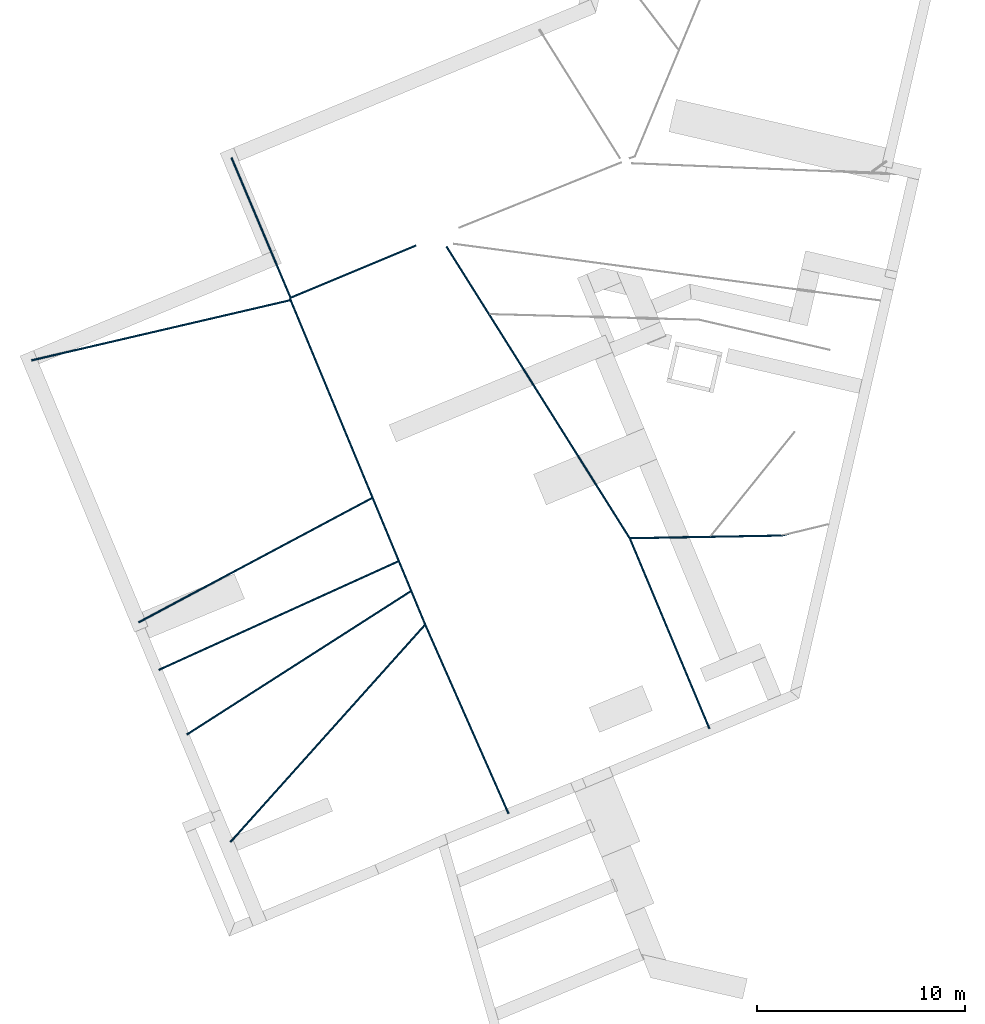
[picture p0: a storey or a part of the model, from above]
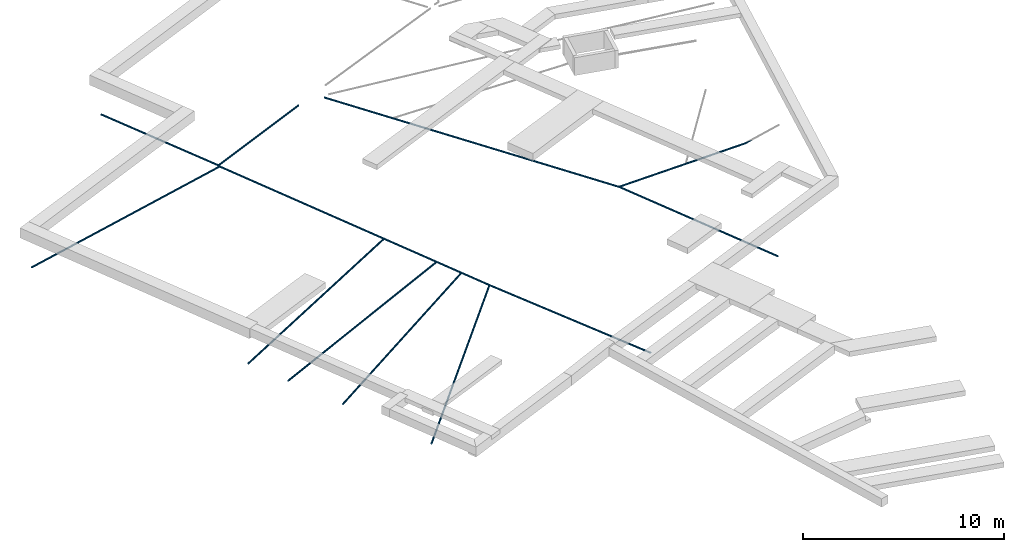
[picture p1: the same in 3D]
Properties of the parts of a building model (IFC2X3), part 1 of 22

# File
Description: ViewDefinition [CoordinationView_V2.0, SurfaceGeometryAddOnView, QuantityTakeOffAddOnView], Option [Drawing Scale: 100.000000], Option [Elements to export: Visible elements (on all stories)], Option [Partial Structure Display: Entire Model], Option [IFC Domain: All], Option [Structural Function: All Elements], Option [Convert Grid elements: On], Option [Convert IFC Annotations and ARCHICAD 2D elements: Off], Option [Convert 2D symbols of Doors and Windows: Off], Option [Export geometries that Participates in Collision Detection only: Off], Option [Split complex elements: Off], Option [Material Preservation: Never explode], Option [IFC Site Location: At Project Origin], Option [Curtain Wall export mode: Single Element], Option [Railing export mode: Single Element], Option [Stair export mode: Single Element], Option [Properties To Export: All properties], Option [Space containment: Off], Option [Bounding Box: Off], Option [Geometry to type objects: Off], Option [Element Properties: Off], Option [Building Material Properties: On], Option [Element Parameters: Off], Option [Component Parameters: Off], Option [IFC Base Quantities: On], Option [Door Window Parameters: Off], Option [IFC Space boundaries: Off], Option [ARCHICAD Zone Categories as IFC Space classification data: Off], Option [Element Classifications: On]
File name: C:\Users\ymarc\Documents\AFFAIRES YM ARCHITECTE\AFFAIRES EN COURS\PIERRES ET TERRITOIRES\CHARTRES Parmentier OLYMPI\Projet 2 - OLYMPI\PRO\Parmentier PRO DEF LIEN BIM OFFICE 26 janvier.ifc
Time: 2021-01-27T10:03:07
Author: #Nom maître oeuvre #Prénom maître oeuvre
Organization: #Societé maître oeuvre
Written by: The EXPRESS Data Manager Version 5.02.0100.09 : 26 Sep 2013
Made in: IFC file generated by GRAPHISOFT ARCHICAD 23.0.0 FRA FULL Windows version (IFC add-on version: 3003 FRA FULL). (Solibri IFC Optimizer)
Authorization: #Nom maître oeuvre #Prénom maître oeuvre

# IfcProject, NOM DU PROJET
Phase: #Provisoire

# IfcSite, Site
RefLatitude: 48, 52, 0, 0; RefLongitude: 2, 20, 0, 0; RefElevation: 136.55 m
BaseQuantities - GrossPerimeter: 0 m; GrossArea: 0 m2

# IfcBuilding, Bâtiment
BaseQuantities - GrossFloorArea: 10399.8 m2

# IfcBuildingStorey (9)
In: Bâtiment
Name | LongName | Elevation (m) | NetHeight (m) = GrossHeight (m) = Height (m) | GrossFloorArea (m2)
Etage | EDICULE | 13.88 | 3 | 0 | Autre - Catégorie: Niveaux; Famille: Niveau: Pointe 8 mm; Famille et type: Niveau: Pointe 8 mm; ID du type: Niveau: Pointe 8 mm; Type: Niveau: Pointe 8 mm; Contraintes - Elévation: 13.58 m; Cotes - Hauteur de calcul: 0 m; Données d'identification - Etage de bâtiment: yes; Structure: no; Nom: EDICULE; Autre(Type) - Catégorie: Niveaux; Nom de la famille: Niveau; Contraintes(Type) - Base de l'élévation: Point de base du projet; Données d'identification(Type) - Nom du type: Pointe 8 mm; Graphismes(Type) - Couleur: 0; Epaisseur des lignes: 1; Motif des lignes: Centre; Symbole: M_Marqueur de niveau - Point triangulaire: M_Marqueur de niveau - Point triangulaire; Valeur par défaut du symbole à l'extrémité 1: no; Valeur par défaut du symbole à l'extrémité 2: yes
Sous-sol | SS | -2.9 | 2.9 | 195.321
Rez-de-chaussée | RDC | 0 | 2.72 | 1224.98
R+1 | 1er | 2.72 | 2.72 | 864.001
R+2 | 2ème | 5.44 | 2.72 | 819.694
R+3 | 3ème | 8.16 | 2.72 | 6864.93
R+4 | 4ème | 10.88 | 3 | 430.843
-2. Etage | fond | -5.7 | 2.8 | 0
Etage |  | 16.88 | 3 | 0

# IfcSpace: Atelier, 001
In: R+4
Type - ElementType: INTERNAL; PredefinedType: USERDEFINED
Description: Logt 3.36.5; LongName: Atelier; InteriorOrExteriorSpace: INTERNAL; Classification: Espace résidentiel (Classification ARCHICAD)
Pset_SpaceCommon - Category: Atelier
PSET ZONES - Finition sol: Carrelage; Finition murs: Peinture; Finition plafond: Peinture
Propriétés DCE - Numéro de LOT: LOT 15; Numéro d'article: L12.2.1.6.3.3; L15.2.1.1
AC_Pset_RenovationAndPhasing - Renovation Status: Existing
BaseQuantities - Height: 2.5 m; FinishCeilingHeight: 2.5 m; FinishFloorHeight: 0 m; ClearHeight: 2.5 m; GrossFloorArea: 20.6791 m2; NetFloorArea: 20.6791 m2; SpaceNetFloorAreaBOMA: 20.6791 m2; SpaceUsableFloorAreaBOMA: 20.6791 m2; GrossCeilingArea: 20.6791 m2; NetCeilingArea: 20.6791 m2; GrossWallArea: 44.7081 m2; NetWallArea: 34.7349 m2; GrossPerimeter: 22.5182 m; NetPerimeter: 22.5182 m; GrossVolume: 51.6977 m3; NetVolume: 45.0737 m3

# IfcSpace: Balcon (17)
LongName: Balcon; InteriorOrExteriorSpace: INTERNAL; Classification: Espace (Classification ARCHICAD)
Pset_SpaceCommon - Category: Balcon
PSET ZONES - Finition sol: résine
AC_Pset_RenovationAndPhasing - Renovation Status: Existing
BaseQuantities - Height: 2.5 m; FinishCeilingHeight: 2.5 m; FinishFloorHeight: 0 m; ClearHeight: 2.5 m
Name | In | Description | GrossFloorArea (m2) = NetFloorArea (m2) = SpaceNetFloorAreaBOMA (m2) = SpaceUsableFloorAreaBOMA (m2) = GrossCeilingArea (m2) = NetCeilingArea (m2) | GrossWallArea (m2) | NetWallArea (m2) | GrossPerimeter (m) = NetPerimeter (m) | GrossVolume (m3) | NetVolume (m3)
001 | R+1 | Logt 1.19.2 | 3.283 | 7.53363 | 2.25363 | 7.81 | 8.2075 | 10.3839
001 | R+1 | Logt 1.15.2 | 3.283 | 7.49458 | 2.21458 | 7.81 | 8.2075 | 10.3906
001 | R+1 | Logt 1.16.2 | 3.283 | 7.49458 | 2.21458 | 7.81 | 8.2075 | 10.3906
001 | R+1 | Logt 1.18.2 | 7.35474 | 18.7929 | 11.5329 | 14.8194 | 18.3868 | 18.3247
001 | R+1 | Logt 1.17.2 | 3.34977 | 0.50818 | 0.50818 | 8.41483 | 8.37443 | 8.465
001 | R+1 | Logt 1.14.3 | 6.68895 | 13.251 | 7.971 | 12.4291 | 16.7224 | 19.8875
001 | R+2 | Logt 2.25.2 | 3.283 | 7.49458 | 2.21458 | 7.81 | 8.2075 | 10.3906
001 | R+2 | Logt 2.26.1 | 3.283 | 7.49458 | 2.21458 | 7.81 | 8.2075 | 10.3906
001 | R+2 | Logt 2.23.3 | 3.98036 | 8.58661 | 3.30661 | 8.80421 | 9.95089 | 12.4015
001 | R+2 | Logt 2.32.2 | 5.50066 | 14.5828 | 9.30276 | 11.1143 | 13.7517 | 13.7499
001 | R+2 | Logt 2.30.3 | 13.2116 | 24.672 | 17.192 | 17.7353 | 33.029 | 36.4807
001 | R+2 | Logt 2.28.2 | 7.35474 | 18.7929 | 11.5329 | 14.8194 | 18.3868 | 18.3247
001 | R+2 | Logt 2.27.2 | 3.34977 | 0.50818 | 0.50818 | 8.41483 | 8.37443 | 8.465
001 | R+3 | Logt 3.34.2 | 3.283 | 7.49458 | 2.21458 | 7.81 | 8.2075 | 10.3906
001 | R+3 | Logt 3.35.3 | 3.283 | 7.49458 | 2.21458 | 7.81 | 8.2075 | 10.3906
001 | R+3 | Logt 3.32.3 | 3.82636 | 8.57113 | 3.29113 | 8.70421 | 9.56589 | 11.9767
001 | R+3 | Logt 3.36.5 | 5.77799 | 12.2434 | 6.96343 | 12.4515 | 14.445 | 13.7299

# IfcSpace: Balcon (4)
In: R+1
Type - ElementType: INTERNAL; PredefinedType: USERDEFINED
InteriorOrExteriorSpace: INTERNAL; Classification: Espace résidentiel (Classification ARCHICAD)
Pset_SpaceCommon - Category: Balcon
PSET ZONES - Finition sol: résine
Propriétés DCE - Numéro de LOT: LOT 12-LOT 15; Numéro d'article: 12.1.1.6-15.1.1.1
AC_Pset_RenovationAndPhasing - Renovation Status: Existing
BaseQuantities - Height: 2.5 m; FinishCeilingHeight: 2.5 m; FinishFloorHeight: 0 m; ClearHeight: 2.5 m
Name | Description | LongName | GrossFloorArea (m2) = NetFloorArea (m2) = SpaceNetFloorAreaBOMA (m2) = SpaceUsableFloorAreaBOMA (m2) = GrossCeilingArea (m2) = NetCeilingArea (m2) | GrossWallArea (m2) | NetWallArea (m2) | GrossPerimeter (m) = NetPerimeter (m) | GrossVolume (m3) | NetVolume (m3)
001 | Logt 1.22.2 | balcon | 7.58408 | 19.7508 | 12.4908 | 14.8322 | 18.9602 | 21.9707
001 | Logt 1.13.3 | Balcon | 5.93859 | 13.4346 | 8.15458 | 11.7353 | 14.8465 | 14.8437
001 | Logt 1.22.2 | balcon | 13.2116 | 24.672 | 17.192 | 17.7353 | 33.029 | 36.4807
001 | Logt 1.22.2 | balcon | 4.69709 | 14.3663 | 9.08629 | 10.154 | 11.7427 | 13.7558

# IfcSpace: Buanderie, 001
In: R+4
Type - ElementType: INTERNAL; PredefinedType: USERDEFINED
Description: Logt 3.36.5; LongName: Buanderie; InteriorOrExteriorSpace: INTERNAL; Classification: Espace résidentiel (Classification ARCHICAD)
Pset_SpaceCommon - Category: Buanderie
PSET ZONES - Finition sol: Carrelage; Finition murs: Peinture
Propriétés DCE - Numéro de LOT: LOT 15; Numéro d'article: L12.2.1.6.3.3; L15.2.1.1
AC_Pset_RenovationAndPhasing - Renovation Status: Existing
BaseQuantities - Height: 2.5 m; FinishCeilingHeight: 2.5 m; FinishFloorHeight: 0 m; ClearHeight: 2.5 m; GrossFloorArea: 6.50737 m2; NetFloorArea: 6.50737 m2; SpaceNetFloorAreaBOMA: 6.50737 m2; SpaceUsableFloorAreaBOMA: 6.50737 m2; GrossCeilingArea: 6.50737 m2; NetCeilingArea: 6.50737 m2; GrossWallArea: 24.57 m2; NetWallArea: 22.3818 m2; GrossPerimeter: 10.6865 m; NetPerimeter: 10.6865 m; GrossVolume: 16.2684 m3; NetVolume: 15.5404 m3

# IfcSpace: CAVES (17)
In: Sous-sol
Type - ElementType: INTERNAL; PredefinedType: USERDEFINED
Description: Logt 0.1.1; InteriorOrExteriorSpace: INTERNAL; Classification: Espace résidentiel (Classification ARCHICAD)
Pset_SpaceCommon - Category: CAVES
PSET ZONES - Finition sol: <Finition de sol>; Finition murs: <Finition de mur>; Finition plafond: <Finition de plafond>
AC_Pset_RenovationAndPhasing - Renovation Status: Existing
BaseQuantities - Height: 2.5 m; FinishCeilingHeight: 2.5 m; FinishFloorHeight: 0 m; ClearHeight: 2.5 m
Name | LongName | GrossFloorArea (m2) = NetFloorArea (m2) = SpaceNetFloorAreaBOMA (m2) = SpaceUsableFloorAreaBOMA (m2) = GrossCeilingArea (m2) = NetCeilingArea (m2) | GrossWallArea (m2) | NetWallArea (m2) | GrossPerimeter (m) = NetPerimeter (m) | GrossVolume (m3) = NetVolume (m3)
001 | C12 | 4.49422 | 28.6191 | 26.9259 | 10.1648 | 11.2355
001 | C14 | 3.99673 | 26.1667 | 24.4735 | 9.12429 | 9.99182
001 | C1 | 3 | 14.6066 | 12.9134 | 7 | 7.5
001 | C2 | 3 | 13.2577 | 11.5645 | 7 | 7.5
001 | C3 | 3 | 18.2324 | 16.5392 | 7 | 7.5
001 | C4 | 3 | 16.9328 | 15.2396 | 7 | 7.5
001 | C5 | 3 | 17.015 | 15.3218 | 7 | 7.5
001 | C6 | 3 | 17.015 | 15.3218 | 7 | 7.5
001 | C7 | 3 | 16.755 | 15.0618 | 7 | 7.5
001 | C8 | 6.55755 | 34.4816 | 32.7884 | 10.8499 | 16.3939
001 | C9 | 2.62853 | 25.3291 | 23.6359 | 6.87805 | 6.57132
001 | C10 | 2.83501 | 21.7716 | 20.0784 | 7.11222 | 7.08752
001 | C11 | 3.06849 | 22.6571 | 20.9639 | 8.02007 | 7.67122
001 | C13 | 3.41698 | 17.3919 | 15.6987 | 7.40575 | 8.54245
001 | C15 | 3.26187 | 23.1827 | 21.4895 | 7.2592 | 8.15468
001 | C16 | 4.27543 | 28.3545 | 26.6613 | 9.5913 | 10.6886
001 | C17 | 4.63662 | 23.6168 | 21.9236 | 9.7913 | 11.5916

# IfcSpace: COULOIR ETAGE (5)
Type - ElementType: INTERNAL; PredefinedType: USERDEFINED
Description: Logt 1.20.2; LongName: Circu. étage; InteriorOrExteriorSpace: INTERNAL; Classification: Espace résidentiel (Classification ARCHICAD)
Pset_SpaceCommon - Category: COULOIR ETAGE
PSET ZONES - Finition sol: Moquette; Finition murs: Peinture; Finition plafond: Peinture
Propriétés DCE - Numéro de LOT: LOT 12-LOT 15-LOT 14; Numéro d'article: L12.2.2.4.1; L15.2.4.1; L14.2.1.1; L14.2.2.1; L14.2.3.1
AC_Pset_RenovationAndPhasing - Renovation Status: Existing
BaseQuantities - Height: 2.5 m; FinishCeilingHeight: 2.5 m; FinishFloorHeight: 0 m; ClearHeight: 2.5 m
Name | In | GrossFloorArea (m2) = NetFloorArea (m2) = SpaceNetFloorAreaBOMA (m2) = SpaceUsableFloorAreaBOMA (m2) = GrossCeilingArea (m2) = NetCeilingArea (m2) | GrossWallArea (m2) | NetWallArea (m2) | GrossPerimeter (m) = NetPerimeter (m) | GrossVolume (m3) = NetVolume (m3)
001 | R+1 | 13.7318 | 56.4038 | 48.815 | 23.6332 | 34.3295
001 | R+1 | 44.1862 | 191.702 | 172.73 | 79.1505 | 110.466
001 | R+2 | 8.48177 | 37.0854 | 31.3938 | 15.674 | 21.2044
001 | R+2 | 41.3609 | 211.953 | 194.878 | 81.5573 | 103.402
001 | R+3 | 18.2227 | 55.9197 | 48.3309 | 31.083 | 45.5567

# IfcSpace: COULOIR RDC, 001
In: Rez-de-chaussée
Description: Logt 0.3.3; LongName: Ascenseur; InteriorOrExteriorSpace: INTERNAL; Classification: Espace (Classification ARCHICAD)
Pset_SpaceCommon - Category: COULOIR RDC
PSET ZONES - Finition sol: Carrelage; Finition murs: <Finition de mur>; Finition plafond: <Finition de plafond>
AC_Pset_RenovationAndPhasing - Renovation Status: Existing
BaseQuantities - Height: 2.5 m; FinishCeilingHeight: 2.5 m; FinishFloorHeight: 0 m; ClearHeight: 2.5 m; GrossFloorArea: 1.54 m2; NetFloorArea: 1.54 m2; SpaceNetFloorAreaBOMA: 1.54 m2; SpaceUsableFloorAreaBOMA: 1.54 m2; GrossCeilingArea: 1.54 m2; NetCeilingArea: 1.54 m2; GrossWallArea: 0 m2; NetWallArea: 0 m2; GrossPerimeter: 5 m; NetPerimeter: 5 m; GrossVolume: 3.85 m3; NetVolume: 3.85 m3

# IfcSpace: COULOIR RDC (2)
In: Rez-de-chaussée
Type - ElementType: INTERNAL; PredefinedType: USERDEFINED
Description: Logt 0.3.3; LongName: Circulation RDC; InteriorOrExteriorSpace: INTERNAL; Classification: Espace résidentiel (Classification ARCHICAD)
Pset_SpaceCommon - Category: COULOIR RDC
PSET ZONES - Finition sol: Carrelage; Finition murs: Peinture; Finition plafond: Peinture
Propriétés DCE - Numéro de LOT: LOT 13-LOT 15; Numéro d'article: 13.1.1.1.3-13.1.3.1.1-13.1.3.1.2-15.1.2.1.1-15.1.2.1.2
AC_Pset_RenovationAndPhasing - Renovation Status: Existing
BaseQuantities - Height: 2.5 m; FinishCeilingHeight: 2.5 m; FinishFloorHeight: 0 m; ClearHeight: 2.5 m
Name | GrossFloorArea (m2) = NetFloorArea (m2) = SpaceNetFloorAreaBOMA (m2) = SpaceUsableFloorAreaBOMA (m2) = GrossCeilingArea (m2) = NetCeilingArea (m2) | GrossWallArea (m2) | NetWallArea (m2) | GrossPerimeter (m) = NetPerimeter (m) | GrossVolume (m3) = NetVolume (m3)
001 | 9.43469 | 40.6755 | 33.0867 | 17.4635 | 23.5867
001 | 45.6297 | 181.319 | 159.083 | 79.5205 | 114.074

# IfcSpace: Cellier, 001
In: R+3
Type - ElementType: INTERNAL; PredefinedType: USERDEFINED
Description: Logt 0.3.3; LongName: Cellier; InteriorOrExteriorSpace: INTERNAL; Classification: Espace résidentiel (Classification ARCHICAD)
Pset_SpaceCommon - Category: Cellier
PSET ZONES - Finition sol: Carrelage; Finition murs: <Finition de mur>; Finition plafond: <Finition de plafond>
Propriétés DCE - Numéro de LOT: LOT 15; Numéro d'article: L12.2.1.6.3.3; L15.2.1.1
AC_Pset_RenovationAndPhasing - Renovation Status: Existing
BaseQuantities - Height: 2.5 m; FinishCeilingHeight: 2.5 m; FinishFloorHeight: 0 m; ClearHeight: 2.5 m; GrossFloorArea: 2.90385 m2; NetFloorArea: 2.90385 m2; SpaceNetFloorAreaBOMA: 2.90385 m2; SpaceUsableFloorAreaBOMA: 2.90385 m2; GrossCeilingArea: 2.90385 m2; NetCeilingArea: 2.90385 m2; GrossWallArea: 18.1002 m2; NetWallArea: 16.407 m2; GrossPerimeter: 7.31993 m; NetPerimeter: 7.31993 m; GrossVolume: 7.25964 m3; NetVolume: 7.25964 m3

# IfcSpace: Chambre, 001
In: R+2
Description: Logt 2.27.2; LongName: Dressing; InteriorOrExteriorSpace: INTERNAL; Classification: Espace (Classification ARCHICAD)
Pset_SpaceCommon - Category: Chambre
PSET ZONES - Finition sol: Parquet; Finition murs: Peinture; Finition plafond: Peinture
Propriétés DCE - Numéro d'article: L12.2.1.6.3.3; L15.2.1.1
AC_Pset_RenovationAndPhasing - Renovation Status: Existing
BaseQuantities - Height: 2.5 m; FinishCeilingHeight: 2.5 m; FinishFloorHeight: 0 m; ClearHeight: 2.5 m; GrossFloorArea: 4.50766 m2; NetFloorArea: 4.50766 m2; SpaceNetFloorAreaBOMA: 4.50766 m2; SpaceUsableFloorAreaBOMA: 4.50766 m2; GrossCeilingArea: 4.50766 m2; NetCeilingArea: 4.50766 m2; GrossWallArea: 22.627 m2; NetWallArea: 20.9338 m2; GrossPerimeter: 9.13062 m; NetPerimeter: 9.13062 m; GrossVolume: 11.2691 m3; NetVolume: 11.2691 m3

# IfcSpace: Chambre (55)
Type - ElementType: INTERNAL; PredefinedType: USERDEFINED
InteriorOrExteriorSpace: INTERNAL; Classification: Espace résidentiel (Classification ARCHICAD)
Pset_SpaceCommon - Category: Chambre
PSET ZONES - Finition sol: Parquet; Finition murs: Peinture; Finition plafond: Peinture
Propriétés DCE - Numéro de LOT: LOT 12-LOT 15
AC_Pset_RenovationAndPhasing - Renovation Status: Existing
BaseQuantities - Height: 2.5 m; FinishCeilingHeight: 2.5 m; FinishFloorHeight: 0 m; ClearHeight: 2.5 m
Name | In | Description | LongName | Numéro d'article | GrossFloorArea (m2) = NetFloorArea (m2) = SpaceNetFloorAreaBOMA (m2) = SpaceUsableFloorAreaBOMA (m2) = GrossCeilingArea (m2) = NetCeilingArea (m2) | GrossWallArea (m2) | NetWallArea (m2) | GrossPerimeter (m) = NetPerimeter (m) | GrossVolume (m3) | NetVolume (m3)
001 | Rez-de-chaussée | Logt 0.2.3 | Chambre 2 | L12.2.1.6.3.3; L15.2.1.1 | 10.8317 | 33.7745 | 30.0313 | 13.684 | 27.0793 | 27.0793
001 | Rez-de-chaussée | Logt 0.2.3 | Chambre 1 | L12.2.1.6.3.3; L15.2.1.1 | 12.0572 | 35.6307 | 31.8875 | 14.2577 | 30.143 | 30.143
001 | Rez-de-chaussée | Logt 0.3.3 | Chambre 2 | L12.2.1.6.3.3; L15.2.1.1 | 10.0639 | 33.651 | 29.9078 | 13.3511 | 25.1598 | 25.1598
001 | Rez-de-chaussée | Logt 0.3.3 | Chambre | L12.2.1.6.3.3; L15.2.1.1 | 13.2249 | 40.3012 | 36.558 | 16.1116 | 33.0622 | 33.0622
001 | Rez-de-chaussée | Logt 0.4.2 | Chambre | L12.2.1.6.3.3; L15.2.1.1 | 11.3237 | 34.5906 | 30.0274 | 13.77 | 28.3093 | 28.3093
001 | Rez-de-chaussée | Logt 0.5.3 | Chambre 1 | L12.2.1.6.3.3; L15.2.1.1 | 12.1874 | 37.0337 | 32.4705 | 14.8309 | 30.4686 | 30.4686
001 | Rez-de-chaussée | Logt 0.5.3 | Chambre 2 | L12.2.1.6.3.3; L15.2.1.1 | 10.5101 | 34.8425 | 30.2793 | 13.8652 | 26.2752 | 26.2752
001 | Rez-de-chaussée | Logt 0.6.2 | Chambre | L12.2.1.6.3.3; L15.2.1.1 | 12.2354 | 35.3281 | 30.7649 | 14.1356 | 30.5886 | 30.5886
001 | Rez-de-chaussée | Logt 0.7.2 | Chambre | L12.2.1.6.3.3; L15.2.1.1 | 10.7997 | 32.864 | 28.3008 | 13.1515 | 26.9992 | 26.9992
001 | Rez-de-chaussée | Logt 0.8.2 | Chambre | L12.2.1.6.3.3; L15.2.1.1 | 13.2777 | 37.2305 | 32.6673 | 15.7317 | 33.1943 | 33.1943
001 | Rez-de-chaussée | Logt 0.9.2 | Chambre | L12.2.1.6.3.3; L15.2.1.1 | 10.9787 | 31.114 | 27.3708 | 13.2593 | 27.4467 | 27.4467
001 | Rez-de-chaussée | Logt 0.10.3 | Chambre 1 | L12.2.1.6.3.3; L15.2.1.1 | 10.8301 | 32.2211 | 28.6379 | 13.1694 | 27.0751 | 27.0751
001 | Rez-de-chaussée | Logt 0.10.3 | Chambre 2 | L12.2.1.6.3.3; L15.2.1.1 | 10.3406 | 33.1093 | 29.5261 | 13.2748 | 25.8516 | 25.8516
001 | Rez-de-chaussée | Logt 0.11.2 | Chambre | L12.2.1.6.3.3; L15.2.1.1 | 11.8526 | 39.1258 | 35.3826 | 15.65 | 29.6314 | 29.6314
001 | R+1 | Logt 2.30.3 | Chambre 2 | L12.1.1.6-L15.1.1.1 | 10.3406 | 32.8862 | 29.303 | 13.2748 | 25.8516 | 25.8671
001 | R+1 | Logt 2.30.3 | Chambre 1 | L12.1.1.6-L15.1.1.1 | 10.8301 | 32.0148 | 28.4316 | 13.1694 | 27.0751 | 27.0931
001 | R+1 | Logt 1.14.3 | Chambre 2 | L12.2.1.6.3.3; L15.2.1.1 | 10.3309 | 26.1613 | 22.5781 | 13.5208 | 25.8273 | 25.8273
001 | R+1 | Logt 1.14.3 | Chambre 1 | L12.2.1.6.3.3; L15.2.1.1 | 13.5888 | 29.462 | 26.3288 | 15.1212 | 33.972 | 33.972
001 | R+1 | Logt 1.17.2 | Chambre | L12.2.1.6.3.3; L15.2.1.1 | 12.1446 | 35.0093 | 31.4261 | 14.0856 | 30.3614 | 30.3614
001 | R+1 | Logt 1.19.2 | Chambre | L12.2.1.6.3.3; L15.2.1.1 | 13.2777 | 39.1295 | 35.5463 | 15.7317 | 33.1943 | 33.1943
001 | R+1 | Logt 1.20.2 | Chambre | L12.2.1.6.3.3; L15.2.1.1 | 10.9787 | 32.8844 | 29.3012 | 13.2593 | 27.4467 | 27.4467
001 | R+1 | Logt 1.22.2 | Chambre | L12.2.1.6.3.3; L15.2.1.1 | 12.1293 | 39.1712 | 35.588 | 15.8707 | 30.3233 | 30.3233
001 | R+1 | Logt 1.12.3 | Chambre 2 | L12.2.1.6.3.3; L15.2.1.1 | 10.7169 | 36.15 | 32.5668 | 14.515 | 26.7923 | 26.7923
001 | R+1 | Logt 1.12.3 | Chambre 1 | L12.2.1.6.3.3; L15.2.1.1 | 12.4766 | 37.5702 | 33.987 | 15.5505 | 31.1916 | 31.1916
001 | R+1 | Logt 1.13.3 | Chambre 2 | L12.2.1.6.3.3; L15.2.1.1 | 10.8542 | 33.6188 | 30.0356 | 13.694 | 27.1355 | 27.1355
001 | R+1 | Logt 1.13.3 | Chambre 1 | L12.2.1.6.3.3; L15.2.1.1 | 12.0572 | 35.4447 | 31.8615 | 14.2577 | 30.143 | 30.143
001 | R+1 | Logt 2.26.3 | Chambre 1 | L12.1.1.6-L15.1.1.1 | 12.1874 | 36.8776 | 33.2944 | 14.8309 | 30.4686 | 30.4686
001 | R+1 | Logt 2.26.3 | Chambre 2 | L12.1.1.6-L15.1.1.1 | 10.5101 | 34.688 | 31.1048 | 13.8652 | 26.2752 | 26.2752
001 | R+1 | Logt 2.28.2 | Chambre | L12.1.1.6-L15.1.1.1 | 10.8233 | 33.0833 | 29.4101 | 13.3132 | 27.0583 | 27.0583
001 | R+1 | Logt 2.25.2 | Chambre | L12.1.1.6-L15.1.1.1 | 11.3237 | 34.2254 | 30.6422 | 13.77 | 28.3093 | 28.3093
001 | R+2 | Logt 2.24.4 | Chambre 2 | L12.2.1.6.3.3; L15.2.1.1 | 9.7608 | 31.1641 | 27.5809 | 13.6455 | 24.402 | 24.402
001 | R+2 | Logt 2.24.4 | Chambre 3 | L12.2.1.6.3.3; L15.2.1.1 | 10.2932 | 32.8868 | 29.3036 | 13.2345 | 25.733 | 25.733
001 | R+2 | Logt 2.24.4 | Chambre 1 | L12.2.1.6.3.3; L15.2.1.1 | 11.4767 | 33.8477 | 30.2645 | 14.4449 | 28.6918 | 28.6918
001 | R+2 | Logt 2.25.2 | Chambre | L12.2.1.6.3.3; L15.2.1.1 | 11.3237 | 34.2254 | 30.6422 | 13.77 | 28.3093 | 28.3093
001 | R+2 | Logt 2.26.3 | Chambre 1 | L12.2.1.6.3.3; L15.2.1.1 | 12.1874 | 36.8776 | 33.2944 | 14.8309 | 30.4686 | 30.4686
001 | R+2 | Logt 2.26.3 | Chambre 2 | L12.2.1.6.3.3; L15.2.1.1 | 10.5101 | 34.688 | 31.1048 | 13.8652 | 26.2752 | 26.2752
001 | R+2 | Logt 2.28.2 | Chambre | L12.2.1.6.3.3; L15.2.1.1 | 10.8233 | 33.0833 | 29.4101 | 13.3132 | 27.0583 | 27.0583
001 | R+2 | Logt 2.30.3 | Chambre 1 | L12.2.1.6.3.3; L15.2.1.1 | 10.8301 | 31.9829 | 28.3997 | 13.1694 | 27.0751 | 27.084
001 | R+2 | Logt 2.30.3 | Chambre 2 | L12.2.1.6.3.3; L15.2.1.1 | 10.3406 | 32.8862 | 29.303 | 13.2748 | 25.8516 | 25.8671
001 | R+2 | Logt 2.29.4 | Chambre 2 | L12.2.1.6.3.3; L15.2.1.1 | 12.4026 | 35.0395 | 31.4563 | 14.0957 | 31.0065 | 31.0065
001 | R+2 | Logt 2.29.4 | Chambre 1 | L12.2.1.6.3.3; L15.2.1.1 | 12.6264 | 41.2386 | 35.9622 | 16.6622 | 31.566 | 31.6108
001 | R+2 | Logt 2.29.4 | Chambre 3 | L12.2.1.6.3.3; L15.2.1.1 | 10.5897 | 33.9057 | 30.3225 | 13.6421 | 26.4742 | 26.4742
001 | R+2 | Logt 2.31.2 | Chambre | L12.2.1.6.3.3; L15.2.1.1 | 12.1198 | 39.1987 | 35.6155 | 15.8667 | 30.2996 | 30.2996
001 | R+2 | Logt 2.23.2 | Chambre 1 | L12.2.1.6.3.3; L15.2.1.1 | 12.4815 | 37.5952 | 34.012 | 15.5605 | 31.2037 | 31.2037
001 | R+2 | Logt 2.23.2 | Chambre 2 | L12.2.1.6.3.3; L15.2.1.1 | 10.7169 | 36.15 | 32.5668 | 14.515 | 26.7923 | 26.7923
001 | R+3 | Logt 3.33.4 | Chambre 1 | L12.2.1.6.3.3; L15.2.1.1 | 14.4222 | 40.4615 | 35.1851 | 16.3319 | 36.0555 | 36.0555
001 | R+3 | Logt 3.34.2 | Chambre | L12.2.1.6.3.3; L15.2.1.1 | 11.3767 | 34.1504 | 30.5672 | 13.74 | 28.4418 | 28.4418
001 | R+3 | Logt 3.35.3 | Chambre 1 | L12.2.1.6.3.3; L15.2.1.1 | 12.181 | 35.8852 | 32.302 | 14.8309 | 30.4526 | 30.4706
001 | R+3 | Logt 3.35.3 | Chambre 2 | L12.2.1.6.3.3; L15.2.1.1 | 10.5101 | 34.5475 | 30.9643 | 13.8652 | 26.2752 | 26.2752
001 | R+3 | Logt 3.32.3 | Chambre 1 | L12.2.1.6.3.3; L15.2.1.1 | 12.4775 | 37.571 | 33.9878 | 15.5512 | 31.1937 | 31.1937
001 | R+3 | Logt 3.32.3 | Chambre 2 | L12.2.1.6.3.3; L15.2.1.1 | 10.7169 | 36.15 | 32.5668 | 14.515 | 26.7923 | 26.7923
001 | R+3 | Logt 3.36.5 | Chambre 1 | L12.2.1.6.3.3; L15.2.1.1 | 17.3424 | 43.2841 | 39.7009 | 17.2946 | 43.356 | 43.356
001 | R+4 | Logt 3.33.4 | Chambre 2 | L12.2.1.6.3.3; L15.2.1.1 | 13.8583 | 38.6254 | 33.1522 | 15.53 | 34.6457 | 34.6457
001 | R+4 | Logt 3.33.4 | Chambre 3 | L12.2.1.6.3.3; L15.2.1.1 | 12.6962 | 40.3167 | 36.7335 | 16.1817 | 31.7406 | 31.7406
001 | R+4 | Logt 3.36.5 | Chambre 2 | L12.2.1.6.3.3; L15.2.1.1 | 25.6963 | 47.0476 | 40.5544 | 21.0926 | 64.2407 | 55.3606

# IfcSpace: Cuisine (18)
Type - ElementType: INTERNAL; PredefinedType: USERDEFINED
LongName: Cuisine; InteriorOrExteriorSpace: INTERNAL; Classification: Espace résidentiel (Classification ARCHICAD)
Pset_SpaceCommon - Category: Cuisine
PSET ZONES - Finition sol: Carrelage
Propriétés DCE - Numéro de LOT: LOT 12-LOT 15
AC_Pset_RenovationAndPhasing - Renovation Status: Existing
BaseQuantities - Height: 2.5 m; FinishCeilingHeight: 2.5 m; FinishFloorHeight: 0 m; ClearHeight: 2.5 m
Name | In | Description | Finition murs | Finition plafond | Numéro d'article | GrossFloorArea (m2) = NetFloorArea (m2) = SpaceNetFloorAreaBOMA (m2) = SpaceUsableFloorAreaBOMA (m2) = GrossCeilingArea (m2) = NetCeilingArea (m2) | GrossWallArea (m2) | NetWallArea (m2) | GrossPerimeter (m) = NetPerimeter (m) | GrossVolume (m3) = NetVolume (m3)
001 | Rez-de-chaussée | Logt 0.3.3 | Peinture | Peinture | L12.2.1.6.3.3; L15.2.1.1 | 4.07483 | 11.1856 | 11.1856 | 8.94848 | 10.1871
001 | Rez-de-chaussée | Logt 0.2.3 | Peinture | Peinture | L12.2.1.6.3.3; L15.2.1.1 | 4.75197 | 7.25744 | 7.25744 | 9.40695 | 11.8799
001 | Rez-de-chaussée | Logt 0.5.3 | Peinture | Peinture | L12.2.1.6.3.3; L15.2.1.1 | 5.54214 | 18.8417 | 18.8417 | 11.1948 | 13.8554
001 | Rez-de-chaussée | Logt 0.10.3 | Peinture | Peinture | L12.2.1.6.3.3; L15.2.1.1 | 4.0175 | 10.5 | 10.5 | 8.4 | 10.0438
001 | R+1 | Logt 1.12.3 | Peinture | Peinture | L12.2.1.6.3.3; L15.2.1.1 | 4.86409 | 18.585 | 18.585 | 9.10011 | 12.1602
001 | R+1 | Logt 1.14.3 | Peinture | Peinture | L12.2.1.6.3.3; L15.2.1.1 | 4.07483 | 11.1856 | 11.1856 | 8.94848 | 10.1871
001 | R+1 | Logt 1.13.3 | Peinture | Peinture | L12.2.1.6.3.3; L15.2.1.1 | 4.75197 | 11.7587 | 11.7587 | 9.40695 | 11.8799
001 | R+1 | Logt 2.30.3 | <Finition de mur> | <Finition de plafond> | 12.1.1.6-15.1.1.1 | 4.0175 | 5.8017 | 5.8017 | 8.4 | 10.0438
001 | R+1 | Logt 2.26.3 | Peinture | Peinture | 12.1.1.6-15.1.1.1 | 5.54214 | 18.8417 | 18.8417 | 11.1948 | 13.8554
001 | R+2 | Logt 2.29.4 | Peinture | Peinture | L12.2.1.6.3.3; L15.2.1.1 | 6.144 | 12.4 | 12.4 | 9.92 | 15.36
001 | R+2 | Logt 2.26.3 | Peinture | Peinture | L12.2.1.6.3.3; L15.2.1.1 | 5.54214 | 18.8417 | 18.8417 | 11.1948 | 13.8554
001 | R+2 | Logt 2.30.3 | <Finition de mur> | <Finition de plafond> | L12.2.1.6.3.3; L15.2.1.1 | 4.0175 | 5.8017 | 5.8017 | 8.4 | 10.0438
001 | R+2 | Logt 2.23.2 | Peinture | Peinture | L12.2.1.6.3.3; L15.2.1.1 | 4.86409 | 18.585 | 18.585 | 9.10011 | 12.1602
001 | R+2 | Logt 2.24.4 | Peinture | Peinture | L12.2.1.6.3.3; L15.2.1.1 | 7.38843 | 17.7671 | 16.8071 | 11.0455 | 18.4711
001 | R+3 | Logt 3.36.5 | Peinture | Peinture | L12.2.1.6.3.3; L15.2.1.1 | 14.7522 | 31.5539 | 27.9707 | 15.8334 | 36.8806
001 | R+3 | Logt 3.33.4 | Peinture | Peinture | L12.2.1.6.3.3; L15.2.1.1 | 8.22793 | 15.5979 | 12.8379 | 12.132 | 20.5698
001 | R+3 | Logt 3.35.3 | Peinture | Peinture | L12.2.1.6.3.3; L15.2.1.1 | 5.54214 | 18.8016 | 18.8016 | 11.1948 | 13.8554
001 | R+3 | Logt 2.23.2 | <Finition de mur> | <Finition de plafond> | L12.2.1.6.3.3; L15.2.1.1 | 4.86409 | 18.585 | 18.585 | 9.10011 | 12.1602

# IfcSpace: Dégagement (10)
Type - ElementType: INTERNAL; PredefinedType: USERDEFINED
InteriorOrExteriorSpace: INTERNAL; Classification: Espace résidentiel (Classification ARCHICAD)
Pset_SpaceCommon - Category: Dégagement
PSET ZONES - Finition sol: Parquet; Finition murs: Peinture; Finition plafond: Peinture
Propriétés DCE - Numéro de LOT: LOT 12-LOT 15; Numéro d'article: L12.2.1.6.3.3; L15.2.1.1
AC_Pset_RenovationAndPhasing - Renovation Status: Existing
BaseQuantities - Height: 2.5 m; FinishCeilingHeight: 2.5 m; FinishFloorHeight: 0 m; ClearHeight: 2.5 m
Name | In | Description | LongName | GrossFloorArea (m2) = NetFloorArea (m2) = SpaceNetFloorAreaBOMA (m2) = SpaceUsableFloorAreaBOMA (m2) = GrossCeilingArea (m2) = NetCeilingArea (m2) | GrossWallArea (m2) | NetWallArea (m2) | GrossPerimeter (m) = NetPerimeter (m) | GrossVolume (m3) | NetVolume (m3)
001 | Rez-de-chaussée | Logt 0.3.3 | Déggt | 4.25148 | 19.6983 | 12.9255 | 8.24764 | 10.6287 | 10.6287
001 | R+1 | Logt 1.14.3 | Déggt | 4.25148 | 19.6983 | 12.9255 | 8.24764 | 10.6287 | 10.6287
001 | R+1 | Logt 1.12.3 | Déggt | 3.15465 | 18.1569 | 11.3841 | 7.5871 | 7.88662 | 7.88662
001 | R+2 | Logt 2.24.4 | Déggt | 8.77711 | 42.2918 | 30.4394 | 17.4507 | 21.9428 | 21.9428
001 | R+2 | Logt 2.29.4 | Déggt | 3.55713 | 22.4668 | 13.174 | 9.32303 | 8.89283 | 8.89283
001 | R+2 | Logt 2.23.2 | Déggt | 3.14982 | 18.1444 | 11.3716 | 7.5771 | 7.87454 | 7.87454
001 | R+3 | Logt 3.32.3 | Déggt | 3.15465 | 18.1569 | 11.3841 | 7.5871 | 7.88662 | 7.88662
001 | R+3 | Logt 3.36.5 | Déggt 1 | 4.07693 | 20.2613 | 14.9777 | 8.208 | 10.1923 | 10.1923
001 | R+4 | Logt 3.36.5 | Déggt 2 | 21.8978 | 77.0758 | 65.533 | 32.3628 | 54.7446 | 50.0303
001 | R+4 | Logt 3.33.4 | Palier | 8.52736 | 29.3825 | 22.6097 | 14.2321 | 21.3184 | 21.3184

# IfcSpace: Entrée (19)
Type - ElementType: INTERNAL; PredefinedType: USERDEFINED
LongName: Entrée; InteriorOrExteriorSpace: INTERNAL; Classification: Espace résidentiel (Classification ARCHICAD)
Pset_SpaceCommon - Category: Entrée
PSET ZONES - Finition sol: Parquet; Finition murs: Peinture; Finition plafond: Peinture
Propriétés DCE - Numéro de LOT: LOT 12-LOT 15
AC_Pset_RenovationAndPhasing - Renovation Status: Existing
BaseQuantities - Height: 2.5 m; FinishCeilingHeight: 2.5 m; FinishFloorHeight: 0 m; ClearHeight: 2.5 m
Name | In | Description | Numéro d'article | GrossFloorArea (m2) = NetFloorArea (m2) = SpaceNetFloorAreaBOMA (m2) = SpaceUsableFloorAreaBOMA (m2) = GrossCeilingArea (m2) = NetCeilingArea (m2) | GrossWallArea (m2) | NetWallArea (m2) | GrossPerimeter (m) = NetPerimeter (m) | GrossVolume (m3) = NetVolume (m3)
001 | Rez-de-chaussée | Logt 0.2.3 | L12.2.1.6.3.3; L15.2.1.1 | 7.97796 | 38.1366 | 27.0186 | 15.7922 | 19.9449
001 | Rez-de-chaussée | Logt 0.3.3 | L12.2.1.6.3.3; L15.2.1.1 | 9.81222 | 40.2189 | 32.1305 | 16.1396 | 24.5305
001 | Rez-de-chaussée | Logt 0.5.3 | L12.2.1.6.3.3; L15.2.1.1 | 5.70438 | 28.9176 | 18.5544 | 11.984 | 14.2609
001 | Rez-de-chaussée | Logt 0.10.3 | L12.2.1.6.3.3; L15.2.1.1 | 7.9214 | 36.6348 | 25.5168 | 15.0028 | 19.8035
001 | R+1 | Logt 1.14.3 | L12.2.1.6.3.3; L15.2.1.1 | 5.4762 | 24.1899 | 17.1915 | 9.94862 | 13.6905
001 | R+1 | Logt 1.12.3 | L12.2.1.6.3.3; L15.2.1.1 | 7.14349 | 32.5811 | 24.8495 | 13.2217 | 17.8587
001 | R+1 | Logt 1.13.3 | L12.2.1.6.3.3; L15.2.1.1 | 7.97021 | 38.1073 | 26.9893 | 15.7981 | 19.9255
001 | R+1 | Logt 2.26.3 | 12.1.1.6-15.1.1.1 | 5.70438 | 28.9926 | 18.6294 | 11.984 | 14.2609
001 | R+1 | Logt 2.30.3 | 12.1.1.6-15.1.1.1 | 7.9214 | 36.4959 | 25.3779 | 15.0028 | 19.8035
001 | R+2 | Logt 2.24.4 | L12.2.1.6.3.3; L15.2.1.1 | 7.05132 | 11.3328 | 9.43565 | 13.127 | 17.6283
001 | R+2 | Logt 2.26.3 | L12.2.1.6.3.3; L15.2.1.1 | 5.70438 | 28.9926 | 18.6294 | 11.984 | 14.2609
001 | R+2 | Logt 2.30.3 | L12.2.1.6.3.3; L15.2.1.1 | 7.9214 | 36.4959 | 25.3779 | 15.0028 | 19.8035
001 | R+2 | Logt 2.27.2 | L12.2.1.6.3.3; L15.2.1.1 | 5.12816 | 23.3123 | 16.3355 | 9.65623 | 12.8204
001 | R+2 | Logt 2.29.4 | L12.2.1.6.3.3; L15.2.1.1 | 4.55607 | 23.1293 | 16.0109 | 9.536 | 11.3902
001 | R+2 | Logt 2.23.2 | L12.2.1.6.3.3; L15.2.1.1 | 7.14349 | 32.5811 | 24.8495 | 13.2217 | 17.8587
001 | R+3 | Logt 3.33.4 | L12.2.1.6.3.3; L15.2.1.1 | 6.2956 | 27.2204 | 23.63 | 12.3153 | 15.739
001 | R+3 | Logt 3.35.3 | L12.2.1.6.3.3; L15.2.1.1 | 5.70438 | 28.8845 | 18.5213 | 11.984 | 14.2609
001 | R+3 | Logt 3.32.3 | L12.2.1.6.3.3; L15.2.1.1 | 7.14349 | 32.1047 | 24.3731 | 13.2217 | 17.8587
001 | R+3 | Logt 3.36.5 | L12.2.1.6.3.3; L15.2.1.1 | 5.0348 | 21.6991 | 16.2115 | 10.5402 | 12.587

# IfcSpace: Escalier service (6)
Type - ElementType: INTERNAL; PredefinedType: USERDEFINED
Description: Logt 1.20.2; InteriorOrExteriorSpace: INTERNAL; Classification: Espace résidentiel (Classification ARCHICAD)
Pset_SpaceCommon - Category: Escalier service
PSET ZONES - Finition sol: Peinture de sol; Finition murs: Peinture; Finition plafond: Peinture
Propriétés DCE - Numéro de LOT: LOT 15; Numéro d'article: L15.12.6.1-L15.1.2.3.1-L151.2.5.1
AC_Pset_RenovationAndPhasing - Renovation Status: Existing
BaseQuantities - Height: 2.5 m; FinishCeilingHeight: 2.5 m; FinishFloorHeight: 0 m; ClearHeight: 2.5 m
Name | In | LongName | GrossFloorArea (m2) = NetFloorArea (m2) = SpaceNetFloorAreaBOMA (m2) = SpaceUsableFloorAreaBOMA (m2) = GrossCeilingArea (m2) = NetCeilingArea (m2) | GrossWallArea (m2) | NetWallArea (m2) | GrossPerimeter (m) = NetPerimeter (m) | GrossVolume (m3) = NetVolume (m3)
001 | Sous-sol | Escalier sous-sol | 8.47847 | 53.9703 | 52.0731 | 14.0935 | 21.1962
001 | Rez-de-chaussée | Escalier sous-sol | 4.9842 | 22.7455 | 20.8483 | 9.19 | 12.4605
001 | Rez-de-chaussée | Escalier RDC | 7.95873 | 27.6313 | 25.7341 | 12.0892 | 19.8968
001 | R+1 | Escalier 1° | 7.95873 | 27.6313 | 25.7341 | 12.0892 | 19.8968
001 | R+2 | Escalier 2° | 7.95873 | 27.6313 | 25.7341 | 12.0892 | 19.8968
001 | R+3 | Escalier 3° | 7.38178 | 29.7833 | 27.8861 | 14.0663 | 18.4545

# IfcSpace: HALL, 001
In: Rez-de-chaussée
Type - ElementType: INTERNAL; PredefinedType: USERDEFINED
Description: Logt 0.3.3; LongName: Hall; InteriorOrExteriorSpace: INTERNAL; Classification: Espace résidentiel (Classification ARCHICAD)
Pset_SpaceCommon - Category: HALL
PSET ZONES - Finition sol: Carrelage; Finition murs: Peinture; Finition plafond: Peinture
Propriétés DCE - Numéro de LOT: LOT 13-LOT 15; Numéro d'article: L13.1.1.1.3-L13.1.3.1.1-L13.1.3.1.2-L15.1.2.1.1-L15.1.2.1.2-15.1.2.1.3
AC_Pset_RenovationAndPhasing - Renovation Status: Existing
BaseQuantities - Height: 2.5 m; FinishCeilingHeight: 2.5 m; FinishFloorHeight: 0 m; ClearHeight: 2.5 m; GrossFloorArea: 16.8686 m2; NetFloorArea: 16.8686 m2; SpaceNetFloorAreaBOMA: 16.8686 m2; SpaceUsableFloorAreaBOMA: 16.8686 m2; GrossCeilingArea: 16.8686 m2; NetCeilingArea: 16.8686 m2; GrossWallArea: 52.4988 m2; NetWallArea: 42.1764 m2; GrossPerimeter: 20.1557 m; NetPerimeter: 20.1557 m; GrossVolume: 42.1714 m3; NetVolume: 42.0781 m3

# IfcSpace: Jardin privatif (5)
In: Rez-de-chaussée
Type - ElementType: INTERNAL; PredefinedType: USERDEFINED
LongName: Jardin; InteriorOrExteriorSpace: INTERNAL; Classification: Espace résidentiel (Classification ARCHICAD)
Pset_SpaceCommon - Category: Jardin privatif
PSET ZONES - Finition sol: Gazon; Finition murs: Peinture; Finition plafond: Peinture
AC_Pset_RenovationAndPhasing - Renovation Status: Existing
BaseQuantities - Height: 2.5 m; FinishCeilingHeight: 2.5 m; FinishFloorHeight: 0 m; ClearHeight: 2.5 m
Name | Description | GrossFloorArea (m2) = GrossCeilingArea (m2) | NetFloorArea (m2) = SpaceNetFloorAreaBOMA (m2) = SpaceUsableFloorAreaBOMA (m2) = NetCeilingArea (m2) | GrossWallArea (m2) = NetWallArea (m2) | GrossPerimeter (m) | NetPerimeter (m) | GrossVolume (m3) | NetVolume (m3)
001 | Logt 0.1.1 | 8.65737 | 38.0237 | 9.11703 | 15.1385 | 39.1549 | 21.6434 | 21.6402
001 | Logt 0.11.3 | 25.9397 | 25.9397 | 13.0734 | 22.3924 | 22.3924 | 64.8494 | 63.7154
001 | Logt 0.2.3 | 29.3663 | 38.0237 | 19.3692 | 27.5318 | 39.1549 | 73.4158 | 73.2185
001 | Logt 0.3.3 | 15.1118 | 15.1118 | 20.1468 | 17.6937 | 17.6937 | 37.7796 | 37.7796
001 | Logt 0.10.3 | 9.1816 | 9.1816 | 5.12703 | 16.6091 | 16.6091 | 22.954 | 22.497

# IfcSpace: Local OM RDC, 001
In: Rez-de-chaussée
Type - ElementType: INTERNAL; PredefinedType: USERDEFINED
Description: Logt 0.3.3; LongName: local OM; InteriorOrExteriorSpace: INTERNAL; Classification: Espace résidentiel (Classification ARCHICAD)
Pset_SpaceCommon - Category: Local OM RDC
PSET ZONES - Finition sol: Carrelage; Finition murs: <Finition de mur>
Propriétés DCE - Numéro de LOT: LOT 13-LOT 15; Numéro d'article: L13.2.1.1.3; L13.2.3.2.1; L13.2.3.2.2-L13.1.5.4; L15.2.2.7.1
AC_Pset_RenovationAndPhasing - Renovation Status: Existing
BaseQuantities - Height: 2.5 m; FinishCeilingHeight: 2.5 m; FinishFloorHeight: 0 m; ClearHeight: 2.5 m; GrossFloorArea: 27.2739 m2; NetFloorArea: 27.2739 m2; SpaceNetFloorAreaBOMA: 27.2739 m2; SpaceUsableFloorAreaBOMA: 27.2739 m2; GrossCeilingArea: 27.2739 m2; NetCeilingArea: 27.2739 m2; GrossWallArea: 65.1817 m2; NetWallArea: 61.3873 m2; GrossPerimeter: 23.5682 m; NetPerimeter: 23.5682 m; GrossVolume: 68.1848 m3; NetVolume: 68.172 m3

# IfcSpace: Local Technique Sous-sol, 001
In: Sous-sol
Type - ElementType: INTERNAL; PredefinedType: USERDEFINED
Description: Logt 0.1.1; LongName: local fibre; InteriorOrExteriorSpace: INTERNAL; Classification: Espace technique (Classification ARCHICAD)
Pset_SpaceCommon - Category: Local Technique Sous-sol
PSET ZONES - Finition sol: <Finition de sol>; Finition murs: <Finition de mur>; Finition plafond: <Finition de plafond>
AC_Pset_RenovationAndPhasing - Renovation Status: Existing
BaseQuantities - Height: 2.5 m; FinishCeilingHeight: 2.5 m; FinishFloorHeight: 0 m; ClearHeight: 2.5 m; GrossFloorArea: 7.00415 m2; NetFloorArea: 7.00415 m2; SpaceNetFloorAreaBOMA: 7.00415 m2; SpaceUsableFloorAreaBOMA: 7.00415 m2; GrossCeilingArea: 7.00415 m2; NetCeilingArea: 7.00415 m2; GrossWallArea: 38.9487 m2; NetWallArea: 37.0515 m2; GrossPerimeter: 11.6278 m; NetPerimeter: 11.6278 m; GrossVolume: 17.5104 m3; NetVolume: 17.5104 m3

# IfcSpace: Local Vélos Sous-sol (2)
In: Sous-sol
Type - ElementType: INTERNAL; PredefinedType: USERDEFINED
Description: Logt 0.1.1; InteriorOrExteriorSpace: INTERNAL; Classification: Espace résidentiel (Classification ARCHICAD)
Pset_SpaceCommon - Category: Local Vélos Sous-sol
PSET ZONES - Finition sol: <Finition de sol>; Finition murs: <Finition de mur>; Finition plafond: <Finition de plafond>
AC_Pset_RenovationAndPhasing - Renovation Status: Existing
BaseQuantities - Height: 2.5 m; FinishCeilingHeight: 2.5 m; FinishFloorHeight: 0 m; ClearHeight: 2.5 m
Name | LongName | Numéro d'article | GrossFloorArea (m2) = NetFloorArea (m2) = SpaceNetFloorAreaBOMA (m2) = SpaceUsableFloorAreaBOMA (m2) = GrossCeilingArea (m2) = NetCeilingArea (m2) | GrossWallArea (m2) | NetWallArea (m2) | GrossPerimeter (m) = NetPerimeter (m) | GrossVolume (m3) = NetVolume (m3)
001 | local vélos | L15.2.2.2; L15.2.2.6.2 | 34.7376 | 111.886 | 109.989 | 30.7754 | 86.8441 | Propriétés DCE - Numéro de LOT: LOT 13-LOT 15
001 | ciculation caves | L15.1.2.2-L15.1.2.6.2 | 18.7292 | 78.2179 | 47.5363 | 33.4311 | 46.823

# IfcSpace: SAS Sous-sol (3)
In: Sous-sol
Type - ElementType: INTERNAL; PredefinedType: USERDEFINED
Description: Logt 0.1.1; InteriorOrExteriorSpace: INTERNAL; Classification: Espace résidentiel (Classification ARCHICAD)
Pset_SpaceCommon - Category: SAS Sous-sol
PSET ZONES - Finition sol: <Finition de sol>; Finition murs: <Finition de mur>; Finition plafond: <Finition de plafond>
Propriétés DCE - Numéro de LOT: LOT 15; Numéro d'article: L15.2.2.2; L15.2.2.6.2
AC_Pset_RenovationAndPhasing - Renovation Status: Existing
BaseQuantities - Height: 2.5 m; FinishCeilingHeight: 2.5 m; FinishFloorHeight: 0 m; ClearHeight: 2.5 m
Name | LongName | GrossFloorArea (m2) = NetFloorArea (m2) = SpaceNetFloorAreaBOMA (m2) = SpaceUsableFloorAreaBOMA (m2) = GrossCeilingArea (m2) = NetCeilingArea (m2) | GrossWallArea (m2) | NetWallArea (m2) | GrossPerimeter (m) = NetPerimeter (m) | GrossVolume (m3) = NetVolume (m3)
001 | sas | 5.55207 | 42.9757 | 39.1813 | 9.84168 | 13.8802
001 | sas | 5.53641 | 36.7587 | 32.9643 | 10.3247 | 13.841
001 | circu. sous-sol | 11.1714 | 64.5525 | 58.8609 | 16.9737 | 27.9286

# IfcSpace: Salle d'eau avec WC (9)
Type - ElementType: INTERNAL; PredefinedType: USERDEFINED
LongName: S. d'eau; InteriorOrExteriorSpace: INTERNAL; Classification: Espace résidentiel (Classification ARCHICAD)
Pset_SpaceCommon - Category: Salle d'eau avec WC
PSET ZONES - Finition sol: Carrelage; Finition murs: Peinture; Finition plafond: Peinture
Propriétés DCE - Numéro de LOT: LOT 09-LOT 13-LOT 15; Numéro d'article: L13.2.1.1.1; L13.2.1.1.2; L13.1.2.2-L13.1.2.3; L15.2.1.2
AC_Pset_RenovationAndPhasing - Renovation Status: Existing
BaseQuantities - Height: 2.5 m; FinishCeilingHeight: 2.5 m; FinishFloorHeight: 0 m; ClearHeight: 2.5 m
Name | In | Description | GrossFloorArea (m2) = NetFloorArea (m2) = SpaceNetFloorAreaBOMA (m2) = SpaceUsableFloorAreaBOMA (m2) = GrossCeilingArea (m2) = NetCeilingArea (m2) | GrossWallArea (m2) | NetWallArea (m2) | GrossPerimeter (m) = NetPerimeter (m) | GrossVolume (m3) | NetVolume (m3)
001 | Rez-de-chaussée | Logt 0.1.1 | 4.78806 | 21.9514 | 20.2582 | 8.92811 | 11.9702 | 11.9702
001 | Rez-de-chaussée | Logt 0.6.2 | 6.62591 | 31.0577 | 29.3645 | 12.5029 | 16.5648 | 16.5648
001 | Rez-de-chaussée | Logt 0.11.2 | 5.28958 | 27.481 | 25.7878 | 11.1242 | 13.2239 | 13.2239
001 | R+1 | Logt 1.17.2 | 6.63575 | 26.3827 | 24.6895 | 10.6329 | 16.5894 | 16.5894
001 | R+1 | Logt 1.22.2 | 5.28958 | 26.9766 | 25.2834 | 11.1242 | 13.2239 | 13.2239
001 | R+2 | Logt 2.31.2 | 5.3275 | 27.5472 | 25.854 | 11.1542 | 13.3187 | 13.3187
001 | R+2 | Logt 2.27.2 | 6.69325 | 26.5077 | 24.8145 | 10.6829 | 16.7331 | 16.7331
001 | R+3 | Logt 0.3.3 | 7.91732 | 32.67 | 30.9768 | 14.0269 | 19.7933 | 19.7918
001 | R+4 | Logt 3.36.5 | 7.98868 | 30.9661 | 28.3929 | 13.2446 | 19.9717 | 17.7077

# IfcSpace: Salle d'eau sans WC (17)
Type - ElementType: INTERNAL; PredefinedType: USERDEFINED
LongName: S. d'eau; InteriorOrExteriorSpace: INTERNAL; Classification: Espace résidentiel (Classification ARCHICAD)
Pset_SpaceCommon - Category: Salle d'eau sans WC
PSET ZONES - Finition sol: Carrelage; Finition murs: Peinture; Finition plafond: Peinture
Propriétés DCE - Numéro de LOT: LOT 09-LOT 13-LOT 15
AC_Pset_RenovationAndPhasing - Renovation Status: Existing
BaseQuantities - Height: 2.5 m; FinishCeilingHeight: 2.5 m; FinishFloorHeight: 0 m; ClearHeight: 2.5 m
Name | In | Description | Numéro d'article | GrossFloorArea (m2) = NetFloorArea (m2) = SpaceNetFloorAreaBOMA (m2) = SpaceUsableFloorAreaBOMA (m2) = GrossCeilingArea (m2) = NetCeilingArea (m2) | GrossWallArea (m2) | NetWallArea (m2) | GrossPerimeter (m) = NetPerimeter (m) | GrossVolume (m3) = NetVolume (m3)
001 | Rez-de-chaussée | Logt 0.7.2 | L13.2.1.1.1; L13.2.1.1.2; L13.1.2.2-L13.1.2.3; L15.2.1.2 | 5.00987 | 25.9777 | 24.2845 | 10.4709 | 12.5247
001 | Rez-de-chaussée | Logt 0.5.3 | L13.2.1.1.1; L13.2.1.1.2; L13.1.2.2-L13.1.2.3; L15.2.1.2 | 4.55674 | 23.5978 | 21.9046 | 9.51898 | 11.3918
001 | Rez-de-chaussée | Logt 0.4.2 | L13.2.1.1.1; L13.2.1.1.2; L13.1.2.2-L13.1.2.3; L15.2.1.2 | 5.39285 | 29.3469 | 27.6537 | 11.8525 | 13.4821
001 | Rez-de-chaussée | Logt 0.8.2 | L13.2.1.1.1; L13.2.1.1.2; L13.1.2.2-L13.1.2.3; L15.2.1.2 | 5.80556 | 29.5382 | 27.845 | 11.8871 | 14.5139
001 | Rez-de-chaussée | Logt 0.9.2 | L13.2.1.1.1; L13.2.1.1.2; L13.1.2.2-L13.1.2.3; L15.2.1.2 | 5.63435 | 29.2058 | 27.5126 | 12.1172 | 14.0859
001 | R+1 | Logt 1.19.2 | L13.2.1.1.1; L13.2.1.1.2; L13.1.2.2-L13.1.2.3; L15.2.1.2 | 5.80556 | 29.5382 | 27.845 | 11.8871 | 14.5139
001 | R+1 | Logt 1.20.2 | L13.2.1.1.1; L13.2.1.1.2; L13.1.2.2-L13.1.2.3; L15.2.1.2 | 5.63435 | 29.6342 | 27.941 | 12.1172 | 14.0859
001 | R+1 | Logt 2.26.3 | L09.2.5.2-L13.1.1.1.1-L13.1.1.1.2-L13.1.1.2.1-L13.1.2.2-L13.1.4.1-L13.1.5.5-L13.1.5.6-L15.1.1.2 | 4.55674 | 23.5978 | 21.9046 | 9.51898 | 11.3918
001 | R+1 | Logt 2.28.2 | L09.2.5.2-L13.1.1.1.1-L13.1.1.1.2-L13.1.1.2.1-L13.1.2.2-L13.1.4.1-L13.1.5.5-L13.1.5.6-L15.1.1.2 | 4.99407 | 25.5342 | 23.841 | 10.4595 | 12.4852
001 | R+1 | Logt 2.25.2 | L09.2.5.2-L13.1.1.1.1-L13.1.1.1.2-L13.1.1.2.1-L13.1.2.2-L13.1.4.1-L13.1.5.5-L13.1.5.6-L15.1.1.2 | 5.39285 | 29.1652 | 27.472 | 11.8525 | 13.4821
001 | R+2 | Logt 2.29.4 | L13.2.1.1.1; L13.2.1.1.2; L13.1.2.2-L13.1.2.3; L15.2.1.2 | 3.75096 | 21.2044 | 19.5112 | 8.63073 | 9.37739
001 | R+2 | Logt 2.24.4 | L13.2.1.1.1; L13.2.1.1.2; L13.1.2.2-L13.1.2.3; L15.2.1.2 | 3.48454 | 20.0274 | 18.3342 | 8.09078 | 8.71136
001 | R+2 | Logt 2.28.2 | L13.2.1.1.1; L13.2.1.1.2; L13.1.2.2-L13.1.2.3; L15.2.1.2 | 4.99407 | 25.5342 | 23.841 | 10.4595 | 12.4852
001 | R+2 | Logt 2.25.2 | L13.2.1.1.1; L13.2.1.1.2; L13.1.2.2-L13.1.2.3; L15.2.1.2 | 5.39285 | 29.1652 | 27.472 | 11.8525 | 13.4821
001 | R+2 | Logt 2.26.3 | L13.2.1.1.1; L13.2.1.1.2; L13.1.2.2-L13.1.2.3; L15.2.1.2 | 4.55674 | 23.5978 | 21.9046 | 9.51898 | 11.3918
001 | R+3 | Logt 3.35.3 | L13.2.1.1.1; L13.2.1.1.2; L13.1.2.2-L13.1.2.3; L15.2.1.2 | 4.57438 | 21.2711 | 19.5779 | 9.51898 | 11.4359
001 | R+3 | Logt 3.33.4 | L13.2.1.1.1; L13.2.1.1.2; L13.1.2.2-L13.1.2.3; L15.2.1.2 | 4.91033 | 24.0288 | 22.3356 | 9.69138 | 12.2758

# IfcSpace: Salle de bain (12)
Type - ElementType: INTERNAL; PredefinedType: USERDEFINED
LongName: S. de bain; InteriorOrExteriorSpace: INTERNAL; Classification: Espace résidentiel (Classification ARCHICAD)
Pset_SpaceCommon - Category: Salle de bain
PSET ZONES - Finition sol: Carrelage; Finition murs: Peinture; Finition plafond: Peinture
Propriétés DCE - Numéro de LOT: LOT 09-LOT 13-LOT 15
AC_Pset_RenovationAndPhasing - Renovation Status: Existing
BaseQuantities - Height: 2.5 m; FinishCeilingHeight: 2.5 m; FinishFloorHeight: 0 m; ClearHeight: 2.5 m
Name | In | Description | Numéro d'article | GrossFloorArea (m2) = NetFloorArea (m2) = SpaceNetFloorAreaBOMA (m2) = SpaceUsableFloorAreaBOMA (m2) = GrossCeilingArea (m2) = NetCeilingArea (m2) | GrossWallArea (m2) | NetWallArea (m2) | GrossPerimeter (m) = NetPerimeter (m) | GrossVolume (m3) | NetVolume (m3)
001 | Rez-de-chaussée | Logt 0.3.3 | L13.2.1.1.1; L13.2.1.1.2; L13.1.2.2-L13.1.2.3; L15.2.1.2 | 4.78076 | 22.1935 | 20.5003 | 9.09029 | 11.9519 | 11.9519
001 | Rez-de-chaussée | Logt 0.2.3 | L13.2.1.1.1; L13.2.1.1.2; L13.1.2.2-L13.1.2.3; L15.2.1.2 | 5.76694 | 25.0353 | 23.3421 | 10.094 | 14.4174 | 14.4174
001 | Rez-de-chaussée | Logt 0.10.3 | L13.2.1.1.1; L13.2.1.1.2; L13.1.2.2-L13.1.2.3; L15.2.1.2 | 6.11693 | 29.2519 | 27.5587 | 11.8445 | 15.2923 | 15.2923
001 | R+1 | Logt 2.30.3 | L09.2.5.2-L13.1.1.1.1-L13.1.1.1.2-L13.1.1.2.1-L13.1.2.2-L13.1.4.1-L13.1.5.5-L13.1.5.6-L15.1.1.2 | 6.13788 | 29.7949 | 28.1017 | 12.0125 | 15.3447 | 15.3452
001 | R+1 | Logt 1.13.3 | L13.2.1.1.1; L13.2.1.1.2; L13.1.2.2-L13.1.2.3; L15.2.1.2 | 5.76619 | 25.4204 | 23.7272 | 10.248 | 14.4155 | 14.4155
001 | R+1 | Logt 1.12.3 | L13.2.1.1.1; L13.2.1.1.2; L13.1.2.2-L13.1.2.3; L15.2.1.2 | 4.6671 | 22.0873 | 20.3941 | 8.91477 | 11.6678 | 11.6678
001 | R+1 | Logt 1.14.3 | L13.2.1.1.1; L13.2.1.1.2; L13.1.2.2-L13.1.2.3; L15.2.1.2 | 4.93769 | 18.5647 | 16.8715 | 9.29171 | 12.3442 | 12.3442
001 | R+2 | Logt 2.23.2 | L13.2.1.1.1; L13.2.1.1.2; L13.1.2.2-L13.1.2.3; L15.2.1.2 | 4.6671 | 22.0873 | 20.3941 | 8.91477 | 11.6678 | 11.6678
001 | R+2 | Logt 2.30.3 | L13.2.1.1.1; L13.2.1.1.2; L13.1.2.2-L13.1.2.3; L15.2.1.2 | 5.96493 | 29.3898 | 27.6966 | 11.8445 | 14.9123 | 14.9123
001 | R+3 | Logt 3.36.5 | L13.2.1.1.1; L13.2.1.1.2; L13.1.2.2-L13.1.2.3; L15.2.1.2 | 4.45113 | 21.5654 | 19.8722 | 8.706 | 11.1278 | 11.1278
001 | R+3 | Logt 3.32.3 | L13.2.1.1.1; L13.2.1.1.2; L13.1.2.2-L13.1.2.3; L15.2.1.2 | 4.6671 | 22.0873 | 20.3941 | 8.91477 | 11.6678 | 11.6678
001 | R+4 | Logt 3.33.4 | L13.2.1.1.1; L13.2.1.1.2; L13.1.2.2-L13.1.2.3; L15.2.1.2 | 6.11661 | 28.2965 | 25.6433 | 11.3984 | 15.2915 | 15.2915

# IfcSpace: Salle de bain+WC (2)
In: R+2
Type - ElementType: INTERNAL; PredefinedType: USERDEFINED
LongName: S. de bain; InteriorOrExteriorSpace: INTERNAL; Classification: Espace résidentiel (Classification ARCHICAD)
Pset_SpaceCommon - Category: Salle de bain+WC
PSET ZONES - Finition sol: Carrelage; Finition murs: Peinture; Finition plafond: Peinture
Propriétés DCE - Numéro de LOT: LOT 09-LOT 13-LOT 15; Numéro d'article: L13.2.1.1.1; L13.2.1.1.2; L13.1.2.2-L13.1.2.3; L15.2.1.2
AC_Pset_RenovationAndPhasing - Renovation Status: Existing
BaseQuantities - Height: 2.5 m; FinishCeilingHeight: 2.5 m; FinishFloorHeight: 0 m; ClearHeight: 2.5 m
Name | Description | GrossFloorArea (m2) = NetFloorArea (m2) = SpaceNetFloorAreaBOMA (m2) = SpaceUsableFloorAreaBOMA (m2) = GrossCeilingArea (m2) = NetCeilingArea (m2) | GrossWallArea (m2) | NetWallArea (m2) | GrossPerimeter (m) = NetPerimeter (m) | GrossVolume (m3) = NetVolume (m3)
001 | Logt 2.29.4 | 5.42055 | 25.4507 | 23.7575 | 10.0801 | 13.5514
001 | Logt 2.24.4 | 5.53083 | 25.8464 | 24.1532 | 10.4284 | 13.8271

# IfcSpace: Séjour A <28m² (15)
LongName: Terrasse; InteriorOrExteriorSpace: INTERNAL; Classification: Espace (Classification ARCHICAD)
Pset_SpaceCommon - Category: Séjour A <28m²
PSET ZONES - Finition plafond: Peinture
AC_Pset_RenovationAndPhasing - Renovation Status: Existing
BaseQuantities - Height: 2.5 m; FinishCeilingHeight: 2.5 m; FinishFloorHeight: 0 m; ClearHeight: 2.5 m
Name | In | Description | Finition sol | Finition murs | GrossFloorArea (m2) = GrossCeilingArea (m2) | NetFloorArea (m2) = SpaceNetFloorAreaBOMA (m2) = SpaceUsableFloorAreaBOMA (m2) = NetCeilingArea (m2) | GrossWallArea (m2) | NetWallArea (m2) | GrossPerimeter (m) | NetPerimeter (m) | GrossVolume (m3) | NetVolume (m3)
001 | Rez-de-chaussée | Logt 0.8.2 | Dalle béton 50x50 | Peinture | 24.3659 | 24.3659 | 37.969 | 27.309 | 25.0874 | 25.0874 | 60.9148 | 60.7925
001 | Rez-de-chaussée | Logt 0.8.2 | Dalle béton 50x50 | Peinture | 15.528 | 15.528 | 29.6288 | 21.8388 | 17.7712 | 17.7712 | 38.8201 | 38.741
001 | Rez-de-chaussée | Logt 0.8.2 | Dalle béton 50x50 | Peinture | 17.2051 | 17.2051 | 25.2541 | 17.4641 | 18.7836 | 18.7836 | 43.0129 | 42.9248
001 | Rez-de-chaussée | Logt 0.8.2 | Dalle béton 50x50 | Peinture | 16.1493 | 16.1493 | 25.3595 | 17.5695 | 18.2469 | 18.2469 | 40.3732 | 40.2726
001 | Rez-de-chaussée | Logt 0.8.2 | Dalle béton 50x50 | Peinture | 17.8924 | 17.8924 | 44.5783 | 36.7883 | 23.486 | 23.486 | 44.7311 | 44.6232
001 | Rez-de-chaussée | Logt 0.9.2 | Dalle béton 50x50 | Peinture | 29.9301 | 29.9301 | 37.1825 | 29.1325 | 25.3226 | 25.3226 | 74.8252 | 69.3665
001 | Rez-de-chaussée | Logt 0.10.3 | Dalle béton 50x50 | Peinture | 30.1386 | 51.2553 | 38.0778 | 30.0278 | 29.7369 | 45.1309 | 75.3465 | 73.1599
001 | Rez-de-chaussée | Logt 0.3.3 | Dalle béton 50x50 | Peinture | 51.3592 | 51.3592 | 85.9994 | 81.8994 | 34.7794 | 34.7794 | 128.398 | 128.155
001 | Rez-de-chaussée | Logt 0.11.3 | Dalle béton 50x50 | Peinture | 21.1165 | 51.2553 | 31.1716 | 24.2016 | 21.674 | 45.1309 | 52.7912 | 49.2675
001 | R+3 | Logt 3.36.5 | plantation gazon | plantation gazon | 29.7178 | 29.7178 | 9.46666 | 9.46666 | 29.7083 | 29.7083 | 74.2945 | 74.7043
001 | R+3 | Logt 3.36.5 | Dalle béton 50x50 | Peinture | 64.5283 | 64.5283 | 69.1576 | 41.1156 | 51.199 | 51.199 | 161.321 | 146.858
001 | R+3 | Logt 3.33.4 | Dalle béton 50x50 | Peinture | 38.3048 | 38.3048 | 25.9399 | 19.3399 | 28.671 | 28.671 | 95.7621 | 94.3438
001 | R+4 | Logt 3.36.5 | plantation gazon | plantation gazon | 18.4905 | 18.4905 | 5.95053 | 5.95053 | 23.984 | 23.984 | 46.2264 | 43.2569
001 | R+4 | Logt 3.36.5 | Dalle béton 50x50 | Peinture | 73.4517 | 73.4517 | 29.8673 | 26.2673 | 56.9297 | 56.9297 | 183.629 | 167.714
001 | R+4 | Logt 3.36.5 | Dalle béton 50x50 | Peinture | 56.3259 | 56.3259 | 22.8439 | 21.0439 | 39.0284 | 39.0284 | 140.815 | 129.763

# IfcSpace: Séjour A <28m² (33)
Type - ElementType: INTERNAL; PredefinedType: USERDEFINED
LongName: Séjour; InteriorOrExteriorSpace: INTERNAL; Classification: Espace résidentiel (Classification ARCHICAD)
Pset_SpaceCommon - Category: Séjour A <28m²
PSET ZONES - Finition sol: Parquet; Finition murs: Peinture; Finition plafond: Peinture
Propriétés DCE - Numéro de LOT: LOT 12-LOT 15
AC_Pset_RenovationAndPhasing - Renovation Status: Existing
BaseQuantities - Height: 2.5 m; FinishCeilingHeight: 2.5 m; FinishFloorHeight: 0 m; ClearHeight: 2.5 m
Name | In | Description | Numéro d'article | GrossFloorArea (m2) = NetFloorArea (m2) = SpaceNetFloorAreaBOMA (m2) = SpaceUsableFloorAreaBOMA (m2) = GrossCeilingArea (m2) = NetCeilingArea (m2) | GrossWallArea (m2) | NetWallArea (m2) | GrossPerimeter (m) = NetPerimeter (m) | GrossVolume (m3) | NetVolume (m3)
001 | Rez-de-chaussée | Logt 0.4.2 | L12.2.1.6.3.3; L15.2.1.1 | 25.2511 | 68.4517 | 56.5549 | 27.6438 | 63.1277 | 63.1277
001 | Rez-de-chaussée | Logt 0.5.3 | L12.2.1.6.3.3; L15.2.1.1 | 19.5258 | 39.4917 | 32.8785 | 19.4526 | 48.8146 | 48.8146
001 | Rez-de-chaussée | Logt 0.6.2 | L12.2.1.6.3.3; L15.2.1.1 | 21.4769 | 60.3017 | 50.0981 | 24.1495 | 53.6922 | 53.6922
001 | Rez-de-chaussée | Logt 0.7.2 | L12.2.1.6.3.3; L15.2.1.1 | 27.8516 | 72.8105 | 60.9137 | 25.3502 | 69.6289 | 69.6289
001 | Rez-de-chaussée | Logt 0.8.2 | L12.2.1.6.3.3; L15.2.1.1 | 25.934 | 74.851 | 62.9542 | 30.0738 | 64.835 | 64.835
001 | Rez-de-chaussée | Logt 0.9.2 | L12.2.1.6.3.3; L15.2.1.1 | 27.7362 | 69.0686 | 56.0918 | 27.6308 | 69.3405 | 69.3405
001 | Rez-de-chaussée | Logt 0.10.3 | L12.2.1.6.3.3; L15.2.1.1 | 24.9726 | 48.5359 | 38.0379 | 23.7224 | 62.4315 | 62.4315
001 | Rez-de-chaussée | Logt 0.11.2 | L12.2.1.6.3.3; L15.2.1.1 | 21.6411 | 56.1785 | 45.9749 | 22.7903 | 54.1028 | 54.1028
001 | Rez-de-chaussée | Logt 0.1.1 | L12.2.1.6.3.3; L15.2.1.1 | 24.6374 | 59.7371 | 49.1767 | 24.2055 | 61.5935 | 61.5935
001 | R+1 | Logt 1.12.3 | L12.2.1.6.3.3; L15.2.1.1 | 3.98036 | 8.58661 | 3.30661 | 8.80421 | 9.95089 | 12.4015
001 | R+1 | Logt 2.30.3 | L12.1.1.6-L15.1.1.1 | 24.921 | 48.0577 | 37.0497 | 23.6824 | 62.3026 | 62.3026
001 | R+1 | Logt 1.17.2 | L12.2.1.6.3.3; L15.2.1.1 | 21.617 | 59.9999 | 49.4363 | 24.1843 | 54.0426 | 54.0426
001 | R+1 | Logt 1.19.2 | L12.2.1.6.3.3; L15.2.1.1 | 25.934 | 74.3162 | 62.0594 | 30.0738 | 64.835 | 64.8978
001 | R+1 | Logt 1.20.2 | L12.2.1.6.3.3; L15.2.1.1 | 27.7362 | 68.3805 | 54.1437 | 27.6308 | 69.3405 | 69.3876
001 | R+1 | Logt 1.22.2 | L12.2.1.6.3.3; L15.2.1.1 | 21.6722 | 44.711 | 34.1474 | 22.7903 | 54.1804 | 54.1804
001 | R+1 | Logt 1.12.3 | L12.2.1.6.3.3; L15.2.1.1 | 19.3907 | 40.0157 | 32.2877 | 19.2981 | 48.4768 | 48.4768
001 | R+1 | Logt 1.13.3 | L12.2.1.6.3.3; L15.2.1.1 | 19.0209 | 39.5537 | 31.8257 | 20.6224 | 47.5522 | 47.5522
001 | R+1 | Logt 2.26.3 | L12.1.1.6-L15.1.1.1 | 19.5258 | 39.2867 | 32.3135 | 19.4526 | 48.8146 | 48.8146
001 | R+1 | Logt 2.28.2 | L12.1.1.6-L15.1.1.1 | 27.819 | 66.4748 | 54.218 | 25.3328 | 69.5474 | 69.5474
001 | R+1 | Logt 2.25.2 | L12.1.1.6-L15.1.1.1 | 25.2511 | 68.3562 | 56.0994 | 27.6438 | 63.1277 | 63.1277
001 | R+2 | Logt 2.24.4 | L12.2.1.6.3.3; L15.2.1.1 | 34.4683 | 65.6893 | 51.7513 | 29.8207 | 86.1709 | 86.1709
001 | R+2 | Logt 2.25.2 | L12.2.1.6.3.3; L15.2.1.1 | 25.2511 | 68.3562 | 56.0994 | 27.6438 | 63.1277 | 63.1277
001 | R+2 | Logt 2.26.3 | L12.2.1.6.3.3; L15.2.1.1 | 19.5258 | 39.2867 | 32.3135 | 19.4526 | 48.8146 | 48.8146
001 | R+2 | Logt 2.27.2 | L12.2.1.6.3.3; L15.2.1.1 | 23.9391 | 54.177 | 45.3138 | 21.7526 | 59.8478 | 59.8478
001 | R+2 | Logt 2.28.2 | L12.2.1.6.3.3; L15.2.1.1 | 27.819 | 66.4554 | 54.1986 | 25.3328 | 69.5474 | 69.5474
001 | R+2 | Logt 2.30.3 | L12.2.1.6.3.3; L15.2.1.1 | 24.921 | 48.0584 | 37.0504 | 23.6824 | 62.3026 | 62.3026
001 | R+2 | Logt 2.29.4 | L12.2.1.6.3.3; L15.2.1.1 | 25.9269 | 53.6681 | 40.2101 | 26.4908 | 64.8172 | 64.8172
001 | R+2 | Logt 2.31.2 | L12.2.1.6.3.3; L15.2.1.1 | 21.7302 | 55.4544 | 44.8908 | 22.8003 | 54.3254 | 54.5414
001 | R+2 | Logt 2.23.2 | L12.2.1.6.3.3; L15.2.1.1 | 19.3907 | 40.0157 | 32.2877 | 19.2981 | 48.4768 | 48.4768
001 | R+3 | Logt 3.36.5 | L12.2.1.6.3.3; L15.2.1.1 | 99.7852 | 128.38 | 95.1062 | 59.8535 | 249.463 | 238.017
001 | R+3 | Logt 3.34.2 | L12.2.1.6.3.3; L15.2.1.1 | 23.9696 | 72.1216 | 61.558 | 28.9521 | 59.924 | 59.924
001 | R+3 | Logt 3.35.3 | L12.2.1.6.3.3; L15.2.1.1 | 19.5258 | 39.1287 | 32.1555 | 19.4526 | 48.8146 | 48.8146
001 | R+3 | Logt 3.32.3 | L12.2.1.6.3.3; L15.2.1.1 | 19.3907 | 40.7282 | 33.0002 | 19.2981 | 48.4768 | 48.4768

# IfcSpace: Séjour A >28m² (4)
Type - ElementType: INTERNAL; PredefinedType: USERDEFINED
LongName: Séjour; InteriorOrExteriorSpace: INTERNAL; Classification: Espace résidentiel (Classification ARCHICAD)
Pset_SpaceCommon - Category: Séjour A >28m²
PSET ZONES - Finition sol: Parquet; Finition murs: Peinture; Finition plafond: Peinture
Propriétés DCE - Numéro de LOT: LOT 12-LOT 15; Numéro d'article: L12.2.1.6.3.3; L15.2.1.1
AC_Pset_RenovationAndPhasing - Renovation Status: Existing
BaseQuantities - Height: 2.5 m; FinishCeilingHeight: 2.5 m; FinishFloorHeight: 0 m; ClearHeight: 2.5 m
Name | In | Description | GrossFloorArea (m2) = NetFloorArea (m2) = SpaceNetFloorAreaBOMA (m2) = SpaceUsableFloorAreaBOMA (m2) = GrossCeilingArea (m2) = NetCeilingArea (m2) | GrossWallArea (m2) | NetWallArea (m2) | GrossPerimeter (m) = NetPerimeter (m) | GrossVolume (m3) = NetVolume (m3)
001 | Rez-de-chaussée | Logt 0.3.3 | 32.7606 | 53.031 | 41.9198 | 25.8399 | 81.9015
001 | Rez-de-chaussée | Logt 0.2.3 | 19.0199 | 39.7947 | 32.4267 | 20.6189 | 47.5499
001 | R+1 | Logt 1.14.3 | 32.7839 | 52.5745 | 41.2633 | 25.8458 | 81.9598
001 | R+3 | Logt 3.33.4 | 37.3867 | 45.261 | 36.8778 | 28.6888 | 93.4667

# IfcSpace: Techniques (4)
LongName: Toiture terrasse inaccessible; InteriorOrExteriorSpace: INTERNAL; Classification: Espace (Classification ARCHICAD)
Pset_SpaceCommon - Category: Techniques
PSET ZONES - Finition sol: gravier; Finition murs: Peinture; Finition plafond: Peinture
AC_Pset_RenovationAndPhasing - Renovation Status: Existing
BaseQuantities - Height: 2.5 m; FinishCeilingHeight: 2.5 m; FinishFloorHeight: 0 m; ClearHeight: 2.5 m
Name | In | GrossFloorArea (m2) = NetFloorArea (m2) = SpaceNetFloorAreaBOMA (m2) = SpaceUsableFloorAreaBOMA (m2) = GrossCeilingArea (m2) = NetCeilingArea (m2) | GrossWallArea (m2) | NetWallArea (m2) | GrossPerimeter (m) = NetPerimeter (m) | GrossVolume (m3) | NetVolume (m3)
001 | R+1 | 20.7213 | 16.7181 | 14.8281 | 18.2954 | 51.8033 | 60.716
001 | R+3 | 96.0594 | 25.9104 | 25.9104 | 41.6304 | 240.148 | 258.076
001 | R+4 | 78.1993 | 99.9308 | 99.9308 | 63.3301 | 195.498 | 201.063
001 | R+4 | 126.089 | 96.8996 | 96.8996 | 122.969 | 315.222 | 300.513

# IfcSpace: Terrasse >5m² (5)
LongName: Terrasse; InteriorOrExteriorSpace: INTERNAL; Classification: Espace (Classification ARCHICAD)
Pset_SpaceCommon - Category: Terrasse >5m²
PSET ZONES - Finition murs: Peinture; Finition plafond: Peinture
AC_Pset_RenovationAndPhasing - Renovation Status: Existing
BaseQuantities - Height: 2.5 m; FinishCeilingHeight: 2.5 m; FinishFloorHeight: 0 m; ClearHeight: 2.5 m
Name | In | Description | Finition sol | GrossFloorArea (m2) = NetFloorArea (m2) = SpaceNetFloorAreaBOMA (m2) = SpaceUsableFloorAreaBOMA (m2) = GrossCeilingArea (m2) = NetCeilingArea (m2) | GrossWallArea (m2) | NetWallArea (m2) | GrossPerimeter (m) = NetPerimeter (m) | GrossVolume (m3) | NetVolume (m3)
001 | Rez-de-chaussée | Logt 0.1.1 | Dalle béton 50x50 | 22.6027 | 41.2545 | 32.2345 | 28.6174 | 56.5067 | 56.3685
001 | Rez-de-chaussée | Logt 0.3.3 | Dalle béton 50x50 | 17.2526 | 34.2875 | 25.2675 | 22.8586 | 43.1316 | 43.199
001 | Rez-de-chaussée | Logt 0.1.1 | Dalle béton 50x50 | 16.2105 | 5.08058 | 5.08058 | 17.1169 | 40.5263 | 40.6019
001 | R+2 | Logt 2.29.4 | Parquet | 11.6786 | 7.87425 | 6.07425 | 16.1581 | 29.1966 | 25.1749
001 | R+2 | Logt 2.24.4 | Dalle béton 50x50 | 55.7501 | 30.4675 | 20.8675 | 40.9657 | 139.375 | 137.29

# IfcSpace: WC (29)
Type - ElementType: INTERNAL; PredefinedType: USERDEFINED
InteriorOrExteriorSpace: INTERNAL; Classification: Espace résidentiel (Classification ARCHICAD)
Pset_SpaceCommon - Category: WC
PSET ZONES - Finition sol: Carrelage; Finition murs: Peinture; Finition plafond: Peinture
Propriétés DCE - Numéro de LOT: LOT 13-LOT 15
AC_Pset_RenovationAndPhasing - Renovation Status: Existing
BaseQuantities - Height: 2.5 m; FinishCeilingHeight: 2.5 m; FinishFloorHeight: 0 m; ClearHeight: 2.5 m
Name | In | Description | LongName | Numéro d'article | GrossFloorArea (m2) = NetFloorArea (m2) = SpaceNetFloorAreaBOMA (m2) = SpaceUsableFloorAreaBOMA (m2) = GrossCeilingArea (m2) = NetCeilingArea (m2) | GrossWallArea (m2) | NetWallArea (m2) | GrossPerimeter (m) = NetPerimeter (m) | GrossVolume (m3) = NetVolume (m3)
001 | Rez-de-chaussée | Logt 0.8.2 | WC | L13.2.1.1.1; L13.2.1.1.2; L13.1.2.2-L13.1.2.3; L15.2.1.2 | 1.8738 | 13.4904 | 11.7972 | 5.476 | 4.6845
001 | Rez-de-chaussée | Logt 0.4.2 | WC | L13.2.1.1.1; L13.2.1.1.2; L13.1.2.2-L13.1.2.3; L15.2.1.2 | 1.88768 | 13.5911 | 11.8979 | 5.508 | 4.7192
001 | Rez-de-chaussée | Logt 0.3.3 | WC | L13.2.1.1.1; L13.2.1.1.2; L13.1.2.2-L13.1.2.3; L15.2.1.2 | 1.96 | 13.733 | 12.0398 | 5.6 | 4.9
001 | Rez-de-chaussée | Logt 0.5.3 | WC | L13.2.1.1.1; L13.2.1.1.2; L13.1.2.2-L13.1.2.3; L15.2.1.2 | 1.9614 | 13.8054 | 12.1122 | 5.602 | 4.9035
001 | Rez-de-chaussée | Logt 0.2.3 | WC | L13.2.1.1.1; L13.2.1.1.2; L13.1.2.2-L13.1.2.3; L15.2.1.2 | 1.88927 | 13.7048 | 12.0116 | 5.49896 | 4.72317
001 | Rez-de-chaussée | Logt 0.7.2 | WC | L13.2.1.1.1; L13.2.1.1.2; L13.1.2.2-L13.1.2.3; L15.2.1.2 | 1.96 | 13.6054 | 11.9122 | 5.6 | 4.9
001 | Rez-de-chaussée | Logt 0.10.3 | WC | L13.2.1.1.1; L13.2.1.1.2; L13.1.2.2-L13.1.2.3; L15.2.1.2 | 2.06802 | 14.3654 | 12.6722 | 5.826 | 5.17004
001 | Rez-de-chaussée | Logt 0.9.2 | WC | L13.2.1.1.1; L13.2.1.1.2; L13.1.2.2-L13.1.2.3; L15.2.1.2 | 1.96 | 13.7724 | 12.0792 | 5.6 | 4.9
001 | R+1 | Logt 0.3.3 | WC | L13.2.1.1.1; L13.2.1.1.2; L13.1.2.2-L13.1.2.3; L15.2.1.2 | 1.96 | 13.733 | 12.0398 | 5.6 | 4.9
001 | R+1 | Logt 1.20.2 | WC | L13.2.1.1.1; L13.2.1.1.2; L13.1.2.2-L13.1.2.3; L15.2.1.2 | 1.96 | 13.1897 | 11.4965 | 5.6 | 4.9
001 | R+1 | Logt 1.13.3 | WC | L13.2.1.1.1; L13.2.1.1.2; L13.1.2.2-L13.1.2.3; L15.2.1.2 | 1.89129 | 13.555 | 11.8618 | 5.50184 | 4.72822
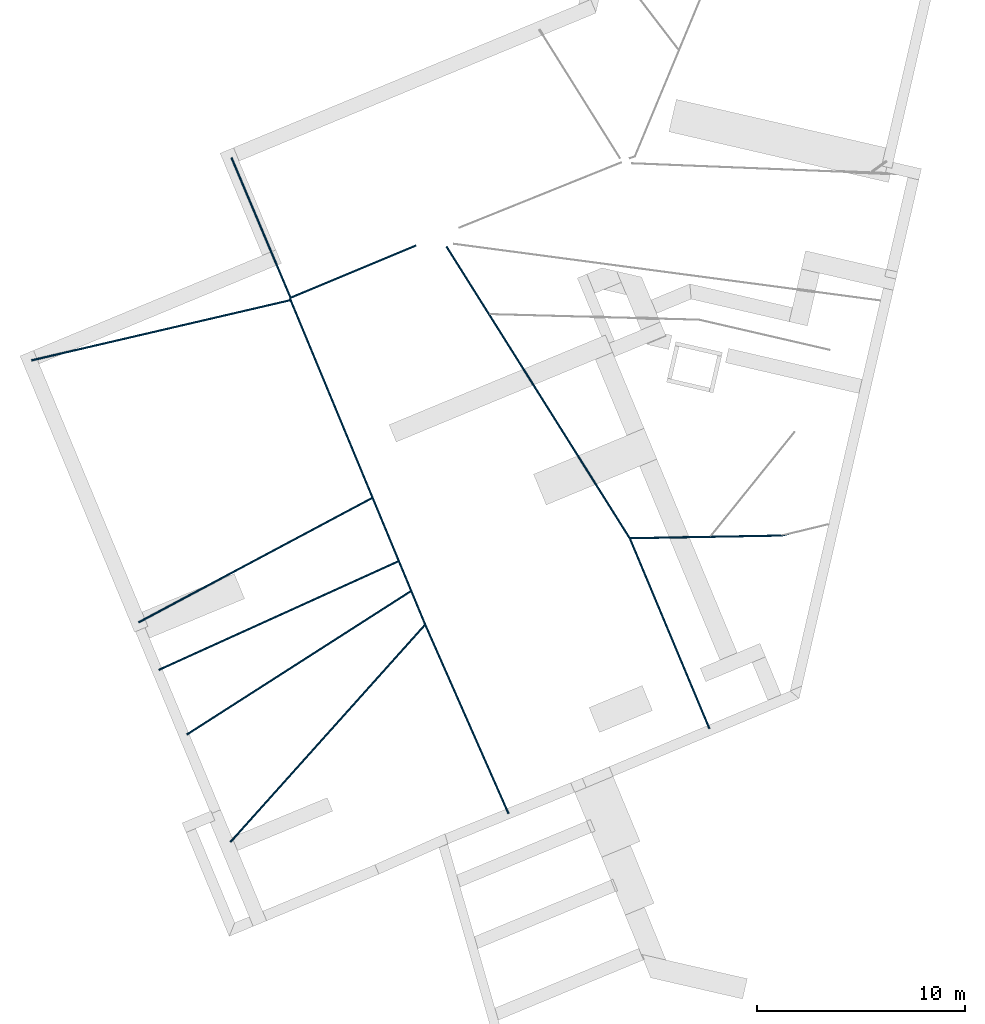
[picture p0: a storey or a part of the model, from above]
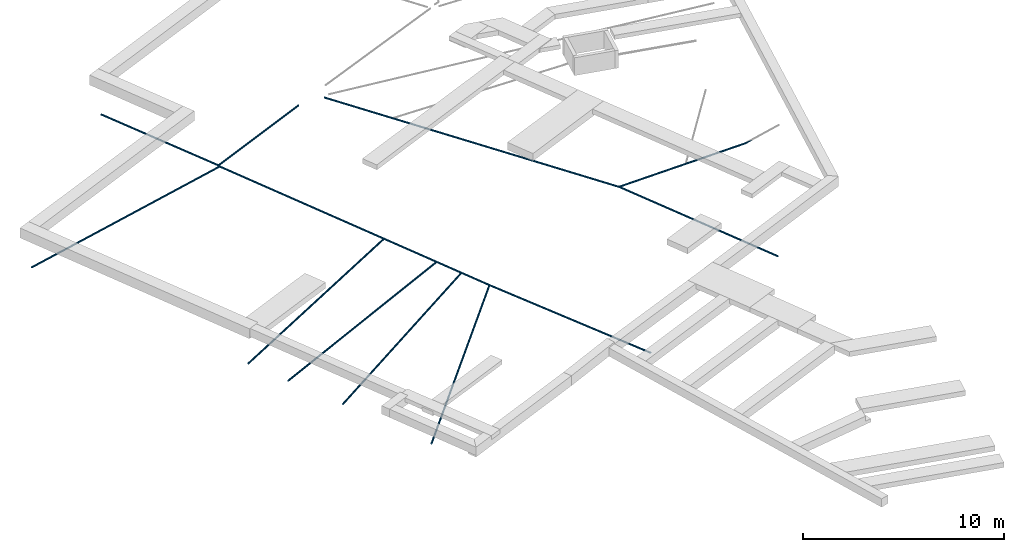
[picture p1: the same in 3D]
Properties of the parts of a building model (IFC2X3), part 2 of 22

# IfcSpace: WC (29)
Name | In | Description | LongName | Numéro d'article | GrossFloorArea (m2) = NetFloorArea (m2) = SpaceNetFloorAreaBOMA (m2) = SpaceUsableFloorAreaBOMA (m2) = GrossCeilingArea (m2) = NetCeilingArea (m2) | GrossWallArea (m2) | NetWallArea (m2) | GrossPerimeter (m) = NetPerimeter (m) | GrossVolume (m3) = NetVolume (m3)
001 | R+1 | Logt 1.19.2 | WC | L13.2.1.1.1; L13.2.1.1.2; L13.1.2.2-L13.1.2.3; L15.2.1.2 | 1.8738 | 13.0854 | 11.3922 | 5.476 | 4.6845
001 | R+1 | Logt 1.12.3 | WC | L13.2.1.1.1; L13.2.1.1.2; L13.1.2.2-L13.1.2.3; L15.2.1.2 | 1.9035 | 16.1354 | 14.4422 | 5.52 | 4.75875
001 | R+1 | Logt 2.26.3 | WC | L13.1.1.1.1-L13.1.1.1.2-L13.1.2.2-L13.1.2.3-L15.1.1.2 | 1.9614 | 13.8054 | 12.1122 | 5.602 | 4.9035
001 | R+1 | Logt 2.30.3 | WC | L13.1.1.1.1-L13.1.1.1.2-L13.1.2.2-L13.1.2.3-L15.1.1.2 | 2.06802 | 14.3071 | 12.6139 | 5.826 | 5.17004
001 | R+1 | Logt 2.28.2 | WC | L13.1.1.1.1-L13.1.1.1.2-L13.1.2.2-L13.1.2.3-L15.1.1.2 | 1.96 | 13.6054 | 11.9122 | 5.6 | 4.9
001 | R+1 | Logt 2.25.2 | WC | L13.1.1.1.1-L13.1.1.1.2-L13.1.2.2-L13.1.2.3-L15.1.1.2 | 1.88768 | 13.5454 | 11.8522 | 5.508 | 4.7192
001 | R+2 | Logt 2.23.2 | WC | L13.2.1.1.1; L13.2.1.1.2; L13.1.2.2-L13.1.2.3; L15.2.1.2 | 1.9035 | 16.1354 | 14.4422 | 5.52 | 4.75875
001 | R+2 | Logt 2.30.3 | WC | L13.2.1.1.1; L13.2.1.1.2; L13.1.2.2-L13.1.2.3; L15.2.1.2 | 2.06802 | 14.3071 | 12.6139 | 5.826 | 5.17004
001 | R+2 | Logt 2.25.2 | WC | L13.2.1.1.1; L13.2.1.1.2; L13.1.2.2-L13.1.2.3; L15.2.1.2 | 1.88768 | 13.5454 | 11.8522 | 5.508 | 4.7192
001 | R+2 | Logt 2.29.4 | WC | L13.2.1.1.1; L13.2.1.1.2; L13.1.2.2-L13.1.2.3; L15.2.1.2 | 1.55512 | 12.6178 | 10.9246 | 5.20435 | 3.8878
001 | R+2 | Logt 2.24.4 | WC | L13.2.1.1.1; L13.2.1.1.2; L13.1.2.2-L13.1.2.3; L15.2.1.2 | 2.07281 | 13.9469 | 12.2537 | 5.75905 | 5.18203
001 | R+2 | Logt 2.26.3 | WC | L13.2.1.1.1; L13.2.1.1.2; L13.1.2.2-L13.1.2.3; L15.2.1.2 | 1.9614 | 13.8054 | 12.1122 | 5.602 | 4.9035
001 | R+2 | Logt 2.28.2 | WC | L13.2.1.1.1; L13.2.1.1.2; L13.1.2.2-L13.1.2.3; L15.2.1.2 | 1.96 | 13.6054 | 11.9122 | 5.6 | 4.9
001 | R+3 | Logt 0.3.3 | WC | L13.2.1.1.1; L13.2.1.1.2; L13.1.2.2-L13.1.2.3; L15.2.1.2 | 2.32213 | 13.1749 | 11.4817 | 6.14691 | 5.80532
001 | R+3 | Logt 3.32.3 | WC | L13.2.1.1.1; L13.2.1.1.2; L13.1.2.2-L13.1.2.3; L15.2.1.2 | 1.9035 | 14.9675 | 13.2743 | 5.52 | 4.75875
001 | R+3 | Logt 3.35.3 | WC | L13.2.1.1.1; L13.2.1.1.2; L13.1.2.2-L13.1.2.3; L15.2.1.2 | 1.9614 | 13.7634 | 12.0702 | 5.602 | 4.9035
001 | R+3 | Logt 3.33.4 | WC1 | L13.2.1.1.1; L13.2.1.1.2; L13.1.2.2-L13.1.2.3; L15.2.1.2 | 2.56571 | 16.7696 | 15.0764 | 6.67167 | 6.41428
001 | R+4 | Logt 3.33.4 | WC2 | L13.2.1.1.1; L13.2.1.1.2; L13.1.2.2-L13.1.2.3; L15.2.1.2 | 2.14305 | 15.9819 | 14.2887 | 6.434 | 5.35763

# IfcBeam: Béton 1000 x 800, PoBA-002
In: Sous-sol
Type - PredefinedType: BEAM
Classification: Poutre (Classification ARCHICAD); Material: Béton
AC_Pset_RenovationAndPhasing - Renovation Status: Existing
Pset_BeamCommon - LoadBearing: yes; IsExternal: no; Reference: Béton 1000 x 800
Material Properties - Béton, ThermalConductivity: 2.3; Béton, SpecificHeatCapacity: 1000 J/kg/K; Béton, MassDensity: 2300 kg/m3; Béton, Embodied Energy: 1.92 (MJ/kg); Béton, Embodied Carbon: 0.198 (kgCO₂/kg); Béton, Name: Béton; Béton, Participates in Collision Detection: yes
BaseQuantities - NetSurfaceAreaExtrudedSides: 32.1338 m2; Length: 9.80263 m; Width: 1 m; Depth: 0.8 m; CrossSectionArea: 0.8 m2; OuterSurfaceArea: 32.1338 m2; TotalSurfaceArea: 33.7338 m2; GrossSurfaceArea: 33.7338 m2; GrossVolume: 7.30449 m3; NetSurfaceArea: 33.7338 m2; NetVolume: 7.30449 m3

# IfcBeam: Béton 200 x 500, PoBA-001
In: Rez-de-chaussée
Type - PredefinedType: BEAM
Classification: Poutre (Classification ARCHICAD); Material: Béton
AC_Pset_RenovationAndPhasing - Renovation Status: Existing
Pset_BeamCommon - LoadBearing: yes; IsExternal: no; Reference: Béton 200 x 500
Material Properties - Béton, ThermalConductivity: 2.3; Béton, SpecificHeatCapacity: 1000 J/kg/K; Béton, MassDensity: 2300 kg/m3; Béton, Embodied Energy: 1.92 (MJ/kg); Béton, Embodied Carbon: 0.198 (kgCO₂/kg); Béton, Name: Béton; Béton, Participates in Collision Detection: yes
BaseQuantities - NetSurfaceAreaExtrudedSides: 6.4678 m2; Length: 4.62 m; Width: 0.2 m; Depth: 0.5 m; CrossSectionArea: 0.1 m2; OuterSurfaceArea: 6.4678 m2; TotalSurfaceArea: 6.6678 m2; GrossSurfaceArea: 6.6678 m2; GrossVolume: 0.461986 m3; NetSurfaceArea: 6.6678 m2; NetVolume: 0.461986 m3

# IfcBeam: Béton 200 x 700, PoBA-002
In: Sous-sol
Type - PredefinedType: BEAM
Classification: Poutre (Classification ARCHICAD); Material: Béton
AC_Pset_RenovationAndPhasing - Renovation Status: Existing
Pset_BeamCommon - LoadBearing: yes; IsExternal: no; Reference: Béton 200 x 700
Material Properties - Béton, ThermalConductivity: 2.3; Béton, SpecificHeatCapacity: 1000 J/kg/K; Béton, MassDensity: 2300 kg/m3; Béton, Embodied Energy: 1.92 (MJ/kg); Béton, Embodied Carbon: 0.198 (kgCO₂/kg); Béton, Name: Béton; Béton, Participates in Collision Detection: yes
BaseQuantities - NetSurfaceAreaExtrudedSides: 2.1452 m2; Length: 1.19735 m; Width: 0.2 m; Depth: 0.7 m; CrossSectionArea: 0.14 m2; OuterSurfaceArea: 2.1452 m2; TotalSurfaceArea: 2.4252 m2; GrossSurfaceArea: 2.4252 m2; GrossVolume: 0.167201 m3; NetSurfaceArea: 2.4252 m2; NetVolume: 0.167201 m3

# IfcBeam: Béton 400 x 600, PoBA-002
In: Sous-sol
Type - PredefinedType: BEAM
Classification: Poutre (Classification ARCHICAD); Material: Béton
AC_Pset_RenovationAndPhasing - Renovation Status: Existing
Pset_BeamCommon - LoadBearing: yes; IsExternal: no; Reference: Béton 400 x 600
Material Properties - Béton, ThermalConductivity: 2.3; Béton, SpecificHeatCapacity: 1000 J/kg/K; Béton, MassDensity: 2300 kg/m3; Béton, Embodied Energy: 1.92 (MJ/kg); Béton, Embodied Carbon: 0.198 (kgCO₂/kg); Béton, Name: Béton; Béton, Participates in Collision Detection: yes
BaseQuantities - NetSurfaceAreaExtrudedSides: 12.846 m2; Length: 6.42298 m; Width: 0.4 m; Depth: 0.6 m; CrossSectionArea: 0.24 m2; OuterSurfaceArea: 12.846 m2; TotalSurfaceArea: 13.326 m2; GrossSurfaceArea: 13.326 m2; GrossVolume: 1.54152 m3; NetSurfaceArea: 13.326 m2; NetVolume: 1.54152 m3

# IfcBeam: Béton 500 x 510, PoBA-002
In: Sous-sol
Type - PredefinedType: BEAM
Classification: Poutre (Classification ARCHICAD); Material: Béton
AC_Pset_RenovationAndPhasing - Renovation Status: Existing
Pset_BeamCommon - LoadBearing: yes; IsExternal: no; Reference: Béton 500 x 510
Material Properties - Béton, ThermalConductivity: 2.3; Béton, SpecificHeatCapacity: 1000 J/kg/K; Béton, MassDensity: 2300 kg/m3; Béton, Embodied Energy: 1.92 (MJ/kg); Béton, Embodied Carbon: 0.198 (kgCO₂/kg); Béton, Name: Béton; Béton, Participates in Collision Detection: yes
BaseQuantities - NetSurfaceAreaExtrudedSides: 8.484 m2; Length: 4.2 m; Width: 0.5 m; Depth: 0.51 m; CrossSectionArea: 0.255 m2; OuterSurfaceArea: 8.484 m2; TotalSurfaceArea: 8.994 m2; GrossSurfaceArea: 8.994 m2; GrossVolume: 1.071 m3; NetSurfaceArea: 8.994 m2; NetVolume: 1.071 m3

# IfcBeam: Béton 500 x 600 (2)
In: Sous-sol
Type - PredefinedType: BEAM
Classification: Poutre (Classification ARCHICAD); Material: Béton
AC_Pset_RenovationAndPhasing - Renovation Status: Existing
Pset_BeamCommon - LoadBearing: yes; IsExternal: no; Reference: Béton 500 x 600
Material Properties - Béton, ThermalConductivity: 2.3; Béton, SpecificHeatCapacity: 1000 J/kg/K; Béton, MassDensity: 2300 kg/m3; Béton, Embodied Energy: 1.92 (MJ/kg); Béton, Embodied Carbon: 0.198 (kgCO₂/kg); Béton, Name: Béton; Béton, Participates in Collision Detection: yes
BaseQuantities - Width: 0.5 m; Depth: 0.6 m; CrossSectionArea: 0.3 m2
Name | NetSurfaceAreaExtrudedSides (m2) = OuterSurfaceArea (m2) | Length (m) | TotalSurfaceArea (m2) = GrossSurfaceArea (m2) = NetSurfaceArea (m2) | GrossVolume (m3) = NetVolume (m3)
PoBA-002 | 11.8623 | 5.39197 | 12.4623 | 1.61759
PoBA-002 | 13.6816 | 6.25 | 14.2816 | 1.87271

# IfcBeam: Béton 500 x 700, PoBA-002
In: Sous-sol
Type - PredefinedType: BEAM
Classification: Poutre (Classification ARCHICAD); Material: Béton
AC_Pset_RenovationAndPhasing - Renovation Status: Existing
Pset_BeamCommon - LoadBearing: yes; IsExternal: no; Reference: Béton 500 x 700
Material Properties - Béton, ThermalConductivity: 2.3; Béton, SpecificHeatCapacity: 1000 J/kg/K; Béton, MassDensity: 2300 kg/m3; Béton, Embodied Energy: 1.92 (MJ/kg); Béton, Embodied Carbon: 0.198 (kgCO₂/kg); Béton, Name: Béton; Béton, Participates in Collision Detection: yes
BaseQuantities - NetSurfaceAreaExtrudedSides: 18.6502 m2; Length: 7.93851 m; Width: 0.5 m; Depth: 0.7 m; CrossSectionArea: 0.35 m2; OuterSurfaceArea: 18.6502 m2; TotalSurfaceArea: 19.3502 m2; GrossSurfaceArea: 19.3502 m2; GrossVolume: 2.71982 m3; NetSurfaceArea: 19.3502 m2; NetVolume: 2.71982 m3

# IfcBeam: Béton 600 x 500, PoBA-002
In: Sous-sol
Type - PredefinedType: BEAM
Classification: Poutre (Classification ARCHICAD); Material: Béton
AC_Pset_RenovationAndPhasing - Renovation Status: Existing
Pset_BeamCommon - LoadBearing: yes; IsExternal: no; Reference: Béton 600 x 500
Material Properties - Béton, ThermalConductivity: 2.3; Béton, SpecificHeatCapacity: 1000 J/kg/K; Béton, MassDensity: 2300 kg/m3; Béton, Embodied Energy: 1.92 (MJ/kg); Béton, Embodied Carbon: 0.198 (kgCO₂/kg); Béton, Name: Béton; Béton, Participates in Collision Detection: yes
BaseQuantities - NetSurfaceAreaExtrudedSides: 12.307 m2; Length: 6.25953 m; Width: 0.6 m; Depth: 0.5 m; CrossSectionArea: 0.3 m2; OuterSurfaceArea: 12.307 m2; TotalSurfaceArea: 12.907 m2; GrossSurfaceArea: 12.907 m2; GrossVolume: 1.67059 m3; NetSurfaceArea: 12.907 m2; NetVolume: 1.67059 m3

# IfcBeam: Béton 700 x 500, PoBA-002
In: Sous-sol
Type - PredefinedType: BEAM
Classification: Poutre (Classification ARCHICAD); Material: Béton
AC_Pset_RenovationAndPhasing - Renovation Status: Existing
Pset_BeamCommon - LoadBearing: yes; IsExternal: no; Reference: Béton 700 x 500
Material Properties - Béton, ThermalConductivity: 2.3; Béton, SpecificHeatCapacity: 1000 J/kg/K; Béton, MassDensity: 2300 kg/m3; Béton, Embodied Energy: 1.92 (MJ/kg); Béton, Embodied Carbon: 0.198 (kgCO₂/kg); Béton, Name: Béton; Béton, Participates in Collision Detection: yes
BaseQuantities - NetSurfaceAreaExtrudedSides: 27.5752 m2; Length: 11.4897 m; Width: 0.7 m; Depth: 0.5 m; CrossSectionArea: 0.35 m2; OuterSurfaceArea: 27.5752 m2; TotalSurfaceArea: 28.2752 m2; GrossSurfaceArea: 28.2752 m2; GrossVolume: 4.02138 m3; NetSurfaceArea: 28.2752 m2; NetVolume: 4.02138 m3

# IfcBeam: Béton 700 x 600 (8)
In: Sous-sol
Type - PredefinedType: BEAM
Classification: Poutre (Classification ARCHICAD); Material: Béton
AC_Pset_RenovationAndPhasing - Renovation Status: Existing
Pset_BeamCommon - LoadBearing: yes; IsExternal: no; Reference: Béton 700 x 600
Material Properties - Béton, ThermalConductivity: 2.3; Béton, SpecificHeatCapacity: 1000 J/kg/K; Béton, MassDensity: 2300 kg/m3; Béton, Embodied Energy: 1.92 (MJ/kg); Béton, Embodied Carbon: 0.198 (kgCO₂/kg); Béton, Name: Béton; Béton, Participates in Collision Detection: yes
BaseQuantities - Width: 0.7 m; Depth: 0.6 m; CrossSectionArea: 0.42 m2
Name | NetSurfaceAreaExtrudedSides (m2) = OuterSurfaceArea (m2) | Length (m) | TotalSurfaceArea (m2) = GrossSurfaceArea (m2) = NetSurfaceArea (m2) | GrossVolume (m3) = NetVolume (m3)
PoBA-002 | 12.137 | 5 | 12.977 | 2.06538
PoBA-002 | 11.303 | 4.3473 | 12.143 | 1.82587
PoBA-002 | 40.0582 | 15.407 | 40.8982 | 6.47094
PoBA-002 | 9.23765 | 3.73144 | 10.0777 | 1.50277
PoBA-002 | 9.54802 | 4.16955 | 10.388 | 1.70148
PoBA-002 | 15.2338 | 6.30263 | 16.0738 | 2.4695
PoBA-002 | 11.591 | 5.00219 | 12.431 | 2.06581
PoBA-002 | 13.9807 | 5.37719 | 14.8207 | 2.25842

# IfcBeam: Béton 700 x 650 (2)
In: Sous-sol
Type - PredefinedType: BEAM
Classification: Poutre (Classification ARCHICAD); Material: Béton
AC_Pset_RenovationAndPhasing - Renovation Status: Existing
Pset_BeamCommon - LoadBearing: yes; IsExternal: no; Reference: Béton 700 x 650
Material Properties - Béton, ThermalConductivity: 2.3; Béton, SpecificHeatCapacity: 1000 J/kg/K; Béton, MassDensity: 2300 kg/m3; Béton, Embodied Energy: 1.92 (MJ/kg); Béton, Embodied Carbon: 0.198 (kgCO₂/kg); Béton, Name: Béton; Béton, Participates in Collision Detection: yes
BaseQuantities - Width: 0.7 m; Depth: 0.65 m; CrossSectionArea: 0.455 m2
Name | NetSurfaceAreaExtrudedSides (m2) = OuterSurfaceArea (m2) | Length (m) | TotalSurfaceArea (m2) = GrossSurfaceArea (m2) = NetSurfaceArea (m2) | GrossVolume (m3) = NetVolume (m3)
PoBA-002 | 14.4493 | 5.3516 | 15.3593 | 2.43498
PoBA-002 | 14.9143 | 6.0516 | 15.8243 | 2.49973

# IfcBeam: Béton 700 x 700 (9)
In: Sous-sol
Type - PredefinedType: BEAM
Classification: Poutre (Classification ARCHICAD); Material: Béton
AC_Pset_RenovationAndPhasing - Renovation Status: Existing
Pset_BeamCommon - LoadBearing: yes; IsExternal: no; Reference: Béton 700 x 700
Material Properties - Béton, ThermalConductivity: 2.3; Béton, SpecificHeatCapacity: 1000 J/kg/K; Béton, MassDensity: 2300 kg/m3; Béton, Embodied Energy: 1.92 (MJ/kg); Béton, Embodied Carbon: 0.198 (kgCO₂/kg); Béton, Name: Béton; Béton, Participates in Collision Detection: yes
BaseQuantities - Width: 0.7 m; Depth: 0.7 m; CrossSectionArea: 0.49 m2
Name | NetSurfaceAreaExtrudedSides (m2) = OuterSurfaceArea (m2) | Length (m) | TotalSurfaceArea (m2) = GrossSurfaceArea (m2) = NetSurfaceArea (m2) | GrossVolume (m3) = NetVolume (m3)
PoBA-002 | 14.8325 | 5.3516 | 15.8125 | 2.56908
PoBA-002 | 29.6832 | 10.6011 | 30.6632 | 5.19455
PoBA-002 | 12.5107 | 5.41902 | 13.4907 | 2.12911
PoBA-002 | 16.3816 | 6.20058 | 17.3616 | 2.86679
PoBA-002 | 13.262 | 5.41554 | 14.242 | 2.44508
PoBA-002 | 38.7558 | 14.7174 | 39.7358 | 6.70122
PoBA-002 | 18.4601 | 7.53572 | 19.4401 | 3.11463
PoBA-002 | 29.1396 | 10.407 | 30.1196 | 5.09943
PoBA-002 | 19.5419 | 7.38144 | 20.5219 | 3.43958

# IfcBeam: Béton 700 x 800 (2)
In: Sous-sol
Type - PredefinedType: BEAM
Classification: Poutre (Classification ARCHICAD); Material: Béton
AC_Pset_RenovationAndPhasing - Renovation Status: Existing
Pset_BeamCommon - LoadBearing: yes; IsExternal: no; Reference: Béton 700 x 800
Material Properties - Béton, ThermalConductivity: 2.3; Béton, SpecificHeatCapacity: 1000 J/kg/K; Béton, MassDensity: 2300 kg/m3; Béton, Embodied Energy: 1.92 (MJ/kg); Béton, Embodied Carbon: 0.198 (kgCO₂/kg); Béton, Name: Béton; Béton, Participates in Collision Detection: yes
BaseQuantities - Width: 0.7 m; Depth: 0.8 m; CrossSectionArea: 0.56 m2
Name | NetSurfaceAreaExtrudedSides (m2) = OuterSurfaceArea (m2) | Length (m) | TotalSurfaceArea (m2) = GrossSurfaceArea (m2) = NetSurfaceArea (m2) | GrossVolume (m3) = NetVolume (m3)
PoBA-002 | 26.2096 | 8.76181 | 27.3296 | 4.8945
PoBA-002 | 23.1423 | 7.71459 | 24.2623 | 4.31983

# IfcBeam: Béton 750 x 700, PoBA-002
In: Sous-sol
Type - PredefinedType: BEAM
Classification: Poutre (Classification ARCHICAD); Material: Béton
AC_Pset_RenovationAndPhasing - Renovation Status: Existing
Pset_BeamCommon - LoadBearing: yes; IsExternal: no; Reference: Béton 750 x 700
Material Properties - Béton, ThermalConductivity: 2.3; Béton, SpecificHeatCapacity: 1000 J/kg/K; Béton, MassDensity: 2300 kg/m3; Béton, Embodied Energy: 1.92 (MJ/kg); Béton, Embodied Carbon: 0.198 (kgCO₂/kg); Béton, Name: Béton; Béton, Participates in Collision Detection: yes
BaseQuantities - NetSurfaceAreaExtrudedSides: 42.5124 m2; Length: 16.4604 m; Width: 0.75 m; Depth: 0.7 m; CrossSectionArea: 0.525 m2; OuterSurfaceArea: 42.5124 m2; TotalSurfaceArea: 43.5624 m2; GrossSurfaceArea: 43.5624 m2; GrossVolume: 7.25506 m3; NetSurfaceArea: 43.5624 m2; NetVolume: 7.25506 m3

# IfcBeam: Béton 800 x 600 (3)
In: Sous-sol
Type - PredefinedType: BEAM
Classification: Poutre (Classification ARCHICAD); Material: Béton
AC_Pset_RenovationAndPhasing - Renovation Status: Existing
Pset_BeamCommon - LoadBearing: yes; IsExternal: no; Reference: Béton 800 x 600
Material Properties - Béton, ThermalConductivity: 2.3; Béton, SpecificHeatCapacity: 1000 J/kg/K; Béton, MassDensity: 2300 kg/m3; Béton, Embodied Energy: 1.92 (MJ/kg); Béton, Embodied Carbon: 0.198 (kgCO₂/kg); Béton, Name: Béton; Béton, Participates in Collision Detection: yes
BaseQuantities - Width: 0.8 m; Depth: 0.6 m; CrossSectionArea: 0.48 m2
Name | NetSurfaceAreaExtrudedSides (m2) = OuterSurfaceArea (m2) | Length (m) | TotalSurfaceArea (m2) = GrossSurfaceArea (m2) = NetSurfaceArea (m2) | GrossVolume (m3) = NetVolume (m3)
PoBA-002 | 17.8001 | 6.76588 | 18.7601 | 3.06201
PoBA-002 | 10.0894 | 3.78117 | 11.0494 | 1.80663
PoBA-002 | 22.1188 | 8.1558 | 23.0788 | 3.86697

# IfcBeam: Béton 800 x 700, PoBA-002
In: Sous-sol
Type - PredefinedType: BEAM
Classification: Poutre (Classification ARCHICAD); Material: Béton
AC_Pset_RenovationAndPhasing - Renovation Status: Existing
Pset_BeamCommon - LoadBearing: yes; IsExternal: no; Reference: Béton 800 x 700
Material Properties - Béton, ThermalConductivity: 2.3; Béton, SpecificHeatCapacity: 1000 J/kg/K; Béton, MassDensity: 2300 kg/m3; Béton, Embodied Energy: 1.92 (MJ/kg); Béton, Embodied Carbon: 0.198 (kgCO₂/kg); Béton, Name: Béton; Béton, Participates in Collision Detection: yes
BaseQuantities - NetSurfaceAreaExtrudedSides: 15.414 m2; Length: 5.138 m; Width: 0.8 m; Depth: 0.7 m; CrossSectionArea: 0.56 m2; OuterSurfaceArea: 15.414 m2; TotalSurfaceArea: 16.534 m2; GrossSurfaceArea: 16.534 m2; GrossVolume: 2.87728 m3; NetSurfaceArea: 16.534 m2; NetVolume: 2.87728 m3

# IfcBeam: Béton 800 x 800 (3)
In: Sous-sol
Type - PredefinedType: BEAM
Classification: Poutre (Classification ARCHICAD); Material: Béton
AC_Pset_RenovationAndPhasing - Renovation Status: Existing
Pset_BeamCommon - LoadBearing: yes; IsExternal: no; Reference: Béton 800 x 800
Material Properties - Béton, ThermalConductivity: 2.3; Béton, SpecificHeatCapacity: 1000 J/kg/K; Béton, MassDensity: 2300 kg/m3; Béton, Embodied Energy: 1.92 (MJ/kg); Béton, Embodied Carbon: 0.198 (kgCO₂/kg); Béton, Name: Béton; Béton, Participates in Collision Detection: yes
BaseQuantities - Width: 0.8 m; Depth: 0.8 m; CrossSectionArea: 0.64 m2
Name | NetSurfaceAreaExtrudedSides (m2) = OuterSurfaceArea (m2) | Length (m) | TotalSurfaceArea (m2) = GrossSurfaceArea (m2) = NetSurfaceArea (m2) | GrossVolume (m3) = NetVolume (m3)
PoBA-002 | 45.2854 | 14.1954 | 46.5654 | 9.02139
PoBA-002 | 45.4254 | 14.1954 | 46.7054 | 9.08509
PoBA-002 | 45.8242 | 14.8189 | 47.1042 | 9.41887

# IfcBeam: Béton armé (Coulé) 400 x 230, PoBA-002
In: Sous-sol
Type - PredefinedType: BEAM
Classification: Poutre (Classification ARCHICAD); Material: Béton armé (Coulé)
AC_Pset_RenovationAndPhasing - Renovation Status: Existing
Pset_BeamCommon - LoadBearing: yes; IsExternal: no; Reference: Béton armé (Coulé) 400 x 230
Material Properties - Béton armé (Coulé), ThermalConductivity: 2.3; Béton armé (Coulé), SpecificHeatCapacity: 1000 J/kg/K; Béton armé (Coulé), MassDensity: 2300 kg/m3; Béton armé (Coulé), Embodied Energy: 1.92 (MJ/kg); Béton armé (Coulé), Embodied Carbon: 0.198 (kgCO₂/kg); Béton armé (Coulé), Name: Béton armé (Coulé); Béton armé (Coulé), Participates in Collision Detection: yes
BaseQuantities - NetSurfaceAreaExtrudedSides: 3.04682 m2; Length: 2.41811 m; Width: 0.4 m; Depth: 0.23 m; CrossSectionArea: 0.092 m2; OuterSurfaceArea: 3.04682 m2; TotalSurfaceArea: 3.23082 m2; GrossSurfaceArea: 3.23082 m2; GrossVolume: 0.222466 m3; NetSurfaceArea: 3.23082 m2; NetVolume: 0.222466 m3

# IfcBuildingElementProxy: 1 - Mur Extérieur Béton 16+ ravalement + bardage 240, M_Ext-008
In: R+4
Classification: Mur (Classification ARCHICAD); Material: Bois - Bardage, Bois - Lattage, Béton, Finition ext - Crépis
Propriétés DCE - Numéro de LOT: LOT 04; LOT 16; Numéro article: L16.2.1
AC_Pset_RenovationAndPhasing - Renovation Status: Existing
Material Properties - Component 1, Bois - Bardage, ThermalConductivity: 0.14; Component 1, Bois - Bardage, SpecificHeatCapacity: 2300 J/kg/K; Component 1, Bois - Bardage, MassDensity: 500 kg/m3; Component 1, Bois - Bardage, Embodied Energy: 10 (MJ/kg); Component 1, Bois - Bardage, Embodied Carbon: 0.36 (kgCO₂/kg); Component 1, Bois - Bardage, Name: Bois - Bardage; Component 1, Bois - Bardage, Participates in Collision Detection: yes; Component 2, Bois - Lattage, ThermalConductivity: 0.13; Component 2, Bois - Lattage, SpecificHeatCapacity: 1600 J/kg/K; Component 2, Bois - Lattage, MassDensity: 500 kg/m3; Component 2, Bois - Lattage, Embodied Energy: 6.95 (MJ/kg); Component 2, Bois - Lattage, Embodied Carbon: 0.29 (kgCO₂/kg); Component 2, Bois - Lattage, Name: Bois - Lattage; Component 2, Bois - Lattage, Participates in Collision Detection: yes; Component 3, Béton, ThermalConductivity: 2.3; Component 3, Béton, SpecificHeatCapacity: 1000 J/kg/K; Component 3, Béton, MassDensity: 2300 kg/m3; Component 3, Béton, Embodied Energy: 1.92 (MJ/kg); Component 3, Béton, Embodied Carbon: 0.198 (kgCO₂/kg); Component 3, Béton, Name: Béton; Component 3, Béton, Participates in Collision Detection: yes; Component 4, Finition ext - Crépis, ThermalConductivity: 0.8; Component 4, Finition ext - Crépis, SpecificHeatCapacity: 1000 J/kg/K; Component 4, Finition ext - Crépis, MassDensity: 1600 kg/m3; Component 4, Finition ext - Crépis, Embodied Energy: 1.4 (MJ/kg); Component 4, Finition ext - Crépis, Embodied Carbon: 0.09 (kgCO₂/kg); Component 4, Finition ext - Crépis, Name: Finition ext - Crépis; Component 4, Finition ext - Crépis, Participates in Collision Detection: no

# IfcBuildingElementProxy: 2 - Murs Béton 16 + Enduit 1 Face 170 (4)
In: R+4
Classification: Mur (Classification ARCHICAD)
AC_Pset_RenovationAndPhasing - Renovation Status: Existing
Material Properties - Component 1, Béton, ThermalConductivity: 2.3; Component 1, Béton, SpecificHeatCapacity: 1000 J/kg/K; Component 1, Béton, MassDensity: 2300 kg/m3; Component 1, Béton, Embodied Energy: 1.92 (MJ/kg); Component 1, Béton, Embodied Carbon: 0.198 (kgCO₂/kg); Component 1, Béton, Name: Béton; Component 1, Béton, Participates in Collision Detection: yes; Component 2, Finition int - Enduit plâtre, ThermalConductivity: 0.57; Component 2, Finition int - Enduit plâtre, SpecificHeatCapacity: 1000 J/kg/K; Component 2, Finition int - Enduit plâtre, MassDensity: 1300 kg/m3; Component 2, Finition int - Enduit plâtre, Embodied Energy: 1.8 (MJ/kg); Component 2, Finition int - Enduit plâtre, Embodied Carbon: 0.13 (kgCO₂/kg); Component 2, Finition int - Enduit plâtre, Name: Finition int - Enduit plâtre; Component 2, Finition int - Enduit plâtre, Participates in Collision Detection: no
Name | Material
2 x M_Ext-008 | Béton, Finition int - Enduit plâtre
2 x M_Ext-008 | Finition int - Enduit plâtre, Béton

# IfcBuildingElementProxy: 2 - Murs Béton 18 + Enduit 2 Faces 200, M_Ext-009
In: R+3
Classification: Mur (Classification ARCHICAD); Material: Finition int - Enduit plâtre (2), Béton
Propriétés DCE - Numéro article: L04.2.12.3.2
AC_Pset_RenovationAndPhasing - Renovation Status: Existing
Material Properties - Component 1, Finition int - Enduit plâtre, ThermalConductivity: 0.57; Component 1, Finition int - Enduit plâtre, SpecificHeatCapacity: 1000 J/kg/K; Component 1, Finition int - Enduit plâtre, MassDensity: 1300 kg/m3; Component 1, Finition int - Enduit plâtre, Embodied Energy: 1.8 (MJ/kg); Component 1, Finition int - Enduit plâtre, Embodied Carbon: 0.13 (kgCO₂/kg); Component 1, Finition int - Enduit plâtre, Name: Finition int - Enduit plâtre; Component 1, Finition int - Enduit plâtre, Participates in Collision Detection: no; Component 2, Béton, ThermalConductivity: 2.3; Component 2, Béton, SpecificHeatCapacity: 1000 J/kg/K; Component 2, Béton, MassDensity: 2300 kg/m3; Component 2, Béton, Embodied Energy: 1.92 (MJ/kg); Component 2, Béton, Embodied Carbon: 0.198 (kgCO₂/kg); Component 2, Béton, Name: Béton; Component 2, Béton, Participates in Collision Detection: yes; Component 1: 2 with these values

# IfcBuildingElementProxy: 5 - Couverture zinc sur fermette+volige+zinc 75 (2)
Classification: Toit (Classification ARCHICAD); Material: Toiture - ZINC, Bois - Massif 01, Bois - Lattage
AC_Pset_RenovationAndPhasing - Renovation Status: Existing
Material Properties - Component 1, Toiture - ZINC, ThermalConductivity: 50; Component 1, Toiture - ZINC, SpecificHeatCapacity: 450 J/kg/K; Component 1, Toiture - ZINC, MassDensity: 7800 kg/m3; Component 1, Toiture - ZINC, Embodied Energy: 20.1 (MJ/kg); Component 1, Toiture - ZINC, Embodied Carbon: 1.46 (kgCO₂/kg); Component 1, Toiture - ZINC, Name: Toiture - ZINC; Component 1, Toiture - ZINC, Participates in Collision Detection: no; Component 2, Bois - Massif 01, ThermalConductivity: 0.14; Component 2, Bois - Massif 01, SpecificHeatCapacity: 2300 J/kg/K; Component 2, Bois - Massif 01, MassDensity: 500 kg/m3; Component 2, Bois - Massif 01, Embodied Energy: 10 (MJ/kg); Component 2, Bois - Massif 01, Embodied Carbon: 0.36 (kgCO₂/kg); Component 2, Bois - Massif 01, Name: Bois - Massif 01; Component 2, Bois - Massif 01, Participates in Collision Detection: yes; Component 3, Bois - Lattage, ThermalConductivity: 0.13; Component 3, Bois - Lattage, SpecificHeatCapacity: 1600 J/kg/K; Component 3, Bois - Lattage, MassDensity: 500 kg/m3; Component 3, Bois - Lattage, Embodied Energy: 6.95 (MJ/kg); Component 3, Bois - Lattage, Embodied Carbon: 0.29 (kgCO₂/kg); Component 3, Bois - Lattage, Name: Bois - Lattage; Component 3, Bois - Lattage, Participates in Collision Detection: yes
Name | In | Numéro de LOT | Numéro article
Toit-05 | R+4 | LOT 06 | L06.1.1
Toit-01 | Etage | LOT 05; LOT 06 | L06.2.1

# IfcBuildingElementProxy: 6 - Isolation sur terrasse béton protections multiples 110 (2)
Classification: Dalle (Classification ARCHICAD); Material: Etanchéité - Bitume, Isolation - Polyuréthane (extérieur)
Propriétés DCE - Numéro de LOT: LOT 07; Numéro article: L07.2.4.1;L07.2.4.3;L07.2.4.4; L07.2.4.5
AC_Pset_RenovationAndPhasing - Renovation Status: Existing
Material Properties - Component 1, Etanchéité - Bitume, ThermalConductivity: 0.23; Component 1, Etanchéité - Bitume, SpecificHeatCapacity: 1000 J/kg/K; Component 1, Etanchéité - Bitume, MassDensity: 1100 kg/m3; Component 1, Etanchéité - Bitume, Embodied Energy: 2.86 (MJ/kg); Component 1, Etanchéité - Bitume, Embodied Carbon: 0.066 (kgCO₂/kg); Component 1, Etanchéité - Bitume, Name: Etanchéité - Bitume; Component 1, Etanchéité - Bitume, Participates in Collision Detection: no; Component 2, Isolation - Polyuréthane (extérieur), ThermalConductivity: 0.036; Component 2, Isolation - Polyuréthane (extérieur), SpecificHeatCapacity: 1450 J/kg/K; Component 2, Isolation - Polyuréthane (extérieur), MassDensity: 25 kg/m3; Component 2, Isolation - Polyuréthane (extérieur), Embodied Energy: 86.6 (MJ/kg); Component 2, Isolation - Polyuréthane (extérieur), Embodied Carbon: 3.29 (kgCO₂/kg); Component 2, Isolation - Polyuréthane (extérieur), Name: Isolation - Polyuréthane (extérieur); Component 2, Isolation - Polyuréthane (extérieur), Participates in Collision Detection: no
Name | In
Dalle_003 | R+4
Dalle_003 | R+3

# IfcBuildingElementProxy: 6 - Isolation sur terrasse sous dalle béton 110 (3)
Classification: Dalle (Classification ARCHICAD); Material: Etanchéité - Bitume, Isolation - Polyuréthane (extérieur)
Propriétés DCE - Numéro de LOT: LOT 07; Numéro article: L07.2.3.3.1; L07.2.3.3; L07.2.3.4
AC_Pset_RenovationAndPhasing - Renovation Status: Existing
Material Properties - Component 1, Etanchéité - Bitume, ThermalConductivity: 0.23; Component 1, Etanchéité - Bitume, SpecificHeatCapacity: 1000 J/kg/K; Component 1, Etanchéité - Bitume, MassDensity: 1100 kg/m3; Component 1, Etanchéité - Bitume, Embodied Energy: 2.86 (MJ/kg); Component 1, Etanchéité - Bitume, Embodied Carbon: 0.066 (kgCO₂/kg); Component 1, Etanchéité - Bitume, Name: Etanchéité - Bitume; Component 1, Etanchéité - Bitume, Participates in Collision Detection: no; Component 2, Isolation - Polyuréthane (extérieur), ThermalConductivity: 0.036; Component 2, Isolation - Polyuréthane (extérieur), SpecificHeatCapacity: 1450 J/kg/K; Component 2, Isolation - Polyuréthane (extérieur), MassDensity: 25 kg/m3; Component 2, Isolation - Polyuréthane (extérieur), Embodied Energy: 86.6 (MJ/kg); Component 2, Isolation - Polyuréthane (extérieur), Embodied Carbon: 3.29 (kgCO₂/kg); Component 2, Isolation - Polyuréthane (extérieur), Name: Isolation - Polyuréthane (extérieur); Component 2, Isolation - Polyuréthane (extérieur), Participates in Collision Detection: no
Name | In
2 x Dalle_003 | R+2
Dalle_003 | R+3

# IfcBuildingElementProxy: 6 - Isolation sur terrasse sous gravier 110 (3)
Classification: Dalle (Classification ARCHICAD); Material: Etanchéité - Bitume, Isolation - Polyuréthane (extérieur)
Propriétés DCE - Numéro de LOT: LOT 07; Numéro article: L07.2.2
AC_Pset_RenovationAndPhasing - Renovation Status: Existing
Material Properties - Component 1, Etanchéité - Bitume, ThermalConductivity: 0.23; Component 1, Etanchéité - Bitume, SpecificHeatCapacity: 1000 J/kg/K; Component 1, Etanchéité - Bitume, MassDensity: 1100 kg/m3; Component 1, Etanchéité - Bitume, Embodied Energy: 2.86 (MJ/kg); Component 1, Etanchéité - Bitume, Embodied Carbon: 0.066 (kgCO₂/kg); Component 1, Etanchéité - Bitume, Name: Etanchéité - Bitume; Component 1, Etanchéité - Bitume, Participates in Collision Detection: no; Component 2, Isolation - Polyuréthane (extérieur), ThermalConductivity: 0.036; Component 2, Isolation - Polyuréthane (extérieur), SpecificHeatCapacity: 1450 J/kg/K; Component 2, Isolation - Polyuréthane (extérieur), MassDensity: 25 kg/m3; Component 2, Isolation - Polyuréthane (extérieur), Embodied Energy: 86.6 (MJ/kg); Component 2, Isolation - Polyuréthane (extérieur), Embodied Carbon: 3.29 (kgCO₂/kg); Component 2, Isolation - Polyuréthane (extérieur), Name: Isolation - Polyuréthane (extérieur); Component 2, Isolation - Polyuréthane (extérieur), Participates in Collision Detection: no
Name | In
Dalle_004 | R+1
Dalle_003 | R+3
Dalle_003 | R+4

# IfcBuildingElementProxy: 6 -Etanchéité RDC non isolée sous dalles sur plots 90, Dalle_004
In: Rez-de-chaussée
Classification: Dalle (Classification ARCHICAD); Material: Divers - Vide, Etanchéité - Bitume
Propriétés DCE - Numéro de LOT: LOT 07; Numéro article: L07.2.3.2; L07.2.3.3; L07.2.3.4
AC_Pset_RenovationAndPhasing - Renovation Status: Existing
Material Properties - Component 1, Divers - Vide, ThermalConductivity: 0.15; Component 1, Divers - Vide, SpecificHeatCapacity: 1008 J/kg/K; Component 1, Divers - Vide, MassDensity: 1.2 kg/m3; Component 1, Divers - Vide, Embodied Energy: 0 (MJ/kg); Component 1, Divers - Vide, Embodied Carbon: 0 (kgCO₂/kg); Component 1, Divers - Vide, Name: Divers - Vide; Component 1, Divers - Vide, Participates in Collision Detection: no; Component 2, Etanchéité - Bitume, ThermalConductivity: 0.23; Component 2, Etanchéité - Bitume, SpecificHeatCapacity: 1000 J/kg/K; Component 2, Etanchéité - Bitume, MassDensity: 1100 kg/m3; Component 2, Etanchéité - Bitume, Embodied Energy: 2.86 (MJ/kg); Component 2, Etanchéité - Bitume, Embodied Carbon: 0.066 (kgCO₂/kg); Component 2, Etanchéité - Bitume, Name: Etanchéité - Bitume; Component 2, Etanchéité - Bitume, Participates in Collision Detection: no

# IfcBuildingElementProxy: 6 -Etanchéité RDC protections multiples 90 (3)
In: Rez-de-chaussée
Classification: Dalle (Classification ARCHICAD); Material: Divers - Vide, Etanchéité - Bitume
Propriétés DCE - Numéro de LOT: LOT 07; Numéro article: L07.2.4.2;L07.2.4.3;L07.2.4.4; L07.2.4.5
AC_Pset_RenovationAndPhasing - Renovation Status: Existing
Material Properties - Component 1, Divers - Vide, ThermalConductivity: 0.15; Component 1, Divers - Vide, SpecificHeatCapacity: 1008 J/kg/K; Component 1, Divers - Vide, MassDensity: 1.2 kg/m3; Component 1, Divers - Vide, Embodied Energy: 0 (MJ/kg); Component 1, Divers - Vide, Embodied Carbon: 0 (kgCO₂/kg); Component 1, Divers - Vide, Name: Divers - Vide; Component 1, Divers - Vide, Participates in Collision Detection: no; Component 2, Etanchéité - Bitume, ThermalConductivity: 0.23; Component 2, Etanchéité - Bitume, SpecificHeatCapacity: 1000 J/kg/K; Component 2, Etanchéité - Bitume, MassDensity: 1100 kg/m3; Component 2, Etanchéité - Bitume, Embodied Energy: 2.86 (MJ/kg); Component 2, Etanchéité - Bitume, Embodied Carbon: 0.066 (kgCO₂/kg); Component 2, Etanchéité - Bitume, Name: Etanchéité - Bitume; Component 2, Etanchéité - Bitume, Participates in Collision Detection: no

# IfcBuildingElementProxy: Bois - Massif 01 100 x 100 (2)
In: R+3
Description: Pergola; Classification: Element de construction non défini (Classification ARCHICAD); Material: Bois - Massif 01
Propriétés DCE - Numéro de LOT: LOT 05; Numéro article: L05.2.2.3.1
AC_Pset_RenovationAndPhasing - Renovation Status: Existing
Material Properties - Bois - Massif 01, ThermalConductivity: 0.14; Bois - Massif 01, SpecificHeatCapacity: 2300 J/kg/K; Bois - Massif 01, MassDensity: 500 kg/m3; Bois - Massif 01, Embodied Energy: 10 (MJ/kg); Bois - Massif 01, Embodied Carbon: 0.36 (kgCO₂/kg); Bois - Massif 01, Name: Bois - Massif 01; Bois - Massif 01, Participates in Collision Detection: yes

# IfcBuildingElementProxy: Béton 10, M_Ext-009
In: R+4
Classification: Finition métallique (Classification ARCHICAD); Material: Béton
AC_Pset_RenovationAndPhasing - Renovation Status: Existing
Material Properties - Béton, ThermalConductivity: 2.3; Béton, SpecificHeatCapacity: 1000 J/kg/K; Béton, MassDensity: 2300 kg/m3; Béton, Embodied Energy: 1.92 (MJ/kg); Béton, Embodied Carbon: 0.198 (kgCO₂/kg); Béton, Name: Béton; Béton, Participates in Collision Detection: yes

# IfcBuildingElementProxy: Béton 120 (3)
In: R+4
Classification: Mur (Classification ARCHICAD); Material: Béton
AC_Pset_RenovationAndPhasing - Renovation Status: Existing
Material Properties - Béton, ThermalConductivity: 2.3; Béton, SpecificHeatCapacity: 1000 J/kg/K; Béton, MassDensity: 2300 kg/m3; Béton, Embodied Energy: 1.92 (MJ/kg); Béton, Embodied Carbon: 0.198 (kgCO₂/kg); Béton, Name: Béton; Béton, Participates in Collision Detection: yes

# IfcBuildingElementProxy: Béton 180 (2)
Classification: Mur (Classification ARCHICAD); Material: Béton
Propriétés DCE - Numéro article: L04.2.12.3.2
AC_Pset_RenovationAndPhasing - Renovation Status: Existing
Material Properties - Béton, ThermalConductivity: 2.3; Béton, SpecificHeatCapacity: 1000 J/kg/K; Béton, MassDensity: 2300 kg/m3; Béton, Embodied Energy: 1.92 (MJ/kg); Béton, Embodied Carbon: 0.198 (kgCO₂/kg); Béton, Name: Béton; Béton, Participates in Collision Detection: yes
Name | In
M_Ext-009 | R+1
M_Ext-009 | R+2

# IfcBuildingElementProxy: Béton 200 (9)
Material: Béton
AC_Pset_RenovationAndPhasing - Renovation Status: Existing
Material Properties - Béton, ThermalConductivity: 2.3; Béton, SpecificHeatCapacity: 1000 J/kg/K; Béton, MassDensity: 2300 kg/m3; Béton, Embodied Energy: 1.92 (MJ/kg); Béton, Embodied Carbon: 0.198 (kgCO₂/kg); Béton, Name: Béton; Béton, Participates in Collision Detection: yes
Name | In | Classification
7 x M_Ext-007 | Sous-sol | Mur (Classification ARCHICAD)
Dalle_004 | R+1 | Dalle (Classification ARCHICAD) | Propriétés DCE - Numéro de LOT: LOT 04; Numéro article: L04.2.12.6
M_Ext-007 | R+3 | Mur (Classification ARCHICAD)

# IfcBuildingElementProxy: Béton 210 (7)
Classification: Dalle (Classification ARCHICAD); Material: Béton
Propriétés DCE - Numéro de LOT: LOT 04; Numéro article: L04.2.12.6
AC_Pset_RenovationAndPhasing - Renovation Status: Existing
Material Properties - Béton, ThermalConductivity: 2.3; Béton, SpecificHeatCapacity: 1000 J/kg/K; Béton, MassDensity: 2300 kg/m3; Béton, Embodied Energy: 1.92 (MJ/kg); Béton, Embodied Carbon: 0.198 (kgCO₂/kg); Béton, Name: Béton; Béton, Participates in Collision Detection: yes
Name | In
2 x Dalle_004 | R+1
2 x Dalle_004 | R+2
2 x Dalle_004 | R+3
Dalle_003 | R+4

# IfcBuildingElementProxy: Béton 230 (4)
Classification: Dalle (Classification ARCHICAD); Material: Béton
Propriétés DCE - Numéro de LOT: LOT 04; Numéro article: L04.2.12.6
AC_Pset_RenovationAndPhasing - Renovation Status: Existing
Material Properties - Béton, ThermalConductivity: 2.3; Béton, SpecificHeatCapacity: 1000 J/kg/K; Béton, MassDensity: 2300 kg/m3; Béton, Embodied Energy: 1.92 (MJ/kg); Béton, Embodied Carbon: 0.198 (kgCO₂/kg); Béton, Name: Béton; Béton, Participates in Collision Detection: yes
Name | In
Dalle_003 | R+4
Dalle_003 | R+2
Dalle_003 | R+3
Dalle_005 | R+4

# IfcBuildingElementProxy: Béton 250 (2)
Classification: Dalle (Classification ARCHICAD); Material: Béton
Propriétés DCE - Numéro de LOT: LOT 04; Numéro article: L04.2.12.6
AC_Pset_RenovationAndPhasing - Renovation Status: Existing
Material Properties - Béton, ThermalConductivity: 2.3; Béton, SpecificHeatCapacity: 1000 J/kg/K; Béton, MassDensity: 2300 kg/m3; Béton, Embodied Energy: 1.92 (MJ/kg); Béton, Embodied Carbon: 0.198 (kgCO₂/kg); Béton, Name: Béton; Béton, Participates in Collision Detection: yes
Name | In
Dalle_004 | R+2
Dalle_003 | R+4

# IfcBuildingElementProxy: Béton 2500, Dalle_004
In: Sous-sol
Classification: Dalle (Classification ARCHICAD); Material: Béton
AC_Pset_RenovationAndPhasing - Renovation Status: Existing
Material Properties - Béton, ThermalConductivity: 2.3; Béton, SpecificHeatCapacity: 1000 J/kg/K; Béton, MassDensity: 2300 kg/m3; Béton, Embodied Energy: 1.92 (MJ/kg); Béton, Embodied Carbon: 0.198 (kgCO₂/kg); Béton, Name: Béton; Béton, Participates in Collision Detection: yes

# IfcBuildingElementProxy: Béton 50, M_Ext-024
In: Rez-de-chaussée
Type - ElementType: CONSTRUCTION ELEMENT; PredefinedType: USERDEFINED
Classification: Couvertine de mur (Classification ARCHICAD); Material: Béton
AC_Pset_RenovationAndPhasing - Renovation Status: Existing
Material Properties - Béton, ThermalConductivity: 2.3; Béton, SpecificHeatCapacity: 1000 J/kg/K; Béton, MassDensity: 2300 kg/m3; Béton, Embodied Energy: 1.92 (MJ/kg); Béton, Embodied Carbon: 0.198 (kgCO₂/kg); Béton, Name: Béton; Béton, Participates in Collision Detection: yes

# IfcBuildingElementProxy: Béton 90, Dalle_003
In: Rez-de-chaussée
Classification: Dalle (Classification ARCHICAD); Material: Béton
Propriétés DCE - Numéro de LOT: LOT 19; Numéro article: L19.2.4.2
AC_Pset_RenovationAndPhasing - Renovation Status: Existing
Material Properties - Béton, ThermalConductivity: 2.3; Béton, SpecificHeatCapacity: 1000 J/kg/K; Béton, MassDensity: 2300 kg/m3; Béton, Embodied Energy: 1.92 (MJ/kg); Béton, Embodied Carbon: 0.198 (kgCO₂/kg); Béton, Name: Béton; Béton, Participates in Collision Detection: yes

# IfcBuildingElementProxy: Béton DALLAGE 130, Dalle_002
In: Sous-sol
Classification: Dalle (Classification ARCHICAD); Material: Béton DALLAGE
Propriétés DCE - Numéro de LOT: LOT 04; Numéro article: L04.2.8.5
AC_Pset_RenovationAndPhasing - Renovation Status: Existing
Material Properties - Béton DALLAGE, ThermalConductivity: 2.3; Béton DALLAGE, SpecificHeatCapacity: 1000 J/kg/K; Béton DALLAGE, MassDensity: 2300 kg/m3; Béton DALLAGE, Embodied Energy: 1.92 (MJ/kg); Béton DALLAGE, Embodied Carbon: 0.198 (kgCO₂/kg); Béton DALLAGE, Name: Béton DALLAGE; Béton DALLAGE, Participates in Collision Detection: yes

# IfcBuildingElementProxy: Béton DALLAGE 250, Dalle_003
In: R+4
Classification: Dalle (Classification ARCHICAD); Material: Béton DALLAGE
AC_Pset_RenovationAndPhasing - Renovation Status: Existing
Material Properties - Béton DALLAGE, ThermalConductivity: 2.3; Béton DALLAGE, SpecificHeatCapacity: 1000 J/kg/K; Béton DALLAGE, MassDensity: 2300 kg/m3; Béton DALLAGE, Embodied Energy: 1.92 (MJ/kg); Béton DALLAGE, Embodied Carbon: 0.198 (kgCO₂/kg); Béton DALLAGE, Name: Béton DALLAGE; Béton DALLAGE, Participates in Collision Detection: yes

# IfcBuildingElementProxy: Béton armé (Banché) 200 (4)
In: -2. Etage
Classification: Mur (Classification ARCHICAD); Material: Béton armé (Banché)
Propriétés DCE - Numéro de LOT: LOT 04; Numéro article: L0.4.2.6.4.2
AC_Pset_RenovationAndPhasing - Renovation Status: Existing
Material Properties - Béton armé (Banché), ThermalConductivity: 2.3; Béton armé (Banché), SpecificHeatCapacity: 1000 J/kg/K; Béton armé (Banché), MassDensity: 2300 kg/m3; Béton armé (Banché), Embodied Energy: 1.92 (MJ/kg); Béton armé (Banché), Embodied Carbon: 0.198 (kgCO₂/kg); Béton armé (Banché), Name: Béton armé (Banché); Béton armé (Banché), Participates in Collision Detection: yes

# IfcBuildingElementProxy: Béton armé (Coulé) 200 x 200, Pot-002
In: R+3
Classification: Poteau (Classification ARCHICAD); Material: Béton armé (Coulé)
Propriétés DCE - Numéro de LOT: LOT 04; Numéro article: L04.2.12.5.1; L04.2.12.5.2; L04.2.12.5.3
AC_Pset_RenovationAndPhasing - Renovation Status: Existing
Material Properties - Béton armé (Coulé), ThermalConductivity: 2.3; Béton armé (Coulé), SpecificHeatCapacity: 1000 J/kg/K; Béton armé (Coulé), MassDensity: 2300 kg/m3; Béton armé (Coulé), Embodied Energy: 1.92 (MJ/kg); Béton armé (Coulé), Embodied Carbon: 0.198 (kgCO₂/kg); Béton armé (Coulé), Name: Béton armé (Coulé); Béton armé (Coulé), Participates in Collision Detection: yes

# IfcBuildingElementProxy: Béton armé (Coulé) 460 x 200, Pot-002
In: R+3
Classification: Poteau (Classification ARCHICAD); Material: Béton armé (Coulé)
Propriétés DCE - Numéro de LOT: LOT 04; Numéro article: L04.2.12.5.1; L04.2.12.5.2; L04.2.12.5.3
AC_Pset_RenovationAndPhasing - Renovation Status: Existing
Material Properties - Béton armé (Coulé), ThermalConductivity: 2.3; Béton armé (Coulé), SpecificHeatCapacity: 1000 J/kg/K; Béton armé (Coulé), MassDensity: 2300 kg/m3; Béton armé (Coulé), Embodied Energy: 1.92 (MJ/kg); Béton armé (Coulé), Embodied Carbon: 0.198 (kgCO₂/kg); Béton armé (Coulé), Name: Béton armé (Coulé); Béton armé (Coulé), Participates in Collision Detection: yes

# IfcBuildingElementProxy: Conduit 23, MOB-002
In: R+4
AC_Pset_RenovationAndPhasing - Renovation Status: Existing

# IfcBuildingElementProxy: Couronnement mur 0401163462 280 x 60 (3)
In: Sous-sol
Type - ElementType: ELEMENTS; PredefinedType: USERDEFINED
Description: Chapeau béton; Classification: Chapeau béton (Classification ARCHICAD); Material: Béton préfabriqué
Propriétés DCE - Numéro de LOT: LOT 04; Numéro article: L04.2.13.2.2
AC_Pset_RenovationAndPhasing - Renovation Status: Existing
Material Properties - Béton préfabriqué, ThermalConductivity: 0.6; Béton préfabriqué, SpecificHeatCapacity: 880 J/kg/K; Béton préfabriqué, MassDensity: 1400 kg/m3; Béton préfabriqué, Embodied Energy: 0.72 (MJ/kg); Béton préfabriqué, Embodied Carbon: 0.088 (kgCO₂/kg); Béton préfabriqué, Name: Béton préfabriqué; Béton préfabriqué, Participates in Collision Detection: yes

# IfcBuildingElementProxy: Couronnement mur 0401163462 330 x 60 (10)
In: Rez-de-chaussée
Type - ElementType: ELEMENTS; PredefinedType: USERDEFINED
Description: Chapeau béton; Classification: Chapeau béton (Classification ARCHICAD); Material: Béton préfabriqué
Propriétés DCE - Numéro de LOT: LOT 04; Numéro article: L04.2.13.2.2
AC_Pset_RenovationAndPhasing - Renovation Status: Existing
Material Properties - Béton préfabriqué, ThermalConductivity: 0.6; Béton préfabriqué, SpecificHeatCapacity: 880 J/kg/K; Béton préfabriqué, MassDensity: 1400 kg/m3; Béton préfabriqué, Embodied Energy: 0.72 (MJ/kg); Béton préfabriqué, Embodied Carbon: 0.088 (kgCO₂/kg); Béton préfabriqué, Name: Béton préfabriqué; Béton préfabriqué, Participates in Collision Detection: yes

# IfcBuildingElementProxy: Couvertine Métal 270 x 50 (4)
In: Rez-de-chaussée
Type - ElementType: CONSTRUCTION ELEMENT; PredefinedType: USERDEFINED
Description: Couvertine; Classification: Couvertine de mur (Classification ARCHICAD); Material: Métal - Aluminium
Propriétés DCE - Numéro de LOT: LOT 07; Numéro article: L07.2.7.1
AC_Pset_RenovationAndPhasing - Renovation Status: Existing
Material Properties - Métal - Aluminium, ThermalConductivity: 160; Métal - Aluminium, SpecificHeatCapacity: 880 J/kg/K; Métal - Aluminium, MassDensity: 2800 kg/m3; Métal - Aluminium, Embodied Energy: 155 (MJ/kg); Métal - Aluminium, Embodied Carbon: 9.16 (kgCO₂/kg); Métal - Aluminium, Name: Métal - Aluminium; Métal - Aluminium, Participates in Collision Detection: yes

# IfcBuildingElementProxy: Couvertine Métal 280 x 50 (35)
Type - ElementType: CONSTRUCTION ELEMENT; PredefinedType: USERDEFINED
Description: Couvertine; Classification: Couvertine de mur (Classification ARCHICAD); Material: Métal - Aluminium
Propriétés DCE - Numéro de LOT: LOT 07; Numéro article: L07.2.7.1
AC_Pset_RenovationAndPhasing - Renovation Status: Existing
Material Properties - Métal - Aluminium, ThermalConductivity: 160; Métal - Aluminium, SpecificHeatCapacity: 880 J/kg/K; Métal - Aluminium, MassDensity: 2800 kg/m3; Métal - Aluminium, Embodied Energy: 155 (MJ/kg); Métal - Aluminium, Embodied Carbon: 9.16 (kgCO₂/kg); Métal - Aluminium, Name: Métal - Aluminium; Métal - Aluminium, Participates in Collision Detection: yes
Name | In
7 x Couvertine métal laqué | R+2
5 x Couvertine métal laqué | R+3
14 x Couvertine métal laqué | R+4
9 x Couvertine métal laqué | Etage

# IfcBuildingElementProxy: Couvertine Métal 320 x 50 (5)
In: R+4
Type - ElementType: CONSTRUCTION ELEMENT; PredefinedType: USERDEFINED
Description: Couvertine; Classification: Couvertine de mur (Classification ARCHICAD); Material: Métal - Aluminium
Propriétés DCE - Numéro de LOT: LOT 07; Numéro article: L07.2.7.1
AC_Pset_RenovationAndPhasing - Renovation Status: Existing
Material Properties - Métal - Aluminium, ThermalConductivity: 160; Métal - Aluminium, SpecificHeatCapacity: 880 J/kg/K; Métal - Aluminium, MassDensity: 2800 kg/m3; Métal - Aluminium, Embodied Energy: 155 (MJ/kg); Métal - Aluminium, Embodied Carbon: 9.16 (kgCO₂/kg); Métal - Aluminium, Name: Métal - Aluminium; Métal - Aluminium, Participates in Collision Detection: yes

# IfcBuildingElementProxy: Couvertine Métal 330 x 50 (11)
Type - ElementType: CONSTRUCTION ELEMENT; PredefinedType: USERDEFINED
Description: Couvertine; Classification: Couvertine de mur (Classification ARCHICAD); Material: Métal - Aluminium
Propriétés DCE - Numéro de LOT: LOT 07; Numéro article: L07.2.7.1
AC_Pset_RenovationAndPhasing - Renovation Status: Existing
Material Properties - Métal - Aluminium, ThermalConductivity: 160; Métal - Aluminium, SpecificHeatCapacity: 880 J/kg/K; Métal - Aluminium, MassDensity: 2800 kg/m3; Métal - Aluminium, Embodied Energy: 155 (MJ/kg); Métal - Aluminium, Embodied Carbon: 9.16 (kgCO₂/kg); Métal - Aluminium, Name: Métal - Aluminium; Métal - Aluminium, Participates in Collision Detection: yes
Name | In
4 x Couvertine métal laqué | R+3
3 x Couvertine métal laqué | R+1
4 x Couvertine métal laqué | R+4

# IfcBuildingElementProxy: Couvertine Métal 400 x 50 (2)
In: R+4
Type - ElementType: CONSTRUCTION ELEMENT; PredefinedType: USERDEFINED
Description: Couvertine; Classification: Couvertine de mur (Classification ARCHICAD); Material: Métal - Aluminium
Propriétés DCE - Numéro de LOT: LOT 07; Numéro article: L07.2.7.1
AC_Pset_RenovationAndPhasing - Renovation Status: Existing
Material Properties - Métal - Aluminium, ThermalConductivity: 160; Métal - Aluminium, SpecificHeatCapacity: 880 J/kg/K; Métal - Aluminium, MassDensity: 2800 kg/m3; Métal - Aluminium, Embodied Energy: 155 (MJ/kg); Métal - Aluminium, Embodied Carbon: 9.16 (kgCO₂/kg); Métal - Aluminium, Name: Métal - Aluminium; Métal - Aluminium, Participates in Collision Detection: yes

# IfcBuildingElementProxy: Couvertine Métal 440 x 50, Couvertine métal laqué
In: R+4
Type - ElementType: CONSTRUCTION ELEMENT; PredefinedType: USERDEFINED
Description: Couvertine; Classification: Couvertine de mur (Classification ARCHICAD); Material: Métal - Aluminium
Propriétés DCE - Numéro de LOT: LOT 07; Numéro article: L07.2.7.1
AC_Pset_RenovationAndPhasing - Renovation Status: Existing
Material Properties - Métal - Aluminium, ThermalConductivity: 160; Métal - Aluminium, SpecificHeatCapacity: 880 J/kg/K; Métal - Aluminium, MassDensity: 2800 kg/m3; Métal - Aluminium, Embodied Energy: 155 (MJ/kg); Métal - Aluminium, Embodied Carbon: 9.16 (kgCO₂/kg); Métal - Aluminium, Name: Métal - Aluminium; Métal - Aluminium, Participates in Collision Detection: yes

# IfcBuildingElementProxy: Couvertine Métal 50 x 50, Couvertine métal laqué
In: Etage
Type - ElementType: CONSTRUCTION ELEMENT; PredefinedType: USERDEFINED
Description: Couvertine; Classification: Couvertine de mur (Classification ARCHICAD); Mur (Classification ARCHICAD); Material: Métal - Aluminium
Propriétés DCE - Numéro de LOT: LOT 07; Numéro article: L07.2.7.1
AC_Pset_RenovationAndPhasing - Renovation Status: Existing
Material Properties - Métal - Aluminium, ThermalConductivity: 160; Métal - Aluminium, SpecificHeatCapacity: 880 J/kg/K; Métal - Aluminium, MassDensity: 2800 kg/m3; Métal - Aluminium, Embodied Energy: 155 (MJ/kg); Métal - Aluminium, Embodied Carbon: 9.16 (kgCO₂/kg); Métal - Aluminium, Name: Métal - Aluminium; Métal - Aluminium, Participates in Collision Detection: yes

# IfcBuildingElementProxy: Couvertine Métal 840 x 50, Couvertine métal laqué
In: Etage
Type - ElementType: CONSTRUCTION ELEMENT; PredefinedType: USERDEFINED
Description: Couvertine; Classification: Couvertine de mur (Classification ARCHICAD); Material: Métal - Aluminium
Propriétés DCE - Numéro de LOT: LOT 07; Numéro article: L07.2.7.1
AC_Pset_RenovationAndPhasing - Renovation Status: Existing
Material Properties - Métal - Aluminium, ThermalConductivity: 160; Métal - Aluminium, SpecificHeatCapacity: 880 J/kg/K; Métal - Aluminium, MassDensity: 2800 kg/m3; Métal - Aluminium, Embodied Energy: 155 (MJ/kg); Métal - Aluminium, Embodied Carbon: 9.16 (kgCO₂/kg); Métal - Aluminium, Name: Métal - Aluminium; Métal - Aluminium, Participates in Collision Detection: yes

# IfcBuildingElementProxy: Echelle murale 23, Echelle aluminium
In: R+3
Description: Echelle mobile; Classification: Element de construction non défini (Classification ARCHICAD)
Propriétés DCE - Numéro de LOT: LOT 17; Numéro article: L17.2.7.2
AC_Pset_RenovationAndPhasing - Renovation Status: Existing

# IfcBuildingElementProxy: Env. - Gravier 50 (4)
Classification: Dalle (Classification ARCHICAD); Material: Env. - Gravier
Propriétés DCE - Numéro de LOT: LOT 07
AC_Pset_RenovationAndPhasing - Renovation Status: Existing
Material Properties - Env. - Gravier, ThermalConductivity: 1.4; Env. - Gravier, SpecificHeatCapacity: 1900 J/kg/K; Env. - Gravier, MassDensity: 2200 kg/m3; Env. - Gravier, Embodied Energy: 0.083 (MJ/kg); Env. - Gravier, Embodied Carbon: 0.005 (kgCO₂/kg); Env. - Gravier, Name: Env. - Gravier; Env. - Gravier, Participates in Collision Detection: no
Name | In | Numéro article
Dalle_003 | R+4 | L07.2.4.6
Dalle_004 | R+1 | L07.2.2
Dalle_003 | R+3 | L07.2.2.4
Dalle_003 | R+4 | L07.2.2.4

# IfcBuildingElementProxy: Env. - Terre (3)
Classification: Géométrie du site (Classification ARCHICAD); Material: Env. - Terre
Propriétés DCE - Numéro de LOT: LOT 19; Numéro article: L19.2.5.2
AC_Pset_RenovationAndPhasing - Renovation Status: Existing
Material Properties - Env. - Terre, ThermalConductivity: 1.4; Env. - Terre, SpecificHeatCapacity: 1400 J/kg/K; Env. - Terre, MassDensity: 1900 kg/m3; Env. - Terre, Embodied Energy: 0.43 (MJ/kg); Env. - Terre, Embodied Carbon: 0.023 (kgCO₂/kg); Env. - Terre, Name: Env. - Terre; Env. - Terre, Participates in Collision Detection: no
Name | In
TER-004 | Rez-de-chaussée
TER-004 | R+3
TER-004 | R+4

# IfcBuildingElementProxy: Ferme pour shed 23 (15)
In: Etage
Classification: Ferme (Classification ARCHICAD); Material: Bois - Massif 02
Propriétés DCE - Numéro de LOT: LOT 05; Numéro article: L05.2.2.2.1
AC_Pset_RenovationAndPhasing - Renovation Status: Existing
Material Properties - Bois - Massif 02, ThermalConductivity: 0.14; Bois - Massif 02, SpecificHeatCapacity: 2300 J/kg/K; Bois - Massif 02, MassDensity: 500 kg/m3; Bois - Massif 02, Embodied Energy: 10 (MJ/kg); Bois - Massif 02, Embodied Carbon: 0.36 (kgCO₂/kg); Bois - Massif 02, Name: Bois - Massif 02; Bois - Massif 02, Participates in Collision Detection: yes

# IfcBuildingElementProxy: Finition ext - Bardage bois, Forme-007
In: R+2
Material: Finition ext - Bardage bois
AC_Pset_RenovationAndPhasing - Renovation Status: Existing
Material Properties - Finition ext - Bardage bois, ThermalConductivity: 0.14; Finition ext - Bardage bois, SpecificHeatCapacity: 2300 J/kg/K; Finition ext - Bardage bois, MassDensity: 500 kg/m3; Finition ext - Bardage bois, Embodied Energy: 10 (MJ/kg); Finition ext - Bardage bois, Embodied Carbon: 0.36 (kgCO₂/kg); Finition ext - Bardage bois, Name: Finition ext - Bardage bois; Finition ext - Bardage bois, Participates in Collision Detection: no

# IfcBuildingElementProxy: Muret en L H=75 600 x 750 (16)
Type - ElementType: CONSTRUCTION ELEMENT; PredefinedType: USERDEFINED
Description: Muret préfa H=75; Classification: Couvertine de mur (Classification ARCHICAD); Material: Béton
Propriétés DCE - Numéro de LOT: LOT 04; LOT 15; Numéro article: L04.2.16.3; L15.2.4.1
AC_Pset_RenovationAndPhasing - Renovation Status: Existing
Material Properties - Béton, ThermalConductivity: 2.3; Béton, SpecificHeatCapacity: 1000 J/kg/K; Béton, MassDensity: 2300 kg/m3; Béton, Embodied Energy: 1.92 (MJ/kg); Béton, Embodied Carbon: 0.198 (kgCO₂/kg); Béton, Name: Béton; Béton, Participates in Collision Detection: yes
Name | In
3 x Muret béton préfabriqué en L H=75 | Rez-de-chaussée
2 x Muret béton préfabriqué en L H=75 | R+3
11 x Muret béton préfabriqué en L H=75 | R+4

# IfcBuildingElementProxy: Panne 23, MOB-003
In: R+3
Classification: Toit (Classification ARCHICAD); Material: Bois - Massif 01
AC_Pset_RenovationAndPhasing - Renovation Status: Existing
Material Properties - Bois - Massif 01, ThermalConductivity: 0.14; Bois - Massif 01, SpecificHeatCapacity: 2300 J/kg/K; Bois - Massif 01, MassDensity: 500 kg/m3; Bois - Massif 01, Embodied Energy: 10 (MJ/kg); Bois - Massif 01, Embodied Carbon: 0.36 (kgCO₂/kg); Bois - Massif 01, Name: Bois - Massif 01; Bois - Massif 01, Participates in Collision Detection: yes

# IfcBuildingElementProxy: Sèche linge 23, MOB-002
In: R+4
Classification: Terminal sanitaire (Classification ARCHICAD)
AC_Pset_RenovationAndPhasing - Renovation Status: Existing

# IfcBuildingElementProxy: Tube évidé 23 (9)
AC_Pset_RenovationAndPhasing - Renovation Status: Existing
Name | In | Classification
MOB-003 | R+2 | Dalle (Classification ARCHICAD); Elément de construction (Classification ARCHICAD)
3 x MOB-003 | R+1 | Terminal d'air (Classification ARCHICAD)
MOB-003 | R+1 | Accessoire distinct (Classification ARCHICAD)
MOB-003 | R+1 | Terminal de gaz (Classification ARCHICAD)
MOB-003 | R+2 | Terminal de gaz (Classification ARCHICAD)
MOB-003 | R+2 | Terminal d'air (Classification ARCHICAD)
MOB-003 | R+3 | Terminal d'air (Classification ARCHICAD)

# IfcBuildingElementProxy: Volume - Etude (77)
Material: Volume - Etude
AC_Pset_RenovationAndPhasing - Renovation Status: Existing
Material Properties - Volume - Etude, ThermalConductivity: 0; Volume - Etude, SpecificHeatCapacity: 0 J/kg/K; Volume - Etude, MassDensity: 0 kg/m3; Volume - Etude, Embodied Energy: 0 (MJ/kg); Volume - Etude, Embodied Carbon: 0 (kgCO₂/kg); Volume - Etude, Name: Volume - Etude; Volume - Etude, Participates in Collision Detection: yes
Name | In
4 x Forme-017 | Sous-sol
8 x Forme-009 | R+2
4 x Forme-010 | R+2
6 x Forme-010 | R+3
14 x Forme-009 | R+3
28 x Forme-009 | R+4
13 x Forme-010 | R+4

# IfcColumn: Béton 200 x 1100 (2)
In: Sous-sol
Type - PredefinedType: COLUMN
Classification: Poteau (Classification ARCHICAD); Material: Béton
Propriétés DCE - Numéro de LOT: LOT 04; Numéro article: L04.2.8.4.1
AC_Pset_RenovationAndPhasing - Renovation Status: Existing
Pset_ColumnCommon - LoadBearing: yes; Reference: Béton 200 x 1100
Material Properties - Béton, ThermalConductivity: 2.3; Béton, SpecificHeatCapacity: 1000 J/kg/K; Béton, MassDensity: 2300 kg/m3; Béton, Embodied Energy: 1.92 (MJ/kg); Béton, Embodied Carbon: 0.198 (kgCO₂/kg); Béton, Name: Béton; Béton, Participates in Collision Detection: yes
BaseQuantities - Width: 0.2 m; Depth: 1.1 m; CrossSectionArea: 0.22 m2
Name | Length (m) | OuterSurfaceArea (m2) | TotalSurfaceArea (m2) = GrossSurfaceArea (m2) | GrossVolume (m3) = NetVolume (m3)
Pot-002 | 3.15 | 8.10626 | 8.54626 | 0.685426
Pot-002 | 2.45 | 6.37 | 6.81 | 0.539

# IfcColumn: Béton 200 x 1260, Pot-002
In: Sous-sol
Type - PredefinedType: COLUMN
Classification: Poteau (Classification ARCHICAD); Material: Béton
Propriétés DCE - Numéro de LOT: LOT 04; Numéro article: L04.2.8.4.1
AC_Pset_RenovationAndPhasing - Renovation Status: Existing
Pset_ColumnCommon - LoadBearing: yes; Reference: Béton 200 x 1260
Material Properties - Béton, ThermalConductivity: 2.3; Béton, SpecificHeatCapacity: 1000 J/kg/K; Béton, MassDensity: 2300 kg/m3; Béton, Embodied Energy: 1.92 (MJ/kg); Béton, Embodied Carbon: 0.198 (kgCO₂/kg); Béton, Name: Béton; Béton, Participates in Collision Detection: yes
BaseQuantities - Length: 2.55 m; Width: 0.2 m; Depth: 1.26 m; CrossSectionArea: 0.252 m2; OuterSurfaceArea: 7.446 m2; TotalSurfaceArea: 7.95 m2; GrossSurfaceArea: 7.95 m2; GrossVolume: 0.6426 m3; NetVolume: 0.6426 m3

# IfcColumn: Béton 200 x 1500, Pot-002
In: Sous-sol
Type - PredefinedType: COLUMN
Classification: Poteau (Classification ARCHICAD); Material: Béton
Propriétés DCE - Numéro de LOT: LOT 04; Numéro article: L04.2.8.4.1
AC_Pset_RenovationAndPhasing - Renovation Status: Existing
Pset_ColumnCommon - LoadBearing: yes; Reference: Béton 200 x 1500
Material Properties - Béton, ThermalConductivity: 2.3; Béton, SpecificHeatCapacity: 1000 J/kg/K; Béton, MassDensity: 2300 kg/m3; Béton, Embodied Energy: 1.92 (MJ/kg); Béton, Embodied Carbon: 0.198 (kgCO₂/kg); Béton, Name: Béton; Béton, Participates in Collision Detection: yes
BaseQuantities - Length: 2.67 m; Width: 0.2 m; Depth: 1.5 m; CrossSectionArea: 0.3 m2; OuterSurfaceArea: 9.05399 m2; TotalSurfaceArea: 9.65398 m2; GrossSurfaceArea: 9.65398 m2; GrossVolume: 0.800999 m3; NetVolume: 0.800999 m3

# IfcColumn: Béton 200 x 700 (21)
In: Sous-sol
Type - PredefinedType: COLUMN
Classification: Poteau (Classification ARCHICAD); Material: Béton
Propriétés DCE - Numéro de LOT: LOT 04; Numéro article: L04.2.8.4.1
AC_Pset_RenovationAndPhasing - Renovation Status: Existing
Pset_ColumnCommon - LoadBearing: yes; Reference: Béton 200 x 700
Material Properties - Béton, ThermalConductivity: 2.3; Béton, SpecificHeatCapacity: 1000 J/kg/K; Béton, MassDensity: 2300 kg/m3; Béton, Embodied Energy: 1.92 (MJ/kg); Béton, Embodied Carbon: 0.198 (kgCO₂/kg); Béton, Name: Béton; Béton, Participates in Collision Detection: yes
BaseQuantities - Width: 0.2 m; Depth: 0.7 m; CrossSectionArea: 0.14 m2
Name | Length (m) | OuterSurfaceArea (m2) | TotalSurfaceArea (m2) = GrossSurfaceArea (m2) | GrossVolume (m3) = NetVolume (m3)
5 x Pot-002 | 2.3 | 4.14 | 4.42 | 0.322
6 x Pot-002 | 2.1 | 3.78 | 4.06 | 0.294
6 x Pot-002 | 2.2 | 3.96 | 4.24 | 0.308
Pot-002 | 2.555 | 4.599 | 4.879 | 0.3577
Pot-002 | 2.45 | 4.41 | 4.69 | 0.343
2 x Pot-002 | 2.4 | 4.32 | 4.6 | 0.336

# IfcColumn: Béton armé (Coulé) 200 x 672, Pot-002
In: R+2
Type - PredefinedType: COLUMN
Classification: Poteau (Classification ARCHICAD); Material: Béton armé (Coulé)
Propriétés DCE - Numéro de LOT: LOT 04; Numéro article: L04.2.12.5.1; L04.2.12.5.2; L04.2.12.5.3
AC_Pset_RenovationAndPhasing - Renovation Status: Existing
Pset_ColumnCommon - LoadBearing: yes; Reference: Béton armé (Coulé) 200 x 672
Material Properties - Béton armé (Coulé), ThermalConductivity: 2.3; Béton armé (Coulé), SpecificHeatCapacity: 1000 J/kg/K; Béton armé (Coulé), MassDensity: 2300 kg/m3; Béton armé (Coulé), Embodied Energy: 1.92 (MJ/kg); Béton armé (Coulé), Embodied Carbon: 0.198 (kgCO₂/kg); Béton armé (Coulé), Name: Béton armé (Coulé); Béton armé (Coulé), Participates in Collision Detection: yes
BaseQuantities - Length: 2.51 m; Width: 0.2 m; Depth: 0.672397 m; CrossSectionArea: 0.134479 m2; OuterSurfaceArea: 4.37943 m2; TotalSurfaceArea: 4.64839 m2; GrossSurfaceArea: 4.64839 m2; GrossVolume: 0.337543 m3; NetVolume: 0.337543 m3

# IfcColumn: Béton armé (Coulé) 200 x 971, Pot-002
In: R+2
Type - PredefinedType: COLUMN
Classification: Poteau (Classification ARCHICAD); Material: Béton armé (Coulé)
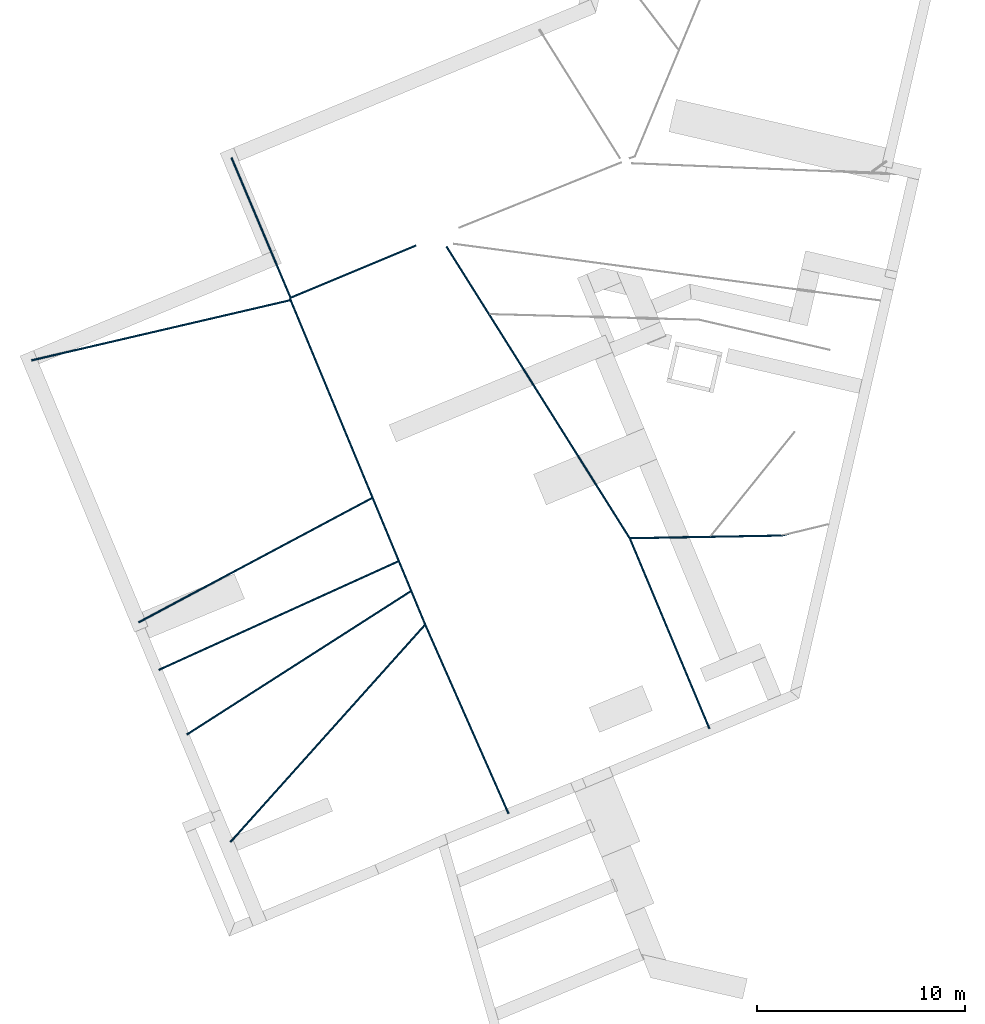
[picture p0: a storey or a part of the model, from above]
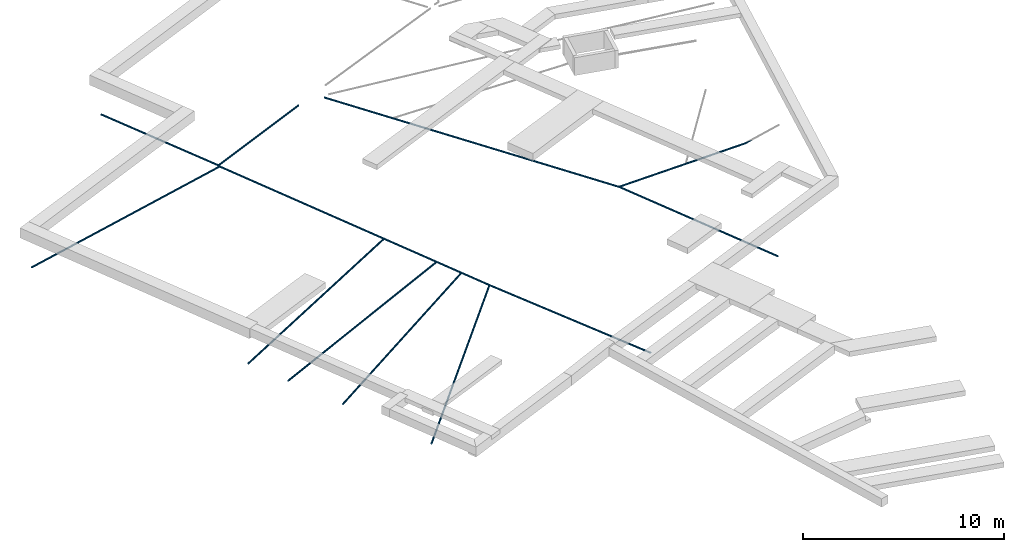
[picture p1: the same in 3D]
Properties of the parts of a building model (IFC2X3), part 3 of 22

# IfcColumn: Béton armé (Coulé) 200 x 971, Pot-002
Propriétés DCE - Numéro de LOT: LOT 04; Numéro article: L04.2.12.5.1; L04.2.12.5.2; L04.2.12.5.3
AC_Pset_RenovationAndPhasing - Renovation Status: Existing
Pset_ColumnCommon - LoadBearing: yes; Reference: Béton armé (Coulé) 200 x 971
Material Properties - Béton armé (Coulé), ThermalConductivity: 2.3; Béton armé (Coulé), SpecificHeatCapacity: 1000 J/kg/K; Béton armé (Coulé), MassDensity: 2300 kg/m3; Béton armé (Coulé), Embodied Energy: 1.92 (MJ/kg); Béton armé (Coulé), Embodied Carbon: 0.198 (kgCO₂/kg); Béton armé (Coulé), Name: Béton armé (Coulé); Béton armé (Coulé), Participates in Collision Detection: yes
BaseQuantities - Length: 2.76 m; Width: 0.2 m; Depth: 0.970609 m; CrossSectionArea: 0.194122 m2; OuterSurfaceArea: 6.46176 m2; TotalSurfaceArea: 6.85 m2; GrossSurfaceArea: 6.85 m2; GrossVolume: 0.535776 m3; NetVolume: 0.535776 m3

# IfcCovering: 6 -Dalles sur plots 130 (3)
Type - PredefinedType: INSULATION
Classification: Isolation (Classification ARCHICAD); Material: Finition sol - Dalles terrasse, Divers - Vide
Pset_CoveringCommon - AcousticRating: Non défini; Material: 6 -Dalles sur plots
Propriétés DCE - Numéro de LOT: LOT 07
AC_Pset_RenovationAndPhasing - Renovation Status: Existing
Material Properties - Component 1, Finition sol - Dalles terrasse, ThermalConductivity: 0.58; Component 1, Finition sol - Dalles terrasse, SpecificHeatCapacity: 840 J/kg/K; Component 1, Finition sol - Dalles terrasse, MassDensity: 1500 kg/m3; Component 1, Finition sol - Dalles terrasse, Embodied Energy: 3 (MJ/kg); Component 1, Finition sol - Dalles terrasse, Embodied Carbon: 0.24 (kgCO₂/kg); Component 1, Finition sol - Dalles terrasse, Name: Finition sol - Dalles terrasse; Component 1, Finition sol - Dalles terrasse, Participates in Collision Detection: no; Component 2, Divers - Vide, ThermalConductivity: 0.15; Component 2, Divers - Vide, SpecificHeatCapacity: 1008 J/kg/K; Component 2, Divers - Vide, MassDensity: 1.2 kg/m3; Component 2, Divers - Vide, Embodied Energy: 0 (MJ/kg); Component 2, Divers - Vide, Embodied Carbon: 0 (kgCO₂/kg); Component 2, Divers - Vide, Name: Divers - Vide; Component 2, Divers - Vide, Participates in Collision Detection: no
Name | In | Numéro article | GrossArea (m2) = NetArea (m2)
Dalle_004 | R+2 | L07.2.3.5 | 9.95122
Dalle_004 | R+2 | LOT 07.2.3.5 | 47.6884
Dalle_004 | R+3 | LOT 07.2.3.5 | 32.9138

# IfcCovering: 6 -Dalles sur plots multi protections 130 (2)
Type - PredefinedType: INSULATION
Classification: Isolation (Classification ARCHICAD); Material: Finition sol - Dalles terrasse, Divers - Vide
Pset_CoveringCommon - AcousticRating: Non défini; Material: 6 -Dalles sur plots multi protections
Propriétés DCE - Numéro de LOT: LOT 07
AC_Pset_RenovationAndPhasing - Renovation Status: Existing
Material Properties - Component 1, Finition sol - Dalles terrasse, ThermalConductivity: 0.58; Component 1, Finition sol - Dalles terrasse, SpecificHeatCapacity: 840 J/kg/K; Component 1, Finition sol - Dalles terrasse, MassDensity: 1500 kg/m3; Component 1, Finition sol - Dalles terrasse, Embodied Energy: 3 (MJ/kg); Component 1, Finition sol - Dalles terrasse, Embodied Carbon: 0.24 (kgCO₂/kg); Component 1, Finition sol - Dalles terrasse, Name: Finition sol - Dalles terrasse; Component 1, Finition sol - Dalles terrasse, Participates in Collision Detection: no; Component 2, Divers - Vide, ThermalConductivity: 0.15; Component 2, Divers - Vide, SpecificHeatCapacity: 1008 J/kg/K; Component 2, Divers - Vide, MassDensity: 1.2 kg/m3; Component 2, Divers - Vide, Embodied Energy: 0 (MJ/kg); Component 2, Divers - Vide, Embodied Carbon: 0 (kgCO₂/kg); Component 2, Divers - Vide, Name: Divers - Vide; Component 2, Divers - Vide, Participates in Collision Detection: no
Name | In | Numéro article | GrossArea (m2) = NetArea (m2)
Dalle_004 | R+3 | 07.2.4.5 | 49.9902
Dalle_004 | R+4 | L07.2.4.5 | 93.7681

# IfcCovering: 7 - FP Isolé 120 mm sous toiture terrasse 176, Dalle_004
In: Etage
Type - PredefinedType: INSULATION
Classification: Isolation (Classification ARCHICAD); Material: Isolation - Laine de verre, Divers - Vide, Finition int - Plaque de plâtre (2)
Pset_CoveringCommon - AcousticRating: Non défini; Material: 7 - FP Isolé 120 mm sous toiture terrasse
Propriétés DCE - Numéro de LOT: LOT 09; Numéro article: L09.2.3.1.2
AC_Pset_RenovationAndPhasing - Renovation Status: Existing
Material Properties - Component 1, Isolation - Laine de verre, ThermalConductivity: 0.038; Component 1, Isolation - Laine de verre, SpecificHeatCapacity: 1030 J/kg/K; Component 1, Isolation - Laine de verre, MassDensity: 14.5 kg/m3; Component 1, Isolation - Laine de verre, Embodied Energy: 26.5 (MJ/kg); Component 1, Isolation - Laine de verre, Embodied Carbon: 1.32 (kgCO₂/kg); Component 1, Isolation - Laine de verre, Name: Isolation - Laine de verre; Component 1, Isolation - Laine de verre, Participates in Collision Detection: no; Component 2, Divers - Vide, ThermalConductivity: 0.15; Component 2, Divers - Vide, SpecificHeatCapacity: 1008 J/kg/K; Component 2, Divers - Vide, MassDensity: 1.2 kg/m3; Component 2, Divers - Vide, Embodied Energy: 0 (MJ/kg); Component 2, Divers - Vide, Embodied Carbon: 0 (kgCO₂/kg); Component 2, Divers - Vide, Name: Divers - Vide; Component 2, Divers - Vide, Participates in Collision Detection: no; Component 3, Finition int - Plaque de plâtre, ThermalConductivity: 0.8; Component 3, Finition int - Plaque de plâtre, SpecificHeatCapacity: 1000 J/kg/K; Component 3, Finition int - Plaque de plâtre, MassDensity: 1600 kg/m3; Component 3, Finition int - Plaque de plâtre, Embodied Energy: 1.45 (MJ/kg); Component 3, Finition int - Plaque de plâtre, Embodied Carbon: 0.22 (kgCO₂/kg); Component 3, Finition int - Plaque de plâtre, Name: Finition int - Plaque de plâtre; Component 3, Finition int - Plaque de plâtre, Participates in Collision Detection: no; Component 3: 2 with these values
BaseQuantities - GrossArea: 76.7284 m2; NetArea: 76.7284 m2

# IfcCovering: 7 - FP Isolé 200 mm sous charpente 276, Dalle_004
In: R+4
Type - PredefinedType: INSULATION
Classification: Isolation (Classification ARCHICAD); Material: Isolation - Laine de verre, Divers - Vide, Finition int - Plaque de plâtre (2)
Pset_CoveringCommon - AcousticRating: Non défini; Material: 7 - FP Isolé 200 mm sous charpente
Propriétés DCE - Numéro de LOT: LOT 09; Numéro article: L09.2.3.1.3
AC_Pset_RenovationAndPhasing - Renovation Status: Existing
Material Properties - Component 1, Isolation - Laine de verre, ThermalConductivity: 0.038; Component 1, Isolation - Laine de verre, SpecificHeatCapacity: 1030 J/kg/K; Component 1, Isolation - Laine de verre, MassDensity: 14.5 kg/m3; Component 1, Isolation - Laine de verre, Embodied Energy: 26.5 (MJ/kg); Component 1, Isolation - Laine de verre, Embodied Carbon: 1.32 (kgCO₂/kg); Component 1, Isolation - Laine de verre, Name: Isolation - Laine de verre; Component 1, Isolation - Laine de verre, Participates in Collision Detection: no; Component 2, Divers - Vide, ThermalConductivity: 0.15; Component 2, Divers - Vide, SpecificHeatCapacity: 1008 J/kg/K; Component 2, Divers - Vide, MassDensity: 1.2 kg/m3; Component 2, Divers - Vide, Embodied Energy: 0 (MJ/kg); Component 2, Divers - Vide, Embodied Carbon: 0 (kgCO₂/kg); Component 2, Divers - Vide, Name: Divers - Vide; Component 2, Divers - Vide, Participates in Collision Detection: no; Component 3, Finition int - Plaque de plâtre, ThermalConductivity: 0.8; Component 3, Finition int - Plaque de plâtre, SpecificHeatCapacity: 1000 J/kg/K; Component 3, Finition int - Plaque de plâtre, MassDensity: 1600 kg/m3; Component 3, Finition int - Plaque de plâtre, Embodied Energy: 1.45 (MJ/kg); Component 3, Finition int - Plaque de plâtre, Embodied Carbon: 0.22 (kgCO₂/kg); Component 3, Finition int - Plaque de plâtre, Name: Finition int - Plaque de plâtre; Component 3, Finition int - Plaque de plâtre, Participates in Collision Detection: no; Component 3: 2 with these values
BaseQuantities - GrossArea: 16.4002 m2; NetArea: 16.4002 m2

# IfcCovering: 7 - FP Isolé 300 mm sous charpente 376, Dalle_004
In: Etage
Type - PredefinedType: CEILING
Classification: Revêtement de plafond (Classification ARCHICAD); Material: Isolation - Laine de verre, Divers - Vide, Finition int - Plaque de plâtre (2)
Pset_CoveringCommon - AcousticRating: Non défini; Material: 7 - FP Isolé 300 mm sous charpente
Propriétés DCE - Numéro de LOT: LOT 09; Numéro article: L09.2.3.1.1
AC_Pset_RenovationAndPhasing - Renovation Status: Existing
Material Properties - Component 1, Isolation - Laine de verre, ThermalConductivity: 0.038; Component 1, Isolation - Laine de verre, SpecificHeatCapacity: 1030 J/kg/K; Component 1, Isolation - Laine de verre, MassDensity: 14.5 kg/m3; Component 1, Isolation - Laine de verre, Embodied Energy: 26.5 (MJ/kg); Component 1, Isolation - Laine de verre, Embodied Carbon: 1.32 (kgCO₂/kg); Component 1, Isolation - Laine de verre, Name: Isolation - Laine de verre; Component 1, Isolation - Laine de verre, Participates in Collision Detection: no; Component 2, Divers - Vide, ThermalConductivity: 0.15; Component 2, Divers - Vide, SpecificHeatCapacity: 1008 J/kg/K; Component 2, Divers - Vide, MassDensity: 1.2 kg/m3; Component 2, Divers - Vide, Embodied Energy: 0 (MJ/kg); Component 2, Divers - Vide, Embodied Carbon: 0 (kgCO₂/kg); Component 2, Divers - Vide, Name: Divers - Vide; Component 2, Divers - Vide, Participates in Collision Detection: no; Component 3, Finition int - Plaque de plâtre, ThermalConductivity: 0.8; Component 3, Finition int - Plaque de plâtre, SpecificHeatCapacity: 1000 J/kg/K; Component 3, Finition int - Plaque de plâtre, MassDensity: 1600 kg/m3; Component 3, Finition int - Plaque de plâtre, Embodied Energy: 1.45 (MJ/kg); Component 3, Finition int - Plaque de plâtre, Embodied Carbon: 0.22 (kgCO₂/kg); Component 3, Finition int - Plaque de plâtre, Name: Finition int - Plaque de plâtre; Component 3, Finition int - Plaque de plâtre, Participates in Collision Detection: no; Component 3: 2 with these values
BaseQuantities - GrossArea: 51.0887 m2; NetArea: 51.0887 m2

# IfcCovering: 7 - Faux-plafond BA13 113 (4)
Type - PredefinedType: CEILING
Classification: Revêtement de plafond (Classification ARCHICAD); Material: Divers - Vide, Finition int - Plaque de plâtre
Pset_CoveringCommon - AcousticRating: Non défini; Material: 7 - Faux-plafond BA13
Propriétés DCE - Numéro de LOT: LOT 09; Numéro article: L09.2.3.2.1
AC_Pset_RenovationAndPhasing - Renovation Status: Existing
Material Properties - Component 1, Divers - Vide, ThermalConductivity: 0.15; Component 1, Divers - Vide, SpecificHeatCapacity: 1008 J/kg/K; Component 1, Divers - Vide, MassDensity: 1.2 kg/m3; Component 1, Divers - Vide, Embodied Energy: 0 (MJ/kg); Component 1, Divers - Vide, Embodied Carbon: 0 (kgCO₂/kg); Component 1, Divers - Vide, Name: Divers - Vide; Component 1, Divers - Vide, Participates in Collision Detection: no; Component 2, Finition int - Plaque de plâtre, ThermalConductivity: 0.8; Component 2, Finition int - Plaque de plâtre, SpecificHeatCapacity: 1000 J/kg/K; Component 2, Finition int - Plaque de plâtre, MassDensity: 1600 kg/m3; Component 2, Finition int - Plaque de plâtre, Embodied Energy: 1.45 (MJ/kg); Component 2, Finition int - Plaque de plâtre, Embodied Carbon: 0.22 (kgCO₂/kg); Component 2, Finition int - Plaque de plâtre, Name: Finition int - Plaque de plâtre; Component 2, Finition int - Plaque de plâtre, Participates in Collision Detection: no
Name | In | GrossArea (m2) | NetArea (m2)
Dalle_004 | Rez-de-chaussée | 31.4801 | 28.6001
Dalle_004 | Rez-de-chaussée | 9.43648 | 6.55648
Dalle_004 | R+2 | 10.7772 | 10.7772
Dalle_004 | R+3 | 18.2188 | 18.2188

# IfcCovering: 7 - Faux-plafond BA13 isolé laine 120mm 133 (2)
In: Rez-de-chaussée
Type - PredefinedType: CEILING
Classification: Revêtement de plafond (Classification ARCHICAD); Material: Isolation - Laine de verre, Finition int - Plaque de plâtre
Pset_CoveringCommon - AcousticRating: Non défini; Material: 7 - Faux-plafond BA13 isolé laine 120mm
Propriétés DCE - Numéro de LOT: LOT 09; Numéro article: L09.2.3.2.2
AC_Pset_RenovationAndPhasing - Renovation Status: Existing
Material Properties - Component 1, Isolation - Laine de verre, ThermalConductivity: 0.038; Component 1, Isolation - Laine de verre, SpecificHeatCapacity: 1030 J/kg/K; Component 1, Isolation - Laine de verre, MassDensity: 14.5 kg/m3; Component 1, Isolation - Laine de verre, Embodied Energy: 26.5 (MJ/kg); Component 1, Isolation - Laine de verre, Embodied Carbon: 1.32 (kgCO₂/kg); Component 1, Isolation - Laine de verre, Name: Isolation - Laine de verre; Component 1, Isolation - Laine de verre, Participates in Collision Detection: no; Component 2, Finition int - Plaque de plâtre, ThermalConductivity: 0.8; Component 2, Finition int - Plaque de plâtre, SpecificHeatCapacity: 1000 J/kg/K; Component 2, Finition int - Plaque de plâtre, MassDensity: 1600 kg/m3; Component 2, Finition int - Plaque de plâtre, Embodied Energy: 1.45 (MJ/kg); Component 2, Finition int - Plaque de plâtre, Embodied Carbon: 0.22 (kgCO₂/kg); Component 2, Finition int - Plaque de plâtre, Name: Finition int - Plaque de plâtre; Component 2, Finition int - Plaque de plâtre, Participates in Collision Detection: no
Name | GrossArea (m2) = NetArea (m2)
Dalle_004 | 16.8583
Dalle_004 | 4.9842

# IfcCovering: 7 - Isolation FYBRASTYROC 150mm sous plancher 165 (2)
In: Rez-de-chaussée
Type - PredefinedType: INSULATION
Classification: Isolation (Classification ARCHICAD); Material: Isolation - Polystyrène extrudé, Finition int - Plaque de plâtre extérieure 13mm
Pset_CoveringCommon - AcousticRating: Non défini; Material: 7 - Isolation FYBRASTYROC 150mm sous plancher
Propriétés DCE - Numéro de LOT: LOT 09; Numéro article: L09.2.3.4.1
AC_Pset_RenovationAndPhasing - Renovation Status: Existing
Material Properties - Component 1, Isolation - Polystyrène extrudé, ThermalConductivity: 0.036; Component 1, Isolation - Polystyrène extrudé, SpecificHeatCapacity: 1400 J/kg/K; Component 1, Isolation - Polystyrène extrudé, MassDensity: 25 kg/m3; Component 1, Isolation - Polystyrène extrudé, Embodied Energy: 86.4 (MJ/kg); Component 1, Isolation - Polystyrène extrudé, Embodied Carbon: 3.43 (kgCO₂/kg); Component 1, Isolation - Polystyrène extrudé, Name: Isolation - Polystyrène extrudé; Component 1, Isolation - Polystyrène extrudé, Participates in Collision Detection: no; Component 2, Finition int - Plaque de plâtre extérieure 13mm, ThermalConductivity: 0.8; Component 2, Finition int - Plaque de plâtre extérieure 13mm, SpecificHeatCapacity: 1000 J/kg/K; Component 2, Finition int - Plaque de plâtre extérieure 13mm, MassDensity: 1600 kg/m3; Component 2, Finition int - Plaque de plâtre extérieure 13mm, Embodied Energy: 1.45 (MJ/kg); Component 2, Finition int - Plaque de plâtre extérieure 13mm, Embodied Carbon: 0.22 (kgCO₂/kg); Component 2, Finition int - Plaque de plâtre extérieure 13mm, Name: Finition int - Plaque de plâtre extérieure 13mm; Component 2, Finition int - Plaque de plâtre extérieure 13mm, Participates in Collision Detection: no
Name | GrossArea (m2) = NetArea (m2)
Dalle_003 | 6.51762
Dalle_003 | 5.34149

# IfcCovering: Bande Podotactile (8)
Type - PredefinedType: FLOORING
Description: Bande podotactile; Classification: Revêtement de sol (Classification ARCHICAD); Material: Plastique - PVC
Pset_CoveringCommon - AcousticRating: Non défini; Material: Hachure solide
Propriétés DCE - Numéro de LOT: LOT 14; Numéro article: L14.2.3.2
AC_Pset_RenovationAndPhasing - Renovation Status: Existing
Material Properties - Plastique - PVC, ThermalConductivity: 0.17; Plastique - PVC, SpecificHeatCapacity: 900 J/kg/K; Plastique - PVC, MassDensity: 1390 kg/m3; Plastique - PVC, Embodied Energy: 77.2 (MJ/kg); Plastique - PVC, Embodied Carbon: 3.1 (kgCO₂/kg); Plastique - PVC, Name: Plastique - PVC; Plastique - PVC, Participates in Collision Detection: no
Name | In
Bande podotactile | Sous-sol
2 x Bande podotactile | Rez-de-chaussée
2 x Bande podotactile | R+1
2 x Bande podotactile | R+2
Bande podotactile | R+3

# IfcCovering: Bandeau de façade composite 80 x 165 (12)
Type - ElementType: MOLDING; PredefinedType: USERDEFINED
Description: Bandeaux de façade; Material: Finition sol - Carrelage
Pset_CoveringCommon - AcousticRating: Non défini; Material: Bandeau de façade composite
Propriétés DCE - Numéro de LOT: LOT 04; LOT 16; Numéro article: L04.2.12.7.2; L16.2.2.2
AC_Pset_RenovationAndPhasing - Renovation Status: Existing
Material Properties - Finition sol - Carrelage, ThermalConductivity: 0.58; Finition sol - Carrelage, SpecificHeatCapacity: 840 J/kg/K; Finition sol - Carrelage, MassDensity: 1500 kg/m3; Finition sol - Carrelage, Embodied Energy: 3 (MJ/kg); Finition sol - Carrelage, Embodied Carbon: 0.24 (kgCO₂/kg); Finition sol - Carrelage, Name: Finition sol - Carrelage; Finition sol - Carrelage, Participates in Collision Detection: no
Name | In | Classification | GrossArea (m2) | NetArea (m2)
Bandeaux de façade préfa composite | R+3 | Moulure (Classification ARCHICAD); Accessoire distinct (Classification ARCHICAD) | 0.110478 | 0.110478
Bandeaux de façade préfa composite | R+2 | Moulure (Classification ARCHICAD); Accessoire distinct (Classification ARCHICAD) | 0.0716647 | 0.0736647
Bandeaux de façade préfa composite | R+2 | Moulure (Classification ARCHICAD); Accessoire distinct (Classification ARCHICAD) | 0.620274 | 0.618258
Bandeaux de façade préfa composite | R+3 | Moulure (Classification ARCHICAD) | 0.33208 | 0.32848
Bandeaux de façade préfa composite | R+3 | Moulure (Classification ARCHICAD) | 0.0684647 | 0.0716647
Bandeaux de façade préfa composite | R+3 | Moulure (Classification ARCHICAD); Elément de construction (Classification ARCHICAD) | 0.0716647 | 0.0684485
Bandeaux de façade préfa composite | R+3 | Moulure (Classification ARCHICAD) | 0.0794611 | 0.0774449
Bandeaux de façade préfa composite | R+3 | Moulure (Classification ARCHICAD); Accessoire distinct (Classification ARCHICAD) | 0.268635 | 0.272567
Bandeaux de façade préfa composite | R+3 | Moulure (Classification ARCHICAD) | 0.329868 | 0.333068
Bandeaux de façade préfa composite | R+4 | Moulure (Classification ARCHICAD); Accessoire distinct (Classification ARCHICAD) | 0.892421 | 0.895621
Bandeaux de façade préfa composite | R+4 | Moulure (Classification ARCHICAD); Accessoire distinct (Classification ARCHICAD) | 0.0815998 | 0.0743837
Bandeaux de façade préfa composite | R+3 | Moulure (Classification ARCHICAD); Accessoire distinct (Classification ARCHICAD) | 0.250542 | 0.249342

# IfcCovering: Béton 120, Dalle_025
In: Rez-de-chaussée
Type - PredefinedType: CEILING
Classification: Revêtement de plafond (Classification ARCHICAD); Material: Béton
Pset_CoveringCommon - AcousticRating: Non défini; Material: Béton
Propriétés DCE - Numéro de LOT: LOT 09; Numéro article: L09.2.3.2.3
AC_Pset_RenovationAndPhasing - Renovation Status: Existing
Material Properties - Béton, ThermalConductivity: 2.3; Béton, SpecificHeatCapacity: 1000 J/kg/K; Béton, MassDensity: 2300 kg/m3; Béton, Embodied Energy: 1.92 (MJ/kg); Béton, Embodied Carbon: 0.198 (kgCO₂/kg); Béton, Name: Béton; Béton, Participates in Collision Detection: yes
BaseQuantities - GrossArea: 0.6895 m2; NetArea: 0.6895 m2

# IfcCovering: Béton 150, Dalle_004
In: Rez-de-chaussée
Type - PredefinedType: CEILING
Classification: Revêtement de plafond (Classification ARCHICAD); Material: Béton
Pset_CoveringCommon - AcousticRating: Non défini; Material: Béton
Propriétés DCE - Numéro de LOT: LOT 04; Numéro article: L04.2.8.6.4.2
AC_Pset_RenovationAndPhasing - Renovation Status: Existing
Material Properties - Béton, ThermalConductivity: 2.3; Béton, SpecificHeatCapacity: 1000 J/kg/K; Béton, MassDensity: 2300 kg/m3; Béton, Embodied Energy: 1.92 (MJ/kg); Béton, Embodied Carbon: 0.198 (kgCO₂/kg); Béton, Name: Béton; Béton, Participates in Collision Detection: yes
BaseQuantities - GrossArea: 7.2954 m2; NetArea: 7.2954 m2

# IfcCovering: Béton 150, Dalle_005
In: R+1
Type - PredefinedType: INSULATION
Classification: Isolation (Classification ARCHICAD); Material: Béton
Pset_CoveringCommon - AcousticRating: Non défini; Material: Béton
Propriétés DCE - Numéro de LOT: LOT 04; Numéro article: L04.2.12.6
AC_Pset_RenovationAndPhasing - Renovation Status: Existing
Material Properties - Béton, ThermalConductivity: 2.3; Béton, SpecificHeatCapacity: 1000 J/kg/K; Béton, MassDensity: 2300 kg/m3; Béton, Embodied Energy: 1.92 (MJ/kg); Béton, Embodied Carbon: 0.198 (kgCO₂/kg); Béton, Name: Béton; Béton, Participates in Collision Detection: yes
BaseQuantities - GrossArea: 6.3504 m2; NetArea: 6.3504 m2

# IfcCovering: Corniche lumineuse 50 x 180 (8)
In: Rez-de-chaussée
Type - ElementType: MOLDING; PredefinedType: USERDEFINED
Classification: Moulure (Classification ARCHICAD); Material: Finition sol - Carrelage
Pset_CoveringCommon - AcousticRating: Non défini; Material: Corniche lumineuse
Propriétés DCE - Numéro de LOT: LOT 09; Numéro article: L09.2.3.2.5
AC_Pset_RenovationAndPhasing - Renovation Status: Existing
Material Properties - Finition sol - Carrelage, ThermalConductivity: 0.58; Finition sol - Carrelage, SpecificHeatCapacity: 840 J/kg/K; Finition sol - Carrelage, MassDensity: 1500 kg/m3; Finition sol - Carrelage, Embodied Energy: 3 (MJ/kg); Finition sol - Carrelage, Embodied Carbon: 0.24 (kgCO₂/kg); Finition sol - Carrelage, Name: Finition sol - Carrelage; Finition sol - Carrelage, Participates in Collision Detection: no
Name | GrossArea (m2) | NetArea (m2)
M_Ext-014 | 0.116444 | 0
M_Ext-012 | 0.0900607 | 0.000516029
M_Ext-009 | 0.0677503 | 0.000516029
M_Ext-008 | 0.281968 | 0.00217822
M_Ext-009 | 0.118434 | 0.00108911
M_Ext-010 | 0.0880704 | 0.00222072
M_Ext-013 | 0.12925 | 0.00222072
M_Ext-011 | 0.0849677 | 0.00108911

# IfcCovering: Cylindre 23, MOB-004
In: Rez-de-chaussée
Type - ElementType: MOLDING; PredefinedType: USERDEFINED
Classification: Moulure (Classification ARCHICAD)
Pset_CoveringCommon - AcousticRating: Non défini; Material: Hachure solide
Propriétés DCE - Numéro de LOT: LOT 09; Numéro article: L09.2.3.2.4
AC_Pset_RenovationAndPhasing - Renovation Status: Existing

# IfcCovering: Evacuation EP terrasse (40)
Type - PredefinedType: FLOORING
Classification: Revêtement de sol (Classification ARCHICAD); Material: Volume - Etude
Pset_CoveringCommon - AcousticRating: Non défini; Material: Hachure solide
Propriétés DCE - Numéro de LOT: LOT 07; Numéro article: L07.2.6
AC_Pset_RenovationAndPhasing - Renovation Status: Existing
Material Properties - Volume - Etude, ThermalConductivity: 0; Volume - Etude, SpecificHeatCapacity: 0 J/kg/K; Volume - Etude, MassDensity: 0 kg/m3; Volume - Etude, Embodied Energy: 0 (MJ/kg); Volume - Etude, Embodied Carbon: 0 (kgCO₂/kg); Volume - Etude, Name: Volume - Etude; Volume - Etude, Participates in Collision Detection: yes
Name | In
18 x MOB-004 | Rez-de-chaussée
2 x MOB-004 | R+1
4 x MOB-004 | R+2
6 x MOB-004 | R+3
7 x MOB-004 | R+4
3 x MOB-004 | Etage

# IfcCovering: Finition ext - Crépis 15, M_Ext-016
In: Rez-de-chaussée
Type - PredefinedType: INSULATION
Classification: Isolation (Classification ARCHICAD); Material: Finition ext - Crépis
Pset_CoveringCommon - AcousticRating: Non défini; Material: Finition ext - Crépis
Propriétés DCE - Numéro de LOT: LOT 04; LOT 16; Numéro article: L16.2.1
AC_Pset_RenovationAndPhasing - Renovation Status: Existing
Material Properties - Finition ext - Crépis, ThermalConductivity: 0.8; Finition ext - Crépis, SpecificHeatCapacity: 1000 J/kg/K; Finition ext - Crépis, MassDensity: 1600 kg/m3; Finition ext - Crépis, Embodied Energy: 1.4 (MJ/kg); Finition ext - Crépis, Embodied Carbon: 0.09 (kgCO₂/kg); Finition ext - Crépis, Name: Finition ext - Crépis; Finition ext - Crépis, Participates in Collision Detection: no
BaseQuantities - GrossArea: 0.125049 m2; NetArea: 0.121974 m2

# IfcCovering: Finition int - Plaque de plâtre 200 (9)
Type - PredefinedType: CEILING
Material: Finition int - Plaque de plâtre
Pset_CoveringCommon - AcousticRating: Non défini; Material: Finition int - Plaque de plâtre
Propriétés DCE - Numéro de LOT: LOT 09; Numéro article: L09.2.3.3.1
AC_Pset_RenovationAndPhasing - Renovation Status: Existing
Material Properties - Finition int - Plaque de plâtre, ThermalConductivity: 0.8; Finition int - Plaque de plâtre, SpecificHeatCapacity: 1000 J/kg/K; Finition int - Plaque de plâtre, MassDensity: 1600 kg/m3; Finition int - Plaque de plâtre, Embodied Energy: 1.45 (MJ/kg); Finition int - Plaque de plâtre, Embodied Carbon: 0.22 (kgCO₂/kg); Finition int - Plaque de plâtre, Name: Finition int - Plaque de plâtre; Finition int - Plaque de plâtre, Participates in Collision Detection: no
Name | In | Classification | GrossArea (m2) = NetArea (m2)
Dalle_003 | R+1 | Dalle (Classification ARCHICAD); Revêtement de plafond (Classification ARCHICAD) | 0.641
Dalle_003 | R+2 | Dalle (Classification ARCHICAD); Revêtement de plafond (Classification ARCHICAD) | 0.641
Dalle_003 | Rez-de-chaussée | Revêtement de plafond (Classification ARCHICAD) | 0.641
Dalle_003 | Rez-de-chaussée | Revêtement de plafond (Classification ARCHICAD) | 7.49084
Dalle_003 | Rez-de-chaussée | Revêtement de plafond (Classification ARCHICAD) | 3.44808
Dalle_003 | Rez-de-chaussée | Revêtement de plafond (Classification ARCHICAD) | 0.805051
Dalle_003 | R+1 | Revêtement de plafond (Classification ARCHICAD) | 7.49082
Dalle_003 | R+1 | Revêtement de plafond (Classification ARCHICAD) | 0.805051
Dalle_003 | R+2 | Revêtement de plafond (Classification ARCHICAD) | 0.653051

# IfcCovering: Finition int - Plaque de plâtre 250 (2)
In: R+3
Type - PredefinedType: CEILING
Classification: Revêtement de plafond (Classification ARCHICAD); Material: Finition int - Plaque de plâtre
Pset_CoveringCommon - AcousticRating: Non défini; Material: Finition int - Plaque de plâtre
Propriétés DCE - Numéro de LOT: LOT 09; Numéro article: L09.2.3.3.1
AC_Pset_RenovationAndPhasing - Renovation Status: Existing
Material Properties - Finition int - Plaque de plâtre, ThermalConductivity: 0.8; Finition int - Plaque de plâtre, SpecificHeatCapacity: 1000 J/kg/K; Finition int - Plaque de plâtre, MassDensity: 1600 kg/m3; Finition int - Plaque de plâtre, Embodied Energy: 1.45 (MJ/kg); Finition int - Plaque de plâtre, Embodied Carbon: 0.22 (kgCO₂/kg); Finition int - Plaque de plâtre, Name: Finition int - Plaque de plâtre; Finition int - Plaque de plâtre, Participates in Collision Detection: no
Name | GrossArea (m2) = NetArea (m2)
Dalle_003 | 2.89715
Dalle_003 | 2.74552

# IfcCovering: Finition int - Plaque de plâtre 300 (25)
Type - PredefinedType: CEILING
Material: Finition int - Plaque de plâtre
Pset_CoveringCommon - AcousticRating: Non défini; Material: Finition int - Plaque de plâtre
Propriétés DCE - Numéro de LOT: LOT 09; Numéro article: L09.2.3.3.1
AC_Pset_RenovationAndPhasing - Renovation Status: Existing
Material Properties - Finition int - Plaque de plâtre, ThermalConductivity: 0.8; Finition int - Plaque de plâtre, SpecificHeatCapacity: 1000 J/kg/K; Finition int - Plaque de plâtre, MassDensity: 1600 kg/m3; Finition int - Plaque de plâtre, Embodied Energy: 1.45 (MJ/kg); Finition int - Plaque de plâtre, Embodied Carbon: 0.22 (kgCO₂/kg); Finition int - Plaque de plâtre, Name: Finition int - Plaque de plâtre; Finition int - Plaque de plâtre, Participates in Collision Detection: no
Name | In | Classification | GrossArea (m2) = NetArea (m2)
Dalle_003 | R+2 | Dalle (Classification ARCHICAD); Revêtement de plafond (Classification ARCHICAD) | 0.718
Dalle_004 | Rez-de-chaussée | Revêtement de plafond (Classification ARCHICAD) | 2.65481
Dalle_003 | Rez-de-chaussée | Revêtement de plafond (Classification ARCHICAD) | 0.63
Dalle_004 | Rez-de-chaussée | Revêtement de plafond (Classification ARCHICAD) | 4.47759
Dalle_003 | Rez-de-chaussée | Revêtement de plafond (Classification ARCHICAD) | 3.58877
Dalle_003 | Rez-de-chaussée | Revêtement de plafond (Classification ARCHICAD) | 0.28435
Dalle_004 | R+1 | Revêtement de plafond (Classification ARCHICAD) | 1.20444
Dalle_004 | R+1 | Revêtement de plafond (Classification ARCHICAD) | 1.04278
Dalle_004 | R+1 | Revêtement de plafond (Classification ARCHICAD) | 2.67024
Dalle_003 | R+1 | Revêtement de plafond (Classification ARCHICAD) | 0.63
Dalle_004 | R+1 | Revêtement de plafond (Classification ARCHICAD) | 3.7902
Dalle_004 | R+1 | Revêtement de plafond (Classification ARCHICAD) | 7.16323
Dalle_004 | R+1 | Revêtement de plafond (Classification ARCHICAD) | 1.16618
Dalle_003 | R+1 | Revêtement de plafond (Classification ARCHICAD) | 3.58877
Dalle_003 | R+1 | Revêtement de plafond (Classification ARCHICAD) | 0.28435
Dalle_003 | R+2 | Revêtement de plafond (Classification ARCHICAD) | 3.58877
Dalle_003 | R+2 | Revêtement de plafond (Classification ARCHICAD) | 1.42245
Dalle_004 | R+2 | Revêtement de plafond (Classification ARCHICAD) | 5.12816
Dalle_004 | R+2 | Revêtement de plafond (Classification ARCHICAD) | 4.45419
Dalle_003 | R+2 | Revêtement de plafond (Classification ARCHICAD) | 1.17989
Dalle_003 | R+2 | Revêtement de plafond (Classification ARCHICAD) | 1.20652
Dalle_003 | R+2 | Revêtement de plafond (Classification ARCHICAD) | 1.51085
Dalle_003 | R+2 | Revêtement de plafond (Classification ARCHICAD) | 0.28435
Dalle_003 | R+3 | Revêtement de plafond (Classification ARCHICAD) | 0.28435
Dalle_003 | R+3 | Revêtement de plafond (Classification ARCHICAD) | 1.65535

# IfcCovering: Finition int - Plaque de plâtre ACOUSTIQUE type GYPTONE 133, Dalle_004
In: Rez-de-chaussée
Type - PredefinedType: CEILING
Classification: Revêtement de plafond (Classification ARCHICAD); Material: Finition int - Plaque de plâtre ACOUSTIQUE type GYPTONE
Pset_CoveringCommon - AcousticRating: Non défini; Material: Finition int - Plaque de plâtre ACOUSTIQUE type GYPTONE
Propriétés DCE - Numéro article: L09.2.3.2.3
AC_Pset_RenovationAndPhasing - Renovation Status: Existing
Material Properties - Finition int - Plaque de plâtre ACOUSTIQUE type GYPTONE, ThermalConductivity: 0.8; Finition int - Plaque de plâtre ACOUSTIQUE type GYPTONE, SpecificHeatCapacity: 1000 J/kg/K; Finition int - Plaque de plâtre ACOUSTIQUE type GYPTONE, MassDensity: 1600 kg/m3; Finition int - Plaque de plâtre ACOUSTIQUE type GYPTONE, Embodied Energy: 1.45 (MJ/kg); Finition int - Plaque de plâtre ACOUSTIQUE type GYPTONE, Embodied Carbon: 0.22 (kgCO₂/kg); Finition int - Plaque de plâtre ACOUSTIQUE type GYPTONE, Name: Finition int - Plaque de plâtre ACOUSTIQUE type GYPTONE; Finition int - Plaque de plâtre ACOUSTIQUE type GYPTONE, Participates in Collision Detection: no
BaseQuantities - GrossArea: 1.44 m2; NetArea: 1.44 m2

# IfcCovering: Finition int - Plaque de plâtre ACOUSTIQUE type GYPTONE 15 (16)
In: Rez-de-chaussée
Type - PredefinedType: CEILING
Classification: Revêtement de plafond (Classification ARCHICAD); Material: Finition int - Plaque de plâtre ACOUSTIQUE type GYPTONE
Pset_CoveringCommon - AcousticRating: Non défini; Material: Finition int - Plaque de plâtre ACOUSTIQUE type GYPTONE
Propriétés DCE - Numéro de LOT: LOT 09; Numéro article: L09.2.3.2.3
AC_Pset_RenovationAndPhasing - Renovation Status: Existing
Material Properties - Finition int - Plaque de plâtre ACOUSTIQUE type GYPTONE, ThermalConductivity: 0.8; Finition int - Plaque de plâtre ACOUSTIQUE type GYPTONE, SpecificHeatCapacity: 1000 J/kg/K; Finition int - Plaque de plâtre ACOUSTIQUE type GYPTONE, MassDensity: 1600 kg/m3; Finition int - Plaque de plâtre ACOUSTIQUE type GYPTONE, Embodied Energy: 1.45 (MJ/kg); Finition int - Plaque de plâtre ACOUSTIQUE type GYPTONE, Embodied Carbon: 0.22 (kgCO₂/kg); Finition int - Plaque de plâtre ACOUSTIQUE type GYPTONE, Name: Finition int - Plaque de plâtre ACOUSTIQUE type GYPTONE; Finition int - Plaque de plâtre ACOUSTIQUE type GYPTONE, Participates in Collision Detection: no
Name | GrossArea (m2) = NetArea (m2)
15 x Dalle_004 | 1.44
Dalle_004 | 2.88

# IfcCovering: Isolation - FLOCAGE 120 (21)
In: Sous-sol
Type - PredefinedType: CEILING
Description: Flocage; Classification: Revêtement de plafond (Classification ARCHICAD); Material: Isolation - FLOCAGE
Pset_CoveringCommon - AcousticRating: Non défini; Material: Isolation - FLOCAGE
Propriétés DCE - Numéro de LOT: LOT 04; Numéro article: L04.2.11.1
AC_Pset_RenovationAndPhasing - Renovation Status: Existing
Material Properties - Isolation - FLOCAGE, ThermalConductivity: 0.052; Isolation - FLOCAGE, SpecificHeatCapacity: 1350 J/kg/K; Isolation - FLOCAGE, MassDensity: 300 kg/m3; Isolation - FLOCAGE, Embodied Energy: 12.4 (MJ/kg); Isolation - FLOCAGE, Embodied Carbon: 0.09 (kgCO₂/kg); Isolation - FLOCAGE, Name: Isolation - FLOCAGE; Isolation - FLOCAGE, Participates in Collision Detection: no
Name | GrossArea (m2) = NetArea (m2)
Flocage thermique 120mm | 33.3173
Flocage thermique 120mm | 58.4941
Flocage thermique 120mm | 36.2078
Flocage thermique 120mm | 29.0784
Flocage thermique 120mm | 3.78679
Flocage thermique 120mm | 35.7283
Flocage thermique 120mm | 29.8442
Flocage thermique 120mm | 46.3031
Flocage thermique 120mm | 21.0808
Flocage thermique 120mm | 18.434
Flocage thermique 120mm | 40.2184
Flocage thermique 120mm | 17.2121
Flocage thermique 120mm | 6.13854
Flocage thermique 120mm | 6.87828
Flocage thermique 120mm | 42.3922
Flocage thermique 120mm | 6.30553
Flocage thermique 120mm | 39.5715
Flocage thermique 120mm | 15.9934
Flocage thermique 120mm | 24.6822
Flocage thermique 120mm | 61.6148
Flocage thermique 120mm | 8.07361

# IfcCovering: Panneau drainage 40 (5)
Type - PredefinedType: INSULATION
Classification: Isolation (Classification ARCHICAD); Material: Panneau drainage
Pset_CoveringCommon - AcousticRating: Non défini; Material: Panneau drainage
Propriétés DCE - Numéro de LOT: LOT 07; Numéro article: L07.2.7.12
AC_Pset_RenovationAndPhasing - Renovation Status: Existing
Material Properties - Panneau drainage, ThermalConductivity: 0.17; Panneau drainage, SpecificHeatCapacity: 900 J/kg/K; Panneau drainage, MassDensity: 1390 kg/m3; Panneau drainage, Embodied Energy: 77.2 (MJ/kg); Panneau drainage, Embodied Carbon: 3.1 (kgCO₂/kg); Panneau drainage, Name: Panneau drainage; Panneau drainage, Participates in Collision Detection: no
Name | In | GrossArea (m2) = NetArea (m2)
Dalle_004 | Rez-de-chaussée | 275.622
Dalle_004 | Rez-de-chaussée | 6.17229
Dalle_004 | Rez-de-chaussée | 17.8319
Dalle_004 | R+3 | 20.9845
Dalle_004 | R+4 | 7.99077

# IfcCovering: Tapis 23, MOB-002
In: Rez-de-chaussée
Type - PredefinedType: FLOORING
Classification: Revêtement de sol (Classification ARCHICAD)
Pset_CoveringCommon - AcousticRating: Non défini; Material: Hachure solide
Propriétés DCE - Numéro de LOT: LOT 13; Numéro article: L13.1.5.2-L13.1.5.3
AC_Pset_RenovationAndPhasing - Renovation Status: Existing

# IfcDistributionChamberElement: Finition int - Plaque de plâtre 300 (3)
Type - PredefinedType: FORMEDDUCT
Classification: Conduit (Classification ARCHICAD); Material: Finition int - Plaque de plâtre
Propriétés DCE - Numéro de LOT: LOT 09; Numéro article: L09.2.5.1.1
AC_Pset_RenovationAndPhasing - Renovation Status: Existing
Material Properties - Finition int - Plaque de plâtre, ThermalConductivity: 0.8; Finition int - Plaque de plâtre, SpecificHeatCapacity: 1000 J/kg/K; Finition int - Plaque de plâtre, MassDensity: 1600 kg/m3; Finition int - Plaque de plâtre, Embodied Energy: 1.45 (MJ/kg); Finition int - Plaque de plâtre, Embodied Carbon: 0.22 (kgCO₂/kg); Finition int - Plaque de plâtre, Name: Finition int - Plaque de plâtre; Finition int - Plaque de plâtre, Participates in Collision Detection: no
Name | In
2 x Dalle_004 | Sous-sol
Dalle_004 | Rez-de-chaussée

# IfcDistributionChamberElement: Finition int - Plaque type PROMAT 5cm 300 (3)
In: Sous-sol
Type - PredefinedType: FORMEDDUCT
Classification: Conduit (Classification ARCHICAD); Material: Finition int - Plaque type PROMAT 5cm
Propriétés DCE - Numéro de LOT: LOT 09; Numéro article: L09.2.5.1.1
AC_Pset_RenovationAndPhasing - Renovation Status: Existing
Material Properties - Finition int - Plaque type PROMAT 5cm, ThermalConductivity: 0.18; Finition int - Plaque type PROMAT 5cm, SpecificHeatCapacity: 1000 J/kg/K; Finition int - Plaque type PROMAT 5cm, MassDensity: 600 kg/m3; Finition int - Plaque type PROMAT 5cm, Embodied Energy: 8 (MJ/kg); Finition int - Plaque type PROMAT 5cm, Embodied Carbon: 1.2 (kgCO₂/kg); Finition int - Plaque type PROMAT 5cm, Name: Finition int - Plaque type PROMAT 5cm; Finition int - Plaque type PROMAT 5cm, Participates in Collision Detection: no

# IfcDistributionElement: Echelle crinoline 23 (2)
In: R+4
Description: Echelle à crinoline; Classification: Elément de distribution (Classification ARCHICAD)
Propriétés DCE - Numéro de LOT: LOT 17; Numéro article: L17.2.7.1
AC_Pset_RenovationAndPhasing - Renovation Status: Existing

# IfcDoor: Porte garage au-dessus tête 23, Porte acier motorisée 450x210
In: Sous-sol
Type - OperationType: ROLLINGUP; ParameterTakesPrecedence: no; Sizeable: no
Description: Porte de garage; OverallHeight: 2.1 m; OverallWidth: 4.5 m; Classification: Porte (Classification ARCHICAD)
Pset_DoorCommon - ThermalTransmittance: 0; GlazingAreaFraction: 1.01191
Propriétés PORTES - Localisation: Porte de garage; Dimension passage: ×
Propriétés DCE - Numéro de LOT: LOT 17; Numéro article: L17.2.8.1
AC_Pset_RenovationAndPhasing - Renovation Status: Existing
BaseQuantities - Height: 2.1 m; Width: 4.5 m; Perimeter: 13.2 m; Area: 9.45 m2; Volume: 0.344259 m3; Depth: 0.215 m; NetVolume: 0.344259 m3

# IfcDoor: Porte int générique 2019 (14)
Type - OperationType: DOUBLE_DOOR_SINGLE_SWING; ParameterTakesPrecedence: no; Sizeable: no
OverallHeight: 2.04 m; Classification: Porte (Classification ARCHICAD)
Pset_DoorCommon - ThermalTransmittance: 0
AC_Pset_RenovationAndPhasing - Renovation Status: Existing
BaseQuantities - Height: 2.08 m
Name | In | Description | OverallWidth (m) | Localisation | Dimension passage | Numéro de LOT | Numéro article | Width (m) | Perimeter (m) | Area (m2) | Volume (m3) = NetVolume (m3) | Depth (m)
3 x Porte 120x204 bois alvéolaire | Rez-de-chaussée | Porte intérieure logement | 1.2 | Distribution Logements | 120x204 | LOT 12; LOT 15; LOT09 | L12.2.1.2.2; L15.2.1.3.1; L09.2.2.2.1 | 1.28 | 6.72 | 2.6624 | 0.0635616 | 0.074
Porte métal 2V 160x204 | Rez-de-chaussée | Porte entrée du hall | 1.6 | Porte de Hall extérieure | × | LOT 17 | L17.2.4.2.1 | 1.68 | 7.52 | 3.4944 | 0.113361 | 0.225
Porte métal 2V 160x204 | Rez-de-chaussée | Porte entrée du hall | 1.6 | Porte de Hall extérieure | × | LOT 17 | L17.2.4.2.2 | 1.68 | 7.52 | 3.4944 | 0.107601 | 0.2
3 x Porte 120x204 bois alvéolaire | R+1 | Porte intérieure logement | 1.2 | Distribution Logements | 120x204 | LOT 12; LOT 15; LOT09 | L12.2.1.2.2; L15.2.1.3.1; L09.2.2.2.1 | 1.28 | 6.72 | 2.6624 | 0.0635616 | 0.074
Porte 120x204 bois alvéolaire | R+1 | Porte intérieure logement | 1.2 | Distribution Logements | 120x204 | LOT 12-LOT 15-LOT09 | L12.1.1.2-L12.1.1.2.2-L15.1.1.3.1-L09.2.2.2.1 | 1.28 | 6.72 | 2.6624 | 0.0635616 | 0.074
3 x Porte 120x204 bois alvéolaire | R+2 | Porte intérieure logement | 1.2 | Distribution Logements | 120x204 | LOT 12; LOT 15; LOT09 | L12.2.1.2.2; L15.2.1.3.1; L09.2.2.2.1 | 1.28 | 6.72 | 2.6624 | 0.0635616 | 0.074
Por-002 | R+2 |  | 1.2 | Distribution Logements | 120x204 | LOT 12; LOT 15; LOT09 | L12.2.1.2.2; L15.2.1.3.1; L09.2.2.2.1 | 1.28 | 6.72 | 2.6624 | 0.0635616 | 0.074
Porte 120x204 bois alvéolaire | R+3 | Porte intérieure logement | 1.2 | Distribution Logements | 120x204 | LOT 12; LOT 15; LOT09 | L12.2.1.2.2; L15.2.1.3.1; L09.2.2.2.1 | 1.28 | 6.72 | 2.6624 | 0.0635616 | 0.074

# IfcDoor: Porte int générique 2019 (90)
Type - OperationType: SINGLE_SWING_LEFT; ParameterTakesPrecedence: no; Sizeable: no
OverallHeight: 2.04 m; Classification: Porte (Classification ARCHICAD)
Pset_DoorCommon - ThermalTransmittance: 0
AC_Pset_RenovationAndPhasing - Renovation Status: Existing
Name | In | Description | OverallWidth (m) | Localisation | Dimension passage | Numéro de LOT | Numéro article | Height (m) | Width (m) | Perimeter (m) | Area (m2) | Volume (m3) = NetVolume (m3) | Depth (m)
10 x Porte 83x204 bois bâti métal | Sous-sol | Porte de cave | 0.83 | Portes de caves | × | LOT 04; LOT 12 | L04.2.19.1; L12.2.1.1; L12.2.2.5.1; L15.2.1.3.2; L15.2.2.5.3 | 2.085 | 0.92 | 6.01 | 1.9182 | 0.070692 | 0.1 | Pset_DoorCommon - IsExternal: no
Porte 93x204 bois CF | Sous-sol | Porte cage d'escalier | 0.93 | Parties Communes Escaliers | × | LOT 04; LOT 12; LOT 15 | L04.2.20.1; L12.2.1.1; L12.2.2.5.1; L15.2.1.3.2; L15.2.2.5.3 | 2.085 | 1.02 | 6.21 | 2.1267 | 0.078912 | 0.2 | Pset_DoorCommon - IsExternal: no
Porte 93x204 bois CF | Sous-sol | Porte de sas | 0.93 | Parties Communes sas | × | LOT 04; LOT 12; LOT 15 | L04.2.20.1; L12.2.1.1; L12.2.2.5.1; L15.2.1.3.2; L15.2.2.5.3 | 2.085 | 1.02 | 6.21 | 2.1267 | 0.078912 | 0.2 | Pset_DoorCommon - IsExternal: no
Porte acier 1V 93x204 | Sous-sol | Porte acier extérieure | 0.93 | Porte métal extérieure 1V | × | L17 | L17.2.4.1.2 | 2.085 | 1.02 | 6.21 | 2.1267 | 0.078912 | 0.2
Porte acier 1V 93x204 | Sous-sol | Porte acier extérieure | 0.93 | Porte métal extérieure 1V | × | L17 | L17.2.4.1.2 | 2.085 | 1.02 | 6.21 | 2.1267 | 0.078912 | 0.215
Porte 93x204 bois CF | Sous-sol | Porte local commun | 0.93 | Parties Communes Locaux Communs | × | LOT 04; LOT 12; LOT 15 | L04.2.20.1; L12.2.1.1; L12.2.2.5.1; L15.2.1.3.2; L15.2.2.5.3 | 2.085 | 1.02 | 6.21 | 2.1267 | 0.078912 | 0.2 | Pset_DoorCommon - IsExternal: no
Porte 93x204 bois CF | Rez-de-chaussée | Porte de recoupement | 0.93 | Parties Communes Recoupement | × | LOT 04; LOT 12; LOT 15 | L04.2.20.1; L12.2.1.1; L12.2.2.5.1; L15.2.1.3.2; L15.2.2.5.3 | 2.085 | 1.02 | 6.21 | 2.1267 | 0.123678 | 0.2 | Pset_DoorCommon - IsExternal: no
14 x Porte 83x204 bois alvéolaire | Rez-de-chaussée | Porte intérieure logement | 0.83 | Distribution Logements | 83x204 | LOT 12; LOT 15; LOT 09 | L12.2.1.2.2; L15.2.1.3.1; L09.2.2.2.1 | 2.08 | 0.91 | 5.98 | 1.8928 | 0.0894884 | 0.074
4 x Porte 93x204 bois blindée | Rez-de-chaussée | Porte palière | 0.93 | Portes palières | 93x204 | LOT 04; LOT 12; LOT 15 | L04.2.20.1; L12.2.1.1; L12.2.2.5.1; L15.2.1.3.2; L15.2.2.5.3 | 2.085 | 1.02 | 6.21 | 2.1267 | 0.123678 | 0.2 | Pset_DoorCommon - IsExternal: no
Porte 93x204 bois CF | Rez-de-chaussée | Porte cage d'escalier | 0.93 | Parties Communes Escaliers | × | LOT 04; LOT 12; LOT 15 | L04.2.20.1; L12.2.1.1; L12.2.2.5.1; L15.2.1.3.2; L15.2.2.5.3 | 2.085 | 1.02 | 6.21 | 2.1267 | 0.078912 | 0.22
Porte 93x204 bois CF | Rez-de-chaussée | Porte local commun | 0.93 | Parties Communes Locaux Communs | × | LOT 04; LOT 12; LOT 15 | L04.2.20.1; L12.2.1.1; L12.2.2.5.1; L15.2.1.3.2; L15.2.2.5.3 | 2.085 | 1.02 | 6.21 | 2.1267 | 0.078912 | 0.21
Porte 93x204 bois CF | Rez-de-chaussée | Porte cage d'escalier | 0.93 | Parties Communes Escaliers | 93x204 | LOT 04; LOT 12; LOT 15 | L04.2.20.1; L12.2.1.1; L12.2.2.5.1; L15.2.1.3.2; L15.2.2.5.3 | 2.085 | 1.02 | 6.21 | 2.1267 | 0.123678 | 0.22 | Pset_DoorCommon - IsExternal: no
4 x Porte 93x204 bois blindée | R+1 | Porte palière | 0.93 | Portes palières | 93x204 | LOT 04; LOT 12; LOT 15 | L04.2.20.1; L12.2.1.1; L12.2.2.5.1; L15.2.1.3.2; L15.2.2.5.3 | 2.085 | 1.02 | 6.21 | 2.1267 | 0.123678 | 0.2 | Pset_DoorCommon - IsExternal: no
Porte 93x204 bois CF | R+1 | Porte cage d'escalier | 0.93 | Parties Communes Escaliers | 93x204 | LOT 04; LOT 12; LOT 15 | L04.2.20.1; L12.2.1.1; L12.2.2.5.1; L15.2.1.3.2; L15.2.2.5.3 | 2.085 | 1.02 | 6.21 | 2.1267 | 0.123678 | 0.22 | Pset_DoorCommon - IsExternal: no
7 x Porte 83x204 bois alvéolaire | R+1 | Porte intérieure logement | 0.83 | Distribution Logements | 83x204 | LOT 12; LOT 15; LOT 09 | L12.2.1.2.2; L15.2.1.3.1; L09.2.2.2.1 | 2.08 | 0.91 | 5.98 | 1.8928 | 0.0894884 | 0.074
Porte 93x204 bois CF | R+1 | Porte de recoupement | 0.93 | Parties Communes Recoupement | × | LOT 04; LOT 12; LOT 15 | L04.2.20.1; L12.2.1.1; L12.2.2.5.1; L15.2.1.3.2; L15.2.2.5.3 | 2.085 | 1.02 | 6.21 | 2.1267 | 0.123678 | 0.2 | Pset_DoorCommon - IsExternal: no
6 x Porte 83x204 bois alvéolaire | R+1 | Porte intérieure logement | 0.83 | Distribution Logements | 83x204 | LOT 12-LOT 15-LOT09 | L12.1.1.2-L12.1.1.2.2-L15.1.1.3.1-L09.2.2.2.1 | 2.08 | 0.91 | 5.98 | 1.8928 | 0.0894884 | 0.074
12 x Porte 83x204 bois alvéolaire | R+2 | Porte intérieure logement | 0.83 | Distribution Logements | 83x204 | LOT 12; LOT 15; LOT 09 | L12.2.1.2.2; L15.2.1.3.1; L09.2.2.2.1 | 2.08 | 0.91 | 5.98 | 1.8928 | 0.0894884 | 0.074
4 x Porte 93x204 bois blindée | R+2 | Porte palière | 0.93 | Portes palières | 93x204 | LOT 04; LOT 12; LOT 15 | L04.2.20.1; L12.2.1.1; L12.2.2.5.1; L15.2.1.3.2; L15.2.2.5.3 | 2.085 | 1.02 | 6.21 | 2.1267 | 0.123678 | 0.2 | Pset_DoorCommon - IsExternal: no
Porte 93x204 bois CF | R+2 | Porte de recoupement | 0.93 | Parties Communes Recoupement | × | LOT 04; LOT 12; LOT 15 | L04.2.20.1; L12.2.1.1; L12.2.2.5.1; L15.2.1.3.2; L15.2.2.5.3 | 2.085 | 1.02 | 6.21 | 2.1267 | 0.123678 | 0.2 | Pset_DoorCommon - IsExternal: no
Porte 93x204 bois CF | R+2 | Porte cage d'escalier | 0.93 | Parties Communes Escaliers | 93x204 | LOT 04; LOT 12; LOT 15 | L04.2.20.1; L12.2.1.1; L12.2.2.5.1; L15.2.1.3.2; L15.2.2.5.3 | 2.085 | 1.02 | 6.21 | 2.1267 | 0.123678 | 0.22 | Pset_DoorCommon - IsExternal: no
2 x Porte 93x204 bois blindée | R+3 | Porte palière | 0.93 | Portes palières | 93x204 | LOT 04; LOT 12; LOT 15 | L04.2.20.1; L12.2.1.1; L12.2.2.5.1; L15.2.1.3.2; L15.2.2.5.3 | 2.085 | 1.02 | 6.21 | 2.1267 | 0.123678 | 0.2 | Pset_DoorCommon - IsExternal: no
Porte 93x204 bois CF | R+3 | Porte cage d'escalier | 0.93 | Parties Communes Escaliers | 93x204 | LOT 04; LOT 12; LOT 15 | L04.2.20.1; L12.2.1.1; L12.2.2.5.1; L15.2.1.3.2; L15.2.2.5.3 | 2.085 | 1.02 | 6.21 | 2.1267 | 0.123678 | 0.22 | Pset_DoorCommon - IsExternal: no
8 x Porte 83x204 bois alvéolaire | R+3 | Porte intérieure logement | 0.83 | Distribution Logements | 83x204 | LOT 12; LOT 15; LOT 09 | L12.2.1.2.2; L15.2.1.3.1; L09.2.2.2.1 | 2.08 | 0.91 | 5.98 | 1.8928 | 0.0894884 | 0.074
5 x Porte 83x204 bois alvéolaire | R+4 | Porte intérieure logement | 0.83 | Distribution Logements | 83x204 | LOT 12; LOT 15; LOT 09 | L12.2.1.2.2; L15.2.1.3.1; L09.2.2.2.1 | 2.08 | 0.91 | 5.98 | 1.8928 | 0.0894884 | 0.074

# IfcDoor: Porte int générique 2019 (122)
Type - OperationType: SINGLE_SWING_RIGHT; ParameterTakesPrecedence: no; Sizeable: no
OverallHeight: 2.04 m; Classification: Porte (Classification ARCHICAD)
Pset_DoorCommon - ThermalTransmittance: 0
AC_Pset_RenovationAndPhasing - Renovation Status: Existing
Name | In | Description | OverallWidth (m) | Localisation | Dimension passage | Numéro de LOT | Numéro article | Height (m) | Width (m) | Perimeter (m) | Area (m2) | Volume (m3) = NetVolume (m3) | Depth (m)
Porte 93x204 bois CF | Sous-sol | Porte local commun | 0.93 | Parties Communes Locaux Communs | × | LOT 04; LOT 12; LOT 15 | L04.2.20.1; L12.2.1.1; L12.2.2.5.1; L15.2.1.3.2; L15.2.2.5.3 | 2.085 | 1.02 | 6.21 | 2.1267 | 0.078912 | 0.2 | Pset_DoorCommon - IsExternal: no
7 x Porte 83x204 bois bâti métal | Sous-sol | Porte de cave | 0.83 | Portes de caves | × | LOT 04; LOT 12 | L04.2.19.1; L12.2.1.1; L12.2.2.5.1; L15.2.1.3.2; L15.2.2.5.3 | 2.085 | 0.92 | 6.01 | 1.9182 | 0.070692 | 0.1 | Pset_DoorCommon - IsExternal: no
3 x Porte 93x204 bois CF | Sous-sol | Porte de sas | 0.93 | Parties Communes sas | × | LOT 04; LOT 12; LOT 15 | L04.2.20.1; L12.2.1.1; L12.2.2.5.1; L15.2.1.3.2; L15.2.2.5.3 | 2.085 | 1.02 | 6.21 | 2.1267 | 0.078912 | 0.2 | Pset_DoorCommon - IsExternal: no
7 x Porte 93x204 bois blindée | Rez-de-chaussée | Porte palière | 0.93 | Portes palières | 93x204 | LOT 04; LOT 12; LOT 15 | L04.2.20.1; L12.2.1.1; L12.2.2.5.1; L15.2.1.3.2; L15.2.2.5.3 | 2.085 | 1.02 | 6.21 | 2.1267 | 0.123678 | 0.2 | Pset_DoorCommon - IsExternal: no
21 x Porte 83x204 bois alvéolaire | Rez-de-chaussée | Porte intérieure logement | 0.83 | Distribution Logements | 83x204 | LOT 12; LOT 15; LOT 09 | L12.2.1.2.2; L15.2.1.3.1; L09.2.2.2.1 | 2.08 | 0.91 | 5.98 | 1.8928 | 0.0894884 | 0.074
Porte acier 1V 93x204 | Rez-de-chaussée | Porte acier extérieure | 0.93 | Porte métal extérieure 1V | 93x204 | L17 | L17.2.4.1.1 | 2.085 | 1.02 | 6.21 | 2.1267 | 0.078912 | 0.28
7 x Porte 93x204 bois blindée | R+1 | Porte palière | 0.93 | Portes palières | 93x204 | LOT 04; LOT 12; LOT 15 | L04.2.20.1; L12.2.1.1; L12.2.2.5.1; L15.2.1.3.2; L15.2.2.5.3 | 2.085 | 1.02 | 6.21 | 2.1267 | 0.123678 | 0.2 | Pset_DoorCommon - IsExternal: no
17 x Porte 83x204 bois alvéolaire | R+1 | Porte intérieure logement | 0.83 | Distribution Logements | 83x204 | LOT 12; LOT 15; LOT 09 | L12.2.1.2.2; L15.2.1.3.1; L09.2.2.2.1 | 2.08 | 0.91 | 5.98 | 1.8928 | 0.0894884 | 0.074
9 x Porte 83x204 bois alvéolaire | R+1 | Porte intérieure logement | 0.83 | Distribution Logements | 83x204 | LOT 12-LOT 15-LOT09 | L12.1.1.2-L12.1.1.2.2-L15.1.1.3.1-L09.2.2.2.1 | 2.08 | 0.91 | 5.98 | 1.8928 | 0.0894884 | 0.074
5 x Porte 93x204 bois blindée | R+2 | Porte palière | 0.93 | Portes palières | 93x204 | LOT 04; LOT 12; LOT 15 | L04.2.20.1; L12.2.1.1; L12.2.2.5.1; L15.2.1.3.2; L15.2.2.5.3 | 2.085 | 1.02 | 6.21 | 2.1267 | 0.123678 | 0.2 | Pset_DoorCommon - IsExternal: no
25 x Porte 83x204 bois alvéolaire | R+2 | Porte intérieure logement | 0.83 | Distribution Logements | 83x204 | LOT 12; LOT 15; LOT 09 | L12.2.1.2.2; L15.2.1.3.1; L09.2.2.2.1 | 2.08 | 0.91 | 5.98 | 1.8928 | 0.0894884 | 0.074
Por-004 | R+2 |  | 0.83 | Distribution Logements | 83x204 | LOT 12; LOT 15; LOT 09 | L12.2.1.2.2; L15.2.1.3.1; L09.2.2.2.1 | 2.08 | 0.91 | 5.98 | 1.8928 | 0.0894884 | 0.074
10 x Porte 83x204 bois alvéolaire | R+3 | Porte intérieure logement | 0.83 | Distribution Logements | 83x204 | LOT 12; LOT 15; LOT 09 | L12.2.1.2.2; L15.2.1.3.1; L09.2.2.2.1 | 2.08 | 0.91 | 5.98 | 1.8928 | 0.0894884 | 0.074
3 x Porte 93x204 bois blindée | R+3 | Porte palière | 0.93 | Portes palières | 93x204 | LOT 04; LOT 12; LOT 15 | L04.2.20.1; L12.2.1.1; L12.2.2.5.1; L15.2.1.3.2; L15.2.2.5.3 | 2.085 | 1.02 | 6.21 | 2.1267 | 0.123678 | 0.2 | Pset_DoorCommon - IsExternal: no
Porte 83x204 bois alvéolaire | R+3 | Porte intérieure logement | 0.83 | Distribution Logements | 83x204 | LOT 12; LOT 15; LOT 09 | L12.2.1.2.2; L15.2.1.3.1; L09.2.2.2.1 | 2.08 | 0.91 | 5.98 | 1.8928 | 0.114638 | 0.2
Porte 83x204 bois alvéolaire | R+3 | Porte intérieure logement | 0.93 | Distribution Logements | × | LOT 12-LOT 15-LOT09 | L12.1.1.2-L12.1.1.2.2-L15.1.1.3.1-L09.2.2.2.1 | 2.085 | 1.02 | 6.21 | 2.1267 | 0.123678 | 0.2
3 x Porte 83x204 bois alvéolaire | R+4 | Porte intérieure logement | 0.83 | Distribution Logements | 83x204 | LOT 12; LOT 15; LOT 09 | L12.2.1.2.2; L15.2.1.3.1; L09.2.2.2.1 | 2.08 | 0.91 | 5.98 | 1.8928 | 0.0894884 | 0.074

# IfcDoor: Porte int générique 2019 (56)
Type - OperationType: USERDEFINED; ParameterTakesPrecedence: no; Sizeable: no
Pset_DoorCommon - ThermalTransmittance: 0
Propriétés PORTES - Localisation: Placard; Dimension passage: ×
Propriétés DCE - Numéro de LOT: LOT 12
AC_Pset_RenovationAndPhasing - Renovation Status: Existing
BaseQuantities - Depth: 0.074 m
Name | In | OverallHeight (m) | OverallWidth (m) | Classification | Numéro article | Height (m) | Width (m) | Perimeter (m) | Area (m2) | Volume (m3) = NetVolume (m3)
Por-002 | R+1 | 2.04 | 1.37 | Porte (Classification ARCHICAD); Porte (Classification ARCHICAD) | L12.1.1.3 | 2.08 | 1.45 | 7.06 | 3.016 | 0.05712
Por-002 | R+1 | 2.5 | 0.869834 | Porte (Classification ARCHICAD); Porte (Classification ARCHICAD) | L12.2.1.3.1 | 2.5 | 0.949834 | 6.89967 | 2.37458 | 0.0449917
Por-002 | R+1 | 2.5 | 1.27 | Porte (Classification ARCHICAD); Porte (Classification ARCHICAD) | L12.2.1.3.2 | 2.5 | 1.35 | 7.7 | 3.375 | 0.065
Por-002 | R+1 | 2.5 | 1.12 | Porte (Classification ARCHICAD); Porte (Classification ARCHICAD) | L12.2.1.3.2 | 2.5 | 1.2 | 7.4 | 3 | 0.0575
Por-002 | R+1 | 2.5 | 3.10475 | Porte (Classification ARCHICAD); Porte (Classification ARCHICAD) | L12.2.1.3.3 | 2.5 | 3.18475 | 11.3695 | 7.96188 | 0.156738
Por-002 | R+1 | 2.5 | 1.31186 | Porte (Classification ARCHICAD); Porte (Classification ARCHICAD) | L12.2.1.3.2 | 2.5 | 1.39186 | 7.78373 | 3.47966 | 0.0670932
Por-002 | R+1 | 2.04 | 0.82 | Porte (Classification ARCHICAD); Porte (Classification ARCHICAD) | L12.2.1.3.1 | 2.08 | 0.9 | 5.96 | 1.872 | 0.03468
Por-002 | R+1 | 2.04 | 0.956 | Porte (Classification ARCHICAD); Porte (Classification ARCHICAD) | L12.2.1.3.2 | 2.08 | 1.036 | 6.232 | 2.15488 | 0.0402288
Por-002 | R+1 | 2.5 | 2.045 | Porte (Classification ARCHICAD); Porte (Classification ARCHICAD) | L12.2.1.3.3 | 2.5 | 2.125 | 9.25 | 5.3125 | 0.10375
Por-002 | R+1 | 2.5 | 0.984 | Porte (Classification ARCHICAD); Porte (Classification ARCHICAD) | L12.2.1.3.2 | 2.5 | 1.064 | 7.128 | 2.66 | 0.0507
Por-003 | R+1 | 2.5 | 1.77002 | Porte (Classification ARCHICAD); Porte (Classification ARCHICAD) | L12.2.1.3.3 | 2.5 | 1.85002 | 8.70003 | 4.62504 | 0.0900008
Por-002 | R+1 | 2.04 | 1.32 | Porte (Classification ARCHICAD); Porte (Classification ARCHICAD) | L12.1.1.3 | 2.08 | 1.4 | 6.96 | 2.912 | 0.05508
Por-002 | R+1 | 2.04 | 1.89807 | Porte (Classification ARCHICAD); Porte (Classification ARCHICAD) | L12.1.1.3 | 2.08 | 1.97807 | 8.11613 | 4.11438 | 0.0786651
Por-002 | R+1 | 2.04 | 1.07 | Porte (Classification ARCHICAD); Porte (Classification ARCHICAD) | L12.1.1.3 | 2.08 | 1.12896 | 6.41793 | 2.34824 | 0.04488
Por-002 | R+1 | 2.04 | 0.87 | Porte (Classification ARCHICAD); Porte (Classification ARCHICAD) | L12.1.1.3 | 2.08 | 0.95 | 6.06 | 1.976 | 0.03672
Por-003 | R+1 | 2.04 | 0.887 | Porte (Classification ARCHICAD); Porte (Classification ARCHICAD) | L12.1.1.3 | 2.08 | 0.967 | 6.094 | 2.01136 | 0.0374136
Por-002 | R+2 | 2.04 | 1.17 | Porte (Classification ARCHICAD); Porte (Classification ARCHICAD) | L12.2.1.3.2 | 2.08 | 1.25 | 6.66 | 2.6 | 0.04896
Por-002 | R+2 | 2.04 | 1.37 | Porte (Classification ARCHICAD); Porte (Classification ARCHICAD) | L12.1.1.3 | 2.08 | 1.45 | 7.06 | 3.016 | 0.05712
2 x Por-002 | R+2 | 2.04 | 1.32 | Porte (Classification ARCHICAD); Porte (Classification ARCHICAD) | L12.2.1.3.3 | 2.08 | 1.4 | 6.96 | 2.912 | 0.05508
Por-002 | R+2 | 2.04 | 0.869834 | Porte (Classification ARCHICAD); Porte (Classification ARCHICAD) | L12.2.1.3.1 | 2.08 | 0.949834 | 6.05967 | 1.97565 | 0.0367132
Por-002 | R+2 | 2.04 | 1.89807 | Porte (Classification ARCHICAD); Porte (Classification ARCHICAD) | L12.2.1.3.3 | 2.08 | 1.97807 | 8.11613 | 4.11438 | 0.0786651
Por-002 | R+2 | 2.04 | 0.87 | Porte (Classification ARCHICAD); Porte (Classification ARCHICAD) | L12.2.1.3.1 | 2.08 | 0.95 | 6.06 | 1.976 | 0.03672
Por-003 | R+2 | 2.04 | 0.887 | Porte (Classification ARCHICAD); Porte (Classification ARCHICAD) | L12.2.1.3.1 | 2.08 | 0.967 | 6.094 | 2.01136 | 0.0374136
Por-002 | R+2 | 2.04 | 1.07 | Porte (Classification ARCHICAD); Porte (Classification ARCHICAD) | L12.2.1.3.2 | 2.08 | 1.12896 | 6.41793 | 2.34824 | 0.04488
Por-002 | R+2 | 2.04 | 1.79589 | Porte (Classification ARCHICAD); Porte (Classification ARCHICAD) | L12.2.1.3.3 | 2.08 | 1.87589 | 7.91179 | 3.90186 | 0.0744965
Por-003 | R+3 | 2.04 | 3.19631 | Porte (Classification ARCHICAD); Porte (Classification ARCHICAD) | L12.2.1.3.3 | 2.08 | 3.27631 | 10.7126 | 6.81473 | 0.131633
Por-002 | R+3 | 2.04 | 3.24493 | Porte (Classification ARCHICAD); Porte (Classification ARCHICAD) | L12.2.1.3.3 | 2.08 | 3.32493 | 10.8099 | 6.91585 | 0.136065
Por-004 | R+3 | 2.04 | 1.792 | Porte (Classification ARCHICAD); Porte (Classification ARCHICAD) | L12.2.1.3.3 | 2.08 | 1.872 | 7.904 | 3.89376 | 0.0743376
Por-002 | R+3 | 2.04 | 0.928738 | Porte (Classification ARCHICAD); Porte (Classification ARCHICAD) | L12.2.1.3.2 | 2.08 | 1.00874 | 6.17748 | 2.09817 | 0.0391165
Por-002 | R+3 | 2.04 | 1.37 | Porte (Classification ARCHICAD); Porte (Classification ARCHICAD) | L12.1.1.3 | 2.08 | 1.45 | 7.06 | 3.016 | 0.05712
Por-002 | R+3 | 2.04 | 1.32 | Porte (Classification ARCHICAD); Porte (Classification ARCHICAD) | L12.2.1.3.3 | 2.08 | 1.4 | 6.96 | 2.912 | 0.05508
Por-002 | R+3 | 2.04 | 0.87 | Porte (Classification ARCHICAD); Porte (Classification ARCHICAD) | L12.2.1.3.1 | 2.08 | 0.95 | 6.06 | 1.976 | 0.03672
Por-003 | R+3 | 2.04 | 0.887 | Porte (Classification ARCHICAD); Porte (Classification ARCHICAD) | L12.2.1.3.1 | 2.08 | 0.967 | 6.094 | 2.01136 | 0.0374136
Por-002 | R+3 | 2.04 | 1.95589 | Porte (Classification ARCHICAD); Porte (Classification ARCHICAD) | L12.2.1.3.3 | 2.08 | 2.03589 | 8.23177 | 4.23464 | 0.0810241
Por-002 | R+4 | 2.04 | 2.24963 | Porte (Classification ARCHICAD); Porte (Classification ARCHICAD) | L12.2.1.3.3 | 2.08 | 2.32963 | 8.81926 | 4.84563 | 0.093009
Por-002 | R+4 | 2.04 | 2.8585 | Porte (Classification ARCHICAD); Porte (Classification ARCHICAD) | L12.2.1.3.3 | 2.08 | 2.9385 | 10.037 | 6.11207 | 0.119075
Por-003 | R+4 | 2.04 | 2.24563 | Porte (Classification ARCHICAD); Porte (Classification ARCHICAD) | L12.2.1.3.3 | 2.08 | 2.32563 | 8.81126 | 4.83731 | 0.0928458
Por-002 | R+4 | 2.04 | 1.25618 | Porte (Classification ARCHICAD); Porte (Classification ARCHICAD) | L12.2.1.3.2 | 2.08 | 1.33618 | 6.83236 | 2.77925 | 0.0524761
Por-002 | Rez-de-chaussée | 2.5 | 1.14491 | Porte (Classification ARCHICAD) | L12.2.1.3.2 | 2.5 | 1.22491 | 7.44981 | 3.06227 | 0.0587453
Por-002 | Rez-de-chaussée | 2.5 | 1.07 | Porte (Classification ARCHICAD) | L12.2.1.3.2 | 2.5 | 1.12896 | 7.25793 | 2.82241 | 0.055
Por-002 | Rez-de-chaussée | 2.5 | 0.87 | Porte (Classification ARCHICAD) | L12.2.1.3.1 | 2.5 | 0.95 | 6.9 | 2.375 | 0.045
Por-002 | Rez-de-chaussée | 2.5 | 1.33779 | Porte (Classification ARCHICAD) | L12.1.1.3 | 2.5 | 1.41779 | 7.83557 | 3.54446 | 0.0683893
Por-002 | Rez-de-chaussée | 2.5 | 0.869834 | Porte (Classification ARCHICAD) | L12.2.1.3.1 | 2.5 | 0.949834 | 6.89967 | 2.37458 | 0.0449917
Por-003 | Rez-de-chaussée | 2.5 | 0.887 | Porte (Classification ARCHICAD) | L12.2.1.3.1 | 2.5 | 0.967 | 6.934 | 2.4175 | 0.04585
2 x Por-002 | Rez-de-chaussée | 2.5 | 1.12 | Porte (Classification ARCHICAD) | L12.2.1.3.2 | 2.5 | 1.2 | 7.4 | 3 | 0.0575
Por-002 | Rez-de-chaussée | 2.5 | 0.984 | Porte (Classification ARCHICAD) | L12.2.1.3.2 | 2.5 | 1.064 | 7.128 | 2.66 | 0.0507
Por-002 | Rez-de-chaussée | 2.04 | 0.82 | Porte (Classification ARCHICAD) | L12.2.1.3.1 | 2.08 | 0.9 | 5.96 | 1.872 | 0.03468
Por-002 | Rez-de-chaussée | 2.04 | 0.956 | Porte (Classification ARCHICAD) | L12.2.1.3.2 | 2.08 | 1.036 | 6.232 | 2.15488 | 0.0402288
Por-002 | Rez-de-chaussée | 2.04 | 1.27 | Porte (Classification ARCHICAD) | L12.2.1.3.2 | 2.08 | 1.35 | 6.86 | 2.808 | 0.05304
Por-002 | Rez-de-chaussée | 2.5 | 1.89807 | Porte (Classification ARCHICAD) | L12.2.1.3.3 | 2.5 | 1.97807 | 8.95613 | 4.94517 | 0.0964033
Por-003 | Rez-de-chaussée | 2.5 | 1.77002 | Porte (Classification ARCHICAD) | L12.2.1.3.3 | 2.5 | 1.85002 | 8.70003 | 4.62504 | 0.0900008
Por-002 | Rez-de-chaussée | 2.5 | 1.32 | Porte (Classification ARCHICAD) | L12.2.1.3.3 | 2.5 | 1.4 | 7.8 | 3.5 | 0.0675
Por-002 | Rez-de-chaussée | 2.5 | 2.045 | Porte (Classification ARCHICAD) | L12.2.1.3.3 | 2.5 | 2.125 | 9.25 | 5.3125 | 0.10375
Por-002 | R+1 | 2.5 | 1.32 | Porte (Classification ARCHICAD); Porte (Classification ARCHICAD) | L12.2.1.3.3 | 2.5 | 1.4 | 7.8 | 3.5 | 0.0675

# IfcEnergyConversionDevice: Chaudière à gaz 23 (18)
Type - PredefinedType: WATER
Classification: Chaudière à eau (Classification ARCHICAD)
AC_Pset_RenovationAndPhasing - Renovation Status: Existing
Name | In
4 x MOB-002 | Rez-de-chaussée
5 x MOB-002 | R+1
5 x MOB-002 | R+2
3 x MOB-002 | R+3
MOB-002 | R+4

# IfcEnergyConversionDevice: Chauffe-eau électrique 23 (18)
Type - PredefinedType: SHELLANDTUBE
AC_Pset_RenovationAndPhasing - Renovation Status: Existing
Name | In | Classification
5 x MOB-002 | Rez-de-chaussée | Echangeur de chaleur tubulaire (Classification ARCHICAD); Terminal sanitaire (Classification ARCHICAD)
3 x MOB-002 | R+1 | Echangeur de chaleur tubulaire (Classification ARCHICAD); Terminal sanitaire (Classification ARCHICAD)
2 x MOB-002 | R+2 | Echangeur de chaleur tubulaire (Classification ARCHICAD); Terminal sanitaire (Classification ARCHICAD)
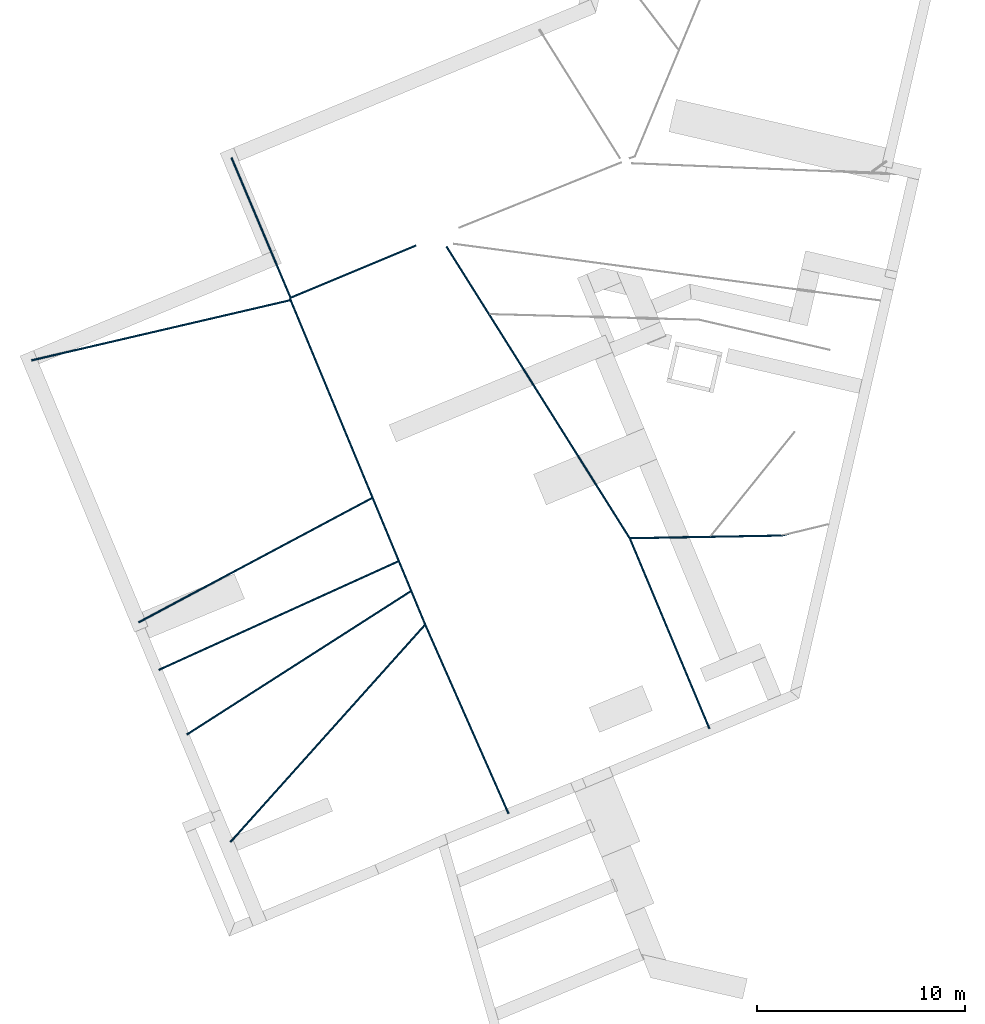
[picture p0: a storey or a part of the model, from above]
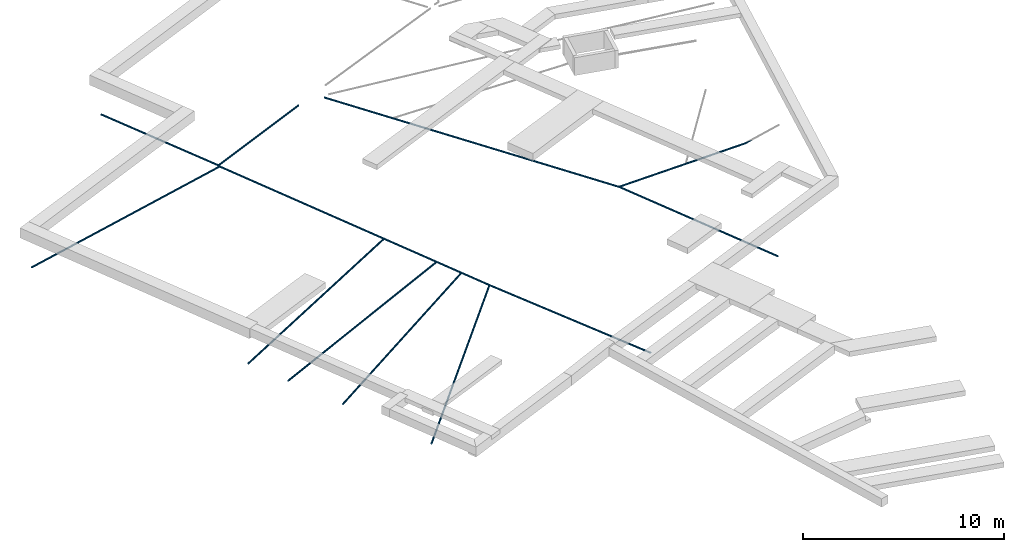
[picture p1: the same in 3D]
Properties of the parts of a building model (IFC2X3), part 4 of 22

# IfcEnergyConversionDevice: Chauffe-eau électrique 23 (18)
Name | In | Classification
2 x MOB-002 | Rez-de-chaussée | Echangeur de chaleur tubulaire (Classification ARCHICAD)
3 x MOB-002 | R+1 | Echangeur de chaleur tubulaire (Classification ARCHICAD)
2 x MOB-002 | R+2 | Echangeur de chaleur tubulaire (Classification ARCHICAD)
MOB-002 | R+3 | Echangeur de chaleur tubulaire (Classification ARCHICAD)

# IfcFastener: Panne 23 (22)
In: R+3
Description: Pergola; Material: Bois - Massif 01
Propriétés DCE - Numéro de LOT: LOT 05; Numéro article: L05.2.2.3.1
AC_Pset_RenovationAndPhasing - Renovation Status: Existing
Material Properties - Bois - Massif 01, ThermalConductivity: 0.14; Bois - Massif 01, SpecificHeatCapacity: 2300 J/kg/K; Bois - Massif 01, MassDensity: 500 kg/m3; Bois - Massif 01, Embodied Energy: 10 (MJ/kg); Bois - Massif 01, Embodied Carbon: 0.36 (kgCO₂/kg); Bois - Massif 01, Name: Bois - Massif 01; Bois - Massif 01, Participates in Collision Detection: yes
Name | Classification
Traverse bois pergola | Accessoire d'assemblage (Classification ARCHICAD); Elément d'assemblage (Classification ARCHICAD)
21 x Traverse bois pergola | Elément d'assemblage (Classification ARCHICAD)

# IfcFlowTerminal: Baignoire 23 (14)
Type - PredefinedType: BATH
AC_Pset_RenovationAndPhasing - Renovation Status: Existing
Name | In | Classification
MOB-002 | R+1 | Baignoire (Classification ARCHICAD); Terminal sanitaire (Classification ARCHICAD)
4 x MOB-002 | R+2 | Baignoire (Classification ARCHICAD); Terminal sanitaire (Classification ARCHICAD)
2 x MOB-002 | R+3 | Baignoire (Classification ARCHICAD); Terminal sanitaire (Classification ARCHICAD)
MOB-002 | R+4 | Baignoire (Classification ARCHICAD); Terminal sanitaire (Classification ARCHICAD)
3 x MOB-002 | Rez-de-chaussée | Baignoire (Classification ARCHICAD)
3 x MOB-002 | R+1 | Baignoire (Classification ARCHICAD)

# IfcFlowTerminal: Boite à eau 23 (6)
Type - PredefinedType: GULLYTRAP
Classification: Elément de construction (Classification ARCHICAD); Grille d'évacuation d'eau (Classification ARCHICAD)
Propriétés DCE - Numéro de LOT: LOT 06; Numéro article: L06.2.2.2
AC_Pset_RenovationAndPhasing - Renovation Status: Existing
Name | In
2 x MOB-005 | R+2
MOB-005 | R+3
MOB-005 | R+4
2 x MOB-005 | Etage

# IfcFlowTerminal: Caiilebotis terrasse accessible (12)
Type - PredefinedType: GULLYTRAP
Classification: Elément de transport (Classification ARCHICAD); Grille d'évacuation d'eau (Classification ARCHICAD)
Propriétés DCE - Numéro de LOT: Lot 07; Numéro article: L07.2.7.5
AC_Pset_RenovationAndPhasing - Renovation Status: Existing
Name | In
3 x MOB-002 | R+2
6 x MOB-002 | R+3
3 x MOB-002 | R+4

# IfcFlowTerminal: Conduit 23 (2)
Classification: Terminal de conduit de cheminée (Classification ARCHICAD)
Propriétés DCE - Numéro de LOT: LOT 07; Numéro article: L07.2.7.7
AC_Pset_RenovationAndPhasing - Renovation Status: Existing
Name | In
MOB-002 | R+3
MOB-002 | R+4

# IfcFlowTerminal: Cunette 115 x 60 (11)
In: Sous-sol
Type - PredefinedType: GULLYSUMP
Classification: Rigole (Classification ARCHICAD); Material: Finition sol - Carrelage
AC_Pset_RenovationAndPhasing - Renovation Status: Existing
Material Properties - Finition sol - Carrelage, ThermalConductivity: 0.58; Finition sol - Carrelage, SpecificHeatCapacity: 840 J/kg/K; Finition sol - Carrelage, MassDensity: 1500 kg/m3; Finition sol - Carrelage, Embodied Energy: 3 (MJ/kg); Finition sol - Carrelage, Embodied Carbon: 0.24 (kgCO₂/kg); Finition sol - Carrelage, Name: Finition sol - Carrelage; Finition sol - Carrelage, Participates in Collision Detection: no
Name
2 x M_Ext-011
4 x M_Ext-012
3 x M_Ext-010
2 x M_Ext-013

# IfcFlowTerminal: Douche rectangulaire 23 (27)
Type - PredefinedType: SHOWER
Classification: Douche (Classification ARCHICAD)
AC_Pset_RenovationAndPhasing - Renovation Status: Existing
Name | In
8 x MOB-002 | Rez-de-chaussée
7 x MOB-002 | R+1
8 x MOB-002 | R+2
3 x MOB-002 | R+3
MOB-002 | R+4

# IfcFlowTerminal: Décalage tuyau descente 23, MOB-006
In: R+4
Type - PredefinedType: GULLYTRAP
Classification: Elément de construction (Classification ARCHICAD); Grille d'évacuation d'eau (Classification ARCHICAD)
Propriétés DCE - Numéro de LOT: LOT 06; Numéro article: L06.1.2.1
AC_Pset_RenovationAndPhasing - Renovation Status: Existing

# IfcFlowTerminal: Elément simple avec deux portes 23 (17)
Type - PredefinedType: WASHINGMACHINE
Classification: Lave-linge (Classification ARCHICAD)
AC_Pset_RenovationAndPhasing - Renovation Status: Existing
Name | In
7 x MOB-002 | Rez-de-chaussée
6 x MOB-002 | R+1
3 x MOB-002 | R+2
MOB-002 | R+3

# IfcFlowTerminal: Empattement 1, Semelle filante:(100x30T):1404018
In: -2. Etage
Type - PredefinedType: WASHINGMACHINE
Classification: Fondation (Classification ARCHICAD); Lave-linge (Classification ARCHICAD); Material: Béton
Autre - Catégorie: Fondations; Famille: Semelle filante: (100x30T); Famille et type: Semelle filante: (100x30T); ID du type: Semelle filante: (100x30T); Type: Semelle filante: (100x30T)
Contraintes - Excentricité: 0 m
Cotes - Elévation à la base: -3.6 m; Elévation en haut: -3.3 m; Etude de l'élévation à la base: -3.6 m; Etude de l'élévation en haut: -3.3 m; Largeur: 1 m; Longueur: 3.01117 m; Surface: 2.73125 m2; Volume: 0.819374 m3
Données d'identification - Commentaires: SF12; Identifiant: SC 42; IdGtcParameter: 27060
Phase de construction - Phase de création: Nouvelle construction
Structure - Activer le modèle analytique: yes; Enrobage d'armature - Autres faces: Paramètres de l'enrobage d'armature: Enrobage d'armature 1; Enrobage d'armature - Face inférieure: Paramètres de l'enrobage d'armature: Enrobage d'armature 1; Enrobage d'armature - Face supérieure: Paramètres de l'enrobage d'armature: Enrobage d'armature 1
Texte - CLASSE BETON: C25/30; RATIOS: 35kg/m3
Autre(Type) - Catégorie: Fondations; Nom de la famille: Semelle filante
Cotes(Type) - Longueur de l'extension de fin par défaut: 0 m; Ne pas couper aux insertions: yes; Epaisseur de fondation: 0.3 m; Largeur: 1 m
Données d'identification(Type) - Nom du type: (100x30T)
Structure(Type) - Utilisation structurelle: Porteur
AC_Pset_RenovationAndPhasing - Renovation Status: Existing
Material Properties - Béton, ThermalConductivity: 2.3; Béton, SpecificHeatCapacity: 1000 J/kg/K; Béton, MassDensity: 2300 kg/m3; Béton, Embodied Energy: 1.92 (MJ/kg); Béton, Embodied Carbon: 0.198 (kgCO₂/kg); Béton, Name: Béton; Béton, Participates in Collision Detection: yes

# IfcFlowTerminal: Empattement 10, Semelle filante:(50x60T) ex:1598820
In: -2. Etage
Type - PredefinedType: WASHINGMACHINE
Classification: Fondation (Classification ARCHICAD); Lave-linge (Classification ARCHICAD); Material: Béton
Autre - Catégorie: Fondations; Famille: Semelle filante: (50x60T) ex; Famille et type: Semelle filante: (50x60T) ex; ID du type: Semelle filante: (50x60T) ex; Type: Semelle filante: (50x60T) ex
Cotes - Elévation à la base: -3.9 m; Elévation en haut: -3.3 m; Etude de l'élévation à la base: -3.9 m; Etude de l'élévation en haut: -3.3 m; Largeur: 0.5 m; Longueur: 7.42692 m; Surface: 3.71289 m2; Volume: 2.06803 m3
Données d'identification - Commentaires: SF4
Phase de construction - Phase de création: Nouvelle construction
Structure - Activer le modèle analytique: yes; Enrobage d'armature - Autres faces: Paramètres de l'enrobage d'armature: Enrobage d'armature 1; Enrobage d'armature - Face inférieure: Paramètres de l'enrobage d'armature: Enrobage d'armature 1; Enrobage d'armature - Face supérieure: Paramètres de l'enrobage d'armature: Enrobage d'armature 1
Autre(Type) - Catégorie: Fondations; Nom de la famille: Semelle filante
Cotes(Type) - Largeur côté extérieur: 0 m; Longueur de l'extension de fin par défaut: 0 m; Ne pas couper aux insertions: yes; Epaisseur de fondation: 0.6 m; Largeur côté intérieur: 0.25 m
Données d'identification(Type) - Nom du type: (50x60T) ex
Structure(Type) - Utilisation structurelle: Soutènement
AC_Pset_RenovationAndPhasing - Renovation Status: Existing
Material Properties - Béton, ThermalConductivity: 2.3; Béton, SpecificHeatCapacity: 1000 J/kg/K; Béton, MassDensity: 2300 kg/m3; Béton, Embodied Energy: 1.92 (MJ/kg); Béton, Embodied Carbon: 0.198 (kgCO₂/kg); Béton, Name: Béton; Béton, Participates in Collision Detection: yes

# IfcFlowTerminal: Empattement 11, Semelle filante:(50x60T) ex:1598829
In: -2. Etage
Type - PredefinedType: WASHINGMACHINE
Classification: Fondation (Classification ARCHICAD); Lave-linge (Classification ARCHICAD); Material: Béton
Autre - Catégorie: Fondations; Famille: Semelle filante: (50x60T) ex; Famille et type: Semelle filante: (50x60T) ex; ID du type: Semelle filante: (50x60T) ex; Type: Semelle filante: (50x60T) ex
Cotes - Elévation à la base: -3.9 m; Elévation en haut: -3.3 m; Etude de l'élévation à la base: -3.9 m; Etude de l'élévation en haut: -3.3 m; Largeur: 0.5 m; Longueur: 10.9542 m; Surface: 5.63048 m2; Volume: 3.09404 m3
Données d'identification - Commentaires: SF4
Phase de construction - Phase de création: Nouvelle construction
Structure - Activer le modèle analytique: yes; Enrobage d'armature - Autres faces: Paramètres de l'enrobage d'armature: Enrobage d'armature 1; Enrobage d'armature - Face inférieure: Paramètres de l'enrobage d'armature: Enrobage d'armature 1; Enrobage d'armature - Face supérieure: Paramètres de l'enrobage d'armature: Enrobage d'armature 1
Autre(Type) - Catégorie: Fondations; Nom de la famille: Semelle filante
Cotes(Type) - Largeur côté extérieur: 0 m; Longueur de l'extension de fin par défaut: 0 m; Ne pas couper aux insertions: yes; Epaisseur de fondation: 0.6 m; Largeur côté intérieur: 0.25 m
Données d'identification(Type) - Nom du type: (50x60T) ex
Structure(Type) - Utilisation structurelle: Soutènement
AC_Pset_RenovationAndPhasing - Renovation Status: Existing
Material Properties - Béton, ThermalConductivity: 2.3; Béton, SpecificHeatCapacity: 1000 J/kg/K; Béton, MassDensity: 2300 kg/m3; Béton, Embodied Energy: 1.92 (MJ/kg); Béton, Embodied Carbon: 0.198 (kgCO₂/kg); Béton, Name: Béton; Béton, Participates in Collision Detection: yes

# IfcFlowTerminal: Empattement 12, Semelle filante:(70x25T):1540224
In: -2. Etage
Type - PredefinedType: WASHINGMACHINE
Classification: Fondation (Classification ARCHICAD); Lave-linge (Classification ARCHICAD); Material: Béton
Autre - Catégorie: Fondations; Famille: Semelle filante: (70x25T); Famille et type: Semelle filante: (70x25T); ID du type: Semelle filante: (70x25T); Type: Semelle filante: (70x25T)
Contraintes - Excentricité: 0 m
Cotes - Elévation à la base: -3.45 m; Elévation en haut: -3.2 m; Etude de l'élévation à la base: -3.45 m; Etude de l'élévation en haut: -3.2 m; Largeur: 0.7 m; Longueur: 5.52331 m; Surface: 3.45757 m2; Volume: 0.913391 m3
Données d'identification - Commentaires: SF9
Phase de construction - Phase de création: Nouvelle construction
Structure - Activer le modèle analytique: yes; Enrobage d'armature - Autres faces: Paramètres de l'enrobage d'armature: Enrobage d'armature 1; Enrobage d'armature - Face inférieure: Paramètres de l'enrobage d'armature: Enrobage d'armature 1; Enrobage d'armature - Face supérieure: Paramètres de l'enrobage d'armature: Enrobage d'armature 1
Autre(Type) - Catégorie: Fondations; Nom de la famille: Semelle filante
Cotes(Type) - Longueur de l'extension de fin par défaut: 0 m; Ne pas couper aux insertions: yes; Epaisseur de fondation: 0.25 m; Largeur: 0.7 m
Données d'identification(Type) - Nom du type: (70x25T)
Structure(Type) - Utilisation structurelle: Porteur
AC_Pset_RenovationAndPhasing - Renovation Status: Existing
Material Properties - Béton, ThermalConductivity: 2.3; Béton, SpecificHeatCapacity: 1000 J/kg/K; Béton, MassDensity: 2300 kg/m3; Béton, Embodied Energy: 1.92 (MJ/kg); Béton, Embodied Carbon: 0.198 (kgCO₂/kg); Béton, Name: Béton; Béton, Participates in Collision Detection: yes

# IfcFlowTerminal: Empattement 13, Semelle filante:(90x30T):1403326
In: -2. Etage
Type - PredefinedType: WASHINGMACHINE
Classification: Fondation (Classification ARCHICAD); Lave-linge (Classification ARCHICAD); Material: Béton
Autre - Catégorie: Fondations; Famille: Semelle filante: (90x30T); Famille et type: Semelle filante: (90x30T); ID du type: Semelle filante: (90x30T); Type: Semelle filante: (90x30T)
Contraintes - Excentricité: 0 m
Cotes - Elévation à la base: -3.6 m; Elévation en haut: -3.3 m; Etude de l'élévation à la base: -3.6 m; Etude de l'élévation en haut: -3.3 m; Largeur: 0.9 m; Longueur: 16.4216 m; Surface: 12.6195 m2; Volume: 3.78584 m3
Données d'identification - Commentaires: SF6; Identifiant: SC 22; IdGtcParameter: 26420
Phase de construction - Phase de création: Nouvelle construction
Structure - Activer le modèle analytique: yes; Enrobage d'armature - Autres faces: Paramètres de l'enrobage d'armature: Enrobage d'armature 1; Enrobage d'armature - Face inférieure: Paramètres de l'enrobage d'armature: Enrobage d'armature 1; Enrobage d'armature - Face supérieure: Paramètres de l'enrobage d'armature: Enrobage d'armature 1
Texte - CLASSE BETON: C25/30; RATIOS: 35kg/m3
Autre(Type) - Catégorie: Fondations; Nom de la famille: Semelle filante
Cotes(Type) - Longueur de l'extension de fin par défaut: 0 m; Ne pas couper aux insertions: yes; Epaisseur de fondation: 0.3 m; Largeur: 0.9 m
Données d'identification(Type) - Nom du type: (90x30T)
Structure(Type) - Utilisation structurelle: Porteur
AC_Pset_RenovationAndPhasing - Renovation Status: Existing
Material Properties - Béton, ThermalConductivity: 2.3; Béton, SpecificHeatCapacity: 1000 J/kg/K; Béton, MassDensity: 2300 kg/m3; Béton, Embodied Energy: 1.92 (MJ/kg); Béton, Embodied Carbon: 0.198 (kgCO₂/kg); Béton, Name: Béton; Béton, Participates in Collision Detection: yes

# IfcFlowTerminal: Empattement 14, Semelle filante:(90x30T):1421007
In: -2. Etage
Type - PredefinedType: WASHINGMACHINE
Classification: Fondation (Classification ARCHICAD); Lave-linge (Classification ARCHICAD); Material: Béton
Autre - Catégorie: Fondations; Famille: Semelle filante: (90x30T); Famille et type: Semelle filante: (90x30T); ID du type: Semelle filante: (90x30T); Type: Semelle filante: (90x30T)
Contraintes - Excentricité: 0 m
Cotes - Elévation à la base: -3.6 m; Elévation en haut: -3.3 m; Etude de l'élévation à la base: -3.6 m; Etude de l'élévation en haut: -3.3 m; Largeur: 0.9 m; Longueur: 2.47968 m; Surface: 2.05115 m2; Volume: 0.615346 m3
Données d'identification - Commentaires: SF6
Phase de construction - Phase de création: Nouvelle construction
Structure - Activer le modèle analytique: yes; Enrobage d'armature - Autres faces: Paramètres de l'enrobage d'armature: Enrobage d'armature 1; Enrobage d'armature - Face inférieure: Paramètres de l'enrobage d'armature: Enrobage d'armature 1; Enrobage d'armature - Face supérieure: Paramètres de l'enrobage d'armature: Enrobage d'armature 1
Texte - CLASSE BETON: C25/30; RATIOS: 35kg/m3
Autre(Type) - Catégorie: Fondations; Nom de la famille: Semelle filante
Cotes(Type) - Longueur de l'extension de fin par défaut: 0 m; Ne pas couper aux insertions: yes; Epaisseur de fondation: 0.3 m; Largeur: 0.9 m
Données d'identification(Type) - Nom du type: (90x30T)
Structure(Type) - Utilisation structurelle: Porteur
AC_Pset_RenovationAndPhasing - Renovation Status: Existing
Material Properties - Béton, ThermalConductivity: 2.3; Béton, SpecificHeatCapacity: 1000 J/kg/K; Béton, MassDensity: 2300 kg/m3; Béton, Embodied Energy: 1.92 (MJ/kg); Béton, Embodied Carbon: 0.198 (kgCO₂/kg); Béton, Name: Béton; Béton, Participates in Collision Detection: yes

# IfcFlowTerminal: Empattement 15, Semelle filante:(90x60T) ex:1402540
In: -2. Etage
Type - PredefinedType: WASHINGMACHINE
Classification: Fondation (Classification ARCHICAD); Lave-linge (Classification ARCHICAD); Material: Béton
Autre - Catégorie: Fondations; Famille: Semelle filante: (90x60T) ex; Famille et type: Semelle filante: (90x60T) ex; ID du type: Semelle filante: (90x60T) ex; Type: Semelle filante: (90x60T) ex
Cotes - Elévation à la base: -3.9 m; Elévation en haut: -3.3 m; Etude de l'élévation à la base: -3.9 m; Etude de l'élévation en haut: -3.3 m; Largeur: 0.9 m; Longueur: 6.79616 m; Surface: 5.60599 m2; Volume: 3.36359 m3
Données d'identification - Commentaires: SF2; Identifiant: SC 6; IdGtcParameter: 25908
Phase de construction - Phase de création: Nouvelle construction
Structure - Activer le modèle analytique: yes; Enrobage d'armature - Autres faces: Paramètres de l'enrobage d'armature: Enrobage d'armature 1; Enrobage d'armature - Face inférieure: Paramètres de l'enrobage d'armature: Enrobage d'armature 1; Enrobage d'armature - Face supérieure: Paramètres de l'enrobage d'armature: Enrobage d'armature 1
Texte - CLASSE BETON: C25/30; RATIOS: 70kg/m3
Autre(Type) - Catégorie: Fondations; Nom de la famille: Semelle filante
Cotes(Type) - Largeur côté extérieur: 0 m; Longueur de l'extension de fin par défaut: 0 m; Ne pas couper aux insertions: yes; Epaisseur de fondation: 0.6 m; Largeur côté intérieur: 0.6 m
Données d'identification(Type) - Nom du type: (90x60T) ex
Structure(Type) - Utilisation structurelle: Soutènement
AC_Pset_RenovationAndPhasing - Renovation Status: Existing
Material Properties - Béton, ThermalConductivity: 2.3; Béton, SpecificHeatCapacity: 1000 J/kg/K; Béton, MassDensity: 2300 kg/m3; Béton, Embodied Energy: 1.92 (MJ/kg); Béton, Embodied Carbon: 0.198 (kgCO₂/kg); Béton, Name: Béton; Béton, Participates in Collision Detection: yes

# IfcFlowTerminal: Empattement 2, Semelle filante:(100x30T):1404027
In: -2. Etage
Type - PredefinedType: WASHINGMACHINE
Classification: Fondation (Classification ARCHICAD); Lave-linge (Classification ARCHICAD); Material: Béton
Autre - Catégorie: Fondations; Famille: Semelle filante: (100x30T); Famille et type: Semelle filante: (100x30T); ID du type: Semelle filante: (100x30T); Type: Semelle filante: (100x30T)
Contraintes - Excentricité: 0 m
Cotes - Elévation à la base: -3.6 m; Elévation en haut: -3.3 m; Etude de l'élévation à la base: -3.6 m; Etude de l'élévation en haut: -3.3 m; Largeur: 1 m; Longueur: 0.938704 m; Surface: 1.74751 m2; Volume: 0.399253 m3
Données d'identification - Commentaires: SF12; Identifiant: SC 43; IdGtcParameter: 27092
Phase de construction - Phase de création: Nouvelle construction
Structure - Activer le modèle analytique: yes; Enrobage d'armature - Autres faces: Paramètres de l'enrobage d'armature: Enrobage d'armature 1; Enrobage d'armature - Face inférieure: Paramètres de l'enrobage d'armature: Enrobage d'armature 1; Enrobage d'armature - Face supérieure: Paramètres de l'enrobage d'armature: Enrobage d'armature 1
Texte - CLASSE BETON: C25/30; RATIOS: 35kg/m3
Autre(Type) - Catégorie: Fondations; Nom de la famille: Semelle filante
Cotes(Type) - Longueur de l'extension de fin par défaut: 0 m; Ne pas couper aux insertions: yes; Epaisseur de fondation: 0.3 m; Largeur: 1 m
Données d'identification(Type) - Nom du type: (100x30T)
Structure(Type) - Utilisation structurelle: Porteur
AC_Pset_RenovationAndPhasing - Renovation Status: Existing
Material Properties - Béton, ThermalConductivity: 2.3; Béton, SpecificHeatCapacity: 1000 J/kg/K; Béton, MassDensity: 2300 kg/m3; Béton, Embodied Energy: 1.92 (MJ/kg); Béton, Embodied Carbon: 0.198 (kgCO₂/kg); Béton, Name: Béton; Béton, Participates in Collision Detection: yes

# IfcFlowTerminal: Empattement 4, Semelle filante:(50x50T) ex:1426913
In: -2. Etage
Type - PredefinedType: WASHINGMACHINE
Classification: Fondation (Classification ARCHICAD); Lave-linge (Classification ARCHICAD); Material: Béton
Autre - Catégorie: Fondations; Famille: Semelle filante: (50x50T) ex; Famille et type: Semelle filante: (50x50T) ex; ID du type: Semelle filante: (50x50T) ex; Type: Semelle filante: (50x50T) ex
Cotes - Elévation à la base: -3.8 m; Elévation en haut: -3.3 m; Etude de l'élévation à la base: -3.8 m; Etude de l'élévation en haut: -3.3 m; Largeur: 0.5 m; Longueur: 20.8507 m; Surface: 10.2714 m2; Volume: 5.05321 m3
Données d'identification - Commentaires: SF3
Phase de construction - Phase de création: Nouvelle construction
Structure - Activer le modèle analytique: yes; Enrobage d'armature - Autres faces: Paramètres de l'enrobage d'armature: Enrobage d'armature 1; Enrobage d'armature - Face inférieure: Paramètres de l'enrobage d'armature: Enrobage d'armature 1; Enrobage d'armature - Face supérieure: Paramètres de l'enrobage d'armature: Enrobage d'armature 1
Texte - CLASSE BETON: C25/30; RATIOS: 70kg/m3
Autre(Type) - Catégorie: Fondations; Nom de la famille: Semelle filante
Cotes(Type) - Largeur côté extérieur: 0 m; Longueur de l'extension de fin par défaut: 0 m; Ne pas couper aux insertions: yes; Epaisseur de fondation: 0.5 m; Largeur côté intérieur: 0.25 m
Données d'identification(Type) - Nom du type: (50x50T) ex
Structure(Type) - Utilisation structurelle: Soutènement
AC_Pset_RenovationAndPhasing - Renovation Status: Existing
Material Properties - Béton, ThermalConductivity: 2.3; Béton, SpecificHeatCapacity: 1000 J/kg/K; Béton, MassDensity: 2300 kg/m3; Béton, Embodied Energy: 1.92 (MJ/kg); Béton, Embodied Carbon: 0.198 (kgCO₂/kg); Béton, Name: Béton; Béton, Participates in Collision Detection: yes

# IfcFlowTerminal: Empattement 5, Semelle filante:(50x50T) ex:1426924
In: -2. Etage
Type - PredefinedType: WASHINGMACHINE
Classification: Fondation (Classification ARCHICAD); Lave-linge (Classification ARCHICAD); Material: Béton
Autre - Catégorie: Fondations; Famille: Semelle filante: (50x50T) ex; Famille et type: Semelle filante: (50x50T) ex; ID du type: Semelle filante: (50x50T) ex; Type: Semelle filante: (50x50T) ex
Cotes - Elévation à la base: -3.8 m; Elévation en haut: -3.3 m; Etude de l'élévation à la base: -3.8 m; Etude de l'élévation en haut: -3.3 m; Largeur: 0.55 m; Longueur: 5.38799 m; Surface: 2.6884 m2; Volume: 1.28659 m3
Données d'identification - Commentaires: SF3
Phase de construction - Phase de création: Nouvelle construction
Structure - Activer le modèle analytique: yes; Enrobage d'armature - Autres faces: Paramètres de l'enrobage d'armature: Enrobage d'armature 1; Enrobage d'armature - Face inférieure: Paramètres de l'enrobage d'armature: Enrobage d'armature 1; Enrobage d'armature - Face supérieure: Paramètres de l'enrobage d'armature: Enrobage d'armature 1
Texte - CLASSE BETON: C25/30; RATIOS: 70kg/m3
Autre(Type) - Catégorie: Fondations; Nom de la famille: Semelle filante
Cotes(Type) - Largeur côté extérieur: 0 m; Longueur de l'extension de fin par défaut: 0 m; Ne pas couper aux insertions: yes; Epaisseur de fondation: 0.5 m; Largeur côté intérieur: 0.25 m
Données d'identification(Type) - Nom du type: (50x50T) ex
Structure(Type) - Utilisation structurelle: Soutènement
AC_Pset_RenovationAndPhasing - Renovation Status: Existing
Material Properties - Béton, ThermalConductivity: 2.3; Béton, SpecificHeatCapacity: 1000 J/kg/K; Béton, MassDensity: 2300 kg/m3; Béton, Embodied Energy: 1.92 (MJ/kg); Béton, Embodied Carbon: 0.198 (kgCO₂/kg); Béton, Name: Béton; Béton, Participates in Collision Detection: yes

# IfcFlowTerminal: Empattement 6, Semelle filante:(50x50T) ex:1539690
In: -2. Etage
Type - PredefinedType: WASHINGMACHINE
Classification: Fondation (Classification ARCHICAD); Lave-linge (Classification ARCHICAD); Material: Béton
Autre - Catégorie: Fondations; Famille: Semelle filante: (50x50T) ex; Famille et type: Semelle filante: (50x50T) ex; ID du type: Semelle filante: (50x50T) ex; Type: Semelle filante: (50x50T) ex
Cotes - Elévation à la base: -3.7 m; Elévation en haut: -3.2 m; Etude de l'élévation à la base: -3.7 m; Etude de l'élévation en haut: -3.2 m; Largeur: 0.5 m; Longueur: 1.5 m; Surface: 0.74375 m2; Volume: 0.3725 m3
Données d'identification - Commentaires: SF3
Phase de construction - Phase de création: Nouvelle construction
Structure - Activer le modèle analytique: yes; Enrobage d'armature - Autres faces: Paramètres de l'enrobage d'armature: Enrobage d'armature 1; Enrobage d'armature - Face inférieure: Paramètres de l'enrobage d'armature: Enrobage d'armature 1; Enrobage d'armature - Face supérieure: Paramètres de l'enrobage d'armature: Enrobage d'armature 1
Autre(Type) - Catégorie: Fondations; Nom de la famille: Semelle filante
Cotes(Type) - Largeur côté extérieur: 0 m; Longueur de l'extension de fin par défaut: 0 m; Ne pas couper aux insertions: yes; Epaisseur de fondation: 0.5 m; Largeur côté intérieur: 0.25 m
Données d'identification(Type) - Nom du type: (50x50T) ex
Structure(Type) - Utilisation structurelle: Soutènement
AC_Pset_RenovationAndPhasing - Renovation Status: Existing
Material Properties - Béton, ThermalConductivity: 2.3; Béton, SpecificHeatCapacity: 1000 J/kg/K; Béton, MassDensity: 2300 kg/m3; Béton, Embodied Energy: 1.92 (MJ/kg); Béton, Embodied Carbon: 0.198 (kgCO₂/kg); Béton, Name: Béton; Béton, Participates in Collision Detection: yes

# IfcFlowTerminal: Empattement 7, Semelle filante:(50x50T):1466518
In: -2. Etage
Type - PredefinedType: WASHINGMACHINE
Classification: Fondation (Classification ARCHICAD); Lave-linge (Classification ARCHICAD); Material: Béton
Autre - Catégorie: Fondations; Famille: Semelle filante: (50x50T); Famille et type: Semelle filante: (50x50T); ID du type: Semelle filante: (50x50T); Type: Semelle filante: (50x50T)
Contraintes - Excentricité: 0 m
Cotes - Elévation à la base: -3.8 m; Elévation en haut: -3.3 m; Etude de l'élévation à la base: -3.8 m; Etude de l'élévation en haut: -3.3 m; Largeur: 0.5 m; Longueur: 4.60913 m; Surface: 2.01508 m2; Volume: 0.847994 m3
Phase de construction - Phase de création: Nouvelle construction
Structure - Activer le modèle analytique: yes; Enrobage d'armature - Autres faces: Paramètres de l'enrobage d'armature: Enrobage d'armature 1; Enrobage d'armature - Face inférieure: Paramètres de l'enrobage d'armature: Enrobage d'armature 1; Enrobage d'armature - Face supérieure: Paramètres de l'enrobage d'armature: Enrobage d'armature 1
Texte - CLASSE BETON: C25/30; RATIOS: 35kg/m3
Autre(Type) - Catégorie: Fondations; Nom de la famille: Semelle filante
Cotes(Type) - Ne pas couper aux insertions: yes; Epaisseur de fondation: 0.5 m; Largeur: 0.5 m; Longueur de l'extension de fin par défaut: 0.5 m
Données d'identification(Type) - Nom du type: (50x50T)
Structure(Type) - Utilisation structurelle: Porteur
AC_Pset_RenovationAndPhasing - Renovation Status: Existing
Material Properties - Béton, ThermalConductivity: 2.3; Béton, SpecificHeatCapacity: 1000 J/kg/K; Béton, MassDensity: 2300 kg/m3; Béton, Embodied Energy: 1.92 (MJ/kg); Béton, Embodied Carbon: 0.198 (kgCO₂/kg); Béton, Name: Béton; Béton, Participates in Collision Detection: yes

# IfcFlowTerminal: Empattement 8, Semelle filante:(50x60T) ex:1598756
In: -2. Etage
Type - PredefinedType: WASHINGMACHINE
Classification: Fondation (Classification ARCHICAD); Lave-linge (Classification ARCHICAD); Material: Béton
Autre - Catégorie: Fondations; Famille: Semelle filante: (50x60T) ex; Famille et type: Semelle filante: (50x60T) ex; ID du type: Semelle filante: (50x60T) ex; Type: Semelle filante: (50x60T) ex
Cotes - Elévation à la base: -3.8 m; Elévation en haut: -3.2 m; Etude de l'élévation à la base: -3.8 m; Etude de l'élévation en haut: -3.2 m; Largeur: 0.5 m; Longueur: 7.53992 m; Surface: 3.89347 m2; Volume: 2.18608 m3
Données d'identification - Commentaires: SF4
Phase de construction - Phase de création: Nouvelle construction
Structure - Activer le modèle analytique: yes; Enrobage d'armature - Autres faces: Paramètres de l'enrobage d'armature: Enrobage d'armature 1; Enrobage d'armature - Face inférieure: Paramètres de l'enrobage d'armature: Enrobage d'armature 1; Enrobage d'armature - Face supérieure: Paramètres de l'enrobage d'armature: Enrobage d'armature 1
Autre(Type) - Catégorie: Fondations; Nom de la famille: Semelle filante
Cotes(Type) - Largeur côté extérieur: 0 m; Longueur de l'extension de fin par défaut: 0 m; Ne pas couper aux insertions: yes; Epaisseur de fondation: 0.6 m; Largeur côté intérieur: 0.25 m
Données d'identification(Type) - Nom du type: (50x60T) ex
Structure(Type) - Utilisation structurelle: Soutènement
AC_Pset_RenovationAndPhasing - Renovation Status: Existing
Material Properties - Béton, ThermalConductivity: 2.3; Béton, SpecificHeatCapacity: 1000 J/kg/K; Béton, MassDensity: 2300 kg/m3; Béton, Embodied Energy: 1.92 (MJ/kg); Béton, Embodied Carbon: 0.198 (kgCO₂/kg); Béton, Name: Béton; Béton, Participates in Collision Detection: yes

# IfcFlowTerminal: Empattement 9, Semelle filante:(50x60T) ex:1598811
In: -2. Etage
Type - PredefinedType: WASHINGMACHINE
Classification: Fondation (Classification ARCHICAD); Lave-linge (Classification ARCHICAD); Material: Béton
Autre - Catégorie: Fondations; Famille: Semelle filante: (50x60T) ex; Famille et type: Semelle filante: (50x60T) ex; ID du type: Semelle filante: (50x60T) ex; Type: Semelle filante: (50x60T) ex
Cotes - Elévation à la base: -3.8 m; Elévation en haut: -3.2 m; Etude de l'élévation à la base: -3.8 m; Etude de l'élévation en haut: -3.2 m; Largeur: 0.5 m; Longueur: 3.19219 m; Surface: 1.5946 m2; Volume: 0.979476 m3
Phase de construction - Phase de création: Nouvelle construction
Structure - Activer le modèle analytique: yes; Enrobage d'armature - Autres faces: Paramètres de l'enrobage d'armature: Enrobage d'armature 1; Enrobage d'armature - Face inférieure: Paramètres de l'enrobage d'armature: Enrobage d'armature 1; Enrobage d'armature - Face supérieure: Paramètres de l'enrobage d'armature: Enrobage d'armature 1
Autre(Type) - Catégorie: Fondations; Nom de la famille: Semelle filante
Cotes(Type) - Largeur côté extérieur: 0 m; Longueur de l'extension de fin par défaut: 0 m; Ne pas couper aux insertions: yes; Epaisseur de fondation: 0.6 m; Largeur côté intérieur: 0.25 m
Données d'identification(Type) - Nom du type: (50x60T) ex
Structure(Type) - Utilisation structurelle: Soutènement
AC_Pset_RenovationAndPhasing - Renovation Status: Existing
Material Properties - Béton, ThermalConductivity: 2.3; Béton, SpecificHeatCapacity: 1000 J/kg/K; Béton, MassDensity: 2300 kg/m3; Béton, Embodied Energy: 1.92 (MJ/kg); Béton, Embodied Carbon: 0.198 (kgCO₂/kg); Béton, Name: Béton; Béton, Participates in Collision Detection: yes

# IfcFlowTerminal: Gouttière 23 (4)
In: Etage
Type - PredefinedType: GULLYTRAP
Classification: Elément de construction (Classification ARCHICAD); Grille d'évacuation d'eau (Classification ARCHICAD)
Propriétés DCE - Numéro de LOT: LOT 06; Numéro article: L06.1.1.6
AC_Pset_RenovationAndPhasing - Renovation Status: Existing

# IfcFlowTerminal: Grille 23 (24)
Type - PredefinedType: GULLYTRAP
Classification: Grille d'évacuation d'eau (Classification ARCHICAD)
AC_Pset_RenovationAndPhasing - Renovation Status: Existing
Name | In | Description | Numéro de LOT | Numéro article
Grille acier galva 200x200 | Sous-sol | Grille de ventilation | LOT 17 | L17.2.6.1.1
Caniveau béton à grille galvanisée | Sous-sol | Caniveau grille galva | LOT 04 | L04.2.19.7.1
5 x Grille acier galva 30x30 | Sous-sol | Grille de ventilation | LOT 17 | L17.2.6.2.1
Grille acier galva 250x150 | Sous-sol | Grille de ventilation | LOT 17 | L17.2.6.1.3
Caniveau béton à grille galvanisée | Sous-sol | Caniveau grille galva | LOT 04 | L04.2.20.7.1
4 x MOB-005 | Sous-sol |  | LOT 04 | L04.2.7.2.1; L04.2.7.2.2
Caniveau à grille inox | Rez-de-chaussée | Caniveau grille inox | LOT 04 | L04.2.19.7.2
5 x Grille acier galva 30x30 | Rez-de-chaussée | Grille de ventilation | LOT 17 | L17.2.6.2.1
Grille acier galva 250x150 | Rez-de-chaussée | Grille de ventilation | LOT 17 | L17.2.6.1.3
3 x Grille acier galva 180x60 | Rez-de-chaussée | Grille de ventilation | LOT 17 | L17.2.6.1.2
Grille acier galva 30x30 | R+4 | Grille de ventilation | LOT 17 | L17.2.6.2.1

# IfcFlowTerminal: IFC Footing Extruded (39)
In: -2. Etage
Type - PredefinedType: WASHINGMACHINE
Classification: Fondation (Classification ARCHICAD); Lave-linge (Classification ARCHICAD); Material: Béton
Autre - Catégorie: Fondations
Phase de construction - Phase de création: Nouvelle construction
Structure - Activer le modèle analytique: yes; Enrobage d'armature - Autres faces: Paramètres de l'enrobage d'armature: Enrobage d'armature 1; Enrobage d'armature - Face inférieure: Paramètres de l'enrobage d'armature: Enrobage d'armature 1; Enrobage d'armature - Face supérieure: Paramètres de l'enrobage d'armature: Enrobage d'armature 1
Autre(Type) - Catégorie: Fondations; Nom de la famille: Semelle filante
Cotes(Type) - Longueur de l'extension de fin par défaut: 0 m; Ne pas couper aux insertions: yes
AC_Pset_RenovationAndPhasing - Renovation Status: Existing
Material Properties - Béton, ThermalConductivity: 2.3; Béton, SpecificHeatCapacity: 1000 J/kg/K; Béton, MassDensity: 2300 kg/m3; Béton, Embodied Energy: 1.92 (MJ/kg); Béton, Embodied Carbon: 0.198 (kgCO₂/kg); Béton, Name: Béton; Béton, Participates in Collision Detection: yes
Name (Semelle filante:...) | Famille = Famille et type = ID du type = Type | Excentricité (m) | Elévation à la base (m) = Etude de l'élévation à la base (m) | Elévation en haut (m) = Etude de l'élévation en haut (m) | Cotes, Largeur (m) | Longueur (m) | Surface (m2) | Volume (m3) | Commentaires | Identifiant | IdGtcParameter | CLASSE BETON | RATIOS | Epaisseur de fondation (m) | Cotes(Type), Largeur (m) | Nom du type | Utilisation structurelle
(100x30T):1404040 | Semelle filante: (100x30T) | 0 | -3.6 | -3.3 | 1 | 1.79858 | 0.296762 | 0.0890287 | SF12 | SC 44 | 27124 | C25/30 | 35kg/m3 | 0.3 | 1 | (100x30T) | Porteur
(130x35T):1402918 | Semelle filante: (130x35T) | 0 | -3.65 | -3.3 | 1.3 | 5.2 | 6.3225 | 2.21287 | SF8 | SC 16 | 26228 | C25/30 | 35kg/m3 | 0.35 | 1.3 | (130x35T) | Porteur
(130x35T):1405857 | Semelle filante: (130x35T) | 0 | -3.65 | -3.3 | 1.3 | 2.76141 | 3.58983 | 1.25644 | SF8 | SC 46 | 27188 | C25/30 | 50kg/m3 | 0.35 | 1.3 | (130x35T) | Porteur
(160x45T):1403203 | Semelle filante: (160x45T) | 0 | -3.75 | -3.3 | 1.6 | 5.20235 | 9.20376 | 4.14169 | SF5 | SC 19 | 26324 | C25/30 | 35kg/m3 | 0.45 | 1.6 | (160x45T) | Porteur
(160x45T):1403427 | Semelle filante: (160x45T) | 0 | -3.75 | -3.3 | 1.6 | 10.8272 | 17.186 | 7.7337 | SF5 | SC 24 | 26484 | C25/30 | 35kg/m3 | 0.45 | 1.6 | (160x45T) | Porteur
(50x25T):1404008 | Semelle filante: (50x25T) | 0 | -3.55 | -3.3 | 0.5 | 3.1273 | 1.65114 | 0.412784 | SF10 | SC 41 | 27028 | C25/30 | 35kg/m3 | 0.25 | 0.5 | (50x25T) | Porteur
(70x25T):1403159 | Semelle filante: (70x25T) | 0 | -3.55 | -3.3 | 0.7 | 5.2 | 3.955 | 0.98875 | SF9 | SC 17 | 26260 | C25/30 | 35kg/m3 | 0.25 | 0.7 | (70x25T) | Porteur
(70x25T):1403297 | Semelle filante: (70x25T) | 0 | -3.55 | -3.3 | 0.7 | 2.66188 | 2.17832 | 0.544579 | SF9 | SC 20 | 26356 | C25/30 | 35kg/m3 | 0.25 | 0.7 | (70x25T) | Porteur
(70x25T):1403310 | Semelle filante: (70x25T) | 0 | -3.55 | -3.3 | 0.7 | 2.66862 | 1.37782 | 0.344454 | SF9 | SC 21 | 26388 | C25/30 | 35kg/m3 | 0.25 | 0.7 | (70x25T) | Porteur
(70x30T):1403837 | Semelle filante: (70x30T) | 0 | -3.6 | -3.3 | 0.7 | 5.60396 | 3.45924 | 1.03777 | SF7 | SC 27 | 26580 | C25/30 | 35kg/m3 | 0.3 | 0.7 | (70x30T) | Porteur
(70x30T):1403850 | Semelle filante: (70x30T) | 0 | -3.6 | -3.3 | 0.7 | 2.27208 | 1.33288 | 0.399864 | SF7 | SC 28 | 26612 | C25/30 | 35kg/m3 | 0.3 | 0.7 | (70x30T) | Porteur
(70x30T):1403876 | Semelle filante: (70x30T) | 0 | -3.6 | -3.3 | 0.7 | 2.42 | 1.869 | 0.5607 | SF7 | SC 30 | 26676 | C25/30 | 35kg/m3 | 0.3 | 0.7 | (70x30T) | Porteur
(90x30T):1403188 | Semelle filante: (90x30T) | 0 | -3.6 | -3.3 | 0.9 | 10.7 | 10.125 | 3.0375 | SF6 | SC 18 | 26292 | C25/30 | 35kg/m3 | 0.3 | 0.9 | (90x30T) | Porteur
(90x30T):1403809 | Semelle filante: (90x30T) | 0 | -3.6 | -3.3 | 0.9 | 4.18594 | 4.08235 | 1.2247 | SF6 | SC 25 | 26516 | C25/30 | 35kg/m3 | 0.3 | 0.9 | (90x30T) | Porteur
(90x30T):1403822 | Semelle filante: (90x30T) | 0 | -3.6 | -3.3 | 0.9 | 2.7 | 2.34 | 0.702 | SF6 | SC 26 | 26548 | C25/30 | 35kg/m3 | 0.3 | 0.9 | (90x30T) | Porteur
(90x30T):1420978 | Semelle filante: (90x30T) | 0 | -3.6 | -3.3 | 0.9 | 2.93339 | 2.42115 | 0.726345 | SF6 |  |  | C25/30 | 35kg/m3 | 0.3 | 0.9 | (90x30T) | Porteur
(90x30T):1420987 | Semelle filante: (90x30T) | 0 | -3.6 | -3.3 | 0.9 | 3.25297 | 2.55241 | 0.765723 | SF6 |  |  | C25/30 | 35kg/m3 | 0.3 | 0.9 | (90x30T) | Porteur
(100x30T):1542379 | Semelle filante: (100x30T) | 0 | -3.6 | -3.3 | 1 | 4.4597 | 4.87839 | 1.46352 | SF12 |  |  |  |  | 0.3 | 1 | (100x30T) | Porteur
(100x30T):1542396 | Semelle filante: (100x30T) | 0 | -3.6 | -3.3 | 1 | 4.99994 | 5.39994 | 1.61998 | SF12 |  |  |  |  | 0.3 | 1 | (100x30T) | Porteur
(100x30T):1542430 | Semelle filante: (100x30T) | 0 | -3.6 | -3.3 | 1 | 8.3467 | 8.0058 | 2.40174 | SF12 |  |  |  |  | 0.3 | 1 | (100x30T) | Porteur
(50x50T) ex:1402805 | Semelle filante: (50x50T) ex |  | -3.8 | -3.3 | 0.5 | 15.5031 | 7.93057 | 3.96529 | SF3 | SC 8 | 25972 | C25/30 | 70kg/m3 | 0.5 |  | (50x50T) ex | Soutènement | Cotes(Type) - Largeur côté extérieur: 0 m; Largeur côté intérieur: 0.25 m
(50x50T) ex:1402814 | Semelle filante: (50x50T) ex |  | -3.8 | -3.3 | 0.5 | 3.95631 | 1.62011 | 0.810056 | SF3 | SC 9 | 26004 | C25/30 | 70kg/m3 | 0.5 |  | (50x50T) ex | Soutènement | Cotes(Type) - Largeur côté extérieur: 0 m; Largeur côté intérieur: 0.25 m
(50x50T) ex:1402823 | Semelle filante: (50x50T) ex |  | -3.8 | -3.3 | 0.55 | 1.63978 | 0.826879 | 0.41344 | SF3 | SC 10 | 26036 | C25/30 | 70kg/m3 | 0.5 |  | (50x50T) ex | Soutènement | Cotes(Type) - Largeur côté extérieur: 0 m; Largeur côté intérieur: 0.25 m
(50x50T) ex:1402856 | Semelle filante: (50x50T) ex |  | -3.8 | -3.3 | 0.5 | 9.46665 | 4.73333 | 2.36666 | SF3 | SC 13 | 26132 | C25/30 | 70kg/m3 | 0.5 |  | (50x50T) ex | Soutènement | Cotes(Type) - Largeur côté extérieur: 0 m; Largeur côté intérieur: 0.25 m
(50x50T) ex:1465981 | Semelle filante: (50x50T) ex |  | -3.7 | -3.2 | 0.5 | 4.46 | 2.13 | 1.065 | SF3 |  |  | C25/30 | 70kg/m3 | 0.5 |  | (50x50T) ex | Soutènement | Cotes(Type) - Largeur côté extérieur: 0 m; Largeur côté intérieur: 0.25 m
(50x50T) ex:1465995 | Semelle filante: (50x50T) ex |  | -3.7 | -3.2 | 0.5 | 1.265 | 0.7575 | 0.37875 | SF3 |  |  | C25/30 | 70kg/m3 | 0.5 |  | (50x50T) ex | Soutènement | Cotes(Type) - Largeur côté extérieur: 0 m; Largeur côté intérieur: 0.25 m
(70x25T):1545225 | Semelle filante: (70x25T) | 0 | -3.55 | -3.3 | 0.7 | 6.82578 | 4.60303 | 1.15076 | SF9 |  |  |  |  | 0.25 | 0.7 | (70x25T) | Porteur
(70x25T):1546529 | Semelle filante: (70x25T) | 0 | -3.55 | -3.3 | 0.7 | 0.896862 | 0.443304 | 0.110826 | SF9 |  |  |  |  | 0.25 | 0.7 | (70x25T) | Porteur
(70x60T) ex:1402454 | Semelle filante: (70x60T) ex |  | -3.9 | -3.3 | 0.7 | 14.0488 | 10.0442 | 6.02651 | SF1 | SC 1 | 25748 | C25/30 | 70kg/m3 | 0.6 |  | (70x60T) ex | Soutènement | Cotes(Type) - Largeur côté extérieur: 0 m; Largeur côté intérieur: 0.4 m
(70x60T) ex:1402495 | Semelle filante: (70x60T) ex |  | -3.9 | -3.3 | 0.7 | 12.6033 | 8.82229 | 5.29337 | SF1 | SC 2 | 25780 | C25/30 | 70kg/m3 | 0.6 |  | (70x60T) ex | Soutènement | Cotes(Type) - Largeur côté extérieur: 0 m; Largeur côté intérieur: 0.4 m
(70x60T) ex:1402508 | Semelle filante: (70x60T) ex |  | -3.9 | -3.3 | 0.7 | 5.31276 | 3.71893 | 2.23136 | SF1 | SC 3 | 25812 | C25/30 | 70kg/m3 | 0.6 |  | (70x60T) ex | Soutènement | Cotes(Type) - Largeur côté extérieur: 0 m; Largeur côté intérieur: 0.4 m
(70x60T) ex:1402517 | Semelle filante: (70x60T) ex |  | -3.9 | -3.3 | 0.7 | 19.2645 | 12.9952 | 7.79711 | SF1 | SC 4 | 25844 | C25/30 | 70kg/m3 | 0.6 |  | (70x60T) ex | Soutènement | Cotes(Type) - Largeur côté extérieur: 0 m; Largeur côté intérieur: 0.4 m
(70x60T) ex:1402526 | Semelle filante: (70x60T) ex |  | -3.9 | -3.3 | 0.7 | 16.9908 | 10.3572 | 6.21431 | SF1 | SC 5 | 25876 | C25/30 | 70kg/m3 | 0.6 |  | (70x60T) ex | Soutènement | Cotes(Type) - Largeur côté extérieur: 0 m; Largeur côté intérieur: 0.4 m
(80x30T):1542443 | Semelle filante: (80x30T) | 0 | -3.6 | -3.3 | 0.8 | 7.46247 | 5.69725 | 1.70918 | SF13 |  |  |  |  | 0.3 | 0.8 | (80x30T) | Porteur
(100x30T) ex:1597808 | Semelle filante: (100x30T) ex |  | -3.6 | -3.3 | 1 | 2.94235 | 2.38299 | 0.714896 | SF16 |  |  |  |  | 0.3 |  | (100x30T) ex | Soutènement | Cotes(Type) - Largeur côté extérieur: 0.4 m; Largeur côté intérieur: 0.4 m
(150x30T) ex:1597777 | Semelle filante: (150x30T) ex |  | -3.6 | -3.3 | 1.5 | 3.0006 | 4.50157 | 1.35047 | SF15 |  |  |  |  | 0.3 |  | (150x30T) ex | Soutènement | Cotes(Type) - Largeur côté extérieur: 0.9 m; Largeur côté intérieur: 0.4 m
(200x30T) ex:1542362 | Semelle filante: (200x30T) ex |  | -3.6 | -3.3 | 2 | 3.37679 | 7.74881 | 2.32464 | SF14 |  |  |  |  | 0.3 |  | (200x30T) ex | Soutènement | Cotes(Type) - Largeur côté extérieur: 1.4 m; Largeur côté intérieur: 0.4 m
(50x50T) ex:1539703 | Semelle filante: (50x50T) ex |  | -3.7 | -3.2 | 0.5 | 5.64822 | 2.57411 | 1.28705 | SF3 |  |  |  |  | 0.5 |  | (50x50T) ex | Soutènement | Cotes(Type) - Largeur côté extérieur: 0 m; Largeur côté intérieur: 0.25 m
(50x50T) ex:1542357 | Semelle filante: (50x50T) ex |  | -3.8 | -3.3 | 0.45 | 19.0858 | 8.70686 | 4.35343 | SF3 |  |  |  |  | 0.5 |  | (50x50T) ex | Soutènement | Cotes(Type) - Largeur côté extérieur: 0 m; Largeur côté intérieur: 0.25 m

# IfcFlowTerminal: Lanterneau plat 23, MOB-001
In: R+4
Type - PredefinedType: GULLYTRAP
Classification: Grille d'évacuation d'eau (Classification ARCHICAD)
Propriétés DCE - Numéro de LOT: LOT 07; Numéro article: L07.2.8
AC_Pset_RenovationAndPhasing - Renovation Status: Existing

# IfcFlowTerminal: Lavabo sur meuble 23 (41)
Classification: Lavabo (Classification ARCHICAD)
AC_Pset_RenovationAndPhasing - Renovation Status: Existing
Name | In
11 x MOB-002 | Rez-de-chaussée
11 x MOB-002 | R+1
11 x MOB-002 | R+2
6 x MOB-002 | R+3
2 x MOB-002 | R+4

# IfcFlowTerminal: Lave linge 23 (34)
Type - PredefinedType: WASHINGMACHINE
Classification: Lave-linge (Classification ARCHICAD)
AC_Pset_RenovationAndPhasing - Renovation Status: Existing
Name | In
10 x MOB-002 | Rez-de-chaussée
10 x MOB-002 | R+1
9 x MOB-002 | R+2
4 x MOB-002 | R+3
MOB-002 | R+4

# IfcFlowTerminal: Modèle arbre conceptuel 23 (19)
In: Rez-de-chaussée
Classification: Géométrie du site (Classification ARCHICAD); Terminal d'air (Classification ARCHICAD)
Propriétés DCE - Numéro de LOT: LOT 19
AC_Pset_RenovationAndPhasing - Renovation Status: Existing
Name | Description | Numéro article
4 x Prunus ceradifera | Arbres à hautes tiges | L19.2.5.4.1
Prunus avium | Arbres à hautes tiges | L19.2.5.4.1
2 x Carpinus caroliniana | Arbres à hautes tiges | L19.2.5.4.1
2 x Acer Japonicum | Arbres à hautes tiges | L19.2.5.4.1
10 x  | Arbuste | L19.2.5.4.2

# IfcFlowTerminal: Platine sortie VMC (3)
In: Etage
Classification: Terminal d'air (Classification ARCHICAD); Material: Métal - Acier inoxidable, Volume - Etude
Propriétés DCE - Numéro de LOT: LOT 07; Numéro article: L07.2.7.10
AC_Pset_RenovationAndPhasing - Renovation Status: Existing
Material Properties - Component 1, Métal - Acier inoxidable, ThermalConductivity: 17; Component 1, Métal - Acier inoxidable, SpecificHeatCapacity: 460 J/kg/K; Component 1, Métal - Acier inoxidable, MassDensity: 7900 kg/m3; Component 1, Métal - Acier inoxidable, Embodied Energy: 56.7 (MJ/kg); Component 1, Métal - Acier inoxidable, Embodied Carbon: 6.15 (kgCO₂/kg); Component 1, Métal - Acier inoxidable, Name: Métal - Acier inoxidable; Component 1, Métal - Acier inoxidable, Participates in Collision Detection: yes; Component 2, Volume - Etude, ThermalConductivity: 0; Component 2, Volume - Etude, SpecificHeatCapacity: 0 J/kg/K; Component 2, Volume - Etude, MassDensity: 0 kg/m3; Component 2, Volume - Etude, Embodied Energy: 0 (MJ/kg); Component 2, Volume - Etude, Embodied Carbon: 0 (kgCO₂/kg); Component 2, Volume - Etude, Name: Volume - Etude; Component 2, Volume - Etude, Participates in Collision Detection: yes

# IfcFlowTerminal: Platine ventilation gaine gaz (2)
In: R+4
Type - PredefinedType: GULLYTRAP
Classification: Grille d'évacuation d'eau (Classification ARCHICAD); Material: Métal - Acier inoxidable, Volume - Etude
Propriétés DCE - Numéro de LOT: LOT 07; Numéro article: L07.2.7.9
AC_Pset_RenovationAndPhasing - Renovation Status: Existing
Material Properties - Component 1, Métal - Acier inoxidable, ThermalConductivity: 17; Component 1, Métal - Acier inoxidable, SpecificHeatCapacity: 460 J/kg/K; Component 1, Métal - Acier inoxidable, MassDensity: 7900 kg/m3; Component 1, Métal - Acier inoxidable, Embodied Energy: 56.7 (MJ/kg); Component 1, Métal - Acier inoxidable, Embodied Carbon: 6.15 (kgCO₂/kg); Component 1, Métal - Acier inoxidable, Name: Métal - Acier inoxidable; Component 1, Métal - Acier inoxidable, Participates in Collision Detection: yes; Component 2, Volume - Etude, ThermalConductivity: 0; Component 2, Volume - Etude, SpecificHeatCapacity: 0 J/kg/K; Component 2, Volume - Etude, MassDensity: 0 kg/m3; Component 2, Volume - Etude, Embodied Energy: 0 (MJ/kg); Component 2, Volume - Etude, Embodied Carbon: 0 (kgCO₂/kg); Component 2, Volume - Etude, Name: Volume - Etude; Component 2, Volume - Etude, Participates in Collision Detection: yes

# IfcFlowTerminal: Poutre 1, CERES_POUTRE_BETON:(60x50T):1599258
In: -2. Etage
Type - PredefinedType: WASHINGMACHINE
Classification: Poutre (Classification ARCHICAD); Lave-linge (Classification ARCHICAD); Material: Béton
Pset_BeamCommon - Slope: 0 deg; Reference: (60x50T)
Autre - Catégorie: Ossature; Famille: CERES_POUTRE_BETON: (60x50T); Famille et type: CERES_POUTRE_BETON: (60x50T); ID du type: CERES_POUTRE_BETON: (60x50T); Type: CERES_POUTRE_BETON: (60x50T)
Contraintes - Décalage du niveau d'arrivée: 0 m; Décalage du niveau de départ: 0 m; Rotation de la section: 0 deg; Orientation: Normale; Elévation du niveau de référence: -3.3 m; Niveau de référence: Niveau: fond; Plan de construction: Niveau : fond
Cotes - Elévation à la base: -3.8 m; Elévation en haut: -3.3 m; Longueur: 7.1 m; Surface: 7.92156 m2; Volume: 2.05913 m3
Phase de construction - Phase de création: Nouvelle construction
Position géométrique - Etat de la jonction: Deux jonctions activées; Justification Y: Origine; Justification YZ: Uniforme; Justification Z: Haut; Valeur de décalage Y: 0 m; Valeur de décalage Z: 0 m
Structure - Activer le modèle analytique: yes; Enrobage d'armature - Autres faces: Paramètres de l'enrobage d'armature: Enrobage d'armature 1; Enrobage d'armature - Face inférieure: Paramètres de l'enrobage d'armature: Enrobage d'armature 1; Enrobage d'armature - Face supérieure: Paramètres de l'enrobage d'armature: Enrobage d'armature 1; Utilisation structurelle: Autre; Longueur de coupe: 7.01554 m
Texte - NOM DE LA POUTRE: Longrine
AC_Pset_RenovationAndPhasing - Renovation Status: Existing
Material Properties - Béton, ThermalConductivity: 2.3; Béton, SpecificHeatCapacity: 1000 J/kg/K; Béton, MassDensity: 2300 kg/m3; Béton, Embodied Energy: 1.92 (MJ/kg); Béton, Embodied Carbon: 0.198 (kgCO₂/kg); Béton, Name: Béton; Béton, Participates in Collision Detection: yes

# IfcFlowTerminal: Poutre 2, CERES_POUTRE_BETON:(60x50T):1599423
In: -2. Etage
Type - PredefinedType: WASHINGMACHINE
Classification: Poutre (Classification ARCHICAD); Lave-linge (Classification ARCHICAD); Material: Béton
Pset_BeamCommon - Slope: 0 deg; Reference: (60x50T)
Autre - Catégorie: Ossature; Famille: CERES_POUTRE_BETON: (60x50T); Famille et type: CERES_POUTRE_BETON: (60x50T); ID du type: CERES_POUTRE_BETON: (60x50T); Type: CERES_POUTRE_BETON: (60x50T)
Contraintes - Décalage du niveau d'arrivée: 0 m; Décalage du niveau de départ: 0 m; Rotation de la section: 0 deg; Orientation: Normale; Niveau de référence: Niveau: fond; Elévation du niveau de référence: -3.3 m; Plan de construction: Niveau : fond
Cotes - Elévation à la base: -3.8 m; Elévation en haut: -3.3 m; Longueur: 7.3 m; Surface: 8.22541 m2; Volume: 2.15081 m3
Phase de construction - Phase de création: Nouvelle construction
Position géométrique - Etat de la jonction: Deux jonctions activées; Justification Y: Origine; Justification YZ: Uniforme; Justification Z: Haut; Valeur de décalage Y: 0 m; Valeur de décalage Z: 0 m
Structure - Activer le modèle analytique: yes; Enrobage d'armature - Autres faces: Paramètres de l'enrobage d'armature: Enrobage d'armature 1; Enrobage d'armature - Face inférieure: Paramètres de l'enrobage d'armature: Enrobage d'armature 1; Enrobage d'armature - Face supérieure: Paramètres de l'enrobage d'armature: Enrobage d'armature 1; Utilisation structurelle: Autre; Longueur de coupe: 7.26727 m
Texte - NOM DE LA POUTRE: Longrine
AC_Pset_RenovationAndPhasing - Renovation Status: Existing
Material Properties - Béton, ThermalConductivity: 2.3; Béton, SpecificHeatCapacity: 1000 J/kg/K; Béton, MassDensity: 2300 kg/m3; Béton, Embodied Energy: 1.92 (MJ/kg); Béton, Embodied Carbon: 0.198 (kgCO₂/kg); Béton, Name: Béton; Béton, Participates in Collision Detection: yes

# IfcFlowTerminal: Poutre 3, CERES_POUTRE_BETON:(60x50T):1599436
In: -2. Etage
Type - PredefinedType: WASHINGMACHINE
Classification: Poutre (Classification ARCHICAD); Lave-linge (Classification ARCHICAD); Material: Béton
Pset_BeamCommon - Slope: 0 deg; Reference: (60x50T)
Autre - Catégorie: Ossature; Famille: CERES_POUTRE_BETON: (60x50T); Famille et type: CERES_POUTRE_BETON: (60x50T); ID du type: CERES_POUTRE_BETON: (60x50T); Type: CERES_POUTRE_BETON: (60x50T)
Contraintes - Décalage du niveau d'arrivée: 0 m; Décalage du niveau de départ: 0 m; Rotation de la section: 0 deg; Orientation: Normale; Niveau de référence: Niveau: fond; Elévation du niveau de référence: -3.3 m; Plan de construction: Niveau : fond
Cotes - Elévation à la base: -3.8 m; Elévation en haut: -3.3 m; Longueur: 7.6 m; Surface: 8.60082 m2; Volume: 2.25913 m3
Phase de construction - Phase de création: Nouvelle construction
Position géométrique - Etat de la jonction: Deux jonctions activées; Justification Y: Origine; Justification YZ: Uniforme; Justification Z: Haut; Valeur de décalage Y: 0 m; Valeur de décalage Z: 0 m
Structure - Activer le modèle analytique: yes; Enrobage d'armature - Autres faces: Paramètres de l'enrobage d'armature: Enrobage d'armature 1; Enrobage d'armature - Face inférieure: Paramètres de l'enrobage d'armature: Enrobage d'armature 1; Enrobage d'armature - Face supérieure: Paramètres de l'enrobage d'armature: Enrobage d'armature 1; Utilisation structurelle: Autre; Longueur de coupe: 7.59207 m
Texte - NOM DE LA POUTRE: Longrine
AC_Pset_RenovationAndPhasing - Renovation Status: Existing
Material Properties - Béton, ThermalConductivity: 2.3; Béton, SpecificHeatCapacity: 1000 J/kg/K; Béton, MassDensity: 2300 kg/m3; Béton, Embodied Energy: 1.92 (MJ/kg); Béton, Embodied Carbon: 0.198 (kgCO₂/kg); Béton, Name: Béton; Béton, Participates in Collision Detection: yes

# IfcFlowTerminal: Poutre 4, CERES_POUTRE_BETON:(60x50T):1599914
In: -2. Etage
Type - PredefinedType: WASHINGMACHINE
Classification: Poutre (Classification ARCHICAD); Lave-linge (Classification ARCHICAD); Material: Béton
Pset_BeamCommon - Slope: 0 deg; Reference: (60x50T)
Autre - Catégorie: Ossature; Famille: CERES_POUTRE_BETON: (60x50T); Famille et type: CERES_POUTRE_BETON: (60x50T); ID du type: CERES_POUTRE_BETON: (60x50T); Type: CERES_POUTRE_BETON: (60x50T)
Contraintes - Décalage du niveau d'arrivée: 0 m; Décalage du niveau de départ: 0 m; Rotation de la section: 0 deg; Orientation: Normale; Niveau de référence: Niveau: fond; Elévation du niveau de référence: -3.3 m; Plan de construction: Niveau : fond
Cotes - Elévation à la base: -3.8 m; Elévation en haut: -3.3 m; Longueur: 4.7 m; Surface: 5.24767 m2; Volume: 1.32534 m3
Phase de construction - Phase de création: Nouvelle construction
Position géométrique - Etat de la jonction: Deux jonctions activées; Justification Y: Origine; Justification YZ: Uniforme; Justification Z: Haut; Valeur de décalage Y: 0 m; Valeur de décalage Z: 0 m
Structure - Activer le modèle analytique: yes; Enrobage d'armature - Autres faces: Paramètres de l'enrobage d'armature: Enrobage d'armature 1; Enrobage d'armature - Face inférieure: Paramètres de l'enrobage d'armature: Enrobage d'armature 1; Enrobage d'armature - Face supérieure: Paramètres de l'enrobage d'armature: Enrobage d'armature 1; Utilisation structurelle: Autre; Longueur de coupe: 4.58784 m
Texte - NOM DE LA POUTRE: Longrine
AC_Pset_RenovationAndPhasing - Renovation Status: Existing
Material Properties - Béton, ThermalConductivity: 2.3; Béton, SpecificHeatCapacity: 1000 J/kg/K; Béton, MassDensity: 2300 kg/m3; Béton, Embodied Energy: 1.92 (MJ/kg); Béton, Embodied Carbon: 0.198 (kgCO₂/kg); Béton, Name: Béton; Béton, Participates in Collision Detection: yes

# IfcFlowTerminal: Socle sortie VMC (12)
In: R+4
Type - PredefinedType: GULLYTRAP
Classification: Grille d'évacuation d'eau (Classification ARCHICAD); Material: Etanchéité - Bitume
Propriétés DCE - Numéro de LOT: LOT 04; LOT 07; Numéro article: L04.2.17.2; L07.2.7.6
AC_Pset_RenovationAndPhasing - Renovation Status: Existing
Material Properties - Etanchéité - Bitume, ThermalConductivity: 0.23; Etanchéité - Bitume, SpecificHeatCapacity: 1000 J/kg/K; Etanchéité - Bitume, MassDensity: 1100 kg/m3; Etanchéité - Bitume, Embodied Energy: 2.86 (MJ/kg); Etanchéité - Bitume, Embodied Carbon: 0.066 (kgCO₂/kg); Etanchéité - Bitume, Name: Etanchéité - Bitume; Etanchéité - Bitume, Participates in Collision Detection: no

# IfcFlowTerminal: Sortie de ventilation toiture terrasse (5)
Type - PredefinedType: GULLYTRAP
Classification: Elément de construction (Classification ARCHICAD); Grille d'évacuation d'eau (Classification ARCHICAD); Material: Métal - Acier inoxidable
Propriétés DCE - Numéro de LOT: LOT 07; Numéro article: L07.2.7.2
AC_Pset_RenovationAndPhasing - Renovation Status: Existing
Material Properties - Métal - Acier inoxidable, ThermalConductivity: 17; Métal - Acier inoxidable, SpecificHeatCapacity: 460 J/kg/K; Métal - Acier inoxidable, MassDensity: 7900 kg/m3; Métal - Acier inoxidable, Embodied Energy: 56.7 (MJ/kg); Métal - Acier inoxidable, Embodied Carbon: 6.15 (kgCO₂/kg); Métal - Acier inoxidable, Name: Métal - Acier inoxidable; Métal - Acier inoxidable, Participates in Collision Detection: yes
Name | In
2 x MOB-007 | R+4
3 x MOB-007 | Etage

# IfcFlowTerminal: Texte 3D 23, MOB-006
In: Rez-de-chaussée
Type - ElementType: GAS_TERMINAL; PredefinedType: USERDEFINED
Classification: Terminal de gaz (Classification ARCHICAD)
AC_Pset_RenovationAndPhasing - Renovation Status: Existing

# IfcFlowTerminal: Tube évidé 23 (5)
In: Rez-de-chaussée
Type - ElementType: GAS_TERMINAL; PredefinedType: USERDEFINED
AC_Pset_RenovationAndPhasing - Renovation Status: Existing
Name | Classification
3 x MOB-003 | Terminal de gaz (Classification ARCHICAD); Terminal d'air (Classification ARCHICAD)
MOB-003 | Terminal de gaz (Classification ARCHICAD); Elément de construction (Classification ARCHICAD)
MOB-003 | Terminal de gaz (Classification ARCHICAD)

# IfcFlowTerminal: Tuyau descente 23 (19)
Type - PredefinedType: GULLYTRAP
Classification: Elément de construction (Classification ARCHICAD); Grille d'évacuation d'eau (Classification ARCHICAD)
Propriétés DCE - Numéro de LOT: LOT 06; Numéro article: L06.2.2.1
AC_Pset_RenovationAndPhasing - Renovation Status: Existing
Name | In
5 x MOB-006 | Rez-de-chaussée
5 x MOB-006 | R+1
3 x MOB-006 | R+2
3 x MOB-006 | R+3
3 x MOB-006 | R+4

# IfcFlowTerminal: WC 23 (40)
Type - PredefinedType: TOILETPAN
Classification: Toilettes (Classification ARCHICAD)
AC_Pset_RenovationAndPhasing - Renovation Status: Existing
Name | In
11 x MOB-002 | Rez-de-chaussée
11 x MOB-002 | R+1
11 x MOB-002 | R+2
5 x MOB-002 | R+3
2 x MOB-002 | R+4

# IfcFurnishingElement: Casiers 23 (2)
In: Rez-de-chaussée
Type - ElementType: SYSTEM_FURNITURE
Classification: Elément d'ameublement (Classification ARCHICAD)
Propriétés DCE - Numéro de LOT: LOT 12; Numéro article: L12.1.2.3.1
AC_Pset_RenovationAndPhasing - Renovation Status: Existing

# IfcFurnishingElement: Lit double 23 (35)
Type - ElementType: BED
Classification: Lit (Classification ARCHICAD)
AC_Pset_RenovationAndPhasing - Renovation Status: Existing
Name | In
11 x MOB-002 | Rez-de-chaussée
11 x MOB-002 | R+1
8 x MOB-002 | R+2
5 x MOB-002 | R+3

# IfcFurnishingElement: Miroir 23 (2)
In: Rez-de-chaussée
Type - ElementType: SYSTEM_FURNITURE
Classification: Elément d'ameublement (Classification ARCHICAD)
Propriétés DCE - Numéro de LOT: LOT 12; Numéro article: L12.1.2.3.3
AC_Pset_RenovationAndPhasing - Renovation Status: Existing

# IfcMember: Béton D300 (4)
Type - ElementType: STAIR_STRUCTURE; PredefinedType: USERDEFINED
Classification: Structure d'escalier (Classification ARCHICAD); Material: Béton
AC_Pset_RenovationAndPhasing - Renovation Status: Existing
Pset_MemberCommon - LoadBearing: yes
Material Properties - Béton, ThermalConductivity: 2.3; Béton, SpecificHeatCapacity: 1000 J/kg/K; Béton, MassDensity: 2300 kg/m3; Béton, Embodied Energy: 1.92 (MJ/kg); Béton, Embodied Carbon: 0.198 (kgCO₂/kg); Béton, Name: Béton; Béton, Participates in Collision Detection: yes
BaseQuantities - Width: 0.3 m; Depth: 0.3 m; CrossSectionArea: 0.0706858 m2
Name | In | Numéro de LOT | Length (m) | OuterSurfaceArea (m2) | TotalSurfaceArea (m2) = GrossSurfaceArea (m2) | GrossVolume (m3) = NetVolume (m3)
Pot-001 | R+1 | LOT 04 | 2.72 | 2.55816 | 2.69835 | 0.190656
Pot-001 | R+2 | LOT 04 | 2.72 | 2.55816 | 2.69835 | 0.190656
Pot-001 | R+3 | LOT 04 | 1.05 | 0.987527 | 1.12771 | 0.0735988
Pot-001 | Rez-de-chaussée |  | 2.72 | 2.55816 | 2.69835 | 0.190656

# IfcOpeningElement (451)
Name | In | Height (m) | Width (m) | Depth (m) | Area (m2) | Volume (m3)
PERCEMENT-002 | Sous-sol | 0.2 | 0.3 | 0.215 | 0.06 | 0.0129 | Classification: Réservation (Classification ARCHICAD); AC_Pset_RenovationAndPhasing - Renovation Status: Existing
PERCEMENT-002 | Sous-sol | 0.3 | 0.3 | 0.2 | 0.09 | 0.009 | Classification: Réservation (Classification ARCHICAD); AC_Pset_RenovationAndPhasing - Renovation Status: Existing
PERCEMENT-002 | Sous-sol | 0.3 | 0.3 | 0.2 | 0.09 | 0.018 | Classification: Réservation (Classification ARCHICAD); AC_Pset_RenovationAndPhasing - Renovation Status: Existing
PERCEMENT-001 | Sous-sol | 0.2 | 2 | 0.2 | 0.4 | 0.08 | Classification: Réservation (Classification ARCHICAD); AC_Pset_RenovationAndPhasing - Renovation Status: Existing
PERCEMENT-002 | Sous-sol | 0.3 | 0.3 | 0.1 | 0.09 | 0.009 | Classification: Réservation (Classification ARCHICAD); AC_Pset_RenovationAndPhasing - Renovation Status: Existing
PERCEMENT-001 | Rez-de-chaussée | 1.25 | 2 | 0.215 | 2.5 | 0.5375 | Classification: Réservation (Classification ARCHICAD); AC_Pset_RenovationAndPhasing - Renovation Status: Existing
PERCEMENT-002 | Rez-de-chaussée | 0.3 | 0.3 | 0.215 | 0.09 | 0.01935 | Classification: Réservation (Classification ARCHICAD); AC_Pset_RenovationAndPhasing - Renovation Status: Existing
4 x PERCEMENT-002 | Rez-de-chaussée | 0.3 | 0.3 | 0.28 | 0.09 | 0.0252 | Classification: Réservation (Classification ARCHICAD); AC_Pset_RenovationAndPhasing - Renovation Status: Existing
PERCEMENT-002 | R+4 | 0.3 | 0.3 | 0.21 | 0.09 | 0.0189 | Classification: Réservation (Classification ARCHICAD); AC_Pset_RenovationAndPhasing - Renovation Status: Existing
7 x Porte 93x204 bois CF | Sous-sol | 2.085 | 1.02 | 0.2 | 2.1267 | 0.078912
17 x Porte 83x204 bois bâti métal | Sous-sol | 2.085 | 0.92 | 0.1 | 1.9182 | 0.070692
Porte acier 1V 93x204 | Sous-sol | 2.085 | 1.02 | 0.2 | 2.1267 | 0.078912
Porte acier 1V 93x204 | Sous-sol | 2.085 | 1.02 | 0.215 | 2.1267 | 0.078912
Porte acier motorisée 450x210 | Sous-sol | 2.1 | 4.5 | 0.215 | 9.45 | 0.344259
Por-002 | Rez-de-chaussée | 2.5 | 1.22491 | 0.074 | 3.06227 | 0.0587453
Por-002 | Rez-de-chaussée | 2.5 | 1.12896 | 0.074 | 2.82241 | 0.055
Porte 93x204 bois CF | Rez-de-chaussée | 2.085 | 1.02 | 0.2 | 2.1267 | 0.123678
11 x Porte 93x204 bois blindée | Rez-de-chaussée | 2.085 | 1.02 | 0.2 | 2.1267 | 0.123678
Por-002 | Rez-de-chaussée | 2.5 | 0.95 | 0.074 | 2.375 | 0.045
35 x Porte 83x204 bois alvéolaire | Rez-de-chaussée | 2.08 | 0.91 | 0.074 | 1.8928 | 0.0894884
MEN 30 | Rez-de-chaussée | 2.05 | 2.4 | 0.356439 | 5.01396 | 0.0981165
Por-002 | Rez-de-chaussée | 2.5 | 1.41779 | 0.074 | 3.54446 | 0.0683893
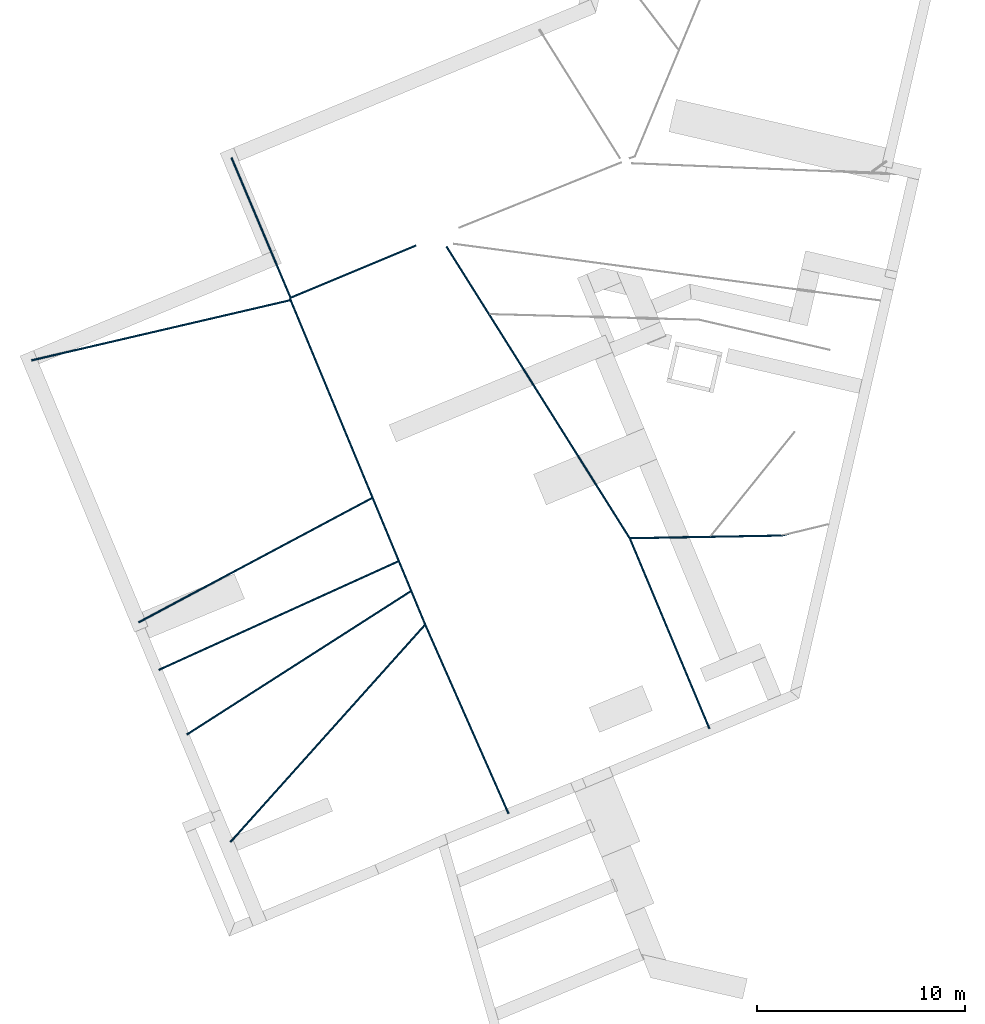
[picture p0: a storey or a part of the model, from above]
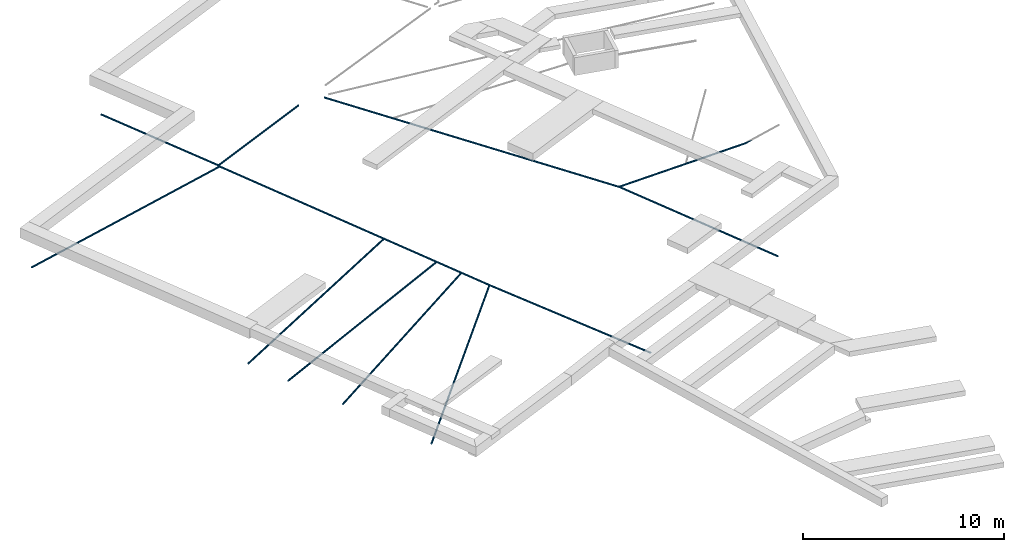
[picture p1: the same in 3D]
Properties of the parts of a building model (IFC2X3), part 5 of 22

# IfcOpeningElement (451)
Name | In | Height (m) | Width (m) | Depth (m) | Area (m2) | Volume (m3)
3 x Porte 120x204 bois alvéolaire | Rez-de-chaussée | 2.08 | 1.28 | 0.074 | 2.6624 | 0.0635616
Por-002 | Rez-de-chaussée | 2.5 | 0.949834 | 0.074 | 2.37458 | 0.0449917
Por-003 | Rez-de-chaussée | 2.5 | 0.967 | 0.074 | 2.4175 | 0.04585
2 x Por-002 | Rez-de-chaussée | 2.5 | 1.2 | 0.074 | 3 | 0.0575
Por-002 | Rez-de-chaussée | 2.5 | 1.064 | 0.074 | 2.66 | 0.0507
Por-002 | Rez-de-chaussée | 2.08 | 0.9 | 0.074 | 1.872 | 0.03468
Por-002 | Rez-de-chaussée | 2.08 | 1.036 | 0.074 | 2.15488 | 0.0402288
MEN 27 | Rez-de-chaussée | 2.05 | 2.4 | 0.356439 | 5.01396 | 0.0981165
MEN 28 | Rez-de-chaussée | 2.05 | 1 | 0.356439 | 2.05 | 0.058261
Porte 93x204 bois CF | Rez-de-chaussée | 2.085 | 1.02 | 0.22 | 2.1267 | 0.078912
MEN 03 | Rez-de-chaussée | 2.05 | 2.4 | 0.356439 | 4.92 | 0.0981165
MEN 15 | Rez-de-chaussée | 2.05 | 2.4 | 0.356439 | 4.92 | 0.0981165
MEN 16 | Rez-de-chaussée | 2.05 | 1.4 | 0.356439 | 2.87 | 0.0809674
MEN 14 | Rez-de-chaussée | 2.05 | 1.4 | 0.356439 | 2.87 | 0.0809674
MEN 13 | Rez-de-chaussée | 2.05 | 1.4 | 0.356439 | 2.87 | 0.0809674
MEN 31 | Rez-de-chaussée | 2.05 | 1 | 0.356439 | 2.08915 | 0.058261
Porte métal 2V 160x204 | Rez-de-chaussée | 2.08 | 1.68 | 0.225 | 3.4944 | 0.113361
Porte acier 1V 93x204 | Rez-de-chaussée | 2.085 | 1.02 | 0.28 | 2.1267 | 0.078912
Porte 93x204 bois CF | Rez-de-chaussée | 2.085 | 1.02 | 0.21 | 2.1267 | 0.078912
Porte 93x204 bois CF | Rez-de-chaussée | 2.085 | 1.02 | 0.22 | 2.1267 | 0.123678
Porte métal 2V 160x204 | Rez-de-chaussée | 2.08 | 1.68 | 0.2 | 3.4944 | 0.107601
MEN 19 | Rez-de-chaussée | 2.05 | 1.4 | 0.356439 | 2.87 | 0.0809674
MEN 18 | Rez-de-chaussée | 2.05 | 2.4 | 0.356439 | 4.92 | 0.0981165
MEN 17 | Rez-de-chaussée | 2.05 | 2.4 | 0.356439 | 4.92 | 0.0981165
MEN 12 | Rez-de-chaussée | 2.05 | 2.4 | 0.356439 | 4.92 | 0.0981165
MEN 11 | Rez-de-chaussée | 2.05 | 1.4 | 0.356439 | 2.87 | 0.0809674
MEN 10 | Rez-de-chaussée | 2.05 | 1 | 0.356439 | 2.05 | 0.058261
MEN 07 | Rez-de-chaussée | 2.05 | 1 | 0.356439 | 2.05 | 0.058261
MEN 08 | Rez-de-chaussée | 2.05 | 1 | 0.356439 | 2.05 | 0.058261
MEN 06 | Rez-de-chaussée | 2.05 | 2.4 | 0.356439 | 4.92 | 0.0981165
MEN 05 | Rez-de-chaussée | 2.05 | 1 | 0.356439 | 2.05 | 0.058261
MEN 04 | Rez-de-chaussée | 2.05 | 1 | 0.356439 | 2.05 | 0.058261
MEN 25 | Rez-de-chaussée | 2.1 | 0.9 | 0.345 | 1.89 | 0.065058
MEN 26 | Rez-de-chaussée | 2.1 | 0.9 | 0.345 | 1.89 | 0.065058
MEN 01 | Rez-de-chaussée | 2.05 | 2.4 | 0.356439 | 4.92 | 0.0981165
MEN 02 | Rez-de-chaussée | 2.05 | 1 | 0.356439 | 2.05 | 0.058261
MEN 29 | Rez-de-chaussée | 1.2 | 0.9 | 0.356439 | 1.08 | 0.0391674
3 x PERCEMENT-004 | Rez-de-chaussée | 0.6 | 1.8 | 0.21 | 1.08 | 0.2268 | AC_Pset_RenovationAndPhasing - Renovation Status: Existing
MEN 23 | Rez-de-chaussée | 2.05 | 2.4 | 0.345 | 4.92 | 0.0981165
MEN 22 | Rez-de-chaussée | 2.05 | 1 | 0.345 | 2.05 | 0.058261
MEN 24 | Rez-de-chaussée | 1.2 | 0.9 | 0.345 | 1.08 | 0.0391674
MEN 21 | Rez-de-chaussée | 2.05 | 1.4 | 0.356439 | 2.87 | 0.0809674
MEN 20 | Rez-de-chaussée | 2.05 | 2.4 | 0.356439 | 4.92 | 0.0981165
MEN 09 | Rez-de-chaussée | 2.05 | 1 | 0.356439 | 2.05 | 0.058261
Por-002 | Rez-de-chaussée | 2.08 | 1.35 | 0.074 | 2.808 | 0.05304
Por-002 | Rez-de-chaussée | 2.5 | 1.97807 | 0.074 | 4.94517 | 0.0964033
Por-003 | Rez-de-chaussée | 2.5 | 1.85002 | 0.074 | 4.62504 | 0.0900008
Por-002 | Rez-de-chaussée | 2.5 | 1.4 | 0.074 | 3.5 | 0.0675
Por-002 | Rez-de-chaussée | 2.5 | 2.125 | 0.074 | 5.3125 | 0.10375
11 x Porte 93x204 bois blindée | R+1 | 2.085 | 1.02 | 0.2 | 2.1267 | 0.123678
Por-002 | R+1 | 2.08 | 1.45 | 0.074 | 3.016 | 0.05712
39 x Porte 83x204 bois alvéolaire | R+1 | 2.08 | 0.91 | 0.074 | 1.8928 | 0.0894884
4 x Porte 120x204 bois alvéolaire | R+1 | 2.08 | 1.28 | 0.074 | 2.6624 | 0.0635616
MEN 42 | R+1 | 1.2 | 0.8 | 0.345 | 0.96 | 0.034786
MEN 50 | R+1 | 2.2 | 2.4 | 0.345 | 5.28 | 0.103149
MEN 51 | R+1 | 2.2 | 0.9 | 0.345 | 1.98 | 0.0625664
MEN 47 | R+1 | 2.2 | 2.4 | 0.345 | 5.28 | 0.103149
MEN 46 | R+1 | 2.1 | 0.9 | 0.345 | 1.89 | 0.0693171
MEN 48 | R+1 | 2.1 | 0.9 | 0.345 | 1.89 | 0.0693171
MEN 45 | R+1 | 2.1 | 0.9 | 0.345 | 1.89 | 0.0693171
MEN 43 | R+1 | 2.1 | 0.9 | 0.345 | 1.89 | 0.0693171
MEN 44 | R+1 | 2.2 | 2.4 | 0.345 | 5.28 | 0.103149
MEN 53 | R+1 | 2.1 | 0.9 | 0.345 | 1.89 | 0.0693171
MEN 52 | R+1 | 2.2 | 2.4 | 0.345 | 5.28 | 0.103149
MEN 41 | R+1 | 2.1 | 0.9 | 0.345 | 1.89 | 0.0693171
MEN 38 | R+1 | 2.2 | 2.4 | 0.345 | 5.28 | 0.103149
MEN 36 | R+1 | 2.1 | 0.9 | 0.345 | 1.89 | 0.0693171
MEN 37 | R+1 | 2.1 | 0.9 | 0.345 | 1.89 | 0.0693171
MEN 35 | R+1 | 2.2 | 2.4 | 0.345 | 5.28 | 0.103149
MEN 49 | R+1 | 2.2 | 2.4 | 0.345 | 5.28 | 0.103149
MEN 39 | R+1 | 2.1 | 0.9 | 0.345 | 1.89 | 0.0693171
MEN 63 | R+1 | 2.1 | 0.9 | 0.345 | 1.89 | 0.065058
MEN 62 | R+1 | 2.2 | 2.4 | 0.345 | 5.28 | 0.103149
MEN 57 | R+1 | 2.1 | 0.9 | 0.345 | 1.89 | 0.065058
MEN 58 | R+1 | 2.1 | 0.9 | 0.345 | 1.89 | 0.065058
Porte 93x204 bois CF | R+1 | 2.085 | 1.02 | 0.22 | 2.1267 | 0.123678
Por-002 | R+1 | 2.5 | 0.949834 | 0.074 | 2.37458 | 0.0449917
Porte 93x204 bois CF | R+1 | 2.085 | 1.02 | 0.2 | 2.1267 | 0.123678
Por-002 | R+1 | 2.5 | 1.35 | 0.074 | 3.375 | 0.065
Por-002 | R+1 | 2.5 | 1.2 | 0.074 | 3 | 0.0575
Por-002 | R+1 | 2.5 | 3.18475 | 0.074 | 7.96188 | 0.156738
Por-002 | R+1 | 2.5 | 1.39186 | 0.074 | 3.47966 | 0.0670932
MEN 54 | R+1 | 2.1 | 0.9 | 0.345 | 1.89 | 0.0693171
MEN 40 | R+1 | 1.2 | 1.2 | 0.345 | 1.44 | 0.0526044
MEN 32 | R+1 | 2.1 | 0.9 | 0.345 | 1.89 | 0.065058
Por-002 | R+1 | 2.08 | 0.9 | 0.074 | 1.872 | 0.03468
Por-002 | R+1 | 2.08 | 1.036 | 0.074 | 2.15488 | 0.0402288
Por-002 | R+1 | 2.5 | 2.125 | 0.074 | 5.3125 | 0.10375
Por-002 | R+1 | 2.5 | 1.064 | 0.074 | 2.66 | 0.0507
Por-003 | R+1 | 2.5 | 1.85002 | 0.074 | 4.62504 | 0.0900008
MEN 55 | R+1 | 2.2 | 2.4 | 0.345 | 5.28 | 0.103149
MEN 56 | R+1 | 2.2 | 0.9 | 0.345 | 1.98 | 0.0625664
MEN 59 | R+1 | 2.2 | 2.4 | 0.345 | 5.28 | 0.103149
MEN 60 | R+1 | 2.2 | 1 | 0.345 | 2.2 | 0.061666
MEN 61 | R+1 | 1.2 | 0.9 | 0.345 | 1.08 | 0.036876
MEN 33 | R+1 | 2.1 | 0.9 | 0.345 | 1.89 | 0.065058
MEN 34 | R+1 | 2.2 | 2.4 | 0.345 | 5.28 | 0.103149
Por-002 | R+1 | 2.08 | 1.4 | 0.074 | 2.912 | 0.05508
Por-002 | R+1 | 2.08 | 1.97807 | 0.074 | 4.11438 | 0.0786651
Por-002 | R+1 | 2.08 | 1.12896 | 0.074 | 2.34824 | 0.04488
Por-002 | R+1 | 2.08 | 0.95 | 0.074 | 1.976 | 0.03672
Por-003 | R+1 | 2.08 | 0.967 | 0.074 | 2.01136 | 0.0374136
37 x Porte 83x204 bois alvéolaire | R+2 | 2.08 | 0.91 | 0.074 | 1.8928 | 0.0894884
9 x Porte 93x204 bois blindée | R+2 | 2.085 | 1.02 | 0.2 | 2.1267 | 0.123678
MEN 92 | R+2 | 2.2 | 2.4 | 0.345 | 5.28 | 0.103149
MEN 93 | R+2 | 2.2 | 1 | 0.345 | 2.2 | 0.061666
MEN 94 | R+2 | 1.2 | 0.9 | 0.345 | 1.08 | 0.036876
MEN 65 | R+2 | 2.1 | 0.9 | 0.345 | 1.89 | 0.065058
MEN 66 | R+2 | 2.2 | 2.4 | 0.345 | 5.28 | 0.103149
MEN 67 | R+2 | 2.1 | 0.9 | 0.345 | 1.89 | 0.065058
MEN 64 | R+2 | 2.1 | 0.9 | 0.345 | 1.89 | 0.065058
MEN 68 | R+2 | 2.1 | 0.9 | 0.395 | 1.89 | 0.065058
MEN 69 | R+2 | 2.1 | 0.9 | 0.395 | 1.89 | 0.065058
MEN 70 | R+2 | 2.1 | 0.9 | 0.395 | 1.89 | 0.065058
MEN 95 | R+2 | 2.2 | 2.4 | 0.345 | 5.28 | 0.103149
3 x Porte 120x204 bois alvéolaire | R+2 | 2.08 | 1.28 | 0.074 | 2.6624 | 0.0635616
Porte 93x204 bois CF | R+2 | 2.085 | 1.02 | 0.2 | 2.1267 | 0.123678
MEN 72 | R+2 | 2 | 2.4 | 0.402689 | 4.824 | 0.096439
MEN 85 | R+2 | 2.1 | 0.9 | 0.345 | 1.89 | 0.065058
MEN 84 | R+2 | 2.1 | 0.9 | 0.345 | 1.89 | 0.065058
MEN 83 | R+2 | 2.1 | 0.9 | 0.345 | 1.89 | 0.065058
MEN 71 | R+2 | 2 | 2.4 | 0.402689 | 4.824 | 0.096439
MEN 88 | R+2 | 2 | 2.4 | 0.402689 | 4.824 | 0.0985035
MEN 89 | R+2 | 1.2 | 0.9 | 0.402689 | 1.08 | 0.0391674
MEN 78 | R+2 | 2.2 | 2.4 | 0.345 | 5.28 | 0.103149
MEN 77 | R+2 | 2.1 | 0.9 | 0.345 | 1.89 | 0.065058
MEN 79 | R+2 | 2.1 | 0.9 | 0.345 | 1.89 | 0.065058
MEN 76 | R+2 | 2.1 | 0.9 | 0.345 | 1.89 | 0.065058
MEN 86 | R+2 | 2.1 | 0.9 | 0.345 | 1.89 | 0.065058
MEN 87 | R+2 | 2 | 0.9 | 0.345 | 1.8 | 0.054636
MEN 96 | R+2 | 2.1 | 0.9 | 0.345 | 1.89 | 0.065058
MEN 74 | R+2 | 2.1 | 0.9 | 0.345 | 1.89 | 0.065058
MEN 75 | R+2 | 2.2 | 2.4 | 0.345 | 5.28 | 0.103149
MEN 81 | R+2 | 2.2 | 2.4 | 0.345 | 5.28 | 0.103149
MEN 82 | R+2 | 2.2 | 0.9 | 0.345 | 1.98 | 0.059076
MEN 80 | R+2 | 2.2 | 2.4 | 0.345 | 5.28 | 0.103149
MEN 73 | R+2 | 1.2 | 0.8 | 0.345 | 0.96 | 0.034786
Por-002 | R+2 | 2.08 | 1.25 | 0.074 | 2.6 | 0.04896
MEN 90 | R+2 | 2.1 | 0.9 | 0.345 | 1.89 | 0.065058
MEN 91 | R+2 | 2.1 | 0.9 | 0.345 | 1.89 | 0.065058
Porte 93x204 bois CF | R+2 | 2.085 | 1.02 | 0.22 | 2.1267 | 0.123678
Por-002 | R+2 | 2.08 | 1.45 | 0.074 | 3.016 | 0.05712
2 x Por-002 | R+2 | 2.08 | 1.4 | 0.074 | 2.912 | 0.05508
Por-002 | R+2 | 2.08 | 0.949834 | 0.074 | 1.97565 | 0.0367132
Por-004 | R+2 | 2.08 | 0.91 | 0.074 | 1.8928 | 0.0894884
Por-002 | R+2 | 2.08 | 1.97807 | 0.074 | 4.11438 | 0.0786651
Por-002 | R+2 | 2.08 | 0.95 | 0.074 | 1.976 | 0.03672
Por-003 | R+2 | 2.08 | 0.967 | 0.074 | 2.01136 | 0.0374136
Por-002 | R+2 | 2.08 | 1.12896 | 0.074 | 2.34824 | 0.04488
Por-002 | R+2 | 2.08 | 1.28 | 0.074 | 2.6624 | 0.0635616
Por-002 | R+2 | 2.08 | 1.87589 | 0.074 | 3.90186 | 0.0744965
18 x Porte 83x204 bois alvéolaire | R+3 | 2.08 | 0.91 | 0.074 | 1.8928 | 0.0894884
Por-003 | R+3 | 2.08 | 3.27631 | 0.074 | 6.81473 | 0.131633
5 x Porte 93x204 bois blindée | R+3 | 2.085 | 1.02 | 0.2 | 2.1267 | 0.123678
MEN 105 | R+3 | 1.2 | 0.8 | 0.395 | 0.96 | 0.034786
MEN 106 | R+3 | 2.1 | 0.9 | 0.345 | 1.89 | 0.065058
MEN 107 | R+3 | 2.2 | 2.4 | 0.345 | 5.28 | 0.103149
MEN 122 | R+3 | 2.1 | 0.9 | 0.345 | 1.89 | 0.065058
MEN 102 | R+3 | 2.1 | 0.9 | 0.395 | 1.89 | 0.065058
MEN 101 | R+3 | 2.1 | 0.7 | 0.395 | 1.47 | 0.057568
MEN 100 | R+3 | 2.1 | 0.9 | 0.395 | 1.89 | 0.065058
MEN 103 | R+3 | 2 | 2.4 | 0.402689 | 4.824 | 0.096439
MEN 112 | R+3 | 2.2 | 2.4 | 0.395 | 5.28 | 0.103149
MEN 113 | R+3 | 2 | 2.4 | 0.356439 | 4.86996 | 0.0985035
MEN 97 | R+3 | 2.1 | 0.9 | 0.345 | 1.89 | 0.065058
Porte 93x204 bois CF | R+3 | 2.085 | 1.02 | 0.22 | 2.1267 | 0.123678
MEN 108 | R+3 | 2.1 | 0.9 | 0.345 | 1.89 | 0.065058
Por-002 | R+3 | 2.08 | 3.32493 | 0.074 | 6.91585 | 0.136065
Porte 83x204 bois alvéolaire | R+3 | 2.08 | 0.91 | 0.2 | 1.8928 | 0.114638
Por-004 | R+3 | 2.08 | 1.872 | 0.074 | 3.89376 | 0.0743376
MEN 121 | R+3 | 2 | 2.4 | 0.356439 | 4.86996 | 0.096439
MEN 110 | R+3 | 2.2 | 2.4 | 0.345 | 5.28 | 0.103149
MEN 109 | R+3 | 2.1 | 0.9 | 0.345 | 1.89 | 0.065058
MEN 111 | R+3 | 2.1 | 0.9 | 0.345 | 1.89 | 0.065058
MEN 98 | R+3 | 2.1 | 0.9 | 0.395 | 1.89 | 0.065058
MEN 99 | R+3 | 2.2 | 2.4 | 0.395 | 5.28 | 0.103149
Por-002 | R+3 | 2.08 | 1.00874 | 0.074 | 2.09817 | 0.0391165
Por-002 | R+3 | 2.08 | 1.45 | 0.074 | 3.016 | 0.05712
Por-002 | R+3 | 2.08 | 1.4 | 0.074 | 2.912 | 0.05508
Porte 120x204 bois alvéolaire | R+3 | 2.08 | 1.28 | 0.074 | 2.6624 | 0.0635616
Por-002 | R+3 | 2.08 | 0.95 | 0.074 | 1.976 | 0.03672
Por-003 | R+3 | 2.08 | 0.967 | 0.074 | 2.01136 | 0.0374136
Por-002 | R+3 | 2.08 | 2.03589 | 0.074 | 4.23464 | 0.0810241
PERCEMENT-005 | R+3 | 0.25 | 0.25 | 0.215 | 0.0625 | 0.0134375 | AC_Pset_RenovationAndPhasing - Renovation Status: Existing
MEN 104 | R+3 | 2 | 0.9 | 0.402689 | 1.809 | 0.054636
Porte 83x204 bois alvéolaire | R+3 | 2.085 | 1.02 | 0.2 | 2.1267 | 0.123678
MEN 116 | R+3 | 1.2 | 0.9 | 0.358 | 1.08 | 0.036876
MEN 118 | R+3 | 1.2 | 0.9 | 0.358 | 1.08 | 0.036876
MEN 117 | R+3 | 1.2 | 2.8 | 0.358 | 3.36 | 0.07296
MEN 120 | R+3 | 2 | 2.8 | 0.358 | 5.84418 | 0.10112
MEN 119 | R+3 | 1.23 | 0.7 | 0.358 | 0.861 | 0.033332
MEN 114 | R+3 | 2 | 2.8 | 0.358 | 5.84418 | 0.10112
MEN 115 | R+3 | 1.23 | 0.7 | 0.358 | 0.861 | 0.033332
8 x Porte 83x204 bois alvéolaire | R+4 | 2.08 | 0.91 | 0.074 | 1.8928 | 0.0894884
Por-002 | R+4 | 2.08 | 2.32963 | 0.074 | 4.84563 | 0.093009
Por-002 | R+4 | 2.08 | 2.9385 | 0.074 | 6.11207 | 0.119075
Por-003 | R+4 | 2.08 | 2.32563 | 0.074 | 4.83731 | 0.0928458
PERCEMENT-002 | R+4 | 1 | 1 | 0.23 | 1 | 0.23 | AC_Pset_RenovationAndPhasing - Renovation Status: Existing
Por-002 | R+4 | 2.08 | 1.33618 | 0.074 | 2.77925 | 0.0524761
MEN 126 | R+4 | 2.1 | 0.9 | 0.31 | 1.89 | 0.0490215
MEN 125 | R+4 | 2.1 | 0.9 | 0.31 | 1.89 | 0.0490215
MEN 127 | R+4 | 1.2 | 0.8 | 0.31 | 0.96 | 0.0258142
MEN 124 | R+4 | 2.1 | 0.9 | 0.31 | 1.89 | 0.0490215
MEN 123 | R+4 | 2.1 | 0.7 | 0.31 | 1.47 | 0.0428719
MEN 128 | R+4 | 2.1 | 0.9 | 0.31 | 1.89 | 0.07275
MEN 133 | R+4 | 1.1 | 0.45 | 0.358 | 0.495 | 0.028776
MEN 134 | R+4 | 1.1 | 0.8 | 0.358 | 0.88 | 0.036616
MEN 129 | R+4 | 1.2 | 2.4 | 0.358 | 2.88 | 0.071998
MEN 130 | R+4 | 2 | 0.9 | 0.31 | 1.8 | 0.060996
MEN 131 | R+4 | 1.2 | 2.4 | 0.358 | 2.88 | 0.071998
MEN 132 | R+4 | 2 | 1.8 | 0.31 | 3.6 | 0.090379
MEN 135 | R+4 | 2 | 2.4 | 0.358 | 5.09466 | 0.100758
Por-003 | R+2 | 2.1 | 1.2 | 0.2 | 2.52 | 0
Ouverture de dalle | Sous-sol
4 x Ouverture de dalle | Rez-de-chaussée
3 x Ouverture de dalle | R+1
2 x Ouverture de dalle | R+2
Ouverture de dalle | R+3
5 x Ouverture de dalle | R+4

# IfcRailing: Type de garde-corps (46)
Classification: Garde-corps (Classification ARCHICAD)
AC_Pset_RenovationAndPhasing - Renovation Status: Existing
Name | In | Description | Material | Numéro de LOT | Numéro article | Component 1 in BARR-001 Poteau 1, 1, Métal - Acier, ThermalConductivity | Component 1 in BARR-001 Poteau 1, 1, Métal - Acier, SpecificHeatCapacity (J/kg/K) | Component 1 in BARR-001 Poteau 1, 1, Métal - Acier, MassDensity (kg/m3) | Component 1 in BARR-001 Poteau 1, 1, Métal - Acier, Embodied Energy | Component 1 in BARR-001 Poteau 1, 1, Métal - Acier, Embodied Carbon | Component 1 in BARR-001 Poteau 1, 1, Métal - Acier, Name | Component 1 in BARR-001 Poteau 1, 1, Métal - Acier, Participates in Collision Detection | Component 1 in BARR-001 Poteau 1, 1 | GrossVolume (m3) = NetVolume (m3) | Length (m)
Grille de clôture acier laqué | Rez-de-chaussée | Grille de clôture | Métal - Acier (78) | LOT 17 | L17.2.2.1 | 60 | 460 | 7800 | 25.1 (MJ/kg) | 1.66 (kgCO₂/kg) | Métal - Acier | yes | 78 with these values | 0.00742778 | 4.14982
Grille de clôture acier laqué | Rez-de-chaussée | Grille de clôture | Métal - Acier (190) | LOT 17 | L17.2.2.1 | 60 | 460 | 7800 | 25.1 (MJ/kg) | 1.66 (kgCO₂/kg) | Métal - Acier | yes | 190 with these values | 0.0172641 | 10.5473
Grille de clôture acier laqué | Rez-de-chaussée | Grille de clôture | Métal - Acier (277) | LOT 17 | L17.2.2.1 | 60 | 460 | 7800 | 25.1 (MJ/kg) | 1.66 (kgCO₂/kg) | Métal - Acier | yes | 277 with these values | 0.040991 | 14.3987
Grille de clôture acier laqué | Rez-de-chaussée | Grille de clôture | Métal - Acier (139) |  | L17.2.2.1 | 60 | 460 | 7800 | 25.1 (MJ/kg) | 1.66 (kgCO₂/kg) | Métal - Acier | yes | 139 with these values | 0.0169137 | 7.91086
Grille de clôture acier laqué | Rez-de-chaussée | Grille de clôture | Métal - Acier (243) | LOT 17 | L17.2.2.1 | 60 | 460 | 7800 | 25.1 (MJ/kg) | 1.66 (kgCO₂/kg) | Métal - Acier | yes | 243 with these values | 0.0291135 | 13.2859
Pare-vue acier laqué+verre dépoli H=90 | Rez-de-chaussée | Pare-vue métal et verre H=90 | Métal - Acier (15), Métal - Acier inoxidable (14), Vitrage (14) | LOT 17 | L17.2.3.2 | 60 | 460 | 7800 | 25.1 (MJ/kg) | 1.66 (kgCO₂/kg) | Métal - Acier | yes | 15 with these values | 0.238805 | 13.6862 | Material Properties - Component 1 in PANNEAU-001 Panneau 1, 1, Métal - Acier inoxidable, ThermalConductivity: 17; Component 1 in PANNEAU-001 Panneau 1, 1, Métal - Acier inoxidable, SpecificHeatCapacity: 460 J/kg/K; Component 1 in PANNEAU-001 Panneau 1, 1, Métal - Acier inoxidable, MassDensity: 7900 kg/m3; Component 1 in PANNEAU-001 Panneau 1, 1, Métal - Acier inoxidable, Embodied Energy: 56.7 (MJ/kg); Component 1 in PANNEAU-001 Panneau 1, 1, Métal - Acier inoxidable, Embodied Carbon: 6.15 (kgCO₂/kg); Component 1 in PANNEAU-001 Panneau 1, 1, Métal - Acier inoxidable, Name: Métal - Acier inoxidable; Component 1 in PANNEAU-001 Panneau 1, 1, Métal - Acier inoxidable, Participates in Collision Detection: yes; Component 2 in PANNEAU-001 Panneau 1, 1, Vitrage, ThermalConductivity: 1; Component 2 in PANNEAU-001 Panneau 1, 1, Vitrage, SpecificHeatCapacity: 750 J/kg/K; Component 2 in PANNEAU-001 Panneau 1, 1, Vitrage, MassDensity: 2500 kg/m3; Component 2 in PANNEAU-001 Panneau 1, 1, Vitrage, Embodied Energy: 15 (MJ/kg); Component 2 in PANNEAU-001 Panneau 1, 1, Vitrage, Embodied Carbon: 0.91 (kgCO₂/kg); Component 2 in PANNEAU-001 Panneau 1, 1, Vitrage, Name: Vitrage; Component 2 in PANNEAU-001 Panneau 1, 1, Vitrage, Participates in Collision Detection: no; Component 1 in PANNEAU-001 Panneau 1, 1: 14 with these values; Component 2 in PANNEAU-001 Panneau 1, 1: 14 with these values
Pare-vue acier laqué+verre dépoli H=190 | Rez-de-chaussée | Pare-vue métal et verre H=190 | Métal - Acier (5), Métal - Acier inoxidable (4), Vitrage (4) | LOT 17 | L17.2.3.1 | 60 | 460 | 7800 | 25.1 (MJ/kg) | 1.66 (kgCO₂/kg) | Métal - Acier | yes | 5 with these values | 0.135139 | 3.44665 | Material Properties - Component 1 in PANNEAU-001 Panneau 1, 1, Métal - Acier inoxidable, ThermalConductivity: 17; Component 1 in PANNEAU-001 Panneau 1, 1, Métal - Acier inoxidable, SpecificHeatCapacity: 460 J/kg/K; Component 1 in PANNEAU-001 Panneau 1, 1, Métal - Acier inoxidable, MassDensity: 7900 kg/m3; Component 1 in PANNEAU-001 Panneau 1, 1, Métal - Acier inoxidable, Embodied Energy: 56.7 (MJ/kg); Component 1 in PANNEAU-001 Panneau 1, 1, Métal - Acier inoxidable, Embodied Carbon: 6.15 (kgCO₂/kg); Component 1 in PANNEAU-001 Panneau 1, 1, Métal - Acier inoxidable, Name: Métal - Acier inoxidable; Component 1 in PANNEAU-001 Panneau 1, 1, Métal - Acier inoxidable, Participates in Collision Detection: yes; Component 2 in PANNEAU-001 Panneau 1, 1, Vitrage, ThermalConductivity: 1; Component 2 in PANNEAU-001 Panneau 1, 1, Vitrage, SpecificHeatCapacity: 750 J/kg/K; Component 2 in PANNEAU-001 Panneau 1, 1, Vitrage, MassDensity: 2500 kg/m3; Component 2 in PANNEAU-001 Panneau 1, 1, Vitrage, Embodied Energy: 15 (MJ/kg); Component 2 in PANNEAU-001 Panneau 1, 1, Vitrage, Embodied Carbon: 0.91 (kgCO₂/kg); Component 2 in PANNEAU-001 Panneau 1, 1, Vitrage, Name: Vitrage; Component 2 in PANNEAU-001 Panneau 1, 1, Vitrage, Participates in Collision Detection: no; Component 1 in PANNEAU-001 Panneau 1, 1: 4 with these values; Component 2 in PANNEAU-001 Panneau 1, 1: 4 with these values
Pare-vue acier laqué+verre dépoli H=190 | Rez-de-chaussée | Pare-vue métal et verre H=190 | Métal - Acier (3), Métal - Acier inoxidable (2), Vitrage (2) | LOT 17 | L17.2.3.1 | 60 | 460 | 7800 | 25.1 (MJ/kg) | 1.66 (kgCO₂/kg) | Métal - Acier | yes | 3 with these values | 0.0911861 | 2.35327 | Material Properties - Component 1 in PANNEAU-001 Panneau 1, 1, Métal - Acier inoxidable, ThermalConductivity: 17; Component 1 in PANNEAU-001 Panneau 1, 1, Métal - Acier inoxidable, SpecificHeatCapacity: 460 J/kg/K; Component 1 in PANNEAU-001 Panneau 1, 1, Métal - Acier inoxidable, MassDensity: 7900 kg/m3; Component 1 in PANNEAU-001 Panneau 1, 1, Métal - Acier inoxidable, Embodied Energy: 56.7 (MJ/kg); Component 1 in PANNEAU-001 Panneau 1, 1, Métal - Acier inoxidable, Embodied Carbon: 6.15 (kgCO₂/kg); Component 1 in PANNEAU-001 Panneau 1, 1, Métal - Acier inoxidable, Name: Métal - Acier inoxidable; Component 1 in PANNEAU-001 Panneau 1, 1, Métal - Acier inoxidable, Participates in Collision Detection: yes; Component 2 in PANNEAU-001 Panneau 1, 1, Vitrage, ThermalConductivity: 1; Component 2 in PANNEAU-001 Panneau 1, 1, Vitrage, SpecificHeatCapacity: 750 J/kg/K; Component 2 in PANNEAU-001 Panneau 1, 1, Vitrage, MassDensity: 2500 kg/m3; Component 2 in PANNEAU-001 Panneau 1, 1, Vitrage, Embodied Energy: 15 (MJ/kg); Component 2 in PANNEAU-001 Panneau 1, 1, Vitrage, Embodied Carbon: 0.91 (kgCO₂/kg); Component 2 in PANNEAU-001 Panneau 1, 1, Vitrage, Name: Vitrage; Component 2 in PANNEAU-001 Panneau 1, 1, Vitrage, Participates in Collision Detection: no; Component 1 in PANNEAU-001 Panneau 1, 1: 2 with these values; Component 2 in PANNEAU-001 Panneau 1, 1: 2 with these values
Pare-vue acier laqué+verre dépoli H=190 | Rez-de-chaussée | Pare-vue métal et verre H=190 | Métal - Acier (3), Métal - Acier inoxidable (2), Vitrage (2) | LOT 17 | L17.2.3.1 | 60 | 460 | 7800 | 25.1 (MJ/kg) | 1.66 (kgCO₂/kg) | Métal - Acier | yes | 3 with these values | 0.0905819 | 2.33667 | Material Properties - Component 1 in PANNEAU-001 Panneau 1, 1, Métal - Acier inoxidable, ThermalConductivity: 17; Component 1 in PANNEAU-001 Panneau 1, 1, Métal - Acier inoxidable, SpecificHeatCapacity: 460 J/kg/K; Component 1 in PANNEAU-001 Panneau 1, 1, Métal - Acier inoxidable, MassDensity: 7900 kg/m3; Component 1 in PANNEAU-001 Panneau 1, 1, Métal - Acier inoxidable, Embodied Energy: 56.7 (MJ/kg); Component 1 in PANNEAU-001 Panneau 1, 1, Métal - Acier inoxidable, Embodied Carbon: 6.15 (kgCO₂/kg); Component 1 in PANNEAU-001 Panneau 1, 1, Métal - Acier inoxidable, Name: Métal - Acier inoxidable; Component 1 in PANNEAU-001 Panneau 1, 1, Métal - Acier inoxidable, Participates in Collision Detection: yes; Component 2 in PANNEAU-001 Panneau 1, 1, Vitrage, ThermalConductivity: 1; Component 2 in PANNEAU-001 Panneau 1, 1, Vitrage, SpecificHeatCapacity: 750 J/kg/K; Component 2 in PANNEAU-001 Panneau 1, 1, Vitrage, MassDensity: 2500 kg/m3; Component 2 in PANNEAU-001 Panneau 1, 1, Vitrage, Embodied Energy: 15 (MJ/kg); Component 2 in PANNEAU-001 Panneau 1, 1, Vitrage, Embodied Carbon: 0.91 (kgCO₂/kg); Component 2 in PANNEAU-001 Panneau 1, 1, Vitrage, Name: Vitrage; Component 2 in PANNEAU-001 Panneau 1, 1, Vitrage, Participates in Collision Detection: no; Component 1 in PANNEAU-001 Panneau 1, 1: 2 with these values; Component 2 in PANNEAU-001 Panneau 1, 1: 2 with these values
Pare-vue acier laqué+verre dépoli H=190 | Rez-de-chaussée | Pare-vue métal et verre H=190 | Métal - Acier (3), Métal - Acier inoxidable (2), Vitrage (2) | LOT 17 | L17.2.3.1 | 60 | 460 | 7800 | 25.1 (MJ/kg) | 1.66 (kgCO₂/kg) | Métal - Acier | yes | 3 with these values | 0.0688664 | 1.74009 | Material Properties - Component 1 in PANNEAU-001 Panneau 1, 1, Métal - Acier inoxidable, ThermalConductivity: 17; Component 1 in PANNEAU-001 Panneau 1, 1, Métal - Acier inoxidable, SpecificHeatCapacity: 460 J/kg/K; Component 1 in PANNEAU-001 Panneau 1, 1, Métal - Acier inoxidable, MassDensity: 7900 kg/m3; Component 1 in PANNEAU-001 Panneau 1, 1, Métal - Acier inoxidable, Embodied Energy: 56.7 (MJ/kg); Component 1 in PANNEAU-001 Panneau 1, 1, Métal - Acier inoxidable, Embodied Carbon: 6.15 (kgCO₂/kg); Component 1 in PANNEAU-001 Panneau 1, 1, Métal - Acier inoxidable, Name: Métal - Acier inoxidable; Component 1 in PANNEAU-001 Panneau 1, 1, Métal - Acier inoxidable, Participates in Collision Detection: yes; Component 2 in PANNEAU-001 Panneau 1, 1, Vitrage, ThermalConductivity: 1; Component 2 in PANNEAU-001 Panneau 1, 1, Vitrage, SpecificHeatCapacity: 750 J/kg/K; Component 2 in PANNEAU-001 Panneau 1, 1, Vitrage, MassDensity: 2500 kg/m3; Component 2 in PANNEAU-001 Panneau 1, 1, Vitrage, Embodied Energy: 15 (MJ/kg); Component 2 in PANNEAU-001 Panneau 1, 1, Vitrage, Embodied Carbon: 0.91 (kgCO₂/kg); Component 2 in PANNEAU-001 Panneau 1, 1, Vitrage, Name: Vitrage; Component 2 in PANNEAU-001 Panneau 1, 1, Vitrage, Participates in Collision Detection: no; Component 1 in PANNEAU-001 Panneau 1, 1: 2 with these values; Component 2 in PANNEAU-001 Panneau 1, 1: 2 with these values
Pare-vue acier laqué+verre dépoli H=190 | Rez-de-chaussée | Pare-vue métal et verre H=190 | Métal - Acier (2), Métal - Acier inoxidable, Vitrage | LOT 17 | L17.2.3.1 | 60 | 460 | 7800 | 25.1 (MJ/kg) | 1.66 (kgCO₂/kg) | Métal - Acier | yes | 2 with these values | 0.0248459 | 0.587799 | Material Properties - Component 1 in PANNEAU-001 Panneau 1, 1, Métal - Acier inoxidable, ThermalConductivity: 17; Component 1 in PANNEAU-001 Panneau 1, 1, Métal - Acier inoxidable, SpecificHeatCapacity: 460 J/kg/K; Component 1 in PANNEAU-001 Panneau 1, 1, Métal - Acier inoxidable, MassDensity: 7900 kg/m3; Component 1 in PANNEAU-001 Panneau 1, 1, Métal - Acier inoxidable, Embodied Energy: 56.7 (MJ/kg); Component 1 in PANNEAU-001 Panneau 1, 1, Métal - Acier inoxidable, Embodied Carbon: 6.15 (kgCO₂/kg); Component 1 in PANNEAU-001 Panneau 1, 1, Métal - Acier inoxidable, Name: Métal - Acier inoxidable; Component 1 in PANNEAU-001 Panneau 1, 1, Métal - Acier inoxidable, Participates in Collision Detection: yes; Component 2 in PANNEAU-001 Panneau 1, 1, Vitrage, ThermalConductivity: 1; Component 2 in PANNEAU-001 Panneau 1, 1, Vitrage, SpecificHeatCapacity: 750 J/kg/K; Component 2 in PANNEAU-001 Panneau 1, 1, Vitrage, MassDensity: 2500 kg/m3; Component 2 in PANNEAU-001 Panneau 1, 1, Vitrage, Embodied Energy: 15 (MJ/kg); Component 2 in PANNEAU-001 Panneau 1, 1, Vitrage, Embodied Carbon: 0.91 (kgCO₂/kg); Component 2 in PANNEAU-001 Panneau 1, 1, Vitrage, Name: Vitrage; Component 2 in PANNEAU-001 Panneau 1, 1, Vitrage, Participates in Collision Detection: no
Pare-vue acier laqué+verre dépoli H=190 | Rez-de-chaussée | Pare-vue métal et verre H=190 | Métal - Acier (3), Métal - Acier inoxidable (2), Vitrage (2) | LOT 17 | L17.2.3.1 | 60 | 460 | 7800 | 25.1 (MJ/kg) | 1.66 (kgCO₂/kg) | Métal - Acier | yes | 3 with these values | 0.0657021 | 1.65316 | Material Properties - Component 1 in PANNEAU-001 Panneau 1, 1, Métal - Acier inoxidable, ThermalConductivity: 17; Component 1 in PANNEAU-001 Panneau 1, 1, Métal - Acier inoxidable, SpecificHeatCapacity: 460 J/kg/K; Component 1 in PANNEAU-001 Panneau 1, 1, Métal - Acier inoxidable, MassDensity: 7900 kg/m3; Component 1 in PANNEAU-001 Panneau 1, 1, Métal - Acier inoxidable, Embodied Energy: 56.7 (MJ/kg); Component 1 in PANNEAU-001 Panneau 1, 1, Métal - Acier inoxidable, Embodied Carbon: 6.15 (kgCO₂/kg); Component 1 in PANNEAU-001 Panneau 1, 1, Métal - Acier inoxidable, Name: Métal - Acier inoxidable; Component 1 in PANNEAU-001 Panneau 1, 1, Métal - Acier inoxidable, Participates in Collision Detection: yes; Component 2 in PANNEAU-001 Panneau 1, 1, Vitrage, ThermalConductivity: 1; Component 2 in PANNEAU-001 Panneau 1, 1, Vitrage, SpecificHeatCapacity: 750 J/kg/K; Component 2 in PANNEAU-001 Panneau 1, 1, Vitrage, MassDensity: 2500 kg/m3; Component 2 in PANNEAU-001 Panneau 1, 1, Vitrage, Embodied Energy: 15 (MJ/kg); Component 2 in PANNEAU-001 Panneau 1, 1, Vitrage, Embodied Carbon: 0.91 (kgCO₂/kg); Component 2 in PANNEAU-001 Panneau 1, 1, Vitrage, Name: Vitrage; Component 2 in PANNEAU-001 Panneau 1, 1, Vitrage, Participates in Collision Detection: no; Component 1 in PANNEAU-001 Panneau 1, 1: 2 with these values; Component 2 in PANNEAU-001 Panneau 1, 1: 2 with these values
GD/pare-vue bois | Rez-de-chaussée | Pare-vue bois | Bois - Massif 01 (9), Métal - Acier (3), Bois - Bardage (2) | LOT 05 | L05.2.2.3.2 |  |  |  |  |  |  |  | 9 with these values | 0.0668755 | 2.15601 | Material Properties - Component 1 in PANNEAU-001 Panneau 1, 1: 2 with these values; Component 1 in BARR-001 Poteau 1, 1, Bois - Massif 01, ThermalConductivity: 0.14; Component 1 in BARR-001 Poteau 1, 1, Bois - Massif 01, SpecificHeatCapacity: 2300 J/kg/K; Component 1 in BARR-001 Poteau 1, 1, Bois - Massif 01, MassDensity: 500 kg/m3; Component 1 in BARR-001 Poteau 1, 1, Bois - Massif 01, Embodied Energy: 10 (MJ/kg); Component 1 in BARR-001 Poteau 1, 1, Bois - Massif 01, Embodied Carbon: 0.36 (kgCO₂/kg); Component 1 in BARR-001 Poteau 1, 1, Bois - Massif 01, Name: Bois - Massif 01; Component 1 in BARR-001 Poteau 1, 1, Bois - Massif 01, Participates in Collision Detection: yes; Component 2 in BARR-001 Poteau 1, 1, Métal - Acier, ThermalConductivity: 60; Component 2 in BARR-001 Poteau 1, 1, Métal - Acier, SpecificHeatCapacity: 460 J/kg/K; Component 2 in BARR-001 Poteau 1, 1, Métal - Acier, MassDensity: 7800 kg/m3; Component 2 in BARR-001 Poteau 1, 1, Métal - Acier, Embodied Energy: 25.1 (MJ/kg); Component 2 in BARR-001 Poteau 1, 1, Métal - Acier, Embodied Carbon: 1.66 (kgCO₂/kg); Component 2 in BARR-001 Poteau 1, 1, Métal - Acier, Name: Métal - Acier; Component 2 in BARR-001 Poteau 1, 1, Métal - Acier, Participates in Collision Detection: yes; Component 1 in PANNEAU-001 Panneau 1, 1, Bois - Bardage, ThermalConductivity: 0.14; Component 1 in PANNEAU-001 Panneau 1, 1, Bois - Bardage, SpecificHeatCapacity: 2300 J/kg/K; Component 1 in PANNEAU-001 Panneau 1, 1, Bois - Bardage, MassDensity: 500 kg/m3; Component 1 in PANNEAU-001 Panneau 1, 1, Bois - Bardage, Embodied Energy: 10 (MJ/kg); Component 1 in PANNEAU-001 Panneau 1, 1, Bois - Bardage, Embodied Carbon: 0.36 (kgCO₂/kg); Component 1 in PANNEAU-001 Panneau 1, 1, Bois - Bardage, Name: Bois - Bardage; Component 1 in PANNEAU-001 Panneau 1, 1, Bois - Bardage, Participates in Collision Detection: yes; Component 2 in BARR-001 Poteau 1, 1: 3 with these values
Pare-vue acier laqué+verre dépoli H=190 | Rez-de-chaussée | Pare-vue métal et verre H=190 | Métal - Acier (4), Métal - Acier inoxidable (3), Vitrage (3) | LOT 17 | L17.2.3.1 | 60 | 460 | 7800 | 25.1 (MJ/kg) | 1.66 (kgCO₂/kg) | Métal - Acier | yes | 4 with these values | 0.108858 | 2.78172 | Material Properties - Component 1 in PANNEAU-001 Panneau 1, 1, Métal - Acier inoxidable, ThermalConductivity: 17; Component 1 in PANNEAU-001 Panneau 1, 1, Métal - Acier inoxidable, SpecificHeatCapacity: 460 J/kg/K; Component 1 in PANNEAU-001 Panneau 1, 1, Métal - Acier inoxidable, MassDensity: 7900 kg/m3; Component 1 in PANNEAU-001 Panneau 1, 1, Métal - Acier inoxidable, Embodied Energy: 56.7 (MJ/kg); Component 1 in PANNEAU-001 Panneau 1, 1, Métal - Acier inoxidable, Embodied Carbon: 6.15 (kgCO₂/kg); Component 1 in PANNEAU-001 Panneau 1, 1, Métal - Acier inoxidable, Name: Métal - Acier inoxidable; Component 1 in PANNEAU-001 Panneau 1, 1, Métal - Acier inoxidable, Participates in Collision Detection: yes; Component 2 in PANNEAU-001 Panneau 1, 1, Vitrage, ThermalConductivity: 1; Component 2 in PANNEAU-001 Panneau 1, 1, Vitrage, SpecificHeatCapacity: 750 J/kg/K; Component 2 in PANNEAU-001 Panneau 1, 1, Vitrage, MassDensity: 2500 kg/m3; Component 2 in PANNEAU-001 Panneau 1, 1, Vitrage, Embodied Energy: 15 (MJ/kg); Component 2 in PANNEAU-001 Panneau 1, 1, Vitrage, Embodied Carbon: 0.91 (kgCO₂/kg); Component 2 in PANNEAU-001 Panneau 1, 1, Vitrage, Name: Vitrage; Component 2 in PANNEAU-001 Panneau 1, 1, Vitrage, Participates in Collision Detection: no; Component 1 in PANNEAU-001 Panneau 1, 1: 3 with these values; Component 2 in PANNEAU-001 Panneau 1, 1: 3 with these values
Pare-vue acier laqué+verre dépoli H=190 | Rez-de-chaussée | Pare-vue métal et verre H=190 | Métal - Acier (3), Métal - Acier inoxidable (2), Vitrage (2) | LOT 17 | L17.2.3.1 | 60 | 460 | 7800 | 25.1 (MJ/kg) | 1.66 (kgCO₂/kg) | Métal - Acier | yes | 3 with these values | 0.0565385 | 1.40141 | Material Properties - Component 1 in PANNEAU-001 Panneau 1, 1, Métal - Acier inoxidable, ThermalConductivity: 17; Component 1 in PANNEAU-001 Panneau 1, 1, Métal - Acier inoxidable, SpecificHeatCapacity: 460 J/kg/K; Component 1 in PANNEAU-001 Panneau 1, 1, Métal - Acier inoxidable, MassDensity: 7900 kg/m3; Component 1 in PANNEAU-001 Panneau 1, 1, Métal - Acier inoxidable, Embodied Energy: 56.7 (MJ/kg); Component 1 in PANNEAU-001 Panneau 1, 1, Métal - Acier inoxidable, Embodied Carbon: 6.15 (kgCO₂/kg); Component 1 in PANNEAU-001 Panneau 1, 1, Métal - Acier inoxidable, Name: Métal - Acier inoxidable; Component 1 in PANNEAU-001 Panneau 1, 1, Métal - Acier inoxidable, Participates in Collision Detection: yes; Component 2 in PANNEAU-001 Panneau 1, 1, Vitrage, ThermalConductivity: 1; Component 2 in PANNEAU-001 Panneau 1, 1, Vitrage, SpecificHeatCapacity: 750 J/kg/K; Component 2 in PANNEAU-001 Panneau 1, 1, Vitrage, MassDensity: 2500 kg/m3; Component 2 in PANNEAU-001 Panneau 1, 1, Vitrage, Embodied Energy: 15 (MJ/kg); Component 2 in PANNEAU-001 Panneau 1, 1, Vitrage, Embodied Carbon: 0.91 (kgCO₂/kg); Component 2 in PANNEAU-001 Panneau 1, 1, Vitrage, Name: Vitrage; Component 2 in PANNEAU-001 Panneau 1, 1, Vitrage, Participates in Collision Detection: no; Component 1 in PANNEAU-001 Panneau 1, 1: 2 with these values; Component 2 in PANNEAU-001 Panneau 1, 1: 2 with these values
GD/pare-vue bois | Rez-de-chaussée | Pare-vue bois | Bois - Massif 01 (31), Métal - Acier (13), Bois - Bardage (12) | LOT 05 | L05.2.2.3.2 |  |  |  |  |  |  |  | 31 with these values | 0.384659 | 13.6012 | Material Properties - Component 1 in PANNEAU-001 Panneau 1, 1: 12 with these values; Component 1 in BARR-001 Poteau 1, 1, Bois - Massif 01, ThermalConductivity: 0.14; Component 1 in BARR-001 Poteau 1, 1, Bois - Massif 01, SpecificHeatCapacity: 2300 J/kg/K; Component 1 in BARR-001 Poteau 1, 1, Bois - Massif 01, MassDensity: 500 kg/m3; Component 1 in BARR-001 Poteau 1, 1, Bois - Massif 01, Embodied Energy: 10 (MJ/kg); Component 1 in BARR-001 Poteau 1, 1, Bois - Massif 01, Embodied Carbon: 0.36 (kgCO₂/kg); Component 1 in BARR-001 Poteau 1, 1, Bois - Massif 01, Name: Bois - Massif 01; Component 1 in BARR-001 Poteau 1, 1, Bois - Massif 01, Participates in Collision Detection: yes; Component 2 in BARR-001 Poteau 1, 1, Métal - Acier, ThermalConductivity: 60; Component 2 in BARR-001 Poteau 1, 1, Métal - Acier, SpecificHeatCapacity: 460 J/kg/K; Component 2 in BARR-001 Poteau 1, 1, Métal - Acier, MassDensity: 7800 kg/m3; Component 2 in BARR-001 Poteau 1, 1, Métal - Acier, Embodied Energy: 25.1 (MJ/kg); Component 2 in BARR-001 Poteau 1, 1, Métal - Acier, Embodied Carbon: 1.66 (kgCO₂/kg); Component 2 in BARR-001 Poteau 1, 1, Métal - Acier, Name: Métal - Acier; Component 2 in BARR-001 Poteau 1, 1, Métal - Acier, Participates in Collision Detection: yes; Component 1 in PANNEAU-001 Panneau 1, 1, Bois - Bardage, ThermalConductivity: 0.14; Component 1 in PANNEAU-001 Panneau 1, 1, Bois - Bardage, SpecificHeatCapacity: 2300 J/kg/K; Component 1 in PANNEAU-001 Panneau 1, 1, Bois - Bardage, MassDensity: 500 kg/m3; Component 1 in PANNEAU-001 Panneau 1, 1, Bois - Bardage, Embodied Energy: 10 (MJ/kg); Component 1 in PANNEAU-001 Panneau 1, 1, Bois - Bardage, Embodied Carbon: 0.36 (kgCO₂/kg); Component 1 in PANNEAU-001 Panneau 1, 1, Bois - Bardage, Name: Bois - Bardage; Component 1 in PANNEAU-001 Panneau 1, 1, Bois - Bardage, Participates in Collision Detection: yes; Component 2 in BARR-001 Poteau 1, 1: 13 with these values
3 x Garde-corps acier laqué | R+1 | Garde-corps balcon | Métal - Acier (63) | LOT 17 | L17.2.1.1 | 60 | 460 | 7800 | 25.1 (MJ/kg) | 1.66 (kgCO₂/kg) | Métal - Acier | yes | 63 with these values | 0.031267 | 5.38253
Garde-corps acier laqué | R+1 | Garde-corps balcon | Métal - Acier (94) | LOT 17 | L17.2.1.1 | 60 | 460 | 7800 | 25.1 (MJ/kg) | 1.66 (kgCO₂/kg) | Métal - Acier | yes | 94 with these values | 0.04878 | 8.63777
Pare-vue acier laqué+verre dépoli H=190 | R+1 | Pare-vue métal et verre H=190 | Métal - Acier (3), Métal - Acier inoxidable (2), Vitrage (2) | LOT 17 | L17.2.3.1 | 60 | 460 | 7800 | 25.1 (MJ/kg) | 1.66 (kgCO₂/kg) | Métal - Acier | yes | 3 with these values | 0.0425642 | 1.01751 | Material Properties - Component 1 in PANNEAU-001 Panneau 1, 1, Métal - Acier inoxidable, ThermalConductivity: 17; Component 1 in PANNEAU-001 Panneau 1, 1, Métal - Acier inoxidable, SpecificHeatCapacity: 460 J/kg/K; Component 1 in PANNEAU-001 Panneau 1, 1, Métal - Acier inoxidable, MassDensity: 7900 kg/m3; Component 1 in PANNEAU-001 Panneau 1, 1, Métal - Acier inoxidable, Embodied Energy: 56.7 (MJ/kg); Component 1 in PANNEAU-001 Panneau 1, 1, Métal - Acier inoxidable, Embodied Carbon: 6.15 (kgCO₂/kg); Component 1 in PANNEAU-001 Panneau 1, 1, Métal - Acier inoxidable, Name: Métal - Acier inoxidable; Component 1 in PANNEAU-001 Panneau 1, 1, Métal - Acier inoxidable, Participates in Collision Detection: yes; Component 2 in PANNEAU-001 Panneau 1, 1, Vitrage, ThermalConductivity: 1; Component 2 in PANNEAU-001 Panneau 1, 1, Vitrage, SpecificHeatCapacity: 750 J/kg/K; Component 2 in PANNEAU-001 Panneau 1, 1, Vitrage, MassDensity: 2500 kg/m3; Component 2 in PANNEAU-001 Panneau 1, 1, Vitrage, Embodied Energy: 15 (MJ/kg); Component 2 in PANNEAU-001 Panneau 1, 1, Vitrage, Embodied Carbon: 0.91 (kgCO₂/kg); Component 2 in PANNEAU-001 Panneau 1, 1, Vitrage, Name: Vitrage; Component 2 in PANNEAU-001 Panneau 1, 1, Vitrage, Participates in Collision Detection: no; Component 1 in PANNEAU-001 Panneau 1, 1: 2 with these values; Component 2 in PANNEAU-001 Panneau 1, 1: 2 with these values
Garde-corps acier laqué | R+1 | Garde-corps balcon | Métal - Acier (60) | LOT 17 | L17.2.1.1 | 60 | 460 | 7800 | 25.1 (MJ/kg) | 1.66 (kgCO₂/kg) | Métal - Acier | yes | 60 with these values | 0.030106 | 5.19942
Garde-corps acier laqué | R+1 | Garde-corps balcon | Métal - Acier (70) | LOT 17 | L17.2.1.1 | 60 | 460 | 7800 | 25.1 (MJ/kg) | 1.66 (kgCO₂/kg) | Métal - Acier | yes | 70 with these values | 0.0351983 | 6.01762
Garde-corps acier laqué | R+1 | Garde-corps balcon | Métal - Acier (90) | LOT 17 | L17.2.1.1 | 60 | 460 | 7800 | 25.1 (MJ/kg) | 1.66 (kgCO₂/kg) | Métal - Acier | yes | 90 with these values | 0.0452073 | 7.86478
Garde-corps acier laqué | R+1 | Garde-corps balcon | Métal - Acier (62) | LOT 17 | L17.2.1.1 | 60 | 460 | 7800 | 25.1 (MJ/kg) | 1.66 (kgCO₂/kg) | Métal - Acier | yes | 62 with these values | 0.0299598 | 4.95343
Garde-corps acier laqué | R+1 | Garde-corps balcon | Métal - Acier (84) | LOT 17 | L17.2.1.1 | 60 | 460 | 7800 | 25.1 (MJ/kg) | 1.66 (kgCO₂/kg) | Métal - Acier | yes | 84 with these values | 0.0435711 | 7.49162
Garde-corps acier laqué | R+1 | Garde-corps balcon | Métal - Acier (93) | LOT 17 | L17.2.1.1 | 60 | 460 | 7800 | 25.1 (MJ/kg) | 1.66 (kgCO₂/kg) | Métal - Acier | yes | 93 with these values | 0.0480627 | 8.44432
Garde-corps acier laqué | R+2 | Garde-corps balcon | Métal - Acier (93) | LOT 17 | L17.2.1.1 | 60 | 460 | 7800 | 25.1 (MJ/kg) | 1.66 (kgCO₂/kg) | Métal - Acier | yes | 93 with these values | 0.0480627 | 8.44432
2 x Garde-corps acier laqué | R+2 | Garde-corps balcon | Métal - Acier (63) | LOT 17 | L17.2.1.1 | 60 | 460 | 7800 | 25.1 (MJ/kg) | 1.66 (kgCO₂/kg) | Métal - Acier | yes | 63 with these values | 0.031267 | 5.38253
Garde-corps acier laqué | R+2 | Garde-corps balcon | Métal - Acier (94) | LOT 17 | L17.2.1.1 | 60 | 460 | 7800 | 25.1 (MJ/kg) | 1.66 (kgCO₂/kg) | Métal - Acier | yes | 94 with these values | 0.04878 | 8.63777
Pare-vue acier laqué+verre dépoli H=190 | R+2 | Pare-vue métal et verre H=190 | Métal - Acier (3), Métal - Acier inoxidable (2), Vitrage (2) | LOT 17 | L17.2.3.1 | 60 | 460 | 7800 | 25.1 (MJ/kg) | 1.66 (kgCO₂/kg) | Métal - Acier | yes | 3 with these values | 0.0425642 | 1.01751 | Material Properties - Component 1 in PANNEAU-001 Panneau 1, 1, Métal - Acier inoxidable, ThermalConductivity: 17; Component 1 in PANNEAU-001 Panneau 1, 1, Métal - Acier inoxidable, SpecificHeatCapacity: 460 J/kg/K; Component 1 in PANNEAU-001 Panneau 1, 1, Métal - Acier inoxidable, MassDensity: 7900 kg/m3; Component 1 in PANNEAU-001 Panneau 1, 1, Métal - Acier inoxidable, Embodied Energy: 56.7 (MJ/kg); Component 1 in PANNEAU-001 Panneau 1, 1, Métal - Acier inoxidable, Embodied Carbon: 6.15 (kgCO₂/kg); Component 1 in PANNEAU-001 Panneau 1, 1, Métal - Acier inoxidable, Name: Métal - Acier inoxidable; Component 1 in PANNEAU-001 Panneau 1, 1, Métal - Acier inoxidable, Participates in Collision Detection: yes; Component 2 in PANNEAU-001 Panneau 1, 1, Vitrage, ThermalConductivity: 1; Component 2 in PANNEAU-001 Panneau 1, 1, Vitrage, SpecificHeatCapacity: 750 J/kg/K; Component 2 in PANNEAU-001 Panneau 1, 1, Vitrage, MassDensity: 2500 kg/m3; Component 2 in PANNEAU-001 Panneau 1, 1, Vitrage, Embodied Energy: 15 (MJ/kg); Component 2 in PANNEAU-001 Panneau 1, 1, Vitrage, Embodied Carbon: 0.91 (kgCO₂/kg); Component 2 in PANNEAU-001 Panneau 1, 1, Vitrage, Name: Vitrage; Component 2 in PANNEAU-001 Panneau 1, 1, Vitrage, Participates in Collision Detection: no; Component 1 in PANNEAU-001 Panneau 1, 1: 2 with these values; Component 2 in PANNEAU-001 Panneau 1, 1: 2 with these values
Garde-corps acier laqué | R+2 | Garde-corps balcon | Métal - Acier (70) | LOT 17 | L17.2.1.1 | 60 | 460 | 7800 | 25.1 (MJ/kg) | 1.66 (kgCO₂/kg) | Métal - Acier | yes | 70 with these values | 0.0351983 | 6.01762
Garde-corps acier laqué | R+2 | Garde-corps balcon | Métal - Acier (62) | LOT 17 | L17.2.1.1 | 60 | 460 | 7800 | 25.1 (MJ/kg) | 1.66 (kgCO₂/kg) | Métal - Acier | yes | 62 with these values | 0.0299598 | 4.95343
Pare-vue acier laqué+verre dépoli H=90 | R+2 | Pare-vue métal et verre H=90 | Métal - Acier (11), Métal - Acier inoxidable (10), Vitrage (10) | LOT 17 | L17.2.3.2 | 60 | 460 | 7800 | 25.1 (MJ/kg) | 1.66 (kgCO₂/kg) | Métal - Acier | yes | 11 with these values | 0.197368 | 11.3979 | Material Properties - Component 1 in PANNEAU-001 Panneau 1, 1, Métal - Acier inoxidable, ThermalConductivity: 17; Component 1 in PANNEAU-001 Panneau 1, 1, Métal - Acier inoxidable, SpecificHeatCapacity: 460 J/kg/K; Component 1 in PANNEAU-001 Panneau 1, 1, Métal - Acier inoxidable, MassDensity: 7900 kg/m3; Component 1 in PANNEAU-001 Panneau 1, 1, Métal - Acier inoxidable, Embodied Energy: 56.7 (MJ/kg); Component 1 in PANNEAU-001 Panneau 1, 1, Métal - Acier inoxidable, Embodied Carbon: 6.15 (kgCO₂/kg); Component 1 in PANNEAU-001 Panneau 1, 1, Métal - Acier inoxidable, Name: Métal - Acier inoxidable; Component 1 in PANNEAU-001 Panneau 1, 1, Métal - Acier inoxidable, Participates in Collision Detection: yes; Component 2 in PANNEAU-001 Panneau 1, 1, Vitrage, ThermalConductivity: 1; Component 2 in PANNEAU-001 Panneau 1, 1, Vitrage, SpecificHeatCapacity: 750 J/kg/K; Component 2 in PANNEAU-001 Panneau 1, 1, Vitrage, MassDensity: 2500 kg/m3; Component 2 in PANNEAU-001 Panneau 1, 1, Vitrage, Embodied Energy: 15 (MJ/kg); Component 2 in PANNEAU-001 Panneau 1, 1, Vitrage, Embodied Carbon: 0.91 (kgCO₂/kg); Component 2 in PANNEAU-001 Panneau 1, 1, Vitrage, Name: Vitrage; Component 2 in PANNEAU-001 Panneau 1, 1, Vitrage, Participates in Collision Detection: no; Component 1 in PANNEAU-001 Panneau 1, 1: 10 with these values; Component 2 in PANNEAU-001 Panneau 1, 1: 10 with these values
Garde-corps acier laqué H=50cm | R+3 |  | Métal - Acier (33) | LOT 17 | L17.2.1.3 | 60 | 460 | 7800 | 25.1 (MJ/kg) | 1.66 (kgCO₂/kg) | Métal - Acier | yes | 33 with these values | 0.0319876 | 17.1582
Garde-corps acier laqué H=75cm | R+3 | Garde-corps technique acier laqué | Métal - Acier (50) | LOT 17 | L17.2.1.4.1 | 60 | 460 | 7800 | 25.1 (MJ/kg) | 1.66 (kgCO₂/kg) | Métal - Acier | yes | 50 with these values | 0.0597968 | 33.132
2 x Garde-corps acier laqué | R+3 | Garde-corps balcon | Métal - Acier (63) | LOT 17 | L17.2.1.1 | 60 | 460 | 7800 | 25.1 (MJ/kg) | 1.66 (kgCO₂/kg) | Métal - Acier | yes | 63 with these values | 0.031267 | 5.38253
Garde-corps acier laqué | R+3 | Garde-corps balcon | Métal - Acier (64) | LOT 17 | L17.2.1.1 | 60 | 460 | 7800 | 25.1 (MJ/kg) | 1.66 (kgCO₂/kg) | Métal - Acier | yes | 64 with these values | 0.0330302 | 5.7127
Garde-corps acier laqué | R+3 | Garde-corps balcon | Métal - Acier (69) | LOT 17 | L17.2.1.1 | 60 | 460 | 7800 | 25.1 (MJ/kg) | 1.66 (kgCO₂/kg) | Métal - Acier | yes | 69 with these values | 0.0337725 | 5.82208
Garde-corps acier laqué H=75cm | R+4 | Garde-corps technique acier laqué | Métal - Acier (55) | LOT 17 | L17.2.1.4.1 | 60 | 460 | 7800 | 25.1 (MJ/kg) | 1.66 (kgCO₂/kg) | Métal - Acier | yes | 55 with these values | 0.065452 | 36.1724
Garde-corps acier laqué H=50cm | R+4 | Garde-corps terrasse | Métal - Acier (18) | LOT 17 | L17.2.1.2 | 60 | 460 | 7800 | 25.1 (MJ/kg) | 1.66 (kgCO₂/kg) | Métal - Acier | yes | 18 with these values | 0.0125197 | 6.37445
Garde-corps acier laqué H=75cm | R+4 | Garde-corps technique acier laqué | Métal - Acier (13) | LOT 17 | L17.2.1.4.2 | 60 | 460 | 7800 | 25.1 (MJ/kg) | 1.66 (kgCO₂/kg) | Métal - Acier | yes | 13 with these values | 0.0135421 | 5.81854
Ligne de vie acier | Etage | Ligne de vie | Métal - Acier (36) | LOT 17 | L17.2.1.4.3 | 60 | 460 | 7800 | 25.1 (MJ/kg) | 1.66 (kgCO₂/kg) | Métal - Acier | yes | 36 with these values | 0.0116365 | 42.8392
RAMPE-001 | R+4 |  | Métal - Acier (18) |  |  | 60 | 460 | 7800 | 25.1 (MJ/kg) | 1.66 (kgCO₂/kg) | Métal - Acier | yes | 18 with these values | 0.00805441 | 1.15966

# IfcRoof: FLAT_ROOF (2)
In: Etage
Classification: Toiture plate (Classification ARCHICAD); Material: Etanchéité - Bitume, Isolation - Polyuréthane (extérieur), Bois - OSB 02
Pset_RoofCommon - IsExternal: yes
Propriétés DCE - Numéro de LOT: LOT 05; LOT 07; Numéro article: L05.2.2.1; L07.2.1
AC_Pset_RenovationAndPhasing - Renovation Status: Existing
Material Properties - Component 1, Etanchéité - Bitume, ThermalConductivity: 0.23; Component 1, Etanchéité - Bitume, SpecificHeatCapacity: 1000 J/kg/K; Component 1, Etanchéité - Bitume, MassDensity: 1100 kg/m3; Component 1, Etanchéité - Bitume, Embodied Energy: 2.86 (MJ/kg); Component 1, Etanchéité - Bitume, Embodied Carbon: 0.066 (kgCO₂/kg); Component 1, Etanchéité - Bitume, Name: Etanchéité - Bitume; Component 1, Etanchéité - Bitume, Participates in Collision Detection: no; Component 2, Isolation - Polyuréthane (extérieur), ThermalConductivity: 0.036; Component 2, Isolation - Polyuréthane (extérieur), SpecificHeatCapacity: 1450 J/kg/K; Component 2, Isolation - Polyuréthane (extérieur), MassDensity: 25 kg/m3; Component 2, Isolation - Polyuréthane (extérieur), Embodied Energy: 86.6 (MJ/kg); Component 2, Isolation - Polyuréthane (extérieur), Embodied Carbon: 3.29 (kgCO₂/kg); Component 2, Isolation - Polyuréthane (extérieur), Name: Isolation - Polyuréthane (extérieur); Component 2, Isolation - Polyuréthane (extérieur), Participates in Collision Detection: no; Component 3, Bois - OSB 02, ThermalConductivity: 0.13; Component 3, Bois - OSB 02, SpecificHeatCapacity: 1350 J/kg/K; Component 3, Bois - OSB 02, MassDensity: 1000 kg/m3; Component 3, Bois - OSB 02, Embodied Energy: 11.98 (MJ/kg); Component 3, Bois - OSB 02, Embodied Carbon: 0.51 (kgCO₂/kg); Component 3, Bois - OSB 02, Name: Bois - OSB 02; Component 3, Bois - OSB 02, Participates in Collision Detection: yes
Name | TotalArea (m2) = TotalSurfaceArea (m2)
Toit-04 | 17.4201
Toit-04 | 62.4084

# IfcRoof: FREEFORM (5)
In: R+4
Classification: Toiture libre (Classification ARCHICAD)
Pset_RoofCommon - IsExternal: yes
Propriétés DCE - Numéro article: L06.2.1
AC_Pset_RenovationAndPhasing - Renovation Status: Existing
Name | Material | TotalArea (m2) = TotalSurfaceArea (m2) | Numéro de LOT | Component 1, Toiture - ZINC, ThermalConductivity | Component 1, Toiture - ZINC, SpecificHeatCapacity (J/kg/K) | Component 1, Toiture - ZINC, MassDensity (kg/m3) | Component 1, Toiture - ZINC, Embodied Energy | Component 1, Toiture - ZINC, Embodied Carbon | Component 1, Toiture - ZINC, Name | Component 1, Toiture - ZINC, Participates in Collision Detection | Component 2, Bois - Massif 01, ThermalConductivity | Component 2, Bois - Massif 01, SpecificHeatCapacity (J/kg/K) | Component 2, Bois - Massif 01, MassDensity (kg/m3) = Component 3, Bois - Lattage, MassDensity (kg/m3) | Component 2, Bois - Massif 01, Embodied Energy | Component 2, Bois - Massif 01, Embodied Carbon | Component 2, Bois - Massif 01, Name | Component 2, Bois - Massif 01, Participates in Collision Detection = Component 3, Bois - Lattage, Participates in Collision Detection | Component 3, Bois - Lattage, ThermalConductivity | Component 3, Bois - Lattage, SpecificHeatCapacity (J/kg/K) | Component 3, Bois - Lattage, Embodied Energy | Component 3, Bois - Lattage, Embodied Carbon | Component 3, Bois - Lattage, Name
Toit-03 | Toiture - ZINC, Bois - Massif 01, Bois - Lattage | 6.89692 | LOT 05; LOT 06 | 50 | 450 | 7800 | 20.1 (MJ/kg) | 1.46 (kgCO₂/kg) | Toiture - ZINC | no | 0.14 | 2300 | 500 | 10 (MJ/kg) | 0.36 (kgCO₂/kg) | Bois - Massif 01 | yes | 0.13 | 1600 | 6.95 (MJ/kg) | 0.29 (kgCO₂/kg) | Bois - Lattage
Toit-03 | Toiture - ZINC, Bois - Massif 01, Bois - Lattage | 7.04479 | LOT 06 | 50 | 450 | 7800 | 20.1 (MJ/kg) | 1.46 (kgCO₂/kg) | Toiture - ZINC | no | 0.14 | 2300 | 500 | 10 (MJ/kg) | 0.36 (kgCO₂/kg) | Bois - Massif 01 | yes | 0.13 | 1600 | 6.95 (MJ/kg) | 0.29 (kgCO₂/kg) | Bois - Lattage
Toit-03 | Toiture - ZINC, Bois - Massif 01, Bois - Lattage | 6.89586 | LOT 05; LOT 06 | 50 | 450 | 7800 | 20.1 (MJ/kg) | 1.46 (kgCO₂/kg) | Toiture - ZINC | no | 0.14 | 2300 | 500 | 10 (MJ/kg) | 0.36 (kgCO₂/kg) | Bois - Massif 01 | yes | 0.13 | 1600 | 6.95 (MJ/kg) | 0.29 (kgCO₂/kg) | Bois - Lattage
2 x Toit-03 | Métal - Zinc | 0.0561174 | LOT 06 | Material Properties - Métal - Zinc, ThermalConductivity: 110; Métal - Zinc, SpecificHeatCapacity: 380 J/kg/K; Métal - Zinc, MassDensity: 7200 kg/m3; Métal - Zinc, Embodied Energy: 53.1 (MJ/kg); Métal - Zinc, Embodied Carbon: 3.09 (kgCO₂/kg); Métal - Zinc, Name: Métal - Zinc; Métal - Zinc, Participates in Collision Detection: yes

# IfcRoof: SHED_ROOF (11)
Classification: Toiture à un pan (Classification ARCHICAD)
AC_Pset_RenovationAndPhasing - Renovation Status: Existing
Name | In | Numéro de LOT | Numéro article | Material = Volume drainant enterré, Name | Volume drainant enterré, ThermalConductivity | Volume drainant enterré, SpecificHeatCapacity (J/kg/K) | Volume drainant enterré, MassDensity (kg/m3) | Volume drainant enterré, Embodied Energy | Volume drainant enterré, Embodied Carbon | Volume drainant enterré, Participates in Collision Detection
3 x MOB-004 | R+4 | LOT 06 | L06.1.1.2
MOB-003 | Etage | LOT 06 | L06.1.1.2
7 x MOB-004 | Rez-de-chaussée | LOT 02 | L02.2.3.1 | Volume drainant enterré | 0.17 | 900 | 1390 | 77.2 (MJ/kg) | 3.1 (kgCO₂/kg) | no

# IfcSlab: 6 -Dalles sur plots multi protections RDC 170 (2)
In: Rez-de-chaussée
Type - PredefinedType: FLOOR
Classification: Dalle de sol (Classification ARCHICAD); Dalle (Classification ARCHICAD); Material: Finition sol - Dalles terrasse, Divers - Vide
Pset_SlabCommon - AcousticRating: Non défini; ThermalTransmittance: 0; LoadBearing: yes; IsExternal: no
PSET_Dalles_ARCHI - Emplacement: INFRASTRUCTURE; Destination: Dallage sous-sol; Matériaux: Béton
Propriétés DCE - Numéro de LOT: LOT 07
AC_Pset_RenovationAndPhasing - Renovation Status: Existing
Material Properties - Component 1, Finition sol - Dalles terrasse, ThermalConductivity: 0.58; Component 1, Finition sol - Dalles terrasse, SpecificHeatCapacity: 840 J/kg/K; Component 1, Finition sol - Dalles terrasse, MassDensity: 1500 kg/m3; Component 1, Finition sol - Dalles terrasse, Embodied Energy: 3 (MJ/kg); Component 1, Finition sol - Dalles terrasse, Embodied Carbon: 0.24 (kgCO₂/kg); Component 1, Finition sol - Dalles terrasse, Name: Finition sol - Dalles terrasse; Component 1, Finition sol - Dalles terrasse, Participates in Collision Detection: no; Component 2, Divers - Vide, ThermalConductivity: 0.15; Component 2, Divers - Vide, SpecificHeatCapacity: 1008 J/kg/K; Component 2, Divers - Vide, MassDensity: 1.2 kg/m3; Component 2, Divers - Vide, Embodied Energy: 0 (MJ/kg); Component 2, Divers - Vide, Embodied Carbon: 0 (kgCO₂/kg); Component 2, Divers - Vide, Name: Divers - Vide; Component 2, Divers - Vide, Participates in Collision Detection: no
BaseQuantities - Width: 0.17 m
Name | Numéro article | Perimeter (m) | GrossArea (m2) = NetArea (m2) | GrossVolume (m3) = NetVolume (m3)
Dalle_006 | 07.2.4.5 | 22.8326 | 20.3878 | 3.78853
Dalle_006 | L07.2.3.5 | 43.2183 | 41.2019 | 7.0032

# IfcSlab: 6 -Dalles sur plots terrasse du RDC 170 (2)
In: Rez-de-chaussée
Type - PredefinedType: FLOOR
Classification: Dalle de sol (Classification ARCHICAD); Dalle (Classification ARCHICAD); Material: Finition sol - Dalles terrasse, Divers - Vide
Pset_SlabCommon - AcousticRating: Non défini; ThermalTransmittance: 0; LoadBearing: yes; IsExternal: no
PSET_Dalles_ARCHI - Emplacement: INFRASTRUCTURE; Destination: Dallage sous-sol; Matériaux: Béton
Propriétés DCE - Numéro de LOT: LOT 07; Numéro article: L07.2.3.5
AC_Pset_RenovationAndPhasing - Renovation Status: Existing
Material Properties - Component 1, Finition sol - Dalles terrasse, ThermalConductivity: 0.58; Component 1, Finition sol - Dalles terrasse, SpecificHeatCapacity: 840 J/kg/K; Component 1, Finition sol - Dalles terrasse, MassDensity: 1500 kg/m3; Component 1, Finition sol - Dalles terrasse, Embodied Energy: 3 (MJ/kg); Component 1, Finition sol - Dalles terrasse, Embodied Carbon: 0.24 (kgCO₂/kg); Component 1, Finition sol - Dalles terrasse, Name: Finition sol - Dalles terrasse; Component 1, Finition sol - Dalles terrasse, Participates in Collision Detection: no; Component 2, Divers - Vide, ThermalConductivity: 0.15; Component 2, Divers - Vide, SpecificHeatCapacity: 1008 J/kg/K; Component 2, Divers - Vide, MassDensity: 1.2 kg/m3; Component 2, Divers - Vide, Embodied Energy: 0 (MJ/kg); Component 2, Divers - Vide, Embodied Carbon: 0 (kgCO₂/kg); Component 2, Divers - Vide, Name: Divers - Vide; Component 2, Divers - Vide, Participates in Collision Detection: no
BaseQuantities - Width: 0.17 m
Name | Perimeter (m) | GrossArea (m2) = NetArea (m2) | GrossVolume (m3) = NetVolume (m3)
Dalle_006 | 115.67 | 141.731 | 24.0902
Dalle_006 | 60.938 | 59.5446 | 10.1212

# IfcSlab: 6 -Etanchéité RDC non isolée sous dalles sur plots 90, Dalle_006
In: Rez-de-chaussée
Type - PredefinedType: FLOOR
Classification: Dalle de sol (Classification ARCHICAD); Dalle (Classification ARCHICAD); Material: Divers - Vide, Etanchéité - Bitume
Pset_SlabCommon - AcousticRating: Non défini; ThermalTransmittance: 0; LoadBearing: yes; IsExternal: no
PSET_Dalles_ARCHI - Emplacement: INFRASTRUCTURE; Destination: Dallage sous-sol; Matériaux: Béton
Propriétés DCE - Numéro de LOT: LOT 07; Numéro article: L07.2.3.2; L07.2.3.3; L07.2.3.4
AC_Pset_RenovationAndPhasing - Renovation Status: Existing
Material Properties - Component 1, Divers - Vide, ThermalConductivity: 0.15; Component 1, Divers - Vide, SpecificHeatCapacity: 1008 J/kg/K; Component 1, Divers - Vide, MassDensity: 1.2 kg/m3; Component 1, Divers - Vide, Embodied Energy: 0 (MJ/kg); Component 1, Divers - Vide, Embodied Carbon: 0 (kgCO₂/kg); Component 1, Divers - Vide, Name: Divers - Vide; Component 1, Divers - Vide, Participates in Collision Detection: no; Component 2, Etanchéité - Bitume, ThermalConductivity: 0.23; Component 2, Etanchéité - Bitume, SpecificHeatCapacity: 1000 J/kg/K; Component 2, Etanchéité - Bitume, MassDensity: 1100 kg/m3; Component 2, Etanchéité - Bitume, Embodied Energy: 2.86 (MJ/kg); Component 2, Etanchéité - Bitume, Embodied Carbon: 0.066 (kgCO₂/kg); Component 2, Etanchéité - Bitume, Name: Etanchéité - Bitume; Component 2, Etanchéité - Bitume, Participates in Collision Detection: no
BaseQuantities - Width: 0.09 m; Perimeter: 115.79 m; GrossArea: 143.076 m2; NetArea: 143.076 m2; GrossVolume: 12.8297 m3; NetVolume: 12.8297 m3

# IfcSlab: 6 -Etanchéité dalle sous-sol sous terre 90, Dalle_007
In: Rez-de-chaussée
Type - PredefinedType: FLOOR
Classification: Dalle de sol (Classification ARCHICAD); Dalle (Classification ARCHICAD); Material: Divers - Vide, Etanchéité - Bitume
Pset_SlabCommon - AcousticRating: Non défini; ThermalTransmittance: 0; LoadBearing: yes; IsExternal: no
PSET_Dalles_ARCHI - Emplacement: INFRASTRUCTURE; Destination: Dallage sous-sol; Matériaux: Béton
Propriétés DCE - Numéro de LOT: LOT 07; Numéro article: L07.2.5.1
AC_Pset_RenovationAndPhasing - Renovation Status: Existing
Material Properties - Component 1, Divers - Vide, ThermalConductivity: 0.15; Component 1, Divers - Vide, SpecificHeatCapacity: 1008 J/kg/K; Component 1, Divers - Vide, MassDensity: 1.2 kg/m3; Component 1, Divers - Vide, Embodied Energy: 0 (MJ/kg); Component 1, Divers - Vide, Embodied Carbon: 0 (kgCO₂/kg); Component 1, Divers - Vide, Name: Divers - Vide; Component 1, Divers - Vide, Participates in Collision Detection: no; Component 2, Etanchéité - Bitume, ThermalConductivity: 0.23; Component 2, Etanchéité - Bitume, SpecificHeatCapacity: 1000 J/kg/K; Component 2, Etanchéité - Bitume, MassDensity: 1100 kg/m3; Component 2, Etanchéité - Bitume, Embodied Energy: 2.86 (MJ/kg); Component 2, Etanchéité - Bitume, Embodied Carbon: 0.066 (kgCO₂/kg); Component 2, Etanchéité - Bitume, Name: Etanchéité - Bitume; Component 2, Etanchéité - Bitume, Participates in Collision Detection: no
BaseQuantities - Width: 0.09 m; Perimeter: 83.2248 m; GrossArea: 274.561 m2; NetArea: 274.561 m2; GrossVolume: 24.6615 m3; NetVolume: 24.6615 m3

# IfcSlab: Béton (24)
Type - ElementType: BALCONY; PredefinedType: USERDEFINED
Description: Balcon; Classification: Balcon (Classification ARCHICAD); Material: Béton
Pset_SlabCommon - AcousticRating: Non défini; ThermalTransmittance: 0; IsExternal: yes
PSET_Dalles_ARCHI - Emplacement: INFRASTRUCTURE; Destination: Dallage sous-sol; Matériaux: Béton
Propriétés DCE - Numéro de LOT: LOT 04; LOT 07; LOT 16; Numéro article: L04.2.12.7.1; L07.2.7.4. L16.2.2.1
AC_Pset_RenovationAndPhasing - Renovation Status: Existing
Material Properties - Béton, ThermalConductivity: 2.3; Béton, SpecificHeatCapacity: 1000 J/kg/K; Béton, MassDensity: 2300 kg/m3; Béton, Embodied Energy: 1.92 (MJ/kg); Béton, Embodied Carbon: 0.198 (kgCO₂/kg); Béton, Name: Béton; Béton, Participates in Collision Detection: yes
Name | In
12 x Dalle de balcon béton | R+1
8 x Dalle de balcon béton | R+2
4 x Dalle de balcon béton | R+3

# IfcSlab: Béton 230 (6)
In: Rez-de-chaussée
Type - PredefinedType: FLOOR
Description: Pré-dalle béton; Classification: Dalle de sol (Classification ARCHICAD); Dalle (Classification ARCHICAD); Material: Béton
Pset_SlabCommon - AcousticRating: Non défini; ThermalTransmittance: 0; LoadBearing: yes; IsExternal: no
PSET_Dalles_ARCHI - Emplacement: INFRASTRUCTURE; Destination: Dallage sous-sol; Matériaux: Béton
Propriétés DCE - Numéro de LOT: LOT 04; Numéro article: L04.2.8.6.1; L04.2.8.6.3; L04.2.8.6.4
AC_Pset_RenovationAndPhasing - Renovation Status: Existing
Material Properties - Béton, ThermalConductivity: 2.3; Béton, SpecificHeatCapacity: 1000 J/kg/K; Béton, MassDensity: 2300 kg/m3; Béton, Embodied Energy: 1.92 (MJ/kg); Béton, Embodied Carbon: 0.198 (kgCO₂/kg); Béton, Name: Béton; Béton, Participates in Collision Detection: yes
BaseQuantities - Width: 0.23 m
Name | Perimeter (m) | GrossArea (m2) = NetArea (m2) | GrossVolume (m3) = NetVolume (m3)
Pré-dalle préfabriquée pour dalle béton | 107.35 | 248.263 | 57.4033
Pré-dalle préfabriquée pour dalle béton | 76.4903 | 216.845 | 50.1051
Pré-dalle préfabriquée pour dalle béton | 80.5534 | 172.107 | 39.8403
Pré-dalle préfabriquée pour dalle béton | 103.941 | 92.5625 | 21.2894
Pré-dalle préfabriquée pour dalle béton | 18.023 | 6.33082 | 1.45609
Pré-dalle préfabriquée pour dalle béton | 0.0216113 | 0.00000805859 | 0.00000185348

# IfcSlab: Béton 320 (5)
In: Rez-de-chaussée
Type - PredefinedType: FLOOR
Classification: Dalle de sol (Classification ARCHICAD); Dalle (Classification ARCHICAD); Material: Béton
Pset_SlabCommon - AcousticRating: Non défini; ThermalTransmittance: 0; LoadBearing: yes; IsExternal: no
PSET_Dalles_ARCHI - Emplacement: INFRASTRUCTURE; Destination: Dallage sous-sol; Matériaux: Béton
Propriétés DCE - Numéro de LOT: LOT 04
AC_Pset_RenovationAndPhasing - Renovation Status: Existing
Material Properties - Béton, ThermalConductivity: 2.3; Béton, SpecificHeatCapacity: 1000 J/kg/K; Béton, MassDensity: 2300 kg/m3; Béton, Embodied Energy: 1.92 (MJ/kg); Béton, Embodied Carbon: 0.198 (kgCO₂/kg); Béton, Name: Béton; Béton, Participates in Collision Detection: yes
BaseQuantities - Width: 0.32 m
Name | Description | Numéro article | Perimeter (m) | GrossArea (m2) = NetArea (m2) | GrossVolume (m3) = NetVolume (m3)
Dalle alvéolaire préfabriquée | Dalle alvéolaire | L04.2.8.6.2; L04.2.8.6.3; L04.2.8.6.4 | 77.9413 | 165.188 | 52.8603
Dalle alvéolaire préfabriquée | Dalle alvéolaire | L04.2.8.6.2; L04.2.8.6.3; L04.2.8.6.4 | 52.4991 | 132.514 | 42.4044
Pré-dalle préfabriquée pour dalle béton | Pré-dalle béton | L04.2.8.6.1; L04.2.8.6.3; L04.2.8.6.4 | 30.1318 | 26.9788 | 8.63323
Pré-dalle préfabriquée pour dalle béton | Pré-dalle béton | L04.2.8.6.1; L04.2.8.6.3; L04.2.8.6.4 | 20.1691 | 14.7923 | 4.78193
Dalle alvéolaire préfabriquée | Dalle alvéolaire | L04.2.8.6.2; L04.2.8.6.3; L04.2.8.6.4 | 30.21 | 42.398 | 13.7487
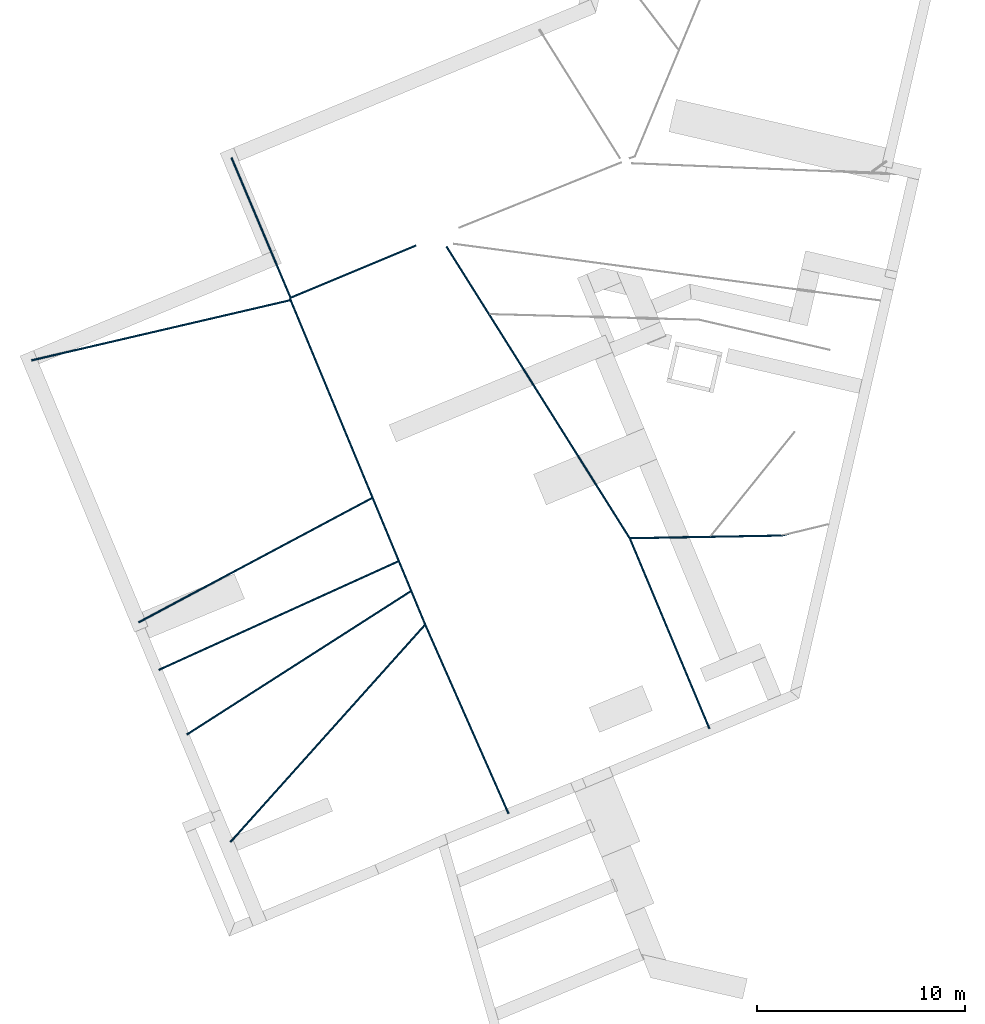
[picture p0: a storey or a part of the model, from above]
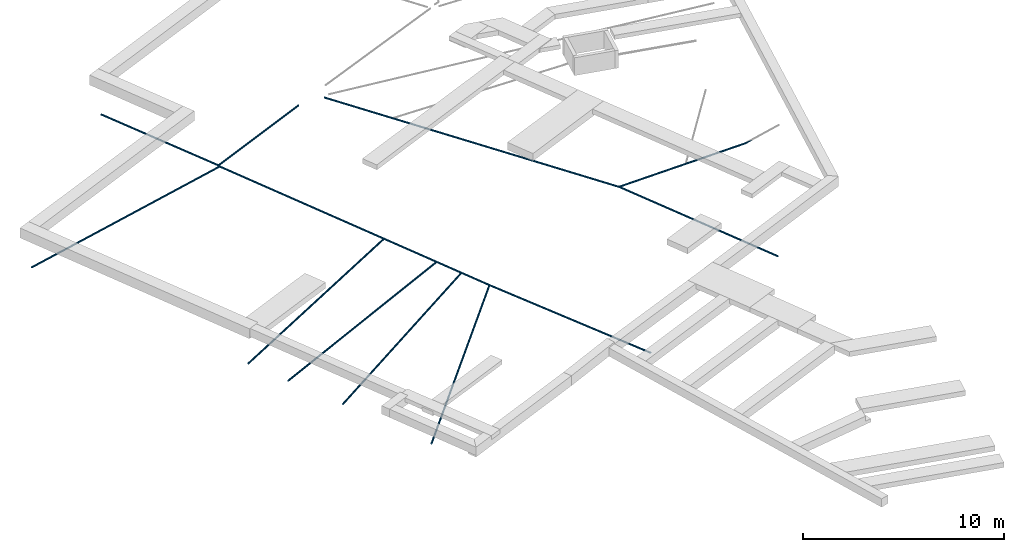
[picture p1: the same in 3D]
Properties of the parts of a building model (IFC2X3), part 6 of 22

# IfcSlab: Béton 380, Pré-dalle préfabriquée pour dalle béton
In: Rez-de-chaussée
Type - PredefinedType: FLOOR
Description: Pré-dalle béton; Classification: Dalle de sol (Classification ARCHICAD); Material: Béton
Pset_SlabCommon - AcousticRating: Non défini; ThermalTransmittance: 0; LoadBearing: yes; IsExternal: no
PSET_Dalles_ARCHI - Emplacement: INFRASTRUCTURE; Destination: Dallage sous-sol; Matériaux: Béton
Propriétés DCE - Numéro de LOT: LOT 04; Numéro article: L04.2.8.6.1; L04.2.8.6.3; L04.2.8.6.4
AC_Pset_RenovationAndPhasing - Renovation Status: Existing
Material Properties - Béton, ThermalConductivity: 2.3; Béton, SpecificHeatCapacity: 1000 J/kg/K; Béton, MassDensity: 2300 kg/m3; Béton, Embodied Energy: 1.92 (MJ/kg); Béton, Embodied Carbon: 0.198 (kgCO₂/kg); Béton, Name: Béton; Béton, Participates in Collision Detection: yes
BaseQuantities - Width: 0.38 m; Perimeter: 34.7739 m; GrossArea: 58.5369 m2; NetArea: 58.5369 m2; GrossVolume: 22.244 m3; NetVolume: 22.244 m3

# IfcSlab: Béton DALLAGE 150 (2)
In: Sous-sol
Type - PredefinedType: FLOOR
Classification: Dalle de sol (Classification ARCHICAD); Material: Béton DALLAGE
Pset_SlabCommon - AcousticRating: Non défini; ThermalTransmittance: 0; LoadBearing: yes; IsExternal: no
PSET_Dalles_ARCHI - Emplacement: INFRASTRUCTURE; Destination: Dallage sous-sol; Matériaux: Béton
Propriétés DCE - Numéro de LOT: LOT 04; Numéro article: L04.2.8.5
AC_Pset_RenovationAndPhasing - Renovation Status: Existing
Material Properties - Béton DALLAGE, ThermalConductivity: 2.3; Béton DALLAGE, SpecificHeatCapacity: 1000 J/kg/K; Béton DALLAGE, MassDensity: 2300 kg/m3; Béton DALLAGE, Embodied Energy: 1.92 (MJ/kg); Béton DALLAGE, Embodied Carbon: 0.198 (kgCO₂/kg); Béton DALLAGE, Name: Béton DALLAGE; Béton DALLAGE, Participates in Collision Detection: yes
BaseQuantities - Width: 0.15 m
Name | Perimeter (m) | GrossArea (m2) | NetArea (m2) | GrossVolume (m3) | NetVolume (m3)
Dalle_002 | 164.623 | 1392.14 | 1389.1 | 208.822 | 208.366
Dalle_002 | 4.96746 | 1.54216 | 1.54216 | 0.231324 | 0.231324

# IfcSlab: Béton DALLAGE 180, Dalle_003
In: R+4
Type - PredefinedType: ROOF
Classification: Dalle de toiture (Classification ARCHICAD); Material: Béton DALLAGE
Pset_SlabCommon - AcousticRating: Non défini; ThermalTransmittance: 0; LoadBearing: yes; IsExternal: no
PSET_Dalles_ARCHI - Emplacement: SUPERSTRUCTURE; Destination: Dalle Edicules; Matériaux: Béton
Propriétés DCE - Numéro de LOT: LOT 04; LOT 07; Numéro article: L04.2.16.2.1; L07.2.7.3
AC_Pset_RenovationAndPhasing - Renovation Status: Existing
Material Properties - Béton DALLAGE, ThermalConductivity: 2.3; Béton DALLAGE, SpecificHeatCapacity: 1000 J/kg/K; Béton DALLAGE, MassDensity: 2300 kg/m3; Béton DALLAGE, Embodied Energy: 1.92 (MJ/kg); Béton DALLAGE, Embodied Carbon: 0.198 (kgCO₂/kg); Béton DALLAGE, Name: Béton DALLAGE; Béton DALLAGE, Participates in Collision Detection: yes
BaseQuantities - Width: 0.18 m; Perimeter: 9.16 m; GrossArea: 5.2216 m2; NetArea: 5.2216 m2; GrossVolume: 0.939888 m3; NetVolume: 0.939888 m3

# IfcSlab: Nez de balcon 160 x 239 (56)
Type - ElementType: BALCONY; PredefinedType: USERDEFINED
Description: Nez-de-balcon; Classification: Balcon (Classification ARCHICAD); Material: Béton
Pset_SlabCommon - AcousticRating: Non défini; ThermalTransmittance: 0; LoadBearing: yes; IsExternal: yes
PSET_Dalles_ARCHI - Emplacement: INFRASTRUCTURE; Destination: Dallage sous-sol; Matériaux: Béton
Propriétés DCE - Numéro de LOT: LOT 04; LOT 16; Numéro article: L04.2.12.7.2; L16.2.2.2
AC_Pset_RenovationAndPhasing - Renovation Status: Existing
Material Properties - Béton, ThermalConductivity: 2.3; Béton, SpecificHeatCapacity: 1000 J/kg/K; Béton, MassDensity: 2300 kg/m3; Béton, Embodied Energy: 1.92 (MJ/kg); Béton, Embodied Carbon: 0.198 (kgCO₂/kg); Béton, Name: Béton; Béton, Participates in Collision Detection: yes
BaseQuantities - Width: 0.16 m
Name | In | Perimeter (m) | GrossArea (m2) | NetArea (m2) | GrossVolume (m3) = NetVolume (m3)
Nez-de-balcon béton | R+3 | 2.62627 | 0.1792 | 0.179101 | 0.038944
Nez-de-balcon béton | R+3 | 3.83 | 0.273439 | 0.273338 | 0.0609077
Nez-de-balcon béton | R+3 | 2.50459 | 0.171 | 0.170899 | 0.0369687
Nez-de-balcon béton | R+1 | 6.17017 | 0.461115 | 0.464131 | 0.107067
Nez-de-balcon béton | R+1 | 1.42627 | 0.0832 | 0.096 | 0.0223909
Nez-de-balcon béton | R+1 | 8.46523 | 0.641159 | 0.653862 | 0.149826
Nez-de-balcon béton | R+1 | 1.42719 | 0.0834182 | 0.0831118 | 0.0165174
Nez-de-balcon béton | R+1 | 12.3467 | 0.960539 | 0.976266 | 0.228031
Nez-de-balcon béton | R+1 | 5.56543 | 0.418038 | 0.410916 | 0.0923579
Nez-de-balcon béton | R+1 | 3.02627 | 0.2112 | 0.224 | 0.0522896
Nez-de-balcon béton | R+1 | 12.9585 | 1.00577 | 1.01783 | 0.232268
Nez-de-balcon béton | R+1 | 6.13255 | 0.4544 | 0.48 | 0.112099
5 x Nez-de-balcon béton | R+1 | 3.02627 | 0.2112 | 0.211101 | 0.0464202
Nez-de-balcon béton | R+1 | 3.02627 | 0.2112 | 0.224 | 0.046592
2 x Nez-de-balcon béton | R+1 | 6.13255 | 0.4544 | 0.48 | 0.112068
Nez-de-balcon béton | R+1 | 0.666274 | 0.0224 | 0.0223009 | 0.00231033
Nez-de-balcon béton | R+1 | 7.06441 | 0.528424 | 0.554519 | 0.129477
Nez-de-balcon béton | R+1 | 3.83 | 0.273439 | 0.273338 | 0.0609077
Nez-de-balcon béton | R+1 | 2.50459 | 0.171 | 0.170899 | 0.0369687
Nez-de-balcon béton | R+1 | 1.31629 | 0.0744032 | 0.0743041 | 0.01446
Nez-de-balcon béton | R+1 | 9.13378 | 0.694498 | 0.720098 | 0.168163
Nez-de-balcon béton | R+1 | 1.3185 | 0.0745761 | 0.0744771 | 0.0145004
Nez-de-balcon béton | R+1 | 3.34627 | 0.2368 | 0.2496 | 0.0582769
Nez-de-balcon béton | R+1 | 10.4317 | 0.798331 | 0.811032 | 0.186546
Nez-de-balcon béton | R+1 | 3.34627 | 0.2368 | 0.236701 | 0.0524013
Nez-de-balcon béton | R+2 | 1.39627 | 0.0808 | 0.096 | 0.0223909
Nez-de-balcon béton | R+2 | 8.46394 | 0.641056 | 0.653758 | 0.149802
Nez-de-balcon béton | R+2 | 1.42721 | 0.0834198 | 0.0831118 | 0.0165174
Nez-de-balcon béton | R+2 | 12.3467 | 0.960539 | 0.976266 | 0.228031
Nez-de-balcon béton | R+2 | 5.45094 | 0.405952 | 0.408779 | 0.0919412
2 x Nez-de-balcon béton | R+2 | 6.13255 | 0.4544 | 0.48 | 0.112068
4 x Nez-de-balcon béton | R+2 | 3.02627 | 0.2112 | 0.211101 | 0.0464202
Nez-de-balcon béton | R+2 | 6.17017 | 0.461115 | 0.464131 | 0.107067
Nez-de-balcon béton | R+2 | 0.666274 | 0.0224 | 0.0223009 | 0.00231033
Nez-de-balcon béton | R+2 | 7.06441 | 0.528424 | 0.554519 | 0.129477
Nez-de-balcon béton | R+2 | 3.83 | 0.273439 | 0.273338 | 0.0609077
Nez-de-balcon béton | R+2 | 2.50459 | 0.171 | 0.170899 | 0.0369687
2 x Nez-de-balcon béton | R+3 | 6.13255 | 0.4544 | 0.48 | 0.112068
4 x Nez-de-balcon béton | R+3 | 3.02627 | 0.2112 | 0.211101 | 0.0464202
Nez-de-balcon béton | R+3 | 7.06441 | 0.528424 | 0.554519 | 0.129477
Nez-de-balcon béton | R+1 | 11.7068 | 0.90935 | 0.925077 | 0.216056
Nez-de-balcon béton | R+2 | 11.7068 | 0.90935 | 0.925077 | 0.216056
Nez-de-balcon béton | R+3 | 9.94314 | 0.764549 | 0.777349 | 0.181577

# IfcStair (3)
In: Sous-sol
Classification: Escalier (Classification ARCHICAD); Material: Béton escalier
Pset_StairCommon - RequiredHeadroom: 2.2 m
AC_Pset_RenovationAndPhasing - Renovation Status: Existing
Material Properties - Béton escalier, ThermalConductivity: 2.3; Béton escalier, SpecificHeatCapacity: 1000 J/kg/K; Béton escalier, MassDensity: 2300 kg/m3; Béton escalier, Embodied Energy: 1.92 (MJ/kg); Béton escalier, Embodied Carbon: 0.198 (kgCO₂/kg); Béton escalier, Name: Béton escalier; Béton escalier, Participates in Collision Detection: yes
Name | Description | NumberOfRiser | NumberOfTreads | RiserHeight (m) | Numéro de LOT | Numéro article | Length (m) | Height (m) | GrossVolume (m3) = NetVolume (m3)
Escalier béton hélicoidale | Escalier béton commun | 17 | 16 | 0.170588 | LOT 04; L OT 15 | L04.2.10.1.2; L15.2.2.3.1. L15.2.2.6.1 | 4.48 | 2.9 | 1.77962
EScalier béton droit 120 extérieur | Escalier extérieur | 16 | 15 | 0.17 | LOT 04; L OT 15 | L04.2.10.1.2; L15.2.2.3.1. L15.2.2.6.1 | 4.2 | 2.72 | 1.32924
EScalier béton droit 140 extérieur | Escalier extérieur | 12 | 11 | 0.166667 | LOT 04 | L04.2.21.2 | 3.08 | 2 | 1.13083

# IfcStair: SPIRAL_STAIR (3)
Description: Escalier béton commun; Classification: Escalier hélicoïdal (Classification ARCHICAD); Material: Béton armé (Coulé)
Pset_StairCommon - NumberOfRiser: 16; NumberOfTreads: 15; RiserHeight: 0.175 m; RequiredHeadroom: 2.2 m
Propriétés DCE - Numéro de LOT: LOT 04; L OT 15; Numéro article: L04.2.10.1.2; L15.2.2.3.1. L15.2.2.6.1
AC_Pset_RenovationAndPhasing - Renovation Status: Existing
Material Properties - Béton armé (Coulé), ThermalConductivity: 2.3; Béton armé (Coulé), SpecificHeatCapacity: 1000 J/kg/K; Béton armé (Coulé), MassDensity: 2300 kg/m3; Béton armé (Coulé), Embodied Energy: 1.92 (MJ/kg); Béton armé (Coulé), Embodied Carbon: 0.198 (kgCO₂/kg); Béton armé (Coulé), Name: Béton armé (Coulé); Béton armé (Coulé), Participates in Collision Detection: yes
BaseQuantities - Length: 4.2 m; Height: 2.8 m; GrossVolume: 1.40527 m3; NetVolume: 1.40527 m3
Name | In
Escalier béton hélicoidale | Rez-de-chaussée
Escalier béton hélicoidale | R+1
Escalier béton hélicoidale | R+2

# IfcStair: TWO_QUARTER_WINDING_STAIR (2)
In: R+3
Description: EScalier des duplex; Classification: Escalier avec deux quarts tournants balancés (Classification ARCHICAD)
Pset_StairCommon - NumberOfRiser: 15; NumberOfTreads: 14; RiserHeight: 0.181333 m; RequiredHeadroom: 2.2 m
Propriétés DCE - Numéro de LOT: LOT 12-LOT 15; Numéro article: L12.1.1.7; L15.2.1.3.4
AC_Pset_RenovationAndPhasing - Renovation Status: Existing
BaseQuantities - Height: 2.72 m
Name | Material | Length (m) | GrossVolume (m3) = NetVolume (m3)
Escalier bois logement | Bois - Massif 02 (3), Bois - Massif 01 (29) | 4.41324 | 1.11312 | Material Properties - Component 1 in VOLEE-007 Structure F1, Bois - Massif 02, ThermalConductivity: 0.14; Component 1 in VOLEE-007 Structure F1, Bois - Massif 02, SpecificHeatCapacity: 2300 J/kg/K; Component 1 in VOLEE-007 Structure F1, Bois - Massif 02, MassDensity: 500 kg/m3; Component 1 in VOLEE-007 Structure F1, Bois - Massif 02, Embodied Energy: 10 (MJ/kg); Component 1 in VOLEE-007 Structure F1, Bois - Massif 02, Embodied Carbon: 0.36 (kgCO₂/kg); Component 1 in VOLEE-007 Structure F1, Bois - Massif 02, Name: Bois - Massif 02; Component 1 in VOLEE-007 Structure F1, Bois - Massif 02, Participates in Collision Detection: yes; Component 1 in C-MARCHE-079 Contremarche F1, 1, Bois - Massif 01, ThermalConductivity: 0.14; Component 1 in C-MARCHE-079 Contremarche F1, 1, Bois - Massif 01, SpecificHeatCapacity: 2300 J/kg/K; Component 1 in C-MARCHE-079 Contremarche F1, 1, Bois - Massif 01, MassDensity: 500 kg/m3; Component 1 in C-MARCHE-079 Contremarche F1, 1, Bois - Massif 01, Embodied Energy: 10 (MJ/kg); Component 1 in C-MARCHE-079 Contremarche F1, 1, Bois - Massif 01, Embodied Carbon: 0.36 (kgCO₂/kg); Component 1 in C-MARCHE-079 Contremarche F1, 1, Bois - Massif 01, Name: Bois - Massif 01; Component 1 in C-MARCHE-079 Contremarche F1, 1, Bois - Massif 01, Participates in Collision Detection: yes; Component 1 in VOLEE-007 Structure F1: 3 with these values; Component 1 in C-MARCHE-079 Contremarche F1, 1: 29 with these values
Escalier bois logement | Bois - Massif 02, Bois - Massif 01 (29) | 3.64 | 1.09129 | Material Properties - Component 1 in VOLEE-011 Structure F1, Bois - Massif 02, ThermalConductivity: 0.14; Component 1 in VOLEE-011 Structure F1, Bois - Massif 02, SpecificHeatCapacity: 2300 J/kg/K; Component 1 in VOLEE-011 Structure F1, Bois - Massif 02, MassDensity: 500 kg/m3; Component 1 in VOLEE-011 Structure F1, Bois - Massif 02, Embodied Energy: 10 (MJ/kg); Component 1 in VOLEE-011 Structure F1, Bois - Massif 02, Embodied Carbon: 0.36 (kgCO₂/kg); Component 1 in VOLEE-011 Structure F1, Bois - Massif 02, Name: Bois - Massif 02; Component 1 in VOLEE-011 Structure F1, Bois - Massif 02, Participates in Collision Detection: yes; Component 1 in C-MARCHE-127 Contremarche F1, 1, Bois - Massif 01, ThermalConductivity: 0.14; Component 1 in C-MARCHE-127 Contremarche F1, 1, Bois - Massif 01, SpecificHeatCapacity: 2300 J/kg/K; Component 1 in C-MARCHE-127 Contremarche F1, 1, Bois - Massif 01, MassDensity: 500 kg/m3; Component 1 in C-MARCHE-127 Contremarche F1, 1, Bois - Massif 01, Embodied Energy: 10 (MJ/kg); Component 1 in C-MARCHE-127 Contremarche F1, 1, Bois - Massif 01, Embodied Carbon: 0.36 (kgCO₂/kg); Component 1 in C-MARCHE-127 Contremarche F1, 1, Bois - Massif 01, Name: Bois - Massif 01; Component 1 in C-MARCHE-127 Contremarche F1, 1, Bois - Massif 01, Participates in Collision Detection: yes; Component 1 in C-MARCHE-127 Contremarche F1, 1: 29 with these values

# IfcTransportElement: Ascenseur 23 (5)
Type - PredefinedType: ELEVATOR
Classification: Ascenseur (Classification ARCHICAD)
AC_Pset_RenovationAndPhasing - Renovation Status: Existing
Name | In
MOB-001 | Sous-sol
MOB-001 | Rez-de-chaussée
MOB-001 | R+1
MOB-001 | R+2
MOB-001 | R+3

# IfcWall: 1 - Mur BETON 18 + ravalement 1 face 195 (2)
In: R+4
Type - ElementType: SOLIDWALL; PredefinedType: USERDEFINED
Classification: Mur porteur (Classification ARCHICAD)
Pset_WallCommon - AcousticRating: Non défini; ThermalTransmittance: 0; LoadBearing: yes; IsExternal: yes
PSET_Murs_ARCHI - Emplacement: Superstructure; Type: Mur béton banché 18cm; Destination: Mur intérieur; Matériaux: BETON
Propriétés DCE - Numéro de LOT: LOT 04; LOT 16; Numéro article: L16.2.1
AC_Pset_RenovationAndPhasing - Renovation Status: Existing
Material Properties - Component 2, Béton, ThermalConductivity: 2.3; Component 2, Béton, SpecificHeatCapacity: 1000 J/kg/K; Component 2, Béton, MassDensity: 2300 kg/m3; Component 2, Béton, Embodied Energy: 1.92 (MJ/kg); Component 2, Béton, Embodied Carbon: 0.198 (kgCO₂/kg); Component 2, Béton, Name: Béton; Component 2, Béton, Participates in Collision Detection: yes; Component 1, Finition ext - Crépis, ThermalConductivity: 0.8; Component 1, Finition ext - Crépis, SpecificHeatCapacity: 1000 J/kg/K; Component 1, Finition ext - Crépis, MassDensity: 1600 kg/m3; Component 1, Finition ext - Crépis, Embodied Energy: 1.4 (MJ/kg); Component 1, Finition ext - Crépis, Embodied Carbon: 0.09 (kgCO₂/kg); Component 1, Finition ext - Crépis, Name: Finition ext - Crépis; Component 1, Finition ext - Crépis, Participates in Collision Detection: no
BaseQuantities - Width: 0.195 m
Name | Material | Length (m) | Height (m) | GrossFootprintArea (m2) = NetFootprintArea (m2) | GrossSideArea (m2) = NetSideArea (m2) | GrossVolume (m3) = NetVolume (m3)
M_Ext-009 | Béton, Finition ext - Crépis | 7.97504 | 1.3 | 1.57583 | 10.0126 | 2.02272
M_Ext-009 | Finition ext - Crépis, Béton | 7.9487 | 1.32 | 1.56284 | 10.0633 | 2.0469

# IfcWall: 1 - Mur BETON 20+ PAREMENT PIERRE 280 (3)
In: Rez-de-chaussée
Type - ElementType: PARAPET; PredefinedType: USERDEFINED
Classification: Mur d'acrotère (Classification ARCHICAD); Material: Béton, Pierre
Pset_WallCommon - AcousticRating: Non défini; ThermalTransmittance: 0; LoadBearing: yes; IsExternal: yes
PSET_Murs_ARCHI - Emplacement: Superstructure; Matériaux: BETON
Propriétés DCE - Numéro de LOT: LOT 04; Numéro article: L04.2.21.1.6. L04.2.21.1.7
AC_Pset_RenovationAndPhasing - Renovation Status: Existing
Material Properties - Component 2, Béton, ThermalConductivity: 2.3; Component 2, Béton, SpecificHeatCapacity: 1000 J/kg/K; Component 2, Béton, MassDensity: 2300 kg/m3; Component 2, Béton, Embodied Energy: 1.92 (MJ/kg); Component 2, Béton, Embodied Carbon: 0.198 (kgCO₂/kg); Component 2, Béton, Name: Béton; Component 2, Béton, Participates in Collision Detection: yes; Component 1, Pierre, ThermalConductivity: 2.3; Component 1, Pierre, SpecificHeatCapacity: 1000 J/kg/K; Component 1, Pierre, MassDensity: 2600 kg/m3; Component 1, Pierre, Embodied Energy: 1.2 (MJ/kg); Component 1, Pierre, Embodied Carbon: 0.08 (kgCO₂/kg); Component 1, Pierre, Name: Pierre; Component 1, Pierre, Participates in Collision Detection: yes
BaseQuantities - Width: 0.28 m
Name | Description | Type | Destination | Length (m) | Height (m) | GrossFootprintArea (m2) = NetFootprintArea (m2) | GrossSideArea (m2) | NetSideArea (m2) | GrossVolume (m3) | NetVolume (m3)
Mur béton 20cm | Mur de clôture | Mur béton 20cm | Clôture | 2.95632 | 1.2239 | 0.827769 | 3.61823 | 3.52823 | 1.01311 | 0.987905
Mur béton 20cm | Mur de clôture | Mur béton 20cm | Clôture | 0.581667 | 1.224 | 0.2092 | 0.914491 | 0.914491 | 0.256058 | 0.256058
Mur béton 20cm | Acrotères et GD terrasses | Mur béton banché 20cm | Façade; Acrotère | 7.992 | 0.825112 | 2.23776 | 6.59429 | 6.59429 | 1.8464 | 1.8464

# IfcWall: 1 - Mur BETON 20+ PAREMENT PIERRE 280 (3)
In: Rez-de-chaussée
Type - PredefinedType: ELEMENTEDWALL
Classification: Mur composite (Classification ARCHICAD)
Pset_WallCommon - AcousticRating: Non défini; ThermalTransmittance: 0; LoadBearing: yes; IsExternal: yes
PSET_Murs_ARCHI - Emplacement: Superstructure; Type: Mur béton banché 20cm; Destination: Façade; Matériaux: BETON
Propriétés DCE - Numéro de LOT: LOT 04; Numéro article: L04.2.21.1.7
AC_Pset_RenovationAndPhasing - Renovation Status: Existing
Material Properties - Component 1, Pierre, ThermalConductivity: 2.3; Component 1, Pierre, SpecificHeatCapacity: 1000 J/kg/K; Component 1, Pierre, MassDensity: 2600 kg/m3; Component 1, Pierre, Embodied Energy: 1.2 (MJ/kg); Component 1, Pierre, Embodied Carbon: 0.08 (kgCO₂/kg); Component 1, Pierre, Name: Pierre; Component 1, Pierre, Participates in Collision Detection: yes; Component 2, Béton, ThermalConductivity: 2.3; Component 2, Béton, SpecificHeatCapacity: 1000 J/kg/K; Component 2, Béton, MassDensity: 2300 kg/m3; Component 2, Béton, Embodied Energy: 1.92 (MJ/kg); Component 2, Béton, Embodied Carbon: 0.198 (kgCO₂/kg); Component 2, Béton, Name: Béton; Component 2, Béton, Participates in Collision Detection: yes
BaseQuantities - Height: 2.27 m; Width: 0.28 m
Name | Material | Length (m) | GrossFootprintArea (m2) = NetFootprintArea (m2) | GrossSideArea (m2) | NetSideArea (m2) | GrossVolume (m3) | NetVolume (m3)
M_Ext-007 | Pierre, Béton | 4.90193 | 1.41896 | 11.5816 | 9.27486 | 3.22104 | 2.57516
M_Ext-007 | Pierre, Béton | 3.90985 | 1.07155 | 8.78452 | 8.78452 | 2.43241 | 2.43241
M_Ext-007 | Béton, Pierre | 0.15938 | 0.0214173 | 0.186829 | 0.186829 | 0.03514 | 0.03514

# IfcWall: 1 - Mur BETON 20+ PAREMENT PIERRE 280, M_Ext-007
In: Rez-de-chaussée
Type - PredefinedType: STANDARD
Classification: Mur standard (Classification ARCHICAD); Material: Pierre, Béton
Pset_WallCommon - AcousticRating: Non défini; ThermalTransmittance: 0; LoadBearing: yes; IsExternal: yes
PSET_Murs_ARCHI - Emplacement: Infrastructure; Type: Mur béton banché 20cm; Destination: Façade; Matériaux: BETON
Propriétés DCE - Numéro article: L04.2.21.1.7
AC_Pset_RenovationAndPhasing - Renovation Status: Existing
Material Properties - Component 1, Pierre, ThermalConductivity: 2.3; Component 1, Pierre, SpecificHeatCapacity: 1000 J/kg/K; Component 1, Pierre, MassDensity: 2600 kg/m3; Component 1, Pierre, Embodied Energy: 1.2 (MJ/kg); Component 1, Pierre, Embodied Carbon: 0.08 (kgCO₂/kg); Component 1, Pierre, Name: Pierre; Component 1, Pierre, Participates in Collision Detection: yes; Component 2, Béton, ThermalConductivity: 2.3; Component 2, Béton, SpecificHeatCapacity: 1000 J/kg/K; Component 2, Béton, MassDensity: 2300 kg/m3; Component 2, Béton, Embodied Energy: 1.92 (MJ/kg); Component 2, Béton, Embodied Carbon: 0.198 (kgCO₂/kg); Component 2, Béton, Name: Béton; Component 2, Béton, Participates in Collision Detection: yes
BaseQuantities - Length: 0.840809 m; Height: 2.54 m; Width: 0.28 m; GrossFootprintArea: 0.242626 m2; NetFootprintArea: 0.242626 m2; GrossSideArea: 2.10381 m2; NetSideArea: 2.01381 m2; GrossVolume: 0.609319 m3; NetVolume: 0.584119 m3

# IfcWall: 1 - Mur BETON 20+ ravalement 1 face 215 (4)
Type - ElementType: SOLIDWALL; PredefinedType: USERDEFINED
Classification: Mur porteur (Classification ARCHICAD)
Pset_WallCommon - AcousticRating: Non défini; ThermalTransmittance: 0; LoadBearing: yes; IsExternal: yes
PSET_Murs_ARCHI - Matériaux: BETON
AC_Pset_RenovationAndPhasing - Renovation Status: Existing
Material Properties - Component 2, Béton, ThermalConductivity: 2.3; Component 2, Béton, SpecificHeatCapacity: 1000 J/kg/K; Component 2, Béton, MassDensity: 2300 kg/m3; Component 2, Béton, Embodied Energy: 1.92 (MJ/kg); Component 2, Béton, Embodied Carbon: 0.198 (kgCO₂/kg); Component 2, Béton, Name: Béton; Component 2, Béton, Participates in Collision Detection: yes; Component 1, Finition ext - Crépis, ThermalConductivity: 0.8; Component 1, Finition ext - Crépis, SpecificHeatCapacity: 1000 J/kg/K; Component 1, Finition ext - Crépis, MassDensity: 1600 kg/m3; Component 1, Finition ext - Crépis, Embodied Energy: 1.4 (MJ/kg); Component 1, Finition ext - Crépis, Embodied Carbon: 0.09 (kgCO₂/kg); Component 1, Finition ext - Crépis, Name: Finition ext - Crépis; Component 1, Finition ext - Crépis, Participates in Collision Detection: no
BaseQuantities - Width: 0.215 m
Name | In | Material | Emplacement | Type | Destination | Numéro article | Length (m) | Height (m) | GrossFootprintArea (m2) = NetFootprintArea (m2) | GrossSideArea (m2) | NetSideArea (m2) | GrossVolume (m3) | NetVolume (m3)
M_Ext-009 | R+3 | Béton, Finition ext - Crépis | Superstructure | Mur béton banché 20cm | Façade | L16.2.1 | 0.9105 | 2.72 | 0.21587 | 2.64324 | 2.58074 | 0.54504 | 0.531603
M_Ext-003 | R+1 | Finition ext - Crépis, Béton | Infrastructure | Voile projeté contre terre | Mur contre terre | L04.2.12.1.1; L09.2.1.1.1; L16.2.1 | 9.185 | 1.27 | 1.9625 | 10.8555 | 10.8555 | 2.24012 | 2.24012 | Propriétés DCE - Numéro de LOT: LOT 04; LOT 05; LOT 09
Voile projeté béton par passes alternées | Rez-de-chaussée | Finition ext - Crépis, Béton | Infrastructure | Voile projeté contre terre | Mur contre terre | L16.2.1 | 1.50054 | 0.4331 | 0.322615 | 0.649882 | 0.649882 | 0.139725 | 0.139725 | Propriétés DCE - Numéro de LOT: LOT 03; Description: Voile contre terre
M_Ext-009 | R+3 | Finition ext - Crépis, Béton | Superstructure | Mur béton banché 20cm | Façade | L16.2.1 | 0.642867 | 2.74 | 0.118329 | 1.65272 | 1.65272 | 0.298179 | 0.298179

# IfcWall: 1 - Mur BETON 20+ ravalement 1 face 215 (2)
In: Rez-de-chaussée
Type - PredefinedType: ELEMENTEDWALL
Classification: Mur composite (Classification ARCHICAD)
Pset_WallCommon - AcousticRating: Non défini; ThermalTransmittance: 0; LoadBearing: yes; IsExternal: yes
PSET_Murs_ARCHI - Emplacement: Superstructure; Type: Mur béton banché 20cm; Destination: Muret sur terrasse; Mur contre terre; Matériaux: BETON
Propriétés DCE - Numéro de LOT: LOT 04; LOT 16; Numéro article: L16.2.1
AC_Pset_RenovationAndPhasing - Renovation Status: Existing
Material Properties - Component 2, Béton, ThermalConductivity: 2.3; Component 2, Béton, SpecificHeatCapacity: 1000 J/kg/K; Component 2, Béton, MassDensity: 2300 kg/m3; Component 2, Béton, Embodied Energy: 1.92 (MJ/kg); Component 2, Béton, Embodied Carbon: 0.198 (kgCO₂/kg); Component 2, Béton, Name: Béton; Component 2, Béton, Participates in Collision Detection: yes; Component 1, Finition ext - Crépis, ThermalConductivity: 0.8; Component 1, Finition ext - Crépis, SpecificHeatCapacity: 1000 J/kg/K; Component 1, Finition ext - Crépis, MassDensity: 1600 kg/m3; Component 1, Finition ext - Crépis, Embodied Energy: 1.4 (MJ/kg); Component 1, Finition ext - Crépis, Embodied Carbon: 0.09 (kgCO₂/kg); Component 1, Finition ext - Crépis, Name: Finition ext - Crépis; Component 1, Finition ext - Crépis, Participates in Collision Detection: no
BaseQuantities - Height: 1.2 m; Width: 0.215 m
Name | Material | Length (m) | GrossFootprintArea (m2) = NetFootprintArea (m2) | GrossSideArea (m2) = NetSideArea (m2) | GrossVolume (m3) = NetVolume (m3)
M_Ext-011 | Béton, Finition ext - Crépis | 14.1301 | 3.01327 | 16.6636 | 3.60185
M_Ext-010 | Finition ext - Crépis, Béton | 21.2364 | 4.59054 | 25.1723 | 5.47803

# IfcWall: 1 - Mur BETON 20+ ravalement 1 face 215 (2)
In: Rez-de-chaussée
Type - PredefinedType: STANDARD
Classification: Mur standard (Classification ARCHICAD); Material: Finition ext - Crépis, Béton
Pset_WallCommon - AcousticRating: Non défini; ThermalTransmittance: 0; LoadBearing: yes; IsExternal: yes
PSET_Murs_ARCHI - Emplacement: Infrastructure; Type: Mur béton banché 20cm; Destination: Façade; Matériaux: BETON
Propriétés DCE - Numéro de LOT: LOT 04; LOT 16; Numéro article: L16.2.1
AC_Pset_RenovationAndPhasing - Renovation Status: Existing
Material Properties - Component 1, Finition ext - Crépis, ThermalConductivity: 0.8; Component 1, Finition ext - Crépis, SpecificHeatCapacity: 1000 J/kg/K; Component 1, Finition ext - Crépis, MassDensity: 1600 kg/m3; Component 1, Finition ext - Crépis, Embodied Energy: 1.4 (MJ/kg); Component 1, Finition ext - Crépis, Embodied Carbon: 0.09 (kgCO₂/kg); Component 1, Finition ext - Crépis, Name: Finition ext - Crépis; Component 1, Finition ext - Crépis, Participates in Collision Detection: no; Component 2, Béton, ThermalConductivity: 2.3; Component 2, Béton, SpecificHeatCapacity: 1000 J/kg/K; Component 2, Béton, MassDensity: 2300 kg/m3; Component 2, Béton, Embodied Energy: 1.92 (MJ/kg); Component 2, Béton, Embodied Carbon: 0.198 (kgCO₂/kg); Component 2, Béton, Name: Béton; Component 2, Béton, Participates in Collision Detection: yes
BaseQuantities - Height: 3.22 m; Width: 0.215 m
Name | Length (m) | GrossFootprintArea (m2) = NetFootprintArea (m2) | GrossSideArea (m2) | NetSideArea (m2) | GrossVolume (m3) | NetVolume (m3)
M_Ext-003 | 4.5025 | 0.98815 | 14.82 | 12.32 | 3.18184 | 2.64434
M_Ext-004 | 1.4075 | 0.282275 | 4.4838 | 4.3938 | 0.908914 | 0.889564

# IfcWall: 1 - Mur BETON 20+ ravalement 2 faces 230 (2)
In: Rez-de-chaussée
Type - ElementType: SOLIDWALL; PredefinedType: USERDEFINED
Classification: Mur porteur (Classification ARCHICAD); Material: Finition ext - Crépis (2), Béton
Pset_WallCommon - AcousticRating: Non défini; ThermalTransmittance: 0; LoadBearing: yes; IsExternal: yes
PSET_Murs_ARCHI - Type: Mur béton banché 20cm; Destination: Façade; Matériaux: BETON
Propriétés DCE - Numéro de LOT: LOT 04; LOT 16; Numéro article: L16.2.1
AC_Pset_RenovationAndPhasing - Renovation Status: Existing
Material Properties - Component 3, Finition ext - Crépis, ThermalConductivity: 0.8; Component 3, Finition ext - Crépis, SpecificHeatCapacity: 1000 J/kg/K; Component 3, Finition ext - Crépis, MassDensity: 1600 kg/m3; Component 3, Finition ext - Crépis, Embodied Energy: 1.4 (MJ/kg); Component 3, Finition ext - Crépis, Embodied Carbon: 0.09 (kgCO₂/kg); Component 3, Finition ext - Crépis, Name: Finition ext - Crépis; Component 3, Finition ext - Crépis, Participates in Collision Detection: no; Component 2, Béton, ThermalConductivity: 2.3; Component 2, Béton, SpecificHeatCapacity: 1000 J/kg/K; Component 2, Béton, MassDensity: 2300 kg/m3; Component 2, Béton, Embodied Energy: 1.92 (MJ/kg); Component 2, Béton, Embodied Carbon: 0.198 (kgCO₂/kg); Component 2, Béton, Name: Béton; Component 2, Béton, Participates in Collision Detection: yes; Component 3: 2 with these values
BaseQuantities - Width: 0.23 m
Name | Emplacement | Length (m) | Height (m) | GrossFootprintArea (m2) = NetFootprintArea (m2) | GrossSideArea (m2) = NetSideArea (m2) | GrossVolume (m3) = NetVolume (m3)
M_Ext-010 | Infrastructure | 0.848309 | 2.51 | 0.196836 | 2.14667 | 0.494019
M_Ext-010 | Superstructure | 0.855809 | 2.54 | 0.200286 | 2.19544 | 0.502564

# IfcWall: 1 - Mur BETON 20+ ravalement 2 faces 230 (4)
In: Sous-sol
Type - PredefinedType: STANDARD
Description: Mur extérieur; Classification: Mur standard (Classification ARCHICAD); Material: Finition ext - Crépis (2), Béton
Pset_WallCommon - AcousticRating: Non défini; ThermalTransmittance: 0; LoadBearing: yes; IsExternal: yes
PSET_Murs_ARCHI - Emplacement: Extérieur; Type: Mur béton préfabriqué; Destination: Mur contre terre; Matériaux: BETON
Propriétés DCE - Numéro de LOT: LOT 04; LOT 16
AC_Pset_RenovationAndPhasing - Renovation Status: Existing
Material Properties - Component 2, Béton, ThermalConductivity: 2.3; Component 2, Béton, SpecificHeatCapacity: 1000 J/kg/K; Component 2, Béton, MassDensity: 2300 kg/m3; Component 2, Béton, Embodied Energy: 1.92 (MJ/kg); Component 2, Béton, Embodied Carbon: 0.198 (kgCO₂/kg); Component 2, Béton, Name: Béton; Component 2, Béton, Participates in Collision Detection: yes
BaseQuantities - Width: 0.23 m
Name | Numéro article | Component 1, Finition ext - Crépis, ThermalConductivity | Component 1, Finition ext - Crépis, SpecificHeatCapacity (J/kg/K) | Component 1, Finition ext - Crépis, MassDensity (kg/m3) | Component 1, Finition ext - Crépis, Embodied Energy | Component 1, Finition ext - Crépis, Embodied Carbon | Component 1, Finition ext - Crépis, Name | Component 1, Finition ext - Crépis, Participates in Collision Detection | Component 1 | Length (m) | Height (m) | GrossFootprintArea (m2) = NetFootprintArea (m2) | GrossSideArea (m2) = NetSideArea (m2) | GrossVolume (m3) = NetVolume (m3)
Mur béton préfabriqué | L04.2.21.1.8; L16.2.1 | 0.8 | 1000 | 1600 | 1.4 (MJ/kg) | 0.09 (kgCO₂/kg) | Finition ext - Crépis | no | 2 with these values | 15.1721 | 3.85 | 3.51879 | 58.4786 | 13.5393
Mur béton préfabriqué | L04.21.1.6.; L16.2.1 | 0.8 | 1000 | 1600 | 1.4 (MJ/kg) | 0.09 (kgCO₂/kg) | Finition ext - Crépis | no | 2 with these values | 4.75267 | 3.85 | 1.07001 | 18.2348 | 4.11862
Mur béton préfabriqué | L04.2.21.1.8; L16.2.1 | 0.8 | 1000 | 1600 | 1.4 (MJ/kg) | 0.09 (kgCO₂/kg) | Finition ext - Crépis | no | 2 with these values | 1.81247 | 1 | 0.393761 | 1.8039 | 0.393761
Mur béton préfabriqué | L04.21.1.6.; L16.2.1 |  |  |  |  |  |  |  |  | 3.86843 | 3.85 | 0.914568 | 14.7339 | 3.40994 | Material Properties - Component 3, Finition ext - Crépis, ThermalConductivity: 0.8; Component 3, Finition ext - Crépis, SpecificHeatCapacity: 1000 J/kg/K; Component 3, Finition ext - Crépis, MassDensity: 1600 kg/m3; Component 3, Finition ext - Crépis, Embodied Energy: 1.4 (MJ/kg); Component 3, Finition ext - Crépis, Embodied Carbon: 0.09 (kgCO₂/kg); Component 3, Finition ext - Crépis, Name: Finition ext - Crépis; Component 3, Finition ext - Crépis, Participates in Collision Detection: no; Component 3: 2 with these values

# IfcWall: 1 - Mur Extérieur BETON 18 +Isolant 120 330 (3)
Type - ElementType: SOLIDWALL; PredefinedType: USERDEFINED
Classification: Mur porteur (Classification ARCHICAD)
Pset_WallCommon - AcousticRating: Non défini; ThermalTransmittance: 0; LoadBearing: yes; IsExternal: yes
PSET_Murs_ARCHI - Emplacement: Superstructure; Type: Mur béton banché 18cm; Destination: Mur intérieur; Mur joint de dilatation; Matériaux: BETON
Propriétés DCE - Numéro de LOT: LOT 04; Numéro article: L04.2.12.4
AC_Pset_RenovationAndPhasing - Renovation Status: Existing
Material Properties - Component 5, Finition int - Plaque de plâtre, ThermalConductivity: 0.8; Component 5, Finition int - Plaque de plâtre, SpecificHeatCapacity: 1000 J/kg/K; Component 5, Finition int - Plaque de plâtre, MassDensity: 1600 kg/m3; Component 5, Finition int - Plaque de plâtre, Embodied Energy: 1.45 (MJ/kg); Component 5, Finition int - Plaque de plâtre, Embodied Carbon: 0.22 (kgCO₂/kg); Component 5, Finition int - Plaque de plâtre, Name: Finition int - Plaque de plâtre; Component 5, Finition int - Plaque de plâtre, Participates in Collision Detection: no; Component 4, Isolation - Polystyrène extrudé, ThermalConductivity: 0.036; Component 4, Isolation - Polystyrène extrudé, SpecificHeatCapacity: 1400 J/kg/K; Component 4, Isolation - Polystyrène extrudé, MassDensity: 25 kg/m3; Component 4, Isolation - Polystyrène extrudé, Embodied Energy: 86.4 (MJ/kg); Component 4, Isolation - Polystyrène extrudé, Embodied Carbon: 3.43 (kgCO₂/kg); Component 4, Isolation - Polystyrène extrudé, Name: Isolation - Polystyrène extrudé; Component 4, Isolation - Polystyrène extrudé, Participates in Collision Detection: no; Component 3, Divers - Vide, ThermalConductivity: 0.15; Component 3, Divers - Vide, SpecificHeatCapacity: 1008 J/kg/K; Component 3, Divers - Vide, MassDensity: 1.2 kg/m3; Component 3, Divers - Vide, Embodied Energy: 0 (MJ/kg); Component 3, Divers - Vide, Embodied Carbon: 0 (kgCO₂/kg); Component 3, Divers - Vide, Name: Divers - Vide; Component 3, Divers - Vide, Participates in Collision Detection: no; Component 1, Béton, ThermalConductivity: 2.3; Component 1, Béton, SpecificHeatCapacity: 1000 J/kg/K; Component 1, Béton, MassDensity: 2300 kg/m3; Component 1, Béton, Embodied Energy: 1.92 (MJ/kg); Component 1, Béton, Embodied Carbon: 0.198 (kgCO₂/kg); Component 1, Béton, Name: Béton; Component 1, Béton, Participates in Collision Detection: yes
BaseQuantities - Width: 0.33 m
Name | In | Material | Length (m) | Height (m) | GrossFootprintArea (m2) = NetFootprintArea (m2) | GrossSideArea (m2) = NetSideArea (m2) | GrossVolume (m3) = NetVolume (m3)
M_Ext-008 | R+1 | Finition int - Plaque de plâtre, Isolation - Polystyrène extrudé, Divers - Vide, Béton | 0.13 | 2.51 | 0.0429 | 0.3263 | 0.107679
M_Ext-008 | R+2 | Finition int - Plaque de plâtre, Isolation - Polystyrène extrudé, Divers - Vide, Béton | 0.34607 | 2.52 | 0.114203 | 0.869058 | 0.286707
M_Ext-009 | R+3 | Béton, Divers - Vide, Isolation - Polystyrène extrudé, Finition int - Plaque de plâtre | 0.285 | 2.51 | 0.09405 | 0.71535 | 0.236065

# IfcWall: 1 - Mur Extérieur BETON étanché+Isolant 120 + ravalement 345 (8)
Type - ElementType: SOLIDWALL; PredefinedType: USERDEFINED
Classification: Mur porteur (Classification ARCHICAD)
Pset_WallCommon - AcousticRating: Non défini; ThermalTransmittance: 0; LoadBearing: yes; IsExternal: yes
PSET_Murs_ARCHI - Emplacement: Superstructure; Type: Mur en bloc ELITHERM; Destination: Façade; Matériaux: Maçonnerie Bloc ALKERN Elitherm
Propriétés DCE - Numéro de LOT: LOT 04; LOT 05; LOT 09
AC_Pset_RenovationAndPhasing - Renovation Status: Existing
Material Properties - Component 1, Finition ext - Crépis, ThermalConductivity: 0.8; Component 1, Finition ext - Crépis, SpecificHeatCapacity: 1000 J/kg/K; Component 1, Finition ext - Crépis, MassDensity: 1600 kg/m3; Component 1, Finition ext - Crépis, Embodied Energy: 1.4 (MJ/kg); Component 1, Finition ext - Crépis, Embodied Carbon: 0.09 (kgCO₂/kg); Component 1, Finition ext - Crépis, Name: Finition ext - Crépis; Component 1, Finition ext - Crépis, Participates in Collision Detection: no; Component 2, Béton, ThermalConductivity: 2.3; Component 2, Béton, SpecificHeatCapacity: 1000 J/kg/K; Component 2, Béton, MassDensity: 2300 kg/m3; Component 2, Béton, Embodied Energy: 1.92 (MJ/kg); Component 2, Béton, Embodied Carbon: 0.198 (kgCO₂/kg); Component 2, Béton, Name: Béton; Component 2, Béton, Participates in Collision Detection: yes; Component 4, Etanchéité résine, ThermalConductivity: 0.17; Component 4, Etanchéité résine, SpecificHeatCapacity: 900 J/kg/K; Component 4, Etanchéité résine, MassDensity: 1390 kg/m3; Component 4, Etanchéité résine, Embodied Energy: 77.2 (MJ/kg); Component 4, Etanchéité résine, Embodied Carbon: 3.1 (kgCO₂/kg); Component 4, Etanchéité résine, Name: Etanchéité résine; Component 4, Etanchéité résine, Participates in Collision Detection: no; Component 5, Isolation - Polystyrène extrudé, ThermalConductivity: 0.036; Component 5, Isolation - Polystyrène extrudé, SpecificHeatCapacity: 1400 J/kg/K; Component 5, Isolation - Polystyrène extrudé, MassDensity: 25 kg/m3; Component 5, Isolation - Polystyrène extrudé, Embodied Energy: 86.4 (MJ/kg); Component 5, Isolation - Polystyrène extrudé, Embodied Carbon: 3.43 (kgCO₂/kg); Component 5, Isolation - Polystyrène extrudé, Name: Isolation - Polystyrène extrudé; Component 5, Isolation - Polystyrène extrudé, Participates in Collision Detection: no; Component 6, Finition int - Plaque de plâtre, ThermalConductivity: 0.8; Component 6, Finition int - Plaque de plâtre, SpecificHeatCapacity: 1000 J/kg/K; Component 6, Finition int - Plaque de plâtre, MassDensity: 1600 kg/m3; Component 6, Finition int - Plaque de plâtre, Embodied Energy: 1.45 (MJ/kg); Component 6, Finition int - Plaque de plâtre, Embodied Carbon: 0.22 (kgCO₂/kg); Component 6, Finition int - Plaque de plâtre, Name: Finition int - Plaque de plâtre; Component 6, Finition int - Plaque de plâtre, Participates in Collision Detection: no
BaseQuantities - Width: 0.345 m
Name | In | Material | Numéro article | Length (m) | Height (m) | GrossFootprintArea (m2) = NetFootprintArea (m2) | GrossSideArea (m2) = NetSideArea (m2) | GrossVolume (m3) = NetVolume (m3)
M_Ext-009 | Rez-de-chaussée | Finition ext - Crépis, Béton, Etanchéité résine, Isolation - Polystyrène extrudé, Finition int - Plaque de plâtre | L04.2.12.1.1; L09.2.1.1.1; L16.2.1 | 1.0425 | 2.72 | 0.388 | 2.7027 | 0.877062
M_Ext-009 | Rez-de-chaussée | Finition int - Plaque de plâtre, Isolation - Polystyrène extrudé, Etanchéité résine, Béton, Finition ext - Crépis | L04.2.12.1.1; L09.2.1.1.1; L16.2.1 | 4.80483 | 2.2869 | 1.65766 | 10.4837 | 3.52655
M_Ext-009 | Rez-de-chaussée | Finition int - Plaque de plâtre, Isolation - Polystyrène extrudé, Etanchéité résine, Béton, Finition ext - Crépis | L04.2.12.1.1; L09.2.1.1.1; L16.2.1 | 5.03933 | 2.2869 | 1.76483 | 11.0238 | 3.75789
M_Ext-009 | Rez-de-chaussée | Finition int - Plaque de plâtre, Isolation - Polystyrène extrudé, Etanchéité résine, Béton, Finition ext - Crépis | L04.2.12.1.1; L09.2.1.1.1; L16.2.1 | 1.34304 | 2.2869 | 0.437085 | 2.93133 | 0.93108
M_Ext-007 | R+1 | Finition ext - Crépis, Béton, Etanchéité résine, Isolation - Polystyrène extrudé, Finition int - Plaque de plâtre | L09.2.1.1.1; L16.2.1 | 0.8075 | 2.72 | 0.287275 | 1.65062 | 0.707157
M_Ext-007 | R+1 | Finition int - Plaque de plâtre, Isolation - Polystyrène extrudé, Etanchéité résine, Béton, Finition ext - Crépis | L09.2.1.1.1; L16.2.1 | 0.8075 | 2.72 | 0.287275 | 1.68062 | 0.621057
M_Ext-009 | Rez-de-chaussée | Finition int - Plaque de plâtre, Isolation - Polystyrène extrudé, Etanchéité résine, Béton, Finition ext - Crépis | L04.2.12.1.1; L09.2.1.1.1; L16.2.1 | 1.0425 | 2.2869 | 0.385925 | 2.30313 | 0.824376
M_Ext-007 | Rez-de-chaussée | Finition ext - Crépis, Béton, Etanchéité résine, Isolation - Polystyrène extrudé, Finition int - Plaque de plâtre | L09.2.1.1.1; L16.2.1 | 0.600137 | 2.51 | 0.204647 | 1.34319 | 0.513664

# IfcWall: 1 - Mur Extérieur Béton 20+ ravalement 1 face 215 (6)
In: Sous-sol
Type - ElementType: SOLIDWALL; PredefinedType: USERDEFINED
Classification: Mur porteur (Classification ARCHICAD)
Pset_WallCommon - AcousticRating: Non défini; ThermalTransmittance: 0; LoadBearing: yes; IsExternal: yes
PSET_Murs_ARCHI - Emplacement: Infrastructure; Type: Mur béton banché 20cm; Matériaux: BETON
Propriétés DCE - Numéro de LOT: LOT 04; LOT 16
AC_Pset_RenovationAndPhasing - Renovation Status: Existing
Material Properties - Component 2, Béton, ThermalConductivity: 2.3; Component 2, Béton, SpecificHeatCapacity: 1000 J/kg/K; Component 2, Béton, MassDensity: 2300 kg/m3; Component 2, Béton, Embodied Energy: 1.92 (MJ/kg); Component 2, Béton, Embodied Carbon: 0.198 (kgCO₂/kg); Component 2, Béton, Name: Béton; Component 2, Béton, Participates in Collision Detection: yes; Component 1, Finition ext - Crépis, ThermalConductivity: 0.8; Component 1, Finition ext - Crépis, SpecificHeatCapacity: 1000 J/kg/K; Component 1, Finition ext - Crépis, MassDensity: 1600 kg/m3; Component 1, Finition ext - Crépis, Embodied Energy: 1.4 (MJ/kg); Component 1, Finition ext - Crépis, Embodied Carbon: 0.09 (kgCO₂/kg); Component 1, Finition ext - Crépis, Name: Finition ext - Crépis; Component 1, Finition ext - Crépis, Participates in Collision Detection: no
BaseQuantities - Width: 0.215 m
Name | Description | Material | Destination | Numéro article | Length (m) | Height (m) | GrossFootprintArea (m2) = NetFootprintArea (m2) | GrossSideArea (m2) | NetSideArea (m2) | GrossVolume (m3) | NetVolume (m3)
Voile béton banché 20cm | Voile extérieur sous-sol | Béton, Finition ext - Crépis | Ouvrage extérieur | L16.2.1 | 7.43346 | 3.02 | 1.60142 | 21.9911 | 10.3544 | 4.826 | 2.32411
Mur béton 20cm | Murs extérieurs | Béton, Finition ext - Crépis | Façade | L04.21.1.6.; L16.2.1 | 9.52366 | 3.05 | 2.06038 | 29.1225 | 29.1225 | 6.24262 | 6.24262
Voile béton banché 20cm | Voile extérieur sous-sol | Béton, Finition ext - Crépis | Ouvrage extérieur | L16.2.1 | 4.07456 | 3.25 | 0.902905 | 12.9586 | 12.9586 | 2.76482 | 2.76482
Voile béton banché 20cm | Voile extérieur sous-sol | Béton, Finition ext - Crépis | Ouvrage extérieur | L16.2.1 | 3.13776 | 3.25 | 0.674621 | 9.83691 | 9.83691 | 2.18369 | 2.18369
Voile béton banché 20cm | Voile extérieur sous-sol | Finition ext - Crépis, Béton | Ouvrage extérieur | L16.2.1 | 3.58933 | 3.25 | 0.771706 | 11.2527 | 11.2527 | 2.49566 | 2.49566
Mur béton 20cm | Murs extérieurs | Béton, Finition ext - Crépis | Façade | L04.21.1.6.; L16.2.1 | 4.22704 | 3.05 | 0.88412 | 12.8644 | 12.8644 | 2.69657 | 2.69657

# IfcWall: 1 - Mur Extérieur Béton 20+ ravalement 1 face+enduit 1 face 225, M_Ext-007
In: Rez-de-chaussée
Type - PredefinedType: STANDARD
Classification: Mur standard (Classification ARCHICAD); Material: Finition ext - Crépis, Béton, Finition int - Enduit plâtre
Pset_WallCommon - AcousticRating: Non défini; ThermalTransmittance: 0; LoadBearing: yes; IsExternal: yes
PSET_Murs_ARCHI - Emplacement: Infrastructure; Type: Mur béton banché 20cm; Destination: Façade; Matériaux: BETON
Propriétés DCE - Numéro de LOT: LOT 04; LOT 05; LOT 09; Numéro article: L04.2.12.1.1; L09.2.1.1.1; L16.2.1
AC_Pset_RenovationAndPhasing - Renovation Status: Existing
Material Properties - Component 1, Finition ext - Crépis, ThermalConductivity: 0.8; Component 1, Finition ext - Crépis, SpecificHeatCapacity: 1000 J/kg/K; Component 1, Finition ext - Crépis, MassDensity: 1600 kg/m3; Component 1, Finition ext - Crépis, Embodied Energy: 1.4 (MJ/kg); Component 1, Finition ext - Crépis, Embodied Carbon: 0.09 (kgCO₂/kg); Component 1, Finition ext - Crépis, Name: Finition ext - Crépis; Component 1, Finition ext - Crépis, Participates in Collision Detection: no; Component 2, Béton, ThermalConductivity: 2.3; Component 2, Béton, SpecificHeatCapacity: 1000 J/kg/K; Component 2, Béton, MassDensity: 2300 kg/m3; Component 2, Béton, Embodied Energy: 1.92 (MJ/kg); Component 2, Béton, Embodied Carbon: 0.198 (kgCO₂/kg); Component 2, Béton, Name: Béton; Component 2, Béton, Participates in Collision Detection: yes; Component 3, Finition int - Enduit plâtre, ThermalConductivity: 0.57; Component 3, Finition int - Enduit plâtre, SpecificHeatCapacity: 1000 J/kg/K; Component 3, Finition int - Enduit plâtre, MassDensity: 1300 kg/m3; Component 3, Finition int - Enduit plâtre, Embodied Energy: 1.8 (MJ/kg); Component 3, Finition int - Enduit plâtre, Embodied Carbon: 0.13 (kgCO₂/kg); Component 3, Finition int - Enduit plâtre, Name: Finition int - Enduit plâtre; Component 3, Finition int - Enduit plâtre, Participates in Collision Detection: no
BaseQuantities - Length: 2.535 m; Height: 2.56 m; Width: 0.225 m; GrossFootprintArea: 0.6012 m2; NetFootprintArea: 0.6012 m2; GrossSideArea: 6.13125 m2; NetSideArea: 2.63685 m2; GrossVolume: 1.51059 m3; NetVolume: 0.72435 m3

# IfcWall: 1 - Mur Extérieur Béton 25+ ravalement 1 face copie 265 (3)
In: Rez-de-chaussée
Type - ElementType: SOLIDWALL; PredefinedType: USERDEFINED
Description: Voile contre terre; Classification: Mur porteur (Classification ARCHICAD); Material: Béton, Finition ext - Crépis
Pset_WallCommon - AcousticRating: Non défini; ThermalTransmittance: 0; LoadBearing: yes; IsExternal: yes
PSET_Murs_ARCHI - Emplacement: Infrastructure; Type: Voile projeté contre terre; Destination: Mur contre terre; Matériaux: BETON
Propriétés DCE - Numéro de LOT: LOT 04; LOT 16; Numéro article: L16.2.1
AC_Pset_RenovationAndPhasing - Renovation Status: Existing
Material Properties - Component 1, Béton, ThermalConductivity: 2.3; Component 1, Béton, SpecificHeatCapacity: 1000 J/kg/K; Component 1, Béton, MassDensity: 2300 kg/m3; Component 1, Béton, Embodied Energy: 1.92 (MJ/kg); Component 1, Béton, Embodied Carbon: 0.198 (kgCO₂/kg); Component 1, Béton, Name: Béton; Component 1, Béton, Participates in Collision Detection: yes; Component 2, Finition ext - Crépis, ThermalConductivity: 0.8; Component 2, Finition ext - Crépis, SpecificHeatCapacity: 1000 J/kg/K; Component 2, Finition ext - Crépis, MassDensity: 1600 kg/m3; Component 2, Finition ext - Crépis, Embodied Energy: 1.4 (MJ/kg); Component 2, Finition ext - Crépis, Embodied Carbon: 0.09 (kgCO₂/kg); Component 2, Finition ext - Crépis, Name: Finition ext - Crépis; Component 2, Finition ext - Crépis, Participates in Collision Detection: no
BaseQuantities - Width: 0.265 m
Name | Length (m) | Height (m) | GrossFootprintArea (m2) = NetFootprintArea (m2) | GrossSideArea (m2) = NetSideArea (m2) | GrossVolume (m3) = NetVolume (m3)
Voile projeté béton par passes alternées | 2.83245 | 4.1 | 0.7506 | 11.6093 | 3.07735
Voile projeté béton par passes alternées | 3.32969 | 3.38 | 0.883879 | 11.2629 | 2.98467
Voile projeté béton par passes alternées | 2.40008 | 1.88 | 0.636022 | 4.51216 | 1.19572

# IfcWall: 1 - Mur Ossature Bois 145 + bardage 222 (13)
In: Etage
Classification: Mur (Classification ARCHICAD)
Pset_WallCommon - AcousticRating: Non défini; ThermalTransmittance: 0; LoadBearing: yes; IsExternal: yes
PSET_Murs_ARCHI - Emplacement: Infrastructure; Type: Murs Ossature Bois; Destination: Façade; Matériaux: BETON
Propriétés DCE - Numéro de LOT: LOT 05; Numéro article: L05.2.1.2; L05.2.3.1
AC_Pset_RenovationAndPhasing - Renovation Status: Existing
Material Properties - Component 1, Finition ext - Bardage bois, ThermalConductivity: 0.14; Component 1, Finition ext - Bardage bois, SpecificHeatCapacity: 2300 J/kg/K; Component 1, Finition ext - Bardage bois, MassDensity: 500 kg/m3; Component 1, Finition ext - Bardage bois, Embodied Energy: 10 (MJ/kg); Component 1, Finition ext - Bardage bois, Embodied Carbon: 0.36 (kgCO₂/kg); Component 1, Finition ext - Bardage bois, Name: Finition ext - Bardage bois; Component 1, Finition ext - Bardage bois, Participates in Collision Detection: no; Component 2, Bois - Lattage, ThermalConductivity: 0.13; Component 2, Bois - Lattage, SpecificHeatCapacity: 1600 J/kg/K; Component 2, Bois - Lattage, MassDensity: 500 kg/m3; Component 2, Bois - Lattage, Embodied Energy: 6.95 (MJ/kg); Component 2, Bois - Lattage, Embodied Carbon: 0.29 (kgCO₂/kg); Component 2, Bois - Lattage, Name: Bois - Lattage; Component 2, Bois - Lattage, Participates in Collision Detection: yes; Component 3, Bois - OSB 02, ThermalConductivity: 0.13; Component 3, Bois - OSB 02, SpecificHeatCapacity: 1350 J/kg/K; Component 3, Bois - OSB 02, MassDensity: 1000 kg/m3; Component 3, Bois - OSB 02, Embodied Energy: 11.98 (MJ/kg); Component 3, Bois - OSB 02, Embodied Carbon: 0.51 (kgCO₂/kg); Component 3, Bois - OSB 02, Name: Bois - OSB 02; Component 3, Bois - OSB 02, Participates in Collision Detection: yes; Component 4, Bois - Massif 01, ThermalConductivity: 0.14; Component 4, Bois - Massif 01, SpecificHeatCapacity: 2300 J/kg/K; Component 4, Bois - Massif 01, MassDensity: 500 kg/m3; Component 4, Bois - Massif 01, Embodied Energy: 10 (MJ/kg); Component 4, Bois - Massif 01, Embodied Carbon: 0.36 (kgCO₂/kg); Component 4, Bois - Massif 01, Name: Bois - Massif 01; Component 4, Bois - Massif 01, Participates in Collision Detection: yes
BaseQuantities - Width: 0.222 m
Name | Material | Length (m) | Height (m) | GrossFootprintArea (m2) = NetFootprintArea (m2) | GrossSideArea (m2) = NetSideArea (m2) | GrossVolume (m3) = NetVolume (m3)
M_Ext-008 | Finition ext - Bardage bois, Bois - Lattage, Bois - OSB 02, Bois - Massif 01 | 4.01941 | 0.61 | 0.892308 | 2.45184 | 0.544308
M_Ext-016 | Finition ext - Bardage bois, Bois - Lattage, Bois - OSB 02, Bois - Massif 01 | 6.407 | 1.45212 | 1.39896 | 5.5657 | 1.22002
M_Ext-008 | Bois - Massif 01, Bois - OSB 02, Bois - Lattage, Finition ext - Bardage bois | 8.60283 | 0.61 | 1.90983 | 5.20573 | 1.15567
M_Ext-014 | Finition ext - Bardage bois, Bois - Lattage, Bois - OSB 02, Bois - Massif 01 | 6.407 | 1.45212 | 1.42235 | 5.59209 | 1.22732
M_Ext-008 | Bois - Massif 01, Bois - OSB 02, Bois - Lattage, Finition ext - Bardage bois | 5.19531 | 0.61 | 1.17675 | 3.25759 | 0.717819
M_Ext-014 | Finition ext - Bardage bois, Bois - Lattage, Bois - OSB 02, Bois - Massif 01 | 8.81339 | 1.45653 | 1.97997 | 12.8743 | 2.84524
M_Ext-010 | Finition ext - Bardage bois, Bois - Lattage, Bois - OSB 02, Bois - Massif 01 | 0.977794 | 0.61 | 0.222831 | 0.663202 | 0.135927
M_Ext-012 | Finition ext - Bardage bois, Bois - Lattage, Bois - OSB 02, Bois - Massif 01 | 7.4269 | 0.61 | 1.64034 | 4.56151 | 1.00061
M_Ext-014 | Finition ext - Bardage bois, Bois - Lattage, Bois - OSB 02, Bois - Massif 01 | 8.81339 | 0.330328 | 1.95657 | 2.75478 | 0.607787
M_Ext-012 | Finition ext - Bardage bois, Bois - Lattage, Bois - OSB 02, Bois - Massif 01 | 2.21653 | 0.61 | 0.49207 | 1.34952 | 0.299771
M_Ext-014 | Finition ext - Bardage bois, Bois - Lattage, Bois - OSB 02, Bois - Massif 01 | 10.9853 | 0.61 | 2.41533 | 6.68319 | 1.47296
M_Ext-009 | Finition ext - Bardage bois, Bois - Lattage, Bois - OSB 02, Bois - Massif 01 | 4.03085 | 0.61 | 0.897523 | 2.50553 | 0.547489
M_Ext-013 | Finition ext - Bardage bois, Bois - Lattage, Bois - OSB 02, Bois - Massif 01 | 0.992 | 0.61 | 0.220224 | 0.60512 | 0.134337

# IfcWall: 1 - Mur Ossature Bois 145 isolé + bardage 310 (11)
In: R+4
Type - PredefinedType: ELEMENTEDWALL
Classification: Mur composite (Classification ARCHICAD)
Pset_WallCommon - AcousticRating: Non défini; ThermalTransmittance: 0; LoadBearing: yes; IsExternal: yes
PSET_Murs_ARCHI - Emplacement: Superstructure; Type: Murs Ossature Bois; Destination: Façade; Matériaux: Ossature Bois
AC_Pset_RenovationAndPhasing - Renovation Status: Existing
Material Properties - Component 5, Etanchéité - Pare-vapeur, ThermalConductivity: 0.5; Component 5, Etanchéité - Pare-vapeur, SpecificHeatCapacity: 1800 J/kg/K; Component 5, Etanchéité - Pare-vapeur, MassDensity: 980 kg/m3; Component 5, Etanchéité - Pare-vapeur, Embodied Energy: 76.7 (MJ/kg); Component 5, Etanchéité - Pare-vapeur, Embodied Carbon: 1.93 (kgCO₂/kg); Component 5, Etanchéité - Pare-vapeur, Name: Etanchéité - Pare-vapeur; Component 5, Etanchéité - Pare-vapeur, Participates in Collision Detection: no; Component 3, Bois - OSB 02, ThermalConductivity: 0.13; Component 3, Bois - OSB 02, SpecificHeatCapacity: 1350 J/kg/K; Component 3, Bois - OSB 02, MassDensity: 1000 kg/m3; Component 3, Bois - OSB 02, Embodied Energy: 11.98 (MJ/kg); Component 3, Bois - OSB 02, Embodied Carbon: 0.51 (kgCO₂/kg); Component 3, Bois - OSB 02, Name: Bois - OSB 02; Component 3, Bois - OSB 02, Participates in Collision Detection: yes; Component 2, Bois - Lattage, ThermalConductivity: 0.13; Component 2, Bois - Lattage, SpecificHeatCapacity: 1600 J/kg/K; Component 2, Bois - Lattage, MassDensity: 500 kg/m3; Component 2, Bois - Lattage, Embodied Energy: 6.95 (MJ/kg); Component 2, Bois - Lattage, Embodied Carbon: 0.29 (kgCO₂/kg); Component 2, Bois - Lattage, Name: Bois - Lattage; Component 2, Bois - Lattage, Participates in Collision Detection: yes; Component 1, Finition ext - Bardage bois, ThermalConductivity: 0.14; Component 1, Finition ext - Bardage bois, SpecificHeatCapacity: 2300 J/kg/K; Component 1, Finition ext - Bardage bois, MassDensity: 500 kg/m3; Component 1, Finition ext - Bardage bois, Embodied Energy: 10 (MJ/kg); Component 1, Finition ext - Bardage bois, Embodied Carbon: 0.36 (kgCO₂/kg); Component 1, Finition ext - Bardage bois, Name: Finition ext - Bardage bois; Component 1, Finition ext - Bardage bois, Participates in Collision Detection: no
BaseQuantities - Width: 0.31 m
Name | Material | Numéro de LOT | Numéro article | Component 7, Finition int - Plaque de plâtre, ThermalConductivity | Component 7, Finition int - Plaque de plâtre, SpecificHeatCapacity (J/kg/K) | Component 7, Finition int - Plaque de plâtre, MassDensity (kg/m3) | Component 7, Finition int - Plaque de plâtre, Embodied Energy | Component 7, Finition int - Plaque de plâtre, Embodied Carbon | Component 7, Finition int - Plaque de plâtre, Name | Component 7, Finition int - Plaque de plâtre, Participates in Collision Detection | Component 6, Isolation - Laine de verre, ThermalConductivity | Component 6, Isolation - Laine de verre, SpecificHeatCapacity (J/kg/K) | Component 6, Isolation - Laine de verre, MassDensity (kg/m3) | Component 6, Isolation - Laine de verre, Embodied Energy | Component 6, Isolation - Laine de verre, Embodied Carbon | Component 6, Isolation - Laine de verre, Name | Component 6, Isolation - Laine de verre, Participates in Collision Detection | Component 6 | Length (m) | Height (m) | GrossFootprintArea (m2) = NetFootprintArea (m2) | GrossSideArea (m2) | NetSideArea (m2) | GrossVolume (m3) | NetVolume (m3)
M_Ext-007 | Finition int - Plaque de plâtre, Isolation - Laine de verre (2), Etanchéité - Pare-vapeur, Bois - OSB 02, Bois - Lattage, Finition ext - Bardage bois | LOT 05; LOT 09 | L05.2.1.2; L05.2.3.1; L09.2.1.2.1 | 0.8 | 1000 | 1600 | 1.45 (MJ/kg) | 0.22 (kgCO₂/kg) | Finition int - Plaque de plâtre | no | 0.038 | 1030 | 14.5 | 26.5 (MJ/kg) | 1.32 (kgCO₂/kg) | Isolation - Laine de verre | no | 2 with these values | 3.17557 | 2.51 | 0.970719 | 7.78902 | 6.82902 | 2.41744 | 2.11984
M_Ext-007 | Finition int - Plaque de plâtre, Isolation - Laine de verre (2), Etanchéité - Pare-vapeur, Bois - OSB 02, Bois - Lattage, Finition ext - Bardage bois | LOT 05; LOT 09 | L05.2.1.2; L05.2.3.1; L09.2.1.2.1 | 0.8 | 1000 | 1600 | 1.45 (MJ/kg) | 0.22 (kgCO₂/kg) | Finition int - Plaque de plâtre | no | 0.038 | 1030 | 14.5 | 26.5 (MJ/kg) | 1.32 (kgCO₂/kg) | Isolation - Laine de verre | no | 2 with these values | 8.72539 | 2.51 | 2.73229 | 21.9037 | 18.1237 | 6.85652 | 5.68472
M_Ext-007 | Finition ext - Bardage bois, Bois - Lattage, Bois - OSB 02, Isolation - Laine de verre (2), Etanchéité - Pare-vapeur, Finition int - Plaque de plâtre | LOT 05; LOT 09 | L05.2.1.2; L05.2.3.1; L09.2.1.2.1 | 0.8 | 1000 | 1600 | 1.45 (MJ/kg) | 0.22 (kgCO₂/kg) | Finition int - Plaque de plâtre | no |  |  |  |  |  |  |  |  | 6.319 | 2.51 | 1.95889 | 15.8218 | 12.4618 | 4.91573 | 3.87413 | Material Properties - Component 4, Isolation - Laine de verre, ThermalConductivity: 0.038; Component 4, Isolation - Laine de verre, SpecificHeatCapacity: 1030 J/kg/K; Component 4, Isolation - Laine de verre, MassDensity: 14.5 kg/m3; Component 4, Isolation - Laine de verre, Embodied Energy: 26.5 (MJ/kg); Component 4, Isolation - Laine de verre, Embodied Carbon: 1.32 (kgCO₂/kg); Component 4, Isolation - Laine de verre, Name: Isolation - Laine de verre; Component 4, Isolation - Laine de verre, Participates in Collision Detection: no; Component 4: 2 with these values
M_Ext-009 | Finition int - Plaque de plâtre, Isolation - Laine de verre (2), Etanchéité - Pare-vapeur, Bois - OSB 02, Bois - Lattage, Finition ext - Bardage bois | LOT 05; LOT 09 | L05.2.1.2; L05.2.3.1; L09.2.1.2.1 | 0.8 | 1000 | 1600 | 1.45 (MJ/kg) | 0.22 (kgCO₂/kg) | Finition int - Plaque de plâtre | no | 0.038 | 1030 | 14.5 | 26.5 (MJ/kg) | 1.32 (kgCO₂/kg) | Isolation - Laine de verre | no | 2 with these values | 10.8973 | 2.5 | 3.37815 | 27.1284 | 25.2384 | 8.44156 | 7.85566
M_Ext-009 | Finition int - Plaque de plâtre, Isolation - Laine de verre (2), Etanchéité - Pare-vapeur, Bois - OSB 02, Bois - Lattage, Finition ext - Bardage bois | LOT 04; LOT 05; LOT 09 | L04.2.12.8.3; L05.2.1.2; L05.2.3.1; L09.2.1.2.1 | 0.8 | 1000 | 1600 | 1.45 (MJ/kg) | 0.22 (kgCO₂/kg) | Finition int - Plaque de plâtre | no | 0.038 | 1030 | 14.5 | 26.5 (MJ/kg) | 1.32 (kgCO₂/kg) | Isolation - Laine de verre | no | 2 with these values | 0.9 | 2.5 | 0.279 | 2.196 | 0.396 | 0.691326 | 0.133326
M_Ext-009 | Finition int - Plaque de plâtre, Isolation - Laine de verre (2), Etanchéité - Pare-vapeur, Bois - OSB 02, Bois - Lattage, Finition ext - Bardage bois | LOT 05; LOT 09 | L05.2.1.2; L05.2.3.1; L09.2.1.2.1 | 0.8 | 1000 | 1600 | 1.45 (MJ/kg) | 0.22 (kgCO₂/kg) | Finition int - Plaque de plâtre | no | 0.038 | 1030 | 14.5 | 26.5 (MJ/kg) | 1.32 (kgCO₂/kg) | Isolation - Laine de verre | no | 2 with these values | 2.21653 | 2.5 | 0.714543 | 5.57274 | 5.57274 | 1.78555 | 1.78555
M_Ext-008 | Finition ext - Bardage bois, Bois - Lattage, Bois - OSB 02, Isolation - Laine de verre (2), Etanchéité - Pare-vapeur, Finition int - Plaque de plâtre | LOT 05; LOT 09 | L05.2.1.2; L05.2.3.1; L09.2.1.2.1 | 0.8 | 1000 | 1600 | 1.45 (MJ/kg) | 0.22 (kgCO₂/kg) | Finition int - Plaque de plâtre | no |  |  |  |  |  |  |  |  | 0.992 | 2.5 | 0.30752 | 2.47008 | 2.47008 | 0.768443 | 0.768443 | Material Properties - Component 4, Isolation - Laine de verre, ThermalConductivity: 0.038; Component 4, Isolation - Laine de verre, SpecificHeatCapacity: 1030 J/kg/K; Component 4, Isolation - Laine de verre, MassDensity: 14.5 kg/m3; Component 4, Isolation - Laine de verre, Embodied Energy: 26.5 (MJ/kg); Component 4, Isolation - Laine de verre, Embodied Carbon: 1.32 (kgCO₂/kg); Component 4, Isolation - Laine de verre, Name: Isolation - Laine de verre; Component 4, Isolation - Laine de verre, Participates in Collision Detection: no; Component 4: 2 with these values
M_Ext-007 | Finition int - Plaque de plâtre, Isolation - Laine de verre (2), Etanchéité - Pare-vapeur, Bois - OSB 02, Bois - Lattage, Finition ext - Bardage bois | LOT 04; LOT 05; LOT 09 | L04.2.12.8.3; L05.2.1.2; L05.2.3.1; L09.2.1.2.1 | 0.8 | 1000 | 1600 | 1.45 (MJ/kg) | 0.22 (kgCO₂/kg) | Finition int - Plaque de plâtre | no | 0.038 | 1030 | 14.5 | 26.5 (MJ/kg) | 1.32 (kgCO₂/kg) | Isolation - Laine de verre | no | 2 with these values | 0.785809 | 2.51 | 0.229892 | 1.91125 | 1.91125 | 0.572127 | 0.572127
M_Ext-009 | Isolation - Laine de verre (2), Etanchéité - Pare-vapeur, Bois - OSB 02, Bois - Lattage, Finition ext - Bardage bois | LOT 05; LOT 09 | L05.2.1.2; L05.2.3.1; L09.2.1.2.1 |  |  |  |  |  |  |  | 0.038 | 1030 | 14.5 | 26.5 (MJ/kg) | 1.32 (kgCO₂/kg) | Isolation - Laine de verre | no | 2 with these values | 0.155 | 2.5 | 0.034341 | 0.223212 | 0.223212 | 0.0542269 | 0.0542269
M_Ext-009 | Finition ext - Bardage bois, Bois - Lattage, Bois - OSB 02, Isolation - Laine de verre (2), Etanchéité - Pare-vapeur | LOT 04; LOT 05; LOT 09 | L04.2.12.8.3; L05.2.1.2; L05.2.3.1; L09.2.1.2.1 |  |  |  |  |  |  |  |  |  |  |  |  |  |  |  | 0.155 | 2.5 | 0.034341 | 0.354 | 0.354 | 0.08556 | 0.08556 | Material Properties - Component 4, Isolation - Laine de verre, ThermalConductivity: 0.038; Component 4, Isolation - Laine de verre, SpecificHeatCapacity: 1030 J/kg/K; Component 4, Isolation - Laine de verre, MassDensity: 14.5 kg/m3; Component 4, Isolation - Laine de verre, Embodied Energy: 26.5 (MJ/kg); Component 4, Isolation - Laine de verre, Embodied Carbon: 1.32 (kgCO₂/kg); Component 4, Isolation - Laine de verre, Name: Isolation - Laine de verre; Component 4, Isolation - Laine de verre, Participates in Collision Detection: no; Component 4: 2 with these values
M_Ext-009 | Finition int - Plaque de plâtre, Isolation - Laine de verre (2), Etanchéité - Pare-vapeur, Bois - OSB 02, Bois - Lattage, Finition ext - Bardage bois | LOT 04; LOT 05; LOT 09 | L04.2.12.8.3; L05.2.1.2; L05.2.3.1; L09.2.1.2.1 | 0.8 | 1000 | 1600 | 1.45 (MJ/kg) | 0.22 (kgCO₂/kg) | Finition int - Plaque de plâtre | no | 0.038 | 1030 | 14.5 | 26.5 (MJ/kg) | 1.32 (kgCO₂/kg) | Isolation - Laine de verre | no | 2 with these values | 1.8 | 2.5 | 0.558 | 4.392 | 0.792 | 1.38265 | 0.266652

# IfcWall: 1 - Mur PARPAING 20 + bardage 265 (3)
In: R+3
Type - ElementType: PARTITIONING; PredefinedType: USERDEFINED
Classification: Mur (Classification ARCHICAD); Cloison (Classification ARCHICAD); Material: Bois - Bardage, Bois - Lattage, Parpaing 20cm
Pset_WallCommon - AcousticRating: Non défini; ThermalTransmittance: 0; LoadBearing: yes; IsExternal: yes
PSET_Murs_ARCHI - Emplacement: Superstructure; Type: Mur béton banché 20cm; Destination: Gaine Technique Palière; Matériaux: BETON
AC_Pset_RenovationAndPhasing - Renovation Status: Existing
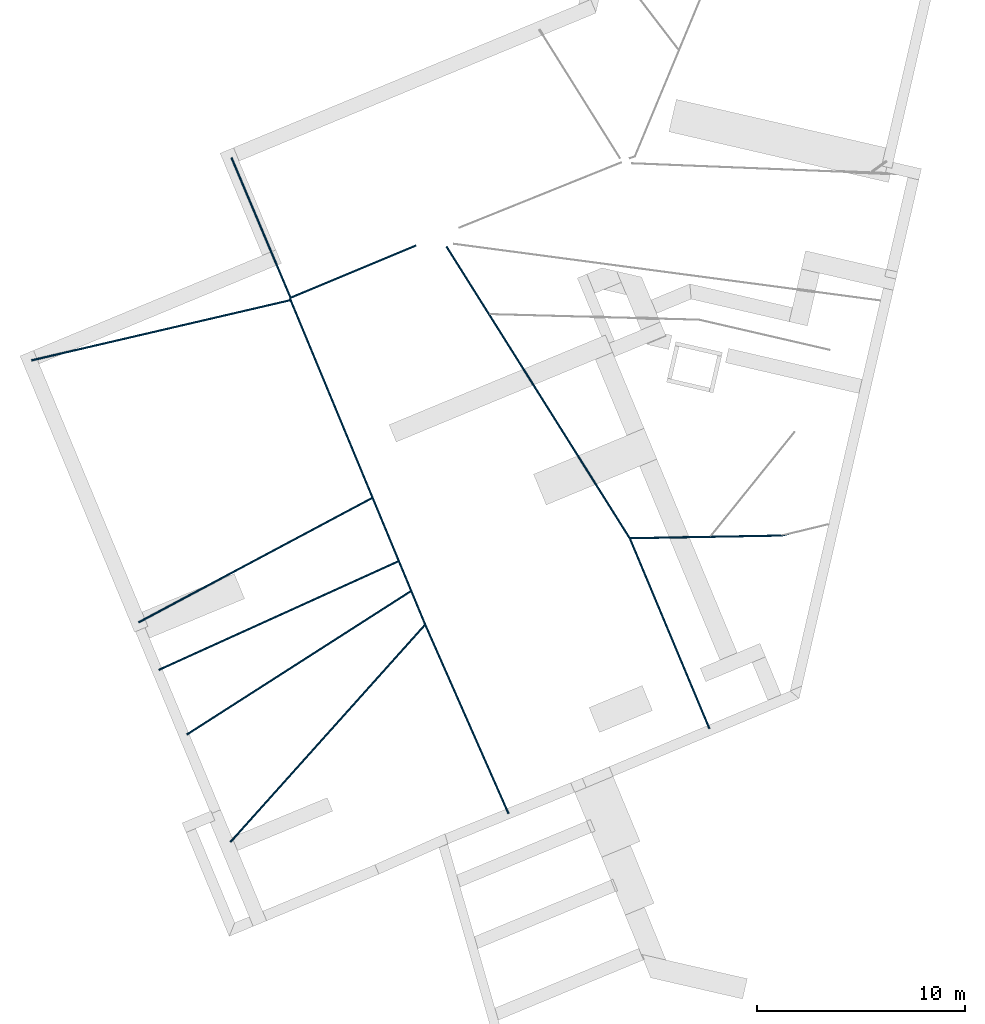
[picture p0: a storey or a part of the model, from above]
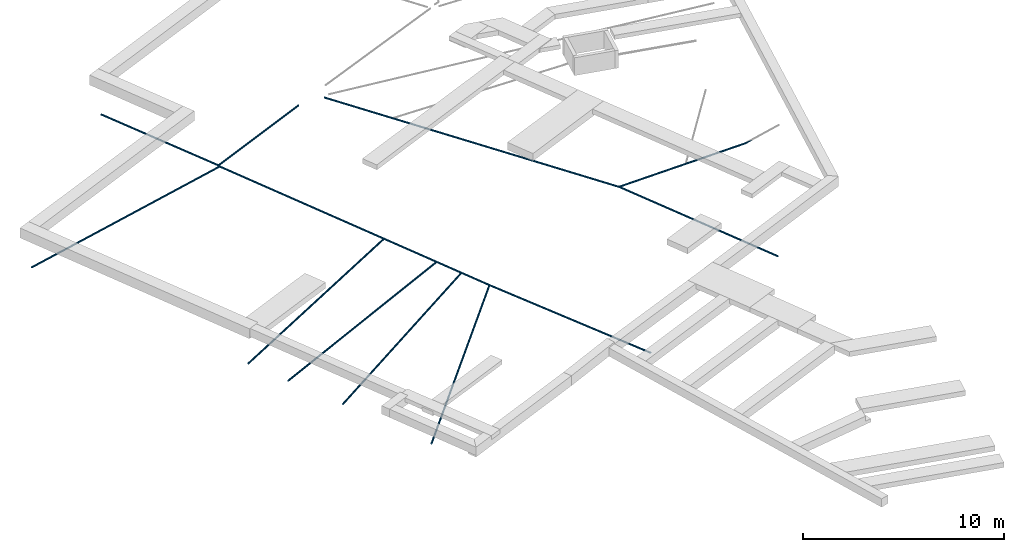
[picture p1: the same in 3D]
Properties of the parts of a building model (IFC2X3), part 7 of 22

# IfcWall: 1 - Mur PARPAING 20 + bardage 265 (3)
Material Properties - Component 1, Bois - Bardage, ThermalConductivity: 0.14; Component 1, Bois - Bardage, SpecificHeatCapacity: 2300 J/kg/K; Component 1, Bois - Bardage, MassDensity: 500 kg/m3; Component 1, Bois - Bardage, Embodied Energy: 10 (MJ/kg); Component 1, Bois - Bardage, Embodied Carbon: 0.36 (kgCO₂/kg); Component 1, Bois - Bardage, Name: Bois - Bardage; Component 1, Bois - Bardage, Participates in Collision Detection: yes; Component 2, Bois - Lattage, ThermalConductivity: 0.13; Component 2, Bois - Lattage, SpecificHeatCapacity: 1600 J/kg/K; Component 2, Bois - Lattage, MassDensity: 500 kg/m3; Component 2, Bois - Lattage, Embodied Energy: 6.95 (MJ/kg); Component 2, Bois - Lattage, Embodied Carbon: 0.29 (kgCO₂/kg); Component 2, Bois - Lattage, Name: Bois - Lattage; Component 2, Bois - Lattage, Participates in Collision Detection: yes; Component 3, Parpaing 20cm, ThermalConductivity: 0.6; Component 3, Parpaing 20cm, SpecificHeatCapacity: 880 J/kg/K; Component 3, Parpaing 20cm, MassDensity: 1400 kg/m3; Component 3, Parpaing 20cm, Embodied Energy: 0.72 (MJ/kg); Component 3, Parpaing 20cm, Embodied Carbon: 0.088 (kgCO₂/kg); Component 3, Parpaing 20cm, Name: Parpaing 20cm; Component 3, Parpaing 20cm, Participates in Collision Detection: yes
BaseQuantities - Width: 0.265 m
Name | Length (m) | Height (m) | GrossFootprintArea (m2) = NetFootprintArea (m2) | GrossSideArea (m2) = NetSideArea (m2) | GrossVolume (m3) = NetVolume (m3)
M_Ext-018 | 0.6595 | 2.6 | 0.19488 | 1.74474 | 0.47998
M_Ext-019 | 0.734324 | 2.52645 | 0.194596 | 1.9555 | 0.480963
M_Ext-020 | 0.6595 | 2.6 | 0.152655 | 1.46374 | 0.373754

# IfcWall: 1 - Mur PARPAING 20 + ravalement 1 face 215 (4)
In: Rez-de-chaussée
Type - ElementType: PARAPET; PredefinedType: USERDEFINED
Classification: Mur d'acrotère (Classification ARCHICAD)
Pset_WallCommon - AcousticRating: Non défini; ThermalTransmittance: 0; LoadBearing: yes; IsExternal: yes
PSET_Murs_ARCHI - Emplacement: Infrastructure; Type: Mur béton banché 20cm; Destination: Façade; Matériaux: BETON
Propriétés DCE - Numéro de LOT: LOT 04; LOT 16; Numéro article: L16.2.1
AC_Pset_RenovationAndPhasing - Renovation Status: Existing
Material Properties - Component 1, Finition ext - Crépis, ThermalConductivity: 0.8; Component 1, Finition ext - Crépis, SpecificHeatCapacity: 1000 J/kg/K; Component 1, Finition ext - Crépis, MassDensity: 1600 kg/m3; Component 1, Finition ext - Crépis, Embodied Energy: 1.4 (MJ/kg); Component 1, Finition ext - Crépis, Embodied Carbon: 0.09 (kgCO₂/kg); Component 1, Finition ext - Crépis, Name: Finition ext - Crépis; Component 1, Finition ext - Crépis, Participates in Collision Detection: no; Component 2, Parpaing 20cm, ThermalConductivity: 0.6; Component 2, Parpaing 20cm, SpecificHeatCapacity: 880 J/kg/K; Component 2, Parpaing 20cm, MassDensity: 1400 kg/m3; Component 2, Parpaing 20cm, Embodied Energy: 0.72 (MJ/kg); Component 2, Parpaing 20cm, Embodied Carbon: 0.088 (kgCO₂/kg); Component 2, Parpaing 20cm, Name: Parpaing 20cm; Component 2, Parpaing 20cm, Participates in Collision Detection: yes
BaseQuantities - Width: 0.215 m
Name | Material | Length (m) | Height (m) | GrossFootprintArea (m2) = NetFootprintArea (m2) | GrossSideArea (m2) = NetSideArea (m2) | GrossVolume (m3) = NetVolume (m3)
M_Ext-007 | Finition ext - Crépis, Parpaing 20cm | 7.1499 | 0.9 | 1.53723 | 6.43491 | 1.38351
M_Ext-007 | Parpaing 20cm, Finition ext - Crépis | 1.33978 | 0.7 | 0.285278 | 0.873097 | 0.199695
M_Ext-007 | Parpaing 20cm, Finition ext - Crépis | 7.94822 | 0.7 | 1.68875 | 5.49375 | 1.18213
M_Ext-007 | Finition ext - Crépis, Parpaing 20cm | 8.11458 | 0.7 | 1.76752 | 5.75021 | 1.23727

# IfcWall: 1 - Mur PARPAING 20 + ravalement 1 face 215, M_Ext-007
In: Rez-de-chaussée
Type - PredefinedType: ELEMENTEDWALL
Classification: Mur composite (Classification ARCHICAD); Material: Parpaing 20cm, Finition ext - Crépis
Pset_WallCommon - AcousticRating: Non défini; ThermalTransmittance: 0; LoadBearing: yes; IsExternal: yes
PSET_Murs_ARCHI - Emplacement: Superstructure; Type: Mur béton banché 20cm; Destination: Façade; Matériaux: BETON
Propriétés DCE - Numéro de LOT: LOT 04; LOT 16; Numéro article: L16.2.1
AC_Pset_RenovationAndPhasing - Renovation Status: Existing
Material Properties - Component 2, Parpaing 20cm, ThermalConductivity: 0.6; Component 2, Parpaing 20cm, SpecificHeatCapacity: 880 J/kg/K; Component 2, Parpaing 20cm, MassDensity: 1400 kg/m3; Component 2, Parpaing 20cm, Embodied Energy: 0.72 (MJ/kg); Component 2, Parpaing 20cm, Embodied Carbon: 0.088 (kgCO₂/kg); Component 2, Parpaing 20cm, Name: Parpaing 20cm; Component 2, Parpaing 20cm, Participates in Collision Detection: yes; Component 1, Finition ext - Crépis, ThermalConductivity: 0.8; Component 1, Finition ext - Crépis, SpecificHeatCapacity: 1000 J/kg/K; Component 1, Finition ext - Crépis, MassDensity: 1600 kg/m3; Component 1, Finition ext - Crépis, Embodied Energy: 1.4 (MJ/kg); Component 1, Finition ext - Crépis, Embodied Carbon: 0.09 (kgCO₂/kg); Component 1, Finition ext - Crépis, Name: Finition ext - Crépis; Component 1, Finition ext - Crépis, Participates in Collision Detection: no
BaseQuantities - Length: 4.46867 m; Height: 2.27 m; Width: 0.215 m; GrossFootprintArea: 0.960764 m2; NetFootprintArea: 0.960764 m2; GrossSideArea: 9.92207 m2; NetSideArea: 9.92207 m2; GrossVolume: 2.15024 m3; NetVolume: 2.15024 m3

# IfcWall: 1 - Mur PARPAING 20 + ravalement 1 face 215, M_Ext-007
In: Rez-de-chaussée
Type - PredefinedType: STANDARD
Classification: Mur standard (Classification ARCHICAD); Material: Parpaing 20cm, Finition ext - Crépis
Pset_WallCommon - AcousticRating: Non défini; ThermalTransmittance: 0; LoadBearing: yes; IsExternal: yes
PSET_Murs_ARCHI - Emplacement: Infrastructure; Type: Mur béton banché 20cm; Destination: Façade; Matériaux: BETON
Propriétés DCE - Numéro de LOT: LOT 04; LOT 16; Numéro article: L16.2.1
AC_Pset_RenovationAndPhasing - Renovation Status: Existing
Material Properties - Component 2, Parpaing 20cm, ThermalConductivity: 0.6; Component 2, Parpaing 20cm, SpecificHeatCapacity: 880 J/kg/K; Component 2, Parpaing 20cm, MassDensity: 1400 kg/m3; Component 2, Parpaing 20cm, Embodied Energy: 0.72 (MJ/kg); Component 2, Parpaing 20cm, Embodied Carbon: 0.088 (kgCO₂/kg); Component 2, Parpaing 20cm, Name: Parpaing 20cm; Component 2, Parpaing 20cm, Participates in Collision Detection: yes; Component 1, Finition ext - Crépis, ThermalConductivity: 0.8; Component 1, Finition ext - Crépis, SpecificHeatCapacity: 1000 J/kg/K; Component 1, Finition ext - Crépis, MassDensity: 1600 kg/m3; Component 1, Finition ext - Crépis, Embodied Energy: 1.4 (MJ/kg); Component 1, Finition ext - Crépis, Embodied Carbon: 0.09 (kgCO₂/kg); Component 1, Finition ext - Crépis, Name: Finition ext - Crépis; Component 1, Finition ext - Crépis, Participates in Collision Detection: no
BaseQuantities - Length: 0.322582 m; Height: 2.54 m; Width: 0.215 m; GrossFootprintArea: 0.0693551 m2; NetFootprintArea: 0.0693551 m2; GrossSideArea: 0.814165 m2; NetSideArea: 0.814165 m2; GrossVolume: 0.175942 m3; NetVolume: 0.175942 m3

# IfcWall: 1 - Mur PARPAING 20 Endui + parement pierre 1 face 265 (9)
In: Rez-de-chaussée
Type - PredefinedType: ELEMENTEDWALL
Classification: Mur composite (Classification ARCHICAD); Material: Pierre, Parpaing 20cm, Finition ext - Crépis
Pset_WallCommon - AcousticRating: Non défini; ThermalTransmittance: 0; LoadBearing: yes; IsExternal: yes
PSET_Murs_ARCHI - Emplacement: Superstructure; Destination: Clôture; Matériaux: BETON
Propriétés DCE - Numéro article: L04.2.21.1.6. L04.2.21.1.7
AC_Pset_RenovationAndPhasing - Renovation Status: Existing
Material Properties - Component 3, Pierre, ThermalConductivity: 2.3; Component 3, Pierre, SpecificHeatCapacity: 1000 J/kg/K; Component 3, Pierre, MassDensity: 2600 kg/m3; Component 3, Pierre, Embodied Energy: 1.2 (MJ/kg); Component 3, Pierre, Embodied Carbon: 0.08 (kgCO₂/kg); Component 3, Pierre, Name: Pierre; Component 3, Pierre, Participates in Collision Detection: yes; Component 2, Parpaing 20cm, ThermalConductivity: 0.6; Component 2, Parpaing 20cm, SpecificHeatCapacity: 880 J/kg/K; Component 2, Parpaing 20cm, MassDensity: 1400 kg/m3; Component 2, Parpaing 20cm, Embodied Energy: 0.72 (MJ/kg); Component 2, Parpaing 20cm, Embodied Carbon: 0.088 (kgCO₂/kg); Component 2, Parpaing 20cm, Name: Parpaing 20cm; Component 2, Parpaing 20cm, Participates in Collision Detection: yes; Component 1, Finition ext - Crépis, ThermalConductivity: 0.8; Component 1, Finition ext - Crépis, SpecificHeatCapacity: 1000 J/kg/K; Component 1, Finition ext - Crépis, MassDensity: 1600 kg/m3; Component 1, Finition ext - Crépis, Embodied Energy: 1.4 (MJ/kg); Component 1, Finition ext - Crépis, Embodied Carbon: 0.09 (kgCO₂/kg); Component 1, Finition ext - Crépis, Name: Finition ext - Crépis; Component 1, Finition ext - Crépis, Participates in Collision Detection: no
BaseQuantities - Width: 0.265 m
Name | Type | Numéro de LOT | Length (m) | Height (m) | GrossFootprintArea (m2) = NetFootprintArea (m2) | GrossSideArea (m2) = NetSideArea (m2) | GrossVolume (m3) = NetVolume (m3) | Description
M_Ext-007 | Mur béton banché 20cm | LOT 04; LOT 16 | 3.05633 | 2 | 0.856195 | 6.32767 | 1.71239
Mur béton 20cm | Mur béton 20cm | LOT 04 | 9.84303 | 1.2239 | 2.5793 | 11.87 | 3.15151 | Mur de clôture
Mur béton 20cm | Mur béton 20cm | LOT 04 | 10.56 | 1.12346 | 2.83072 | 11.8789 | 3.1772 | Mur de clôture
Mur béton 20cm | Mur béton 20cm | LOT 04; LOT 16 | 0.557837 | 0.931537 | 0.169262 | 0.543013 | 0.157673 | Mur de clôture
Mur béton 20cm | Mur béton 20cm | LOT 04; LOT 16 | 2.61849 | 1.03154 | 0.693941 | 2.6896 | 0.714629 | Mur de clôture
Mur béton 20cm | Mur béton 20cm | LOT 04; LOT 16 | 4.02833 | 1.23 | 1.10157 | 4.74599 | 1.27448 | Mur de clôture
Mur béton 20cm | Mur béton 20cm | LOT 04; LOT 16 | 6.63023 | 0.931537 | 1.75701 | 6.17626 | 1.63671 | Mur de clôture
Mur béton 20cm | Mur béton 20cm | LOT 04; LOT 16 | 4.186 | 1.05168 | 1.07858 | 4.36454 | 1.13432 | Mur de clôture
Mur béton 20cm | Mur béton 20cm | LOT 04; LOT 16 | 0.648372 | 0.931537 | 0.171819 | 0.603982 | 0.160055 | Mur de clôture

# IfcWall: 2 - Murs Béton 18 + Enduit 1 Face 190 (66)
Type - ElementType: SOLIDWALL; PredefinedType: USERDEFINED
Pset_WallCommon - AcousticRating: Non défini; ThermalTransmittance: 0; LoadBearing: yes; IsExternal: yes
PSET_Murs_ARCHI - Type: Mur béton banché 18cm; Matériaux: BETON
Propriétés DCE - Numéro de LOT: LOT 04
AC_Pset_RenovationAndPhasing - Renovation Status: Existing
Material Properties - Component 2, Finition int - Enduit plâtre, ThermalConductivity: 0.57; Component 2, Finition int - Enduit plâtre, SpecificHeatCapacity: 1000 J/kg/K; Component 2, Finition int - Enduit plâtre, MassDensity: 1300 kg/m3; Component 2, Finition int - Enduit plâtre, Embodied Energy: 1.8 (MJ/kg); Component 2, Finition int - Enduit plâtre, Embodied Carbon: 0.13 (kgCO₂/kg); Component 2, Finition int - Enduit plâtre, Name: Finition int - Enduit plâtre; Component 2, Finition int - Enduit plâtre, Participates in Collision Detection: no; Component 1, Béton, ThermalConductivity: 2.3; Component 1, Béton, SpecificHeatCapacity: 1000 J/kg/K; Component 1, Béton, MassDensity: 2300 kg/m3; Component 1, Béton, Embodied Energy: 1.92 (MJ/kg); Component 1, Béton, Embodied Carbon: 0.198 (kgCO₂/kg); Component 1, Béton, Name: Béton; Component 1, Béton, Participates in Collision Detection: yes
BaseQuantities - Width: 0.19 m
Name | In | Classification | Material | Emplacement | Destination | Numéro article | Length (m) | Height (m) | GrossFootprintArea (m2) = NetFootprintArea (m2) | GrossSideArea (m2) = NetSideArea (m2) | GrossVolume (m3) = NetVolume (m3)
M_Ext-008 | R+1 | Mur porteur (Classification ARCHICAD); Mur (Classification ARCHICAD) | Finition int - Enduit plâtre, Béton | Superstructure | Mur intérieur | L04.2.12.3.2 | 3.24806 | 2.5 | 0.616131 | 7.99514 | 1.54033
M_Ext-008 | R+2 | Mur porteur (Classification ARCHICAD); Mur (Classification ARCHICAD) | Finition int - Enduit plâtre, Béton | Superstructure | Mur intérieur | L04.2.12.3.2 | 3.24806 | 2.5 | 0.616131 | 7.99514 | 1.54033
M_Ext-008 | R+3 | Mur porteur (Classification ARCHICAD); Mur (Classification ARCHICAD) | Finition int - Enduit plâtre, Béton | Superstructure | Mur intérieur | L04.2.12.3.2 | 3.24806 | 2.5 | 0.649631 | 8.35764 | 1.62408
M_Ext-009 | Rez-de-chaussée | Mur porteur (Classification ARCHICAD) | Béton, Finition int - Enduit plâtre | Superstructure | Mur intérieur | L04.2.12.3.2 | 2.43339 | 2.51 | 0.482943 | 5.99536 | 1.20969
M_Ext-009 | R+1 | Mur porteur (Classification ARCHICAD); Mur (Classification ARCHICAD) | Béton, Finition int - Enduit plâtre | Superstructure | Mur intérieur | L04.2.12.3.2 | 2.43339 | 2.51 | 0.443011 | 5.82738 | 1.11196
M_Ext-009 | R+2 | Mur porteur (Classification ARCHICAD); Mur (Classification ARCHICAD) | Béton, Finition int - Enduit plâtre | Superstructure | Mur intérieur | L04.2.12.3.2 | 2.43339 | 2.51 | 0.443011 | 5.82738 | 1.11196
M_Ext-009 | Rez-de-chaussée | Mur porteur (Classification ARCHICAD) | Béton, Finition int - Enduit plâtre | Superstructure | Mur intérieur | L04.2.12.3.2 | 1.22165 | 2.51 | 0.232113 | 3.05412 | 0.582399
M_Ext-008 | R+1 | Mur porteur (Classification ARCHICAD); Mur (Classification ARCHICAD) | Finition int - Enduit plâtre, Béton | Superstructure | Mur intérieur | L04.2.12.3.2 | 0.652363 | 2.51 | 0.121619 | 1.4415 | 0.30506
M_Ext-008 | Rez-de-chaussée | Mur porteur (Classification ARCHICAD) | Finition int - Enduit plâtre, Béton | Superstructure | Mur intérieur | L04.2.12.3.2 | 0.652363 | 2.51 | 0.122999 | 1.45238 | 0.305278
M_Ext-008 | R+1 | Mur porteur (Classification ARCHICAD); Mur (Classification ARCHICAD) | Finition int - Enduit plâtre, Béton | Superstructure | Mur intérieur | L04.2.12.3.2 | 0.565 | 2.5 | 0.0739 | 1.1625 | 0.18475
M_Ext-009 | R+1 | Mur porteur (Classification ARCHICAD); Mur (Classification ARCHICAD) | Finition int - Enduit plâtre, Béton | Superstructure | Mur intérieur | L04.2.12.3.2 | 0.444 | 2.51 | 0.06906 | 1.11444 | 0.173341
M_Ext-009 | R+1 | Mur porteur (Classification ARCHICAD); Mur (Classification ARCHICAD) | Finition int - Enduit plâtre, Béton | Superstructure | Mur intérieur | L04.2.12.3.2 | 0.35 | 2.51 | 0.0818 | 0.8785 | 0.205318
M_Ext-008 | R+1 | Mur porteur (Classification ARCHICAD); Mur (Classification ARCHICAD) | Béton, Finition int - Enduit plâtre | Superstructure | Mur intérieur | L04.2.12.3.2 | 0.45 | 2.5 | 0.0854 | 1.1125 | 0.2135
M_Ext-008 | R+1 | Mur porteur (Classification ARCHICAD); Mur (Classification ARCHICAD) | Finition int - Enduit plâtre, Béton | Superstructure | Mur intérieur | L04.2.12.3.2 | 0.355 | 2.51 | 0.06472 | 0.51335 | 0.159644
M_Ext-009 | R+2 | Mur porteur (Classification ARCHICAD); Mur (Classification ARCHICAD) | Finition int - Enduit plâtre, Béton | Superstructure | Mur intérieur | L04.2.12.3.2 | 0.444 | 2.51 | 0.06906 | 1.11444 | 0.173341
M_Ext-008 | R+2 | Mur porteur (Classification ARCHICAD); Mur (Classification ARCHICAD) | Béton, Finition int - Enduit plâtre | Superstructure | Mur intérieur | L04.2.12.3.2 | 0.45 | 2.5 | 0.0854 | 1.1125 | 0.2135
M_Ext-008 | R+2 | Mur porteur (Classification ARCHICAD) | Finition int - Enduit plâtre, Béton | Superstructure | Mur intérieur | L04.2.12.3.2 | 0.665635 | 2.51 | 0.109271 | 1.43229 | 0.27427
M_Ext-009 | R+2 | Mur porteur (Classification ARCHICAD); Mur (Classification ARCHICAD) | Finition int - Enduit plâtre, Béton | Superstructure | Mur intérieur | L04.2.12.3.2 | 0.35 | 2.51 | 0.0818 | 0.8785 | 0.205318
M_Ext-008 | R+2 | Mur porteur (Classification ARCHICAD); Mur (Classification ARCHICAD) | Finition int - Enduit plâtre, Béton | Superstructure | Mur intérieur | L04.2.12.3.2 | 0.565 | 2.5 | 0.0739 | 1.1625 | 0.18475
M_Ext-008 | R+3 | Mur porteur (Classification ARCHICAD); Mur (Classification ARCHICAD) | Finition int - Enduit plâtre, Béton | Superstructure | Mur intérieur | L04.2.12.3.2 | 0.565 | 2.5 | 0.0739 | 1.1625 | 0.18475
M_Ext-008 | Rez-de-chaussée | Mur porteur (Classification ARCHICAD) | Finition int - Enduit plâtre, Béton | Superstructure | Mur intérieur | L04.2.12.3.2 | 0.57 | 2.5 | 0.0758 | 1.1875 | 0.1895
M_Ext-008 | Rez-de-chaussée | Mur porteur (Classification ARCHICAD) | Finition int - Enduit plâtre, Béton | Superstructure | Mur intérieur | L04.2.12.3.2 | 0.355 | 2.51 | 0.0665 | 0.516 | 0.159665
M_Ext-008 | Rez-de-chaussée | Mur porteur (Classification ARCHICAD) | Finition int - Enduit plâtre, Béton | Infrastructure | Façade | L04.2.12.4 | 4.81174 | 2.51 | 0.91423 | 12.0775 | 2.29472
M_Ext-009 | Rez-de-chaussée | Mur porteur (Classification ARCHICAD) | Finition int - Enduit plâtre, Béton | Superstructure | Mur intérieur | L04.2.12.3.2 | 0.444 | 2.51 | 0.06906 | 1.07893 | 0.17263
M_Ext-008 | Rez-de-chaussée | Mur porteur (Classification ARCHICAD) | Finition int - Enduit plâtre, Béton | Superstructure | Mur intérieur | L04.2.12.3.2 | 0.665635 | 2.51 | 0.109271 | 1.43229 | 0.27427
M_Ext-009 | Rez-de-chaussée | Mur porteur (Classification ARCHICAD) | Finition int - Enduit plâtre, Béton | Superstructure | Mur intérieur | L04.2.12.3.2 | 0.35 | 2.51 | 0.0493 | 0.64005 | 0.123743
M_Ext-008 | R+1 | Mur porteur (Classification ARCHICAD); Mur (Classification ARCHICAD) | Finition int - Enduit plâtre, Béton | Superstructure | Mur intérieur | L04.2.12.3.2 | 0.534 | 2.52 | 0.10146 | 1.32966 | 0.254738
M_Ext-009 | R+1 | Mur porteur (Classification ARCHICAD); Mur (Classification ARCHICAD) | Finition int - Enduit plâtre, Béton | Superstructure | Mur intérieur | L04.2.12.3.2 | 0.993 | 2.51 | 0.17337 | 2.49243 | 0.435159
M_Ext-008 | R+1 | Mur porteur (Classification ARCHICAD) | Finition int - Enduit plâtre, Béton | Superstructure | Mur intérieur | L04.2.12.3.2 | 0.665635 | 2.51 | 0.109271 | 1.43229 | 0.27427
M_Ext-008 | R+1 | Mur porteur (Classification ARCHICAD) | Béton, Finition int - Enduit plâtre | Superstructure | Mur intérieur; Mur joint de dilatation | L04.2.12.4 | 5.01083 | 2.51 | 0.934857 | 12.1362 | 2.34244
M_Ext-009 | R+2 | Mur porteur (Classification ARCHICAD); Mur (Classification ARCHICAD) | Finition int - Enduit plâtre, Béton | Superstructure | Mur intérieur | L04.2.12.3.2 | 0.993 | 2.51 | 0.17337 | 2.49243 | 0.435159
M_Ext-008 | R+2 | Mur porteur (Classification ARCHICAD) | Finition int - Enduit plâtre, Béton | Superstructure | Mur intérieur; Mur joint de dilatation | L04.2.12.4 | 4.98424 | 2.52 | 0.942407 | 12.266 | 2.35473
M_Ext-008 | R+2 | Mur porteur (Classification ARCHICAD) | Béton, Finition int - Enduit plâtre | Superstructure | Mur intérieur; Mur joint de dilatation | L04.2.12.4 | 5.94486 | 2.51 | 1.12952 | 14.7966 | 2.8326
M_Ext-009 | R+3 | Mur porteur (Classification ARCHICAD); Mur (Classification ARCHICAD) | Finition int - Enduit plâtre, Béton | Superstructure | Mur intérieur | L04.2.12.3.2 | 0.993 | 2.51 | 0.17337 | 2.49243 | 0.435159
M_Ext-009 | R+3 | Mur porteur (Classification ARCHICAD); Mur (Classification ARCHICAD) | Finition int - Enduit plâtre, Béton | Superstructure | Mur intérieur | L04.2.12.3.2 | 0.424 | 2.52 | 0.06526 | 1.06681 | 0.163854
M_Ext-009 | Rez-de-chaussée | Mur porteur (Classification ARCHICAD) | Béton, Finition int - Enduit plâtre | Infrastructure | Façade | L04.2.12.4 | 5.74741 | 2.51 | 1.12323 | 14.1419 | 2.7531
M_Ext-008 | Rez-de-chaussée | Mur porteur (Classification ARCHICAD) | Finition int - Enduit plâtre, Béton | Superstructure | Mur intérieur | L04.2.12.3.2 | 0.582674 | 2.51 | 0.0954081 | 1.45579 | 0.239452
M_Ext-009 | Rez-de-chaussée | Mur porteur (Classification ARCHICAD) | Béton, Finition int - Enduit plâtre | Superstructure | Mur intérieur | L04.2.12.3.2 | 0.539 | 2.51 | 0.08456 | 1.34645 | 0.212227
M_Ext-008 | Rez-de-chaussée | Mur porteur (Classification ARCHICAD) | Finition int - Enduit plâtre, Béton | Superstructure | Mur intérieur | L04.2.12.3.2 | 1.288 | 2.51 | 0.24472 | 3.23288 | 0.614247
M_Ext-009 | Rez-de-chaussée | Mur porteur (Classification ARCHICAD) | Finition int - Enduit plâtre, Béton | Superstructure | Mur intérieur | L04.2.12.3.2 | 0.993 | 2.51 | 0.17337 | 2.42041 | 0.433718
M_Ext-009 | Rez-de-chaussée | Mur porteur (Classification ARCHICAD) | Finition int - Enduit plâtre, Béton | Infrastructure | Façade | L04.2.12.4 | 6.01553 | 2.51 | 1.15887 | 14.8149 | 2.84256
M_Ext-008 | Rez-de-chaussée | Mur porteur (Classification ARCHICAD) | Finition int - Enduit plâtre, Béton | Superstructure | Mur intérieur | L04.2.12.3.2 | 0.534 | 2.51 | 0.10146 | 1.34034 | 0.254665
M_Ext-008 | Rez-de-chaussée | Mur porteur (Classification ARCHICAD) | Béton, Finition int - Enduit plâtre | Infrastructure | Façade | L04.2.12.4 | 1.9625 | 2.51 | 0.3635 | 4.65605 | 0.912385
M_Ext-008 | Rez-de-chaussée | Mur porteur (Classification ARCHICAD) | Finition int - Enduit plâtre, Béton | Superstructure | Mur intérieur | L04.2.12.3.2 | 0.68 | 2.51 | 0.1139 | 1.6991 | 0.285873
M_Ext-008 | Rez-de-chaussée | Mur porteur (Classification ARCHICAD) | Béton, Finition int - Enduit plâtre | Superstructure | Mur intérieur | L04.2.12.3.2 | 0.449548 | 2.5 | 0.052914 | 0.886369 | 0.132285
M_Ext-008 | Rez-de-chaussée | Mur porteur (Classification ARCHICAD) | Béton, Finition int - Enduit plâtre | Superstructure | Mur intérieur | L04.2.12.3.2 | 0.123777 | 2.51 | 0.0340626 | 0.449985 | 0.0854971
M_Ext-008 | Rez-de-chaussée | Mur porteur (Classification ARCHICAD) | Béton, Finition int - Enduit plâtre | Infrastructure | Façade | L04.2.12.4 | 5.01083 | 2.51 | 0.934857 | 12.3387 | 2.34649
M_Ext-009 | Rez-de-chaussée | Mur porteur (Classification ARCHICAD) | Béton, Finition int - Enduit plâtre | Infrastructure | Façade | L04.2.12.4 | 5.97853 | 2.5 | 1.12546 | 14.6633 | 2.81365
M_Ext-009 | Rez-de-chaussée | Mur porteur (Classification ARCHICAD) | Finition int - Enduit plâtre, Béton | Infrastructure | Façade | L04.2.12.4 | 5.61741 | 2.51 | 1.08323 | 13.8156 | 2.6527
M_Ext-008 | R+1 | Mur porteur (Classification ARCHICAD) | Béton, Finition int - Enduit plâtre | Superstructure | Mur intérieur; Mur joint de dilatation | L04.2.12.4 | 1.9625 | 2.52 | 0.367192 | 4.58227 | 0.897994
M_Ext-009 | R+1 | Mur porteur (Classification ARCHICAD) | Finition int - Enduit plâtre, Béton | Superstructure | Mur intérieur; Mur joint de dilatation | L04.2.12.4 | 6.00981 | 2.51 | 1.13249 | 14.8148 | 2.84255
M_Ext-008 | R+1 | Mur porteur (Classification ARCHICAD) | Finition int - Enduit plâtre, Béton | Superstructure | Mur intérieur; Mur joint de dilatation | L04.2.12.4 | 5.14174 | 2.52 | 0.97693 | 12.9064 | 2.45222
M_Ext-009 | R+1 | Mur porteur (Classification ARCHICAD) | Béton, Finition int - Enduit plâtre | Superstructure | Mur intérieur; Mur joint de dilatation | L04.2.12.4 | 5.57419 | 2.51 | 1.07715 | 14.0047 | 2.69914
M_Ext-008 | R+1 | Mur porteur (Classification ARCHICAD); Mur (Classification ARCHICAD) | Finition int - Enduit plâtre, Béton | Superstructure | Mur intérieur | L04.2.12.3.2 | 1.488 | 2.52 | 0.28272 | 3.73556 | 0.709756
M_Ext-009 | R+1 | Mur porteur (Classification ARCHICAD) | Béton, Finition int - Enduit plâtre | Superstructure | Mur intérieur; Mur joint de dilatation | L04.2.12.4 | 5.97281 | 2.5 | 1.12546 | 14.6633 | 2.81365
M_Ext-008 | R+1 | Mur porteur (Classification ARCHICAD) | Béton, Finition int - Enduit plâtre | Superstructure | Mur intérieur | L04.2.12.3.2 | 0.123777 | 2.51 | 0.0340626 | 0.449985 | 0.0854971
M_Ext-009 | R+1 | Mur porteur (Classification ARCHICAD) | Finition int - Enduit plâtre, Béton | Superstructure | Mur intérieur; Mur joint de dilatation | L04.2.12.4 | 5.43919 | 2.51 | 1.03345 | 13.6524 | 2.59395
M_Ext-009 | R+2 | Mur porteur (Classification ARCHICAD) | Béton, Finition int - Enduit plâtre | Superstructure | Mur intérieur; Mur joint de dilatation | L04.2.12.4 | 5.57419 | 2.51 | 1.07715 | 14.0047 | 2.69914
M_Ext-009 | R+2 | Mur porteur (Classification ARCHICAD) | Finition int - Enduit plâtre, Béton | Superstructure | Mur intérieur; Mur joint de dilatation | L04.2.12.4 | 5.43919 | 2.51 | 1.03345 | 13.6524 | 2.59395
M_Ext-009 | R+2 | Mur porteur (Classification ARCHICAD) | Béton, Finition int - Enduit plâtre | Superstructure | Mur intérieur; Mur joint de dilatation | L04.2.12.4 | 5.97281 | 2.5 | 1.12546 | 14.6633 | 2.81365
M_Ext-009 | R+2 | Mur porteur (Classification ARCHICAD) | Finition int - Enduit plâtre, Béton | Superstructure | Mur intérieur; Mur joint de dilatation | L04.2.12.4 | 6.00981 | 2.51 | 1.13249 | 14.8148 | 2.84255
M_Ext-008 | R+3 | Mur porteur (Classification ARCHICAD); Mur (Classification ARCHICAD) | Finition int - Enduit plâtre, Béton | Superstructure | Mur intérieur | L04.2.12.3.2 | 0.555635 | 2.51 | 0.105571 | 1.39464 | 0.264983
M_Ext-009 | R+3 | Mur porteur (Classification ARCHICAD) | Béton, Finition int - Enduit plâtre | Superstructure | Mur intérieur; Mur joint de dilatation | L04.2.12.4 | 5.22481 | 2.5 | 0.983339 | 12.7933 | 2.45835
M_Ext-009 | R+3 | Mur porteur (Classification ARCHICAD) | Finition int - Enduit plâtre, Béton | Superstructure | Mur intérieur; Mur joint de dilatation | L04.2.12.4 | 6.00981 | 2.49 | 1.16247 | 14.7008 | 2.82046
M_Ext-009 | R+3 | Mur porteur (Classification ARCHICAD) | Béton, Finition int - Enduit plâtre | Superstructure | Mur intérieur; Mur joint de dilatation | L04.2.12.4 | 5.70419 | 2.51 | 1.10185 | 14.0935 | 2.67988
M_Ext-009 | R+3 | Mur porteur (Classification ARCHICAD) | Finition int - Enduit plâtre, Béton | Superstructure | Mur intérieur; Mur joint de dilatation | L04.2.12.4 | 5.45919 | 2.51 | 1.03725 | 13.7026 | 2.60349

# IfcWall: 2 - Murs Béton 18 + Enduit 2 Faces 200 (88)
Type - ElementType: SOLIDWALL; PredefinedType: USERDEFINED
Material: Finition int - Enduit plâtre (2), Béton
Pset_WallCommon - AcousticRating: Non défini; ThermalTransmittance: 0; LoadBearing: yes; IsExternal: yes
PSET_Murs_ARCHI - Emplacement: Superstructure; Type: Mur béton banché 18cm; Destination: Mur intérieur; Matériaux: BETON
Propriétés DCE - Numéro de LOT: LOT 04
AC_Pset_RenovationAndPhasing - Renovation Status: Existing
Material Properties - Component 2, Béton, ThermalConductivity: 2.3; Component 2, Béton, SpecificHeatCapacity: 1000 J/kg/K; Component 2, Béton, MassDensity: 2300 kg/m3; Component 2, Béton, Embodied Energy: 1.92 (MJ/kg); Component 2, Béton, Embodied Carbon: 0.198 (kgCO₂/kg); Component 2, Béton, Name: Béton; Component 2, Béton, Participates in Collision Detection: yes
BaseQuantities - Width: 0.2 m
Name | In | Classification | Numéro article | Length (m) | Height (m) | GrossFootprintArea (m2) = NetFootprintArea (m2) | GrossSideArea (m2) | NetSideArea (m2) | GrossVolume (m3) | NetVolume (m3) | Component 3, Finition int - Enduit plâtre, ThermalConductivity | Component 3, Finition int - Enduit plâtre, SpecificHeatCapacity (J/kg/K) | Component 3, Finition int - Enduit plâtre, MassDensity (kg/m3) | Component 3, Finition int - Enduit plâtre, Embodied Energy | Component 3, Finition int - Enduit plâtre, Embodied Carbon | Component 3, Finition int - Enduit plâtre, Name | Component 3, Finition int - Enduit plâtre, Participates in Collision Detection | Component 3
M_Ext-009 | Rez-de-chaussée | Mur porteur (Classification ARCHICAD) | L04.2.12.3.2 | 17.0521 | 2.51 | 3.03823 | 40.8597 | 36.6267 | 8.56427 | 7.714 | Material Properties - Component 1, Finition int - Enduit plâtre, ThermalConductivity: 0.57; Component 1, Finition int - Enduit plâtre, SpecificHeatCapacity: 1000 J/kg/K; Component 1, Finition int - Enduit plâtre, MassDensity: 1300 kg/m3; Component 1, Finition int - Enduit plâtre, Embodied Energy: 1.8 (MJ/kg); Component 1, Finition int - Enduit plâtre, Embodied Carbon: 0.13 (kgCO₂/kg); Component 1, Finition int - Enduit plâtre, Name: Finition int - Enduit plâtre; Component 1, Finition int - Enduit plâtre, Participates in Collision Detection: no; Component 1: 2 with these values
M_Ext-009 | R+1 | Mur porteur (Classification ARCHICAD); Mur (Classification ARCHICAD) | L04.2.12.3.2 | 17.0521 | 2.51 | 2.98533 | 42.08 | 37.8266 | 8.50735 | 7.65667 | Material Properties - Component 1, Finition int - Enduit plâtre, ThermalConductivity: 0.57; Component 1, Finition int - Enduit plâtre, SpecificHeatCapacity: 1000 J/kg/K; Component 1, Finition int - Enduit plâtre, MassDensity: 1300 kg/m3; Component 1, Finition int - Enduit plâtre, Embodied Energy: 1.8 (MJ/kg); Component 1, Finition int - Enduit plâtre, Embodied Carbon: 0.13 (kgCO₂/kg); Component 1, Finition int - Enduit plâtre, Name: Finition int - Enduit plâtre; Component 1, Finition int - Enduit plâtre, Participates in Collision Detection: no; Component 1: 2 with these values
M_Ext-009 | R+2 | Mur porteur (Classification ARCHICAD); Mur (Classification ARCHICAD) | L04.2.12.3.2 | 17.0521 | 2.51 | 2.98533 | 42.0475 | 37.7941 | 8.5067 | 7.65602 | Material Properties - Component 1, Finition int - Enduit plâtre, ThermalConductivity: 0.57; Component 1, Finition int - Enduit plâtre, SpecificHeatCapacity: 1000 J/kg/K; Component 1, Finition int - Enduit plâtre, MassDensity: 1300 kg/m3; Component 1, Finition int - Enduit plâtre, Embodied Energy: 1.8 (MJ/kg); Component 1, Finition int - Enduit plâtre, Embodied Carbon: 0.13 (kgCO₂/kg); Component 1, Finition int - Enduit plâtre, Name: Finition int - Enduit plâtre; Component 1, Finition int - Enduit plâtre, Participates in Collision Detection: no; Component 1: 2 with these values
M_Ext-009 | R+3 | Mur porteur (Classification ARCHICAD); Mur (Classification ARCHICAD) | L04.2.12.3.2 | 12.8641 | 2.52 | 2.17783 | 31.5136 | 27.2602 | 6.47572 | 5.62504 | Material Properties - Component 1, Finition int - Enduit plâtre, ThermalConductivity: 0.57; Component 1, Finition int - Enduit plâtre, SpecificHeatCapacity: 1000 J/kg/K; Component 1, Finition int - Enduit plâtre, MassDensity: 1300 kg/m3; Component 1, Finition int - Enduit plâtre, Embodied Energy: 1.8 (MJ/kg); Component 1, Finition int - Enduit plâtre, Embodied Carbon: 0.13 (kgCO₂/kg); Component 1, Finition int - Enduit plâtre, Name: Finition int - Enduit plâtre; Component 1, Finition int - Enduit plâtre, Participates in Collision Detection: no; Component 1: 2 with these values
M_Ext-009 | R+1 | Mur porteur (Classification ARCHICAD); Mur (Classification ARCHICAD) | L04.2.12.3.2 | 9.93553 | 2.51 | 1.80033 | 24.1821 | 22.0554 | 5.02247 | 4.59713 | 0.57 | 1000 | 1300 | 1.8 (MJ/kg) | 0.13 (kgCO₂/kg) | Finition int - Enduit plâtre | no | 2 with these values
M_Ext-008 | Rez-de-chaussée | Mur porteur (Classification ARCHICAD) | L04.2.12.3.2 | 3.24806 | 2.51 | 0.649611 | 7.59667 | 7.59667 | 1.61908 | 1.61908 | 0.57 | 1000 | 1300 | 1.8 (MJ/kg) | 0.13 (kgCO₂/kg) | Finition int - Enduit plâtre | no | 2 with these values
M_Ext-009 | Rez-de-chaussée | Mur porteur (Classification ARCHICAD) | L04.2.12.3.2 | 5.76427 | 2.51 | 0.948853 | 14.0807 | 11.954 | 2.88591 | 2.46057 | 0.57 | 1000 | 1300 | 1.8 (MJ/kg) | 0.13 (kgCO₂/kg) | Finition int - Enduit plâtre | no | 2 with these values
M_Ext-008 | Rez-de-chaussée | Mur porteur (Classification ARCHICAD) | L04.2.12.3.2 | 7.87723 | 2.51 | 1.38005 | 18.9224 | 16.8059 | 3.93386 | 3.50862 | 0.57 | 1000 | 1300 | 1.8 (MJ/kg) | 0.13 (kgCO₂/kg) | Finition int - Enduit plâtre | no | 2 with these values
M_Ext-009 | R+2 | Mur porteur (Classification ARCHICAD); Mur (Classification ARCHICAD) | L04.2.12.3.2 | 9.84053 | 2.51 | 1.72354 | 24.1013 | 21.9746 | 4.82943 | 4.40409 | 0.57 | 1000 | 1300 | 1.8 (MJ/kg) | 0.13 (kgCO₂/kg) | Finition int - Enduit plâtre | no | 2 with these values
M_Ext-009 | R+1 | Mur porteur (Classification ARCHICAD); Mur (Classification ARCHICAD) | L04.2.12.3.2 | 5.76427 | 2.51 | 0.948853 | 14.3596 | 12.2329 | 2.89149 | 2.46615 | 0.57 | 1000 | 1300 | 1.8 (MJ/kg) | 0.13 (kgCO₂/kg) | Finition int - Enduit plâtre | no | 2 with these values
M_Ext-009 | R+2 | Mur porteur (Classification ARCHICAD); Mur (Classification ARCHICAD) | L04.2.12.3.2 | 5.76427 | 2.51 | 0.948853 | 14.3596 | 12.2329 | 2.89149 | 2.46615 | 0.57 | 1000 | 1300 | 1.8 (MJ/kg) | 0.13 (kgCO₂/kg) | Finition int - Enduit plâtre | no | 2 with these values
M_Ext-008 | R+2 | Mur porteur (Classification ARCHICAD); Mur (Classification ARCHICAD) | L04.2.12.3.2 | 7.87723 | 2.51 | 1.41466 | 19.3254 | 17.1987 | 4.0459 | 3.62056 | 0.57 | 1000 | 1300 | 1.8 (MJ/kg) | 0.13 (kgCO₂/kg) | Finition int - Enduit plâtre | no | 2 with these values
M_Ext-008 | R+1 | Mur porteur (Classification ARCHICAD); Mur (Classification ARCHICAD) | L04.2.12.3.2 | 8.55539 | 2.51 | 1.52868 | 21.0306 | 18.9039 | 4.34467 | 3.91933 | 0.57 | 1000 | 1300 | 1.8 (MJ/kg) | 0.13 (kgCO₂/kg) | Finition int - Enduit plâtre | no | 2 with these values
M_Ext-008 | R+1 | Mur porteur (Classification ARCHICAD); Mur (Classification ARCHICAD) | L04.2.12.3.2 | 4.93355 | 2.51 | 0.794411 | 12.2699 | 10.1432 | 2.49923 | 2.07389 | 0.57 | 1000 | 1300 | 1.8 (MJ/kg) | 0.13 (kgCO₂/kg) | Finition int - Enduit plâtre | no | 2 with these values
M_Ext-008 | R+1 | Mur porteur (Classification ARCHICAD); Mur (Classification ARCHICAD) | L04.2.12.3.2 | 7.87723 | 2.51 | 1.40978 | 19.7781 | 17.6514 | 4.05015 | 3.62481 | 0.57 | 1000 | 1300 | 1.8 (MJ/kg) | 0.13 (kgCO₂/kg) | Finition int - Enduit plâtre | no | 2 with these values
M_Ext-008 | R+2 | Mur porteur (Classification ARCHICAD); Mur (Classification ARCHICAD) | L04.2.12.3.2 | 4.93355 | 2.51 | 0.794411 | 12.2699 | 10.1432 | 2.49923 | 2.07389 | 0.57 | 1000 | 1300 | 1.8 (MJ/kg) | 0.13 (kgCO₂/kg) | Finition int - Enduit plâtre | no | 2 with these values
M_Ext-009 | R+3 | Mur porteur (Classification ARCHICAD); Mur (Classification ARCHICAD) | L04.2.12.3.2 | 2.12665 | 2.51 | 0.22113 | 4.9944 | 2.8677 | 1.06523 | 0.639887 | 0.57 | 1000 | 1300 | 1.8 (MJ/kg) | 0.13 (kgCO₂/kg) | Finition int - Enduit plâtre | no | 2 with these values
M_Ext-008 | R+3 | Mur porteur (Classification ARCHICAD); Mur (Classification ARCHICAD) | L04.2.12.3.2 | 4.93355 | 2.51 | 0.794411 | 12.2699 | 10.1432 | 2.49923 | 2.07389 | 0.57 | 1000 | 1300 | 1.8 (MJ/kg) | 0.13 (kgCO₂/kg) | Finition int - Enduit plâtre | no | 2 with these values
M_Ext-008 | Rez-de-chaussée | Mur porteur (Classification ARCHICAD) | L04.2.12.3.2 | 2.32355 | 2.5 | 0.26631 | 5.24963 | 3.12293 | 1.17534 | 0.750001 | 0.57 | 1000 | 1300 | 1.8 (MJ/kg) | 0.13 (kgCO₂/kg) | Finition int - Enduit plâtre | no | 2 with these values
M_Ext-009 | Rez-de-chaussée | Mur porteur (Classification ARCHICAD) | L04.2.12.3.2 | 6.81636 | 2.51 | 1.15927 | 16.8559 | 14.7394 | 3.41746 | 2.99223 | 0.57 | 1000 | 1300 | 1.8 (MJ/kg) | 0.13 (kgCO₂/kg) | Finition int - Enduit plâtre | no | 2 with these values
M_Ext-008 | R+1 | Mur porteur (Classification ARCHICAD); Mur (Classification ARCHICAD) | L04.2.12.3.2 | 6.40031 | 2.51 | 1.30526 | 15.8473 | 15.8473 | 3.27186 | 3.27186 | 0.57 | 1000 | 1300 | 1.8 (MJ/kg) | 0.13 (kgCO₂/kg) | Finition int - Enduit plâtre | no | 2 with these values
M_Ext-008 | R+1 | Mur porteur (Classification ARCHICAD); Mur (Classification ARCHICAD) | L04.2.12.3.2 | 1.94502 | 2.52 | 0.373703 | 4.62749 | 4.62749 | 0.933021 | 0.933021 | Material Properties - Component 1, Finition int - Enduit plâtre, ThermalConductivity: 0.57; Component 1, Finition int - Enduit plâtre, SpecificHeatCapacity: 1000 J/kg/K; Component 1, Finition int - Enduit plâtre, MassDensity: 1300 kg/m3; Component 1, Finition int - Enduit plâtre, Embodied Energy: 1.8 (MJ/kg); Component 1, Finition int - Enduit plâtre, Embodied Carbon: 0.13 (kgCO₂/kg); Component 1, Finition int - Enduit plâtre, Name: Finition int - Enduit plâtre; Component 1, Finition int - Enduit plâtre, Participates in Collision Detection: no; Component 1: 2 with these values
M_Ext-008 | R+1 | Mur porteur (Classification ARCHICAD); Mur (Classification ARCHICAD) | L04.2.12.3.2 | 5.27338 | 2.51 | 0.885976 | 13.2404 | 11.1137 | 2.7309 | 2.30556 | 0.57 | 1000 | 1300 | 1.8 (MJ/kg) | 0.13 (kgCO₂/kg) | Finition int - Enduit plâtre | no | 2 with these values
M_Ext-008 | R+1 | Mur porteur (Classification ARCHICAD); Mur (Classification ARCHICAD) | L04.2.12.3.2 | 3.037 | 2.51 | 0.4351 | 7.39263 | 5.26593 | 1.60355 | 1.17821 | 0.57 | 1000 | 1300 | 1.8 (MJ/kg) | 0.13 (kgCO₂/kg) | Finition int - Enduit plâtre | no | 2 with these values
M_Ext-008 | R+1 | Mur porteur (Classification ARCHICAD); Mur (Classification ARCHICAD) | L04.2.12.3.2 | 4.31115 | 2.51 | 0.88033 | 10.6485 | 10.6485 | 2.20593 | 2.20593 | 0.57 | 1000 | 1300 | 1.8 (MJ/kg) | 0.13 (kgCO₂/kg) | Finition int - Enduit plâtre | no | 2 with these values
M_Ext-008 | R+1 | Mur porteur (Classification ARCHICAD); Mur (Classification ARCHICAD) | L04.2.12.3.2 | 2.674 | 2.52 | 0.5348 | 6.1815 | 6.1815 | 1.33605 | 1.33605 | Material Properties - Component 1, Finition int - Enduit plâtre, ThermalConductivity: 0.57; Component 1, Finition int - Enduit plâtre, SpecificHeatCapacity: 1000 J/kg/K; Component 1, Finition int - Enduit plâtre, MassDensity: 1300 kg/m3; Component 1, Finition int - Enduit plâtre, Embodied Energy: 1.8 (MJ/kg); Component 1, Finition int - Enduit plâtre, Embodied Carbon: 0.13 (kgCO₂/kg); Component 1, Finition int - Enduit plâtre, Name: Finition int - Enduit plâtre; Component 1, Finition int - Enduit plâtre, Participates in Collision Detection: no; Component 1: 2 with these values
M_Ext-008 | R+2 | Mur porteur (Classification ARCHICAD); Mur (Classification ARCHICAD) | L04.2.12.3.2 | 6.40031 | 2.51 | 1.30526 | 15.8473 | 15.8473 | 3.27186 | 3.27186 | 0.57 | 1000 | 1300 | 1.8 (MJ/kg) | 0.13 (kgCO₂/kg) | Finition int - Enduit plâtre | no | 2 with these values
M_Ext-008 | R+3 | Mur porteur (Classification ARCHICAD); Mur (Classification ARCHICAD) | L04.2.12.3.2 | 1.43089 | 2.5 | 0.0939681 | 3.57168 | 1.44498 | 0.744809 | 0.319469 | Material Properties - Component 1, Finition int - Enduit plâtre, ThermalConductivity: 0.57; Component 1, Finition int - Enduit plâtre, SpecificHeatCapacity: 1000 J/kg/K; Component 1, Finition int - Enduit plâtre, MassDensity: 1300 kg/m3; Component 1, Finition int - Enduit plâtre, Embodied Energy: 1.8 (MJ/kg); Component 1, Finition int - Enduit plâtre, Embodied Carbon: 0.13 (kgCO₂/kg); Component 1, Finition int - Enduit plâtre, Name: Finition int - Enduit plâtre; Component 1, Finition int - Enduit plâtre, Participates in Collision Detection: no; Component 1: 2 with these values
M_Ext-008 | Rez-de-chaussée | Mur porteur (Classification ARCHICAD) | L04.2.12.3.2 | 9.10753 | 2.51 | 1.63753 | 22.6921 | 20.5756 | 4.61931 | 4.1941 | Material Properties - Component 1, Finition int - Enduit plâtre, ThermalConductivity: 0.57; Component 1, Finition int - Enduit plâtre, SpecificHeatCapacity: 1000 J/kg/K; Component 1, Finition int - Enduit plâtre, MassDensity: 1300 kg/m3; Component 1, Finition int - Enduit plâtre, Embodied Energy: 1.8 (MJ/kg); Component 1, Finition int - Enduit plâtre, Embodied Carbon: 0.13 (kgCO₂/kg); Component 1, Finition int - Enduit plâtre, Name: Finition int - Enduit plâtre; Component 1, Finition int - Enduit plâtre, Participates in Collision Detection: no; Component 1: 2 with these values
M_Ext-008 | Rez-de-chaussée | Mur porteur (Classification ARCHICAD) | L04.2.12.3.2 | 2.674 | 2.51 | 0.5348 | 6.5825 | 6.5825 | 1.34011 | 1.34011 | Material Properties - Component 1, Finition int - Enduit plâtre, ThermalConductivity: 0.57; Component 1, Finition int - Enduit plâtre, SpecificHeatCapacity: 1000 J/kg/K; Component 1, Finition int - Enduit plâtre, MassDensity: 1300 kg/m3; Component 1, Finition int - Enduit plâtre, Embodied Energy: 1.8 (MJ/kg); Component 1, Finition int - Enduit plâtre, Embodied Carbon: 0.13 (kgCO₂/kg); Component 1, Finition int - Enduit plâtre, Name: Finition int - Enduit plâtre; Component 1, Finition int - Enduit plâtre, Participates in Collision Detection: no; Component 1: 2 with these values
M_Ext-008 | Rez-de-chaussée | Mur porteur (Classification ARCHICAD) | L04.2.12.3.2 | 6.40031 | 2.51 | 1.33426 | 15.8474 | 15.8474 | 3.27187 | 3.27187 | 0.57 | 1000 | 1300 | 1.8 (MJ/kg) | 0.13 (kgCO₂/kg) | Finition int - Enduit plâtre | no | 2 with these values
M_Ext-008 | Rez-de-chaussée | Mur porteur (Classification ARCHICAD) | L04.2.12.3.2 | 3.037 | 2.51 | 0.4351 | 7.40637 | 5.28987 | 1.60398 | 1.17875 | 0.57 | 1000 | 1300 | 1.8 (MJ/kg) | 0.13 (kgCO₂/kg) | Finition int - Enduit plâtre | no | 2 with these values
M_Ext-008 | Rez-de-chaussée | Mur porteur (Classification ARCHICAD) | L04.2.12.3.2 | 2.5 | 2.56 | 0.194979 | 6.2755 | 2.8138 | 1.22015 | 0.523398 | 0.57 | 1000 | 1300 | 1.8 (MJ/kg) | 0.13 (kgCO₂/kg) | Finition int - Enduit plâtre | no | 2 with these values
M_Ext-009 | Rez-de-chaussée | Mur porteur (Classification ARCHICAD) | L04.2.12.3.2 | 4.437 | 2.51 | 0.8874 | 11.0119 | 11.0119 | 2.22487 | 2.22487 | Material Properties - Component 1, Finition int - Enduit plâtre, ThermalConductivity: 0.57; Component 1, Finition int - Enduit plâtre, SpecificHeatCapacity: 1000 J/kg/K; Component 1, Finition int - Enduit plâtre, MassDensity: 1300 kg/m3; Component 1, Finition int - Enduit plâtre, Embodied Energy: 1.8 (MJ/kg); Component 1, Finition int - Enduit plâtre, Embodied Carbon: 0.13 (kgCO₂/kg); Component 1, Finition int - Enduit plâtre, Name: Finition int - Enduit plâtre; Component 1, Finition int - Enduit plâtre, Participates in Collision Detection: no; Component 1: 2 with these values
M_Ext-008 | Rez-de-chaussée | Mur porteur (Classification ARCHICAD) | L04.2.12.3.2 | 1.94502 | 2.51 | 0.373703 | 4.66449 | 4.66449 | 0.933645 | 0.933645 | Material Properties - Component 1, Finition int - Enduit plâtre, ThermalConductivity: 0.57; Component 1, Finition int - Enduit plâtre, SpecificHeatCapacity: 1000 J/kg/K; Component 1, Finition int - Enduit plâtre, MassDensity: 1300 kg/m3; Component 1, Finition int - Enduit plâtre, Embodied Energy: 1.8 (MJ/kg); Component 1, Finition int - Enduit plâtre, Embodied Carbon: 0.13 (kgCO₂/kg); Component 1, Finition int - Enduit plâtre, Name: Finition int - Enduit plâtre; Component 1, Finition int - Enduit plâtre, Participates in Collision Detection: no; Component 1: 2 with these values
M_Ext-008 | Rez-de-chaussée | Mur porteur (Classification ARCHICAD) | L04.2.12.3.2 | 6.7267 | 2.51 | 1.38144 | 16.6541 | 16.6541 | 3.39029 | 3.39029 | 0.57 | 1000 | 1300 | 1.8 (MJ/kg) | 0.13 (kgCO₂/kg) | Finition int - Enduit plâtre | no | 2 with these values
M_Ext-008 | R+1 | Mur porteur (Classification ARCHICAD); Mur (Classification ARCHICAD) | L04.2.12.3.2 | 2.13391 | 2.51 | 0.208282 | 5.29909 | 3.17239 | 1.03394 | 0.608599 | Material Properties - Component 1, Finition int - Enduit plâtre, ThermalConductivity: 0.57; Component 1, Finition int - Enduit plâtre, SpecificHeatCapacity: 1000 J/kg/K; Component 1, Finition int - Enduit plâtre, MassDensity: 1300 kg/m3; Component 1, Finition int - Enduit plâtre, Embodied Energy: 1.8 (MJ/kg); Component 1, Finition int - Enduit plâtre, Embodied Carbon: 0.13 (kgCO₂/kg); Component 1, Finition int - Enduit plâtre, Name: Finition int - Enduit plâtre; Component 1, Finition int - Enduit plâtre, Participates in Collision Detection: no; Component 1: 2 with these values
M_Ext-009 | R+1 | Mur porteur (Classification ARCHICAD); Mur (Classification ARCHICAD) | L04.2.12.3.2 | 2.61531 | 2.51 | 0.504962 | 6.32598 | 6.32598 | 1.26745 | 1.26745 | 0.57 | 1000 | 1300 | 1.8 (MJ/kg) | 0.13 (kgCO₂/kg) | Finition int - Enduit plâtre | no | 2 with these values
M_Ext-008 | R+1 | Mur porteur (Classification ARCHICAD); Mur (Classification ARCHICAD) | L04.2.12.3.2 | 3.25474 | 2.51 | 0.681752 | 8.07176 | 8.07176 | 1.70538 | 1.70538 | 0.57 | 1000 | 1300 | 1.8 (MJ/kg) | 0.13 (kgCO₂/kg) | Finition int - Enduit plâtre | no | 2 with these values
M_Ext-008 | R+1 | Mur porteur (Classification ARCHICAD); Mur (Classification ARCHICAD) | L04.2.12.3.2 | 9.7002 | 2.51 | 1.69981 | 24.2539 | 22.1272 | 4.77701 | 4.35167 | Material Properties - Component 1, Finition int - Enduit plâtre, ThermalConductivity: 0.57; Component 1, Finition int - Enduit plâtre, SpecificHeatCapacity: 1000 J/kg/K; Component 1, Finition int - Enduit plâtre, MassDensity: 1300 kg/m3; Component 1, Finition int - Enduit plâtre, Embodied Energy: 1.8 (MJ/kg); Component 1, Finition int - Enduit plâtre, Embodied Carbon: 0.13 (kgCO₂/kg); Component 1, Finition int - Enduit plâtre, Name: Finition int - Enduit plâtre; Component 1, Finition int - Enduit plâtre, Participates in Collision Detection: no; Component 1: 2 with these values
M_Ext-009 | R+2 | Mur porteur (Classification ARCHICAD); Mur (Classification ARCHICAD) | L04.2.12.3.2 | 2.61531 | 2.51 | 0.504962 | 6.32598 | 6.32598 | 1.26745 | 1.26745 | 0.57 | 1000 | 1300 | 1.8 (MJ/kg) | 0.13 (kgCO₂/kg) | Finition int - Enduit plâtre | no | 2 with these values
M_Ext-008 | R+2 | Mur porteur (Classification ARCHICAD); Mur (Classification ARCHICAD) | L04.2.12.3.2 | 1.635 | 2.51 | 0.1085 | 4.0913 | 1.9646 | 0.784375 | 0.359035 | Material Properties - Component 1, Finition int - Enduit plâtre, ThermalConductivity: 0.57; Component 1, Finition int - Enduit plâtre, SpecificHeatCapacity: 1000 J/kg/K; Component 1, Finition int - Enduit plâtre, MassDensity: 1300 kg/m3; Component 1, Finition int - Enduit plâtre, Embodied Energy: 1.8 (MJ/kg); Component 1, Finition int - Enduit plâtre, Embodied Carbon: 0.13 (kgCO₂/kg); Component 1, Finition int - Enduit plâtre, Name: Finition int - Enduit plâtre; Component 1, Finition int - Enduit plâtre, Participates in Collision Detection: no; Component 1: 2 with these values
M_Ext-008 | R+2 | Mur porteur (Classification ARCHICAD); Mur (Classification ARCHICAD) | L04.2.12.3.2 | 3.70852 | 2.51 | 0.777005 | 9.31265 | 9.31265 | 1.94535 | 1.94535 | 0.57 | 1000 | 1300 | 1.8 (MJ/kg) | 0.13 (kgCO₂/kg) | Finition int - Enduit plâtre | no | 2 with these values
M_Ext-008 | R+2 | Mur porteur (Classification ARCHICAD); Mur (Classification ARCHICAD) | L04.2.12.3.2 | 7.8702 | 2.51 | 1.39569 | 19.3107 | 17.184 | 3.99574 | 3.5704 | Material Properties - Component 1, Finition int - Enduit plâtre, ThermalConductivity: 0.57; Component 1, Finition int - Enduit plâtre, SpecificHeatCapacity: 1000 J/kg/K; Component 1, Finition int - Enduit plâtre, MassDensity: 1300 kg/m3; Component 1, Finition int - Enduit plâtre, Embodied Energy: 1.8 (MJ/kg); Component 1, Finition int - Enduit plâtre, Embodied Carbon: 0.13 (kgCO₂/kg); Component 1, Finition int - Enduit plâtre, Name: Finition int - Enduit plâtre; Component 1, Finition int - Enduit plâtre, Participates in Collision Detection: no; Component 1: 2 with these values
M_Ext-009 | R+3 | Mur porteur (Classification ARCHICAD); Mur (Classification ARCHICAD) | L04.2.12.3.2 | 5.78427 | 2.51 | 0.952853 | 14.2935 | 12.1668 | 2.8992 | 2.47386 | Material Properties - Component 1, Finition int - Enduit plâtre, ThermalConductivity: 0.57; Component 1, Finition int - Enduit plâtre, SpecificHeatCapacity: 1000 J/kg/K; Component 1, Finition int - Enduit plâtre, MassDensity: 1300 kg/m3; Component 1, Finition int - Enduit plâtre, Embodied Energy: 1.8 (MJ/kg); Component 1, Finition int - Enduit plâtre, Embodied Carbon: 0.13 (kgCO₂/kg); Component 1, Finition int - Enduit plâtre, Name: Finition int - Enduit plâtre; Component 1, Finition int - Enduit plâtre, Participates in Collision Detection: no; Component 1: 2 with these values
M_Ext-008 | R+3 | Mur porteur (Classification ARCHICAD); Mur (Classification ARCHICAD) | L04.2.12.3.2 | 6.40031 | 2.51 | 1.30526 | 15.8758 | 15.8758 | 3.24892 | 3.24892 | 0.57 | 1000 | 1300 | 1.8 (MJ/kg) | 0.13 (kgCO₂/kg) | Finition int - Enduit plâtre | no | 2 with these values
M_Ext-008 | R+3 | Mur porteur (Classification ARCHICAD); Mur (Classification ARCHICAD) | L04.2.12.3.2 | 4.24193 | 2.51 | 0.673046 | 10.6469 | 8.75407 | 2.14602 | 1.76746 | 0.57 | 1000 | 1300 | 1.8 (MJ/kg) | 0.13 (kgCO₂/kg) | Finition int - Enduit plâtre | no | 2 with these values
M_Ext-008 | Rez-de-chaussée | Mur porteur (Classification ARCHICAD) | L04.2.12.3.2 | 2.13391 | 2.51 | 0.208282 | 5.34357 | 3.21687 | 1.03483 | 0.609489 | Material Properties - Component 1, Finition int - Enduit plâtre, ThermalConductivity: 0.57; Component 1, Finition int - Enduit plâtre, SpecificHeatCapacity: 1000 J/kg/K; Component 1, Finition int - Enduit plâtre, MassDensity: 1300 kg/m3; Component 1, Finition int - Enduit plâtre, Embodied Energy: 1.8 (MJ/kg); Component 1, Finition int - Enduit plâtre, Embodied Carbon: 0.13 (kgCO₂/kg); Component 1, Finition int - Enduit plâtre, Name: Finition int - Enduit plâtre; Component 1, Finition int - Enduit plâtre, Participates in Collision Detection: no; Component 1: 2 with these values
M_Ext-008 | Rez-de-chaussée | Mur porteur (Classification ARCHICAD) | L04.2.12.3.2 | 4.41115 | 2.51 | 0.878429 | 10.5951 | 10.5951 | 2.20486 | 2.20486 | 0.57 | 1000 | 1300 | 1.8 (MJ/kg) | 0.13 (kgCO₂/kg) | Finition int - Enduit plâtre | no | 2 with these values
M_Ext-009 | Rez-de-chaussée | Mur porteur (Classification ARCHICAD) | L04.2.12.3.2 | 1.26852 | 2.51 | 0.233677 | 3.1564 | 3.1564 | 0.5863 | 0.5863 | 0.57 | 1000 | 1300 | 1.8 (MJ/kg) | 0.13 (kgCO₂/kg) | Finition int - Enduit plâtre | no | 2 with these values
M_Ext-009 | Rez-de-chaussée | Mur porteur (Classification ARCHICAD) | L04.2.12.3.2 | 2.61531 | 2.51 | 0.504962 | 6.32598 | 6.32598 | 1.26745 | 1.26745 | 0.57 | 1000 | 1300 | 1.8 (MJ/kg) | 0.13 (kgCO₂/kg) | Finition int - Enduit plâtre | no | 2 with these values
M_Ext-008 | Rez-de-chaussée | Mur porteur (Classification ARCHICAD) | L04.2.12.3.2 | 5.27338 | 2.51 | 0.853385 | 13.2371 | 11.1104 | 2.64951 | 2.22417 | 0.57 | 1000 | 1300 | 1.8 (MJ/kg) | 0.13 (kgCO₂/kg) | Finition int - Enduit plâtre | no | 2 with these values
M_Ext-008 | R+1 | Mur porteur (Classification ARCHICAD); Mur (Classification ARCHICAD) | L04.2.12.3.2 | 0.771637 | 2.51 | 0.155227 | 1.92147 | 1.92147 | 0.389314 | 0.389314 | Material Properties - Component 1, Finition int - Enduit plâtre, ThermalConductivity: 0.57; Component 1, Finition int - Enduit plâtre, SpecificHeatCapacity: 1000 J/kg/K; Component 1, Finition int - Enduit plâtre, MassDensity: 1300 kg/m3; Component 1, Finition int - Enduit plâtre, Embodied Energy: 1.8 (MJ/kg); Component 1, Finition int - Enduit plâtre, Embodied Carbon: 0.13 (kgCO₂/kg); Component 1, Finition int - Enduit plâtre, Name: Finition int - Enduit plâtre; Component 1, Finition int - Enduit plâtre, Participates in Collision Detection: no; Component 1: 2 with these values
M_Ext-008 | R+1 | Mur porteur (Classification ARCHICAD); Mur (Classification ARCHICAD) | L04.2.12.3.2 | 3.41319 | 2.51 | 0.689298 | 8.52792 | 8.52792 | 1.72223 | 1.72223 | 0.57 | 1000 | 1300 | 1.8 (MJ/kg) | 0.13 (kgCO₂/kg) | Finition int - Enduit plâtre | no | 2 with these values
M_Ext-008 | R+1 | Mur porteur (Classification ARCHICAD); Mur (Classification ARCHICAD) | L04.2.12.3.2 | 1.58 | 2.51 | 0.3485 | 3.94065 | 3.94065 | 0.873981 | 0.873981 | Material Properties - Component 1, Finition int - Enduit plâtre, ThermalConductivity: 0.57; Component 1, Finition int - Enduit plâtre, SpecificHeatCapacity: 1000 J/kg/K; Component 1, Finition int - Enduit plâtre, MassDensity: 1300 kg/m3; Component 1, Finition int - Enduit plâtre, Embodied Energy: 1.8 (MJ/kg); Component 1, Finition int - Enduit plâtre, Embodied Carbon: 0.13 (kgCO₂/kg); Component 1, Finition int - Enduit plâtre, Name: Finition int - Enduit plâtre; Component 1, Finition int - Enduit plâtre, Participates in Collision Detection: no; Component 1: 2 with these values
M_Ext-009 | R+1 | Mur porteur (Classification ARCHICAD); Mur (Classification ARCHICAD) | L04.2.12.3.2 | 2.9216 | 2.51 | 0.58432 | 7.33321 | 7.33321 | 1.46664 | 1.46664 | 0.57 | 1000 | 1300 | 1.8 (MJ/kg) | 0.13 (kgCO₂/kg) | Finition int - Enduit plâtre | no | 2 with these values
M_Ext-009 | R+1 | Mur porteur (Classification ARCHICAD); Mur (Classification ARCHICAD) | L04.2.12.3.2 | 4.977 | 2.51 | 0.9972 | 12.4425 | 12.4425 | 2.50198 | 2.50198 | Material Properties - Component 1, Finition int - Enduit plâtre, ThermalConductivity: 0.57; Component 1, Finition int - Enduit plâtre, SpecificHeatCapacity: 1000 J/kg/K; Component 1, Finition int - Enduit plâtre, MassDensity: 1300 kg/m3; Component 1, Finition int - Enduit plâtre, Embodied Energy: 1.8 (MJ/kg); Component 1, Finition int - Enduit plâtre, Embodied Carbon: 0.13 (kgCO₂/kg); Component 1, Finition int - Enduit plâtre, Name: Finition int - Enduit plâtre; Component 1, Finition int - Enduit plâtre, Participates in Collision Detection: no; Component 1: 2 with these values
M_Ext-008 | R+1 | Mur porteur (Classification ARCHICAD); Mur (Classification ARCHICAD) | L04.2.12.3.2 | 2.82618 | 2.51 | 0.578556 | 7.09372 | 7.09372 | 1.45204 | 1.45204 | Material Properties - Component 1, Finition int - Enduit plâtre, ThermalConductivity: 0.57; Component 1, Finition int - Enduit plâtre, SpecificHeatCapacity: 1000 J/kg/K; Component 1, Finition int - Enduit plâtre, MassDensity: 1300 kg/m3; Component 1, Finition int - Enduit plâtre, Embodied Energy: 1.8 (MJ/kg); Component 1, Finition int - Enduit plâtre, Embodied Carbon: 0.13 (kgCO₂/kg); Component 1, Finition int - Enduit plâtre, Name: Finition int - Enduit plâtre; Component 1, Finition int - Enduit plâtre, Participates in Collision Detection: no; Component 1: 2 with these values
M_Ext-008 | R+1 | Mur porteur (Classification ARCHICAD); Mur (Classification ARCHICAD) | L04.2.12.3.2 | 1.26 | 2.51 | 0.2846 | 3.1877 | 3.1877 | 0.714346 | 0.714346 | 0.57 | 1000 | 1300 | 1.8 (MJ/kg) | 0.13 (kgCO₂/kg) | Finition int - Enduit plâtre | no | 2 with these values
M_Ext-008 | R+1 | Mur porteur (Classification ARCHICAD); Mur (Classification ARCHICAD) | L04.2.12.3.2 | 1.28039 | 2.5 | 0.0661381 | 3.20653 | 1.07983 | 0.642304 | 0.216964 | Material Properties - Component 1, Finition int - Enduit plâtre, ThermalConductivity: 0.57; Component 1, Finition int - Enduit plâtre, SpecificHeatCapacity: 1000 J/kg/K; Component 1, Finition int - Enduit plâtre, MassDensity: 1300 kg/m3; Component 1, Finition int - Enduit plâtre, Embodied Energy: 1.8 (MJ/kg); Component 1, Finition int - Enduit plâtre, Embodied Carbon: 0.13 (kgCO₂/kg); Component 1, Finition int - Enduit plâtre, Name: Finition int - Enduit plâtre; Component 1, Finition int - Enduit plâtre, Participates in Collision Detection: no; Component 1: 2 with these values
M_Ext-008 | R+1 | Mur porteur (Classification ARCHICAD); Mur (Classification ARCHICAD) | L04.2.12.3.2 | 0.267852 | 2.51 | 0.0209704 | 0.647209 | 0.647209 | 0.0526357 | 0.0526357 | 0.57 | 1000 | 1300 | 1.8 (MJ/kg) | 0.13 (kgCO₂/kg) | Finition int - Enduit plâtre | no | 2 with these values
M_Ext-008 | R+1 | Mur porteur (Classification ARCHICAD); Mur (Classification ARCHICAD) | L04.2.12.3.2 | 2.55498 | 2.51 | 0.518096 | 6.40045 | 6.40045 | 1.30042 | 1.30042 | Material Properties - Component 1, Finition int - Enduit plâtre, ThermalConductivity: 0.57; Component 1, Finition int - Enduit plâtre, SpecificHeatCapacity: 1000 J/kg/K; Component 1, Finition int - Enduit plâtre, MassDensity: 1300 kg/m3; Component 1, Finition int - Enduit plâtre, Embodied Energy: 1.8 (MJ/kg); Component 1, Finition int - Enduit plâtre, Embodied Carbon: 0.13 (kgCO₂/kg); Component 1, Finition int - Enduit plâtre, Name: Finition int - Enduit plâtre; Component 1, Finition int - Enduit plâtre, Participates in Collision Detection: no; Component 1: 2 with these values
M_Ext-008 | R+2 | Mur porteur (Classification ARCHICAD); Mur (Classification ARCHICAD) | L04.2.12.3.2 | 1.26 | 2.51 | 0.252 | 3.1626 | 3.1626 | 0.63252 | 0.63252 | 0.57 | 1000 | 1300 | 1.8 (MJ/kg) | 0.13 (kgCO₂/kg) | Finition int - Enduit plâtre | no | 2 with these values
M_Ext-008 | R+2 | Mur porteur (Classification ARCHICAD); Mur (Classification ARCHICAD) | L04.2.12.3.2 | 2.55498 | 2.51 | 0.550696 | 6.42555 | 6.42555 | 1.38225 | 1.38225 | Material Properties - Component 1, Finition int - Enduit plâtre, ThermalConductivity: 0.57; Component 1, Finition int - Enduit plâtre, SpecificHeatCapacity: 1000 J/kg/K; Component 1, Finition int - Enduit plâtre, MassDensity: 1300 kg/m3; Component 1, Finition int - Enduit plâtre, Embodied Energy: 1.8 (MJ/kg); Component 1, Finition int - Enduit plâtre, Embodied Carbon: 0.13 (kgCO₂/kg); Component 1, Finition int - Enduit plâtre, Name: Finition int - Enduit plâtre; Component 1, Finition int - Enduit plâtre, Participates in Collision Detection: no; Component 1: 2 with these values
M_Ext-009 | R+2 | Mur porteur (Classification ARCHICAD); Mur (Classification ARCHICAD) | L04.2.12.3.2 | 3.2516 | 2.51 | 0.64852 | 7.93561 | 7.93561 | 1.62778 | 1.62778 | 0.57 | 1000 | 1300 | 1.8 (MJ/kg) | 0.13 (kgCO₂/kg) | Finition int - Enduit plâtre | no | 2 with these values
M_Ext-008 | R+2 | Mur porteur (Classification ARCHICAD); Mur (Classification ARCHICAD) | L04.2.12.3.2 | 4.28202 | 2.51 | 0.629723 | 10.6622 | 8.16622 | 2.18116 | 1.67764 | Material Properties - Component 1, Finition int - Enduit plâtre, ThermalConductivity: 0.57; Component 1, Finition int - Enduit plâtre, SpecificHeatCapacity: 1000 J/kg/K; Component 1, Finition int - Enduit plâtre, MassDensity: 1300 kg/m3; Component 1, Finition int - Enduit plâtre, Embodied Energy: 1.8 (MJ/kg); Component 1, Finition int - Enduit plâtre, Embodied Carbon: 0.13 (kgCO₂/kg); Component 1, Finition int - Enduit plâtre, Name: Finition int - Enduit plâtre; Component 1, Finition int - Enduit plâtre, Participates in Collision Detection: no; Component 1: 2 with these values
M_Ext-008 | R+2 | Mur porteur (Classification ARCHICAD); Mur (Classification ARCHICAD) | L04.2.12.3.2 | 1.998 | 2.51 | 0.4322 | 5.04008 | 5.04008 | 1.08482 | 1.08482 | 0.57 | 1000 | 1300 | 1.8 (MJ/kg) | 0.13 (kgCO₂/kg) | Finition int - Enduit plâtre | no | 2 with these values
M_Ext-008 | R+2 | Mur porteur (Classification ARCHICAD); Mur (Classification ARCHICAD) | L04.2.12.3.2 | 0.264609 | 2.51 | 0.0203219 | 0.63907 | 0.63907 | 0.051008 | 0.051008 | 0.57 | 1000 | 1300 | 1.8 (MJ/kg) | 0.13 (kgCO₂/kg) | Finition int - Enduit plâtre | no | 2 with these values
M_Ext-008 | R+2 | Mur porteur (Classification ARCHICAD); Mur (Classification ARCHICAD) | L04.2.12.3.2 | 1.28039 | 2.5 | 0.0661381 | 3.20653 | 1.07983 | 0.642304 | 0.216964 | Material Properties - Component 1, Finition int - Enduit plâtre, ThermalConductivity: 0.57; Component 1, Finition int - Enduit plâtre, SpecificHeatCapacity: 1000 J/kg/K; Component 1, Finition int - Enduit plâtre, MassDensity: 1300 kg/m3; Component 1, Finition int - Enduit plâtre, Embodied Energy: 1.8 (MJ/kg); Component 1, Finition int - Enduit plâtre, Embodied Carbon: 0.13 (kgCO₂/kg); Component 1, Finition int - Enduit plâtre, Name: Finition int - Enduit plâtre; Component 1, Finition int - Enduit plâtre, Participates in Collision Detection: no; Component 1: 2 with these values
M_Ext-008 | R+2 | Mur porteur (Classification ARCHICAD); Mur (Classification ARCHICAD) | L04.2.12.3.2 | 0.19 | 2.51 | 0.038 | 0.475 | 0.475 | 0.0953421 | 0.0953421 | Material Properties - Component 1, Finition int - Enduit plâtre, ThermalConductivity: 0.57; Component 1, Finition int - Enduit plâtre, SpecificHeatCapacity: 1000 J/kg/K; Component 1, Finition int - Enduit plâtre, MassDensity: 1300 kg/m3; Component 1, Finition int - Enduit plâtre, Embodied Energy: 1.8 (MJ/kg); Component 1, Finition int - Enduit plâtre, Embodied Carbon: 0.13 (kgCO₂/kg); Component 1, Finition int - Enduit plâtre, Name: Finition int - Enduit plâtre; Component 1, Finition int - Enduit plâtre, Participates in Collision Detection: no; Component 1: 2 with these values
M_Ext-009 | R+2 | Mur porteur (Classification ARCHICAD); Mur (Classification ARCHICAD) | L04.2.12.3.2 | 4.977 | 2.51 | 0.9972 | 12.4425 | 12.4425 | 2.50198 | 2.50198 | 0.57 | 1000 | 1300 | 1.8 (MJ/kg) | 0.13 (kgCO₂/kg) | Finition int - Enduit plâtre | no | 2 with these values
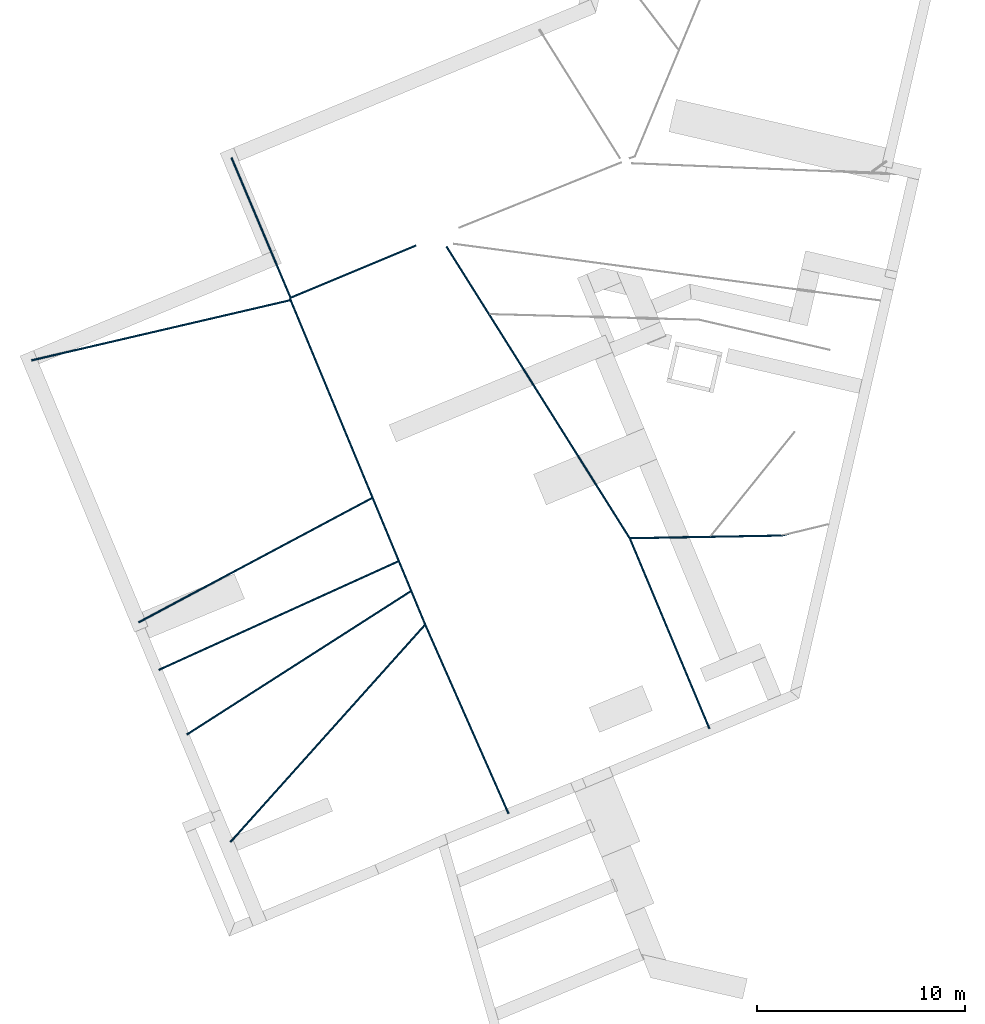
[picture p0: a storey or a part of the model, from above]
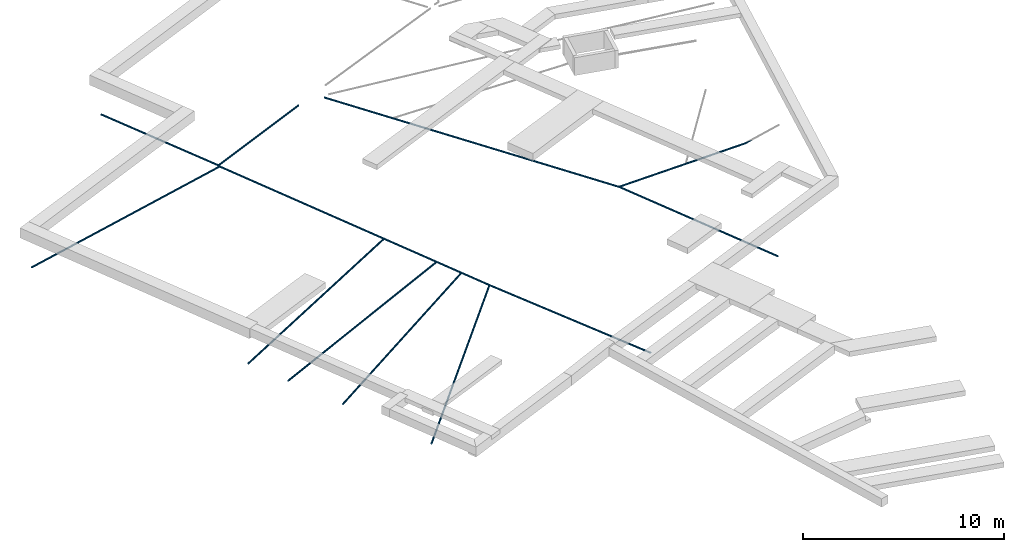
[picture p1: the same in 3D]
Properties of the parts of a building model (IFC2X3), part 8 of 22

# IfcWall: 2 - Murs Béton 18 + Enduit 2 Faces 200 (88)
Name | In | Classification | Numéro article | Length (m) | Height (m) | GrossFootprintArea (m2) = NetFootprintArea (m2) | GrossSideArea (m2) | NetSideArea (m2) | GrossVolume (m3) | NetVolume (m3) | Component 3, Finition int - Enduit plâtre, ThermalConductivity | Component 3, Finition int - Enduit plâtre, SpecificHeatCapacity (J/kg/K) | Component 3, Finition int - Enduit plâtre, MassDensity (kg/m3) | Component 3, Finition int - Enduit plâtre, Embodied Energy | Component 3, Finition int - Enduit plâtre, Embodied Carbon | Component 3, Finition int - Enduit plâtre, Name | Component 3, Finition int - Enduit plâtre, Participates in Collision Detection | Component 3
M_Ext-008 | R+2 | Mur porteur (Classification ARCHICAD) | L04.2.12.4 | 1.99867 | 2.51 | 0.180166 | 4.67444 | 2.54774 | 0.964255 | 0.538915 | Material Properties - Component 1, Finition int - Enduit plâtre, ThermalConductivity: 0.57; Component 1, Finition int - Enduit plâtre, SpecificHeatCapacity: 1000 J/kg/K; Component 1, Finition int - Enduit plâtre, MassDensity: 1300 kg/m3; Component 1, Finition int - Enduit plâtre, Embodied Energy: 1.8 (MJ/kg); Component 1, Finition int - Enduit plâtre, Embodied Carbon: 0.13 (kgCO₂/kg); Component 1, Finition int - Enduit plâtre, Name: Finition int - Enduit plâtre; Component 1, Finition int - Enduit plâtre, Participates in Collision Detection: no; Component 1: 2 with these values
M_Ext-009 | R+3 | Mur porteur (Classification ARCHICAD); Mur (Classification ARCHICAD) | L04.2.12.3.2 | 1.621 | 2.51 | 0.3242 | 4.06871 | 4.06871 | 0.813742 | 0.813742 | Material Properties - Component 1, Finition int - Enduit plâtre, ThermalConductivity: 0.57; Component 1, Finition int - Enduit plâtre, SpecificHeatCapacity: 1000 J/kg/K; Component 1, Finition int - Enduit plâtre, MassDensity: 1300 kg/m3; Component 1, Finition int - Enduit plâtre, Embodied Energy: 1.8 (MJ/kg); Component 1, Finition int - Enduit plâtre, Embodied Carbon: 0.13 (kgCO₂/kg); Component 1, Finition int - Enduit plâtre, Name: Finition int - Enduit plâtre; Component 1, Finition int - Enduit plâtre, Participates in Collision Detection: no; Component 1: 2 with these values
M_Ext-008 | Rez-de-chaussée | Mur porteur (Classification ARCHICAD) | L04.2.12.3.2 | 1.28039 | 2.5 | 0.0661381 | 3.18613 | 1.07983 | 0.640978 | 0.216964 | Material Properties - Component 1, Finition int - Enduit plâtre, ThermalConductivity: 0.57; Component 1, Finition int - Enduit plâtre, SpecificHeatCapacity: 1000 J/kg/K; Component 1, Finition int - Enduit plâtre, MassDensity: 1300 kg/m3; Component 1, Finition int - Enduit plâtre, Embodied Energy: 1.8 (MJ/kg); Component 1, Finition int - Enduit plâtre, Embodied Carbon: 0.13 (kgCO₂/kg); Component 1, Finition int - Enduit plâtre, Name: Finition int - Enduit plâtre; Component 1, Finition int - Enduit plâtre, Participates in Collision Detection: no; Component 1: 2 with these values
M_Ext-008 | Rez-de-chaussée | Mur porteur (Classification ARCHICAD) | L04.2.12.3.2 | 1.27 | 2.51 | 0.254 | 3.1877 | 3.1877 | 0.63754 | 0.63754 | 0.57 | 1000 | 1300 | 1.8 (MJ/kg) | 0.13 (kgCO₂/kg) | Finition int - Enduit plâtre | no | 2 with these values
M_Ext-008 | Rez-de-chaussée | Mur porteur (Classification ARCHICAD) | L04.2.12.3.2 | 2.55498 | 2.51 | 0.579696 | 6.42567 | 6.42567 | 1.38226 | 1.38226 | Material Properties - Component 1, Finition int - Enduit plâtre, ThermalConductivity: 0.57; Component 1, Finition int - Enduit plâtre, SpecificHeatCapacity: 1000 J/kg/K; Component 1, Finition int - Enduit plâtre, MassDensity: 1300 kg/m3; Component 1, Finition int - Enduit plâtre, Embodied Energy: 1.8 (MJ/kg); Component 1, Finition int - Enduit plâtre, Embodied Carbon: 0.13 (kgCO₂/kg); Component 1, Finition int - Enduit plâtre, Name: Finition int - Enduit plâtre; Component 1, Finition int - Enduit plâtre, Participates in Collision Detection: no; Component 1: 2 with these values
M_Ext-008 | Rez-de-chaussée | Mur porteur (Classification ARCHICAD) | L04.2.12.3.2 | 3.25474 | 2.51 | 0.681747 | 8.13758 | 8.13758 | 1.70902 | 1.70902 | 0.57 | 1000 | 1300 | 1.8 (MJ/kg) | 0.13 (kgCO₂/kg) | Finition int - Enduit plâtre | no | 2 with these values
M_Ext-008 | Rez-de-chaussée | Mur porteur (Classification ARCHICAD) | L04.2.12.3.2 | 0.771637 | 2.52 | 0.155227 | 1.93681 | 1.93681 | 0.389621 | 0.389621 | Material Properties - Component 1, Finition int - Enduit plâtre, ThermalConductivity: 0.57; Component 1, Finition int - Enduit plâtre, SpecificHeatCapacity: 1000 J/kg/K; Component 1, Finition int - Enduit plâtre, MassDensity: 1300 kg/m3; Component 1, Finition int - Enduit plâtre, Embodied Energy: 1.8 (MJ/kg); Component 1, Finition int - Enduit plâtre, Embodied Carbon: 0.13 (kgCO₂/kg); Component 1, Finition int - Enduit plâtre, Name: Finition int - Enduit plâtre; Component 1, Finition int - Enduit plâtre, Participates in Collision Detection: no; Component 1: 2 with these values
M_Ext-008 | Rez-de-chaussée | Mur porteur (Classification ARCHICAD) | L04.2.12.3.2 | 0.265182 | 2.51 | 0.0530364 | 0.665607 | 0.665607 | 0.133121 | 0.133121 | 0.57 | 1000 | 1300 | 1.8 (MJ/kg) | 0.13 (kgCO₂/kg) | Finition int - Enduit plâtre | no | 2 with these values
M_Ext-008 | Rez-de-chaussée | Mur porteur (Classification ARCHICAD) | L04.2.12.3.2 | 0.9 | 2.51 | 0.1963 | 2.26355 | 2.26355 | 0.492707 | 0.492707 | Material Properties - Component 1, Finition int - Enduit plâtre, ThermalConductivity: 0.57; Component 1, Finition int - Enduit plâtre, SpecificHeatCapacity: 1000 J/kg/K; Component 1, Finition int - Enduit plâtre, MassDensity: 1300 kg/m3; Component 1, Finition int - Enduit plâtre, Embodied Energy: 1.8 (MJ/kg); Component 1, Finition int - Enduit plâtre, Embodied Carbon: 0.13 (kgCO₂/kg); Component 1, Finition int - Enduit plâtre, Name: Finition int - Enduit plâtre; Component 1, Finition int - Enduit plâtre, Participates in Collision Detection: no; Component 1: 2 with these values
M_Ext-008 | Rez-de-chaussée | Mur porteur (Classification ARCHICAD) | L04.2.12.3.2 | 3.40819 | 2.51 | 0.688298 | 8.55419 | 8.55419 | 1.72749 | 1.72749 | 0.57 | 1000 | 1300 | 1.8 (MJ/kg) | 0.13 (kgCO₂/kg) | Finition int - Enduit plâtre | no | 2 with these values
M_Ext-008 | Rez-de-chaussée | Mur porteur (Classification ARCHICAD) | L04.2.12.3.2 | 2.86318 | 2.51 | 0.579296 | 7.18622 | 7.18622 | 1.45389 | 1.45389 | Material Properties - Component 1, Finition int - Enduit plâtre, ThermalConductivity: 0.57; Component 1, Finition int - Enduit plâtre, SpecificHeatCapacity: 1000 J/kg/K; Component 1, Finition int - Enduit plâtre, MassDensity: 1300 kg/m3; Component 1, Finition int - Enduit plâtre, Embodied Energy: 1.8 (MJ/kg); Component 1, Finition int - Enduit plâtre, Embodied Carbon: 0.13 (kgCO₂/kg); Component 1, Finition int - Enduit plâtre, Name: Finition int - Enduit plâtre; Component 1, Finition int - Enduit plâtre, Participates in Collision Detection: no; Component 1: 2 with these values
M_Ext-008 | Rez-de-chaussée | Mur porteur (Classification ARCHICAD) | L04.2.12.3.2 | 1.59869 | 2.51 | 0.112138 | 3.56091 | 1.43421 | 0.793506 | 0.368166 | 0.57 | 1000 | 1300 | 1.8 (MJ/kg) | 0.13 (kgCO₂/kg) | Finition int - Enduit plâtre | no | 2 with these values
M_Ext-009 | Rez-de-chaussée | Mur porteur (Classification ARCHICAD) | L04.2.12.3.2 | 2.9216 | 2.5 | 0.58432 | 7.30399 | 7.30399 | 1.4608 | 1.4608 | 0.57 | 1000 | 1300 | 1.8 (MJ/kg) | 0.13 (kgCO₂/kg) | Finition int - Enduit plâtre | no | 2 with these values
M_Ext-008 | R+1 | Mur porteur (Classification ARCHICAD); Mur (Classification ARCHICAD) | L04.2.12.3.2 | 2.33443 | 2.51 | 0.466886 | 5.85942 | 5.85942 | 1.17188 | 1.17188 | Material Properties - Component 1, Finition int - Enduit plâtre, ThermalConductivity: 0.57; Component 1, Finition int - Enduit plâtre, SpecificHeatCapacity: 1000 J/kg/K; Component 1, Finition int - Enduit plâtre, MassDensity: 1300 kg/m3; Component 1, Finition int - Enduit plâtre, Embodied Energy: 1.8 (MJ/kg); Component 1, Finition int - Enduit plâtre, Embodied Carbon: 0.13 (kgCO₂/kg); Component 1, Finition int - Enduit plâtre, Name: Finition int - Enduit plâtre; Component 1, Finition int - Enduit plâtre, Participates in Collision Detection: no; Component 1: 2 with these values
M_Ext-008 | R+2 | Mur porteur (Classification ARCHICAD); Mur (Classification ARCHICAD) | L04.2.12.3.2 | 1.92 | 2.51 | 0.384 | 4.79948 | 4.79948 | 0.963446 | 0.963446 | Material Properties - Component 1, Finition int - Enduit plâtre, ThermalConductivity: 0.57; Component 1, Finition int - Enduit plâtre, SpecificHeatCapacity: 1000 J/kg/K; Component 1, Finition int - Enduit plâtre, MassDensity: 1300 kg/m3; Component 1, Finition int - Enduit plâtre, Embodied Energy: 1.8 (MJ/kg); Component 1, Finition int - Enduit plâtre, Embodied Carbon: 0.13 (kgCO₂/kg); Component 1, Finition int - Enduit plâtre, Name: Finition int - Enduit plâtre; Component 1, Finition int - Enduit plâtre, Participates in Collision Detection: no; Component 1: 2 with these values
M_Ext-008 | Rez-de-chaussée | Mur porteur (Classification ARCHICAD) | L04.2.12.3.2 | 2.33443 | 2.51 | 0.466886 | 5.85942 | 5.85942 | 1.17188 | 1.17188 | Material Properties - Component 1, Finition int - Enduit plâtre, ThermalConductivity: 0.57; Component 1, Finition int - Enduit plâtre, SpecificHeatCapacity: 1000 J/kg/K; Component 1, Finition int - Enduit plâtre, MassDensity: 1300 kg/m3; Component 1, Finition int - Enduit plâtre, Embodied Energy: 1.8 (MJ/kg); Component 1, Finition int - Enduit plâtre, Embodied Carbon: 0.13 (kgCO₂/kg); Component 1, Finition int - Enduit plâtre, Name: Finition int - Enduit plâtre; Component 1, Finition int - Enduit plâtre, Participates in Collision Detection: no; Component 1: 2 with these values
M_Ext-009 | R+3 | Mur porteur (Classification ARCHICAD); Mur (Classification ARCHICAD) | L04.2.12.3.2 | 3.0516 | 2.51 | 0.61032 | 7.65951 | 7.65951 | 1.5319 | 1.5319 | 0.57 | 1000 | 1300 | 1.8 (MJ/kg) | 0.13 (kgCO₂/kg) | Finition int - Enduit plâtre | no | 2 with these values

# IfcWall: 2 - Murs Béton 18 + isolant 100 320 (2)
Type - ElementType: SOLIDWALL; PredefinedType: USERDEFINED
Classification: Mur porteur (Classification ARCHICAD); Material: Finition int - Plaque de plâtre, Isolation - Polystyrène extrudé, Divers - Vide, Béton
Pset_WallCommon - AcousticRating: Non défini; ThermalTransmittance: 0; LoadBearing: yes; IsExternal: yes
PSET_Murs_ARCHI - Type: Mur béton banché 18cm; Matériaux: BETON
Propriétés DCE - Numéro article: L04.2.12.4
AC_Pset_RenovationAndPhasing - Renovation Status: Existing
Material Properties - Component 4, Finition int - Plaque de plâtre, ThermalConductivity: 0.8; Component 4, Finition int - Plaque de plâtre, SpecificHeatCapacity: 1000 J/kg/K; Component 4, Finition int - Plaque de plâtre, MassDensity: 1600 kg/m3; Component 4, Finition int - Plaque de plâtre, Embodied Energy: 1.45 (MJ/kg); Component 4, Finition int - Plaque de plâtre, Embodied Carbon: 0.22 (kgCO₂/kg); Component 4, Finition int - Plaque de plâtre, Name: Finition int - Plaque de plâtre; Component 4, Finition int - Plaque de plâtre, Participates in Collision Detection: no; Component 3, Isolation - Polystyrène extrudé, ThermalConductivity: 0.036; Component 3, Isolation - Polystyrène extrudé, SpecificHeatCapacity: 1400 J/kg/K; Component 3, Isolation - Polystyrène extrudé, MassDensity: 25 kg/m3; Component 3, Isolation - Polystyrène extrudé, Embodied Energy: 86.4 (MJ/kg); Component 3, Isolation - Polystyrène extrudé, Embodied Carbon: 3.43 (kgCO₂/kg); Component 3, Isolation - Polystyrène extrudé, Name: Isolation - Polystyrène extrudé; Component 3, Isolation - Polystyrène extrudé, Participates in Collision Detection: no; Component 2, Divers - Vide, ThermalConductivity: 0.15; Component 2, Divers - Vide, SpecificHeatCapacity: 1008 J/kg/K; Component 2, Divers - Vide, MassDensity: 1.2 kg/m3; Component 2, Divers - Vide, Embodied Energy: 0 (MJ/kg); Component 2, Divers - Vide, Embodied Carbon: 0 (kgCO₂/kg); Component 2, Divers - Vide, Name: Divers - Vide; Component 2, Divers - Vide, Participates in Collision Detection: no; Component 1, Béton, ThermalConductivity: 2.3; Component 1, Béton, SpecificHeatCapacity: 1000 J/kg/K; Component 1, Béton, MassDensity: 2300 kg/m3; Component 1, Béton, Embodied Energy: 1.92 (MJ/kg); Component 1, Béton, Embodied Carbon: 0.198 (kgCO₂/kg); Component 1, Béton, Name: Béton; Component 1, Béton, Participates in Collision Detection: yes
BaseQuantities - Height: 2.52 m; Width: 0.32 m
Name | In | Emplacement | Destination | Numéro de LOT | Length (m) | GrossFootprintArea (m2) = NetFootprintArea (m2) | GrossSideArea (m2) = NetSideArea (m2) | GrossVolume (m3) = NetVolume (m3)
M_Ext-008 | Rez-de-chaussée | Infrastructure | Façade | LOT 09 | 2.07955 | 0.665455 | 5.16001 | 1.66913
M_Ext-008 | R+1 | Superstructure | Mur intérieur; Mur joint de dilatation | LOT 04 | 2.09455 | 0.670255 | 5.24684 | 1.67321

# IfcWall: 2 - Murs Béton 20 + Enduit 1 Face 210 (18)
Type - ElementType: SOLIDWALL; PredefinedType: USERDEFINED
Pset_WallCommon - AcousticRating: Non défini; ThermalTransmittance: 0; LoadBearing: yes; IsExternal: yes
PSET_Murs_ARCHI - Matériaux: BETON
AC_Pset_RenovationAndPhasing - Renovation Status: Existing
Material Properties - Component 1, Béton, ThermalConductivity: 2.3; Component 1, Béton, SpecificHeatCapacity: 1000 J/kg/K; Component 1, Béton, MassDensity: 2300 kg/m3; Component 1, Béton, Embodied Energy: 1.92 (MJ/kg); Component 1, Béton, Embodied Carbon: 0.198 (kgCO₂/kg); Component 1, Béton, Name: Béton; Component 1, Béton, Participates in Collision Detection: yes; Component 2, Finition int - Enduit plâtre, ThermalConductivity: 0.57; Component 2, Finition int - Enduit plâtre, SpecificHeatCapacity: 1000 J/kg/K; Component 2, Finition int - Enduit plâtre, MassDensity: 1300 kg/m3; Component 2, Finition int - Enduit plâtre, Embodied Energy: 1.8 (MJ/kg); Component 2, Finition int - Enduit plâtre, Embodied Carbon: 0.13 (kgCO₂/kg); Component 2, Finition int - Enduit plâtre, Name: Finition int - Enduit plâtre; Component 2, Finition int - Enduit plâtre, Participates in Collision Detection: no
BaseQuantities - Width: 0.21 m
Name | In | Classification | Material | Emplacement | Type | Destination | Numéro de LOT | Length (m) | Height (m) | GrossFootprintArea (m2) = NetFootprintArea (m2) | GrossSideArea (m2) | NetSideArea (m2) | GrossVolume (m3) | NetVolume (m3)
M_Ext-009 | Rez-de-chaussée | Mur porteur (Classification ARCHICAD) | Béton, Finition int - Enduit plâtre | Superstructure | Mur béton banché 18cm | Mur intérieur | LOT 04 | 4.885 | 2.56 | 0.7844 | 11.7626 | 9.64864 | 2.47161 | 2.02622
M_Ext-009 | R+1 | Mur porteur (Classification ARCHICAD); Mur (Classification ARCHICAD) | Finition int - Enduit plâtre, Béton | Superstructure | Mur béton banché 18cm | Mur intérieur | LOT 04 | 1.895 | 2.51 | 0.397991 | 4.64234 | 4.64234 | 0.998957 | 0.998957
M_Ext-009 | R+2 | Mur porteur (Classification ARCHICAD); Mur (Classification ARCHICAD) | Finition int - Enduit plâtre, Béton | Superstructure | Mur béton banché 18cm | Mur intérieur | LOT 04 | 1.895 | 2.51 | 0.397991 | 4.64234 | 4.64234 | 0.998957 | 0.998957
M_Ext-009 | R+3 | Mur porteur (Classification ARCHICAD); Mur (Classification ARCHICAD) | Finition int - Enduit plâtre, Béton | Superstructure | Mur béton banché 18cm | Mur intérieur | LOT 04 | 1.89 | 2.51 | 0.400091 | 4.64339 | 4.64339 | 0.998978 | 0.998978
M_Ext-009 | Rez-de-chaussée | Mur porteur (Classification ARCHICAD) | Finition int - Enduit plâtre, Béton | Superstructure | Mur béton banché 18cm | Mur intérieur | LOT 04 | 2.005 | 2.52 | 0.398091 | 4.66394 | 4.66394 | 0.999389 | 0.999389
M_Ext-009 | Rez-de-chaussée | Mur porteur (Classification ARCHICAD) | Béton, Finition int - Enduit plâtre | Superstructure | Mur béton banché 18cm | Mur intérieur | LOT 04 | 0.86 | 2.52 | 0.19645 | 2.12468 | 2.12468 | 0.493164 | 0.493164
Voile béton banché 20cm | Rez-de-chaussée | Mur porteur (Classification ARCHICAD) | Béton, Finition int - Enduit plâtre | Infrastructure | Mur béton banché 20cm | Ouvrage extérieur | LOT 04 | 2.105 | 3.77 | 0.4621 | 8.31285 | 7.23285 | 1.74212 | 1.51532 | Description: Voile extérieur sous-sol; Propriétés DCE - Numéro article: L04.2.8.1
Voile béton banché 20cm | Rez-de-chaussée | Mur porteur (Classification ARCHICAD) | Béton, Finition int - Enduit plâtre | Infrastructure | Mur béton banché 20cm | Ouvrage extérieur | LOT 04 | 2.21 | 3.77 | 0.4641 | 8.68985 | 7.60985 | 1.74966 | 1.52286 | Description: Voile extérieur sous-sol; Propriétés DCE - Numéro article: L04.2.8.1
Voile béton banché 20cm | Rez-de-chaussée | Mur porteur (Classification ARCHICAD) | Béton, Finition int - Enduit plâtre | Infrastructure | Mur béton banché 20cm | Ouvrage extérieur | LOT 04 | 2.105 | 3.77 | 0.425 | 8.439 | 7.359 | 1.60157 | 1.37477 | Description: Voile extérieur sous-sol; Propriétés DCE - Numéro article: L04.2.8.1
M_Ext-009 | R+1 | Mur porteur (Classification ARCHICAD); Mur (Classification ARCHICAD) | Béton, Finition int - Enduit plâtre | Superstructure | Mur béton banché 18cm | Mur intérieur | LOT 04 | 0.845 | 2.52 | 0.15635 | 1.86108 | 1.86108 | 0.392512 | 0.392512
M_Ext-009 | Rez-de-chaussée | Mur porteur (Classification ARCHICAD) | Béton, Finition int - Enduit plâtre | Superstructure | Mur béton banché 18cm | Mur intérieur | LOT 04 | 1.36708 | 2.52 | 0.292856 | 3.41289 | 3.41289 | 0.716709 | 0.716709
M_Ext-009 | Rez-de-chaussée | Mur porteur (Classification ARCHICAD) | Béton, Finition int - Enduit plâtre | Superstructure | Mur béton banché 18cm | Mur intérieur | LOT 04 | 2.005 | 2.51 | 0.401 | 5.02 | 5.02 | 1.00651 | 1.00651
M_Ext-009 | Rez-de-chaussée | Mur porteur (Classification ARCHICAD) | Finition int - Enduit plâtre, Béton | Superstructure | Mur béton banché 18cm | Mur intérieur | LOT 04 | 1.81 | 2.56 | 0.4202 | 5.1251 | 5.1251 | 1.0715 | 1.0715
M_Ext-009 | R+4 | Mur porteur (Classification ARCHICAD) | Finition int - Enduit plâtre, Béton | Toiture | Mur béton banché 20cm | Ouvrage en toiture; Edicules en toiture |  | 1.81 | 0.66 | 0.4202 | 1.165 | 1.075 | 0.2741 | 0.2552
M_Ext-009 | R+4 | Mur porteur (Classification ARCHICAD) | Béton, Finition int - Enduit plâtre | Toiture | Mur béton banché 20cm | Ouvrage en toiture; Edicules en toiture |  | 2.12 | 0.66 | 0.4051 | 1.2078 | 1.2078 | 0.26367 | 0.26367
M_Ext-009 | R+4 | Mur porteur (Classification ARCHICAD) | Béton, Finition int - Enduit plâtre | Toiture | Mur béton banché 20cm | Ouvrage en toiture; Edicules en toiture |  | 1.81 | 0.66 | 0.4202 | 1.165 | 1.165 | 0.2741 | 0.2741
M_Ext-009 | R+4 | Mur porteur (Classification ARCHICAD) | Finition int - Enduit plâtre, Béton | Toiture | Mur béton banché 20cm | Ouvrage en toiture; Edicules en toiture |  | 2.12 | 0.66 | 0.4051 | 1.2078 | 1.2078 | 0.26367 | 0.26367
Voile béton banché 20cm | R+1 | Mur porteur (Classification ARCHICAD) | Béton, Finition int - Enduit plâtre | Infrastructure | Mur béton banché 20cm | Ouvrage extérieur | LOT 04 | 2.42 | 0.2 | 0.5082 | 0.484 | 0.484 | 0.10164 | 0.10164 | Description: Voile extérieur sous-sol; Propriétés DCE - Numéro article: L04.2.8.1

# IfcWall: 2 - Murs Béton 20 + Enduit 2 Faces 220 (17)
Type - ElementType: SOLIDWALL; PredefinedType: USERDEFINED
Material: Finition int - Enduit plâtre (2), Béton
Pset_WallCommon - AcousticRating: Non défini; ThermalTransmittance: 0; LoadBearing: yes; IsExternal: yes
PSET_Murs_ARCHI - Emplacement: Superstructure; Type: Mur béton banché 18cm; Destination: Mur intérieur; Matériaux: BETON
Propriétés DCE - Numéro de LOT: LOT 04
AC_Pset_RenovationAndPhasing - Renovation Status: Existing
Material Properties - Component 2, Béton, ThermalConductivity: 2.3; Component 2, Béton, SpecificHeatCapacity: 1000 J/kg/K; Component 2, Béton, MassDensity: 2300 kg/m3; Component 2, Béton, Embodied Energy: 1.92 (MJ/kg); Component 2, Béton, Embodied Carbon: 0.198 (kgCO₂/kg); Component 2, Béton, Name: Béton; Component 2, Béton, Participates in Collision Detection: yes
BaseQuantities - Width: 0.22 m
Name | In | Classification | Component 3, Finition int - Enduit plâtre, ThermalConductivity | Component 3, Finition int - Enduit plâtre, SpecificHeatCapacity (J/kg/K) | Component 3, Finition int - Enduit plâtre, MassDensity (kg/m3) | Component 3, Finition int - Enduit plâtre, Embodied Energy | Component 3, Finition int - Enduit plâtre, Embodied Carbon | Component 3, Finition int - Enduit plâtre, Name | Component 3, Finition int - Enduit plâtre, Participates in Collision Detection | Component 3 | Length (m) | Height (m) | GrossFootprintArea (m2) = NetFootprintArea (m2) | GrossSideArea (m2) | NetSideArea (m2) | GrossVolume (m3) | NetVolume (m3)
M_Ext-009 | Rez-de-chaussée | Mur porteur (Classification ARCHICAD) | 0.57 | 1000 | 1300 | 1.8 (MJ/kg) | 0.13 (kgCO₂/kg) | Finition int - Enduit plâtre | no | 2 with these values | 2.84 | 2.52 | 0.627626 | 6.98217 | 6.98217 | 1.57536 | 1.57536
M_Ext-009 | R+1 | Mur porteur (Classification ARCHICAD); Mur (Classification ARCHICAD) | 0.57 | 1000 | 1300 | 1.8 (MJ/kg) | 0.13 (kgCO₂/kg) | Finition int - Enduit plâtre | no | 2 with these values | 3.055 | 2.52 | 0.4488 | 7.68235 | 5.55565 | 1.68977 | 1.22189
M_Ext-009 | R+2 | Mur porteur (Classification ARCHICAD); Mur (Classification ARCHICAD) | 0.57 | 1000 | 1300 | 1.8 (MJ/kg) | 0.13 (kgCO₂/kg) | Finition int - Enduit plâtre | no | 2 with these values | 2.95 | 2.51 | 0.4065 | 7.39195 | 5.26525 | 1.58356 | 1.11569
M_Ext-009 | R+2 | Mur porteur (Classification ARCHICAD); Mur (Classification ARCHICAD) | 0.57 | 1000 | 1300 | 1.8 (MJ/kg) | 0.13 (kgCO₂/kg) | Finition int - Enduit plâtre | no | 2 with these values | 0.818 | 2.51 | 0.204 | 1.79 | 1.79 | 0.51019 | 0.51019
M_Ext-009 | R+3 | Mur porteur (Classification ARCHICAD); Mur (Classification ARCHICAD) | 0.57 | 1000 | 1300 | 1.8 (MJ/kg) | 0.13 (kgCO₂/kg) | Finition int - Enduit plâtre | no | 2 with these values | 1.61605 | 2.51 | 0.131132 | 4.05629 | 1.92959 | 0.892385 | 0.424511
M_Ext-009 | Rez-de-chaussée | Mur porteur (Classification ARCHICAD) |  |  |  |  |  |  |  |  | 1.755 | 2.51 | 0.1657 | 4.28834 | 2.16164 | 0.976817 | 0.508943 | Material Properties - Component 1, Finition int - Enduit plâtre, ThermalConductivity: 0.57; Component 1, Finition int - Enduit plâtre, SpecificHeatCapacity: 1000 J/kg/K; Component 1, Finition int - Enduit plâtre, MassDensity: 1300 kg/m3; Component 1, Finition int - Enduit plâtre, Embodied Energy: 1.8 (MJ/kg); Component 1, Finition int - Enduit plâtre, Embodied Carbon: 0.13 (kgCO₂/kg); Component 1, Finition int - Enduit plâtre, Name: Finition int - Enduit plâtre; Component 1, Finition int - Enduit plâtre, Participates in Collision Detection: no; Component 1: 2 with these values
M_Ext-009 | Rez-de-chaussée | Mur porteur (Classification ARCHICAD) | 0.57 | 1000 | 1300 | 1.8 (MJ/kg) | 0.13 (kgCO₂/kg) | Finition int - Enduit plâtre | no | 2 with these values | 2.95 | 2.52 | 0.4467 | 7.41818 | 5.29148 | 1.68473 | 1.21685
M_Ext-009 | R+1 | Mur porteur (Classification ARCHICAD); Mur (Classification ARCHICAD) | 0.57 | 1000 | 1300 | 1.8 (MJ/kg) | 0.13 (kgCO₂/kg) | Finition int - Enduit plâtre | no | 2 with these values | 1.085 | 2.51 | 0.2588 | 2.7359 | 2.7359 | 0.649588 | 0.649588
M_Ext-009 | R+2 | Mur porteur (Classification ARCHICAD); Mur (Classification ARCHICAD) | 0.57 | 1000 | 1300 | 1.8 (MJ/kg) | 0.13 (kgCO₂/kg) | Finition int - Enduit plâtre | no | 2 with these values | 1.085 | 2.51 | 0.2588 | 2.7359 | 2.7359 | 0.649588 | 0.649588
M_Ext-009 | R+3 | Mur porteur (Classification ARCHICAD); Mur (Classification ARCHICAD) | 0.57 | 1000 | 1300 | 1.8 (MJ/kg) | 0.13 (kgCO₂/kg) | Finition int - Enduit plâtre | no | 2 with these values | 1.33395 | 2.51 | 0.275368 | 3.33566 | 3.33566 | 0.691174 | 0.691174
M_Ext-009 | R+3 | Mur porteur (Classification ARCHICAD); Mur (Classification ARCHICAD) | 0.57 | 1000 | 1300 | 1.8 (MJ/kg) | 0.13 (kgCO₂/kg) | Finition int - Enduit plâtre | no | 2 with these values | 1.085 | 2.51 | 0.2588 | 2.67968 | 2.67968 | 0.649026 | 0.649026
M_Ext-009 | R+3 | Mur porteur (Classification ARCHICAD); Mur (Classification ARCHICAD) | 0.57 | 1000 | 1300 | 1.8 (MJ/kg) | 0.13 (kgCO₂/kg) | Finition int - Enduit plâtre | no | 2 with these values | 0.234848 | 2.51 | 0.0516665 | 0.589468 | 0.589468 | 0.129683 | 0.129683
M_Ext-009 | Rez-de-chaussée | Mur porteur (Classification ARCHICAD) |  |  |  |  |  |  |  |  | 0.59 | 2.51 | 0.1477 | 1.42313 | 1.42313 | 0.369823 | 0.369823 | Material Properties - Component 1, Finition int - Enduit plâtre, ThermalConductivity: 0.57; Component 1, Finition int - Enduit plâtre, SpecificHeatCapacity: 1000 J/kg/K; Component 1, Finition int - Enduit plâtre, MassDensity: 1300 kg/m3; Component 1, Finition int - Enduit plâtre, Embodied Energy: 1.8 (MJ/kg); Component 1, Finition int - Enduit plâtre, Embodied Carbon: 0.13 (kgCO₂/kg); Component 1, Finition int - Enduit plâtre, Name: Finition int - Enduit plâtre; Component 1, Finition int - Enduit plâtre, Participates in Collision Detection: no; Component 1: 2 with these values
M_Ext-009 | Rez-de-chaussée | Mur porteur (Classification ARCHICAD) | 0.57 | 1000 | 1300 | 1.8 (MJ/kg) | 0.13 (kgCO₂/kg) | Finition int - Enduit plâtre | no | 2 with these values | 1.085 | 2.52 | 0.2186 | 2.64872 | 2.64872 | 0.547445 | 0.547445
M_Ext-009 | R+1 | Mur porteur (Classification ARCHICAD); Mur (Classification ARCHICAD) |  |  |  |  |  |  |  |  | 3.012 | 2.51 | 0.66264 | 7.56012 | 7.56012 | 1.66323 | 1.66323 | Material Properties - Component 1, Finition int - Enduit plâtre, ThermalConductivity: 0.57; Component 1, Finition int - Enduit plâtre, SpecificHeatCapacity: 1000 J/kg/K; Component 1, Finition int - Enduit plâtre, MassDensity: 1300 kg/m3; Component 1, Finition int - Enduit plâtre, Embodied Energy: 1.8 (MJ/kg); Component 1, Finition int - Enduit plâtre, Embodied Carbon: 0.13 (kgCO₂/kg); Component 1, Finition int - Enduit plâtre, Name: Finition int - Enduit plâtre; Component 1, Finition int - Enduit plâtre, Participates in Collision Detection: no; Component 1: 2 with these values
M_Ext-009 | R+2 | Mur porteur (Classification ARCHICAD); Mur (Classification ARCHICAD) |  |  |  |  |  |  |  |  | 3.012 | 2.51 | 0.66264 | 7.56012 | 7.56012 | 1.66323 | 1.66323 | Material Properties - Component 1, Finition int - Enduit plâtre, ThermalConductivity: 0.57; Component 1, Finition int - Enduit plâtre, SpecificHeatCapacity: 1000 J/kg/K; Component 1, Finition int - Enduit plâtre, MassDensity: 1300 kg/m3; Component 1, Finition int - Enduit plâtre, Embodied Energy: 1.8 (MJ/kg); Component 1, Finition int - Enduit plâtre, Embodied Carbon: 0.13 (kgCO₂/kg); Component 1, Finition int - Enduit plâtre, Name: Finition int - Enduit plâtre; Component 1, Finition int - Enduit plâtre, Participates in Collision Detection: no; Component 1: 2 with these values
M_Ext-009 | R+3 | Mur porteur (Classification ARCHICAD); Mur (Classification ARCHICAD) | 0.57 | 1000 | 1300 | 1.8 (MJ/kg) | 0.13 (kgCO₂/kg) | Finition int - Enduit plâtre | no | 2 with these values | 1.21855 | 1.05 | 0.238492 | 1.17325 | 1.17325 | 0.250417 | 0.250417

# IfcWall: 2 - Murs Béton 20 + Isolant 120 + Enduit 1 Faces 340 (11)
Type - ElementType: SOLIDWALL; PredefinedType: USERDEFINED
Pset_WallCommon - AcousticRating: Non défini; ThermalTransmittance: 0; LoadBearing: yes; IsExternal: yes
PSET_Murs_ARCHI - Emplacement: Superstructure; Type: Mur béton banché 18cm; Destination: Mur intérieur; Matériaux: BETON
AC_Pset_RenovationAndPhasing - Renovation Status: Existing
Material Properties - Component 4, Finition int - Plaque de plâtre, ThermalConductivity: 0.8; Component 4, Finition int - Plaque de plâtre, SpecificHeatCapacity: 1000 J/kg/K; Component 4, Finition int - Plaque de plâtre, MassDensity: 1600 kg/m3; Component 4, Finition int - Plaque de plâtre, Embodied Energy: 1.45 (MJ/kg); Component 4, Finition int - Plaque de plâtre, Embodied Carbon: 0.22 (kgCO₂/kg); Component 4, Finition int - Plaque de plâtre, Name: Finition int - Plaque de plâtre; Component 4, Finition int - Plaque de plâtre, Participates in Collision Detection: no; Component 3, Isolation - Polystyrène extrudé, ThermalConductivity: 0.036; Component 3, Isolation - Polystyrène extrudé, SpecificHeatCapacity: 1400 J/kg/K; Component 3, Isolation - Polystyrène extrudé, MassDensity: 25 kg/m3; Component 3, Isolation - Polystyrène extrudé, Embodied Energy: 86.4 (MJ/kg); Component 3, Isolation - Polystyrène extrudé, Embodied Carbon: 3.43 (kgCO₂/kg); Component 3, Isolation - Polystyrène extrudé, Name: Isolation - Polystyrène extrudé; Component 3, Isolation - Polystyrène extrudé, Participates in Collision Detection: no; Component 2, Béton, ThermalConductivity: 2.3; Component 2, Béton, SpecificHeatCapacity: 1000 J/kg/K; Component 2, Béton, MassDensity: 2300 kg/m3; Component 2, Béton, Embodied Energy: 1.92 (MJ/kg); Component 2, Béton, Embodied Carbon: 0.198 (kgCO₂/kg); Component 2, Béton, Name: Béton; Component 2, Béton, Participates in Collision Detection: yes; Component 1, Finition int - Enduit plâtre, ThermalConductivity: 0.57; Component 1, Finition int - Enduit plâtre, SpecificHeatCapacity: 1000 J/kg/K; Component 1, Finition int - Enduit plâtre, MassDensity: 1300 kg/m3; Component 1, Finition int - Enduit plâtre, Embodied Energy: 1.8 (MJ/kg); Component 1, Finition int - Enduit plâtre, Embodied Carbon: 0.13 (kgCO₂/kg); Component 1, Finition int - Enduit plâtre, Name: Finition int - Enduit plâtre; Component 1, Finition int - Enduit plâtre, Participates in Collision Detection: no
BaseQuantities - Width: 0.34 m
Name | In | Classification | Material | Numéro de LOT | Numéro article | Length (m) | Height (m) | GrossFootprintArea (m2) = NetFootprintArea (m2) | GrossSideArea (m2) = NetSideArea (m2) | GrossVolume (m3) = NetVolume (m3)
M_Ext-008 | Rez-de-chaussée | Mur porteur (Classification ARCHICAD) | Finition int - Plaque de plâtre, Isolation - Polystyrène extrudé, Béton, Finition int - Enduit plâtre | LOT 09 | L09.2.1.3.1 | 6.31741 | 2.51 | 2.20728 | 15.354 | 5.36083
M_Ext-008 | R+1 | Mur porteur (Classification ARCHICAD); Mur (Classification ARCHICAD) | Finition int - Plaque de plâtre, Isolation - Polystyrène extrudé, Béton, Finition int - Enduit plâtre | LOT 04 | 09.2.1.3.1 | 3.22 | 2.51 | 1.11883 | 7.68391 | 2.80825
M_Ext-008 | R+2 | Mur porteur (Classification ARCHICAD); Mur (Classification ARCHICAD) | Finition int - Plaque de plâtre, Isolation - Polystyrène extrudé, Béton, Finition int - Enduit plâtre | LOT 04 | 09.2.1.3.1 | 3.22 | 2.51 | 1.06423 | 7.65881 | 2.67121
M_Ext-008 | R+3 | Mur porteur (Classification ARCHICAD); Mur (Classification ARCHICAD) | Finition int - Plaque de plâtre, Isolation - Polystyrène extrudé, Béton, Finition int - Enduit plâtre | LOT 04 | 09.2.1.3.1 | 3.05 | 2.5 | 1.03703 | 7.2283 | 2.59257
M_Ext-008 | R+3 | Mur porteur (Classification ARCHICAD); Mur (Classification ARCHICAD) | Finition int - Plaque de plâtre, Isolation - Polystyrène extrudé, Béton, Finition int - Enduit plâtre | LOT 04 | 09.2.1.3.1 | 5.06035 | 2.51 | 1.72052 | 12.289 | 4.31025
M_Ext-008 | Rez-de-chaussée | Mur porteur (Classification ARCHICAD) | Finition int - Plaque de plâtre, Isolation - Polystyrène extrudé, Béton, Finition int - Enduit plâtre | LOT 09 | L09.2.1.3.1 | 4.21 | 2.51 | 1.423 | 10.3161 | 3.57173
M_Ext-008 | R+1 | Mur porteur (Classification ARCHICAD); Mur (Classification ARCHICAD) | Finition int - Enduit plâtre, Béton, Isolation - Polystyrène extrudé, Finition int - Plaque de plâtre | LOT 04 | 09.2.1.3.1 | 1.03461 | 2.51 | 0.359067 | 2.60942 | 0.901259
M_Ext-008 | R+1 | Mur porteur (Classification ARCHICAD); Mur (Classification ARCHICAD) | Finition int - Plaque de plâtre, Isolation - Polystyrène extrudé, Béton, Finition int - Enduit plâtre | LOT 04 | 09.2.1.3.1 | 2.3 | 2.51 | 0.7547 | 5.76045 | 1.8943
M_Ext-008 | R+2 | Mur porteur (Classification ARCHICAD); Mur (Classification ARCHICAD) | Finition int - Enduit plâtre, Béton, Isolation - Polystyrène extrudé, Finition int - Plaque de plâtre | LOT 04 | 09.2.1.3.1 | 1.03461 | 2.51 | 0.359067 | 2.60942 | 0.901259
M_Ext-008 | R+3 | Mur porteur (Classification ARCHICAD); Mur (Classification ARCHICAD) | Finition int - Enduit plâtre, Béton, Isolation - Polystyrène extrudé, Finition int - Plaque de plâtre | LOT 04 | 09.2.1.3.1 | 1.03461 | 2.51 | 0.359067 | 2.55661 | 0.900203
M_Ext-008 | R+2 | Mur porteur (Classification ARCHICAD); Mur (Classification ARCHICAD) | Finition int - Plaque de plâtre, Isolation - Polystyrène extrudé, Béton, Finition int - Enduit plâtre | LOT 04 | 09.2.1.3.1 | 2.3 | 2.51 | 0.8093 | 5.78555 | 2.03134

# IfcWall: 2 - Murs Béton 20 + Isolant 120 330 (6)
Type - ElementType: SOLIDWALL; PredefinedType: USERDEFINED
Classification: Mur porteur (Classification ARCHICAD); Mur (Classification ARCHICAD)
Pset_WallCommon - AcousticRating: Non défini; ThermalTransmittance: 0; LoadBearing: yes; IsExternal: yes
PSET_Murs_ARCHI - Emplacement: Superstructure; Type: Mur béton banché 18cm; Destination: Mur intérieur; Matériaux: BETON
Propriétés DCE - Numéro article: 09.2.1.3.1
AC_Pset_RenovationAndPhasing - Renovation Status: Existing
Material Properties - Component 3, Finition int - Plaque de plâtre, ThermalConductivity: 0.8; Component 3, Finition int - Plaque de plâtre, SpecificHeatCapacity: 1000 J/kg/K; Component 3, Finition int - Plaque de plâtre, MassDensity: 1600 kg/m3; Component 3, Finition int - Plaque de plâtre, Embodied Energy: 1.45 (MJ/kg); Component 3, Finition int - Plaque de plâtre, Embodied Carbon: 0.22 (kgCO₂/kg); Component 3, Finition int - Plaque de plâtre, Name: Finition int - Plaque de plâtre; Component 3, Finition int - Plaque de plâtre, Participates in Collision Detection: no; Component 2, Isolation - Polystyrène extrudé, ThermalConductivity: 0.036; Component 2, Isolation - Polystyrène extrudé, SpecificHeatCapacity: 1400 J/kg/K; Component 2, Isolation - Polystyrène extrudé, MassDensity: 25 kg/m3; Component 2, Isolation - Polystyrène extrudé, Embodied Energy: 86.4 (MJ/kg); Component 2, Isolation - Polystyrène extrudé, Embodied Carbon: 3.43 (kgCO₂/kg); Component 2, Isolation - Polystyrène extrudé, Name: Isolation - Polystyrène extrudé; Component 2, Isolation - Polystyrène extrudé, Participates in Collision Detection: no; Component 1, Béton, ThermalConductivity: 2.3; Component 1, Béton, SpecificHeatCapacity: 1000 J/kg/K; Component 1, Béton, MassDensity: 2300 kg/m3; Component 1, Béton, Embodied Energy: 1.92 (MJ/kg); Component 1, Béton, Embodied Carbon: 0.198 (kgCO₂/kg); Component 1, Béton, Name: Béton; Component 1, Béton, Participates in Collision Detection: yes
BaseQuantities - Height: 2.51 m; Width: 0.33 m
Name | In | Material | Numéro de LOT | Length (m) | GrossFootprintArea (m2) = NetFootprintArea (m2) | GrossSideArea (m2) = NetSideArea (m2) | GrossVolume (m3) = NetVolume (m3)
M_Ext-008 | R+1 | Finition int - Plaque de plâtre, Isolation - Polystyrène extrudé, Béton | LOT 04 | 1.765 | 0.6097 | 4.68115 | 1.53035
M_Ext-008 | R+2 | Finition int - Plaque de plâtre, Isolation - Polystyrène extrudé, Béton | LOT 04 | 1.765 | 0.6097 | 4.68115 | 1.53035
M_Ext-008 | R+3 | Finition int - Plaque de plâtre, Isolation - Polystyrène extrudé, Béton | LOT 04 | 1.765 | 0.677 | 4.6832 | 1.53102
M_Ext-008 | R+1 | Béton, Isolation - Polystyrène extrudé, Finition int - Plaque de plâtre | LOT 04 | 2.065 | 0.6542 | 5.1706 | 1.64204
M_Ext-008 | R+2 | Béton, Isolation - Polystyrène extrudé, Finition int - Plaque de plâtre | LOT 04 | 2.065 | 0.6542 | 5.1706 | 1.64204
M_Ext-008 | R+3 | Béton, Isolation - Polystyrène extrudé, Finition int - Plaque de plâtre | LOT 04. | 2.065 | 0.6542 | 5.1706 | 1.64204

# IfcWall: 3 - Cloison 72mm Placostil 74 (508)
Type - ElementType: PARTITIONING; PredefinedType: USERDEFINED
Description: Cloisons logements
Pset_WallCommon - ThermalTransmittance: 0; LoadBearing: yes; IsExternal: yes
PSET_Murs_ARCHI - Emplacement: Superstructure; Type: Cloisons; Destination: Cloison; Matériaux: Cloison 72/48
Propriétés DCE - Numéro de LOT: LOT 09; Numéro article: L09.2.2.1.1
AC_Pset_RenovationAndPhasing - Renovation Status: Existing
BaseQuantities - Width: 0.074 m
Name | In | Classification | Material | AcousticRating | Component 2, Isolation - Laine de roche, ThermalConductivity | Component 2, Isolation - Laine de roche, SpecificHeatCapacity (J/kg/K) | Component 2, Isolation - Laine de roche, MassDensity (kg/m3) | Component 2, Isolation - Laine de roche, Embodied Energy | Component 2, Isolation - Laine de roche, Embodied Carbon | Component 2, Isolation - Laine de roche, Name | Component 2, Isolation - Laine de roche, Participates in Collision Detection | Length (m) | Height (m) | GrossFootprintArea (m2) = NetFootprintArea (m2) | GrossSideArea (m2) | NetSideArea (m2) | GrossVolume (m3) | NetVolume (m3) | Component 1, Finition int - Plaque de plâtre, ThermalConductivity | Component 1, Finition int - Plaque de plâtre, SpecificHeatCapacity (J/kg/K) | Component 1, Finition int - Plaque de plâtre, MassDensity (kg/m3) | Component 1, Finition int - Plaque de plâtre, Embodied Energy | Component 1, Finition int - Plaque de plâtre, Embodied Carbon | Component 1, Finition int - Plaque de plâtre, Name | Component 1, Finition int - Plaque de plâtre, Participates in Collision Detection
Cloison Placostil 72/48 | R+2 | Mur (Classification ARCHICAD); Cloison (Classification ARCHICAD) | Finition int - Plaque de plâtre (2), Isolation - Laine de roche | Non défini | 0.04 | 840 | 160 | 23.4 (MJ/kg) | 1.73 (kgCO₂/kg) | Isolation - Laine de roche | no | 6.61947 | 2.5 | 0.272984 | 16.1699 | 10.4915 | 1.18751 | 0.767308 | Material Properties - Component 3, Finition int - Plaque de plâtre, ThermalConductivity: 0.8; Component 3, Finition int - Plaque de plâtre, SpecificHeatCapacity: 1000 J/kg/K; Component 3, Finition int - Plaque de plâtre, MassDensity: 1600 kg/m3; Component 3, Finition int - Plaque de plâtre, Embodied Energy: 1.45 (MJ/kg); Component 3, Finition int - Plaque de plâtre, Embodied Carbon: 0.22 (kgCO₂/kg); Component 3, Finition int - Plaque de plâtre, Name: Finition int - Plaque de plâtre; Component 3, Finition int - Plaque de plâtre, Participates in Collision Detection: no; Component 3: 2 with these values
Cloison Placostil 72/48 | R+1 | Mur (Classification ARCHICAD); Cloison (Classification ARCHICAD) | Finition int - Plaque de plâtre (2), Isolation - Laine de roche | Non défini | 0.04 | 840 | 160 | 23.4 (MJ/kg) | 1.73 (kgCO₂/kg) | Isolation - Laine de roche | no | 2.67383 | 2.5 | 0.129899 | 6.50458 | 4.61178 | 0.493099 | 0.353031 | Material Properties - Component 3, Finition int - Plaque de plâtre, ThermalConductivity: 0.8; Component 3, Finition int - Plaque de plâtre, SpecificHeatCapacity: 1000 J/kg/K; Component 3, Finition int - Plaque de plâtre, MassDensity: 1600 kg/m3; Component 3, Finition int - Plaque de plâtre, Embodied Energy: 1.45 (MJ/kg); Component 3, Finition int - Plaque de plâtre, Embodied Carbon: 0.22 (kgCO₂/kg); Component 3, Finition int - Plaque de plâtre, Name: Finition int - Plaque de plâtre; Component 3, Finition int - Plaque de plâtre, Participates in Collision Detection: no; Component 3: 2 with these values
Cloison Placostil 72/48 | R+2 | Mur (Classification ARCHICAD); Cloison (Classification ARCHICAD) | Finition int - Plaque de plâtre (2), Isolation - Laine de roche | Non défini | 0.04 | 840 | 160 | 23.4 (MJ/kg) | 1.73 (kgCO₂/kg) | Isolation - Laine de roche | no | 2.67383 | 2.5 | 0.129899 | 6.50458 | 4.61178 | 0.493099 | 0.353031 | Material Properties - Component 3, Finition int - Plaque de plâtre, ThermalConductivity: 0.8; Component 3, Finition int - Plaque de plâtre, SpecificHeatCapacity: 1000 J/kg/K; Component 3, Finition int - Plaque de plâtre, MassDensity: 1600 kg/m3; Component 3, Finition int - Plaque de plâtre, Embodied Energy: 1.45 (MJ/kg); Component 3, Finition int - Plaque de plâtre, Embodied Carbon: 0.22 (kgCO₂/kg); Component 3, Finition int - Plaque de plâtre, Name: Finition int - Plaque de plâtre; Component 3, Finition int - Plaque de plâtre, Participates in Collision Detection: no; Component 3: 2 with these values
Cloison Placostil 72/48 | R+3 | Mur (Classification ARCHICAD); Cloison (Classification ARCHICAD) | Finition int - Plaque de plâtre (2), Isolation - Laine de roche | Non défini | 0.04 | 840 | 160 | 23.4 (MJ/kg) | 1.73 (kgCO₂/kg) | Isolation - Laine de roche | no | 2.71083 | 2.5 | 0.130692 | 6.58083 | 4.68803 | 0.495081 | 0.355014 | Material Properties - Component 3, Finition int - Plaque de plâtre, ThermalConductivity: 0.8; Component 3, Finition int - Plaque de plâtre, SpecificHeatCapacity: 1000 J/kg/K; Component 3, Finition int - Plaque de plâtre, MassDensity: 1600 kg/m3; Component 3, Finition int - Plaque de plâtre, Embodied Energy: 1.45 (MJ/kg); Component 3, Finition int - Plaque de plâtre, Embodied Carbon: 0.22 (kgCO₂/kg); Component 3, Finition int - Plaque de plâtre, Name: Finition int - Plaque de plâtre; Component 3, Finition int - Plaque de plâtre, Participates in Collision Detection: no; Component 3: 2 with these values
Cloison Placostil 72/48 | R+3 | Mur (Classification ARCHICAD); Cloison (Classification ARCHICAD) | Finition int - Plaque de plâtre (2), Isolation - Laine de roche | Non défini | 0.04 | 840 | 160 | 23.4 (MJ/kg) | 1.73 (kgCO₂/kg) | Isolation - Laine de roche | no | 3.628 | 2.5 | 0.204863 | 9.1075 | 7.2147 | 0.680507 | 0.54044 | Material Properties - Component 3, Finition int - Plaque de plâtre, ThermalConductivity: 0.8; Component 3, Finition int - Plaque de plâtre, SpecificHeatCapacity: 1000 J/kg/K; Component 3, Finition int - Plaque de plâtre, MassDensity: 1600 kg/m3; Component 3, Finition int - Plaque de plâtre, Embodied Energy: 1.45 (MJ/kg); Component 3, Finition int - Plaque de plâtre, Embodied Carbon: 0.22 (kgCO₂/kg); Component 3, Finition int - Plaque de plâtre, Name: Finition int - Plaque de plâtre; Component 3, Finition int - Plaque de plâtre, Participates in Collision Detection: no; Component 3: 2 with these values
Cloison Placostil 72/48 | R+4 | Mur (Classification ARCHICAD); Cloison (Classification ARCHICAD) | Finition int - Plaque de plâtre (2), Isolation - Laine de roche | Non défini | 0.04 | 840 | 160 | 23.4 (MJ/kg) | 1.73 (kgCO₂/kg) | Isolation - Laine de roche | no | 4.87496 | 2.5 | 0.226067 | 12.0674 | 8.2818 | 0.901868 | 0.621733 | 0.8 | 1000 | 1600 | 1.45 (MJ/kg) | 0.22 (kgCO₂/kg) | Finition int - Plaque de plâtre | no | Material Properties - Component 1: 2 with these values
Cloison Placostil 72/48 | R+1 | Mur (Classification ARCHICAD); Cloison (Classification ARCHICAD) | Finition int - Plaque de plâtre (2), Isolation - Laine de roche | Non défini | 0.04 | 840 | 160 | 23.4 (MJ/kg) | 1.73 (kgCO₂/kg) | Isolation - Laine de roche | no | 2.64284 | 2.5 | 0.125661 | 6.41085 | 4.51805 | 0.482503 | 0.342435 | Material Properties - Component 3, Finition int - Plaque de plâtre, ThermalConductivity: 0.8; Component 3, Finition int - Plaque de plâtre, SpecificHeatCapacity: 1000 J/kg/K; Component 3, Finition int - Plaque de plâtre, MassDensity: 1600 kg/m3; Component 3, Finition int - Plaque de plâtre, Embodied Energy: 1.45 (MJ/kg); Component 3, Finition int - Plaque de plâtre, Embodied Carbon: 0.22 (kgCO₂/kg); Component 3, Finition int - Plaque de plâtre, Name: Finition int - Plaque de plâtre; Component 3, Finition int - Plaque de plâtre, Participates in Collision Detection: no; Component 3: 2 with these values
Cloison Placostil 72/48 | R+1 | Mur (Classification ARCHICAD); Cloison (Classification ARCHICAD) | Finition int - Plaque de plâtre (2), Isolation - Laine de roche | Non défini | 0.04 | 840 | 160 | 23.4 (MJ/kg) | 1.73 (kgCO₂/kg) | Isolation - Laine de roche | no | 4.504 | 2.49 | 0.196047 | 11.0693 | 7.28365 | 0.82325 | 0.543116 | 0.8 | 1000 | 1600 | 1.45 (MJ/kg) | 0.22 (kgCO₂/kg) | Finition int - Plaque de plâtre | no | Material Properties - Component 1: 2 with these values
Cloison Placostil 72/48 | R+1 | Mur (Classification ARCHICAD); Cloison (Classification ARCHICAD) | Finition int - Plaque de plâtre (2), Isolation - Laine de roche | Non défini | 0.04 | 840 | 160 | 23.4 (MJ/kg) | 1.73 (kgCO₂/kg) | Isolation - Laine de roche | no | 2.26067 | 2.5 | 0.107994 | 5.73292 | 3.84012 | 0.438336 | 0.298269 | Material Properties - Component 3, Finition int - Plaque de plâtre, ThermalConductivity: 0.8; Component 3, Finition int - Plaque de plâtre, SpecificHeatCapacity: 1000 J/kg/K; Component 3, Finition int - Plaque de plâtre, MassDensity: 1600 kg/m3; Component 3, Finition int - Plaque de plâtre, Embodied Energy: 1.45 (MJ/kg); Component 3, Finition int - Plaque de plâtre, Embodied Carbon: 0.22 (kgCO₂/kg); Component 3, Finition int - Plaque de plâtre, Name: Finition int - Plaque de plâtre; Component 3, Finition int - Plaque de plâtre, Participates in Collision Detection: no; Component 3: 2 with these values
Cloison Placostil 72/48 | R+1 | Mur (Classification ARCHICAD); Cloison (Classification ARCHICAD) | Finition int - Plaque de plâtre (2), Isolation - Laine de roche | Non défini | 0.04 | 840 | 160 | 23.4 (MJ/kg) | 1.73 (kgCO₂/kg) | Isolation - Laine de roche | no | 3.15302 | 2.5 | 0.0994565 | 7.8038 | 4.0182 | 0.585341 | 0.305207 | 0.8 | 1000 | 1600 | 1.45 (MJ/kg) | 0.22 (kgCO₂/kg) | Finition int - Plaque de plâtre | no | Material Properties - Component 1: 2 with these values
Cloison Placostil 72/48 | R+2 | Mur (Classification ARCHICAD); Cloison (Classification ARCHICAD) | Finition int - Plaque de plâtre (2), Isolation - Laine de roche | Non défini | 0.04 | 840 | 160 | 23.4 (MJ/kg) | 1.73 (kgCO₂/kg) | Isolation - Laine de roche | no | 4.504 | 2.49 | 0.196047 | 11.0693 | 7.28365 | 0.82325 | 0.543116 | 0.8 | 1000 | 1600 | 1.45 (MJ/kg) | 0.22 (kgCO₂/kg) | Finition int - Plaque de plâtre | no | Material Properties - Component 1: 2 with these values
Cloison Placostil 72/48 | R+2 | Mur (Classification ARCHICAD); Cloison (Classification ARCHICAD) | Finition int - Plaque de plâtre (2), Isolation - Laine de roche | Non défini | 0.04 | 840 | 160 | 23.4 (MJ/kg) | 1.73 (kgCO₂/kg) | Isolation - Laine de roche | no | 2.26067 | 2.5 | 0.107994 | 5.73292 | 3.84012 | 0.438336 | 0.298269 | Material Properties - Component 3, Finition int - Plaque de plâtre, ThermalConductivity: 0.8; Component 3, Finition int - Plaque de plâtre, SpecificHeatCapacity: 1000 J/kg/K; Component 3, Finition int - Plaque de plâtre, MassDensity: 1600 kg/m3; Component 3, Finition int - Plaque de plâtre, Embodied Energy: 1.45 (MJ/kg); Component 3, Finition int - Plaque de plâtre, Embodied Carbon: 0.22 (kgCO₂/kg); Component 3, Finition int - Plaque de plâtre, Name: Finition int - Plaque de plâtre; Component 3, Finition int - Plaque de plâtre, Participates in Collision Detection: no; Component 3: 2 with these values
Cloison Placostil 72/48 | R+2 | Mur (Classification ARCHICAD); Cloison (Classification ARCHICAD) | Finition int - Plaque de plâtre (2), Isolation - Laine de roche | Non défini | 0.04 | 840 | 160 | 23.4 (MJ/kg) | 1.73 (kgCO₂/kg) | Isolation - Laine de roche | no | 3.15302 | 2.5 | 0.0994565 | 7.8038 | 4.0182 | 0.585341 | 0.305207 | 0.8 | 1000 | 1600 | 1.45 (MJ/kg) | 0.22 (kgCO₂/kg) | Finition int - Plaque de plâtre | no | Material Properties - Component 1: 2 with these values
Cloison Placostil 72/48 | R+3 | Mur (Classification ARCHICAD); Cloison (Classification ARCHICAD) | Finition int - Plaque de plâtre (2), Isolation - Laine de roche | Non défini | 0.04 | 840 | 160 | 23.4 (MJ/kg) | 1.73 (kgCO₂/kg) | Isolation - Laine de roche | no | 2.26067 | 2.49 | 0.107994 | 5.70999 | 3.81719 | 0.436583 | 0.296516 | Material Properties - Component 3, Finition int - Plaque de plâtre, ThermalConductivity: 0.8; Component 3, Finition int - Plaque de plâtre, SpecificHeatCapacity: 1000 J/kg/K; Component 3, Finition int - Plaque de plâtre, MassDensity: 1600 kg/m3; Component 3, Finition int - Plaque de plâtre, Embodied Energy: 1.45 (MJ/kg); Component 3, Finition int - Plaque de plâtre, Embodied Carbon: 0.22 (kgCO₂/kg); Component 3, Finition int - Plaque de plâtre, Name: Finition int - Plaque de plâtre; Component 3, Finition int - Plaque de plâtre, Participates in Collision Detection: no; Component 3: 2 with these values
Cloison Placostil 72/48 | R+3 | Mur (Classification ARCHICAD); Cloison (Classification ARCHICAD) | Finition int - Plaque de plâtre (2), Isolation - Laine de roche | Non défini | 0.04 | 840 | 160 | 23.4 (MJ/kg) | 1.73 (kgCO₂/kg) | Isolation - Laine de roche | no | 3.15302 | 2.5 | 0.0994565 | 7.77269 | 3.98709 | 0.583007 | 0.302873 | 0.8 | 1000 | 1600 | 1.45 (MJ/kg) | 0.22 (kgCO₂/kg) | Finition int - Plaque de plâtre | no | Material Properties - Component 1: 2 with these values
Cloison Placostil 72/48 | Rez-de-chaussée | Cloison (Classification ARCHICAD) | Finition int - Plaque de plâtre (2), Isolation - Laine de roche | Non défini | 0.04 | 840 | 160 | 23.4 (MJ/kg) | 1.73 (kgCO₂/kg) | Isolation - Laine de roche | no | 2.26067 | 2.5 | 0.107994 | 5.73292 | 3.84012 | 0.438336 | 0.298269 | Material Properties - Component 3, Finition int - Plaque de plâtre, ThermalConductivity: 0.8; Component 3, Finition int - Plaque de plâtre, SpecificHeatCapacity: 1000 J/kg/K; Component 3, Finition int - Plaque de plâtre, MassDensity: 1600 kg/m3; Component 3, Finition int - Plaque de plâtre, Embodied Energy: 1.45 (MJ/kg); Component 3, Finition int - Plaque de plâtre, Embodied Carbon: 0.22 (kgCO₂/kg); Component 3, Finition int - Plaque de plâtre, Name: Finition int - Plaque de plâtre; Component 3, Finition int - Plaque de plâtre, Participates in Collision Detection: no; Component 3: 2 with these values
Cloison Placostil 72/48 | Rez-de-chaussée | Cloison (Classification ARCHICAD) | Finition int - Plaque de plâtre (2), Isolation - Laine de roche | Non défini | 0.04 | 840 | 160 | 23.4 (MJ/kg) | 1.73 (kgCO₂/kg) | Isolation - Laine de roche | no | 3.15302 | 2.5 | 0.0994565 | 7.8038 | 4.0182 | 0.585341 | 0.305207 | 0.8 | 1000 | 1600 | 1.45 (MJ/kg) | 0.22 (kgCO₂/kg) | Finition int - Plaque de plâtre | no | Material Properties - Component 1: 2 with these values
Cloison Placostil 72/48 | Rez-de-chaussée | Cloison (Classification ARCHICAD) | Finition int - Plaque de plâtre (2), Isolation - Laine de roche | Non défini | 0.04 | 840 | 160 | 23.4 (MJ/kg) | 1.73 (kgCO₂/kg) | Isolation - Laine de roche | no | 2.64284 | 2.5 | 0.125661 | 6.47085 | 4.57805 | 0.482503 | 0.342435 | Material Properties - Component 3, Finition int - Plaque de plâtre, ThermalConductivity: 0.8; Component 3, Finition int - Plaque de plâtre, SpecificHeatCapacity: 1000 J/kg/K; Component 3, Finition int - Plaque de plâtre, MassDensity: 1600 kg/m3; Component 3, Finition int - Plaque de plâtre, Embodied Energy: 1.45 (MJ/kg); Component 3, Finition int - Plaque de plâtre, Embodied Carbon: 0.22 (kgCO₂/kg); Component 3, Finition int - Plaque de plâtre, Name: Finition int - Plaque de plâtre; Component 3, Finition int - Plaque de plâtre, Participates in Collision Detection: no; Component 3: 2 with these values
Cloison Placostil 72/48 | Rez-de-chaussée | Cloison (Classification ARCHICAD) | Finition int - Plaque de plâtre (2), Isolation - Laine de roche | Non défini | 0.04 | 840 | 160 | 23.4 (MJ/kg) | 1.73 (kgCO₂/kg) | Isolation - Laine de roche | no | 4.504 | 2.5 | 0.196047 | 11.1137 | 7.32815 | 0.826557 | 0.546423 | 0.8 | 1000 | 1600 | 1.45 (MJ/kg) | 0.22 (kgCO₂/kg) | Finition int - Plaque de plâtre | no | Material Properties - Component 1: 2 with these values
Cloison Placostil 72/48 | R+1 | Mur (Classification ARCHICAD); Cloison (Classification ARCHICAD) | Finition int - Plaque de plâtre (2), Isolation - Laine de roche | Non défini | 0.04 | 840 | 160 | 23.4 (MJ/kg) | 1.73 (kgCO₂/kg) | Isolation - Laine de roche | no | 2.95083 | 2.5 | 0.0583195 | 7.34958 | 2.79438 | 0.550949 | 0.213864 | 0.8 | 1000 | 1600 | 1.45 (MJ/kg) | 0.22 (kgCO₂/kg) | Finition int - Plaque de plâtre | no | Material Properties - Component 1: 2 with these values
Cloison Placostil 72/48 | R+1 | Mur (Classification ARCHICAD); Cloison (Classification ARCHICAD) | Finition int - Plaque de plâtre (2), Isolation - Laine de roche | Non défini | 0.04 | 840 | 160 | 23.4 (MJ/kg) | 1.73 (kgCO₂/kg) | Isolation - Laine de roche | no | 2.33437 | 2.5 | 0.078647 | 5.77591 | 3.11351 | 0.433418 | 0.2364 | Material Properties - Component 3, Finition int - Plaque de plâtre, ThermalConductivity: 0.8; Component 3, Finition int - Plaque de plâtre, SpecificHeatCapacity: 1000 J/kg/K; Component 3, Finition int - Plaque de plâtre, MassDensity: 1600 kg/m3; Component 3, Finition int - Plaque de plâtre, Embodied Energy: 1.45 (MJ/kg); Component 3, Finition int - Plaque de plâtre, Embodied Carbon: 0.22 (kgCO₂/kg); Component 3, Finition int - Plaque de plâtre, Name: Finition int - Plaque de plâtre; Component 3, Finition int - Plaque de plâtre, Participates in Collision Detection: no; Component 3: 2 with these values
Cloison Placostil 72/48 | R+1 | Mur (Classification ARCHICAD); Cloison (Classification ARCHICAD) | Finition int - Plaque de plâtre (2), Isolation - Laine de roche | Non défini | 0.04 | 840 | 160 | 23.4 (MJ/kg) | 1.73 (kgCO₂/kg) | Isolation - Laine de roche | no | 2.26139 | 2.5 | 0.0193431 | 5.08648 | 1.30088 | 0.383576 | 0.103441 | 0.8 | 1000 | 1600 | 1.45 (MJ/kg) | 0.22 (kgCO₂/kg) | Finition int - Plaque de plâtre | no | Material Properties - Component 1: 2 with these values
Cloison Placostil 72/48 | R+1 | Mur (Classification ARCHICAD); Cloison (Classification ARCHICAD) | Finition int - Plaque de plâtre (2), Isolation - Laine de roche | Non défini | 0.04 | 840 | 160 | 23.4 (MJ/kg) | 1.73 (kgCO₂/kg) | Isolation - Laine de roche | no | 0.9 | 2.5 | 0.011238 | 2.4675 | 0.5955 | 0.194595 | 0.056067 | Material Properties - Component 3, Finition int - Plaque de plâtre, ThermalConductivity: 0.8; Component 3, Finition int - Plaque de plâtre, SpecificHeatCapacity: 1000 J/kg/K; Component 3, Finition int - Plaque de plâtre, MassDensity: 1600 kg/m3; Component 3, Finition int - Plaque de plâtre, Embodied Energy: 1.45 (MJ/kg); Component 3, Finition int - Plaque de plâtre, Embodied Carbon: 0.22 (kgCO₂/kg); Component 3, Finition int - Plaque de plâtre, Name: Finition int - Plaque de plâtre; Component 3, Finition int - Plaque de plâtre, Participates in Collision Detection: no; Component 3: 2 with these values
Cloison Placostil 72/48 | R+1 | Mur (Classification ARCHICAD); Cloison (Classification ARCHICAD) | Finition int - Plaque de plâtre (2), Isolation - Laine de roche | Non défini | 0.04 | 840 | 160 | 23.4 (MJ/kg) | 1.73 (kgCO₂/kg) | Isolation - Laine de roche | no | 1.425 | 2.5 | 0.105598 | 3.42625 | 3.42625 | 0.263995 | 0.263995 | Material Properties - Component 3, Finition int - Plaque de plâtre, ThermalConductivity: 0.8; Component 3, Finition int - Plaque de plâtre, SpecificHeatCapacity: 1000 J/kg/K; Component 3, Finition int - Plaque de plâtre, MassDensity: 1600 kg/m3; Component 3, Finition int - Plaque de plâtre, Embodied Energy: 1.45 (MJ/kg); Component 3, Finition int - Plaque de plâtre, Embodied Carbon: 0.22 (kgCO₂/kg); Component 3, Finition int - Plaque de plâtre, Name: Finition int - Plaque de plâtre; Component 3, Finition int - Plaque de plâtre, Participates in Collision Detection: no; Component 3: 2 with these values
Cloison Placostil 72/48 | R+1 | Mur (Classification ARCHICAD); Cloison (Classification ARCHICAD) | Finition int - Plaque de plâtre (2), Isolation - Laine de roche | Non défini | 0.04 | 840 | 160 | 23.4 (MJ/kg) | 1.73 (kgCO₂/kg) | Isolation - Laine de roche | no | 1.85002 | 2.5 | 0.00705 | 4.94004 | 0.3705 | 0.355593 | 0.0174471 | 0.8 | 1000 | 1600 | 1.45 (MJ/kg) | 0.22 (kgCO₂/kg) | Finition int - Plaque de plâtre | no | Material Properties - Component 1: 2 with these values
Cloison Placostil 72/48 | R+1 | Mur (Classification ARCHICAD); Cloison (Classification ARCHICAD) | Finition int - Plaque de plâtre (2), Isolation - Laine de roche | Non défini | 0.04 | 840 | 160 | 23.4 (MJ/kg) | 1.73 (kgCO₂/kg) | Isolation - Laine de roche | no | 2.237 | 2.49 | 0.099592 | 5.48298 | 3.59018 | 0.415661 | 0.275593 | Material Properties - Component 3, Finition int - Plaque de plâtre, ThermalConductivity: 0.8; Component 3, Finition int - Plaque de plâtre, SpecificHeatCapacity: 1000 J/kg/K; Component 3, Finition int - Plaque de plâtre, MassDensity: 1600 kg/m3; Component 3, Finition int - Plaque de plâtre, Embodied Energy: 1.45 (MJ/kg); Component 3, Finition int - Plaque de plâtre, Embodied Carbon: 0.22 (kgCO₂/kg); Component 3, Finition int - Plaque de plâtre, Name: Finition int - Plaque de plâtre; Component 3, Finition int - Plaque de plâtre, Participates in Collision Detection: no; Component 3: 2 with these values
Cloison Placostil 72/48 | R+1 | Mur (Classification ARCHICAD); Cloison (Classification ARCHICAD) | Finition int - Plaque de plâtre (2), Isolation - Laine de roche | Non défini | 0.04 | 840 | 160 | 23.4 (MJ/kg) | 1.73 (kgCO₂/kg) | Isolation - Laine de roche | no | 0.851 | 2.5 | 0.0611459 | 2.00249 | 2.00249 | 0.152865 | 0.152865 | 0.8 | 1000 | 1600 | 1.45 (MJ/kg) | 0.22 (kgCO₂/kg) | Finition int - Plaque de plâtre | no | Material Properties - Component 1: 2 with these values
Cloison Placostil 72/48 | R+1 | Mur (Classification ARCHICAD); Cloison (Classification ARCHICAD) | Finition int - Plaque de plâtre (2), Isolation - Laine de roche | Non défini | 0.04 | 840 | 160 | 23.4 (MJ/kg) | 1.73 (kgCO₂/kg) | Isolation - Laine de roche | no | 1.67802 | 2.5 | 0.0542645 | 3.9988 | 2.106 | 0.304011 | 0.163944 | 0.8 | 1000 | 1600 | 1.45 (MJ/kg) | 0.22 (kgCO₂/kg) | Finition int - Plaque de plâtre | no | Material Properties - Component 1: 2 with these values
Cloison Placostil 72/48 | R+2 | Mur (Classification ARCHICAD); Cloison (Classification ARCHICAD) | Finition int - Plaque de plâtre (2), Isolation - Laine de roche | Non défini | 0.04 | 840 | 160 | 23.4 (MJ/kg) | 1.73 (kgCO₂/kg) | Isolation - Laine de roche | no | 2.734 | 2.5 | 0.13637 | 6.7475 | 4.8547 | 0.509275 | 0.369208 | Material Properties - Component 3, Finition int - Plaque de plâtre, ThermalConductivity: 0.8; Component 3, Finition int - Plaque de plâtre, SpecificHeatCapacity: 1000 J/kg/K; Component 3, Finition int - Plaque de plâtre, MassDensity: 1600 kg/m3; Component 3, Finition int - Plaque de plâtre, Embodied Energy: 1.45 (MJ/kg); Component 3, Finition int - Plaque de plâtre, Embodied Carbon: 0.22 (kgCO₂/kg); Component 3, Finition int - Plaque de plâtre, Name: Finition int - Plaque de plâtre; Component 3, Finition int - Plaque de plâtre, Participates in Collision Detection: no; Component 3: 2 with these values
Cloison Placostil 72/48 | R+2 | Mur (Classification ARCHICAD); Cloison (Classification ARCHICAD) | Finition int - Plaque de plâtre (2), Isolation - Laine de roche | Non défini | 0.04 | 840 | 160 | 23.4 (MJ/kg) | 1.73 (kgCO₂/kg) | Isolation - Laine de roche | no | 2.95083 | 2.5 | 0.0583195 | 7.34958 | 2.79438 | 0.550949 | 0.213864 | 0.8 | 1000 | 1600 | 1.45 (MJ/kg) | 0.22 (kgCO₂/kg) | Finition int - Plaque de plâtre | no | Material Properties - Component 1: 2 with these values
Cloison Placostil 72/48 | R+2 | Mur (Classification ARCHICAD); Cloison (Classification ARCHICAD) | Finition int - Plaque de plâtre (2), Isolation - Laine de roche | Non défini | 0.04 | 840 | 160 | 23.4 (MJ/kg) | 1.73 (kgCO₂/kg) | Isolation - Laine de roche | no | 1.31747 | 2.5 | 0.0307765 | 3.23367 | 1.34087 | 0.245291 | 0.105224 | Material Properties - Component 3, Finition int - Plaque de plâtre, ThermalConductivity: 0.8; Component 3, Finition int - Plaque de plâtre, SpecificHeatCapacity: 1000 J/kg/K; Component 3, Finition int - Plaque de plâtre, MassDensity: 1600 kg/m3; Component 3, Finition int - Plaque de plâtre, Embodied Energy: 1.45 (MJ/kg); Component 3, Finition int - Plaque de plâtre, Embodied Carbon: 0.22 (kgCO₂/kg); Component 3, Finition int - Plaque de plâtre, Name: Finition int - Plaque de plâtre; Component 3, Finition int - Plaque de plâtre, Participates in Collision Detection: no; Component 3: 2 with these values
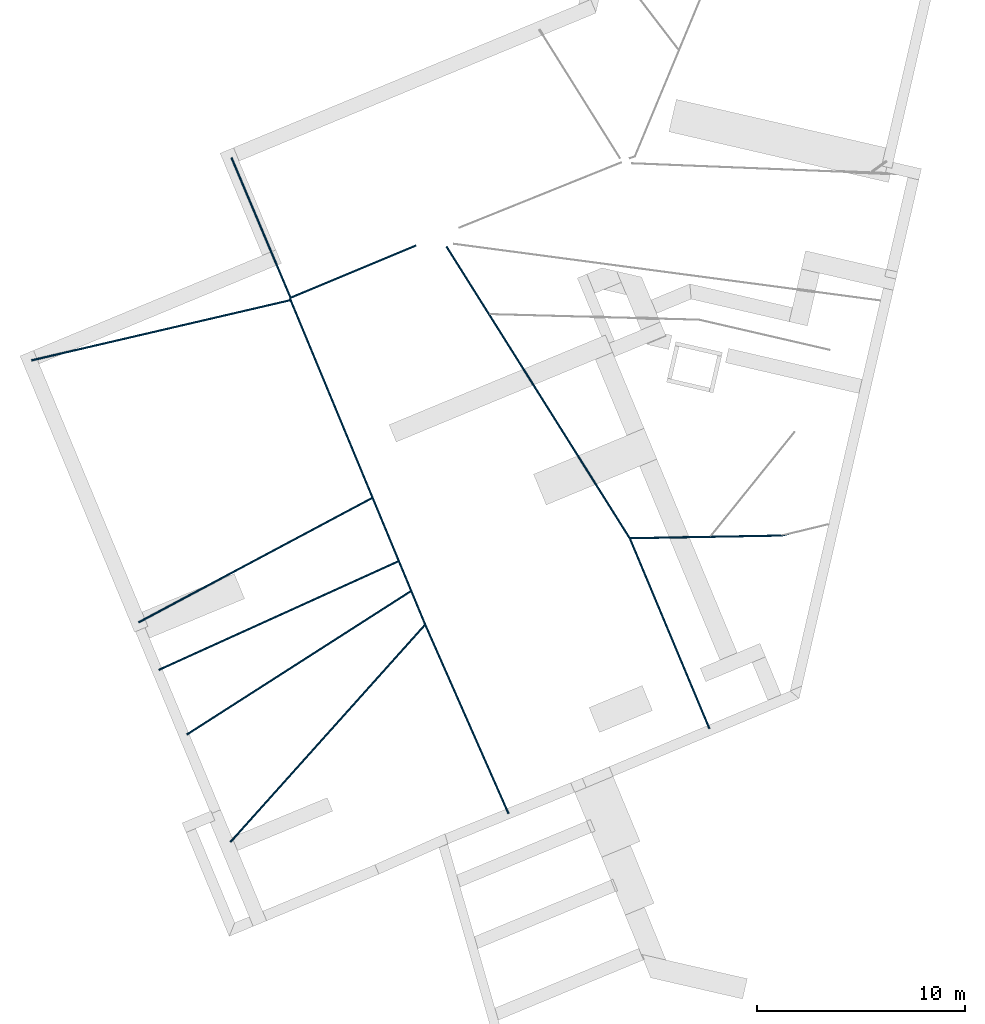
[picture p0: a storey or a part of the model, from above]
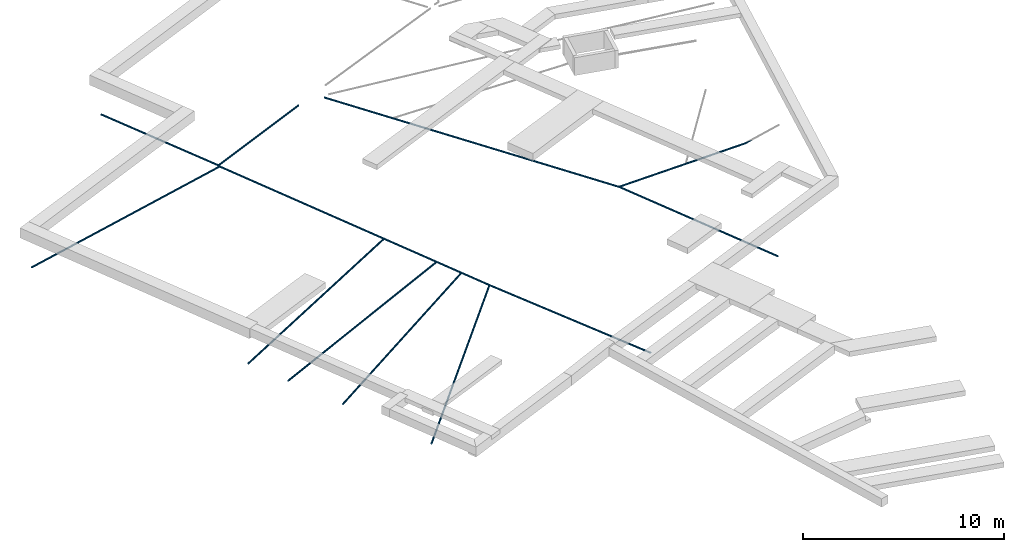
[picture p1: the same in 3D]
Properties of the parts of a building model (IFC2X3), part 9 of 22

# IfcWall: 3 - Cloison 72mm Placostil 74 (508)
Name | In | Classification | Material | AcousticRating | Component 2, Isolation - Laine de roche, ThermalConductivity | Component 2, Isolation - Laine de roche, SpecificHeatCapacity (J/kg/K) | Component 2, Isolation - Laine de roche, MassDensity (kg/m3) | Component 2, Isolation - Laine de roche, Embodied Energy | Component 2, Isolation - Laine de roche, Embodied Carbon | Component 2, Isolation - Laine de roche, Name | Component 2, Isolation - Laine de roche, Participates in Collision Detection | Length (m) | Height (m) | GrossFootprintArea (m2) = NetFootprintArea (m2) | GrossSideArea (m2) | NetSideArea (m2) | GrossVolume (m3) | NetVolume (m3) | Component 1, Finition int - Plaque de plâtre, ThermalConductivity | Component 1, Finition int - Plaque de plâtre, SpecificHeatCapacity (J/kg/K) | Component 1, Finition int - Plaque de plâtre, MassDensity (kg/m3) | Component 1, Finition int - Plaque de plâtre, Embodied Energy | Component 1, Finition int - Plaque de plâtre, Embodied Carbon | Component 1, Finition int - Plaque de plâtre, Name | Component 1, Finition int - Plaque de plâtre, Participates in Collision Detection
Cloison Placostil 72/48 | R+2 | Mur (Classification ARCHICAD); Cloison (Classification ARCHICAD) | Finition int - Plaque de plâtre (2), Isolation - Laine de roche | Non défini | 0.04 | 840 | 160 | 23.4 (MJ/kg) | 1.73 (kgCO₂/kg) | Isolation - Laine de roche | no | 2.237 | 2.49 | 0.099592 | 5.48298 | 3.59018 | 0.415661 | 0.275593 | Material Properties - Component 3, Finition int - Plaque de plâtre, ThermalConductivity: 0.8; Component 3, Finition int - Plaque de plâtre, SpecificHeatCapacity: 1000 J/kg/K; Component 3, Finition int - Plaque de plâtre, MassDensity: 1600 kg/m3; Component 3, Finition int - Plaque de plâtre, Embodied Energy: 1.45 (MJ/kg); Component 3, Finition int - Plaque de plâtre, Embodied Carbon: 0.22 (kgCO₂/kg); Component 3, Finition int - Plaque de plâtre, Name: Finition int - Plaque de plâtre; Component 3, Finition int - Plaque de plâtre, Participates in Collision Detection: no; Component 3: 2 with these values
Cloison Placostil 72/48 | R+2 | Mur (Classification ARCHICAD); Cloison (Classification ARCHICAD) | Finition int - Plaque de plâtre (2), Isolation - Laine de roche | Non défini | 0.04 | 840 | 160 | 23.4 (MJ/kg) | 1.73 (kgCO₂/kg) | Isolation - Laine de roche | no | 0.851 | 2.5 | 0.0611459 | 2.00249 | 2.00249 | 0.152865 | 0.152865 | 0.8 | 1000 | 1600 | 1.45 (MJ/kg) | 0.22 (kgCO₂/kg) | Finition int - Plaque de plâtre | no | Material Properties - Component 1: 2 with these values
Cloison Placostil 72/48 | R+2 | Mur (Classification ARCHICAD); Cloison (Classification ARCHICAD) | Finition int - Plaque de plâtre (2), Isolation - Laine de roche | Non défini | 0.04 | 840 | 160 | 23.4 (MJ/kg) | 1.73 (kgCO₂/kg) | Isolation - Laine de roche | no | 1.67802 | 2.5 | 0.0542645 | 3.9988 | 2.106 | 0.304011 | 0.163944 | 0.8 | 1000 | 1600 | 1.45 (MJ/kg) | 0.22 (kgCO₂/kg) | Finition int - Plaque de plâtre | no | Material Properties - Component 1: 2 with these values
Cloison Placostil 72/48 | R+3 | Mur (Classification ARCHICAD); Cloison (Classification ARCHICAD) | Finition int - Plaque de plâtre (2), Isolation - Laine de roche | Non défini | 0.04 | 840 | 160 | 23.4 (MJ/kg) | 1.73 (kgCO₂/kg) | Isolation - Laine de roche | no | 2.95083 | 2.5 | 0.0583195 | 7.22407 | 2.66887 | 0.546178 | 0.209094 | 0.8 | 1000 | 1600 | 1.45 (MJ/kg) | 0.22 (kgCO₂/kg) | Finition int - Plaque de plâtre | no | Material Properties - Component 1: 2 with these values
Cloison Placostil 72/48 | R+3 | Mur (Classification ARCHICAD); Cloison (Classification ARCHICAD) | Finition int - Plaque de plâtre (2), Isolation - Laine de roche | Non défini | 0.04 | 840 | 160 | 23.4 (MJ/kg) | 1.73 (kgCO₂/kg) | Isolation - Laine de roche | no | 1.67802 | 2.49 | 0.0542645 | 3.98281 | 2.09001 | 0.302795 | 0.162728 | 0.8 | 1000 | 1600 | 1.45 (MJ/kg) | 0.22 (kgCO₂/kg) | Finition int - Plaque de plâtre | no | Material Properties - Component 1: 2 with these values
Cloison Placostil 72/48 | R+3 | Mur (Classification ARCHICAD); Cloison (Classification ARCHICAD) | Finition int - Plaque de plâtre (2), Isolation - Laine de roche | Non défini | 0.04 | 840 | 160 | 23.4 (MJ/kg) | 1.73 (kgCO₂/kg) | Isolation - Laine de roche | no | 2.76753 | 2.5 | 0.14481 | 6.83885 | 4.94605 | 0.530375 | 0.390307 | 0.8 | 1000 | 1600 | 1.45 (MJ/kg) | 0.22 (kgCO₂/kg) | Finition int - Plaque de plâtre | no | Material Properties - Component 1: 2 with these values
Cloison Placostil 72/48 | Rez-de-chaussée | Cloison (Classification ARCHICAD) | Finition int - Plaque de plâtre (2), Isolation - Laine de roche | Non défini | 0.04 | 840 | 160 | 23.4 (MJ/kg) | 1.73 (kgCO₂/kg) | Isolation - Laine de roche | no | 0.801 | 2.5 | 0.0685359 | 1.90999 | 1.90999 | 0.17134 | 0.17134 | 0.8 | 1000 | 1600 | 1.45 (MJ/kg) | 0.22 (kgCO₂/kg) | Finition int - Plaque de plâtre | no | Material Properties - Component 1: 2 with these values
Cloison Placostil 72/48 | Rez-de-chaussée | Cloison (Classification ARCHICAD) | Finition int - Plaque de plâtre (2), Isolation - Laine de roche | Non défini | 0.04 | 840 | 160 | 23.4 (MJ/kg) | 1.73 (kgCO₂/kg) | Isolation - Laine de roche | no | 2.16139 | 2.5 | 0.0186031 | 5.06148 | 1.27588 | 0.381726 | 0.101591 | 0.8 | 1000 | 1600 | 1.45 (MJ/kg) | 0.22 (kgCO₂/kg) | Finition int - Plaque de plâtre | no | Material Properties - Component 1: 2 with these values
Cloison Placostil 72/48 | Rez-de-chaussée | Cloison (Classification ARCHICAD) | Finition int - Plaque de plâtre (2), Isolation - Laine de roche | Non défini | 0.04 | 840 | 160 | 23.4 (MJ/kg) | 1.73 (kgCO₂/kg) | Isolation - Laine de roche | no | 1.67802 | 2.5 | 0.0542645 | 3.9988 | 2.106 | 0.304011 | 0.163944 | 0.8 | 1000 | 1600 | 1.45 (MJ/kg) | 0.22 (kgCO₂/kg) | Finition int - Plaque de plâtre | no | Material Properties - Component 1: 2 with these values
Cloison Placostil 72/48 | Rez-de-chaussée | Cloison (Classification ARCHICAD) | Finition int - Plaque de plâtre (2), Isolation - Laine de roche | Non défini | 0.04 | 840 | 160 | 23.4 (MJ/kg) | 1.73 (kgCO₂/kg) | Isolation - Laine de roche | no | 0.9 | 2.5 | 0.011238 | 2.4675 | 0.5955 | 0.194595 | 0.056067 | Material Properties - Component 3, Finition int - Plaque de plâtre, ThermalConductivity: 0.8; Component 3, Finition int - Plaque de plâtre, SpecificHeatCapacity: 1000 J/kg/K; Component 3, Finition int - Plaque de plâtre, MassDensity: 1600 kg/m3; Component 3, Finition int - Plaque de plâtre, Embodied Energy: 1.45 (MJ/kg); Component 3, Finition int - Plaque de plâtre, Embodied Carbon: 0.22 (kgCO₂/kg); Component 3, Finition int - Plaque de plâtre, Name: Finition int - Plaque de plâtre; Component 3, Finition int - Plaque de plâtre, Participates in Collision Detection: no; Component 3: 2 with these values
Cloison Placostil 72/48 | Rez-de-chaussée | Cloison (Classification ARCHICAD) | Finition int - Plaque de plâtre (2), Isolation - Laine de roche | Non défini | 0.04 | 840 | 160 | 23.4 (MJ/kg) | 1.73 (kgCO₂/kg) | Isolation - Laine de roche | no | 1.425 | 2.5 | 0.105598 | 3.42625 | 3.42625 | 0.263995 | 0.263995 | Material Properties - Component 3, Finition int - Plaque de plâtre, ThermalConductivity: 0.8; Component 3, Finition int - Plaque de plâtre, SpecificHeatCapacity: 1000 J/kg/K; Component 3, Finition int - Plaque de plâtre, MassDensity: 1600 kg/m3; Component 3, Finition int - Plaque de plâtre, Embodied Energy: 1.45 (MJ/kg); Component 3, Finition int - Plaque de plâtre, Embodied Carbon: 0.22 (kgCO₂/kg); Component 3, Finition int - Plaque de plâtre, Name: Finition int - Plaque de plâtre; Component 3, Finition int - Plaque de plâtre, Participates in Collision Detection: no; Component 3: 2 with these values
Cloison Placostil 72/48 | Rez-de-chaussée | Cloison (Classification ARCHICAD) | Finition int - Plaque de plâtre (2), Isolation - Laine de roche | Non défini | 0.04 | 840 | 160 | 23.4 (MJ/kg) | 1.73 (kgCO₂/kg) | Isolation - Laine de roche | no | 2.33937 | 2.5 | 0.079017 | 5.78841 | 3.12601 | 0.434343 | 0.237325 | Material Properties - Component 3, Finition int - Plaque de plâtre, ThermalConductivity: 0.8; Component 3, Finition int - Plaque de plâtre, SpecificHeatCapacity: 1000 J/kg/K; Component 3, Finition int - Plaque de plâtre, MassDensity: 1600 kg/m3; Component 3, Finition int - Plaque de plâtre, Embodied Energy: 1.45 (MJ/kg); Component 3, Finition int - Plaque de plâtre, Embodied Carbon: 0.22 (kgCO₂/kg); Component 3, Finition int - Plaque de plâtre, Name: Finition int - Plaque de plâtre; Component 3, Finition int - Plaque de plâtre, Participates in Collision Detection: no; Component 3: 2 with these values
Cloison Placostil 72/48 | Rez-de-chaussée | Cloison (Classification ARCHICAD) | Finition int - Plaque de plâtre (2), Isolation - Laine de roche | Non défini | 0.04 | 840 | 160 | 23.4 (MJ/kg) | 1.73 (kgCO₂/kg) | Isolation - Laine de roche | no | 1.908 | 2.5 | 0.071283 | 4.54331 | 2.65051 | 0.344206 | 0.204139 | 0.8 | 1000 | 1600 | 1.45 (MJ/kg) | 0.22 (kgCO₂/kg) | Finition int - Plaque de plâtre | no | Material Properties - Component 1: 2 with these values
Cloison Placostil 72/48 | Rez-de-chaussée | Cloison (Classification ARCHICAD) | Finition int - Plaque de plâtre (2), Isolation - Laine de roche | Non défini | 0.04 | 840 | 160 | 23.4 (MJ/kg) | 1.73 (kgCO₂/kg) | Isolation - Laine de roche | no | 1.85002 | 2.5 | 0.00705 | 5.00004 | 0.375 | 0.359878 | 0.017625 | 0.8 | 1000 | 1600 | 1.45 (MJ/kg) | 0.22 (kgCO₂/kg) | Finition int - Plaque de plâtre | no | Material Properties - Component 1: 2 with these values
Cloison Placostil 72/48 | Rez-de-chaussée | Cloison (Classification ARCHICAD) | Finition int - Plaque de plâtre (2), Isolation - Laine de roche | Non défini | 0.04 | 840 | 160 | 23.4 (MJ/kg) | 1.73 (kgCO₂/kg) | Isolation - Laine de roche | no | 2.237 | 2.5 | 0.099592 | 5.505 | 3.6122 | 0.41733 | 0.277263 | Material Properties - Component 3, Finition int - Plaque de plâtre, ThermalConductivity: 0.8; Component 3, Finition int - Plaque de plâtre, SpecificHeatCapacity: 1000 J/kg/K; Component 3, Finition int - Plaque de plâtre, MassDensity: 1600 kg/m3; Component 3, Finition int - Plaque de plâtre, Embodied Energy: 1.45 (MJ/kg); Component 3, Finition int - Plaque de plâtre, Embodied Carbon: 0.22 (kgCO₂/kg); Component 3, Finition int - Plaque de plâtre, Name: Finition int - Plaque de plâtre; Component 3, Finition int - Plaque de plâtre, Participates in Collision Detection: no; Component 3: 2 with these values
Cloison Placostil 72/48 | R+1 | Mur (Classification ARCHICAD); Cloison (Classification ARCHICAD) | Finition int - Plaque de plâtre (2), Isolation - Laine de roche | Non défini | 0.04 | 840 | 160 | 23.4 (MJ/kg) | 1.73 (kgCO₂/kg) | Isolation - Laine de roche | no | 2.748 | 2.5 | 0.199462 | 6.7175 | 6.7175 | 0.498655 | 0.498655 | 0.8 | 1000 | 1600 | 1.45 (MJ/kg) | 0.22 (kgCO₂/kg) | Finition int - Plaque de plâtre | no | Material Properties - Component 1: 2 with these values
Cloison Placostil 72/48 | R+1 | Mur (Classification ARCHICAD); Cloison (Classification ARCHICAD) | Finition int - Plaque de plâtre (2), Isolation - Laine de roche | Non défini | 0.04 | 840 | 160 | 23.4 (MJ/kg) | 1.73 (kgCO₂/kg) | Isolation - Laine de roche | no | 2.42331 | 2.5 | 0.114003 | 6.03077 | 4.13797 | 0.453357 | 0.31329 | 0.8 | 1000 | 1600 | 1.45 (MJ/kg) | 0.22 (kgCO₂/kg) | Finition int - Plaque de plâtre | no | Material Properties - Component 1: 2 with these values
Cloison Placostil 72/48 | R+1 | Mur (Classification ARCHICAD); Cloison (Classification ARCHICAD) | Finition int - Plaque de plâtre (2), Isolation - Laine de roche | Non défini | 0.04 | 840 | 160 | 23.4 (MJ/kg) | 1.73 (kgCO₂/kg) | Isolation - Laine de roche | no | 1.274 | 2.5 | 0.028954 | 3.1575 | 1.2647 | 0.240735 | 0.100668 | Material Properties - Component 3, Finition int - Plaque de plâtre, ThermalConductivity: 0.8; Component 3, Finition int - Plaque de plâtre, SpecificHeatCapacity: 1000 J/kg/K; Component 3, Finition int - Plaque de plâtre, MassDensity: 1600 kg/m3; Component 3, Finition int - Plaque de plâtre, Embodied Energy: 1.45 (MJ/kg); Component 3, Finition int - Plaque de plâtre, Embodied Carbon: 0.22 (kgCO₂/kg); Component 3, Finition int - Plaque de plâtre, Name: Finition int - Plaque de plâtre; Component 3, Finition int - Plaque de plâtre, Participates in Collision Detection: no; Component 3: 2 with these values
Cloison Placostil 72/48 | R+1 | Mur (Classification ARCHICAD); Cloison (Classification ARCHICAD) | Finition int - Plaque de plâtre (2), Isolation - Laine de roche | Non défini | 0.04 | 840 | 160 | 23.4 (MJ/kg) | 1.73 (kgCO₂/kg) | Isolation - Laine de roche | no | 2.087 | 2.5 | 0.085777 | 5.14125 | 3.24845 | 0.382793 | 0.242725 | 0.8 | 1000 | 1600 | 1.45 (MJ/kg) | 0.22 (kgCO₂/kg) | Finition int - Plaque de plâtre | no | Material Properties - Component 1: 2 with these values
Cloison Placostil 72/48 | R+1 | Mur (Classification ARCHICAD); Cloison (Classification ARCHICAD) | Finition int - Plaque de plâtre (2), Isolation - Laine de roche | Non défini | 0.04 | 840 | 160 | 23.4 (MJ/kg) | 1.73 (kgCO₂/kg) | Isolation - Laine de roche | no | 2.34703 | 2.5 | 0.0796042 | 5.56668 | 2.90428 | 0.431533 | 0.234516 | 0.8 | 1000 | 1600 | 1.45 (MJ/kg) | 0.22 (kgCO₂/kg) | Finition int - Plaque de plâtre | no | Material Properties - Component 1: 2 with these values
Cloison Placostil 72/48 | R+1 | Mur (Classification ARCHICAD); Cloison (Classification ARCHICAD) | Finition int - Plaque de plâtre (2), Isolation - Laine de roche | Non défini | 0.04 | 840 | 160 | 23.4 (MJ/kg) | 1.73 (kgCO₂/kg) | Isolation - Laine de roche | no | 1.40733 | 2.5 | 0.00239214 | 3.34008 | 0.0358016 | 0.258841 | 0.00590624 | 0.8 | 1000 | 1600 | 1.45 (MJ/kg) | 0.22 (kgCO₂/kg) | Finition int - Plaque de plâtre | no | Material Properties - Component 1: 2 with these values
Cloison Placostil 72/48 | R+1 | Mur (Classification ARCHICAD); Cloison (Classification ARCHICAD) | Finition int - Plaque de plâtre (2), Isolation - Laine de roche | Non défini | 0.04 | 840 | 160 | 23.4 (MJ/kg) | 1.73 (kgCO₂/kg) | Isolation - Laine de roche | no | 1.474 | 2.5 | 0.107599 | 3.48046 | 3.48046 | 0.267439 | 0.267439 | 0.8 | 1000 | 1600 | 1.45 (MJ/kg) | 0.22 (kgCO₂/kg) | Finition int - Plaque de plâtre | no | Material Properties - Component 1: 2 with these values
Cloison Placostil 72/48 | R+1 | Mur (Classification ARCHICAD); Cloison (Classification ARCHICAD) | Finition int - Plaque de plâtre (2), Isolation - Laine de roche | Non défini | 0.04 | 840 | 160 | 23.4 (MJ/kg) | 1.73 (kgCO₂/kg) | Isolation - Laine de roche | no | 5.42029 | 2.5 | 0.265174 | 13.4307 | 9.64513 | 0.999634 | 0.7195 | 0.8 | 1000 | 1600 | 1.45 (MJ/kg) | 0.22 (kgCO₂/kg) | Finition int - Plaque de plâtre | no | Material Properties - Component 1: 2 with these values
Cloison Placostil 72/48 | R+1 | Mur (Classification ARCHICAD); Cloison (Classification ARCHICAD) | Finition int - Plaque de plâtre (2), Isolation - Laine de roche | Non défini | 0.04 | 840 | 160 | 23.4 (MJ/kg) | 1.73 (kgCO₂/kg) | Isolation - Laine de roche | no | 2.4474 | 2.5 | 0.112447 | 5.97701 | 4.08421 | 0.447771 | 0.307703 | 0.8 | 1000 | 1600 | 1.45 (MJ/kg) | 0.22 (kgCO₂/kg) | Finition int - Plaque de plâtre | no | Material Properties - Component 1: 2 with these values
Cloison Placostil 72/48 | R+1 | Mur (Classification ARCHICAD); Cloison (Classification ARCHICAD) | Finition int - Plaque de plâtre (2), Isolation - Laine de roche | Non défini | 0.04 | 840 | 160 | 23.4 (MJ/kg) | 1.73 (kgCO₂/kg) | Isolation - Laine de roche | no | 2.565 | 2.5 | 0.122543 | 5.75495 | 3.86215 | 0.460309 | 0.320241 | 0.8 | 1000 | 1600 | 1.45 (MJ/kg) | 0.22 (kgCO₂/kg) | Finition int - Plaque de plâtre | no | Material Properties - Component 1: 2 with these values
Cloison Placostil 72/48 | R+1 | Mur (Classification ARCHICAD); Cloison (Classification ARCHICAD) | Finition int - Plaque de plâtre (2), Isolation - Laine de roche | Non défini | 0.04 | 840 | 160 | 23.4 (MJ/kg) | 1.73 (kgCO₂/kg) | Isolation - Laine de roche | no | 1.574 | 2.5 | 0.048512 | 3.875 | 1.9822 | 0.28963 | 0.149563 | Material Properties - Component 3, Finition int - Plaque de plâtre, ThermalConductivity: 0.8; Component 3, Finition int - Plaque de plâtre, SpecificHeatCapacity: 1000 J/kg/K; Component 3, Finition int - Plaque de plâtre, MassDensity: 1600 kg/m3; Component 3, Finition int - Plaque de plâtre, Embodied Energy: 1.45 (MJ/kg); Component 3, Finition int - Plaque de plâtre, Embodied Carbon: 0.22 (kgCO₂/kg); Component 3, Finition int - Plaque de plâtre, Name: Finition int - Plaque de plâtre; Component 3, Finition int - Plaque de plâtre, Participates in Collision Detection: no; Component 3: 2 with these values
Cloison Placostil 72/48 | R+1 | Mur (Classification ARCHICAD); Cloison (Classification ARCHICAD) | Finition int - Plaque de plâtre (2), Isolation - Laine de roche | Non défini | 0.04 | 840 | 160 | 23.4 (MJ/kg) | 1.73 (kgCO₂/kg) | Isolation - Laine de roche | no | 1.176 | 2.49 | 0.098262 | 3.14487 | 3.14487 | 0.244672 | 0.244672 | 0.8 | 1000 | 1600 | 1.45 (MJ/kg) | 0.22 (kgCO₂/kg) | Finition int - Plaque de plâtre | no | Material Properties - Component 1: 2 with these values
Cloison Placostil 72/48 | R+1 | Mur (Classification ARCHICAD); Cloison (Classification ARCHICAD) | Finition int - Plaque de plâtre (2), Isolation - Laine de roche | Non défini | 0.04 | 840 | 160 | 23.4 (MJ/kg) | 1.73 (kgCO₂/kg) | Isolation - Laine de roche | no | 1.4209 | 2.49 | 0.0371097 | 3.52186 | 1.62906 | 0.26008 | 0.120012 | 0.8 | 1000 | 1600 | 1.45 (MJ/kg) | 0.22 (kgCO₂/kg) | Finition int - Plaque de plâtre | no | Material Properties - Component 1: 2 with these values
Cloison Placostil 72/48 | R+1 | Mur (Classification ARCHICAD); Cloison (Classification ARCHICAD) | Finition int - Plaque de plâtre (2), Isolation - Laine de roche | Non défini | 0.04 | 840 | 160 | 23.4 (MJ/kg) | 1.73 (kgCO₂/kg) | Isolation - Laine de roche | no | 2.01507 | 2.5 | 0.004927 | 4.72471 | 0.610328 | 0.370545 | 0.0660813 | 0.8 | 1000 | 1600 | 1.45 (MJ/kg) | 0.22 (kgCO₂/kg) | Finition int - Plaque de plâtre | no | Material Properties - Component 1: 2 with these values
Cloison Placostil 72/48 | R+1 | Mur (Classification ARCHICAD); Cloison (Classification ARCHICAD) | Finition int - Plaque de plâtre (2), Isolation - Laine de roche | Non défini | 0.04 | 840 | 160 | 23.4 (MJ/kg) | 1.73 (kgCO₂/kg) | Isolation - Laine de roche | no | 1.459 | 2.5 | 0.040002 | 3.5875 | 1.6947 | 0.268355 | 0.128288 | Material Properties - Component 3, Finition int - Plaque de plâtre, ThermalConductivity: 0.8; Component 3, Finition int - Plaque de plâtre, SpecificHeatCapacity: 1000 J/kg/K; Component 3, Finition int - Plaque de plâtre, MassDensity: 1600 kg/m3; Component 3, Finition int - Plaque de plâtre, Embodied Energy: 1.45 (MJ/kg); Component 3, Finition int - Plaque de plâtre, Embodied Carbon: 0.22 (kgCO₂/kg); Component 3, Finition int - Plaque de plâtre, Name: Finition int - Plaque de plâtre; Component 3, Finition int - Plaque de plâtre, Participates in Collision Detection: no; Component 3: 2 with these values
Cloison Placostil 72/48 | R+1 | Mur (Classification ARCHICAD); Cloison (Classification ARCHICAD) | Finition int - Plaque de plâtre (2), Isolation - Laine de roche | Non défini | 0.04 | 840 | 160 | 23.4 (MJ/kg) | 1.73 (kgCO₂/kg) | Isolation - Laine de roche | no | 1.16596 | 2.5 | 0.0111335 | 3.11616 | 0.746036 | 0.238936 | 0.0632989 | Material Properties - Component 3, Finition int - Plaque de plâtre, ThermalConductivity: 0.8; Component 3, Finition int - Plaque de plâtre, SpecificHeatCapacity: 1000 J/kg/K; Component 3, Finition int - Plaque de plâtre, MassDensity: 1600 kg/m3; Component 3, Finition int - Plaque de plâtre, Embodied Energy: 1.45 (MJ/kg); Component 3, Finition int - Plaque de plâtre, Embodied Carbon: 0.22 (kgCO₂/kg); Component 3, Finition int - Plaque de plâtre, Name: Finition int - Plaque de plâtre; Component 3, Finition int - Plaque de plâtre, Participates in Collision Detection: no; Component 3: 2 with these values
Cloison Placostil 72/48 | R+1 | Mur (Classification ARCHICAD); Cloison (Classification ARCHICAD) | Finition int - Plaque de plâtre (2), Isolation - Laine de roche | Non défini | 0.04 | 840 | 160 | 23.4 (MJ/kg) | 1.73 (kgCO₂/kg) | Isolation - Laine de roche | no | 1.511 | 2.5 | 0.109245 | 3.64125 | 3.64125 | 0.273113 | 0.273113 | Material Properties - Component 3, Finition int - Plaque de plâtre, ThermalConductivity: 0.8; Component 3, Finition int - Plaque de plâtre, SpecificHeatCapacity: 1000 J/kg/K; Component 3, Finition int - Plaque de plâtre, MassDensity: 1600 kg/m3; Component 3, Finition int - Plaque de plâtre, Embodied Energy: 1.45 (MJ/kg); Component 3, Finition int - Plaque de plâtre, Embodied Carbon: 0.22 (kgCO₂/kg); Component 3, Finition int - Plaque de plâtre, Name: Finition int - Plaque de plâtre; Component 3, Finition int - Plaque de plâtre, Participates in Collision Detection: no; Component 3: 2 with these values
Cloison Placostil 72/48 | R+1 | Mur (Classification ARCHICAD); Cloison (Classification ARCHICAD) | Finition int - Plaque de plâtre (2), Isolation - Laine de roche | Non défini | 0.04 | 840 | 160 | 23.4 (MJ/kg) | 1.73 (kgCO₂/kg) | Isolation - Laine de roche | no | 1.004 | 2.5 | 0.000793 | 2.30875 | 0.40139 | 0.165627 | 0.0294749 | Material Properties - Component 3, Finition int - Plaque de plâtre, ThermalConductivity: 0.8; Component 3, Finition int - Plaque de plâtre, SpecificHeatCapacity: 1000 J/kg/K; Component 3, Finition int - Plaque de plâtre, MassDensity: 1600 kg/m3; Component 3, Finition int - Plaque de plâtre, Embodied Energy: 1.45 (MJ/kg); Component 3, Finition int - Plaque de plâtre, Embodied Carbon: 0.22 (kgCO₂/kg); Component 3, Finition int - Plaque de plâtre, Name: Finition int - Plaque de plâtre; Component 3, Finition int - Plaque de plâtre, Participates in Collision Detection: no; Component 3: 2 with these values
Cloison Placostil 72/48 | R+2 | Mur (Classification ARCHICAD); Cloison (Classification ARCHICAD) | Finition int - Plaque de plâtre (2), Isolation - Laine de roche | Non défini | 0.04 | 840 | 160 | 23.4 (MJ/kg) | 1.73 (kgCO₂/kg) | Isolation - Laine de roche | no | 3.474 | 2.5 | 0.18647 | 8.5925 | 6.6997 | 0.634525 | 0.494458 | 0.8 | 1000 | 1600 | 1.45 (MJ/kg) | 0.22 (kgCO₂/kg) | Finition int - Plaque de plâtre | no | Material Properties - Component 1: 2 with these values
Cloison Placostil 72/48 | R+2 | Mur (Classification ARCHICAD); Cloison (Classification ARCHICAD) | Finition int - Plaque de plâtre (2), Isolation - Laine de roche | Non défini | 0.04 | 840 | 160 | 23.4 (MJ/kg) | 1.73 (kgCO₂/kg) | Isolation - Laine de roche | no | 1.64838 | 2.5 | 0.0559609 | 4.07719 | 2.18439 | 0.308252 | 0.168185 | 0.8 | 1000 | 1600 | 1.45 (MJ/kg) | 0.22 (kgCO₂/kg) | Finition int - Plaque de plâtre | no | Material Properties - Component 1: 2 with these values
Cloison Placostil 72/48 | R+2 | Mur (Classification ARCHICAD); Cloison (Classification ARCHICAD) | Finition int - Plaque de plâtre (2), Isolation - Laine de roche | Non défini | 0.04 | 840 | 160 | 23.4 (MJ/kg) | 1.73 (kgCO₂/kg) | Isolation - Laine de roche | no | 2.06779 | 2.5 | 0.0743012 | 4.73571 | 2.84291 | 0.354103 | 0.214036 | 0.8 | 1000 | 1600 | 1.45 (MJ/kg) | 0.22 (kgCO₂/kg) | Finition int - Plaque de plâtre | no | Material Properties - Component 1: 2 with these values
Cloison Placostil 72/48 | R+2 | Mur (Classification ARCHICAD); Cloison (Classification ARCHICAD) | Finition int - Plaque de plâtre (2), Isolation - Laine de roche | Non défini | 0.04 | 840 | 160 | 23.4 (MJ/kg) | 1.73 (kgCO₂/kg) | Isolation - Laine de roche | no | 1.70917 | 2.5 | 0.126552 | 3.97574 | 3.97574 | 0.31135 | 0.31135 | 0.8 | 1000 | 1600 | 1.45 (MJ/kg) | 0.22 (kgCO₂/kg) | Finition int - Plaque de plâtre | no | Material Properties - Component 1: 2 with these values
Cloison Placostil 72/48 | R+2 | Mur (Classification ARCHICAD); Cloison (Classification ARCHICAD) | Finition int - Plaque de plâtre (2), Isolation - Laine de roche | Non défini | 0.04 | 840 | 160 | 23.4 (MJ/kg) | 1.73 (kgCO₂/kg) | Isolation - Laine de roche | no | 2.748 | 2.5 | 0.199462 | 6.7175 | 6.7175 | 0.498655 | 0.498655 | 0.8 | 1000 | 1600 | 1.45 (MJ/kg) | 0.22 (kgCO₂/kg) | Finition int - Plaque de plâtre | no | Material Properties - Component 1: 2 with these values
Cloison Placostil 72/48 | R+2 | Mur (Classification ARCHICAD); Cloison (Classification ARCHICAD) | Finition int - Plaque de plâtre (2), Isolation - Laine de roche | Non défini | 0.04 | 840 | 160 | 23.4 (MJ/kg) | 1.73 (kgCO₂/kg) | Isolation - Laine de roche | no | 2.42331 | 2.5 | 0.114003 | 6.03077 | 4.13797 | 0.453357 | 0.31329 | 0.8 | 1000 | 1600 | 1.45 (MJ/kg) | 0.22 (kgCO₂/kg) | Finition int - Plaque de plâtre | no | Material Properties - Component 1: 2 with these values
Cloison Placostil 72/48 | R+2 | Mur (Classification ARCHICAD); Cloison (Classification ARCHICAD) | Finition int - Plaque de plâtre (2), Isolation - Laine de roche | Non défini | 0.04 | 840 | 160 | 23.4 (MJ/kg) | 1.73 (kgCO₂/kg) | Isolation - Laine de roche | no | 1.176 | 2.49 | 0.098262 | 3.14487 | 3.14487 | 0.244672 | 0.244672 | 0.8 | 1000 | 1600 | 1.45 (MJ/kg) | 0.22 (kgCO₂/kg) | Finition int - Plaque de plâtre | no | Material Properties - Component 1: 2 with these values
Cloison Placostil 72/48 | R+2 | Mur (Classification ARCHICAD); Cloison (Classification ARCHICAD) | Finition int - Plaque de plâtre (2), Isolation - Laine de roche | Non défini | 0.04 | 840 | 160 | 23.4 (MJ/kg) | 1.73 (kgCO₂/kg) | Isolation - Laine de roche | no | 1.25 | 2.5 | 0.001248 | 3.125 | 0.525 | 0.23437 | 0.04197 | 0.8 | 1000 | 1600 | 1.45 (MJ/kg) | 0.22 (kgCO₂/kg) | Finition int - Plaque de plâtre | no | Material Properties - Component 1: 2 with these values
Cloison Placostil 72/48 | R+2 | Mur (Classification ARCHICAD); Cloison (Classification ARCHICAD) | Finition int - Plaque de plâtre (2), Isolation - Laine de roche | 35 dB(A) | 0.04 | 840 | 160 | 23.4 (MJ/kg) | 1.73 (kgCO₂/kg) | Isolation - Laine de roche | no | 0.361 | 2.5 | 0.026641 | 0.88625 | 0.88625 | 0.0666025 | 0.0666025 | Material Properties - Component 3, Finition int - Plaque de plâtre, ThermalConductivity: 0.8; Component 3, Finition int - Plaque de plâtre, SpecificHeatCapacity: 1000 J/kg/K; Component 3, Finition int - Plaque de plâtre, MassDensity: 1600 kg/m3; Component 3, Finition int - Plaque de plâtre, Embodied Energy: 1.45 (MJ/kg); Component 3, Finition int - Plaque de plâtre, Embodied Carbon: 0.22 (kgCO₂/kg); Component 3, Finition int - Plaque de plâtre, Name: Finition int - Plaque de plâtre; Component 3, Finition int - Plaque de plâtre, Participates in Collision Detection: no; Component 3: 2 with these values
Cloison Placostil 72/48 | R+2 | Mur (Classification ARCHICAD); Cloison (Classification ARCHICAD) | Finition int - Plaque de plâtre (2), Isolation - Laine de roche | Non défini | 0.04 | 840 | 160 | 23.4 (MJ/kg) | 1.73 (kgCO₂/kg) | Isolation - Laine de roche | no | 2.565 | 2.5 | 0.122543 | 5.9222 | 4.0294 | 0.464655 | 0.324588 | 0.8 | 1000 | 1600 | 1.45 (MJ/kg) | 0.22 (kgCO₂/kg) | Finition int - Plaque de plâtre | no | Material Properties - Component 1: 2 with these values
Cloison Placostil 72/48 | R+2 | Mur (Classification ARCHICAD); Cloison (Classification ARCHICAD) | Finition int - Plaque de plâtre (2), Isolation - Laine de roche | Non défini | 0.04 | 840 | 160 | 23.4 (MJ/kg) | 1.73 (kgCO₂/kg) | Isolation - Laine de roche | no | 1.4209 | 2.49 | 0.0371097 | 3.52186 | 1.62906 | 0.26008 | 0.120012 | 0.8 | 1000 | 1600 | 1.45 (MJ/kg) | 0.22 (kgCO₂/kg) | Finition int - Plaque de plâtre | no | Material Properties - Component 1: 2 with these values
Cloison Placostil 72/48 | R+2 | Mur (Classification ARCHICAD); Cloison (Classification ARCHICAD) | Finition int - Plaque de plâtre (2), Isolation - Laine de roche | Non défini | 0.04 | 840 | 160 | 23.4 (MJ/kg) | 1.73 (kgCO₂/kg) | Isolation - Laine de roche | no | 2.01507 | 2.5 | 0.004927 | 4.72471 | 0.610328 | 0.370545 | 0.0660813 | 0.8 | 1000 | 1600 | 1.45 (MJ/kg) | 0.22 (kgCO₂/kg) | Finition int - Plaque de plâtre | no | Material Properties - Component 1: 2 with these values
Cloison Placostil 72/48 | R+2 | Mur (Classification ARCHICAD); Cloison (Classification ARCHICAD) | Finition int - Plaque de plâtre (2), Isolation - Laine de roche | Non défini | 0.04 | 840 | 160 | 23.4 (MJ/kg) | 1.73 (kgCO₂/kg) | Isolation - Laine de roche | no | 3.47153 | 2.5 | 0.188232 | 8.60258 | 6.70978 | 0.638931 | 0.498864 | 0.8 | 1000 | 1600 | 1.45 (MJ/kg) | 0.22 (kgCO₂/kg) | Finition int - Plaque de plâtre | no | Material Properties - Component 1: 2 with these values
Cloison Placostil 72/48 | R+2 | Mur (Classification ARCHICAD); Cloison (Classification ARCHICAD) | Finition int - Plaque de plâtre (2), Isolation - Laine de roche | Non défini | 0.04 | 840 | 160 | 23.4 (MJ/kg) | 1.73 (kgCO₂/kg) | Isolation - Laine de roche | no | 2.337 | 2.5 | 0.103029 | 5.70625 | 3.81345 | 0.425923 | 0.285855 | 0.8 | 1000 | 1600 | 1.45 (MJ/kg) | 0.22 (kgCO₂/kg) | Finition int - Plaque de plâtre | no | Material Properties - Component 1: 2 with these values
Cloison Placostil 72/48 | R+2 | Mur (Classification ARCHICAD); Cloison (Classification ARCHICAD) | Finition int - Plaque de plâtre (2), Isolation - Laine de roche | Non défini | 0.04 | 840 | 160 | 23.4 (MJ/kg) | 1.73 (kgCO₂/kg) | Isolation - Laine de roche | no | 1.511 | 2.5 | 0.109245 | 3.64125 | 3.64125 | 0.273113 | 0.273113 | Material Properties - Component 3, Finition int - Plaque de plâtre, ThermalConductivity: 0.8; Component 3, Finition int - Plaque de plâtre, SpecificHeatCapacity: 1000 J/kg/K; Component 3, Finition int - Plaque de plâtre, MassDensity: 1600 kg/m3; Component 3, Finition int - Plaque de plâtre, Embodied Energy: 1.45 (MJ/kg); Component 3, Finition int - Plaque de plâtre, Embodied Carbon: 0.22 (kgCO₂/kg); Component 3, Finition int - Plaque de plâtre, Name: Finition int - Plaque de plâtre; Component 3, Finition int - Plaque de plâtre, Participates in Collision Detection: no; Component 3: 2 with these values
Cloison Placostil 72/48 | R+2 | Mur (Classification ARCHICAD); Cloison (Classification ARCHICAD) | Finition int - Plaque de plâtre (2), Isolation - Laine de roche | Non défini | 0.04 | 840 | 160 | 23.4 (MJ/kg) | 1.73 (kgCO₂/kg) | Isolation - Laine de roche | no | 1.004 | 2.5 | 0.000793 | 2.30875 | 0.40139 | 0.165627 | 0.0294749 | Material Properties - Component 3, Finition int - Plaque de plâtre, ThermalConductivity: 0.8; Component 3, Finition int - Plaque de plâtre, SpecificHeatCapacity: 1000 J/kg/K; Component 3, Finition int - Plaque de plâtre, MassDensity: 1600 kg/m3; Component 3, Finition int - Plaque de plâtre, Embodied Energy: 1.45 (MJ/kg); Component 3, Finition int - Plaque de plâtre, Embodied Carbon: 0.22 (kgCO₂/kg); Component 3, Finition int - Plaque de plâtre, Name: Finition int - Plaque de plâtre; Component 3, Finition int - Plaque de plâtre, Participates in Collision Detection: no; Component 3: 2 with these values
Cloison Placostil 72/48 | R+2 | Mur (Classification ARCHICAD); Cloison (Classification ARCHICAD) | Finition int - Plaque de plâtre (2), Isolation - Laine de roche | Non défini | 0.04 | 840 | 160 | 23.4 (MJ/kg) | 1.73 (kgCO₂/kg) | Isolation - Laine de roche | no | 1.459 | 2.5 | 0.040002 | 3.5875 | 1.6947 | 0.268355 | 0.128288 | Material Properties - Component 3, Finition int - Plaque de plâtre, ThermalConductivity: 0.8; Component 3, Finition int - Plaque de plâtre, SpecificHeatCapacity: 1000 J/kg/K; Component 3, Finition int - Plaque de plâtre, MassDensity: 1600 kg/m3; Component 3, Finition int - Plaque de plâtre, Embodied Energy: 1.45 (MJ/kg); Component 3, Finition int - Plaque de plâtre, Embodied Carbon: 0.22 (kgCO₂/kg); Component 3, Finition int - Plaque de plâtre, Name: Finition int - Plaque de plâtre; Component 3, Finition int - Plaque de plâtre, Participates in Collision Detection: no; Component 3: 2 with these values
Cloison Placostil 72/48 | R+2 | Mur (Classification ARCHICAD); Cloison (Classification ARCHICAD) | Finition int - Plaque de plâtre (2), Isolation - Laine de roche | Non défini | 0.04 | 840 | 160 | 23.4 (MJ/kg) | 1.73 (kgCO₂/kg) | Isolation - Laine de roche | no | 1.16596 | 2.5 | 0.0111335 | 3.11616 | 0.746036 | 0.238936 | 0.0632989 | Material Properties - Component 3, Finition int - Plaque de plâtre, ThermalConductivity: 0.8; Component 3, Finition int - Plaque de plâtre, SpecificHeatCapacity: 1000 J/kg/K; Component 3, Finition int - Plaque de plâtre, MassDensity: 1600 kg/m3; Component 3, Finition int - Plaque de plâtre, Embodied Energy: 1.45 (MJ/kg); Component 3, Finition int - Plaque de plâtre, Embodied Carbon: 0.22 (kgCO₂/kg); Component 3, Finition int - Plaque de plâtre, Name: Finition int - Plaque de plâtre; Component 3, Finition int - Plaque de plâtre, Participates in Collision Detection: no; Component 3: 2 with these values
Cloison Placostil 72/48 | R+2 | Mur (Classification ARCHICAD); Cloison (Classification ARCHICAD) | Finition int - Plaque de plâtre (2), Isolation - Laine de roche | Non défini | 0.04 | 840 | 160 | 23.4 (MJ/kg) | 1.73 (kgCO₂/kg) | Isolation - Laine de roche | no | 1.63 | 2.5 | 0.025034 | 4.0425 | 1.3801 | 0.299385 | 0.102367 | Material Properties - Component 3, Finition int - Plaque de plâtre, ThermalConductivity: 0.8; Component 3, Finition int - Plaque de plâtre, SpecificHeatCapacity: 1000 J/kg/K; Component 3, Finition int - Plaque de plâtre, MassDensity: 1600 kg/m3; Component 3, Finition int - Plaque de plâtre, Embodied Energy: 1.45 (MJ/kg); Component 3, Finition int - Plaque de plâtre, Embodied Carbon: 0.22 (kgCO₂/kg); Component 3, Finition int - Plaque de plâtre, Name: Finition int - Plaque de plâtre; Component 3, Finition int - Plaque de plâtre, Participates in Collision Detection: no; Component 3: 2 with these values
Cloison Placostil 72/48 | R+3 | Mur (Classification ARCHICAD); Cloison (Classification ARCHICAD) | Finition int - Plaque de plâtre (2), Isolation - Laine de roche | Non défini | 0.04 | 840 | 160 | 23.4 (MJ/kg) | 1.73 (kgCO₂/kg) | Isolation - Laine de roche | no | 1.69821 | 2.5 | 0.0596488 | 4.20178 | 2.30898 | 0.317472 | 0.177405 | 0.8 | 1000 | 1600 | 1.45 (MJ/kg) | 0.22 (kgCO₂/kg) | Finition int - Plaque de plâtre | no | Material Properties - Component 1: 2 with these values
Cloison Placostil 72/48 | R+3 | Mur (Classification ARCHICAD); Cloison (Classification ARCHICAD) | Finition int - Plaque de plâtre (2), Isolation - Laine de roche | Non défini | 0.04 | 840 | 160 | 23.4 (MJ/kg) | 1.73 (kgCO₂/kg) | Isolation - Laine de roche | no | 2.70826 | 2.5 | 0.198466 | 6.63441 | 6.63441 | 0.496166 | 0.496166 | 0.8 | 1000 | 1600 | 1.45 (MJ/kg) | 0.22 (kgCO₂/kg) | Finition int - Plaque de plâtre | no | Material Properties - Component 1: 2 with these values
Cloison Placostil 72/48 | R+3 | Mur (Classification ARCHICAD); Cloison (Classification ARCHICAD) | Finition int - Plaque de plâtre (2), Isolation - Laine de roche | Non défini | 0.04 | 840 | 160 | 23.4 (MJ/kg) | 1.73 (kgCO₂/kg) | Isolation - Laine de roche | no | 0.361 | 2.5 | 0.014898 | 0.4725 | 0.4725 | 0.037245 | 0.037245 | 0.8 | 1000 | 1600 | 1.45 (MJ/kg) | 0.22 (kgCO₂/kg) | Finition int - Plaque de plâtre | no | Material Properties - Component 1: 2 with these values
Cloison Placostil 72/48 | R+3 | Mur (Classification ARCHICAD); Cloison (Classification ARCHICAD) | Finition int - Plaque de plâtre (2), Isolation - Laine de roche | Non défini | 0.04 | 840 | 160 | 23.4 (MJ/kg) | 1.73 (kgCO₂/kg) | Isolation - Laine de roche | no | 2.748 | 2.5 | 0.199462 | 6.7175 | 6.7175 | 0.498655 | 0.498655 | 0.8 | 1000 | 1600 | 1.45 (MJ/kg) | 0.22 (kgCO₂/kg) | Finition int - Plaque de plâtre | no | Material Properties - Component 1: 2 with these values
Cloison Placostil 72/48 | R+3 | Mur (Classification ARCHICAD); Cloison (Classification ARCHICAD) | Finition int - Plaque de plâtre (2), Isolation - Laine de roche | Non défini | 0.04 | 840 | 160 | 23.4 (MJ/kg) | 1.73 (kgCO₂/kg) | Isolation - Laine de roche | no | 2.42331 | 2.5 | 0.114003 | 6.03077 | 4.13797 | 0.453357 | 0.31329 | 0.8 | 1000 | 1600 | 1.45 (MJ/kg) | 0.22 (kgCO₂/kg) | Finition int - Plaque de plâtre | no | Material Properties - Component 1: 2 with these values
Cloison Placostil 72/48 | R+3 | Mur (Classification ARCHICAD); Cloison (Classification ARCHICAD) | Finition int - Plaque de plâtre (2), Isolation - Laine de roche | Non défini | 0.04 | 840 | 160 | 23.4 (MJ/kg) | 1.73 (kgCO₂/kg) | Isolation - Laine de roche | no | 1.004 | 2.49 | 0.000793 | 2.29951 | 0.392155 | 0.164965 | 0.0288123 | Material Properties - Component 3, Finition int - Plaque de plâtre, ThermalConductivity: 0.8; Component 3, Finition int - Plaque de plâtre, SpecificHeatCapacity: 1000 J/kg/K; Component 3, Finition int - Plaque de plâtre, MassDensity: 1600 kg/m3; Component 3, Finition int - Plaque de plâtre, Embodied Energy: 1.45 (MJ/kg); Component 3, Finition int - Plaque de plâtre, Embodied Carbon: 0.22 (kgCO₂/kg); Component 3, Finition int - Plaque de plâtre, Name: Finition int - Plaque de plâtre; Component 3, Finition int - Plaque de plâtre, Participates in Collision Detection: no; Component 3: 2 with these values
Cloison Placostil 72/48 | R+3 | Mur (Classification ARCHICAD); Cloison (Classification ARCHICAD) | Finition int - Plaque de plâtre (2), Isolation - Laine de roche | Non défini | 0.04 | 840 | 160 | 23.4 (MJ/kg) | 1.73 (kgCO₂/kg) | Isolation - Laine de roche | no | 2.859 | 2.5 | 0.143602 | 7.0875 | 5.1947 | 0.527355 | 0.387288 | Material Properties - Component 3, Finition int - Plaque de plâtre, ThermalConductivity: 0.8; Component 3, Finition int - Plaque de plâtre, SpecificHeatCapacity: 1000 J/kg/K; Component 3, Finition int - Plaque de plâtre, MassDensity: 1600 kg/m3; Component 3, Finition int - Plaque de plâtre, Embodied Energy: 1.45 (MJ/kg); Component 3, Finition int - Plaque de plâtre, Embodied Carbon: 0.22 (kgCO₂/kg); Component 3, Finition int - Plaque de plâtre, Name: Finition int - Plaque de plâtre; Component 3, Finition int - Plaque de plâtre, Participates in Collision Detection: no; Component 3: 2 with these values
Cloison Placostil 72/48 | R+3 | Mur (Classification ARCHICAD); Cloison (Classification ARCHICAD) | Finition int - Plaque de plâtre (2), Isolation - Laine de roche | Non défini | 0.04 | 840 | 160 | 23.4 (MJ/kg) | 1.73 (kgCO₂/kg) | Isolation - Laine de roche | no | 0.775 | 2.49 | 0.0672359 | 1.83761 | 1.83761 | 0.167417 | 0.167417 | 0.8 | 1000 | 1600 | 1.45 (MJ/kg) | 0.22 (kgCO₂/kg) | Finition int - Plaque de plâtre | no | Material Properties - Component 1: 2 with these values
Cloison Placostil 72/48 | R+3 | Mur (Classification ARCHICAD); Cloison (Classification ARCHICAD) | Finition int - Plaque de plâtre (2), Isolation - Laine de roche | Non défini | 0.04 | 840 | 160 | 23.4 (MJ/kg) | 1.73 (kgCO₂/kg) | Isolation - Laine de roche | no | 4.90595 | 2.5 | 0.370768 | 12.0849 | 12.0849 | 0.926921 | 0.926921 | 0.8 | 1000 | 1600 | 1.45 (MJ/kg) | 0.22 (kgCO₂/kg) | Finition int - Plaque de plâtre | no | Material Properties - Component 1: 2 with these values
Cloison Placostil 72/48 | R+4 | Mur (Classification ARCHICAD); Cloison (Classification ARCHICAD) | Finition int - Plaque de plâtre (2), Isolation - Laine de roche | Non défini | 0.04 | 840 | 160 | 23.4 (MJ/kg) | 1.73 (kgCO₂/kg) | Isolation - Laine de roche | no | 1.78884 | 2.48 | 0.0675993 | 4.41572 | 2.54112 | 0.334649 | 0.195929 | Material Properties - Component 3, Finition int - Plaque de plâtre, ThermalConductivity: 0.8; Component 3, Finition int - Plaque de plâtre, SpecificHeatCapacity: 1000 J/kg/K; Component 3, Finition int - Plaque de plâtre, MassDensity: 1600 kg/m3; Component 3, Finition int - Plaque de plâtre, Embodied Energy: 1.45 (MJ/kg); Component 3, Finition int - Plaque de plâtre, Embodied Carbon: 0.22 (kgCO₂/kg); Component 3, Finition int - Plaque de plâtre, Name: Finition int - Plaque de plâtre; Component 3, Finition int - Plaque de plâtre, Participates in Collision Detection: no; Component 3: 2 with these values
Cloison Placostil 72/48 | R+4 | Mur (Classification ARCHICAD); Cloison (Classification ARCHICAD) | Finition int - Plaque de plâtre (2), Isolation - Laine de roche | Non défini | 0.04 | 840 | 160 | 23.4 (MJ/kg) | 1.73 (kgCO₂/kg) | Isolation - Laine de roche | no | 5.15681 | 2.48 | 0.312943 | 12.7132 | 10.8386 | 0.943102 | 0.804381 | Material Properties - Component 3, Finition int - Plaque de plâtre, ThermalConductivity: 0.8; Component 3, Finition int - Plaque de plâtre, SpecificHeatCapacity: 1000 J/kg/K; Component 3, Finition int - Plaque de plâtre, MassDensity: 1600 kg/m3; Component 3, Finition int - Plaque de plâtre, Embodied Energy: 1.45 (MJ/kg); Component 3, Finition int - Plaque de plâtre, Embodied Carbon: 0.22 (kgCO₂/kg); Component 3, Finition int - Plaque de plâtre, Name: Finition int - Plaque de plâtre; Component 3, Finition int - Plaque de plâtre, Participates in Collision Detection: no; Component 3: 2 with these values
Cloison Placostil 72/48 | Rez-de-chaussée | Cloison (Classification ARCHICAD) | Isolation - Laine de roche, Finition int - Plaque de plâtre | Non défini | 0.04 | 840 | 160 | 23.4 (MJ/kg) | 1.73 (kgCO₂/kg) | Isolation - Laine de roche | no | 1.16596 | 2.5 | 0.0111335 | 3.11616 | 0.267454 | 0.238936 | 0.0278338 | 0.8 | 1000 | 1600 | 1.45 (MJ/kg) | 0.22 (kgCO₂/kg) | Finition int - Plaque de plâtre | no
Cloison Placostil 72/48 | Rez-de-chaussée | Cloison (Classification ARCHICAD) | Finition int - Plaque de plâtre (2), Isolation - Laine de roche | Non défini | 0.04 | 840 | 160 | 23.4 (MJ/kg) | 1.73 (kgCO₂/kg) | Isolation - Laine de roche | no | 1.459 | 2.5 | 0.040002 | 3.5875 | 1.6947 | 0.268355 | 0.128288 | Material Properties - Component 3, Finition int - Plaque de plâtre, ThermalConductivity: 0.8; Component 3, Finition int - Plaque de plâtre, SpecificHeatCapacity: 1000 J/kg/K; Component 3, Finition int - Plaque de plâtre, MassDensity: 1600 kg/m3; Component 3, Finition int - Plaque de plâtre, Embodied Energy: 1.45 (MJ/kg); Component 3, Finition int - Plaque de plâtre, Embodied Carbon: 0.22 (kgCO₂/kg); Component 3, Finition int - Plaque de plâtre, Name: Finition int - Plaque de plâtre; Component 3, Finition int - Plaque de plâtre, Participates in Collision Detection: no; Component 3: 2 with these values
Cloison Placostil 72/48 | Rez-de-chaussée | Cloison (Classification ARCHICAD) | Isolation - Laine de roche | Non défini |  |  |  |  |  |  |  | 1.41733 | 2.5 | 0.00122594 | 3.36318 | 0 | 0.260642 | 0.00306484 | Material Properties - Isolation - Laine de roche, ThermalConductivity: 0.04; Isolation - Laine de roche, SpecificHeatCapacity: 840 J/kg/K; Isolation - Laine de roche, MassDensity: 160 kg/m3; Isolation - Laine de roche, Embodied Energy: 23.4 (MJ/kg); Isolation - Laine de roche, Embodied Carbon: 1.73 (kgCO₂/kg); Isolation - Laine de roche, Name: Isolation - Laine de roche; Isolation - Laine de roche, Participates in Collision Detection: no
Cloison Placostil 72/48 | Rez-de-chaussée | Cloison (Classification ARCHICAD) | Finition int - Plaque de plâtre (2), Isolation - Laine de roche | Non défini | 0.04 | 840 | 160 | 23.4 (MJ/kg) | 1.73 (kgCO₂/kg) | Isolation - Laine de roche | no | 2.31178 | 2.5 | 0.0769956 | 5.65042 | 2.98802 | 0.428449 | 0.231431 | 0.8 | 1000 | 1600 | 1.45 (MJ/kg) | 0.22 (kgCO₂/kg) | Finition int - Plaque de plâtre | no | Material Properties - Component 1: 2 with these values
Cloison Placostil 72/48 | Rez-de-chaussée | Cloison (Classification ARCHICAD) | Finition int - Plaque de plâtre (2), Isolation - Laine de roche | Non défini | 0.04 | 840 | 160 | 23.4 (MJ/kg) | 1.73 (kgCO₂/kg) | Isolation - Laine de roche | no | 1.474 | 2.5 | 0.107599 | 3.48046 | 3.48046 | 0.267439 | 0.267439 | 0.8 | 1000 | 1600 | 1.45 (MJ/kg) | 0.22 (kgCO₂/kg) | Finition int - Plaque de plâtre | no | Material Properties - Component 1: 2 with these values
Cloison Placostil 72/48 | Rez-de-chaussée | Cloison (Classification ARCHICAD) | Finition int - Plaque de plâtre (2), Isolation - Laine de roche | Non défini | 0.04 | 840 | 160 | 23.4 (MJ/kg) | 1.73 (kgCO₂/kg) | Isolation - Laine de roche | no | 2.4474 | 2.5 | 0.112447 | 5.97701 | 4.08421 | 0.447771 | 0.307703 | 0.8 | 1000 | 1600 | 1.45 (MJ/kg) | 0.22 (kgCO₂/kg) | Finition int - Plaque de plâtre | no | Material Properties - Component 1: 2 with these values
Cloison Placostil 72/48 | Rez-de-chaussée | Cloison (Classification ARCHICAD) | Finition int - Plaque de plâtre (2), Isolation - Laine de roche | Non défini | 0.04 | 840 | 160 | 23.4 (MJ/kg) | 1.73 (kgCO₂/kg) | Isolation - Laine de roche | no | 2.565 | 2.5 | 0.122543 | 6.08945 | 4.19665 | 0.469006 | 0.328938 | 0.8 | 1000 | 1600 | 1.45 (MJ/kg) | 0.22 (kgCO₂/kg) | Finition int - Plaque de plâtre | no | Material Properties - Component 1: 2 with these values
Cloison Placostil 72/48 | Rez-de-chaussée | Cloison (Classification ARCHICAD) | Finition int - Plaque de plâtre (2), Isolation - Laine de roche | Non défini | 0.04 | 840 | 160 | 23.4 (MJ/kg) | 1.73 (kgCO₂/kg) | Isolation - Laine de roche | no | 1.511 | 2.5 | 0.109245 | 3.64125 | 3.64125 | 0.273113 | 0.273113 | Material Properties - Component 3, Finition int - Plaque de plâtre, ThermalConductivity: 0.8; Component 3, Finition int - Plaque de plâtre, SpecificHeatCapacity: 1000 J/kg/K; Component 3, Finition int - Plaque de plâtre, MassDensity: 1600 kg/m3; Component 3, Finition int - Plaque de plâtre, Embodied Energy: 1.45 (MJ/kg); Component 3, Finition int - Plaque de plâtre, Embodied Carbon: 0.22 (kgCO₂/kg); Component 3, Finition int - Plaque de plâtre, Name: Finition int - Plaque de plâtre; Component 3, Finition int - Plaque de plâtre, Participates in Collision Detection: no; Component 3: 2 with these values
Cloison Placostil 72/48 | Rez-de-chaussée | Cloison (Classification ARCHICAD) | Isolation - Laine de roche, Finition int - Plaque de plâtre | Non défini | 0.04 | 840 | 160 | 23.4 (MJ/kg) | 1.73 (kgCO₂/kg) | Isolation - Laine de roche | no | 1.004 | 2.5 | 0.000793 | 2.30875 | 0.01625 | 0.165627 | 0.0019825 | 0.8 | 1000 | 1600 | 1.45 (MJ/kg) | 0.22 (kgCO₂/kg) | Finition int - Plaque de plâtre | no
Cloison Placostil 72/48 | Rez-de-chaussée | Cloison (Classification ARCHICAD) | Finition int - Plaque de plâtre (2), Isolation - Laine de roche | Non défini | 0.04 | 840 | 160 | 23.4 (MJ/kg) | 1.73 (kgCO₂/kg) | Isolation - Laine de roche | no | 5.43031 | 2.5 | 0.265915 | 13.4558 | 9.67018 | 1.00149 | 0.721353 | 0.8 | 1000 | 1600 | 1.45 (MJ/kg) | 0.22 (kgCO₂/kg) | Finition int - Plaque de plâtre | no | Material Properties - Component 1: 2 with these values
Cloison Placostil 72/48 | Rez-de-chaussée | Cloison (Classification ARCHICAD) | Finition int - Plaque de plâtre (2), Isolation - Laine de roche | Non défini | 0.04 | 840 | 160 | 23.4 (MJ/kg) | 1.73 (kgCO₂/kg) | Isolation - Laine de roche | no | 1.574 | 2.5 | 0.048512 | 3.875 | 1.9822 | 0.28963 | 0.149563 | Material Properties - Component 3, Finition int - Plaque de plâtre, ThermalConductivity: 0.8; Component 3, Finition int - Plaque de plâtre, SpecificHeatCapacity: 1000 J/kg/K; Component 3, Finition int - Plaque de plâtre, MassDensity: 1600 kg/m3; Component 3, Finition int - Plaque de plâtre, Embodied Energy: 1.45 (MJ/kg); Component 3, Finition int - Plaque de plâtre, Embodied Carbon: 0.22 (kgCO₂/kg); Component 3, Finition int - Plaque de plâtre, Name: Finition int - Plaque de plâtre; Component 3, Finition int - Plaque de plâtre, Participates in Collision Detection: no; Component 3: 2 with these values
Cloison Placostil 72/48 | Rez-de-chaussée | Cloison (Classification ARCHICAD) | Finition int - Plaque de plâtre (2), Isolation - Laine de roche | Non défini | 0.04 | 840 | 160 | 23.4 (MJ/kg) | 1.73 (kgCO₂/kg) | Isolation - Laine de roche | no | 1.274 | 2.5 | 0.028954 | 3.1575 | 1.2647 | 0.240735 | 0.100668 | Material Properties - Component 3, Finition int - Plaque de plâtre, ThermalConductivity: 0.8; Component 3, Finition int - Plaque de plâtre, SpecificHeatCapacity: 1000 J/kg/K; Component 3, Finition int - Plaque de plâtre, MassDensity: 1600 kg/m3; Component 3, Finition int - Plaque de plâtre, Embodied Energy: 1.45 (MJ/kg); Component 3, Finition int - Plaque de plâtre, Embodied Carbon: 0.22 (kgCO₂/kg); Component 3, Finition int - Plaque de plâtre, Name: Finition int - Plaque de plâtre; Component 3, Finition int - Plaque de plâtre, Participates in Collision Detection: no; Component 3: 2 with these values
Cloison Placostil 72/48 | Rez-de-chaussée | Cloison (Classification ARCHICAD) | Finition int - Plaque de plâtre, Isolation - Laine de roche | Non défini | 0.04 | 840 | 160 | 23.4 (MJ/kg) | 1.73 (kgCO₂/kg) | Isolation - Laine de roche | no | 2.01507 | 2.5 | 0.004927 | 4.72471 | 0.07625 | 0.370545 | 0.0123175 | 0.8 | 1000 | 1600 | 1.45 (MJ/kg) | 0.22 (kgCO₂/kg) | Finition int - Plaque de plâtre | no
Cloison Placostil 72/48 | Rez-de-chaussée | Cloison (Classification ARCHICAD) | Finition int - Plaque de plâtre (2), Isolation - Laine de roche | Non défini | 0.04 | 840 | 160 | 23.4 (MJ/kg) | 1.73 (kgCO₂/kg) | Isolation - Laine de roche | no | 2.087 | 2.5 | 0.088419 | 5.17375 | 3.28095 | 0.389398 | 0.24933 | 0.8 | 1000 | 1600 | 1.45 (MJ/kg) | 0.22 (kgCO₂/kg) | Finition int - Plaque de plâtre | no | Material Properties - Component 1: 2 with these values
Cloison Placostil 72/48 | Rez-de-chaussée | Cloison (Classification ARCHICAD) | Finition int - Plaque de plâtre (2), Isolation - Laine de roche | Non défini | 0.04 | 840 | 160 | 23.4 (MJ/kg) | 1.73 (kgCO₂/kg) | Isolation - Laine de roche | no | 1.4209 | 2.5 | 0.0371097 | 3.536 | 1.6432 | 0.261124 | 0.121057 | 0.8 | 1000 | 1600 | 1.45 (MJ/kg) | 0.22 (kgCO₂/kg) | Finition int - Plaque de plâtre | no | Material Properties - Component 1: 2 with these values
Cloison Placostil 72/48 | Rez-de-chaussée | Cloison (Classification ARCHICAD) | Finition int - Plaque de plâtre (2), Isolation - Laine de roche | Non défini | 0.04 | 840 | 160 | 23.4 (MJ/kg) | 1.73 (kgCO₂/kg) | Isolation - Laine de roche | no | 1.189 | 2.5 | 0.08861 | 2.9725 | 2.9725 | 0.221525 | 0.221525 | 0.8 | 1000 | 1600 | 1.45 (MJ/kg) | 0.22 (kgCO₂/kg) | Finition int - Plaque de plâtre | no | Material Properties - Component 1: 2 with these values
Cloison Placostil 72/48 | R+1 | Mur (Classification ARCHICAD); Cloison (Classification ARCHICAD) | Finition int - Plaque de plâtre (2), Isolation - Laine de roche | Non défini | 0.04 | 840 | 160 | 23.4 (MJ/kg) | 1.73 (kgCO₂/kg) | Isolation - Laine de roche | no | 0.637 | 2.5 | 0.049707 | 1.60875 | 1.60875 | 0.124268 | 0.124268 | Material Properties - Component 3, Finition int - Plaque de plâtre, ThermalConductivity: 0.8; Component 3, Finition int - Plaque de plâtre, SpecificHeatCapacity: 1000 J/kg/K; Component 3, Finition int - Plaque de plâtre, MassDensity: 1600 kg/m3; Component 3, Finition int - Plaque de plâtre, Embodied Energy: 1.45 (MJ/kg); Component 3, Finition int - Plaque de plâtre, Embodied Carbon: 0.22 (kgCO₂/kg); Component 3, Finition int - Plaque de plâtre, Name: Finition int - Plaque de plâtre; Component 3, Finition int - Plaque de plâtre, Participates in Collision Detection: no; Component 3: 2 with these values
Cloison Placostil 72/48 | R+1 | Mur (Classification ARCHICAD); Cloison (Classification ARCHICAD) | Finition int - Plaque de plâtre (2), Isolation - Laine de roche | Non défini | 0.04 | 840 | 160 | 23.4 (MJ/kg) | 1.73 (kgCO₂/kg) | Isolation - Laine de roche | no | 0.976834 | 2.5 | 0.00424871 | 2.42583 | 0.533035 | 0.178972 | 0.0389046 | Material Properties - Component 3, Finition int - Plaque de plâtre, ThermalConductivity: 0.8; Component 3, Finition int - Plaque de plâtre, SpecificHeatCapacity: 1000 J/kg/K; Component 3, Finition int - Plaque de plâtre, MassDensity: 1600 kg/m3; Component 3, Finition int - Plaque de plâtre, Embodied Energy: 1.45 (MJ/kg); Component 3, Finition int - Plaque de plâtre, Embodied Carbon: 0.22 (kgCO₂/kg); Component 3, Finition int - Plaque de plâtre, Name: Finition int - Plaque de plâtre; Component 3, Finition int - Plaque de plâtre, Participates in Collision Detection: no; Component 3: 2 with these values
Cloison Placostil 72/48 | R+1 | Mur (Classification ARCHICAD); Cloison (Classification ARCHICAD) | Finition int - Plaque de plâtre (2), Isolation - Laine de roche | Non défini | 0.04 | 840 | 160 | 23.4 (MJ/kg) | 1.73 (kgCO₂/kg) | Isolation - Laine de roche | no | 0.629589 | 2.5 | 0.0479536 | 1.58897 | 1.58897 | 0.119624 | 0.119624 | 0.8 | 1000 | 1600 | 1.45 (MJ/kg) | 0.22 (kgCO₂/kg) | Finition int - Plaque de plâtre | no | Material Properties - Component 1: 2 with these values
Cloison Placostil 72/48 | R+1 | Mur (Classification ARCHICAD); Cloison (Classification ARCHICAD) | Isolation - Laine de roche, Finition int - Plaque de plâtre | Non défini | 0.04 | 840 | 160 | 23.4 (MJ/kg) | 1.73 (kgCO₂/kg) | Isolation - Laine de roche | no | 0.976834 | 2.5 | 0.001431 | 2.13473 | 0.0561 | 0.171403 | 0.0033786 | 0.8 | 1000 | 1600 | 1.45 (MJ/kg) | 0.22 (kgCO₂/kg) | Finition int - Plaque de plâtre | no
Cloison Placostil 72/48 | R+1 | Mur (Classification ARCHICAD); Cloison (Classification ARCHICAD) | Finition int - Plaque de plâtre (2), Isolation - Laine de roche | Non défini | 0.04 | 840 | 160 | 23.4 (MJ/kg) | 1.73 (kgCO₂/kg) | Isolation - Laine de roche | no | 2.06348 | 2.5 | 0.151186 | 4.9737 | 4.9737 | 0.377966 | 0.377966 | Material Properties - Component 3, Finition int - Plaque de plâtre, ThermalConductivity: 0.8; Component 3, Finition int - Plaque de plâtre, SpecificHeatCapacity: 1000 J/kg/K; Component 3, Finition int - Plaque de plâtre, MassDensity: 1600 kg/m3; Component 3, Finition int - Plaque de plâtre, Embodied Energy: 1.45 (MJ/kg); Component 3, Finition int - Plaque de plâtre, Embodied Carbon: 0.22 (kgCO₂/kg); Component 3, Finition int - Plaque de plâtre, Name: Finition int - Plaque de plâtre; Component 3, Finition int - Plaque de plâtre, Participates in Collision Detection: no; Component 3: 2 with these values
Cloison Placostil 72/48 | R+1 | Mur (Classification ARCHICAD); Cloison (Classification ARCHICAD) | Finition int - Plaque de plâtre (2), Isolation - Laine de roche | Non défini | 0.04 | 840 | 160 | 23.4 (MJ/kg) | 1.73 (kgCO₂/kg) | Isolation - Laine de roche | no | 1.03462 | 2.5 | 0.00657951 | 2.55404 | 0.661238 | 0.184799 | 0.0447316 | Material Properties - Component 3, Finition int - Plaque de plâtre, ThermalConductivity: 0.8; Component 3, Finition int - Plaque de plâtre, SpecificHeatCapacity: 1000 J/kg/K; Component 3, Finition int - Plaque de plâtre, MassDensity: 1600 kg/m3; Component 3, Finition int - Plaque de plâtre, Embodied Energy: 1.45 (MJ/kg); Component 3, Finition int - Plaque de plâtre, Embodied Carbon: 0.22 (kgCO₂/kg); Component 3, Finition int - Plaque de plâtre, Name: Finition int - Plaque de plâtre; Component 3, Finition int - Plaque de plâtre, Participates in Collision Detection: no; Component 3: 2 with these values
Cloison Placostil 72/48 | R+1 | Mur (Classification ARCHICAD); Cloison (Classification ARCHICAD) | Finition int - Plaque de plâtre (2), Isolation - Laine de roche | Non défini | 0.04 | 840 | 160 | 23.4 (MJ/kg) | 1.73 (kgCO₂/kg) | Isolation - Laine de roche | no | 0.901055 | 2.5 | 0.0681556 | 2.14687 | 2.14687 | 0.169111 | 0.169111 | Material Properties - Component 3, Finition int - Plaque de plâtre, ThermalConductivity: 0.8; Component 3, Finition int - Plaque de plâtre, SpecificHeatCapacity: 1000 J/kg/K; Component 3, Finition int - Plaque de plâtre, MassDensity: 1600 kg/m3; Component 3, Finition int - Plaque de plâtre, Embodied Energy: 1.45 (MJ/kg); Component 3, Finition int - Plaque de plâtre, Embodied Carbon: 0.22 (kgCO₂/kg); Component 3, Finition int - Plaque de plâtre, Name: Finition int - Plaque de plâtre; Component 3, Finition int - Plaque de plâtre, Participates in Collision Detection: no; Component 3: 2 with these values
Cloison Placostil 72/48 | R+1 | Mur (Classification ARCHICAD); Cloison (Classification ARCHICAD) | Finition int - Plaque de plâtre (2), Isolation - Laine de roche | Non défini | 0.04 | 840 | 160 | 23.4 (MJ/kg) | 1.73 (kgCO₂/kg) | Isolation - Laine de roche | no | 1.437 | 2.5 | 0.040319 | 3.60752 | 1.71472 | 0.26912 | 0.129052 | 0.8 | 1000 | 1600 | 1.45 (MJ/kg) | 0.22 (kgCO₂/kg) | Finition int - Plaque de plâtre | no | Material Properties - Component 1: 2 with these values
Cloison Placostil 72/48 | R+1 | Mur (Classification ARCHICAD); Cloison (Classification ARCHICAD) | Finition int - Plaque de plâtre (2), Isolation - Laine de roche | Non défini | 0.04 | 840 | 160 | 23.4 (MJ/kg) | 1.73 (kgCO₂/kg) | Isolation - Laine de roche | no | 0.847474 | 2.5 | 0.0626401 | 2.10243 | 2.10243 | 0.1566 | 0.1566 | 0.8 | 1000 | 1600 | 1.45 (MJ/kg) | 0.22 (kgCO₂/kg) | Finition int - Plaque de plâtre | no | Material Properties - Component 1: 2 with these values
Cloison Placostil 72/48 | R+1 | Mur (Classification ARCHICAD); Cloison (Classification ARCHICAD) | Finition int - Plaque de plâtre (2), Isolation - Laine de roche | Non défini | 0.04 | 840 | 160 | 23.4 (MJ/kg) | 1.73 (kgCO₂/kg) | Isolation - Laine de roche | no | 0.621367 | 2.5 | 0.0459081 | 1.53717 | 1.53717 | 0.11477 | 0.11477 | Material Properties - Component 3, Finition int - Plaque de plâtre, ThermalConductivity: 0.8; Component 3, Finition int - Plaque de plâtre, SpecificHeatCapacity: 1000 J/kg/K; Component 3, Finition int - Plaque de plâtre, MassDensity: 1600 kg/m3; Component 3, Finition int - Plaque de plâtre, Embodied Energy: 1.45 (MJ/kg); Component 3, Finition int - Plaque de plâtre, Embodied Carbon: 0.22 (kgCO₂/kg); Component 3, Finition int - Plaque de plâtre, Name: Finition int - Plaque de plâtre; Component 3, Finition int - Plaque de plâtre, Participates in Collision Detection: no; Component 3: 2 with these values
Cloison Placostil 72/48 | R+1 | Mur (Classification ARCHICAD); Cloison (Classification ARCHICAD) | Finition int - Plaque de plâtre (2), Isolation - Laine de roche | Non défini | 0.04 | 840 | 160 | 23.4 (MJ/kg) | 1.73 (kgCO₂/kg) | Isolation - Laine de roche | no | 2.67485 | 2.5 | 0.191976 | 6.41838 | 6.41838 | 0.47994 | 0.47994 | Material Properties - Component 3, Finition int - Plaque de plâtre, ThermalConductivity: 0.8; Component 3, Finition int - Plaque de plâtre, SpecificHeatCapacity: 1000 J/kg/K; Component 3, Finition int - Plaque de plâtre, MassDensity: 1600 kg/m3; Component 3, Finition int - Plaque de plâtre, Embodied Energy: 1.45 (MJ/kg); Component 3, Finition int - Plaque de plâtre, Embodied Carbon: 0.22 (kgCO₂/kg); Component 3, Finition int - Plaque de plâtre, Name: Finition int - Plaque de plâtre; Component 3, Finition int - Plaque de plâtre, Participates in Collision Detection: no; Component 3: 2 with these values
Cloison Placostil 72/48 | R+1 | Mur (Classification ARCHICAD); Cloison (Classification ARCHICAD) | Finition int - Plaque de plâtre (2), Isolation - Laine de roche | Non défini | 0.04 | 840 | 160 | 23.4 (MJ/kg) | 1.73 (kgCO₂/kg) | Isolation - Laine de roche | no | 3.842 | 2.5 | 0.21572 | 9.485 | 7.5922 | 0.70765 | 0.567583 | Material Properties - Component 3, Finition int - Plaque de plâtre, ThermalConductivity: 0.8; Component 3, Finition int - Plaque de plâtre, SpecificHeatCapacity: 1000 J/kg/K; Component 3, Finition int - Plaque de plâtre, MassDensity: 1600 kg/m3; Component 3, Finition int - Plaque de plâtre, Embodied Energy: 1.45 (MJ/kg); Component 3, Finition int - Plaque de plâtre, Embodied Carbon: 0.22 (kgCO₂/kg); Component 3, Finition int - Plaque de plâtre, Name: Finition int - Plaque de plâtre; Component 3, Finition int - Plaque de plâtre, Participates in Collision Detection: no; Component 3: 2 with these values
Cloison Placostil 72/48 | R+1 | Mur (Classification ARCHICAD); Cloison (Classification ARCHICAD) | Finition int - Plaque de plâtre (2), Isolation - Laine de roche | Non défini | 0.04 | 840 | 160 | 23.4 (MJ/kg) | 1.73 (kgCO₂/kg) | Isolation - Laine de roche | no | 0.637 | 2.5 | 0.049083 | 1.60875 | 1.60875 | 0.122707 | 0.122707 | 0.8 | 1000 | 1600 | 1.45 (MJ/kg) | 0.22 (kgCO₂/kg) | Finition int - Plaque de plâtre | no | Material Properties - Component 1: 2 with these values
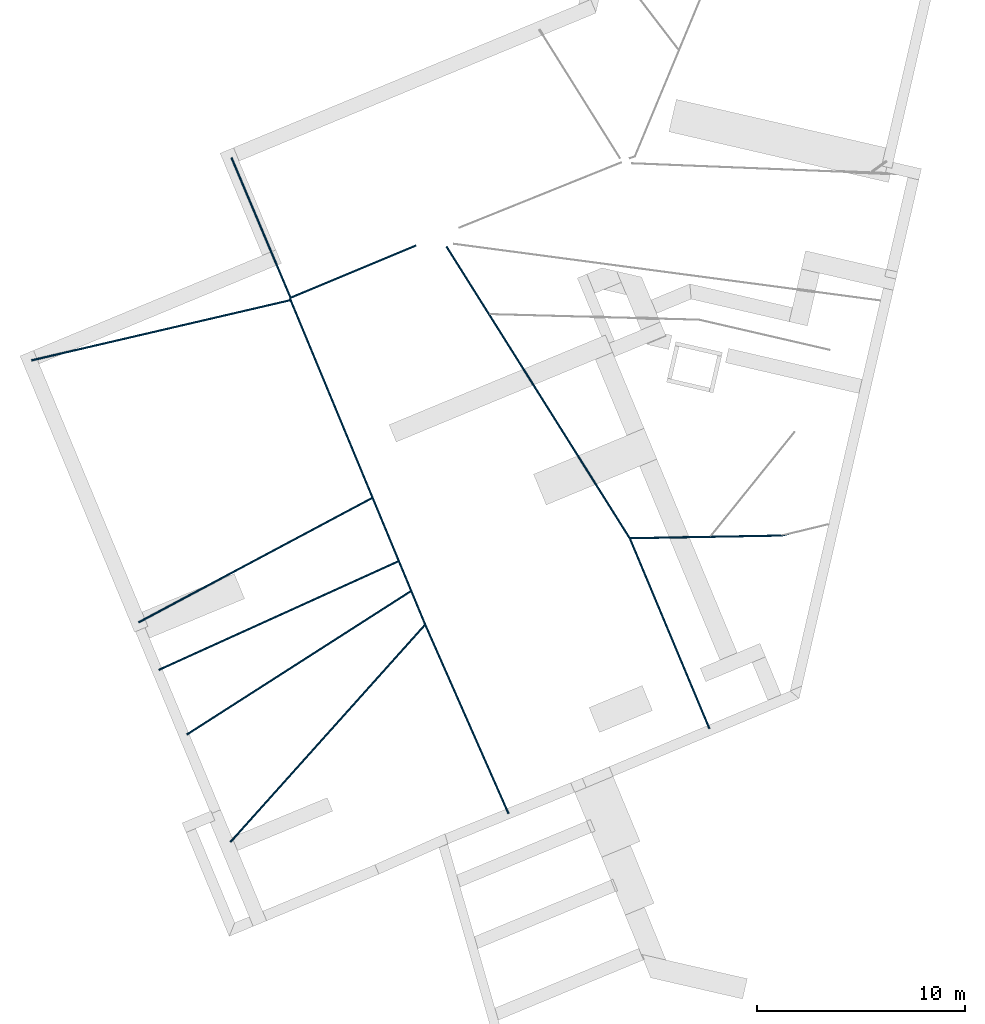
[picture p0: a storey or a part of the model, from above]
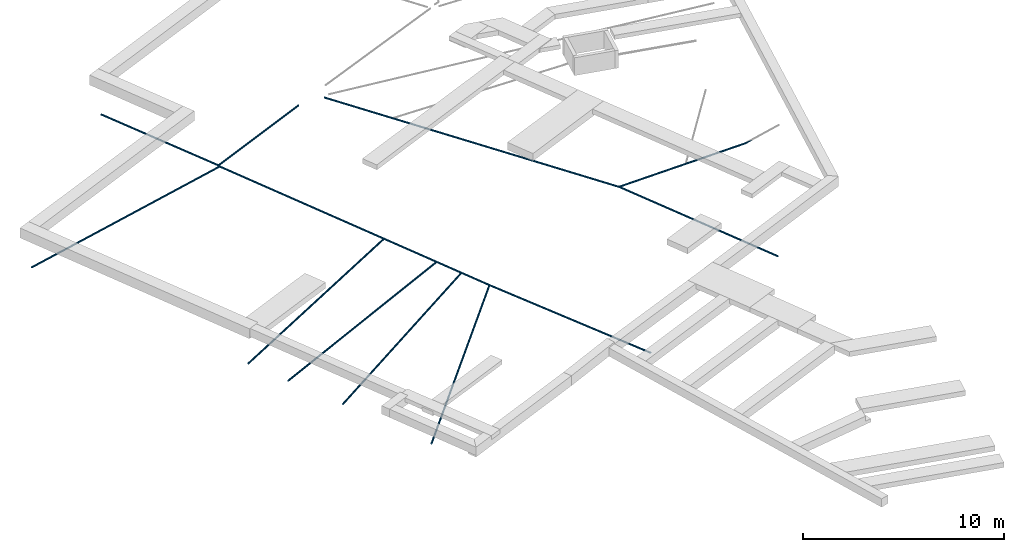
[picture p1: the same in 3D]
Properties of the parts of a building model (IFC2X3), part 10 of 22

# IfcWall: 3 - Cloison 72mm Placostil 74 (508)
Name | In | Classification | Material | AcousticRating | Component 2, Isolation - Laine de roche, ThermalConductivity | Component 2, Isolation - Laine de roche, SpecificHeatCapacity (J/kg/K) | Component 2, Isolation - Laine de roche, MassDensity (kg/m3) | Component 2, Isolation - Laine de roche, Embodied Energy | Component 2, Isolation - Laine de roche, Embodied Carbon | Component 2, Isolation - Laine de roche, Name | Component 2, Isolation - Laine de roche, Participates in Collision Detection | Length (m) | Height (m) | GrossFootprintArea (m2) = NetFootprintArea (m2) | GrossSideArea (m2) | NetSideArea (m2) | GrossVolume (m3) | NetVolume (m3) | Component 1, Finition int - Plaque de plâtre, ThermalConductivity | Component 1, Finition int - Plaque de plâtre, SpecificHeatCapacity (J/kg/K) | Component 1, Finition int - Plaque de plâtre, MassDensity (kg/m3) | Component 1, Finition int - Plaque de plâtre, Embodied Energy | Component 1, Finition int - Plaque de plâtre, Embodied Carbon | Component 1, Finition int - Plaque de plâtre, Name | Component 1, Finition int - Plaque de plâtre, Participates in Collision Detection
Cloison Placostil 72/48 | R+1 | Mur (Classification ARCHICAD); Cloison (Classification ARCHICAD) | Finition int - Plaque de plâtre (2), Isolation - Laine de roche | Non défini | 0.04 | 840 | 160 | 23.4 (MJ/kg) | 1.73 (kgCO₂/kg) | Isolation - Laine de roche | no | 0.687 | 2.5 | 0.049633 | 1.66625 | 1.66625 | 0.124083 | 0.124083 | 0.8 | 1000 | 1600 | 1.45 (MJ/kg) | 0.22 (kgCO₂/kg) | Finition int - Plaque de plâtre | no | Material Properties - Component 1: 2 with these values
Cloison Placostil 72/48 | R+1 | Mur (Classification ARCHICAD); Cloison (Classification ARCHICAD) | Finition int - Plaque de plâtre (2), Isolation - Laine de roche | Non défini | 0.04 | 840 | 160 | 23.4 (MJ/kg) | 1.73 (kgCO₂/kg) | Isolation - Laine de roche | no | 0.324728 | 2.5 | 0.0213878 | 0.779319 | 0.779319 | 0.0534696 | 0.0534696 | Material Properties - Component 3, Finition int - Plaque de plâtre, ThermalConductivity: 0.8; Component 3, Finition int - Plaque de plâtre, SpecificHeatCapacity: 1000 J/kg/K; Component 3, Finition int - Plaque de plâtre, MassDensity: 1600 kg/m3; Component 3, Finition int - Plaque de plâtre, Embodied Energy: 1.45 (MJ/kg); Component 3, Finition int - Plaque de plâtre, Embodied Carbon: 0.22 (kgCO₂/kg); Component 3, Finition int - Plaque de plâtre, Name: Finition int - Plaque de plâtre; Component 3, Finition int - Plaque de plâtre, Participates in Collision Detection: no; Component 3: 2 with these values
Cloison Placostil 72/48 | R+1 | Mur (Classification ARCHICAD); Cloison (Classification ARCHICAD) | Finition int - Plaque de plâtre (2), Isolation - Laine de roche | Non défini | 0.04 | 840 | 160 | 23.4 (MJ/kg) | 1.73 (kgCO₂/kg) | Isolation - Laine de roche | no | 0.637 | 2.5 | 0.048459 | 1.54875 | 1.54875 | 0.121148 | 0.121148 | Material Properties - Component 3, Finition int - Plaque de plâtre, ThermalConductivity: 0.8; Component 3, Finition int - Plaque de plâtre, SpecificHeatCapacity: 1000 J/kg/K; Component 3, Finition int - Plaque de plâtre, MassDensity: 1600 kg/m3; Component 3, Finition int - Plaque de plâtre, Embodied Energy: 1.45 (MJ/kg); Component 3, Finition int - Plaque de plâtre, Embodied Carbon: 0.22 (kgCO₂/kg); Component 3, Finition int - Plaque de plâtre, Name: Finition int - Plaque de plâtre; Component 3, Finition int - Plaque de plâtre, Participates in Collision Detection: no; Component 3: 2 with these values
Cloison Placostil 72/48 | R+1 | Mur (Classification ARCHICAD); Cloison (Classification ARCHICAD) | Finition int - Plaque de plâtre (2), Isolation - Laine de roche | Non défini | 0.04 | 840 | 160 | 23.4 (MJ/kg) | 1.73 (kgCO₂/kg) | Isolation - Laine de roche | no | 1.26173 | 2.5 | 0.0946889 | 3.11057 | 3.11057 | 0.236722 | 0.236722 | Material Properties - Component 3, Finition int - Plaque de plâtre, ThermalConductivity: 0.8; Component 3, Finition int - Plaque de plâtre, SpecificHeatCapacity: 1000 J/kg/K; Component 3, Finition int - Plaque de plâtre, MassDensity: 1600 kg/m3; Component 3, Finition int - Plaque de plâtre, Embodied Energy: 1.45 (MJ/kg); Component 3, Finition int - Plaque de plâtre, Embodied Carbon: 0.22 (kgCO₂/kg); Component 3, Finition int - Plaque de plâtre, Name: Finition int - Plaque de plâtre; Component 3, Finition int - Plaque de plâtre, Participates in Collision Detection: no; Component 3: 2 with these values
Cloison Placostil 72/48 | R+1 | Mur (Classification ARCHICAD); Cloison (Classification ARCHICAD) | Finition int - Plaque de plâtre (2), Isolation - Laine de roche | Non défini | 0.04 | 840 | 160 | 23.4 (MJ/kg) | 1.73 (kgCO₂/kg) | Isolation - Laine de roche | no | 1.77228 | 2.5 | 0.0638084 | 4.37069 | 2.47789 | 0.327871 | 0.187804 | 0.8 | 1000 | 1600 | 1.45 (MJ/kg) | 0.22 (kgCO₂/kg) | Finition int - Plaque de plâtre | no | Material Properties - Component 1: 2 with these values
Cloison Placostil 72/48 | R+1 | Mur (Classification ARCHICAD); Cloison (Classification ARCHICAD) | Finition int - Plaque de plâtre (2), Isolation - Laine de roche | Non défini | 0.04 | 840 | 160 | 23.4 (MJ/kg) | 1.73 (kgCO₂/kg) | Isolation - Laine de roche | no | 1.073 | 2.5 | 0.004683 | 2.69875 | 0.54387 | 0.203367 | 0.0439064 | Material Properties - Component 3, Finition int - Plaque de plâtre, ThermalConductivity: 0.8; Component 3, Finition int - Plaque de plâtre, SpecificHeatCapacity: 1000 J/kg/K; Component 3, Finition int - Plaque de plâtre, MassDensity: 1600 kg/m3; Component 3, Finition int - Plaque de plâtre, Embodied Energy: 1.45 (MJ/kg); Component 3, Finition int - Plaque de plâtre, Embodied Carbon: 0.22 (kgCO₂/kg); Component 3, Finition int - Plaque de plâtre, Name: Finition int - Plaque de plâtre; Component 3, Finition int - Plaque de plâtre, Participates in Collision Detection: no; Component 3: 2 with these values
Cloison Placostil 72/48 | R+1 | Mur (Classification ARCHICAD); Cloison (Classification ARCHICAD) | Finition int - Plaque de plâtre (2), Isolation - Laine de roche | Non défini | 0.04 | 840 | 160 | 23.4 (MJ/kg) | 1.73 (kgCO₂/kg) | Isolation - Laine de roche | no | 1.247 | 2.5 | 0.096316 | 3.13375 | 3.13375 | 0.24079 | 0.24079 | 0.8 | 1000 | 1600 | 1.45 (MJ/kg) | 0.22 (kgCO₂/kg) | Finition int - Plaque de plâtre | no | Material Properties - Component 1: 2 with these values
Cloison Placostil 72/48 | R+1 | Mur (Classification ARCHICAD); Cloison (Classification ARCHICAD) | Finition int - Plaque de plâtre (2), Isolation - Laine de roche | Non défini | 0.04 | 840 | 160 | 23.4 (MJ/kg) | 1.73 (kgCO₂/kg) | Isolation - Laine de roche | no | 1.387 | 2.5 | 0.026629 | 2.87625 | 0.98345 | 0.224783 | 0.0847153 | Material Properties - Component 3, Finition int - Plaque de plâtre, ThermalConductivity: 0.8; Component 3, Finition int - Plaque de plâtre, SpecificHeatCapacity: 1000 J/kg/K; Component 3, Finition int - Plaque de plâtre, MassDensity: 1600 kg/m3; Component 3, Finition int - Plaque de plâtre, Embodied Energy: 1.45 (MJ/kg); Component 3, Finition int - Plaque de plâtre, Embodied Carbon: 0.22 (kgCO₂/kg); Component 3, Finition int - Plaque de plâtre, Name: Finition int - Plaque de plâtre; Component 3, Finition int - Plaque de plâtre, Participates in Collision Detection: no; Component 3: 2 with these values
Cloison Placostil 72/48 | R+1 | Mur (Classification ARCHICAD); Cloison (Classification ARCHICAD) | Isolation - Laine de roche, Finition int - Plaque de plâtre | Non défini | 0.04 | 840 | 160 | 23.4 (MJ/kg) | 1.73 (kgCO₂/kg) | Isolation - Laine de roche | no | 1.064 | 2.47 | 0.010614 | 2.84297 | 0.21489 | 0.220695 | 0.0262166 | 0.8 | 1000 | 1600 | 1.45 (MJ/kg) | 0.22 (kgCO₂/kg) | Finition int - Plaque de plâtre | no
Cloison Placostil 72/48 | R+1 | Mur (Classification ARCHICAD); Cloison (Classification ARCHICAD) | Finition int - Plaque de plâtre (2), Isolation - Laine de roche | Non défini | 0.04 | 840 | 160 | 23.4 (MJ/kg) | 1.73 (kgCO₂/kg) | Isolation - Laine de roche | no | 0.789637 | 2.47 | 0.0583601 | 1.93435 | 1.93435 | 0.144149 | 0.144149 | Material Properties - Component 3, Finition int - Plaque de plâtre, ThermalConductivity: 0.8; Component 3, Finition int - Plaque de plâtre, SpecificHeatCapacity: 1000 J/kg/K; Component 3, Finition int - Plaque de plâtre, MassDensity: 1600 kg/m3; Component 3, Finition int - Plaque de plâtre, Embodied Energy: 1.45 (MJ/kg); Component 3, Finition int - Plaque de plâtre, Embodied Carbon: 0.22 (kgCO₂/kg); Component 3, Finition int - Plaque de plâtre, Name: Finition int - Plaque de plâtre; Component 3, Finition int - Plaque de plâtre, Participates in Collision Detection: no; Component 3: 2 with these values
Cloison Placostil 72/48 | R+1 | Mur (Classification ARCHICAD); Cloison (Classification ARCHICAD) | Finition int - Plaque de plâtre (2), Isolation - Laine de roche | Non défini | 0.04 | 840 | 160 | 23.4 (MJ/kg) | 1.73 (kgCO₂/kg) | Isolation - Laine de roche | no | 1.437 | 2.5 | 0.040943 | 3.60003 | 1.70723 | 0.270037 | 0.12997 | Material Properties - Component 3, Finition int - Plaque de plâtre, ThermalConductivity: 0.8; Component 3, Finition int - Plaque de plâtre, SpecificHeatCapacity: 1000 J/kg/K; Component 3, Finition int - Plaque de plâtre, MassDensity: 1600 kg/m3; Component 3, Finition int - Plaque de plâtre, Embodied Energy: 1.45 (MJ/kg); Component 3, Finition int - Plaque de plâtre, Embodied Carbon: 0.22 (kgCO₂/kg); Component 3, Finition int - Plaque de plâtre, Name: Finition int - Plaque de plâtre; Component 3, Finition int - Plaque de plâtre, Participates in Collision Detection: no; Component 3: 2 with these values
Cloison Placostil 72/48 | R+1 | Mur (Classification ARCHICAD); Cloison (Classification ARCHICAD) | Finition int - Plaque de plâtre (2), Isolation - Laine de roche | Non défini | 0.04 | 840 | 160 | 23.4 (MJ/kg) | 1.73 (kgCO₂/kg) | Isolation - Laine de roche | no | 2.67362 | 2.5 | 0.130508 | 6.49675 | 4.60395 | 0.49131 | 0.351243 | 0.8 | 1000 | 1600 | 1.45 (MJ/kg) | 0.22 (kgCO₂/kg) | Finition int - Plaque de plâtre | no | Material Properties - Component 1: 2 with these values
Cloison Placostil 72/48 | R+1 | Mur (Classification ARCHICAD); Cloison (Classification ARCHICAD) | Finition int - Plaque de plâtre (2), Isolation - Laine de roche | Non défini | 0.04 | 840 | 160 | 23.4 (MJ/kg) | 1.73 (kgCO₂/kg) | Isolation - Laine de roche | no | 3.52193 | 2.5 | 0.185999 | 8.51982 | 6.62702 | 0.633347 | 0.49328 | Material Properties - Component 3, Finition int - Plaque de plâtre, ThermalConductivity: 0.8; Component 3, Finition int - Plaque de plâtre, SpecificHeatCapacity: 1000 J/kg/K; Component 3, Finition int - Plaque de plâtre, MassDensity: 1600 kg/m3; Component 3, Finition int - Plaque de plâtre, Embodied Energy: 1.45 (MJ/kg); Component 3, Finition int - Plaque de plâtre, Embodied Carbon: 0.22 (kgCO₂/kg); Component 3, Finition int - Plaque de plâtre, Name: Finition int - Plaque de plâtre; Component 3, Finition int - Plaque de plâtre, Participates in Collision Detection: no; Component 3: 2 with these values
Cloison Placostil 72/48 | R+1 | Mur (Classification ARCHICAD); Cloison (Classification ARCHICAD) | Finition int - Plaque de plâtre (2), Isolation - Laine de roche | Non défini | 0.04 | 840 | 160 | 23.4 (MJ/kg) | 1.73 (kgCO₂/kg) | Isolation - Laine de roche | no | 0.324 | 2.47 | 0.013986 | 0.58539 | 0.58539 | 0.0345454 | 0.0345454 | Material Properties - Component 3, Finition int - Plaque de plâtre, ThermalConductivity: 0.8; Component 3, Finition int - Plaque de plâtre, SpecificHeatCapacity: 1000 J/kg/K; Component 3, Finition int - Plaque de plâtre, MassDensity: 1600 kg/m3; Component 3, Finition int - Plaque de plâtre, Embodied Energy: 1.45 (MJ/kg); Component 3, Finition int - Plaque de plâtre, Embodied Carbon: 0.22 (kgCO₂/kg); Component 3, Finition int - Plaque de plâtre, Name: Finition int - Plaque de plâtre; Component 3, Finition int - Plaque de plâtre, Participates in Collision Detection: no; Component 3: 2 with these values
Cloison Placostil 72/48 | R+1 | Mur (Classification ARCHICAD); Cloison (Classification ARCHICAD) | Finition int - Plaque de plâtre (2), Isolation - Laine de roche | Non défini | 0.04 | 840 | 160 | 23.4 (MJ/kg) | 1.73 (kgCO₂/kg) | Isolation - Laine de roche | no | 3.44314 | 2.49 | 0.15522 | 8.3294 | 5.667 | 0.622351 | 0.425334 | 0.8 | 1000 | 1600 | 1.45 (MJ/kg) | 0.22 (kgCO₂/kg) | Finition int - Plaque de plâtre | no | Material Properties - Component 1: 2 with these values
Cloison Placostil 72/48 | R+1 | Mur (Classification ARCHICAD); Cloison (Classification ARCHICAD) | Finition int - Plaque de plâtre (2), Isolation - Laine de roche | Non défini | 0.04 | 840 | 160 | 23.4 (MJ/kg) | 1.73 (kgCO₂/kg) | Isolation - Laine de roche | no | 0.991738 | 2.5 | 0.00667262 | 2.47935 | 0.586545 | 0.185032 | 0.0449644 | 0.8 | 1000 | 1600 | 1.45 (MJ/kg) | 0.22 (kgCO₂/kg) | Finition int - Plaque de plâtre | no | Material Properties - Component 1: 2 with these values
Cloison Placostil 72/48 | R+1 | Mur (Classification ARCHICAD); Cloison (Classification ARCHICAD) | Finition int - Plaque de plâtre (2), Isolation - Laine de roche | Non défini | 0.04 | 840 | 160 | 23.4 (MJ/kg) | 1.73 (kgCO₂/kg) | Isolation - Laine de roche | no | 0.537 | 2.5 | 0.038417 | 1.32625 | 1.32625 | 0.0960425 | 0.0960425 | 0.8 | 1000 | 1600 | 1.45 (MJ/kg) | 0.22 (kgCO₂/kg) | Finition int - Plaque de plâtre | no | Material Properties - Component 1: 2 with these values
Cloison Placostil 72/48 | R+1 | Mur (Classification ARCHICAD); Cloison (Classification ARCHICAD) | Finition int - Plaque de plâtre (2), Isolation - Laine de roche | Non défini | 0.04 | 840 | 160 | 23.4 (MJ/kg) | 1.73 (kgCO₂/kg) | Isolation - Laine de roche | no | 1.474 | 2.5 | 0.111094 | 3.6575 | 3.6575 | 0.277735 | 0.277735 | 0.8 | 1000 | 1600 | 1.45 (MJ/kg) | 0.22 (kgCO₂/kg) | Finition int - Plaque de plâtre | no | Material Properties - Component 1: 2 with these values
Cloison Placostil 72/48 | R+1 | Mur (Classification ARCHICAD); Cloison (Classification ARCHICAD) | Finition int - Plaque de plâtre (2), Isolation - Laine de roche | Non défini | 0.04 | 840 | 160 | 23.4 (MJ/kg) | 1.73 (kgCO₂/kg) | Isolation - Laine de roche | no | 0.644 | 2.5 | 0.04902 | 1.625 | 1.625 | 0.12229 | 0.12229 | 0.8 | 1000 | 1600 | 1.45 (MJ/kg) | 0.22 (kgCO₂/kg) | Finition int - Plaque de plâtre | no | Material Properties - Component 1: 2 with these values
Cloison Placostil 72/48 | R+1 | Mur (Classification ARCHICAD); Cloison (Classification ARCHICAD) | Finition int - Plaque de plâtre (2), Isolation - Laine de roche | Non défini | 0.04 | 840 | 160 | 23.4 (MJ/kg) | 1.73 (kgCO₂/kg) | Isolation - Laine de roche | no | 0.324 | 2.5 | 0.013986 | 0.5925 | 0.5925 | 0.034965 | 0.034965 | Material Properties - Component 3, Finition int - Plaque de plâtre, ThermalConductivity: 0.8; Component 3, Finition int - Plaque de plâtre, SpecificHeatCapacity: 1000 J/kg/K; Component 3, Finition int - Plaque de plâtre, MassDensity: 1600 kg/m3; Component 3, Finition int - Plaque de plâtre, Embodied Energy: 1.45 (MJ/kg); Component 3, Finition int - Plaque de plâtre, Embodied Carbon: 0.22 (kgCO₂/kg); Component 3, Finition int - Plaque de plâtre, Name: Finition int - Plaque de plâtre; Component 3, Finition int - Plaque de plâtre, Participates in Collision Detection: no; Component 3: 2 with these values
Cloison Placostil 72/48 | R+1 | Mur (Classification ARCHICAD); Cloison (Classification ARCHICAD) | Finition int - Plaque de plâtre (2), Isolation - Laine de roche | Non défini | 0.04 | 840 | 160 | 23.4 (MJ/kg) | 1.73 (kgCO₂/kg) | Isolation - Laine de roche | no | 2.2324 | 2.5 | 0.0971608 | 5.56476 | 3.67196 | 0.411252 | 0.271185 | Material Properties - Component 3, Finition int - Plaque de plâtre, ThermalConductivity: 0.8; Component 3, Finition int - Plaque de plâtre, SpecificHeatCapacity: 1000 J/kg/K; Component 3, Finition int - Plaque de plâtre, MassDensity: 1600 kg/m3; Component 3, Finition int - Plaque de plâtre, Embodied Energy: 1.45 (MJ/kg); Component 3, Finition int - Plaque de plâtre, Embodied Carbon: 0.22 (kgCO₂/kg); Component 3, Finition int - Plaque de plâtre, Name: Finition int - Plaque de plâtre; Component 3, Finition int - Plaque de plâtre, Participates in Collision Detection: no; Component 3: 2 with these values
Cloison Placostil 72/48 | R+1 | Mur (Classification ARCHICAD); Cloison (Classification ARCHICAD) | Finition int - Plaque de plâtre (2), Isolation - Laine de roche | Non défini | 0.04 | 840 | 160 | 23.4 (MJ/kg) | 1.73 (kgCO₂/kg) | Isolation - Laine de roche | no | 0.97131 | 2.5 | 0.00590097 | 2.45328 | 0.560476 | 0.183102 | 0.0430352 | Material Properties - Component 3, Finition int - Plaque de plâtre, ThermalConductivity: 0.8; Component 3, Finition int - Plaque de plâtre, SpecificHeatCapacity: 1000 J/kg/K; Component 3, Finition int - Plaque de plâtre, MassDensity: 1600 kg/m3; Component 3, Finition int - Plaque de plâtre, Embodied Energy: 1.45 (MJ/kg); Component 3, Finition int - Plaque de plâtre, Embodied Carbon: 0.22 (kgCO₂/kg); Component 3, Finition int - Plaque de plâtre, Name: Finition int - Plaque de plâtre; Component 3, Finition int - Plaque de plâtre, Participates in Collision Detection: no; Component 3: 2 with these values
Cloison Placostil 72/48 | R+1 | Mur (Classification ARCHICAD); Cloison (Classification ARCHICAD) | Finition int - Plaque de plâtre (2), Isolation - Laine de roche | Non défini | 0.04 | 840 | 160 | 23.4 (MJ/kg) | 1.73 (kgCO₂/kg) | Isolation - Laine de roche | no | 1.443 | 2.5 | 0.106158 | 3.5475 | 3.5475 | 0.265395 | 0.265395 | 0.8 | 1000 | 1600 | 1.45 (MJ/kg) | 0.22 (kgCO₂/kg) | Finition int - Plaque de plâtre | no | Material Properties - Component 1: 2 with these values
Cloison Placostil 72/48 | R+1 | Mur (Classification ARCHICAD); Cloison (Classification ARCHICAD) | Finition int - Plaque de plâtre (2), Isolation - Laine de roche | Non défini | 0.04 | 840 | 160 | 23.4 (MJ/kg) | 1.73 (kgCO₂/kg) | Isolation - Laine de roche | no | 0.524 | 2.5 | 0.037429 | 1.29125 | 1.29125 | 0.0935725 | 0.0935725 | 0.8 | 1000 | 1600 | 1.45 (MJ/kg) | 0.22 (kgCO₂/kg) | Finition int - Plaque de plâtre | no | Material Properties - Component 1: 2 with these values
Cloison Placostil 72/48 | R+1 | Mur (Classification ARCHICAD); Cloison (Classification ARCHICAD) | Finition int - Plaque de plâtre (2), Isolation - Laine de roche | Non défini | 0.04 | 840 | 160 | 23.4 (MJ/kg) | 1.73 (kgCO₂/kg) | Isolation - Laine de roche | no | 0.637 | 2.5 | 0.045933 | 1.54125 | 1.54125 | 0.114832 | 0.114832 | 0.8 | 1000 | 1600 | 1.45 (MJ/kg) | 0.22 (kgCO₂/kg) | Finition int - Plaque de plâtre | no | Material Properties - Component 1: 2 with these values
Cloison Placostil 72/48 | R+1 | Mur (Classification ARCHICAD); Cloison (Classification ARCHICAD) | Finition int - Plaque de plâtre (2), Isolation - Laine de roche | Non défini | 0.04 | 840 | 160 | 23.4 (MJ/kg) | 1.73 (kgCO₂/kg) | Isolation - Laine de roche | no | 1.438 | 2.5 | 0.041133 | 3.63625 | 1.74345 | 0.271183 | 0.131115 | Material Properties - Component 3, Finition int - Plaque de plâtre, ThermalConductivity: 0.8; Component 3, Finition int - Plaque de plâtre, SpecificHeatCapacity: 1000 J/kg/K; Component 3, Finition int - Plaque de plâtre, MassDensity: 1600 kg/m3; Component 3, Finition int - Plaque de plâtre, Embodied Energy: 1.45 (MJ/kg); Component 3, Finition int - Plaque de plâtre, Embodied Carbon: 0.22 (kgCO₂/kg); Component 3, Finition int - Plaque de plâtre, Name: Finition int - Plaque de plâtre; Component 3, Finition int - Plaque de plâtre, Participates in Collision Detection: no; Component 3: 2 with these values
Cloison Placostil 72/48 | R+1 | Mur (Classification ARCHICAD); Cloison (Classification ARCHICAD) | Finition int - Plaque de plâtre (2), Isolation - Laine de roche | Non défini | 0.04 | 840 | 160 | 23.4 (MJ/kg) | 1.73 (kgCO₂/kg) | Isolation - Laine de roche | no | 1.078 | 2.5 | 0.074223 | 2.49375 | 2.49375 | 0.185557 | 0.185557 | Material Properties - Component 3, Finition int - Plaque de plâtre, ThermalConductivity: 0.8; Component 3, Finition int - Plaque de plâtre, SpecificHeatCapacity: 1000 J/kg/K; Component 3, Finition int - Plaque de plâtre, MassDensity: 1600 kg/m3; Component 3, Finition int - Plaque de plâtre, Embodied Energy: 1.45 (MJ/kg); Component 3, Finition int - Plaque de plâtre, Embodied Carbon: 0.22 (kgCO₂/kg); Component 3, Finition int - Plaque de plâtre, Name: Finition int - Plaque de plâtre; Component 3, Finition int - Plaque de plâtre, Participates in Collision Detection: no; Component 3: 2 with these values
Cloison Placostil 72/48 | R+1 | Mur (Classification ARCHICAD); Cloison (Classification ARCHICAD) | Finition int - Plaque de plâtre (2), Isolation - Laine de roche | Non défini | 0.04 | 840 | 160 | 23.4 (MJ/kg) | 1.73 (kgCO₂/kg) | Isolation - Laine de roche | no | 0.987 | 2.5 | 0.001417 | 2.45125 | 0.47525 | 0.179293 | 0.0330685 | Material Properties - Component 3, Finition int - Plaque de plâtre, ThermalConductivity: 0.8; Component 3, Finition int - Plaque de plâtre, SpecificHeatCapacity: 1000 J/kg/K; Component 3, Finition int - Plaque de plâtre, MassDensity: 1600 kg/m3; Component 3, Finition int - Plaque de plâtre, Embodied Energy: 1.45 (MJ/kg); Component 3, Finition int - Plaque de plâtre, Embodied Carbon: 0.22 (kgCO₂/kg); Component 3, Finition int - Plaque de plâtre, Name: Finition int - Plaque de plâtre; Component 3, Finition int - Plaque de plâtre, Participates in Collision Detection: no; Component 3: 2 with these values
Cloison Placostil 72/48 | R+1 | Mur (Classification ARCHICAD); Cloison (Classification ARCHICAD) | Finition int - Plaque de plâtre (2), Isolation - Laine de roche | 35 dB(A) | 0.04 | 840 | 160 | 23.4 (MJ/kg) | 1.73 (kgCO₂/kg) | Isolation - Laine de roche | no | 0.5 | 2.5 | 0.038988 | 1.275 | 1.275 | 0.09747 | 0.09747 | 0.8 | 1000 | 1600 | 1.45 (MJ/kg) | 0.22 (kgCO₂/kg) | Finition int - Plaque de plâtre | no | Material Properties - Component 1: 2 with these values
Cloison Placostil 72/48 | R+2 | Mur (Classification ARCHICAD); Cloison (Classification ARCHICAD) | Finition int - Plaque de plâtre (2), Isolation - Laine de roche | Non défini | 0.04 | 840 | 160 | 23.4 (MJ/kg) | 1.73 (kgCO₂/kg) | Isolation - Laine de roche | no | 1.874 | 2.5 | 0.071336 | 4.685 | 2.7922 | 0.34669 | 0.206623 | Material Properties - Component 3, Finition int - Plaque de plâtre, ThermalConductivity: 0.8; Component 3, Finition int - Plaque de plâtre, SpecificHeatCapacity: 1000 J/kg/K; Component 3, Finition int - Plaque de plâtre, MassDensity: 1600 kg/m3; Component 3, Finition int - Plaque de plâtre, Embodied Energy: 1.45 (MJ/kg); Component 3, Finition int - Plaque de plâtre, Embodied Carbon: 0.22 (kgCO₂/kg); Component 3, Finition int - Plaque de plâtre, Name: Finition int - Plaque de plâtre; Component 3, Finition int - Plaque de plâtre, Participates in Collision Detection: no; Component 3: 2 with these values
Cloison Placostil 72/48 | R+2 | Mur (Classification ARCHICAD); Cloison (Classification ARCHICAD) | Finition int - Plaque de plâtre (2), Isolation - Laine de roche | Non défini | 0.04 | 840 | 160 | 23.4 (MJ/kg) | 1.73 (kgCO₂/kg) | Isolation - Laine de roche | no | 1.50939 | 2.5 | 0.113713 | 3.74598 | 3.74598 | 0.284282 | 0.284282 | Material Properties - Component 3, Finition int - Plaque de plâtre, ThermalConductivity: 0.8; Component 3, Finition int - Plaque de plâtre, SpecificHeatCapacity: 1000 J/kg/K; Component 3, Finition int - Plaque de plâtre, MassDensity: 1600 kg/m3; Component 3, Finition int - Plaque de plâtre, Embodied Energy: 1.45 (MJ/kg); Component 3, Finition int - Plaque de plâtre, Embodied Carbon: 0.22 (kgCO₂/kg); Component 3, Finition int - Plaque de plâtre, Name: Finition int - Plaque de plâtre; Component 3, Finition int - Plaque de plâtre, Participates in Collision Detection: no; Component 3: 2 with these values
Cloison Placostil 72/48 | R+2 | Mur (Classification ARCHICAD); Cloison (Classification ARCHICAD) | Finition int - Plaque de plâtre (2), Isolation - Laine de roche | Non défini | 0.04 | 840 | 160 | 23.4 (MJ/kg) | 1.73 (kgCO₂/kg) | Isolation - Laine de roche | no | 0.287 | 2.5 | 0.030531 | 0.91875 | 0.91875 | 0.0763275 | 0.0763275 | 0.8 | 1000 | 1600 | 1.45 (MJ/kg) | 0.22 (kgCO₂/kg) | Finition int - Plaque de plâtre | no | Material Properties - Component 1: 2 with these values
Cloison Placostil 72/48 | R+2 | Mur (Classification ARCHICAD); Cloison (Classification ARCHICAD) | Finition int - Plaque de plâtre (2), Isolation - Laine de roche | Non défini | 0.04 | 840 | 160 | 23.4 (MJ/kg) | 1.73 (kgCO₂/kg) | Isolation - Laine de roche | no | 1.23673 | 2.5 | 0.0234807 | 3.07556 | 1.18276 | 0.227052 | 0.0869844 | Material Properties - Component 3, Finition int - Plaque de plâtre, ThermalConductivity: 0.8; Component 3, Finition int - Plaque de plâtre, SpecificHeatCapacity: 1000 J/kg/K; Component 3, Finition int - Plaque de plâtre, MassDensity: 1600 kg/m3; Component 3, Finition int - Plaque de plâtre, Embodied Energy: 1.45 (MJ/kg); Component 3, Finition int - Plaque de plâtre, Embodied Carbon: 0.22 (kgCO₂/kg); Component 3, Finition int - Plaque de plâtre, Name: Finition int - Plaque de plâtre; Component 3, Finition int - Plaque de plâtre, Participates in Collision Detection: no; Component 3: 2 with these values
Cloison Placostil 72/48 | R+2 | Mur (Classification ARCHICAD); Cloison (Classification ARCHICAD) | Finition int - Plaque de plâtre (2), Isolation - Laine de roche | Non défini | 0.04 | 840 | 160 | 23.4 (MJ/kg) | 1.73 (kgCO₂/kg) | Isolation - Laine de roche | no | 3.44314 | 2.49 | 0.15522 | 8.3294 | 5.667 | 0.622351 | 0.425334 | 0.8 | 1000 | 1600 | 1.45 (MJ/kg) | 0.22 (kgCO₂/kg) | Finition int - Plaque de plâtre | no | Material Properties - Component 1: 2 with these values
Cloison Placostil 72/48 | R+2 | Mur (Classification ARCHICAD); Cloison (Classification ARCHICAD) | Finition int - Plaque de plâtre (2), Isolation - Laine de roche | Non défini | 0.04 | 840 | 160 | 23.4 (MJ/kg) | 1.73 (kgCO₂/kg) | Isolation - Laine de roche | no | 0.961834 | 2.5 | 0.00313871 | 2.38833 | 0.495535 | 0.176197 | 0.0361296 | Material Properties - Component 3, Finition int - Plaque de plâtre, ThermalConductivity: 0.8; Component 3, Finition int - Plaque de plâtre, SpecificHeatCapacity: 1000 J/kg/K; Component 3, Finition int - Plaque de plâtre, MassDensity: 1600 kg/m3; Component 3, Finition int - Plaque de plâtre, Embodied Energy: 1.45 (MJ/kg); Component 3, Finition int - Plaque de plâtre, Embodied Carbon: 0.22 (kgCO₂/kg); Component 3, Finition int - Plaque de plâtre, Name: Finition int - Plaque de plâtre; Component 3, Finition int - Plaque de plâtre, Participates in Collision Detection: no; Component 3: 2 with these values
Cloison Placostil 72/48 | R+2 | Mur (Classification ARCHICAD); Cloison (Classification ARCHICAD) | Finition int - Plaque de plâtre (2), Isolation - Laine de roche | Non défini | 0.04 | 840 | 160 | 23.4 (MJ/kg) | 1.73 (kgCO₂/kg) | Isolation - Laine de roche | no | 0.997 | 2.5 | 0.005117 | 2.47625 | 0.58345 | 0.181142 | 0.0410753 | 0.8 | 1000 | 1600 | 1.45 (MJ/kg) | 0.22 (kgCO₂/kg) | Finition int - Plaque de plâtre | no | Material Properties - Component 1: 2 with these values
Cloison Placostil 72/48 | R+2 | Mur (Classification ARCHICAD); Cloison (Classification ARCHICAD) | Finition int - Plaque de plâtre (2), Isolation - Laine de roche | Non défini | 0.04 | 840 | 160 | 23.4 (MJ/kg) | 1.73 (kgCO₂/kg) | Isolation - Laine de roche | no | 1.057 | 2.5 | 0.081876 | 2.84375 | 2.84375 | 0.20469 | 0.20469 | Material Properties - Component 3, Finition int - Plaque de plâtre, ThermalConductivity: 0.8; Component 3, Finition int - Plaque de plâtre, SpecificHeatCapacity: 1000 J/kg/K; Component 3, Finition int - Plaque de plâtre, MassDensity: 1600 kg/m3; Component 3, Finition int - Plaque de plâtre, Embodied Energy: 1.45 (MJ/kg); Component 3, Finition int - Plaque de plâtre, Embodied Carbon: 0.22 (kgCO₂/kg); Component 3, Finition int - Plaque de plâtre, Name: Finition int - Plaque de plâtre; Component 3, Finition int - Plaque de plâtre, Participates in Collision Detection: no; Component 3: 2 with these values
Cloison Placostil 72/48 | R+2 | Mur (Classification ARCHICAD); Cloison (Classification ARCHICAD) | Finition int - Plaque de plâtre (2), Isolation - Laine de roche | Non défini | 0.04 | 840 | 160 | 23.4 (MJ/kg) | 1.73 (kgCO₂/kg) | Isolation - Laine de roche | no | 1.799 | 2.5 | 0.066483 | 4.45375 | 2.56095 | 0.334557 | 0.19449 | Material Properties - Component 3, Finition int - Plaque de plâtre, ThermalConductivity: 0.8; Component 3, Finition int - Plaque de plâtre, SpecificHeatCapacity: 1000 J/kg/K; Component 3, Finition int - Plaque de plâtre, MassDensity: 1600 kg/m3; Component 3, Finition int - Plaque de plâtre, Embodied Energy: 1.45 (MJ/kg); Component 3, Finition int - Plaque de plâtre, Embodied Carbon: 0.22 (kgCO₂/kg); Component 3, Finition int - Plaque de plâtre, Name: Finition int - Plaque de plâtre; Component 3, Finition int - Plaque de plâtre, Participates in Collision Detection: no; Component 3: 2 with these values
Cloison Placostil 72/48 | R+2 | Mur (Classification ARCHICAD); Cloison (Classification ARCHICAD) | Finition int - Plaque de plâtre (2), Isolation - Laine de roche | Non défini | 0.04 | 840 | 160 | 23.4 (MJ/kg) | 1.73 (kgCO₂/kg) | Isolation - Laine de roche | no | 0.361 | 2.5 | 0.027411 | 0.85875 | 0.85875 | 0.0685275 | 0.0685275 | Material Properties - Component 3, Finition int - Plaque de plâtre, ThermalConductivity: 0.8; Component 3, Finition int - Plaque de plâtre, SpecificHeatCapacity: 1000 J/kg/K; Component 3, Finition int - Plaque de plâtre, MassDensity: 1600 kg/m3; Component 3, Finition int - Plaque de plâtre, Embodied Energy: 1.45 (MJ/kg); Component 3, Finition int - Plaque de plâtre, Embodied Carbon: 0.22 (kgCO₂/kg); Component 3, Finition int - Plaque de plâtre, Name: Finition int - Plaque de plâtre; Component 3, Finition int - Plaque de plâtre, Participates in Collision Detection: no; Component 3: 2 with these values
Cloison Placostil 72/48 | R+2 | Mur (Classification ARCHICAD); Cloison (Classification ARCHICAD) | Finition int - Plaque de plâtre (2), Isolation - Laine de roche | Non défini | 0.04 | 840 | 160 | 23.4 (MJ/kg) | 1.73 (kgCO₂/kg) | Isolation - Laine de roche | no | 2.514 | 2.5 | 0.0913158 | 6.22499 | 3.56259 | 0.46509 | 0.268072 | 0.8 | 1000 | 1600 | 1.45 (MJ/kg) | 0.22 (kgCO₂/kg) | Finition int - Plaque de plâtre | no | Material Properties - Component 1: 2 with these values
Cloison Placostil 72/48 | R+2 | Mur (Classification ARCHICAD); Cloison (Classification ARCHICAD) | Finition int - Plaque de plâtre (2), Isolation - Laine de roche | Non défini | 0.04 | 840 | 160 | 23.4 (MJ/kg) | 1.73 (kgCO₂/kg) | Isolation - Laine de roche | no | 2.749 | 2.5 | 0.204747 | 6.82875 | 6.82875 | 0.511868 | 0.511868 | 0.8 | 1000 | 1600 | 1.45 (MJ/kg) | 0.22 (kgCO₂/kg) | Finition int - Plaque de plâtre | no | Material Properties - Component 1: 2 with these values
Cloison Placostil 72/48 | R+2 | Mur (Classification ARCHICAD); Cloison (Classification ARCHICAD) | Finition int - Plaque de plâtre (2), Isolation - Laine de roche | Non défini | 0.04 | 840 | 160 | 23.4 (MJ/kg) | 1.73 (kgCO₂/kg) | Isolation - Laine de roche | no | 1.81 | 2.5 | 0.135336 | 4.50875 | 4.50875 | 0.33834 | 0.33834 | 0.8 | 1000 | 1600 | 1.45 (MJ/kg) | 0.22 (kgCO₂/kg) | Finition int - Plaque de plâtre | no | Material Properties - Component 1: 2 with these values
Cloison Placostil 72/48 | R+2 | Mur (Classification ARCHICAD); Cloison (Classification ARCHICAD) | Finition int - Plaque de plâtre (2), Isolation - Laine de roche | Non défini | 0.04 | 840 | 160 | 23.4 (MJ/kg) | 1.73 (kgCO₂/kg) | Isolation - Laine de roche | no | 0.637 | 2.5 | 0.049707 | 1.60875 | 1.60875 | 0.124267 | 0.124267 | Material Properties - Component 3, Finition int - Plaque de plâtre, ThermalConductivity: 0.8; Component 3, Finition int - Plaque de plâtre, SpecificHeatCapacity: 1000 J/kg/K; Component 3, Finition int - Plaque de plâtre, MassDensity: 1600 kg/m3; Component 3, Finition int - Plaque de plâtre, Embodied Energy: 1.45 (MJ/kg); Component 3, Finition int - Plaque de plâtre, Embodied Carbon: 0.22 (kgCO₂/kg); Component 3, Finition int - Plaque de plâtre, Name: Finition int - Plaque de plâtre; Component 3, Finition int - Plaque de plâtre, Participates in Collision Detection: no; Component 3: 2 with these values
Cloison Placostil 72/48 | R+2 | Mur (Classification ARCHICAD); Cloison (Classification ARCHICAD) | Finition int - Plaque de plâtre (2), Isolation - Laine de roche | Non défini | 0.04 | 840 | 160 | 23.4 (MJ/kg) | 1.73 (kgCO₂/kg) | Isolation - Laine de roche | no | 0.961834 | 2.5 | 0.001092 | 2.10173 | 0.15208 | 0.168745 | 0.0244208 | Material Properties - Component 3, Finition int - Plaque de plâtre, ThermalConductivity: 0.8; Component 3, Finition int - Plaque de plâtre, SpecificHeatCapacity: 1000 J/kg/K; Component 3, Finition int - Plaque de plâtre, MassDensity: 1600 kg/m3; Component 3, Finition int - Plaque de plâtre, Embodied Energy: 1.45 (MJ/kg); Component 3, Finition int - Plaque de plâtre, Embodied Carbon: 0.22 (kgCO₂/kg); Component 3, Finition int - Plaque de plâtre, Name: Finition int - Plaque de plâtre; Component 3, Finition int - Plaque de plâtre, Participates in Collision Detection: no; Component 3: 2 with these values
Cloison Placostil 72/48 | R+2 | Mur (Classification ARCHICAD); Cloison (Classification ARCHICAD) | Finition int - Plaque de plâtre (2), Isolation - Laine de roche | Non défini | 0.04 | 840 | 160 | 23.4 (MJ/kg) | 1.73 (kgCO₂/kg) | Isolation - Laine de roche | no | 0.629589 | 2.5 | 0.0579436 | 1.80647 | 1.80647 | 0.144599 | 0.144599 | 0.8 | 1000 | 1600 | 1.45 (MJ/kg) | 0.22 (kgCO₂/kg) | Finition int - Plaque de plâtre | no | Material Properties - Component 1: 2 with these values
Cloison Placostil 72/48 | R+2 | Mur (Classification ARCHICAD); Cloison (Classification ARCHICAD) | Finition int - Plaque de plâtre (2), Isolation - Laine de roche | Non défini | 0.04 | 840 | 160 | 23.4 (MJ/kg) | 1.73 (kgCO₂/kg) | Isolation - Laine de roche | no | 1 | 2.5 | 0.085238 | 2.63335 | 2.63335 | 0.210907 | 0.210907 | Material Properties - Component 3, Finition int - Plaque de plâtre, ThermalConductivity: 0.8; Component 3, Finition int - Plaque de plâtre, SpecificHeatCapacity: 1000 J/kg/K; Component 3, Finition int - Plaque de plâtre, MassDensity: 1600 kg/m3; Component 3, Finition int - Plaque de plâtre, Embodied Energy: 1.45 (MJ/kg); Component 3, Finition int - Plaque de plâtre, Embodied Carbon: 0.22 (kgCO₂/kg); Component 3, Finition int - Plaque de plâtre, Name: Finition int - Plaque de plâtre; Component 3, Finition int - Plaque de plâtre, Participates in Collision Detection: no; Component 3: 2 with these values
Cloison Placostil 72/48 | R+2 | Mur (Classification ARCHICAD); Cloison (Classification ARCHICAD) | Finition int - Plaque de plâtre (2), Isolation - Laine de roche | Non défini | 0.04 | 840 | 160 | 23.4 (MJ/kg) | 1.73 (kgCO₂/kg) | Isolation - Laine de roche | no | 0.644 | 2.5 | 0.04902 | 1.625 | 1.625 | 0.12229 | 0.12229 | 0.8 | 1000 | 1600 | 1.45 (MJ/kg) | 0.22 (kgCO₂/kg) | Finition int - Plaque de plâtre | no | Material Properties - Component 1: 2 with these values
Cloison Placostil 72/48 | R+2 | Mur (Classification ARCHICAD); Cloison (Classification ARCHICAD) | Finition int - Plaque de plâtre (2), Isolation - Laine de roche | Non défini | 0.04 | 840 | 160 | 23.4 (MJ/kg) | 1.73 (kgCO₂/kg) | Isolation - Laine de roche | no | 0.991738 | 2.5 | 0.00667262 | 2.47935 | 0.586545 | 0.185032 | 0.0449644 | 0.8 | 1000 | 1600 | 1.45 (MJ/kg) | 0.22 (kgCO₂/kg) | Finition int - Plaque de plâtre | no | Material Properties - Component 1: 2 with these values
Cloison Placostil 72/48 | R+2 | Mur (Classification ARCHICAD); Cloison (Classification ARCHICAD) | Finition int - Plaque de plâtre (2), Isolation - Laine de roche | Non défini | 0.04 | 840 | 160 | 23.4 (MJ/kg) | 1.73 (kgCO₂/kg) | Isolation - Laine de roche | no | 0.537 | 2.5 | 0.038417 | 1.32625 | 1.32625 | 0.0960425 | 0.0960425 | 0.8 | 1000 | 1600 | 1.45 (MJ/kg) | 0.22 (kgCO₂/kg) | Finition int - Plaque de plâtre | no | Material Properties - Component 1: 2 with these values
Cloison Placostil 72/48 | R+2 | Mur (Classification ARCHICAD); Cloison (Classification ARCHICAD) | Finition int - Plaque de plâtre (2), Isolation - Laine de roche | Non défini | 0.04 | 840 | 160 | 23.4 (MJ/kg) | 1.73 (kgCO₂/kg) | Isolation - Laine de roche | no | 1.474 | 2.5 | 0.111094 | 3.6575 | 3.6575 | 0.277735 | 0.277735 | 0.8 | 1000 | 1600 | 1.45 (MJ/kg) | 0.22 (kgCO₂/kg) | Finition int - Plaque de plâtre | no | Material Properties - Component 1: 2 with these values
Cloison Placostil 72/48 | R+2 | Mur (Classification ARCHICAD); Cloison (Classification ARCHICAD) | Finition int - Plaque de plâtre (2), Isolation - Laine de roche | Non défini | 0.04 | 840 | 160 | 23.4 (MJ/kg) | 1.73 (kgCO₂/kg) | Isolation - Laine de roche | no | 1.226 | 2.5 | 0.025256 | 3.065 | 1.1722 | 0.23149 | 0.0914228 | 0.8 | 1000 | 1600 | 1.45 (MJ/kg) | 0.22 (kgCO₂/kg) | Finition int - Plaque de plâtre | no | Material Properties - Component 1: 2 with these values
Cloison Placostil 72/48 | R+2 | Mur (Classification ARCHICAD); Cloison (Classification ARCHICAD) | Finition int - Plaque de plâtre (2), Isolation - Laine de roche | Non défini | 0.04 | 840 | 160 | 23.4 (MJ/kg) | 1.73 (kgCO₂/kg) | Isolation - Laine de roche | no | 1.438 | 2.5 | 0.041133 | 3.63625 | 1.74345 | 0.271183 | 0.131115 | Material Properties - Component 3, Finition int - Plaque de plâtre, ThermalConductivity: 0.8; Component 3, Finition int - Plaque de plâtre, SpecificHeatCapacity: 1000 J/kg/K; Component 3, Finition int - Plaque de plâtre, MassDensity: 1600 kg/m3; Component 3, Finition int - Plaque de plâtre, Embodied Energy: 1.45 (MJ/kg); Component 3, Finition int - Plaque de plâtre, Embodied Carbon: 0.22 (kgCO₂/kg); Component 3, Finition int - Plaque de plâtre, Name: Finition int - Plaque de plâtre; Component 3, Finition int - Plaque de plâtre, Participates in Collision Detection: no; Component 3: 2 with these values
Cloison Placostil 72/48 | R+2 | Mur (Classification ARCHICAD); Cloison (Classification ARCHICAD) | Finition int - Plaque de plâtre (2), Isolation - Laine de roche | Non défini | 0.04 | 840 | 160 | 23.4 (MJ/kg) | 1.73 (kgCO₂/kg) | Isolation - Laine de roche | no | 1.078 | 2.5 | 0.074223 | 2.49375 | 2.49375 | 0.185557 | 0.185557 | Material Properties - Component 3, Finition int - Plaque de plâtre, ThermalConductivity: 0.8; Component 3, Finition int - Plaque de plâtre, SpecificHeatCapacity: 1000 J/kg/K; Component 3, Finition int - Plaque de plâtre, MassDensity: 1600 kg/m3; Component 3, Finition int - Plaque de plâtre, Embodied Energy: 1.45 (MJ/kg); Component 3, Finition int - Plaque de plâtre, Embodied Carbon: 0.22 (kgCO₂/kg); Component 3, Finition int - Plaque de plâtre, Name: Finition int - Plaque de plâtre; Component 3, Finition int - Plaque de plâtre, Participates in Collision Detection: no; Component 3: 2 with these values
Cloison Placostil 72/48 | R+2 | Mur (Classification ARCHICAD); Cloison (Classification ARCHICAD) | Finition int - Plaque de plâtre (2), Isolation - Laine de roche | Non défini | 0.04 | 840 | 160 | 23.4 (MJ/kg) | 1.73 (kgCO₂/kg) | Isolation - Laine de roche | no | 0.987 | 2.5 | 0.001417 | 2.45125 | 0.47525 | 0.179293 | 0.0330685 | Material Properties - Component 3, Finition int - Plaque de plâtre, ThermalConductivity: 0.8; Component 3, Finition int - Plaque de plâtre, SpecificHeatCapacity: 1000 J/kg/K; Component 3, Finition int - Plaque de plâtre, MassDensity: 1600 kg/m3; Component 3, Finition int - Plaque de plâtre, Embodied Energy: 1.45 (MJ/kg); Component 3, Finition int - Plaque de plâtre, Embodied Carbon: 0.22 (kgCO₂/kg); Component 3, Finition int - Plaque de plâtre, Name: Finition int - Plaque de plâtre; Component 3, Finition int - Plaque de plâtre, Participates in Collision Detection: no; Component 3: 2 with these values
Cloison Placostil 72/48 | R+2 | Mur (Classification ARCHICAD); Cloison (Classification ARCHICAD) | Finition int - Plaque de plâtre (2), Isolation - Laine de roche | 35 dB(A) | 0.04 | 840 | 160 | 23.4 (MJ/kg) | 1.73 (kgCO₂/kg) | Isolation - Laine de roche | no | 0.5 | 2.5 | 0.038988 | 1.275 | 1.275 | 0.09747 | 0.09747 | 0.8 | 1000 | 1600 | 1.45 (MJ/kg) | 0.22 (kgCO₂/kg) | Finition int - Plaque de plâtre | no | Material Properties - Component 1: 2 with these values
Cloison Placostil 72/48 | R+2 | Mur (Classification ARCHICAD); Cloison (Classification ARCHICAD) | Finition int - Plaque de plâtre (2), Isolation - Laine de roche | Non défini | 0.04 | 840 | 160 | 23.4 (MJ/kg) | 1.73 (kgCO₂/kg) | Isolation - Laine de roche | no | 0.324 | 2.5 | 0.013986 | 0.5925 | 0.5925 | 0.034965 | 0.034965 | Material Properties - Component 3, Finition int - Plaque de plâtre, ThermalConductivity: 0.8; Component 3, Finition int - Plaque de plâtre, SpecificHeatCapacity: 1000 J/kg/K; Component 3, Finition int - Plaque de plâtre, MassDensity: 1600 kg/m3; Component 3, Finition int - Plaque de plâtre, Embodied Energy: 1.45 (MJ/kg); Component 3, Finition int - Plaque de plâtre, Embodied Carbon: 0.22 (kgCO₂/kg); Component 3, Finition int - Plaque de plâtre, Name: Finition int - Plaque de plâtre; Component 3, Finition int - Plaque de plâtre, Participates in Collision Detection: no; Component 3: 2 with these values
Cloison Placostil 72/48 | R+2 | Mur (Classification ARCHICAD); Cloison (Classification ARCHICAD) | Finition int - Plaque de plâtre (2), Isolation - Laine de roche | Non défini | 0.04 | 840 | 160 | 23.4 (MJ/kg) | 1.73 (kgCO₂/kg) | Isolation - Laine de roche | no | 2.2324 | 2.5 | 0.0971608 | 5.56476 | 3.67196 | 0.411252 | 0.271185 | Material Properties - Component 3, Finition int - Plaque de plâtre, ThermalConductivity: 0.8; Component 3, Finition int - Plaque de plâtre, SpecificHeatCapacity: 1000 J/kg/K; Component 3, Finition int - Plaque de plâtre, MassDensity: 1600 kg/m3; Component 3, Finition int - Plaque de plâtre, Embodied Energy: 1.45 (MJ/kg); Component 3, Finition int - Plaque de plâtre, Embodied Carbon: 0.22 (kgCO₂/kg); Component 3, Finition int - Plaque de plâtre, Name: Finition int - Plaque de plâtre; Component 3, Finition int - Plaque de plâtre, Participates in Collision Detection: no; Component 3: 2 with these values
Cloison Placostil 72/48 | R+2 | Mur (Classification ARCHICAD); Cloison (Classification ARCHICAD) | Finition int - Plaque de plâtre (2), Isolation - Laine de roche | Non défini | 0.04 | 840 | 160 | 23.4 (MJ/kg) | 1.73 (kgCO₂/kg) | Isolation - Laine de roche | no | 0.97131 | 2.5 | 0.00590097 | 2.45328 | 0.560476 | 0.183102 | 0.0430352 | Material Properties - Component 3, Finition int - Plaque de plâtre, ThermalConductivity: 0.8; Component 3, Finition int - Plaque de plâtre, SpecificHeatCapacity: 1000 J/kg/K; Component 3, Finition int - Plaque de plâtre, MassDensity: 1600 kg/m3; Component 3, Finition int - Plaque de plâtre, Embodied Energy: 1.45 (MJ/kg); Component 3, Finition int - Plaque de plâtre, Embodied Carbon: 0.22 (kgCO₂/kg); Component 3, Finition int - Plaque de plâtre, Name: Finition int - Plaque de plâtre; Component 3, Finition int - Plaque de plâtre, Participates in Collision Detection: no; Component 3: 2 with these values
Cloison Placostil 72/48 | R+2 | Mur (Classification ARCHICAD); Cloison (Classification ARCHICAD) | Finition int - Plaque de plâtre (2), Isolation - Laine de roche | Non défini | 0.04 | 840 | 160 | 23.4 (MJ/kg) | 1.73 (kgCO₂/kg) | Isolation - Laine de roche | no | 1.443 | 2.5 | 0.106158 | 3.5475 | 3.5475 | 0.265395 | 0.265395 | 0.8 | 1000 | 1600 | 1.45 (MJ/kg) | 0.22 (kgCO₂/kg) | Finition int - Plaque de plâtre | no | Material Properties - Component 1: 2 with these values
Cloison Placostil 72/48 | R+2 | Mur (Classification ARCHICAD); Cloison (Classification ARCHICAD) | Finition int - Plaque de plâtre (2), Isolation - Laine de roche | Non défini | 0.04 | 840 | 160 | 23.4 (MJ/kg) | 1.73 (kgCO₂/kg) | Isolation - Laine de roche | no | 0.524 | 2.5 | 0.037429 | 1.29125 | 1.29125 | 0.0935725 | 0.0935725 | 0.8 | 1000 | 1600 | 1.45 (MJ/kg) | 0.22 (kgCO₂/kg) | Finition int - Plaque de plâtre | no | Material Properties - Component 1: 2 with these values
Cloison Placostil 72/48 | R+2 | Mur (Classification ARCHICAD); Cloison (Classification ARCHICAD) | Finition int - Plaque de plâtre (2), Isolation - Laine de roche | Non défini | 0.04 | 840 | 160 | 23.4 (MJ/kg) | 1.73 (kgCO₂/kg) | Isolation - Laine de roche | no | 0.637 | 2.5 | 0.045933 | 1.54125 | 1.54125 | 0.114832 | 0.114832 | 0.8 | 1000 | 1600 | 1.45 (MJ/kg) | 0.22 (kgCO₂/kg) | Finition int - Plaque de plâtre | no | Material Properties - Component 1: 2 with these values
Cloison Placostil 72/48 | R+3 | Mur (Classification ARCHICAD); Cloison (Classification ARCHICAD) | Finition int - Plaque de plâtre (2), Isolation - Laine de roche | Non défini | 0.04 | 840 | 160 | 23.4 (MJ/kg) | 1.73 (kgCO₂/kg) | Isolation - Laine de roche | no | 2.53543 | 2.5 | 0.120979 | 6.29482 | 4.40202 | 0.470796 | 0.330729 | Material Properties - Component 3, Finition int - Plaque de plâtre, ThermalConductivity: 0.8; Component 3, Finition int - Plaque de plâtre, SpecificHeatCapacity: 1000 J/kg/K; Component 3, Finition int - Plaque de plâtre, MassDensity: 1600 kg/m3; Component 3, Finition int - Plaque de plâtre, Embodied Energy: 1.45 (MJ/kg); Component 3, Finition int - Plaque de plâtre, Embodied Carbon: 0.22 (kgCO₂/kg); Component 3, Finition int - Plaque de plâtre, Name: Finition int - Plaque de plâtre; Component 3, Finition int - Plaque de plâtre, Participates in Collision Detection: no; Component 3: 2 with these values
Cloison Placostil 72/48 | R+3 | Mur (Classification ARCHICAD); Cloison (Classification ARCHICAD) | Finition int - Plaque de plâtre (2), Isolation - Laine de roche | Non défini | 0.04 | 840 | 160 | 23.4 (MJ/kg) | 1.73 (kgCO₂/kg) | Isolation - Laine de roche | no | 0.464359 | 2.5 | 0.0265386 | 1.1009 | 1.1009 | 0.0663465 | 0.0663465 | 0.8 | 1000 | 1600 | 1.45 (MJ/kg) | 0.22 (kgCO₂/kg) | Finition int - Plaque de plâtre | no | Material Properties - Component 1: 2 with these values
Cloison Placostil 72/48 | R+3 | Mur (Classification ARCHICAD); Cloison (Classification ARCHICAD) | Finition int - Plaque de plâtre (2), Isolation - Laine de roche | Non défini | 0.04 | 840 | 160 | 23.4 (MJ/kg) | 1.73 (kgCO₂/kg) | Isolation - Laine de roche | no | 1.648 | 2.5 | 0.123273 | 4.07625 | 4.07625 | 0.308182 | 0.308182 | 0.8 | 1000 | 1600 | 1.45 (MJ/kg) | 0.22 (kgCO₂/kg) | Finition int - Plaque de plâtre | no | Material Properties - Component 1: 2 with these values
Cloison Placostil 72/48 | R+3 | Mur (Classification ARCHICAD); Cloison (Classification ARCHICAD) | Finition int - Plaque de plâtre (2), Isolation - Laine de roche | Non défini | 0.04 | 840 | 160 | 23.4 (MJ/kg) | 1.73 (kgCO₂/kg) | Isolation - Laine de roche | no | 1.511 | 2.5 | 0.043777 | 2.67244 | 0.779641 | 0.197111 | 0.0570443 | 0.8 | 1000 | 1600 | 1.45 (MJ/kg) | 0.22 (kgCO₂/kg) | Finition int - Plaque de plâtre | no | Material Properties - Component 1: 2 with these values
Cloison Placostil 72/48 | R+3 | Mur (Classification ARCHICAD); Cloison (Classification ARCHICAD) | Finition int - Plaque de plâtre (2), Isolation - Laine de roche | Non défini | 0.04 | 840 | 160 | 23.4 (MJ/kg) | 1.73 (kgCO₂/kg) | Isolation - Laine de roche | no | 1.872 | 2.5 | 0.000624 | 4.68 | 0.78624 | 0.34788 | 0.0597418 | 0.8 | 1000 | 1600 | 1.45 (MJ/kg) | 0.22 (kgCO₂/kg) | Finition int - Plaque de plâtre | no | Material Properties - Component 1: 2 with these values
Cloison Placostil 72/48 | R+3 | Mur (Classification ARCHICAD); Cloison (Classification ARCHICAD) | Finition int - Plaque de plâtre (2), Isolation - Laine de roche | Non défini | 0.04 | 840 | 160 | 23.4 (MJ/kg) | 1.73 (kgCO₂/kg) | Isolation - Laine de roche | no | 0.361 | 2.5 | 0.027411 | 0.85875 | 0.85875 | 0.0685275 | 0.0685275 | Material Properties - Component 3, Finition int - Plaque de plâtre, ThermalConductivity: 0.8; Component 3, Finition int - Plaque de plâtre, SpecificHeatCapacity: 1000 J/kg/K; Component 3, Finition int - Plaque de plâtre, MassDensity: 1600 kg/m3; Component 3, Finition int - Plaque de plâtre, Embodied Energy: 1.45 (MJ/kg); Component 3, Finition int - Plaque de plâtre, Embodied Carbon: 0.22 (kgCO₂/kg); Component 3, Finition int - Plaque de plâtre, Name: Finition int - Plaque de plâtre; Component 3, Finition int - Plaque de plâtre, Participates in Collision Detection: no; Component 3: 2 with these values
Cloison Placostil 72/48 | R+3 | Mur (Classification ARCHICAD); Cloison (Classification ARCHICAD) | Finition int - Plaque de plâtre (2), Isolation - Laine de roche | Non défini | 0.04 | 840 | 160 | 23.4 (MJ/kg) | 1.73 (kgCO₂/kg) | Isolation - Laine de roche | no | 0.644 | 2.5 | 0.04902 | 1.625 | 1.625 | 0.12229 | 0.12229 | 0.8 | 1000 | 1600 | 1.45 (MJ/kg) | 0.22 (kgCO₂/kg) | Finition int - Plaque de plâtre | no | Material Properties - Component 1: 2 with these values
Cloison Placostil 72/48 | R+3 | Mur (Classification ARCHICAD); Cloison (Classification ARCHICAD) | Finition int - Plaque de plâtre (2), Isolation - Laine de roche | Non défini | 0.04 | 840 | 160 | 23.4 (MJ/kg) | 1.73 (kgCO₂/kg) | Isolation - Laine de roche | no | 0.687 | 2.5 | 0.044959 | 1.73375 | 1.73375 | 0.112397 | 0.112397 | Material Properties - Component 3, Finition int - Plaque de plâtre, ThermalConductivity: 0.8; Component 3, Finition int - Plaque de plâtre, SpecificHeatCapacity: 1000 J/kg/K; Component 3, Finition int - Plaque de plâtre, MassDensity: 1600 kg/m3; Component 3, Finition int - Plaque de plâtre, Embodied Energy: 1.45 (MJ/kg); Component 3, Finition int - Plaque de plâtre, Embodied Carbon: 0.22 (kgCO₂/kg); Component 3, Finition int - Plaque de plâtre, Name: Finition int - Plaque de plâtre; Component 3, Finition int - Plaque de plâtre, Participates in Collision Detection: no; Component 3: 2 with these values
Cloison Placostil 72/48 | R+3 | Mur (Classification ARCHICAD); Cloison (Classification ARCHICAD) | Finition int - Plaque de plâtre (2), Isolation - Laine de roche | 35 dB(A) | 0.04 | 840 | 160 | 23.4 (MJ/kg) | 1.73 (kgCO₂/kg) | Isolation - Laine de roche | no | 0.369552 | 2.5 | 0.0293649 | 0.896381 | 0.896381 | 0.0734122 | 0.0734122 | Material Properties - Component 3, Finition int - Plaque de plâtre, ThermalConductivity: 0.8; Component 3, Finition int - Plaque de plâtre, SpecificHeatCapacity: 1000 J/kg/K; Component 3, Finition int - Plaque de plâtre, MassDensity: 1600 kg/m3; Component 3, Finition int - Plaque de plâtre, Embodied Energy: 1.45 (MJ/kg); Component 3, Finition int - Plaque de plâtre, Embodied Carbon: 0.22 (kgCO₂/kg); Component 3, Finition int - Plaque de plâtre, Name: Finition int - Plaque de plâtre; Component 3, Finition int - Plaque de plâtre, Participates in Collision Detection: no; Component 3: 2 with these values
Cloison Placostil 72/48 | R+3 | Mur (Classification ARCHICAD); Cloison (Classification ARCHICAD) | Finition int - Plaque de plâtre (2), Isolation - Laine de roche | Non défini | 0.04 | 840 | 160 | 23.4 (MJ/kg) | 1.73 (kgCO₂/kg) | Isolation - Laine de roche | no | 0.987 | 2.49 | 0.001417 | 2.44145 | 0.465445 | 0.178575 | 0.0323513 | Material Properties - Component 3, Finition int - Plaque de plâtre, ThermalConductivity: 0.8; Component 3, Finition int - Plaque de plâtre, SpecificHeatCapacity: 1000 J/kg/K; Component 3, Finition int - Plaque de plâtre, MassDensity: 1600 kg/m3; Component 3, Finition int - Plaque de plâtre, Embodied Energy: 1.45 (MJ/kg); Component 3, Finition int - Plaque de plâtre, Embodied Carbon: 0.22 (kgCO₂/kg); Component 3, Finition int - Plaque de plâtre, Name: Finition int - Plaque de plâtre; Component 3, Finition int - Plaque de plâtre, Participates in Collision Detection: no; Component 3: 2 with these values
Cloison Placostil 72/48 | R+3 | Mur (Classification ARCHICAD); Cloison (Classification ARCHICAD) | Finition int - Plaque de plâtre (2), Isolation - Laine de roche | Non défini | 0.04 | 840 | 160 | 23.4 (MJ/kg) | 1.73 (kgCO₂/kg) | Isolation - Laine de roche | no | 1.078 | 2.49 | 0.074223 | 2.48377 | 2.48377 | 0.184815 | 0.184815 | Material Properties - Component 3, Finition int - Plaque de plâtre, ThermalConductivity: 0.8; Component 3, Finition int - Plaque de plâtre, SpecificHeatCapacity: 1000 J/kg/K; Component 3, Finition int - Plaque de plâtre, MassDensity: 1600 kg/m3; Component 3, Finition int - Plaque de plâtre, Embodied Energy: 1.45 (MJ/kg); Component 3, Finition int - Plaque de plâtre, Embodied Carbon: 0.22 (kgCO₂/kg); Component 3, Finition int - Plaque de plâtre, Name: Finition int - Plaque de plâtre; Component 3, Finition int - Plaque de plâtre, Participates in Collision Detection: no; Component 3: 2 with these values
Cloison Placostil 72/48 | R+3 | Mur (Classification ARCHICAD); Cloison (Classification ARCHICAD) | Finition int - Plaque de plâtre (2), Isolation - Laine de roche | 35 dB(A) | 0.04 | 840 | 160 | 23.4 (MJ/kg) | 1.73 (kgCO₂/kg) | Isolation - Laine de roche | no | 0.55 | 2.5 | 0.03424 | 1.3945 | 1.3945 | 0.085265 | 0.085265 | 0.8 | 1000 | 1600 | 1.45 (MJ/kg) | 0.22 (kgCO₂/kg) | Finition int - Plaque de plâtre | no | Material Properties - Component 1: 2 with these values
Cloison Placostil 72/48 | R+3 | Mur (Classification ARCHICAD); Cloison (Classification ARCHICAD) | Finition int - Plaque de plâtre (2), Isolation - Laine de roche | Non défini | 0.04 | 840 | 160 | 23.4 (MJ/kg) | 1.73 (kgCO₂/kg) | Isolation - Laine de roche | no | 1.437 | 2.49 | 0.104393 | 3.50219 | 3.50219 | 0.259939 | 0.259939 | Material Properties - Component 3, Finition int - Plaque de plâtre, ThermalConductivity: 0.8; Component 3, Finition int - Plaque de plâtre, SpecificHeatCapacity: 1000 J/kg/K; Component 3, Finition int - Plaque de plâtre, MassDensity: 1600 kg/m3; Component 3, Finition int - Plaque de plâtre, Embodied Energy: 1.45 (MJ/kg); Component 3, Finition int - Plaque de plâtre, Embodied Carbon: 0.22 (kgCO₂/kg); Component 3, Finition int - Plaque de plâtre, Name: Finition int - Plaque de plâtre; Component 3, Finition int - Plaque de plâtre, Participates in Collision Detection: no; Component 3: 2 with these values
Cloison Placostil 72/48 | R+3 | Mur (Classification ARCHICAD); Cloison (Classification ARCHICAD) | Finition int - Plaque de plâtre (2), Isolation - Laine de roche | Non défini | 0.04 | 840 | 160 | 23.4 (MJ/kg) | 1.73 (kgCO₂/kg) | Isolation - Laine de roche | no | 1.438 | 2.5 | 0.041133 | 3.62181 | 1.72901 | 0.270105 | 0.130038 | Material Properties - Component 3, Finition int - Plaque de plâtre, ThermalConductivity: 0.8; Component 3, Finition int - Plaque de plâtre, SpecificHeatCapacity: 1000 J/kg/K; Component 3, Finition int - Plaque de plâtre, MassDensity: 1600 kg/m3; Component 3, Finition int - Plaque de plâtre, Embodied Energy: 1.45 (MJ/kg); Component 3, Finition int - Plaque de plâtre, Embodied Carbon: 0.22 (kgCO₂/kg); Component 3, Finition int - Plaque de plâtre, Name: Finition int - Plaque de plâtre; Component 3, Finition int - Plaque de plâtre, Participates in Collision Detection: no; Component 3: 2 with these values
Cloison Placostil 72/48 | R+3 | Mur (Classification ARCHICAD); Cloison (Classification ARCHICAD) | Finition int - Plaque de plâtre (2), Isolation - Laine de roche | Non défini | 0.04 | 840 | 160 | 23.4 (MJ/kg) | 1.73 (kgCO₂/kg) | Isolation - Laine de roche | no | 2.24131 | 2.5 | 0.098517 | 5.54328 | 3.65048 | 0.414642 | 0.274575 | 0.8 | 1000 | 1600 | 1.45 (MJ/kg) | 0.22 (kgCO₂/kg) | Finition int - Plaque de plâtre | no | Material Properties - Component 1: 2 with these values
Cloison Placostil 72/48 | R+3 | Mur (Classification ARCHICAD); Cloison (Classification ARCHICAD) | Finition int - Plaque de plâtre (2), Isolation - Laine de roche | Non défini | 0.04 | 840 | 160 | 23.4 (MJ/kg) | 1.73 (kgCO₂/kg) | Isolation - Laine de roche | no | 2.03589 | 2.5 | 0.000624 | 5.08971 | 0.855072 | 0.378199 | 0.0648353 | Material Properties - Component 3, Finition int - Plaque de plâtre, ThermalConductivity: 0.8; Component 3, Finition int - Plaque de plâtre, SpecificHeatCapacity: 1000 J/kg/K; Component 3, Finition int - Plaque de plâtre, MassDensity: 1600 kg/m3; Component 3, Finition int - Plaque de plâtre, Embodied Energy: 1.45 (MJ/kg); Component 3, Finition int - Plaque de plâtre, Embodied Carbon: 0.22 (kgCO₂/kg); Component 3, Finition int - Plaque de plâtre, Name: Finition int - Plaque de plâtre; Component 3, Finition int - Plaque de plâtre, Participates in Collision Detection: no; Component 3: 2 with these values
Cloison Placostil 72/48 | R+3 | Mur (Classification ARCHICAD); Cloison (Classification ARCHICAD) | Finition int - Plaque de plâtre (2), Isolation - Laine de roche | Non défini | 0.04 | 840 | 160 | 23.4 (MJ/kg) | 1.73 (kgCO₂/kg) | Isolation - Laine de roche | no | 1.513 | 2.5 | 0.114151 | 3.76625 | 3.76625 | 0.285378 | 0.285378 | 0.8 | 1000 | 1600 | 1.45 (MJ/kg) | 0.22 (kgCO₂/kg) | Finition int - Plaque de plâtre | no | Material Properties - Component 1: 2 with these values
Cloison Placostil 72/48 | R+3 | Mur (Classification ARCHICAD); Cloison (Classification ARCHICAD) | Finition int - Plaque de plâtre (2), Isolation - Laine de roche | Non défini | 0.04 | 840 | 160 | 23.4 (MJ/kg) | 1.73 (kgCO₂/kg) | Isolation - Laine de roche | no | 0.601263 | 2.5 | 0.0438695 | 1.44316 | 1.44316 | 0.109674 | 0.109674 | 0.8 | 1000 | 1600 | 1.45 (MJ/kg) | 0.22 (kgCO₂/kg) | Finition int - Plaque de plâtre | no | Material Properties - Component 1: 2 with these values
Cloison Placostil 72/48 | R+3 | Mur (Classification ARCHICAD); Cloison (Classification ARCHICAD) | Finition int - Plaque de plâtre (2), Isolation - Laine de roche | Non défini | 0.04 | 840 | 160 | 23.4 (MJ/kg) | 1.73 (kgCO₂/kg) | Isolation - Laine de roche | no | 0.357 | 2.5 | 0.024473 | 0.81625 | 0.81625 | 0.0611825 | 0.0611825 | Material Properties - Component 3, Finition int - Plaque de plâtre, ThermalConductivity: 0.8; Component 3, Finition int - Plaque de plâtre, SpecificHeatCapacity: 1000 J/kg/K; Component 3, Finition int - Plaque de plâtre, MassDensity: 1600 kg/m3; Component 3, Finition int - Plaque de plâtre, Embodied Energy: 1.45 (MJ/kg); Component 3, Finition int - Plaque de plâtre, Embodied Carbon: 0.22 (kgCO₂/kg); Component 3, Finition int - Plaque de plâtre, Name: Finition int - Plaque de plâtre; Component 3, Finition int - Plaque de plâtre, Participates in Collision Detection: no; Component 3: 2 with these values
Cloison Placostil 72/48 | R+3 | Mur (Classification ARCHICAD); Cloison (Classification ARCHICAD) | Finition int - Plaque de plâtre (2), Isolation - Laine de roche | Non défini | 0.04 | 840 | 160 | 23.4 (MJ/kg) | 1.73 (kgCO₂/kg) | Isolation - Laine de roche | no | 1.53196 | 2.5 | 0.122658 | 4.03116 | 4.03116 | 0.306646 | 0.306646 | Material Properties - Component 3, Finition int - Plaque de plâtre, ThermalConductivity: 0.8; Component 3, Finition int - Plaque de plâtre, SpecificHeatCapacity: 1000 J/kg/K; Component 3, Finition int - Plaque de plâtre, MassDensity: 1600 kg/m3; Component 3, Finition int - Plaque de plâtre, Embodied Energy: 1.45 (MJ/kg); Component 3, Finition int - Plaque de plâtre, Embodied Carbon: 0.22 (kgCO₂/kg); Component 3, Finition int - Plaque de plâtre, Name: Finition int - Plaque de plâtre; Component 3, Finition int - Plaque de plâtre, Participates in Collision Detection: no; Component 3: 2 with these values
Cloison Placostil 72/48 | R+4 | Mur (Classification ARCHICAD); Cloison (Classification ARCHICAD) | Finition int - Plaque de plâtre (2), Isolation - Laine de roche | Non défini | 0.04 | 840 | 160 | 23.4 (MJ/kg) | 1.73 (kgCO₂/kg) | Isolation - Laine de roche | no | 2.80131 | 2.48 | 0.206673 | 6.82821 | 6.82821 | 0.512549 | 0.512549 | 0.8 | 1000 | 1600 | 1.45 (MJ/kg) | 0.22 (kgCO₂/kg) | Finition int - Plaque de plâtre | no | Material Properties - Component 1: 2 with these values
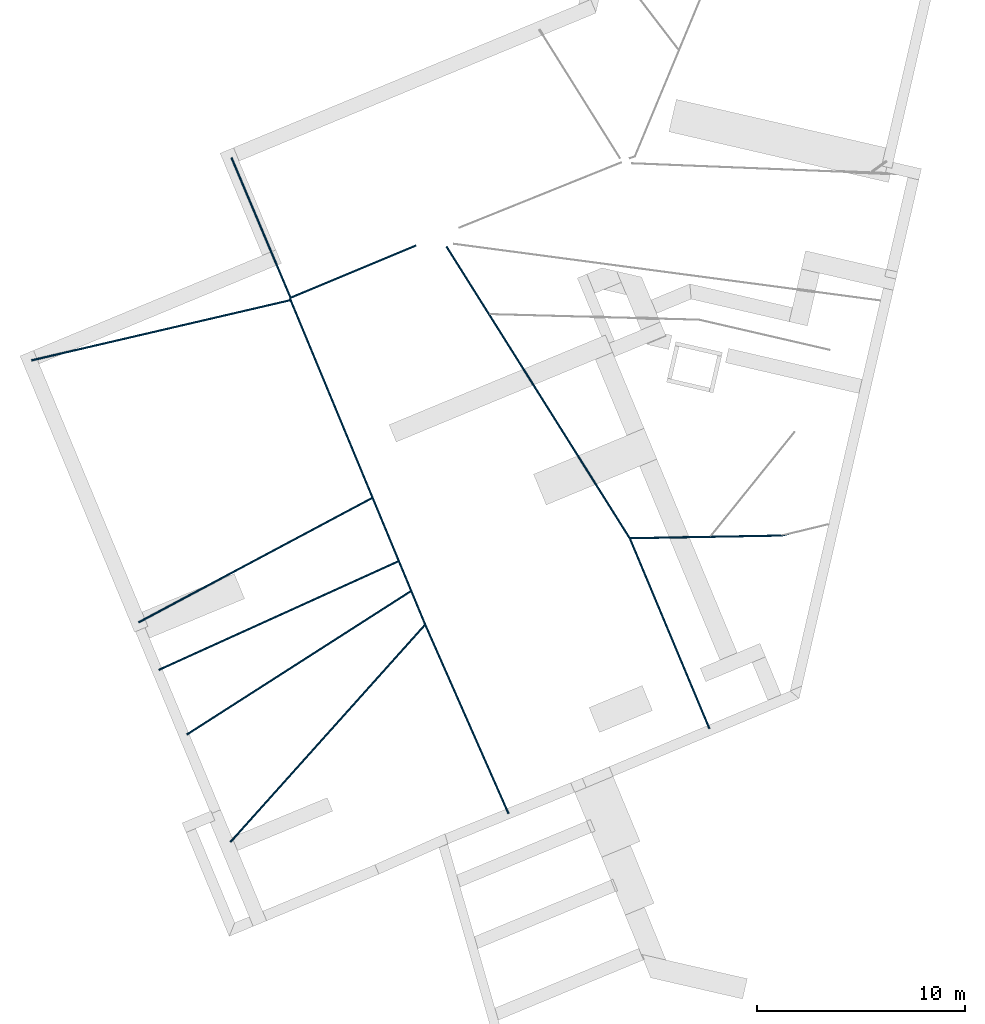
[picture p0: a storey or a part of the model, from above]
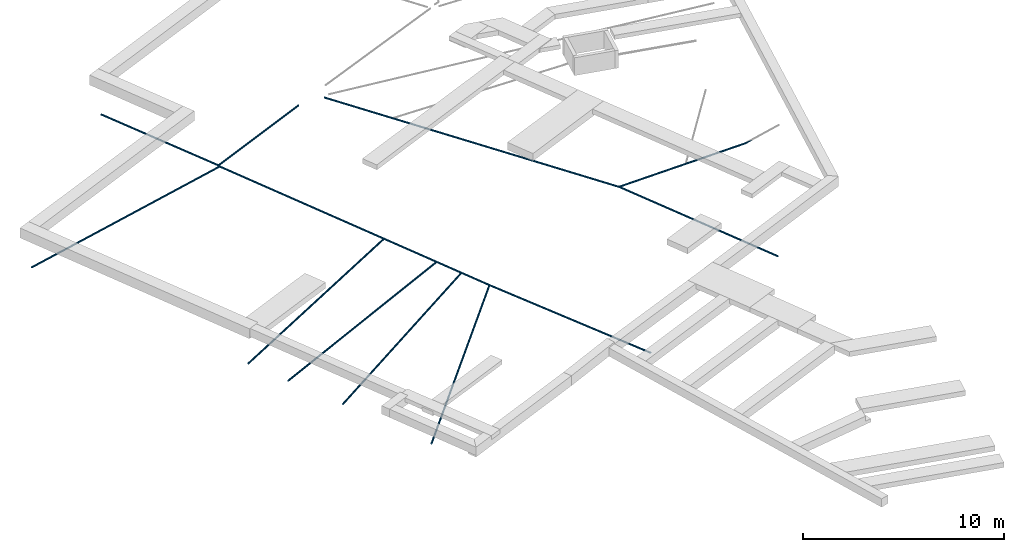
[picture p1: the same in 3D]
Properties of the parts of a building model (IFC2X3), part 11 of 22

# IfcWall: 3 - Cloison 72mm Placostil 74 (508)
Name | In | Classification | Material | AcousticRating | Component 2, Isolation - Laine de roche, ThermalConductivity | Component 2, Isolation - Laine de roche, SpecificHeatCapacity (J/kg/K) | Component 2, Isolation - Laine de roche, MassDensity (kg/m3) | Component 2, Isolation - Laine de roche, Embodied Energy | Component 2, Isolation - Laine de roche, Embodied Carbon | Component 2, Isolation - Laine de roche, Name | Component 2, Isolation - Laine de roche, Participates in Collision Detection | Length (m) | Height (m) | GrossFootprintArea (m2) = NetFootprintArea (m2) | GrossSideArea (m2) | NetSideArea (m2) | GrossVolume (m3) | NetVolume (m3) | Component 1, Finition int - Plaque de plâtre, ThermalConductivity | Component 1, Finition int - Plaque de plâtre, SpecificHeatCapacity (J/kg/K) | Component 1, Finition int - Plaque de plâtre, MassDensity (kg/m3) | Component 1, Finition int - Plaque de plâtre, Embodied Energy | Component 1, Finition int - Plaque de plâtre, Embodied Carbon | Component 1, Finition int - Plaque de plâtre, Name | Component 1, Finition int - Plaque de plâtre, Participates in Collision Detection
Cloison Placostil 72/48 | R+4 | Mur (Classification ARCHICAD); Cloison (Classification ARCHICAD) | Finition int - Plaque de plâtre (2), Isolation - Laine de roche | Non défini | 0.04 | 840 | 160 | 23.4 (MJ/kg) | 1.73 (kgCO₂/kg) | Isolation - Laine de roche | no | 4.79731 | 2.48 | 0.286413 | 11.7783 | 9.90369 | 0.877307 | 0.738587 | 0.8 | 1000 | 1600 | 1.45 (MJ/kg) | 0.22 (kgCO₂/kg) | Finition int - Plaque de plâtre | no | Material Properties - Component 1: 2 with these values
Cloison Placostil 72/48 | R+4 | Mur (Classification ARCHICAD); Cloison (Classification ARCHICAD) | Finition int - Plaque de plâtre (2), Isolation - Laine de roche | Non défini | 0.04 | 840 | 160 | 23.4 (MJ/kg) | 1.73 (kgCO₂/kg) | Isolation - Laine de roche | no | 2.00899 | 2.48 | 0.080628 | 4.96617 | 3.09157 | 0.366961 | 0.22824 | 0.8 | 1000 | 1600 | 1.45 (MJ/kg) | 0.22 (kgCO₂/kg) | Finition int - Plaque de plâtre | no | Material Properties - Component 1: 2 with these values
Cloison Placostil 72/48 | R+4 | Mur (Classification ARCHICAD); Cloison (Classification ARCHICAD) | Finition int - Plaque de plâtre (2), Isolation - Laine de roche | Non défini | 0.04 | 840 | 160 | 23.4 (MJ/kg) | 1.73 (kgCO₂/kg) | Isolation - Laine de roche | no | 2.36663 | 2.48 | 0.004683 | 5.88537 | 1.08633 | 0.439148 | 0.0840188 | 0.8 | 1000 | 1600 | 1.45 (MJ/kg) | 0.22 (kgCO₂/kg) | Finition int - Plaque de plâtre | no | Material Properties - Component 1: 2 with these values
Cloison Placostil 72/48 | R+4 | Mur (Classification ARCHICAD); Cloison (Classification ARCHICAD) | Finition int - Plaque de plâtre (2), Isolation - Laine de roche | Non défini | 0.04 | 840 | 160 | 23.4 (MJ/kg) | 1.73 (kgCO₂/kg) | Isolation - Laine de roche | no | 5.022 | 2.5 | 0.302343 | 12.4788 | 10.586 | 0.924208 | 0.78414 | 0.8 | 1000 | 1600 | 1.45 (MJ/kg) | 0.22 (kgCO₂/kg) | Finition int - Plaque de plâtre | no | Material Properties - Component 1: 2 with these values
Cloison Placostil 72/48 | R+4 | Mur (Classification ARCHICAD); Cloison (Classification ARCHICAD) | Finition int - Plaque de plâtre (2), Isolation - Laine de roche | Non défini | 0.04 | 840 | 160 | 23.4 (MJ/kg) | 1.73 (kgCO₂/kg) | Isolation - Laine de roche | no | 2.275 | 2.5 | 0.10101 | 5.6275 | 3.7347 | 0.420875 | 0.280808 | 0.8 | 1000 | 1600 | 1.45 (MJ/kg) | 0.22 (kgCO₂/kg) | Finition int - Plaque de plâtre | no | Material Properties - Component 1: 2 with these values
Cloison Placostil 72/48 | R+4 | Mur (Classification ARCHICAD); Cloison (Classification ARCHICAD) | Finition int - Plaque de plâtre (2), Isolation - Laine de roche | Non défini | 0.04 | 840 | 160 | 23.4 (MJ/kg) | 1.73 (kgCO₂/kg) | Isolation - Laine de roche | no | 2.96366 | 2.5 | 0.00147731 | 7.39291 | 1.30579 | 0.546535 | 0.0948907 | Material Properties - Component 3, Finition int - Plaque de plâtre, ThermalConductivity: 0.8; Component 3, Finition int - Plaque de plâtre, SpecificHeatCapacity: 1000 J/kg/K; Component 3, Finition int - Plaque de plâtre, MassDensity: 1600 kg/m3; Component 3, Finition int - Plaque de plâtre, Embodied Energy: 1.45 (MJ/kg); Component 3, Finition int - Plaque de plâtre, Embodied Carbon: 0.22 (kgCO₂/kg); Component 3, Finition int - Plaque de plâtre, Name: Finition int - Plaque de plâtre; Component 3, Finition int - Plaque de plâtre, Participates in Collision Detection: no; Component 3: 2 with these values
Cloison Placostil 72/48 | R+4 | Mur (Classification ARCHICAD); Cloison (Classification ARCHICAD) | Finition int - Plaque de plâtre (2), Isolation - Laine de roche | Non défini | 0.04 | 840 | 160 | 23.4 (MJ/kg) | 1.73 (kgCO₂/kg) | Isolation - Laine de roche | no | 1.33664 | 2.5 | 0.00190614 | 3.3416 | 0.562347 | 0.251958 | 0.0462938 | 0.8 | 1000 | 1600 | 1.45 (MJ/kg) | 0.22 (kgCO₂/kg) | Finition int - Plaque de plâtre | no | Material Properties - Component 1: 2 with these values
Cloison Placostil 72/48 | Rez-de-chaussée | Cloison (Classification ARCHICAD) | Finition int - Plaque de plâtre (2), Isolation - Laine de roche | Non défini | 0.04 | 840 | 160 | 23.4 (MJ/kg) | 1.73 (kgCO₂/kg) | Isolation - Laine de roche | no | 1.26191 | 2.5 | 0.004683 | 3.17102 | 0.10875 | 0.238315 | 0.0117075 | 0.8 | 1000 | 1600 | 1.45 (MJ/kg) | 0.22 (kgCO₂/kg) | Finition int - Plaque de plâtre | no | Material Properties - Component 1: 2 with these values
Cloison Placostil 72/48 | Rez-de-chaussée | Cloison (Classification ARCHICAD) | Isolation - Laine de roche, Finition int - Plaque de plâtre | Non défini | 0.04 | 840 | 160 | 23.4 (MJ/kg) | 1.73 (kgCO₂/kg) | Isolation - Laine de roche | no | 0.987 | 2.5 | 0.001417 | 2.45125 | 0.07625 | 0.179293 | 0.0035425 | 0.8 | 1000 | 1600 | 1.45 (MJ/kg) | 0.22 (kgCO₂/kg) | Finition int - Plaque de plâtre | no
Cloison Placostil 72/48 | Rez-de-chaussée | Cloison (Classification ARCHICAD) | Finition int - Plaque de plâtre (2), Isolation - Laine de roche | Non défini | 0.04 | 840 | 160 | 23.4 (MJ/kg) | 1.73 (kgCO₂/kg) | Isolation - Laine de roche | no | 0.663 | 2.5 | 0.050499 | 1.4526 | 1.4526 | 0.121408 | 0.121408 | 0.8 | 1000 | 1600 | 1.45 (MJ/kg) | 0.22 (kgCO₂/kg) | Finition int - Plaque de plâtre | no | Material Properties - Component 1: 2 with these values
Cloison Placostil 72/48 | Rez-de-chaussée | Cloison (Classification ARCHICAD) | Finition int - Plaque de plâtre (2), Isolation - Laine de roche | Non défini | 0.04 | 840 | 160 | 23.4 (MJ/kg) | 1.73 (kgCO₂/kg) | Isolation - Laine de roche | no | 0.637 | 2.5 | 0.045933 | 1.54125 | 1.54125 | 0.114832 | 0.114832 | 0.8 | 1000 | 1600 | 1.45 (MJ/kg) | 0.22 (kgCO₂/kg) | Finition int - Plaque de plâtre | no | Material Properties - Component 1: 2 with these values
2 x Cloison Placostil 72/48 | Rez-de-chaussée | Cloison (Classification ARCHICAD) | Finition int - Plaque de plâtre (2), Isolation - Laine de roche | Non défini | 0.04 | 840 | 160 | 23.4 (MJ/kg) | 1.73 (kgCO₂/kg) | Isolation - Laine de roche | no | 0.324 | 2.5 | 0.013986 | 0.5925 | 0.5925 | 0.034965 | 0.034965 | Material Properties - Component 3, Finition int - Plaque de plâtre, ThermalConductivity: 0.8; Component 3, Finition int - Plaque de plâtre, SpecificHeatCapacity: 1000 J/kg/K; Component 3, Finition int - Plaque de plâtre, MassDensity: 1600 kg/m3; Component 3, Finition int - Plaque de plâtre, Embodied Energy: 1.45 (MJ/kg); Component 3, Finition int - Plaque de plâtre, Embodied Carbon: 0.22 (kgCO₂/kg); Component 3, Finition int - Plaque de plâtre, Name: Finition int - Plaque de plâtre; Component 3, Finition int - Plaque de plâtre, Participates in Collision Detection: no; Component 3: 2 with these values
Cloison Placostil 72/48 | Rez-de-chaussée | Cloison (Classification ARCHICAD) | Finition int - Plaque de plâtre (2), Isolation - Laine de roche | Non défini | 0.04 | 840 | 160 | 23.4 (MJ/kg) | 1.73 (kgCO₂/kg) | Isolation - Laine de roche | no | 0.97131 | 2.5 | 0.00590097 | 2.45328 | 0.560476 | 0.183102 | 0.0430352 | Material Properties - Component 3, Finition int - Plaque de plâtre, ThermalConductivity: 0.8; Component 3, Finition int - Plaque de plâtre, SpecificHeatCapacity: 1000 J/kg/K; Component 3, Finition int - Plaque de plâtre, MassDensity: 1600 kg/m3; Component 3, Finition int - Plaque de plâtre, Embodied Energy: 1.45 (MJ/kg); Component 3, Finition int - Plaque de plâtre, Embodied Carbon: 0.22 (kgCO₂/kg); Component 3, Finition int - Plaque de plâtre, Name: Finition int - Plaque de plâtre; Component 3, Finition int - Plaque de plâtre, Participates in Collision Detection: no; Component 3: 2 with these values
Cloison Placostil 72/48 | Rez-de-chaussée | Cloison (Classification ARCHICAD) | Finition int - Plaque de plâtre (2), Isolation - Laine de roche | Non défini | 0.04 | 840 | 160 | 23.4 (MJ/kg) | 1.73 (kgCO₂/kg) | Isolation - Laine de roche | no | 0.644 | 2.5 | 0.04902 | 1.625 | 1.625 | 0.12229 | 0.12229 | 0.8 | 1000 | 1600 | 1.45 (MJ/kg) | 0.22 (kgCO₂/kg) | Finition int - Plaque de plâtre | no | Material Properties - Component 1: 2 with these values
Cloison Placostil 72/48 | Rez-de-chaussée | Cloison (Classification ARCHICAD) | Finition int - Plaque de plâtre (2), Isolation - Laine de roche | Non défini | 0.04 | 840 | 160 | 23.4 (MJ/kg) | 1.73 (kgCO₂/kg) | Isolation - Laine de roche | no | 1.443 | 2.5 | 0.106158 | 3.5475 | 3.5475 | 0.265395 | 0.265395 | 0.8 | 1000 | 1600 | 1.45 (MJ/kg) | 0.22 (kgCO₂/kg) | Finition int - Plaque de plâtre | no | Material Properties - Component 1: 2 with these values
Cloison Placostil 72/48 | Rez-de-chaussée | Cloison (Classification ARCHICAD) | Finition int - Plaque de plâtre (2), Isolation - Laine de roche | Non défini | 0.04 | 840 | 160 | 23.4 (MJ/kg) | 1.73 (kgCO₂/kg) | Isolation - Laine de roche | no | 2.2324 | 2.5 | 0.0971608 | 5.56476 | 3.67196 | 0.411252 | 0.271185 | Material Properties - Component 3, Finition int - Plaque de plâtre, ThermalConductivity: 0.8; Component 3, Finition int - Plaque de plâtre, SpecificHeatCapacity: 1000 J/kg/K; Component 3, Finition int - Plaque de plâtre, MassDensity: 1600 kg/m3; Component 3, Finition int - Plaque de plâtre, Embodied Energy: 1.45 (MJ/kg); Component 3, Finition int - Plaque de plâtre, Embodied Carbon: 0.22 (kgCO₂/kg); Component 3, Finition int - Plaque de plâtre, Name: Finition int - Plaque de plâtre; Component 3, Finition int - Plaque de plâtre, Participates in Collision Detection: no; Component 3: 2 with these values
Cloison Placostil 72/48 | Rez-de-chaussée | Cloison (Classification ARCHICAD) | Finition int - Plaque de plâtre (2), Isolation - Laine de roche | Non défini | 0.04 | 840 | 160 | 23.4 (MJ/kg) | 1.73 (kgCO₂/kg) | Isolation - Laine de roche | no | 0.911056 | 2.5 | 0.0688956 | 2.17092 | 2.17092 | 0.17096 | 0.17096 | Material Properties - Component 3, Finition int - Plaque de plâtre, ThermalConductivity: 0.8; Component 3, Finition int - Plaque de plâtre, SpecificHeatCapacity: 1000 J/kg/K; Component 3, Finition int - Plaque de plâtre, MassDensity: 1600 kg/m3; Component 3, Finition int - Plaque de plâtre, Embodied Energy: 1.45 (MJ/kg); Component 3, Finition int - Plaque de plâtre, Embodied Carbon: 0.22 (kgCO₂/kg); Component 3, Finition int - Plaque de plâtre, Name: Finition int - Plaque de plâtre; Component 3, Finition int - Plaque de plâtre, Participates in Collision Detection: no; Component 3: 2 with these values
Cloison Placostil 72/48 | Rez-de-chaussée | Cloison (Classification ARCHICAD) | Finition int - Plaque de plâtre (2), Isolation - Laine de roche | Non défini | 0.04 | 840 | 160 | 23.4 (MJ/kg) | 1.73 (kgCO₂/kg) | Isolation - Laine de roche | no | 0.847474 | 2.5 | 0.0626401 | 2.10243 | 2.10243 | 0.1566 | 0.1566 | 0.8 | 1000 | 1600 | 1.45 (MJ/kg) | 0.22 (kgCO₂/kg) | Finition int - Plaque de plâtre | no | Material Properties - Component 1: 2 with these values
Cloison Placostil 72/48 | Rez-de-chaussée | Cloison (Classification ARCHICAD) | Finition int - Plaque de plâtre (2), Isolation - Laine de roche | Non défini | 0.04 | 840 | 160 | 23.4 (MJ/kg) | 1.73 (kgCO₂/kg) | Isolation - Laine de roche | no | 1.437 | 2.5 | 0.040319 | 3.60752 | 1.71472 | 0.26912 | 0.129052 | 0.8 | 1000 | 1600 | 1.45 (MJ/kg) | 0.22 (kgCO₂/kg) | Finition int - Plaque de plâtre | no | Material Properties - Component 1: 2 with these values
Cloison Placostil 72/48 | Rez-de-chaussée | Cloison (Classification ARCHICAD) | Finition int - Plaque de plâtre (2), Isolation - Laine de roche | Non défini | 0.04 | 840 | 160 | 23.4 (MJ/kg) | 1.73 (kgCO₂/kg) | Isolation - Laine de roche | no | 3.852 | 2.5 | 0.21646 | 9.51 | 7.6172 | 0.7095 | 0.569433 | Material Properties - Component 3, Finition int - Plaque de plâtre, ThermalConductivity: 0.8; Component 3, Finition int - Plaque de plâtre, SpecificHeatCapacity: 1000 J/kg/K; Component 3, Finition int - Plaque de plâtre, MassDensity: 1600 kg/m3; Component 3, Finition int - Plaque de plâtre, Embodied Energy: 1.45 (MJ/kg); Component 3, Finition int - Plaque de plâtre, Embodied Carbon: 0.22 (kgCO₂/kg); Component 3, Finition int - Plaque de plâtre, Name: Finition int - Plaque de plâtre; Component 3, Finition int - Plaque de plâtre, Participates in Collision Detection: no; Component 3: 2 with these values
Cloison Placostil 72/48 | Rez-de-chaussée | Cloison (Classification ARCHICAD) | Finition int - Plaque de plâtre (2), Isolation - Laine de roche | Non défini | 0.04 | 840 | 160 | 23.4 (MJ/kg) | 1.73 (kgCO₂/kg) | Isolation - Laine de roche | no | 0.986834 | 2.5 | 0.00498871 | 2.45083 | 0.558035 | 0.180822 | 0.0407546 | Material Properties - Component 3, Finition int - Plaque de plâtre, ThermalConductivity: 0.8; Component 3, Finition int - Plaque de plâtre, SpecificHeatCapacity: 1000 J/kg/K; Component 3, Finition int - Plaque de plâtre, MassDensity: 1600 kg/m3; Component 3, Finition int - Plaque de plâtre, Embodied Energy: 1.45 (MJ/kg); Component 3, Finition int - Plaque de plâtre, Embodied Carbon: 0.22 (kgCO₂/kg); Component 3, Finition int - Plaque de plâtre, Name: Finition int - Plaque de plâtre; Component 3, Finition int - Plaque de plâtre, Participates in Collision Detection: no; Component 3: 2 with these values
Cloison Placostil 72/48 | Rez-de-chaussée | Cloison (Classification ARCHICAD) | Isolation - Laine de roche, Finition int - Plaque de plâtre | Non défini | 0.04 | 840 | 160 | 23.4 (MJ/kg) | 1.73 (kgCO₂/kg) | Isolation - Laine de roche | no | 0.986834 | 2.5 | 0.002041 | 2.15673 | 0.0671 | 0.173175 | 0.0048646 | 0.8 | 1000 | 1600 | 1.45 (MJ/kg) | 0.22 (kgCO₂/kg) | Finition int - Plaque de plâtre | no
Cloison Placostil 72/48 | Rez-de-chaussée | Cloison (Classification ARCHICAD) | Finition int - Plaque de plâtre (2), Isolation - Laine de roche | Non défini | 0.04 | 840 | 160 | 23.4 (MJ/kg) | 1.73 (kgCO₂/kg) | Isolation - Laine de roche | no | 1.078 | 2.5 | 0.074223 | 2.49375 | 2.49375 | 0.185557 | 0.185557 | Material Properties - Component 3, Finition int - Plaque de plâtre, ThermalConductivity: 0.8; Component 3, Finition int - Plaque de plâtre, SpecificHeatCapacity: 1000 J/kg/K; Component 3, Finition int - Plaque de plâtre, MassDensity: 1600 kg/m3; Component 3, Finition int - Plaque de plâtre, Embodied Energy: 1.45 (MJ/kg); Component 3, Finition int - Plaque de plâtre, Embodied Carbon: 0.22 (kgCO₂/kg); Component 3, Finition int - Plaque de plâtre, Name: Finition int - Plaque de plâtre; Component 3, Finition int - Plaque de plâtre, Participates in Collision Detection: no; Component 3: 2 with these values
Cloison Placostil 72/48 | Rez-de-chaussée | Cloison (Classification ARCHICAD) | Finition int - Plaque de plâtre (2), Isolation - Laine de roche | Non défini | 0.04 | 840 | 160 | 23.4 (MJ/kg) | 1.73 (kgCO₂/kg) | Isolation - Laine de roche | no | 0.55 | 2.5 | 0.03424 | 1.4 | 1.4 | 0.0856 | 0.0856 | 0.8 | 1000 | 1600 | 1.45 (MJ/kg) | 0.22 (kgCO₂/kg) | Finition int - Plaque de plâtre | no | Material Properties - Component 1: 2 with these values
Cloison Placostil 72/48 | Rez-de-chaussée | Cloison (Classification ARCHICAD) | Finition int - Plaque de plâtre (2), Isolation - Laine de roche | Non défini | 0.04 | 840 | 160 | 23.4 (MJ/kg) | 1.73 (kgCO₂/kg) | Isolation - Laine de roche | no | 1.438 | 2.5 | 0.041133 | 3.63625 | 1.74345 | 0.271183 | 0.131115 | Material Properties - Component 3, Finition int - Plaque de plâtre, ThermalConductivity: 0.8; Component 3, Finition int - Plaque de plâtre, SpecificHeatCapacity: 1000 J/kg/K; Component 3, Finition int - Plaque de plâtre, MassDensity: 1600 kg/m3; Component 3, Finition int - Plaque de plâtre, Embodied Energy: 1.45 (MJ/kg); Component 3, Finition int - Plaque de plâtre, Embodied Carbon: 0.22 (kgCO₂/kg); Component 3, Finition int - Plaque de plâtre, Name: Finition int - Plaque de plâtre; Component 3, Finition int - Plaque de plâtre, Participates in Collision Detection: no; Component 3: 2 with these values
Cloison Placostil 72/48 | Rez-de-chaussée | Cloison (Classification ARCHICAD) | Finition int - Plaque de plâtre (2), Isolation - Laine de roche | Non défini | 0.04 | 840 | 160 | 23.4 (MJ/kg) | 1.73 (kgCO₂/kg) | Isolation - Laine de roche | no | 0.537 | 2.5 | 0.041134 | 1.32625 | 1.32625 | 0.102835 | 0.102835 | 0.8 | 1000 | 1600 | 1.45 (MJ/kg) | 0.22 (kgCO₂/kg) | Finition int - Plaque de plâtre | no | Material Properties - Component 1: 2 with these values
Cloison Placostil 72/48 | Rez-de-chaussée | Cloison (Classification ARCHICAD) | Finition int - Plaque de plâtre (2), Isolation - Laine de roche | Non défini | 0.04 | 840 | 160 | 23.4 (MJ/kg) | 1.73 (kgCO₂/kg) | Isolation - Laine de roche | no | 1.474 | 2.5 | 0.111094 | 3.6575 | 3.6575 | 0.277735 | 0.277735 | 0.8 | 1000 | 1600 | 1.45 (MJ/kg) | 0.22 (kgCO₂/kg) | Finition int - Plaque de plâtre | no | Material Properties - Component 1: 2 with these values
Cloison Placostil 72/48 | Rez-de-chaussée | Cloison (Classification ARCHICAD) | Isolation - Laine de roche, Finition int - Plaque de plâtre | Non défini | 0.04 | 840 | 160 | 23.4 (MJ/kg) | 1.73 (kgCO₂/kg) | Isolation - Laine de roche | no | 1.064 | 2.5 | 0.010614 | 2.8775 | 0.2175 | 0.223375 | 0.026535 | 0.8 | 1000 | 1600 | 1.45 (MJ/kg) | 0.22 (kgCO₂/kg) | Finition int - Plaque de plâtre | no
Cloison Placostil 72/48 | Rez-de-chaussée | Cloison (Classification ARCHICAD) | Finition int - Plaque de plâtre (2), Isolation - Laine de roche | Non défini | 0.04 | 840 | 160 | 23.4 (MJ/kg) | 1.73 (kgCO₂/kg) | Isolation - Laine de roche | no | 0.324728 | 2.5 | 0.0213878 | 0.779319 | 0.779319 | 0.0534696 | 0.0534696 | Material Properties - Component 3, Finition int - Plaque de plâtre, ThermalConductivity: 0.8; Component 3, Finition int - Plaque de plâtre, SpecificHeatCapacity: 1000 J/kg/K; Component 3, Finition int - Plaque de plâtre, MassDensity: 1600 kg/m3; Component 3, Finition int - Plaque de plâtre, Embodied Energy: 1.45 (MJ/kg); Component 3, Finition int - Plaque de plâtre, Embodied Carbon: 0.22 (kgCO₂/kg); Component 3, Finition int - Plaque de plâtre, Name: Finition int - Plaque de plâtre; Component 3, Finition int - Plaque de plâtre, Participates in Collision Detection: no; Component 3: 2 with these values
Cloison Placostil 72/48 | Rez-de-chaussée | Cloison (Classification ARCHICAD) | Finition int - Plaque de plâtre (2), Isolation - Laine de roche | Non défini | 0.04 | 840 | 160 | 23.4 (MJ/kg) | 1.73 (kgCO₂/kg) | Isolation - Laine de roche | no | 0.789637 | 2.5 | 0.0583601 | 1.95784 | 1.95784 | 0.1459 | 0.1459 | Material Properties - Component 3, Finition int - Plaque de plâtre, ThermalConductivity: 0.8; Component 3, Finition int - Plaque de plâtre, SpecificHeatCapacity: 1000 J/kg/K; Component 3, Finition int - Plaque de plâtre, MassDensity: 1600 kg/m3; Component 3, Finition int - Plaque de plâtre, Embodied Energy: 1.45 (MJ/kg); Component 3, Finition int - Plaque de plâtre, Embodied Carbon: 0.22 (kgCO₂/kg); Component 3, Finition int - Plaque de plâtre, Name: Finition int - Plaque de plâtre; Component 3, Finition int - Plaque de plâtre, Participates in Collision Detection: no; Component 3: 2 with these values
Cloison Placostil 72/48 | Rez-de-chaussée | Cloison (Classification ARCHICAD) | Finition int - Plaque de plâtre (2), Isolation - Laine de roche | Non défini | 0.04 | 840 | 160 | 23.4 (MJ/kg) | 1.73 (kgCO₂/kg) | Isolation - Laine de roche | no | 1.437 | 2.5 | 0.040943 | 3.60875 | 1.71595 | 0.270707 | 0.13064 | Material Properties - Component 3, Finition int - Plaque de plâtre, ThermalConductivity: 0.8; Component 3, Finition int - Plaque de plâtre, SpecificHeatCapacity: 1000 J/kg/K; Component 3, Finition int - Plaque de plâtre, MassDensity: 1600 kg/m3; Component 3, Finition int - Plaque de plâtre, Embodied Energy: 1.45 (MJ/kg); Component 3, Finition int - Plaque de plâtre, Embodied Carbon: 0.22 (kgCO₂/kg); Component 3, Finition int - Plaque de plâtre, Name: Finition int - Plaque de plâtre; Component 3, Finition int - Plaque de plâtre, Participates in Collision Detection: no; Component 3: 2 with these values
Cloison Placostil 72/48 | Rez-de-chaussée | Cloison (Classification ARCHICAD) | Finition int - Plaque de plâtre (2), Isolation - Laine de roche | Non défini | 0.04 | 840 | 160 | 23.4 (MJ/kg) | 1.73 (kgCO₂/kg) | Isolation - Laine de roche | no | 2.67362 | 2.5 | 0.130508 | 6.62406 | 4.73126 | 0.494621 | 0.354553 | 0.8 | 1000 | 1600 | 1.45 (MJ/kg) | 0.22 (kgCO₂/kg) | Finition int - Plaque de plâtre | no | Material Properties - Component 1: 2 with these values
Cloison Placostil 72/48 | Rez-de-chaussée | Cloison (Classification ARCHICAD) | Finition int - Plaque de plâtre (2), Isolation - Laine de roche | Non défini | 0.04 | 840 | 160 | 23.4 (MJ/kg) | 1.73 (kgCO₂/kg) | Isolation - Laine de roche | no | 0.637 | 2.5 | 0.048459 | 1.54875 | 1.54875 | 0.121148 | 0.121148 | Material Properties - Component 3, Finition int - Plaque de plâtre, ThermalConductivity: 0.8; Component 3, Finition int - Plaque de plâtre, SpecificHeatCapacity: 1000 J/kg/K; Component 3, Finition int - Plaque de plâtre, MassDensity: 1600 kg/m3; Component 3, Finition int - Plaque de plâtre, Embodied Energy: 1.45 (MJ/kg); Component 3, Finition int - Plaque de plâtre, Embodied Carbon: 0.22 (kgCO₂/kg); Component 3, Finition int - Plaque de plâtre, Name: Finition int - Plaque de plâtre; Component 3, Finition int - Plaque de plâtre, Participates in Collision Detection: no; Component 3: 2 with these values
Cloison Placostil 72/48 | Rez-de-chaussée | Cloison (Classification ARCHICAD) | Finition int - Plaque de plâtre (2), Isolation - Laine de roche | Non défini | 0.04 | 840 | 160 | 23.4 (MJ/kg) | 1.73 (kgCO₂/kg) | Isolation - Laine de roche | no | 1.26173 | 2.5 | 0.0946889 | 3.11057 | 3.11057 | 0.236722 | 0.236722 | Material Properties - Component 3, Finition int - Plaque de plâtre, ThermalConductivity: 0.8; Component 3, Finition int - Plaque de plâtre, SpecificHeatCapacity: 1000 J/kg/K; Component 3, Finition int - Plaque de plâtre, MassDensity: 1600 kg/m3; Component 3, Finition int - Plaque de plâtre, Embodied Energy: 1.45 (MJ/kg); Component 3, Finition int - Plaque de plâtre, Embodied Carbon: 0.22 (kgCO₂/kg); Component 3, Finition int - Plaque de plâtre, Name: Finition int - Plaque de plâtre; Component 3, Finition int - Plaque de plâtre, Participates in Collision Detection: no; Component 3: 2 with these values
Cloison Placostil 72/48 | Rez-de-chaussée | Cloison (Classification ARCHICAD) | Finition int - Plaque de plâtre (2), Isolation - Laine de roche | Non défini | 0.04 | 840 | 160 | 23.4 (MJ/kg) | 1.73 (kgCO₂/kg) | Isolation - Laine de roche | no | 1.78228 | 2.5 | 0.0645484 | 4.39569 | 2.50289 | 0.329721 | 0.189654 | 0.8 | 1000 | 1600 | 1.45 (MJ/kg) | 0.22 (kgCO₂/kg) | Finition int - Plaque de plâtre | no | Material Properties - Component 1: 2 with these values
Cloison Placostil 72/48 | Rez-de-chaussée | Cloison (Classification ARCHICAD) | Finition int - Plaque de plâtre (2), Isolation - Laine de roche | Non défini | 0.04 | 840 | 160 | 23.4 (MJ/kg) | 1.73 (kgCO₂/kg) | Isolation - Laine de roche | no | 1.073 | 2.5 | 0.004683 | 2.69875 | 0.54387 | 0.203367 | 0.0439064 | Material Properties - Component 3, Finition int - Plaque de plâtre, ThermalConductivity: 0.8; Component 3, Finition int - Plaque de plâtre, SpecificHeatCapacity: 1000 J/kg/K; Component 3, Finition int - Plaque de plâtre, MassDensity: 1600 kg/m3; Component 3, Finition int - Plaque de plâtre, Embodied Energy: 1.45 (MJ/kg); Component 3, Finition int - Plaque de plâtre, Embodied Carbon: 0.22 (kgCO₂/kg); Component 3, Finition int - Plaque de plâtre, Name: Finition int - Plaque de plâtre; Component 3, Finition int - Plaque de plâtre, Participates in Collision Detection: no; Component 3: 2 with these values
Cloison Placostil 72/48 | Rez-de-chaussée | Cloison (Classification ARCHICAD) | Finition int - Plaque de plâtre (2), Isolation - Laine de roche | Non défini | 0.04 | 840 | 160 | 23.4 (MJ/kg) | 1.73 (kgCO₂/kg) | Isolation - Laine de roche | no | 1.247 | 2.5 | 0.096316 | 3.13375 | 3.13375 | 0.24079 | 0.24079 | 0.8 | 1000 | 1600 | 1.45 (MJ/kg) | 0.22 (kgCO₂/kg) | Finition int - Plaque de plâtre | no | Material Properties - Component 1: 2 with these values
Cloison Placostil 72/48 | Rez-de-chaussée | Cloison (Classification ARCHICAD) | Finition int - Plaque de plâtre (2), Isolation - Laine de roche | Non défini | 0.04 | 840 | 160 | 23.4 (MJ/kg) | 1.73 (kgCO₂/kg) | Isolation - Laine de roche | no | 3.52193 | 2.5 | 0.185999 | 8.51982 | 6.62702 | 0.633347 | 0.49328 | Material Properties - Component 3, Finition int - Plaque de plâtre, ThermalConductivity: 0.8; Component 3, Finition int - Plaque de plâtre, SpecificHeatCapacity: 1000 J/kg/K; Component 3, Finition int - Plaque de plâtre, MassDensity: 1600 kg/m3; Component 3, Finition int - Plaque de plâtre, Embodied Energy: 1.45 (MJ/kg); Component 3, Finition int - Plaque de plâtre, Embodied Carbon: 0.22 (kgCO₂/kg); Component 3, Finition int - Plaque de plâtre, Name: Finition int - Plaque de plâtre; Component 3, Finition int - Plaque de plâtre, Participates in Collision Detection: no; Component 3: 2 with these values
Cloison Placostil 72/48 | Rez-de-chaussée | Cloison (Classification ARCHICAD) | Finition int - Plaque de plâtre (2), Isolation - Laine de roche | Non défini | 0.04 | 840 | 160 | 23.4 (MJ/kg) | 1.73 (kgCO₂/kg) | Isolation - Laine de roche | no | 0.990997 | 2.5 | 0.00724179 | 2.47749 | 0.584693 | 0.186454 | 0.0463873 | 0.8 | 1000 | 1600 | 1.45 (MJ/kg) | 0.22 (kgCO₂/kg) | Finition int - Plaque de plâtre | no | Material Properties - Component 1: 2 with these values
Cloison Placostil 72/48 | Rez-de-chaussée | Cloison (Classification ARCHICAD) | Finition int - Plaque de plâtre (2), Isolation - Laine de roche | Non défini | 0.04 | 840 | 160 | 23.4 (MJ/kg) | 1.73 (kgCO₂/kg) | Isolation - Laine de roche | no | 1.387 | 2.5 | 0.026629 | 3.26625 | 1.37345 | 0.234923 | 0.0948553 | Material Properties - Component 3, Finition int - Plaque de plâtre, ThermalConductivity: 0.8; Component 3, Finition int - Plaque de plâtre, SpecificHeatCapacity: 1000 J/kg/K; Component 3, Finition int - Plaque de plâtre, MassDensity: 1600 kg/m3; Component 3, Finition int - Plaque de plâtre, Embodied Energy: 1.45 (MJ/kg); Component 3, Finition int - Plaque de plâtre, Embodied Carbon: 0.22 (kgCO₂/kg); Component 3, Finition int - Plaque de plâtre, Name: Finition int - Plaque de plâtre; Component 3, Finition int - Plaque de plâtre, Participates in Collision Detection: no; Component 3: 2 with these values
Cloison Placostil 72/48 | Rez-de-chaussée | Cloison (Classification ARCHICAD) | Finition int - Plaque de plâtre (2), Isolation - Laine de roche | Non défini | 0.04 | 840 | 160 | 23.4 (MJ/kg) | 1.73 (kgCO₂/kg) | Isolation - Laine de roche | no | 3.43314 | 2.5 | 0.15448 | 8.33785 | 5.67545 | 0.623001 | 0.425983 | 0.8 | 1000 | 1600 | 1.45 (MJ/kg) | 0.22 (kgCO₂/kg) | Finition int - Plaque de plâtre | no | Material Properties - Component 1: 2 with these values
Cloison Placostil 72/48 | Rez-de-chaussée | Cloison (Classification ARCHICAD) | Finition int - Plaque de plâtre (2), Isolation - Laine de roche | Non défini | 0.04 | 840 | 160 | 23.4 (MJ/kg) | 1.73 (kgCO₂/kg) | Isolation - Laine de roche | no | 0.637 | 2.5 | 0.051176 | 1.60875 | 1.60875 | 0.12794 | 0.12794 | 0.8 | 1000 | 1600 | 1.45 (MJ/kg) | 0.22 (kgCO₂/kg) | Finition int - Plaque de plâtre | no | Material Properties - Component 1: 2 with these values
Cloison Placostil 72/48 | Rez-de-chaussée | Cloison (Classification ARCHICAD) | Finition int - Plaque de plâtre (2), Isolation - Laine de roche | Non défini | 0.04 | 840 | 160 | 23.4 (MJ/kg) | 1.73 (kgCO₂/kg) | Isolation - Laine de roche | no | 1.02962 | 2.5 | 0.00620951 | 2.54154 | 0.648738 | 0.183874 | 0.0438066 | Material Properties - Component 3, Finition int - Plaque de plâtre, ThermalConductivity: 0.8; Component 3, Finition int - Plaque de plâtre, SpecificHeatCapacity: 1000 J/kg/K; Component 3, Finition int - Plaque de plâtre, MassDensity: 1600 kg/m3; Component 3, Finition int - Plaque de plâtre, Embodied Energy: 1.45 (MJ/kg); Component 3, Finition int - Plaque de plâtre, Embodied Carbon: 0.22 (kgCO₂/kg); Component 3, Finition int - Plaque de plâtre, Name: Finition int - Plaque de plâtre; Component 3, Finition int - Plaque de plâtre, Participates in Collision Detection: no; Component 3: 2 with these values
Cloison Placostil 72/48 | Rez-de-chaussée | Cloison (Classification ARCHICAD) | Finition int - Plaque de plâtre (2), Isolation - Laine de roche | Non défini | 0.04 | 840 | 160 | 23.4 (MJ/kg) | 1.73 (kgCO₂/kg) | Isolation - Laine de roche | no | 1.98415 | 2.5 | 0.150168 | 4.96037 | 4.96037 | 0.37542 | 0.37542 | Material Properties - Component 3, Finition int - Plaque de plâtre, ThermalConductivity: 0.8; Component 3, Finition int - Plaque de plâtre, SpecificHeatCapacity: 1000 J/kg/K; Component 3, Finition int - Plaque de plâtre, MassDensity: 1600 kg/m3; Component 3, Finition int - Plaque de plâtre, Embodied Energy: 1.45 (MJ/kg); Component 3, Finition int - Plaque de plâtre, Embodied Carbon: 0.22 (kgCO₂/kg); Component 3, Finition int - Plaque de plâtre, Name: Finition int - Plaque de plâtre; Component 3, Finition int - Plaque de plâtre, Participates in Collision Detection: no; Component 3: 2 with these values
Cloison Placostil 72/48 | Rez-de-chaussée | Cloison (Classification ARCHICAD) | Finition int - Plaque de plâtre (2), Isolation - Laine de roche | Non défini | 0.04 | 840 | 160 | 23.4 (MJ/kg) | 1.73 (kgCO₂/kg) | Isolation - Laine de roche | no | 2.67485 | 2.5 | 0.191976 | 6.41838 | 6.41838 | 0.47994 | 0.47994 | Material Properties - Component 3, Finition int - Plaque de plâtre, ThermalConductivity: 0.8; Component 3, Finition int - Plaque de plâtre, SpecificHeatCapacity: 1000 J/kg/K; Component 3, Finition int - Plaque de plâtre, MassDensity: 1600 kg/m3; Component 3, Finition int - Plaque de plâtre, Embodied Energy: 1.45 (MJ/kg); Component 3, Finition int - Plaque de plâtre, Embodied Carbon: 0.22 (kgCO₂/kg); Component 3, Finition int - Plaque de plâtre, Name: Finition int - Plaque de plâtre; Component 3, Finition int - Plaque de plâtre, Participates in Collision Detection: no; Component 3: 2 with these values
Cloison Placostil 72/48 | Rez-de-chaussée | Cloison (Classification ARCHICAD) | Finition int - Plaque de plâtre (2), Isolation - Laine de roche | Non défini | 0.04 | 840 | 160 | 23.4 (MJ/kg) | 1.73 (kgCO₂/kg) | Isolation - Laine de roche | no | 0.629589 | 2.5 | 0.0579436 | 1.80647 | 1.80647 | 0.144599 | 0.144599 | 0.8 | 1000 | 1600 | 1.45 (MJ/kg) | 0.22 (kgCO₂/kg) | Finition int - Plaque de plâtre | no | Material Properties - Component 1: 2 with these values
Cloison Placostil 72/48 | Rez-de-chaussée | Cloison (Classification ARCHICAD) | Finition int - Plaque de plâtre (2), Isolation - Laine de roche | Non défini | 0.04 | 840 | 160 | 23.4 (MJ/kg) | 1.73 (kgCO₂/kg) | Isolation - Laine de roche | no | 0.621367 | 2.5 | 0.0459081 | 1.53717 | 1.53717 | 0.11477 | 0.11477 | Material Properties - Component 3, Finition int - Plaque de plâtre, ThermalConductivity: 0.8; Component 3, Finition int - Plaque de plâtre, SpecificHeatCapacity: 1000 J/kg/K; Component 3, Finition int - Plaque de plâtre, MassDensity: 1600 kg/m3; Component 3, Finition int - Plaque de plâtre, Embodied Energy: 1.45 (MJ/kg); Component 3, Finition int - Plaque de plâtre, Embodied Carbon: 0.22 (kgCO₂/kg); Component 3, Finition int - Plaque de plâtre, Name: Finition int - Plaque de plâtre; Component 3, Finition int - Plaque de plâtre, Participates in Collision Detection: no; Component 3: 2 with these values
Cloison Placostil 72/48 | Rez-de-chaussée | Cloison (Classification ARCHICAD) | Finition int - Plaque de plâtre (2), Isolation - Laine de roche | Non défini | 0.04 | 840 | 160 | 23.4 (MJ/kg) | 1.73 (kgCO₂/kg) | Isolation - Laine de roche | no | 0.524 | 2.5 | 0.037429 | 1.29125 | 1.29125 | 0.0935725 | 0.0935725 | 0.8 | 1000 | 1600 | 1.45 (MJ/kg) | 0.22 (kgCO₂/kg) | Finition int - Plaque de plâtre | no | Material Properties - Component 1: 2 with these values
Cloison Placostil 72/48 | Rez-de-chaussée | Cloison (Classification ARCHICAD) | Finition int - Plaque de plâtre (2), Isolation - Laine de roche | Non défini | 0.04 | 840 | 160 | 23.4 (MJ/kg) | 1.73 (kgCO₂/kg) | Isolation - Laine de roche | no | 0.687 | 2.5 | 0.049633 | 1.66625 | 1.66625 | 0.124083 | 0.124083 | 0.8 | 1000 | 1600 | 1.45 (MJ/kg) | 0.22 (kgCO₂/kg) | Finition int - Plaque de plâtre | no | Material Properties - Component 1: 2 with these values
Cloison Placostil 72/48 | R+1 | Mur (Classification ARCHICAD); Cloison (Classification ARCHICAD) | Finition int - Plaque de plâtre (2), Isolation - Laine de roche | Non défini | 0.04 | 840 | 160 | 23.4 (MJ/kg) | 1.73 (kgCO₂/kg) | Isolation - Laine de roche | no | 1.45 | 2.5 | 0.000624 | 3.625 | 0.609 | 0.26981 | 0.046626 | Material Properties - Component 3, Finition int - Plaque de plâtre, ThermalConductivity: 0.8; Component 3, Finition int - Plaque de plâtre, SpecificHeatCapacity: 1000 J/kg/K; Component 3, Finition int - Plaque de plâtre, MassDensity: 1600 kg/m3; Component 3, Finition int - Plaque de plâtre, Embodied Energy: 1.45 (MJ/kg); Component 3, Finition int - Plaque de plâtre, Embodied Carbon: 0.22 (kgCO₂/kg); Component 3, Finition int - Plaque de plâtre, Name: Finition int - Plaque de plâtre; Component 3, Finition int - Plaque de plâtre, Participates in Collision Detection: no; Component 3: 2 with these values
Cloison Placostil 72/48 | R+1 | Mur (Classification ARCHICAD); Cloison (Classification ARCHICAD) | Finition int - Plaque de plâtre (2), Isolation - Laine de roche | Non défini | 0.04 | 840 | 160 | 23.4 (MJ/kg) | 1.73 (kgCO₂/kg) | Isolation - Laine de roche | no | 2.09955 | 2.5 | 0.0886509 | 5.24888 | 3.35608 | 0.389977 | 0.24991 | 0.8 | 1000 | 1600 | 1.45 (MJ/kg) | 0.22 (kgCO₂/kg) | Finition int - Plaque de plâtre | no | Material Properties - Component 1: 2 with these values
Cloison Placostil 72/48 | R+1 | Mur (Classification ARCHICAD); Cloison (Classification ARCHICAD) | Finition int - Plaque de plâtre (2), Isolation - Laine de roche | Non défini | 0.04 | 840 | 160 | 23.4 (MJ/kg) | 1.73 (kgCO₂/kg) | Isolation - Laine de roche | no | 0.6 | 2.5 | 0.045648 | 1.5 | 1.5 | 0.11412 | 0.11412 | Material Properties - Component 3, Finition int - Plaque de plâtre, ThermalConductivity: 0.8; Component 3, Finition int - Plaque de plâtre, SpecificHeatCapacity: 1000 J/kg/K; Component 3, Finition int - Plaque de plâtre, MassDensity: 1600 kg/m3; Component 3, Finition int - Plaque de plâtre, Embodied Energy: 1.45 (MJ/kg); Component 3, Finition int - Plaque de plâtre, Embodied Carbon: 0.22 (kgCO₂/kg); Component 3, Finition int - Plaque de plâtre, Name: Finition int - Plaque de plâtre; Component 3, Finition int - Plaque de plâtre, Participates in Collision Detection: no; Component 3: 2 with these values
Cloison Placostil 72/48 | R+1 | Mur (Classification ARCHICAD); Cloison (Classification ARCHICAD) | Finition int - Plaque de plâtre (2), Isolation - Laine de roche | Non défini | 0.04 | 840 | 160 | 23.4 (MJ/kg) | 1.73 (kgCO₂/kg) | Isolation - Laine de roche | no | 0.694 | 2.5 | 0.051356 | 1.735 | 1.735 | 0.12839 | 0.12839 | Material Properties - Component 3, Finition int - Plaque de plâtre, ThermalConductivity: 0.8; Component 3, Finition int - Plaque de plâtre, SpecificHeatCapacity: 1000 J/kg/K; Component 3, Finition int - Plaque de plâtre, MassDensity: 1600 kg/m3; Component 3, Finition int - Plaque de plâtre, Embodied Energy: 1.45 (MJ/kg); Component 3, Finition int - Plaque de plâtre, Embodied Carbon: 0.22 (kgCO₂/kg); Component 3, Finition int - Plaque de plâtre, Name: Finition int - Plaque de plâtre; Component 3, Finition int - Plaque de plâtre, Participates in Collision Detection: no; Component 3: 2 with these values
Cloison Placostil 72/48 | R+1 | Mur (Classification ARCHICAD); Cloison (Classification ARCHICAD) | Finition int - Plaque de plâtre (2), Isolation - Laine de roche | Non défini | 0.04 | 840 | 160 | 23.4 (MJ/kg) | 1.73 (kgCO₂/kg) | Isolation - Laine de roche | no | 3.40917 | 2.5 | 0.252279 | 8.46292 | 8.46292 | 0.630696 | 0.630696 | 0.8 | 1000 | 1600 | 1.45 (MJ/kg) | 0.22 (kgCO₂/kg) | Finition int - Plaque de plâtre | no | Material Properties - Component 1: 2 with these values
Cloison Placostil 72/48 | R+1 | Mur (Classification ARCHICAD); Cloison (Classification ARCHICAD) | Finition int - Plaque de plâtre (2), Isolation - Laine de roche | Non défini | 0.04 | 840 | 160 | 23.4 (MJ/kg) | 1.73 (kgCO₂/kg) | Isolation - Laine de roche | no | 0.361 | 2.5 | 0.027411 | 0.85875 | 0.85875 | 0.0685275 | 0.0685275 | Material Properties - Component 3, Finition int - Plaque de plâtre, ThermalConductivity: 0.8; Component 3, Finition int - Plaque de plâtre, SpecificHeatCapacity: 1000 J/kg/K; Component 3, Finition int - Plaque de plâtre, MassDensity: 1600 kg/m3; Component 3, Finition int - Plaque de plâtre, Embodied Energy: 1.45 (MJ/kg); Component 3, Finition int - Plaque de plâtre, Embodied Carbon: 0.22 (kgCO₂/kg); Component 3, Finition int - Plaque de plâtre, Name: Finition int - Plaque de plâtre; Component 3, Finition int - Plaque de plâtre, Participates in Collision Detection: no; Component 3: 2 with these values
Cloison Placostil 72/48 | R+1 | Mur (Classification ARCHICAD); Cloison (Classification ARCHICAD) | Finition int - Plaque de plâtre (2), Isolation - Laine de roche | Non défini | 0.04 | 840 | 160 | 23.4 (MJ/kg) | 1.73 (kgCO₂/kg) | Isolation - Laine de roche | no | 0.966221 | 2.5 | 0.00478435 | 2.41555 | 0.522753 | 0.180311 | 0.0402437 | 0.8 | 1000 | 1600 | 1.45 (MJ/kg) | 0.22 (kgCO₂/kg) | Finition int - Plaque de plâtre | no | Material Properties - Component 1: 2 with these values
Cloison Placostil 72/48 | R+1 | Mur (Classification ARCHICAD); Cloison (Classification ARCHICAD) | Finition int - Plaque de plâtre (2), Isolation - Laine de roche | Non défini | 0.04 | 840 | 160 | 23.4 (MJ/kg) | 1.73 (kgCO₂/kg) | Isolation - Laine de roche | no | 0.637 | 2.5 | 0.046441 | 1.57625 | 1.57625 | 0.116102 | 0.116102 | Material Properties - Component 3, Finition int - Plaque de plâtre, ThermalConductivity: 0.8; Component 3, Finition int - Plaque de plâtre, SpecificHeatCapacity: 1000 J/kg/K; Component 3, Finition int - Plaque de plâtre, MassDensity: 1600 kg/m3; Component 3, Finition int - Plaque de plâtre, Embodied Energy: 1.45 (MJ/kg); Component 3, Finition int - Plaque de plâtre, Embodied Carbon: 0.22 (kgCO₂/kg); Component 3, Finition int - Plaque de plâtre, Name: Finition int - Plaque de plâtre; Component 3, Finition int - Plaque de plâtre, Participates in Collision Detection: no; Component 3: 2 with these values
Cloison Placostil 72/48 | R+1 | Mur (Classification ARCHICAD); Cloison (Classification ARCHICAD) | Finition int - Plaque de plâtre (2), Isolation - Laine de roche | Non défini | 0.04 | 840 | 160 | 23.4 (MJ/kg) | 1.73 (kgCO₂/kg) | Isolation - Laine de roche | no | 1.387 | 2.5 | 0.101941 | 3.45125 | 3.45125 | 0.254852 | 0.254852 | Material Properties - Component 3, Finition int - Plaque de plâtre, ThermalConductivity: 0.8; Component 3, Finition int - Plaque de plâtre, SpecificHeatCapacity: 1000 J/kg/K; Component 3, Finition int - Plaque de plâtre, MassDensity: 1600 kg/m3; Component 3, Finition int - Plaque de plâtre, Embodied Energy: 1.45 (MJ/kg); Component 3, Finition int - Plaque de plâtre, Embodied Carbon: 0.22 (kgCO₂/kg); Component 3, Finition int - Plaque de plâtre, Name: Finition int - Plaque de plâtre; Component 3, Finition int - Plaque de plâtre, Participates in Collision Detection: no; Component 3: 2 with these values
Cloison Placostil 72/48 | R+1 | Mur (Classification ARCHICAD); Cloison (Classification ARCHICAD) | Finition int - Plaque de plâtre (2), Isolation - Laine de roche | Non défini | 0.04 | 840 | 160 | 23.4 (MJ/kg) | 1.73 (kgCO₂/kg) | Isolation - Laine de roche | no | 0.638 | 2.5 | 0.049273 | 1.63625 | 1.63625 | 0.123183 | 0.123183 | 0.8 | 1000 | 1600 | 1.45 (MJ/kg) | 0.22 (kgCO₂/kg) | Finition int - Plaque de plâtre | no | Material Properties - Component 1: 2 with these values
Cloison Placostil 72/48 | R+1 | Mur (Classification ARCHICAD); Cloison (Classification ARCHICAD) | Finition int - Plaque de plâtre (2), Isolation - Laine de roche | Non défini | 0.04 | 840 | 160 | 23.4 (MJ/kg) | 1.73 (kgCO₂/kg) | Isolation - Laine de roche | no | 0.32501 | 2.5 | 0.0240507 | 0.812525 | 0.812525 | 0.0601268 | 0.0601268 | 0.8 | 1000 | 1600 | 1.45 (MJ/kg) | 0.22 (kgCO₂/kg) | Finition int - Plaque de plâtre | no | Material Properties - Component 1: 2 with these values
Cloison Placostil 72/48 | R+1 | Mur (Classification ARCHICAD); Cloison (Classification ARCHICAD) | Finition int - Plaque de plâtre (2), Isolation - Laine de roche | Non défini | 0.04 | 840 | 160 | 23.4 (MJ/kg) | 1.73 (kgCO₂/kg) | Isolation - Laine de roche | no | 0.638 | 2.5 | 0.046631 | 1.60375 | 1.60375 | 0.116577 | 0.116577 | 0.8 | 1000 | 1600 | 1.45 (MJ/kg) | 0.22 (kgCO₂/kg) | Finition int - Plaque de plâtre | no | Material Properties - Component 1: 2 with these values
Cloison Placostil 72/48 | R+1 | Mur (Classification ARCHICAD); Cloison (Classification ARCHICAD) | Finition int - Plaque de plâtre (2), Isolation - Laine de roche | Non défini | 0.04 | 840 | 160 | 23.4 (MJ/kg) | 1.73 (kgCO₂/kg) | Isolation - Laine de roche | no | 0.287 | 2.5 | 0.020541 | 0.70125 | 0.70125 | 0.0513525 | 0.0513525 | 0.8 | 1000 | 1600 | 1.45 (MJ/kg) | 0.22 (kgCO₂/kg) | Finition int - Plaque de plâtre | no | Material Properties - Component 1: 2 with these values
Cloison Placostil 72/48 | R+1 | Mur (Classification ARCHICAD); Cloison (Classification ARCHICAD) | Finition int - Plaque de plâtre (2), Isolation - Laine de roche | Non défini | 0.04 | 840 | 160 | 23.4 (MJ/kg) | 1.73 (kgCO₂/kg) | Isolation - Laine de roche | no | 1.35037 | 2.5 | 0.101291 | 3.40092 | 3.40092 | 0.253228 | 0.253228 | Material Properties - Component 3, Finition int - Plaque de plâtre, ThermalConductivity: 0.8; Component 3, Finition int - Plaque de plâtre, SpecificHeatCapacity: 1000 J/kg/K; Component 3, Finition int - Plaque de plâtre, MassDensity: 1600 kg/m3; Component 3, Finition int - Plaque de plâtre, Embodied Energy: 1.45 (MJ/kg); Component 3, Finition int - Plaque de plâtre, Embodied Carbon: 0.22 (kgCO₂/kg); Component 3, Finition int - Plaque de plâtre, Name: Finition int - Plaque de plâtre; Component 3, Finition int - Plaque de plâtre, Participates in Collision Detection: no; Component 3: 2 with these values
Cloison Placostil 72/48 | R+1 | Mur (Classification ARCHICAD); Cloison (Classification ARCHICAD) | Finition int - Plaque de plâtre (2), Isolation - Laine de roche | Non défini | 0.04 | 840 | 160 | 23.4 (MJ/kg) | 1.73 (kgCO₂/kg) | Isolation - Laine de roche | no | 1.387 | 2.5 | 0.004059 | 3.48375 | 0.10875 | 0.259897 | 0.0101475 | Material Properties - Component 3, Finition int - Plaque de plâtre, ThermalConductivity: 0.8; Component 3, Finition int - Plaque de plâtre, SpecificHeatCapacity: 1000 J/kg/K; Component 3, Finition int - Plaque de plâtre, MassDensity: 1600 kg/m3; Component 3, Finition int - Plaque de plâtre, Embodied Energy: 1.45 (MJ/kg); Component 3, Finition int - Plaque de plâtre, Embodied Carbon: 0.22 (kgCO₂/kg); Component 3, Finition int - Plaque de plâtre, Name: Finition int - Plaque de plâtre; Component 3, Finition int - Plaque de plâtre, Participates in Collision Detection: no; Component 3: 2 with these values
Cloison Placostil 72/48 | R+1 | Mur (Classification ARCHICAD); Cloison (Classification ARCHICAD) | Finition int - Plaque de plâtre, Isolation - Laine de roche | Non défini | 0.04 | 840 | 160 | 23.4 (MJ/kg) | 1.73 (kgCO₂/kg) | Isolation - Laine de roche | no | 1.237 | 2.5 | 0.001417 | 2.71625 | 0.07625 | 0.216182 | 0.0035425 | 0.8 | 1000 | 1600 | 1.45 (MJ/kg) | 0.22 (kgCO₂/kg) | Finition int - Plaque de plâtre | no
Cloison Placostil 72/48 | R+1 | Mur (Classification ARCHICAD); Cloison (Classification ARCHICAD) | Finition int - Plaque de plâtre (2), Isolation - Laine de roche | Non défini | 0.04 | 840 | 160 | 23.4 (MJ/kg) | 1.73 (kgCO₂/kg) | Isolation - Laine de roche | no | 3.19975 | 2.5 | 0.001734 | 7.99938 | 0.0375 | 0.593514 | 0.004335 | 0.8 | 1000 | 1600 | 1.45 (MJ/kg) | 0.22 (kgCO₂/kg) | Finition int - Plaque de plâtre | no | Material Properties - Component 1: 2 with these values
Cloison Placostil 72/48 | R+1 | Mur (Classification ARCHICAD); Cloison (Classification ARCHICAD) | Finition int - Plaque de plâtre (2), Isolation - Laine de roche | Non défini | 0.04 | 840 | 160 | 23.4 (MJ/kg) | 1.73 (kgCO₂/kg) | Isolation - Laine de roche | no | 0.477635 | 2.5 | 0.0340771 | 1.17082 | 1.17082 | 0.0851929 | 0.0851929 | 0.8 | 1000 | 1600 | 1.45 (MJ/kg) | 0.22 (kgCO₂/kg) | Finition int - Plaque de plâtre | no | Material Properties - Component 1: 2 with these values
Cloison Placostil 72/48 | R+1 | Mur (Classification ARCHICAD); Cloison (Classification ARCHICAD) | Finition int - Plaque de plâtre (2), Isolation - Laine de roche | Non défini | 0.04 | 840 | 160 | 23.4 (MJ/kg) | 1.73 (kgCO₂/kg) | Isolation - Laine de roche | no | 0.7 | 2.5 | 0.054442 | 1.7825 | 1.7825 | 0.136105 | 0.136105 | 0.8 | 1000 | 1600 | 1.45 (MJ/kg) | 0.22 (kgCO₂/kg) | Finition int - Plaque de plâtre | no | Material Properties - Component 1: 2 with these values
Cloison Placostil 72/48 | R+1 | Mur (Classification ARCHICAD); Cloison (Classification ARCHICAD) | Finition int - Plaque de plâtre (2), Isolation - Laine de roche | Non défini | 0.04 | 840 | 160 | 23.4 (MJ/kg) | 1.73 (kgCO₂/kg) | Isolation - Laine de roche | no | 2.17161 | 2.5 | 0.1625 | 5.44527 | 5.44527 | 0.40625 | 0.40625 | Material Properties - Component 3, Finition int - Plaque de plâtre, ThermalConductivity: 0.8; Component 3, Finition int - Plaque de plâtre, SpecificHeatCapacity: 1000 J/kg/K; Component 3, Finition int - Plaque de plâtre, MassDensity: 1600 kg/m3; Component 3, Finition int - Plaque de plâtre, Embodied Energy: 1.45 (MJ/kg); Component 3, Finition int - Plaque de plâtre, Embodied Carbon: 0.22 (kgCO₂/kg); Component 3, Finition int - Plaque de plâtre, Name: Finition int - Plaque de plâtre; Component 3, Finition int - Plaque de plâtre, Participates in Collision Detection: no; Component 3: 2 with these values
Cloison Placostil 72/48 | R+1 | Mur (Classification ARCHICAD); Cloison (Classification ARCHICAD) | Finition int - Plaque de plâtre (2), Isolation - Laine de roche | Non défini | 0.04 | 840 | 160 | 23.4 (MJ/kg) | 1.73 (kgCO₂/kg) | Isolation - Laine de roche | no | 1.57217 | 2.5 | 0.113698 | 3.89792 | 3.89792 | 0.284246 | 0.284246 | Material Properties - Component 3, Finition int - Plaque de plâtre, ThermalConductivity: 0.8; Component 3, Finition int - Plaque de plâtre, SpecificHeatCapacity: 1000 J/kg/K; Component 3, Finition int - Plaque de plâtre, MassDensity: 1600 kg/m3; Component 3, Finition int - Plaque de plâtre, Embodied Energy: 1.45 (MJ/kg); Component 3, Finition int - Plaque de plâtre, Embodied Carbon: 0.22 (kgCO₂/kg); Component 3, Finition int - Plaque de plâtre, Name: Finition int - Plaque de plâtre; Component 3, Finition int - Plaque de plâtre, Participates in Collision Detection: no; Component 3: 2 with these values
Cloison Placostil 72/48 | R+1 | Mur (Classification ARCHICAD); Cloison (Classification ARCHICAD) | Finition int - Plaque de plâtre (2), Isolation - Laine de roche | Non défini | 0.04 | 840 | 160 | 23.4 (MJ/kg) | 1.73 (kgCO₂/kg) | Isolation - Laine de roche | no | 2.18055 | 2.5 | 0.158719 | 5.41888 | 5.41888 | 0.396797 | 0.396797 | 0.8 | 1000 | 1600 | 1.45 (MJ/kg) | 0.22 (kgCO₂/kg) | Finition int - Plaque de plâtre | no | Material Properties - Component 1: 2 with these values
Cloison Placostil 72/48 | R+1 | Mur (Classification ARCHICAD); Cloison (Classification ARCHICAD) | Finition int - Plaque de plâtre (2), Isolation - Laine de roche | Non défini | 0.04 | 840 | 160 | 23.4 (MJ/kg) | 1.73 (kgCO₂/kg) | Isolation - Laine de roche | no | 0.327 | 2.5 | 0.026143 | 0.83375 | 0.83375 | 0.065356 | 0.065356 | Material Properties - Component 3, Finition int - Plaque de plâtre, ThermalConductivity: 0.8; Component 3, Finition int - Plaque de plâtre, SpecificHeatCapacity: 1000 J/kg/K; Component 3, Finition int - Plaque de plâtre, MassDensity: 1600 kg/m3; Component 3, Finition int - Plaque de plâtre, Embodied Energy: 1.45 (MJ/kg); Component 3, Finition int - Plaque de plâtre, Embodied Carbon: 0.22 (kgCO₂/kg); Component 3, Finition int - Plaque de plâtre, Name: Finition int - Plaque de plâtre; Component 3, Finition int - Plaque de plâtre, Participates in Collision Detection: no; Component 3: 2 with these values
Cloison Placostil 72/48 | R+1 | Mur (Classification ARCHICAD); Cloison (Classification ARCHICAD) | Finition int - Plaque de plâtre (2), Isolation - Laine de roche | Non défini | 0.04 | 840 | 160 | 23.4 (MJ/kg) | 1.73 (kgCO₂/kg) | Isolation - Laine de roche | no | 0.674 | 2.5 | 0.049876 | 1.685 | 1.685 | 0.12469 | 0.12469 | 0.8 | 1000 | 1600 | 1.45 (MJ/kg) | 0.22 (kgCO₂/kg) | Finition int - Plaque de plâtre | no | Material Properties - Component 1: 2 with these values
Cloison Placostil 72/48 | R+1 | Mur (Classification ARCHICAD); Cloison (Classification ARCHICAD) | Finition int - Plaque de plâtre (2), Isolation - Laine de roche | Non défini | 0.04 | 840 | 160 | 23.4 (MJ/kg) | 1.73 (kgCO₂/kg) | Isolation - Laine de roche | no | 0.7 | 2.5 | 0.054442 | 1.7825 | 1.7825 | 0.136105 | 0.136105 | Material Properties - Component 3, Finition int - Plaque de plâtre, ThermalConductivity: 0.8; Component 3, Finition int - Plaque de plâtre, SpecificHeatCapacity: 1000 J/kg/K; Component 3, Finition int - Plaque de plâtre, MassDensity: 1600 kg/m3; Component 3, Finition int - Plaque de plâtre, Embodied Energy: 1.45 (MJ/kg); Component 3, Finition int - Plaque de plâtre, Embodied Carbon: 0.22 (kgCO₂/kg); Component 3, Finition int - Plaque de plâtre, Name: Finition int - Plaque de plâtre; Component 3, Finition int - Plaque de plâtre, Participates in Collision Detection: no; Component 3: 2 with these values
Cloison Placostil 72/48 | R+1 | Mur (Classification ARCHICAD); Cloison (Classification ARCHICAD) | Finition int - Plaque de plâtre (2), Isolation - Laine de roche | Non défini | 0.04 | 840 | 160 | 23.4 (MJ/kg) | 1.73 (kgCO₂/kg) | Isolation - Laine de roche | no | 1.05755 | 2.5 | 0.0809007 | 2.67638 | 2.67638 | 0.202252 | 0.202252 | 0.8 | 1000 | 1600 | 1.45 (MJ/kg) | 0.22 (kgCO₂/kg) | Finition int - Plaque de plâtre | no | Material Properties - Component 1: 2 with these values
Cloison Placostil 72/48 | R+1 | Mur (Classification ARCHICAD); Cloison (Classification ARCHICAD) | Isolation - Laine de roche | Non défini |  |  |  |  |  |  |  | 2.125 | 2.5 | 0.000624 | 5.3125 | 0 | 0.394685 | 0.00156 | Material Properties - Isolation - Laine de roche, ThermalConductivity: 0.04; Isolation - Laine de roche, SpecificHeatCapacity: 840 J/kg/K; Isolation - Laine de roche, MassDensity: 160 kg/m3; Isolation - Laine de roche, Embodied Energy: 23.4 (MJ/kg); Isolation - Laine de roche, Embodied Carbon: 1.73 (kgCO₂/kg); Isolation - Laine de roche, Name: Isolation - Laine de roche; Isolation - Laine de roche, Participates in Collision Detection: no
Cloison Placostil 72/48 | R+1 | Mur (Classification ARCHICAD); Cloison (Classification ARCHICAD) | Finition int - Plaque de plâtre (2), Isolation - Laine de roche | Non défini | 0.04 | 840 | 160 | 23.4 (MJ/kg) | 1.73 (kgCO₂/kg) | Isolation - Laine de roche | no | 0.913 | 2.5 | 0.06492 | 2.25 | 2.25 | 0.1623 | 0.1623 | Material Properties - Component 3, Finition int - Plaque de plâtre, ThermalConductivity: 0.8; Component 3, Finition int - Plaque de plâtre, SpecificHeatCapacity: 1000 J/kg/K; Component 3, Finition int - Plaque de plâtre, MassDensity: 1600 kg/m3; Component 3, Finition int - Plaque de plâtre, Embodied Energy: 1.45 (MJ/kg); Component 3, Finition int - Plaque de plâtre, Embodied Carbon: 0.22 (kgCO₂/kg); Component 3, Finition int - Plaque de plâtre, Name: Finition int - Plaque de plâtre; Component 3, Finition int - Plaque de plâtre, Participates in Collision Detection: no; Component 3: 2 with these values
Cloison Placostil 72/48 | R+1 | Mur (Classification ARCHICAD); Cloison (Classification ARCHICAD) | Finition int - Plaque de plâtre (2), Isolation - Laine de roche | Non défini | 0.04 | 840 | 160 | 23.4 (MJ/kg) | 1.73 (kgCO₂/kg) | Isolation - Laine de roche | no | 0.637 | 2.47 | 0.045193 | 1.49805 | 1.49805 | 0.111627 | 0.111627 | Material Properties - Component 3, Finition int - Plaque de plâtre, ThermalConductivity: 0.8; Component 3, Finition int - Plaque de plâtre, SpecificHeatCapacity: 1000 J/kg/K; Component 3, Finition int - Plaque de plâtre, MassDensity: 1600 kg/m3; Component 3, Finition int - Plaque de plâtre, Embodied Energy: 1.45 (MJ/kg); Component 3, Finition int - Plaque de plâtre, Embodied Carbon: 0.22 (kgCO₂/kg); Component 3, Finition int - Plaque de plâtre, Name: Finition int - Plaque de plâtre; Component 3, Finition int - Plaque de plâtre, Participates in Collision Detection: no; Component 3: 2 with these values
Cloison Placostil 72/48 | R+1 | Mur (Classification ARCHICAD); Cloison (Classification ARCHICAD) | Finition int - Plaque de plâtre (2), Isolation - Laine de roche | Non défini | 0.04 | 840 | 160 | 23.4 (MJ/kg) | 1.73 (kgCO₂/kg) | Isolation - Laine de roche | no | 0.387 | 2.5 | 0.029262 | 0.9675 | 0.9675 | 0.073155 | 0.073155 | Material Properties - Component 3, Finition int - Plaque de plâtre, ThermalConductivity: 0.8; Component 3, Finition int - Plaque de plâtre, SpecificHeatCapacity: 1000 J/kg/K; Component 3, Finition int - Plaque de plâtre, MassDensity: 1600 kg/m3; Component 3, Finition int - Plaque de plâtre, Embodied Energy: 1.45 (MJ/kg); Component 3, Finition int - Plaque de plâtre, Embodied Carbon: 0.22 (kgCO₂/kg); Component 3, Finition int - Plaque de plâtre, Name: Finition int - Plaque de plâtre; Component 3, Finition int - Plaque de plâtre, Participates in Collision Detection: no; Component 3: 2 with these values
Cloison Placostil 72/48 | R+1 | Mur (Classification ARCHICAD); Cloison (Classification ARCHICAD) | Finition int - Plaque de plâtre (2), Isolation - Laine de roche | Non défini | 0.04 | 840 | 160 | 23.4 (MJ/kg) | 1.73 (kgCO₂/kg) | Isolation - Laine de roche | no | 0.483901 | 2.49 | 0.0384507 | 1.23728 | 1.23728 | 0.0957421 | 0.0957421 | Material Properties - Component 3, Finition int - Plaque de plâtre, ThermalConductivity: 0.8; Component 3, Finition int - Plaque de plâtre, SpecificHeatCapacity: 1000 J/kg/K; Component 3, Finition int - Plaque de plâtre, MassDensity: 1600 kg/m3; Component 3, Finition int - Plaque de plâtre, Embodied Energy: 1.45 (MJ/kg); Component 3, Finition int - Plaque de plâtre, Embodied Carbon: 0.22 (kgCO₂/kg); Component 3, Finition int - Plaque de plâtre, Name: Finition int - Plaque de plâtre; Component 3, Finition int - Plaque de plâtre, Participates in Collision Detection: no; Component 3: 2 with these values
Cloison Placostil 72/48 | R+1 | Mur (Classification ARCHICAD); Cloison (Classification ARCHICAD) | Finition int - Plaque de plâtre (2), Isolation - Laine de roche | Non défini | 0.04 | 840 | 160 | 23.4 (MJ/kg) | 1.73 (kgCO₂/kg) | Isolation - Laine de roche | no | 0.286541 | 2.49 | 0.020507 | 0.697301 | 0.697301 | 0.0510625 | 0.0510625 | Material Properties - Component 3, Finition int - Plaque de plâtre, ThermalConductivity: 0.8; Component 3, Finition int - Plaque de plâtre, SpecificHeatCapacity: 1000 J/kg/K; Component 3, Finition int - Plaque de plâtre, MassDensity: 1600 kg/m3; Component 3, Finition int - Plaque de plâtre, Embodied Energy: 1.45 (MJ/kg); Component 3, Finition int - Plaque de plâtre, Embodied Carbon: 0.22 (kgCO₂/kg); Component 3, Finition int - Plaque de plâtre, Name: Finition int - Plaque de plâtre; Component 3, Finition int - Plaque de plâtre, Participates in Collision Detection: no; Component 3: 2 with these values
Cloison Placostil 72/48 | R+1 | Mur (Classification ARCHICAD); Cloison (Classification ARCHICAD) | Finition int - Plaque de plâtre (2), Isolation - Laine de roche | Non défini | 0.04 | 840 | 160 | 23.4 (MJ/kg) | 1.73 (kgCO₂/kg) | Isolation - Laine de roche | no | 1.437 | 2.49 | 0.001417 | 3.56195 | 0.649945 | 0.261492 | 0.0460043 | Material Properties - Component 3, Finition int - Plaque de plâtre, ThermalConductivity: 0.8; Component 3, Finition int - Plaque de plâtre, SpecificHeatCapacity: 1000 J/kg/K; Component 3, Finition int - Plaque de plâtre, MassDensity: 1600 kg/m3; Component 3, Finition int - Plaque de plâtre, Embodied Energy: 1.45 (MJ/kg); Component 3, Finition int - Plaque de plâtre, Embodied Carbon: 0.22 (kgCO₂/kg); Component 3, Finition int - Plaque de plâtre, Name: Finition int - Plaque de plâtre; Component 3, Finition int - Plaque de plâtre, Participates in Collision Detection: no; Component 3: 2 with these values
Cloison Placostil 72/48 | R+1 | Mur (Classification ARCHICAD); Cloison (Classification ARCHICAD) | Finition int - Plaque de plâtre (2), Isolation - Laine de roche | Non défini | 0.04 | 840 | 160 | 23.4 (MJ/kg) | 1.73 (kgCO₂/kg) | Isolation - Laine de roche | no | 2.00219 | 2.49 | 0.145593 | 4.84976 | 4.84976 | 0.362528 | 0.362528 | 0.8 | 1000 | 1600 | 1.45 (MJ/kg) | 0.22 (kgCO₂/kg) | Finition int - Plaque de plâtre | no | Material Properties - Component 1: 2 with these values
Cloison Placostil 72/48 | R+1 | Mur (Classification ARCHICAD); Cloison (Classification ARCHICAD) | Finition int - Plaque de plâtre (2), Isolation - Laine de roche | Non défini | 0.04 | 840 | 160 | 23.4 (MJ/kg) | 1.73 (kgCO₂/kg) | Isolation - Laine de roche | no | 3.42688 | 2.5 | 0.24804 | 8.36594 | 8.36594 | 0.6201 | 0.6201 | 0.8 | 1000 | 1600 | 1.45 (MJ/kg) | 0.22 (kgCO₂/kg) | Finition int - Plaque de plâtre | no | Material Properties - Component 1: 2 with these values
Cloison Placostil 72/48 | R+1 | Mur (Classification ARCHICAD); Cloison (Classification ARCHICAD) | Finition int - Plaque de plâtre (2), Isolation - Laine de roche | Non défini | 0.04 | 840 | 160 | 23.4 (MJ/kg) | 1.73 (kgCO₂/kg) | Isolation - Laine de roche | no | 0.663 | 2.5 | 0.049759 | 1.4276 | 1.4276 | 0.119558 | 0.119558 | 0.8 | 1000 | 1600 | 1.45 (MJ/kg) | 0.22 (kgCO₂/kg) | Finition int - Plaque de plâtre | no | Material Properties - Component 1: 2 with these values
Cloison Placostil 72/48 | R+1 | Mur (Classification ARCHICAD); Cloison (Classification ARCHICAD) | Finition int - Plaque de plâtre (2), Isolation - Laine de roche | Non défini | 0.04 | 840 | 160 | 23.4 (MJ/kg) | 1.73 (kgCO₂/kg) | Isolation - Laine de roche | no | 0.637 | 2.5 | 0.049083 | 1.4157 | 1.4157 | 0.117688 | 0.117688 | Material Properties - Component 3, Finition int - Plaque de plâtre, ThermalConductivity: 0.8; Component 3, Finition int - Plaque de plâtre, SpecificHeatCapacity: 1000 J/kg/K; Component 3, Finition int - Plaque de plâtre, MassDensity: 1600 kg/m3; Component 3, Finition int - Plaque de plâtre, Embodied Energy: 1.45 (MJ/kg); Component 3, Finition int - Plaque de plâtre, Embodied Carbon: 0.22 (kgCO₂/kg); Component 3, Finition int - Plaque de plâtre, Name: Finition int - Plaque de plâtre; Component 3, Finition int - Plaque de plâtre, Participates in Collision Detection: no; Component 3: 2 with these values
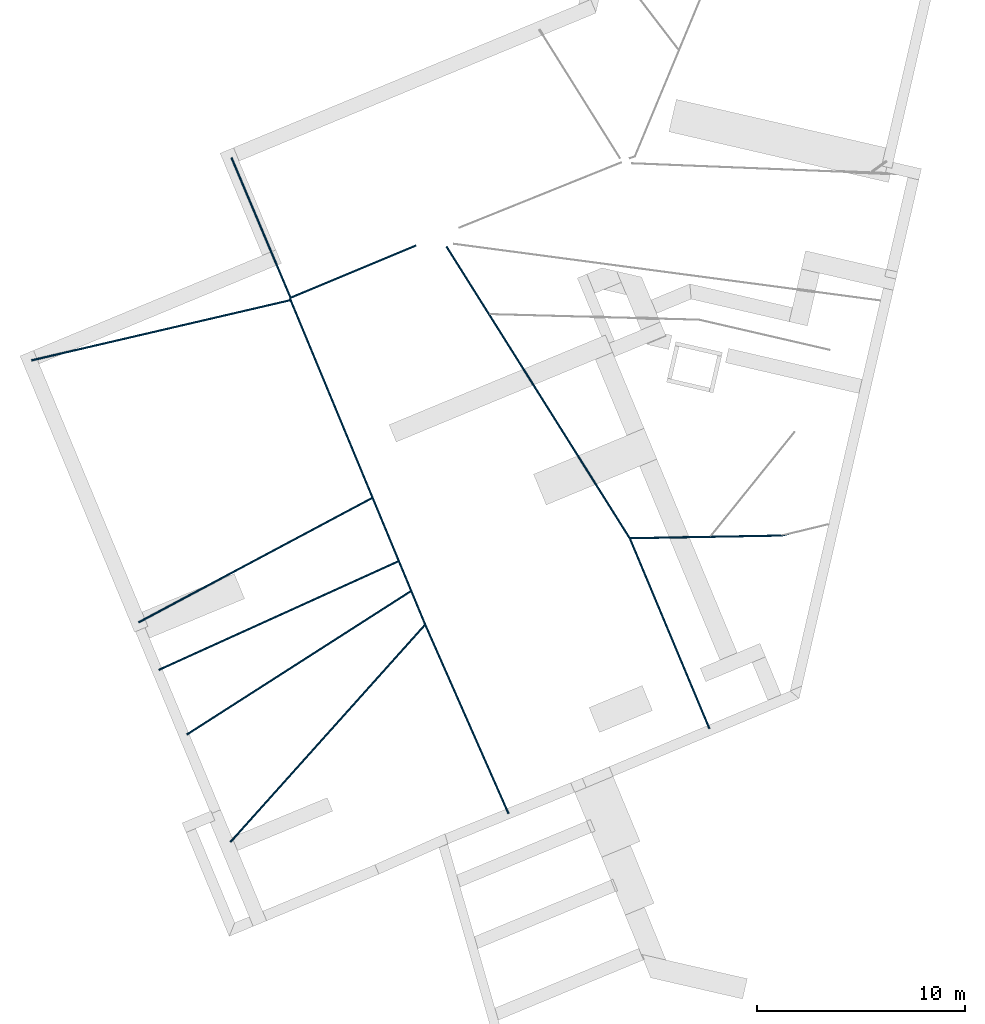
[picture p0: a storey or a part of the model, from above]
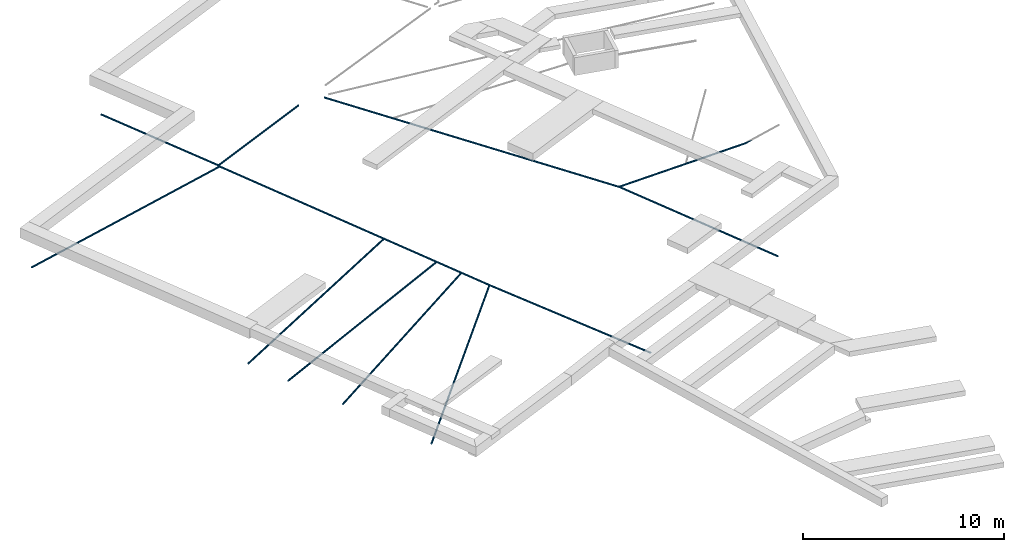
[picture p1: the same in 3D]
Properties of the parts of a building model (IFC2X3), part 12 of 22

# IfcWall: 3 - Cloison 72mm Placostil 74 (508)
Name | In | Classification | Material | AcousticRating | Component 2, Isolation - Laine de roche, ThermalConductivity | Component 2, Isolation - Laine de roche, SpecificHeatCapacity (J/kg/K) | Component 2, Isolation - Laine de roche, MassDensity (kg/m3) | Component 2, Isolation - Laine de roche, Embodied Energy | Component 2, Isolation - Laine de roche, Embodied Carbon | Component 2, Isolation - Laine de roche, Name | Component 2, Isolation - Laine de roche, Participates in Collision Detection | Length (m) | Height (m) | GrossFootprintArea (m2) = NetFootprintArea (m2) | GrossSideArea (m2) | NetSideArea (m2) | GrossVolume (m3) | NetVolume (m3) | Component 1, Finition int - Plaque de plâtre, ThermalConductivity | Component 1, Finition int - Plaque de plâtre, SpecificHeatCapacity (J/kg/K) | Component 1, Finition int - Plaque de plâtre, MassDensity (kg/m3) | Component 1, Finition int - Plaque de plâtre, Embodied Energy | Component 1, Finition int - Plaque de plâtre, Embodied Carbon | Component 1, Finition int - Plaque de plâtre, Name | Component 1, Finition int - Plaque de plâtre, Participates in Collision Detection
Cloison Placostil 72/48 | R+1 | Mur (Classification ARCHICAD); Cloison (Classification ARCHICAD) | Finition int - Plaque de plâtre (2), Isolation - Laine de roche | Non défini | 0.04 | 840 | 160 | 23.4 (MJ/kg) | 1.73 (kgCO₂/kg) | Isolation - Laine de roche | no | 1.437 | 2.5 | 0.037677 | 3.38125 | 1.48845 | 0.257473 | 0.117405 | 0.8 | 1000 | 1600 | 1.45 (MJ/kg) | 0.22 (kgCO₂/kg) | Finition int - Plaque de plâtre | no | Material Properties - Component 1: 2 with these values
Cloison Placostil 72/48 | R+1 | Mur (Classification ARCHICAD); Cloison (Classification ARCHICAD) | Finition int - Plaque de plâtre (2), Isolation - Laine de roche | Non défini | 0.04 | 840 | 160 | 23.4 (MJ/kg) | 1.73 (kgCO₂/kg) | Isolation - Laine de roche | no | 3.23685 | 2.5 | 0.173508 | 8.10837 | 6.21557 | 0.602119 | 0.462052 | 0.8 | 1000 | 1600 | 1.45 (MJ/kg) | 0.22 (kgCO₂/kg) | Finition int - Plaque de plâtre | no | Material Properties - Component 1: 2 with these values
Cloison Placostil 72/48 | R+1 | Mur (Classification ARCHICAD); Cloison (Classification ARCHICAD) | Finition int - Plaque de plâtre (2), Isolation - Laine de roche | Non défini | 0.04 | 840 | 160 | 23.4 (MJ/kg) | 1.73 (kgCO₂/kg) | Isolation - Laine de roche | no | 0.31902 | 2.5 | 0.0236075 | 0.797551 | 0.797551 | 0.0590188 | 0.0590188 | 0.8 | 1000 | 1600 | 1.45 (MJ/kg) | 0.22 (kgCO₂/kg) | Finition int - Plaque de plâtre | no | Material Properties - Component 1: 2 with these values
Cloison Placostil 72/48 | R+1 | Mur (Classification ARCHICAD); Cloison (Classification ARCHICAD) | Finition int - Plaque de plâtre (2), Isolation - Laine de roche | Non défini | 0.04 | 840 | 160 | 23.4 (MJ/kg) | 1.73 (kgCO₂/kg) | Isolation - Laine de roche | no | 0.637 | 2.5 | 0.049083 | 1.60875 | 1.60875 | 0.122708 | 0.122708 | Material Properties - Component 3, Finition int - Plaque de plâtre, ThermalConductivity: 0.8; Component 3, Finition int - Plaque de plâtre, SpecificHeatCapacity: 1000 J/kg/K; Component 3, Finition int - Plaque de plâtre, MassDensity: 1600 kg/m3; Component 3, Finition int - Plaque de plâtre, Embodied Energy: 1.45 (MJ/kg); Component 3, Finition int - Plaque de plâtre, Embodied Carbon: 0.22 (kgCO₂/kg); Component 3, Finition int - Plaque de plâtre, Name: Finition int - Plaque de plâtre; Component 3, Finition int - Plaque de plâtre, Participates in Collision Detection: no; Component 3: 2 with these values
Cloison Placostil 72/48 | R+1 | Mur (Classification ARCHICAD); Cloison (Classification ARCHICAD) | Finition int - Plaque de plâtre (2), Isolation - Laine de roche | Non défini | 0.04 | 840 | 160 | 23.4 (MJ/kg) | 1.73 (kgCO₂/kg) | Isolation - Laine de roche | no | 0.287 | 2.5 | 0.020541 | 0.70125 | 0.70125 | 0.0513525 | 0.0513525 | Material Properties - Component 3, Finition int - Plaque de plâtre, ThermalConductivity: 0.8; Component 3, Finition int - Plaque de plâtre, SpecificHeatCapacity: 1000 J/kg/K; Component 3, Finition int - Plaque de plâtre, MassDensity: 1600 kg/m3; Component 3, Finition int - Plaque de plâtre, Embodied Energy: 1.45 (MJ/kg); Component 3, Finition int - Plaque de plâtre, Embodied Carbon: 0.22 (kgCO₂/kg); Component 3, Finition int - Plaque de plâtre, Name: Finition int - Plaque de plâtre; Component 3, Finition int - Plaque de plâtre, Participates in Collision Detection: no; Component 3: 2 with these values
Cloison Placostil 72/48 | R+1 | Mur (Classification ARCHICAD); Cloison (Classification ARCHICAD) | Finition int - Plaque de plâtre (2), Isolation - Laine de roche | Non défini | 0.04 | 840 | 160 | 23.4 (MJ/kg) | 1.73 (kgCO₂/kg) | Isolation - Laine de roche | no | 3.92129 | 2.5 | 0.290872 | 9.75947 | 9.75947 | 0.727181 | 0.727181 | 0.8 | 1000 | 1600 | 1.45 (MJ/kg) | 0.22 (kgCO₂/kg) | Finition int - Plaque de plâtre | no | Material Properties - Component 1: 2 with these values
Cloison Placostil 72/48 | R+1 | Mur (Classification ARCHICAD); Cloison (Classification ARCHICAD) | Finition int - Plaque de plâtre (2), Isolation - Laine de roche | Non défini | 0.04 | 840 | 160 | 23.4 (MJ/kg) | 1.73 (kgCO₂/kg) | Isolation - Laine de roche | no | 1.79147 | 2.5 | 0.131872 | 4.46242 | 4.46242 | 0.329679 | 0.329679 | Material Properties - Component 3, Finition int - Plaque de plâtre, ThermalConductivity: 0.8; Component 3, Finition int - Plaque de plâtre, SpecificHeatCapacity: 1000 J/kg/K; Component 3, Finition int - Plaque de plâtre, MassDensity: 1600 kg/m3; Component 3, Finition int - Plaque de plâtre, Embodied Energy: 1.45 (MJ/kg); Component 3, Finition int - Plaque de plâtre, Embodied Carbon: 0.22 (kgCO₂/kg); Component 3, Finition int - Plaque de plâtre, Name: Finition int - Plaque de plâtre; Component 3, Finition int - Plaque de plâtre, Participates in Collision Detection: no; Component 3: 2 with these values
Cloison Placostil 72/48 | R+2 | Mur (Classification ARCHICAD); Cloison (Classification ARCHICAD) | Finition int - Plaque de plâtre (2), Isolation - Laine de roche | Non défini | 0.04 | 840 | 160 | 23.4 (MJ/kg) | 1.73 (kgCO₂/kg) | Isolation - Laine de roche | no | 3.68483 | 2.5 | 0.273374 | 9.16831 | 9.16831 | 0.683435 | 0.683435 | 0.8 | 1000 | 1600 | 1.45 (MJ/kg) | 0.22 (kgCO₂/kg) | Finition int - Plaque de plâtre | no | Material Properties - Component 1: 2 with these values
Cloison Placostil 72/48 | R+2 | Mur (Classification ARCHICAD); Cloison (Classification ARCHICAD) | Finition int - Plaque de plâtre (2), Isolation - Laine de roche | Non défini | 0.04 | 840 | 160 | 23.4 (MJ/kg) | 1.73 (kgCO₂/kg) | Isolation - Laine de roche | no | 0.483901 | 2.49 | 0.0384507 | 1.23728 | 1.23728 | 0.0957421 | 0.0957421 | Material Properties - Component 3, Finition int - Plaque de plâtre, ThermalConductivity: 0.8; Component 3, Finition int - Plaque de plâtre, SpecificHeatCapacity: 1000 J/kg/K; Component 3, Finition int - Plaque de plâtre, MassDensity: 1600 kg/m3; Component 3, Finition int - Plaque de plâtre, Embodied Energy: 1.45 (MJ/kg); Component 3, Finition int - Plaque de plâtre, Embodied Carbon: 0.22 (kgCO₂/kg); Component 3, Finition int - Plaque de plâtre, Name: Finition int - Plaque de plâtre; Component 3, Finition int - Plaque de plâtre, Participates in Collision Detection: no; Component 3: 2 with these values
Cloison Placostil 72/48 | R+2 | Mur (Classification ARCHICAD); Cloison (Classification ARCHICAD) | Finition int - Plaque de plâtre (2), Isolation - Laine de roche | Non défini | 0.04 | 840 | 160 | 23.4 (MJ/kg) | 1.73 (kgCO₂/kg) | Isolation - Laine de roche | no | 1.54147 | 2.5 | 0.117579 | 3.85367 | 3.85367 | 0.293946 | 0.293946 | 0.8 | 1000 | 1600 | 1.45 (MJ/kg) | 0.22 (kgCO₂/kg) | Finition int - Plaque de plâtre | no | Material Properties - Component 1: 2 with these values
Cloison Placostil 72/48 | R+2 | Mur (Classification ARCHICAD); Cloison (Classification ARCHICAD) | Finition int - Plaque de plâtre (2), Isolation - Laine de roche | Non défini | 0.04 | 840 | 160 | 23.4 (MJ/kg) | 1.73 (kgCO₂/kg) | Isolation - Laine de roche | no | 0.25 | 2.5 | 0.015858 | 0.5925 | 0.5925 | 0.039645 | 0.039645 | 0.8 | 1000 | 1600 | 1.45 (MJ/kg) | 0.22 (kgCO₂/kg) | Finition int - Plaque de plâtre | no | Material Properties - Component 1: 2 with these values
Cloison Placostil 72/48 | R+2 | Mur (Classification ARCHICAD); Cloison (Classification ARCHICAD) | Finition int - Plaque de plâtre (2), Isolation - Laine de roche | Non défini | 0.04 | 840 | 160 | 23.4 (MJ/kg) | 1.73 (kgCO₂/kg) | Isolation - Laine de roche | no | 0.636831 | 2.5 | 0.0490705 | 1.60833 | 1.60833 | 0.122676 | 0.122676 | 0.8 | 1000 | 1600 | 1.45 (MJ/kg) | 0.22 (kgCO₂/kg) | Finition int - Plaque de plâtre | no | Material Properties - Component 1: 2 with these values
Cloison Placostil 72/48 | R+2 | Mur (Classification ARCHICAD); Cloison (Classification ARCHICAD) | Finition int - Plaque de plâtre (2), Isolation - Laine de roche | Non défini | 0.04 | 840 | 160 | 23.4 (MJ/kg) | 1.73 (kgCO₂/kg) | Isolation - Laine de roche | no | 0.286541 | 2.49 | 0.020507 | 0.697301 | 0.697301 | 0.0510625 | 0.0510625 | Material Properties - Component 3, Finition int - Plaque de plâtre, ThermalConductivity: 0.8; Component 3, Finition int - Plaque de plâtre, SpecificHeatCapacity: 1000 J/kg/K; Component 3, Finition int - Plaque de plâtre, MassDensity: 1600 kg/m3; Component 3, Finition int - Plaque de plâtre, Embodied Energy: 1.45 (MJ/kg); Component 3, Finition int - Plaque de plâtre, Embodied Carbon: 0.22 (kgCO₂/kg); Component 3, Finition int - Plaque de plâtre, Name: Finition int - Plaque de plâtre; Component 3, Finition int - Plaque de plâtre, Participates in Collision Detection: no; Component 3: 2 with these values
Cloison Placostil 72/48 | R+2 | Mur (Classification ARCHICAD); Cloison (Classification ARCHICAD) | Finition int - Plaque de plâtre (2), Isolation - Laine de roche | Non défini | 0.04 | 840 | 160 | 23.4 (MJ/kg) | 1.73 (kgCO₂/kg) | Isolation - Laine de roche | no | 0.31902 | 2.5 | 0.0236075 | 0.797551 | 0.797551 | 0.0590188 | 0.0590188 | 0.8 | 1000 | 1600 | 1.45 (MJ/kg) | 0.22 (kgCO₂/kg) | Finition int - Plaque de plâtre | no | Material Properties - Component 1: 2 with these values
Cloison Placostil 72/48 | R+2 | Mur (Classification ARCHICAD); Cloison (Classification ARCHICAD) | Finition int - Plaque de plâtre (2), Isolation - Laine de roche | Non défini | 0.04 | 840 | 160 | 23.4 (MJ/kg) | 1.73 (kgCO₂/kg) | Isolation - Laine de roche | no | 1.387 | 2.5 | 0.101941 | 3.45125 | 3.45125 | 0.254852 | 0.254852 | Material Properties - Component 3, Finition int - Plaque de plâtre, ThermalConductivity: 0.8; Component 3, Finition int - Plaque de plâtre, SpecificHeatCapacity: 1000 J/kg/K; Component 3, Finition int - Plaque de plâtre, MassDensity: 1600 kg/m3; Component 3, Finition int - Plaque de plâtre, Embodied Energy: 1.45 (MJ/kg); Component 3, Finition int - Plaque de plâtre, Embodied Carbon: 0.22 (kgCO₂/kg); Component 3, Finition int - Plaque de plâtre, Name: Finition int - Plaque de plâtre; Component 3, Finition int - Plaque de plâtre, Participates in Collision Detection: no; Component 3: 2 with these values
Cloison Placostil 72/48 | R+2 | Mur (Classification ARCHICAD); Cloison (Classification ARCHICAD) | Finition int - Plaque de plâtre (2), Isolation - Laine de roche | Non défini | 0.04 | 840 | 160 | 23.4 (MJ/kg) | 1.73 (kgCO₂/kg) | Isolation - Laine de roche | no | 3.38417 | 2.5 | 0.250429 | 8.40042 | 8.40042 | 0.626071 | 0.626071 | 0.8 | 1000 | 1600 | 1.45 (MJ/kg) | 0.22 (kgCO₂/kg) | Finition int - Plaque de plâtre | no | Material Properties - Component 1: 2 with these values
Cloison Placostil 72/48 | R+2 | Mur (Classification ARCHICAD); Cloison (Classification ARCHICAD) | Finition int - Plaque de plâtre (2), Isolation - Laine de roche | Non défini | 0.04 | 840 | 160 | 23.4 (MJ/kg) | 1.73 (kgCO₂/kg) | Isolation - Laine de roche | no | 0.694 | 2.5 | 0.051356 | 1.735 | 1.735 | 0.12839 | 0.12839 | Material Properties - Component 3, Finition int - Plaque de plâtre, ThermalConductivity: 0.8; Component 3, Finition int - Plaque de plâtre, SpecificHeatCapacity: 1000 J/kg/K; Component 3, Finition int - Plaque de plâtre, MassDensity: 1600 kg/m3; Component 3, Finition int - Plaque de plâtre, Embodied Energy: 1.45 (MJ/kg); Component 3, Finition int - Plaque de plâtre, Embodied Carbon: 0.22 (kgCO₂/kg); Component 3, Finition int - Plaque de plâtre, Name: Finition int - Plaque de plâtre; Component 3, Finition int - Plaque de plâtre, Participates in Collision Detection: no; Component 3: 2 with these values
Cloison Placostil 72/48 | R+2 | Mur (Classification ARCHICAD); Cloison (Classification ARCHICAD) | Finition int - Plaque de plâtre (2), Isolation - Laine de roche | Non défini | 0.04 | 840 | 160 | 23.4 (MJ/kg) | 1.73 (kgCO₂/kg) | Isolation - Laine de roche | no | 0.637 | 2.5 | 0.046441 | 1.57625 | 1.57625 | 0.116102 | 0.116102 | Material Properties - Component 3, Finition int - Plaque de plâtre, ThermalConductivity: 0.8; Component 3, Finition int - Plaque de plâtre, SpecificHeatCapacity: 1000 J/kg/K; Component 3, Finition int - Plaque de plâtre, MassDensity: 1600 kg/m3; Component 3, Finition int - Plaque de plâtre, Embodied Energy: 1.45 (MJ/kg); Component 3, Finition int - Plaque de plâtre, Embodied Carbon: 0.22 (kgCO₂/kg); Component 3, Finition int - Plaque de plâtre, Name: Finition int - Plaque de plâtre; Component 3, Finition int - Plaque de plâtre, Participates in Collision Detection: no; Component 3: 2 with these values
Cloison Placostil 72/48 | R+2 | Mur (Classification ARCHICAD); Cloison (Classification ARCHICAD) | Finition int - Plaque de plâtre (2), Isolation - Laine de roche | Non défini | 0.04 | 840 | 160 | 23.4 (MJ/kg) | 1.73 (kgCO₂/kg) | Isolation - Laine de roche | no | 0.966221 | 2.5 | 0.00478436 | 2.41555 | 0.522753 | 0.180311 | 0.0402437 | 0.8 | 1000 | 1600 | 1.45 (MJ/kg) | 0.22 (kgCO₂/kg) | Finition int - Plaque de plâtre | no | Material Properties - Component 1: 2 with these values
Cloison Placostil 72/48 | R+2 | Mur (Classification ARCHICAD); Cloison (Classification ARCHICAD) | Finition int - Plaque de plâtre (2), Isolation - Laine de roche | Non défini | 0.04 | 840 | 160 | 23.4 (MJ/kg) | 1.73 (kgCO₂/kg) | Isolation - Laine de roche | no | 0.32501 | 2.5 | 0.0266927 | 0.845025 | 0.845025 | 0.0667318 | 0.0667318 | 0.8 | 1000 | 1600 | 1.45 (MJ/kg) | 0.22 (kgCO₂/kg) | Finition int - Plaque de plâtre | no | Material Properties - Component 1: 2 with these values
Cloison Placostil 72/48 | R+2 | Mur (Classification ARCHICAD); Cloison (Classification ARCHICAD) | Finition int - Plaque de plâtre (2), Isolation - Laine de roche | Non défini | 0.04 | 840 | 160 | 23.4 (MJ/kg) | 1.73 (kgCO₂/kg) | Isolation - Laine de roche | no | 0.955 | 2.5 | 0.003954 | 2.3875 | 0.4947 | 0.178235 | 0.0381678 | Material Properties - Component 3, Finition int - Plaque de plâtre, ThermalConductivity: 0.8; Component 3, Finition int - Plaque de plâtre, SpecificHeatCapacity: 1000 J/kg/K; Component 3, Finition int - Plaque de plâtre, MassDensity: 1600 kg/m3; Component 3, Finition int - Plaque de plâtre, Embodied Energy: 1.45 (MJ/kg); Component 3, Finition int - Plaque de plâtre, Embodied Carbon: 0.22 (kgCO₂/kg); Component 3, Finition int - Plaque de plâtre, Name: Finition int - Plaque de plâtre; Component 3, Finition int - Plaque de plâtre, Participates in Collision Detection: no; Component 3: 2 with these values
Cloison Placostil 72/48 | R+2 | Mur (Classification ARCHICAD); Cloison (Classification ARCHICAD) | Finition int - Plaque de plâtre (2), Isolation - Laine de roche | Non défini | 0.04 | 840 | 160 | 23.4 (MJ/kg) | 1.73 (kgCO₂/kg) | Isolation - Laine de roche | no | 0.523283 | 2.5 | 0.0360809 | 1.27571 | 1.27571 | 0.0902023 | 0.0902023 | Material Properties - Component 3, Finition int - Plaque de plâtre, ThermalConductivity: 0.8; Component 3, Finition int - Plaque de plâtre, SpecificHeatCapacity: 1000 J/kg/K; Component 3, Finition int - Plaque de plâtre, MassDensity: 1600 kg/m3; Component 3, Finition int - Plaque de plâtre, Embodied Energy: 1.45 (MJ/kg); Component 3, Finition int - Plaque de plâtre, Embodied Carbon: 0.22 (kgCO₂/kg); Component 3, Finition int - Plaque de plâtre, Name: Finition int - Plaque de plâtre; Component 3, Finition int - Plaque de plâtre, Participates in Collision Detection: no; Component 3: 2 with these values
Cloison Placostil 72/48 | R+2 | Mur (Classification ARCHICAD); Cloison (Classification ARCHICAD) | Finition int - Plaque de plâtre (2), Isolation - Laine de roche | Non défini | 0.04 | 840 | 160 | 23.4 (MJ/kg) | 1.73 (kgCO₂/kg) | Isolation - Laine de roche | no | 1.45 | 2.5 | 0.000624 | 3.625 | 0.609 | 0.26981 | 0.046626 | Material Properties - Component 3, Finition int - Plaque de plâtre, ThermalConductivity: 0.8; Component 3, Finition int - Plaque de plâtre, SpecificHeatCapacity: 1000 J/kg/K; Component 3, Finition int - Plaque de plâtre, MassDensity: 1600 kg/m3; Component 3, Finition int - Plaque de plâtre, Embodied Energy: 1.45 (MJ/kg); Component 3, Finition int - Plaque de plâtre, Embodied Carbon: 0.22 (kgCO₂/kg); Component 3, Finition int - Plaque de plâtre, Name: Finition int - Plaque de plâtre; Component 3, Finition int - Plaque de plâtre, Participates in Collision Detection: no; Component 3: 2 with these values
Cloison Placostil 72/48 | R+2 | Mur (Classification ARCHICAD); Cloison (Classification ARCHICAD) | Finition int - Plaque de plâtre (2), Isolation - Laine de roche | Non défini | 0.04 | 840 | 160 | 23.4 (MJ/kg) | 1.73 (kgCO₂/kg) | Isolation - Laine de roche | no | 1.4 | 0.42 | 0 | 3.5 | 0.588 | 0.259 | 0.043512 | Material Properties - Component 3, Finition int - Plaque de plâtre, ThermalConductivity: 0.8; Component 3, Finition int - Plaque de plâtre, SpecificHeatCapacity: 1000 J/kg/K; Component 3, Finition int - Plaque de plâtre, MassDensity: 1600 kg/m3; Component 3, Finition int - Plaque de plâtre, Embodied Energy: 1.45 (MJ/kg); Component 3, Finition int - Plaque de plâtre, Embodied Carbon: 0.22 (kgCO₂/kg); Component 3, Finition int - Plaque de plâtre, Name: Finition int - Plaque de plâtre; Component 3, Finition int - Plaque de plâtre, Participates in Collision Detection: no; Component 3: 2 with these values
Cloison Placostil 72/48 | R+2 | Mur (Classification ARCHICAD); Cloison (Classification ARCHICAD) | Finition int - Plaque de plâtre (2), Isolation - Laine de roche | Non défini | 0.04 | 840 | 160 | 23.4 (MJ/kg) | 1.73 (kgCO₂/kg) | Isolation - Laine de roche | no | 2.09455 | 2.5 | 0.0882809 | 5.23638 | 3.34358 | 0.389052 | 0.248985 | 0.8 | 1000 | 1600 | 1.45 (MJ/kg) | 0.22 (kgCO₂/kg) | Finition int - Plaque de plâtre | no | Material Properties - Component 1: 2 with these values
Cloison Placostil 72/48 | R+2 | Mur (Classification ARCHICAD); Cloison (Classification ARCHICAD) | Finition int - Plaque de plâtre (2), Isolation - Laine de roche | Non défini | 0.04 | 840 | 160 | 23.4 (MJ/kg) | 1.73 (kgCO₂/kg) | Isolation - Laine de roche | no | 0.6 | 2.5 | 0.045648 | 1.5 | 1.5 | 0.11412 | 0.11412 | Material Properties - Component 3, Finition int - Plaque de plâtre, ThermalConductivity: 0.8; Component 3, Finition int - Plaque de plâtre, SpecificHeatCapacity: 1000 J/kg/K; Component 3, Finition int - Plaque de plâtre, MassDensity: 1600 kg/m3; Component 3, Finition int - Plaque de plâtre, Embodied Energy: 1.45 (MJ/kg); Component 3, Finition int - Plaque de plâtre, Embodied Carbon: 0.22 (kgCO₂/kg); Component 3, Finition int - Plaque de plâtre, Name: Finition int - Plaque de plâtre; Component 3, Finition int - Plaque de plâtre, Participates in Collision Detection: no; Component 3: 2 with these values
Cloison Placostil 72/48 | R+2 | Mur (Classification ARCHICAD); Cloison (Classification ARCHICAD) | Finition int - Plaque de plâtre (2), Isolation - Laine de roche | Non défini | 0.04 | 840 | 160 | 23.4 (MJ/kg) | 1.73 (kgCO₂/kg) | Isolation - Laine de roche | no | 1.437 | 2.49 | 0.001417 | 3.56195 | 0.649945 | 0.261492 | 0.0460043 | Material Properties - Component 3, Finition int - Plaque de plâtre, ThermalConductivity: 0.8; Component 3, Finition int - Plaque de plâtre, SpecificHeatCapacity: 1000 J/kg/K; Component 3, Finition int - Plaque de plâtre, MassDensity: 1600 kg/m3; Component 3, Finition int - Plaque de plâtre, Embodied Energy: 1.45 (MJ/kg); Component 3, Finition int - Plaque de plâtre, Embodied Carbon: 0.22 (kgCO₂/kg); Component 3, Finition int - Plaque de plâtre, Name: Finition int - Plaque de plâtre; Component 3, Finition int - Plaque de plâtre, Participates in Collision Detection: no; Component 3: 2 with these values
Cloison Placostil 72/48 | R+2 | Mur (Classification ARCHICAD); Cloison (Classification ARCHICAD) | Finition int - Plaque de plâtre (2), Isolation - Laine de roche | Non défini | 0.04 | 840 | 160 | 23.4 (MJ/kg) | 1.73 (kgCO₂/kg) | Isolation - Laine de roche | no | 2.00219 | 2.49 | 0.145593 | 4.84976 | 4.84976 | 0.362528 | 0.362528 | 0.8 | 1000 | 1600 | 1.45 (MJ/kg) | 0.22 (kgCO₂/kg) | Finition int - Plaque de plâtre | no | Material Properties - Component 1: 2 with these values
Cloison Placostil 72/48 | R+2 | Mur (Classification ARCHICAD); Cloison (Classification ARCHICAD) | Finition int - Plaque de plâtre (2), Isolation - Laine de roche | Non défini | 0.04 | 840 | 160 | 23.4 (MJ/kg) | 1.73 (kgCO₂/kg) | Isolation - Laine de roche | no | 3.42688 | 2.5 | 0.24804 | 8.36594 | 8.36594 | 0.6201 | 0.6201 | 0.8 | 1000 | 1600 | 1.45 (MJ/kg) | 0.22 (kgCO₂/kg) | Finition int - Plaque de plâtre | no | Material Properties - Component 1: 2 with these values
Cloison Placostil 72/48 | R+2 | Mur (Classification ARCHICAD); Cloison (Classification ARCHICAD) | Finition int - Plaque de plâtre (2), Isolation - Laine de roche | Non défini | 0.04 | 840 | 160 | 23.4 (MJ/kg) | 1.73 (kgCO₂/kg) | Isolation - Laine de roche | no | 0.663 | 2.5 | 0.049759 | 1.4276 | 1.4276 | 0.119558 | 0.119558 | 0.8 | 1000 | 1600 | 1.45 (MJ/kg) | 0.22 (kgCO₂/kg) | Finition int - Plaque de plâtre | no | Material Properties - Component 1: 2 with these values
Cloison Placostil 72/48 | R+2 | Mur (Classification ARCHICAD); Cloison (Classification ARCHICAD) | Finition int - Plaque de plâtre (2), Isolation - Laine de roche | Non défini | 0.04 | 840 | 160 | 23.4 (MJ/kg) | 1.73 (kgCO₂/kg) | Isolation - Laine de roche | no | 0.637 | 2.5 | 0.049083 | 1.4157 | 1.4157 | 0.117688 | 0.117688 | Material Properties - Component 3, Finition int - Plaque de plâtre, ThermalConductivity: 0.8; Component 3, Finition int - Plaque de plâtre, SpecificHeatCapacity: 1000 J/kg/K; Component 3, Finition int - Plaque de plâtre, MassDensity: 1600 kg/m3; Component 3, Finition int - Plaque de plâtre, Embodied Energy: 1.45 (MJ/kg); Component 3, Finition int - Plaque de plâtre, Embodied Carbon: 0.22 (kgCO₂/kg); Component 3, Finition int - Plaque de plâtre, Name: Finition int - Plaque de plâtre; Component 3, Finition int - Plaque de plâtre, Participates in Collision Detection: no; Component 3: 2 with these values
Cloison Placostil 72/48 | R+2 | Mur (Classification ARCHICAD); Cloison (Classification ARCHICAD) | Finition int - Plaque de plâtre (2), Isolation - Laine de roche | Non défini | 0.04 | 840 | 160 | 23.4 (MJ/kg) | 1.73 (kgCO₂/kg) | Isolation - Laine de roche | no | 1.437 | 2.5 | 0.037677 | 3.38125 | 1.48845 | 0.257473 | 0.117405 | 0.8 | 1000 | 1600 | 1.45 (MJ/kg) | 0.22 (kgCO₂/kg) | Finition int - Plaque de plâtre | no | Material Properties - Component 1: 2 with these values
Cloison Placostil 72/48 | R+2 | Mur (Classification ARCHICAD); Cloison (Classification ARCHICAD) | Finition int - Plaque de plâtre (2), Isolation - Laine de roche | Non défini | 0.04 | 840 | 160 | 23.4 (MJ/kg) | 1.73 (kgCO₂/kg) | Isolation - Laine de roche | no | 3.23685 | 2.5 | 0.173508 | 8.10837 | 6.21557 | 0.602119 | 0.462052 | 0.8 | 1000 | 1600 | 1.45 (MJ/kg) | 0.22 (kgCO₂/kg) | Finition int - Plaque de plâtre | no | Material Properties - Component 1: 2 with these values
Cloison Placostil 72/48 | R+2 | Mur (Classification ARCHICAD); Cloison (Classification ARCHICAD) | Finition int - Plaque de plâtre (2), Isolation - Laine de roche | Non défini | 0.04 | 840 | 160 | 23.4 (MJ/kg) | 1.73 (kgCO₂/kg) | Isolation - Laine de roche | no | 0.301167 | 2.5 | 0.0242317 | 0.769173 | 0.769173 | 0.0605793 | 0.0605793 | Material Properties - Component 3, Finition int - Plaque de plâtre, ThermalConductivity: 0.8; Component 3, Finition int - Plaque de plâtre, SpecificHeatCapacity: 1000 J/kg/K; Component 3, Finition int - Plaque de plâtre, MassDensity: 1600 kg/m3; Component 3, Finition int - Plaque de plâtre, Embodied Energy: 1.45 (MJ/kg); Component 3, Finition int - Plaque de plâtre, Embodied Carbon: 0.22 (kgCO₂/kg); Component 3, Finition int - Plaque de plâtre, Name: Finition int - Plaque de plâtre; Component 3, Finition int - Plaque de plâtre, Participates in Collision Detection: no; Component 3: 2 with these values
Cloison Placostil 72/48 | R+2 | Mur (Classification ARCHICAD); Cloison (Classification ARCHICAD) | Finition int - Plaque de plâtre (2), Isolation - Laine de roche | Non défini | 0.04 | 840 | 160 | 23.4 (MJ/kg) | 1.73 (kgCO₂/kg) | Isolation - Laine de roche | no | 0.637 | 2.5 | 0.049083 | 1.60875 | 1.60875 | 0.122708 | 0.122708 | Material Properties - Component 3, Finition int - Plaque de plâtre, ThermalConductivity: 0.8; Component 3, Finition int - Plaque de plâtre, SpecificHeatCapacity: 1000 J/kg/K; Component 3, Finition int - Plaque de plâtre, MassDensity: 1600 kg/m3; Component 3, Finition int - Plaque de plâtre, Embodied Energy: 1.45 (MJ/kg); Component 3, Finition int - Plaque de plâtre, Embodied Carbon: 0.22 (kgCO₂/kg); Component 3, Finition int - Plaque de plâtre, Name: Finition int - Plaque de plâtre; Component 3, Finition int - Plaque de plâtre, Participates in Collision Detection: no; Component 3: 2 with these values
Cloison Placostil 72/48 | R+2 | Mur (Classification ARCHICAD); Cloison (Classification ARCHICAD) | Finition int - Plaque de plâtre (2), Isolation - Laine de roche | Non défini | 0.04 | 840 | 160 | 23.4 (MJ/kg) | 1.73 (kgCO₂/kg) | Isolation - Laine de roche | no | 0.287 | 2.5 | 0.020541 | 0.70125 | 0.70125 | 0.0513525 | 0.0513525 | Material Properties - Component 3, Finition int - Plaque de plâtre, ThermalConductivity: 0.8; Component 3, Finition int - Plaque de plâtre, SpecificHeatCapacity: 1000 J/kg/K; Component 3, Finition int - Plaque de plâtre, MassDensity: 1600 kg/m3; Component 3, Finition int - Plaque de plâtre, Embodied Energy: 1.45 (MJ/kg); Component 3, Finition int - Plaque de plâtre, Embodied Carbon: 0.22 (kgCO₂/kg); Component 3, Finition int - Plaque de plâtre, Name: Finition int - Plaque de plâtre; Component 3, Finition int - Plaque de plâtre, Participates in Collision Detection: no; Component 3: 2 with these values
Cloison Placostil 72/48 | R+2 | Mur (Classification ARCHICAD); Cloison (Classification ARCHICAD) | Finition int - Plaque de plâtre (2), Isolation - Laine de roche | Non défini | 0.04 | 840 | 160 | 23.4 (MJ/kg) | 1.73 (kgCO₂/kg) | Isolation - Laine de roche | no | 3.92129 | 2.5 | 0.290872 | 9.75947 | 9.75947 | 0.727181 | 0.727181 | 0.8 | 1000 | 1600 | 1.45 (MJ/kg) | 0.22 (kgCO₂/kg) | Finition int - Plaque de plâtre | no | Material Properties - Component 1: 2 with these values
Cloison Placostil 72/48 | R+2 | Mur (Classification ARCHICAD); Cloison (Classification ARCHICAD) | Finition int - Plaque de plâtre (2), Isolation - Laine de roche | Non défini | 0.04 | 840 | 160 | 23.4 (MJ/kg) | 1.73 (kgCO₂/kg) | Isolation - Laine de roche | no | 1.79147 | 2.5 | 0.131872 | 4.46242 | 4.46242 | 0.329679 | 0.329679 | Material Properties - Component 3, Finition int - Plaque de plâtre, ThermalConductivity: 0.8; Component 3, Finition int - Plaque de plâtre, SpecificHeatCapacity: 1000 J/kg/K; Component 3, Finition int - Plaque de plâtre, MassDensity: 1600 kg/m3; Component 3, Finition int - Plaque de plâtre, Embodied Energy: 1.45 (MJ/kg); Component 3, Finition int - Plaque de plâtre, Embodied Carbon: 0.22 (kgCO₂/kg); Component 3, Finition int - Plaque de plâtre, Name: Finition int - Plaque de plâtre; Component 3, Finition int - Plaque de plâtre, Participates in Collision Detection: no; Component 3: 2 with these values
Cloison Placostil 72/48 | R+2 | Mur (Classification ARCHICAD); Cloison (Classification ARCHICAD) | Finition int - Plaque de plâtre (2), Isolation - Laine de roche | Non défini | 0.04 | 840 | 160 | 23.4 (MJ/kg) | 1.73 (kgCO₂/kg) | Isolation - Laine de roche | no | 1.87589 | 2.5 | 0.000624 | 4.68973 | 0.787875 | 0.3486 | 0.0598628 | 0.8 | 1000 | 1600 | 1.45 (MJ/kg) | 0.22 (kgCO₂/kg) | Finition int - Plaque de plâtre | no | Material Properties - Component 1: 2 with these values
Cloison Placostil 72/48 | R+3 | Mur (Classification ARCHICAD); Cloison (Classification ARCHICAD) | Finition int - Plaque de plâtre (2), Isolation - Laine de roche | Non défini | 0.04 | 840 | 160 | 23.4 (MJ/kg) | 1.73 (kgCO₂/kg) | Isolation - Laine de roche | no | 3.27631 | 2.5 | 0.000624 | 8.19078 | 1.37605 | 0.607677 | 0.103388 | 0.8 | 1000 | 1600 | 1.45 (MJ/kg) | 0.22 (kgCO₂/kg) | Finition int - Plaque de plâtre | no | Material Properties - Component 1: 2 with these values
Cloison Placostil 72/48 | R+3 | Mur (Classification ARCHICAD); Cloison (Classification ARCHICAD) | Finition int - Plaque de plâtre (2), Isolation - Laine de roche | Non défini | 0.04 | 840 | 160 | 23.4 (MJ/kg) | 1.73 (kgCO₂/kg) | Isolation - Laine de roche | no | 0.432754 | 2.5 | 0.0313733 | 1.07388 | 1.07388 | 0.0784332 | 0.0784332 | Material Properties - Component 3, Finition int - Plaque de plâtre, ThermalConductivity: 0.8; Component 3, Finition int - Plaque de plâtre, SpecificHeatCapacity: 1000 J/kg/K; Component 3, Finition int - Plaque de plâtre, MassDensity: 1600 kg/m3; Component 3, Finition int - Plaque de plâtre, Embodied Energy: 1.45 (MJ/kg); Component 3, Finition int - Plaque de plâtre, Embodied Carbon: 0.22 (kgCO₂/kg); Component 3, Finition int - Plaque de plâtre, Name: Finition int - Plaque de plâtre; Component 3, Finition int - Plaque de plâtre, Participates in Collision Detection: no; Component 3: 2 with these values
Cloison Placostil 72/48 | R+3 | Mur (Classification ARCHICAD); Cloison (Classification ARCHICAD) | Finition int - Plaque de plâtre (2), Isolation - Laine de roche | 35 dB(A) | 0.04 | 840 | 160 | 23.4 (MJ/kg) | 1.73 (kgCO₂/kg) | Isolation - Laine de roche | no | 0.726 | 2.5 | 0.053143 | 1.82375 | 1.82375 | 0.132857 | 0.132857 | Material Properties - Component 3, Finition int - Plaque de plâtre, ThermalConductivity: 0.8; Component 3, Finition int - Plaque de plâtre, SpecificHeatCapacity: 1000 J/kg/K; Component 3, Finition int - Plaque de plâtre, MassDensity: 1600 kg/m3; Component 3, Finition int - Plaque de plâtre, Embodied Energy: 1.45 (MJ/kg); Component 3, Finition int - Plaque de plâtre, Embodied Carbon: 0.22 (kgCO₂/kg); Component 3, Finition int - Plaque de plâtre, Name: Finition int - Plaque de plâtre; Component 3, Finition int - Plaque de plâtre, Participates in Collision Detection: no; Component 3: 2 with these values
Cloison Placostil 72/48 | R+3 | Mur (Classification ARCHICAD); Cloison (Classification ARCHICAD) | Finition int - Plaque de plâtre (2), Isolation - Laine de roche | Non défini | 0.04 | 840 | 160 | 23.4 (MJ/kg) | 1.73 (kgCO₂/kg) | Isolation - Laine de roche | no | 3.32493 | 2.5 | 0.000624 | 8.31232 | 1.39647 | 0.616672 | 0.104899 | 0.8 | 1000 | 1600 | 1.45 (MJ/kg) | 0.22 (kgCO₂/kg) | Finition int - Plaque de plâtre | no | Material Properties - Component 1: 2 with these values
Cloison Placostil 72/48 | R+3 | Mur (Classification ARCHICAD); Cloison (Classification ARCHICAD) | Finition int - Plaque de plâtre (2), Isolation - Laine de roche | Non défini | 0.04 | 840 | 160 | 23.4 (MJ/kg) | 1.73 (kgCO₂/kg) | Isolation - Laine de roche | no | 1.50857 | 2.5 | 0.105598 | 3.54643 | 3.54643 | 0.263996 | 0.263996 | 0.8 | 1000 | 1600 | 1.45 (MJ/kg) | 0.22 (kgCO₂/kg) | Finition int - Plaque de plâtre | no | Material Properties - Component 1: 2 with these values
Cloison Placostil 72/48 | R+3 | Mur (Classification ARCHICAD); Cloison (Classification ARCHICAD) | Finition int - Plaque de plâtre (2), Isolation - Laine de roche | Non défini | 0.04 | 840 | 160 | 23.4 (MJ/kg) | 1.73 (kgCO₂/kg) | Isolation - Laine de roche | no | 0.625213 | 2.5 | 0.0475138 | 1.56303 | 1.56303 | 0.118784 | 0.118784 | 0.8 | 1000 | 1600 | 1.45 (MJ/kg) | 0.22 (kgCO₂/kg) | Finition int - Plaque de plâtre | no | Material Properties - Component 1: 2 with these values
Cloison Placostil 72/48 | R+3 | Mur (Classification ARCHICAD); Cloison (Classification ARCHICAD) | Finition int - Plaque de plâtre (2), Isolation - Laine de roche | Non défini | 0.04 | 840 | 160 | 23.4 (MJ/kg) | 1.73 (kgCO₂/kg) | Isolation - Laine de roche | no | 1.51565 | 2.5 | 0.111534 | 3.72913 | 3.72913 | 0.278836 | 0.278836 | Material Properties - Component 3, Finition int - Plaque de plâtre, ThermalConductivity: 0.8; Component 3, Finition int - Plaque de plâtre, SpecificHeatCapacity: 1000 J/kg/K; Component 3, Finition int - Plaque de plâtre, MassDensity: 1600 kg/m3; Component 3, Finition int - Plaque de plâtre, Embodied Energy: 1.45 (MJ/kg); Component 3, Finition int - Plaque de plâtre, Embodied Carbon: 0.22 (kgCO₂/kg); Component 3, Finition int - Plaque de plâtre, Name: Finition int - Plaque de plâtre; Component 3, Finition int - Plaque de plâtre, Participates in Collision Detection: no; Component 3: 2 with these values
Cloison Placostil 72/48 | R+3 | Mur (Classification ARCHICAD); Cloison (Classification ARCHICAD) | Finition int - Plaque de plâtre (2), Isolation - Laine de roche | Non défini | 0.04 | 840 | 160 | 23.4 (MJ/kg) | 1.73 (kgCO₂/kg) | Isolation - Laine de roche | no | 1.04574 | 2.5 | 0.0766876 | 2.59809 | 2.59809 | 0.191719 | 0.191719 | 0.8 | 1000 | 1600 | 1.45 (MJ/kg) | 0.22 (kgCO₂/kg) | Finition int - Plaque de plâtre | no | Material Properties - Component 1: 2 with these values
2 x Cloison Placostil 72/48 | R+3 | Mur (Classification ARCHICAD); Cloison (Classification ARCHICAD) | Finition int - Plaque de plâtre (2), Isolation - Laine de roche | Non défini | 0.04 | 840 | 160 | 23.4 (MJ/kg) | 1.73 (kgCO₂/kg) | Isolation - Laine de roche | no | 0.6 | 2.5 | 0.045648 | 1.5 | 1.5 | 0.11412 | 0.11412 | Material Properties - Component 3, Finition int - Plaque de plâtre, ThermalConductivity: 0.8; Component 3, Finition int - Plaque de plâtre, SpecificHeatCapacity: 1000 J/kg/K; Component 3, Finition int - Plaque de plâtre, MassDensity: 1600 kg/m3; Component 3, Finition int - Plaque de plâtre, Embodied Energy: 1.45 (MJ/kg); Component 3, Finition int - Plaque de plâtre, Embodied Carbon: 0.22 (kgCO₂/kg); Component 3, Finition int - Plaque de plâtre, Name: Finition int - Plaque de plâtre; Component 3, Finition int - Plaque de plâtre, Participates in Collision Detection: no; Component 3: 2 with these values
Cloison Placostil 72/48 | R+3 | Mur (Classification ARCHICAD); Cloison (Classification ARCHICAD) | Finition int - Plaque de plâtre (2), Isolation - Laine de roche | Non défini | 0.04 | 840 | 160 | 23.4 (MJ/kg) | 1.73 (kgCO₂/kg) | Isolation - Laine de roche | no | 1.33279 | 2.5 | 0.102221 | 2.90218 | 2.90218 | 0.220476 | 0.220476 | Material Properties - Component 3, Finition int - Plaque de plâtre, ThermalConductivity: 0.8; Component 3, Finition int - Plaque de plâtre, SpecificHeatCapacity: 1000 J/kg/K; Component 3, Finition int - Plaque de plâtre, MassDensity: 1600 kg/m3; Component 3, Finition int - Plaque de plâtre, Embodied Energy: 1.45 (MJ/kg); Component 3, Finition int - Plaque de plâtre, Embodied Carbon: 0.22 (kgCO₂/kg); Component 3, Finition int - Plaque de plâtre, Name: Finition int - Plaque de plâtre; Component 3, Finition int - Plaque de plâtre, Participates in Collision Detection: no; Component 3: 2 with these values
Cloison Placostil 72/48 | R+3 | Mur (Classification ARCHICAD); Cloison (Classification ARCHICAD) | Finition int - Plaque de plâtre (2), Isolation - Laine de roche | Non défini | 0.04 | 840 | 160 | 23.4 (MJ/kg) | 1.73 (kgCO₂/kg) | Isolation - Laine de roche | no | 2.07 | 2.5 | 0.086464 | 5.175 | 3.2822 | 0.38451 | 0.244443 | Material Properties - Component 3, Finition int - Plaque de plâtre, ThermalConductivity: 0.8; Component 3, Finition int - Plaque de plâtre, SpecificHeatCapacity: 1000 J/kg/K; Component 3, Finition int - Plaque de plâtre, MassDensity: 1600 kg/m3; Component 3, Finition int - Plaque de plâtre, Embodied Energy: 1.45 (MJ/kg); Component 3, Finition int - Plaque de plâtre, Embodied Carbon: 0.22 (kgCO₂/kg); Component 3, Finition int - Plaque de plâtre, Name: Finition int - Plaque de plâtre; Component 3, Finition int - Plaque de plâtre, Participates in Collision Detection: no; Component 3: 2 with these values
Cloison Placostil 72/48 | R+3 | Mur (Classification ARCHICAD); Cloison (Classification ARCHICAD) | Finition int - Plaque de plâtre (2), Isolation - Laine de roche | Non défini | 0.04 | 840 | 160 | 23.4 (MJ/kg) | 1.73 (kgCO₂/kg) | Isolation - Laine de roche | no | 1.387 | 2.5 | 0.101941 | 3.45125 | 3.45125 | 0.254852 | 0.254852 | Material Properties - Component 3, Finition int - Plaque de plâtre, ThermalConductivity: 0.8; Component 3, Finition int - Plaque de plâtre, SpecificHeatCapacity: 1000 J/kg/K; Component 3, Finition int - Plaque de plâtre, MassDensity: 1600 kg/m3; Component 3, Finition int - Plaque de plâtre, Embodied Energy: 1.45 (MJ/kg); Component 3, Finition int - Plaque de plâtre, Embodied Carbon: 0.22 (kgCO₂/kg); Component 3, Finition int - Plaque de plâtre, Name: Finition int - Plaque de plâtre; Component 3, Finition int - Plaque de plâtre, Participates in Collision Detection: no; Component 3: 2 with these values
Cloison Placostil 72/48 | R+3 | Mur (Classification ARCHICAD); Cloison (Classification ARCHICAD) | Finition int - Plaque de plâtre (2), Isolation - Laine de roche | Non défini | 0.04 | 840 | 160 | 23.4 (MJ/kg) | 1.73 (kgCO₂/kg) | Isolation - Laine de roche | no | 3.39417 | 2.5 | 0.251169 | 8.42542 | 8.42542 | 0.627921 | 0.627921 | 0.8 | 1000 | 1600 | 1.45 (MJ/kg) | 0.22 (kgCO₂/kg) | Finition int - Plaque de plâtre | no | Material Properties - Component 1: 2 with these values
Cloison Placostil 72/48 | R+3 | Mur (Classification ARCHICAD); Cloison (Classification ARCHICAD) | Finition int - Plaque de plâtre (2), Isolation - Laine de roche | Non défini | 0.04 | 840 | 160 | 23.4 (MJ/kg) | 1.73 (kgCO₂/kg) | Isolation - Laine de roche | no | 0.694 | 2.5 | 0.051356 | 1.735 | 1.735 | 0.12839 | 0.12839 | Material Properties - Component 3, Finition int - Plaque de plâtre, ThermalConductivity: 0.8; Component 3, Finition int - Plaque de plâtre, SpecificHeatCapacity: 1000 J/kg/K; Component 3, Finition int - Plaque de plâtre, MassDensity: 1600 kg/m3; Component 3, Finition int - Plaque de plâtre, Embodied Energy: 1.45 (MJ/kg); Component 3, Finition int - Plaque de plâtre, Embodied Carbon: 0.22 (kgCO₂/kg); Component 3, Finition int - Plaque de plâtre, Name: Finition int - Plaque de plâtre; Component 3, Finition int - Plaque de plâtre, Participates in Collision Detection: no; Component 3: 2 with these values
Cloison Placostil 72/48 | R+3 | Mur (Classification ARCHICAD); Cloison (Classification ARCHICAD) | Finition int - Plaque de plâtre (2), Isolation - Laine de roche | Non défini | 0.04 | 840 | 160 | 23.4 (MJ/kg) | 1.73 (kgCO₂/kg) | Isolation - Laine de roche | no | 0.637 | 2.5 | 0.046441 | 1.57625 | 1.57625 | 0.116102 | 0.116102 | Material Properties - Component 3, Finition int - Plaque de plâtre, ThermalConductivity: 0.8; Component 3, Finition int - Plaque de plâtre, SpecificHeatCapacity: 1000 J/kg/K; Component 3, Finition int - Plaque de plâtre, MassDensity: 1600 kg/m3; Component 3, Finition int - Plaque de plâtre, Embodied Energy: 1.45 (MJ/kg); Component 3, Finition int - Plaque de plâtre, Embodied Carbon: 0.22 (kgCO₂/kg); Component 3, Finition int - Plaque de plâtre, Name: Finition int - Plaque de plâtre; Component 3, Finition int - Plaque de plâtre, Participates in Collision Detection: no; Component 3: 2 with these values
Cloison Placostil 72/48 | R+3 | Mur (Classification ARCHICAD); Cloison (Classification ARCHICAD) | Finition int - Plaque de plâtre (2), Isolation - Laine de roche | Non défini | 0.04 | 840 | 160 | 23.4 (MJ/kg) | 1.73 (kgCO₂/kg) | Isolation - Laine de roche | no | 0.966221 | 2.5 | 0.00478435 | 2.41555 | 0.522753 | 0.180311 | 0.0402437 | 0.8 | 1000 | 1600 | 1.45 (MJ/kg) | 0.22 (kgCO₂/kg) | Finition int - Plaque de plâtre | no | Material Properties - Component 1: 2 with these values
Cloison Placostil 72/48 | R+3 | Mur (Classification ARCHICAD); Cloison (Classification ARCHICAD) | Finition int - Plaque de plâtre (2), Isolation - Laine de roche | Non défini | 0.04 | 840 | 160 | 23.4 (MJ/kg) | 1.73 (kgCO₂/kg) | Isolation - Laine de roche | no | 1.45 | 2.5 | 0.000624 | 3.625 | 0.609 | 0.26981 | 0.046626 | Material Properties - Component 3, Finition int - Plaque de plâtre, ThermalConductivity: 0.8; Component 3, Finition int - Plaque de plâtre, SpecificHeatCapacity: 1000 J/kg/K; Component 3, Finition int - Plaque de plâtre, MassDensity: 1600 kg/m3; Component 3, Finition int - Plaque de plâtre, Embodied Energy: 1.45 (MJ/kg); Component 3, Finition int - Plaque de plâtre, Embodied Carbon: 0.22 (kgCO₂/kg); Component 3, Finition int - Plaque de plâtre, Name: Finition int - Plaque de plâtre; Component 3, Finition int - Plaque de plâtre, Participates in Collision Detection: no; Component 3: 2 with these values
Cloison Placostil 72/48 | R+3 | Mur (Classification ARCHICAD); Cloison (Classification ARCHICAD) | Finition int - Plaque de plâtre (2), Isolation - Laine de roche | Non défini | 0.04 | 840 | 160 | 23.4 (MJ/kg) | 1.73 (kgCO₂/kg) | Isolation - Laine de roche | no | 1.4 | 0.42 | 0 | 3.31 | 0.398 | 0.25406 | 0.038572 | Material Properties - Component 3, Finition int - Plaque de plâtre, ThermalConductivity: 0.8; Component 3, Finition int - Plaque de plâtre, SpecificHeatCapacity: 1000 J/kg/K; Component 3, Finition int - Plaque de plâtre, MassDensity: 1600 kg/m3; Component 3, Finition int - Plaque de plâtre, Embodied Energy: 1.45 (MJ/kg); Component 3, Finition int - Plaque de plâtre, Embodied Carbon: 0.22 (kgCO₂/kg); Component 3, Finition int - Plaque de plâtre, Name: Finition int - Plaque de plâtre; Component 3, Finition int - Plaque de plâtre, Participates in Collision Detection: no; Component 3: 2 with these values
Cloison Placostil 72/48 | R+3 | Mur (Classification ARCHICAD); Cloison (Classification ARCHICAD) | Finition int - Plaque de plâtre (2), Isolation - Laine de roche | Non défini | 0.04 | 840 | 160 | 23.4 (MJ/kg) | 1.73 (kgCO₂/kg) | Isolation - Laine de roche | no | 2.09955 | 2.5 | 0.0886509 | 5.24888 | 3.35608 | 0.389977 | 0.24991 | 0.8 | 1000 | 1600 | 1.45 (MJ/kg) | 0.22 (kgCO₂/kg) | Finition int - Plaque de plâtre | no | Material Properties - Component 1: 2 with these values
Cloison Placostil 72/48 | R+3 | Mur (Classification ARCHICAD); Cloison (Classification ARCHICAD) | Finition int - Plaque de plâtre (2), Isolation - Laine de roche | Non défini | 0.04 | 840 | 160 | 23.4 (MJ/kg) | 1.73 (kgCO₂/kg) | Isolation - Laine de roche | no | 3.92129 | 2.49 | 0.290872 | 9.72044 | 9.72044 | 0.724272 | 0.724272 | 0.8 | 1000 | 1600 | 1.45 (MJ/kg) | 0.22 (kgCO₂/kg) | Finition int - Plaque de plâtre | no | Material Properties - Component 1: 2 with these values
Cloison Placostil 72/48 | R+3 | Mur (Classification ARCHICAD); Cloison (Classification ARCHICAD) | Finition int - Plaque de plâtre (2), Isolation - Laine de roche | Non défini | 0.04 | 840 | 160 | 23.4 (MJ/kg) | 1.73 (kgCO₂/kg) | Isolation - Laine de roche | no | 0.637 | 2.5 | 0.049199 | 1.62732 | 1.62732 | 0.122513 | 0.122513 | Material Properties - Component 3, Finition int - Plaque de plâtre, ThermalConductivity: 0.8; Component 3, Finition int - Plaque de plâtre, SpecificHeatCapacity: 1000 J/kg/K; Component 3, Finition int - Plaque de plâtre, MassDensity: 1600 kg/m3; Component 3, Finition int - Plaque de plâtre, Embodied Energy: 1.45 (MJ/kg); Component 3, Finition int - Plaque de plâtre, Embodied Carbon: 0.22 (kgCO₂/kg); Component 3, Finition int - Plaque de plâtre, Name: Finition int - Plaque de plâtre; Component 3, Finition int - Plaque de plâtre, Participates in Collision Detection: no; Component 3: 2 with these values
Cloison Placostil 72/48 | R+3 | Mur (Classification ARCHICAD); Cloison (Classification ARCHICAD) | Finition int - Plaque de plâtre (2), Isolation - Laine de roche | Non défini | 0.04 | 840 | 160 | 23.4 (MJ/kg) | 1.73 (kgCO₂/kg) | Isolation - Laine de roche | no | 0.287 | 2.49 | 0.020541 | 0.698445 | 0.698445 | 0.0511471 | 0.0511471 | Material Properties - Component 3, Finition int - Plaque de plâtre, ThermalConductivity: 0.8; Component 3, Finition int - Plaque de plâtre, SpecificHeatCapacity: 1000 J/kg/K; Component 3, Finition int - Plaque de plâtre, MassDensity: 1600 kg/m3; Component 3, Finition int - Plaque de plâtre, Embodied Energy: 1.45 (MJ/kg); Component 3, Finition int - Plaque de plâtre, Embodied Carbon: 0.22 (kgCO₂/kg); Component 3, Finition int - Plaque de plâtre, Name: Finition int - Plaque de plâtre; Component 3, Finition int - Plaque de plâtre, Participates in Collision Detection: no; Component 3: 2 with these values
Cloison Placostil 72/48 | R+3 | Mur (Classification ARCHICAD); Cloison (Classification ARCHICAD) | Finition int - Plaque de plâtre (2), Isolation - Laine de roche | Non défini | 0.04 | 840 | 160 | 23.4 (MJ/kg) | 1.73 (kgCO₂/kg) | Isolation - Laine de roche | no | 0.637 | 2.49 | 0.049083 | 1.60232 | 1.60232 | 0.122217 | 0.122217 | Material Properties - Component 3, Finition int - Plaque de plâtre, ThermalConductivity: 0.8; Component 3, Finition int - Plaque de plâtre, SpecificHeatCapacity: 1000 J/kg/K; Component 3, Finition int - Plaque de plâtre, MassDensity: 1600 kg/m3; Component 3, Finition int - Plaque de plâtre, Embodied Energy: 1.45 (MJ/kg); Component 3, Finition int - Plaque de plâtre, Embodied Carbon: 0.22 (kgCO₂/kg); Component 3, Finition int - Plaque de plâtre, Name: Finition int - Plaque de plâtre; Component 3, Finition int - Plaque de plâtre, Participates in Collision Detection: no; Component 3: 2 with these values
Cloison Placostil 72/48 | R+3 | Mur (Classification ARCHICAD); Cloison (Classification ARCHICAD) | Finition int - Plaque de plâtre (2), Isolation - Laine de roche | Non défini | 0.04 | 840 | 160 | 23.4 (MJ/kg) | 1.73 (kgCO₂/kg) | Isolation - Laine de roche | no | 1.79147 | 2.49 | 0.131872 | 4.44457 | 4.44457 | 0.32836 | 0.32836 | Material Properties - Component 3, Finition int - Plaque de plâtre, ThermalConductivity: 0.8; Component 3, Finition int - Plaque de plâtre, SpecificHeatCapacity: 1000 J/kg/K; Component 3, Finition int - Plaque de plâtre, MassDensity: 1600 kg/m3; Component 3, Finition int - Plaque de plâtre, Embodied Energy: 1.45 (MJ/kg); Component 3, Finition int - Plaque de plâtre, Embodied Carbon: 0.22 (kgCO₂/kg); Component 3, Finition int - Plaque de plâtre, Name: Finition int - Plaque de plâtre; Component 3, Finition int - Plaque de plâtre, Participates in Collision Detection: no; Component 3: 2 with these values
Cloison Placostil 72/48 | R+3 | Mur (Classification ARCHICAD); Cloison (Classification ARCHICAD) | Finition int - Plaque de plâtre (2), Isolation - Laine de roche | Non défini | 0.04 | 840 | 160 | 23.4 (MJ/kg) | 1.73 (kgCO₂/kg) | Isolation - Laine de roche | no | 0.31902 | 2.49 | 0.0262495 | 0.826731 | 0.826731 | 0.0653613 | 0.0653613 | 0.8 | 1000 | 1600 | 1.45 (MJ/kg) | 0.22 (kgCO₂/kg) | Finition int - Plaque de plâtre | no | Material Properties - Component 1: 2 with these values
Cloison Placostil 72/48 | R+3 | Mur (Classification ARCHICAD); Cloison (Classification ARCHICAD) | Finition int - Plaque de plâtre (2), Isolation - Laine de roche | 35 dB(A) | 0.04 | 840 | 160 | 23.4 (MJ/kg) | 1.73 (kgCO₂/kg) | Isolation - Laine de roche | no | 0.71 | 2.5 | 0.06214 | 1.775 | 1.775 | 0.15535 | 0.15535 | Material Properties - Component 3, Finition int - Plaque de plâtre, ThermalConductivity: 0.8; Component 3, Finition int - Plaque de plâtre, SpecificHeatCapacity: 1000 J/kg/K; Component 3, Finition int - Plaque de plâtre, MassDensity: 1600 kg/m3; Component 3, Finition int - Plaque de plâtre, Embodied Energy: 1.45 (MJ/kg); Component 3, Finition int - Plaque de plâtre, Embodied Carbon: 0.22 (kgCO₂/kg); Component 3, Finition int - Plaque de plâtre, Name: Finition int - Plaque de plâtre; Component 3, Finition int - Plaque de plâtre, Participates in Collision Detection: no; Component 3: 2 with these values
Cloison Placostil 72/48 | R+3 | Mur (Classification ARCHICAD); Cloison (Classification ARCHICAD) | Finition int - Plaque de plâtre (2), Isolation - Laine de roche | 35 dB(A) | 0.04 | 840 | 160 | 23.4 (MJ/kg) | 1.73 (kgCO₂/kg) | Isolation - Laine de roche | no | 0.689 | 2.5 | 0.05161 | 1.7225 | 1.7225 | 0.129025 | 0.129025 | Material Properties - Component 3, Finition int - Plaque de plâtre, ThermalConductivity: 0.8; Component 3, Finition int - Plaque de plâtre, SpecificHeatCapacity: 1000 J/kg/K; Component 3, Finition int - Plaque de plâtre, MassDensity: 1600 kg/m3; Component 3, Finition int - Plaque de plâtre, Embodied Energy: 1.45 (MJ/kg); Component 3, Finition int - Plaque de plâtre, Embodied Carbon: 0.22 (kgCO₂/kg); Component 3, Finition int - Plaque de plâtre, Name: Finition int - Plaque de plâtre; Component 3, Finition int - Plaque de plâtre, Participates in Collision Detection: no; Component 3: 2 with these values
Cloison Placostil 72/48 | R+4 | Mur (Classification ARCHICAD); Cloison (Classification ARCHICAD) | Finition int - Plaque de plâtre (2), Isolation - Laine de roche | Non défini | 0.04 | 840 | 160 | 23.4 (MJ/kg) | 1.73 (kgCO₂/kg) | Isolation - Laine de roche | no | 1.575 | 2.5 | 0.117247 | 3.89375 | 3.89375 | 0.293117 | 0.293117 | 0.8 | 1000 | 1600 | 1.45 (MJ/kg) | 0.22 (kgCO₂/kg) | Finition int - Plaque de plâtre | no | Material Properties - Component 1: 2 with these values
Cloison Placostil 72/48 | R+4 | Mur (Classification ARCHICAD); Cloison (Classification ARCHICAD) | Finition int - Plaque de plâtre (2), Isolation - Laine de roche | Non défini | 0.04 | 840 | 160 | 23.4 (MJ/kg) | 1.73 (kgCO₂/kg) | Isolation - Laine de roche | no | 0.324581 | 2.5 | 0.021377 | 0.778951 | 0.778951 | 0.0534424 | 0.0534424 | 0.8 | 1000 | 1600 | 1.45 (MJ/kg) | 0.22 (kgCO₂/kg) | Finition int - Plaque de plâtre | no | Material Properties - Component 1: 2 with these values
Cloison Placostil 72/48 | R+4 | Mur (Classification ARCHICAD); Cloison (Classification ARCHICAD) | Finition int - Plaque de plâtre (2), Isolation - Laine de roche | Non défini | 0.04 | 840 | 160 | 23.4 (MJ/kg) | 1.73 (kgCO₂/kg) | Isolation - Laine de roche | no | 2.36263 | 2.48 | 0.004059 | 5.87545 | 1.08465 | 0.436866 | 0.0823469 | 0.8 | 1000 | 1600 | 1.45 (MJ/kg) | 0.22 (kgCO₂/kg) | Finition int - Plaque de plâtre | no | Material Properties - Component 1: 2 with these values
Cloison Placostil 72/48 | R+4 | Mur (Classification ARCHICAD); Cloison (Classification ARCHICAD) | Finition int - Plaque de plâtre (2), Isolation - Laine de roche | Non défini | 0.04 | 840 | 160 | 23.4 (MJ/kg) | 1.73 (kgCO₂/kg) | Isolation - Laine de roche | no | 2.53695 | 2.48 | 0.187734 | 6.29164 | 6.29164 | 0.465581 | 0.465581 | Material Properties - Component 3, Finition int - Plaque de plâtre, ThermalConductivity: 0.8; Component 3, Finition int - Plaque de plâtre, SpecificHeatCapacity: 1000 J/kg/K; Component 3, Finition int - Plaque de plâtre, MassDensity: 1600 kg/m3; Component 3, Finition int - Plaque de plâtre, Embodied Energy: 1.45 (MJ/kg); Component 3, Finition int - Plaque de plâtre, Embodied Carbon: 0.22 (kgCO₂/kg); Component 3, Finition int - Plaque de plâtre, Name: Finition int - Plaque de plâtre; Component 3, Finition int - Plaque de plâtre, Participates in Collision Detection: no; Component 3: 2 with these values
Cloison Placostil 72/48 | R+4 | Mur (Classification ARCHICAD); Cloison (Classification ARCHICAD) | Finition int - Plaque de plâtre (2), Isolation - Laine de roche | Non défini | 0.04 | 840 | 160 | 23.4 (MJ/kg) | 1.73 (kgCO₂/kg) | Isolation - Laine de roche | no | 1.5365 | 2.48 | 0.109965 | 3.76493 | 3.76493 | 0.272713 | 0.272713 | Material Properties - Component 3, Finition int - Plaque de plâtre, ThermalConductivity: 0.8; Component 3, Finition int - Plaque de plâtre, SpecificHeatCapacity: 1000 J/kg/K; Component 3, Finition int - Plaque de plâtre, MassDensity: 1600 kg/m3; Component 3, Finition int - Plaque de plâtre, Embodied Energy: 1.45 (MJ/kg); Component 3, Finition int - Plaque de plâtre, Embodied Carbon: 0.22 (kgCO₂/kg); Component 3, Finition int - Plaque de plâtre, Name: Finition int - Plaque de plâtre; Component 3, Finition int - Plaque de plâtre, Participates in Collision Detection: no; Component 3: 2 with these values
Cloison Placostil 72/48 | R+4 | Mur (Classification ARCHICAD); Cloison (Classification ARCHICAD) | Finition int - Plaque de plâtre (2), Isolation - Laine de roche | Non défini | 0.04 | 840 | 160 | 23.4 (MJ/kg) | 1.73 (kgCO₂/kg) | Isolation - Laine de roche | no | 2.085 | 2.5 | 0.156235 | 5.22875 | 5.22875 | 0.390588 | 0.390588 | 0.8 | 1000 | 1600 | 1.45 (MJ/kg) | 0.22 (kgCO₂/kg) | Finition int - Plaque de plâtre | no | Material Properties - Component 1: 2 with these values
Cloison Placostil 72/48 | Rez-de-chaussée | Cloison (Classification ARCHICAD) | Finition int - Plaque de plâtre (2), Isolation - Laine de roche | Non défini | 0.04 | 840 | 160 | 23.4 (MJ/kg) | 1.73 (kgCO₂/kg) | Isolation - Laine de roche | no | 0.63557 | 2.5 | 0.0489772 | 1.60517 | 1.60517 | 0.122443 | 0.122443 | 0.8 | 1000 | 1600 | 1.45 (MJ/kg) | 0.22 (kgCO₂/kg) | Finition int - Plaque de plâtre | no | Material Properties - Component 1: 2 with these values
Cloison Placostil 72/48 | Rez-de-chaussée | Cloison (Classification ARCHICAD) | Finition int - Plaque de plâtre (2), Isolation - Laine de roche | Non défini | 0.04 | 840 | 160 | 23.4 (MJ/kg) | 1.73 (kgCO₂/kg) | Isolation - Laine de roche | no | 0.637 | 2.5 | 0.049083 | 1.4157 | 1.4157 | 0.117688 | 0.117688 | Material Properties - Component 3, Finition int - Plaque de plâtre, ThermalConductivity: 0.8; Component 3, Finition int - Plaque de plâtre, SpecificHeatCapacity: 1000 J/kg/K; Component 3, Finition int - Plaque de plâtre, MassDensity: 1600 kg/m3; Component 3, Finition int - Plaque de plâtre, Embodied Energy: 1.45 (MJ/kg); Component 3, Finition int - Plaque de plâtre, Embodied Carbon: 0.22 (kgCO₂/kg); Component 3, Finition int - Plaque de plâtre, Name: Finition int - Plaque de plâtre; Component 3, Finition int - Plaque de plâtre, Participates in Collision Detection: no; Component 3: 2 with these values
Cloison Placostil 72/48 | Rez-de-chaussée | Cloison (Classification ARCHICAD) | Finition int - Plaque de plâtre (2), Isolation - Laine de roche | Non défini | 0.04 | 840 | 160 | 23.4 (MJ/kg) | 1.73 (kgCO₂/kg) | Isolation - Laine de roche | no | 0.637 | 2.5 | 0.048761 | 1.63375 | 1.6175 | 0.122997 | 0.121903 | 0.8 | 1000 | 1600 | 1.45 (MJ/kg) | 0.22 (kgCO₂/kg) | Finition int - Plaque de plâtre | no | Material Properties - Component 1: 2 with these values
2 x Cloison Placostil 72/48 | Rez-de-chaussée | Cloison (Classification ARCHICAD) | Finition int - Plaque de plâtre (2), Isolation - Laine de roche | Non défini | 0.04 | 840 | 160 | 23.4 (MJ/kg) | 1.73 (kgCO₂/kg) | Isolation - Laine de roche | no | 0.637 | 2.5 | 0.049199 | 1.63375 | 1.63375 | 0.122997 | 0.122997 | Material Properties - Component 3, Finition int - Plaque de plâtre, ThermalConductivity: 0.8; Component 3, Finition int - Plaque de plâtre, SpecificHeatCapacity: 1000 J/kg/K; Component 3, Finition int - Plaque de plâtre, MassDensity: 1600 kg/m3; Component 3, Finition int - Plaque de plâtre, Embodied Energy: 1.45 (MJ/kg); Component 3, Finition int - Plaque de plâtre, Embodied Carbon: 0.22 (kgCO₂/kg); Component 3, Finition int - Plaque de plâtre, Name: Finition int - Plaque de plâtre; Component 3, Finition int - Plaque de plâtre, Participates in Collision Detection: no; Component 3: 2 with these values
Cloison Placostil 72/48 | Rez-de-chaussée | Cloison (Classification ARCHICAD) | Finition int - Plaque de plâtre (2), Isolation - Laine de roche | Non défini | 0.04 | 840 | 160 | 23.4 (MJ/kg) | 1.73 (kgCO₂/kg) | Isolation - Laine de roche | no | 2.25661 | 2.5 | 0.16251 | 5.44561 | 5.44561 | 0.406275 | 0.406275 | Material Properties - Component 3, Finition int - Plaque de plâtre, ThermalConductivity: 0.8; Component 3, Finition int - Plaque de plâtre, SpecificHeatCapacity: 1000 J/kg/K; Component 3, Finition int - Plaque de plâtre, MassDensity: 1600 kg/m3; Component 3, Finition int - Plaque de plâtre, Embodied Energy: 1.45 (MJ/kg); Component 3, Finition int - Plaque de plâtre, Embodied Carbon: 0.22 (kgCO₂/kg); Component 3, Finition int - Plaque de plâtre, Name: Finition int - Plaque de plâtre; Component 3, Finition int - Plaque de plâtre, Participates in Collision Detection: no; Component 3: 2 with these values
Cloison Placostil 72/48 | Rez-de-chaussée | Cloison (Classification ARCHICAD) | Finition int - Plaque de plâtre (2), Isolation - Laine de roche | Non défini | 0.04 | 840 | 160 | 23.4 (MJ/kg) | 1.73 (kgCO₂/kg) | Isolation - Laine de roche | no | 0.638 | 2.5 | 0.046631 | 1.60375 | 1.60375 | 0.116577 | 0.116577 | 0.8 | 1000 | 1600 | 1.45 (MJ/kg) | 0.22 (kgCO₂/kg) | Finition int - Plaque de plâtre | no | Material Properties - Component 1: 2 with these values
Cloison Placostil 72/48 | Rez-de-chaussée | Cloison (Classification ARCHICAD) | Finition int - Plaque de plâtre (2), Isolation - Laine de roche | Non défini | 0.04 | 840 | 160 | 23.4 (MJ/kg) | 1.73 (kgCO₂/kg) | Isolation - Laine de roche | no | 0.32501 | 2.5 | 0.0240507 | 0.812525 | 0.812525 | 0.0601268 | 0.0601268 | 0.8 | 1000 | 1600 | 1.45 (MJ/kg) | 0.22 (kgCO₂/kg) | Finition int - Plaque de plâtre | no | Material Properties - Component 1: 2 with these values
Cloison Placostil 72/48 | Rez-de-chaussée | Cloison (Classification ARCHICAD) | Finition int - Plaque de plâtre (2), Isolation - Laine de roche | Non défini | 0.04 | 840 | 160 | 23.4 (MJ/kg) | 1.73 (kgCO₂/kg) | Isolation - Laine de roche | no | 0.638 | 2.5 | 0.049273 | 1.63625 | 1.63625 | 0.123183 | 0.123183 | 0.8 | 1000 | 1600 | 1.45 (MJ/kg) | 0.22 (kgCO₂/kg) | Finition int - Plaque de plâtre | no | Material Properties - Component 1: 2 with these values
Cloison Placostil 72/48 | Rez-de-chaussée | Cloison (Classification ARCHICAD) | Finition int - Plaque de plâtre (2), Isolation - Laine de roche | Non défini | 0.04 | 840 | 160 | 23.4 (MJ/kg) | 1.73 (kgCO₂/kg) | Isolation - Laine de roche | no | 0.287 | 2.5 | 0.020541 | 0.70125 | 0.70125 | 0.0513525 | 0.0513525 | Material Properties - Component 3, Finition int - Plaque de plâtre, ThermalConductivity: 0.8; Component 3, Finition int - Plaque de plâtre, SpecificHeatCapacity: 1000 J/kg/K; Component 3, Finition int - Plaque de plâtre, MassDensity: 1600 kg/m3; Component 3, Finition int - Plaque de plâtre, Embodied Energy: 1.45 (MJ/kg); Component 3, Finition int - Plaque de plâtre, Embodied Carbon: 0.22 (kgCO₂/kg); Component 3, Finition int - Plaque de plâtre, Name: Finition int - Plaque de plâtre; Component 3, Finition int - Plaque de plâtre, Participates in Collision Detection: no; Component 3: 2 with these values
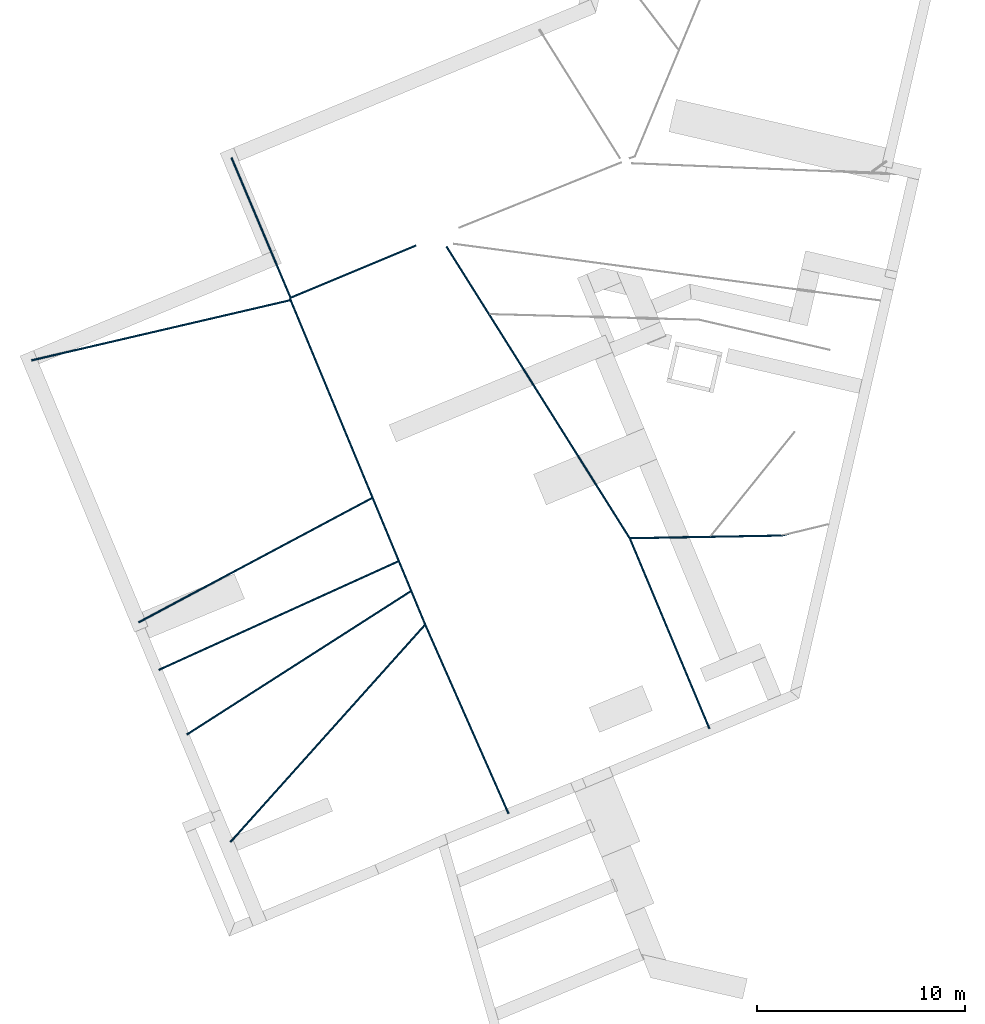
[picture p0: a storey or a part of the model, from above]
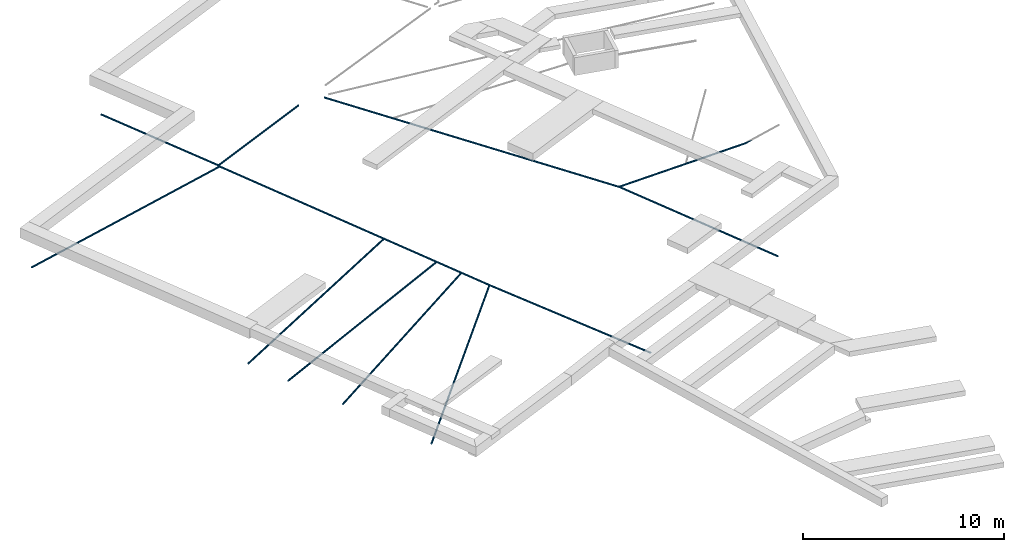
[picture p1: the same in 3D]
Properties of the parts of a building model (IFC2X3), part 13 of 22

# IfcWall: 3 - Cloison 72mm Placostil 74 (508)
Name | In | Classification | Material | AcousticRating | Component 2, Isolation - Laine de roche, ThermalConductivity | Component 2, Isolation - Laine de roche, SpecificHeatCapacity (J/kg/K) | Component 2, Isolation - Laine de roche, MassDensity (kg/m3) | Component 2, Isolation - Laine de roche, Embodied Energy | Component 2, Isolation - Laine de roche, Embodied Carbon | Component 2, Isolation - Laine de roche, Name | Component 2, Isolation - Laine de roche, Participates in Collision Detection | Length (m) | Height (m) | GrossFootprintArea (m2) = NetFootprintArea (m2) | GrossSideArea (m2) | NetSideArea (m2) | GrossVolume (m3) | NetVolume (m3) | Component 1, Finition int - Plaque de plâtre, ThermalConductivity | Component 1, Finition int - Plaque de plâtre, SpecificHeatCapacity (J/kg/K) | Component 1, Finition int - Plaque de plâtre, MassDensity (kg/m3) | Component 1, Finition int - Plaque de plâtre, Embodied Energy | Component 1, Finition int - Plaque de plâtre, Embodied Carbon | Component 1, Finition int - Plaque de plâtre, Name | Component 1, Finition int - Plaque de plâtre, Participates in Collision Detection
Cloison Placostil 72/48 | Rez-de-chaussée | Cloison (Classification ARCHICAD) | Finition int - Plaque de plâtre (2), Isolation - Laine de roche | Non défini | 0.04 | 840 | 160 | 23.4 (MJ/kg) | 1.73 (kgCO₂/kg) | Isolation - Laine de roche | no | 0.637 | 2.5 | 0.049083 | 1.60875 | 1.60875 | 0.122708 | 0.122708 | Material Properties - Component 3, Finition int - Plaque de plâtre, ThermalConductivity: 0.8; Component 3, Finition int - Plaque de plâtre, SpecificHeatCapacity: 1000 J/kg/K; Component 3, Finition int - Plaque de plâtre, MassDensity: 1600 kg/m3; Component 3, Finition int - Plaque de plâtre, Embodied Energy: 1.45 (MJ/kg); Component 3, Finition int - Plaque de plâtre, Embodied Carbon: 0.22 (kgCO₂/kg); Component 3, Finition int - Plaque de plâtre, Name: Finition int - Plaque de plâtre; Component 3, Finition int - Plaque de plâtre, Participates in Collision Detection: no; Component 3: 2 with these values
Cloison Placostil 72/48 | Rez-de-chaussée | Cloison (Classification ARCHICAD) | Finition int - Plaque de plâtre (2), Isolation - Laine de roche | Non défini | 0.04 | 840 | 160 | 23.4 (MJ/kg) | 1.73 (kgCO₂/kg) | Isolation - Laine de roche | no | 1.79147 | 2.5 | 0.131872 | 4.46242 | 4.46242 | 0.329679 | 0.329679 | Material Properties - Component 3, Finition int - Plaque de plâtre, ThermalConductivity: 0.8; Component 3, Finition int - Plaque de plâtre, SpecificHeatCapacity: 1000 J/kg/K; Component 3, Finition int - Plaque de plâtre, MassDensity: 1600 kg/m3; Component 3, Finition int - Plaque de plâtre, Embodied Energy: 1.45 (MJ/kg); Component 3, Finition int - Plaque de plâtre, Embodied Carbon: 0.22 (kgCO₂/kg); Component 3, Finition int - Plaque de plâtre, Name: Finition int - Plaque de plâtre; Component 3, Finition int - Plaque de plâtre, Participates in Collision Detection: no; Component 3: 2 with these values
Cloison Placostil 72/48 | Rez-de-chaussée | Cloison (Classification ARCHICAD) | Finition int - Plaque de plâtre (2), Isolation - Laine de roche | Non défini | 0.04 | 840 | 160 | 23.4 (MJ/kg) | 1.73 (kgCO₂/kg) | Isolation - Laine de roche | no | 0.31902 | 2.5 | 0.0236075 | 0.797551 | 0.797551 | 0.0590188 | 0.0590188 | 0.8 | 1000 | 1600 | 1.45 (MJ/kg) | 0.22 (kgCO₂/kg) | Finition int - Plaque de plâtre | no | Material Properties - Component 1: 2 with these values
Cloison Placostil 72/48 | Rez-de-chaussée | Cloison (Classification ARCHICAD) | Finition int - Plaque de plâtre (2), Isolation - Laine de roche | Non défini | 0.04 | 840 | 160 | 23.4 (MJ/kg) | 1.73 (kgCO₂/kg) | Isolation - Laine de roche | no | 3.94629 | 2.5 | 0.292723 | 9.82197 | 9.82197 | 0.731806 | 0.731806 | 0.8 | 1000 | 1600 | 1.45 (MJ/kg) | 0.22 (kgCO₂/kg) | Finition int - Plaque de plâtre | no | Material Properties - Component 1: 2 with these values
Cloison Placostil 72/48 | Rez-de-chaussée | Cloison (Classification ARCHICAD) | Finition int - Plaque de plâtre (2), Isolation - Laine de roche | Non défini | 0.04 | 840 | 160 | 23.4 (MJ/kg) | 1.73 (kgCO₂/kg) | Isolation - Laine de roche | no | 0.301167 | 2.5 | 0.0242317 | 0.769173 | 0.769173 | 0.0605793 | 0.0605793 | Material Properties - Component 3, Finition int - Plaque de plâtre, ThermalConductivity: 0.8; Component 3, Finition int - Plaque de plâtre, SpecificHeatCapacity: 1000 J/kg/K; Component 3, Finition int - Plaque de plâtre, MassDensity: 1600 kg/m3; Component 3, Finition int - Plaque de plâtre, Embodied Energy: 1.45 (MJ/kg); Component 3, Finition int - Plaque de plâtre, Embodied Carbon: 0.22 (kgCO₂/kg); Component 3, Finition int - Plaque de plâtre, Name: Finition int - Plaque de plâtre; Component 3, Finition int - Plaque de plâtre, Participates in Collision Detection: no; Component 3: 2 with these values
Cloison Placostil 72/48 | Rez-de-chaussée | Cloison (Classification ARCHICAD) | Finition int - Plaque de plâtre, Isolation - Laine de roche | Non défini | 0.04 | 840 | 160 | 23.4 (MJ/kg) | 1.73 (kgCO₂/kg) | Isolation - Laine de roche | no | 1.237 | 2.5 | 0.001417 | 2.71625 | 0.07625 | 0.216182 | 0.0035425 | 0.8 | 1000 | 1600 | 1.45 (MJ/kg) | 0.22 (kgCO₂/kg) | Finition int - Plaque de plâtre | no
Cloison Placostil 72/48 | Rez-de-chaussée | Cloison (Classification ARCHICAD) | Finition int - Plaque de plâtre (2), Isolation - Laine de roche | Non défini | 0.04 | 840 | 160 | 23.4 (MJ/kg) | 1.73 (kgCO₂/kg) | Isolation - Laine de roche | no | 0.7 | 2.5 | 0.054442 | 1.7825 | 1.7825 | 0.136105 | 0.136105 | 0.8 | 1000 | 1600 | 1.45 (MJ/kg) | 0.22 (kgCO₂/kg) | Finition int - Plaque de plâtre | no | Material Properties - Component 1: 2 with these values
Cloison Placostil 72/48 | Rez-de-chaussée | Cloison (Classification ARCHICAD) | Finition int - Plaque de plâtre (2), Isolation - Laine de roche | Non défini | 0.04 | 840 | 160 | 23.4 (MJ/kg) | 1.73 (kgCO₂/kg) | Isolation - Laine de roche | no | 3.427 | 2.5 | 0.251653 | 8.49125 | 8.49125 | 0.629132 | 0.629132 | 0.8 | 1000 | 1600 | 1.45 (MJ/kg) | 0.22 (kgCO₂/kg) | Finition int - Plaque de plâtre | no | Material Properties - Component 1: 2 with these values
Cloison Placostil 72/48 | Rez-de-chaussée | Cloison (Classification ARCHICAD) | Finition int - Plaque de plâtre (2), Isolation - Laine de roche | Non défini | 0.04 | 840 | 160 | 23.4 (MJ/kg) | 1.73 (kgCO₂/kg) | Isolation - Laine de roche | no | 3.22274 | 2.5 | 0.172464 | 8.0731 | 6.1803 | 0.59951 | 0.459442 | 0.8 | 1000 | 1600 | 1.45 (MJ/kg) | 0.22 (kgCO₂/kg) | Finition int - Plaque de plâtre | no | Material Properties - Component 1: 2 with these values
Cloison Placostil 72/48 | Rez-de-chaussée | Cloison (Classification ARCHICAD) | Finition int - Plaque de plâtre (2), Isolation - Laine de roche | Non défini | 0.04 | 840 | 160 | 23.4 (MJ/kg) | 1.73 (kgCO₂/kg) | Isolation - Laine de roche | no | 0.674 | 2.5 | 0.049876 | 1.685 | 1.685 | 0.12469 | 0.12469 | 0.8 | 1000 | 1600 | 1.45 (MJ/kg) | 0.22 (kgCO₂/kg) | Finition int - Plaque de plâtre | no | Material Properties - Component 1: 2 with these values
Cloison Placostil 72/48 | Rez-de-chaussée | Cloison (Classification ARCHICAD) | Finition int - Plaque de plâtre (2), Isolation - Laine de roche | Non défini | 0.04 | 840 | 160 | 23.4 (MJ/kg) | 1.73 (kgCO₂/kg) | Isolation - Laine de roche | no | 1.05755 | 2.5 | 0.0809007 | 2.67638 | 2.67638 | 0.202252 | 0.202252 | 0.8 | 1000 | 1600 | 1.45 (MJ/kg) | 0.22 (kgCO₂/kg) | Finition int - Plaque de plâtre | no | Material Properties - Component 1: 2 with these values
Cloison Placostil 72/48 | Rez-de-chaussée | Cloison (Classification ARCHICAD) | Finition int - Plaque de plâtre (2), Isolation - Laine de roche | Non défini | 0.04 | 840 | 160 | 23.4 (MJ/kg) | 1.73 (kgCO₂/kg) | Isolation - Laine de roche | no | 0.637 | 2.5 | 0.045193 | 1.51625 | 1.51625 | 0.112982 | 0.112982 | Material Properties - Component 3, Finition int - Plaque de plâtre, ThermalConductivity: 0.8; Component 3, Finition int - Plaque de plâtre, SpecificHeatCapacity: 1000 J/kg/K; Component 3, Finition int - Plaque de plâtre, MassDensity: 1600 kg/m3; Component 3, Finition int - Plaque de plâtre, Embodied Energy: 1.45 (MJ/kg); Component 3, Finition int - Plaque de plâtre, Embodied Carbon: 0.22 (kgCO₂/kg); Component 3, Finition int - Plaque de plâtre, Name: Finition int - Plaque de plâtre; Component 3, Finition int - Plaque de plâtre, Participates in Collision Detection: no; Component 3: 2 with these values
Cloison Placostil 72/48 | Rez-de-chaussée | Cloison (Classification ARCHICAD) | Finition int - Plaque de plâtre (2), Isolation - Laine de roche | Non défini | 0.04 | 840 | 160 | 23.4 (MJ/kg) | 1.73 (kgCO₂/kg) | Isolation - Laine de roche | no | 2.18055 | 2.5 | 0.161361 | 5.45138 | 5.45138 | 0.403402 | 0.403402 | 0.8 | 1000 | 1600 | 1.45 (MJ/kg) | 0.22 (kgCO₂/kg) | Finition int - Plaque de plâtre | no | Material Properties - Component 1: 2 with these values
Cloison Placostil 72/48 | Rez-de-chaussée | Cloison (Classification ARCHICAD) | Finition int - Plaque de plâtre (2), Isolation - Laine de roche | Non défini | 0.04 | 840 | 160 | 23.4 (MJ/kg) | 1.73 (kgCO₂/kg) | Isolation - Laine de roche | no | 0.491957 | 2.5 | 0.0351369 | 1.20662 | 1.20662 | 0.0878423 | 0.0878423 | 0.8 | 1000 | 1600 | 1.45 (MJ/kg) | 0.22 (kgCO₂/kg) | Finition int - Plaque de plâtre | no | Material Properties - Component 1: 2 with these values
Cloison Placostil 72/48 | Rez-de-chaussée | Cloison (Classification ARCHICAD) | Finition int - Plaque de plâtre (2), Isolation - Laine de roche | Non défini | 0.04 | 840 | 160 | 23.4 (MJ/kg) | 1.73 (kgCO₂/kg) | Isolation - Laine de roche | no | 1.437 | 2.5 | 0.037677 | 3.38125 | 1.48845 | 0.257473 | 0.117405 | 0.8 | 1000 | 1600 | 1.45 (MJ/kg) | 0.22 (kgCO₂/kg) | Finition int - Plaque de plâtre | no | Material Properties - Component 1: 2 with these values
Cloison Placostil 72/48 | Rez-de-chaussée | Cloison (Classification ARCHICAD) | Finition int - Plaque de plâtre (2), Isolation - Laine de roche | Non défini | 0.04 | 840 | 160 | 23.4 (MJ/kg) | 1.73 (kgCO₂/kg) | Isolation - Laine de roche | no | 0.287 | 2.5 | 0.020541 | 0.70125 | 0.70125 | 0.0513525 | 0.0513525 | 0.8 | 1000 | 1600 | 1.45 (MJ/kg) | 0.22 (kgCO₂/kg) | Finition int - Plaque de plâtre | no | Material Properties - Component 1: 2 with these values
Cloison Placostil 72/48 | Rez-de-chaussée | Cloison (Classification ARCHICAD) | Finition int - Plaque de plâtre (2), Isolation - Laine de roche | Non défini | 0.04 | 840 | 160 | 23.4 (MJ/kg) | 1.73 (kgCO₂/kg) | Isolation - Laine de roche | no | 0.913 | 2.5 | 0.06492 | 2.25 | 2.25 | 0.1623 | 0.1623 | Material Properties - Component 3, Finition int - Plaque de plâtre, ThermalConductivity: 0.8; Component 3, Finition int - Plaque de plâtre, SpecificHeatCapacity: 1000 J/kg/K; Component 3, Finition int - Plaque de plâtre, MassDensity: 1600 kg/m3; Component 3, Finition int - Plaque de plâtre, Embodied Energy: 1.45 (MJ/kg); Component 3, Finition int - Plaque de plâtre, Embodied Carbon: 0.22 (kgCO₂/kg); Component 3, Finition int - Plaque de plâtre, Name: Finition int - Plaque de plâtre; Component 3, Finition int - Plaque de plâtre, Participates in Collision Detection: no; Component 3: 2 with these values
Cloison Placostil 72/48 | Rez-de-chaussée | Cloison (Classification ARCHICAD) | Finition int - Plaque de plâtre (2), Isolation - Laine de roche | Non défini | 0.04 | 840 | 160 | 23.4 (MJ/kg) | 1.73 (kgCO₂/kg) | Isolation - Laine de roche | no | 0.225375 | 2.5 | 0.0153568 | 0.547188 | 0.547188 | 0.0383919 | 0.0383919 | Material Properties - Component 3, Finition int - Plaque de plâtre, ThermalConductivity: 0.8; Component 3, Finition int - Plaque de plâtre, SpecificHeatCapacity: 1000 J/kg/K; Component 3, Finition int - Plaque de plâtre, MassDensity: 1600 kg/m3; Component 3, Finition int - Plaque de plâtre, Embodied Energy: 1.45 (MJ/kg); Component 3, Finition int - Plaque de plâtre, Embodied Carbon: 0.22 (kgCO₂/kg); Component 3, Finition int - Plaque de plâtre, Name: Finition int - Plaque de plâtre; Component 3, Finition int - Plaque de plâtre, Participates in Collision Detection: no; Component 3: 2 with these values
Cloison Placostil 72/48 | Rez-de-chaussée | Cloison (Classification ARCHICAD) | Finition int - Plaque de plâtre (2), Isolation - Laine de roche | Non défini | 0.04 | 840 | 160 | 23.4 (MJ/kg) | 1.73 (kgCO₂/kg) | Isolation - Laine de roche | no | 0.286541 | 2.5 | 0.020507 | 0.700102 | 0.700102 | 0.0512675 | 0.0512675 | Material Properties - Component 3, Finition int - Plaque de plâtre, ThermalConductivity: 0.8; Component 3, Finition int - Plaque de plâtre, SpecificHeatCapacity: 1000 J/kg/K; Component 3, Finition int - Plaque de plâtre, MassDensity: 1600 kg/m3; Component 3, Finition int - Plaque de plâtre, Embodied Energy: 1.45 (MJ/kg); Component 3, Finition int - Plaque de plâtre, Embodied Carbon: 0.22 (kgCO₂/kg); Component 3, Finition int - Plaque de plâtre, Name: Finition int - Plaque de plâtre; Component 3, Finition int - Plaque de plâtre, Participates in Collision Detection: no; Component 3: 2 with these values
Cloison Placostil 72/48 | Rez-de-chaussée | Cloison (Classification ARCHICAD) | Finition int - Plaque de plâtre (2), Isolation - Laine de roche | Non défini | 0.04 | 840 | 160 | 23.4 (MJ/kg) | 1.73 (kgCO₂/kg) | Isolation - Laine de roche | no | 1.33039 | 2.5 | 0.00832806 | 3.05819 | 0.286192 | 0.23628 | 0.0202081 | 0.8 | 1000 | 1600 | 1.45 (MJ/kg) | 0.22 (kgCO₂/kg) | Finition int - Plaque de plâtre | no | Material Properties - Component 1: 2 with these values
Cloison Placostil 72/48 | Rez-de-chaussée | Cloison (Classification ARCHICAD) | Finition int - Plaque de plâtre (2), Isolation - Laine de roche | Non défini | 0.04 | 840 | 160 | 23.4 (MJ/kg) | 1.73 (kgCO₂/kg) | Isolation - Laine de roche | no | 2.70947 | 2.5 | 0.200501 | 6.71367 | 6.71367 | 0.501251 | 0.501251 | 0.8 | 1000 | 1600 | 1.45 (MJ/kg) | 0.22 (kgCO₂/kg) | Finition int - Plaque de plâtre | no | Material Properties - Component 1: 2 with these values
Cloison Placostil 72/48 | Rez-de-chaussée | Cloison (Classification ARCHICAD) | Finition int - Plaque de plâtre (2), Isolation - Laine de roche | Non défini | 0.04 | 840 | 160 | 23.4 (MJ/kg) | 1.73 (kgCO₂/kg) | Isolation - Laine de roche | no | 1.387 | 2.5 | 0.001417 | 3.45125 | 0.64325 | 0.253292 | 0.0455005 | Material Properties - Component 3, Finition int - Plaque de plâtre, ThermalConductivity: 0.8; Component 3, Finition int - Plaque de plâtre, SpecificHeatCapacity: 1000 J/kg/K; Component 3, Finition int - Plaque de plâtre, MassDensity: 1600 kg/m3; Component 3, Finition int - Plaque de plâtre, Embodied Energy: 1.45 (MJ/kg); Component 3, Finition int - Plaque de plâtre, Embodied Carbon: 0.22 (kgCO₂/kg); Component 3, Finition int - Plaque de plâtre, Name: Finition int - Plaque de plâtre; Component 3, Finition int - Plaque de plâtre, Participates in Collision Detection: no; Component 3: 2 with these values
Cloison Placostil 72/48 | Rez-de-chaussée | Cloison (Classification ARCHICAD) | Finition int - Plaque de plâtre (2), Isolation - Laine de roche | Non défini | 0.04 | 840 | 160 | 23.4 (MJ/kg) | 1.73 (kgCO₂/kg) | Isolation - Laine de roche | no | 0.483901 | 2.5 | 0.0384507 | 1.24225 | 1.24225 | 0.0961266 | 0.0961266 | Material Properties - Component 3, Finition int - Plaque de plâtre, ThermalConductivity: 0.8; Component 3, Finition int - Plaque de plâtre, SpecificHeatCapacity: 1000 J/kg/K; Component 3, Finition int - Plaque de plâtre, MassDensity: 1600 kg/m3; Component 3, Finition int - Plaque de plâtre, Embodied Energy: 1.45 (MJ/kg); Component 3, Finition int - Plaque de plâtre, Embodied Carbon: 0.22 (kgCO₂/kg); Component 3, Finition int - Plaque de plâtre, Name: Finition int - Plaque de plâtre; Component 3, Finition int - Plaque de plâtre, Participates in Collision Detection: no; Component 3: 2 with these values
Cloison Placostil 72/48 | Rez-de-chaussée | Cloison (Classification ARCHICAD) | Finition int - Plaque de plâtre (2), Isolation - Laine de roche | Non défini | 0.04 | 840 | 160 | 23.4 (MJ/kg) | 1.73 (kgCO₂/kg) | Isolation - Laine de roche | no | 0.387 | 2.5 | 0.029262 | 0.9675 | 0.9675 | 0.073155 | 0.073155 | Material Properties - Component 3, Finition int - Plaque de plâtre, ThermalConductivity: 0.8; Component 3, Finition int - Plaque de plâtre, SpecificHeatCapacity: 1000 J/kg/K; Component 3, Finition int - Plaque de plâtre, MassDensity: 1600 kg/m3; Component 3, Finition int - Plaque de plâtre, Embodied Energy: 1.45 (MJ/kg); Component 3, Finition int - Plaque de plâtre, Embodied Carbon: 0.22 (kgCO₂/kg); Component 3, Finition int - Plaque de plâtre, Name: Finition int - Plaque de plâtre; Component 3, Finition int - Plaque de plâtre, Participates in Collision Detection: no; Component 3: 2 with these values
Cloison Placostil 72/48 | Rez-de-chaussée | Cloison (Classification ARCHICAD) | Finition int - Plaque de plâtre (2), Isolation - Laine de roche | Non défini | 0.04 | 840 | 160 | 23.4 (MJ/kg) | 1.73 (kgCO₂/kg) | Isolation - Laine de roche | no | 1.57217 | 2.5 | 0.113698 | 3.89792 | 3.89792 | 0.284246 | 0.284246 | Material Properties - Component 3, Finition int - Plaque de plâtre, ThermalConductivity: 0.8; Component 3, Finition int - Plaque de plâtre, SpecificHeatCapacity: 1000 J/kg/K; Component 3, Finition int - Plaque de plâtre, MassDensity: 1600 kg/m3; Component 3, Finition int - Plaque de plâtre, Embodied Energy: 1.45 (MJ/kg); Component 3, Finition int - Plaque de plâtre, Embodied Carbon: 0.22 (kgCO₂/kg); Component 3, Finition int - Plaque de plâtre, Name: Finition int - Plaque de plâtre; Component 3, Finition int - Plaque de plâtre, Participates in Collision Detection: no; Component 3: 2 with these values
Cloison Placostil 72/48 | Rez-de-chaussée | Cloison (Classification ARCHICAD) | Finition int - Plaque de plâtre (2), Isolation - Laine de roche | Non défini | 0.04 | 840 | 160 | 23.4 (MJ/kg) | 1.73 (kgCO₂/kg) | Isolation - Laine de roche | no | 0.287 | 2.5 | 0.020657 | 0.6421 | 0.6421 | 0.0494546 | 0.0494546 | Material Properties - Component 3, Finition int - Plaque de plâtre, ThermalConductivity: 0.8; Component 3, Finition int - Plaque de plâtre, SpecificHeatCapacity: 1000 J/kg/K; Component 3, Finition int - Plaque de plâtre, MassDensity: 1600 kg/m3; Component 3, Finition int - Plaque de plâtre, Embodied Energy: 1.45 (MJ/kg); Component 3, Finition int - Plaque de plâtre, Embodied Carbon: 0.22 (kgCO₂/kg); Component 3, Finition int - Plaque de plâtre, Name: Finition int - Plaque de plâtre; Component 3, Finition int - Plaque de plâtre, Participates in Collision Detection: no; Component 3: 2 with these values
Cloison Placostil 72/48 | Rez-de-chaussée | Cloison (Classification ARCHICAD) | Finition int - Plaque de plâtre (2), Isolation - Laine de roche | Non défini | 0.04 | 840 | 160 | 23.4 (MJ/kg) | 1.73 (kgCO₂/kg) | Isolation - Laine de roche | no | 1.94319 | 2.5 | 0.142423 | 4.83674 | 4.83674 | 0.356059 | 0.356059 | 0.8 | 1000 | 1600 | 1.45 (MJ/kg) | 0.22 (kgCO₂/kg) | Finition int - Plaque de plâtre | no | Material Properties - Component 1: 2 with these values
Cloison Placostil 72/48 | Rez-de-chaussée | Cloison (Classification ARCHICAD) | Finition int - Plaque de plâtre (2), Isolation - Laine de roche | Non défini | 0.04 | 840 | 160 | 23.4 (MJ/kg) | 1.73 (kgCO₂/kg) | Isolation - Laine de roche | no | 1.08 | 2.5 | 0.05746 | 1.915 | 1.915 | 0.14339 | 0.14339 | 0.8 | 1000 | 1600 | 1.45 (MJ/kg) | 0.22 (kgCO₂/kg) | Finition int - Plaque de plâtre | no | Material Properties - Component 1: 2 with these values
Cloison Placostil 72/48 | Rez-de-chaussée | Cloison (Classification ARCHICAD) | Isolation - Laine de roche, Finition int - Plaque de plâtre | Non défini | 0.04 | 840 | 160 | 23.4 (MJ/kg) | 1.73 (kgCO₂/kg) | Isolation - Laine de roche | no | 1.437 | 2.5 | 0.001417 | 3.57625 | 0.07625 | 0.262543 | 0.0035425 | 0.8 | 1000 | 1600 | 1.45 (MJ/kg) | 0.22 (kgCO₂/kg) | Finition int - Plaque de plâtre | no
Cloison Placostil 72/48 | Rez-de-chaussée | Cloison (Classification ARCHICAD) | Finition int - Plaque de plâtre (2), Isolation - Laine de roche | Non défini | 0.04 | 840 | 160 | 23.4 (MJ/kg) | 1.73 (kgCO₂/kg) | Isolation - Laine de roche | no | 0.7 | 2.5 | 0.0518 | 1.75 | 1.75 | 0.1295 | 0.1295 | Material Properties - Component 3, Finition int - Plaque de plâtre, ThermalConductivity: 0.8; Component 3, Finition int - Plaque de plâtre, SpecificHeatCapacity: 1000 J/kg/K; Component 3, Finition int - Plaque de plâtre, MassDensity: 1600 kg/m3; Component 3, Finition int - Plaque de plâtre, Embodied Energy: 1.45 (MJ/kg); Component 3, Finition int - Plaque de plâtre, Embodied Carbon: 0.22 (kgCO₂/kg); Component 3, Finition int - Plaque de plâtre, Name: Finition int - Plaque de plâtre; Component 3, Finition int - Plaque de plâtre, Participates in Collision Detection: no; Component 3: 2 with these values
Cloison Placostil 72/48 | Rez-de-chaussée | Cloison (Classification ARCHICAD) | Isolation - Laine de roche | Non défini |  |  |  |  |  |  |  | 2.125 | 2.5 | 0.000624 | 5.3125 | 0 | 0.394685 | 0.00156 | Material Properties - Isolation - Laine de roche, ThermalConductivity: 0.04; Isolation - Laine de roche, SpecificHeatCapacity: 840 J/kg/K; Isolation - Laine de roche, MassDensity: 160 kg/m3; Isolation - Laine de roche, Embodied Energy: 23.4 (MJ/kg); Isolation - Laine de roche, Embodied Carbon: 1.73 (kgCO₂/kg); Isolation - Laine de roche, Name: Isolation - Laine de roche; Isolation - Laine de roche, Participates in Collision Detection: no
Cloison Placostil 72/48 | R+1 | Mur (Classification ARCHICAD); Cloison (Classification ARCHICAD) | Finition int - Plaque de plâtre (2), Isolation - Laine de roche | Non défini | 0.04 | 840 | 160 | 23.4 (MJ/kg) | 1.73 (kgCO₂/kg) | Isolation - Laine de roche | no | 1.89636 | 2.5 | 0.13901 | 4.72465 | 4.72465 | 0.347524 | 0.347524 | 0.8 | 1000 | 1600 | 1.45 (MJ/kg) | 0.22 (kgCO₂/kg) | Finition int - Plaque de plâtre | no | Material Properties - Component 1: 2 with these values
Cloison Placostil 72/48 | R+1 | Mur (Classification ARCHICAD); Cloison (Classification ARCHICAD) | Finition int - Plaque de plâtre (2), Isolation - Laine de roche | Non défini | 0.04 | 840 | 160 | 23.4 (MJ/kg) | 1.73 (kgCO₂/kg) | Isolation - Laine de roche | no | 3.07 | 2.5 | 0.228501 | 7.69125 | 7.69125 | 0.571253 | 0.571253 | 0.8 | 1000 | 1600 | 1.45 (MJ/kg) | 0.22 (kgCO₂/kg) | Finition int - Plaque de plâtre | no | Material Properties - Component 1: 2 with these values
Cloison Placostil 72/48 | R+1 | Mur (Classification ARCHICAD); Cloison (Classification ARCHICAD) | Finition int - Plaque de plâtre (2), Isolation - Laine de roche | Non défini | 0.04 | 840 | 160 | 23.4 (MJ/kg) | 1.73 (kgCO₂/kg) | Isolation - Laine de roche | no | 0.613 | 2.5 | 0.046603 | 1.3629 | 1.3486 | 0.111875 | 0.111699 | Material Properties - Component 3, Finition int - Plaque de plâtre, ThermalConductivity: 0.8; Component 3, Finition int - Plaque de plâtre, SpecificHeatCapacity: 1000 J/kg/K; Component 3, Finition int - Plaque de plâtre, MassDensity: 1600 kg/m3; Component 3, Finition int - Plaque de plâtre, Embodied Energy: 1.45 (MJ/kg); Component 3, Finition int - Plaque de plâtre, Embodied Carbon: 0.22 (kgCO₂/kg); Component 3, Finition int - Plaque de plâtre, Name: Finition int - Plaque de plâtre; Component 3, Finition int - Plaque de plâtre, Participates in Collision Detection: no; Component 3: 2 with these values
Cloison Placostil 72/48 | R+1 | Mur (Classification ARCHICAD); Cloison (Classification ARCHICAD) | Finition int - Plaque de plâtre (2), Isolation - Laine de roche | Non défini | 0.04 | 840 | 160 | 23.4 (MJ/kg) | 1.73 (kgCO₂/kg) | Isolation - Laine de roche | no | 0.657 | 2.5 | 0.048618 | 1.6425 | 1.6425 | 0.121545 | 0.121545 | Material Properties - Component 3, Finition int - Plaque de plâtre, ThermalConductivity: 0.8; Component 3, Finition int - Plaque de plâtre, SpecificHeatCapacity: 1000 J/kg/K; Component 3, Finition int - Plaque de plâtre, MassDensity: 1600 kg/m3; Component 3, Finition int - Plaque de plâtre, Embodied Energy: 1.45 (MJ/kg); Component 3, Finition int - Plaque de plâtre, Embodied Carbon: 0.22 (kgCO₂/kg); Component 3, Finition int - Plaque de plâtre, Name: Finition int - Plaque de plâtre; Component 3, Finition int - Plaque de plâtre, Participates in Collision Detection: no; Component 3: 2 with these values
Cloison Placostil 72/48 | R+1 | Mur (Classification ARCHICAD); Cloison (Classification ARCHICAD) | Finition int - Plaque de plâtre (2), Isolation - Laine de roche | Non défini | 0.04 | 840 | 160 | 23.4 (MJ/kg) | 1.73 (kgCO₂/kg) | Isolation - Laine de roche | no | 1.10539 | 2.5 | 0.0824227 | 2.76347 | 2.76347 | 0.206057 | 0.206057 | Material Properties - Component 3, Finition int - Plaque de plâtre, ThermalConductivity: 0.8; Component 3, Finition int - Plaque de plâtre, SpecificHeatCapacity: 1000 J/kg/K; Component 3, Finition int - Plaque de plâtre, MassDensity: 1600 kg/m3; Component 3, Finition int - Plaque de plâtre, Embodied Energy: 1.45 (MJ/kg); Component 3, Finition int - Plaque de plâtre, Embodied Carbon: 0.22 (kgCO₂/kg); Component 3, Finition int - Plaque de plâtre, Name: Finition int - Plaque de plâtre; Component 3, Finition int - Plaque de plâtre, Participates in Collision Detection: no; Component 3: 2 with these values
Cloison Placostil 72/48 | R+1 | Mur (Classification ARCHICAD); Cloison (Classification ARCHICAD) | Finition int - Plaque de plâtre (2), Isolation - Laine de roche | Non défini | 0.04 | 840 | 160 | 23.4 (MJ/kg) | 1.73 (kgCO₂/kg) | Isolation - Laine de roche | no | 2.68447 | 2.5 | 0.199275 | 6.71117 | 6.71117 | 0.498186 | 0.498186 | 0.8 | 1000 | 1600 | 1.45 (MJ/kg) | 0.22 (kgCO₂/kg) | Finition int - Plaque de plâtre | no | Material Properties - Component 1: 2 with these values
Cloison Placostil 72/48 | R+1 | Mur (Classification ARCHICAD); Cloison (Classification ARCHICAD) | Finition int - Plaque de plâtre (2), Isolation - Laine de roche | Non défini | 0.04 | 840 | 160 | 23.4 (MJ/kg) | 1.73 (kgCO₂/kg) | Isolation - Laine de roche | no | 0.638186 | 2.5 | 0.0459048 | 1.48006 | 1.48006 | 0.112562 | 0.112562 | Material Properties - Component 3, Finition int - Plaque de plâtre, ThermalConductivity: 0.8; Component 3, Finition int - Plaque de plâtre, SpecificHeatCapacity: 1000 J/kg/K; Component 3, Finition int - Plaque de plâtre, MassDensity: 1600 kg/m3; Component 3, Finition int - Plaque de plâtre, Embodied Energy: 1.45 (MJ/kg); Component 3, Finition int - Plaque de plâtre, Embodied Carbon: 0.22 (kgCO₂/kg); Component 3, Finition int - Plaque de plâtre, Name: Finition int - Plaque de plâtre; Component 3, Finition int - Plaque de plâtre, Participates in Collision Detection: no; Component 3: 2 with these values
Cloison Placostil 72/48 | R+1 | Mur (Classification ARCHICAD); Cloison (Classification ARCHICAD) | Finition int - Plaque de plâtre (2), Isolation - Laine de roche | Non défini | 0.04 | 840 | 160 | 23.4 (MJ/kg) | 1.73 (kgCO₂/kg) | Isolation - Laine de roche | no | 3.19738 | 2.5 | 0.23723 | 7.99346 | 7.99346 | 0.593076 | 0.593076 | Material Properties - Component 3, Finition int - Plaque de plâtre, ThermalConductivity: 0.8; Component 3, Finition int - Plaque de plâtre, SpecificHeatCapacity: 1000 J/kg/K; Component 3, Finition int - Plaque de plâtre, MassDensity: 1600 kg/m3; Component 3, Finition int - Plaque de plâtre, Embodied Energy: 1.45 (MJ/kg); Component 3, Finition int - Plaque de plâtre, Embodied Carbon: 0.22 (kgCO₂/kg); Component 3, Finition int - Plaque de plâtre, Name: Finition int - Plaque de plâtre; Component 3, Finition int - Plaque de plâtre, Participates in Collision Detection: no; Component 3: 2 with these values
Cloison Placostil 72/48 | R+1 | Mur (Classification ARCHICAD); Cloison (Classification ARCHICAD) | Finition int - Plaque de plâtre (2), Isolation - Laine de roche | Non défini | 0.04 | 840 | 160 | 23.4 (MJ/kg) | 1.73 (kgCO₂/kg) | Isolation - Laine de roche | no | 0.363 | 2.5 | 0.025541 | 0.89125 | 0.89125 | 0.0638525 | 0.0638525 | 0.8 | 1000 | 1600 | 1.45 (MJ/kg) | 0.22 (kgCO₂/kg) | Finition int - Plaque de plâtre | no | Material Properties - Component 1: 2 with these values
Cloison Placostil 72/48 | R+1 | Mur (Classification ARCHICAD); Cloison (Classification ARCHICAD) | Finition int - Plaque de plâtre (2), Isolation - Laine de roche | Non défini | 0.04 | 840 | 160 | 23.4 (MJ/kg) | 1.73 (kgCO₂/kg) | Isolation - Laine de roche | no | 0.603 | 2.5 | 0.043301 | 1.49125 | 1.49125 | 0.108253 | 0.108253 | 0.8 | 1000 | 1600 | 1.45 (MJ/kg) | 0.22 (kgCO₂/kg) | Finition int - Plaque de plâtre | no | Material Properties - Component 1: 2 with these values
Cloison Placostil 72/48 | R+1 | Mur (Classification ARCHICAD); Cloison (Classification ARCHICAD) | Finition int - Plaque de plâtre (2), Isolation - Laine de roche | Non défini | 0.04 | 840 | 160 | 23.4 (MJ/kg) | 1.73 (kgCO₂/kg) | Isolation - Laine de roche | no | 0.637 | 2.47 | 0.048459 | 1.58944 | 1.58944 | 0.119694 | 0.119694 | Material Properties - Component 3, Finition int - Plaque de plâtre, ThermalConductivity: 0.8; Component 3, Finition int - Plaque de plâtre, SpecificHeatCapacity: 1000 J/kg/K; Component 3, Finition int - Plaque de plâtre, MassDensity: 1600 kg/m3; Component 3, Finition int - Plaque de plâtre, Embodied Energy: 1.45 (MJ/kg); Component 3, Finition int - Plaque de plâtre, Embodied Carbon: 0.22 (kgCO₂/kg); Component 3, Finition int - Plaque de plâtre, Name: Finition int - Plaque de plâtre; Component 3, Finition int - Plaque de plâtre, Participates in Collision Detection: no; Component 3: 2 with these values
Cloison Placostil 72/48 | R+1 | Mur (Classification ARCHICAD); Cloison (Classification ARCHICAD) | Finition int - Plaque de plâtre (2), Isolation - Laine de roche | Non défini | 0.04 | 840 | 160 | 23.4 (MJ/kg) | 1.73 (kgCO₂/kg) | Isolation - Laine de roche | no | 3.21029 | 2.5 | 0.238185 | 8.02572 | 8.02572 | 0.595464 | 0.595464 | 0.8 | 1000 | 1600 | 1.45 (MJ/kg) | 0.22 (kgCO₂/kg) | Finition int - Plaque de plâtre | no | Material Properties - Component 1: 2 with these values
Cloison Placostil 72/48 | R+1 | Mur (Classification ARCHICAD); Cloison (Classification ARCHICAD) | Finition int - Plaque de plâtre (2), Isolation - Laine de roche | Non défini | 0.04 | 840 | 160 | 23.4 (MJ/kg) | 1.73 (kgCO₂/kg) | Isolation - Laine de roche | no | 3.195 | 2.49 | 0.237054 | 7.95555 | 7.95555 | 0.590264 | 0.590264 | 0.8 | 1000 | 1600 | 1.45 (MJ/kg) | 0.22 (kgCO₂/kg) | Finition int - Plaque de plâtre | no | Material Properties - Component 1: 2 with these values
Cloison Placostil 72/48 | R+1 | Mur (Classification ARCHICAD); Cloison (Classification ARCHICAD) | Finition int - Plaque de plâtre (2), Isolation - Laine de roche | Non défini | 0.04 | 840 | 160 | 23.4 (MJ/kg) | 1.73 (kgCO₂/kg) | Isolation - Laine de roche | no | 0.637 | 2.49 | 0.048459 | 1.60232 | 1.60232 | 0.120663 | 0.120663 | Material Properties - Component 3, Finition int - Plaque de plâtre, ThermalConductivity: 0.8; Component 3, Finition int - Plaque de plâtre, SpecificHeatCapacity: 1000 J/kg/K; Component 3, Finition int - Plaque de plâtre, MassDensity: 1600 kg/m3; Component 3, Finition int - Plaque de plâtre, Embodied Energy: 1.45 (MJ/kg); Component 3, Finition int - Plaque de plâtre, Embodied Carbon: 0.22 (kgCO₂/kg); Component 3, Finition int - Plaque de plâtre, Name: Finition int - Plaque de plâtre; Component 3, Finition int - Plaque de plâtre, Participates in Collision Detection: no; Component 3: 2 with these values
Cloison Placostil 72/48 | R+1 | Mur (Classification ARCHICAD); Cloison (Classification ARCHICAD) | Finition int - Plaque de plâtre (2), Isolation - Laine de roche | 35 dB(A) | 0.04 | 840 | 160 | 23.4 (MJ/kg) | 1.73 (kgCO₂/kg) | Isolation - Laine de roche | no | 0.73 | 2.49 | 0.05476 | 1.8326 | 1.8326 | 0.136092 | 0.136092 | 0.8 | 1000 | 1600 | 1.45 (MJ/kg) | 0.22 (kgCO₂/kg) | Finition int - Plaque de plâtre | no | Material Properties - Component 1: 2 with these values
Cloison Placostil 72/48 | R+1 | Mur (Classification ARCHICAD); Cloison (Classification ARCHICAD) | Finition int - Plaque de plâtre (2), Isolation - Laine de roche | Non défini | 0.04 | 840 | 160 | 23.4 (MJ/kg) | 1.73 (kgCO₂/kg) | Isolation - Laine de roche | no | 1.4 | 2.49 | 0.104224 | 3.486 | 3.486 | 0.259518 | 0.259518 | Material Properties - Component 3, Finition int - Plaque de plâtre, ThermalConductivity: 0.8; Component 3, Finition int - Plaque de plâtre, SpecificHeatCapacity: 1000 J/kg/K; Component 3, Finition int - Plaque de plâtre, MassDensity: 1600 kg/m3; Component 3, Finition int - Plaque de plâtre, Embodied Energy: 1.45 (MJ/kg); Component 3, Finition int - Plaque de plâtre, Embodied Carbon: 0.22 (kgCO₂/kg); Component 3, Finition int - Plaque de plâtre, Name: Finition int - Plaque de plâtre; Component 3, Finition int - Plaque de plâtre, Participates in Collision Detection: no; Component 3: 2 with these values
Cloison Placostil 72/48 | R+1 | Mur (Classification ARCHICAD); Cloison (Classification ARCHICAD) | Finition int - Plaque de plâtre (2), Isolation - Laine de roche | Non défini | 0.04 | 840 | 160 | 23.4 (MJ/kg) | 1.73 (kgCO₂/kg) | Isolation - Laine de roche | no | 0.287 | 2.5 | 0.019917 | 0.6171 | 0.6171 | 0.0476046 | 0.0476046 | Material Properties - Component 3, Finition int - Plaque de plâtre, ThermalConductivity: 0.8; Component 3, Finition int - Plaque de plâtre, SpecificHeatCapacity: 1000 J/kg/K; Component 3, Finition int - Plaque de plâtre, MassDensity: 1600 kg/m3; Component 3, Finition int - Plaque de plâtre, Embodied Energy: 1.45 (MJ/kg); Component 3, Finition int - Plaque de plâtre, Embodied Carbon: 0.22 (kgCO₂/kg); Component 3, Finition int - Plaque de plâtre, Name: Finition int - Plaque de plâtre; Component 3, Finition int - Plaque de plâtre, Participates in Collision Detection: no; Component 3: 2 with these values
2 x Cloison Placostil 72/48 | R+1 | Mur (Classification ARCHICAD); Cloison (Classification ARCHICAD) | Finition int - Plaque de plâtre (2), Isolation - Laine de roche | Non défini | 0.04 | 840 | 160 | 23.4 (MJ/kg) | 1.73 (kgCO₂/kg) | Isolation - Laine de roche | no | 0.637 | 2.5 | 0.048459 | 1.60875 | 1.60875 | 0.121147 | 0.121147 | Material Properties - Component 3, Finition int - Plaque de plâtre, ThermalConductivity: 0.8; Component 3, Finition int - Plaque de plâtre, SpecificHeatCapacity: 1000 J/kg/K; Component 3, Finition int - Plaque de plâtre, MassDensity: 1600 kg/m3; Component 3, Finition int - Plaque de plâtre, Embodied Energy: 1.45 (MJ/kg); Component 3, Finition int - Plaque de plâtre, Embodied Carbon: 0.22 (kgCO₂/kg); Component 3, Finition int - Plaque de plâtre, Name: Finition int - Plaque de plâtre; Component 3, Finition int - Plaque de plâtre, Participates in Collision Detection: no; Component 3: 2 with these values
Cloison Placostil 72/48 | R+1 | Mur (Classification ARCHICAD); Cloison (Classification ARCHICAD) | Finition int - Plaque de plâtre (2), Isolation - Laine de roche | Non défini | 0.04 | 840 | 160 | 23.4 (MJ/kg) | 1.73 (kgCO₂/kg) | Isolation - Laine de roche | no | 0.577598 | 2.5 | 0.0440632 | 1.46024 | 1.46024 | 0.110158 | 0.110158 | Material Properties - Component 3, Finition int - Plaque de plâtre, ThermalConductivity: 0.8; Component 3, Finition int - Plaque de plâtre, SpecificHeatCapacity: 1000 J/kg/K; Component 3, Finition int - Plaque de plâtre, MassDensity: 1600 kg/m3; Component 3, Finition int - Plaque de plâtre, Embodied Energy: 1.45 (MJ/kg); Component 3, Finition int - Plaque de plâtre, Embodied Carbon: 0.22 (kgCO₂/kg); Component 3, Finition int - Plaque de plâtre, Name: Finition int - Plaque de plâtre; Component 3, Finition int - Plaque de plâtre, Participates in Collision Detection: no; Component 3: 2 with these values
Cloison Placostil 72/48 | R+1 | Mur (Classification ARCHICAD); Cloison (Classification ARCHICAD) | Finition int - Plaque de plâtre (2), Isolation - Laine de roche | Non défini | 0.04 | 840 | 160 | 23.4 (MJ/kg) | 1.73 (kgCO₂/kg) | Isolation - Laine de roche | no | 4.122 | 2.5 | 0.306349 | 10.3213 | 10.3213 | 0.765873 | 0.765873 | 0.8 | 1000 | 1600 | 1.45 (MJ/kg) | 0.22 (kgCO₂/kg) | Finition int - Plaque de plâtre | no | Material Properties - Component 1: 2 with these values
Cloison Placostil 72/48 | R+1 | Mur (Classification ARCHICAD); Cloison (Classification ARCHICAD) | Finition int - Plaque de plâtre (2), Isolation - Laine de roche | Non défini | 0.04 | 840 | 160 | 23.4 (MJ/kg) | 1.73 (kgCO₂/kg) | Isolation - Laine de roche | no | 0.637 | 2.5 | 0.048021 | 1.60875 | 1.59523 | 0.121147 | 0.120236 | 0.8 | 1000 | 1600 | 1.45 (MJ/kg) | 0.22 (kgCO₂/kg) | Finition int - Plaque de plâtre | no | Material Properties - Component 1: 2 with these values
Cloison Placostil 72/48 | R+1 | Mur (Classification ARCHICAD); Cloison (Classification ARCHICAD) | Finition int - Plaque de plâtre (2), Isolation - Laine de roche | Non défini | 0.04 | 840 | 160 | 23.4 (MJ/kg) | 1.73 (kgCO₂/kg) | Isolation - Laine de roche | no | 0.876 | 2.5 | 0.066145 | 2.20625 | 2.20625 | 0.165362 | 0.165362 | Material Properties - Component 3, Finition int - Plaque de plâtre, ThermalConductivity: 0.8; Component 3, Finition int - Plaque de plâtre, SpecificHeatCapacity: 1000 J/kg/K; Component 3, Finition int - Plaque de plâtre, MassDensity: 1600 kg/m3; Component 3, Finition int - Plaque de plâtre, Embodied Energy: 1.45 (MJ/kg); Component 3, Finition int - Plaque de plâtre, Embodied Carbon: 0.22 (kgCO₂/kg); Component 3, Finition int - Plaque de plâtre, Name: Finition int - Plaque de plâtre; Component 3, Finition int - Plaque de plâtre, Participates in Collision Detection: no; Component 3: 2 with these values
Cloison Placostil 72/48 | R+2 | Mur (Classification ARCHICAD); Cloison (Classification ARCHICAD) | Finition int - Plaque de plâtre (2), Isolation - Laine de roche | Non défini | 0.04 | 840 | 160 | 23.4 (MJ/kg) | 1.73 (kgCO₂/kg) | Isolation - Laine de roche | no | 3.69483 | 2.5 | 0.274738 | 9.25331 | 9.25331 | 0.686845 | 0.686845 | Material Properties - Component 3, Finition int - Plaque de plâtre, ThermalConductivity: 0.8; Component 3, Finition int - Plaque de plâtre, SpecificHeatCapacity: 1000 J/kg/K; Component 3, Finition int - Plaque de plâtre, MassDensity: 1600 kg/m3; Component 3, Finition int - Plaque de plâtre, Embodied Energy: 1.45 (MJ/kg); Component 3, Finition int - Plaque de plâtre, Embodied Carbon: 0.22 (kgCO₂/kg); Component 3, Finition int - Plaque de plâtre, Name: Finition int - Plaque de plâtre; Component 3, Finition int - Plaque de plâtre, Participates in Collision Detection: no; Component 3: 2 with these values
Cloison Placostil 72/48 | R+2 | Mur (Classification ARCHICAD); Cloison (Classification ARCHICAD) | Finition int - Plaque de plâtre (2), Isolation - Laine de roche | Non défini | 0.04 | 840 | 160 | 23.4 (MJ/kg) | 1.73 (kgCO₂/kg) | Isolation - Laine de roche | no | 3.195 | 2.49 | 0.237054 | 7.95555 | 7.95555 | 0.590264 | 0.590264 | 0.8 | 1000 | 1600 | 1.45 (MJ/kg) | 0.22 (kgCO₂/kg) | Finition int - Plaque de plâtre | no | Material Properties - Component 1: 2 with these values
Cloison Placostil 72/48 | R+2 | Mur (Classification ARCHICAD); Cloison (Classification ARCHICAD) | Finition int - Plaque de plâtre (2), Isolation - Laine de roche | Non défini | 0.04 | 840 | 160 | 23.4 (MJ/kg) | 1.73 (kgCO₂/kg) | Isolation - Laine de roche | no | 0.213 | 2.5 | 0.014441 | 0.51625 | 0.51625 | 0.0361025 | 0.0361025 | Material Properties - Component 3, Finition int - Plaque de plâtre, ThermalConductivity: 0.8; Component 3, Finition int - Plaque de plâtre, SpecificHeatCapacity: 1000 J/kg/K; Component 3, Finition int - Plaque de plâtre, MassDensity: 1600 kg/m3; Component 3, Finition int - Plaque de plâtre, Embodied Energy: 1.45 (MJ/kg); Component 3, Finition int - Plaque de plâtre, Embodied Carbon: 0.22 (kgCO₂/kg); Component 3, Finition int - Plaque de plâtre, Name: Finition int - Plaque de plâtre; Component 3, Finition int - Plaque de plâtre, Participates in Collision Detection: no; Component 3: 2 with these values
Cloison Placostil 72/48 | R+2 | Mur (Classification ARCHICAD); Cloison (Classification ARCHICAD) | Finition int - Plaque de plâtre (2), Isolation - Laine de roche | Non défini | 0.04 | 840 | 160 | 23.4 (MJ/kg) | 1.73 (kgCO₂/kg) | Isolation - Laine de roche | no | 0.637 | 2.49 | 0.048459 | 1.60232 | 1.60232 | 0.120663 | 0.120663 | Material Properties - Component 3, Finition int - Plaque de plâtre, ThermalConductivity: 0.8; Component 3, Finition int - Plaque de plâtre, SpecificHeatCapacity: 1000 J/kg/K; Component 3, Finition int - Plaque de plâtre, MassDensity: 1600 kg/m3; Component 3, Finition int - Plaque de plâtre, Embodied Energy: 1.45 (MJ/kg); Component 3, Finition int - Plaque de plâtre, Embodied Carbon: 0.22 (kgCO₂/kg); Component 3, Finition int - Plaque de plâtre, Name: Finition int - Plaque de plâtre; Component 3, Finition int - Plaque de plâtre, Participates in Collision Detection: no; Component 3: 2 with these values
Cloison Placostil 72/48 | R+2 | Mur (Classification ARCHICAD); Cloison (Classification ARCHICAD) | Finition int - Plaque de plâtre (2), Isolation - Laine de roche | Non défini | 0.04 | 840 | 160 | 23.4 (MJ/kg) | 1.73 (kgCO₂/kg) | Isolation - Laine de roche | no | 1.45 | 2.5 | 0.107924 | 3.625 | 3.625 | 0.26981 | 0.26981 | Material Properties - Component 3, Finition int - Plaque de plâtre, ThermalConductivity: 0.8; Component 3, Finition int - Plaque de plâtre, SpecificHeatCapacity: 1000 J/kg/K; Component 3, Finition int - Plaque de plâtre, MassDensity: 1600 kg/m3; Component 3, Finition int - Plaque de plâtre, Embodied Energy: 1.45 (MJ/kg); Component 3, Finition int - Plaque de plâtre, Embodied Carbon: 0.22 (kgCO₂/kg); Component 3, Finition int - Plaque de plâtre, Name: Finition int - Plaque de plâtre; Component 3, Finition int - Plaque de plâtre, Participates in Collision Detection: no; Component 3: 2 with these values
Cloison Placostil 72/48 | R+2 | Mur (Classification ARCHICAD); Cloison (Classification ARCHICAD) | Finition int - Plaque de plâtre (2), Isolation - Laine de roche | Non défini | 0.04 | 840 | 160 | 23.4 (MJ/kg) | 1.73 (kgCO₂/kg) | Isolation - Laine de roche | no | 0.287 | 2.5 | 0.022559 | 0.73375 | 0.73375 | 0.0563975 | 0.0563975 | Material Properties - Component 3, Finition int - Plaque de plâtre, ThermalConductivity: 0.8; Component 3, Finition int - Plaque de plâtre, SpecificHeatCapacity: 1000 J/kg/K; Component 3, Finition int - Plaque de plâtre, MassDensity: 1600 kg/m3; Component 3, Finition int - Plaque de plâtre, Embodied Energy: 1.45 (MJ/kg); Component 3, Finition int - Plaque de plâtre, Embodied Carbon: 0.22 (kgCO₂/kg); Component 3, Finition int - Plaque de plâtre, Name: Finition int - Plaque de plâtre; Component 3, Finition int - Plaque de plâtre, Participates in Collision Detection: no; Component 3: 2 with these values
Cloison Placostil 72/48 | R+2 | Mur (Classification ARCHICAD); Cloison (Classification ARCHICAD) | Finition int - Plaque de plâtre (2), Isolation - Laine de roche | Non défini | 0.04 | 840 | 160 | 23.4 (MJ/kg) | 1.73 (kgCO₂/kg) | Isolation - Laine de roche | no | 1.56317 | 2.5 | 0.114353 | 3.89167 | 3.89167 | 0.285883 | 0.285883 | Material Properties - Component 3, Finition int - Plaque de plâtre, ThermalConductivity: 0.8; Component 3, Finition int - Plaque de plâtre, SpecificHeatCapacity: 1000 J/kg/K; Component 3, Finition int - Plaque de plâtre, MassDensity: 1600 kg/m3; Component 3, Finition int - Plaque de plâtre, Embodied Energy: 1.45 (MJ/kg); Component 3, Finition int - Plaque de plâtre, Embodied Carbon: 0.22 (kgCO₂/kg); Component 3, Finition int - Plaque de plâtre, Name: Finition int - Plaque de plâtre; Component 3, Finition int - Plaque de plâtre, Participates in Collision Detection: no; Component 3: 2 with these values
Cloison Placostil 72/48 | R+2 | Mur (Classification ARCHICAD); Cloison (Classification ARCHICAD) | Finition int - Plaque de plâtre (2), Isolation - Laine de roche | Non défini | 0.04 | 840 | 160 | 23.4 (MJ/kg) | 1.73 (kgCO₂/kg) | Isolation - Laine de roche | no | 6.06717 | 2.5 | 0.448347 | 15.1079 | 15.1079 | 1.12087 | 1.12087 | 0.8 | 1000 | 1600 | 1.45 (MJ/kg) | 0.22 (kgCO₂/kg) | Finition int - Plaque de plâtre | no | Material Properties - Component 1: 2 with these values
Cloison Placostil 72/48 | R+2 | Mur (Classification ARCHICAD); Cloison (Classification ARCHICAD) | Finition int - Plaque de plâtre (2), Isolation - Laine de roche | Non défini | 0.04 | 840 | 160 | 23.4 (MJ/kg) | 1.73 (kgCO₂/kg) | Isolation - Laine de roche | no | 4.11727 | 2.5 | 0.305302 | 10.2932 | 10.2932 | 0.763256 | 0.763256 | Material Properties - Component 3, Finition int - Plaque de plâtre, ThermalConductivity: 0.8; Component 3, Finition int - Plaque de plâtre, SpecificHeatCapacity: 1000 J/kg/K; Component 3, Finition int - Plaque de plâtre, MassDensity: 1600 kg/m3; Component 3, Finition int - Plaque de plâtre, Embodied Energy: 1.45 (MJ/kg); Component 3, Finition int - Plaque de plâtre, Embodied Carbon: 0.22 (kgCO₂/kg); Component 3, Finition int - Plaque de plâtre, Name: Finition int - Plaque de plâtre; Component 3, Finition int - Plaque de plâtre, Participates in Collision Detection: no; Component 3: 2 with these values
Cloison Placostil 72/48 | R+2 | Mur (Classification ARCHICAD); Cloison (Classification ARCHICAD) | Finition int - Plaque de plâtre (2), Isolation - Laine de roche | Non défini | 0.04 | 840 | 160 | 23.4 (MJ/kg) | 1.73 (kgCO₂/kg) | Isolation - Laine de roche | no | 0.638 | 2.5 | 0.045891 | 1.57875 | 1.57875 | 0.114728 | 0.114728 | 0.8 | 1000 | 1600 | 1.45 (MJ/kg) | 0.22 (kgCO₂/kg) | Finition int - Plaque de plâtre | no | Material Properties - Component 1: 2 with these values
Cloison Placostil 72/48 | R+2 | Mur (Classification ARCHICAD); Cloison (Classification ARCHICAD) | Finition int - Plaque de plâtre (2), Isolation - Laine de roche | Non défini | 0.04 | 840 | 160 | 23.4 (MJ/kg) | 1.73 (kgCO₂/kg) | Isolation - Laine de roche | no | 0.564 | 2.5 | 0.039675 | 1.36875 | 1.36875 | 0.0991875 | 0.0991875 | 0.8 | 1000 | 1600 | 1.45 (MJ/kg) | 0.22 (kgCO₂/kg) | Finition int - Plaque de plâtre | no | Material Properties - Component 1: 2 with these values
Cloison Placostil 72/48 | R+2 | Mur (Classification ARCHICAD); Cloison (Classification ARCHICAD) | Finition int - Plaque de plâtre (2), Isolation - Laine de roche | Non défini | 0.04 | 840 | 160 | 23.4 (MJ/kg) | 1.73 (kgCO₂/kg) | Isolation - Laine de roche | no | 1.91164 | 2.5 | 0.142782 | 4.79535 | 4.79535 | 0.356956 | 0.356956 | 0.8 | 1000 | 1600 | 1.45 (MJ/kg) | 0.22 (kgCO₂/kg) | Finition int - Plaque de plâtre | no | Material Properties - Component 1: 2 with these values
Cloison Placostil 72/48 | R+2 | Mur (Classification ARCHICAD); Cloison (Classification ARCHICAD) | Finition int - Plaque de plâtre (2), Isolation - Laine de roche | Non défini | 0.04 | 840 | 160 | 23.4 (MJ/kg) | 1.73 (kgCO₂/kg) | Isolation - Laine de roche | no | 0.638 | 2.5 | 0.045891 | 1.57875 | 1.57875 | 0.114727 | 0.114727 | 0.8 | 1000 | 1600 | 1.45 (MJ/kg) | 0.22 (kgCO₂/kg) | Finition int - Plaque de plâtre | no | Material Properties - Component 1: 2 with these values
Cloison Placostil 72/48 | R+2 | Mur (Classification ARCHICAD); Cloison (Classification ARCHICAD) | Finition int - Plaque de plâtre (2), Isolation - Laine de roche | Non défini | 0.04 | 840 | 160 | 23.4 (MJ/kg) | 1.73 (kgCO₂/kg) | Isolation - Laine de roche | no | 2.124 | 2.5 | 0.157176 | 5.31 | 5.31 | 0.39294 | 0.39294 | Material Properties - Component 3, Finition int - Plaque de plâtre, ThermalConductivity: 0.8; Component 3, Finition int - Plaque de plâtre, SpecificHeatCapacity: 1000 J/kg/K; Component 3, Finition int - Plaque de plâtre, MassDensity: 1600 kg/m3; Component 3, Finition int - Plaque de plâtre, Embodied Energy: 1.45 (MJ/kg); Component 3, Finition int - Plaque de plâtre, Embodied Carbon: 0.22 (kgCO₂/kg); Component 3, Finition int - Plaque de plâtre, Name: Finition int - Plaque de plâtre; Component 3, Finition int - Plaque de plâtre, Participates in Collision Detection: no; Component 3: 2 with these values
Cloison Placostil 72/48 | R+2 | Mur (Classification ARCHICAD); Cloison (Classification ARCHICAD) | Finition int - Plaque de plâtre (2), Isolation - Laine de roche | Non défini | 0.04 | 840 | 160 | 23.4 (MJ/kg) | 1.73 (kgCO₂/kg) | Isolation - Laine de roche | no | 1.87136 | 2.5 | 0.13716 | 4.66215 | 4.66215 | 0.342899 | 0.342899 | 0.8 | 1000 | 1600 | 1.45 (MJ/kg) | 0.22 (kgCO₂/kg) | Finition int - Plaque de plâtre | no | Material Properties - Component 1: 2 with these values
Cloison Placostil 72/48 | R+2 | Mur (Classification ARCHICAD); Cloison (Classification ARCHICAD) | Finition int - Plaque de plâtre (2), Isolation - Laine de roche | Non défini | 0.04 | 840 | 160 | 23.4 (MJ/kg) | 1.73 (kgCO₂/kg) | Isolation - Laine de roche | no | 0.657 | 2.5 | 0.048618 | 1.6425 | 1.6425 | 0.121545 | 0.121545 | Material Properties - Component 3, Finition int - Plaque de plâtre, ThermalConductivity: 0.8; Component 3, Finition int - Plaque de plâtre, SpecificHeatCapacity: 1000 J/kg/K; Component 3, Finition int - Plaque de plâtre, MassDensity: 1600 kg/m3; Component 3, Finition int - Plaque de plâtre, Embodied Energy: 1.45 (MJ/kg); Component 3, Finition int - Plaque de plâtre, Embodied Carbon: 0.22 (kgCO₂/kg); Component 3, Finition int - Plaque de plâtre, Name: Finition int - Plaque de plâtre; Component 3, Finition int - Plaque de plâtre, Participates in Collision Detection: no; Component 3: 2 with these values
Cloison Placostil 72/48 | R+2 | Mur (Classification ARCHICAD); Cloison (Classification ARCHICAD) | Finition int - Plaque de plâtre (2), Isolation - Laine de roche | Non défini | 0.04 | 840 | 160 | 23.4 (MJ/kg) | 1.73 (kgCO₂/kg) | Isolation - Laine de roche | no | 3.07 | 2.5 | 0.228501 | 7.69125 | 7.69125 | 0.571253 | 0.571253 | 0.8 | 1000 | 1600 | 1.45 (MJ/kg) | 0.22 (kgCO₂/kg) | Finition int - Plaque de plâtre | no | Material Properties - Component 1: 2 with these values
Cloison Placostil 72/48 | R+2 | Mur (Classification ARCHICAD); Cloison (Classification ARCHICAD) | Finition int - Plaque de plâtre (2), Isolation - Laine de roche | Non défini | 0.04 | 840 | 160 | 23.4 (MJ/kg) | 1.73 (kgCO₂/kg) | Isolation - Laine de roche | no | 0.613 | 2.5 | 0.0460945 | 1.3629 | 1.34938 | 0.111875 | 0.110651 | Material Properties - Component 3, Finition int - Plaque de plâtre, ThermalConductivity: 0.8; Component 3, Finition int - Plaque de plâtre, SpecificHeatCapacity: 1000 J/kg/K; Component 3, Finition int - Plaque de plâtre, MassDensity: 1600 kg/m3; Component 3, Finition int - Plaque de plâtre, Embodied Energy: 1.45 (MJ/kg); Component 3, Finition int - Plaque de plâtre, Embodied Carbon: 0.22 (kgCO₂/kg); Component 3, Finition int - Plaque de plâtre, Name: Finition int - Plaque de plâtre; Component 3, Finition int - Plaque de plâtre, Participates in Collision Detection: no; Component 3: 2 with these values
Cloison Placostil 72/48 | R+2 | Mur (Classification ARCHICAD); Cloison (Classification ARCHICAD) | Finition int - Plaque de plâtre (2), Isolation - Laine de roche | Non défini | 0.04 | 840 | 160 | 23.4 (MJ/kg) | 1.73 (kgCO₂/kg) | Isolation - Laine de roche | no | 0.363 | 2.5 | 0.025541 | 0.89125 | 0.89125 | 0.0638525 | 0.0638525 | 0.8 | 1000 | 1600 | 1.45 (MJ/kg) | 0.22 (kgCO₂/kg) | Finition int - Plaque de plâtre | no | Material Properties - Component 1: 2 with these values
Cloison Placostil 72/48 | R+2 | Mur (Classification ARCHICAD); Cloison (Classification ARCHICAD) | Finition int - Plaque de plâtre (2), Isolation - Laine de roche | Non défini | 0.04 | 840 | 160 | 23.4 (MJ/kg) | 1.73 (kgCO₂/kg) | Isolation - Laine de roche | no | 0.65 | 2.5 | 0.046779 | 1.60875 | 1.60875 | 0.116947 | 0.116947 | Material Properties - Component 3, Finition int - Plaque de plâtre, ThermalConductivity: 0.8; Component 3, Finition int - Plaque de plâtre, SpecificHeatCapacity: 1000 J/kg/K; Component 3, Finition int - Plaque de plâtre, MassDensity: 1600 kg/m3; Component 3, Finition int - Plaque de plâtre, Embodied Energy: 1.45 (MJ/kg); Component 3, Finition int - Plaque de plâtre, Embodied Carbon: 0.22 (kgCO₂/kg); Component 3, Finition int - Plaque de plâtre, Name: Finition int - Plaque de plâtre; Component 3, Finition int - Plaque de plâtre, Participates in Collision Detection: no; Component 3: 2 with these values
Cloison Placostil 72/48 | R+2 | Mur (Classification ARCHICAD); Cloison (Classification ARCHICAD) | Finition int - Plaque de plâtre (2), Isolation - Laine de roche | 35 dB(A) | 0.04 | 840 | 160 | 23.4 (MJ/kg) | 1.73 (kgCO₂/kg) | Isolation - Laine de roche | no | 0.73 | 2.49 | 0.05476 | 1.8326 | 1.8326 | 0.136092 | 0.136092 | 0.8 | 1000 | 1600 | 1.45 (MJ/kg) | 0.22 (kgCO₂/kg) | Finition int - Plaque de plâtre | no | Material Properties - Component 1: 2 with these values
Cloison Placostil 72/48 | R+2 | Mur (Classification ARCHICAD); Cloison (Classification ARCHICAD) | Finition int - Plaque de plâtre (2), Isolation - Laine de roche | Non défini | 0.04 | 840 | 160 | 23.4 (MJ/kg) | 1.73 (kgCO₂/kg) | Isolation - Laine de roche | no | 1.4 | 2.49 | 0.104224 | 3.486 | 3.486 | 0.259518 | 0.259518 | Material Properties - Component 3, Finition int - Plaque de plâtre, ThermalConductivity: 0.8; Component 3, Finition int - Plaque de plâtre, SpecificHeatCapacity: 1000 J/kg/K; Component 3, Finition int - Plaque de plâtre, MassDensity: 1600 kg/m3; Component 3, Finition int - Plaque de plâtre, Embodied Energy: 1.45 (MJ/kg); Component 3, Finition int - Plaque de plâtre, Embodied Carbon: 0.22 (kgCO₂/kg); Component 3, Finition int - Plaque de plâtre, Name: Finition int - Plaque de plâtre; Component 3, Finition int - Plaque de plâtre, Participates in Collision Detection: no; Component 3: 2 with these values
Cloison Placostil 72/48 | R+2 | Mur (Classification ARCHICAD); Cloison (Classification ARCHICAD) | Finition int - Plaque de plâtre (2), Isolation - Laine de roche | Non défini | 0.04 | 840 | 160 | 23.4 (MJ/kg) | 1.73 (kgCO₂/kg) | Isolation - Laine de roche | no | 0.287 | 2.5 | 0.019917 | 0.6171 | 0.6171 | 0.0476046 | 0.0476046 | Material Properties - Component 3, Finition int - Plaque de plâtre, ThermalConductivity: 0.8; Component 3, Finition int - Plaque de plâtre, SpecificHeatCapacity: 1000 J/kg/K; Component 3, Finition int - Plaque de plâtre, MassDensity: 1600 kg/m3; Component 3, Finition int - Plaque de plâtre, Embodied Energy: 1.45 (MJ/kg); Component 3, Finition int - Plaque de plâtre, Embodied Carbon: 0.22 (kgCO₂/kg); Component 3, Finition int - Plaque de plâtre, Name: Finition int - Plaque de plâtre; Component 3, Finition int - Plaque de plâtre, Participates in Collision Detection: no; Component 3: 2 with these values
Cloison Placostil 72/48 | R+2 | Mur (Classification ARCHICAD); Cloison (Classification ARCHICAD) | Finition int - Plaque de plâtre (2), Isolation - Laine de roche | Non défini | 0.04 | 840 | 160 | 23.4 (MJ/kg) | 1.73 (kgCO₂/kg) | Isolation - Laine de roche | no | 0.72831 | 2.5 | 0.055216 | 1.83703 | 1.83703 | 0.13804 | 0.13804 | 0.8 | 1000 | 1600 | 1.45 (MJ/kg) | 0.22 (kgCO₂/kg) | Finition int - Plaque de plâtre | no | Material Properties - Component 1: 2 with these values
Cloison Placostil 72/48 | R+2 | Mur (Classification ARCHICAD); Cloison (Classification ARCHICAD) | Finition int - Plaque de plâtre (2), Isolation - Laine de roche | Non défini | 0.04 | 840 | 160 | 23.4 (MJ/kg) | 1.73 (kgCO₂/kg) | Isolation - Laine de roche | no | 2.74647 | 2.5 | 0.20456 | 6.88242 | 6.88242 | 0.511399 | 0.511399 | 0.8 | 1000 | 1600 | 1.45 (MJ/kg) | 0.22 (kgCO₂/kg) | Finition int - Plaque de plâtre | no | Material Properties - Component 1: 2 with these values
Cloison Placostil 72/48 | R+2 | Mur (Classification ARCHICAD); Cloison (Classification ARCHICAD) | Finition int - Plaque de plâtre (2), Isolation - Laine de roche | Non défini | 0.04 | 840 | 160 | 23.4 (MJ/kg) | 1.73 (kgCO₂/kg) | Isolation - Laine de roche | no | 0.636334 | 2.5 | 0.0457674 | 1.57458 | 1.57458 | 0.114419 | 0.114419 | Material Properties - Component 3, Finition int - Plaque de plâtre, ThermalConductivity: 0.8; Component 3, Finition int - Plaque de plâtre, SpecificHeatCapacity: 1000 J/kg/K; Component 3, Finition int - Plaque de plâtre, MassDensity: 1600 kg/m3; Component 3, Finition int - Plaque de plâtre, Embodied Energy: 1.45 (MJ/kg); Component 3, Finition int - Plaque de plâtre, Embodied Carbon: 0.22 (kgCO₂/kg); Component 3, Finition int - Plaque de plâtre, Name: Finition int - Plaque de plâtre; Component 3, Finition int - Plaque de plâtre, Participates in Collision Detection: no; Component 3: 2 with these values
Cloison Placostil 72/48 | R+2 | Mur (Classification ARCHICAD); Cloison (Classification ARCHICAD) | Finition int - Plaque de plâtre (2), Isolation - Laine de roche | Non défini | 0.04 | 840 | 160 | 23.4 (MJ/kg) | 1.73 (kgCO₂/kg) | Isolation - Laine de roche | no | 0.876 | 2.5 | 0.066145 | 2.20625 | 2.20625 | 0.165362 | 0.165362 | Material Properties - Component 3, Finition int - Plaque de plâtre, ThermalConductivity: 0.8; Component 3, Finition int - Plaque de plâtre, SpecificHeatCapacity: 1000 J/kg/K; Component 3, Finition int - Plaque de plâtre, MassDensity: 1600 kg/m3; Component 3, Finition int - Plaque de plâtre, Embodied Energy: 1.45 (MJ/kg); Component 3, Finition int - Plaque de plâtre, Embodied Carbon: 0.22 (kgCO₂/kg); Component 3, Finition int - Plaque de plâtre, Name: Finition int - Plaque de plâtre; Component 3, Finition int - Plaque de plâtre, Participates in Collision Detection: no; Component 3: 2 with these values
2 x Cloison Placostil 72/48 | R+2 | Mur (Classification ARCHICAD); Cloison (Classification ARCHICAD) | Finition int - Plaque de plâtre (2), Isolation - Laine de roche | Non défini | 0.04 | 840 | 160 | 23.4 (MJ/kg) | 1.73 (kgCO₂/kg) | Isolation - Laine de roche | no | 0.637 | 2.5 | 0.048459 | 1.60875 | 1.60875 | 0.121147 | 0.121147 | Material Properties - Component 3, Finition int - Plaque de plâtre, ThermalConductivity: 0.8; Component 3, Finition int - Plaque de plâtre, SpecificHeatCapacity: 1000 J/kg/K; Component 3, Finition int - Plaque de plâtre, MassDensity: 1600 kg/m3; Component 3, Finition int - Plaque de plâtre, Embodied Energy: 1.45 (MJ/kg); Component 3, Finition int - Plaque de plâtre, Embodied Carbon: 0.22 (kgCO₂/kg); Component 3, Finition int - Plaque de plâtre, Name: Finition int - Plaque de plâtre; Component 3, Finition int - Plaque de plâtre, Participates in Collision Detection: no; Component 3: 2 with these values
Cloison Placostil 72/48 | R+2 | Mur (Classification ARCHICAD); Cloison (Classification ARCHICAD) | Finition int - Plaque de plâtre (2), Isolation - Laine de roche | Non défini | 0.04 | 840 | 160 | 23.4 (MJ/kg) | 1.73 (kgCO₂/kg) | Isolation - Laine de roche | no | 0.577598 | 2.5 | 0.0440632 | 1.46024 | 1.46024 | 0.110158 | 0.110158 | Material Properties - Component 3, Finition int - Plaque de plâtre, ThermalConductivity: 0.8; Component 3, Finition int - Plaque de plâtre, SpecificHeatCapacity: 1000 J/kg/K; Component 3, Finition int - Plaque de plâtre, MassDensity: 1600 kg/m3; Component 3, Finition int - Plaque de plâtre, Embodied Energy: 1.45 (MJ/kg); Component 3, Finition int - Plaque de plâtre, Embodied Carbon: 0.22 (kgCO₂/kg); Component 3, Finition int - Plaque de plâtre, Name: Finition int - Plaque de plâtre; Component 3, Finition int - Plaque de plâtre, Participates in Collision Detection: no; Component 3: 2 with these values
Cloison Placostil 72/48 | R+2 | Mur (Classification ARCHICAD); Cloison (Classification ARCHICAD) | Finition int - Plaque de plâtre (2), Isolation - Laine de roche | Non défini | 0.04 | 840 | 160 | 23.4 (MJ/kg) | 1.73 (kgCO₂/kg) | Isolation - Laine de roche | no | 4.122 | 2.5 | 0.306349 | 10.3213 | 10.3213 | 0.765873 | 0.765873 | 0.8 | 1000 | 1600 | 1.45 (MJ/kg) | 0.22 (kgCO₂/kg) | Finition int - Plaque de plâtre | no | Material Properties - Component 1: 2 with these values
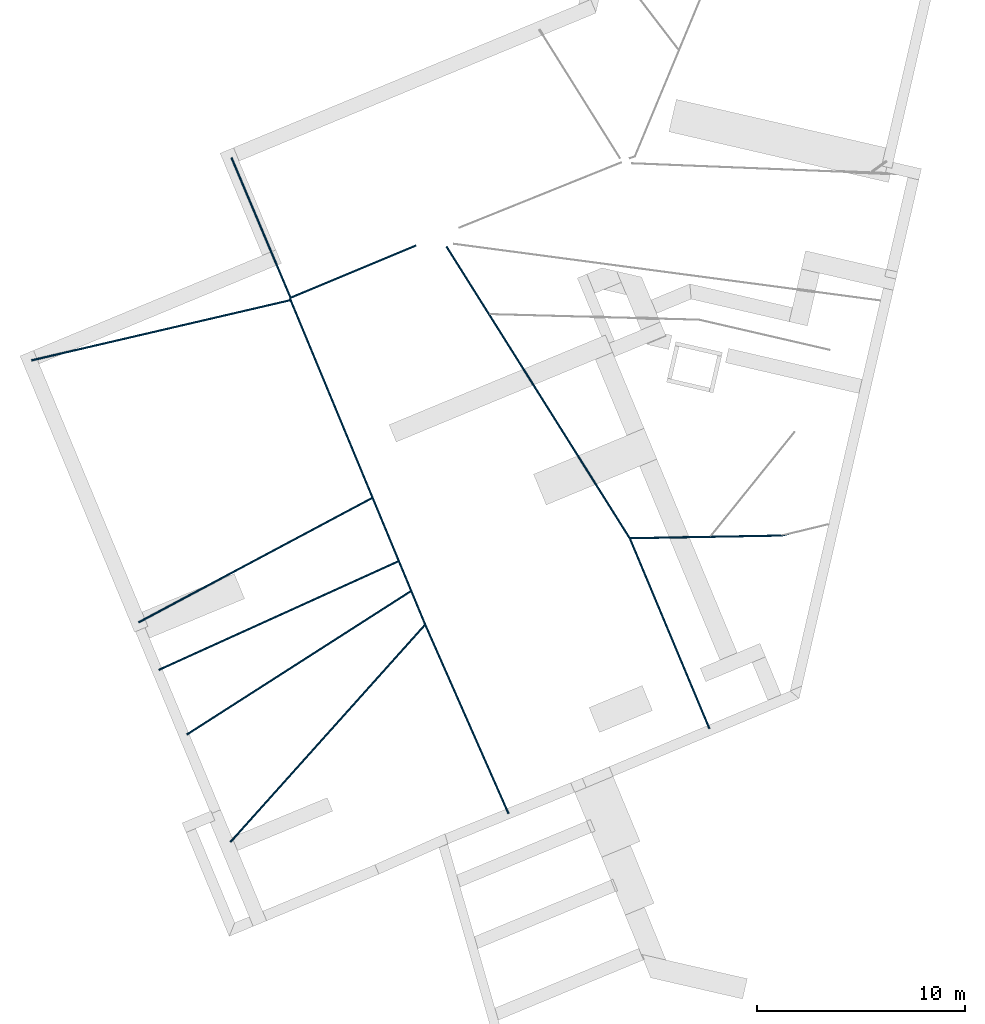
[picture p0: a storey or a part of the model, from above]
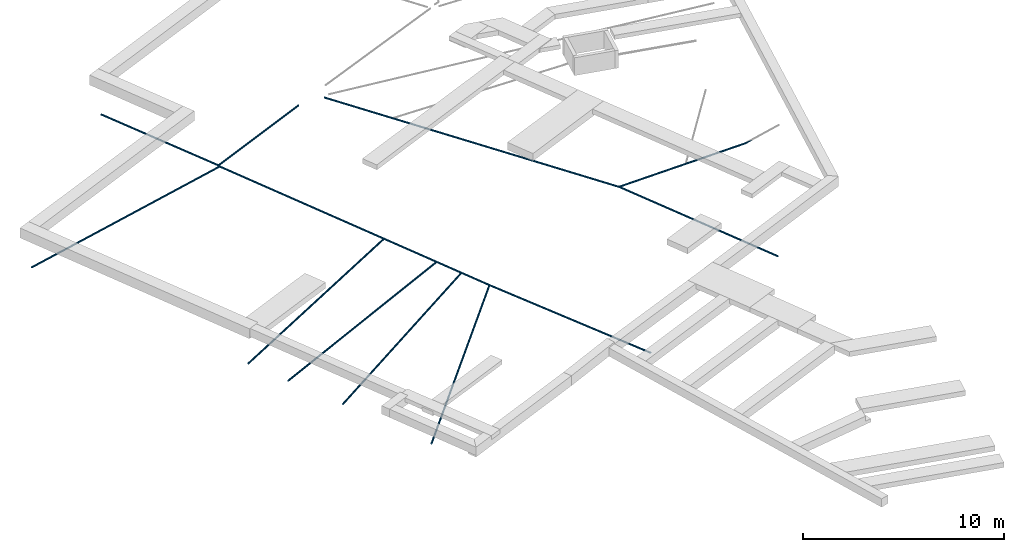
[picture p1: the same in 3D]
Properties of the parts of a building model (IFC2X3), part 14 of 22

# IfcWall: 3 - Cloison 72mm Placostil 74 (508)
Name | In | Classification | Material | AcousticRating | Component 2, Isolation - Laine de roche, ThermalConductivity | Component 2, Isolation - Laine de roche, SpecificHeatCapacity (J/kg/K) | Component 2, Isolation - Laine de roche, MassDensity (kg/m3) | Component 2, Isolation - Laine de roche, Embodied Energy | Component 2, Isolation - Laine de roche, Embodied Carbon | Component 2, Isolation - Laine de roche, Name | Component 2, Isolation - Laine de roche, Participates in Collision Detection | Length (m) | Height (m) | GrossFootprintArea (m2) = NetFootprintArea (m2) | GrossSideArea (m2) | NetSideArea (m2) | GrossVolume (m3) | NetVolume (m3) | Component 1, Finition int - Plaque de plâtre, ThermalConductivity | Component 1, Finition int - Plaque de plâtre, SpecificHeatCapacity (J/kg/K) | Component 1, Finition int - Plaque de plâtre, MassDensity (kg/m3) | Component 1, Finition int - Plaque de plâtre, Embodied Energy | Component 1, Finition int - Plaque de plâtre, Embodied Carbon | Component 1, Finition int - Plaque de plâtre, Name | Component 1, Finition int - Plaque de plâtre, Participates in Collision Detection
Cloison Placostil 72/48 | R+2 | Mur (Classification ARCHICAD); Cloison (Classification ARCHICAD) | Finition int - Plaque de plâtre (2), Isolation - Laine de roche | Non défini | 0.04 | 840 | 160 | 23.4 (MJ/kg) | 1.73 (kgCO₂/kg) | Isolation - Laine de roche | no | 0.637 | 2.5 | 0.048021 | 1.60875 | 1.59523 | 0.121147 | 0.120236 | 0.8 | 1000 | 1600 | 1.45 (MJ/kg) | 0.22 (kgCO₂/kg) | Finition int - Plaque de plâtre | no | Material Properties - Component 1: 2 with these values
Cloison Placostil 72/48 | R+2 | Mur (Classification ARCHICAD); Cloison (Classification ARCHICAD) | Finition int - Plaque de plâtre (2), Isolation - Laine de roche | Non défini | 0.04 | 840 | 160 | 23.4 (MJ/kg) | 1.73 (kgCO₂/kg) | Isolation - Laine de roche | no | 3.21029 | 2.5 | 0.238185 | 8.02572 | 8.02572 | 0.595464 | 0.595464 | 0.8 | 1000 | 1600 | 1.45 (MJ/kg) | 0.22 (kgCO₂/kg) | Finition int - Plaque de plâtre | no | Material Properties - Component 1: 2 with these values
Cloison Placostil 72/48 | R+2 | Mur (Classification ARCHICAD); Cloison (Classification ARCHICAD) | Finition int - Plaque de plâtre (2), Isolation - Laine de roche | Non défini | 0.04 | 840 | 160 | 23.4 (MJ/kg) | 1.73 (kgCO₂/kg) | Isolation - Laine de roche | no | 2.37847 | 2.5 | 0.177327 | 5.96242 | 5.96242 | 0.443319 | 0.443319 | Material Properties - Component 3, Finition int - Plaque de plâtre, ThermalConductivity: 0.8; Component 3, Finition int - Plaque de plâtre, SpecificHeatCapacity: 1000 J/kg/K; Component 3, Finition int - Plaque de plâtre, MassDensity: 1600 kg/m3; Component 3, Finition int - Plaque de plâtre, Embodied Energy: 1.45 (MJ/kg); Component 3, Finition int - Plaque de plâtre, Embodied Carbon: 0.22 (kgCO₂/kg); Component 3, Finition int - Plaque de plâtre, Name: Finition int - Plaque de plâtre; Component 3, Finition int - Plaque de plâtre, Participates in Collision Detection: no; Component 3: 2 with these values
Cloison Placostil 72/48 | R+2 | Mur (Classification ARCHICAD); Cloison (Classification ARCHICAD) | Finition int - Plaque de plâtre (2), Isolation - Laine de roche | Non défini | 0.04 | 840 | 160 | 23.4 (MJ/kg) | 1.73 (kgCO₂/kg) | Isolation - Laine de roche | no | 1.45159 | 2.5 | 0.106794 | 3.56898 | 3.56898 | 0.266984 | 0.266984 | 0.8 | 1000 | 1600 | 1.45 (MJ/kg) | 0.22 (kgCO₂/kg) | Finition int - Plaque de plâtre | no | Material Properties - Component 1: 2 with these values
Cloison Placostil 72/48 | R+3 | Mur (Classification ARCHICAD); Cloison (Classification ARCHICAD) | Finition int - Plaque de plâtre (2), Isolation - Laine de roche | Non défini | 0.04 | 840 | 160 | 23.4 (MJ/kg) | 1.73 (kgCO₂/kg) | Isolation - Laine de roche | no | 0.637 | 2.5 | 0.045817 | 1.57625 | 1.57625 | 0.114542 | 0.114542 | Material Properties - Component 3, Finition int - Plaque de plâtre, ThermalConductivity: 0.8; Component 3, Finition int - Plaque de plâtre, SpecificHeatCapacity: 1000 J/kg/K; Component 3, Finition int - Plaque de plâtre, MassDensity: 1600 kg/m3; Component 3, Finition int - Plaque de plâtre, Embodied Energy: 1.45 (MJ/kg); Component 3, Finition int - Plaque de plâtre, Embodied Carbon: 0.22 (kgCO₂/kg); Component 3, Finition int - Plaque de plâtre, Name: Finition int - Plaque de plâtre; Component 3, Finition int - Plaque de plâtre, Participates in Collision Detection: no; Component 3: 2 with these values
Cloison Placostil 72/48 | R+3 | Mur (Classification ARCHICAD); Cloison (Classification ARCHICAD) | Finition int - Plaque de plâtre (2), Isolation - Laine de roche | Non défini | 0.04 | 840 | 160 | 23.4 (MJ/kg) | 1.73 (kgCO₂/kg) | Isolation - Laine de roche | no | 0.944 | 2.5 | 0.065628 | 2.175 | 2.175 | 0.16407 | 0.16407 | 0.8 | 1000 | 1600 | 1.45 (MJ/kg) | 0.22 (kgCO₂/kg) | Finition int - Plaque de plâtre | no | Material Properties - Component 1: 2 with these values
Cloison Placostil 72/48 | R+3 | Mur (Classification ARCHICAD); Cloison (Classification ARCHICAD) | Finition int - Plaque de plâtre (2), Isolation - Laine de roche | Non défini | 0.04 | 840 | 160 | 23.4 (MJ/kg) | 1.73 (kgCO₂/kg) | Isolation - Laine de roche | no | 1.00874 | 0.42 | 0 | 2.52184 | 0.42367 | 0.186616 | 0.0313516 | 0.8 | 1000 | 1600 | 1.45 (MJ/kg) | 0.22 (kgCO₂/kg) | Finition int - Plaque de plâtre | no | Material Properties - Component 1: 2 with these values
Cloison Placostil 72/48 | R+3 | Mur (Classification ARCHICAD); Cloison (Classification ARCHICAD) | Finition int - Plaque de plâtre (2), Isolation - Laine de roche | Non défini | 0.04 | 840 | 160 | 23.4 (MJ/kg) | 1.73 (kgCO₂/kg) | Isolation - Laine de roche | no | 0.363 | 2.5 | 0.025541 | 0.802125 | 0.802125 | 0.0615353 | 0.0615353 | 0.8 | 1000 | 1600 | 1.45 (MJ/kg) | 0.22 (kgCO₂/kg) | Finition int - Plaque de plâtre | no | Material Properties - Component 1: 2 with these values
Cloison Placostil 72/48 | R+3 | Mur (Classification ARCHICAD); Cloison (Classification ARCHICAD) | Finition int - Plaque de plâtre (2), Isolation - Laine de roche | Non défini | 0.04 | 840 | 160 | 23.4 (MJ/kg) | 1.73 (kgCO₂/kg) | Isolation - Laine de roche | no | 1.88136 | 2.5 | 0.1379 | 4.68715 | 4.68715 | 0.344749 | 0.344749 | 0.8 | 1000 | 1600 | 1.45 (MJ/kg) | 0.22 (kgCO₂/kg) | Finition int - Plaque de plâtre | no | Material Properties - Component 1: 2 with these values
Cloison Placostil 72/48 | R+3 | Mur (Classification ARCHICAD); Cloison (Classification ARCHICAD) | Finition int - Plaque de plâtre (2), Isolation - Laine de roche | Non défini | 0.04 | 840 | 160 | 23.4 (MJ/kg) | 1.73 (kgCO₂/kg) | Isolation - Laine de roche | no | 3.21029 | 2.49 | 0.238185 | 7.99362 | 7.99362 | 0.593082 | 0.593082 | 0.8 | 1000 | 1600 | 1.45 (MJ/kg) | 0.22 (kgCO₂/kg) | Finition int - Plaque de plâtre | no | Material Properties - Component 1: 2 with these values
Cloison Placostil 72/48 | R+3 | Mur (Classification ARCHICAD); Cloison (Classification ARCHICAD) | Finition int - Plaque de plâtre (2), Isolation - Laine de roche | Non défini | 0.04 | 840 | 160 | 23.4 (MJ/kg) | 1.73 (kgCO₂/kg) | Isolation - Laine de roche | no | 0.638 | 2.5 | 0.048533 | 1.61125 | 1.61125 | 0.121332 | 0.121332 | Material Properties - Component 3, Finition int - Plaque de plâtre, ThermalConductivity: 0.8; Component 3, Finition int - Plaque de plâtre, SpecificHeatCapacity: 1000 J/kg/K; Component 3, Finition int - Plaque de plâtre, MassDensity: 1600 kg/m3; Component 3, Finition int - Plaque de plâtre, Embodied Energy: 1.45 (MJ/kg); Component 3, Finition int - Plaque de plâtre, Embodied Carbon: 0.22 (kgCO₂/kg); Component 3, Finition int - Plaque de plâtre, Name: Finition int - Plaque de plâtre; Component 3, Finition int - Plaque de plâtre, Participates in Collision Detection: no; Component 3: 2 with these values
Cloison Placostil 72/48 | R+3 | Mur (Classification ARCHICAD); Cloison (Classification ARCHICAD) | Finition int - Plaque de plâtre (2), Isolation - Laine de roche | Non défini | 0.04 | 840 | 160 | 23.4 (MJ/kg) | 1.73 (kgCO₂/kg) | Isolation - Laine de roche | no | 4.122 | 2.5 | 0.306349 | 10.3213 | 10.3213 | 0.765873 | 0.765873 | 0.8 | 1000 | 1600 | 1.45 (MJ/kg) | 0.22 (kgCO₂/kg) | Finition int - Plaque de plâtre | no | Material Properties - Component 1: 2 with these values
Cloison Placostil 72/48 | R+3 | Mur (Classification ARCHICAD); Cloison (Classification ARCHICAD) | Finition int - Plaque de plâtre (2), Isolation - Laine de roche | Non défini | 0.04 | 840 | 160 | 23.4 (MJ/kg) | 1.73 (kgCO₂/kg) | Isolation - Laine de roche | no | 0.152 | 2.5 | 0.009927 | 0.36375 | 0.36375 | 0.0248175 | 0.0248175 | Material Properties - Component 3, Finition int - Plaque de plâtre, ThermalConductivity: 0.8; Component 3, Finition int - Plaque de plâtre, SpecificHeatCapacity: 1000 J/kg/K; Component 3, Finition int - Plaque de plâtre, MassDensity: 1600 kg/m3; Component 3, Finition int - Plaque de plâtre, Embodied Energy: 1.45 (MJ/kg); Component 3, Finition int - Plaque de plâtre, Embodied Carbon: 0.22 (kgCO₂/kg); Component 3, Finition int - Plaque de plâtre, Name: Finition int - Plaque de plâtre; Component 3, Finition int - Plaque de plâtre, Participates in Collision Detection: no; Component 3: 2 with these values
Cloison Placostil 72/48 | R+3 | Mur (Classification ARCHICAD); Cloison (Classification ARCHICAD) | Finition int - Plaque de plâtre (2), Isolation - Laine de roche | Non défini | 0.04 | 840 | 160 | 23.4 (MJ/kg) | 1.73 (kgCO₂/kg) | Isolation - Laine de roche | no | 0.601 | 2.5 | 0.045098 | 1.5025 | 1.5025 | 0.112745 | 0.112745 | Material Properties - Component 3, Finition int - Plaque de plâtre, ThermalConductivity: 0.8; Component 3, Finition int - Plaque de plâtre, SpecificHeatCapacity: 1000 J/kg/K; Component 3, Finition int - Plaque de plâtre, MassDensity: 1600 kg/m3; Component 3, Finition int - Plaque de plâtre, Embodied Energy: 1.45 (MJ/kg); Component 3, Finition int - Plaque de plâtre, Embodied Carbon: 0.22 (kgCO₂/kg); Component 3, Finition int - Plaque de plâtre, Name: Finition int - Plaque de plâtre; Component 3, Finition int - Plaque de plâtre, Participates in Collision Detection: no; Component 3: 2 with these values
Cloison Placostil 72/48 | R+3 | Mur (Classification ARCHICAD); Cloison (Classification ARCHICAD) | Finition int - Plaque de plâtre (2), Isolation - Laine de roche | Non défini | 0.04 | 840 | 160 | 23.4 (MJ/kg) | 1.73 (kgCO₂/kg) | Isolation - Laine de roche | no | 0.637 | 2.5 | 0.048459 | 1.60875 | 1.60875 | 0.121148 | 0.121148 | 0.8 | 1000 | 1600 | 1.45 (MJ/kg) | 0.22 (kgCO₂/kg) | Finition int - Plaque de plâtre | no | Material Properties - Component 1: 2 with these values
Cloison Placostil 72/48 | R+3 | Mur (Classification ARCHICAD); Cloison (Classification ARCHICAD) | Finition int - Plaque de plâtre (2), Isolation - Laine de roche | Non défini | 0.04 | 840 | 160 | 23.4 (MJ/kg) | 1.73 (kgCO₂/kg) | Isolation - Laine de roche | no | 0.886 | 2.49 | 0.064243 | 2.18995 | 2.18995 | 0.159965 | 0.159965 | Material Properties - Component 3, Finition int - Plaque de plâtre, ThermalConductivity: 0.8; Component 3, Finition int - Plaque de plâtre, SpecificHeatCapacity: 1000 J/kg/K; Component 3, Finition int - Plaque de plâtre, MassDensity: 1600 kg/m3; Component 3, Finition int - Plaque de plâtre, Embodied Energy: 1.45 (MJ/kg); Component 3, Finition int - Plaque de plâtre, Embodied Carbon: 0.22 (kgCO₂/kg); Component 3, Finition int - Plaque de plâtre, Name: Finition int - Plaque de plâtre; Component 3, Finition int - Plaque de plâtre, Participates in Collision Detection: no; Component 3: 2 with these values
Cloison Placostil 72/48 | R+4 | Mur (Classification ARCHICAD); Cloison (Classification ARCHICAD) | Finition int - Plaque de plâtre (2), Isolation - Laine de roche | Non défini | 0.04 | 840 | 160 | 23.4 (MJ/kg) | 1.73 (kgCO₂/kg) | Isolation - Laine de roche | no | 2.817 | 2.5 | 0.209779 | 7.05875 | 7.05875 | 0.524447 | 0.524447 | 0.8 | 1000 | 1600 | 1.45 (MJ/kg) | 0.22 (kgCO₂/kg) | Finition int - Plaque de plâtre | no | Material Properties - Component 1: 2 with these values
Cloison Placostil 72/48 | R+4 | Mur (Classification ARCHICAD); Cloison (Classification ARCHICAD) | Finition int - Plaque de plâtre (2), Isolation - Laine de roche | Non défini | 0.04 | 840 | 160 | 23.4 (MJ/kg) | 1.73 (kgCO₂/kg) | Isolation - Laine de roche | no | 0.62784 | 2.5 | 0.0477812 | 1.58585 | 1.58585 | 0.119453 | 0.119453 | Material Properties - Component 3, Finition int - Plaque de plâtre, ThermalConductivity: 0.8; Component 3, Finition int - Plaque de plâtre, SpecificHeatCapacity: 1000 J/kg/K; Component 3, Finition int - Plaque de plâtre, MassDensity: 1600 kg/m3; Component 3, Finition int - Plaque de plâtre, Embodied Energy: 1.45 (MJ/kg); Component 3, Finition int - Plaque de plâtre, Embodied Carbon: 0.22 (kgCO₂/kg); Component 3, Finition int - Plaque de plâtre, Name: Finition int - Plaque de plâtre; Component 3, Finition int - Plaque de plâtre, Participates in Collision Detection: no; Component 3: 2 with these values
Cloison Placostil 72/48 | R+4 | Mur (Classification ARCHICAD); Cloison (Classification ARCHICAD) | Finition int - Plaque de plâtre (2), Isolation - Laine de roche | Non défini | 0.04 | 840 | 160 | 23.4 (MJ/kg) | 1.73 (kgCO₂/kg) | Isolation - Laine de roche | no | 0.685 | 2.48 | 0.049369 | 1.68268 | 1.68268 | 0.122435 | 0.122435 | Material Properties - Component 3, Finition int - Plaque de plâtre, ThermalConductivity: 0.8; Component 3, Finition int - Plaque de plâtre, SpecificHeatCapacity: 1000 J/kg/K; Component 3, Finition int - Plaque de plâtre, MassDensity: 1600 kg/m3; Component 3, Finition int - Plaque de plâtre, Embodied Energy: 1.45 (MJ/kg); Component 3, Finition int - Plaque de plâtre, Embodied Carbon: 0.22 (kgCO₂/kg); Component 3, Finition int - Plaque de plâtre, Name: Finition int - Plaque de plâtre; Component 3, Finition int - Plaque de plâtre, Participates in Collision Detection: no; Component 3: 2 with these values
Cloison Placostil 72/48 | R+4 | Mur (Classification ARCHICAD); Cloison (Classification ARCHICAD) | Finition int - Plaque de plâtre (2), Isolation - Laine de roche | Non défini | 0.04 | 840 | 160 | 23.4 (MJ/kg) | 1.73 (kgCO₂/kg) | Isolation - Laine de roche | no | 0.685 | 2.48 | 0.049369 | 1.68268 | 1.68268 | 0.122435 | 0.122435 | 0.8 | 1000 | 1600 | 1.45 (MJ/kg) | 0.22 (kgCO₂/kg) | Finition int - Plaque de plâtre | no | Material Properties - Component 1: 2 with these values
Cloison Placostil 72/48 | R+4 | Mur (Classification ARCHICAD); Cloison (Classification ARCHICAD) | Finition int - Plaque de plâtre (2), Isolation - Laine de roche | Non défini | 0.04 | 840 | 160 | 23.4 (MJ/kg) | 1.73 (kgCO₂/kg) | Isolation - Laine de roche | no | 0.913 | 2.48 | 0.068186 | 2.26424 | 2.26424 | 0.169101 | 0.169101 | 0.8 | 1000 | 1600 | 1.45 (MJ/kg) | 0.22 (kgCO₂/kg) | Finition int - Plaque de plâtre | no | Material Properties - Component 1: 2 with these values
Cloison Placostil 72/48 | R+4 | Mur (Classification ARCHICAD); Cloison (Classification ARCHICAD) | Finition int - Plaque de plâtre (2), Isolation - Laine de roche | Non défini | 0.04 | 840 | 160 | 23.4 (MJ/kg) | 1.73 (kgCO₂/kg) | Isolation - Laine de roche | no | 0.151506 | 2.48 | 0.0130796 | 0.398531 | 0.398531 | 0.0324374 | 0.0324374 | Material Properties - Component 3, Finition int - Plaque de plâtre, ThermalConductivity: 0.8; Component 3, Finition int - Plaque de plâtre, SpecificHeatCapacity: 1000 J/kg/K; Component 3, Finition int - Plaque de plâtre, MassDensity: 1600 kg/m3; Component 3, Finition int - Plaque de plâtre, Embodied Energy: 1.45 (MJ/kg); Component 3, Finition int - Plaque de plâtre, Embodied Carbon: 0.22 (kgCO₂/kg); Component 3, Finition int - Plaque de plâtre, Name: Finition int - Plaque de plâtre; Component 3, Finition int - Plaque de plâtre, Participates in Collision Detection: no; Component 3: 2 with these values
Cloison Placostil 72/48 | R+4 | Mur (Classification ARCHICAD); Cloison (Classification ARCHICAD) | Finition int - Plaque de plâtre (2), Isolation - Laine de roche | Non défini | 0.04 | 840 | 160 | 23.4 (MJ/kg) | 1.73 (kgCO₂/kg) | Isolation - Laine de roche | no | 0.484 | 2.48 | 0.037137 | 1.21644 | 1.21644 | 0.0920998 | 0.0920998 | 0.8 | 1000 | 1600 | 1.45 (MJ/kg) | 0.22 (kgCO₂/kg) | Finition int - Plaque de plâtre | no | Material Properties - Component 1: 2 with these values
Cloison Placostil 72/48 | Rez-de-chaussée | Cloison (Classification ARCHICAD) | Finition int - Plaque de plâtre (2), Isolation - Laine de roche | Non défini | 0.04 | 840 | 160 | 23.4 (MJ/kg) | 1.73 (kgCO₂/kg) | Isolation - Laine de roche | no | 0.591249 | 2.5 | 0.0424315 | 1.46187 | 1.46187 | 0.106079 | 0.106079 | 0.8 | 1000 | 1600 | 1.45 (MJ/kg) | 0.22 (kgCO₂/kg) | Finition int - Plaque de plâtre | no | Material Properties - Component 1: 2 with these values
Cloison Placostil 72/48 | Rez-de-chaussée | Cloison (Classification ARCHICAD) | Finition int - Plaque de plâtre (2), Isolation - Laine de roche | Non défini | 0.04 | 840 | 160 | 23.4 (MJ/kg) | 1.73 (kgCO₂/kg) | Isolation - Laine de roche | no | 0.297 | 2.5 | 0.020657 | 0.72625 | 0.72625 | 0.0516425 | 0.0516425 | 0.8 | 1000 | 1600 | 1.45 (MJ/kg) | 0.22 (kgCO₂/kg) | Finition int - Plaque de plâtre | no | Material Properties - Component 1: 2 with these values
Cloison Placostil 72/48 | Rez-de-chaussée | Cloison (Classification ARCHICAD) | Finition int - Plaque de plâtre (2), Isolation - Laine de roche | Non défini | 0.04 | 840 | 160 | 23.4 (MJ/kg) | 1.73 (kgCO₂/kg) | Isolation - Laine de roche | no | 0.567598 | 2.5 | 0.0433232 | 1.43524 | 1.43524 | 0.108308 | 0.108308 | Material Properties - Component 3, Finition int - Plaque de plâtre, ThermalConductivity: 0.8; Component 3, Finition int - Plaque de plâtre, SpecificHeatCapacity: 1000 J/kg/K; Component 3, Finition int - Plaque de plâtre, MassDensity: 1600 kg/m3; Component 3, Finition int - Plaque de plâtre, Embodied Energy: 1.45 (MJ/kg); Component 3, Finition int - Plaque de plâtre, Embodied Carbon: 0.22 (kgCO₂/kg); Component 3, Finition int - Plaque de plâtre, Name: Finition int - Plaque de plâtre; Component 3, Finition int - Plaque de plâtre, Participates in Collision Detection: no; Component 3: 2 with these values
Cloison Placostil 72/48 | Rez-de-chaussée | Cloison (Classification ARCHICAD) | Finition int - Plaque de plâtre (2), Isolation - Laine de roche | Non défini | 0.04 | 840 | 160 | 23.4 (MJ/kg) | 1.73 (kgCO₂/kg) | Isolation - Laine de roche | no | 4.122 | 2.5 | 0.306349 | 10.3213 | 10.3213 | 0.765873 | 0.765873 | 0.8 | 1000 | 1600 | 1.45 (MJ/kg) | 0.22 (kgCO₂/kg) | Finition int - Plaque de plâtre | no | Material Properties - Component 1: 2 with these values
Cloison Placostil 72/48 | Rez-de-chaussée | Cloison (Classification ARCHICAD) | Finition int - Plaque de plâtre (2), Isolation - Laine de roche | Non défini | 0.04 | 840 | 160 | 23.4 (MJ/kg) | 1.73 (kgCO₂/kg) | Isolation - Laine de roche | no | 1.10539 | 2.5 | 0.0824227 | 2.76347 | 2.76347 | 0.206057 | 0.206057 | Material Properties - Component 3, Finition int - Plaque de plâtre, ThermalConductivity: 0.8; Component 3, Finition int - Plaque de plâtre, SpecificHeatCapacity: 1000 J/kg/K; Component 3, Finition int - Plaque de plâtre, MassDensity: 1600 kg/m3; Component 3, Finition int - Plaque de plâtre, Embodied Energy: 1.45 (MJ/kg); Component 3, Finition int - Plaque de plâtre, Embodied Carbon: 0.22 (kgCO₂/kg); Component 3, Finition int - Plaque de plâtre, Name: Finition int - Plaque de plâtre; Component 3, Finition int - Plaque de plâtre, Participates in Collision Detection: no; Component 3: 2 with these values
Cloison Placostil 72/48 | Rez-de-chaussée | Cloison (Classification ARCHICAD) | Finition int - Plaque de plâtre (2), Isolation - Laine de roche | Non défini | 0.04 | 840 | 160 | 23.4 (MJ/kg) | 1.73 (kgCO₂/kg) | Isolation - Laine de roche | no | 0.613 | 2.5 | 0.046683 | 1.3629 | 1.3629 | 0.111875 | 0.111875 | Material Properties - Component 3, Finition int - Plaque de plâtre, ThermalConductivity: 0.8; Component 3, Finition int - Plaque de plâtre, SpecificHeatCapacity: 1000 J/kg/K; Component 3, Finition int - Plaque de plâtre, MassDensity: 1600 kg/m3; Component 3, Finition int - Plaque de plâtre, Embodied Energy: 1.45 (MJ/kg); Component 3, Finition int - Plaque de plâtre, Embodied Carbon: 0.22 (kgCO₂/kg); Component 3, Finition int - Plaque de plâtre, Name: Finition int - Plaque de plâtre; Component 3, Finition int - Plaque de plâtre, Participates in Collision Detection: no; Component 3: 2 with these values
Cloison Placostil 72/48 | Rez-de-chaussée | Cloison (Classification ARCHICAD) | Finition int - Plaque de plâtre (2), Isolation - Laine de roche | Non défini | 0.04 | 840 | 160 | 23.4 (MJ/kg) | 1.73 (kgCO₂/kg) | Isolation - Laine de roche | no | 3.08 | 2.5 | 0.229241 | 7.71625 | 7.71625 | 0.573102 | 0.573102 | 0.8 | 1000 | 1600 | 1.45 (MJ/kg) | 0.22 (kgCO₂/kg) | Finition int - Plaque de plâtre | no | Material Properties - Component 1: 2 with these values
Cloison Placostil 72/48 | Rez-de-chaussée | Cloison (Classification ARCHICAD) | Finition int - Plaque de plâtre (2), Isolation - Laine de roche | Non défini | 0.04 | 840 | 160 | 23.4 (MJ/kg) | 1.73 (kgCO₂/kg) | Isolation - Laine de roche | no | 0.662 | 2.5 | 0.048988 | 1.655 | 1.655 | 0.12247 | 0.12247 | Material Properties - Component 3, Finition int - Plaque de plâtre, ThermalConductivity: 0.8; Component 3, Finition int - Plaque de plâtre, SpecificHeatCapacity: 1000 J/kg/K; Component 3, Finition int - Plaque de plâtre, MassDensity: 1600 kg/m3; Component 3, Finition int - Plaque de plâtre, Embodied Energy: 1.45 (MJ/kg); Component 3, Finition int - Plaque de plâtre, Embodied Carbon: 0.22 (kgCO₂/kg); Component 3, Finition int - Plaque de plâtre, Name: Finition int - Plaque de plâtre; Component 3, Finition int - Plaque de plâtre, Participates in Collision Detection: no; Component 3: 2 with these values
Cloison Placostil 72/48 | Rez-de-chaussée | Cloison (Classification ARCHICAD) | Finition int - Plaque de plâtre (2), Isolation - Laine de roche | Non défini | 0.04 | 840 | 160 | 23.4 (MJ/kg) | 1.73 (kgCO₂/kg) | Isolation - Laine de roche | no | 3.23529 | 2.5 | 0.240035 | 8.08822 | 8.08822 | 0.600089 | 0.600089 | 0.8 | 1000 | 1600 | 1.45 (MJ/kg) | 0.22 (kgCO₂/kg) | Finition int - Plaque de plâtre | no | Material Properties - Component 1: 2 with these values
Cloison Placostil 72/48 | Rez-de-chaussée | Cloison (Classification ARCHICAD) | Finition int - Plaque de plâtre (2), Isolation - Laine de roche | Non défini | 0.04 | 840 | 160 | 23.4 (MJ/kg) | 1.73 (kgCO₂/kg) | Isolation - Laine de roche | no | 0.906 | 2.5 | 0.068365 | 2.28125 | 2.28125 | 0.170912 | 0.170912 | Material Properties - Component 3, Finition int - Plaque de plâtre, ThermalConductivity: 0.8; Component 3, Finition int - Plaque de plâtre, SpecificHeatCapacity: 1000 J/kg/K; Component 3, Finition int - Plaque de plâtre, MassDensity: 1600 kg/m3; Component 3, Finition int - Plaque de plâtre, Embodied Energy: 1.45 (MJ/kg); Component 3, Finition int - Plaque de plâtre, Embodied Carbon: 0.22 (kgCO₂/kg); Component 3, Finition int - Plaque de plâtre, Name: Finition int - Plaque de plâtre; Component 3, Finition int - Plaque de plâtre, Participates in Collision Detection: no; Component 3: 2 with these values
Cloison Placostil 72/48 | Rez-de-chaussée | Cloison (Classification ARCHICAD) | Finition int - Plaque de plâtre (2), Isolation - Laine de roche | Non défini | 0.04 | 840 | 160 | 23.4 (MJ/kg) | 1.73 (kgCO₂/kg) | Isolation - Laine de roche | no | 0.636334 | 2.5 | 0.0457674 | 1.57458 | 1.57458 | 0.114419 | 0.114419 | Material Properties - Component 3, Finition int - Plaque de plâtre, ThermalConductivity: 0.8; Component 3, Finition int - Plaque de plâtre, SpecificHeatCapacity: 1000 J/kg/K; Component 3, Finition int - Plaque de plâtre, MassDensity: 1600 kg/m3; Component 3, Finition int - Plaque de plâtre, Embodied Energy: 1.45 (MJ/kg); Component 3, Finition int - Plaque de plâtre, Embodied Carbon: 0.22 (kgCO₂/kg); Component 3, Finition int - Plaque de plâtre, Name: Finition int - Plaque de plâtre; Component 3, Finition int - Plaque de plâtre, Participates in Collision Detection: no; Component 3: 2 with these values
Cloison Placostil 72/48 | Rez-de-chaussée | Cloison (Classification ARCHICAD) | Finition int - Plaque de plâtre (2), Isolation - Laine de roche | Non défini | 0.04 | 840 | 160 | 23.4 (MJ/kg) | 1.73 (kgCO₂/kg) | Isolation - Laine de roche | no | 0.91 | 2.5 | 0.067964 | 2.275 | 2.275 | 0.16991 | 0.16991 | 0.8 | 1000 | 1600 | 1.45 (MJ/kg) | 0.22 (kgCO₂/kg) | Finition int - Plaque de plâtre | no | Material Properties - Component 1: 2 with these values
Cloison Placostil 72/48 | Rez-de-chaussée | Cloison (Classification ARCHICAD) | Finition int - Plaque de plâtre (2), Isolation - Laine de roche | Non défini | 0.04 | 840 | 160 | 23.4 (MJ/kg) | 1.73 (kgCO₂/kg) | Isolation - Laine de roche | no | 0.613 | 2.5 | 0.044041 | 1.51625 | 1.51625 | 0.110102 | 0.110102 | 0.8 | 1000 | 1600 | 1.45 (MJ/kg) | 0.22 (kgCO₂/kg) | Finition int - Plaque de plâtre | no | Material Properties - Component 1: 2 with these values
Cloison Placostil 72/48 | Rez-de-chaussée | Cloison (Classification ARCHICAD) | Finition int - Plaque de plâtre (2), Isolation - Laine de roche | Non défini | 0.04 | 840 | 160 | 23.4 (MJ/kg) | 1.73 (kgCO₂/kg) | Isolation - Laine de roche | no | 0.637 | 2.5 | 0.048459 | 1.60875 | 1.60875 | 0.121147 | 0.121147 | Material Properties - Component 3, Finition int - Plaque de plâtre, ThermalConductivity: 0.8; Component 3, Finition int - Plaque de plâtre, SpecificHeatCapacity: 1000 J/kg/K; Component 3, Finition int - Plaque de plâtre, MassDensity: 1600 kg/m3; Component 3, Finition int - Plaque de plâtre, Embodied Energy: 1.45 (MJ/kg); Component 3, Finition int - Plaque de plâtre, Embodied Carbon: 0.22 (kgCO₂/kg); Component 3, Finition int - Plaque de plâtre, Name: Finition int - Plaque de plâtre; Component 3, Finition int - Plaque de plâtre, Participates in Collision Detection: no; Component 3: 2 with these values
Cloison Placostil 72/48 | Rez-de-chaussée | Cloison (Classification ARCHICAD) | Finition int - Plaque de plâtre (2), Isolation - Laine de roche | Non défini | 0.04 | 840 | 160 | 23.4 (MJ/kg) | 1.73 (kgCO₂/kg) | Isolation - Laine de roche | no | 0.672 | 2.5 | 0.051049 | 1.57019 | 1.57019 | 0.124345 | 0.124345 | 0.8 | 1000 | 1600 | 1.45 (MJ/kg) | 0.22 (kgCO₂/kg) | Finition int - Plaque de plâtre | no | Material Properties - Component 1: 2 with these values
Cloison Placostil 72/48 | Rez-de-chaussée | Cloison (Classification ARCHICAD) | Finition int - Plaque de plâtre (2), Isolation - Laine de roche | Non défini | 0.04 | 840 | 160 | 23.4 (MJ/kg) | 1.73 (kgCO₂/kg) | Isolation - Laine de roche | no | 0.637 | 2.5 | 0.048459 | 1.60875 | 1.60875 | 0.121148 | 0.121148 | Material Properties - Component 3, Finition int - Plaque de plâtre, ThermalConductivity: 0.8; Component 3, Finition int - Plaque de plâtre, SpecificHeatCapacity: 1000 J/kg/K; Component 3, Finition int - Plaque de plâtre, MassDensity: 1600 kg/m3; Component 3, Finition int - Plaque de plâtre, Embodied Energy: 1.45 (MJ/kg); Component 3, Finition int - Plaque de plâtre, Embodied Carbon: 0.22 (kgCO₂/kg); Component 3, Finition int - Plaque de plâtre, Name: Finition int - Plaque de plâtre; Component 3, Finition int - Plaque de plâtre, Participates in Collision Detection: no; Component 3: 2 with these values
Cloison Placostil 72/48 | Rez-de-chaussée | Cloison (Classification ARCHICAD) | Finition int - Plaque de plâtre (2), Isolation - Laine de roche | Non défini | 0.04 | 840 | 160 | 23.4 (MJ/kg) | 1.73 (kgCO₂/kg) | Isolation - Laine de roche | no | 3.19738 | 2.5 | 0.23723 | 7.99346 | 7.99346 | 0.593076 | 0.593076 | Material Properties - Component 3, Finition int - Plaque de plâtre, ThermalConductivity: 0.8; Component 3, Finition int - Plaque de plâtre, SpecificHeatCapacity: 1000 J/kg/K; Component 3, Finition int - Plaque de plâtre, MassDensity: 1600 kg/m3; Component 3, Finition int - Plaque de plâtre, Embodied Energy: 1.45 (MJ/kg); Component 3, Finition int - Plaque de plâtre, Embodied Carbon: 0.22 (kgCO₂/kg); Component 3, Finition int - Plaque de plâtre, Name: Finition int - Plaque de plâtre; Component 3, Finition int - Plaque de plâtre, Participates in Collision Detection: no; Component 3: 2 with these values
Cloison Placostil 72/48 | Rez-de-chaussée | Cloison (Classification ARCHICAD) | Finition int - Plaque de plâtre (2), Isolation - Laine de roche | Non défini | 0.04 | 840 | 160 | 23.4 (MJ/kg) | 1.73 (kgCO₂/kg) | Isolation - Laine de roche | no | 3.205 | 2.5 | 0.237794 | 8.0125 | 8.0125 | 0.594485 | 0.594485 | 0.8 | 1000 | 1600 | 1.45 (MJ/kg) | 0.22 (kgCO₂/kg) | Finition int - Plaque de plâtre | no | Material Properties - Component 1: 2 with these values
Cloison Placostil 72/48 | Rez-de-chaussée | Cloison (Classification ARCHICAD) | Finition int - Plaque de plâtre (2), Isolation - Laine de roche | Non défini | 0.04 | 840 | 160 | 23.4 (MJ/kg) | 1.73 (kgCO₂/kg) | Isolation - Laine de roche | no | 2.43106 | 2.5 | 0.181219 | 6.09389 | 6.09389 | 0.453048 | 0.453048 | 0.8 | 1000 | 1600 | 1.45 (MJ/kg) | 0.22 (kgCO₂/kg) | Finition int - Plaque de plâtre | no | Material Properties - Component 1: 2 with these values
Cloison Placostil 72/48 | Rez-de-chaussée | Cloison (Classification ARCHICAD) | Finition int - Plaque de plâtre (2), Isolation - Laine de roche | Non défini | 0.04 | 840 | 160 | 23.4 (MJ/kg) | 1.73 (kgCO₂/kg) | Isolation - Laine de roche | no | 1.35948 | 2.5 | 0.101225 | 3.39869 | 3.39869 | 0.253063 | 0.253063 | Material Properties - Component 3, Finition int - Plaque de plâtre, ThermalConductivity: 0.8; Component 3, Finition int - Plaque de plâtre, SpecificHeatCapacity: 1000 J/kg/K; Component 3, Finition int - Plaque de plâtre, MassDensity: 1600 kg/m3; Component 3, Finition int - Plaque de plâtre, Embodied Energy: 1.45 (MJ/kg); Component 3, Finition int - Plaque de plâtre, Embodied Carbon: 0.22 (kgCO₂/kg); Component 3, Finition int - Plaque de plâtre, Name: Finition int - Plaque de plâtre; Component 3, Finition int - Plaque de plâtre, Participates in Collision Detection: no; Component 3: 2 with these values
Cloison Placostil 72/48 | Rez-de-chaussée | Cloison (Classification ARCHICAD) | Finition int - Plaque de plâtre (2), Isolation - Laine de roche | Non défini | 0.04 | 840 | 160 | 23.4 (MJ/kg) | 1.73 (kgCO₂/kg) | Isolation - Laine de roche | no | 1.4 | 2.5 | 0.104224 | 3.5 | 3.5 | 0.26056 | 0.26056 | Material Properties - Component 3, Finition int - Plaque de plâtre, ThermalConductivity: 0.8; Component 3, Finition int - Plaque de plâtre, SpecificHeatCapacity: 1000 J/kg/K; Component 3, Finition int - Plaque de plâtre, MassDensity: 1600 kg/m3; Component 3, Finition int - Plaque de plâtre, Embodied Energy: 1.45 (MJ/kg); Component 3, Finition int - Plaque de plâtre, Embodied Carbon: 0.22 (kgCO₂/kg); Component 3, Finition int - Plaque de plâtre, Name: Finition int - Plaque de plâtre; Component 3, Finition int - Plaque de plâtre, Participates in Collision Detection: no; Component 3: 2 with these values
Cloison Placostil 72/48 | R+1 | Mur (Classification ARCHICAD); Cloison (Classification ARCHICAD) | Finition int - Plaque de plâtre (2), Isolation - Laine de roche | 35 dB(A) | 0.04 | 840 | 160 | 23.4 (MJ/kg) | 1.73 (kgCO₂/kg) | Isolation - Laine de roche | no | 0.64 | 2.5 | 0.04736 | 1.6 | 1.6 | 0.1184 | 0.1184 | Material Properties - Component 3, Finition int - Plaque de plâtre, ThermalConductivity: 0.8; Component 3, Finition int - Plaque de plâtre, SpecificHeatCapacity: 1000 J/kg/K; Component 3, Finition int - Plaque de plâtre, MassDensity: 1600 kg/m3; Component 3, Finition int - Plaque de plâtre, Embodied Energy: 1.45 (MJ/kg); Component 3, Finition int - Plaque de plâtre, Embodied Carbon: 0.22 (kgCO₂/kg); Component 3, Finition int - Plaque de plâtre, Name: Finition int - Plaque de plâtre; Component 3, Finition int - Plaque de plâtre, Participates in Collision Detection: no; Component 3: 2 with these values
Cloison Placostil 72/48 | R+2 | Mur (Classification ARCHICAD); Cloison (Classification ARCHICAD) | Finition int - Plaque de plâtre | Non défini |  |  |  |  |  |  |  | 0.01 | 2.5 | 0.0000184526 | 0.0125 | 0.0125 | 0.0000461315 | 0.0000461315 | Material Properties - Finition int - Plaque de plâtre, ThermalConductivity: 0.8; Finition int - Plaque de plâtre, SpecificHeatCapacity: 1000 J/kg/K; Finition int - Plaque de plâtre, MassDensity: 1600 kg/m3; Finition int - Plaque de plâtre, Embodied Energy: 1.45 (MJ/kg); Finition int - Plaque de plâtre, Embodied Carbon: 0.22 (kgCO₂/kg); Finition int - Plaque de plâtre, Name: Finition int - Plaque de plâtre; Finition int - Plaque de plâtre, Participates in Collision Detection: no
Cloison Placostil 72/48 | R+2 | Mur (Classification ARCHICAD); Cloison (Classification ARCHICAD) | Finition int - Plaque de plâtre (2), Isolation - Laine de roche | Non défini | 0.04 | 840 | 160 | 23.4 (MJ/kg) | 1.73 (kgCO₂/kg) | Isolation - Laine de roche | no | 0.63 | 2.5 | 0.04662 | 1.575 | 1.575 | 0.11655 | 0.11655 | 0.8 | 1000 | 1600 | 1.45 (MJ/kg) | 0.22 (kgCO₂/kg) | Finition int - Plaque de plâtre | no | Material Properties - Component 1: 2 with these values
Cloison Placostil 72/48 | Rez-de-chaussée | Cloison (Classification ARCHICAD) | Finition int - Plaque de plâtre (2), Isolation - Laine de roche | Non défini | 0.04 | 840 | 160 | 23.4 (MJ/kg) | 1.73 (kgCO₂/kg) | Isolation - Laine de roche | no | 0.65 | 2.5 | 0.0481 | 1.625 | 1.625 | 0.12025 | 0.12025 | Material Properties - Component 3, Finition int - Plaque de plâtre, ThermalConductivity: 0.8; Component 3, Finition int - Plaque de plâtre, SpecificHeatCapacity: 1000 J/kg/K; Component 3, Finition int - Plaque de plâtre, MassDensity: 1600 kg/m3; Component 3, Finition int - Plaque de plâtre, Embodied Energy: 1.45 (MJ/kg); Component 3, Finition int - Plaque de plâtre, Embodied Carbon: 0.22 (kgCO₂/kg); Component 3, Finition int - Plaque de plâtre, Name: Finition int - Plaque de plâtre; Component 3, Finition int - Plaque de plâtre, Participates in Collision Detection: no; Component 3: 2 with these values

# IfcWall: 3 - Cloison CF 2H PROMAT 111 (6)
Type - ElementType: PARTITIONING; PredefinedType: USERDEFINED
Description: Paroi CF gaine palière; Classification: Cloison (Classification ARCHICAD)
Pset_WallCommon - AcousticRating: Non défini; ThermalTransmittance: 0; LoadBearing: yes; IsExternal: yes
PSET_Murs_ARCHI - Emplacement: Superstructure; Type: Cloisons; Destination: Gaine Technique Palière; Matériaux: Promat
Propriétés DCE - Numéro de LOT: LOT 09; Numéro article: L09.2.5.4
AC_Pset_RenovationAndPhasing - Renovation Status: Existing
Material Properties - Component 3, Finition int - Plaque de plâtre, ThermalConductivity: 0.8; Component 3, Finition int - Plaque de plâtre, SpecificHeatCapacity: 1000 J/kg/K; Component 3, Finition int - Plaque de plâtre, MassDensity: 1600 kg/m3; Component 3, Finition int - Plaque de plâtre, Embodied Energy: 1.45 (MJ/kg); Component 3, Finition int - Plaque de plâtre, Embodied Carbon: 0.22 (kgCO₂/kg); Component 3, Finition int - Plaque de plâtre, Name: Finition int - Plaque de plâtre; Component 3, Finition int - Plaque de plâtre, Participates in Collision Detection: no; Component 2, Isolation - Laine de roche, ThermalConductivity: 0.04; Component 2, Isolation - Laine de roche, SpecificHeatCapacity: 840 J/kg/K; Component 2, Isolation - Laine de roche, MassDensity: 160 kg/m3; Component 2, Isolation - Laine de roche, Embodied Energy: 23.4 (MJ/kg); Component 2, Isolation - Laine de roche, Embodied Carbon: 1.73 (kgCO₂/kg); Component 2, Isolation - Laine de roche, Name: Isolation - Laine de roche; Component 2, Isolation - Laine de roche, Participates in Collision Detection: no; Component 1, Finition int - Plaque type PROMAT 5cm, ThermalConductivity: 0.18; Component 1, Finition int - Plaque type PROMAT 5cm, SpecificHeatCapacity: 1000 J/kg/K; Component 1, Finition int - Plaque type PROMAT 5cm, MassDensity: 600 kg/m3; Component 1, Finition int - Plaque type PROMAT 5cm, Embodied Energy: 8 (MJ/kg); Component 1, Finition int - Plaque type PROMAT 5cm, Embodied Carbon: 1.2 (kgCO₂/kg); Component 1, Finition int - Plaque type PROMAT 5cm, Name: Finition int - Plaque type PROMAT 5cm; Component 1, Finition int - Plaque type PROMAT 5cm, Participates in Collision Detection: no
BaseQuantities - Height: 2.5 m; Width: 0.111 m
Name | In | Material | Length (m) | GrossFootprintArea (m2) = NetFootprintArea (m2) | GrossSideArea (m2) = NetSideArea (m2) | GrossVolume (m3) = NetVolume (m3)
Cloison CF Promat 5cm | R+2 | Finition int - Plaque de plâtre, Isolation - Laine de roche, Finition int - Plaque type PROMAT 5cm | 0.465367 | 0.0427757 | 0.963416 | 0.106939
Cloison CF Promat 5cm | R+3 | Finition int - Plaque type PROMAT 5cm, Isolation - Laine de roche, Finition int - Plaque de plâtre | 0.834976 | 0.0851788 | 1.92494 | 0.212947
Cloison CF Promat 5cm | Rez-de-chaussée | Finition int - Plaque de plâtre, Isolation - Laine de roche, Finition int - Plaque type PROMAT 5cm | 0.460367 | 0.0405557 | 0.913416 | 0.101389
Cloison CF Promat 5cm | R+1 | Finition int - Plaque de plâtre, Isolation - Laine de roche, Finition int - Plaque type PROMAT 5cm | 0.460367 | 0.0405557 | 0.913416 | 0.101389
Cloison CF Promat 5cm | R+3 | Finition int - Plaque de plâtre, Isolation - Laine de roche, Finition int - Plaque type PROMAT 5cm | 0.345367 | 0.0383357 | 0.863416 | 0.0958392
Cloison CF Promat 5cm | R+3 | Finition int - Plaque type PROMAT 5cm, Isolation - Laine de roche, Finition int - Plaque de plâtre | 0.3895 | 0.030758 | 0.7325 | 0.076895

# IfcWall: 3 - Cloison Gaine Technique 72mm 74 (154)
Type - ElementType: PARTITIONING; PredefinedType: USERDEFINED
Description: Cloison gaine logements; Material: Finition int - Plaque de plâtre (2), Isolation - Laine de roche
Pset_WallCommon - ThermalTransmittance: 0; LoadBearing: yes; IsExternal: yes
PSET_Murs_ARCHI - Emplacement: Superstructure; Type: Cloisons; Destination: Gaine technique logements; Matériaux: Cloison 72/48
Propriétés DCE - Numéro de LOT: LOT 09; Numéro article: L09.2.4.1.1
AC_Pset_RenovationAndPhasing - Renovation Status: Existing
Material Properties - Component 2, Isolation - Laine de roche, ThermalConductivity: 0.04; Component 2, Isolation - Laine de roche, SpecificHeatCapacity: 840 J/kg/K; Component 2, Isolation - Laine de roche, MassDensity: 160 kg/m3; Component 2, Isolation - Laine de roche, Embodied Energy: 23.4 (MJ/kg); Component 2, Isolation - Laine de roche, Embodied Carbon: 1.73 (kgCO₂/kg); Component 2, Isolation - Laine de roche, Name: Isolation - Laine de roche; Component 2, Isolation - Laine de roche, Participates in Collision Detection: no
BaseQuantities - Width: 0.074 m
Name | In | Classification | AcousticRating | Component 1, Finition int - Plaque de plâtre, ThermalConductivity | Component 1, Finition int - Plaque de plâtre, SpecificHeatCapacity (J/kg/K) | Component 1, Finition int - Plaque de plâtre, MassDensity (kg/m3) | Component 1, Finition int - Plaque de plâtre, Embodied Energy | Component 1, Finition int - Plaque de plâtre, Embodied Carbon | Component 1, Finition int - Plaque de plâtre, Name | Component 1, Finition int - Plaque de plâtre, Participates in Collision Detection | Component 1 | Length (m) | Height (m) | GrossFootprintArea (m2) = NetFootprintArea (m2) | GrossSideArea (m2) | NetSideArea (m2) | GrossVolume (m3) | NetVolume (m3)
Cloison Placostil 72/48 | R+1 | Mur (Classification ARCHICAD); Cloison (Classification ARCHICAD) | 35 dB(A) | 0.8 | 1000 | 1600 | 1.45 (MJ/kg) | 0.22 (kgCO₂/kg) | Finition int - Plaque de plâtre | no | 2 with these values | 0.324 | 2.5 | 0.02537 | 0.7225 | 0.7225 | 0.063425 | 0.063425
Cloison Placostil 72/48 | R+2 | Mur (Classification ARCHICAD); Cloison (Classification ARCHICAD) | 35 dB(A) | 0.8 | 1000 | 1600 | 1.45 (MJ/kg) | 0.22 (kgCO₂/kg) | Finition int - Plaque de plâtre | no | 2 with these values | 0.660831 | 2.5 | 0.0476535 | 1.53208 | 1.53208 | 0.119134 | 0.119134
Cloison Placostil 72/48 | Rez-de-chaussée | Cloison (Classification ARCHICAD) | Non défini | 0.8 | 1000 | 1600 | 1.45 (MJ/kg) | 0.22 (kgCO₂/kg) | Finition int - Plaque de plâtre | no | 2 with these values | 0.311 | 2.5 | 0.024239 | 0.67375 | 0.67375 | 0.0605975 | 0.0605975
Cloison Placostil 72/48 | R+1 | Mur (Classification ARCHICAD); Cloison (Classification ARCHICAD) | Non défini |  |  |  |  |  |  |  |  | 0.369552 | 2.5 | 0.0293649 | 0.896381 | 0.896381 | 0.0734122 | 0.0734122 | Material Properties - Component 3, Finition int - Plaque de plâtre, ThermalConductivity: 0.8; Component 3, Finition int - Plaque de plâtre, SpecificHeatCapacity: 1000 J/kg/K; Component 3, Finition int - Plaque de plâtre, MassDensity: 1600 kg/m3; Component 3, Finition int - Plaque de plâtre, Embodied Energy: 1.45 (MJ/kg); Component 3, Finition int - Plaque de plâtre, Embodied Carbon: 0.22 (kgCO₂/kg); Component 3, Finition int - Plaque de plâtre, Name: Finition int - Plaque de plâtre; Component 3, Finition int - Plaque de plâtre, Participates in Collision Detection: no; Component 3: 2 with these values
Cloison Placostil 72/48 | R+1 | Mur (Classification ARCHICAD); Cloison (Classification ARCHICAD) | 35 dB(A) |  |  |  |  |  |  |  |  | 0.211 | 2.5 | 0.0135 | 0.435 | 0.435 | 0.03375 | 0.03375 | Material Properties - Component 3, Finition int - Plaque de plâtre, ThermalConductivity: 0.8; Component 3, Finition int - Plaque de plâtre, SpecificHeatCapacity: 1000 J/kg/K; Component 3, Finition int - Plaque de plâtre, MassDensity: 1600 kg/m3; Component 3, Finition int - Plaque de plâtre, Embodied Energy: 1.45 (MJ/kg); Component 3, Finition int - Plaque de plâtre, Embodied Carbon: 0.22 (kgCO₂/kg); Component 3, Finition int - Plaque de plâtre, Name: Finition int - Plaque de plâtre; Component 3, Finition int - Plaque de plâtre, Participates in Collision Detection: no; Component 3: 2 with these values
Cloison Placostil 72/48 | R+1 | Mur (Classification ARCHICAD); Cloison (Classification ARCHICAD) | 35 dB(A) |  |  |  |  |  |  |  |  | 0.563 | 2.5 | 0.043342 | 1.26305 | 1.26305 | 0.108087 | 0.108087 | Material Properties - Component 3, Finition int - Plaque de plâtre, ThermalConductivity: 0.8; Component 3, Finition int - Plaque de plâtre, SpecificHeatCapacity: 1000 J/kg/K; Component 3, Finition int - Plaque de plâtre, MassDensity: 1600 kg/m3; Component 3, Finition int - Plaque de plâtre, Embodied Energy: 1.45 (MJ/kg); Component 3, Finition int - Plaque de plâtre, Embodied Carbon: 0.22 (kgCO₂/kg); Component 3, Finition int - Plaque de plâtre, Name: Finition int - Plaque de plâtre; Component 3, Finition int - Plaque de plâtre, Participates in Collision Detection: no; Component 3: 2 with these values
Cloison Placostil 72/48 | R+1 | Mur (Classification ARCHICAD); Cloison (Classification ARCHICAD) | 35 dB(A) | 0.8 | 1000 | 1600 | 1.45 (MJ/kg) | 0.22 (kgCO₂/kg) | Finition int - Plaque de plâtre | no | 2 with these values | 0.718 | 2.5 | 0.054569 | 1.77625 | 1.77625 | 0.136422 | 0.136422
Cloison Placostil 72/48 | R+1 | Mur (Classification ARCHICAD); Cloison (Classification ARCHICAD) | 35 dB(A) | 0.8 | 1000 | 1600 | 1.45 (MJ/kg) | 0.22 (kgCO₂/kg) | Finition int - Plaque de plâtre | no | 2 with these values | 0.55 | 2.5 | 0.042549 | 1.33125 | 1.33125 | 0.106373 | 0.106373
Cloison Placostil 72/48 | R+1 | Mur (Classification ARCHICAD); Cloison (Classification ARCHICAD) | 35 dB(A) |  |  |  |  |  |  |  |  | 0.565633 | 2.5 | 0.0411069 | 1.40658 | 1.40658 | 0.102767 | 0.102767 | Material Properties - Component 3, Finition int - Plaque de plâtre, ThermalConductivity: 0.8; Component 3, Finition int - Plaque de plâtre, SpecificHeatCapacity: 1000 J/kg/K; Component 3, Finition int - Plaque de plâtre, MassDensity: 1600 kg/m3; Component 3, Finition int - Plaque de plâtre, Embodied Energy: 1.45 (MJ/kg); Component 3, Finition int - Plaque de plâtre, Embodied Carbon: 0.22 (kgCO₂/kg); Component 3, Finition int - Plaque de plâtre, Name: Finition int - Plaque de plâtre; Component 3, Finition int - Plaque de plâtre, Participates in Collision Detection: no; Component 3: 2 with these values
Cloison Placostil 72/48 | R+1 | Mur (Classification ARCHICAD); Cloison (Classification ARCHICAD) | Non défini | 0.8 | 1000 | 1600 | 1.45 (MJ/kg) | 0.22 (kgCO₂/kg) | Finition int - Plaque de plâtre | no | 2 with these values | 0.279747 | 2.5 | 0.0200507 | 0.683117 | 0.683117 | 0.0501268 | 0.0501268
Cloison Placostil 72/48 | R+1 | Mur (Classification ARCHICAD); Cloison (Classification ARCHICAD) | 35 dB(A) |  |  |  |  |  |  |  |  | 0.714475 | 2.5 | 0.0522901 | 1.79494 | 1.79494 | 0.130725 | 0.130725 | Material Properties - Component 3, Finition int - Plaque de plâtre, ThermalConductivity: 0.8; Component 3, Finition int - Plaque de plâtre, SpecificHeatCapacity: 1000 J/kg/K; Component 3, Finition int - Plaque de plâtre, MassDensity: 1600 kg/m3; Component 3, Finition int - Plaque de plâtre, Embodied Energy: 1.45 (MJ/kg); Component 3, Finition int - Plaque de plâtre, Embodied Carbon: 0.22 (kgCO₂/kg); Component 3, Finition int - Plaque de plâtre, Name: Finition int - Plaque de plâtre; Component 3, Finition int - Plaque de plâtre, Participates in Collision Detection: no; Component 3: 2 with these values
Cloison Placostil 72/48 | R+1 | Mur (Classification ARCHICAD); Cloison (Classification ARCHICAD) | 35 dB(A) | 0.8 | 1000 | 1600 | 1.45 (MJ/kg) | 0.22 (kgCO₂/kg) | Finition int - Plaque de plâtre | no | 2 with these values | 0.513147 | 2.5 | 0.0373489 | 1.22287 | 1.22287 | 0.0933721 | 0.0933721
Cloison Placostil 72/48 | R+1 | Mur (Classification ARCHICAD); Cloison (Classification ARCHICAD) | Non défini |  |  |  |  |  |  |  |  | 0.283208 | 2.5 | 0.0223333 | 0.664267 | 0.664267 | 0.0558332 | 0.0558332 | Material Properties - Component 3, Finition int - Plaque de plâtre, ThermalConductivity: 0.8; Component 3, Finition int - Plaque de plâtre, SpecificHeatCapacity: 1000 J/kg/K; Component 3, Finition int - Plaque de plâtre, MassDensity: 1600 kg/m3; Component 3, Finition int - Plaque de plâtre, Embodied Energy: 1.45 (MJ/kg); Component 3, Finition int - Plaque de plâtre, Embodied Carbon: 0.22 (kgCO₂/kg); Component 3, Finition int - Plaque de plâtre, Name: Finition int - Plaque de plâtre; Component 3, Finition int - Plaque de plâtre, Participates in Collision Detection: no; Component 3: 2 with these values
Cloison Placostil 72/48 | R+1 | Mur (Classification ARCHICAD); Cloison (Classification ARCHICAD) | 35 dB(A) | 0.8 | 1000 | 1600 | 1.45 (MJ/kg) | 0.22 (kgCO₂/kg) | Finition int - Plaque de plâtre | no | 2 with these values | 0.9 | 2.5 | 0.065807 | 2.17375 | 2.17375 | 0.164518 | 0.164518
Cloison Placostil 72/48 | R+1 | Mur (Classification ARCHICAD); Cloison (Classification ARCHICAD) | 35 dB(A) | 0.8 | 1000 | 1600 | 1.45 (MJ/kg) | 0.22 (kgCO₂/kg) | Finition int - Plaque de plâtre | no | 2 with these values | 1.131 | 2.5 | 0.084391 | 2.77375 | 2.77375 | 0.210718 | 0.210718
Cloison Placostil 72/48 | R+1 | Mur (Classification ARCHICAD); Cloison (Classification ARCHICAD) | Non défini | 0.8 | 1000 | 1600 | 1.45 (MJ/kg) | 0.22 (kgCO₂/kg) | Finition int - Plaque de plâtre | no | 2 with these values | 0.224036 | 2.49 | 0.0133126 | 0.465718 | 0.465718 | 0.0331484 | 0.0331484
Cloison Placostil 72/48 | R+1 | Mur (Classification ARCHICAD); Cloison (Classification ARCHICAD) | 35 dB(A) | 0.8 | 1000 | 1600 | 1.45 (MJ/kg) | 0.22 (kgCO₂/kg) | Finition int - Plaque de plâtre | no | 2 with these values | 0.523367 | 2.5 | 0.0411601 | 1.36217 | 1.36217 | 0.1029 | 0.1029
Cloison Placostil 72/48 | R+2 | Mur (Classification ARCHICAD); Cloison (Classification ARCHICAD) | 35 dB(A) | 0.8 | 1000 | 1600 | 1.45 (MJ/kg) | 0.22 (kgCO₂/kg) | Finition int - Plaque de plâtre | no | 2 with these values | 0.32 | 2.5 | 0.023056 | 0.74 | 0.74 | 0.05764 | 0.05764
Cloison Placostil 72/48 | R+2 | Mur (Classification ARCHICAD); Cloison (Classification ARCHICAD) | 35 dB(A) | 0.8 | 1000 | 1600 | 1.45 (MJ/kg) | 0.22 (kgCO₂/kg) | Finition int - Plaque de plâtre | no | 2 with these values | 0.841068 | 2.5 | 0.0614461 | 2.02642 | 2.02642 | 0.153615 | 0.153615
Cloison Placostil 72/48 | R+2 | Mur (Classification ARCHICAD); Cloison (Classification ARCHICAD) | 35 dB(A) | 0.8 | 1000 | 1600 | 1.45 (MJ/kg) | 0.22 (kgCO₂/kg) | Finition int - Plaque de plâtre | no | 2 with these values | 1.011 | 2.5 | 0.074021 | 2.45125 | 2.45125 | 0.185053 | 0.185053
Cloison Placostil 72/48 | R+2 | Mur (Classification ARCHICAD); Cloison (Classification ARCHICAD) | 35 dB(A) |  |  |  |  |  |  |  |  | 0.369552 | 2.5 | 0.0267229 | 0.863881 | 0.863881 | 0.0668072 | 0.0668072 | Material Properties - Component 3, Finition int - Plaque de plâtre, ThermalConductivity: 0.8; Component 3, Finition int - Plaque de plâtre, SpecificHeatCapacity: 1000 J/kg/K; Component 3, Finition int - Plaque de plâtre, MassDensity: 1600 kg/m3; Component 3, Finition int - Plaque de plâtre, Embodied Energy: 1.45 (MJ/kg); Component 3, Finition int - Plaque de plâtre, Embodied Carbon: 0.22 (kgCO₂/kg); Component 3, Finition int - Plaque de plâtre, Name: Finition int - Plaque de plâtre; Component 3, Finition int - Plaque de plâtre, Participates in Collision Detection: no; Component 3: 2 with these values
Cloison Placostil 72/48 | R+2 | Mur (Classification ARCHICAD); Cloison (Classification ARCHICAD) | 35 dB(A) | 0.8 | 1000 | 1600 | 1.45 (MJ/kg) | 0.22 (kgCO₂/kg) | Finition int - Plaque de plâtre | no | 2 with these values | 0.497 | 2.5 | 0.020709 | 0.79125 | 0.79125 | 0.0517725 | 0.0517725
Cloison Placostil 72/48 | R+2 | Mur (Classification ARCHICAD); Cloison (Classification ARCHICAD) | Non défini | 0.8 | 1000 | 1600 | 1.45 (MJ/kg) | 0.22 (kgCO₂/kg) | Finition int - Plaque de plâtre | no | 2 with these values | 0.224036 | 2.49 | 0.0133126 | 0.465718 | 0.465718 | 0.0331484 | 0.0331484
Cloison Placostil 72/48 | R+2 | Mur (Classification ARCHICAD); Cloison (Classification ARCHICAD) | Non défini |  |  |  |  |  |  |  |  | 0.211 | 2.5 | 0.0135 | 0.435 | 0.435 | 0.03375 | 0.03375 | Material Properties - Component 3, Finition int - Plaque de plâtre, ThermalConductivity: 0.8; Component 3, Finition int - Plaque de plâtre, SpecificHeatCapacity: 1000 J/kg/K; Component 3, Finition int - Plaque de plâtre, MassDensity: 1600 kg/m3; Component 3, Finition int - Plaque de plâtre, Embodied Energy: 1.45 (MJ/kg); Component 3, Finition int - Plaque de plâtre, Embodied Carbon: 0.22 (kgCO₂/kg); Component 3, Finition int - Plaque de plâtre, Name: Finition int - Plaque de plâtre; Component 3, Finition int - Plaque de plâtre, Participates in Collision Detection: no; Component 3: 2 with these values
Cloison Placostil 72/48 | R+2 | Mur (Classification ARCHICAD); Cloison (Classification ARCHICAD) | 35 dB(A) | 0.8 | 1000 | 1600 | 1.45 (MJ/kg) | 0.22 (kgCO₂/kg) | Finition int - Plaque de plâtre | no | 2 with these values | 0.718 | 2.5 | 0.051927 | 1.74375 | 1.74375 | 0.129817 | 0.129817
Cloison Placostil 72/48 | R+2 | Mur (Classification ARCHICAD); Cloison (Classification ARCHICAD) | 35 dB(A) | 0.8 | 1000 | 1600 | 1.45 (MJ/kg) | 0.22 (kgCO₂/kg) | Finition int - Plaque de plâtre | no | 2 with these values | 0.65 | 2.5 | 0.0481 | 1.3922 | 1.3922 | 0.115757 | 0.115757
Cloison Placostil 72/48 | R+2 | Mur (Classification ARCHICAD); Cloison (Classification ARCHICAD) | 35 dB(A) | 0.8 | 1000 | 1600 | 1.45 (MJ/kg) | 0.22 (kgCO₂/kg) | Finition int - Plaque de plâtre | no | 2 with these values | 0.538367 | 2.5 | 0.0411601 | 1.36217 | 1.36217 | 0.1029 | 0.1029
Cloison Placostil 72/48 | R+3 | Mur (Classification ARCHICAD); Cloison (Classification ARCHICAD) | 35 dB(A) | 0.8 | 1000 | 1600 | 1.45 (MJ/kg) | 0.22 (kgCO₂/kg) | Finition int - Plaque de plâtre | no | 2 with these values | 0.428609 | 2.5 | 0.0309241 | 0.995274 | 0.995274 | 0.0773103 | 0.0773103
Cloison Placostil 72/48 | R+3 | Mur (Classification ARCHICAD); Cloison (Classification ARCHICAD) | 35 dB(A) |  |  |  |  |  |  |  |  | 0.347 | 2.5 | 0.027527 | 0.82375 | 0.82375 | 0.0688175 | 0.0688175 | Material Properties - Component 3, Finition int - Plaque de plâtre, ThermalConductivity: 0.8; Component 3, Finition int - Plaque de plâtre, SpecificHeatCapacity: 1000 J/kg/K; Component 3, Finition int - Plaque de plâtre, MassDensity: 1600 kg/m3; Component 3, Finition int - Plaque de plâtre, Embodied Energy: 1.45 (MJ/kg); Component 3, Finition int - Plaque de plâtre, Embodied Carbon: 0.22 (kgCO₂/kg); Component 3, Finition int - Plaque de plâtre, Name: Finition int - Plaque de plâtre; Component 3, Finition int - Plaque de plâtre, Participates in Collision Detection: no; Component 3: 2 with these values
Cloison Placostil 72/48 | R+3 | Mur (Classification ARCHICAD); Cloison (Classification ARCHICAD) | 35 dB(A) | 0.8 | 1000 | 1600 | 1.45 (MJ/kg) | 0.22 (kgCO₂/kg) | Finition int - Plaque de plâtre | no | 2 with these values | 0.703652 | 2.5 | 0.0488043 | 1.66663 | 1.66663 | 0.122011 | 0.122011
Cloison Placostil 72/48 | R+3 | Mur (Classification ARCHICAD); Cloison (Classification ARCHICAD) | 35 dB(A) | 0.8 | 1000 | 1600 | 1.45 (MJ/kg) | 0.22 (kgCO₂/kg) | Finition int - Plaque de plâtre | no | 2 with these values | 0.657 | 2.5 | 0.050679 | 1.68375 | 1.68375 | 0.126697 | 0.126697
Cloison Placostil 72/48 | R+4 | Mur (Classification ARCHICAD); Cloison (Classification ARCHICAD) | 35 dB(A) | 0.8 | 1000 | 1600 | 1.45 (MJ/kg) | 0.22 (kgCO₂/kg) | Finition int - Plaque de plâtre | no | 2 with these values | 1.2 | 2.5 | 0.088176 | 2.94 | 2.94 | 0.22044 | 0.22044
Cloison Placostil 72/48 | Rez-de-chaussée | Cloison (Classification ARCHICAD) | Non défini |  |  |  |  |  |  |  |  | 0.563 | 2.5 | 0.043342 | 1.3475 | 1.3475 | 0.108355 | 0.108355 | Material Properties - Component 3, Finition int - Plaque de plâtre, ThermalConductivity: 0.8; Component 3, Finition int - Plaque de plâtre, SpecificHeatCapacity: 1000 J/kg/K; Component 3, Finition int - Plaque de plâtre, MassDensity: 1600 kg/m3; Component 3, Finition int - Plaque de plâtre, Embodied Energy: 1.45 (MJ/kg); Component 3, Finition int - Plaque de plâtre, Embodied Carbon: 0.22 (kgCO₂/kg); Component 3, Finition int - Plaque de plâtre, Name: Finition int - Plaque de plâtre; Component 3, Finition int - Plaque de plâtre, Participates in Collision Detection: no; Component 3: 2 with these values
Cloison Placostil 72/48 | Rez-de-chaussée | Cloison (Classification ARCHICAD) | Non défini |  |  |  |  |  |  |  |  | 0.565633 | 2.5 | 0.0411069 | 1.40658 | 1.40658 | 0.102767 | 0.102767 | Material Properties - Component 3, Finition int - Plaque de plâtre, ThermalConductivity: 0.8; Component 3, Finition int - Plaque de plâtre, SpecificHeatCapacity: 1000 J/kg/K; Component 3, Finition int - Plaque de plâtre, MassDensity: 1600 kg/m3; Component 3, Finition int - Plaque de plâtre, Embodied Energy: 1.45 (MJ/kg); Component 3, Finition int - Plaque de plâtre, Embodied Carbon: 0.22 (kgCO₂/kg); Component 3, Finition int - Plaque de plâtre, Name: Finition int - Plaque de plâtre; Component 3, Finition int - Plaque de plâtre, Participates in Collision Detection: no; Component 3: 2 with these values
Cloison Placostil 72/48 | Rez-de-chaussée | Cloison (Classification ARCHICAD) | Non défini | 0.8 | 1000 | 1600 | 1.45 (MJ/kg) | 0.22 (kgCO₂/kg) | Finition int - Plaque de plâtre | no | 2 with these values | 0.518367 | 2.5 | 0.0396801 | 1.31217 | 1.31217 | 0.0992003 | 0.0992003
Cloison Placostil 72/48 | Rez-de-chaussée | Cloison (Classification ARCHICAD) | Non défini | 0.8 | 1000 | 1600 | 1.45 (MJ/kg) | 0.22 (kgCO₂/kg) | Finition int - Plaque de plâtre | no | 2 with these values | 0.9 | 2.5 | 0.065807 | 2.17375 | 2.17375 | 0.164518 | 0.164518
Cloison Placostil 72/48 | Rez-de-chaussée | Cloison (Classification ARCHICAD) | Non défini | 0.8 | 1000 | 1600 | 1.45 (MJ/kg) | 0.22 (kgCO₂/kg) | Finition int - Plaque de plâtre | no | 2 with these values | 0.52 | 2.5 | 0.040329 | 1.25625 | 1.25625 | 0.100823 | 0.100823
Cloison Placostil 72/48 | Rez-de-chaussée | Cloison (Classification ARCHICAD) | Non défini |  |  |  |  |  |  |  |  | 0.283208 | 2.5 | 0.0223213 | 0.664267 | 0.631765 | 0.0558332 | 0.0558033 | Material Properties - Component 3, Finition int - Plaque de plâtre, ThermalConductivity: 0.8; Component 3, Finition int - Plaque de plâtre, SpecificHeatCapacity: 1000 J/kg/K; Component 3, Finition int - Plaque de plâtre, MassDensity: 1600 kg/m3; Component 3, Finition int - Plaque de plâtre, Embodied Energy: 1.45 (MJ/kg); Component 3, Finition int - Plaque de plâtre, Embodied Carbon: 0.22 (kgCO₂/kg); Component 3, Finition int - Plaque de plâtre, Name: Finition int - Plaque de plâtre; Component 3, Finition int - Plaque de plâtre, Participates in Collision Detection: no; Component 3: 2 with these values
Cloison Placostil 72/48 | Rez-de-chaussée | Cloison (Classification ARCHICAD) | Non défini | 0.8 | 1000 | 1600 | 1.45 (MJ/kg) | 0.22 (kgCO₂/kg) | Finition int - Plaque de plâtre | no | 2 with these values | 0.291633 | 2.5 | 0.0234299 | 0.685334 | 0.685334 | 0.0585747 | 0.0585747
Cloison Placostil 72/48 | Rez-de-chaussée | Cloison (Classification ARCHICAD) | Non défini | 0.8 | 1000 | 1600 | 1.45 (MJ/kg) | 0.22 (kgCO₂/kg) | Finition int - Plaque de plâtre | no | 2 with these values | 1.131 | 2.5 | 0.084391 | 2.77375 | 2.77375 | 0.210718 | 0.210718
Cloison Placostil 72/48 | Rez-de-chaussée | Cloison (Classification ARCHICAD) | Non défini |  |  |  |  |  |  |  |  | 0.211 | 2.5 | 0.0135 | 0.435 | 0.435 | 0.03375 | 0.03375 | Material Properties - Component 3, Finition int - Plaque de plâtre, ThermalConductivity: 0.8; Component 3, Finition int - Plaque de plâtre, SpecificHeatCapacity: 1000 J/kg/K; Component 3, Finition int - Plaque de plâtre, MassDensity: 1600 kg/m3; Component 3, Finition int - Plaque de plâtre, Embodied Energy: 1.45 (MJ/kg); Component 3, Finition int - Plaque de plâtre, Embodied Carbon: 0.22 (kgCO₂/kg); Component 3, Finition int - Plaque de plâtre, Name: Finition int - Plaque de plâtre; Component 3, Finition int - Plaque de plâtre, Participates in Collision Detection: no; Component 3: 2 with these values
Cloison Placostil 72/48 | Rez-de-chaussée | Cloison (Classification ARCHICAD) | Non défini | 0.8 | 1000 | 1600 | 1.45 (MJ/kg) | 0.22 (kgCO₂/kg) | Finition int - Plaque de plâtre | no | 2 with these values | 0.279747 | 2.5 | 0.0200507 | 0.683117 | 0.683117 | 0.0501268 | 0.0501268
Cloison Placostil 72/48 | R+1 | Mur (Classification ARCHICAD); Cloison (Classification ARCHICAD) | 35 dB(A) |  |  |  |  |  |  |  |  | 0.76 | 2.5 | 0.05475 | 1.8675 | 1.8675 | 0.136875 | 0.136875 | Material Properties - Component 3, Finition int - Plaque de plâtre, ThermalConductivity: 0.8; Component 3, Finition int - Plaque de plâtre, SpecificHeatCapacity: 1000 J/kg/K; Component 3, Finition int - Plaque de plâtre, MassDensity: 1600 kg/m3; Component 3, Finition int - Plaque de plâtre, Embodied Energy: 1.45 (MJ/kg); Component 3, Finition int - Plaque de plâtre, Embodied Carbon: 0.22 (kgCO₂/kg); Component 3, Finition int - Plaque de plâtre, Name: Finition int - Plaque de plâtre; Component 3, Finition int - Plaque de plâtre, Participates in Collision Detection: no; Component 3: 2 with these values
Cloison Placostil 72/48 | R+1 | Mur (Classification ARCHICAD); Cloison (Classification ARCHICAD) | 35 dB(A) |  |  |  |  |  |  |  |  | 0.217635 | 2.5 | 0.014784 | 0.527837 | 0.527837 | 0.0369599 | 0.0369599 | Material Properties - Component 3, Finition int - Plaque de plâtre, ThermalConductivity: 0.8; Component 3, Finition int - Plaque de plâtre, SpecificHeatCapacity: 1000 J/kg/K; Component 3, Finition int - Plaque de plâtre, MassDensity: 1600 kg/m3; Component 3, Finition int - Plaque de plâtre, Embodied Energy: 1.45 (MJ/kg); Component 3, Finition int - Plaque de plâtre, Embodied Carbon: 0.22 (kgCO₂/kg); Component 3, Finition int - Plaque de plâtre, Name: Finition int - Plaque de plâtre; Component 3, Finition int - Plaque de plâtre, Participates in Collision Detection: no; Component 3: 2 with these values
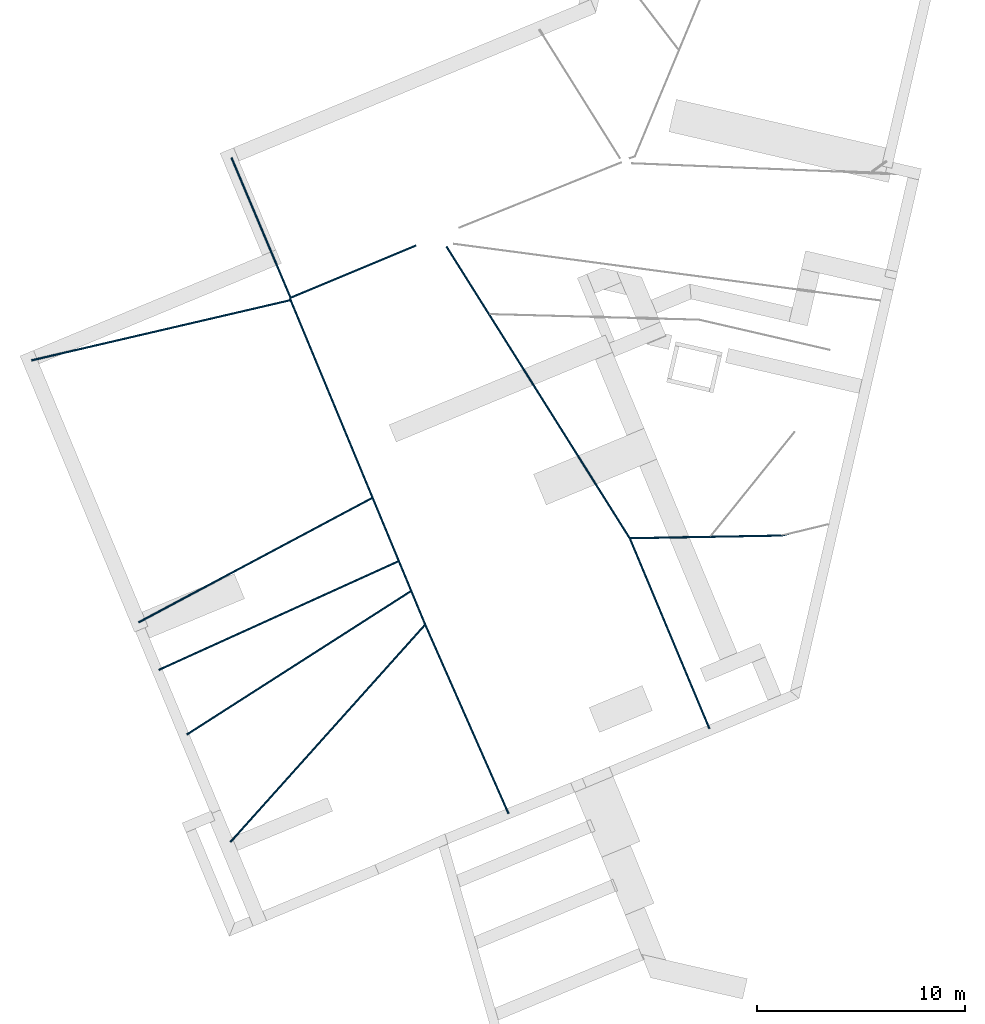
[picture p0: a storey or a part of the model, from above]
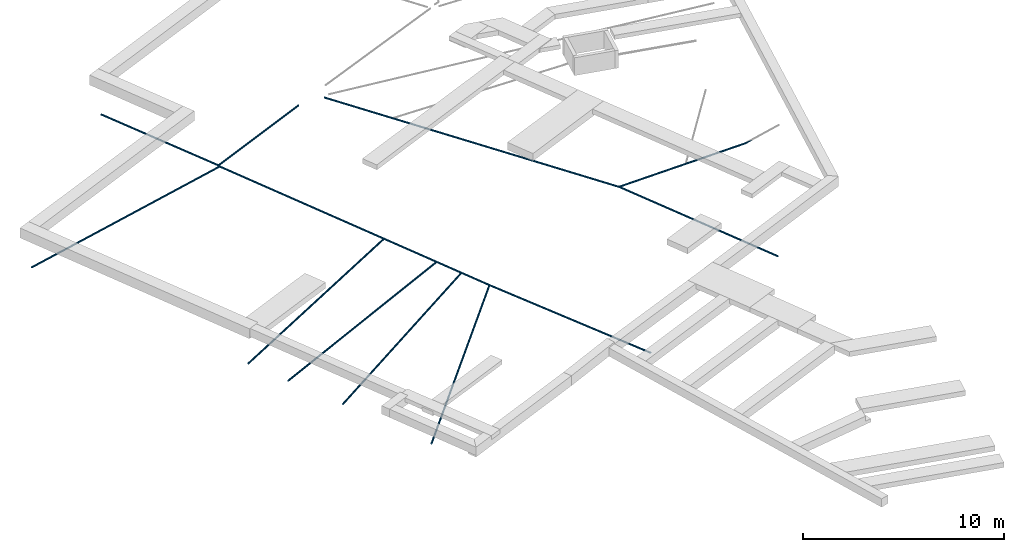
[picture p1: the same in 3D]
Properties of the parts of a building model (IFC2X3), part 15 of 22

# IfcWall: 3 - Cloison Gaine Technique 72mm 74 (154)
Name | In | Classification | AcousticRating | Component 1, Finition int - Plaque de plâtre, ThermalConductivity | Component 1, Finition int - Plaque de plâtre, SpecificHeatCapacity (J/kg/K) | Component 1, Finition int - Plaque de plâtre, MassDensity (kg/m3) | Component 1, Finition int - Plaque de plâtre, Embodied Energy | Component 1, Finition int - Plaque de plâtre, Embodied Carbon | Component 1, Finition int - Plaque de plâtre, Name | Component 1, Finition int - Plaque de plâtre, Participates in Collision Detection | Component 1 | Length (m) | Height (m) | GrossFootprintArea (m2) = NetFootprintArea (m2) | GrossSideArea (m2) | NetSideArea (m2) | GrossVolume (m3) | NetVolume (m3)
Cloison Placostil 72/48 | R+1 | Mur (Classification ARCHICAD); Cloison (Classification ARCHICAD) | 35 dB(A) | 0.8 | 1000 | 1600 | 1.45 (MJ/kg) | 0.22 (kgCO₂/kg) | Finition int - Plaque de plâtre | no | 2 with these values | 0.397 | 2.5 | 0.028057 | 0.97625 | 0.97625 | 0.0701425 | 0.0701425
Cloison Placostil 72/48 | R+1 | Mur (Classification ARCHICAD); Cloison (Classification ARCHICAD) | 35 dB(A) | 0.8 | 1000 | 1600 | 1.45 (MJ/kg) | 0.22 (kgCO₂/kg) | Finition int - Plaque de plâtre | no | 2 with these values | 0.217635 | 2.5 | 0.014784 | 0.527837 | 0.527837 | 0.0369599 | 0.0369599
Cloison Placostil 72/48 | R+1 | Mur (Classification ARCHICAD); Cloison (Classification ARCHICAD) | 35 dB(A) | 0.8 | 1000 | 1600 | 1.45 (MJ/kg) | 0.22 (kgCO₂/kg) | Finition int - Plaque de plâtre | no | 2 with these values | 0.187 | 2.5 | 0.013257 | 0.47625 | 0.47625 | 0.0331425 | 0.0331425
Cloison Placostil 72/48 | R+1 | Mur (Classification ARCHICAD); Cloison (Classification ARCHICAD) | 35 dB(A) |  |  |  |  |  |  |  |  | 0.391 | 2.5 | 0.030735 | 0.99375 | 0.99375 | 0.0768375 | 0.0768375 | Material Properties - Component 3, Finition int - Plaque de plâtre, ThermalConductivity: 0.8; Component 3, Finition int - Plaque de plâtre, SpecificHeatCapacity: 1000 J/kg/K; Component 3, Finition int - Plaque de plâtre, MassDensity: 1600 kg/m3; Component 3, Finition int - Plaque de plâtre, Embodied Energy: 1.45 (MJ/kg); Component 3, Finition int - Plaque de plâtre, Embodied Carbon: 0.22 (kgCO₂/kg); Component 3, Finition int - Plaque de plâtre, Name: Finition int - Plaque de plâtre; Component 3, Finition int - Plaque de plâtre, Participates in Collision Detection: no; Component 3: 2 with these values
Cloison Placostil 72/48 | R+1 | Mur (Classification ARCHICAD); Cloison (Classification ARCHICAD) | 35 dB(A) |  |  |  |  |  |  |  |  | 0.899 | 2.5 | 0.066357 | 2.23125 | 2.23125 | 0.165892 | 0.165892 | Material Properties - Component 3, Finition int - Plaque de plâtre, ThermalConductivity: 0.8; Component 3, Finition int - Plaque de plâtre, SpecificHeatCapacity: 1000 J/kg/K; Component 3, Finition int - Plaque de plâtre, MassDensity: 1600 kg/m3; Component 3, Finition int - Plaque de plâtre, Embodied Energy: 1.45 (MJ/kg); Component 3, Finition int - Plaque de plâtre, Embodied Carbon: 0.22 (kgCO₂/kg); Component 3, Finition int - Plaque de plâtre, Name: Finition int - Plaque de plâtre; Component 3, Finition int - Plaque de plâtre, Participates in Collision Detection: no; Component 3: 2 with these values
Cloison Placostil 72/48 | R+1 | Mur (Classification ARCHICAD); Cloison (Classification ARCHICAD) | 35 dB(A) | 0.8 | 1000 | 1600 | 1.45 (MJ/kg) | 0.22 (kgCO₂/kg) | Finition int - Plaque de plâtre | no | 2 with these values | 0.55 | 2.5 | 0.03921 | 1.3425 | 1.3425 | 0.098025 | 0.098025
Cloison Placostil 72/48 | R+1 | Mur (Classification ARCHICAD); Cloison (Classification ARCHICAD) | 35 dB(A) |  |  |  |  |  |  |  |  | 0.841131 | 2.5 | 0.0594327 | 2.05408 | 2.05408 | 0.148582 | 0.148582 | Material Properties - Component 3, Finition int - Plaque de plâtre, ThermalConductivity: 0.8; Component 3, Finition int - Plaque de plâtre, SpecificHeatCapacity: 1000 J/kg/K; Component 3, Finition int - Plaque de plâtre, MassDensity: 1600 kg/m3; Component 3, Finition int - Plaque de plâtre, Embodied Energy: 1.45 (MJ/kg); Component 3, Finition int - Plaque de plâtre, Embodied Carbon: 0.22 (kgCO₂/kg); Component 3, Finition int - Plaque de plâtre, Name: Finition int - Plaque de plâtre; Component 3, Finition int - Plaque de plâtre, Participates in Collision Detection: no; Component 3: 2 with these values
Cloison Placostil 72/48 | R+1 | Mur (Classification ARCHICAD); Cloison (Classification ARCHICAD) | 35 dB(A) |  |  |  |  |  |  |  |  | 0.295 | 2.5 | 0.021249 | 0.74625 | 0.74625 | 0.0531225 | 0.0531225 | Material Properties - Component 3, Finition int - Plaque de plâtre, ThermalConductivity: 0.8; Component 3, Finition int - Plaque de plâtre, SpecificHeatCapacity: 1000 J/kg/K; Component 3, Finition int - Plaque de plâtre, MassDensity: 1600 kg/m3; Component 3, Finition int - Plaque de plâtre, Embodied Energy: 1.45 (MJ/kg); Component 3, Finition int - Plaque de plâtre, Embodied Carbon: 0.22 (kgCO₂/kg); Component 3, Finition int - Plaque de plâtre, Name: Finition int - Plaque de plâtre; Component 3, Finition int - Plaque de plâtre, Participates in Collision Detection: no; Component 3: 2 with these values
Cloison Placostil 72/48 | R+1 | Mur (Classification ARCHICAD); Cloison (Classification ARCHICAD) | Non défini |  |  |  |  |  |  |  |  | 0.726 | 2.5 | 0.052403 | 1.79875 | 1.79875 | 0.131008 | 0.131008 | Material Properties - Component 3, Finition int - Plaque de plâtre, ThermalConductivity: 0.8; Component 3, Finition int - Plaque de plâtre, SpecificHeatCapacity: 1000 J/kg/K; Component 3, Finition int - Plaque de plâtre, MassDensity: 1600 kg/m3; Component 3, Finition int - Plaque de plâtre, Embodied Energy: 1.45 (MJ/kg); Component 3, Finition int - Plaque de plâtre, Embodied Carbon: 0.22 (kgCO₂/kg); Component 3, Finition int - Plaque de plâtre, Name: Finition int - Plaque de plâtre; Component 3, Finition int - Plaque de plâtre, Participates in Collision Detection: no; Component 3: 2 with these values
Cloison Placostil 72/48 | R+1 | Mur (Classification ARCHICAD); Cloison (Classification ARCHICAD) | 35 dB(A) |  |  |  |  |  |  |  |  | 0.607363 | 2.5 | 0.0454729 | 1.45841 | 1.45841 | 0.113682 | 0.113682 | Material Properties - Component 3, Finition int - Plaque de plâtre, ThermalConductivity: 0.8; Component 3, Finition int - Plaque de plâtre, SpecificHeatCapacity: 1000 J/kg/K; Component 3, Finition int - Plaque de plâtre, MassDensity: 1600 kg/m3; Component 3, Finition int - Plaque de plâtre, Embodied Energy: 1.45 (MJ/kg); Component 3, Finition int - Plaque de plâtre, Embodied Carbon: 0.22 (kgCO₂/kg); Component 3, Finition int - Plaque de plâtre, Name: Finition int - Plaque de plâtre; Component 3, Finition int - Plaque de plâtre, Participates in Collision Detection: no; Component 3: 2 with these values
Cloison Placostil 72/48 | R+1 | Mur (Classification ARCHICAD); Cloison (Classification ARCHICAD) | 35 dB(A) | 0.8 | 1000 | 1600 | 1.45 (MJ/kg) | 0.22 (kgCO₂/kg) | Finition int - Plaque de plâtre | no | 2 with these values | 0.526 | 2.5 | 0.040985 | 1.35625 | 1.35625 | 0.102463 | 0.102463
Cloison Placostil 72/48 | R+1 | Mur (Classification ARCHICAD); Cloison (Classification ARCHICAD) | 35 dB(A) |  |  |  |  |  |  |  |  | 0.486 | 2.5 | 0.034643 | 1.19875 | 1.19875 | 0.0866075 | 0.0866075 | Material Properties - Component 3, Finition int - Plaque de plâtre, ThermalConductivity: 0.8; Component 3, Finition int - Plaque de plâtre, SpecificHeatCapacity: 1000 J/kg/K; Component 3, Finition int - Plaque de plâtre, MassDensity: 1600 kg/m3; Component 3, Finition int - Plaque de plâtre, Embodied Energy: 1.45 (MJ/kg); Component 3, Finition int - Plaque de plâtre, Embodied Carbon: 0.22 (kgCO₂/kg); Component 3, Finition int - Plaque de plâtre, Name: Finition int - Plaque de plâtre; Component 3, Finition int - Plaque de plâtre, Participates in Collision Detection: no; Component 3: 2 with these values
Cloison Placostil 72/48 | R+1 | Mur (Classification ARCHICAD); Cloison (Classification ARCHICAD) | 35 dB(A) |  |  |  |  |  |  |  |  | 0.607363 | 2.47 | 0.0434549 | 1.46808 | 1.46808 | 0.107334 | 0.107334 | Material Properties - Component 3, Finition int - Plaque de plâtre, ThermalConductivity: 0.8; Component 3, Finition int - Plaque de plâtre, SpecificHeatCapacity: 1000 J/kg/K; Component 3, Finition int - Plaque de plâtre, MassDensity: 1600 kg/m3; Component 3, Finition int - Plaque de plâtre, Embodied Energy: 1.45 (MJ/kg); Component 3, Finition int - Plaque de plâtre, Embodied Carbon: 0.22 (kgCO₂/kg); Component 3, Finition int - Plaque de plâtre, Name: Finition int - Plaque de plâtre; Component 3, Finition int - Plaque de plâtre, Participates in Collision Detection: no; Component 3: 2 with these values
Cloison Placostil 72/48 | R+1 | Mur (Classification ARCHICAD); Cloison (Classification ARCHICAD) | 35 dB(A) |  |  |  |  |  |  |  |  | 0.726 | 2.5 | 0.053143 | 1.82375 | 1.82375 | 0.132858 | 0.132858 | Material Properties - Component 3, Finition int - Plaque de plâtre, ThermalConductivity: 0.8; Component 3, Finition int - Plaque de plâtre, SpecificHeatCapacity: 1000 J/kg/K; Component 3, Finition int - Plaque de plâtre, MassDensity: 1600 kg/m3; Component 3, Finition int - Plaque de plâtre, Embodied Energy: 1.45 (MJ/kg); Component 3, Finition int - Plaque de plâtre, Embodied Carbon: 0.22 (kgCO₂/kg); Component 3, Finition int - Plaque de plâtre, Name: Finition int - Plaque de plâtre; Component 3, Finition int - Plaque de plâtre, Participates in Collision Detection: no; Component 3: 2 with these values
Cloison Placostil 72/48 | R+1 | Mur (Classification ARCHICAD); Cloison (Classification ARCHICAD) | Non défini | 0.8 | 1000 | 1600 | 1.45 (MJ/kg) | 0.22 (kgCO₂/kg) | Finition int - Plaque de plâtre | no | 2 with these values | 0.187 | 2.49 | 0.005169 | 0.265185 | 0.265185 | 0.0128708 | 0.0128708
Cloison Placostil 72/48 | R+1 | Mur (Classification ARCHICAD); Cloison (Classification ARCHICAD) | 35 dB(A) | 0.8 | 1000 | 1600 | 1.45 (MJ/kg) | 0.22 (kgCO₂/kg) | Finition int - Plaque de plâtre | no | 2 with these values | 0.267633 | 2.5 | 0.0217499 | 0.685334 | 0.685334 | 0.0543747 | 0.0543747
Cloison Placostil 72/48 | R+1 | Mur (Classification ARCHICAD); Cloison (Classification ARCHICAD) | 35 dB(A) | 0.8 | 1000 | 1600 | 1.45 (MJ/kg) | 0.22 (kgCO₂/kg) | Finition int - Plaque de plâtre | no | 2 with these values | 0.262 | 2.5 | 0.018067 | 0.63875 | 0.63875 | 0.0451675 | 0.0451675
Cloison Placostil 72/48 | R+1 | Mur (Classification ARCHICAD); Cloison (Classification ARCHICAD) | Non défini | 0.8 | 1000 | 1600 | 1.45 (MJ/kg) | 0.22 (kgCO₂/kg) | Finition int - Plaque de plâtre | no | 2 with these values | 0.186598 | 2.5 | 0.0131112 | 0.450245 | 0.450245 | 0.0327781 | 0.0327781
Cloison Placostil 72/48 | R+1 | Mur (Classification ARCHICAD); Cloison (Classification ARCHICAD) | 35 dB(A) | 0.8 | 1000 | 1600 | 1.45 (MJ/kg) | 0.22 (kgCO₂/kg) | Finition int - Plaque de plâtre | no | 2 with these values | 0.647 | 2.5 | 0.048575 | 1.57375 | 1.57375 | 0.121438 | 0.121438
Cloison Placostil 72/48 | R+2 | Mur (Classification ARCHICAD); Cloison (Classification ARCHICAD) | Non défini | 0.8 | 1000 | 1600 | 1.45 (MJ/kg) | 0.22 (kgCO₂/kg) | Finition int - Plaque de plâtre | no | 2 with these values | 0.187 | 2.49 | 0.005169 | 0.265185 | 0.265185 | 0.0128708 | 0.0128708
Cloison Placostil 72/48 | R+2 | Mur (Classification ARCHICAD); Cloison (Classification ARCHICAD) | 35 dB(A) | 0.8 | 1000 | 1600 | 1.45 (MJ/kg) | 0.22 (kgCO₂/kg) | Finition int - Plaque de plâtre | no | 2 with these values | 0.262 | 2.5 | 0.018067 | 0.63875 | 0.63875 | 0.0451675 | 0.0451675
Cloison Placostil 72/48 | R+2 | Mur (Classification ARCHICAD); Cloison (Classification ARCHICAD) | Non défini | 0.8 | 1000 | 1600 | 1.45 (MJ/kg) | 0.22 (kgCO₂/kg) | Finition int - Plaque de plâtre | no | 2 with these values | 0.186598 | 2.5 | 0.0131112 | 0.450245 | 0.450245 | 0.0327781 | 0.0327781
Cloison Placostil 72/48 | R+2 | Mur (Classification ARCHICAD); Cloison (Classification ARCHICAD) | 35 dB(A) |  |  |  |  |  |  |  |  | 0.413 | 2.5 | 0.021893 | 0.78985 | 0.78985 | 0.0536561 | 0.0536561 | Material Properties - Component 3, Finition int - Plaque de plâtre, ThermalConductivity: 0.8; Component 3, Finition int - Plaque de plâtre, SpecificHeatCapacity: 1000 J/kg/K; Component 3, Finition int - Plaque de plâtre, MassDensity: 1600 kg/m3; Component 3, Finition int - Plaque de plâtre, Embodied Energy: 1.45 (MJ/kg); Component 3, Finition int - Plaque de plâtre, Embodied Carbon: 0.22 (kgCO₂/kg); Component 3, Finition int - Plaque de plâtre, Name: Finition int - Plaque de plâtre; Component 3, Finition int - Plaque de plâtre, Participates in Collision Detection: no; Component 3: 2 with these values
Cloison Placostil 72/48 | R+2 | Mur (Classification ARCHICAD); Cloison (Classification ARCHICAD) | 35 dB(A) | 0.8 | 1000 | 1600 | 1.45 (MJ/kg) | 0.22 (kgCO₂/kg) | Finition int - Plaque de plâtre | no | 2 with these values | 0.583363 | 2.5 | 0.0431689 | 1.45841 | 1.45841 | 0.107922 | 0.107922
Cloison Placostil 72/48 | R+2 | Mur (Classification ARCHICAD); Cloison (Classification ARCHICAD) | 35 dB(A) |  |  |  |  |  |  |  |  | 0.726 | 2.5 | 0.055785 | 1.85625 | 1.85625 | 0.139463 | 0.139463 | Material Properties - Component 3, Finition int - Plaque de plâtre, ThermalConductivity: 0.8; Component 3, Finition int - Plaque de plâtre, SpecificHeatCapacity: 1000 J/kg/K; Component 3, Finition int - Plaque de plâtre, MassDensity: 1600 kg/m3; Component 3, Finition int - Plaque de plâtre, Embodied Energy: 1.45 (MJ/kg); Component 3, Finition int - Plaque de plâtre, Embodied Carbon: 0.22 (kgCO₂/kg); Component 3, Finition int - Plaque de plâtre, Name: Finition int - Plaque de plâtre; Component 3, Finition int - Plaque de plâtre, Participates in Collision Detection: no; Component 3: 2 with these values
Cloison Placostil 72/48 | R+2 | Mur (Classification ARCHICAD); Cloison (Classification ARCHICAD) | Non défini |  |  |  |  |  |  |  |  | 0.55 | 2.5 | 0.043173 | 1.39125 | 1.39125 | 0.107933 | 0.107933 | Material Properties - Component 3, Finition int - Plaque de plâtre, ThermalConductivity: 0.8; Component 3, Finition int - Plaque de plâtre, SpecificHeatCapacity: 1000 J/kg/K; Component 3, Finition int - Plaque de plâtre, MassDensity: 1600 kg/m3; Component 3, Finition int - Plaque de plâtre, Embodied Energy: 1.45 (MJ/kg); Component 3, Finition int - Plaque de plâtre, Embodied Carbon: 0.22 (kgCO₂/kg); Component 3, Finition int - Plaque de plâtre, Name: Finition int - Plaque de plâtre; Component 3, Finition int - Plaque de plâtre, Participates in Collision Detection: no; Component 3: 2 with these values
Cloison Placostil 72/48 | R+2 | Mur (Classification ARCHICAD); Cloison (Classification ARCHICAD) | Non défini |  |  |  |  |  |  |  |  | 0.76 | 2.5 | 0.057392 | 1.9 | 1.9 | 0.14348 | 0.14348 | Material Properties - Component 3, Finition int - Plaque de plâtre, ThermalConductivity: 0.8; Component 3, Finition int - Plaque de plâtre, SpecificHeatCapacity: 1000 J/kg/K; Component 3, Finition int - Plaque de plâtre, MassDensity: 1600 kg/m3; Component 3, Finition int - Plaque de plâtre, Embodied Energy: 1.45 (MJ/kg); Component 3, Finition int - Plaque de plâtre, Embodied Carbon: 0.22 (kgCO₂/kg); Component 3, Finition int - Plaque de plâtre, Name: Finition int - Plaque de plâtre; Component 3, Finition int - Plaque de plâtre, Participates in Collision Detection: no; Component 3: 2 with these values
Cloison Placostil 72/48 | R+2 | Mur (Classification ARCHICAD); Cloison (Classification ARCHICAD) | Non défini |  |  |  |  |  |  |  |  | 0.726 | 2.5 | 0.052403 | 1.79875 | 1.79875 | 0.131008 | 0.131008 | Material Properties - Component 3, Finition int - Plaque de plâtre, ThermalConductivity: 0.8; Component 3, Finition int - Plaque de plâtre, SpecificHeatCapacity: 1000 J/kg/K; Component 3, Finition int - Plaque de plâtre, MassDensity: 1600 kg/m3; Component 3, Finition int - Plaque de plâtre, Embodied Energy: 1.45 (MJ/kg); Component 3, Finition int - Plaque de plâtre, Embodied Carbon: 0.22 (kgCO₂/kg); Component 3, Finition int - Plaque de plâtre, Name: Finition int - Plaque de plâtre; Component 3, Finition int - Plaque de plâtre, Participates in Collision Detection: no; Component 3: 2 with these values
Cloison Placostil 72/48 | R+2 | Mur (Classification ARCHICAD); Cloison (Classification ARCHICAD) | 35 dB(A) | 0.8 | 1000 | 1600 | 1.45 (MJ/kg) | 0.22 (kgCO₂/kg) | Finition int - Plaque de plâtre | no | 2 with these values | 0.267633 | 2.5 | 0.0217499 | 0.685334 | 0.685334 | 0.0543747 | 0.0543747
Cloison Placostil 72/48 | R+2 | Mur (Classification ARCHICAD); Cloison (Classification ARCHICAD) | 35 dB(A) |  |  |  |  |  |  |  |  | 0.899 | 2.5 | 0.066357 | 2.23125 | 2.23125 | 0.165892 | 0.165892 | Material Properties - Component 3, Finition int - Plaque de plâtre, ThermalConductivity: 0.8; Component 3, Finition int - Plaque de plâtre, SpecificHeatCapacity: 1000 J/kg/K; Component 3, Finition int - Plaque de plâtre, MassDensity: 1600 kg/m3; Component 3, Finition int - Plaque de plâtre, Embodied Energy: 1.45 (MJ/kg); Component 3, Finition int - Plaque de plâtre, Embodied Carbon: 0.22 (kgCO₂/kg); Component 3, Finition int - Plaque de plâtre, Name: Finition int - Plaque de plâtre; Component 3, Finition int - Plaque de plâtre, Participates in Collision Detection: no; Component 3: 2 with these values
Cloison Placostil 72/48 | R+2 | Mur (Classification ARCHICAD); Cloison (Classification ARCHICAD) | 35 dB(A) |  |  |  |  |  |  |  |  | 0.295 | 2.5 | 0.021249 | 0.74625 | 0.74625 | 0.0531225 | 0.0531225 | Material Properties - Component 3, Finition int - Plaque de plâtre, ThermalConductivity: 0.8; Component 3, Finition int - Plaque de plâtre, SpecificHeatCapacity: 1000 J/kg/K; Component 3, Finition int - Plaque de plâtre, MassDensity: 1600 kg/m3; Component 3, Finition int - Plaque de plâtre, Embodied Energy: 1.45 (MJ/kg); Component 3, Finition int - Plaque de plâtre, Embodied Carbon: 0.22 (kgCO₂/kg); Component 3, Finition int - Plaque de plâtre, Name: Finition int - Plaque de plâtre; Component 3, Finition int - Plaque de plâtre, Participates in Collision Detection: no; Component 3: 2 with these values
Cloison Placostil 72/48 | R+2 | Mur (Classification ARCHICAD); Cloison (Classification ARCHICAD) | 35 dB(A) | 0.8 | 1000 | 1600 | 1.45 (MJ/kg) | 0.22 (kgCO₂/kg) | Finition int - Plaque de plâtre | no | 2 with these values | 0.647 | 2.5 | 0.048575 | 1.57375 | 1.57375 | 0.121438 | 0.121438
Cloison Placostil 72/48 | R+3 | Mur (Classification ARCHICAD); Cloison (Classification ARCHICAD) | 35 dB(A) | 0.8 | 1000 | 1600 | 1.45 (MJ/kg) | 0.22 (kgCO₂/kg) | Finition int - Plaque de plâtre | no | 2 with these values | 0.535574 | 2.5 | 0.0415774 | 1.35518 | 1.35518 | 0.103944 | 0.103944
Cloison Placostil 72/48 | R+3 | Mur (Classification ARCHICAD); Cloison (Classification ARCHICAD) | 35 dB(A) | 0.8 | 1000 | 1600 | 1.45 (MJ/kg) | 0.22 (kgCO₂/kg) | Finition int - Plaque de plâtre | no | 2 with these values | 0.565 | 2.5 | 0.03461 | 1.4125 | 1.4125 | 0.086525 | 0.086525
Cloison Placostil 72/48 | R+3 | Mur (Classification ARCHICAD); Cloison (Classification ARCHICAD) | 35 dB(A) | 0.8 | 1000 | 1600 | 1.45 (MJ/kg) | 0.22 (kgCO₂/kg) | Finition int - Plaque de plâtre | no | 2 with these values | 0.262 | 2.5 | 0.018067 | 0.63875 | 0.63875 | 0.0451675 | 0.0451675
Cloison Placostil 72/48 | R+3 | Mur (Classification ARCHICAD); Cloison (Classification ARCHICAD) | 35 dB(A) | 0.8 | 1000 | 1600 | 1.45 (MJ/kg) | 0.22 (kgCO₂/kg) | Finition int - Plaque de plâtre | no | 2 with these values | 0.653263 | 2.5 | 0.0463965 | 1.55691 | 1.55691 | 0.115991 | 0.115991
Cloison Placostil 72/48 | R+3 | Mur (Classification ARCHICAD); Cloison (Classification ARCHICAD) | 35 dB(A) | 0.8 | 1000 | 1600 | 1.45 (MJ/kg) | 0.22 (kgCO₂/kg) | Finition int - Plaque de plâtre | no | 2 with these values | 0.223598 | 2.5 | 0.0165462 | 0.558995 | 0.558995 | 0.0413656 | 0.0413656
Cloison Placostil 72/48 | R+3 | Mur (Classification ARCHICAD); Cloison (Classification ARCHICAD) | 35 dB(A) | 0.8 | 1000 | 1600 | 1.45 (MJ/kg) | 0.22 (kgCO₂/kg) | Finition int - Plaque de plâtre | no | 2 with these values | 0.647 | 2.5 | 0.048575 | 1.57375 | 1.57375 | 0.121438 | 0.121438
Cloison Placostil 72/48 | R+4 | Mur (Classification ARCHICAD); Cloison (Classification ARCHICAD) | 35 dB(A) |  |  |  |  |  |  |  |  | 0.437844 | 2.48 | 0.0343454 | 1.10197 | 1.10197 | 0.0851766 | 0.0851766 | Material Properties - Component 3, Finition int - Plaque de plâtre, ThermalConductivity: 0.8; Component 3, Finition int - Plaque de plâtre, SpecificHeatCapacity: 1000 J/kg/K; Component 3, Finition int - Plaque de plâtre, MassDensity: 1600 kg/m3; Component 3, Finition int - Plaque de plâtre, Embodied Energy: 1.45 (MJ/kg); Component 3, Finition int - Plaque de plâtre, Embodied Carbon: 0.22 (kgCO₂/kg); Component 3, Finition int - Plaque de plâtre, Name: Finition int - Plaque de plâtre; Component 3, Finition int - Plaque de plâtre, Participates in Collision Detection: no; Component 3: 2 with these values
Cloison Placostil 72/48 | R+4 | Mur (Classification ARCHICAD); Cloison (Classification ARCHICAD) | 35 dB(A) | 0.8 | 1000 | 1600 | 1.45 (MJ/kg) | 0.22 (kgCO₂/kg) | Finition int - Plaque de plâtre | no | 2 with these values | 0.64943 | 2.5 | 0.0467368 | 1.60732 | 1.60732 | 0.116842 | 0.116842
Cloison Placostil 72/48 | Rez-de-chaussée | Cloison (Classification ARCHICAD) | Non défini | 0.8 | 1000 | 1600 | 1.45 (MJ/kg) | 0.22 (kgCO₂/kg) | Finition int - Plaque de plâtre | no | 2 with these values | 0.272 | 2.5 | 0.018807 | 0.66375 | 0.66375 | 0.0470175 | 0.0470175
Cloison Placostil 72/48 | Rez-de-chaussée | Cloison (Classification ARCHICAD) | Non défini | 0.8 | 1000 | 1600 | 1.45 (MJ/kg) | 0.22 (kgCO₂/kg) | Finition int - Plaque de plâtre | no | 2 with these values | 0.186598 | 2.5 | 0.0131112 | 0.450245 | 0.450245 | 0.0327781 | 0.0327781
Cloison Placostil 72/48 | Rez-de-chaussée | Cloison (Classification ARCHICAD) | Non défini | 0.8 | 1000 | 1600 | 1.45 (MJ/kg) | 0.22 (kgCO₂/kg) | Finition int - Plaque de plâtre | no | 2 with these values | 0.647 | 2.5 | 0.048575 | 1.57375 | 1.57375 | 0.121438 | 0.121438
Cloison Placostil 72/48 | Rez-de-chaussée | Cloison (Classification ARCHICAD) | Non défini | 0.8 | 1000 | 1600 | 1.45 (MJ/kg) | 0.22 (kgCO₂/kg) | Finition int - Plaque de plâtre | no | 2 with these values | 0.187 | 2.5 | 0.015899 | 0.50875 | 0.50875 | 0.0397475 | 0.0397475
Cloison Placostil 72/48 | Rez-de-chaussée | Cloison (Classification ARCHICAD) | Non défini |  |  |  |  |  |  |  |  | 0.841131 | 2.5 | 0.0594327 | 2.05408 | 2.05408 | 0.148582 | 0.148582 | Material Properties - Component 3, Finition int - Plaque de plâtre, ThermalConductivity: 0.8; Component 3, Finition int - Plaque de plâtre, SpecificHeatCapacity: 1000 J/kg/K; Component 3, Finition int - Plaque de plâtre, MassDensity: 1600 kg/m3; Component 3, Finition int - Plaque de plâtre, Embodied Energy: 1.45 (MJ/kg); Component 3, Finition int - Plaque de plâtre, Embodied Carbon: 0.22 (kgCO₂/kg); Component 3, Finition int - Plaque de plâtre, Name: Finition int - Plaque de plâtre; Component 3, Finition int - Plaque de plâtre, Participates in Collision Detection: no; Component 3: 2 with these values
Cloison Placostil 72/48 | Rez-de-chaussée | Cloison (Classification ARCHICAD) | Non défini |  |  |  |  |  |  |  |  | 0.391137 | 2.5 | 0.0307451 | 0.994091 | 0.994091 | 0.0768628 | 0.0768628 | Material Properties - Component 3, Finition int - Plaque de plâtre, ThermalConductivity: 0.8; Component 3, Finition int - Plaque de plâtre, SpecificHeatCapacity: 1000 J/kg/K; Component 3, Finition int - Plaque de plâtre, MassDensity: 1600 kg/m3; Component 3, Finition int - Plaque de plâtre, Embodied Energy: 1.45 (MJ/kg); Component 3, Finition int - Plaque de plâtre, Embodied Carbon: 0.22 (kgCO₂/kg); Component 3, Finition int - Plaque de plâtre, Name: Finition int - Plaque de plâtre; Component 3, Finition int - Plaque de plâtre, Participates in Collision Detection: no; Component 3: 2 with these values
Cloison Placostil 72/48 | Rez-de-chaussée | Cloison (Classification ARCHICAD) | Non défini | 0.8 | 1000 | 1600 | 1.45 (MJ/kg) | 0.22 (kgCO₂/kg) | Finition int - Plaque de plâtre | no | 2 with these values | 0.728 | 2.5 | 0.051927 | 1.74375 | 1.74375 | 0.129818 | 0.129818
Cloison Placostil 72/48 | Rez-de-chaussée | Cloison (Classification ARCHICAD) | Non défini | 0.8 | 1000 | 1600 | 1.45 (MJ/kg) | 0.22 (kgCO₂/kg) | Finition int - Plaque de plâtre | no | 2 with these values | 0.397 | 2.5 | 0.020709 | 0.79125 | 0.79125 | 0.0517725 | 0.0517725
Cloison Placostil 72/48 | Rez-de-chaussée | Cloison (Classification ARCHICAD) | Non défini |  |  |  |  |  |  |  |  | 0.295 | 2.5 | 0.021249 | 0.74625 | 0.74625 | 0.0531225 | 0.0531225 | Material Properties - Component 3, Finition int - Plaque de plâtre, ThermalConductivity: 0.8; Component 3, Finition int - Plaque de plâtre, SpecificHeatCapacity: 1000 J/kg/K; Component 3, Finition int - Plaque de plâtre, MassDensity: 1600 kg/m3; Component 3, Finition int - Plaque de plâtre, Embodied Energy: 1.45 (MJ/kg); Component 3, Finition int - Plaque de plâtre, Embodied Carbon: 0.22 (kgCO₂/kg); Component 3, Finition int - Plaque de plâtre, Name: Finition int - Plaque de plâtre; Component 3, Finition int - Plaque de plâtre, Participates in Collision Detection: no; Component 3: 2 with these values
Cloison Placostil 72/48 | Rez-de-chaussée | Cloison (Classification ARCHICAD) | Non défini |  |  |  |  |  |  |  |  | 0.899 | 2.5 | 0.066357 | 2.23125 | 2.23125 | 0.165892 | 0.165892 | Material Properties - Component 3, Finition int - Plaque de plâtre, ThermalConductivity: 0.8; Component 3, Finition int - Plaque de plâtre, SpecificHeatCapacity: 1000 J/kg/K; Component 3, Finition int - Plaque de plâtre, MassDensity: 1600 kg/m3; Component 3, Finition int - Plaque de plâtre, Embodied Energy: 1.45 (MJ/kg); Component 3, Finition int - Plaque de plâtre, Embodied Carbon: 0.22 (kgCO₂/kg); Component 3, Finition int - Plaque de plâtre, Name: Finition int - Plaque de plâtre; Component 3, Finition int - Plaque de plâtre, Participates in Collision Detection: no; Component 3: 2 with these values
Cloison Placostil 72/48 | Rez-de-chaussée | Cloison (Classification ARCHICAD) | Non défini |  |  |  |  |  |  |  |  | 0.607363 | 2.5 | 0.0454729 | 1.45841 | 1.45841 | 0.113682 | 0.113682 | Material Properties - Component 3, Finition int - Plaque de plâtre, ThermalConductivity: 0.8; Component 3, Finition int - Plaque de plâtre, SpecificHeatCapacity: 1000 J/kg/K; Component 3, Finition int - Plaque de plâtre, MassDensity: 1600 kg/m3; Component 3, Finition int - Plaque de plâtre, Embodied Energy: 1.45 (MJ/kg); Component 3, Finition int - Plaque de plâtre, Embodied Carbon: 0.22 (kgCO₂/kg); Component 3, Finition int - Plaque de plâtre, Name: Finition int - Plaque de plâtre; Component 3, Finition int - Plaque de plâtre, Participates in Collision Detection: no; Component 3: 2 with these values
Cloison Placostil 72/48 | Rez-de-chaussée | Cloison (Classification ARCHICAD) | Non défini |  |  |  |  |  |  |  |  | 0.486 | 2.5 | 0.034643 | 1.19875 | 1.19875 | 0.0866075 | 0.0866075 | Material Properties - Component 3, Finition int - Plaque de plâtre, ThermalConductivity: 0.8; Component 3, Finition int - Plaque de plâtre, SpecificHeatCapacity: 1000 J/kg/K; Component 3, Finition int - Plaque de plâtre, MassDensity: 1600 kg/m3; Component 3, Finition int - Plaque de plâtre, Embodied Energy: 1.45 (MJ/kg); Component 3, Finition int - Plaque de plâtre, Embodied Carbon: 0.22 (kgCO₂/kg); Component 3, Finition int - Plaque de plâtre, Name: Finition int - Plaque de plâtre; Component 3, Finition int - Plaque de plâtre, Participates in Collision Detection: no; Component 3: 2 with these values
Cloison Placostil 72/48 | Rez-de-chaussée | Cloison (Classification ARCHICAD) | Non défini | 0.8 | 1000 | 1600 | 1.45 (MJ/kg) | 0.22 (kgCO₂/kg) | Finition int - Plaque de plâtre | no | 2 with these values | 0.541 | 2.5 | 0.040985 | 1.35625 | 1.35625 | 0.102463 | 0.102463
Cloison Placostil 72/48 | Rez-de-chaussée | Cloison (Classification ARCHICAD) | Non défini |  |  |  |  |  |  |  |  | 0.597363 | 2.5 | 0.0427149 | 1.46091 | 1.46091 | 0.106787 | 0.106787 | Material Properties - Component 3, Finition int - Plaque de plâtre, ThermalConductivity: 0.8; Component 3, Finition int - Plaque de plâtre, SpecificHeatCapacity: 1000 J/kg/K; Component 3, Finition int - Plaque de plâtre, MassDensity: 1600 kg/m3; Component 3, Finition int - Plaque de plâtre, Embodied Energy: 1.45 (MJ/kg); Component 3, Finition int - Plaque de plâtre, Embodied Carbon: 0.22 (kgCO₂/kg); Component 3, Finition int - Plaque de plâtre, Name: Finition int - Plaque de plâtre; Component 3, Finition int - Plaque de plâtre, Participates in Collision Detection: no; Component 3: 2 with these values
Cloison Placostil 72/48 | Rez-de-chaussée | Cloison (Classification ARCHICAD) | Non défini | 0.8 | 1000 | 1600 | 1.45 (MJ/kg) | 0.22 (kgCO₂/kg) | Finition int - Plaque de plâtre | no | 2 with these values | 0.192 | 2.5 | 0.013627 | 0.48875 | 0.48875 | 0.0340675 | 0.0340675
Cloison Placostil 72/48 | Rez-de-chaussée | Cloison (Classification ARCHICAD) | Non défini | 0.8 | 1000 | 1600 | 1.45 (MJ/kg) | 0.22 (kgCO₂/kg) | Finition int - Plaque de plâtre | no | 2 with these values | 0.464918 | 2.5 | 0.0337069 | 1.14605 | 1.14605 | 0.0842674 | 0.0842674
Cloison Placostil 72/48 | Rez-de-chaussée | Cloison (Classification ARCHICAD) | Non défini | 0.8 | 1000 | 1600 | 1.45 (MJ/kg) | 0.22 (kgCO₂/kg) | Finition int - Plaque de plâtre | no | 2 with these values | 0.199 | 2.5 | 0.015466 | 0.5225 | 0.5225 | 0.038665 | 0.038665
Cloison Placostil 72/48 | Rez-de-chaussée | Cloison (Classification ARCHICAD) | Non défini | 0.8 | 1000 | 1600 | 1.45 (MJ/kg) | 0.22 (kgCO₂/kg) | Finition int - Plaque de plâtre | no | 2 with these values | 0.55 | 2.5 | 0.03921 | 1.3425 | 1.3425 | 0.098025 | 0.098025
Cloison Placostil 72/48 | Rez-de-chaussée | Cloison (Classification ARCHICAD) | Non défini |  |  |  |  |  |  |  |  | 0.577057 | 2.5 | 0.0446472 | 1.41946 | 1.41946 | 0.111105 | 0.111105 | Material Properties - Component 3, Finition int - Plaque de plâtre, ThermalConductivity: 0.8; Component 3, Finition int - Plaque de plâtre, SpecificHeatCapacity: 1000 J/kg/K; Component 3, Finition int - Plaque de plâtre, MassDensity: 1600 kg/m3; Component 3, Finition int - Plaque de plâtre, Embodied Energy: 1.45 (MJ/kg); Component 3, Finition int - Plaque de plâtre, Embodied Carbon: 0.22 (kgCO₂/kg); Component 3, Finition int - Plaque de plâtre, Name: Finition int - Plaque de plâtre; Component 3, Finition int - Plaque de plâtre, Participates in Collision Detection: no; Component 3: 2 with these values
Cloison Placostil 72/48 | Rez-de-chaussée | Cloison (Classification ARCHICAD) | Non défini |  |  |  |  |  |  |  |  | 0.236 | 2.5 | 0.016883 | 0.59875 | 0.59875 | 0.0422075 | 0.0422075 | Material Properties - Component 3, Finition int - Plaque de plâtre, ThermalConductivity: 0.8; Component 3, Finition int - Plaque de plâtre, SpecificHeatCapacity: 1000 J/kg/K; Component 3, Finition int - Plaque de plâtre, MassDensity: 1600 kg/m3; Component 3, Finition int - Plaque de plâtre, Embodied Energy: 1.45 (MJ/kg); Component 3, Finition int - Plaque de plâtre, Embodied Carbon: 0.22 (kgCO₂/kg); Component 3, Finition int - Plaque de plâtre, Name: Finition int - Plaque de plâtre; Component 3, Finition int - Plaque de plâtre, Participates in Collision Detection: no; Component 3: 2 with these values
Cloison Placostil 72/48 | Rez-de-chaussée | Cloison (Classification ARCHICAD) | Non défini | 0.8 | 1000 | 1600 | 1.45 (MJ/kg) | 0.22 (kgCO₂/kg) | Finition int - Plaque de plâtre | no | 2 with these values | 0.187036 | 2.5 | 0.0131436 | 0.451339 | 0.451339 | 0.0328591 | 0.0328591
Cloison Placostil 72/48 | Rez-de-chaussée | Cloison (Classification ARCHICAD) | Non défini |  |  |  |  |  |  |  |  | 0.187 | 2.5 | 0.013257 | 0.47625 | 0.47625 | 0.0331425 | 0.0331425 | Material Properties - Component 3, Finition int - Plaque de plâtre, ThermalConductivity: 0.8; Component 3, Finition int - Plaque de plâtre, SpecificHeatCapacity: 1000 J/kg/K; Component 3, Finition int - Plaque de plâtre, MassDensity: 1600 kg/m3; Component 3, Finition int - Plaque de plâtre, Embodied Energy: 1.45 (MJ/kg); Component 3, Finition int - Plaque de plâtre, Embodied Carbon: 0.22 (kgCO₂/kg); Component 3, Finition int - Plaque de plâtre, Name: Finition int - Plaque de plâtre; Component 3, Finition int - Plaque de plâtre, Participates in Collision Detection: no; Component 3: 2 with these values
Cloison Placostil 72/48 | R+1 | Mur (Classification ARCHICAD); Cloison (Classification ARCHICAD) | 35 dB(A) |  |  |  |  |  |  |  |  | 0.714833 | 2.5 | 0.0542186 | 1.80333 | 1.80333 | 0.135547 | 0.135547 | Material Properties - Component 3, Finition int - Plaque de plâtre, ThermalConductivity: 0.8; Component 3, Finition int - Plaque de plâtre, SpecificHeatCapacity: 1000 J/kg/K; Component 3, Finition int - Plaque de plâtre, MassDensity: 1600 kg/m3; Component 3, Finition int - Plaque de plâtre, Embodied Energy: 1.45 (MJ/kg); Component 3, Finition int - Plaque de plâtre, Embodied Carbon: 0.22 (kgCO₂/kg); Component 3, Finition int - Plaque de plâtre, Name: Finition int - Plaque de plâtre; Component 3, Finition int - Plaque de plâtre, Participates in Collision Detection: no; Component 3: 2 with these values
Cloison Placostil 72/48 | R+1 | Cloison (Classification ARCHICAD) | Non défini |  |  |  |  |  |  |  |  | 0.187 | 2.47 | 0.013257 | 0.416385 | 0.416385 | 0.0313369 | 0.0313369 | Material Properties - Component 3, Finition int - Plaque de plâtre, ThermalConductivity: 0.8; Component 3, Finition int - Plaque de plâtre, SpecificHeatCapacity: 1000 J/kg/K; Component 3, Finition int - Plaque de plâtre, MassDensity: 1600 kg/m3; Component 3, Finition int - Plaque de plâtre, Embodied Energy: 1.45 (MJ/kg); Component 3, Finition int - Plaque de plâtre, Embodied Carbon: 0.22 (kgCO₂/kg); Component 3, Finition int - Plaque de plâtre, Name: Finition int - Plaque de plâtre; Component 3, Finition int - Plaque de plâtre, Participates in Collision Detection: no; Component 3: 2 with these values
Cloison Placostil 72/48 | R+1 | Mur (Classification ARCHICAD); Cloison (Classification ARCHICAD) | 35 dB(A) |  |  |  |  |  |  |  |  | 1.003 | 2.49 | 0.072901 | 2.48129 | 2.48129 | 0.181523 | 0.181523 | Material Properties - Component 3, Finition int - Plaque de plâtre, ThermalConductivity: 0.8; Component 3, Finition int - Plaque de plâtre, SpecificHeatCapacity: 1000 J/kg/K; Component 3, Finition int - Plaque de plâtre, MassDensity: 1600 kg/m3; Component 3, Finition int - Plaque de plâtre, Embodied Energy: 1.45 (MJ/kg); Component 3, Finition int - Plaque de plâtre, Embodied Carbon: 0.22 (kgCO₂/kg); Component 3, Finition int - Plaque de plâtre, Name: Finition int - Plaque de plâtre; Component 3, Finition int - Plaque de plâtre, Participates in Collision Detection: no; Component 3: 2 with these values
Cloison Placostil 72/48 | R+1 | Mur (Classification ARCHICAD); Cloison (Classification ARCHICAD) | Non défini | 0.8 | 1000 | 1600 | 1.45 (MJ/kg) | 0.22 (kgCO₂/kg) | Finition int - Plaque de plâtre | no | 2 with these values | 0.187 | 2.49 | 0.015159 | 0.481815 | 0.481815 | 0.0377459 | 0.0377459
Cloison Placostil 72/48 | R+1 | Mur (Classification ARCHICAD); Cloison (Classification ARCHICAD) | 35 dB(A) |  |  |  |  |  |  |  |  | 0.520901 | 2.5 | 0.0398677 | 1.31503 | 1.31503 | 0.0994037 | 0.0994037 | Material Properties - Component 3, Finition int - Plaque de plâtre, ThermalConductivity: 0.8; Component 3, Finition int - Plaque de plâtre, SpecificHeatCapacity: 1000 J/kg/K; Component 3, Finition int - Plaque de plâtre, MassDensity: 1600 kg/m3; Component 3, Finition int - Plaque de plâtre, Embodied Energy: 1.45 (MJ/kg); Component 3, Finition int - Plaque de plâtre, Embodied Carbon: 0.22 (kgCO₂/kg); Component 3, Finition int - Plaque de plâtre, Name: Finition int - Plaque de plâtre; Component 3, Finition int - Plaque de plâtre, Participates in Collision Detection: no; Component 3: 2 with these values
Cloison Placostil 72/48 | R+1 | Mur (Classification ARCHICAD); Cloison (Classification ARCHICAD) | 35 dB(A) | 0.8 | 1000 | 1600 | 1.45 (MJ/kg) | 0.22 (kgCO₂/kg) | Finition int - Plaque de plâtre | no | 2 with these values | 0.436 | 2.5 | 0.030943 | 1.07375 | 1.07375 | 0.0773575 | 0.0773575
Cloison Placostil 72/48 | R+1 | Mur (Classification ARCHICAD); Cloison (Classification ARCHICAD) | 35 dB(A) |  |  |  |  |  |  |  |  | 0.876 | 2.5 | 0.063503 | 2.17375 | 2.17375 | 0.158757 | 0.158757 | Material Properties - Component 3, Finition int - Plaque de plâtre, ThermalConductivity: 0.8; Component 3, Finition int - Plaque de plâtre, SpecificHeatCapacity: 1000 J/kg/K; Component 3, Finition int - Plaque de plâtre, MassDensity: 1600 kg/m3; Component 3, Finition int - Plaque de plâtre, Embodied Energy: 1.45 (MJ/kg); Component 3, Finition int - Plaque de plâtre, Embodied Carbon: 0.22 (kgCO₂/kg); Component 3, Finition int - Plaque de plâtre, Name: Finition int - Plaque de plâtre; Component 3, Finition int - Plaque de plâtre, Participates in Collision Detection: no; Component 3: 2 with these values
Cloison Placostil 72/48 | R+1 | Mur (Classification ARCHICAD); Cloison (Classification ARCHICAD) | 35 dB(A) | 0.8 | 1000 | 1600 | 1.45 (MJ/kg) | 0.22 (kgCO₂/kg) | Finition int - Plaque de plâtre | no | 2 with these values | 0.9 | 2.5 | 0.0666 | 2.25 | 2.25 | 0.1665 | 0.1665
Cloison Placostil 72/48 | R+1 | Mur (Classification ARCHICAD); Cloison (Classification ARCHICAD) | 35 dB(A) | 0.8 | 1000 | 1600 | 1.45 (MJ/kg) | 0.22 (kgCO₂/kg) | Finition int - Plaque de plâtre | no | 2 with these values | 0.876 | 2.5 | 0.066145 | 2.20625 | 2.20625 | 0.165363 | 0.165363
Cloison Placostil 72/48 | R+1 | Mur (Classification ARCHICAD); Cloison (Classification ARCHICAD) | 35 dB(A) | 0.8 | 1000 | 1600 | 1.45 (MJ/kg) | 0.22 (kgCO₂/kg) | Finition int - Plaque de plâtre | no | 2 with these values | 0.898 | 2.5 | 0.066452 | 2.245 | 2.245 | 0.16613 | 0.16613
Cloison Placostil 72/48 | R+1 | Mur (Classification ARCHICAD); Cloison (Classification ARCHICAD) | 35 dB(A) |  |  |  |  |  |  |  |  | 0.536 | 2.5 | 0.040985 | 1.35625 | 1.35625 | 0.102462 | 0.102462 | Material Properties - Component 3, Finition int - Plaque de plâtre, ThermalConductivity: 0.8; Component 3, Finition int - Plaque de plâtre, SpecificHeatCapacity: 1000 J/kg/K; Component 3, Finition int - Plaque de plâtre, MassDensity: 1600 kg/m3; Component 3, Finition int - Plaque de plâtre, Embodied Energy: 1.45 (MJ/kg); Component 3, Finition int - Plaque de plâtre, Embodied Carbon: 0.22 (kgCO₂/kg); Component 3, Finition int - Plaque de plâtre, Name: Finition int - Plaque de plâtre; Component 3, Finition int - Plaque de plâtre, Participates in Collision Detection: no; Component 3: 2 with these values
Cloison Placostil 72/48 | R+1 | Mur (Classification ARCHICAD); Cloison (Classification ARCHICAD) | 35 dB(A) | 0.8 | 1000 | 1600 | 1.45 (MJ/kg) | 0.22 (kgCO₂/kg) | Finition int - Plaque de plâtre | no | 2 with these values | 0.886 | 2.5 | 0.064243 | 2.19875 | 2.19875 | 0.160607 | 0.160607
Cloison Placostil 72/48 | R+2 | Mur (Classification ARCHICAD); Cloison (Classification ARCHICAD) | 35 dB(A) |  |  |  |  |  |  |  |  | 0.863 | 2.49 | 0.062541 | 2.13269 | 2.13269 | 0.155727 | 0.155727 | Material Properties - Component 3, Finition int - Plaque de plâtre, ThermalConductivity: 0.8; Component 3, Finition int - Plaque de plâtre, SpecificHeatCapacity: 1000 J/kg/K; Component 3, Finition int - Plaque de plâtre, MassDensity: 1600 kg/m3; Component 3, Finition int - Plaque de plâtre, Embodied Energy: 1.45 (MJ/kg); Component 3, Finition int - Plaque de plâtre, Embodied Carbon: 0.22 (kgCO₂/kg); Component 3, Finition int - Plaque de plâtre, Name: Finition int - Plaque de plâtre; Component 3, Finition int - Plaque de plâtre, Participates in Collision Detection: no; Component 3: 2 with these values
Cloison Placostil 72/48 | R+2 | Mur (Classification ARCHICAD); Cloison (Classification ARCHICAD) | 35 dB(A) | 0.8 | 1000 | 1600 | 1.45 (MJ/kg) | 0.22 (kgCO₂/kg) | Finition int - Plaque de plâtre | no | 2 with these values | 0.743476 | 2.5 | 0.0563382 | 1.87494 | 1.87494 | 0.140845 | 0.140845
2 x Cloison Placostil 72/48 | R+2 | Mur (Classification ARCHICAD); Cloison (Classification ARCHICAD) | 35 dB(A) | 0.8 | 1000 | 1600 | 1.45 (MJ/kg) | 0.22 (kgCO₂/kg) | Finition int - Plaque de plâtre | no | 2 with these values | 0.436 | 2.5 | 0.030943 | 1.07375 | 1.07375 | 0.0773575 | 0.0773575
Cloison Placostil 72/48 | R+2 | Mur (Classification ARCHICAD); Cloison (Classification ARCHICAD) | 35 dB(A) | 0.8 | 1000 | 1600 | 1.45 (MJ/kg) | 0.22 (kgCO₂/kg) | Finition int - Plaque de plâtre | no | 2 with these values | 0.148391 | 2.5 | 0.0096599 | 0.354726 | 0.354726 | 0.0241497 | 0.0241497
Cloison Placostil 72/48 | R+2 | Mur (Classification ARCHICAD); Cloison (Classification ARCHICAD) | 35 dB(A) | 0.8 | 1000 | 1600 | 1.45 (MJ/kg) | 0.22 (kgCO₂/kg) | Finition int - Plaque de plâtre | no | 2 with these values | 0.676 | 2.5 | 0.051345 | 1.70625 | 1.70625 | 0.128363 | 0.128363
Cloison Placostil 72/48 | R+2 | Mur (Classification ARCHICAD); Cloison (Classification ARCHICAD) | 35 dB(A) |  |  |  |  |  |  |  |  | 0.95 | 2.5 | 0.070924 | 2.375 | 2.375 | 0.17731 | 0.17731 | Material Properties - Component 3, Finition int - Plaque de plâtre, ThermalConductivity: 0.8; Component 3, Finition int - Plaque de plâtre, SpecificHeatCapacity: 1000 J/kg/K; Component 3, Finition int - Plaque de plâtre, MassDensity: 1600 kg/m3; Component 3, Finition int - Plaque de plâtre, Embodied Energy: 1.45 (MJ/kg); Component 3, Finition int - Plaque de plâtre, Embodied Carbon: 0.22 (kgCO₂/kg); Component 3, Finition int - Plaque de plâtre, Name: Finition int - Plaque de plâtre; Component 3, Finition int - Plaque de plâtre, Participates in Collision Detection: no; Component 3: 2 with these values
Cloison Placostil 72/48 | R+2 | Mur (Classification ARCHICAD); Cloison (Classification ARCHICAD) | Non défini | 0.8 | 1000 | 1600 | 1.45 (MJ/kg) | 0.22 (kgCO₂/kg) | Finition int - Plaque de plâtre | no | 2 with these values | 0.187 | 2.49 | 0.015159 | 0.481815 | 0.481815 | 0.0377459 | 0.0377459
Cloison Placostil 72/48 | R+2 | Mur (Classification ARCHICAD); Cloison (Classification ARCHICAD) | 35 dB(A) |  |  |  |  |  |  |  |  | 0.330901 | 2.49 | 0.0258077 | 0.840128 | 0.840128 | 0.0642611 | 0.0642611 | Material Properties - Component 3, Finition int - Plaque de plâtre, ThermalConductivity: 0.8; Component 3, Finition int - Plaque de plâtre, SpecificHeatCapacity: 1000 J/kg/K; Component 3, Finition int - Plaque de plâtre, MassDensity: 1600 kg/m3; Component 3, Finition int - Plaque de plâtre, Embodied Energy: 1.45 (MJ/kg); Component 3, Finition int - Plaque de plâtre, Embodied Carbon: 0.22 (kgCO₂/kg); Component 3, Finition int - Plaque de plâtre, Name: Finition int - Plaque de plâtre; Component 3, Finition int - Plaque de plâtre, Participates in Collision Detection: no; Component 3: 2 with these values
Cloison Placostil 72/48 | R+2 | Mur (Classification ARCHICAD); Cloison (Classification ARCHICAD) | 35 dB(A) |  |  |  |  |  |  |  |  | 0.876 | 2.5 | 0.063503 | 2.17375 | 2.17375 | 0.158757 | 0.158757 | Material Properties - Component 3, Finition int - Plaque de plâtre, ThermalConductivity: 0.8; Component 3, Finition int - Plaque de plâtre, SpecificHeatCapacity: 1000 J/kg/K; Component 3, Finition int - Plaque de plâtre, MassDensity: 1600 kg/m3; Component 3, Finition int - Plaque de plâtre, Embodied Energy: 1.45 (MJ/kg); Component 3, Finition int - Plaque de plâtre, Embodied Carbon: 0.22 (kgCO₂/kg); Component 3, Finition int - Plaque de plâtre, Name: Finition int - Plaque de plâtre; Component 3, Finition int - Plaque de plâtre, Participates in Collision Detection: no; Component 3: 2 with these values
Cloison Placostil 72/48 | R+2 | Mur (Classification ARCHICAD); Cloison (Classification ARCHICAD) | 35 dB(A) |  |  |  |  |  |  |  |  | 0.536 | 2.5 | 0.040985 | 1.35625 | 1.35625 | 0.102462 | 0.102462 | Material Properties - Component 3, Finition int - Plaque de plâtre, ThermalConductivity: 0.8; Component 3, Finition int - Plaque de plâtre, SpecificHeatCapacity: 1000 J/kg/K; Component 3, Finition int - Plaque de plâtre, MassDensity: 1600 kg/m3; Component 3, Finition int - Plaque de plâtre, Embodied Energy: 1.45 (MJ/kg); Component 3, Finition int - Plaque de plâtre, Embodied Carbon: 0.22 (kgCO₂/kg); Component 3, Finition int - Plaque de plâtre, Name: Finition int - Plaque de plâtre; Component 3, Finition int - Plaque de plâtre, Participates in Collision Detection: no; Component 3: 2 with these values
Cloison Placostil 72/48 | R+2 | Mur (Classification ARCHICAD); Cloison (Classification ARCHICAD) | 35 dB(A) | 0.8 | 1000 | 1600 | 1.45 (MJ/kg) | 0.22 (kgCO₂/kg) | Finition int - Plaque de plâtre | no | 2 with these values | 0.886 | 2.5 | 0.064243 | 2.19875 | 2.19875 | 0.160607 | 0.160607
Cloison Placostil 72/48 | R+2 | Mur (Classification ARCHICAD); Cloison (Classification ARCHICAD) | 35 dB(A) | 0.8 | 1000 | 1600 | 1.45 (MJ/kg) | 0.22 (kgCO₂/kg) | Finition int - Plaque de plâtre | no | 2 with these values | 0.876 | 2.5 | 0.066145 | 2.20625 | 2.20625 | 0.165363 | 0.165363
Cloison Placostil 72/48 | R+2 | Mur (Classification ARCHICAD); Cloison (Classification ARCHICAD) | 35 dB(A) | 0.8 | 1000 | 1600 | 1.45 (MJ/kg) | 0.22 (kgCO₂/kg) | Finition int - Plaque de plâtre | no | 2 with these values | 0.898 | 2.5 | 0.066452 | 2.245 | 2.245 | 0.16613 | 0.16613
Cloison Placostil 72/48 | R+2 | Mur (Classification ARCHICAD); Cloison (Classification ARCHICAD) | 35 dB(A) | 0.8 | 1000 | 1600 | 1.45 (MJ/kg) | 0.22 (kgCO₂/kg) | Finition int - Plaque de plâtre | no | 2 with these values | 0.9 | 2.5 | 0.0666 | 2.25 | 2.25 | 0.1665 | 0.1665
Cloison Placostil 72/48 | R+3 | Mur (Classification ARCHICAD); Cloison (Classification ARCHICAD) | 35 dB(A) | 0.8 | 1000 | 1600 | 1.45 (MJ/kg) | 0.22 (kgCO₂/kg) | Finition int - Plaque de plâtre | no | 2 with these values | 0.876 | 2.5 | 0.063503 | 2.17375 | 2.17375 | 0.158758 | 0.158758
Cloison Placostil 72/48 | R+3 | Mur (Classification ARCHICAD); Cloison (Classification ARCHICAD) | 35 dB(A) |  |  |  |  |  |  |  |  | 0.726 | 2.5 | 0.052403 | 1.79875 | 1.79875 | 0.131008 | 0.131008 | Material Properties - Component 3, Finition int - Plaque de plâtre, ThermalConductivity: 0.8; Component 3, Finition int - Plaque de plâtre, SpecificHeatCapacity: 1000 J/kg/K; Component 3, Finition int - Plaque de plâtre, MassDensity: 1600 kg/m3; Component 3, Finition int - Plaque de plâtre, Embodied Energy: 1.45 (MJ/kg); Component 3, Finition int - Plaque de plâtre, Embodied Carbon: 0.22 (kgCO₂/kg); Component 3, Finition int - Plaque de plâtre, Name: Finition int - Plaque de plâtre; Component 3, Finition int - Plaque de plâtre, Participates in Collision Detection: no; Component 3: 2 with these values
Cloison Placostil 72/48 | R+3 | Mur (Classification ARCHICAD); Cloison (Classification ARCHICAD) | 35 dB(A) | 0.8 | 1000 | 1600 | 1.45 (MJ/kg) | 0.22 (kgCO₂/kg) | Finition int - Plaque de plâtre | no | 2 with these values | 0.753476 | 2.5 | 0.0570782 | 1.89994 | 1.89994 | 0.142695 | 0.142695
Cloison Placostil 72/48 | R+3 | Mur (Classification ARCHICAD); Cloison (Classification ARCHICAD) | 35 dB(A) | 0.8 | 1000 | 1600 | 1.45 (MJ/kg) | 0.22 (kgCO₂/kg) | Finition int - Plaque de plâtre | no | 2 with these values | 0.876 | 2.5 | 0.066145 | 2.1725 | 2.1725 | 0.164687 | 0.164687
Cloison Placostil 72/48 | R+3 | Mur (Classification ARCHICAD); Cloison (Classification ARCHICAD) | 35 dB(A) |  |  |  |  |  |  |  |  | 0.536 | 2.5 | 0.038343 | 1.31855 | 1.31855 | 0.0954815 | 0.0954815 | Material Properties - Component 3, Finition int - Plaque de plâtre, ThermalConductivity: 0.8; Component 3, Finition int - Plaque de plâtre, SpecificHeatCapacity: 1000 J/kg/K; Component 3, Finition int - Plaque de plâtre, MassDensity: 1600 kg/m3; Component 3, Finition int - Plaque de plâtre, Embodied Energy: 1.45 (MJ/kg); Component 3, Finition int - Plaque de plâtre, Embodied Carbon: 0.22 (kgCO₂/kg); Component 3, Finition int - Plaque de plâtre, Name: Finition int - Plaque de plâtre; Component 3, Finition int - Plaque de plâtre, Participates in Collision Detection: no; Component 3: 2 with these values
Cloison Placostil 72/48 | R+3 | Mur (Classification ARCHICAD); Cloison (Classification ARCHICAD) | 35 dB(A) | 0.8 | 1000 | 1600 | 1.45 (MJ/kg) | 0.22 (kgCO₂/kg) | Finition int - Plaque de plâtre | no | 2 with these values | 0.886 | 2.49 | 0.066885 | 2.22232 | 2.22232 | 0.166544 | 0.166544
Cloison Placostil 72/48 | R+4 | Mur (Classification ARCHICAD); Cloison (Classification ARCHICAD) | 35 dB(A) |  |  |  |  |  |  |  |  | 0.407 | 2.48 | 0.028797 | 0.99324 | 0.99324 | 0.0714166 | 0.0714166 | Material Properties - Component 3, Finition int - Plaque de plâtre, ThermalConductivity: 0.8; Component 3, Finition int - Plaque de plâtre, SpecificHeatCapacity: 1000 J/kg/K; Component 3, Finition int - Plaque de plâtre, MassDensity: 1600 kg/m3; Component 3, Finition int - Plaque de plâtre, Embodied Energy: 1.45 (MJ/kg); Component 3, Finition int - Plaque de plâtre, Embodied Carbon: 0.22 (kgCO₂/kg); Component 3, Finition int - Plaque de plâtre, Name: Finition int - Plaque de plâtre; Component 3, Finition int - Plaque de plâtre, Participates in Collision Detection: no; Component 3: 2 with these values
Cloison Placostil 72/48 | R+4 | Mur (Classification ARCHICAD); Cloison (Classification ARCHICAD) | 35 dB(A) | 0.8 | 1000 | 1600 | 1.45 (MJ/kg) | 0.22 (kgCO₂/kg) | Finition int - Plaque de plâtre | no | 2 with these values | 0.64943 | 2.5 | 0.0493788 | 1.63982 | 1.63982 | 0.123447 | 0.123447
Cloison Placostil 72/48 | Rez-de-chaussée | Cloison (Classification ARCHICAD) | Non défini | 0.8 | 1000 | 1600 | 1.45 (MJ/kg) | 0.22 (kgCO₂/kg) | Finition int - Plaque de plâtre | no | 2 with these values | 0.876 | 2.5 | 0.066145 | 2.20625 | 2.20625 | 0.165363 | 0.165363
Cloison Placostil 72/48 | Rez-de-chaussée | Cloison (Classification ARCHICAD) | Non défini | 0.8 | 1000 | 1600 | 1.45 (MJ/kg) | 0.22 (kgCO₂/kg) | Finition int - Plaque de plâtre | no | 2 with these values | 0.898 | 2.5 | 0.066452 | 2.245 | 2.245 | 0.16613 | 0.16613
Cloison Placostil 72/48 | Rez-de-chaussée | Cloison (Classification ARCHICAD) | Non défini | 0.8 | 1000 | 1600 | 1.45 (MJ/kg) | 0.22 (kgCO₂/kg) | Finition int - Plaque de plâtre | no | 2 with these values | 0.886 | 2.5 | 0.064243 | 2.19875 | 2.19875 | 0.160607 | 0.160607
Cloison Placostil 72/48 | Rez-de-chaussée | Cloison (Classification ARCHICAD) | Non défini |  |  |  |  |  |  |  |  | 0.536 | 2.5 | 0.040985 | 1.35625 | 1.35625 | 0.102462 | 0.102462 | Material Properties - Component 3, Finition int - Plaque de plâtre, ThermalConductivity: 0.8; Component 3, Finition int - Plaque de plâtre, SpecificHeatCapacity: 1000 J/kg/K; Component 3, Finition int - Plaque de plâtre, MassDensity: 1600 kg/m3; Component 3, Finition int - Plaque de plâtre, Embodied Energy: 1.45 (MJ/kg); Component 3, Finition int - Plaque de plâtre, Embodied Carbon: 0.22 (kgCO₂/kg); Component 3, Finition int - Plaque de plâtre, Name: Finition int - Plaque de plâtre; Component 3, Finition int - Plaque de plâtre, Participates in Collision Detection: no; Component 3: 2 with these values
Cloison Placostil 72/48 | Rez-de-chaussée | Cloison (Classification ARCHICAD) | Non défini |  |  |  |  |  |  |  |  | 0.749478 | 2.5 | 0.0554614 | 1.87369 | 1.87369 | 0.138653 | 0.138653 | Material Properties - Component 3, Finition int - Plaque de plâtre, ThermalConductivity: 0.8; Component 3, Finition int - Plaque de plâtre, SpecificHeatCapacity: 1000 J/kg/K; Component 3, Finition int - Plaque de plâtre, MassDensity: 1600 kg/m3; Component 3, Finition int - Plaque de plâtre, Embodied Energy: 1.45 (MJ/kg); Component 3, Finition int - Plaque de plâtre, Embodied Carbon: 0.22 (kgCO₂/kg); Component 3, Finition int - Plaque de plâtre, Name: Finition int - Plaque de plâtre; Component 3, Finition int - Plaque de plâtre, Participates in Collision Detection: no; Component 3: 2 with these values
Cloison Placostil 72/48 | Rez-de-chaussée | Cloison (Classification ARCHICAD) | Non défini |  |  |  |  |  |  |  |  | 0.725478 | 2.5 | 0.0550064 | 1.82994 | 1.82994 | 0.137516 | 0.137516 | Material Properties - Component 3, Finition int - Plaque de plâtre, ThermalConductivity: 0.8; Component 3, Finition int - Plaque de plâtre, SpecificHeatCapacity: 1000 J/kg/K; Component 3, Finition int - Plaque de plâtre, MassDensity: 1600 kg/m3; Component 3, Finition int - Plaque de plâtre, Embodied Energy: 1.45 (MJ/kg); Component 3, Finition int - Plaque de plâtre, Embodied Carbon: 0.22 (kgCO₂/kg); Component 3, Finition int - Plaque de plâtre, Name: Finition int - Plaque de plâtre; Component 3, Finition int - Plaque de plâtre, Participates in Collision Detection: no; Component 3: 2 with these values
Cloison Placostil 72/48 | Rez-de-chaussée | Cloison (Classification ARCHICAD) | Non défini |  |  |  |  |  |  |  |  | 0.993 | 2.5 | 0.072161 | 2.46625 | 2.46625 | 0.180403 | 0.180403 | Material Properties - Component 3, Finition int - Plaque de plâtre, ThermalConductivity: 0.8; Component 3, Finition int - Plaque de plâtre, SpecificHeatCapacity: 1000 J/kg/K; Component 3, Finition int - Plaque de plâtre, MassDensity: 1600 kg/m3; Component 3, Finition int - Plaque de plâtre, Embodied Energy: 1.45 (MJ/kg); Component 3, Finition int - Plaque de plâtre, Embodied Carbon: 0.22 (kgCO₂/kg); Component 3, Finition int - Plaque de plâtre, Name: Finition int - Plaque de plâtre; Component 3, Finition int - Plaque de plâtre, Participates in Collision Detection: no; Component 3: 2 with these values
Cloison Placostil 72/48 | Rez-de-chaussée | Cloison (Classification ARCHICAD) | Non défini |  |  |  |  |  |  |  |  | 0.863 | 2.5 | 0.062541 | 2.14125 | 2.14125 | 0.156352 | 0.156352 | Material Properties - Component 3, Finition int - Plaque de plâtre, ThermalConductivity: 0.8; Component 3, Finition int - Plaque de plâtre, SpecificHeatCapacity: 1000 J/kg/K; Component 3, Finition int - Plaque de plâtre, MassDensity: 1600 kg/m3; Component 3, Finition int - Plaque de plâtre, Embodied Energy: 1.45 (MJ/kg); Component 3, Finition int - Plaque de plâtre, Embodied Carbon: 0.22 (kgCO₂/kg); Component 3, Finition int - Plaque de plâtre, Name: Finition int - Plaque de plâtre; Component 3, Finition int - Plaque de plâtre, Participates in Collision Detection: no; Component 3: 2 with these values
Cloison Placostil 72/48 | Rez-de-chaussée | Cloison (Classification ARCHICAD) | Non défini | 0.8 | 1000 | 1600 | 1.45 (MJ/kg) | 0.22 (kgCO₂/kg) | Finition int - Plaque de plâtre | no | 2 with these values | 0.310365 | 2.5 | 0.021646 | 0.759662 | 0.759662 | 0.054115 | 0.054115
Cloison Placostil 72/48 | Rez-de-chaussée | Cloison (Classification ARCHICAD) | Non défini | 0.8 | 1000 | 1600 | 1.45 (MJ/kg) | 0.22 (kgCO₂/kg) | Finition int - Plaque de plâtre | no | 2 with these values | 0.211 | 2.5 | 0.015614 | 0.5275 | 0.5275 | 0.039035 | 0.039035
Cloison Placostil 72/48 | Rez-de-chaussée | Cloison (Classification ARCHICAD) | Non défini |  |  |  |  |  |  |  |  | 0.520901 | 2.5 | 0.0398677 | 1.3185 | 1.3185 | 0.0996691 | 0.0996691 | Material Properties - Component 3, Finition int - Plaque de plâtre, ThermalConductivity: 0.8; Component 3, Finition int - Plaque de plâtre, SpecificHeatCapacity: 1000 J/kg/K; Component 3, Finition int - Plaque de plâtre, MassDensity: 1600 kg/m3; Component 3, Finition int - Plaque de plâtre, Embodied Energy: 1.45 (MJ/kg); Component 3, Finition int - Plaque de plâtre, Embodied Carbon: 0.22 (kgCO₂/kg); Component 3, Finition int - Plaque de plâtre, Name: Finition int - Plaque de plâtre; Component 3, Finition int - Plaque de plâtre, Participates in Collision Detection: no; Component 3: 2 with these values
Cloison Placostil 72/48 | Rez-de-chaussée | Cloison (Classification ARCHICAD) | Non défini |  |  |  |  |  |  |  |  | 0.187 | 2.5 | 0.015159 | 0.48375 | 0.48375 | 0.0378975 | 0.0378975 | Material Properties - Component 3, Finition int - Plaque de plâtre, ThermalConductivity: 0.8; Component 3, Finition int - Plaque de plâtre, SpecificHeatCapacity: 1000 J/kg/K; Component 3, Finition int - Plaque de plâtre, MassDensity: 1600 kg/m3; Component 3, Finition int - Plaque de plâtre, Embodied Energy: 1.45 (MJ/kg); Component 3, Finition int - Plaque de plâtre, Embodied Carbon: 0.22 (kgCO₂/kg); Component 3, Finition int - Plaque de plâtre, Name: Finition int - Plaque de plâtre; Component 3, Finition int - Plaque de plâtre, Participates in Collision Detection: no; Component 3: 2 with these values
Cloison Placostil 72/48 | R+1 | Cloison (Classification ARCHICAD) | Non défini |  |  |  |  |  |  |  |  | 0.187 | 2.47 | 0.015159 | 0.419895 | 0.419895 | 0.0359334 | 0.0359334 | Material Properties - Component 3, Finition int - Plaque de plâtre, ThermalConductivity: 0.8; Component 3, Finition int - Plaque de plâtre, SpecificHeatCapacity: 1000 J/kg/K; Component 3, Finition int - Plaque de plâtre, MassDensity: 1600 kg/m3; Component 3, Finition int - Plaque de plâtre, Embodied Energy: 1.45 (MJ/kg); Component 3, Finition int - Plaque de plâtre, Embodied Carbon: 0.22 (kgCO₂/kg); Component 3, Finition int - Plaque de plâtre, Name: Finition int - Plaque de plâtre; Component 3, Finition int - Plaque de plâtre, Participates in Collision Detection: no; Component 3: 2 with these values

# IfcWall: 3 - Cloison Gaine Technique 98mm 100 (141)
Type - ElementType: PARTITIONING; PredefinedType: USERDEFINED
Description: Cloison gaine logements
Pset_WallCommon - ThermalTransmittance: 0; LoadBearing: yes; IsExternal: yes
PSET_Murs_ARCHI - Emplacement: Superstructure; Type: Cloisons; Destination: Gaine technique logements; Matériaux: Cloison 98/48
Propriétés DCE - Numéro de LOT: LOT 09; Numéro article: L09.2.4.1.2
AC_Pset_RenovationAndPhasing - Renovation Status: Existing
Material Properties - Component 3, Isolation - Laine de roche, ThermalConductivity: 0.04; Component 3, Isolation - Laine de roche, SpecificHeatCapacity: 840 J/kg/K; Component 3, Isolation - Laine de roche, MassDensity: 160 kg/m3; Component 3, Isolation - Laine de roche, Embodied Energy: 23.4 (MJ/kg); Component 3, Isolation - Laine de roche, Embodied Carbon: 1.73 (kgCO₂/kg); Component 3, Isolation - Laine de roche, Name: Isolation - Laine de roche; Component 3, Isolation - Laine de roche, Participates in Collision Detection: no
BaseQuantities - Width: 0.1 m
Name | In | Classification | Material | AcousticRating | Component 1, Finition int - Plaque de plâtre, ThermalConductivity | Component 1, Finition int - Plaque de plâtre, SpecificHeatCapacity (J/kg/K) | Component 1, Finition int - Plaque de plâtre, MassDensity (kg/m3) | Component 1, Finition int - Plaque de plâtre, Embodied Energy | Component 1, Finition int - Plaque de plâtre, Embodied Carbon | Component 1, Finition int - Plaque de plâtre, Name | Component 1, Finition int - Plaque de plâtre, Participates in Collision Detection | Component 1 | Length (m) | Height (m) | GrossFootprintArea (m2) = NetFootprintArea (m2) | GrossSideArea (m2) = NetSideArea (m2) | GrossVolume (m3) = NetVolume (m3)
Cloison 98 isolée | R+1 | Mur (Classification ARCHICAD); Cloison (Classification ARCHICAD) | Finition int - Plaque de plâtre (4), Isolation - Laine de roche | 30 dB(A) | 0.8 | 1000 | 1600 | 1.45 (MJ/kg) | 0.22 (kgCO₂/kg) | Finition int - Plaque de plâtre | no | 4 with these values | 0.447 | 2.47 | 0.04119 | 1.04481 | 0.101739
Cloison 98 isolée | Rez-de-chaussée | Cloison (Classification ARCHICAD) | Finition int - Plaque de plâtre (4), Isolation - Laine de roche | Non défini | 0.8 | 1000 | 1600 | 1.45 (MJ/kg) | 0.22 (kgCO₂/kg) | Finition int - Plaque de plâtre | no | 4 with these values | 0.447 | 2.5 | 0.04119 | 1.0575 | 0.102975
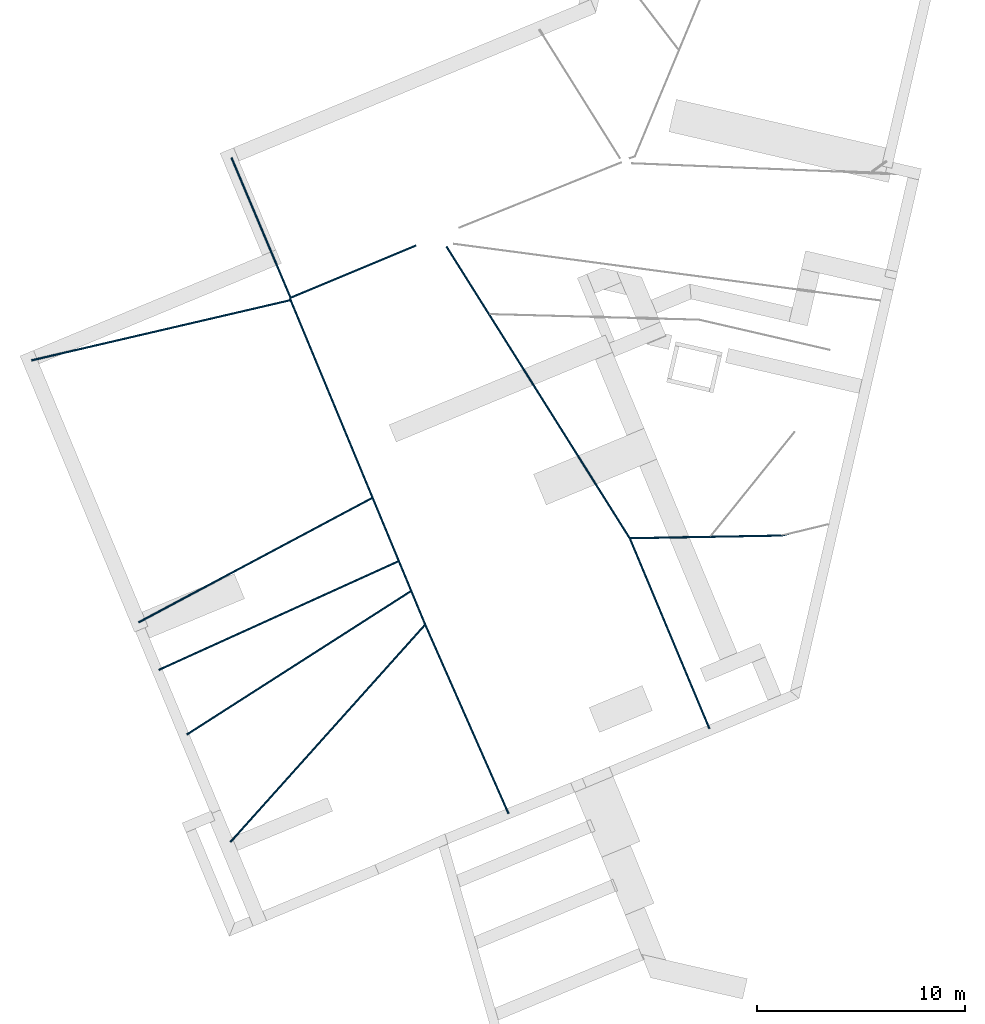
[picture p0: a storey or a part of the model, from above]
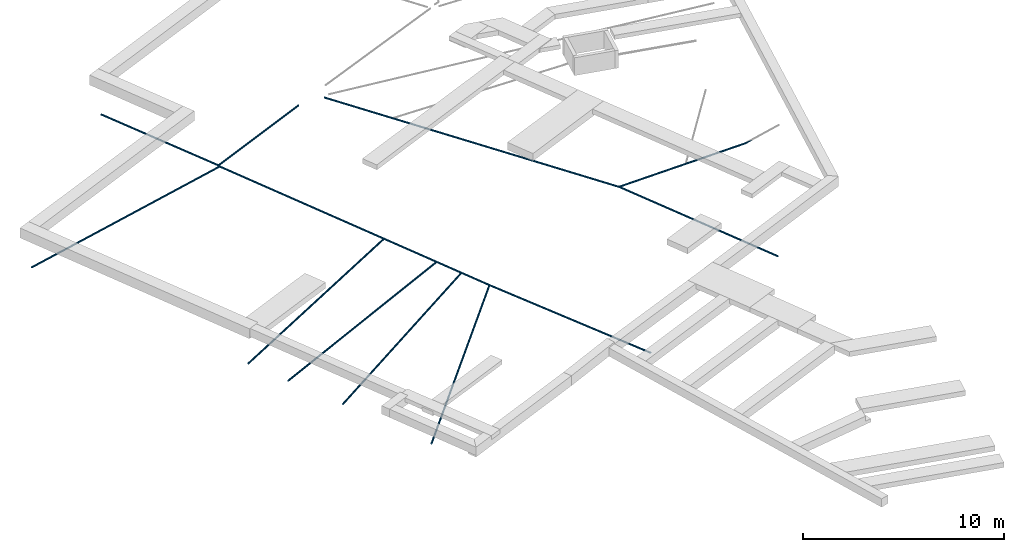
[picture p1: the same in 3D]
Properties of the parts of a building model (IFC2X3), part 16 of 22

# IfcWall: 3 - Cloison Gaine Technique 98mm 100 (141)
Name | In | Classification | Material | AcousticRating | Component 1, Finition int - Plaque de plâtre, ThermalConductivity | Component 1, Finition int - Plaque de plâtre, SpecificHeatCapacity (J/kg/K) | Component 1, Finition int - Plaque de plâtre, MassDensity (kg/m3) | Component 1, Finition int - Plaque de plâtre, Embodied Energy | Component 1, Finition int - Plaque de plâtre, Embodied Carbon | Component 1, Finition int - Plaque de plâtre, Name | Component 1, Finition int - Plaque de plâtre, Participates in Collision Detection | Component 1 | Length (m) | Height (m) | GrossFootprintArea (m2) = NetFootprintArea (m2) | GrossSideArea (m2) = NetSideArea (m2) | GrossVolume (m3) = NetVolume (m3)
Cloison 98 isolée | R+1 | Mur (Classification ARCHICAD); Cloison (Classification ARCHICAD) | Finition int - Plaque de plâtre (4), Isolation - Laine de roche | 30 dB(A) | 0.8 | 1000 | 1600 | 1.45 (MJ/kg) | 0.22 (kgCO₂/kg) | Finition int - Plaque de plâtre | no | 4 with these values | 0.357057 | 2.5 | 0.0344577 | 0.832643 | 0.0861443
Cloison 98 isolée | R+1 | Mur (Classification ARCHICAD); Cloison (Classification ARCHICAD) | Finition int - Plaque de plâtre (4), Isolation - Laine de roche | 30 dB(A) | 0.8 | 1000 | 1600 | 1.45 (MJ/kg) | 0.22 (kgCO₂/kg) | Finition int - Plaque de plâtre | no | 4 with these values | 0.576504 | 2.5 | 0.0593824 | 1.41376 | 0.148456
Cloison 98 isolée | R+1 | Mur (Classification ARCHICAD); Cloison (Classification ARCHICAD) | Finition int - Plaque de plâtre (4), Isolation - Laine de roche | 30 dB(A) | 0.8 | 1000 | 1600 | 1.45 (MJ/kg) | 0.22 (kgCO₂/kg) | Finition int - Plaque de plâtre | no | 4 with these values | 0.361 | 2.5 | 0.034852 | 0.8425 | 0.08713
Cloison 98 isolée | R+1 | Mur (Classification ARCHICAD); Cloison (Classification ARCHICAD) | Finition int - Plaque de plâtre (4), Isolation - Laine de roche | 30 dB(A) | 0.8 | 1000 | 1600 | 1.45 (MJ/kg) | 0.22 (kgCO₂/kg) | Finition int - Plaque de plâtre | no | 4 with these values | 0.526 | 2.5 | 0.050355 | 1.34 | 0.125887
Cloison 98 isolée | R+1 | Mur (Classification ARCHICAD); Cloison (Classification ARCHICAD) | Finition int - Plaque de plâtre (4), Isolation - Laine de roche | 30 dB(A) |  |  |  |  |  |  |  |  | 0.187 | 2.5 | 0.016455 | 0.4925 | 0.0411375 | Material Properties - Component 5, Finition int - Plaque de plâtre, ThermalConductivity: 0.8; Component 5, Finition int - Plaque de plâtre, SpecificHeatCapacity: 1000 J/kg/K; Component 5, Finition int - Plaque de plâtre, MassDensity: 1600 kg/m3; Component 5, Finition int - Plaque de plâtre, Embodied Energy: 1.45 (MJ/kg); Component 5, Finition int - Plaque de plâtre, Embodied Carbon: 0.22 (kgCO₂/kg); Component 5, Finition int - Plaque de plâtre, Name: Finition int - Plaque de plâtre; Component 5, Finition int - Plaque de plâtre, Participates in Collision Detection: no; Component 5: 4 with these values
Cloison 98 isolée | R+1 | Mur (Classification ARCHICAD); Cloison (Classification ARCHICAD) | Finition int - Plaque de plâtre (3), Isolation - Laine de roche | 30 dB(A) | 0.8 | 1000 | 1600 | 1.45 (MJ/kg) | 0.22 (kgCO₂/kg) | Finition int - Plaque de plâtre | no | 3 with these values | 0.134031 | 2.5 | 0.0111372 | 0.335078 | 0.027843
Cloison 98 isolée | R+1 | Mur (Classification ARCHICAD); Cloison (Classification ARCHICAD) | Finition int - Plaque de plâtre (4), Isolation - Laine de roche | 30 dB(A) |  |  |  |  |  |  |  |  | 0.56 | 2.5 | 0.05749 | 1.41625 | 0.143725 | Material Properties - Component 5, Finition int - Plaque de plâtre, ThermalConductivity: 0.8; Component 5, Finition int - Plaque de plâtre, SpecificHeatCapacity: 1000 J/kg/K; Component 5, Finition int - Plaque de plâtre, MassDensity: 1600 kg/m3; Component 5, Finition int - Plaque de plâtre, Embodied Energy: 1.45 (MJ/kg); Component 5, Finition int - Plaque de plâtre, Embodied Carbon: 0.22 (kgCO₂/kg); Component 5, Finition int - Plaque de plâtre, Name: Finition int - Plaque de plâtre; Component 5, Finition int - Plaque de plâtre, Participates in Collision Detection: no; Component 5: 4 with these values
Cloison 98 isolée | R+1 | Mur (Classification ARCHICAD); Cloison (Classification ARCHICAD) | Finition int - Plaque de plâtre (4), Isolation - Laine de roche | Non défini |  |  |  |  |  |  |  |  | 0.417186 | 2.5 | 0.0402286 | 1.02672 | 0.100572 | Material Properties - Component 5, Finition int - Plaque de plâtre, ThermalConductivity: 0.8; Component 5, Finition int - Plaque de plâtre, SpecificHeatCapacity: 1000 J/kg/K; Component 5, Finition int - Plaque de plâtre, MassDensity: 1600 kg/m3; Component 5, Finition int - Plaque de plâtre, Embodied Energy: 1.45 (MJ/kg); Component 5, Finition int - Plaque de plâtre, Embodied Carbon: 0.22 (kgCO₂/kg); Component 5, Finition int - Plaque de plâtre, Name: Finition int - Plaque de plâtre; Component 5, Finition int - Plaque de plâtre, Participates in Collision Detection: no; Component 5: 4 with these values
Cloison 98 isolée | R+1 | Mur (Classification ARCHICAD); Cloison (Classification ARCHICAD) | Finition int - Plaque de plâtre (4), Isolation - Laine de roche | 30 dB(A) | 0.8 | 1000 | 1600 | 1.45 (MJ/kg) | 0.22 (kgCO₂/kg) | Finition int - Plaque de plâtre | no | 4 with these values | 0.587 | 2.5 | 0.057452 | 1.4075 | 0.14363
Cloison 98 isolée | R+2 | Mur (Classification ARCHICAD); Cloison (Classification ARCHICAD) | Finition int - Plaque de plâtre (4), Isolation - Laine de roche | 30 dB(A) | 0.8 | 1000 | 1600 | 1.45 (MJ/kg) | 0.22 (kgCO₂/kg) | Finition int - Plaque de plâtre | no | 4 with these values | 0.357057 | 2.5 | 0.0318157 | 0.816393 | 0.0795393
Cloison 98 isolée | R+2 | Mur (Classification ARCHICAD); Cloison (Classification ARCHICAD) | Finition int - Plaque de plâtre (4), Isolation - Laine de roche | 30 dB(A) |  |  |  |  |  |  |  |  | 0.574242 | 2.5 | 0.0591562 | 1.40811 | 0.147891 | Material Properties - Component 5, Finition int - Plaque de plâtre, ThermalConductivity: 0.8; Component 5, Finition int - Plaque de plâtre, SpecificHeatCapacity: 1000 J/kg/K; Component 5, Finition int - Plaque de plâtre, MassDensity: 1600 kg/m3; Component 5, Finition int - Plaque de plâtre, Embodied Energy: 1.45 (MJ/kg); Component 5, Finition int - Plaque de plâtre, Embodied Carbon: 0.22 (kgCO₂/kg); Component 5, Finition int - Plaque de plâtre, Name: Finition int - Plaque de plâtre; Component 5, Finition int - Plaque de plâtre, Participates in Collision Detection: no; Component 5: 4 with these values
Cloison 98 isolée | R+2 | Mur (Classification ARCHICAD); Cloison (Classification ARCHICAD) | Finition int - Plaque de plâtre (4), Isolation - Laine de roche | Non défini |  |  |  |  |  |  |  |  | 0.417186 | 2.5 | 0.0402286 | 1.02672 | 0.100572 | Material Properties - Component 5, Finition int - Plaque de plâtre, ThermalConductivity: 0.8; Component 5, Finition int - Plaque de plâtre, SpecificHeatCapacity: 1000 J/kg/K; Component 5, Finition int - Plaque de plâtre, MassDensity: 1600 kg/m3; Component 5, Finition int - Plaque de plâtre, Embodied Energy: 1.45 (MJ/kg); Component 5, Finition int - Plaque de plâtre, Embodied Carbon: 0.22 (kgCO₂/kg); Component 5, Finition int - Plaque de plâtre, Name: Finition int - Plaque de plâtre; Component 5, Finition int - Plaque de plâtre, Participates in Collision Detection: no; Component 5: 4 with these values
Cloison 98 isolée | R+2 | Mur (Classification ARCHICAD); Cloison (Classification ARCHICAD) | Finition int - Plaque de plâtre (4), Isolation - Laine de roche | 30 dB(A) | 0.8 | 1000 | 1600 | 1.45 (MJ/kg) | 0.22 (kgCO₂/kg) | Finition int - Plaque de plâtre | no | 4 with these values | 0.660831 | 2.5 | 0.0678151 | 1.62458 | 0.169538
Cloison 98 isolée | R+2 | Mur (Classification ARCHICAD); Cloison (Classification ARCHICAD) | Finition int - Plaque de plâtre (4), Isolation - Laine de roche | 30 dB(A) |  |  |  |  |  |  |  |  | 0.411 | 2.5 | 0.030941 | 0.81 | 0.0773525 | Material Properties - Component 5, Finition int - Plaque de plâtre, ThermalConductivity: 0.8; Component 5, Finition int - Plaque de plâtre, SpecificHeatCapacity: 1000 J/kg/K; Component 5, Finition int - Plaque de plâtre, MassDensity: 1600 kg/m3; Component 5, Finition int - Plaque de plâtre, Embodied Energy: 1.45 (MJ/kg); Component 5, Finition int - Plaque de plâtre, Embodied Carbon: 0.22 (kgCO₂/kg); Component 5, Finition int - Plaque de plâtre, Name: Finition int - Plaque de plâtre; Component 5, Finition int - Plaque de plâtre, Participates in Collision Detection: no; Component 5: 4 with these values
Cloison 98 isolée | R+2 | Mur (Classification ARCHICAD); Cloison (Classification ARCHICAD) | Finition int - Plaque de plâtre (3), Isolation - Laine de roche | 30 dB(A) | 0.8 | 1000 | 1600 | 1.45 (MJ/kg) | 0.22 (kgCO₂/kg) | Finition int - Plaque de plâtre | no | 3 with these values | 0.134031 | 2.5 | 0.0111372 | 0.335078 | 0.027843
Cloison 98 isolée | R+2 | Mur (Classification ARCHICAD); Cloison (Classification ARCHICAD) | Finition int - Plaque de plâtre (4), Isolation - Laine de roche | 30 dB(A) | 0.8 | 1000 | 1600 | 1.45 (MJ/kg) | 0.22 (kgCO₂/kg) | Finition int - Plaque de plâtre | no | 4 with these values | 0.348 | 2.5 | 0.033721 | 0.81 | 0.0843025
Cloison 98 isolée | R+2 | Mur (Classification ARCHICAD); Cloison (Classification ARCHICAD) | Finition int - Plaque de plâtre (4), Isolation - Laine de roche | 30 dB(A) | 0.8 | 1000 | 1600 | 1.45 (MJ/kg) | 0.22 (kgCO₂/kg) | Finition int - Plaque de plâtre | no | 4 with these values | 0.587 | 2.5 | 0.057452 | 1.4075 | 0.14363
Cloison 98 isolée | R+2 | Mur (Classification ARCHICAD); Cloison (Classification ARCHICAD) | Finition int - Plaque de plâtre (4), Isolation - Laine de roche | 30 dB(A) |  |  |  |  |  |  |  |  | 0.56 | 2.5 | 0.05749 | 1.41625 | 0.143725 | Material Properties - Component 5, Finition int - Plaque de plâtre, ThermalConductivity: 0.8; Component 5, Finition int - Plaque de plâtre, SpecificHeatCapacity: 1000 J/kg/K; Component 5, Finition int - Plaque de plâtre, MassDensity: 1600 kg/m3; Component 5, Finition int - Plaque de plâtre, Embodied Energy: 1.45 (MJ/kg); Component 5, Finition int - Plaque de plâtre, Embodied Carbon: 0.22 (kgCO₂/kg); Component 5, Finition int - Plaque de plâtre, Name: Finition int - Plaque de plâtre; Component 5, Finition int - Plaque de plâtre, Participates in Collision Detection: no; Component 5: 4 with these values
Cloison 98 isolée | R+3 | Mur (Classification ARCHICAD); Cloison (Classification ARCHICAD) | Finition int - Plaque de plâtre (4), Isolation - Laine de roche | Non défini |  |  |  |  |  |  |  |  | 0.491186 | 2.49 | 0.0463806 | 1.14711 | 0.115488 | Material Properties - Component 5, Finition int - Plaque de plâtre, ThermalConductivity: 0.8; Component 5, Finition int - Plaque de plâtre, SpecificHeatCapacity: 1000 J/kg/K; Component 5, Finition int - Plaque de plâtre, MassDensity: 1600 kg/m3; Component 5, Finition int - Plaque de plâtre, Embodied Energy: 1.45 (MJ/kg); Component 5, Finition int - Plaque de plâtre, Embodied Carbon: 0.22 (kgCO₂/kg); Component 5, Finition int - Plaque de plâtre, Name: Finition int - Plaque de plâtre; Component 5, Finition int - Plaque de plâtre, Participates in Collision Detection: no; Component 5: 4 with these values
Cloison 98 isolée | R+3 | Mur (Classification ARCHICAD); Cloison (Classification ARCHICAD) | Finition int - Plaque de plâtre (4), Isolation - Laine de roche | 30 dB(A) | 0.8 | 1000 | 1600 | 1.45 (MJ/kg) | 0.22 (kgCO₂/kg) | Finition int - Plaque de plâtre | no | 4 with these values | 0.357057 | 2.5 | 0.0318157 | 0.816393 | 0.0795393
Cloison 98 isolée | R+3 | Mur (Classification ARCHICAD); Cloison (Classification ARCHICAD) | Finition int - Plaque de plâtre (4), Isolation - Laine de roche | 30 dB(A) |  |  |  |  |  |  |  |  | 0.726 | 2.5 | 0.068093 | 1.6225 | 0.170233 | Material Properties - Component 5, Finition int - Plaque de plâtre, ThermalConductivity: 0.8; Component 5, Finition int - Plaque de plâtre, SpecificHeatCapacity: 1000 J/kg/K; Component 5, Finition int - Plaque de plâtre, MassDensity: 1600 kg/m3; Component 5, Finition int - Plaque de plâtre, Embodied Energy: 1.45 (MJ/kg); Component 5, Finition int - Plaque de plâtre, Embodied Carbon: 0.22 (kgCO₂/kg); Component 5, Finition int - Plaque de plâtre, Name: Finition int - Plaque de plâtre; Component 5, Finition int - Plaque de plâtre, Participates in Collision Detection: no; Component 5: 4 with these values
Cloison 98 isolée | R+3 | Mur (Classification ARCHICAD); Cloison (Classification ARCHICAD) | Finition int - Plaque de plâtre (4), Isolation - Laine de roche | 30 dB(A) | 0.8 | 1000 | 1600 | 1.45 (MJ/kg) | 0.22 (kgCO₂/kg) | Finition int - Plaque de plâtre | no | 4 with these values | 0.437 | 2.5 | 0.04279 | 1.04875 | 0.106975
Cloison 98 isolée | R+3 | Mur (Classification ARCHICAD); Cloison (Classification ARCHICAD) | Finition int - Plaque de plâtre (4), Isolation - Laine de roche | 30 dB(A) | 0.8 | 1000 | 1600 | 1.45 (MJ/kg) | 0.22 (kgCO₂/kg) | Finition int - Plaque de plâtre | no | 4 with these values | 1.534 | 2.5 | 0.14951 | 3.75875 | 0.373775
Cloison 98 isolée | R+3 | Mur (Classification ARCHICAD); Cloison (Classification ARCHICAD) | Finition int - Plaque de plâtre (4), Isolation - Laine de roche | 30 dB(A) | 0.8 | 1000 | 1600 | 1.45 (MJ/kg) | 0.22 (kgCO₂/kg) | Finition int - Plaque de plâtre | no | 4 with these values | 0.587 | 2.49 | 0.05481 | 1.38569 | 0.136477
Cloison 98 isolée | Rez-de-chaussée | Cloison (Classification ARCHICAD) | Finition int - Plaque de plâtre (4), Isolation - Laine de roche | Non défini | 0.8 | 1000 | 1600 | 1.45 (MJ/kg) | 0.22 (kgCO₂/kg) | Finition int - Plaque de plâtre | no | 4 with these values | 0.587 | 2.5 | 0.05481 | 1.39125 | 0.137025
Cloison 98 isolée | Rez-de-chaussée | Cloison (Classification ARCHICAD) | Finition int - Plaque de plâtre (4), Isolation - Laine de roche | Non défini | 0.8 | 1000 | 1600 | 1.45 (MJ/kg) | 0.22 (kgCO₂/kg) | Finition int - Plaque de plâtre | no | 4 with these values | 0.576504 | 2.5 | 0.0593824 | 1.41376 | 0.148456
Cloison 98 isolée | Rez-de-chaussée | Cloison (Classification ARCHICAD) | Finition int - Plaque de plâtre (4), Isolation - Laine de roche | Non défini | 0.8 | 1000 | 1600 | 1.45 (MJ/kg) | 0.22 (kgCO₂/kg) | Finition int - Plaque de plâtre | no | 4 with these values | 0.361 | 2.5 | 0.034852 | 0.8425 | 0.08713
Cloison 98 isolée | Rez-de-chaussée | Cloison (Classification ARCHICAD) | Finition int - Plaque de plâtre (4), Isolation - Laine de roche | Non défini | 0.8 | 1000 | 1600 | 1.45 (MJ/kg) | 0.22 (kgCO₂/kg) | Finition int - Plaque de plâtre | no | 4 with these values | 0.526 | 2.5 | 0.050355 | 1.34 | 0.125887
Cloison 98 isolée | Rez-de-chaussée | Cloison (Classification ARCHICAD) | Finition int - Plaque de plâtre (4), Isolation - Laine de roche | Non défini | 0.8 | 1000 | 1600 | 1.45 (MJ/kg) | 0.22 (kgCO₂/kg) | Finition int - Plaque de plâtre | no | 4 with these values | 0.51 | 2.5 | 0.04951 | 1.25875 | 0.123775
Cloison 98 isolée | Rez-de-chaussée | Cloison (Classification ARCHICAD) | Finition int - Plaque de plâtre (4), Isolation - Laine de roche | Non défini | 0.8 | 1000 | 1600 | 1.45 (MJ/kg) | 0.22 (kgCO₂/kg) | Finition int - Plaque de plâtre | no | 4 with these values | 0.51 | 2.5 | 0.05249 | 1.29125 | 0.131225
Cloison 98 isolée | Rez-de-chaussée | Cloison (Classification ARCHICAD) | Finition int - Plaque de plâtre (4), Isolation - Laine de roche | Non défini |  |  |  |  |  |  |  |  | 0.56 | 2.5 | 0.05749 | 1.41625 | 0.143725 | Material Properties - Component 5, Finition int - Plaque de plâtre, ThermalConductivity: 0.8; Component 5, Finition int - Plaque de plâtre, SpecificHeatCapacity: 1000 J/kg/K; Component 5, Finition int - Plaque de plâtre, MassDensity: 1600 kg/m3; Component 5, Finition int - Plaque de plâtre, Embodied Energy: 1.45 (MJ/kg); Component 5, Finition int - Plaque de plâtre, Embodied Carbon: 0.22 (kgCO₂/kg); Component 5, Finition int - Plaque de plâtre, Name: Finition int - Plaque de plâtre; Component 5, Finition int - Plaque de plâtre, Participates in Collision Detection: no; Component 5: 4 with these values
Cloison 98 isolée | Rez-de-chaussée | Cloison (Classification ARCHICAD) | Finition int - Plaque de plâtre (4), Isolation - Laine de roche | Non défini |  |  |  |  |  |  |  |  | 0.192 | 2.5 | 0.016955 | 0.505 | 0.0423875 | Material Properties - Component 5, Finition int - Plaque de plâtre, ThermalConductivity: 0.8; Component 5, Finition int - Plaque de plâtre, SpecificHeatCapacity: 1000 J/kg/K; Component 5, Finition int - Plaque de plâtre, MassDensity: 1600 kg/m3; Component 5, Finition int - Plaque de plâtre, Embodied Energy: 1.45 (MJ/kg); Component 5, Finition int - Plaque de plâtre, Embodied Carbon: 0.22 (kgCO₂/kg); Component 5, Finition int - Plaque de plâtre, Name: Finition int - Plaque de plâtre; Component 5, Finition int - Plaque de plâtre, Participates in Collision Detection: no; Component 5: 4 with these values
Cloison 98 isolée | Rez-de-chaussée | Cloison (Classification ARCHICAD) | Finition int - Plaque de plâtre (3), Isolation - Laine de roche | Non défini | 0.8 | 1000 | 1600 | 1.45 (MJ/kg) | 0.22 (kgCO₂/kg) | Finition int - Plaque de plâtre | no | 3 with these values | 0.134031 | 2.5 | 0.0111372 | 0.335078 | 0.027843
Cloison 98 isolée | Rez-de-chaussée | Cloison (Classification ARCHICAD) | Finition int - Plaque de plâtre (4), Isolation - Laine de roche | Non défini |  |  |  |  |  |  |  |  | 0.65 | 2.5 | 0.0648365 | 1.59 | 0.162091 | Material Properties - Component 5, Finition int - Plaque de plâtre, ThermalConductivity: 0.8; Component 5, Finition int - Plaque de plâtre, SpecificHeatCapacity: 1000 J/kg/K; Component 5, Finition int - Plaque de plâtre, MassDensity: 1600 kg/m3; Component 5, Finition int - Plaque de plâtre, Embodied Energy: 1.45 (MJ/kg); Component 5, Finition int - Plaque de plâtre, Embodied Carbon: 0.22 (kgCO₂/kg); Component 5, Finition int - Plaque de plâtre, Name: Finition int - Plaque de plâtre; Component 5, Finition int - Plaque de plâtre, Participates in Collision Detection: no; Component 5: 4 with these values
Cloison 98 isolée | Rez-de-chaussée | Cloison (Classification ARCHICAD) | Finition int - Plaque de plâtre (4), Isolation - Laine de roche | Non défini |  |  |  |  |  |  |  |  | 0.417186 | 2.5 | 0.0402286 | 1.02672 | 0.100572 | Material Properties - Component 5, Finition int - Plaque de plâtre, ThermalConductivity: 0.8; Component 5, Finition int - Plaque de plâtre, SpecificHeatCapacity: 1000 J/kg/K; Component 5, Finition int - Plaque de plâtre, MassDensity: 1600 kg/m3; Component 5, Finition int - Plaque de plâtre, Embodied Energy: 1.45 (MJ/kg); Component 5, Finition int - Plaque de plâtre, Embodied Carbon: 0.22 (kgCO₂/kg); Component 5, Finition int - Plaque de plâtre, Name: Finition int - Plaque de plâtre; Component 5, Finition int - Plaque de plâtre, Participates in Collision Detection: no; Component 5: 4 with these values
Cloison 98 isolée | R+1 | Mur (Classification ARCHICAD); Cloison (Classification ARCHICAD) | Finition int - Plaque de plâtre (4), Isolation - Laine de roche | 30 dB(A) | 0.8 | 1000 | 1600 | 1.45 (MJ/kg) | 0.22 (kgCO₂/kg) | Finition int - Plaque de plâtre | no | 4 with these values | 0.76 | 2.5 | 0.07849 | 1.94125 | 0.196225
Cloison 98 isolée | R+1 | Mur (Classification ARCHICAD); Cloison (Classification ARCHICAD) | Finition int - Plaque de plâtre (4), Isolation - Laine de roche | 30 dB(A) |  |  |  |  |  |  |  |  | 0.625 | 2.5 | 0.06499 | 1.5025 | 0.162272 | Material Properties - Component 5, Finition int - Plaque de plâtre, ThermalConductivity: 0.8; Component 5, Finition int - Plaque de plâtre, SpecificHeatCapacity: 1000 J/kg/K; Component 5, Finition int - Plaque de plâtre, MassDensity: 1600 kg/m3; Component 5, Finition int - Plaque de plâtre, Embodied Energy: 1.45 (MJ/kg); Component 5, Finition int - Plaque de plâtre, Embodied Carbon: 0.22 (kgCO₂/kg); Component 5, Finition int - Plaque de plâtre, Name: Finition int - Plaque de plâtre; Component 5, Finition int - Plaque de plâtre, Participates in Collision Detection: no; Component 5: 4 with these values
Cloison 98 isolée | R+1 | Mur (Classification ARCHICAD); Cloison (Classification ARCHICAD) | Finition int - Plaque de plâtre (4), Isolation - Laine de roche | 30 dB(A) |  |  |  |  |  |  |  |  | 0.15 | 2.5 | 0.017452 | 0.39125 | 0.04363 | Material Properties - Component 5, Finition int - Plaque de plâtre, ThermalConductivity: 0.8; Component 5, Finition int - Plaque de plâtre, SpecificHeatCapacity: 1000 J/kg/K; Component 5, Finition int - Plaque de plâtre, MassDensity: 1600 kg/m3; Component 5, Finition int - Plaque de plâtre, Embodied Energy: 1.45 (MJ/kg); Component 5, Finition int - Plaque de plâtre, Embodied Carbon: 0.22 (kgCO₂/kg); Component 5, Finition int - Plaque de plâtre, Name: Finition int - Plaque de plâtre; Component 5, Finition int - Plaque de plâtre, Participates in Collision Detection: no; Component 5: 4 with these values
Cloison 98 isolée | R+1 | Mur (Classification ARCHICAD); Cloison (Classification ARCHICAD) | Finition int - Plaque de plâtre (4), Isolation - Laine de roche | 30 dB(A) |  |  |  |  |  |  |  |  | 0.515 | 2.5 | 0.050972 | 1.27125 | 0.12743 | Material Properties - Component 5, Finition int - Plaque de plâtre, ThermalConductivity: 0.8; Component 5, Finition int - Plaque de plâtre, SpecificHeatCapacity: 1000 J/kg/K; Component 5, Finition int - Plaque de plâtre, MassDensity: 1600 kg/m3; Component 5, Finition int - Plaque de plâtre, Embodied Energy: 1.45 (MJ/kg); Component 5, Finition int - Plaque de plâtre, Embodied Carbon: 0.22 (kgCO₂/kg); Component 5, Finition int - Plaque de plâtre, Name: Finition int - Plaque de plâtre; Component 5, Finition int - Plaque de plâtre, Participates in Collision Detection: no; Component 5: 4 with these values
Cloison 98 isolée | R+1 | Mur (Classification ARCHICAD); Cloison (Classification ARCHICAD) | Finition int - Plaque de plâtre (4), Isolation - Laine de roche | 30 dB(A) | 0.8 | 1000 | 1600 | 1.45 (MJ/kg) | 0.22 (kgCO₂/kg) | Finition int - Plaque de plâtre | no | 4 with these values | 0.565633 | 2.5 | 0.0590533 | 1.45533 | 0.147633
Cloison 98 isolée | R+1 | Mur (Classification ARCHICAD); Cloison (Classification ARCHICAD) | Finition int - Plaque de plâtre (4), Isolation - Laine de roche | 30 dB(A) | 0.8 | 1000 | 1600 | 1.45 (MJ/kg) | 0.22 (kgCO₂/kg) | Finition int - Plaque de plâtre | no | 4 with these values | 0.295 | 2.5 | 0.03199 | 0.77875 | 0.079975
Cloison 98 isolée | R+1 | Mur (Classification ARCHICAD); Cloison (Classification ARCHICAD) | Finition int - Plaque de plâtre (4), Isolation - Laine de roche | 30 dB(A) |  |  |  |  |  |  |  |  | 0.391 | 2.5 | 0.04133 | 0.99375 | 0.103325 | Material Properties - Component 5, Finition int - Plaque de plâtre, ThermalConductivity: 0.8; Component 5, Finition int - Plaque de plâtre, SpecificHeatCapacity: 1000 J/kg/K; Component 5, Finition int - Plaque de plâtre, MassDensity: 1600 kg/m3; Component 5, Finition int - Plaque de plâtre, Embodied Energy: 1.45 (MJ/kg); Component 5, Finition int - Plaque de plâtre, Embodied Carbon: 0.22 (kgCO₂/kg); Component 5, Finition int - Plaque de plâtre, Name: Finition int - Plaque de plâtre; Component 5, Finition int - Plaque de plâtre, Participates in Collision Detection: no; Component 5: 4 with these values
Cloison 98 isolée | R+1 | Mur (Classification ARCHICAD); Cloison (Classification ARCHICAD) | Finition int - Plaque de plâtre (4), Isolation - Laine de roche | 35 dB(A) |  |  |  |  |  |  |  |  | 0.323 | 2.5 | 0.029055 | 0.8075 | 0.0726375 | Material Properties - Component 5, Finition int - Plaque de plâtre, ThermalConductivity: 0.8; Component 5, Finition int - Plaque de plâtre, SpecificHeatCapacity: 1000 J/kg/K; Component 5, Finition int - Plaque de plâtre, MassDensity: 1600 kg/m3; Component 5, Finition int - Plaque de plâtre, Embodied Energy: 1.45 (MJ/kg); Component 5, Finition int - Plaque de plâtre, Embodied Carbon: 0.22 (kgCO₂/kg); Component 5, Finition int - Plaque de plâtre, Name: Finition int - Plaque de plâtre; Component 5, Finition int - Plaque de plâtre, Participates in Collision Detection: no; Component 5: 4 with these values
Cloison 98 isolée | R+1 | Mur (Classification ARCHICAD); Cloison (Classification ARCHICAD) | Finition int - Plaque de plâtre (4), Isolation - Laine de roche | 30 dB(A) |  |  |  |  |  |  |  |  | 0.607363 | 2.47 | 0.0609783 | 1.45696 | 0.150617 | Material Properties - Component 5, Finition int - Plaque de plâtre, ThermalConductivity: 0.8; Component 5, Finition int - Plaque de plâtre, SpecificHeatCapacity: 1000 J/kg/K; Component 5, Finition int - Plaque de plâtre, MassDensity: 1600 kg/m3; Component 5, Finition int - Plaque de plâtre, Embodied Energy: 1.45 (MJ/kg); Component 5, Finition int - Plaque de plâtre, Embodied Carbon: 0.22 (kgCO₂/kg); Component 5, Finition int - Plaque de plâtre, Name: Finition int - Plaque de plâtre; Component 5, Finition int - Plaque de plâtre, Participates in Collision Detection: no; Component 5: 4 with these values
Cloison 98 isolée | R+1 | Mur (Classification ARCHICAD); Cloison (Classification ARCHICAD) | Finition int - Plaque de plâtre (4), Isolation - Laine de roche | Non défini |  |  |  |  |  |  |  |  | 0.288699 | 2.5 | 0.03185 | 0.754249 | 0.0796251 | Material Properties - Component 5, Finition int - Plaque de plâtre, ThermalConductivity: 0.8; Component 5, Finition int - Plaque de plâtre, SpecificHeatCapacity: 1000 J/kg/K; Component 5, Finition int - Plaque de plâtre, MassDensity: 1600 kg/m3; Component 5, Finition int - Plaque de plâtre, Embodied Energy: 1.45 (MJ/kg); Component 5, Finition int - Plaque de plâtre, Embodied Carbon: 0.22 (kgCO₂/kg); Component 5, Finition int - Plaque de plâtre, Name: Finition int - Plaque de plâtre; Component 5, Finition int - Plaque de plâtre, Participates in Collision Detection: no; Component 5: 4 with these values
Cloison 98 isolée | R+1 | Mur (Classification ARCHICAD); Cloison (Classification ARCHICAD) | Finition int - Plaque de plâtre (4), Isolation - Laine de roche | 30 dB(A) | 0.8 | 1000 | 1600 | 1.45 (MJ/kg) | 0.22 (kgCO₂/kg) | Finition int - Plaque de plâtre | no | 4 with these values | 0.5 | 2.49 | 0.04951 | 1.25372 | 0.12328
Cloison 98 isolée | R+1 | Mur (Classification ARCHICAD); Cloison (Classification ARCHICAD) | Finition int - Plaque de plâtre (4), Isolation - Laine de roche | 30 dB(A) |  |  |  |  |  |  |  |  | 0.65 | 2.5 | 0.0638365 | 1.565 | 0.159591 | Material Properties - Component 5, Finition int - Plaque de plâtre, ThermalConductivity: 0.8; Component 5, Finition int - Plaque de plâtre, SpecificHeatCapacity: 1000 J/kg/K; Component 5, Finition int - Plaque de plâtre, MassDensity: 1600 kg/m3; Component 5, Finition int - Plaque de plâtre, Embodied Energy: 1.45 (MJ/kg); Component 5, Finition int - Plaque de plâtre, Embodied Carbon: 0.22 (kgCO₂/kg); Component 5, Finition int - Plaque de plâtre, Name: Finition int - Plaque de plâtre; Component 5, Finition int - Plaque de plâtre, Participates in Collision Detection: no; Component 5: 4 with these values
Cloison 98 isolée | R+1 | Mur (Classification ARCHICAD); Cloison (Classification ARCHICAD) | Finition int - Plaque de plâtre (4), Isolation - Laine de roche | Non défini |  |  |  |  |  |  |  |  | 0.417219 | 2.5 | 0.0411938 | 1.0268 | 0.102985 | Material Properties - Component 5, Finition int - Plaque de plâtre, ThermalConductivity: 0.8; Component 5, Finition int - Plaque de plâtre, SpecificHeatCapacity: 1000 J/kg/K; Component 5, Finition int - Plaque de plâtre, MassDensity: 1600 kg/m3; Component 5, Finition int - Plaque de plâtre, Embodied Energy: 1.45 (MJ/kg); Component 5, Finition int - Plaque de plâtre, Embodied Carbon: 0.22 (kgCO₂/kg); Component 5, Finition int - Plaque de plâtre, Name: Finition int - Plaque de plâtre; Component 5, Finition int - Plaque de plâtre, Participates in Collision Detection: no; Component 5: 4 with these values
Cloison 98 isolée | R+2 | Mur (Classification ARCHICAD); Cloison (Classification ARCHICAD) | Finition int - Plaque de plâtre (4), Isolation - Laine de roche | 30 dB(A) | 0.8 | 1000 | 1600 | 1.45 (MJ/kg) | 0.22 (kgCO₂/kg) | Finition int - Plaque de plâtre | no | 4 with these values | 0.76 | 2.5 | 0.07849 | 1.94125 | 0.196225
Cloison 98 isolée | R+2 | Mur (Classification ARCHICAD); Cloison (Classification ARCHICAD) | Finition int - Plaque de plâtre (4), Isolation - Laine de roche | 30 dB(A) | 0.8 | 1000 | 1600 | 1.45 (MJ/kg) | 0.22 (kgCO₂/kg) | Finition int - Plaque de plâtre | no | 4 with these values | 0.5 | 2.5 | 0.04951 | 1.25373 | 0.123282
Cloison 98 isolée | R+2 | Mur (Classification ARCHICAD); Cloison (Classification ARCHICAD) | Finition int - Plaque de plâtre (4), Isolation - Laine de roche | Non défini |  |  |  |  |  |  |  |  | 0.513 | 2.5 | 0.050772 | 1.26625 | 0.12693 | Material Properties - Component 5, Finition int - Plaque de plâtre, ThermalConductivity: 0.8; Component 5, Finition int - Plaque de plâtre, SpecificHeatCapacity: 1000 J/kg/K; Component 5, Finition int - Plaque de plâtre, MassDensity: 1600 kg/m3; Component 5, Finition int - Plaque de plâtre, Embodied Energy: 1.45 (MJ/kg); Component 5, Finition int - Plaque de plâtre, Embodied Carbon: 0.22 (kgCO₂/kg); Component 5, Finition int - Plaque de plâtre, Name: Finition int - Plaque de plâtre; Component 5, Finition int - Plaque de plâtre, Participates in Collision Detection: no; Component 5: 4 with these values
Cloison 98 isolée | R+2 | Mur (Classification ARCHICAD); Cloison (Classification ARCHICAD) | Finition int - Plaque de plâtre (4), Isolation - Laine de roche | Non défini |  |  |  |  |  |  |  |  | 0.187 | 2.5 | 0.019038 | 0.48375 | 0.047595 | Material Properties - Component 5, Finition int - Plaque de plâtre, ThermalConductivity: 0.8; Component 5, Finition int - Plaque de plâtre, SpecificHeatCapacity: 1000 J/kg/K; Component 5, Finition int - Plaque de plâtre, MassDensity: 1600 kg/m3; Component 5, Finition int - Plaque de plâtre, Embodied Energy: 1.45 (MJ/kg); Component 5, Finition int - Plaque de plâtre, Embodied Carbon: 0.22 (kgCO₂/kg); Component 5, Finition int - Plaque de plâtre, Name: Finition int - Plaque de plâtre; Component 5, Finition int - Plaque de plâtre, Participates in Collision Detection: no; Component 5: 4 with these values
Cloison 98 isolée | R+2 | Mur (Classification ARCHICAD); Cloison (Classification ARCHICAD) | Finition int - Plaque de plâtre (4), Isolation - Laine de roche | 30 dB(A) |  |  |  |  |  |  |  |  | 0.625 | 2.5 | 0.06499 | 1.51375 | 0.162115 | Material Properties - Component 5, Finition int - Plaque de plâtre, ThermalConductivity: 0.8; Component 5, Finition int - Plaque de plâtre, SpecificHeatCapacity: 1000 J/kg/K; Component 5, Finition int - Plaque de plâtre, MassDensity: 1600 kg/m3; Component 5, Finition int - Plaque de plâtre, Embodied Energy: 1.45 (MJ/kg); Component 5, Finition int - Plaque de plâtre, Embodied Carbon: 0.22 (kgCO₂/kg); Component 5, Finition int - Plaque de plâtre, Name: Finition int - Plaque de plâtre; Component 5, Finition int - Plaque de plâtre, Participates in Collision Detection: no; Component 5: 4 with these values
Cloison 98 isolée | R+2 | Mur (Classification ARCHICAD); Cloison (Classification ARCHICAD) | Finition int - Plaque de plâtre (4), Isolation - Laine de roche | 30 dB(A) |  |  |  |  |  |  |  |  | 0.420363 | 2.5 | 0.0365293 | 0.833409 | 0.0913234 | Material Properties - Component 5, Finition int - Plaque de plâtre, ThermalConductivity: 0.8; Component 5, Finition int - Plaque de plâtre, SpecificHeatCapacity: 1000 J/kg/K; Component 5, Finition int - Plaque de plâtre, MassDensity: 1600 kg/m3; Component 5, Finition int - Plaque de plâtre, Embodied Energy: 1.45 (MJ/kg); Component 5, Finition int - Plaque de plâtre, Embodied Carbon: 0.22 (kgCO₂/kg); Component 5, Finition int - Plaque de plâtre, Name: Finition int - Plaque de plâtre; Component 5, Finition int - Plaque de plâtre, Participates in Collision Detection: no; Component 5: 4 with these values
Cloison 98 isolée | R+2 | Mur (Classification ARCHICAD); Cloison (Classification ARCHICAD) | Finition int - Plaque de plâtre (4), Isolation - Laine de roche | 30 dB(A) | 0.8 | 1000 | 1600 | 1.45 (MJ/kg) | 0.22 (kgCO₂/kg) | Finition int - Plaque de plâtre | no | 4 with these values | 0.676 | 2.5 | 0.064355 | 1.69 | 0.160887
Cloison 98 isolée | R+2 | Mur (Classification ARCHICAD); Cloison (Classification ARCHICAD) | Finition int - Plaque de plâtre (4), Isolation - Laine de roche | Non défini | 0.8 | 1000 | 1600 | 1.45 (MJ/kg) | 0.22 (kgCO₂/kg) | Finition int - Plaque de plâtre | no | 4 with these values | 0.795527 | 2.5 | 0.0820765 | 2.00507 | 0.205191
Cloison 98 isolée | R+2 | Mur (Classification ARCHICAD); Cloison (Classification ARCHICAD) | Finition int - Plaque de plâtre (4), Isolation - Laine de roche | 30 dB(A) |  |  |  |  |  |  |  |  | 0.75 | 2.5 | 0.0525986 | 1.62125 | 0.131496 | Material Properties - Component 5, Finition int - Plaque de plâtre, ThermalConductivity: 0.8; Component 5, Finition int - Plaque de plâtre, SpecificHeatCapacity: 1000 J/kg/K; Component 5, Finition int - Plaque de plâtre, MassDensity: 1600 kg/m3; Component 5, Finition int - Plaque de plâtre, Embodied Energy: 1.45 (MJ/kg); Component 5, Finition int - Plaque de plâtre, Embodied Carbon: 0.22 (kgCO₂/kg); Component 5, Finition int - Plaque de plâtre, Name: Finition int - Plaque de plâtre; Component 5, Finition int - Plaque de plâtre, Participates in Collision Detection: no; Component 5: 4 with these values
Cloison 98 isolée | R+2 | Mur (Classification ARCHICAD); Cloison (Classification ARCHICAD) | Finition int - Plaque de plâtre (4), Isolation - Laine de roche | 30 dB(A) |  |  |  |  |  |  |  |  | 0.65 | 2.5 | 0.0638365 | 1.565 | 0.159591 | Material Properties - Component 5, Finition int - Plaque de plâtre, ThermalConductivity: 0.8; Component 5, Finition int - Plaque de plâtre, SpecificHeatCapacity: 1000 J/kg/K; Component 5, Finition int - Plaque de plâtre, MassDensity: 1600 kg/m3; Component 5, Finition int - Plaque de plâtre, Embodied Energy: 1.45 (MJ/kg); Component 5, Finition int - Plaque de plâtre, Embodied Carbon: 0.22 (kgCO₂/kg); Component 5, Finition int - Plaque de plâtre, Name: Finition int - Plaque de plâtre; Component 5, Finition int - Plaque de plâtre, Participates in Collision Detection: no; Component 5: 4 with these values
Cloison 98 isolée | R+2 | Mur (Classification ARCHICAD); Cloison (Classification ARCHICAD) | Finition int - Plaque de plâtre (4), Isolation - Laine de roche | 30 dB(A) | 0.8 | 1000 | 1600 | 1.45 (MJ/kg) | 0.22 (kgCO₂/kg) | Finition int - Plaque de plâtre | no | 4 with these values | 0.724 | 2.5 | 0.07489 | 1.85125 | 0.187225
Cloison 98 isolée | R+2 | Mur (Classification ARCHICAD); Cloison (Classification ARCHICAD) | Finition int - Plaque de plâtre (4), Isolation - Laine de roche | 30 dB(A) |  |  |  |  |  |  |  |  | 0.724 | 2.5 | 0.07191 | 1.81875 | 0.179775 | Material Properties - Component 5, Finition int - Plaque de plâtre, ThermalConductivity: 0.8; Component 5, Finition int - Plaque de plâtre, SpecificHeatCapacity: 1000 J/kg/K; Component 5, Finition int - Plaque de plâtre, MassDensity: 1600 kg/m3; Component 5, Finition int - Plaque de plâtre, Embodied Energy: 1.45 (MJ/kg); Component 5, Finition int - Plaque de plâtre, Embodied Carbon: 0.22 (kgCO₂/kg); Component 5, Finition int - Plaque de plâtre, Name: Finition int - Plaque de plâtre; Component 5, Finition int - Plaque de plâtre, Participates in Collision Detection: no; Component 5: 4 with these values
Cloison 98 isolée | R+2 | Mur (Classification ARCHICAD); Cloison (Classification ARCHICAD) | Finition int - Plaque de plâtre (4), Isolation - Laine de roche | 30 dB(A) | 0.8 | 1000 | 1600 | 1.45 (MJ/kg) | 0.22 (kgCO₂/kg) | Finition int - Plaque de plâtre | no | 4 with these values | 0.295 | 2.5 | 0.03199 | 0.77875 | 0.079975
Cloison 98 isolée | R+2 | Mur (Classification ARCHICAD); Cloison (Classification ARCHICAD) | Finition int - Plaque de plâtre (4), Isolation - Laine de roche | Non défini |  |  |  |  |  |  |  |  | 0.417219 | 2.5 | 0.0411938 | 1.0268 | 0.102985 | Material Properties - Component 5, Finition int - Plaque de plâtre, ThermalConductivity: 0.8; Component 5, Finition int - Plaque de plâtre, SpecificHeatCapacity: 1000 J/kg/K; Component 5, Finition int - Plaque de plâtre, MassDensity: 1600 kg/m3; Component 5, Finition int - Plaque de plâtre, Embodied Energy: 1.45 (MJ/kg); Component 5, Finition int - Plaque de plâtre, Embodied Carbon: 0.22 (kgCO₂/kg); Component 5, Finition int - Plaque de plâtre, Name: Finition int - Plaque de plâtre; Component 5, Finition int - Plaque de plâtre, Participates in Collision Detection: no; Component 5: 4 with these values
Cloison 98 isolée | R+2 | Mur (Classification ARCHICAD); Cloison (Classification ARCHICAD) | Finition int - Plaque de plâtre (4), Isolation - Laine de roche | Non défini |  |  |  |  |  |  |  |  | 0.288699 | 2.5 | 0.03185 | 0.754249 | 0.0796251 | Material Properties - Component 5, Finition int - Plaque de plâtre, ThermalConductivity: 0.8; Component 5, Finition int - Plaque de plâtre, SpecificHeatCapacity: 1000 J/kg/K; Component 5, Finition int - Plaque de plâtre, MassDensity: 1600 kg/m3; Component 5, Finition int - Plaque de plâtre, Embodied Energy: 1.45 (MJ/kg); Component 5, Finition int - Plaque de plâtre, Embodied Carbon: 0.22 (kgCO₂/kg); Component 5, Finition int - Plaque de plâtre, Name: Finition int - Plaque de plâtre; Component 5, Finition int - Plaque de plâtre, Participates in Collision Detection: no; Component 5: 4 with these values
Cloison 98 isolée | R+3 | Mur (Classification ARCHICAD); Cloison (Classification ARCHICAD) | Finition int - Plaque de plâtre (4), Isolation - Laine de roche | 30 dB(A) | 0.8 | 1000 | 1600 | 1.45 (MJ/kg) | 0.22 (kgCO₂/kg) | Finition int - Plaque de plâtre | no | 4 with these values | 0.404609 | 2.5 | 0.0389709 | 0.995274 | 0.0974274
Cloison 98 isolée | R+3 | Mur (Classification ARCHICAD); Cloison (Classification ARCHICAD) | Finition int - Plaque de plâtre (4), Isolation - Laine de roche | 30 dB(A) | 0.8 | 1000 | 1600 | 1.45 (MJ/kg) | 0.22 (kgCO₂/kg) | Finition int - Plaque de plâtre | no | 4 with these values | 0.559574 | 2.5 | 0.0562954 | 1.41518 | 0.140738
Cloison 98 isolée | R+3 | Mur (Classification ARCHICAD); Cloison (Classification ARCHICAD) | Finition int - Plaque de plâtre (4), Isolation - Laine de roche | 30 dB(A) |  |  |  |  |  |  |  |  | 1.19057 | 2.5 | 0.116077 | 2.94393 | 0.290193 | Material Properties - Component 5, Finition int - Plaque de plâtre, ThermalConductivity: 0.8; Component 5, Finition int - Plaque de plâtre, SpecificHeatCapacity: 1000 J/kg/K; Component 5, Finition int - Plaque de plâtre, MassDensity: 1600 kg/m3; Component 5, Finition int - Plaque de plâtre, Embodied Energy: 1.45 (MJ/kg); Component 5, Finition int - Plaque de plâtre, Embodied Carbon: 0.22 (kgCO₂/kg); Component 5, Finition int - Plaque de plâtre, Name: Finition int - Plaque de plâtre; Component 5, Finition int - Plaque de plâtre, Participates in Collision Detection: no; Component 5: 4 with these values
Cloison 98 isolée | R+3 | Mur (Classification ARCHICAD); Cloison (Classification ARCHICAD) | Finition int - Plaque de plâtre (4), Isolation - Laine de roche | 30 dB(A) |  |  |  |  |  |  |  |  | 0.496016 | 2.5 | 0.0496016 | 1.24004 | 0.124004 | Material Properties - Component 5, Finition int - Plaque de plâtre, ThermalConductivity: 0.8; Component 5, Finition int - Plaque de plâtre, SpecificHeatCapacity: 1000 J/kg/K; Component 5, Finition int - Plaque de plâtre, MassDensity: 1600 kg/m3; Component 5, Finition int - Plaque de plâtre, Embodied Energy: 1.45 (MJ/kg); Component 5, Finition int - Plaque de plâtre, Embodied Carbon: 0.22 (kgCO₂/kg); Component 5, Finition int - Plaque de plâtre, Name: Finition int - Plaque de plâtre; Component 5, Finition int - Plaque de plâtre, Participates in Collision Detection: no; Component 5: 4 with these values
Cloison 98 isolée | R+3 | Mur (Classification ARCHICAD); Cloison (Classification ARCHICAD) | Finition int - Plaque de plâtre (4), Isolation - Laine de roche | 30 dB(A) |  |  |  |  |  |  |  |  | 0.52 | 2.5 | 0.052 | 1.3 | 0.13 | Material Properties - Component 5, Finition int - Plaque de plâtre, ThermalConductivity: 0.8; Component 5, Finition int - Plaque de plâtre, SpecificHeatCapacity: 1000 J/kg/K; Component 5, Finition int - Plaque de plâtre, MassDensity: 1600 kg/m3; Component 5, Finition int - Plaque de plâtre, Embodied Energy: 1.45 (MJ/kg); Component 5, Finition int - Plaque de plâtre, Embodied Carbon: 0.22 (kgCO₂/kg); Component 5, Finition int - Plaque de plâtre, Name: Finition int - Plaque de plâtre; Component 5, Finition int - Plaque de plâtre, Participates in Collision Detection: no; Component 5: 4 with these values
Cloison 98 isolée | R+3 | Mur (Classification ARCHICAD); Cloison (Classification ARCHICAD) | Finition int - Plaque de plâtre (4), Isolation - Laine de roche | 30 dB(A) |  |  |  |  |  |  |  |  | 0.657 | 2.5 | 0.057031 | 1.44125 | 0.142578 | Material Properties - Component 5, Finition int - Plaque de plâtre, ThermalConductivity: 0.8; Component 5, Finition int - Plaque de plâtre, SpecificHeatCapacity: 1000 J/kg/K; Component 5, Finition int - Plaque de plâtre, MassDensity: 1600 kg/m3; Component 5, Finition int - Plaque de plâtre, Embodied Energy: 1.45 (MJ/kg); Component 5, Finition int - Plaque de plâtre, Embodied Carbon: 0.22 (kgCO₂/kg); Component 5, Finition int - Plaque de plâtre, Name: Finition int - Plaque de plâtre; Component 5, Finition int - Plaque de plâtre, Participates in Collision Detection: no; Component 5: 4 with these values
Cloison 98 isolée | R+3 | Mur (Classification ARCHICAD); Cloison (Classification ARCHICAD) | Finition int - Plaque de plâtre (4), Isolation - Laine de roche | 30 dB(A) | 0.8 | 1000 | 1600 | 1.45 (MJ/kg) | 0.22 (kgCO₂/kg) | Finition int - Plaque de plâtre | no | 4 with these values | 0.52 | 2.5 | 0.052 | 1.3 | 0.13
Cloison 98 isolée | R+3 | Mur (Classification ARCHICAD); Cloison (Classification ARCHICAD) | Finition int - Plaque de plâtre (4), Isolation - Laine de roche | 30 dB(A) | 0.8 | 1000 | 1600 | 1.45 (MJ/kg) | 0.22 (kgCO₂/kg) | Finition int - Plaque de plâtre | no | 4 with these values | 0.496 | 2.5 | 0.0496 | 1.24 | 0.124
Cloison 98 isolée | R+3 | Mur (Classification ARCHICAD); Cloison (Classification ARCHICAD) | Finition int - Plaque de plâtre (4), Isolation - Laine de roche | 30 dB(A) |  |  |  |  |  |  |  |  | 1.308 | 2.5 | 0.131042 | 3.22625 | 0.327605 | Material Properties - Component 5, Finition int - Plaque de plâtre, ThermalConductivity: 0.8; Component 5, Finition int - Plaque de plâtre, SpecificHeatCapacity: 1000 J/kg/K; Component 5, Finition int - Plaque de plâtre, MassDensity: 1600 kg/m3; Component 5, Finition int - Plaque de plâtre, Embodied Energy: 1.45 (MJ/kg); Component 5, Finition int - Plaque de plâtre, Embodied Carbon: 0.22 (kgCO₂/kg); Component 5, Finition int - Plaque de plâtre, Name: Finition int - Plaque de plâtre; Component 5, Finition int - Plaque de plâtre, Participates in Collision Detection: no; Component 5: 4 with these values
Cloison 98 isolée | R+3 | Mur (Classification ARCHICAD); Cloison (Classification ARCHICAD) | Finition int - Plaque de plâtre (4), Isolation - Laine de roche | 35 dB(A) | 0.8 | 1000 | 1600 | 1.45 (MJ/kg) | 0.22 (kgCO₂/kg) | Finition int - Plaque de plâtre | no | 4 with these values | 0.294 | 2.5 | 0.025648 | 0.71875 | 0.06412
Cloison 98 isolée | R+3 | Mur (Classification ARCHICAD); Cloison (Classification ARCHICAD) | Finition int - Plaque de plâtre (4), Isolation - Laine de roche | 30 dB(A) | 0.8 | 1000 | 1600 | 1.45 (MJ/kg) | 0.22 (kgCO₂/kg) | Finition int - Plaque de plâtre | no | 4 with these values | 0.656554 | 2.5 | 0.0656554 | 1.64139 | 0.164139
Cloison 98 isolée | R+3 | Mur (Classification ARCHICAD); Cloison (Classification ARCHICAD) | Finition int - Plaque de plâtre (4), Isolation - Laine de roche | Non défini |  |  |  |  |  |  |  |  | 0.417219 | 2.49 | 0.0411938 | 1.02269 | 0.102573 | Material Properties - Component 5, Finition int - Plaque de plâtre, ThermalConductivity: 0.8; Component 5, Finition int - Plaque de plâtre, SpecificHeatCapacity: 1000 J/kg/K; Component 5, Finition int - Plaque de plâtre, MassDensity: 1600 kg/m3; Component 5, Finition int - Plaque de plâtre, Embodied Energy: 1.45 (MJ/kg); Component 5, Finition int - Plaque de plâtre, Embodied Carbon: 0.22 (kgCO₂/kg); Component 5, Finition int - Plaque de plâtre, Name: Finition int - Plaque de plâtre; Component 5, Finition int - Plaque de plâtre, Participates in Collision Detection: no; Component 5: 4 with these values
Cloison 98 isolée | R+3 | Mur (Classification ARCHICAD); Cloison (Classification ARCHICAD) | Finition int - Plaque de plâtre (4), Isolation - Laine de roche | Non défini |  |  |  |  |  |  |  |  | 0.288699 | 2.49 | 0.03185 | 0.751232 | 0.0793066 | Material Properties - Component 5, Finition int - Plaque de plâtre, ThermalConductivity: 0.8; Component 5, Finition int - Plaque de plâtre, SpecificHeatCapacity: 1000 J/kg/K; Component 5, Finition int - Plaque de plâtre, MassDensity: 1600 kg/m3; Component 5, Finition int - Plaque de plâtre, Embodied Energy: 1.45 (MJ/kg); Component 5, Finition int - Plaque de plâtre, Embodied Carbon: 0.22 (kgCO₂/kg); Component 5, Finition int - Plaque de plâtre, Name: Finition int - Plaque de plâtre; Component 5, Finition int - Plaque de plâtre, Participates in Collision Detection: no; Component 5: 4 with these values
Cloison 98 isolée | R+4 | Mur (Classification ARCHICAD); Cloison (Classification ARCHICAD) | Finition int - Plaque de plâtre (4), Isolation - Laine de roche | 30 dB(A) | 0.8 | 1000 | 1600 | 1.45 (MJ/kg) | 0.22 (kgCO₂/kg) | Finition int - Plaque de plâtre | no | 4 with these values | 0.416359 | 2.48 | 0.0446159 | 1.06481 | 0.110648
Cloison 98 isolée | R+4 | Mur (Classification ARCHICAD); Cloison (Classification ARCHICAD) | Finition int - Plaque de plâtre (4), Isolation - Laine de roche | 30 dB(A) | 0.8 | 1000 | 1600 | 1.45 (MJ/kg) | 0.22 (kgCO₂/kg) | Finition int - Plaque de plâtre | no | 4 with these values | 0.604464 | 2.5 | 0.0606885 | 1.46741 | 0.151721
Cloison 98 isolée | R+4 | Mur (Classification ARCHICAD); Cloison (Classification ARCHICAD) | Finition int - Plaque de plâtre (4), Isolation - Laine de roche | 30 dB(A) | 0.8 | 1000 | 1600 | 1.45 (MJ/kg) | 0.22 (kgCO₂/kg) | Finition int - Plaque de plâtre | no | 4 with these values | 0.550672 | 2.5 | 0.0520871 | 1.34418 | 0.130218
Cloison 98 isolée | Rez-de-chaussée | Cloison (Classification ARCHICAD) | Finition int - Plaque de plâtre (4), Isolation - Laine de roche | Non défini |  |  |  |  |  |  |  |  | 0.391137 | 2.5 | 0.0413437 | 0.994091 | 0.103359 | Material Properties - Component 5, Finition int - Plaque de plâtre, ThermalConductivity: 0.8; Component 5, Finition int - Plaque de plâtre, SpecificHeatCapacity: 1000 J/kg/K; Component 5, Finition int - Plaque de plâtre, MassDensity: 1600 kg/m3; Component 5, Finition int - Plaque de plâtre, Embodied Energy: 1.45 (MJ/kg); Component 5, Finition int - Plaque de plâtre, Embodied Carbon: 0.22 (kgCO₂/kg); Component 5, Finition int - Plaque de plâtre, Name: Finition int - Plaque de plâtre; Component 5, Finition int - Plaque de plâtre, Participates in Collision Detection: no; Component 5: 4 with these values
Cloison 98 isolée | Rez-de-chaussée | Cloison (Classification ARCHICAD) | Finition int - Plaque de plâtre (4), Isolation - Laine de roche | Non défini |  |  |  |  |  |  |  |  | 0.423647 | 2.5 | 0.0418747 | 1.06787 | 0.104687 | Material Properties - Component 5, Finition int - Plaque de plâtre, ThermalConductivity: 0.8; Component 5, Finition int - Plaque de plâtre, SpecificHeatCapacity: 1000 J/kg/K; Component 5, Finition int - Plaque de plâtre, MassDensity: 1600 kg/m3; Component 5, Finition int - Plaque de plâtre, Embodied Energy: 1.45 (MJ/kg); Component 5, Finition int - Plaque de plâtre, Embodied Carbon: 0.22 (kgCO₂/kg); Component 5, Finition int - Plaque de plâtre, Name: Finition int - Plaque de plâtre; Component 5, Finition int - Plaque de plâtre, Participates in Collision Detection: no; Component 5: 4 with these values
Cloison 98 isolée | Rez-de-chaussée | Cloison (Classification ARCHICAD) | Finition int - Plaque de plâtre (4), Isolation - Laine de roche | Non défini |  |  |  |  |  |  |  |  | 0.15 | 2.5 | 0.017452 | 0.39125 | 0.04363 | Material Properties - Component 5, Finition int - Plaque de plâtre, ThermalConductivity: 0.8; Component 5, Finition int - Plaque de plâtre, SpecificHeatCapacity: 1000 J/kg/K; Component 5, Finition int - Plaque de plâtre, MassDensity: 1600 kg/m3; Component 5, Finition int - Plaque de plâtre, Embodied Energy: 1.45 (MJ/kg); Component 5, Finition int - Plaque de plâtre, Embodied Carbon: 0.22 (kgCO₂/kg); Component 5, Finition int - Plaque de plâtre, Name: Finition int - Plaque de plâtre; Component 5, Finition int - Plaque de plâtre, Participates in Collision Detection: no; Component 5: 4 with these values
Cloison 98 isolée | Rez-de-chaussée | Cloison (Classification ARCHICAD) | Finition int - Plaque de plâtre (4), Isolation - Laine de roche | Non défini | 0.8 | 1000 | 1600 | 1.45 (MJ/kg) | 0.22 (kgCO₂/kg) | Finition int - Plaque de plâtre | no | 4 with these values | 0.565633 | 2.5 | 0.0590533 | 1.45533 | 0.147633
Cloison 98 isolée | Rez-de-chaussée | Cloison (Classification ARCHICAD) | Finition int - Plaque de plâtre (4), Isolation - Laine de roche | Non défini | 0.8 | 1000 | 1600 | 1.45 (MJ/kg) | 0.22 (kgCO₂/kg) | Finition int - Plaque de plâtre | no | 4 with these values | 0.295 | 2.5 | 0.03199 | 0.77875 | 0.079975
Cloison 98 isolée | Rez-de-chaussée | Cloison (Classification ARCHICAD) | Finition int - Plaque de plâtre (4), Isolation - Laine de roche | Non défini |  |  |  |  |  |  |  |  | 0.597363 | 2.5 | 0.0599783 | 1.44966 | 0.149946 | Material Properties - Component 5, Finition int - Plaque de plâtre, ThermalConductivity: 0.8; Component 5, Finition int - Plaque de plâtre, SpecificHeatCapacity: 1000 J/kg/K; Component 5, Finition int - Plaque de plâtre, MassDensity: 1600 kg/m3; Component 5, Finition int - Plaque de plâtre, Embodied Energy: 1.45 (MJ/kg); Component 5, Finition int - Plaque de plâtre, Embodied Carbon: 0.22 (kgCO₂/kg); Component 5, Finition int - Plaque de plâtre, Name: Finition int - Plaque de plâtre; Component 5, Finition int - Plaque de plâtre, Participates in Collision Detection: no; Component 5: 4 with these values
Cloison 98 isolée | Rez-de-chaussée | Cloison (Classification ARCHICAD) | Finition int - Plaque de plâtre (4), Isolation - Laine de roche | Non défini |  |  |  |  |  |  |  |  | 0.515 | 2.5 | 0.050972 | 1.27125 | 0.12743 | Material Properties - Component 5, Finition int - Plaque de plâtre, ThermalConductivity: 0.8; Component 5, Finition int - Plaque de plâtre, SpecificHeatCapacity: 1000 J/kg/K; Component 5, Finition int - Plaque de plâtre, MassDensity: 1600 kg/m3; Component 5, Finition int - Plaque de plâtre, Embodied Energy: 1.45 (MJ/kg); Component 5, Finition int - Plaque de plâtre, Embodied Carbon: 0.22 (kgCO₂/kg); Component 5, Finition int - Plaque de plâtre, Name: Finition int - Plaque de plâtre; Component 5, Finition int - Plaque de plâtre, Participates in Collision Detection: no; Component 5: 4 with these values
Cloison 98 isolée | Rez-de-chaussée | Cloison (Classification ARCHICAD) | Finition int - Plaque de plâtre (4), Isolation - Laine de roche | Non défini |  |  |  |  |  |  |  |  | 0.635 | 2.5 | 0.06499 | 1.60375 | 0.162475 | Material Properties - Component 5, Finition int - Plaque de plâtre, ThermalConductivity: 0.8; Component 5, Finition int - Plaque de plâtre, SpecificHeatCapacity: 1000 J/kg/K; Component 5, Finition int - Plaque de plâtre, MassDensity: 1600 kg/m3; Component 5, Finition int - Plaque de plâtre, Embodied Energy: 1.45 (MJ/kg); Component 5, Finition int - Plaque de plâtre, Embodied Carbon: 0.22 (kgCO₂/kg); Component 5, Finition int - Plaque de plâtre, Name: Finition int - Plaque de plâtre; Component 5, Finition int - Plaque de plâtre, Participates in Collision Detection: no; Component 5: 4 with these values
Cloison 98 isolée | Rez-de-chaussée | Cloison (Classification ARCHICAD) | Finition int - Plaque de plâtre (4), Isolation - Laine de roche | Non défini |  |  |  |  |  |  |  |  | 0.323 | 2.5 | 0.029055 | 0.8075 | 0.0726375 | Material Properties - Component 5, Finition int - Plaque de plâtre, ThermalConductivity: 0.8; Component 5, Finition int - Plaque de plâtre, SpecificHeatCapacity: 1000 J/kg/K; Component 5, Finition int - Plaque de plâtre, MassDensity: 1600 kg/m3; Component 5, Finition int - Plaque de plâtre, Embodied Energy: 1.45 (MJ/kg); Component 5, Finition int - Plaque de plâtre, Embodied Carbon: 0.22 (kgCO₂/kg); Component 5, Finition int - Plaque de plâtre, Name: Finition int - Plaque de plâtre; Component 5, Finition int - Plaque de plâtre, Participates in Collision Detection: no; Component 5: 4 with these values
Cloison 98 isolée | Rez-de-chaussée | Cloison (Classification ARCHICAD) | Finition int - Plaque de plâtre (4), Isolation - Laine de roche | Non défini | 0.8 | 1000 | 1600 | 1.45 (MJ/kg) | 0.22 (kgCO₂/kg) | Finition int - Plaque de plâtre | no | 4 with these values | 0.225539 | 2.5 | 0.0193089 | 0.563847 | 0.0482722
Cloison 98 isolée | Rez-de-chaussée | Cloison (Classification ARCHICAD) | Finition int - Plaque de plâtre (4), Isolation - Laine de roche | Non défini | 0.8 | 1000 | 1600 | 1.45 (MJ/kg) | 0.22 (kgCO₂/kg) | Finition int - Plaque de plâtre | no | 4 with these values | 0.576381 | 2.5 | 0.0586381 | 1.46595 | 0.146595
Cloison 98 isolée | Rez-de-chaussée | Cloison (Classification ARCHICAD) | Finition int - Plaque de plâtre (4), Isolation - Laine de roche | Non défini | 0.8 | 1000 | 1600 | 1.45 (MJ/kg) | 0.22 (kgCO₂/kg) | Finition int - Plaque de plâtre | no | 4 with these values | 0.863 | 2.5 | 0.083055 | 2.1575 | 0.207638
Cloison 98 isolée | Rez-de-chaussée | Cloison (Classification ARCHICAD) | Finition int - Plaque de plâtre (4), Isolation - Laine de roche | Non défini |  |  |  |  |  |  |  |  | 0.417219 | 2.5 | 0.0411938 | 1.0268 | 0.102985 | Material Properties - Component 5, Finition int - Plaque de plâtre, ThermalConductivity: 0.8; Component 5, Finition int - Plaque de plâtre, SpecificHeatCapacity: 1000 J/kg/K; Component 5, Finition int - Plaque de plâtre, MassDensity: 1600 kg/m3; Component 5, Finition int - Plaque de plâtre, Embodied Energy: 1.45 (MJ/kg); Component 5, Finition int - Plaque de plâtre, Embodied Carbon: 0.22 (kgCO₂/kg); Component 5, Finition int - Plaque de plâtre, Name: Finition int - Plaque de plâtre; Component 5, Finition int - Plaque de plâtre, Participates in Collision Detection: no; Component 5: 4 with these values
Cloison 98 isolée | Rez-de-chaussée | Cloison (Classification ARCHICAD) | Finition int - Plaque de plâtre (4), Isolation - Laine de roche | Non défini |  |  |  |  |  |  |  |  | 0.288699 | 2.5 | 0.03185 | 0.754249 | 0.0796251 | Material Properties - Component 5, Finition int - Plaque de plâtre, ThermalConductivity: 0.8; Component 5, Finition int - Plaque de plâtre, SpecificHeatCapacity: 1000 J/kg/K; Component 5, Finition int - Plaque de plâtre, MassDensity: 1600 kg/m3; Component 5, Finition int - Plaque de plâtre, Embodied Energy: 1.45 (MJ/kg); Component 5, Finition int - Plaque de plâtre, Embodied Carbon: 0.22 (kgCO₂/kg); Component 5, Finition int - Plaque de plâtre, Name: Finition int - Plaque de plâtre; Component 5, Finition int - Plaque de plâtre, Participates in Collision Detection: no; Component 5: 4 with these values
Cloison 98 isolée | R+1 | Mur (Classification ARCHICAD); Cloison (Classification ARCHICAD) | Finition int - Plaque de plâtre (4), Isolation - Laine de roche | 35 dB(A) | 0.8 | 1000 | 1600 | 1.45 (MJ/kg) | 0.22 (kgCO₂/kg) | Finition int - Plaque de plâtre | no | 4 with these values | 0.740476 | 2.5 | 0.0755376 | 1.86744 | 0.188844
Cloison 98 isolée | R+1 | Mur (Classification ARCHICAD); Cloison (Classification ARCHICAD) | Finition int - Plaque de plâtre (4), Isolation - Laine de roche | 35 dB(A) | 0.8 | 1000 | 1600 | 1.45 (MJ/kg) | 0.22 (kgCO₂/kg) | Finition int - Plaque de plâtre | no | 4 with these values | 0.423 | 2.5 | 0.04081 | 1.04125 | 0.102025
Cloison 98 isolée | R+1 | Mur (Classification ARCHICAD); Cloison (Classification ARCHICAD) | Finition int - Plaque de plâtre (4), Isolation - Laine de roche | 30 dB(A) |  |  |  |  |  |  |  |  | 0.443647 | 2.5 | 0.0428747 | 1.09287 | 0.107187 | Material Properties - Component 5, Finition int - Plaque de plâtre, ThermalConductivity: 0.8; Component 5, Finition int - Plaque de plâtre, SpecificHeatCapacity: 1000 J/kg/K; Component 5, Finition int - Plaque de plâtre, MassDensity: 1600 kg/m3; Component 5, Finition int - Plaque de plâtre, Embodied Energy: 1.45 (MJ/kg); Component 5, Finition int - Plaque de plâtre, Embodied Carbon: 0.22 (kgCO₂/kg); Component 5, Finition int - Plaque de plâtre, Name: Finition int - Plaque de plâtre; Component 5, Finition int - Plaque de plâtre, Participates in Collision Detection: no; Component 5: 4 with these values
Cloison 98 isolée | R+1 | Mur (Classification ARCHICAD); Cloison (Classification ARCHICAD) | Finition int - Plaque de plâtre (4), Isolation - Laine de roche | 30 dB(A) | 0.8 | 1000 | 1600 | 1.45 (MJ/kg) | 0.22 (kgCO₂/kg) | Finition int - Plaque de plâtre | no | 4 with these values | 0.55 | 2.5 | 0.05351 | 1.35875 | 0.133775
Cloison 98 isolée | R+1 | Mur (Classification ARCHICAD); Cloison (Classification ARCHICAD) | Finition int - Plaque de plâtre (4), Isolation - Laine de roche | 30 dB(A) |  |  |  |  |  |  |  |  | 0.56 | 2.47 | 0.05451 | 1.36715 | 0.13464 | Material Properties - Component 5, Finition int - Plaque de plâtre, ThermalConductivity: 0.8; Component 5, Finition int - Plaque de plâtre, SpecificHeatCapacity: 1000 J/kg/K; Component 5, Finition int - Plaque de plâtre, MassDensity: 1600 kg/m3; Component 5, Finition int - Plaque de plâtre, Embodied Energy: 1.45 (MJ/kg); Component 5, Finition int - Plaque de plâtre, Embodied Carbon: 0.22 (kgCO₂/kg); Component 5, Finition int - Plaque de plâtre, Name: Finition int - Plaque de plâtre; Component 5, Finition int - Plaque de plâtre, Participates in Collision Detection: no; Component 5: 4 with these values
Cloison 98 isolée | R+1 | Mur (Classification ARCHICAD); Cloison (Classification ARCHICAD) | Finition int - Plaque de plâtre (4), Isolation - Laine de roche | 30 dB(A) |  |  |  |  |  |  |  |  | 0.477449 | 2.47 | 0.0492349 | 1.19535 | 0.12161 | Material Properties - Component 5, Finition int - Plaque de plâtre, ThermalConductivity: 0.8; Component 5, Finition int - Plaque de plâtre, SpecificHeatCapacity: 1000 J/kg/K; Component 5, Finition int - Plaque de plâtre, MassDensity: 1600 kg/m3; Component 5, Finition int - Plaque de plâtre, Embodied Energy: 1.45 (MJ/kg); Component 5, Finition int - Plaque de plâtre, Embodied Carbon: 0.22 (kgCO₂/kg); Component 5, Finition int - Plaque de plâtre, Name: Finition int - Plaque de plâtre; Component 5, Finition int - Plaque de plâtre, Participates in Collision Detection: no; Component 5: 4 with these values
Cloison 98 isolée | R+1 | Mur (Classification ARCHICAD); Cloison (Classification ARCHICAD) | Finition int - Plaque de plâtre (4), Isolation - Laine de roche | 30 dB(A) | 0.8 | 1000 | 1600 | 1.45 (MJ/kg) | 0.22 (kgCO₂/kg) | Finition int - Plaque de plâtre | no | 4 with these values | 0.48 | 2.49 | 0.04949 | 1.21139 | 0.12323
Cloison 98 isolée | R+1 | Mur (Classification ARCHICAD); Cloison (Classification ARCHICAD) | Finition int - Plaque de plâtre (4), Isolation - Laine de roche | 30 dB(A) | 0.8 | 1000 | 1600 | 1.45 (MJ/kg) | 0.22 (kgCO₂/kg) | Finition int - Plaque de plâtre | no | 4 with these values | 0.576381 | 2.5 | 0.0576381 | 1.44095 | 0.144095
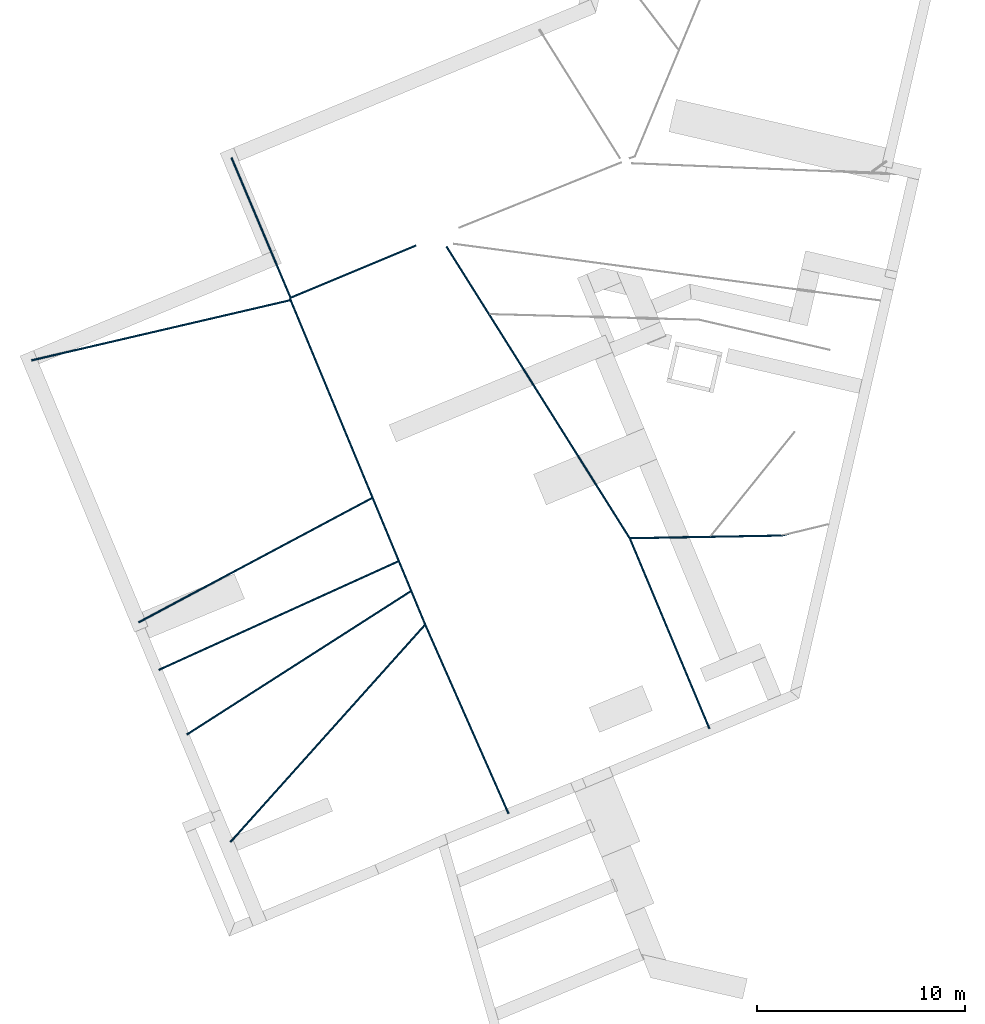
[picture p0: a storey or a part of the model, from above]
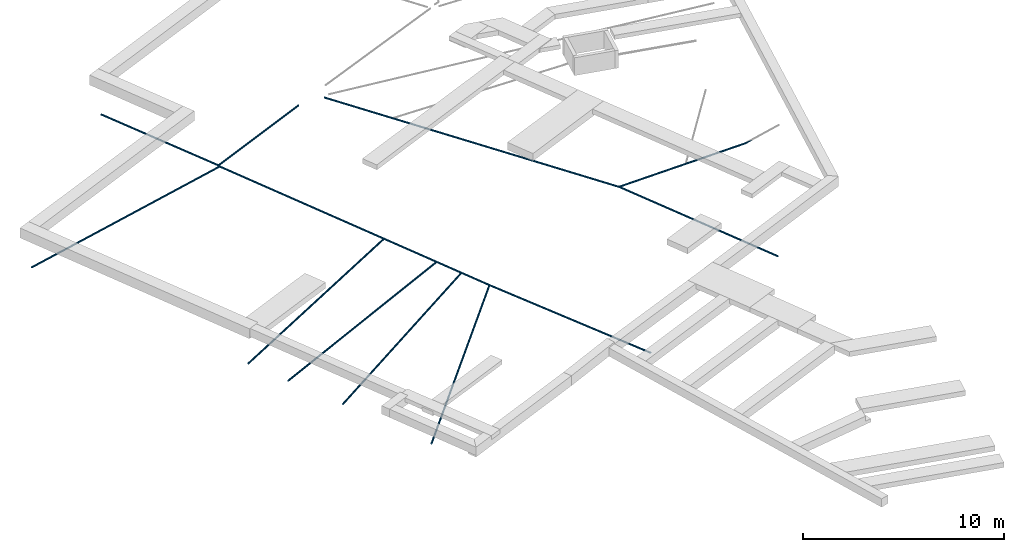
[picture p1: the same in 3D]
Properties of the parts of a building model (IFC2X3), part 17 of 22

# IfcWall: 3 - Cloison Gaine Technique 98mm 100 (141)
Name | In | Classification | Material | AcousticRating | Component 1, Finition int - Plaque de plâtre, ThermalConductivity | Component 1, Finition int - Plaque de plâtre, SpecificHeatCapacity (J/kg/K) | Component 1, Finition int - Plaque de plâtre, MassDensity (kg/m3) | Component 1, Finition int - Plaque de plâtre, Embodied Energy | Component 1, Finition int - Plaque de plâtre, Embodied Carbon | Component 1, Finition int - Plaque de plâtre, Name | Component 1, Finition int - Plaque de plâtre, Participates in Collision Detection | Component 1 | Length (m) | Height (m) | GrossFootprintArea (m2) = NetFootprintArea (m2) | GrossSideArea (m2) = NetSideArea (m2) | GrossVolume (m3) = NetVolume (m3)
Cloison 98 isolée | R+1 | Mur (Classification ARCHICAD); Cloison (Classification ARCHICAD) | Finition int - Plaque de plâtre (4), Isolation - Laine de roche | 30 dB(A) |  |  |  |  |  |  |  |  | 0.304 | 2.5 | 0.02891 | 0.74375 | 0.072275 | Material Properties - Component 5, Finition int - Plaque de plâtre, ThermalConductivity: 0.8; Component 5, Finition int - Plaque de plâtre, SpecificHeatCapacity: 1000 J/kg/K; Component 5, Finition int - Plaque de plâtre, MassDensity: 1600 kg/m3; Component 5, Finition int - Plaque de plâtre, Embodied Energy: 1.45 (MJ/kg); Component 5, Finition int - Plaque de plâtre, Embodied Carbon: 0.22 (kgCO₂/kg); Component 5, Finition int - Plaque de plâtre, Name: Finition int - Plaque de plâtre; Component 5, Finition int - Plaque de plâtre, Participates in Collision Detection: no; Component 5: 4 with these values
Cloison 98 isolée | R+1 | Mur (Classification ARCHICAD); Cloison (Classification ARCHICAD) | Finition int - Plaque de plâtre (4), Isolation - Laine de roche | 30 dB(A) | 0.8 | 1000 | 1600 | 1.45 (MJ/kg) | 0.22 (kgCO₂/kg) | Finition int - Plaque de plâtre | no | 4 with these values | 0.55 | 2.5 | 0.05649 | 1.39125 | 0.141225
Cloison 98 isolée | R+2 | Mur (Classification ARCHICAD); Cloison (Classification ARCHICAD) | Finition int - Plaque de plâtre (4), Isolation - Laine de roche | 35 dB(A) |  |  |  |  |  |  |  |  | 0.476 | 2.5 | 0.04909 | 1.20625 | 0.122725 | Material Properties - Component 5, Finition int - Plaque de plâtre, ThermalConductivity: 0.8; Component 5, Finition int - Plaque de plâtre, SpecificHeatCapacity: 1000 J/kg/K; Component 5, Finition int - Plaque de plâtre, MassDensity: 1600 kg/m3; Component 5, Finition int - Plaque de plâtre, Embodied Energy: 1.45 (MJ/kg); Component 5, Finition int - Plaque de plâtre, Embodied Carbon: 0.22 (kgCO₂/kg); Component 5, Finition int - Plaque de plâtre, Name: Finition int - Plaque de plâtre; Component 5, Finition int - Plaque de plâtre, Participates in Collision Detection: no; Component 5: 4 with these values
Cloison 98 isolée | R+2 | Mur (Classification ARCHICAD); Cloison (Classification ARCHICAD) | Finition int - Plaque de plâtre (4), Isolation - Laine de roche | 30 dB(A) | 0.8 | 1000 | 1600 | 1.45 (MJ/kg) | 0.22 (kgCO₂/kg) | Finition int - Plaque de plâtre | no | 4 with these values | 0.48 | 2.49 | 0.04949 | 1.21139 | 0.12323
Cloison 98 isolée | R+2 | Mur (Classification ARCHICAD); Cloison (Classification ARCHICAD) | Finition int - Plaque de plâtre (4), Isolation - Laine de roche | 35 dB(A) | 0.8 | 1000 | 1600 | 1.45 (MJ/kg) | 0.22 (kgCO₂/kg) | Finition int - Plaque de plâtre | no | 4 with these values | 0.284 | 2.5 | 0.02691 | 0.69375 | 0.067275
Cloison 98 isolée | R+2 | Mur (Classification ARCHICAD); Cloison (Classification ARCHICAD) | Finition int - Plaque de plâtre (4), Isolation - Laine de roche | Non défini |  |  |  |  |  |  |  |  | 0.180798 | 2.5 | 0.0165898 | 0.435745 | 0.0414745 | Material Properties - Component 5, Finition int - Plaque de plâtre, ThermalConductivity: 0.8; Component 5, Finition int - Plaque de plâtre, SpecificHeatCapacity: 1000 J/kg/K; Component 5, Finition int - Plaque de plâtre, MassDensity: 1600 kg/m3; Component 5, Finition int - Plaque de plâtre, Embodied Energy: 1.45 (MJ/kg); Component 5, Finition int - Plaque de plâtre, Embodied Carbon: 0.22 (kgCO₂/kg); Component 5, Finition int - Plaque de plâtre, Name: Finition int - Plaque de plâtre; Component 5, Finition int - Plaque de plâtre, Participates in Collision Detection: no; Component 5: 4 with these values
Cloison 98 isolée | R+2 | Mur (Classification ARCHICAD); Cloison (Classification ARCHICAD) | Finition int - Plaque de plâtre (4), Isolation - Laine de roche | 30 dB(A) | 0.8 | 1000 | 1600 | 1.45 (MJ/kg) | 0.22 (kgCO₂/kg) | Finition int - Plaque de plâtre | no | 4 with these values | 0.76 | 2.5 | 0.05451 | 1.38375 | 0.136275
Cloison 98 isolée | R+2 | Mur (Classification ARCHICAD); Cloison (Classification ARCHICAD) | Finition int - Plaque de plâtre (4), Isolation - Laine de roche | 30 dB(A) |  |  |  |  |  |  |  |  | 0.443647 | 2.5 | 0.0428747 | 1.09287 | 0.107187 | Material Properties - Component 5, Finition int - Plaque de plâtre, ThermalConductivity: 0.8; Component 5, Finition int - Plaque de plâtre, SpecificHeatCapacity: 1000 J/kg/K; Component 5, Finition int - Plaque de plâtre, MassDensity: 1600 kg/m3; Component 5, Finition int - Plaque de plâtre, Embodied Energy: 1.45 (MJ/kg); Component 5, Finition int - Plaque de plâtre, Embodied Carbon: 0.22 (kgCO₂/kg); Component 5, Finition int - Plaque de plâtre, Name: Finition int - Plaque de plâtre; Component 5, Finition int - Plaque de plâtre, Participates in Collision Detection: no; Component 5: 4 with these values
Cloison 98 isolée | R+2 | Mur (Classification ARCHICAD); Cloison (Classification ARCHICAD) | Finition int - Plaque de plâtre (4), Isolation - Laine de roche | 30 dB(A) | 0.8 | 1000 | 1600 | 1.45 (MJ/kg) | 0.22 (kgCO₂/kg) | Finition int - Plaque de plâtre | no | 4 with these values | 0.93 | 2.5 | 0.094 | 2.2105 | 0.231373
Cloison 98 isolée | R+2 | Mur (Classification ARCHICAD); Cloison (Classification ARCHICAD) | Finition int - Plaque de plâtre (4), Isolation - Laine de roche | 30 dB(A) | 0.8 | 1000 | 1600 | 1.45 (MJ/kg) | 0.22 (kgCO₂/kg) | Finition int - Plaque de plâtre | no | 4 with these values | 0.576381 | 2.5 | 0.0576381 | 1.44095 | 0.144095
Cloison 98 isolée | R+2 | Mur (Classification ARCHICAD); Cloison (Classification ARCHICAD) | Finition int - Plaque de plâtre (4), Isolation - Laine de roche | 30 dB(A) | 0.8 | 1000 | 1600 | 1.45 (MJ/kg) | 0.22 (kgCO₂/kg) | Finition int - Plaque de plâtre | no | 4 with these values | 0.55 | 2.5 | 0.05649 | 1.39125 | 0.141225
Cloison 98 isolée | R+2 | Mur (Classification ARCHICAD); Cloison (Classification ARCHICAD) | Finition int - Plaque de plâtre (4), Isolation - Laine de roche | 30 dB(A) |  |  |  |  |  |  |  |  | 0.304 | 2.5 | 0.02891 | 0.74375 | 0.072275 | Material Properties - Component 5, Finition int - Plaque de plâtre, ThermalConductivity: 0.8; Component 5, Finition int - Plaque de plâtre, SpecificHeatCapacity: 1000 J/kg/K; Component 5, Finition int - Plaque de plâtre, MassDensity: 1600 kg/m3; Component 5, Finition int - Plaque de plâtre, Embodied Energy: 1.45 (MJ/kg); Component 5, Finition int - Plaque de plâtre, Embodied Carbon: 0.22 (kgCO₂/kg); Component 5, Finition int - Plaque de plâtre, Name: Finition int - Plaque de plâtre; Component 5, Finition int - Plaque de plâtre, Participates in Collision Detection: no; Component 5: 4 with these values
2 x Cloison 98 isolée | R+3 | Mur (Classification ARCHICAD); Cloison (Classification ARCHICAD) | Finition int - Plaque de plâtre (4), Isolation - Laine de roche | 30 dB(A) | 0.8 | 1000 | 1600 | 1.45 (MJ/kg) | 0.22 (kgCO₂/kg) | Finition int - Plaque de plâtre | no | 4 with these values | 0.543 | 2.5 | 0.05579 | 1.37375 | 0.139475
Cloison 98 isolée | R+3 | Mur (Classification ARCHICAD); Cloison (Classification ARCHICAD) | Finition int - Plaque de plâtre (4), Isolation - Laine de roche | 30 dB(A) |  |  |  |  |  |  |  |  | 0.485 | 2.5 | 0.04999 | 1.22875 | 0.124975 | Material Properties - Component 5, Finition int - Plaque de plâtre, ThermalConductivity: 0.8; Component 5, Finition int - Plaque de plâtre, SpecificHeatCapacity: 1000 J/kg/K; Component 5, Finition int - Plaque de plâtre, MassDensity: 1600 kg/m3; Component 5, Finition int - Plaque de plâtre, Embodied Energy: 1.45 (MJ/kg); Component 5, Finition int - Plaque de plâtre, Embodied Carbon: 0.22 (kgCO₂/kg); Component 5, Finition int - Plaque de plâtre, Name: Finition int - Plaque de plâtre; Component 5, Finition int - Plaque de plâtre, Participates in Collision Detection: no; Component 5: 4 with these values
Cloison 98 isolée | R+3 | Mur (Classification ARCHICAD); Cloison (Classification ARCHICAD) | Finition int - Plaque de plâtre (4), Isolation - Laine de roche | 30 dB(A) |  |  |  |  |  |  |  |  | 0.565 | 2.5 | 0.05501 | 1.39625 | 0.137525 | Material Properties - Component 5, Finition int - Plaque de plâtre, ThermalConductivity: 0.8; Component 5, Finition int - Plaque de plâtre, SpecificHeatCapacity: 1000 J/kg/K; Component 5, Finition int - Plaque de plâtre, MassDensity: 1600 kg/m3; Component 5, Finition int - Plaque de plâtre, Embodied Energy: 1.45 (MJ/kg); Component 5, Finition int - Plaque de plâtre, Embodied Carbon: 0.22 (kgCO₂/kg); Component 5, Finition int - Plaque de plâtre, Name: Finition int - Plaque de plâtre; Component 5, Finition int - Plaque de plâtre, Participates in Collision Detection: no; Component 5: 4 with these values
Cloison 98 isolée | R+3 | Mur (Classification ARCHICAD); Cloison (Classification ARCHICAD) | Finition int - Plaque de plâtre (4), Isolation - Laine de roche | 30 dB(A) | 0.8 | 1000 | 1600 | 1.45 (MJ/kg) | 0.22 (kgCO₂/kg) | Finition int - Plaque de plâtre | no | 4 with these values | 0.365367 | 2.5 | 0.0380267 | 0.929666 | 0.0950666
Cloison 98 isolée | R+3 | Mur (Classification ARCHICAD); Cloison (Classification ARCHICAD) | Finition int - Plaque de plâtre (4), Isolation - Laine de roche | 30 dB(A) | 0.8 | 1000 | 1600 | 1.45 (MJ/kg) | 0.22 (kgCO₂/kg) | Finition int - Plaque de plâtre | no | 4 with these values | 0.47 | 2.5 | 0.04849 | 1.19125 | 0.121225
Cloison 98 isolée | R+3 | Mur (Classification ARCHICAD); Cloison (Classification ARCHICAD) | Finition int - Plaque de plâtre (4), Isolation - Laine de roche | 30 dB(A) | 0.8 | 1000 | 1600 | 1.45 (MJ/kg) | 0.22 (kgCO₂/kg) | Finition int - Plaque de plâtre | no | 4 with these values | 0.464359 | 2.5 | 0.0479259 | 1.17715 | 0.119815
Cloison 98 isolée | R+3 | Mur (Classification ARCHICAD); Cloison (Classification ARCHICAD) | Finition int - Plaque de plâtre (4), Isolation - Laine de roche | 30 dB(A) | 0.8 | 1000 | 1600 | 1.45 (MJ/kg) | 0.22 (kgCO₂/kg) | Finition int - Plaque de plâtre | no | 4 with these values | 0.225154 | 2.5 | 0.0210254 | 0.546636 | 0.0525636
Cloison 98 isolée | R+3 | Mur (Classification ARCHICAD); Cloison (Classification ARCHICAD) | Finition int - Plaque de plâtre (4), Isolation - Laine de roche | 30 dB(A) |  |  |  |  |  |  |  |  | 0.221016 | 2.5 | 0.0206116 | 0.53629 | 0.051529 | Material Properties - Component 5, Finition int - Plaque de plâtre, ThermalConductivity: 0.8; Component 5, Finition int - Plaque de plâtre, SpecificHeatCapacity: 1000 J/kg/K; Component 5, Finition int - Plaque de plâtre, MassDensity: 1600 kg/m3; Component 5, Finition int - Plaque de plâtre, Embodied Energy: 1.45 (MJ/kg); Component 5, Finition int - Plaque de plâtre, Embodied Carbon: 0.22 (kgCO₂/kg); Component 5, Finition int - Plaque de plâtre, Name: Finition int - Plaque de plâtre; Component 5, Finition int - Plaque de plâtre, Participates in Collision Detection: no; Component 5: 4 with these values
Cloison 98 isolée | R+3 | Mur (Classification ARCHICAD); Cloison (Classification ARCHICAD) | Finition int - Plaque de plâtre (4), Isolation - Laine de roche | 30 dB(A) | 0.8 | 1000 | 1600 | 1.45 (MJ/kg) | 0.22 (kgCO₂/kg) | Finition int - Plaque de plâtre | no | 4 with these values | 0.76 | 2.5 | 0.07749 | 1.91625 | 0.193725
Cloison 98 isolée | R+3 | Mur (Classification ARCHICAD); Cloison (Classification ARCHICAD) | Finition int - Plaque de plâtre (4), Isolation - Laine de roche | 30 dB(A) | 0.8 | 1000 | 1600 | 1.45 (MJ/kg) | 0.22 (kgCO₂/kg) | Finition int - Plaque de plâtre | no | 4 with these values | 0.55 | 2.49 | 0.05649 | 1.38568 | 0.14066
Cloison 98 isolée | R+3 | Mur (Classification ARCHICAD); Cloison (Classification ARCHICAD) | Finition int - Plaque de plâtre (4), Isolation - Laine de roche | 30 dB(A) | 0.8 | 1000 | 1600 | 1.45 (MJ/kg) | 0.22 (kgCO₂/kg) | Finition int - Plaque de plâtre | no | 4 with these values | 0.338 | 2.5 | 0.03231 | 0.82875 | 0.080775
Cloison 98 isolée | R+3 | Mur (Classification ARCHICAD); Cloison (Classification ARCHICAD) | Finition int - Plaque de plâtre (4), Isolation - Laine de roche | 30 dB(A) | 0.8 | 1000 | 1600 | 1.45 (MJ/kg) | 0.22 (kgCO₂/kg) | Finition int - Plaque de plâtre | no | 4 with these values | 0.297365 | 2.5 | 0.0282465 | 0.727162 | 0.0706162
Cloison 98 isolée | R+3 | Mur (Classification ARCHICAD); Cloison (Classification ARCHICAD) | Finition int - Plaque de plâtre (4), Isolation - Laine de roche | 30 dB(A) | 0.8 | 1000 | 1600 | 1.45 (MJ/kg) | 0.22 (kgCO₂/kg) | Finition int - Plaque de plâtre | no | 4 with these values | 0.338 | 2.5 | 0.03529 | 0.86125 | 0.088225
Cloison 98 isolée | R+4 | Mur (Classification ARCHICAD); Cloison (Classification ARCHICAD) | Finition int - Plaque de plâtre (4), Isolation - Laine de roche | 30 dB(A) | 0.8 | 1000 | 1600 | 1.45 (MJ/kg) | 0.22 (kgCO₂/kg) | Finition int - Plaque de plâtre | no | 4 with these values | 0.603982 | 2.5 | 0.0618882 | 1.5262 | 0.15472
2 x Cloison 98 isolée | R+4 | Mur (Classification ARCHICAD); Cloison (Classification ARCHICAD) | Finition int - Plaque de plâtre (4), Isolation - Laine de roche | 30 dB(A) | 0.8 | 1000 | 1600 | 1.45 (MJ/kg) | 0.22 (kgCO₂/kg) | Finition int - Plaque de plâtre | no | 4 with these values | 0.383 | 2.48 | 0.03681 | 0.93372 | 0.0912888
Cloison 98 isolée | R+4 | Mur (Classification ARCHICAD); Cloison (Classification ARCHICAD) | Finition int - Plaque de plâtre (4), Isolation - Laine de roche | 35 dB(A) |  |  |  |  |  |  |  |  | 0.733407 | 2.48 | 0.0718507 | 1.80273 | 0.17819 | Material Properties - Component 5, Finition int - Plaque de plâtre, ThermalConductivity: 0.8; Component 5, Finition int - Plaque de plâtre, SpecificHeatCapacity: 1000 J/kg/K; Component 5, Finition int - Plaque de plâtre, MassDensity: 1600 kg/m3; Component 5, Finition int - Plaque de plâtre, Embodied Energy: 1.45 (MJ/kg); Component 5, Finition int - Plaque de plâtre, Embodied Carbon: 0.22 (kgCO₂/kg); Component 5, Finition int - Plaque de plâtre, Name: Finition int - Plaque de plâtre; Component 5, Finition int - Plaque de plâtre, Participates in Collision Detection: no; Component 5: 4 with these values
Cloison 98 isolée | R+4 | Mur (Classification ARCHICAD); Cloison (Classification ARCHICAD) | Finition int - Plaque de plâtre (4), Isolation - Laine de roche | 35 dB(A) |  |  |  |  |  |  |  |  | 0.419251 | 2.48 | 0.0434151 | 1.05586 | 0.107669 | Material Properties - Component 5, Finition int - Plaque de plâtre, ThermalConductivity: 0.8; Component 5, Finition int - Plaque de plâtre, SpecificHeatCapacity: 1000 J/kg/K; Component 5, Finition int - Plaque de plâtre, MassDensity: 1600 kg/m3; Component 5, Finition int - Plaque de plâtre, Embodied Energy: 1.45 (MJ/kg); Component 5, Finition int - Plaque de plâtre, Embodied Carbon: 0.22 (kgCO₂/kg); Component 5, Finition int - Plaque de plâtre, Name: Finition int - Plaque de plâtre; Component 5, Finition int - Plaque de plâtre, Participates in Collision Detection: no; Component 5: 4 with these values
Cloison 98 isolée | Rez-de-chaussée | Cloison (Classification ARCHICAD) | Finition int - Plaque de plâtre (4), Isolation - Laine de roche | Non défini | 0.8 | 1000 | 1600 | 1.45 (MJ/kg) | 0.22 (kgCO₂/kg) | Finition int - Plaque de plâtre | no | 4 with these values | 0.55 | 2.5 | 0.05649 | 1.39125 | 0.141225
Cloison 98 isolée | Rez-de-chaussée | Cloison (Classification ARCHICAD) | Finition int - Plaque de plâtre (4), Isolation - Laine de roche | Non défini | 0.8 | 1000 | 1600 | 1.45 (MJ/kg) | 0.22 (kgCO₂/kg) | Finition int - Plaque de plâtre | no | 4 with these values | 0.55 | 2.5 | 0.05351 | 1.35875 | 0.133775
Cloison 98 isolée | Rez-de-chaussée | Cloison (Classification ARCHICAD) | Finition int - Plaque de plâtre (4), Isolation - Laine de roche | Non défini |  |  |  |  |  |  |  |  | 0.56 | 2.5 | 0.05451 | 1.38375 | 0.136275 | Material Properties - Component 5, Finition int - Plaque de plâtre, ThermalConductivity: 0.8; Component 5, Finition int - Plaque de plâtre, SpecificHeatCapacity: 1000 J/kg/K; Component 5, Finition int - Plaque de plâtre, MassDensity: 1600 kg/m3; Component 5, Finition int - Plaque de plâtre, Embodied Energy: 1.45 (MJ/kg); Component 5, Finition int - Plaque de plâtre, Embodied Carbon: 0.22 (kgCO₂/kg); Component 5, Finition int - Plaque de plâtre, Name: Finition int - Plaque de plâtre; Component 5, Finition int - Plaque de plâtre, Participates in Collision Detection: no; Component 5: 4 with these values
Cloison 98 isolée | Rez-de-chaussée | Cloison (Classification ARCHICAD) | Finition int - Plaque de plâtre (4), Isolation - Laine de roche | Non défini |  |  |  |  |  |  |  |  | 0.477449 | 2.5 | 0.0492349 | 1.20987 | 0.123087 | Material Properties - Component 5, Finition int - Plaque de plâtre, ThermalConductivity: 0.8; Component 5, Finition int - Plaque de plâtre, SpecificHeatCapacity: 1000 J/kg/K; Component 5, Finition int - Plaque de plâtre, MassDensity: 1600 kg/m3; Component 5, Finition int - Plaque de plâtre, Embodied Energy: 1.45 (MJ/kg); Component 5, Finition int - Plaque de plâtre, Embodied Carbon: 0.22 (kgCO₂/kg); Component 5, Finition int - Plaque de plâtre, Name: Finition int - Plaque de plâtre; Component 5, Finition int - Plaque de plâtre, Participates in Collision Detection: no; Component 5: 4 with these values
Cloison 98 isolée | Rez-de-chaussée | Cloison (Classification ARCHICAD) | Finition int - Plaque de plâtre (4), Isolation - Laine de roche | Non défini | 0.8 | 1000 | 1600 | 1.45 (MJ/kg) | 0.22 (kgCO₂/kg) | Finition int - Plaque de plâtre | no | 4 with these values | 0.423 | 2.5 | 0.04081 | 1.04125 | 0.102025
Cloison 98 isolée | Rez-de-chaussée | Cloison (Classification ARCHICAD) | Finition int - Plaque de plâtre (4), Isolation - Laine de roche | Non défini | 0.8 | 1000 | 1600 | 1.45 (MJ/kg) | 0.22 (kgCO₂/kg) | Finition int - Plaque de plâtre | no | 4 with these values | 0.750476 | 2.5 | 0.0765376 | 1.89244 | 0.191344
Cloison 98 isolée | Rez-de-chaussée | Cloison (Classification ARCHICAD) | Finition int - Plaque de plâtre (4), Isolation - Laine de roche | Non défini |  |  |  |  |  |  |  |  | 0.304 | 2.5 | 0.02891 | 0.74375 | 0.072275 | Material Properties - Component 5, Finition int - Plaque de plâtre, ThermalConductivity: 0.8; Component 5, Finition int - Plaque de plâtre, SpecificHeatCapacity: 1000 J/kg/K; Component 5, Finition int - Plaque de plâtre, MassDensity: 1600 kg/m3; Component 5, Finition int - Plaque de plâtre, Embodied Energy: 1.45 (MJ/kg); Component 5, Finition int - Plaque de plâtre, Embodied Carbon: 0.22 (kgCO₂/kg); Component 5, Finition int - Plaque de plâtre, Name: Finition int - Plaque de plâtre; Component 5, Finition int - Plaque de plâtre, Participates in Collision Detection: no; Component 5: 4 with these values

# IfcWall: Acrotère plancher 21 isolée TERR ACCE BARDAGE BOIS 285 x 1240, Muret béton 20cm
In: R+3
Type - ElementType: PARAPET; PredefinedType: USERDEFINED
Description: Acrotère et GD terrasses; Classification: Mur d'acrotère (Classification ARCHICAD); Material: Finition ext - Bardage bois, Bois - Lattage, Béton, Etanchéité - Bitume, Finition ext - Crépis, Métal - Aluminium
Pset_WallCommon - AcousticRating: Non défini; ThermalTransmittance: 0; LoadBearing: yes; IsExternal: yes
PSET_Murs_ARCHI - Emplacement: Superstructure; Type: Mur béton 20cm; Destination: Muret formant garde-corps; Matériaux: BETON
Propriétés DCE - Numéro de LOT: LOT 04; LOT 05; Numéro article: L05.2.3.2
AC_Pset_RenovationAndPhasing - Renovation Status: Existing
Material Properties - Component 6, Finition ext - Bardage bois, ThermalConductivity: 0.14; Component 6, Finition ext - Bardage bois, SpecificHeatCapacity: 2300 J/kg/K; Component 6, Finition ext - Bardage bois, MassDensity: 500 kg/m3; Component 6, Finition ext - Bardage bois, Embodied Energy: 10 (MJ/kg); Component 6, Finition ext - Bardage bois, Embodied Carbon: 0.36 (kgCO₂/kg); Component 6, Finition ext - Bardage bois, Name: Finition ext - Bardage bois; Component 6, Finition ext - Bardage bois, Participates in Collision Detection: no; Component 4, Bois - Lattage, ThermalConductivity: 0.13; Component 4, Bois - Lattage, SpecificHeatCapacity: 1600 J/kg/K; Component 4, Bois - Lattage, MassDensity: 500 kg/m3; Component 4, Bois - Lattage, Embodied Energy: 6.95 (MJ/kg); Component 4, Bois - Lattage, Embodied Carbon: 0.29 (kgCO₂/kg); Component 4, Bois - Lattage, Name: Bois - Lattage; Component 4, Bois - Lattage, Participates in Collision Detection: yes; Component 3, Béton, ThermalConductivity: 2.3; Component 3, Béton, SpecificHeatCapacity: 1000 J/kg/K; Component 3, Béton, MassDensity: 2300 kg/m3; Component 3, Béton, Embodied Energy: 1.92 (MJ/kg); Component 3, Béton, Embodied Carbon: 0.198 (kgCO₂/kg); Component 3, Béton, Name: Béton; Component 3, Béton, Participates in Collision Detection: yes; Component 2, Etanchéité - Bitume, ThermalConductivity: 0.23; Component 2, Etanchéité - Bitume, SpecificHeatCapacity: 1000 J/kg/K; Component 2, Etanchéité - Bitume, MassDensity: 1100 kg/m3; Component 2, Etanchéité - Bitume, Embodied Energy: 2.86 (MJ/kg); Component 2, Etanchéité - Bitume, Embodied Carbon: 0.066 (kgCO₂/kg); Component 2, Etanchéité - Bitume, Name: Etanchéité - Bitume; Component 2, Etanchéité - Bitume, Participates in Collision Detection: no; Component 5, Finition ext - Crépis, ThermalConductivity: 0.8; Component 5, Finition ext - Crépis, SpecificHeatCapacity: 1000 J/kg/K; Component 5, Finition ext - Crépis, MassDensity: 1600 kg/m3; Component 5, Finition ext - Crépis, Embodied Energy: 1.4 (MJ/kg); Component 5, Finition ext - Crépis, Embodied Carbon: 0.09 (kgCO₂/kg); Component 5, Finition ext - Crépis, Name: Finition ext - Crépis; Component 5, Finition ext - Crépis, Participates in Collision Detection: no; Component 1, Métal - Aluminium, ThermalConductivity: 160; Component 1, Métal - Aluminium, SpecificHeatCapacity: 880 J/kg/K; Component 1, Métal - Aluminium, MassDensity: 2800 kg/m3; Component 1, Métal - Aluminium, Embodied Energy: 155 (MJ/kg); Component 1, Métal - Aluminium, Embodied Carbon: 9.16 (kgCO₂/kg); Component 1, Métal - Aluminium, Name: Métal - Aluminium; Component 1, Métal - Aluminium, Participates in Collision Detection: yes
BaseQuantities - Length: 3.81348 m; Height: 1.24 m; Width: 0.285485 m; GrossFootprintArea: 1.05195 m2; NetFootprintArea: 1.05195 m2; GrossSideArea: 4.88006 m2; NetSideArea: 4.88006 m2; GrossVolume: 1.28838 m3; NetVolume: 1.28838 m3

# IfcWall: Acrotère plancher 21 isolée TERR ACCE BARDAGE BOIS 285 x 1250 (2)
In: R+3
Type - ElementType: PARAPET; PredefinedType: USERDEFINED
Description: Acrotère et GD terrasses; Classification: Mur d'acrotère (Classification ARCHICAD); Material: Finition ext - Bardage bois, Bois - Lattage, Béton, Etanchéité - Bitume, Finition ext - Crépis, Métal - Aluminium
Pset_WallCommon - AcousticRating: Non défini; ThermalTransmittance: 0; LoadBearing: yes; IsExternal: yes
PSET_Murs_ARCHI - Emplacement: Superstructure; Type: Mur béton 20cm; Destination: Muret formant garde-corps; Matériaux: BETON
Propriétés DCE - Numéro de LOT: LOT 04; LOT 05; Numéro article: L05.2.3.2
AC_Pset_RenovationAndPhasing - Renovation Status: Existing
Material Properties - Component 6, Finition ext - Bardage bois, ThermalConductivity: 0.14; Component 6, Finition ext - Bardage bois, SpecificHeatCapacity: 2300 J/kg/K; Component 6, Finition ext - Bardage bois, MassDensity: 500 kg/m3; Component 6, Finition ext - Bardage bois, Embodied Energy: 10 (MJ/kg); Component 6, Finition ext - Bardage bois, Embodied Carbon: 0.36 (kgCO₂/kg); Component 6, Finition ext - Bardage bois, Name: Finition ext - Bardage bois; Component 6, Finition ext - Bardage bois, Participates in Collision Detection: no; Component 4, Bois - Lattage, ThermalConductivity: 0.13; Component 4, Bois - Lattage, SpecificHeatCapacity: 1600 J/kg/K; Component 4, Bois - Lattage, MassDensity: 500 kg/m3; Component 4, Bois - Lattage, Embodied Energy: 6.95 (MJ/kg); Component 4, Bois - Lattage, Embodied Carbon: 0.29 (kgCO₂/kg); Component 4, Bois - Lattage, Name: Bois - Lattage; Component 4, Bois - Lattage, Participates in Collision Detection: yes; Component 3, Béton, ThermalConductivity: 2.3; Component 3, Béton, SpecificHeatCapacity: 1000 J/kg/K; Component 3, Béton, MassDensity: 2300 kg/m3; Component 3, Béton, Embodied Energy: 1.92 (MJ/kg); Component 3, Béton, Embodied Carbon: 0.198 (kgCO₂/kg); Component 3, Béton, Name: Béton; Component 3, Béton, Participates in Collision Detection: yes; Component 2, Etanchéité - Bitume, ThermalConductivity: 0.23; Component 2, Etanchéité - Bitume, SpecificHeatCapacity: 1000 J/kg/K; Component 2, Etanchéité - Bitume, MassDensity: 1100 kg/m3; Component 2, Etanchéité - Bitume, Embodied Energy: 2.86 (MJ/kg); Component 2, Etanchéité - Bitume, Embodied Carbon: 0.066 (kgCO₂/kg); Component 2, Etanchéité - Bitume, Name: Etanchéité - Bitume; Component 2, Etanchéité - Bitume, Participates in Collision Detection: no; Component 5, Finition ext - Crépis, ThermalConductivity: 0.8; Component 5, Finition ext - Crépis, SpecificHeatCapacity: 1000 J/kg/K; Component 5, Finition ext - Crépis, MassDensity: 1600 kg/m3; Component 5, Finition ext - Crépis, Embodied Energy: 1.4 (MJ/kg); Component 5, Finition ext - Crépis, Embodied Carbon: 0.09 (kgCO₂/kg); Component 5, Finition ext - Crépis, Name: Finition ext - Crépis; Component 5, Finition ext - Crépis, Participates in Collision Detection: no; Component 1, Métal - Aluminium, ThermalConductivity: 160; Component 1, Métal - Aluminium, SpecificHeatCapacity: 880 J/kg/K; Component 1, Métal - Aluminium, MassDensity: 2800 kg/m3; Component 1, Métal - Aluminium, Embodied Energy: 155 (MJ/kg); Component 1, Métal - Aluminium, Embodied Carbon: 9.16 (kgCO₂/kg); Component 1, Métal - Aluminium, Name: Métal - Aluminium; Component 1, Métal - Aluminium, Participates in Collision Detection: yes
BaseQuantities - Height: 1.2499 m; Width: 0.285485 m
Name | Length (m) | GrossFootprintArea (m2) = NetFootprintArea (m2) | GrossSideArea (m2) = NetSideArea (m2) | GrossVolume (m3) = NetVolume (m3)
Muret béton 20cm | 7.38135 | 2.12839 | 9.59058 | 2.62692
Muret béton 20cm | 1.06 | 0.268101 | 1.34866 | 0.330581

# IfcWall: Acrotère pour plancher 20 PAREMENT PIERRE 307 x 680 (3)
In: R+1
Type - ElementType: PARAPET; PredefinedType: USERDEFINED
Description: Acrotère et GD terrasses; Classification: Mur d'acrotère (Classification ARCHICAD)
Pset_WallCommon - AcousticRating: Non défini; ThermalTransmittance: 0; LoadBearing: yes; IsExternal: yes
PSET_Murs_ARCHI - Emplacement: Superstructure; Type: Mur béton 20cm; Destination: Muret formant garde-corps; Acrotère; Matériaux: BETON
Propriétés DCE - Numéro de LOT: LOT 04; Numéro article: L04.2.21.1.7
AC_Pset_RenovationAndPhasing - Renovation Status: Existing
Material Properties - Component 4, Pierre, ThermalConductivity: 2.3; Component 4, Pierre, SpecificHeatCapacity: 1000 J/kg/K; Component 4, Pierre, MassDensity: 2600 kg/m3; Component 4, Pierre, Embodied Energy: 1.2 (MJ/kg); Component 4, Pierre, Embodied Carbon: 0.08 (kgCO₂/kg); Component 4, Pierre, Name: Pierre; Component 4, Pierre, Participates in Collision Detection: yes; Component 3, Béton, ThermalConductivity: 2.3; Component 3, Béton, SpecificHeatCapacity: 1000 J/kg/K; Component 3, Béton, MassDensity: 2300 kg/m3; Component 3, Béton, Embodied Energy: 1.92 (MJ/kg); Component 3, Béton, Embodied Carbon: 0.198 (kgCO₂/kg); Component 3, Béton, Name: Béton; Component 3, Béton, Participates in Collision Detection: yes; Component 2, Etanchéité - Bitume, ThermalConductivity: 0.23; Component 2, Etanchéité - Bitume, SpecificHeatCapacity: 1000 J/kg/K; Component 2, Etanchéité - Bitume, MassDensity: 1100 kg/m3; Component 2, Etanchéité - Bitume, Embodied Energy: 2.86 (MJ/kg); Component 2, Etanchéité - Bitume, Embodied Carbon: 0.066 (kgCO₂/kg); Component 2, Etanchéité - Bitume, Name: Etanchéité - Bitume; Component 2, Etanchéité - Bitume, Participates in Collision Detection: no; Component 1, Métal - Aluminium, ThermalConductivity: 160; Component 1, Métal - Aluminium, SpecificHeatCapacity: 880 J/kg/K; Component 1, Métal - Aluminium, MassDensity: 2800 kg/m3; Component 1, Métal - Aluminium, Embodied Energy: 155 (MJ/kg); Component 1, Métal - Aluminium, Embodied Carbon: 9.16 (kgCO₂/kg); Component 1, Métal - Aluminium, Name: Métal - Aluminium; Component 1, Métal - Aluminium, Participates in Collision Detection: yes
BaseQuantities - Height: 0.68 m; Width: 0.307485 m
Name | Material | Length (m) | GrossFootprintArea (m2) = NetFootprintArea (m2) | GrossSideArea (m2) = NetSideArea (m2) | GrossVolume (m3) = NetVolume (m3)
Muret béton 20cm | Pierre, Béton, Etanchéité - Bitume, Métal - Aluminium | 4.87444 | 1.44764 | 3.17279 | 0.774919
Muret béton 20cm | Métal - Aluminium, Etanchéité - Bitume, Béton, Pierre | 3.89571 | 1.1174 | 2.50789 | 0.727175
Muret béton 20cm | Pierre, Béton, Etanchéité - Bitume, Métal - Aluminium | 0.149485 | 0.0448104 | 0.107568 | 0.0303873

# IfcWall: Acrotère pour plancher 20 isolé 242 x 680, Muret béton 20cm
In: R+1
Type - ElementType: PARAPET; PredefinedType: USERDEFINED
Description: Acrotère et GD terrasses; Classification: Mur d'acrotère (Classification ARCHICAD); Material: Finition ext - Crépis (2), Béton, Etanchéité - Bitume, Métal - Aluminium
Pset_WallCommon - AcousticRating: Non défini; ThermalTransmittance: 0; LoadBearing: yes; IsExternal: yes
PSET_Murs_ARCHI - Emplacement: Superstructure; Type: Mur béton 20cm; Destination: Muret formant garde-corps; Acrotère; Matériaux: BETON
Propriétés DCE - Numéro de LOT: LOT 04; LOT 16; Numéro article: L16.2.1
AC_Pset_RenovationAndPhasing - Renovation Status: Existing
Material Properties - Component 4, Finition ext - Crépis, ThermalConductivity: 0.8; Component 4, Finition ext - Crépis, SpecificHeatCapacity: 1000 J/kg/K; Component 4, Finition ext - Crépis, MassDensity: 1600 kg/m3; Component 4, Finition ext - Crépis, Embodied Energy: 1.4 (MJ/kg); Component 4, Finition ext - Crépis, Embodied Carbon: 0.09 (kgCO₂/kg); Component 4, Finition ext - Crépis, Name: Finition ext - Crépis; Component 4, Finition ext - Crépis, Participates in Collision Detection: no; Component 3, Béton, ThermalConductivity: 2.3; Component 3, Béton, SpecificHeatCapacity: 1000 J/kg/K; Component 3, Béton, MassDensity: 2300 kg/m3; Component 3, Béton, Embodied Energy: 1.92 (MJ/kg); Component 3, Béton, Embodied Carbon: 0.198 (kgCO₂/kg); Component 3, Béton, Name: Béton; Component 3, Béton, Participates in Collision Detection: yes; Component 2, Etanchéité - Bitume, ThermalConductivity: 0.23; Component 2, Etanchéité - Bitume, SpecificHeatCapacity: 1000 J/kg/K; Component 2, Etanchéité - Bitume, MassDensity: 1100 kg/m3; Component 2, Etanchéité - Bitume, Embodied Energy: 2.86 (MJ/kg); Component 2, Etanchéité - Bitume, Embodied Carbon: 0.066 (kgCO₂/kg); Component 2, Etanchéité - Bitume, Name: Etanchéité - Bitume; Component 2, Etanchéité - Bitume, Participates in Collision Detection: no; Component 1, Métal - Aluminium, ThermalConductivity: 160; Component 1, Métal - Aluminium, SpecificHeatCapacity: 880 J/kg/K; Component 1, Métal - Aluminium, MassDensity: 2800 kg/m3; Component 1, Métal - Aluminium, Embodied Energy: 155 (MJ/kg); Component 1, Métal - Aluminium, Embodied Carbon: 9.16 (kgCO₂/kg); Component 1, Métal - Aluminium, Name: Métal - Aluminium; Component 1, Métal - Aluminium, Participates in Collision Detection: yes; Component 4: 2 with these values
BaseQuantities - Length: 4.4618 m; Height: 0.68 m; Width: 0.242485 m; GrossFootprintArea: 1.04163 m2; NetFootprintArea: 1.04163 m2; GrossSideArea: 3.33107 m2; NetSideArea: 3.33107 m2; GrossVolume: 0.673875 m3; NetVolume: 0.673875 m3

# IfcWall: Acrotère pour plancher 21 isolée 242 x 1330 (4)
In: R+4
Type - ElementType: PARAPET; PredefinedType: USERDEFINED
Description: Acrotère et GD terrasses; Classification: Mur d'acrotère (Classification ARCHICAD)
Pset_WallCommon - AcousticRating: Non défini; ThermalTransmittance: 0; LoadBearing: yes; IsExternal: yes
PSET_Murs_ARCHI - Emplacement: Superstructure; Type: Mur béton 20cm; Destination: Muret formant garde-corps; Matériaux: BETON
Propriétés DCE - Numéro de LOT: LOT 04; LOT 16; Numéro article: L16.2.1
AC_Pset_RenovationAndPhasing - Renovation Status: Existing
Material Properties - Component 3, Béton, ThermalConductivity: 2.3; Component 3, Béton, SpecificHeatCapacity: 1000 J/kg/K; Component 3, Béton, MassDensity: 2300 kg/m3; Component 3, Béton, Embodied Energy: 1.92 (MJ/kg); Component 3, Béton, Embodied Carbon: 0.198 (kgCO₂/kg); Component 3, Béton, Name: Béton; Component 3, Béton, Participates in Collision Detection: yes; Component 2, Etanchéité - Bitume, ThermalConductivity: 0.23; Component 2, Etanchéité - Bitume, SpecificHeatCapacity: 1000 J/kg/K; Component 2, Etanchéité - Bitume, MassDensity: 1100 kg/m3; Component 2, Etanchéité - Bitume, Embodied Energy: 2.86 (MJ/kg); Component 2, Etanchéité - Bitume, Embodied Carbon: 0.066 (kgCO₂/kg); Component 2, Etanchéité - Bitume, Name: Etanchéité - Bitume; Component 2, Etanchéité - Bitume, Participates in Collision Detection: no; Component 1, Métal - Aluminium, ThermalConductivity: 160; Component 1, Métal - Aluminium, SpecificHeatCapacity: 880 J/kg/K; Component 1, Métal - Aluminium, MassDensity: 2800 kg/m3; Component 1, Métal - Aluminium, Embodied Energy: 155 (MJ/kg); Component 1, Métal - Aluminium, Embodied Carbon: 9.16 (kgCO₂/kg); Component 1, Métal - Aluminium, Name: Métal - Aluminium; Component 1, Métal - Aluminium, Participates in Collision Detection: yes
BaseQuantities - Height: 1.33 m; Width: 0.242485 m
Name | Material | Length (m) | GrossFootprintArea (m2) = NetFootprintArea (m2) | GrossSideArea (m2) = NetSideArea (m2) | GrossVolume (m3) = NetVolume (m3)
Muret béton 20cm | Finition ext - Crépis (2), Béton, Etanchéité - Bitume, Métal - Aluminium | 2.65407 | 0.594543 | 3.64192 | 0.778144 | Material Properties - Component 4, Finition ext - Crépis, ThermalConductivity: 0.8; Component 4, Finition ext - Crépis, SpecificHeatCapacity: 1000 J/kg/K; Component 4, Finition ext - Crépis, MassDensity: 1600 kg/m3; Component 4, Finition ext - Crépis, Embodied Energy: 1.4 (MJ/kg); Component 4, Finition ext - Crépis, Embodied Carbon: 0.09 (kgCO₂/kg); Component 4, Finition ext - Crépis, Name: Finition ext - Crépis; Component 4, Finition ext - Crépis, Participates in Collision Detection: no; Component 4: 2 with these values
Muret béton 20cm | Métal - Aluminium, Finition ext - Crépis (2), Etanchéité - Bitume, Béton | 6.32862 | 1.50462 | 8.8456 | 1.95599 | Material Properties - Component 5, Finition ext - Crépis, ThermalConductivity: 0.8; Component 5, Finition ext - Crépis, SpecificHeatCapacity: 1000 J/kg/K; Component 5, Finition ext - Crépis, MassDensity: 1600 kg/m3; Component 5, Finition ext - Crépis, Embodied Energy: 1.4 (MJ/kg); Component 5, Finition ext - Crépis, Embodied Carbon: 0.09 (kgCO₂/kg); Component 5, Finition ext - Crépis, Name: Finition ext - Crépis; Component 5, Finition ext - Crépis, Participates in Collision Detection: no; Component 5: 2 with these values
Muret béton 20cm | Finition ext - Crépis (2), Béton, Etanchéité - Bitume, Métal - Aluminium | 3.03 | 0.741149 | 4.21295 | 0.970786 | Material Properties - Component 4, Finition ext - Crépis, ThermalConductivity: 0.8; Component 4, Finition ext - Crépis, SpecificHeatCapacity: 1000 J/kg/K; Component 4, Finition ext - Crépis, MassDensity: 1600 kg/m3; Component 4, Finition ext - Crépis, Embodied Energy: 1.4 (MJ/kg); Component 4, Finition ext - Crépis, Embodied Carbon: 0.09 (kgCO₂/kg); Component 4, Finition ext - Crépis, Name: Finition ext - Crépis; Component 4, Finition ext - Crépis, Participates in Collision Detection: no; Component 4: 2 with these values
Muret béton 20cm | Métal - Aluminium, Finition ext - Crépis (2), Etanchéité - Bitume, Béton | 3.98 | 0.880006 | 5.46595 | 1.15083 | Material Properties - Component 5, Finition ext - Crépis, ThermalConductivity: 0.8; Component 5, Finition ext - Crépis, SpecificHeatCapacity: 1000 J/kg/K; Component 5, Finition ext - Crépis, MassDensity: 1600 kg/m3; Component 5, Finition ext - Crépis, Embodied Energy: 1.4 (MJ/kg); Component 5, Finition ext - Crépis, Embodied Carbon: 0.09 (kgCO₂/kg); Component 5, Finition ext - Crépis, Name: Finition ext - Crépis; Component 5, Finition ext - Crépis, Participates in Collision Detection: no; Component 5: 2 with these values

# IfcWall: Acrotère pour plancher 21 isolée 242 x 580 (7)
In: R+3
Type - ElementType: PARAPET; PredefinedType: USERDEFINED
Description: Acrotère et GD terrasses; Classification: Mur d'acrotère (Classification ARCHICAD)
Pset_WallCommon - AcousticRating: Non défini; ThermalTransmittance: 0; LoadBearing: yes; IsExternal: yes
PSET_Murs_ARCHI - Emplacement: Superstructure; Type: Mur béton 20cm; Destination: Acrotère; Matériaux: BETON
Propriétés DCE - Numéro de LOT: LOT 04; LOT 16; Numéro article: L16.2.1
AC_Pset_RenovationAndPhasing - Renovation Status: Existing
Material Properties - Component 3, Béton, ThermalConductivity: 2.3; Component 3, Béton, SpecificHeatCapacity: 1000 J/kg/K; Component 3, Béton, MassDensity: 2300 kg/m3; Component 3, Béton, Embodied Energy: 1.92 (MJ/kg); Component 3, Béton, Embodied Carbon: 0.198 (kgCO₂/kg); Component 3, Béton, Name: Béton; Component 3, Béton, Participates in Collision Detection: yes; Component 2, Etanchéité - Bitume, ThermalConductivity: 0.23; Component 2, Etanchéité - Bitume, SpecificHeatCapacity: 1000 J/kg/K; Component 2, Etanchéité - Bitume, MassDensity: 1100 kg/m3; Component 2, Etanchéité - Bitume, Embodied Energy: 2.86 (MJ/kg); Component 2, Etanchéité - Bitume, Embodied Carbon: 0.066 (kgCO₂/kg); Component 2, Etanchéité - Bitume, Name: Etanchéité - Bitume; Component 2, Etanchéité - Bitume, Participates in Collision Detection: no; Component 1, Métal - Aluminium, ThermalConductivity: 160; Component 1, Métal - Aluminium, SpecificHeatCapacity: 880 J/kg/K; Component 1, Métal - Aluminium, MassDensity: 2800 kg/m3; Component 1, Métal - Aluminium, Embodied Energy: 155 (MJ/kg); Component 1, Métal - Aluminium, Embodied Carbon: 9.16 (kgCO₂/kg); Component 1, Métal - Aluminium, Name: Métal - Aluminium; Component 1, Métal - Aluminium, Participates in Collision Detection: yes
BaseQuantities - Height: 0.58 m; Width: 0.242485 m
Name | Material | Component 4, Finition ext - Crépis, ThermalConductivity | Component 4, Finition ext - Crépis, SpecificHeatCapacity (J/kg/K) | Component 4, Finition ext - Crépis, MassDensity (kg/m3) | Component 4, Finition ext - Crépis, Embodied Energy | Component 4, Finition ext - Crépis, Embodied Carbon | Component 4, Finition ext - Crépis, Name | Component 4, Finition ext - Crépis, Participates in Collision Detection | Component 4 | Length (m) | GrossFootprintArea (m2) = NetFootprintArea (m2) | GrossSideArea (m2) = NetSideArea (m2) | GrossVolume (m3) = NetVolume (m3)
Muret béton 20cm | Finition ext - Crépis (2), Béton, Etanchéité - Bitume, Métal - Aluminium | 0.8 | 1000 | 1600 | 1.4 (MJ/kg) | 0.09 (kgCO₂/kg) | Finition ext - Crépis | no | 2 with these values | 1.09376 | 0.233146 | 0.665958 | 0.131259
Muret béton 20cm | Finition ext - Crépis (2), Béton, Etanchéité - Bitume, Métal - Aluminium | 0.8 | 1000 | 1600 | 1.4 (MJ/kg) | 0.09 (kgCO₂/kg) | Finition ext - Crépis | no | 2 with these values | 2.07621 | 0.496255 | 1.31405 | 0.280061
Muret béton 20cm | Métal - Aluminium, Finition ext - Crépis (2), Etanchéité - Bitume, Béton |  |  |  |  |  |  |  |  | 3.70244 | 0.858909 | 2.34322 | 0.484227 | Material Properties - Component 5, Finition ext - Crépis, ThermalConductivity: 0.8; Component 5, Finition ext - Crépis, SpecificHeatCapacity: 1000 J/kg/K; Component 5, Finition ext - Crépis, MassDensity: 1600 kg/m3; Component 5, Finition ext - Crépis, Embodied Energy: 1.4 (MJ/kg); Component 5, Finition ext - Crépis, Embodied Carbon: 0.09 (kgCO₂/kg); Component 5, Finition ext - Crépis, Name: Finition ext - Crépis; Component 5, Finition ext - Crépis, Participates in Collision Detection: no; Component 5: 2 with these values
Muret béton 20cm | Métal - Aluminium, Finition ext - Crépis (2), Etanchéité - Bitume, Béton |  |  |  |  |  |  |  |  | 1.875 | 0.398289 | 1.16578 | 0.223461 | Material Properties - Component 5, Finition ext - Crépis, ThermalConductivity: 0.8; Component 5, Finition ext - Crépis, SpecificHeatCapacity: 1000 J/kg/K; Component 5, Finition ext - Crépis, MassDensity: 1600 kg/m3; Component 5, Finition ext - Crépis, Embodied Energy: 1.4 (MJ/kg); Component 5, Finition ext - Crépis, Embodied Carbon: 0.09 (kgCO₂/kg); Component 5, Finition ext - Crépis, Name: Finition ext - Crépis; Component 5, Finition ext - Crépis, Participates in Collision Detection: no; Component 5: 2 with these values
Muret béton 20cm | Finition ext - Crépis (2), Béton, Etanchéité - Bitume, Métal - Aluminium | 0.8 | 1000 | 1600 | 1.4 (MJ/kg) | 0.09 (kgCO₂/kg) | Finition ext - Crépis | no | 2 with these values | 6.24474 | 1.444 | 3.93873 | 0.812791
Muret béton 20cm | Finition ext - Crépis (2), Béton, Etanchéité - Bitume, Métal - Aluminium | 0.8 | 1000 | 1600 | 1.4 (MJ/kg) | 0.09 (kgCO₂/kg) | Finition ext - Crépis | no | 2 with these values | 9.90053 | 2.33248 | 6.27062 | 1.31435
Muret béton 20cm | Métal - Aluminium, Finition ext - Crépis (2), Etanchéité - Bitume, Béton |  |  |  |  |  |  |  |  | 11.2897 | 2.61334 | 7.12871 | 1.47175 | Material Properties - Component 5, Finition ext - Crépis, ThermalConductivity: 0.8; Component 5, Finition ext - Crépis, SpecificHeatCapacity: 1000 J/kg/K; Component 5, Finition ext - Crépis, MassDensity: 1600 kg/m3; Component 5, Finition ext - Crépis, Embodied Energy: 1.4 (MJ/kg); Component 5, Finition ext - Crépis, Embodied Carbon: 0.09 (kgCO₂/kg); Component 5, Finition ext - Crépis, Name: Finition ext - Crépis; Component 5, Finition ext - Crépis, Participates in Collision Detection: no; Component 5: 2 with these values

# IfcWall: Acrotère pour plancher 21 isolée BARDAGE BOIS 292 x 1310 (3)
In: R+4
Type - ElementType: PARAPET; PredefinedType: USERDEFINED
Description: Acrotère et GD terrasses; Classification: Mur d'acrotère (Classification ARCHICAD); Material: Métal - Aluminium, Finition ext - Crépis, Etanchéité - Bitume, Béton, Bois - Lattage, Finition ext - Bardage bois
Pset_WallCommon - AcousticRating: Non défini; ThermalTransmittance: 0; LoadBearing: yes; IsExternal: yes
PSET_Murs_ARCHI - Emplacement: Superstructure; Type: Mur béton 20cm; Destination: Muret formant garde-corps; Matériaux: BETON
Propriétés DCE - Numéro de LOT: LOT 04; LOT 05; Numéro article: L05.2.3.2
AC_Pset_RenovationAndPhasing - Renovation Status: Existing
Material Properties - Component 1, Métal - Aluminium, ThermalConductivity: 160; Component 1, Métal - Aluminium, SpecificHeatCapacity: 880 J/kg/K; Component 1, Métal - Aluminium, MassDensity: 2800 kg/m3; Component 1, Métal - Aluminium, Embodied Energy: 155 (MJ/kg); Component 1, Métal - Aluminium, Embodied Carbon: 9.16 (kgCO₂/kg); Component 1, Métal - Aluminium, Name: Métal - Aluminium; Component 1, Métal - Aluminium, Participates in Collision Detection: yes; Component 5, Finition ext - Crépis, ThermalConductivity: 0.8; Component 5, Finition ext - Crépis, SpecificHeatCapacity: 1000 J/kg/K; Component 5, Finition ext - Crépis, MassDensity: 1600 kg/m3; Component 5, Finition ext - Crépis, Embodied Energy: 1.4 (MJ/kg); Component 5, Finition ext - Crépis, Embodied Carbon: 0.09 (kgCO₂/kg); Component 5, Finition ext - Crépis, Name: Finition ext - Crépis; Component 5, Finition ext - Crépis, Participates in Collision Detection: no; Component 2, Etanchéité - Bitume, ThermalConductivity: 0.23; Component 2, Etanchéité - Bitume, SpecificHeatCapacity: 1000 J/kg/K; Component 2, Etanchéité - Bitume, MassDensity: 1100 kg/m3; Component 2, Etanchéité - Bitume, Embodied Energy: 2.86 (MJ/kg); Component 2, Etanchéité - Bitume, Embodied Carbon: 0.066 (kgCO₂/kg); Component 2, Etanchéité - Bitume, Name: Etanchéité - Bitume; Component 2, Etanchéité - Bitume, Participates in Collision Detection: no; Component 3, Béton, ThermalConductivity: 2.3; Component 3, Béton, SpecificHeatCapacity: 1000 J/kg/K; Component 3, Béton, MassDensity: 2300 kg/m3; Component 3, Béton, Embodied Energy: 1.92 (MJ/kg); Component 3, Béton, Embodied Carbon: 0.198 (kgCO₂/kg); Component 3, Béton, Name: Béton; Component 3, Béton, Participates in Collision Detection: yes; Component 4, Bois - Lattage, ThermalConductivity: 0.13; Component 4, Bois - Lattage, SpecificHeatCapacity: 1600 J/kg/K; Component 4, Bois - Lattage, MassDensity: 500 kg/m3; Component 4, Bois - Lattage, Embodied Energy: 6.95 (MJ/kg); Component 4, Bois - Lattage, Embodied Carbon: 0.29 (kgCO₂/kg); Component 4, Bois - Lattage, Name: Bois - Lattage; Component 4, Bois - Lattage, Participates in Collision Detection: yes; Component 6, Finition ext - Bardage bois, ThermalConductivity: 0.14; Component 6, Finition ext - Bardage bois, SpecificHeatCapacity: 2300 J/kg/K; Component 6, Finition ext - Bardage bois, MassDensity: 500 kg/m3; Component 6, Finition ext - Bardage bois, Embodied Energy: 10 (MJ/kg); Component 6, Finition ext - Bardage bois, Embodied Carbon: 0.36 (kgCO₂/kg); Component 6, Finition ext - Bardage bois, Name: Finition ext - Bardage bois; Component 6, Finition ext - Bardage bois, Participates in Collision Detection: no
BaseQuantities - Height: 1.31 m; Width: 0.292485 m
Name | Length (m) | GrossFootprintArea (m2) = NetFootprintArea (m2) | GrossSideArea (m2) = NetSideArea (m2) | GrossVolume (m3) = NetVolume (m3)
Muret béton 20cm | 6.23058 | 1.80038 | 8.51877 | 2.32838
Muret béton 20cm | 1.12682 | 0.290014 | 1.50278 | 0.373277
Muret béton 20cm | 5.1605 | 1.4318 | 7.00824 | 1.85106

# IfcWall: Acrotère pour plancher 21 isolée BARDAGE BOIS 292 x 1330, Muret béton 20cm
In: R+4
Type - ElementType: PARAPET; PredefinedType: USERDEFINED
Description: Acrotère et GD terrasses; Classification: Mur d'acrotère (Classification ARCHICAD); Material: Finition ext - Bardage bois, Bois - Lattage, Béton, Etanchéité - Bitume, Finition ext - Crépis, Métal - Aluminium
Pset_WallCommon - AcousticRating: Non défini; ThermalTransmittance: 0; LoadBearing: yes; IsExternal: yes
PSET_Murs_ARCHI - Emplacement: Superstructure; Type: Mur béton 20cm; Destination: Muret formant garde-corps; Matériaux: BETON
Propriétés DCE - Numéro de LOT: LOT 04; LOT 05; Numéro article: L05.2.3.2
AC_Pset_RenovationAndPhasing - Renovation Status: Existing
Material Properties - Component 6, Finition ext - Bardage bois, ThermalConductivity: 0.14; Component 6, Finition ext - Bardage bois, SpecificHeatCapacity: 2300 J/kg/K; Component 6, Finition ext - Bardage bois, MassDensity: 500 kg/m3; Component 6, Finition ext - Bardage bois, Embodied Energy: 10 (MJ/kg); Component 6, Finition ext - Bardage bois, Embodied Carbon: 0.36 (kgCO₂/kg); Component 6, Finition ext - Bardage bois, Name: Finition ext - Bardage bois; Component 6, Finition ext - Bardage bois, Participates in Collision Detection: no; Component 4, Bois - Lattage, ThermalConductivity: 0.13; Component 4, Bois - Lattage, SpecificHeatCapacity: 1600 J/kg/K; Component 4, Bois - Lattage, MassDensity: 500 kg/m3; Component 4, Bois - Lattage, Embodied Energy: 6.95 (MJ/kg); Component 4, Bois - Lattage, Embodied Carbon: 0.29 (kgCO₂/kg); Component 4, Bois - Lattage, Name: Bois - Lattage; Component 4, Bois - Lattage, Participates in Collision Detection: yes; Component 3, Béton, ThermalConductivity: 2.3; Component 3, Béton, SpecificHeatCapacity: 1000 J/kg/K; Component 3, Béton, MassDensity: 2300 kg/m3; Component 3, Béton, Embodied Energy: 1.92 (MJ/kg); Component 3, Béton, Embodied Carbon: 0.198 (kgCO₂/kg); Component 3, Béton, Name: Béton; Component 3, Béton, Participates in Collision Detection: yes; Component 2, Etanchéité - Bitume, ThermalConductivity: 0.23; Component 2, Etanchéité - Bitume, SpecificHeatCapacity: 1000 J/kg/K; Component 2, Etanchéité - Bitume, MassDensity: 1100 kg/m3; Component 2, Etanchéité - Bitume, Embodied Energy: 2.86 (MJ/kg); Component 2, Etanchéité - Bitume, Embodied Carbon: 0.066 (kgCO₂/kg); Component 2, Etanchéité - Bitume, Name: Etanchéité - Bitume; Component 2, Etanchéité - Bitume, Participates in Collision Detection: no; Component 5, Finition ext - Crépis, ThermalConductivity: 0.8; Component 5, Finition ext - Crépis, SpecificHeatCapacity: 1000 J/kg/K; Component 5, Finition ext - Crépis, MassDensity: 1600 kg/m3; Component 5, Finition ext - Crépis, Embodied Energy: 1.4 (MJ/kg); Component 5, Finition ext - Crépis, Embodied Carbon: 0.09 (kgCO₂/kg); Component 5, Finition ext - Crépis, Name: Finition ext - Crépis; Component 5, Finition ext - Crépis, Participates in Collision Detection: no; Component 1, Métal - Aluminium, ThermalConductivity: 160; Component 1, Métal - Aluminium, SpecificHeatCapacity: 880 J/kg/K; Component 1, Métal - Aluminium, MassDensity: 2800 kg/m3; Component 1, Métal - Aluminium, Embodied Energy: 155 (MJ/kg); Component 1, Métal - Aluminium, Embodied Carbon: 9.16 (kgCO₂/kg); Component 1, Métal - Aluminium, Name: Métal - Aluminium; Component 1, Métal - Aluminium, Participates in Collision Detection: yes
BaseQuantities - Length: 4.0635 m; Height: 1.33 m; Width: 0.292485 m; GrossFootprintArea: 1.16861 m2; NetFootprintArea: 1.16861 m2; GrossSideArea: 5.60649 m2; NetSideArea: 5.60649 m2; GrossVolume: 1.48666 m3; NetVolume: 1.48666 m3

# IfcWall: Acrotère pour plancher 21 isolée BARDAGE BOIS 292 x 580, Muret béton 20cm
In: R+3
Type - ElementType: PARAPET; PredefinedType: USERDEFINED
Description: Acrotère et GD terrasses; Classification: Mur d'acrotère (Classification ARCHICAD); Material: Métal - Aluminium, Finition ext - Crépis, Etanchéité - Bitume, Béton, Bois - Lattage, Finition ext - Bardage bois
Pset_WallCommon - AcousticRating: Non défini; ThermalTransmittance: 0; LoadBearing: yes; IsExternal: yes
PSET_Murs_ARCHI - Emplacement: Superstructure; Type: Mur béton 20cm; Destination: Acrotère; Matériaux: BETON
Propriétés DCE - Numéro de LOT: LOT 04; LOT 05; Numéro article: L05.2.3.2
AC_Pset_RenovationAndPhasing - Renovation Status: Existing
Material Properties - Component 1, Métal - Aluminium, ThermalConductivity: 160; Component 1, Métal - Aluminium, SpecificHeatCapacity: 880 J/kg/K; Component 1, Métal - Aluminium, MassDensity: 2800 kg/m3; Component 1, Métal - Aluminium, Embodied Energy: 155 (MJ/kg); Component 1, Métal - Aluminium, Embodied Carbon: 9.16 (kgCO₂/kg); Component 1, Métal - Aluminium, Name: Métal - Aluminium; Component 1, Métal - Aluminium, Participates in Collision Detection: yes; Component 5, Finition ext - Crépis, ThermalConductivity: 0.8; Component 5, Finition ext - Crépis, SpecificHeatCapacity: 1000 J/kg/K; Component 5, Finition ext - Crépis, MassDensity: 1600 kg/m3; Component 5, Finition ext - Crépis, Embodied Energy: 1.4 (MJ/kg); Component 5, Finition ext - Crépis, Embodied Carbon: 0.09 (kgCO₂/kg); Component 5, Finition ext - Crépis, Name: Finition ext - Crépis; Component 5, Finition ext - Crépis, Participates in Collision Detection: no; Component 2, Etanchéité - Bitume, ThermalConductivity: 0.23; Component 2, Etanchéité - Bitume, SpecificHeatCapacity: 1000 J/kg/K; Component 2, Etanchéité - Bitume, MassDensity: 1100 kg/m3; Component 2, Etanchéité - Bitume, Embodied Energy: 2.86 (MJ/kg); Component 2, Etanchéité - Bitume, Embodied Carbon: 0.066 (kgCO₂/kg); Component 2, Etanchéité - Bitume, Name: Etanchéité - Bitume; Component 2, Etanchéité - Bitume, Participates in Collision Detection: no; Component 3, Béton, ThermalConductivity: 2.3; Component 3, Béton, SpecificHeatCapacity: 1000 J/kg/K; Component 3, Béton, MassDensity: 2300 kg/m3; Component 3, Béton, Embodied Energy: 1.92 (MJ/kg); Component 3, Béton, Embodied Carbon: 0.198 (kgCO₂/kg); Component 3, Béton, Name: Béton; Component 3, Béton, Participates in Collision Detection: yes; Component 4, Bois - Lattage, ThermalConductivity: 0.13; Component 4, Bois - Lattage, SpecificHeatCapacity: 1600 J/kg/K; Component 4, Bois - Lattage, MassDensity: 500 kg/m3; Component 4, Bois - Lattage, Embodied Energy: 6.95 (MJ/kg); Component 4, Bois - Lattage, Embodied Carbon: 0.29 (kgCO₂/kg); Component 4, Bois - Lattage, Name: Bois - Lattage; Component 4, Bois - Lattage, Participates in Collision Detection: yes; Component 6, Finition ext - Bardage bois, ThermalConductivity: 0.14; Component 6, Finition ext - Bardage bois, SpecificHeatCapacity: 2300 J/kg/K; Component 6, Finition ext - Bardage bois, MassDensity: 500 kg/m3; Component 6, Finition ext - Bardage bois, Embodied Energy: 10 (MJ/kg); Component 6, Finition ext - Bardage bois, Embodied Carbon: 0.36 (kgCO₂/kg); Component 6, Finition ext - Bardage bois, Name: Finition ext - Bardage bois; Component 6, Finition ext - Bardage bois, Participates in Collision Detection: no
BaseQuantities - Length: 6.19809 m; Height: 0.58 m; Width: 0.292485 m; GrossFootprintArea: 1.74363 m2; NetFootprintArea: 1.74363 m2; GrossSideArea: 3.91365 m2; NetSideArea: 3.91365 m2; GrossVolume: 0.986681 m3; NetVolume: 0.986681 m3

# IfcWall: Acrotère pour plancher 21 isolée TERRASSE ACCESSIBLE 235 x 1240 (7)
Type - ElementType: PARAPET; PredefinedType: USERDEFINED
Description: Acrotère et GD terrasses; Classification: Mur d'acrotère (Classification ARCHICAD)
Pset_WallCommon - AcousticRating: Non défini; ThermalTransmittance: 0; LoadBearing: yes; IsExternal: yes
PSET_Murs_ARCHI - Emplacement: Superstructure; Type: Mur béton 20cm; Destination: Muret formant garde-corps; Matériaux: BETON
Propriétés DCE - Numéro de LOT: LOT 04; LOT 16; Numéro article: L16.2.1
AC_Pset_RenovationAndPhasing - Renovation Status: Existing
Material Properties - Component 1, Métal - Aluminium, ThermalConductivity: 160; Component 1, Métal - Aluminium, SpecificHeatCapacity: 880 J/kg/K; Component 1, Métal - Aluminium, MassDensity: 2800 kg/m3; Component 1, Métal - Aluminium, Embodied Energy: 155 (MJ/kg); Component 1, Métal - Aluminium, Embodied Carbon: 9.16 (kgCO₂/kg); Component 1, Métal - Aluminium, Name: Métal - Aluminium; Component 1, Métal - Aluminium, Participates in Collision Detection: yes; Component 2, Etanchéité - Bitume, ThermalConductivity: 0.23; Component 2, Etanchéité - Bitume, SpecificHeatCapacity: 1000 J/kg/K; Component 2, Etanchéité - Bitume, MassDensity: 1100 kg/m3; Component 2, Etanchéité - Bitume, Embodied Energy: 2.86 (MJ/kg); Component 2, Etanchéité - Bitume, Embodied Carbon: 0.066 (kgCO₂/kg); Component 2, Etanchéité - Bitume, Name: Etanchéité - Bitume; Component 2, Etanchéité - Bitume, Participates in Collision Detection: no; Component 3, Béton, ThermalConductivity: 2.3; Component 3, Béton, SpecificHeatCapacity: 1000 J/kg/K; Component 3, Béton, MassDensity: 2300 kg/m3; Component 3, Béton, Embodied Energy: 1.92 (MJ/kg); Component 3, Béton, Embodied Carbon: 0.198 (kgCO₂/kg); Component 3, Béton, Name: Béton; Component 3, Béton, Participates in Collision Detection: yes
BaseQuantities - Height: 1.24 m; Width: 0.235485 m
Name | In | Material | Length (m) | GrossFootprintArea (m2) = NetFootprintArea (m2) | GrossSideArea (m2) = NetSideArea (m2) | GrossVolume (m3) = NetVolume (m3) | Component 4, Finition ext - Crépis, ThermalConductivity | Component 4, Finition ext - Crépis, SpecificHeatCapacity (J/kg/K) | Component 4, Finition ext - Crépis, MassDensity (kg/m3) | Component 4, Finition ext - Crépis, Embodied Energy | Component 4, Finition ext - Crépis, Embodied Carbon | Component 4, Finition ext - Crépis, Name | Component 4, Finition ext - Crépis, Participates in Collision Detection | Component 4
Muret béton 20cm | R+2 | Métal - Aluminium, Finition ext - Crépis (2), Etanchéité - Bitume, Béton | 3.44744 | 0.777267 | 4.24041 | 0.949217 | Material Properties - Component 5, Finition ext - Crépis, ThermalConductivity: 0.8; Component 5, Finition ext - Crépis, SpecificHeatCapacity: 1000 J/kg/K; Component 5, Finition ext - Crépis, MassDensity: 1600 kg/m3; Component 5, Finition ext - Crépis, Embodied Energy: 1.4 (MJ/kg); Component 5, Finition ext - Crépis, Embodied Carbon: 0.09 (kgCO₂/kg); Component 5, Finition ext - Crépis, Name: Finition ext - Crépis; Component 5, Finition ext - Crépis, Participates in Collision Detection: no; Component 5: 2 with these values
Muret béton 20cm | R+2 | Finition ext - Crépis (2), Béton, Etanchéité - Bitume, Métal - Aluminium | 2.5 | 0.57819 | 3.08529 | 0.703293 | 0.8 | 1000 | 1600 | 1.4 (MJ/kg) | 0.09 (kgCO₂/kg) | Finition ext - Crépis | no | 2 with these values
Muret béton 20cm | R+2 | Finition ext - Crépis (2), Béton, Etanchéité - Bitume, Métal - Aluminium | 3.19049 | 0.753884 | 4.08464 | 0.84376 | 0.8 | 1000 | 1600 | 1.4 (MJ/kg) | 0.09 (kgCO₂/kg) | Finition ext - Crépis | no | 2 with these values
Muret béton 20cm | R+2 | Finition ext - Crépis (2), Béton, Etanchéité - Bitume, Métal - Aluminium | 4.6937 | 1.12681 | 6.06441 | 1.37776 | 0.8 | 1000 | 1600 | 1.4 (MJ/kg) | 0.09 (kgCO₂/kg) | Finition ext - Crépis | no | 2 with these values
Muret béton 20cm | R+2 | Finition ext - Crépis (2), Béton, Etanchéité - Bitume, Métal - Aluminium | 9.29452 | 2.15031 | 11.9442 | 2.62691 | 0.8 | 1000 | 1600 | 1.4 (MJ/kg) | 0.09 (kgCO₂/kg) | Finition ext - Crépis | no | 2 with these values
Muret béton 20cm | R+3 | Métal - Aluminium, Finition ext - Crépis (2), Etanchéité - Bitume, Béton | 2.81775 | 0.623657 | 3.60515 | 0.761183 | Material Properties - Component 5, Finition ext - Crépis, ThermalConductivity: 0.8; Component 5, Finition ext - Crépis, SpecificHeatCapacity: 1000 J/kg/K; Component 5, Finition ext - Crépis, MassDensity: 1600 kg/m3; Component 5, Finition ext - Crépis, Embodied Energy: 1.4 (MJ/kg); Component 5, Finition ext - Crépis, Embodied Carbon: 0.09 (kgCO₂/kg); Component 5, Finition ext - Crépis, Name: Finition ext - Crépis; Component 5, Finition ext - Crépis, Participates in Collision Detection: no; Component 5: 2 with these values
Muret béton 20cm | R+3 | Finition ext - Crépis (2), Béton, Etanchéité - Bitume, Métal - Aluminium | 1.1997 | 0.305899 | 1.50881 | 0.374203 | 0.8 | 1000 | 1600 | 1.4 (MJ/kg) | 0.09 (kgCO₂/kg) | Finition ext - Crépis | no | 2 with these values

# IfcWall: Acrotère pour plancher 21 isolée TERRASSE ACCESSIBLE 235 x 1450, Muret béton 20cm
In: R+2
Type - ElementType: PARAPET; PredefinedType: USERDEFINED
Description: Acrotère et GD terrasses; Classification: Mur d'acrotère (Classification ARCHICAD); Material: Finition ext - Crépis (2), Béton, Etanchéité - Bitume, Métal - Aluminium
Pset_WallCommon - AcousticRating: Non défini; ThermalTransmittance: 0; LoadBearing: yes; IsExternal: yes
PSET_Murs_ARCHI - Emplacement: Superstructure; Type: Mur béton 20cm; Destination: Muret formant garde-corps; Matériaux: BETON
Propriétés DCE - Numéro de LOT: LOT 04; LOT 16; Numéro article: L16.2.1
AC_Pset_RenovationAndPhasing - Renovation Status: Existing
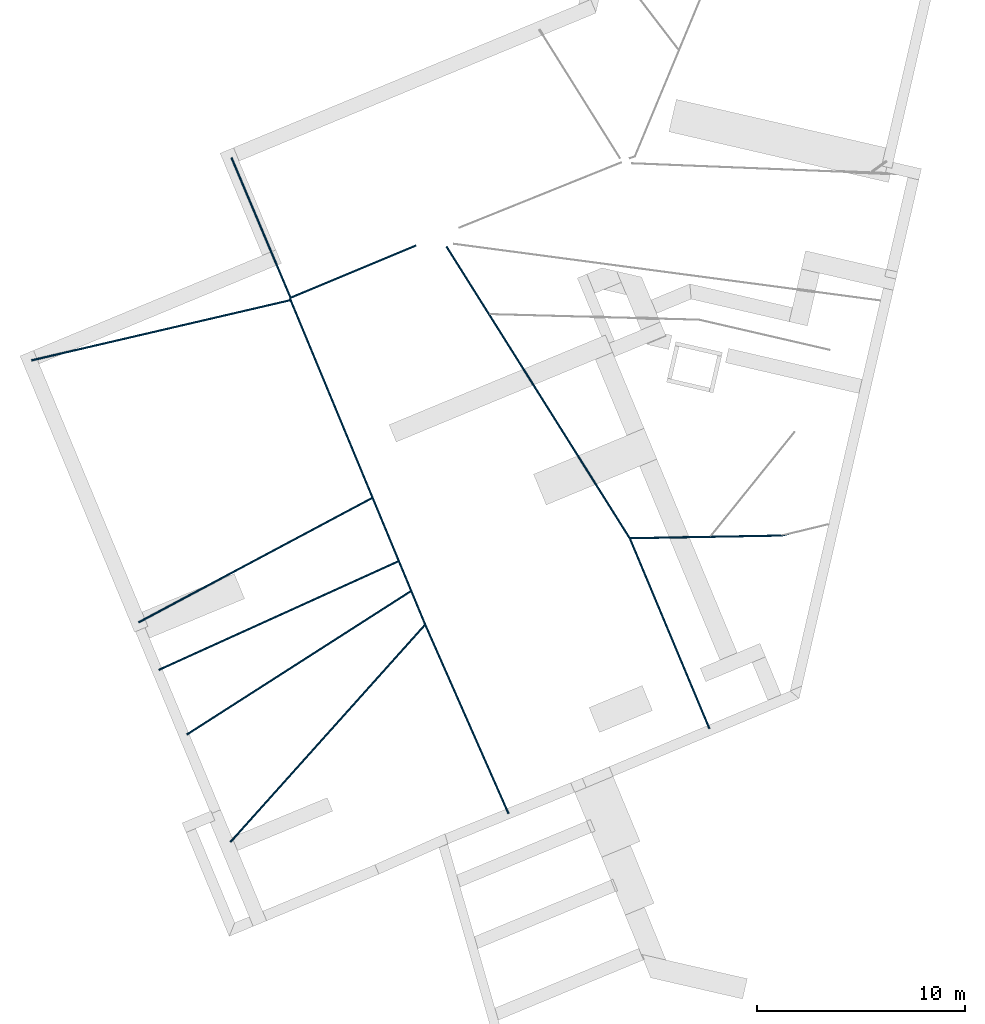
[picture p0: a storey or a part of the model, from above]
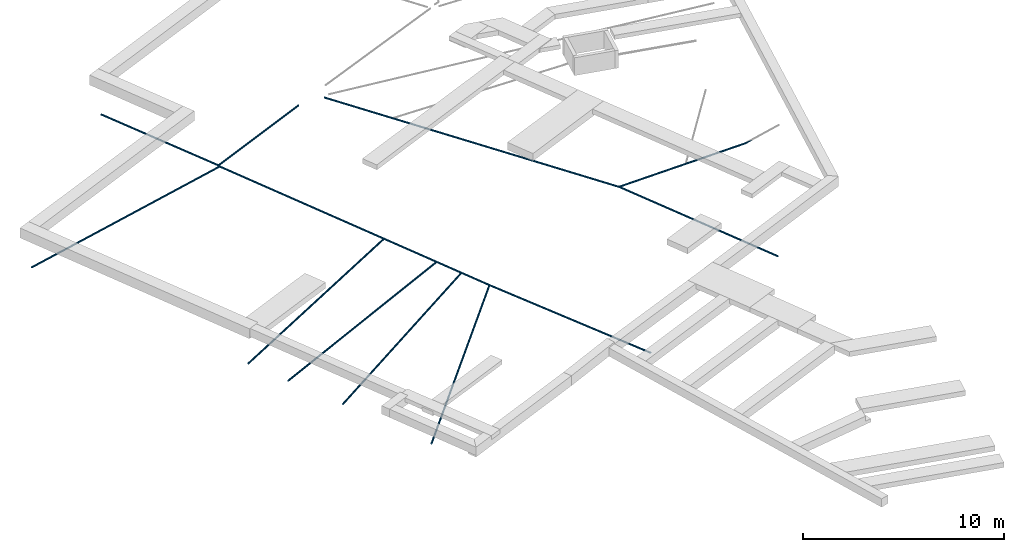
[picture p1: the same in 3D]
Properties of the parts of a building model (IFC2X3), part 18 of 22

# IfcWall: Acrotère pour plancher 21 isolée TERRASSE ACCESSIBLE 235 x 1450, Muret béton 20cm
Material Properties - Component 4, Finition ext - Crépis, ThermalConductivity: 0.8; Component 4, Finition ext - Crépis, SpecificHeatCapacity: 1000 J/kg/K; Component 4, Finition ext - Crépis, MassDensity: 1600 kg/m3; Component 4, Finition ext - Crépis, Embodied Energy: 1.4 (MJ/kg); Component 4, Finition ext - Crépis, Embodied Carbon: 0.09 (kgCO₂/kg); Component 4, Finition ext - Crépis, Name: Finition ext - Crépis; Component 4, Finition ext - Crépis, Participates in Collision Detection: no; Component 3, Béton, ThermalConductivity: 2.3; Component 3, Béton, SpecificHeatCapacity: 1000 J/kg/K; Component 3, Béton, MassDensity: 2300 kg/m3; Component 3, Béton, Embodied Energy: 1.92 (MJ/kg); Component 3, Béton, Embodied Carbon: 0.198 (kgCO₂/kg); Component 3, Béton, Name: Béton; Component 3, Béton, Participates in Collision Detection: yes; Component 2, Etanchéité - Bitume, ThermalConductivity: 0.23; Component 2, Etanchéité - Bitume, SpecificHeatCapacity: 1000 J/kg/K; Component 2, Etanchéité - Bitume, MassDensity: 1100 kg/m3; Component 2, Etanchéité - Bitume, Embodied Energy: 2.86 (MJ/kg); Component 2, Etanchéité - Bitume, Embodied Carbon: 0.066 (kgCO₂/kg); Component 2, Etanchéité - Bitume, Name: Etanchéité - Bitume; Component 2, Etanchéité - Bitume, Participates in Collision Detection: no; Component 1, Métal - Aluminium, ThermalConductivity: 160; Component 1, Métal - Aluminium, SpecificHeatCapacity: 880 J/kg/K; Component 1, Métal - Aluminium, MassDensity: 2800 kg/m3; Component 1, Métal - Aluminium, Embodied Energy: 155 (MJ/kg); Component 1, Métal - Aluminium, Embodied Carbon: 9.16 (kgCO₂/kg); Component 1, Métal - Aluminium, Name: Métal - Aluminium; Component 1, Métal - Aluminium, Participates in Collision Detection: yes; Component 4: 2 with these values
BaseQuantities - Length: 4.12517 m; Height: 1.45 m; Width: 0.235485 m; GrossFootprintArea: 0.967865 m2; NetFootprintArea: 0.967865 m2; GrossSideArea: 5.49208 m2; NetSideArea: 5.49208 m2; GrossVolume: 1.19814 m3; NetVolume: 1.19814 m3

# IfcWall: Acrotère pour plancher 23 isolée 242 x 1260 (6)
In: R+3
Type - ElementType: PARAPET; PredefinedType: USERDEFINED
Description: Acrotère et GD terrasses; Classification: Mur d'acrotère (Classification ARCHICAD)
Pset_WallCommon - AcousticRating: Non défini; ThermalTransmittance: 0; LoadBearing: yes; IsExternal: yes
PSET_Murs_ARCHI - Emplacement: Superstructure; Type: Mur béton 20cm; Destination: Muret formant garde-corps; Matériaux: BETON
Propriétés DCE - Numéro de LOT: LOT 04; LOT 16; Numéro article: L16.2.1
AC_Pset_RenovationAndPhasing - Renovation Status: Existing
Material Properties - Component 3, Béton, ThermalConductivity: 2.3; Component 3, Béton, SpecificHeatCapacity: 1000 J/kg/K; Component 3, Béton, MassDensity: 2300 kg/m3; Component 3, Béton, Embodied Energy: 1.92 (MJ/kg); Component 3, Béton, Embodied Carbon: 0.198 (kgCO₂/kg); Component 3, Béton, Name: Béton; Component 3, Béton, Participates in Collision Detection: yes; Component 2, Etanchéité - Bitume, ThermalConductivity: 0.23; Component 2, Etanchéité - Bitume, SpecificHeatCapacity: 1000 J/kg/K; Component 2, Etanchéité - Bitume, MassDensity: 1100 kg/m3; Component 2, Etanchéité - Bitume, Embodied Energy: 2.86 (MJ/kg); Component 2, Etanchéité - Bitume, Embodied Carbon: 0.066 (kgCO₂/kg); Component 2, Etanchéité - Bitume, Name: Etanchéité - Bitume; Component 2, Etanchéité - Bitume, Participates in Collision Detection: no; Component 1, Métal - Aluminium, ThermalConductivity: 160; Component 1, Métal - Aluminium, SpecificHeatCapacity: 880 J/kg/K; Component 1, Métal - Aluminium, MassDensity: 2800 kg/m3; Component 1, Métal - Aluminium, Embodied Energy: 155 (MJ/kg); Component 1, Métal - Aluminium, Embodied Carbon: 9.16 (kgCO₂/kg); Component 1, Métal - Aluminium, Name: Métal - Aluminium; Component 1, Métal - Aluminium, Participates in Collision Detection: yes
BaseQuantities - Height: 1.26001 m; Width: 0.242485 m
Name | Material | Length (m) | GrossFootprintArea (m2) = NetFootprintArea (m2) | GrossSideArea (m2) = NetSideArea (m2) | GrossVolume (m3) = NetVolume (m3)
Muret béton 20cm | Finition ext - Crépis (2), Béton, Etanchéité - Bitume, Métal - Aluminium | 4.15009 | 0.973229 | 5.82502 | 1.2055 | Material Properties - Component 4, Finition ext - Crépis, ThermalConductivity: 0.8; Component 4, Finition ext - Crépis, SpecificHeatCapacity: 1000 J/kg/K; Component 4, Finition ext - Crépis, MassDensity: 1600 kg/m3; Component 4, Finition ext - Crépis, Embodied Energy: 1.4 (MJ/kg); Component 4, Finition ext - Crépis, Embodied Carbon: 0.09 (kgCO₂/kg); Component 4, Finition ext - Crépis, Name: Finition ext - Crépis; Component 4, Finition ext - Crépis, Participates in Collision Detection: no; Component 4: 2 with these values
Muret béton 20cm | Finition ext - Crépis (2), Béton, Etanchéité - Bitume, Métal - Aluminium | 2.69376 | 0.623035 | 3.49313 | 0.771164 | Material Properties - Component 4, Finition ext - Crépis, ThermalConductivity: 0.8; Component 4, Finition ext - Crépis, SpecificHeatCapacity: 1000 J/kg/K; Component 4, Finition ext - Crépis, MassDensity: 1600 kg/m3; Component 4, Finition ext - Crépis, Embodied Energy: 1.4 (MJ/kg); Component 4, Finition ext - Crépis, Embodied Carbon: 0.09 (kgCO₂/kg); Component 4, Finition ext - Crépis, Name: Finition ext - Crépis; Component 4, Finition ext - Crépis, Participates in Collision Detection: no; Component 4: 2 with these values
Muret béton 20cm | Métal - Aluminium, Finition ext - Crépis (2), Etanchéité - Bitume, Béton | 7.63808 | 1.77026 | 10.014 | 2.19353 | Material Properties - Component 5, Finition ext - Crépis, ThermalConductivity: 0.8; Component 5, Finition ext - Crépis, SpecificHeatCapacity: 1000 J/kg/K; Component 5, Finition ext - Crépis, MassDensity: 1600 kg/m3; Component 5, Finition ext - Crépis, Embodied Energy: 1.4 (MJ/kg); Component 5, Finition ext - Crépis, Embodied Carbon: 0.09 (kgCO₂/kg); Component 5, Finition ext - Crépis, Name: Finition ext - Crépis; Component 5, Finition ext - Crépis, Participates in Collision Detection: no; Component 5: 2 with these values
Muret béton 20cm | Métal - Aluminium, Finition ext - Crépis (2), Etanchéité - Bitume, Béton | 6.85971 | 1.62934 | 8.90147 | 2.01801 | Material Properties - Component 5, Finition ext - Crépis, ThermalConductivity: 0.8; Component 5, Finition ext - Crépis, SpecificHeatCapacity: 1000 J/kg/K; Component 5, Finition ext - Crépis, MassDensity: 1600 kg/m3; Component 5, Finition ext - Crépis, Embodied Energy: 1.4 (MJ/kg); Component 5, Finition ext - Crépis, Embodied Carbon: 0.09 (kgCO₂/kg); Component 5, Finition ext - Crépis, Name: Finition ext - Crépis; Component 5, Finition ext - Crépis, Participates in Collision Detection: no; Component 5: 2 with these values
Muret béton 20cm | Métal - Aluminium, Finition ext - Crépis (2), Etanchéité - Bitume, Béton | 7.75566 | 1.77458 | 9.86578 | 2.18736 | Material Properties - Component 5, Finition ext - Crépis, ThermalConductivity: 0.8; Component 5, Finition ext - Crépis, SpecificHeatCapacity: 1000 J/kg/K; Component 5, Finition ext - Crépis, MassDensity: 1600 kg/m3; Component 5, Finition ext - Crépis, Embodied Energy: 1.4 (MJ/kg); Component 5, Finition ext - Crépis, Embodied Carbon: 0.09 (kgCO₂/kg); Component 5, Finition ext - Crépis, Name: Finition ext - Crépis; Component 5, Finition ext - Crépis, Participates in Collision Detection: no; Component 5: 2 with these values
Muret béton 20cm | Finition ext - Crépis (2), Béton, Etanchéité - Bitume, Métal - Aluminium | 2.0693 | 0.454483 | 2.70245 | 0.5628 | Material Properties - Component 4, Finition ext - Crépis, ThermalConductivity: 0.8; Component 4, Finition ext - Crépis, SpecificHeatCapacity: 1000 J/kg/K; Component 4, Finition ext - Crépis, MassDensity: 1600 kg/m3; Component 4, Finition ext - Crépis, Embodied Energy: 1.4 (MJ/kg); Component 4, Finition ext - Crépis, Embodied Carbon: 0.09 (kgCO₂/kg); Component 4, Finition ext - Crépis, Name: Finition ext - Crépis; Component 4, Finition ext - Crépis, Participates in Collision Detection: no; Component 4: 2 with these values

# IfcWall: Acrotère pour plancher 23 isolée 242 x 600 (5)
In: R+4
Type - ElementType: PARAPET; PredefinedType: USERDEFINED
Description: Acrotère et GD terrasses; Classification: Mur d'acrotère (Classification ARCHICAD)
Pset_WallCommon - AcousticRating: Non défini; ThermalTransmittance: 0; LoadBearing: yes; IsExternal: yes
PSET_Murs_ARCHI - Emplacement: Superstructure; Type: Mur béton 20cm; Destination: Muret formant garde-corps; Acrotère; Matériaux: BETON
Propriétés DCE - Numéro de LOT: LOT 04; LOT 16; Numéro article: L16.2.1
AC_Pset_RenovationAndPhasing - Renovation Status: Existing
Material Properties - Component 3, Béton, ThermalConductivity: 2.3; Component 3, Béton, SpecificHeatCapacity: 1000 J/kg/K; Component 3, Béton, MassDensity: 2300 kg/m3; Component 3, Béton, Embodied Energy: 1.92 (MJ/kg); Component 3, Béton, Embodied Carbon: 0.198 (kgCO₂/kg); Component 3, Béton, Name: Béton; Component 3, Béton, Participates in Collision Detection: yes; Component 2, Etanchéité - Bitume, ThermalConductivity: 0.23; Component 2, Etanchéité - Bitume, SpecificHeatCapacity: 1000 J/kg/K; Component 2, Etanchéité - Bitume, MassDensity: 1100 kg/m3; Component 2, Etanchéité - Bitume, Embodied Energy: 2.86 (MJ/kg); Component 2, Etanchéité - Bitume, Embodied Carbon: 0.066 (kgCO₂/kg); Component 2, Etanchéité - Bitume, Name: Etanchéité - Bitume; Component 2, Etanchéité - Bitume, Participates in Collision Detection: no; Component 1, Métal - Aluminium, ThermalConductivity: 160; Component 1, Métal - Aluminium, SpecificHeatCapacity: 880 J/kg/K; Component 1, Métal - Aluminium, MassDensity: 2800 kg/m3; Component 1, Métal - Aluminium, Embodied Energy: 155 (MJ/kg); Component 1, Métal - Aluminium, Embodied Carbon: 9.16 (kgCO₂/kg); Component 1, Métal - Aluminium, Name: Métal - Aluminium; Component 1, Métal - Aluminium, Participates in Collision Detection: yes
BaseQuantities - Height: 0.6 m; Width: 0.242485 m
Name | Material | Component 4, Finition ext - Crépis, ThermalConductivity | Component 4, Finition ext - Crépis, SpecificHeatCapacity (J/kg/K) | Component 4, Finition ext - Crépis, MassDensity (kg/m3) | Component 4, Finition ext - Crépis, Embodied Energy | Component 4, Finition ext - Crépis, Embodied Carbon | Component 4, Finition ext - Crépis, Name | Component 4, Finition ext - Crépis, Participates in Collision Detection | Component 4 | Length (m) | GrossFootprintArea (m2) = NetFootprintArea (m2) | GrossSideArea (m2) = NetSideArea (m2) | GrossVolume (m3) = NetVolume (m3)
Muret béton 20cm | Finition ext - Crépis (2), Béton, Etanchéité - Bitume, Métal - Aluminium | 0.8 | 1000 | 1600 | 1.4 (MJ/kg) | 0.09 (kgCO₂/kg) | Finition ext - Crépis | no | 2 with these values | 4.835 | 1.16333 | 3.16143 | 0.678539
Muret béton 20cm | Métal - Aluminium, Finition ext - Crépis (2), Etanchéité - Bitume, Béton |  |  |  |  |  |  |  |  | 18.1979 | 4.26113 | 11.874 | 2.4802 | Material Properties - Component 5, Finition ext - Crépis, ThermalConductivity: 0.8; Component 5, Finition ext - Crépis, SpecificHeatCapacity: 1000 J/kg/K; Component 5, Finition ext - Crépis, MassDensity: 1600 kg/m3; Component 5, Finition ext - Crépis, Embodied Energy: 1.4 (MJ/kg); Component 5, Finition ext - Crépis, Embodied Carbon: 0.09 (kgCO₂/kg); Component 5, Finition ext - Crépis, Name: Finition ext - Crépis; Component 5, Finition ext - Crépis, Participates in Collision Detection: no; Component 5: 2 with these values
Muret béton 20cm | Finition ext - Crépis (2), Béton, Etanchéité - Bitume, Métal - Aluminium | 0.8 | 1000 | 1600 | 1.4 (MJ/kg) | 0.09 (kgCO₂/kg) | Finition ext - Crépis | no | 2 with these values | 3.7392 | 0.859559 | 2.43239 | 0.500532
Muret béton 20cm | Finition ext - Crépis (2), Béton, Etanchéité - Bitume, Métal - Aluminium | 0.8 | 1000 | 1600 | 1.4 (MJ/kg) | 0.09 (kgCO₂/kg) | Finition ext - Crépis | no | 2 with these values | 0.322582 | 0.034286 | 0.191515 | 0.0192599
Muret béton 20cm | Métal - Aluminium, Finition ext - Crépis (2), Etanchéité - Bitume, Béton |  |  |  |  |  |  |  |  | 0.896758 | 0.234316 | 0.567353 | 0.107417 | Material Properties - Component 5, Finition ext - Crépis, ThermalConductivity: 0.8; Component 5, Finition ext - Crépis, SpecificHeatCapacity: 1000 J/kg/K; Component 5, Finition ext - Crépis, MassDensity: 1600 kg/m3; Component 5, Finition ext - Crépis, Embodied Energy: 1.4 (MJ/kg); Component 5, Finition ext - Crépis, Embodied Carbon: 0.09 (kgCO₂/kg); Component 5, Finition ext - Crépis, Name: Finition ext - Crépis; Component 5, Finition ext - Crépis, Participates in Collision Detection: no; Component 5: 2 with these values

# IfcWall: Acrotère pour plancher 23 isolée BARDAGE BOIS (1) 292 x 600 (3)
In: R+4
Type - ElementType: PARAPET; PredefinedType: USERDEFINED
Description: Acrotère et GD terrasses; Classification: Mur d'acrotère (Classification ARCHICAD); Material: Finition ext - Bardage bois, Bois - Lattage, Béton, Etanchéité - Bitume, Finition ext - Crépis, Métal - Aluminium
Pset_WallCommon - AcousticRating: Non défini; ThermalTransmittance: 0; LoadBearing: yes; IsExternal: yes
PSET_Murs_ARCHI - Emplacement: Superstructure; Type: Mur béton 20cm; Destination: Muret formant garde-corps; Acrotère; Matériaux: BETON
Propriétés DCE - Numéro de LOT: LOT 04; LOT 05; Numéro article: L05.2.3.2
AC_Pset_RenovationAndPhasing - Renovation Status: Existing
Material Properties - Component 6, Finition ext - Bardage bois, ThermalConductivity: 0.14; Component 6, Finition ext - Bardage bois, SpecificHeatCapacity: 2300 J/kg/K; Component 6, Finition ext - Bardage bois, MassDensity: 500 kg/m3; Component 6, Finition ext - Bardage bois, Embodied Energy: 10 (MJ/kg); Component 6, Finition ext - Bardage bois, Embodied Carbon: 0.36 (kgCO₂/kg); Component 6, Finition ext - Bardage bois, Name: Finition ext - Bardage bois; Component 6, Finition ext - Bardage bois, Participates in Collision Detection: no; Component 4, Bois - Lattage, ThermalConductivity: 0.13; Component 4, Bois - Lattage, SpecificHeatCapacity: 1600 J/kg/K; Component 4, Bois - Lattage, MassDensity: 500 kg/m3; Component 4, Bois - Lattage, Embodied Energy: 6.95 (MJ/kg); Component 4, Bois - Lattage, Embodied Carbon: 0.29 (kgCO₂/kg); Component 4, Bois - Lattage, Name: Bois - Lattage; Component 4, Bois - Lattage, Participates in Collision Detection: yes; Component 3, Béton, ThermalConductivity: 2.3; Component 3, Béton, SpecificHeatCapacity: 1000 J/kg/K; Component 3, Béton, MassDensity: 2300 kg/m3; Component 3, Béton, Embodied Energy: 1.92 (MJ/kg); Component 3, Béton, Embodied Carbon: 0.198 (kgCO₂/kg); Component 3, Béton, Name: Béton; Component 3, Béton, Participates in Collision Detection: yes; Component 2, Etanchéité - Bitume, ThermalConductivity: 0.23; Component 2, Etanchéité - Bitume, SpecificHeatCapacity: 1000 J/kg/K; Component 2, Etanchéité - Bitume, MassDensity: 1100 kg/m3; Component 2, Etanchéité - Bitume, Embodied Energy: 2.86 (MJ/kg); Component 2, Etanchéité - Bitume, Embodied Carbon: 0.066 (kgCO₂/kg); Component 2, Etanchéité - Bitume, Name: Etanchéité - Bitume; Component 2, Etanchéité - Bitume, Participates in Collision Detection: no; Component 5, Finition ext - Crépis, ThermalConductivity: 0.8; Component 5, Finition ext - Crépis, SpecificHeatCapacity: 1000 J/kg/K; Component 5, Finition ext - Crépis, MassDensity: 1600 kg/m3; Component 5, Finition ext - Crépis, Embodied Energy: 1.4 (MJ/kg); Component 5, Finition ext - Crépis, Embodied Carbon: 0.09 (kgCO₂/kg); Component 5, Finition ext - Crépis, Name: Finition ext - Crépis; Component 5, Finition ext - Crépis, Participates in Collision Detection: no; Component 1, Métal - Aluminium, ThermalConductivity: 160; Component 1, Métal - Aluminium, SpecificHeatCapacity: 880 J/kg/K; Component 1, Métal - Aluminium, MassDensity: 2800 kg/m3; Component 1, Métal - Aluminium, Embodied Energy: 155 (MJ/kg); Component 1, Métal - Aluminium, Embodied Carbon: 9.16 (kgCO₂/kg); Component 1, Métal - Aluminium, Name: Métal - Aluminium; Component 1, Métal - Aluminium, Participates in Collision Detection: yes
BaseQuantities - Height: 0.6 m; Width: 0.292485 m
Name | Length (m) | GrossFootprintArea (m2) = NetFootprintArea (m2) | GrossSideArea (m2) = NetSideArea (m2) | GrossVolume (m3) = NetVolume (m3)
Muret béton 20cm | 8.27412 | 2.37267 | 5.4083 | 1.39155
Muret béton 20cm | 0.880809 | 0.201602 | 0.555 | 0.117525
Muret béton 20cm | 0.709566 | 0.180042 | 0.452386 | 0.105663

# IfcWall: Acrotère pour planelle 25 isolée TERRASSE ACCESSIBLE (1) 235 x 1220, Muret béton 20cm
In: R+2
Type - ElementType: PARAPET; PredefinedType: USERDEFINED
Description: Acrotère et GD terrasses; Classification: Mur d'acrotère (Classification ARCHICAD); Material: Métal - Aluminium, Finition ext - Crépis (2), Etanchéité - Bitume, Béton
Pset_WallCommon - AcousticRating: Non défini; ThermalTransmittance: 0; LoadBearing: yes; IsExternal: yes
PSET_Murs_ARCHI - Emplacement: Superstructure; Type: Mur béton 20cm; Destination: Muret formant garde-corps; Matériaux: BETON
Propriétés DCE - Numéro de LOT: LOT 04; LOT 16; Numéro article: L16.2.1
AC_Pset_RenovationAndPhasing - Renovation Status: Existing
Material Properties - Component 1, Métal - Aluminium, ThermalConductivity: 160; Component 1, Métal - Aluminium, SpecificHeatCapacity: 880 J/kg/K; Component 1, Métal - Aluminium, MassDensity: 2800 kg/m3; Component 1, Métal - Aluminium, Embodied Energy: 155 (MJ/kg); Component 1, Métal - Aluminium, Embodied Carbon: 9.16 (kgCO₂/kg); Component 1, Métal - Aluminium, Name: Métal - Aluminium; Component 1, Métal - Aluminium, Participates in Collision Detection: yes; Component 5, Finition ext - Crépis, ThermalConductivity: 0.8; Component 5, Finition ext - Crépis, SpecificHeatCapacity: 1000 J/kg/K; Component 5, Finition ext - Crépis, MassDensity: 1600 kg/m3; Component 5, Finition ext - Crépis, Embodied Energy: 1.4 (MJ/kg); Component 5, Finition ext - Crépis, Embodied Carbon: 0.09 (kgCO₂/kg); Component 5, Finition ext - Crépis, Name: Finition ext - Crépis; Component 5, Finition ext - Crépis, Participates in Collision Detection: no; Component 2, Etanchéité - Bitume, ThermalConductivity: 0.23; Component 2, Etanchéité - Bitume, SpecificHeatCapacity: 1000 J/kg/K; Component 2, Etanchéité - Bitume, MassDensity: 1100 kg/m3; Component 2, Etanchéité - Bitume, Embodied Energy: 2.86 (MJ/kg); Component 2, Etanchéité - Bitume, Embodied Carbon: 0.066 (kgCO₂/kg); Component 2, Etanchéité - Bitume, Name: Etanchéité - Bitume; Component 2, Etanchéité - Bitume, Participates in Collision Detection: no; Component 3, Béton, ThermalConductivity: 2.3; Component 3, Béton, SpecificHeatCapacity: 1000 J/kg/K; Component 3, Béton, MassDensity: 2300 kg/m3; Component 3, Béton, Embodied Energy: 1.92 (MJ/kg); Component 3, Béton, Embodied Carbon: 0.198 (kgCO₂/kg); Component 3, Béton, Name: Béton; Component 3, Béton, Participates in Collision Detection: yes; Component 5: 2 with these values
BaseQuantities - Length: 6.195 m; Height: 1.22 m; Width: 0.235485 m; GrossFootprintArea: 1.4322 m2; NetFootprintArea: 1.4322 m2; GrossSideArea: 7.80616 m2; NetSideArea: 7.80616 m2; GrossVolume: 1.72063 m3; NetVolume: 1.72063 m3

# IfcWall: Acrotère pour planelle 25 isolée TERRASSE ACCESSIBLE (1) 235 x 1330, Muret béton 20cm
In: R+4
Type - ElementType: PARAPET; PredefinedType: USERDEFINED
Description: Acrotère et GD terrasses; Classification: Mur d'acrotère (Classification ARCHICAD); Material: Métal - Aluminium, Finition ext - Crépis (2), Etanchéité - Bitume, Béton
Pset_WallCommon - AcousticRating: Non défini; ThermalTransmittance: 0; LoadBearing: yes; IsExternal: yes
PSET_Murs_ARCHI - Emplacement: Superstructure; Type: Mur béton 20cm; Destination: Muret formant garde-corps; Matériaux: BETON
Propriétés DCE - Numéro de LOT: LOT 04; LOT 16; Numéro article: L16.2.1
AC_Pset_RenovationAndPhasing - Renovation Status: Existing
Material Properties - Component 1, Métal - Aluminium, ThermalConductivity: 160; Component 1, Métal - Aluminium, SpecificHeatCapacity: 880 J/kg/K; Component 1, Métal - Aluminium, MassDensity: 2800 kg/m3; Component 1, Métal - Aluminium, Embodied Energy: 155 (MJ/kg); Component 1, Métal - Aluminium, Embodied Carbon: 9.16 (kgCO₂/kg); Component 1, Métal - Aluminium, Name: Métal - Aluminium; Component 1, Métal - Aluminium, Participates in Collision Detection: yes; Component 5, Finition ext - Crépis, ThermalConductivity: 0.8; Component 5, Finition ext - Crépis, SpecificHeatCapacity: 1000 J/kg/K; Component 5, Finition ext - Crépis, MassDensity: 1600 kg/m3; Component 5, Finition ext - Crépis, Embodied Energy: 1.4 (MJ/kg); Component 5, Finition ext - Crépis, Embodied Carbon: 0.09 (kgCO₂/kg); Component 5, Finition ext - Crépis, Name: Finition ext - Crépis; Component 5, Finition ext - Crépis, Participates in Collision Detection: no; Component 2, Etanchéité - Bitume, ThermalConductivity: 0.23; Component 2, Etanchéité - Bitume, SpecificHeatCapacity: 1000 J/kg/K; Component 2, Etanchéité - Bitume, MassDensity: 1100 kg/m3; Component 2, Etanchéité - Bitume, Embodied Energy: 2.86 (MJ/kg); Component 2, Etanchéité - Bitume, Embodied Carbon: 0.066 (kgCO₂/kg); Component 2, Etanchéité - Bitume, Name: Etanchéité - Bitume; Component 2, Etanchéité - Bitume, Participates in Collision Detection: no; Component 3, Béton, ThermalConductivity: 2.3; Component 3, Béton, SpecificHeatCapacity: 1000 J/kg/K; Component 3, Béton, MassDensity: 2300 kg/m3; Component 3, Béton, Embodied Energy: 1.92 (MJ/kg); Component 3, Béton, Embodied Carbon: 0.198 (kgCO₂/kg); Component 3, Béton, Name: Béton; Component 3, Béton, Participates in Collision Detection: yes; Component 5: 2 with these values
BaseQuantities - Length: 2.37634 m; Height: 1.33 m; Width: 0.235485 m; GrossFootprintArea: 0.634853 m2; NetFootprintArea: 0.634853 m2; GrossSideArea: 3.35922 m2; NetSideArea: 3.35922 m2; GrossVolume: 0.803287 m3; NetVolume: 0.803287 m3

# IfcWall: Acrotère ravalement contre terre 242 x 1000 (4)
In: Rez-de-chaussée
Type - ElementType: PARAPET; PredefinedType: USERDEFINED
Description: Acrotère et GD terrasses; Classification: Mur d'acrotère (Classification ARCHICAD); Material: Métal - Aluminium, Finition ext - Crépis (2), Etanchéité - Bitume, Béton
Pset_WallCommon - AcousticRating: Non défini; ThermalTransmittance: 0; LoadBearing: yes; IsExternal: yes
PSET_Murs_ARCHI - Emplacement: Superstructure; Type: Mur béton 20cm; Destination: Muret formant garde-corps; Matériaux: BETON
Propriétés DCE - Numéro de LOT: LOT 04; LOT 16; Numéro article: L16.2.1
AC_Pset_RenovationAndPhasing - Renovation Status: Existing
Material Properties - Component 1, Métal - Aluminium, ThermalConductivity: 160; Component 1, Métal - Aluminium, SpecificHeatCapacity: 880 J/kg/K; Component 1, Métal - Aluminium, MassDensity: 2800 kg/m3; Component 1, Métal - Aluminium, Embodied Energy: 155 (MJ/kg); Component 1, Métal - Aluminium, Embodied Carbon: 9.16 (kgCO₂/kg); Component 1, Métal - Aluminium, Name: Métal - Aluminium; Component 1, Métal - Aluminium, Participates in Collision Detection: yes; Component 5, Finition ext - Crépis, ThermalConductivity: 0.8; Component 5, Finition ext - Crépis, SpecificHeatCapacity: 1000 J/kg/K; Component 5, Finition ext - Crépis, MassDensity: 1600 kg/m3; Component 5, Finition ext - Crépis, Embodied Energy: 1.4 (MJ/kg); Component 5, Finition ext - Crépis, Embodied Carbon: 0.09 (kgCO₂/kg); Component 5, Finition ext - Crépis, Name: Finition ext - Crépis; Component 5, Finition ext - Crépis, Participates in Collision Detection: no; Component 2, Etanchéité - Bitume, ThermalConductivity: 0.23; Component 2, Etanchéité - Bitume, SpecificHeatCapacity: 1000 J/kg/K; Component 2, Etanchéité - Bitume, MassDensity: 1100 kg/m3; Component 2, Etanchéité - Bitume, Embodied Energy: 2.86 (MJ/kg); Component 2, Etanchéité - Bitume, Embodied Carbon: 0.066 (kgCO₂/kg); Component 2, Etanchéité - Bitume, Name: Etanchéité - Bitume; Component 2, Etanchéité - Bitume, Participates in Collision Detection: no; Component 3, Béton, ThermalConductivity: 2.3; Component 3, Béton, SpecificHeatCapacity: 1000 J/kg/K; Component 3, Béton, MassDensity: 2300 kg/m3; Component 3, Béton, Embodied Energy: 1.92 (MJ/kg); Component 3, Béton, Embodied Carbon: 0.198 (kgCO₂/kg); Component 3, Béton, Name: Béton; Component 3, Béton, Participates in Collision Detection: yes; Component 5: 2 with these values
BaseQuantities - Width: 0.242485 m
Name | Length (m) | Height (m) | GrossFootprintArea (m2) = NetFootprintArea (m2) | GrossSideArea (m2) = NetSideArea (m2) | GrossVolume (m3) = NetVolume (m3)
Muret béton 20cm | 6.30387 | 1 | 1.41109 | 6.48834 | 1.38184
Muret béton 20cm | 3.13893 | 0.978827 | 0.725542 | 3.18811 | 0.693926
Muret béton 20cm | 3.89819 | 1 | 0.894929 | 3.82613 | 0.857601
Muret béton 20cm | 0.67949 | 1 | 0.157108 | 0.700327 | 0.153418

# IfcWall: Bois - Mélaminé blanc 20 (14)
Type - ElementType: PARTITIONING; PredefinedType: USERDEFINED
Description: Façade menuisées; Classification: Accessoire distinct (Classification ARCHICAD); Cloison (Classification ARCHICAD); Material: Bois - Mélaminé blanc
Pset_WallCommon - AcousticRating: Non défini; ThermalTransmittance: 0; LoadBearing: yes; IsExternal: yes
Propriétés DCE - Numéro de LOT: LOT 12; Numéro article: L12.2.1.5.2
AC_Pset_RenovationAndPhasing - Renovation Status: Existing
Material Properties - Bois - Mélaminé blanc, ThermalConductivity: 0.1; Bois - Mélaminé blanc, SpecificHeatCapacity: 1700 J/kg/K; Bois - Mélaminé blanc, MassDensity: 300 kg/m3; Bois - Mélaminé blanc, Embodied Energy: 14.2 (MJ/kg); Bois - Mélaminé blanc, Embodied Carbon: 0.58 (kgCO₂/kg); Bois - Mélaminé blanc, Name: Bois - Mélaminé blanc; Bois - Mélaminé blanc, Participates in Collision Detection: yes
BaseQuantities - Height: 1 m; Width: 0.02 m
Name | In | Length (m) | GrossFootprintArea (m2) = NetFootprintArea (m2) = GrossVolume (m3) = NetVolume (m3) | GrossSideArea (m2) = NetSideArea (m2)
Panneaux 20mm mélaminé blanc | Rez-de-chaussée | 0.553 | 0.01084 | 0.542
Panneaux 20mm mélaminé blanc | R+1 | 0.553 | 0.01084 | 0.542
Panneaux 20mm mélaminé blanc | R+2 | 0.553 | 0.01084 | 0.542
Panneaux 20mm mélaminé blanc | Rez-de-chaussée | 0.636624 | 0.0129925 | 0.649624
Panneaux 20mm mélaminé blanc | Rez-de-chaussée | 0.65 | 0.0132 | 0.66
Panneaux 20mm mélaminé blanc | Rez-de-chaussée | 0.718 | 0.01388 | 0.694
Panneaux 20mm mélaminé blanc | Rez-de-chaussée | 0.647 | 0.01246 | 0.623
Panneaux 20mm mélaminé blanc | R+1 | 0.636624 | 0.0129925 | 0.649624
Panneaux 20mm mélaminé blanc | R+1 | 0.65 | 0.0132 | 0.66
Panneaux 20mm mélaminé blanc | R+1 | 0.718 | 0.01388 | 0.694
Panneaux 20mm mélaminé blanc | R+1 | 0.647 | 0.01246 | 0.623
Panneaux 20mm mélaminé blanc | R+2 | 0.647 | 0.01246 | 0.623
Panneaux 20mm mélaminé blanc | R+2 | 0.718 | 0.01388 | 0.694
Panneaux 20mm mélaminé blanc | R+3 | 0.977 | 0.01906 | 0.953

# IfcWall: Béton 10, M_Ext-012
In: R+3
Type - ElementType: SOLIDWALL; PredefinedType: USERDEFINED
Classification: Mur porteur (Classification ARCHICAD); Material: Béton
Pset_WallCommon - AcousticRating: Non défini; ThermalTransmittance: 0; LoadBearing: yes; IsExternal: yes
PSET_Murs_ARCHI - Emplacement: Infrastructure; Type: Mur béton banché 20cm; Destination: Ouvrage divers en Infrastructure; Ouvrage extérieur; Matériaux: BETON
Propriétés DCE - Numéro de LOT: LOT 04
AC_Pset_RenovationAndPhasing - Renovation Status: Existing
Material Properties - Béton, ThermalConductivity: 2.3; Béton, SpecificHeatCapacity: 1000 J/kg/K; Béton, MassDensity: 2300 kg/m3; Béton, Embodied Energy: 1.92 (MJ/kg); Béton, Embodied Carbon: 0.198 (kgCO₂/kg); Béton, Name: Béton; Béton, Participates in Collision Detection: yes
BaseQuantities - Length: 0.0974078 m; Height: 1.25 m; Width: 0.01 m; GrossFootprintArea: 0.000974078 m2; NetFootprintArea: 0.000974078 m2; GrossSideArea: 0.12176 m2; NetSideArea: 0.12176 m2; GrossVolume: 0.0012176 m3; NetVolume: 0.0012176 m3

# IfcWall: Béton 100 (2)
In: Sous-sol
Type - ElementType: PARTITIONING; PredefinedType: USERDEFINED
Classification: Cloison (Classification ARCHICAD); Material: Béton
Pset_WallCommon - AcousticRating: Non défini; ThermalTransmittance: 0; LoadBearing: no; IsExternal: no
PSET_Murs_ARCHI - Emplacement: Infrastructure; Type: Mur en bloc de maçonnerie parpaing 10cm; Destination: Mur intérieur; Matériaux: Maçonnerie Parpaing 10 cm
Propriétés DCE - Numéro de LOT: LOT 04
AC_Pset_RenovationAndPhasing - Renovation Status: Existing
Material Properties - Béton, ThermalConductivity: 2.3; Béton, SpecificHeatCapacity: 1000 J/kg/K; Béton, MassDensity: 2300 kg/m3; Béton, Embodied Energy: 1.92 (MJ/kg); Béton, Embodied Carbon: 0.198 (kgCO₂/kg); Béton, Name: Béton; Béton, Participates in Collision Detection: yes
BaseQuantities - Width: 0.1 m
Name | Length (m) | Height (m) | GrossFootprintArea (m2) = NetFootprintArea (m2) | GrossSideArea (m2) | NetSideArea (m2) | GrossVolume (m3) | NetVolume (m3)
M_Ext-009 | 0.636364 | 2.37 | 0.0736364 | 1.74518 | 1.65518 | 0.174518 | 0.165518
M_Ext-012 | 11.5906 | 0.767434 | 1.15906 | 8.89502 | 8.89502 | 0.889502 | 0.889502

# IfcWall: Béton 150 (3)
In: Sous-sol
Type - PredefinedType: STANDARD
Description: Murs extérieurs; Classification: Mur standard (Classification ARCHICAD); Material: Béton
Pset_WallCommon - AcousticRating: Non défini; ThermalTransmittance: 0; LoadBearing: yes; IsExternal: yes
PSET_Murs_ARCHI - Emplacement: Extérieur; Type: Mur béton banché 20cm; Destination: Mur contre terre; Matériaux: BETON
Propriétés DCE - Numéro de LOT: LOT 04
AC_Pset_RenovationAndPhasing - Renovation Status: Existing
Material Properties - Béton, ThermalConductivity: 2.3; Béton, SpecificHeatCapacity: 1000 J/kg/K; Béton, MassDensity: 2300 kg/m3; Béton, Embodied Energy: 1.92 (MJ/kg); Béton, Embodied Carbon: 0.198 (kgCO₂/kg); Béton, Name: Béton; Béton, Participates in Collision Detection: yes
BaseQuantities - Height: 0.4 m; Width: 0.15 m
Name | Length (m) | GrossFootprintArea (m2) = NetFootprintArea (m2) | GrossSideArea (m2) = NetSideArea (m2) | GrossVolume (m3) = NetVolume (m3)
Mur béton 20cm | 4.885 | 0.72 | 1.92 | 0.288
Mur béton 20cm | 4.76678 | 0.730208 | 1.94722 | 0.292083
Mur béton 20cm | 2.29044 | 0.328375 | 0.875665 | 0.13135

# IfcWall: Béton 160 (2)
Type - ElementType: SOLIDWALL; PredefinedType: USERDEFINED
Classification: Mur porteur (Classification ARCHICAD); Material: Béton
Pset_WallCommon - AcousticRating: Non défini; ThermalTransmittance: 0; LoadBearing: yes; IsExternal: yes
PSET_Murs_ARCHI - Emplacement: Superstructure; Type: Mur béton banché 18cm; Destination: Mur intérieur; Matériaux: BETON
Propriétés DCE - Numéro de LOT: LOT 04; Numéro article: L04.2.12.4
AC_Pset_RenovationAndPhasing - Renovation Status: Existing
Material Properties - Béton, ThermalConductivity: 2.3; Béton, SpecificHeatCapacity: 1000 J/kg/K; Béton, MassDensity: 2300 kg/m3; Béton, Embodied Energy: 1.92 (MJ/kg); Béton, Embodied Carbon: 0.198 (kgCO₂/kg); Béton, Name: Béton; Béton, Participates in Collision Detection: yes
BaseQuantities - Height: 2.51 m; Width: 0.16 m
Name | In | Length (m) | GrossFootprintArea (m2) = NetFootprintArea (m2) | GrossSideArea (m2) = NetSideArea (m2) | GrossVolume (m3) = NetVolume (m3)
M_Ext-008 | R+1 | 0.279088 | 0.044654 | 0.70051 | 0.112082
M_Ext-008 | R+2 | 0.402865 | 0.0733383 | 1.1505 | 0.184079

# IfcWall: Béton 180 (42)
Type - ElementType: SOLIDWALL; PredefinedType: USERDEFINED
Material: Béton
Pset_WallCommon - AcousticRating: Non défini; ThermalTransmittance: 0; LoadBearing: yes; IsExternal: yes
PSET_Murs_ARCHI - Type: Mur béton banché 18cm; Matériaux: BETON
Propriétés DCE - Numéro de LOT: LOT 04
AC_Pset_RenovationAndPhasing - Renovation Status: Existing
Material Properties - Béton, ThermalConductivity: 2.3; Béton, SpecificHeatCapacity: 1000 J/kg/K; Béton, MassDensity: 2300 kg/m3; Béton, Embodied Energy: 1.92 (MJ/kg); Béton, Embodied Carbon: 0.198 (kgCO₂/kg); Béton, Name: Béton; Béton, Participates in Collision Detection: yes
BaseQuantities - Width: 0.18 m
Name | In | Classification | Emplacement | Destination | Numéro article | Length (m) | Height (m) | GrossFootprintArea (m2) = NetFootprintArea (m2) | GrossSideArea (m2) = NetSideArea (m2) | GrossVolume (m3) = NetVolume (m3)
M_Ext-009 | Rez-de-chaussée | Mur porteur (Classification ARCHICAD) | Superstructure | Mur intérieur | L04.2.12.3.2 | 0.56 | 2.51 | 0.1008 | 1.4056 | 0.253008
M_Ext-008 | Rez-de-chaussée | Mur porteur (Classification ARCHICAD) | Infrastructure | Façade | L04.2.12.4 | 0.279088 | 2.51 | 0.0502358 | 0.70051 | 0.126092
M_Ext-009 | R+3 | Mur porteur (Classification ARCHICAD); Mur (Classification ARCHICAD) | Superstructure | Mur intérieur | L04.2.12.3.2 | 0.744976 | 2.5 | 0.144086 | 2.00119 | 0.360214
M_Ext-009 | R+3 | Mur porteur (Classification ARCHICAD) | Superstructure | Mur intérieur; Mur joint de dilatation | L04.2.12.4 | 0.584 | 2.5 | 0.1251 | 1.7375 | 0.31275
M_Ext-008 | Rez-de-chaussée | Mur porteur (Classification ARCHICAD) | Infrastructure | Façade | L04.2.12.4 | 0.662901 | 2.51 | 0.134622 | 1.87723 | 0.337902
M_Ext-008 | Rez-de-chaussée | Mur porteur (Classification ARCHICAD) | Infrastructure | Façade | L04.2.12.4 | 0.622449 | 2.51 | 0.127341 | 1.7757 | 0.319626
M_Ext-009 | Rez-de-chaussée | Mur porteur (Classification ARCHICAD) | Infrastructure | Façade | L04.2.12.4 | 0.763 | 2.5 | 0.144 | 1.99999 | 0.359999
M_Ext-009 | Rez-de-chaussée | Mur porteur (Classification ARCHICAD) | Infrastructure | Façade | L04.2.12.4 | 0.668 | 2.51 | 0.13554 | 1.89003 | 0.340205
M_Ext-009 | Rez-de-chaussée | Mur porteur (Classification ARCHICAD) | Infrastructure | Façade | L04.2.12.4 | 0.705 | 2.51 | 0.1422 | 1.9829 | 0.356922
4 x M_Ext-008 | R+1 | Mur porteur (Classification ARCHICAD); Mur (Classification ARCHICAD) | Superstructure | Mur intérieur | L04.2.12.3.2 | 0.13 | 2.51 | 0.0234 | 0.3263 | 0.058734
M_Ext-009 | R+1 | Mur porteur (Classification ARCHICAD) | Superstructure | Mur intérieur; Mur joint de dilatation | L04.2.12.4 | 0.705 | 2.51 | 0.1422 | 1.9829 | 0.356922
M_Ext-009 | R+1 | Mur porteur (Classification ARCHICAD) | Superstructure | Mur intérieur; Mur joint de dilatation | L04.2.12.4 | 0.668 | 2.51 | 0.13554 | 1.89003 | 0.340205
M_Ext-008 | R+1 | Mur porteur (Classification ARCHICAD) | Superstructure | Mur intérieur; Mur joint de dilatation | L04.2.12.4 | 0.657901 | 2.52 | 0.134622 | 1.87662 | 0.337487
M_Ext-008 | R+1 | Mur porteur (Classification ARCHICAD) | Superstructure | Mur intérieur; Mur joint de dilatation | L04.2.12.4 | 0.617449 | 2.47 | 0.0949408 | 1.3028 | 0.234504
M_Ext-009 | R+1 | Mur porteur (Classification ARCHICAD) | Superstructure | Mur intérieur; Mur joint de dilatation | L04.2.12.4 | 0.763 | 2.5 | 0.144 | 1.99999 | 0.359999
M_Ext-009 | R+1 | Mur porteur (Classification ARCHICAD); Mur (Classification ARCHICAD) | Superstructure | Mur intérieur | L04.2.12.3.2 | 0.705476 | 2.5 | 0.109886 | 1.52619 | 0.274714
M_Ext-009 | R+1 | Mur porteur (Classification ARCHICAD); Mur (Classification ARCHICAD) | Superstructure | Mur intérieur | L04.2.12.3.2 | 0.13 | 2.51 | 0.0234 | 0.3263 | 0.058734
M_Ext-009 | R+2 | Mur porteur (Classification ARCHICAD) | Superstructure | Mur intérieur; Mur joint de dilatation | L04.2.12.4 | 0.763 | 2.5 | 0.144 | 1.99999 | 0.359999
M_Ext-009 | R+2 | Mur porteur (Classification ARCHICAD) | Superstructure | Mur intérieur; Mur joint de dilatation | L04.2.12.4 | 0.705 | 2.51 | 0.1422 | 1.9829 | 0.356922
M_Ext-009 | R+2 | Mur porteur (Classification ARCHICAD); Mur (Classification ARCHICAD) | Superstructure | Mur intérieur | L04.2.12.3.2 | 0.705476 | 2.5 | 0.109886 | 1.52619 | 0.274714
M_Ext-009 | R+2 | Mur porteur (Classification ARCHICAD); Mur (Classification ARCHICAD) | Superstructure | Mur intérieur | L04.2.12.3.2 | 0.13 | 2.51 | 0.0234 | 0.3263 | 0.058734
M_Ext-009 | R+2 | Mur porteur (Classification ARCHICAD) | Superstructure | Mur intérieur; Mur joint de dilatation | L04.2.12.4 | 0.668 | 2.51 | 0.13554 | 1.89003 | 0.340205
M_Ext-009 | R+3 | Mur porteur (Classification ARCHICAD) | Superstructure | Mur intérieur; Mur joint de dilatation | L04.2.12.4 | 0.668 | 2.51 | 0.13554 | 1.87877 | 0.338179
M_Ext-009 | R+3 | Mur porteur (Classification ARCHICAD) | Superstructure | Mur intérieur; Mur joint de dilatation | L04.2.12.4 | 1.453 | 2.51 | 0.27684 | 3.86038 | 0.694868
M_Ext-009 | Rez-de-chaussée | Mur porteur (Classification ARCHICAD) | Superstructure | Mur intérieur | L04.2.12.3.2 | 0.12 | 2.5 | 0.0216 | 0.3 | 0.054
5 x M_Ext-008 | Rez-de-chaussée | Mur porteur (Classification ARCHICAD) | Superstructure | Mur intérieur | L04.2.12.3.2 | 0.13 | 2.51 | 0.0234 | 0.3263 | 0.058734
M_Ext-009 | Rez-de-chaussée | Mur porteur (Classification ARCHICAD) | Superstructure | Mur intérieur | L04.2.12.3.2 | 0.13 | 2.5 | 0.0234 | 0.325 | 0.0585
M_Ext-008 | Rez-de-chaussée | Mur porteur (Classification ARCHICAD) | Superstructure | Mur intérieur | L04.2.12.3.2 | 0.12 | 2.51 | 0.0216 | 0.3012 | 0.054216
M_Ext-009 | Rez-de-chaussée | Mur porteur (Classification ARCHICAD) | Superstructure | Mur intérieur | L04.2.12.3.2 | 0.705476 | 2.5 | 0.142286 | 1.97619 | 0.355714
2 x M_Ext-009 | R+1 | Mur porteur (Classification ARCHICAD) | Superstructure | Mur intérieur; Mur joint de dilatation | L04.2.12.4 | 0.13 | 2.51 | 0.0234 | 0.3263 | 0.058734
2 x M_Ext-009 | R+2 | Mur porteur (Classification ARCHICAD) | Superstructure | Mur intérieur; Mur joint de dilatation | L04.2.12.4 | 0.13 | 2.51 | 0.0234 | 0.3263 | 0.058734
2 x M_Ext-009 | R+3 | Mur porteur (Classification ARCHICAD) | Superstructure | Mur intérieur; Mur joint de dilatation | L04.2.12.4 | 0.11 | 2.51 | 0.0198 | 0.2761 | 0.049698

# IfcWall: Béton 200 (45)
In: Sous-sol
Type - ElementType: SOLIDWALL; PredefinedType: USERDEFINED
Classification: Mur porteur (Classification ARCHICAD); Material: Béton
Pset_WallCommon - AcousticRating: Non défini; ThermalTransmittance: 0; LoadBearing: yes
PSET_Murs_ARCHI - Emplacement: Infrastructure; Matériaux: BETON
Propriétés DCE - Numéro article: L04.2.8.3
AC_Pset_RenovationAndPhasing - Renovation Status: Existing
Material Properties - Béton, ThermalConductivity: 2.3; Béton, SpecificHeatCapacity: 1000 J/kg/K; Béton, MassDensity: 2300 kg/m3; Béton, Embodied Energy: 1.92 (MJ/kg); Béton, Embodied Carbon: 0.198 (kgCO₂/kg); Béton, Name: Béton; Béton, Participates in Collision Detection: yes
BaseQuantities - Width: 0.2 m
Name | IsExternal | Type | Destination | Numéro de LOT | Length (m) | Height (m) | GrossFootprintArea (m2) = NetFootprintArea (m2) | GrossSideArea (m2) | NetSideArea (m2) | GrossVolume (m3) | NetVolume (m3)
M_Ext-007 | no | Mur béton banché 20cm | Mur intérieur | LOT 04 | 16.4216 | 2.67 | 3.24433 | 42.6051 | 42.6051 | 8.52095 | 8.52095
M_Ext-007 | no | Mur béton banché 20cm | Mur intérieur | LOT 04 | 4.21 | 2.37 | 0.782 | 9.9777 | 9.4427 | 1.99554 | 1.88854
M_Ext-007 | no | Mur béton banché 20cm | Mur intérieur | LOT 04 | 10.8499 | 2.67 | 2.2044 | 28.9251 | 28.9251 | 5.77556 | 5.77556
M_Ext-007 | no | Mur béton banché 20cm | Mur intérieur | LOT 04 | 1.92929 | 2.67 | 0.181859 | 5.0263 | 2.90421 | 1.00526 | 0.580789
M_Ext-002 | yes | Voile projeté contre terre | Mur contre terre | LOT 03 | 5.18373 | 3.15 | 1.08675 | 15.7664 | 13.6397 | 3.27806 | 2.85272
M_Ext-007 | no | Mur béton banché 20cm | Mur intérieur | LOT 04 | 2.8 | 2.67 | 0.58 | 7.14845 | 7.14845 | 1.42969 | 1.42969
M_Ext-007 | no | Mur béton banché 20cm | Mur intérieur | LOT 04 | 4.55125 | 2.67 | 0.895676 | 11.9223 | 11.9223 | 2.38444 | 2.38444
M_Ext-007 | no | Mur béton banché 20cm | Mur intérieur | LOT 04 | 2.25203 | 2.67 | 0.211984 | 5.5204 | 3.3937 | 1.10408 | 0.678739
M_Ext-007 | no | Mur béton banché 20cm | Mur intérieur | LOT 04 | 2.66737 | 2.67 | 0.473473 | 6.24087 | 6.24087 | 1.24817 | 1.24817
M_Ext-007 | no | Mur béton banché 20cm | Mur intérieur | LOT 04 | 2.19939 | 2.37 | 0.243816 | 5.30389 | 3.17719 | 1.06131 | 0.635969
M_Ext-007 | no | Mur béton banché 20cm | Mur intérieur | LOT 04 | 3.29547 | 2.67 | 0.669093 | 8.93239 | 8.93239 | 1.78648 | 1.78648
M_Ext-007 | no | Mur béton banché 20cm | Mur intérieur | LOT 04 | 2.56188 | 2.67 | 0.492377 | 6.57323 | 6.57323 | 1.31465 | 1.31465
M_Ext-007 | no | Mur béton banché 20cm | Mur intérieur | LOT 04 | 3.3273 | 2.37 | 0.66546 | 7.8857 | 7.8857 | 1.57714 | 1.57714
M_Ext-007 | no | Mur béton banché 20cm | Mur intérieur | LOT 04 | 1.49544 | 2.67 | 0.115089 | 4.25984 | 2.13314 | 0.851968 | 0.426628
M_Ext-007 | no | Mur béton banché 20cm | Mur intérieur | LOT 04 | 1.61126 | 2.67 | 0.346826 | 4.63013 | 4.63013 | 0.926025 | 0.926025
M_Ext-007 | no | Mur béton banché 20cm | Mur intérieur | LOT 04 | 1.99263 | 2.62 | 0.378527 | 4.9587 | 4.9587 | 0.99174 | 0.99174
M_Ext-007 | no | Mur béton banché 20cm | Mur intérieur | LOT 04 | 2.64497 | 2.37 | 0.553568 | 6.51127 | 6.51127 | 1.30153 | 1.30153
M_Ext-007 | no | Mur béton banché 20cm | Mur intérieur | LOT 04 | 0.770735 | 2.37 | 0.119725 | 1.41874 | 1.41874 | 0.283748 | 0.283748
M_Ext-007 | no | Mur béton banché 20cm | Mur intérieur | LOT 04 | 1.975 | 2.67 | 0.435 | 5.79725 | 5.79725 | 1.15945 | 1.15945
M_Ext-007 | no | Mur béton banché 20cm | Mur intérieur | LOT 04 | 2.30412 | 2.37 | 0.291245 | 5.83334 | 3.70664 | 1.16619 | 0.740853
M_Ext-007 | no | Mur béton banché 20cm | Mur intérieur | LOT 04 | 1.53787 | 2.37 | 0.113423 | 3.76016 | 1.63346 | 0.752224 | 0.326884
M_Ext-007 | no | Mur béton banché 20cm | Mur intérieur | LOT 04 | 1.167 | 2.67 | 0.2334 | 3.11589 | 3.11589 | 0.623178 | 0.623178
M_Ext-007 | no | Mur béton banché 20cm | Mur intérieur | LOT 04 | 2.32793 | 2.37 | 0.485585 | 5.75418 | 5.75418 | 1.15084 | 1.15084
M_Ext-007 | no | Mur béton banché 20cm | Mur intérieur | LOT 04 | 1.62 | 2.55 | 0.1 | 3.876 | 1.7493 | 0.7752 | 0.34986
M_Ext-007 | no | Mur béton banché 20cm | Mur intérieur | LOT 04 | 2.27849 | 2.67 | 0.420808 | 5.61779 | 5.61779 | 1.12356 | 1.12356
M_Ext-007 | no | Mur béton banché 20cm | Mur intérieur | LOT 04 | 0.0956296 | 2.67 | 0.0126702 | 0.207818 | 0.207818 | 0.0338294 | 0.0338294
M_Ext-007 | no | Mur béton banché 20cm | Mur intérieur | LOT 04 | 2.00824 | 2.55 | 0.421648 | 5.37602 | 5.37602 | 1.0752 | 1.0752
M_Ext-007 | no | Mur béton banché 20cm | Mur intérieur | LOT 04 | 0.947292 | 2.67 | 0.204348 | 2.72804 | 2.72804 | 0.545609 | 0.545609
M_Ext-007 | no | Mur béton banché 20cm | Mur intérieur | LOT 04 | 1 | 2.58 | 0.2 | 2.38509 | 2.38509 | 0.474076 | 0.474076
M_Ext-007 | no | Mur béton banché 20cm | Mur intérieur | LOT 04 | 3.78729 | 2.37 | 0.777458 | 9.21287 | 9.21287 | 1.84257 | 1.84257
M_Ext-007 | no | Mur béton banché 20cm | Mur intérieur | LOT 04 | 2.7 | 2.37 | 0.54 | 6.399 | 6.399 | 1.2798 | 1.2798
M_Ext-007 | no | Mur béton banché 20cm | Mur intérieur | LOT 04 | 3.25195 | 2.37 | 0.622452 | 7.37605 | 7.37605 | 1.47521 | 1.47521
M_Ext-007 | no | Mur béton banché 20cm | Mur intérieur | LOT 04 | 5.39177 | 2.67 | 1.02564 | 13.5146 | 13.5146 | 2.72669 | 2.72669
M_Ext-007 | no | Mur béton banché 20cm | Mur intérieur | LOT 04 | 3.25803 | 2.67 | 0.651606 | 8.69893 | 8.69893 | 1.73979 | 1.73979
M_Ext-007 | no | Mur béton banché 20cm | Mur intérieur | LOT 04 | 0.7 | 2.4 | 0.14 | 1.68 | 1.68 | 0.336 | 0.336
M_Ext-007 | no | Mur béton banché 20cm | Mur intérieur | LOT 04 | 0.75 | 2.1 | 0.15 | 1.575 | 1.575 | 0.315 | 0.315
M_Ext-007 | no | Mur béton banché 20cm | Mur intérieur | LOT 04 | 1.04197 | 2.3 | 0.208394 | 2.39654 | 2.39654 | 0.479307 | 0.479307
M_Ext-007 | no | Mur béton banché 20cm | Mur intérieur | LOT 04 | 5.00235 | 2.67 | 1.00047 | 12.0454 | 12.0454 | 2.40642 | 2.40642
M_Ext-007 | no | Mur béton banché 20cm | Mur intérieur | LOT 04 | 10.6024 | 2.67 | 2.10048 | 27.2337 | 27.2337 | 5.4489 | 5.4489
M_Ext-007 | no | Mur béton banché 20cm | Mur intérieur | LOT 04 | 2.83468 | 2.58 | 0.566935 | 7.31346 | 7.31346 | 1.46269 | 1.46269
M_Ext-007 | no | Mur béton banché 20cm | Mur intérieur | LOT 04 | 2.36141 | 2.67 | 0.472282 | 6.30496 | 6.30496 | 1.26099 | 1.26099
M_Ext-007 | no | Mur béton banché 20cm | Mur intérieur | LOT 04 | 2.47505 | 2.67 | 0.495011 | 5.71868 | 5.71868 | 1.14407 | 1.14407
M_Ext-007 | no | Mur béton banché 20cm | Mur intérieur | LOT 04 | 1.90164 | 2.67 | 0.380327 | 4.61131 | 4.61131 | 0.936029 | 0.936029
M_Ext-007 | no | Mur béton banché 20cm | Mur intérieur | LOT 04 | 1.90164 | 2.67 | 0.380327 | 4.61395 | 4.61395 | 0.936639 | 0.936639
M_Ext-007 | no | Mur béton banché 20cm | Mur intérieur | LOT 04 | 10.3731 | 2.67 | 2.07462 | 27.06 | 27.06 | 5.52391 | 5.52391

# IfcWall: Béton 200, Mur béton 20cm
In: Sous-sol
Type - PredefinedType: STANDARD
Description: Murs extérieurs; Classification: Mur standard (Classification ARCHICAD); Material: Béton
Pset_WallCommon - AcousticRating: Non défini; ThermalTransmittance: 0; LoadBearing: yes; IsExternal: yes
PSET_Murs_ARCHI - Emplacement: Extérieur; Type: Mur béton banché 20cm; Destination: Mur contre terre; Matériaux: BETON
Propriétés DCE - Numéro de LOT: LOT 04; Numéro article: L04.21.1.6.; L16.2.1
AC_Pset_RenovationAndPhasing - Renovation Status: Existing
Material Properties - Béton, ThermalConductivity: 2.3; Béton, SpecificHeatCapacity: 1000 J/kg/K; Béton, MassDensity: 2300 kg/m3; Béton, Embodied Energy: 1.92 (MJ/kg); Béton, Embodied Carbon: 0.198 (kgCO₂/kg); Béton, Name: Béton; Béton, Participates in Collision Detection: yes
BaseQuantities - Length: 5.07494 m; Height: 2.37 m; Width: 0.2 m; GrossFootprintArea: 1.02999 m2; NetFootprintArea: 1.02999 m2; GrossSideArea: 11.9099 m2; NetSideArea: 11.9099 m2; GrossVolume: 2.38197 m3; NetVolume: 2.38197 m3

# IfcWall: Béton 250 (15)
Type - ElementType: SOLIDWALL; PredefinedType: USERDEFINED
Description: Voile contre terre; Classification: Mur porteur (Classification ARCHICAD); Material: Béton
Pset_WallCommon - AcousticRating: Non défini; ThermalTransmittance: 0; LoadBearing: yes; IsExternal: yes
PSET_Murs_ARCHI - Emplacement: Infrastructure; Type: Voile projeté contre terre; Destination: Mur contre terre; Matériaux: BETON
Propriétés DCE - Numéro de LOT: LOT 03
AC_Pset_RenovationAndPhasing - Renovation Status: Existing
Material Properties - Béton, ThermalConductivity: 2.3; Béton, SpecificHeatCapacity: 1000 J/kg/K; Béton, MassDensity: 2300 kg/m3; Béton, Embodied Energy: 1.92 (MJ/kg); Béton, Embodied Carbon: 0.198 (kgCO₂/kg); Béton, Name: Béton; Béton, Participates in Collision Detection: yes
BaseQuantities - Width: 0.25 m
Name | In | Length (m) | Height (m) | GrossFootprintArea (m2) = NetFootprintArea (m2) | GrossSideArea (m2) = NetSideArea (m2) | GrossVolume (m3) = NetVolume (m3)
Voile projeté béton par passes alternées | Sous-sol | 3.27434 | 3.22 | 0.742579 | 9.25457 | 2.36673
Voile projeté béton par passes alternées | Rez-de-chaussée | 5.23683 | 0.493 | 1.25921 | 2.48316 | 0.620789
Voile projeté béton par passes alternées | Sous-sol | 4.485 | 3.22 | 1.115 | 14.3612 | 3.5903
Voile projeté béton par passes alternées | Sous-sol | 1.51498 | 3.22 | 0.378745 | 4.8725 | 1.21813
Voile projeté béton par passes alternées | Sous-sol | 2.95152 | 2.88 | 0.691804 | 7.75533 | 1.99124
Voile projeté béton par passes alternées | Sous-sol | 4.67983 | 3.25 | 1.20121 | 15.0294 | 3.8882
Voile projeté béton par passes alternées | Sous-sol | 6.16247 | 3.22 | 1.62812 | 20.9701 | 5.24253
Voile projeté béton par passes alternées | Sous-sol | 1.45 | 3 | 0.3 | 3.6 | 0.9
Voile projeté béton par passes alternées | Sous-sol | 0.24378 | 3.02 | 0.0840702 | 1.01551 | 0.253879
Voile projeté béton par passes alternées | Sous-sol | 15.4038 | 3.25 | 3.91519 | 48.3984 | 12.4164
Voile projeté béton par passes alternées | Sous-sol | 5.41623 | 3.22 | 1.40843 | 18.1406 | 4.53515
Voile projeté béton par passes alternées | Sous-sol | 5.23683 | 3.22 | 1.30921 | 16.8626 | 4.21564
Voile projeté béton par passes alternées | Sous-sol | 7.90128 | 2.88 | 1.97532 | 22.5847 | 5.688
Voile projeté béton par passes alternées | Rez-de-chaussée | 4.80483 | 0.4331 | 1.20121 | 2.08097 | 0.520242
Voile projeté béton par passes alternées | Sous-sol | 2.40041 | 3.22 | 0.600101 | 7.72931 | 1.93233

# IfcWall: Béton 300 (21)
Type - ElementType: SOLIDWALL; PredefinedType: USERDEFINED
Description: Voile contre terre; Classification: Mur porteur (Classification ARCHICAD); Material: Béton
Pset_WallCommon - AcousticRating: Non défini; ThermalTransmittance: 0; LoadBearing: yes; IsExternal: yes
PSET_Murs_ARCHI - Emplacement: Infrastructure; Type: Voile projeté contre terre; Destination: Mur contre terre; Matériaux: BETON
Propriétés DCE - Numéro de LOT: LOT 03
AC_Pset_RenovationAndPhasing - Renovation Status: Existing
Material Properties - Béton, ThermalConductivity: 2.3; Béton, SpecificHeatCapacity: 1000 J/kg/K; Béton, MassDensity: 2300 kg/m3; Béton, Embodied Energy: 1.92 (MJ/kg); Béton, Embodied Carbon: 0.198 (kgCO₂/kg); Béton, Name: Béton; Béton, Participates in Collision Detection: yes
BaseQuantities - Width: 0.3 m
Name | In | Length (m) | Height (m) | GrossFootprintArea (m2) = NetFootprintArea (m2) | GrossSideArea (m2) = NetSideArea (m2) | GrossVolume (m3) = NetVolume (m3)
Voile projeté béton par passes alternées | Sous-sol | 25.9116 | 2.97 | 7.77455 | 76.9501 | 23.085
Voile projeté béton par passes alternées | Sous-sol | 16.51 | 3.22 | 4.84013 | 52.1993 | 15.5635
Voile projeté béton par passes alternées | Rez-de-chaussée | 12.6033 | 3.6 | 3.78098 | 45.3718 | 13.6115
Voile projeté béton par passes alternées | Sous-sol | 18.5616 | 3.22 | 5.57878 | 59.8789 | 17.9637
Voile projeté béton par passes alternées | Rez-de-chaussée | 4.38293 | 1.64189 | 1.31488 | 7.1963 | 2.15889
Voile projeté béton par passes alternées | Rez-de-chaussée | 1.515 | 4.1 | 0.4545 | 6.2115 | 1.86345
Voile projeté béton par passes alternées | Rez-de-chaussée | 5.60497 | 4.2 | 1.61863 | 22.6469 | 6.79406
Voile projeté béton par passes alternées | Rez-de-chaussée | 4.79513 | 2.8 | 1.49383 | 13.9424 | 4.18272
Voile projeté béton par passes alternées | Sous-sol | 5.31276 | 3.22 | 1.59383 | 17.1071 | 5.13213
Voile projeté béton par passes alternées | Sous-sol | 12.6033 | 3.22 | 3.87098 | 41.5485 | 12.4646
Voile projeté béton par passes alternées | Sous-sol | 1.36478 | 3.22 | 0.491934 | 5.06762 | 1.5503
Voile projeté béton par passes alternées | Sous-sol | 6.43801 | 3.22 | 1.93897 | 20.8116 | 6.24349
Voile projeté béton par passes alternées | Sous-sol | 13.9988 | 3.22 | 4.15465 | 44.5932 | 13.378
Voile projeté béton par passes alternées | Rez-de-chaussée | 5.31276 | 3.6 | 1.59383 | 19.1259 | 5.73778
Voile projeté béton par passes alternées | Rez-de-chaussée | 4.79271 | 3.6 | 1.39281 | 16.7137 | 5.01412
Voile projeté béton par passes alternées | Rez-de-chaussée | 2.24777 | 2.8 | 0.61904 | 5.77771 | 1.73331
Voile projeté béton par passes alternées | Rez-de-chaussée | 9.515 | 4.2 | 2.8545 | 38.6898 | 11.4457
Voile projeté béton par passes alternées | Rez-de-chaussée | 4.8232 | 2 | 1.44696 | 9.6464 | 2.89392
Voile projeté béton par passes alternées | Rez-de-chaussée | 1.86525 | 4.2 | 0.622437 | 8.71412 | 2.61424
Voile projeté béton par passes alternées | Rez-de-chaussée | 13.7665 | 2.8 | 4.17495 | 38.9662 | 11.6899
Voile projeté béton par passes alternées | Rez-de-chaussée | 2.32499 | 3.4 | 0.697496 | 7.90495 | 2.37149

# IfcWall: Béton 48, M_Ext-007
In: Rez-de-chaussée
Type - ElementType: PARAPET; PredefinedType: USERDEFINED
Classification: Mur d'acrotère (Classification ARCHICAD); Material: Béton
Pset_WallCommon - AcousticRating: Non défini; ThermalTransmittance: 0; LoadBearing: yes; IsExternal: yes
PSET_Murs_ARCHI - Emplacement: Superstructure; Type: Mur béton banché 20cm; Destination: Muret formant garde-corps; Matériaux: BETON
Propriétés DCE - Numéro de LOT: LOT 04
AC_Pset_RenovationAndPhasing - Renovation Status: Existing
Material Properties - Béton, ThermalConductivity: 2.3; Béton, SpecificHeatCapacity: 1000 J/kg/K; Béton, MassDensity: 2300 kg/m3; Béton, Embodied Energy: 1.92 (MJ/kg); Béton, Embodied Carbon: 0.198 (kgCO₂/kg); Béton, Name: Béton; Béton, Participates in Collision Detection: yes
BaseQuantities - Length: 0.678259 m; Height: 0.23 m; Width: 0.048 m; GrossFootprintArea: 0.0325564 m2; NetFootprintArea: 0.0325564 m2; GrossSideArea: 0.156 m2; NetSideArea: 0.156 m2; GrossVolume: 0.00748798 m3; NetVolume: 0.00748798 m3

# IfcWall: Béton 48, M_Ext-004
In: R+2
Type - ElementType: SOLIDWALL; PredefinedType: USERDEFINED
Classification: Mur porteur (Classification ARCHICAD); Material: Béton
Pset_WallCommon - AcousticRating: Non défini; ThermalTransmittance: 0; LoadBearing: yes; IsExternal: yes
PSET_Murs_ARCHI - Emplacement: Infrastructure; Type: Voile projeté contre terre; Destination: Mur contre terre; Matériaux: BETON
Propriétés DCE - Numéro de LOT: LOT 03
AC_Pset_RenovationAndPhasing - Renovation Status: Existing
Material Properties - Béton, ThermalConductivity: 2.3; Béton, SpecificHeatCapacity: 1000 J/kg/K; Béton, MassDensity: 2300 kg/m3; Béton, Embodied Energy: 1.92 (MJ/kg); Béton, Embodied Carbon: 0.198 (kgCO₂/kg); Béton, Name: Béton; Béton, Participates in Collision Detection: yes
BaseQuantities - Length: 3.8274 m; Height: 0.21 m; Width: 0.048 m; GrossFootprintArea: 0.184435 m2; NetFootprintArea: 0.184435 m2; GrossSideArea: 0.806903 m2; NetSideArea: 0.806903 m2; GrossVolume: 0.0387314 m3; NetVolume: 0.0387314 m3

# IfcWall: Cloison - Carreaux de plâtre 74 (49)
Type - ElementType: PARTITIONING; PredefinedType: USERDEFINED
Description: Cloisons gaines palières; Material: Cloison - Carreaux de plâtre
Pset_WallCommon - AcousticRating: Non défini; ThermalTransmittance: 0; LoadBearing: yes; IsExternal: yes
Propriétés DCE - Numéro de LOT: LOT 09; Numéro article: L09.2.5.2
AC_Pset_RenovationAndPhasing - Renovation Status: Existing
Material Properties - Cloison - Carreaux de plâtre, ThermalConductivity: 0.43; Cloison - Carreaux de plâtre, SpecificHeatCapacity: 1000 J/kg/K; Cloison - Carreaux de plâtre, MassDensity: 1200 kg/m3; Cloison - Carreaux de plâtre, Embodied Energy: 1.8 (MJ/kg); Cloison - Carreaux de plâtre, Embodied Carbon: 0.13 (kgCO₂/kg); Cloison - Carreaux de plâtre, Name: Cloison - Carreaux de plâtre; Cloison - Carreaux de plâtre, Participates in Collision Detection: yes
BaseQuantities - Width: 0.074 m
Name | In | Classification | Emplacement | Type | Destination | Matériaux | Length (m) | Height (m) | GrossFootprintArea (m2) = NetFootprintArea (m2) | GrossSideArea (m2) = NetSideArea (m2) | GrossVolume (m3) = NetVolume (m3)
Carreaux de plâtre 8cm | R+1 | Mur (Classification ARCHICAD); Cloison (Classification ARCHICAD) | Superstructure | Cloisons | Gaine Technique Palière | Carreau de plâtre 5cm | 3.34806 | 0.15 | 0.243996 | 0.510459 | 0.0365994
Carreaux de plâtre 8cm | R+2 | Mur (Classification ARCHICAD); Cloison (Classification ARCHICAD) | Superstructure | Cloisons | Gaine Technique Palière | Carreau de plâtre 5cm | 3.34806 | 0.15 | 0.243996 | 0.510459 | 0.0365994
Carreaux de plâtre 8cm | Rez-de-chaussée | Cloison (Classification ARCHICAD) | Infrastructure | Mur béton banché 20cm | Façade | BETON | 3.34806 | 0.15 | 0.243996 | 0.510459 | 0.0365994
Carreaux de plâtre 8cm | R+3 | Mur (Classification ARCHICAD); Cloison (Classification ARCHICAD) | Superstructure | Cloisons | Gaine Technique Palière | Carreau de plâtre 5cm | 3.25806 | 0.15 | 0.243996 | 0.510459 | 0.0365994
Carreaux de plâtre 8cm | R+1 | Mur (Classification ARCHICAD); Cloison (Classification ARCHICAD) | Superstructure | Cloisons | Gaine Technique Palière | Carreau de plâtre 5cm | 2.08801 | 0.15 | 0.154513 | 0.313201 | 0.0231769
Carreaux de plâtre 8cm | R+2 | Mur (Classification ARCHICAD); Cloison (Classification ARCHICAD) | Superstructure | Cloisons | Gaine Technique Palière | Carreau de plâtre 5cm | 2.08801 | 0.15 | 0.154513 | 0.313201 | 0.0231769
Carreaux de plâtre 8cm | Rez-de-chaussée | Cloison (Classification ARCHICAD) | Infrastructure | Mur béton banché 20cm | Façade | BETON | 2.08801 | 0.15 | 0.154513 | 0.313201 | 0.0231769
Carreaux de plâtre 8cm | R+1 | Mur (Classification ARCHICAD); Cloison (Classification ARCHICAD) | Superstructure | Cloisons | Gaine Technique Palière | Carreau de plâtre 5cm | 0.495153 | 2.5 | 0.0366413 | 1.23788 | 0.0916032
Carreaux de plâtre 8cm | R+2 | Cloison (Classification ARCHICAD) | Infrastructure | Mur béton banché 20cm | Façade | BETON | 0.545367 | 0.15 | 0.00074 | 0.0015 | 0.000111
Carreaux de plâtre 8cm | R+2 | Cloison (Classification ARCHICAD) | Infrastructure | Mur béton banché 20cm | Façade | BETON | 0.508367 | 0.15 | 0.0425171 | 0.102055 | 0.00637757
Carreaux de plâtre 8cm | R+2 | Mur (Classification ARCHICAD); Cloison (Classification ARCHICAD) | Superstructure | Cloisons | Gaine Technique Palière | Carreau de plâtre 5cm | 0.495153 | 2.5 | 0.0366413 | 1.23788 | 0.0916033
Carreaux de plâtre 8cm | Rez-de-chaussée | Cloison (Classification ARCHICAD) | Infrastructure | Mur béton banché 20cm | Façade | BETON | 0.518367 | 0.15 | 0.0439971 | 0.102942 | 0.00659761
Carreaux de plâtre 8cm | Rez-de-chaussée | Mur (Classification ARCHICAD); Cloison (Classification ARCHICAD) | Superstructure | Cloisons | Gaine Technique Palière | Carreau de plâtre 5cm | 0.0649888 | 2.5 | 0.00480917 | 0.162472 | 0.0120229
Carreaux de plâtre 8cm | Rez-de-chaussée | Cloison (Classification ARCHICAD) | Infrastructure | Mur béton banché 20cm | Façade | BETON | 0.495153 | 2.5 | 0.0366413 | 1.23788 | 0.0916033
Carreaux de plâtre 8cm | Rez-de-chaussée | Mur (Classification ARCHICAD); Cloison (Classification ARCHICAD) | Superstructure | Cloisons | Gaine Technique Palière | Carreau de plâtre 5cm | 0.594475 | 2.72 | 0.0481286 | 1.70077 | 0.125963
4 x Carreaux de plâtre 8cm | R+1 | Mur (Classification ARCHICAD); Cloison (Classification ARCHICAD) | Superstructure | Cloisons | Gaine Technique Palière | Carreau de plâtre 5cm | 0.496 | 2.5 | 0.04218 | 1.4139 | 0.104629
Carreaux de plâtre 8cm | R+1 | Mur (Classification ARCHICAD); Cloison (Classification ARCHICAD) | Superstructure | Cloisons | Gaine Technique Palière | Carreau de plâtre 5cm | 0.610476 | 0.15 | 0.0480752 | 0.113321 | 0.00721128
2 x Carreaux de plâtre 8cm | R+1 | Mur (Classification ARCHICAD); Cloison (Classification ARCHICAD) | Superstructure | Cloisons | Gaine Technique Palière | Carreau de plâtre 5cm | 0.366 | 2.5 | 0.03256 | 1.0889 | 0.0805786
Carreaux de plâtre 8cm | R+1 | Mur (Classification ARCHICAD); Cloison (Classification ARCHICAD) | Superstructure | Cloisons | Gaine Technique Palière | Carreau de plâtre 5cm | 0.0649888 | 2.5 | 0.00480917 | 0.162472 | 0.0120229
Carreaux de plâtre 8cm | R+1 | Mur (Classification ARCHICAD); Cloison (Classification ARCHICAD) | Superstructure | Cloisons | Gaine Technique Palière | Carreau de plâtre 5cm | 0.594475 | 2.72 | 0.0481286 | 1.70275 | 0.126004
Carreaux de plâtre 8cm | R+1 | Cloison (Classification ARCHICAD) | Infrastructure | Mur béton banché 20cm | Façade | BETON | 0.518367 | 0.15 | 0.0385211 | 0.093955 | 0.00577817
Carreaux de plâtre 8cm | R+2 | Cloison (Classification ARCHICAD) | Infrastructure | Mur béton banché 20cm | Façade | BETON | 0.580635 | 2.5 | 0.055917 | 1.87949 | 0.139082
2 x Carreaux de plâtre 8cm | R+2 | Mur (Classification ARCHICAD); Cloison (Classification ARCHICAD) | Superstructure | Cloisons | Gaine Technique Palière | Carreau de plâtre 5cm | 0.366 | 2.5 | 0.03256 | 1.0889 | 0.0805786
Carreaux de plâtre 8cm | R+2 | Mur (Classification ARCHICAD); Cloison (Classification ARCHICAD) | Superstructure | Cloisons | Gaine Technique Palière | Carreau de plâtre 5cm | 0.610476 | 0.15 | 0.0480752 | 0.113321 | 0.00721128
Carreaux de plâtre 8cm | R+2 | Mur (Classification ARCHICAD); Cloison (Classification ARCHICAD) | Superstructure | Cloisons | Gaine Technique Palière | Carreau de plâtre 5cm | 0.0649888 | 2.5 | 0.00480917 | 0.162472 | 0.0120229
4 x Carreaux de plâtre 8cm | R+2 | Mur (Classification ARCHICAD); Cloison (Classification ARCHICAD) | Superstructure | Cloisons | Gaine Technique Palière | Carreau de plâtre 5cm | 0.496 | 2.5 | 0.04218 | 1.4139 | 0.104629
Carreaux de plâtre 8cm | R+2 | Mur (Classification ARCHICAD); Cloison (Classification ARCHICAD) | Superstructure | Cloisons | Gaine Technique Palière | Carreau de plâtre 5cm | 0.594475 | 2.72 | 0.0481286 | 1.57172 | 0.116307
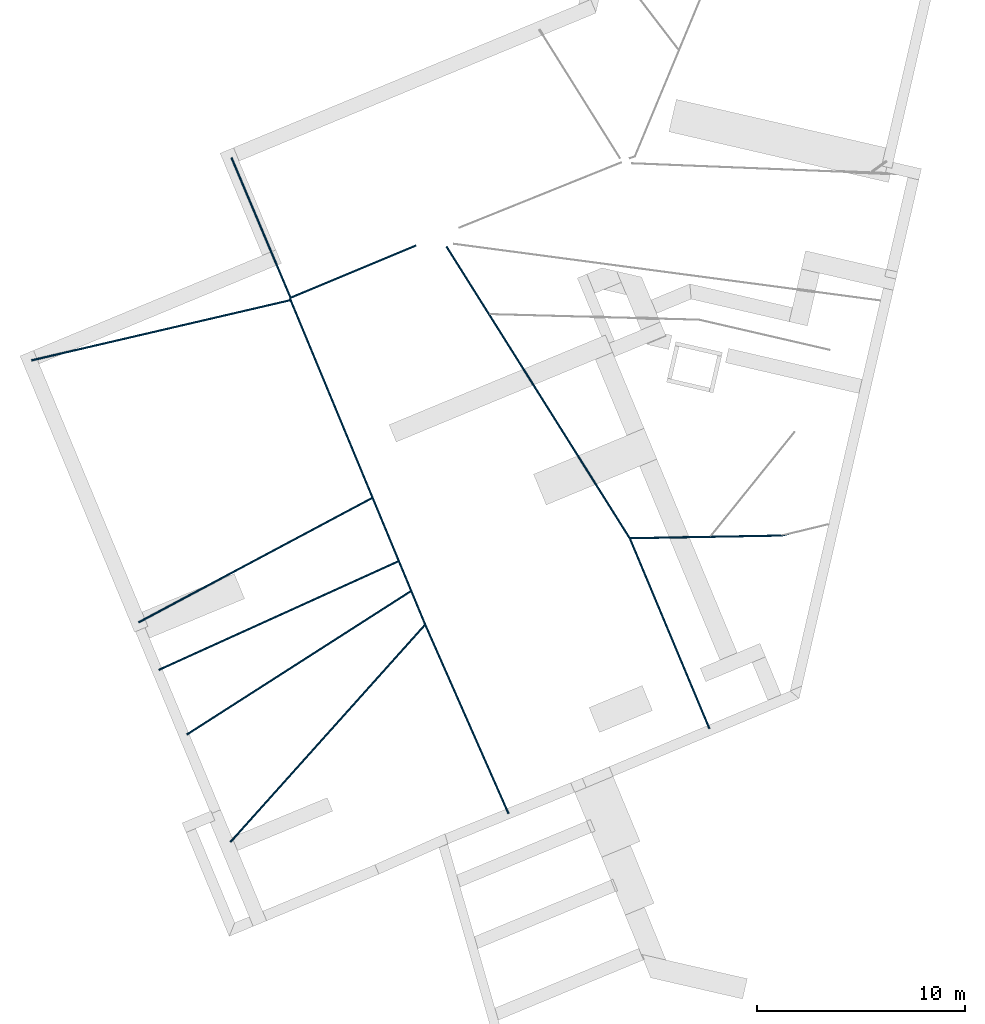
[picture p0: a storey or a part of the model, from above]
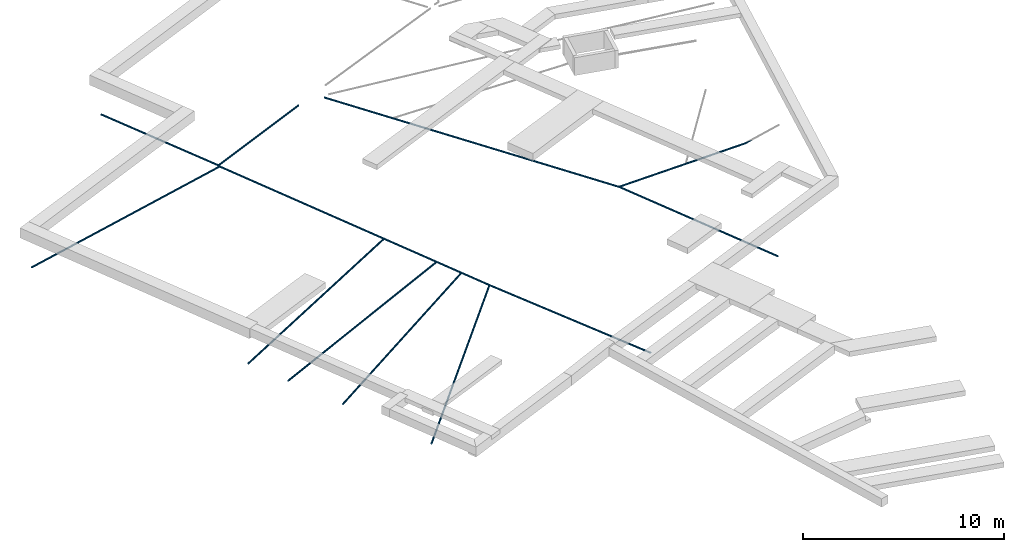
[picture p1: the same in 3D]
Properties of the parts of a building model (IFC2X3), part 19 of 22

# IfcWall: Cloison - Carreaux de plâtre 74 (49)
Name | In | Classification | Emplacement | Type | Destination | Matériaux | Length (m) | Height (m) | GrossFootprintArea (m2) = NetFootprintArea (m2) | GrossSideArea (m2) = NetSideArea (m2) | GrossVolume (m3) = NetVolume (m3)
4 x Carreaux de plâtre 8cm | R+3 | Mur (Classification ARCHICAD); Cloison (Classification ARCHICAD) | Superstructure | Cloisons | Gaine Technique Palière | Carreau de plâtre 5cm | 0.496 | 2.5 | 0.04218 | 1.4139 | 0.104629
Carreaux de plâtre 8cm | R+3 | Mur (Classification ARCHICAD); Cloison (Classification ARCHICAD) | Superstructure | Cloisons | Gaine Technique Palière | Carreau de plâtre 5cm | 0.594475 | 2.51 | 0.0500094 | 1.56669 | 0.115935
4 x Carreaux de plâtre 8cm | Rez-de-chaussée | Cloison (Classification ARCHICAD) | Infrastructure | Mur béton banché 20cm | Façade | BETON | 0.496 | 2.5 | 0.04292 | 1.4389 | 0.106479
2 x Carreaux de plâtre 8cm | Rez-de-chaussée | Cloison (Classification ARCHICAD) | Infrastructure | Mur béton banché 20cm | Façade | BETON | 0.366 | 2.5 | 0.03256 | 1.0889 | 0.0805786
Carreaux de plâtre 8cm | Rez-de-chaussée | Cloison (Classification ARCHICAD) | Infrastructure | Mur béton banché 20cm | Façade | BETON | 0.617635 | 2.5 | 0.047703 | 1.60199 | 0.118547
Carreaux de plâtre 8cm | R+1 | Cloison (Classification ARCHICAD) | Infrastructure | Mur béton banché 20cm | Façade | BETON | 0.617635 | 2.5 | 0.048443 | 1.61309 | 0.119369
Carreaux de plâtre 8cm | Rez-de-chaussée | Cloison (Classification ARCHICAD) | Infrastructure | Mur béton banché 20cm | Façade | BETON | 0.610476 | 0.15 | 0.0451752 | 0.0900702 | 0.00677567

# IfcWall: Etanchéité intérieure+isolant TH32 140 x 2510 (2)
Type - PredefinedType: ELEMENTEDWALL
Classification: Mur composite (Classification ARCHICAD); Material: Finition int - Plaque de plâtre, Isolation - Polystyrène extrudé, Etanchéité résine
Pset_WallCommon - AcousticRating: Non défini; ThermalTransmittance: 0; LoadBearing: yes; IsExternal: yes
PSET_Murs_ARCHI - Emplacement: Infrastructure; Type: Mur béton banché 20cm; Destination: Façade; Matériaux: BETON
AC_Pset_RenovationAndPhasing - Renovation Status: Existing
Material Properties - Component 2, Finition int - Plaque de plâtre, ThermalConductivity: 0.8; Component 2, Finition int - Plaque de plâtre, SpecificHeatCapacity: 1000 J/kg/K; Component 2, Finition int - Plaque de plâtre, MassDensity: 1600 kg/m3; Component 2, Finition int - Plaque de plâtre, Embodied Energy: 1.45 (MJ/kg); Component 2, Finition int - Plaque de plâtre, Embodied Carbon: 0.22 (kgCO₂/kg); Component 2, Finition int - Plaque de plâtre, Name: Finition int - Plaque de plâtre; Component 2, Finition int - Plaque de plâtre, Participates in Collision Detection: no; Component 1, Isolation - Polystyrène extrudé, ThermalConductivity: 0.036; Component 1, Isolation - Polystyrène extrudé, SpecificHeatCapacity: 1400 J/kg/K; Component 1, Isolation - Polystyrène extrudé, MassDensity: 25 kg/m3; Component 1, Isolation - Polystyrène extrudé, Embodied Energy: 86.4 (MJ/kg); Component 1, Isolation - Polystyrène extrudé, Embodied Carbon: 3.43 (kgCO₂/kg); Component 1, Isolation - Polystyrène extrudé, Name: Isolation - Polystyrène extrudé; Component 1, Isolation - Polystyrène extrudé, Participates in Collision Detection: no; Component 3, Etanchéité résine, ThermalConductivity: 0.17; Component 3, Etanchéité résine, SpecificHeatCapacity: 900 J/kg/K; Component 3, Etanchéité résine, MassDensity: 1390 kg/m3; Component 3, Etanchéité résine, Embodied Energy: 77.2 (MJ/kg); Component 3, Etanchéité résine, Embodied Carbon: 3.1 (kgCO₂/kg); Component 3, Etanchéité résine, Name: Etanchéité résine; Component 3, Etanchéité résine, Participates in Collision Detection: no
BaseQuantities - Height: 2.51 m; Width: 0.14 m
Name | In | Numéro de LOT | Numéro article | Length (m) | GrossFootprintArea (m2) = NetFootprintArea (m2) | GrossSideArea (m2) = NetSideArea (m2) | GrossVolume (m3) = NetVolume (m3)
M_Ext-011 | Rez-de-chaussée | LOT 04; LOT 09 | L09.2.1.1.1 | 8.82995 | 1.24109 | 22.1236 | 3.10998
M_Ext-011 | R+1 | LOT 04; LOT 09; LOT 16 | L09.2.1.1.1; L16.2.1 | 8.84 | 1.2424 | 22.1333 | 3.11322

# IfcWall: Etanchéité résine bitumeuse 10 (11)
In: Rez-de-chaussée
Type - ElementType: SOLIDWALL; PredefinedType: USERDEFINED
Classification: Mur porteur (Classification ARCHICAD); Material: Etanchéité résine bitumeuse
Pset_WallCommon - AcousticRating: Non défini; ThermalTransmittance: 0; LoadBearing: yes; IsExternal: yes
PSET_Murs_ARCHI - Emplacement: Infrastructure; Type: Mur béton banché 20cm; Destination: Façade; Matériaux: BETON
Propriétés DCE - Numéro de LOT: LOT 07; Numéro article: L07.2.5.2
AC_Pset_RenovationAndPhasing - Renovation Status: Existing
Material Properties - Etanchéité résine bitumeuse, ThermalConductivity: 0.17; Etanchéité résine bitumeuse, SpecificHeatCapacity: 900 J/kg/K; Etanchéité résine bitumeuse, MassDensity: 1390 kg/m3; Etanchéité résine bitumeuse, Embodied Energy: 77.2 (MJ/kg); Etanchéité résine bitumeuse, Embodied Carbon: 3.1 (kgCO₂/kg); Etanchéité résine bitumeuse, Name: Etanchéité résine bitumeuse; Etanchéité résine bitumeuse, Participates in Collision Detection: no
BaseQuantities - Width: 0.01 m
Name | Length (m) | Height (m) | GrossFootprintArea (m2) = NetFootprintArea (m2) | GrossSideArea (m2) = NetSideArea (m2) | GrossVolume (m3) = NetVolume (m3)
M_Ext-008 | 5.00776 | 3.56 | 0.0501279 | 17.7367 | 0.177033
M_Ext-008 | 13.7188 | 2.67 | 0.137278 | 36.6082 | 0.36613
M_Ext-008 | 21.092 | 1.15 | 0.21092 | 24.187 | 0.24187
M_Ext-008 | 2.41999 | 2.62795 | 0.0243 | 6.38591 | 0.0638591
M_Ext-008 | 2.21 | 2.62795 | 0.0221 | 5.80777 | 0.0580777
M_Ext-009 | 10.1833 | 3.52 | 0.101833 | 35.8451 | 0.358451
M_Ext-008 | 2.515 | 2.66795 | 0.0251085 | 6.69056 | 0.0669356
M_Ext-009 | 4.63771 | 3.52 | 0.046327 | 16.3071 | 0.163071
M_Ext-008 | 14.0672 | 1.15 | 0.140661 | 16.176 | 0.16176
M_Ext-009 | 2.39293 | 1.15 | 0.0238792 | 2.74612 | 0.0274612
M_Ext-009 | 4.8232 | 1.92 | 0.0482319 | 9.26054 | 0.0926053

# IfcWall: Finition ext - Crépis 15 (2)
In: Rez-de-chaussée
Type - ElementType: SOLIDWALL; PredefinedType: USERDEFINED
Classification: Mur porteur (Classification ARCHICAD); Material: Finition ext - Crépis
Pset_WallCommon - AcousticRating: Non défini; ThermalTransmittance: 0; LoadBearing: yes; IsExternal: yes
PSET_Murs_ARCHI - Emplacement: Infrastructure; Type: Mur béton banché 20cm; Destination: Façade; Matériaux: BETON
Propriétés DCE - Numéro de LOT: LOT 04; LOT 16; Numéro article: L16.2.1
AC_Pset_RenovationAndPhasing - Renovation Status: Existing
Material Properties - Finition ext - Crépis, ThermalConductivity: 0.8; Finition ext - Crépis, SpecificHeatCapacity: 1000 J/kg/K; Finition ext - Crépis, MassDensity: 1600 kg/m3; Finition ext - Crépis, Embodied Energy: 1.4 (MJ/kg); Finition ext - Crépis, Embodied Carbon: 0.09 (kgCO₂/kg); Finition ext - Crépis, Name: Finition ext - Crépis; Finition ext - Crépis, Participates in Collision Detection: no
BaseQuantities - Width: 0.015 m
Name | Length (m) | Height (m) | GrossFootprintArea (m2) = NetFootprintArea (m2) | GrossSideArea (m2) = NetSideArea (m2) | GrossVolume (m3) = NetVolume (m3)
M_Ext-016 | 0.870809 | 0.135 | 0.000225 | 0.002025 | 0.0000303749
M_Ext-008 | 1.515 | 0.7 | 0.0225 | 1.05 | 0.01575

# IfcWall: Finition int - Plaque de plâtre 15 (2)
In: Rez-de-chaussée
Type - ElementType: PARTITIONING; PredefinedType: USERDEFINED
Classification: Cloison (Classification ARCHICAD); Material: Finition int - Plaque de plâtre
Pset_WallCommon - AcousticRating: Non défini; ThermalTransmittance: 0; LoadBearing: yes; IsExternal: yes
PSET_Murs_ARCHI - Emplacement: Infrastructure; Type: Mur béton banché 20cm; Destination: Façade; Matériaux: BETON
AC_Pset_RenovationAndPhasing - Renovation Status: Existing
Material Properties - Finition int - Plaque de plâtre, ThermalConductivity: 0.8; Finition int - Plaque de plâtre, SpecificHeatCapacity: 1000 J/kg/K; Finition int - Plaque de plâtre, MassDensity: 1600 kg/m3; Finition int - Plaque de plâtre, Embodied Energy: 1.45 (MJ/kg); Finition int - Plaque de plâtre, Embodied Carbon: 0.22 (kgCO₂/kg); Finition int - Plaque de plâtre, Name: Finition int - Plaque de plâtre; Finition int - Plaque de plâtre, Participates in Collision Detection: no
BaseQuantities - Height: 2.5 m; Width: 0.015 m
Name | Length (m) | GrossFootprintArea (m2) = NetFootprintArea (m2) | GrossSideArea (m2) = NetSideArea (m2) | GrossVolume (m3) = NetVolume (m3)
M_Ext-011 | 0.12809 | 0.00625885 | 0.863974 | 0.0156471
M_Ext-010 | 0.437109 | 0.00681914 | 1.13652 | 0.0170479

# IfcWall: Mur ALKERN + planelle 21 + planelle 23 base 345 x 2950, Mue bloc ALKERN isolé
In: Rez-de-chaussée
Type - ElementType: SOLIDWALL; PredefinedType: USERDEFINED
Description: Murs de façade bloc ALKERN; Classification: Mur porteur (Classification ARCHICAD); Material: Finition int - Plaque de plâtre, Isolation - Polystyrène extrudé, Bloc ELITHERM, Isolation - Polystyrène expansé (2), Mortier (2), Béton cellulaire (2), Finition ext - Crépis
Pset_WallCommon - AcousticRating: Non défini; ThermalTransmittance: 0; LoadBearing: yes; IsExternal: yes
PSET_Murs_ARCHI - Emplacement: Superstructure; Type: Mur en bloc ELITHERM; Destination: Façade; Matériaux: Maçonnerie Bloc ALKERN Elitherm
Propriétés DCE - Numéro de LOT: LOT 04; LOT 09; LOT 16; Numéro article: L04.2.12.1.1; L09.2.1.1.1; L16.2.1
AC_Pset_RenovationAndPhasing - Renovation Status: Existing
Material Properties - Component 4, Finition int - Plaque de plâtre, ThermalConductivity: 0.8; Component 4, Finition int - Plaque de plâtre, SpecificHeatCapacity: 1000 J/kg/K; Component 4, Finition int - Plaque de plâtre, MassDensity: 1600 kg/m3; Component 4, Finition int - Plaque de plâtre, Embodied Energy: 1.45 (MJ/kg); Component 4, Finition int - Plaque de plâtre, Embodied Carbon: 0.22 (kgCO₂/kg); Component 4, Finition int - Plaque de plâtre, Name: Finition int - Plaque de plâtre; Component 4, Finition int - Plaque de plâtre, Participates in Collision Detection: no; Component 2, Isolation - Polystyrène extrudé, ThermalConductivity: 0.036; Component 2, Isolation - Polystyrène extrudé, SpecificHeatCapacity: 1400 J/kg/K; Component 2, Isolation - Polystyrène extrudé, MassDensity: 25 kg/m3; Component 2, Isolation - Polystyrène extrudé, Embodied Energy: 86.4 (MJ/kg); Component 2, Isolation - Polystyrène extrudé, Embodied Carbon: 3.43 (kgCO₂/kg); Component 2, Isolation - Polystyrène extrudé, Name: Isolation - Polystyrène extrudé; Component 2, Isolation - Polystyrène extrudé, Participates in Collision Detection: no; Component 1, Bloc ELITHERM, ThermalConductivity: 1.35; Component 1, Bloc ELITHERM, SpecificHeatCapacity: 1000 J/kg/K; Component 1, Bloc ELITHERM, MassDensity: 2000 kg/m3; Component 1, Bloc ELITHERM, Embodied Energy: 0.78 (MJ/kg); Component 1, Bloc ELITHERM, Embodied Carbon: 0.113 (kgCO₂/kg); Component 1, Bloc ELITHERM, Name: Bloc ELITHERM; Component 1, Bloc ELITHERM, Participates in Collision Detection: yes; Component 8, Isolation - Polystyrène expansé, ThermalConductivity: 0.036; Component 8, Isolation - Polystyrène expansé, SpecificHeatCapacity: 1450 J/kg/K; Component 8, Isolation - Polystyrène expansé, MassDensity: 25 kg/m3; Component 8, Isolation - Polystyrène expansé, Embodied Energy: 86.6 (MJ/kg); Component 8, Isolation - Polystyrène expansé, Embodied Carbon: 3.29 (kgCO₂/kg); Component 8, Isolation - Polystyrène expansé, Name: Isolation - Polystyrène expansé; Component 8, Isolation - Polystyrène expansé, Participates in Collision Detection: no; Component 7, Mortier, ThermalConductivity: 1.15; Component 7, Mortier, SpecificHeatCapacity: 1000 J/kg/K; Component 7, Mortier, MassDensity: 1800 kg/m3; Component 7, Mortier, Embodied Energy: 0.74 (MJ/kg); Component 7, Mortier, Embodied Carbon: 0.107 (kgCO₂/kg); Component 7, Mortier, Name: Mortier; Component 7, Mortier, Participates in Collision Detection: yes; Component 9, Béton cellulaire, ThermalConductivity: 0.12; Component 9, Béton cellulaire, SpecificHeatCapacity: 1050 J/kg/K; Component 9, Béton cellulaire, MassDensity: 450 kg/m3; Component 9, Béton cellulaire, Embodied Energy: 0.57 (MJ/kg); Component 9, Béton cellulaire, Embodied Carbon: 0.061 (kgCO₂/kg); Component 9, Béton cellulaire, Name: Béton cellulaire; Component 9, Béton cellulaire, Participates in Collision Detection: yes; Component 3, Finition ext - Crépis, ThermalConductivity: 0.8; Component 3, Finition ext - Crépis, SpecificHeatCapacity: 1000 J/kg/K; Component 3, Finition ext - Crépis, MassDensity: 1600 kg/m3; Component 3, Finition ext - Crépis, Embodied Energy: 1.4 (MJ/kg); Component 3, Finition ext - Crépis, Embodied Carbon: 0.09 (kgCO₂/kg); Component 3, Finition ext - Crépis, Name: Finition ext - Crépis; Component 3, Finition ext - Crépis, Participates in Collision Detection: no; Component 8: 2 with these values; Component 7: 2 with these values; Component 9: 2 with these values
BaseQuantities - Length: 6.76863 m; Height: 2.95 m; Width: 0.345 m; GrossFootprintArea: 2.40926 m2; NetFootprintArea: 2.40926 m2; GrossSideArea: 19.9749 m2; NetSideArea: 16.1949 m2; GrossVolume: 5.96945 m3; NetVolume: 4.66535 m3

# IfcWall: Mur ALKERN + planelle 21 345 x 2720 (65)
Type - ElementType: SOLIDWALL; PredefinedType: USERDEFINED
Description: Murs de façade bloc ALKERN; Classification: Mur porteur (Classification ARCHICAD)
Pset_WallCommon - AcousticRating: Non défini; ThermalTransmittance: 0; LoadBearing: yes; IsExternal: yes
PSET_Murs_ARCHI - Emplacement: Superstructure; Type: Mur en bloc ELITHERM; Destination: Façade; Matériaux: Maçonnerie Bloc ALKERN Elitherm
Propriétés DCE - Numéro de LOT: LOT 04; LOT 09; LOT 16; Numéro article: L04.2.12.1.1; L09.2.1.1.1; L16.2.1
AC_Pset_RenovationAndPhasing - Renovation Status: Existing
Material Properties - Component 4, Finition int - Plaque de plâtre, ThermalConductivity: 0.8; Component 4, Finition int - Plaque de plâtre, SpecificHeatCapacity: 1000 J/kg/K; Component 4, Finition int - Plaque de plâtre, MassDensity: 1600 kg/m3; Component 4, Finition int - Plaque de plâtre, Embodied Energy: 1.45 (MJ/kg); Component 4, Finition int - Plaque de plâtre, Embodied Carbon: 0.22 (kgCO₂/kg); Component 4, Finition int - Plaque de plâtre, Name: Finition int - Plaque de plâtre; Component 4, Finition int - Plaque de plâtre, Participates in Collision Detection: no; Component 2, Isolation - Polystyrène extrudé, ThermalConductivity: 0.036; Component 2, Isolation - Polystyrène extrudé, SpecificHeatCapacity: 1400 J/kg/K; Component 2, Isolation - Polystyrène extrudé, MassDensity: 25 kg/m3; Component 2, Isolation - Polystyrène extrudé, Embodied Energy: 86.4 (MJ/kg); Component 2, Isolation - Polystyrène extrudé, Embodied Carbon: 3.43 (kgCO₂/kg); Component 2, Isolation - Polystyrène extrudé, Name: Isolation - Polystyrène extrudé; Component 2, Isolation - Polystyrène extrudé, Participates in Collision Detection: no; Component 1, Bloc ELITHERM, ThermalConductivity: 1.35; Component 1, Bloc ELITHERM, SpecificHeatCapacity: 1000 J/kg/K; Component 1, Bloc ELITHERM, MassDensity: 2000 kg/m3; Component 1, Bloc ELITHERM, Embodied Energy: 0.78 (MJ/kg); Component 1, Bloc ELITHERM, Embodied Carbon: 0.113 (kgCO₂/kg); Component 1, Bloc ELITHERM, Name: Bloc ELITHERM; Component 1, Bloc ELITHERM, Participates in Collision Detection: yes; Component 7, Mortier, ThermalConductivity: 1.15; Component 7, Mortier, SpecificHeatCapacity: 1000 J/kg/K; Component 7, Mortier, MassDensity: 1800 kg/m3; Component 7, Mortier, Embodied Energy: 0.74 (MJ/kg); Component 7, Mortier, Embodied Carbon: 0.107 (kgCO₂/kg); Component 7, Mortier, Name: Mortier; Component 7, Mortier, Participates in Collision Detection: yes; Component 6, Béton cellulaire, ThermalConductivity: 0.12; Component 6, Béton cellulaire, SpecificHeatCapacity: 1050 J/kg/K; Component 6, Béton cellulaire, MassDensity: 450 kg/m3; Component 6, Béton cellulaire, Embodied Energy: 0.57 (MJ/kg); Component 6, Béton cellulaire, Embodied Carbon: 0.061 (kgCO₂/kg); Component 6, Béton cellulaire, Name: Béton cellulaire; Component 6, Béton cellulaire, Participates in Collision Detection: yes; Component 3, Finition ext - Crépis, ThermalConductivity: 0.8; Component 3, Finition ext - Crépis, SpecificHeatCapacity: 1000 J/kg/K; Component 3, Finition ext - Crépis, MassDensity: 1600 kg/m3; Component 3, Finition ext - Crépis, Embodied Energy: 1.4 (MJ/kg); Component 3, Finition ext - Crépis, Embodied Carbon: 0.09 (kgCO₂/kg); Component 3, Finition ext - Crépis, Name: Finition ext - Crépis; Component 3, Finition ext - Crépis, Participates in Collision Detection: no
BaseQuantities - Height: 2.72 m; Width: 0.345 m
Name | In | Material | Component 5, Isolation - Polystyrène expansé, ThermalConductivity | Component 5, Isolation - Polystyrène expansé, SpecificHeatCapacity (J/kg/K) | Component 5, Isolation - Polystyrène expansé, MassDensity (kg/m3) | Component 5, Isolation - Polystyrène expansé, Embodied Energy | Component 5, Isolation - Polystyrène expansé, Embodied Carbon | Component 5, Isolation - Polystyrène expansé, Name | Component 5, Isolation - Polystyrène expansé, Participates in Collision Detection | Length (m) | GrossFootprintArea (m2) = NetFootprintArea (m2) | GrossSideArea (m2) | NetSideArea (m2) | GrossVolume (m3) | NetVolume (m3)
Mue bloc ALKERN isolé | R+1 | Finition int - Plaque de plâtre, Isolation - Polystyrène extrudé, Bloc ELITHERM, Isolation - Polystyrène expansé, Mortier, Béton cellulaire, Finition ext - Crépis | 0.036 | 1450 | 25 | 86.6 (MJ/kg) | 3.29 (kgCO₂/kg) | Isolation - Polystyrène expansé | no | 13.3241 | 4.61015 | 36.0343 | 25.0843 | 11.8063 | 8.02854
Mue bloc ALKERN isolé | R+2 | Finition int - Plaque de plâtre, Isolation - Polystyrène extrudé, Bloc ELITHERM, Mortier, Béton cellulaire, Finition ext - Crépis |  |  |  |  |  |  |  | 13.3241 | 4.61015 | 34.6982 | 23.7482 | 11.7527 | 7.97493
Mue bloc ALKERN isolé | R+1 | Finition ext - Crépis, Béton cellulaire, Mortier, Isolation - Polystyrène expansé, Bloc ELITHERM, Isolation - Polystyrène extrudé, Finition int - Plaque de plâtre | 0.036 | 1450 | 25 | 86.6 (MJ/kg) | 3.29 (kgCO₂/kg) | Isolation - Polystyrène expansé | no | 11.5865 | 4.0405 | 29.7467 | 20.6867 | 10.2973 | 7.17157
Mue bloc ALKERN isolé | R+1 | Finition ext - Crépis, Béton cellulaire, Mortier, Isolation - Polystyrène expansé, Bloc ELITHERM, Isolation - Polystyrène extrudé, Finition int - Plaque de plâtre | 0.036 | 1450 | 25 | 86.6 (MJ/kg) | 3.29 (kgCO₂/kg) | Isolation - Polystyrène expansé | no | 8.12161 | 2.81189 | 22.0807 | 14.9107 | 7.17663 | 4.70298
Mue bloc ALKERN isolé | Rez-de-chaussée | Finition int - Plaque de plâtre, Isolation - Polystyrène extrudé, Bloc ELITHERM, Isolation - Polystyrène expansé, Mortier, Béton cellulaire, Finition ext - Crépis | 0.036 | 1450 | 25 | 86.6 (MJ/kg) | 3.29 (kgCO₂/kg) | Isolation - Polystyrène expansé | no | 8.83302 | 3.03337 | 23.7883 | 15.7383 | 7.76804 | 4.99079
Mue bloc ALKERN isolé | R+1 | Finition int - Plaque de plâtre, Isolation - Polystyrène extrudé, Bloc ELITHERM, Isolation - Polystyrène expansé, Mortier, Béton cellulaire, Finition ext - Crépis | 0.036 | 1450 | 25 | 86.6 (MJ/kg) | 3.29 (kgCO₂/kg) | Isolation - Polystyrène expansé | no | 6.26736 | 2.22238 | 17.0855 | 9.91553 | 5.63204 | 3.15839
Mue bloc ALKERN isolé | R+1 | Finition ext - Crépis, Béton cellulaire, Mortier, Isolation - Polystyrène expansé, Bloc ELITHERM, Isolation - Polystyrène extrudé, Finition int - Plaque de plâtre | 0.036 | 1450 | 25 | 86.6 (MJ/kg) | 3.29 (kgCO₂/kg) | Isolation - Polystyrène expansé | no | 9.81302 | 3.462 | 26.7657 | 19.5957 | 8.81223 | 6.33858
Mue bloc ALKERN isolé | R+2 | Finition ext - Crépis, Béton cellulaire, Mortier, Isolation - Polystyrène expansé, Bloc ELITHERM, Isolation - Polystyrène extrudé, Finition int - Plaque de plâtre | 0.036 | 1450 | 25 | 86.6 (MJ/kg) | 3.29 (kgCO₂/kg) | Isolation - Polystyrène expansé | no | 8.12161 | 2.81189 | 21.2744 | 14.1044 | 7.14793 | 4.67428
Mue bloc ALKERN isolé | R+2 | Finition int - Plaque de plâtre, Isolation - Polystyrène extrudé, Bloc ELITHERM, Isolation - Polystyrène expansé, Mortier, Béton cellulaire, Finition ext - Crépis | 0.036 | 1450 | 25 | 86.6 (MJ/kg) | 3.29 (kgCO₂/kg) | Isolation - Polystyrène expansé | no | 6.26736 | 2.17759 | 16.4067 | 9.23675 | 5.46831 | 2.99466
Mue bloc ALKERN isolé | R+3 | Finition int - Plaque de plâtre, Isolation - Polystyrène extrudé, Bloc ELITHERM, Mortier, Béton cellulaire, Finition ext - Crépis |  |  |  |  |  |  |  | 6.26736 | 2.22238 | 16.4735 | 9.30354 | 5.60721 | 3.13356
Mue bloc ALKERN isolé | R+1 | Finition int - Plaque de plâtre, Isolation - Polystyrène extrudé, Bloc ELITHERM, Isolation - Polystyrène expansé, Mortier, Béton cellulaire, Finition ext - Crépis | 0.036 | 1450 | 25 | 86.6 (MJ/kg) | 3.29 (kgCO₂/kg) | Isolation - Polystyrène expansé | no | 6.09043 | 2.11302 | 16.3873 | 15.4273 | 5.40286 | 5.07166
Mue bloc ALKERN isolé | R+1 | Finition int - Plaque de plâtre, Isolation - Polystyrène extrudé, Bloc ELITHERM, Isolation - Polystyrène expansé, Mortier, Béton cellulaire, Finition ext - Crépis | 0.036 | 1450 | 25 | 86.6 (MJ/kg) | 3.29 (kgCO₂/kg) | Isolation - Polystyrène expansé | no | 3.77443 | 1.30614 | 10.0818 | 8.19179 | 3.34677 | 2.69472
Mue bloc ALKERN isolé | R+1 | Finition ext - Crépis, Béton cellulaire, Mortier, Isolation - Polystyrène expansé, Bloc ELITHERM, Isolation - Polystyrène extrudé, Finition int - Plaque de plâtre | 0.036 | 1450 | 25 | 86.6 (MJ/kg) | 3.29 (kgCO₂/kg) | Isolation - Polystyrène expansé | no | 4.85967 | 1.70395 | 13.2127 | 11.3227 | 4.35911 | 3.70706
Mue bloc ALKERN isolé | R+1 | Finition int - Plaque de plâtre, Isolation - Polystyrène extrudé, Bloc ELITHERM, Isolation - Polystyrène expansé, Mortier, Béton cellulaire, Finition ext - Crépis | 0.036 | 1450 | 25 | 86.6 (MJ/kg) | 3.29 (kgCO₂/kg) | Isolation - Polystyrène expansé | no | 7.66295 | 2.6546 | 20.7331 | 13.2531 | 6.76323 | 4.18263
Mue bloc ALKERN isolé | R+2 | Finition int - Plaque de plâtre, Isolation - Polystyrène extrudé, Bloc ELITHERM, Mortier, Béton cellulaire, Finition ext - Crépis |  |  |  |  |  |  |  | 7.66295 | 2.6546 | 19.9923 | 12.5123 | 6.73341 | 4.15281
Mue bloc ALKERN isolé | R+2 | Finition ext - Crépis, Béton cellulaire, Mortier, Isolation - Polystyrène expansé, Bloc ELITHERM, Isolation - Polystyrène extrudé, Finition int - Plaque de plâtre | 0.036 | 1450 | 25 | 86.6 (MJ/kg) | 3.29 (kgCO₂/kg) | Isolation - Polystyrène expansé | no | 9.81302 | 3.41721 | 26.767 | 21.097 | 8.67567 | 6.71952
Mue bloc ALKERN isolé | R+2 | Finition int - Plaque de plâtre, Isolation - Polystyrène extrudé, Bloc ELITHERM, Isolation - Polystyrène expansé, Mortier, Béton cellulaire, Finition ext - Crépis | 0.036 | 1450 | 25 | 86.6 (MJ/kg) | 3.29 (kgCO₂/kg) | Isolation - Polystyrène expansé | no | 6.2561 | 2.13524 | 16.9988 | 9.7388 | 5.46521 | 2.96051
Mue bloc ALKERN isolé | R+1 | Finition int - Plaque de plâtre, Isolation - Polystyrène extrudé, Bloc ELITHERM, Isolation - Polystyrène expansé, Mortier, Béton cellulaire, Finition ext - Crépis | 0.036 | 1450 | 25 | 86.6 (MJ/kg) | 3.29 (kgCO₂/kg) | Isolation - Polystyrène expansé | no | 6.5186 | 2.21155 | 17.6258 | 10.3658 | 5.59893 | 3.09423
Mue bloc ALKERN isolé | R+1 | Finition int - Plaque de plâtre, Isolation - Polystyrène extrudé, Bloc ELITHERM, Isolation - Polystyrène expansé, Mortier, Béton cellulaire, Finition ext - Crépis | 0.036 | 1450 | 25 | 86.6 (MJ/kg) | 3.29 (kgCO₂/kg) | Isolation - Polystyrène expansé | no | 3.6321 | 1.29066 | 9.6572 | 4.3772 | 3.3001 | 1.4785
Mue bloc ALKERN isolé | R+1 | Finition ext - Crépis, Béton cellulaire, Mortier, Isolation - Polystyrène expansé, Bloc ELITHERM, Isolation - Polystyrène extrudé, Finition int - Plaque de plâtre | 0.036 | 1450 | 25 | 86.6 (MJ/kg) | 3.29 (kgCO₂/kg) | Isolation - Polystyrène expansé | no | 3.87733 | 1.36504 | 10.5425 | 8.65247 | 3.49359 | 2.84154
Mue bloc ALKERN isolé | R+1 | Finition ext - Crépis, Béton cellulaire, Mortier, Isolation - Polystyrène expansé, Bloc ELITHERM, Isolation - Polystyrène extrudé, Finition int - Plaque de plâtre | 0.036 | 1450 | 25 | 86.6 (MJ/kg) | 3.29 (kgCO₂/kg) | Isolation - Polystyrène expansé | no | 2.08541 | 0.680629 | 5.63156 | 4.55156 | 1.68666 | 1.31406
Mue bloc ALKERN isolé | R+2 | Finition ext - Crépis, Béton cellulaire, Mortier, Isolation - Polystyrène expansé, Bloc ELITHERM, Isolation - Polystyrène extrudé, Finition int - Plaque de plâtre | 0.036 | 1450 | 25 | 86.6 (MJ/kg) | 3.29 (kgCO₂/kg) | Isolation - Polystyrène expansé | no | 2.08541 | 0.680629 | 5.42704 | 4.34704 | 1.67838 | 1.30578
Mue bloc ALKERN isolé | R+2 | Finition ext - Crépis, Béton cellulaire, Mortier, Isolation - Polystyrène expansé, Bloc ELITHERM, Isolation - Polystyrène extrudé, Finition int - Plaque de plâtre | 0.036 | 1450 | 25 | 86.6 (MJ/kg) | 3.29 (kgCO₂/kg) | Isolation - Polystyrène expansé | no | 3.87733 | 1.36504 | 10.1703 | 8.28034 | 3.48003 | 2.82798
Mue bloc ALKERN isolé | R+2 | Finition int - Plaque de plâtre, Isolation - Polystyrène extrudé, Bloc ELITHERM, Mortier, Béton cellulaire, Finition ext - Crépis |  |  |  |  |  |  |  | 3.6321 | 1.29066 | 9.30755 | 4.02755 | 3.28609 | 1.46449
Mue bloc ALKERN isolé | R+2 | Finition int - Plaque de plâtre, Isolation - Polystyrène extrudé, Bloc ELITHERM, Isolation - Polystyrène expansé, Mortier, Béton cellulaire, Finition ext - Crépis | 0.036 | 1450 | 25 | 86.6 (MJ/kg) | 3.29 (kgCO₂/kg) | Isolation - Polystyrène expansé | no | 1.17711 | 0.38176 | 2.92924 | 2.92924 | 0.938081 | 0.938081
Mue bloc ALKERN isolé | Rez-de-chaussée | Finition ext - Crépis, Béton cellulaire, Mortier, Isolation - Polystyrène expansé, Bloc ELITHERM, Isolation - Polystyrène extrudé, Finition int - Plaque de plâtre | 0.036 | 1450 | 25 | 86.6 (MJ/kg) | 3.29 (kgCO₂/kg) | Isolation - Polystyrène expansé | no | 3.84759 | 1.35568 | 10.1861 | 10.1861 | 3.31902 | 3.31902
Mue bloc ALKERN isolé | R+1 | Finition ext - Crépis, Béton cellulaire, Mortier, Isolation - Polystyrène expansé, Bloc ELITHERM, Isolation - Polystyrène extrudé, Finition int - Plaque de plâtre | 0.036 | 1450 | 25 | 86.6 (MJ/kg) | 3.29 (kgCO₂/kg) | Isolation - Polystyrène expansé | no | 4.521 | 1.61447 | 12.2794 | 6.9994 | 4.12705 | 2.30545
Mue bloc ALKERN isolé | R+1 | Finition ext - Crépis, Béton cellulaire, Mortier, Isolation - Polystyrène expansé, Bloc ELITHERM, Isolation - Polystyrène extrudé, Finition int - Plaque de plâtre | 0.036 | 1450 | 25 | 86.6 (MJ/kg) | 3.29 (kgCO₂/kg) | Isolation - Polystyrène expansé | no | 3.22296 | 1.11433 | 8.72149 | 6.83149 | 2.81513 | 2.16308
Mue bloc ALKERN isolé | R+1 | Finition ext - Crépis, Béton cellulaire, Mortier, Bloc ELITHERM, Isolation - Polystyrène extrudé, Finition int - Plaque de plâtre |  |  |  |  |  |  |  | 4.17001 | 1.43888 | 10.8941 | 5.6141 | 3.66227 | 1.84068
Mue bloc ALKERN isolé | R+2 | Finition ext - Crépis, Béton cellulaire, Mortier, Isolation - Polystyrène expansé, Bloc ELITHERM, Isolation - Polystyrène extrudé, Finition int - Plaque de plâtre | 0.036 | 1450 | 25 | 86.6 (MJ/kg) | 3.29 (kgCO₂/kg) | Isolation - Polystyrène expansé | no | 4.461 | 1.60142 | 11.6686 | 9.7786 | 4.07802 | 3.42597
Mue bloc ALKERN isolé | R+2 | Finition ext - Crépis, Béton cellulaire, Mortier, Isolation - Polystyrène expansé, Bloc ELITHERM, Isolation - Polystyrène extrudé, Finition int - Plaque de plâtre | 0.036 | 1450 | 25 | 86.6 (MJ/kg) | 3.29 (kgCO₂/kg) | Isolation - Polystyrène expansé | no | 4.85967 | 1.70395 | 12.7527 | 10.8627 | 4.34429 | 3.69224
Mue bloc ALKERN isolé | R+2 | Finition ext - Crépis, Béton cellulaire, Mortier, Isolation - Polystyrène expansé, Bloc ELITHERM, Isolation - Polystyrène extrudé, Finition int - Plaque de plâtre | 0.036 | 1450 | 25 | 86.6 (MJ/kg) | 3.29 (kgCO₂/kg) | Isolation - Polystyrène expansé | no | 4.17001 | 1.46993 | 10.4727 | 5.19274 | 3.50722 | 1.68562
Mue bloc ALKERN isolé | R+2 | Finition ext - Crépis, Béton cellulaire, Mortier, Isolation - Polystyrène expansé, Bloc ELITHERM, Isolation - Polystyrène extrudé, Finition int - Plaque de plâtre | 0.036 | 1450 | 25 | 86.6 (MJ/kg) | 3.29 (kgCO₂/kg) | Isolation - Polystyrène expansé | no | 0.8 | 0.276 | 2.049 | 2.049 | 0.69671 | 0.69671
Mue bloc ALKERN isolé | R+2 | Finition ext - Crépis, Béton cellulaire, Mortier, Bloc ELITHERM, Isolation - Polystyrène extrudé, Finition int - Plaque de plâtre |  |  |  |  |  |  |  | 0.8 | 0.285936 | 1.97871 | 1.97871 | 0.683219 | 0.683219
Mue bloc ALKERN isolé | R+2 | Finition int - Plaque de plâtre, Isolation - Polystyrène extrudé, Bloc ELITHERM, Isolation - Polystyrène expansé, Mortier, Béton cellulaire, Finition ext - Crépis | 0.036 | 1450 | 25 | 86.6 (MJ/kg) | 3.29 (kgCO₂/kg) | Isolation - Polystyrène expansé | no | 3.59993 | 1.25191 | 9.84131 | 7.95131 | 3.18467 | 2.53262
Mue bloc ALKERN isolé | R+2 | Finition int - Plaque de plâtre, Isolation - Polystyrène extrudé, Bloc ELITHERM, Isolation - Polystyrène expansé, Mortier, Béton cellulaire, Finition ext - Crépis | 0.036 | 1450 | 25 | 86.6 (MJ/kg) | 3.29 (kgCO₂/kg) | Isolation - Polystyrène expansé | no | 1.87116 | 0.611896 | 4.95734 | 3.15734 | 1.52963 | 0.908626
Mue bloc ALKERN isolé | R+2 | Finition int - Plaque de plâtre, Isolation - Polystyrène extrudé, Bloc ELITHERM, Isolation - Polystyrène expansé, Mortier, Béton cellulaire, Finition ext - Crépis | 0.036 | 1450 | 25 | 86.6 (MJ/kg) | 3.29 (kgCO₂/kg) | Isolation - Polystyrène expansé | no | 6.09043 | 2.11206 | 15.8315 | 14.8715 | 5.38099 | 5.04979
Mue bloc ALKERN isolé | R+1 | Finition int - Plaque de plâtre, Isolation - Polystyrène extrudé, Bloc ELITHERM, Isolation - Polystyrène expansé, Mortier, Béton cellulaire, Finition ext - Crépis | 0.036 | 1450 | 25 | 86.6 (MJ/kg) | 3.29 (kgCO₂/kg) | Isolation - Polystyrène expansé | no | 1.1348 | 0.34076 | 2.92611 | 2.92611 | 0.835026 | 0.835026
Mue bloc ALKERN isolé | R+1 | Finition int - Plaque de plâtre, Isolation - Polystyrène extrudé, Bloc ELITHERM, Isolation - Polystyrène expansé, Mortier, Béton cellulaire, Finition ext - Crépis | 0.036 | 1450 | 25 | 86.6 (MJ/kg) | 3.29 (kgCO₂/kg) | Isolation - Polystyrène expansé | no | 2.76031 | 1.00703 | 7.54333 | 7.54333 | 2.5764 | 2.5764
Mue bloc ALKERN isolé | R+1 | Finition ext - Crépis, Béton cellulaire, Mortier, Isolation - Polystyrène expansé, Bloc ELITHERM, Isolation - Polystyrène extrudé, Finition int - Plaque de plâtre | 0.036 | 1450 | 25 | 86.6 (MJ/kg) | 3.29 (kgCO₂/kg) | Isolation - Polystyrène expansé | no | 0.8 | 0.294776 | 2.17573 | 2.17573 | 0.709542 | 0.709542
Mue bloc ALKERN isolé | R+1 | Finition int - Plaque de plâtre, Isolation - Polystyrène extrudé, Bloc ELITHERM, Isolation - Polystyrène expansé, Mortier, Béton cellulaire, Finition ext - Crépis | 0.036 | 1450 | 25 | 86.6 (MJ/kg) | 3.29 (kgCO₂/kg) | Isolation - Polystyrène expansé | no | 1.2 | 0.490509 | 3.0163 | 3.0163 | 1.02586 | 1.02586
Mue bloc ALKERN isolé | R+1 | Finition int - Plaque de plâtre, Isolation - Polystyrène extrudé, Bloc ELITHERM, Isolation - Polystyrène expansé, Mortier, Béton cellulaire, Finition ext - Crépis | 0.036 | 1450 | 25 | 86.6 (MJ/kg) | 3.29 (kgCO₂/kg) | Isolation - Polystyrène expansé | no | 2.80733 | 0.99589 | 7.62882 | 5.73882 | 2.54665 | 1.8946
Mue bloc ALKERN isolé | R+1 | Finition ext - Crépis, Béton cellulaire, Mortier, Isolation - Polystyrène expansé, Bloc ELITHERM, Isolation - Polystyrène extrudé, Finition int - Plaque de plâtre | 0.036 | 1450 | 25 | 86.6 (MJ/kg) | 3.29 (kgCO₂/kg) | Isolation - Polystyrène expansé | no | 0.980018 | 0.294277 | 2.63036 | 2.63036 | 0.727735 | 0.727735
Mue bloc ALKERN isolé | R+1 | Finition int - Plaque de plâtre, Isolation - Polystyrène extrudé, Bloc ELITHERM, Mortier, Béton cellulaire, Finition ext - Crépis |  |  |  |  |  |  |  | 0.855809 | 0.250465 | 2.20893 | 2.20893 | 0.614667 | 0.614667
Mue bloc ALKERN isolé | R+1 | Finition ext - Crépis, Béton cellulaire, Mortier, Isolation - Polystyrène expansé, Bloc ELITHERM, Isolation - Polystyrène extrudé, Finition int - Plaque de plâtre | 0.036 | 1450 | 25 | 86.6 (MJ/kg) | 3.29 (kgCO₂/kg) | Isolation - Polystyrène expansé | no | 2.5 | 0.86346 | 6.79887 | 6.79887 | 2.20842 | 2.20842
Mue bloc ALKERN isolé | R+1 | Finition ext - Crépis, Béton cellulaire, Mortier, Isolation - Polystyrène expansé, Bloc ELITHERM, Isolation - Polystyrène extrudé, Finition int - Plaque de plâtre | 0.036 | 1450 | 25 | 86.6 (MJ/kg) | 3.29 (kgCO₂/kg) | Isolation - Polystyrène expansé | no | 0.8 | 0.306485 | 2.18086 | 2.18086 | 0.709386 | 0.709386
Mue bloc ALKERN isolé | R+1 | Finition int - Plaque de plâtre, Isolation - Polystyrène extrudé, Bloc ELITHERM, Isolation - Polystyrène expansé, Mortier, Béton cellulaire, Finition ext - Crépis | 0.036 | 1450 | 25 | 86.6 (MJ/kg) | 3.29 (kgCO₂/kg) | Isolation - Polystyrène expansé | no | 11.1872 | 3.82473 | 30.4434 | 30.4434 | 9.74911 | 9.74911
Mue bloc ALKERN isolé | R+1 | Finition int - Plaque de plâtre, Isolation - Polystyrène extrudé, Bloc ELITHERM, Isolation - Polystyrène expansé, Mortier, Béton cellulaire, Finition ext - Crépis | 0.036 | 1450 | 25 | 86.6 (MJ/kg) | 3.29 (kgCO₂/kg) | Isolation - Polystyrène expansé | no | 3.03 | 1.05529 | 8.0601 | 8.0601 | 2.67301 | 2.67301
Mue bloc ALKERN isolé | R+1 | Finition int - Plaque de plâtre, Isolation - Polystyrène extrudé, Bloc ELITHERM, Isolation - Polystyrène expansé, Mortier, Béton cellulaire, Finition ext - Crépis | 0.036 | 1450 | 25 | 86.6 (MJ/kg) | 3.29 (kgCO₂/kg) | Isolation - Polystyrène expansé | no | 3.98 | 1.32927 | 10.7903 | 10.7903 | 3.37786 | 3.37786
Mue bloc ALKERN isolé | R+1 | Finition ext - Crépis, Béton cellulaire, Mortier, Isolation - Polystyrène expansé, Bloc ELITHERM, Isolation - Polystyrène extrudé, Finition int - Plaque de plâtre | 0.036 | 1450 | 25 | 86.6 (MJ/kg) | 3.29 (kgCO₂/kg) | Isolation - Polystyrène expansé | no | 3.84189 | 1.30803 | 10.1071 | 8.6671 | 3.31664 | 2.81984
Mue bloc ALKERN isolé | R+1 | Finition ext - Crépis, Béton cellulaire, Mortier, Isolation - Polystyrène expansé, Bloc ELITHERM, Isolation - Polystyrène extrudé, Finition int - Plaque de plâtre | 0.036 | 1450 | 25 | 86.6 (MJ/kg) | 3.29 (kgCO₂/kg) | Isolation - Polystyrène expansé | no | 0.855809 | 0.251425 | 2.29251 | 2.29251 | 0.61801 | 0.61801
Mue bloc ALKERN isolé | R+1 | Finition ext - Crépis, Béton cellulaire, Mortier, Isolation - Polystyrène expansé, Bloc ELITHERM, Isolation - Polystyrène extrudé, Finition int - Plaque de plâtre | 0.036 | 1450 | 25 | 86.6 (MJ/kg) | 3.29 (kgCO₂/kg) | Isolation - Polystyrène expansé | no | 0.855809 | 0.296214 | 2.3278 | 2.3278 | 0.756004 | 0.756004
Mue bloc ALKERN isolé | R+2 | Finition int - Plaque de plâtre, Isolation - Polystyrène extrudé, Bloc ELITHERM, Isolation - Polystyrène expansé, Mortier, Béton cellulaire, Finition ext - Crépis | 0.036 | 1450 | 25 | 86.6 (MJ/kg) | 3.29 (kgCO₂/kg) | Isolation - Polystyrène expansé | no | 3.98 | 1.37402 | 10.8254 | 10.8254 | 3.51584 | 3.51584
Mue bloc ALKERN isolé | R+2 | Finition int - Plaque de plâtre, Isolation - Polystyrène extrudé, Bloc ELITHERM, Isolation - Polystyrène expansé, Mortier, Béton cellulaire, Finition ext - Crépis | 0.036 | 1450 | 25 | 86.6 (MJ/kg) | 3.29 (kgCO₂/kg) | Isolation - Polystyrène expansé | no | 3.03 | 1.05529 | 7.75879 | 7.75879 | 2.66096 | 2.66096
Mue bloc ALKERN isolé | R+2 | Finition int - Plaque de plâtre, Isolation - Polystyrène extrudé, Bloc ELITHERM, Isolation - Polystyrène expansé, Mortier, Béton cellulaire, Finition ext - Crépis | 0.036 | 1450 | 25 | 86.6 (MJ/kg) | 3.29 (kgCO₂/kg) | Isolation - Polystyrène expansé | no | 2.76031 | 1.00703 | 7.54114 | 7.54114 | 2.57631 | 2.57631
Mue bloc ALKERN isolé | R+2 | Finition ext - Crépis, Béton cellulaire, Mortier, Isolation - Polystyrène expansé, Bloc ELITHERM, Isolation - Polystyrène extrudé, Finition int - Plaque de plâtre | 0.036 | 1450 | 25 | 86.6 (MJ/kg) | 3.29 (kgCO₂/kg) | Isolation - Polystyrène expansé | no | 0.855809 | 0.251425 | 2.29251 | 2.29251 | 0.61801 | 0.61801
Mue bloc ALKERN isolé | R+2 | Finition ext - Crépis, Béton cellulaire, Mortier, Isolation - Polystyrène expansé, Bloc ELITHERM, Isolation - Polystyrène extrudé, Finition int - Plaque de plâtre | 0.036 | 1450 | 25 | 86.6 (MJ/kg) | 3.29 (kgCO₂/kg) | Isolation - Polystyrène expansé | no | 0.855809 | 0.295254 | 2.24241 | 2.24241 | 0.752589 | 0.752589
Mue bloc ALKERN isolé | R+2 | Finition ext - Crépis, Béton cellulaire, Mortier, Isolation - Polystyrène expansé, Bloc ELITHERM, Isolation - Polystyrène extrudé, Finition int - Plaque de plâtre | 0.036 | 1450 | 25 | 86.6 (MJ/kg) | 3.29 (kgCO₂/kg) | Isolation - Polystyrène expansé | no | 0.322582 | 0.111291 | 0.845164 | 0.845164 | 0.283672 | 0.283672
Mue bloc ALKERN isolé | R+2 | Finition int - Plaque de plâtre, Isolation - Polystyrène extrudé, Bloc ELITHERM, Isolation - Polystyrène expansé, Mortier, Béton cellulaire, Finition ext - Crépis | 0.036 | 1450 | 25 | 86.6 (MJ/kg) | 3.29 (kgCO₂/kg) | Isolation - Polystyrène expansé | no | 11.1872 | 3.9143 | 30.5139 | 30.5139 | 10.0251 | 10.0251
Mue bloc ALKERN isolé | R+2 | Finition ext - Crépis, Béton cellulaire, Mortier, Bloc ELITHERM, Isolation - Polystyrène extrudé, Finition int - Plaque de plâtre |  |  |  |  |  |  |  | 0.980018 | 0.293317 | 2.53436 | 2.53436 | 0.723894 | 0.723894
Mue bloc ALKERN isolé | R+2 | Finition int - Plaque de plâtre, Isolation - Polystyrène extrudé, Bloc ELITHERM, Isolation - Polystyrène expansé, Mortier, Béton cellulaire, Finition ext - Crépis | 0.036 | 1450 | 25 | 86.6 (MJ/kg) | 3.29 (kgCO₂/kg) | Isolation - Polystyrène expansé | no | 1.0275 | 0.471249 | 3.08383 | 3.08383 | 1.0215 | 1.0215
Mue bloc ALKERN isolé | R+3 | Finition int - Plaque de plâtre, Isolation - Polystyrène extrudé, Bloc ELITHERM, Mortier, Béton cellulaire, Finition ext - Crépis |  |  |  |  |  |  |  | 2.73531 | 0.951557 | 7.16401 | 7.16401 | 2.42532 | 2.42532
Mue bloc ALKERN isolé | R+3 | Finition int - Plaque de plâtre, Isolation - Polystyrène extrudé, Bloc ELITHERM, Mortier, Béton cellulaire, Finition ext - Crépis |  |  |  |  |  |  |  | 3.03 | 1.05529 | 7.7571 | 7.7571 | 2.66089 | 2.66089
Mue bloc ALKERN isolé | R+3 | Finition int - Plaque de plâtre, Isolation - Polystyrène extrudé, Bloc ELITHERM, Mortier, Béton cellulaire, Finition ext - Crépis |  |  |  |  |  |  |  | 3.98 | 1.32831 | 10.3943 | 10.3943 | 3.36202 | 3.36202
Mue bloc ALKERN isolé | R+3 | Finition int - Plaque de plâtre, Isolation - Polystyrène extrudé, Bloc ELITHERM, Mortier, Béton cellulaire, Finition ext - Crépis |  |  |  |  |  |  |  | 0.899324 | 0.310267 | 2.35473 | 2.35473 | 0.790802 | 0.790802

# IfcWall: Mur ALKERN + planelle 21 345 x 2930, Mue bloc ALKERN isolé
In: R+1
Type - ElementType: SOLIDWALL; PredefinedType: USERDEFINED
Description: Murs de façade bloc ALKERN; Classification: Mur porteur (Classification ARCHICAD); Material: Finition ext - Crépis, Béton cellulaire, Mortier, Isolation - Polystyrène expansé, Bloc ELITHERM, Isolation - Polystyrène extrudé, Finition int - Plaque de plâtre
Pset_WallCommon - AcousticRating: Non défini; ThermalTransmittance: 0; LoadBearing: yes; IsExternal: yes
PSET_Murs_ARCHI - Emplacement: Superstructure; Type: Mur en bloc ELITHERM; Destination: Façade; Matériaux: Maçonnerie Bloc ALKERN Elitherm
Propriétés DCE - Numéro de LOT: LOT 04; LOT 09; LOT 16; Numéro article: L04.2.12.1.1; L09.2.1.1.1; L16.2.1
AC_Pset_RenovationAndPhasing - Renovation Status: Existing
Material Properties - Component 3, Finition ext - Crépis, ThermalConductivity: 0.8; Component 3, Finition ext - Crépis, SpecificHeatCapacity: 1000 J/kg/K; Component 3, Finition ext - Crépis, MassDensity: 1600 kg/m3; Component 3, Finition ext - Crépis, Embodied Energy: 1.4 (MJ/kg); Component 3, Finition ext - Crépis, Embodied Carbon: 0.09 (kgCO₂/kg); Component 3, Finition ext - Crépis, Name: Finition ext - Crépis; Component 3, Finition ext - Crépis, Participates in Collision Detection: no; Component 6, Béton cellulaire, ThermalConductivity: 0.12; Component 6, Béton cellulaire, SpecificHeatCapacity: 1050 J/kg/K; Component 6, Béton cellulaire, MassDensity: 450 kg/m3; Component 6, Béton cellulaire, Embodied Energy: 0.57 (MJ/kg); Component 6, Béton cellulaire, Embodied Carbon: 0.061 (kgCO₂/kg); Component 6, Béton cellulaire, Name: Béton cellulaire; Component 6, Béton cellulaire, Participates in Collision Detection: yes; Component 7, Mortier, ThermalConductivity: 1.15; Component 7, Mortier, SpecificHeatCapacity: 1000 J/kg/K; Component 7, Mortier, MassDensity: 1800 kg/m3; Component 7, Mortier, Embodied Energy: 0.74 (MJ/kg); Component 7, Mortier, Embodied Carbon: 0.107 (kgCO₂/kg); Component 7, Mortier, Name: Mortier; Component 7, Mortier, Participates in Collision Detection: yes; Component 5, Isolation - Polystyrène expansé, ThermalConductivity: 0.036; Component 5, Isolation - Polystyrène expansé, SpecificHeatCapacity: 1450 J/kg/K; Component 5, Isolation - Polystyrène expansé, MassDensity: 25 kg/m3; Component 5, Isolation - Polystyrène expansé, Embodied Energy: 86.6 (MJ/kg); Component 5, Isolation - Polystyrène expansé, Embodied Carbon: 3.29 (kgCO₂/kg); Component 5, Isolation - Polystyrène expansé, Name: Isolation - Polystyrène expansé; Component 5, Isolation - Polystyrène expansé, Participates in Collision Detection: no; Component 1, Bloc ELITHERM, ThermalConductivity: 1.35; Component 1, Bloc ELITHERM, SpecificHeatCapacity: 1000 J/kg/K; Component 1, Bloc ELITHERM, MassDensity: 2000 kg/m3; Component 1, Bloc ELITHERM, Embodied Energy: 0.78 (MJ/kg); Component 1, Bloc ELITHERM, Embodied Carbon: 0.113 (kgCO₂/kg); Component 1, Bloc ELITHERM, Name: Bloc ELITHERM; Component 1, Bloc ELITHERM, Participates in Collision Detection: yes; Component 2, Isolation - Polystyrène extrudé, ThermalConductivity: 0.036; Component 2, Isolation - Polystyrène extrudé, SpecificHeatCapacity: 1400 J/kg/K; Component 2, Isolation - Polystyrène extrudé, MassDensity: 25 kg/m3; Component 2, Isolation - Polystyrène extrudé, Embodied Energy: 86.4 (MJ/kg); Component 2, Isolation - Polystyrène extrudé, Embodied Carbon: 3.43 (kgCO₂/kg); Component 2, Isolation - Polystyrène extrudé, Name: Isolation - Polystyrène extrudé; Component 2, Isolation - Polystyrène extrudé, Participates in Collision Detection: no; Component 4, Finition int - Plaque de plâtre, ThermalConductivity: 0.8; Component 4, Finition int - Plaque de plâtre, SpecificHeatCapacity: 1000 J/kg/K; Component 4, Finition int - Plaque de plâtre, MassDensity: 1600 kg/m3; Component 4, Finition int - Plaque de plâtre, Embodied Energy: 1.45 (MJ/kg); Component 4, Finition int - Plaque de plâtre, Embodied Carbon: 0.22 (kgCO₂/kg); Component 4, Finition int - Plaque de plâtre, Name: Finition int - Plaque de plâtre; Component 4, Finition int - Plaque de plâtre, Participates in Collision Detection: no
BaseQuantities - Length: 0.322582 m; Height: 2.93 m; Width: 0.345 m; GrossFootprintArea: 0.136353 m2; NetFootprintArea: 0.136353 m2; GrossSideArea: 0.912719 m2; NetSideArea: 0.912719 m2; GrossVolume: 0.299897 m3; NetVolume: 0.299897 m3

# IfcWall: Mur ALKERN + planelle 21 BARDAGE TERRASSE 403 x 2720 (5)
Type - ElementType: SOLIDWALL; PredefinedType: USERDEFINED
Description: Murs de façade bloc ALKERN; Classification: Mur porteur (Classification ARCHICAD)
Pset_WallCommon - AcousticRating: Non défini; ThermalTransmittance: 0; LoadBearing: yes; IsExternal: yes
PSET_Murs_ARCHI - Emplacement: Superstructure; Type: Mur en bloc ELITHERM; Destination: Façade; Matériaux: Maçonnerie Bloc ALKERN Elitherm
AC_Pset_RenovationAndPhasing - Renovation Status: Existing
Material Properties - Component 4, Finition int - Plaque de plâtre, ThermalConductivity: 0.8; Component 4, Finition int - Plaque de plâtre, SpecificHeatCapacity: 1000 J/kg/K; Component 4, Finition int - Plaque de plâtre, MassDensity: 1600 kg/m3; Component 4, Finition int - Plaque de plâtre, Embodied Energy: 1.45 (MJ/kg); Component 4, Finition int - Plaque de plâtre, Embodied Carbon: 0.22 (kgCO₂/kg); Component 4, Finition int - Plaque de plâtre, Name: Finition int - Plaque de plâtre; Component 4, Finition int - Plaque de plâtre, Participates in Collision Detection: no; Component 2, Isolation - Polystyrène extrudé, ThermalConductivity: 0.036; Component 2, Isolation - Polystyrène extrudé, SpecificHeatCapacity: 1400 J/kg/K; Component 2, Isolation - Polystyrène extrudé, MassDensity: 25 kg/m3; Component 2, Isolation - Polystyrène extrudé, Embodied Energy: 86.4 (MJ/kg); Component 2, Isolation - Polystyrène extrudé, Embodied Carbon: 3.43 (kgCO₂/kg); Component 2, Isolation - Polystyrène extrudé, Name: Isolation - Polystyrène extrudé; Component 2, Isolation - Polystyrène extrudé, Participates in Collision Detection: no; Component 1, Bloc ELITHERM, ThermalConductivity: 1.35; Component 1, Bloc ELITHERM, SpecificHeatCapacity: 1000 J/kg/K; Component 1, Bloc ELITHERM, MassDensity: 2000 kg/m3; Component 1, Bloc ELITHERM, Embodied Energy: 0.78 (MJ/kg); Component 1, Bloc ELITHERM, Embodied Carbon: 0.113 (kgCO₂/kg); Component 1, Bloc ELITHERM, Name: Bloc ELITHERM; Component 1, Bloc ELITHERM, Participates in Collision Detection: yes; Component 7, Mortier, ThermalConductivity: 1.15; Component 7, Mortier, SpecificHeatCapacity: 1000 J/kg/K; Component 7, Mortier, MassDensity: 1800 kg/m3; Component 7, Mortier, Embodied Energy: 0.74 (MJ/kg); Component 7, Mortier, Embodied Carbon: 0.107 (kgCO₂/kg); Component 7, Mortier, Name: Mortier; Component 7, Mortier, Participates in Collision Detection: yes; Component 6, Béton cellulaire, ThermalConductivity: 0.12; Component 6, Béton cellulaire, SpecificHeatCapacity: 1050 J/kg/K; Component 6, Béton cellulaire, MassDensity: 450 kg/m3; Component 6, Béton cellulaire, Embodied Energy: 0.57 (MJ/kg); Component 6, Béton cellulaire, Embodied Carbon: 0.061 (kgCO₂/kg); Component 6, Béton cellulaire, Name: Béton cellulaire; Component 6, Béton cellulaire, Participates in Collision Detection: yes; Component 10, Etanchéité - Bitume, ThermalConductivity: 0.23; Component 10, Etanchéité - Bitume, SpecificHeatCapacity: 1000 J/kg/K; Component 10, Etanchéité - Bitume, MassDensity: 1100 kg/m3; Component 10, Etanchéité - Bitume, Embodied Energy: 2.86 (MJ/kg); Component 10, Etanchéité - Bitume, Embodied Carbon: 0.066 (kgCO₂/kg); Component 10, Etanchéité - Bitume, Name: Etanchéité - Bitume; Component 10, Etanchéité - Bitume, Participates in Collision Detection: no; Component 3, Bois - Lattage, ThermalConductivity: 0.13; Component 3, Bois - Lattage, SpecificHeatCapacity: 1600 J/kg/K; Component 3, Bois - Lattage, MassDensity: 500 kg/m3; Component 3, Bois - Lattage, Embodied Energy: 6.95 (MJ/kg); Component 3, Bois - Lattage, Embodied Carbon: 0.29 (kgCO₂/kg); Component 3, Bois - Lattage, Name: Bois - Lattage; Component 3, Bois - Lattage, Participates in Collision Detection: yes; Component 8, Finition ext - Bardage bois, ThermalConductivity: 0.14; Component 8, Finition ext - Bardage bois, SpecificHeatCapacity: 2300 J/kg/K; Component 8, Finition ext - Bardage bois, MassDensity: 500 kg/m3; Component 8, Finition ext - Bardage bois, Embodied Energy: 10 (MJ/kg); Component 8, Finition ext - Bardage bois, Embodied Carbon: 0.36 (kgCO₂/kg); Component 8, Finition ext - Bardage bois, Name: Finition ext - Bardage bois; Component 8, Finition ext - Bardage bois, Participates in Collision Detection: no; Component 9, Métal - Aluminium, ThermalConductivity: 160; Component 9, Métal - Aluminium, SpecificHeatCapacity: 880 J/kg/K; Component 9, Métal - Aluminium, MassDensity: 2800 kg/m3; Component 9, Métal - Aluminium, Embodied Energy: 155 (MJ/kg); Component 9, Métal - Aluminium, Embodied Carbon: 9.16 (kgCO₂/kg); Component 9, Métal - Aluminium, Name: Métal - Aluminium; Component 9, Métal - Aluminium, Participates in Collision Detection: yes
BaseQuantities - Height: 2.72 m; Width: 0.402689 m
Name | In | Material | Numéro de LOT | Numéro article | Component 5, Isolation - Polystyrène expansé, ThermalConductivity | Component 5, Isolation - Polystyrène expansé, SpecificHeatCapacity (J/kg/K) | Component 5, Isolation - Polystyrène expansé, MassDensity (kg/m3) | Component 5, Isolation - Polystyrène expansé, Embodied Energy | Component 5, Isolation - Polystyrène expansé, Embodied Carbon | Component 5, Isolation - Polystyrène expansé, Name | Component 5, Isolation - Polystyrène expansé, Participates in Collision Detection | Length (m) | GrossFootprintArea (m2) = NetFootprintArea (m2) | GrossSideArea (m2) | NetSideArea (m2) | GrossVolume (m3) | NetVolume (m3)
Mue bloc ALKERN isolé | R+2 | Finition int - Plaque de plâtre, Isolation - Polystyrène extrudé, Bloc ELITHERM, Isolation - Polystyrène expansé, Mortier, Béton cellulaire, Etanchéité - Bitume, Bois - Lattage, Finition ext - Bardage bois, Métal - Aluminium | LOT 04; LOT 05; LOT 09 | L04.2.12.1.1; L05.2.3.2; L09.2.1.1.1 | 0.036 | 1450 | 25 | 86.6 (MJ/kg) | 3.29 (kgCO₂/kg) | Isolation - Polystyrène expansé | no | 7.30421 | 2.87699 | 20.0233 | 15.1993 | 7.43035 | 5.55922
Mue bloc ALKERN isolé | R+2 | Finition int - Plaque de plâtre, Isolation - Polystyrène extrudé, Bloc ELITHERM, Isolation - Polystyrène expansé, Mortier, Béton cellulaire, Etanchéité - Bitume, Bois - Lattage, Finition ext - Bardage bois, Métal - Aluminium | LOT 04; LOT 05 | L04.2.12.1.1; L09.2.1.1.1; L16.2.1 | 0.036 | 1450 | 25 | 86.6 (MJ/kg) | 3.29 (kgCO₂/kg) | Isolation - Polystyrène expansé | no | 6.28059 | 2.4757 | 17.3463 | 11.4423 | 6.34719 | 4.04946
Mue bloc ALKERN isolé | R+3 | Finition int - Plaque de plâtre, Isolation - Polystyrène extrudé, Bloc ELITHERM, Mortier, Béton cellulaire, Etanchéité - Bitume, Bois - Lattage, Finition ext - Bardage bois, Métal - Aluminium | LOT 04; LOT 05; LOT 09 | L04.2.12.1.1; L05.2.3.2; L09.2.1.1.1 |  |  |  |  |  |  |  | 4.60289 | 1.7014 | 12.1796 | 7.35557 | 4.494 | 2.62287
Mue bloc ALKERN isolé | R+3 | Finition int - Plaque de plâtre, Isolation - Polystyrène extrudé, Bloc ELITHERM, Mortier, Béton cellulaire, Etanchéité - Bitume, Bois - Lattage, Finition ext - Bardage bois, Métal - Aluminium | LOT 04; LOT 05; LOT 09 | L04.2.12.1.1; L05.2.3.2; L09.2.1.1.1 |  |  |  |  |  |  |  | 3.13818 | 1.19811 | 7.85791 | 6.05791 | 3.03232 | 2.33083
Mue bloc ALKERN isolé | R+2 | Finition int - Plaque de plâtre, Isolation - Polystyrène extrudé, Bloc ELITHERM, Isolation - Polystyrène expansé, Mortier, Béton cellulaire, Etanchéité - Bitume, Bois - Lattage, Finition ext - Bardage bois, Métal - Aluminium | LOT 04; LOT 05; LOT 09 | L04.2.12.1.1; L05.2.3.2; L09.2.1.1.1 | 0.036 | 1450 | 25 | 86.6 (MJ/kg) | 3.29 (kgCO₂/kg) | Isolation - Polystyrène expansé | no | 3.76257 | 1.35808 | 10.1325 | 5.30849 | 3.67175 | 1.80062

# IfcWall: Mur ALKERN + planelle 21 BARDAGE courant 395 x 2720 (5)
Type - ElementType: SOLIDWALL; PredefinedType: USERDEFINED
Description: Murs de façade bloc ALKERN; Classification: Mur porteur (Classification ARCHICAD)
Pset_WallCommon - AcousticRating: Non défini; ThermalTransmittance: 0; LoadBearing: yes; IsExternal: yes
PSET_Murs_ARCHI - Emplacement: Superstructure; Type: Mur en bloc ELITHERM; Destination: Façade; Matériaux: Maçonnerie Bloc ALKERN Elitherm
AC_Pset_RenovationAndPhasing - Renovation Status: Existing
Material Properties - Component 8, Finition ext - Bardage bois, ThermalConductivity: 0.14; Component 8, Finition ext - Bardage bois, SpecificHeatCapacity: 2300 J/kg/K; Component 8, Finition ext - Bardage bois, MassDensity: 500 kg/m3; Component 8, Finition ext - Bardage bois, Embodied Energy: 10 (MJ/kg); Component 8, Finition ext - Bardage bois, Embodied Carbon: 0.36 (kgCO₂/kg); Component 8, Finition ext - Bardage bois, Name: Finition ext - Bardage bois; Component 8, Finition ext - Bardage bois, Participates in Collision Detection: no; Component 3, Bois - Lattage, ThermalConductivity: 0.13; Component 3, Bois - Lattage, SpecificHeatCapacity: 1600 J/kg/K; Component 3, Bois - Lattage, MassDensity: 500 kg/m3; Component 3, Bois - Lattage, Embodied Energy: 6.95 (MJ/kg); Component 3, Bois - Lattage, Embodied Carbon: 0.29 (kgCO₂/kg); Component 3, Bois - Lattage, Name: Bois - Lattage; Component 3, Bois - Lattage, Participates in Collision Detection: yes; Component 6, Béton cellulaire, ThermalConductivity: 0.12; Component 6, Béton cellulaire, SpecificHeatCapacity: 1050 J/kg/K; Component 6, Béton cellulaire, MassDensity: 450 kg/m3; Component 6, Béton cellulaire, Embodied Energy: 0.57 (MJ/kg); Component 6, Béton cellulaire, Embodied Carbon: 0.061 (kgCO₂/kg); Component 6, Béton cellulaire, Name: Béton cellulaire; Component 6, Béton cellulaire, Participates in Collision Detection: yes; Component 7, Mortier, ThermalConductivity: 1.15; Component 7, Mortier, SpecificHeatCapacity: 1000 J/kg/K; Component 7, Mortier, MassDensity: 1800 kg/m3; Component 7, Mortier, Embodied Energy: 0.74 (MJ/kg); Component 7, Mortier, Embodied Carbon: 0.107 (kgCO₂/kg); Component 7, Mortier, Name: Mortier; Component 7, Mortier, Participates in Collision Detection: yes; Component 1, Bloc ELITHERM, ThermalConductivity: 1.35; Component 1, Bloc ELITHERM, SpecificHeatCapacity: 1000 J/kg/K; Component 1, Bloc ELITHERM, MassDensity: 2000 kg/m3; Component 1, Bloc ELITHERM, Embodied Energy: 0.78 (MJ/kg); Component 1, Bloc ELITHERM, Embodied Carbon: 0.113 (kgCO₂/kg); Component 1, Bloc ELITHERM, Name: Bloc ELITHERM; Component 1, Bloc ELITHERM, Participates in Collision Detection: yes; Component 2, Isolation - Polystyrène extrudé, ThermalConductivity: 0.036; Component 2, Isolation - Polystyrène extrudé, SpecificHeatCapacity: 1400 J/kg/K; Component 2, Isolation - Polystyrène extrudé, MassDensity: 25 kg/m3; Component 2, Isolation - Polystyrène extrudé, Embodied Energy: 86.4 (MJ/kg); Component 2, Isolation - Polystyrène extrudé, Embodied Carbon: 3.43 (kgCO₂/kg); Component 2, Isolation - Polystyrène extrudé, Name: Isolation - Polystyrène extrudé; Component 2, Isolation - Polystyrène extrudé, Participates in Collision Detection: no; Component 4, Finition int - Plaque de plâtre, ThermalConductivity: 0.8; Component 4, Finition int - Plaque de plâtre, SpecificHeatCapacity: 1000 J/kg/K; Component 4, Finition int - Plaque de plâtre, MassDensity: 1600 kg/m3; Component 4, Finition int - Plaque de plâtre, Embodied Energy: 1.45 (MJ/kg); Component 4, Finition int - Plaque de plâtre, Embodied Carbon: 0.22 (kgCO₂/kg); Component 4, Finition int - Plaque de plâtre, Name: Finition int - Plaque de plâtre; Component 4, Finition int - Plaque de plâtre, Participates in Collision Detection: no
BaseQuantities - Height: 2.72 m; Width: 0.395 m
Name | In | Material | Numéro de LOT | Numéro article | Length (m) | GrossFootprintArea (m2) = NetFootprintArea (m2) | GrossSideArea (m2) | NetSideArea (m2) | GrossVolume (m3) | NetVolume (m3)
Mue bloc ALKERN isolé | R+2 | Finition ext - Bardage bois, Bois - Lattage, Béton cellulaire, Mortier, Isolation - Polystyrène expansé, Bloc ELITHERM, Isolation - Polystyrène extrudé, Finition int - Plaque de plâtre | LOT 04; LOT 05; LOT 09 | L04.2.12.1.1; L05.2.3.2; L09.2.1.1.1 | 7.47472 | 2.95873 | 20.2849 | 14.6149 | 7.58745 | 5.3478 | Material Properties - Component 5, Isolation - Polystyrène expansé, ThermalConductivity: 0.036; Component 5, Isolation - Polystyrène expansé, SpecificHeatCapacity: 1450 J/kg/K; Component 5, Isolation - Polystyrène expansé, MassDensity: 25 kg/m3; Component 5, Isolation - Polystyrène expansé, Embodied Energy: 86.6 (MJ/kg); Component 5, Isolation - Polystyrène expansé, Embodied Carbon: 3.29 (kgCO₂/kg); Component 5, Isolation - Polystyrène expansé, Name: Isolation - Polystyrène expansé; Component 5, Isolation - Polystyrène expansé, Participates in Collision Detection: no
Mue bloc ALKERN isolé | R+3 | Finition ext - Bardage bois, Bois - Lattage, Béton cellulaire, Mortier, Bloc ELITHERM, Isolation - Polystyrène extrudé, Finition int - Plaque de plâtre | LOT 04; LOT 05; LOT 09 | L04.2.12.1.1; L05.2.3.2; L09.2.1.1.1 | 6.23784 | 2.47243 | 16.3426 | 12.9826 | 6.33538 | 5.00818
Mue bloc ALKERN isolé | R+3 | Finition int - Plaque de plâtre, Isolation - Polystyrène extrudé, Bloc ELITHERM, Mortier, Béton cellulaire, Bois - Lattage, Finition ext - Bardage bois | LOT 04; LOT 05 | L04.2.12.1.1; L09.2.1.1.1; L16.2.1 | 3.09442 | 1.26869 | 7.85381 | 6.90181 | 3.2549 | 2.87578
Mue bloc ALKERN isolé | R+3 | Finition ext - Bardage bois, Bois - Lattage, Béton cellulaire, Mortier, Isolation - Polystyrène expansé, Bloc ELITHERM, Isolation - Polystyrène extrudé, Finition int - Plaque de plâtre | LOT 04; LOT 05; LOT 09 | L04.2.12.1.1; L05.2.3.2; L09.2.1.1.1 | 4.436 | 1.81779 | 11.6495 | 9.75946 | 4.64116 | 3.89461 | Material Properties - Component 5, Isolation - Polystyrène expansé, ThermalConductivity: 0.036; Component 5, Isolation - Polystyrène expansé, SpecificHeatCapacity: 1450 J/kg/K; Component 5, Isolation - Polystyrène expansé, MassDensity: 25 kg/m3; Component 5, Isolation - Polystyrène expansé, Embodied Energy: 86.6 (MJ/kg); Component 5, Isolation - Polystyrène expansé, Embodied Carbon: 3.29 (kgCO₂/kg); Component 5, Isolation - Polystyrène expansé, Name: Isolation - Polystyrène expansé; Component 5, Isolation - Polystyrène expansé, Participates in Collision Detection: no
Mue bloc ALKERN isolé | R+2 | Finition int - Plaque de plâtre, Isolation - Polystyrène extrudé, Bloc ELITHERM, Mortier, Béton cellulaire, Bois - Lattage, Finition ext - Bardage bois | LOT 04; LOT 05; LOT 09 | L04.2.12.1.1; L05.2.3.2; L09.2.1.1.1 | 0.900809 | 0.30238 | 2.32679 | 2.32679 | 0.753818 | 0.753818

# IfcWall: Mur ALKERN + planelle 21 BARDAGE courant 395 x 2740 (2)
In: R+3
Type - ElementType: SOLIDWALL; PredefinedType: USERDEFINED
Description: Murs de façade bloc ALKERN; Classification: Mur porteur (Classification ARCHICAD); Material: Finition ext - Bardage bois, Bois - Lattage, Béton cellulaire, Mortier, Bloc ELITHERM, Isolation - Polystyrène extrudé, Finition int - Plaque de plâtre
Pset_WallCommon - AcousticRating: Non défini; ThermalTransmittance: 0; LoadBearing: yes; IsExternal: yes
PSET_Murs_ARCHI - Emplacement: Superstructure; Type: Mur en bloc ELITHERM; Destination: Façade; Matériaux: Maçonnerie Bloc ALKERN Elitherm
Propriétés DCE - Numéro de LOT: LOT 04; LOT 05; LOT 09; Numéro article: L04.2.12.1.1; L05.2.3.2; L09.2.1.1.1
AC_Pset_RenovationAndPhasing - Renovation Status: Existing
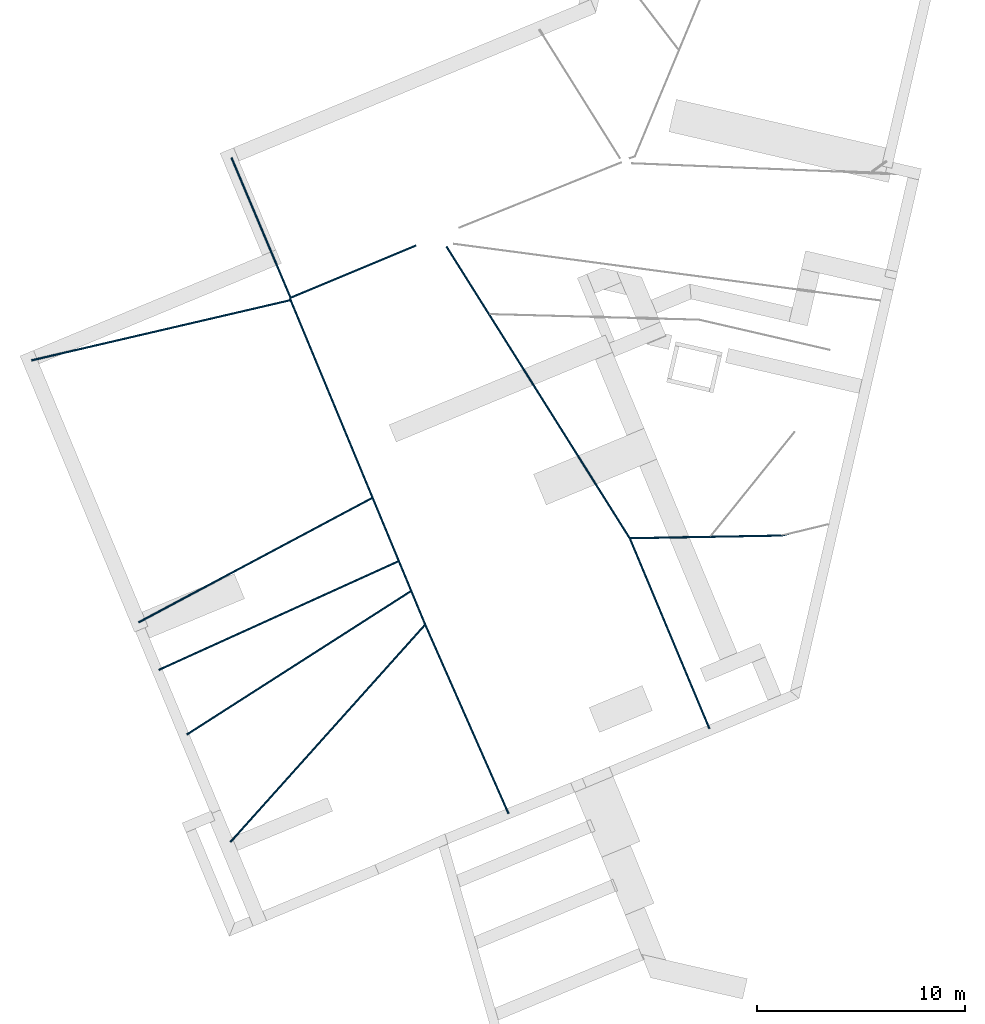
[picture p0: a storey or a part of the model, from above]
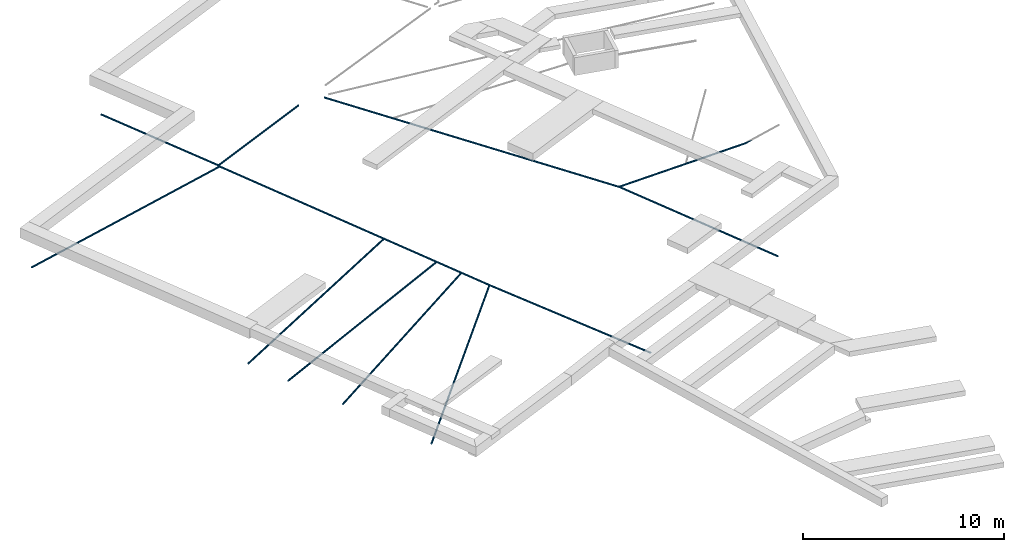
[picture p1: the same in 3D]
Properties of the parts of a building model (IFC2X3), part 20 of 22

# IfcWall: Mur ALKERN + planelle 21 BARDAGE courant 395 x 2740 (2)
Material Properties - Component 8, Finition ext - Bardage bois, ThermalConductivity: 0.14; Component 8, Finition ext - Bardage bois, SpecificHeatCapacity: 2300 J/kg/K; Component 8, Finition ext - Bardage bois, MassDensity: 500 kg/m3; Component 8, Finition ext - Bardage bois, Embodied Energy: 10 (MJ/kg); Component 8, Finition ext - Bardage bois, Embodied Carbon: 0.36 (kgCO₂/kg); Component 8, Finition ext - Bardage bois, Name: Finition ext - Bardage bois; Component 8, Finition ext - Bardage bois, Participates in Collision Detection: no; Component 3, Bois - Lattage, ThermalConductivity: 0.13; Component 3, Bois - Lattage, SpecificHeatCapacity: 1600 J/kg/K; Component 3, Bois - Lattage, MassDensity: 500 kg/m3; Component 3, Bois - Lattage, Embodied Energy: 6.95 (MJ/kg); Component 3, Bois - Lattage, Embodied Carbon: 0.29 (kgCO₂/kg); Component 3, Bois - Lattage, Name: Bois - Lattage; Component 3, Bois - Lattage, Participates in Collision Detection: yes; Component 6, Béton cellulaire, ThermalConductivity: 0.12; Component 6, Béton cellulaire, SpecificHeatCapacity: 1050 J/kg/K; Component 6, Béton cellulaire, MassDensity: 450 kg/m3; Component 6, Béton cellulaire, Embodied Energy: 0.57 (MJ/kg); Component 6, Béton cellulaire, Embodied Carbon: 0.061 (kgCO₂/kg); Component 6, Béton cellulaire, Name: Béton cellulaire; Component 6, Béton cellulaire, Participates in Collision Detection: yes; Component 7, Mortier, ThermalConductivity: 1.15; Component 7, Mortier, SpecificHeatCapacity: 1000 J/kg/K; Component 7, Mortier, MassDensity: 1800 kg/m3; Component 7, Mortier, Embodied Energy: 0.74 (MJ/kg); Component 7, Mortier, Embodied Carbon: 0.107 (kgCO₂/kg); Component 7, Mortier, Name: Mortier; Component 7, Mortier, Participates in Collision Detection: yes; Component 1, Bloc ELITHERM, ThermalConductivity: 1.35; Component 1, Bloc ELITHERM, SpecificHeatCapacity: 1000 J/kg/K; Component 1, Bloc ELITHERM, MassDensity: 2000 kg/m3; Component 1, Bloc ELITHERM, Embodied Energy: 0.78 (MJ/kg); Component 1, Bloc ELITHERM, Embodied Carbon: 0.113 (kgCO₂/kg); Component 1, Bloc ELITHERM, Name: Bloc ELITHERM; Component 1, Bloc ELITHERM, Participates in Collision Detection: yes; Component 2, Isolation - Polystyrène extrudé, ThermalConductivity: 0.036; Component 2, Isolation - Polystyrène extrudé, SpecificHeatCapacity: 1400 J/kg/K; Component 2, Isolation - Polystyrène extrudé, MassDensity: 25 kg/m3; Component 2, Isolation - Polystyrène extrudé, Embodied Energy: 86.4 (MJ/kg); Component 2, Isolation - Polystyrène extrudé, Embodied Carbon: 3.43 (kgCO₂/kg); Component 2, Isolation - Polystyrène extrudé, Name: Isolation - Polystyrène extrudé; Component 2, Isolation - Polystyrène extrudé, Participates in Collision Detection: no; Component 4, Finition int - Plaque de plâtre, ThermalConductivity: 0.8; Component 4, Finition int - Plaque de plâtre, SpecificHeatCapacity: 1000 J/kg/K; Component 4, Finition int - Plaque de plâtre, MassDensity: 1600 kg/m3; Component 4, Finition int - Plaque de plâtre, Embodied Energy: 1.45 (MJ/kg); Component 4, Finition int - Plaque de plâtre, Embodied Carbon: 0.22 (kgCO₂/kg); Component 4, Finition int - Plaque de plâtre, Name: Finition int - Plaque de plâtre; Component 4, Finition int - Plaque de plâtre, Participates in Collision Detection: no
BaseQuantities - Height: 2.74 m; Width: 0.395 m
Name | Length (m) | GrossFootprintArea (m2) = NetFootprintArea (m2) | GrossSideArea (m2) = NetSideArea (m2) | GrossVolume (m3) = NetVolume (m3)
Mue bloc ALKERN isolé | 0.855809 | 0.349363 | 2.25056 | 0.873232
Mue bloc ALKERN isolé | 0.880809 | 0.401189 | 2.35181 | 1.01933

# IfcWall: Mur ALKERN + planelle 21 BARDAGE courant 395 x 2930, Mue bloc ALKERN isolé
In: R+3
Type - ElementType: SOLIDWALL; PredefinedType: USERDEFINED
Description: Murs de façade bloc ALKERN; Classification: Mur porteur (Classification ARCHICAD); Material: Finition int - Plaque de plâtre, Isolation - Polystyrène extrudé, Bloc ELITHERM, Mortier, Béton cellulaire, Bois - Lattage, Finition ext - Bardage bois
Pset_WallCommon - AcousticRating: Non défini; ThermalTransmittance: 0; LoadBearing: yes; IsExternal: yes
PSET_Murs_ARCHI - Emplacement: Superstructure; Type: Mur en bloc ELITHERM; Destination: Façade; Matériaux: Maçonnerie Bloc ALKERN Elitherm
Propriétés DCE - Numéro de LOT: LOT 04; LOT 05; LOT 09; Numéro article: L04.2.12.1.1; L05.2.3.2; L09.2.1.1.1
AC_Pset_RenovationAndPhasing - Renovation Status: Existing
Material Properties - Component 4, Finition int - Plaque de plâtre, ThermalConductivity: 0.8; Component 4, Finition int - Plaque de plâtre, SpecificHeatCapacity: 1000 J/kg/K; Component 4, Finition int - Plaque de plâtre, MassDensity: 1600 kg/m3; Component 4, Finition int - Plaque de plâtre, Embodied Energy: 1.45 (MJ/kg); Component 4, Finition int - Plaque de plâtre, Embodied Carbon: 0.22 (kgCO₂/kg); Component 4, Finition int - Plaque de plâtre, Name: Finition int - Plaque de plâtre; Component 4, Finition int - Plaque de plâtre, Participates in Collision Detection: no; Component 2, Isolation - Polystyrène extrudé, ThermalConductivity: 0.036; Component 2, Isolation - Polystyrène extrudé, SpecificHeatCapacity: 1400 J/kg/K; Component 2, Isolation - Polystyrène extrudé, MassDensity: 25 kg/m3; Component 2, Isolation - Polystyrène extrudé, Embodied Energy: 86.4 (MJ/kg); Component 2, Isolation - Polystyrène extrudé, Embodied Carbon: 3.43 (kgCO₂/kg); Component 2, Isolation - Polystyrène extrudé, Name: Isolation - Polystyrène extrudé; Component 2, Isolation - Polystyrène extrudé, Participates in Collision Detection: no; Component 1, Bloc ELITHERM, ThermalConductivity: 1.35; Component 1, Bloc ELITHERM, SpecificHeatCapacity: 1000 J/kg/K; Component 1, Bloc ELITHERM, MassDensity: 2000 kg/m3; Component 1, Bloc ELITHERM, Embodied Energy: 0.78 (MJ/kg); Component 1, Bloc ELITHERM, Embodied Carbon: 0.113 (kgCO₂/kg); Component 1, Bloc ELITHERM, Name: Bloc ELITHERM; Component 1, Bloc ELITHERM, Participates in Collision Detection: yes; Component 7, Mortier, ThermalConductivity: 1.15; Component 7, Mortier, SpecificHeatCapacity: 1000 J/kg/K; Component 7, Mortier, MassDensity: 1800 kg/m3; Component 7, Mortier, Embodied Energy: 0.74 (MJ/kg); Component 7, Mortier, Embodied Carbon: 0.107 (kgCO₂/kg); Component 7, Mortier, Name: Mortier; Component 7, Mortier, Participates in Collision Detection: yes; Component 6, Béton cellulaire, ThermalConductivity: 0.12; Component 6, Béton cellulaire, SpecificHeatCapacity: 1050 J/kg/K; Component 6, Béton cellulaire, MassDensity: 450 kg/m3; Component 6, Béton cellulaire, Embodied Energy: 0.57 (MJ/kg); Component 6, Béton cellulaire, Embodied Carbon: 0.061 (kgCO₂/kg); Component 6, Béton cellulaire, Name: Béton cellulaire; Component 6, Béton cellulaire, Participates in Collision Detection: yes; Component 3, Bois - Lattage, ThermalConductivity: 0.13; Component 3, Bois - Lattage, SpecificHeatCapacity: 1600 J/kg/K; Component 3, Bois - Lattage, MassDensity: 500 kg/m3; Component 3, Bois - Lattage, Embodied Energy: 6.95 (MJ/kg); Component 3, Bois - Lattage, Embodied Carbon: 0.29 (kgCO₂/kg); Component 3, Bois - Lattage, Name: Bois - Lattage; Component 3, Bois - Lattage, Participates in Collision Detection: yes; Component 8, Finition ext - Bardage bois, ThermalConductivity: 0.14; Component 8, Finition ext - Bardage bois, SpecificHeatCapacity: 2300 J/kg/K; Component 8, Finition ext - Bardage bois, MassDensity: 500 kg/m3; Component 8, Finition ext - Bardage bois, Embodied Energy: 10 (MJ/kg); Component 8, Finition ext - Bardage bois, Embodied Carbon: 0.36 (kgCO₂/kg); Component 8, Finition ext - Bardage bois, Name: Finition ext - Bardage bois; Component 8, Finition ext - Bardage bois, Participates in Collision Detection: no
BaseQuantities - Length: 0.875809 m; Height: 2.93 m; Width: 0.395 m; GrossFootprintArea: 0.348592 m2; NetFootprintArea: 0.348592 m2; GrossSideArea: 2.29482 m2; NetSideArea: 2.29482 m2; GrossVolume: 0.915091 m3; NetVolume: 0.915091 m3

# IfcWall: Mur ALKERN + planelle 21 TERRASSE RDC 356 x 2720 (28)
In: Rez-de-chaussée
Type - ElementType: SOLIDWALL; PredefinedType: USERDEFINED
Description: Murs de façade bloc ALKERN; Classification: Mur porteur (Classification ARCHICAD)
Pset_WallCommon - AcousticRating: Non défini; ThermalTransmittance: 0; LoadBearing: yes; IsExternal: yes
PSET_Murs_ARCHI - Emplacement: Superstructure; Type: Mur en bloc ELITHERM; Destination: Façade; Matériaux: Maçonnerie Bloc ALKERN Elitherm
Propriétés DCE - Numéro de LOT: LOT 04; LOT 09; LOT 16; Numéro article: L04.2.12.1.1; L09.2.1.1.1; L16.2.1
AC_Pset_RenovationAndPhasing - Renovation Status: Existing
Material Properties - Component 4, Finition int - Plaque de plâtre, ThermalConductivity: 0.8; Component 4, Finition int - Plaque de plâtre, SpecificHeatCapacity: 1000 J/kg/K; Component 4, Finition int - Plaque de plâtre, MassDensity: 1600 kg/m3; Component 4, Finition int - Plaque de plâtre, Embodied Energy: 1.45 (MJ/kg); Component 4, Finition int - Plaque de plâtre, Embodied Carbon: 0.22 (kgCO₂/kg); Component 4, Finition int - Plaque de plâtre, Name: Finition int - Plaque de plâtre; Component 4, Finition int - Plaque de plâtre, Participates in Collision Detection: no; Component 2, Isolation - Polystyrène extrudé, ThermalConductivity: 0.036; Component 2, Isolation - Polystyrène extrudé, SpecificHeatCapacity: 1400 J/kg/K; Component 2, Isolation - Polystyrène extrudé, MassDensity: 25 kg/m3; Component 2, Isolation - Polystyrène extrudé, Embodied Energy: 86.4 (MJ/kg); Component 2, Isolation - Polystyrène extrudé, Embodied Carbon: 3.43 (kgCO₂/kg); Component 2, Isolation - Polystyrène extrudé, Name: Isolation - Polystyrène extrudé; Component 2, Isolation - Polystyrène extrudé, Participates in Collision Detection: no; Component 1, Bloc ELITHERM, ThermalConductivity: 1.35; Component 1, Bloc ELITHERM, SpecificHeatCapacity: 1000 J/kg/K; Component 1, Bloc ELITHERM, MassDensity: 2000 kg/m3; Component 1, Bloc ELITHERM, Embodied Energy: 0.78 (MJ/kg); Component 1, Bloc ELITHERM, Embodied Carbon: 0.113 (kgCO₂/kg); Component 1, Bloc ELITHERM, Name: Bloc ELITHERM; Component 1, Bloc ELITHERM, Participates in Collision Detection: yes; Component 7, Mortier, ThermalConductivity: 1.15; Component 7, Mortier, SpecificHeatCapacity: 1000 J/kg/K; Component 7, Mortier, MassDensity: 1800 kg/m3; Component 7, Mortier, Embodied Energy: 0.74 (MJ/kg); Component 7, Mortier, Embodied Carbon: 0.107 (kgCO₂/kg); Component 7, Mortier, Name: Mortier; Component 7, Mortier, Participates in Collision Detection: yes; Component 6, Béton cellulaire, ThermalConductivity: 0.12; Component 6, Béton cellulaire, SpecificHeatCapacity: 1050 J/kg/K; Component 6, Béton cellulaire, MassDensity: 450 kg/m3; Component 6, Béton cellulaire, Embodied Energy: 0.57 (MJ/kg); Component 6, Béton cellulaire, Embodied Carbon: 0.061 (kgCO₂/kg); Component 6, Béton cellulaire, Name: Béton cellulaire; Component 6, Béton cellulaire, Participates in Collision Detection: yes; Component 8, Etanchéité - Bitume, ThermalConductivity: 0.23; Component 8, Etanchéité - Bitume, SpecificHeatCapacity: 1000 J/kg/K; Component 8, Etanchéité - Bitume, MassDensity: 1100 kg/m3; Component 8, Etanchéité - Bitume, Embodied Energy: 2.86 (MJ/kg); Component 8, Etanchéité - Bitume, Embodied Carbon: 0.066 (kgCO₂/kg); Component 8, Etanchéité - Bitume, Name: Etanchéité - Bitume; Component 8, Etanchéité - Bitume, Participates in Collision Detection: no; Component 3, Finition ext - Crépis, ThermalConductivity: 0.8; Component 3, Finition ext - Crépis, SpecificHeatCapacity: 1000 J/kg/K; Component 3, Finition ext - Crépis, MassDensity: 1600 kg/m3; Component 3, Finition ext - Crépis, Embodied Energy: 1.4 (MJ/kg); Component 3, Finition ext - Crépis, Embodied Carbon: 0.09 (kgCO₂/kg); Component 3, Finition ext - Crépis, Name: Finition ext - Crépis; Component 3, Finition ext - Crépis, Participates in Collision Detection: no; Component 9, Métal - Aluminium, ThermalConductivity: 160; Component 9, Métal - Aluminium, SpecificHeatCapacity: 880 J/kg/K; Component 9, Métal - Aluminium, MassDensity: 2800 kg/m3; Component 9, Métal - Aluminium, Embodied Energy: 155 (MJ/kg); Component 9, Métal - Aluminium, Embodied Carbon: 9.16 (kgCO₂/kg); Component 9, Métal - Aluminium, Name: Métal - Aluminium; Component 9, Métal - Aluminium, Participates in Collision Detection: yes
BaseQuantities - Height: 2.72 m; Width: 0.356439 m
Name | Material | Component 5, Isolation - Polystyrène expansé, ThermalConductivity | Component 5, Isolation - Polystyrène expansé, SpecificHeatCapacity (J/kg/K) | Component 5, Isolation - Polystyrène expansé, MassDensity (kg/m3) | Component 5, Isolation - Polystyrène expansé, Embodied Energy | Component 5, Isolation - Polystyrène expansé, Embodied Carbon | Component 5, Isolation - Polystyrène expansé, Name | Component 5, Isolation - Polystyrène expansé, Participates in Collision Detection | Length (m) | GrossFootprintArea (m2) = NetFootprintArea (m2) | GrossSideArea (m2) | NetSideArea (m2) | GrossVolume (m3) | NetVolume (m3)
Mue bloc ALKERN isolé | Finition int - Plaque de plâtre, Isolation - Polystyrène extrudé, Bloc ELITHERM, Isolation - Polystyrène expansé, Mortier, Béton cellulaire, Etanchéité - Bitume, Finition ext - Crépis, Métal - Aluminium | 0.036 | 1450 | 25 | 86.6 (MJ/kg) | 3.29 (kgCO₂/kg) | Isolation - Polystyrène expansé | no | 13.3448 | 4.58739 | 36.7242 | 23.1942 | 11.6655 | 6.99766
Mue bloc ALKERN isolé | Métal - Aluminium, Finition ext - Crépis, Etanchéité - Bitume, Béton cellulaire, Mortier, Isolation - Polystyrène expansé, Bloc ELITHERM, Isolation - Polystyrène extrudé, Finition int - Plaque de plâtre | 0.036 | 1450 | 25 | 86.6 (MJ/kg) | 3.29 (kgCO₂/kg) | Isolation - Polystyrène expansé | no | 11.5831 | 4.05117 | 30.7019 | 21.6819 | 10.2985 | 7.18663
Mue bloc ALKERN isolé | Métal - Aluminium, Finition ext - Crépis, Etanchéité - Bitume, Béton cellulaire, Mortier, Isolation - Polystyrène expansé, Bloc ELITHERM, Isolation - Polystyrène extrudé, Finition int - Plaque de plâtre | 0.036 | 1450 | 25 | 86.6 (MJ/kg) | 3.29 (kgCO₂/kg) | Isolation - Polystyrène expansé | no | 4.26422 | 1.51509 | 11.852 | 6.93201 | 3.85891 | 2.16151
Mue bloc ALKERN isolé | Finition int - Plaque de plâtre, Isolation - Polystyrène extrudé, Bloc ELITHERM, Isolation - Polystyrène expansé, Mortier, Béton cellulaire, Etanchéité - Bitume, Finition ext - Crépis, Métal - Aluminium | 0.036 | 1450 | 25 | 86.6 (MJ/kg) | 3.29 (kgCO₂/kg) | Isolation - Polystyrène expansé | no | 6.08712 | 2.11173 | 16.6722 | 14.6222 | 5.34091 | 4.63366
Mue bloc ALKERN isolé | Métal - Aluminium, Finition ext - Crépis, Etanchéité - Bitume, Béton cellulaire, Mortier, Isolation - Polystyrène expansé, Bloc ELITHERM, Isolation - Polystyrène extrudé, Finition int - Plaque de plâtre | 0.036 | 1450 | 25 | 86.6 (MJ/kg) | 3.29 (kgCO₂/kg) | Isolation - Polystyrène expansé | no | 5.57161 | 1.95328 | 14.0599 | 7.08994 | 4.93304 | 2.52839
Mue bloc ALKERN isolé | Finition int - Plaque de plâtre, Isolation - Polystyrène extrudé, Bloc ELITHERM, Isolation - Polystyrène expansé, Mortier, Béton cellulaire, Etanchéité - Bitume, Finition ext - Crépis, Métal - Aluminium | 0.036 | 1450 | 25 | 86.6 (MJ/kg) | 3.29 (kgCO₂/kg) | Isolation - Polystyrène expansé | no | 7.66018 | 2.64861 | 21.1808 | 14.1181 | 6.77395 | 4.36989
Mue bloc ALKERN isolé | Métal - Aluminium, Finition ext - Crépis, Etanchéité - Bitume, Béton cellulaire, Mortier, Isolation - Polystyrène expansé, Bloc ELITHERM, Isolation - Polystyrène extrudé, Finition int - Plaque de plâtre | 0.036 | 1450 | 25 | 86.6 (MJ/kg) | 3.29 (kgCO₂/kg) | Isolation - Polystyrène expansé | no | 3.77344 | 1.30798 | 10.4332 | 8.3445 | 3.32123 | 2.61423
Mue bloc ALKERN isolé | Finition int - Plaque de plâtre, Isolation - Polystyrène extrudé, Bloc ELITHERM, Isolation - Polystyrène expansé, Mortier, Béton cellulaire, Etanchéité - Bitume, Finition ext - Crépis, Métal - Aluminium | 0.036 | 1450 | 25 | 86.6 (MJ/kg) | 3.29 (kgCO₂/kg) | Isolation - Polystyrène expansé | no | 6.50994 | 2.252 | 18.0047 | 10.2147 | 5.73166 | 3.04411
Mue bloc ALKERN isolé | Finition int - Plaque de plâtre, Isolation - Polystyrène extrudé, Bloc ELITHERM, Isolation - Polystyrène expansé, Mortier, Béton cellulaire, Etanchéité - Bitume, Finition ext - Crépis, Métal - Aluminium | 0.036 | 1450 | 25 | 86.6 (MJ/kg) | 3.29 (kgCO₂/kg) | Isolation - Polystyrène expansé | no | 3.60843 | 1.23624 | 9.74975 | 4.82975 | 3.1448 | 1.4474
Mue bloc ALKERN isolé | Finition int - Plaque de plâtre, Isolation - Polystyrène extrudé, Bloc ELITHERM, Isolation - Polystyrène expansé, Mortier, Béton cellulaire, Etanchéité - Bitume, Finition ext - Crépis, Métal - Aluminium | 0.036 | 1450 | 25 | 86.6 (MJ/kg) | 3.29 (kgCO₂/kg) | Isolation - Polystyrène expansé | no | 6.27308 | 2.18572 | 17.3788 | 9.58882 | 5.48637 | 2.79882
Mue bloc ALKERN isolé | Métal - Aluminium, Finition ext - Crépis, Etanchéité - Bitume, Béton cellulaire, Mortier, Isolation - Polystyrène expansé, Bloc ELITHERM, Isolation - Polystyrène extrudé, Finition int - Plaque de plâtre | 0.036 | 1450 | 25 | 86.6 (MJ/kg) | 3.29 (kgCO₂/kg) | Isolation - Polystyrène expansé | no | 2.4943 | 0.867887 | 6.92157 | 4.87157 | 2.20212 | 1.49487
Mue bloc ALKERN isolé | Métal - Aluminium, Finition ext - Crépis, Etanchéité - Bitume, Béton cellulaire, Mortier, Isolation - Polystyrène expansé, Bloc ELITHERM, Isolation - Polystyrène extrudé, Finition int - Plaque de plâtre | 0.036 | 1450 | 25 | 86.6 (MJ/kg) | 3.29 (kgCO₂/kg) | Isolation - Polystyrène expansé | no | 4.15857 | 1.43269 | 11.485 | 6.47219 | 3.67451 | 1.9777
Mue bloc ALKERN isolé | Métal - Aluminium, Finition ext - Crépis, Etanchéité - Bitume, Béton cellulaire, Mortier, Isolation - Polystyrène expansé, Bloc ELITHERM, Isolation - Polystyrène extrudé, Finition int - Plaque de plâtre | 0.036 | 1450 | 25 | 86.6 (MJ/kg) | 3.29 (kgCO₂/kg) | Isolation - Polystyrène expansé | no | 3.21957 | 1.1183 | 8.89735 | 6.84735 | 2.8122 | 2.10495
Mue bloc ALKERN isolé | Finition int - Plaque de plâtre, Isolation - Polystyrène extrudé, Bloc ELITHERM, Isolation - Polystyrène expansé, Mortier, Béton cellulaire, Etanchéité - Bitume, Finition ext - Crépis, Métal - Aluminium | 0.036 | 1450 | 25 | 86.6 (MJ/kg) | 3.29 (kgCO₂/kg) | Isolation - Polystyrène expansé | no | 3.66195 | 1.29641 | 9.77411 | 9.77411 | 3.29252 | 3.29252
Mue bloc ALKERN isolé | Métal - Aluminium, Finition ext - Crépis, Etanchéité - Bitume, Béton cellulaire, Mortier, Isolation - Polystyrène expansé, Bloc ELITHERM, Isolation - Polystyrène extrudé, Finition int - Plaque de plâtre | 0.036 | 1450 | 25 | 86.6 (MJ/kg) | 3.29 (kgCO₂/kg) | Isolation - Polystyrène expansé | no | 2.09408 | 0.683654 | 5.54695 | 4.46695 | 1.68858 | 1.31598
Mue bloc ALKERN isolé | Métal - Aluminium, Finition ext - Crépis, Etanchéité - Bitume, Béton cellulaire, Mortier, Isolation - Polystyrène expansé, Bloc ELITHERM, Isolation - Polystyrène extrudé, Finition int - Plaque de plâtre | 0.036 | 1450 | 25 | 86.6 (MJ/kg) | 3.29 (kgCO₂/kg) | Isolation - Polystyrène expansé | no | 8.77624 | 3.06424 | 24.2839 | 16.4939 | 7.80618 | 5.11863
Mue bloc ALKERN isolé | Métal - Aluminium, Finition ext - Crépis, Etanchéité - Bitume, Béton cellulaire, Mortier, Isolation - Polystyrène expansé, Bloc ELITHERM, Isolation - Polystyrène extrudé, Finition int - Plaque de plâtre | 0.036 | 1450 | 25 | 86.6 (MJ/kg) | 3.29 (kgCO₂/kg) | Isolation - Polystyrène expansé | no | 0.8 | 0.27828 | 2.21602 | 2.21602 | 0.705749 | 0.705749
Mue bloc ALKERN isolé | Métal - Aluminium, Finition ext - Crépis, Etanchéité - Bitume, Béton cellulaire, Mortier, Isolation - Polystyrène expansé, Bloc ELITHERM, Isolation - Polystyrène extrudé, Finition int - Plaque de plâtre | 0.036 | 1450 | 25 | 86.6 (MJ/kg) | 3.29 (kgCO₂/kg) | Isolation - Polystyrène expansé | no | 0.8 | 0.287031 | 2.21602 | 2.21602 | 0.705749 | 0.705749
Mue bloc ALKERN isolé | Finition int - Plaque de plâtre, Isolation - Polystyrène extrudé, Bloc ELITHERM, Mortier, Béton cellulaire, Etanchéité - Bitume, Finition ext - Crépis, Métal - Aluminium |  |  |  |  |  |  |  | 0.855809 | 0.251919 | 2.2512 | 2.2512 | 0.613708 | 0.613708
Mue bloc ALKERN isolé | Métal - Aluminium, Finition ext - Crépis, Etanchéité - Bitume, Béton cellulaire, Mortier, Isolation - Polystyrène expansé, Bloc ELITHERM, Isolation - Polystyrène extrudé, Finition int - Plaque de plâtre | 0.036 | 1450 | 25 | 86.6 (MJ/kg) | 3.29 (kgCO₂/kg) | Isolation - Polystyrène expansé | no | 2.68804 | 0.988462 | 7.47997 | 7.47997 | 2.51381 | 2.51381
Mue bloc ALKERN isolé | Finition int - Plaque de plâtre, Isolation - Polystyrène extrudé, Bloc ELITHERM, Mortier, Béton cellulaire, Etanchéité - Bitume, Finition ext - Crépis, Métal - Aluminium |  |  |  |  |  |  |  | 0.88522 | 0.376466 | 2.2976 | 2.2976 | 0.945359 | 0.945359
Mue bloc ALKERN isolé | Métal - Aluminium, Finition ext - Crépis, Etanchéité - Bitume, Béton cellulaire, Mortier, Isolation - Polystyrène expansé, Bloc ELITHERM, Isolation - Polystyrène extrudé, Finition int - Plaque de plâtre | 0.036 | 1450 | 25 | 86.6 (MJ/kg) | 3.29 (kgCO₂/kg) | Isolation - Polystyrène expansé | no | 0.980018 | 0.394105 | 2.75051 | 2.75051 | 1.00249 | 1.00249
Mue bloc ALKERN isolé | Finition int - Plaque de plâtre, Isolation - Polystyrène extrudé, Bloc ELITHERM, Isolation - Polystyrène expansé, Mortier, Béton cellulaire, Etanchéité - Bitume, Finition ext - Crépis, Métal - Aluminium | 0.036 | 1450 | 25 | 86.6 (MJ/kg) | 3.29 (kgCO₂/kg) | Isolation - Polystyrène expansé | no | 3.98 | 1.3793 | 11.0247 | 11.0247 | 3.5111 | 3.5111
Mue bloc ALKERN isolé | Finition int - Plaque de plâtre, Isolation - Polystyrène extrudé, Bloc ELITHERM, Isolation - Polystyrène expansé, Mortier, Béton cellulaire, Etanchéité - Bitume, Finition ext - Crépis, Métal - Aluminium | 0.036 | 1450 | 25 | 86.6 (MJ/kg) | 3.29 (kgCO₂/kg) | Isolation - Polystyrène expansé | no | 3.03 | 1.05913 | 8.21168 | 8.21168 | 2.66939 | 2.66939
Mue bloc ALKERN isolé | Finition int - Plaque de plâtre, Isolation - Polystyrène extrudé, Bloc ELITHERM, Isolation - Polystyrène expansé, Mortier, Béton cellulaire, Etanchéité - Bitume, Finition ext - Crépis, Métal - Aluminium | 0.036 | 1450 | 25 | 86.6 (MJ/kg) | 3.29 (kgCO₂/kg) | Isolation - Polystyrène expansé | no | 2.76031 | 0.957007 | 7.64983 | 7.64983 | 2.43527 | 2.43527
Mue bloc ALKERN isolé | Finition int - Plaque de plâtre, Isolation - Polystyrène extrudé, Bloc ELITHERM, Isolation - Polystyrène expansé, Mortier, Béton cellulaire, Etanchéité - Bitume, Finition ext - Crépis, Métal - Aluminium | 0.036 | 1450 | 25 | 86.6 (MJ/kg) | 3.29 (kgCO₂/kg) | Isolation - Polystyrène expansé | no | 1.13149 | 0.458427 | 3.06238 | 3.06238 | 1.16446 | 1.16446
Mue bloc ALKERN isolé | Finition int - Plaque de plâtre, Isolation - Polystyrène extrudé, Bloc ELITHERM, Mortier, Béton cellulaire, Etanchéité - Bitume, Finition ext - Crépis, Métal - Aluminium |  |  |  |  |  |  |  | 1.2 | 0.37109 | 3.1702 | 3.1702 | 0.916031 | 0.916031
Mue bloc ALKERN isolé | Finition int - Plaque de plâtre, Isolation - Polystyrène extrudé, Bloc ELITHERM, Isolation - Polystyrène expansé, Mortier, Béton cellulaire, Etanchéité - Bitume, Finition ext - Crépis, Métal - Aluminium | 0.036 | 1450 | 25 | 86.6 (MJ/kg) | 3.29 (kgCO₂/kg) | Isolation - Polystyrène expansé | no | 2.80141 | 0.945624 | 7.72488 | 5.67488 | 2.40534 | 1.69809

# IfcWall: Mur ALKERN + planelle 23 345 x 2720 (5)
Type - ElementType: SOLIDWALL; PredefinedType: USERDEFINED
Description: Murs de façade bloc ALKERN; Classification: Mur porteur (Classification ARCHICAD)
Pset_WallCommon - AcousticRating: Non défini; ThermalTransmittance: 0; LoadBearing: yes; IsExternal: yes
PSET_Murs_ARCHI - Emplacement: Superstructure; Type: Mur en bloc ELITHERM; Destination: Façade; Matériaux: Maçonnerie Bloc ALKERN Elitherm
Propriétés DCE - Numéro de LOT: LOT 04; LOT 09; LOT 16; Numéro article: L04.2.12.1.1; L09.2.1.1.1; L16.2.1
AC_Pset_RenovationAndPhasing - Renovation Status: Existing
Material Properties - Component 4, Finition int - Plaque de plâtre, ThermalConductivity: 0.8; Component 4, Finition int - Plaque de plâtre, SpecificHeatCapacity: 1000 J/kg/K; Component 4, Finition int - Plaque de plâtre, MassDensity: 1600 kg/m3; Component 4, Finition int - Plaque de plâtre, Embodied Energy: 1.45 (MJ/kg); Component 4, Finition int - Plaque de plâtre, Embodied Carbon: 0.22 (kgCO₂/kg); Component 4, Finition int - Plaque de plâtre, Name: Finition int - Plaque de plâtre; Component 4, Finition int - Plaque de plâtre, Participates in Collision Detection: no; Component 2, Isolation - Polystyrène extrudé, ThermalConductivity: 0.036; Component 2, Isolation - Polystyrène extrudé, SpecificHeatCapacity: 1400 J/kg/K; Component 2, Isolation - Polystyrène extrudé, MassDensity: 25 kg/m3; Component 2, Isolation - Polystyrène extrudé, Embodied Energy: 86.4 (MJ/kg); Component 2, Isolation - Polystyrène extrudé, Embodied Carbon: 3.43 (kgCO₂/kg); Component 2, Isolation - Polystyrène extrudé, Name: Isolation - Polystyrène extrudé; Component 2, Isolation - Polystyrène extrudé, Participates in Collision Detection: no; Component 1, Bloc ELITHERM, ThermalConductivity: 1.35; Component 1, Bloc ELITHERM, SpecificHeatCapacity: 1000 J/kg/K; Component 1, Bloc ELITHERM, MassDensity: 2000 kg/m3; Component 1, Bloc ELITHERM, Embodied Energy: 0.78 (MJ/kg); Component 1, Bloc ELITHERM, Embodied Carbon: 0.113 (kgCO₂/kg); Component 1, Bloc ELITHERM, Name: Bloc ELITHERM; Component 1, Bloc ELITHERM, Participates in Collision Detection: yes; Component 7, Mortier, ThermalConductivity: 1.15; Component 7, Mortier, SpecificHeatCapacity: 1000 J/kg/K; Component 7, Mortier, MassDensity: 1800 kg/m3; Component 7, Mortier, Embodied Energy: 0.74 (MJ/kg); Component 7, Mortier, Embodied Carbon: 0.107 (kgCO₂/kg); Component 7, Mortier, Name: Mortier; Component 7, Mortier, Participates in Collision Detection: yes; Component 6, Béton cellulaire, ThermalConductivity: 0.12; Component 6, Béton cellulaire, SpecificHeatCapacity: 1050 J/kg/K; Component 6, Béton cellulaire, MassDensity: 450 kg/m3; Component 6, Béton cellulaire, Embodied Energy: 0.57 (MJ/kg); Component 6, Béton cellulaire, Embodied Carbon: 0.061 (kgCO₂/kg); Component 6, Béton cellulaire, Name: Béton cellulaire; Component 6, Béton cellulaire, Participates in Collision Detection: yes; Component 3, Finition ext - Crépis, ThermalConductivity: 0.8; Component 3, Finition ext - Crépis, SpecificHeatCapacity: 1000 J/kg/K; Component 3, Finition ext - Crépis, MassDensity: 1600 kg/m3; Component 3, Finition ext - Crépis, Embodied Energy: 1.4 (MJ/kg); Component 3, Finition ext - Crépis, Embodied Carbon: 0.09 (kgCO₂/kg); Component 3, Finition ext - Crépis, Name: Finition ext - Crépis; Component 3, Finition ext - Crépis, Participates in Collision Detection: no
BaseQuantities - Height: 2.72 m; Width: 0.345 m
Name | In | Material | Component 5, Isolation - Polystyrène expansé, ThermalConductivity | Component 5, Isolation - Polystyrène expansé, SpecificHeatCapacity (J/kg/K) | Component 5, Isolation - Polystyrène expansé, MassDensity (kg/m3) | Component 5, Isolation - Polystyrène expansé, Embodied Energy | Component 5, Isolation - Polystyrène expansé, Embodied Carbon | Component 5, Isolation - Polystyrène expansé, Name | Component 5, Isolation - Polystyrène expansé, Participates in Collision Detection | Length (m) | GrossFootprintArea (m2) = NetFootprintArea (m2) | GrossSideArea (m2) | NetSideArea (m2) | GrossVolume (m3) | NetVolume (m3)
Mue bloc ALKERN isolé | R+1 | Finition int - Plaque de plâtre, Isolation - Polystyrène extrudé, Bloc ELITHERM, Isolation - Polystyrène expansé, Mortier, Béton cellulaire, Finition ext - Crépis | 0.036 | 1450 | 25 | 86.6 (MJ/kg) | 3.29 (kgCO₂/kg) | Isolation - Polystyrène expansé | no | 6.75719 | 2.34117 | 18.4154 | 14.6354 | 5.93838 | 4.63428
Mue bloc ALKERN isolé | R+2 | Finition int - Plaque de plâtre, Isolation - Polystyrène extrudé, Bloc ELITHERM, Mortier, Béton cellulaire, Finition ext - Crépis |  |  |  |  |  |  |  | 6.75719 | 2.30129 | 17.6182 | 13.8382 | 5.771 | 4.4669
Mue bloc ALKERN isolé | R+1 | Finition ext - Crépis, Béton cellulaire, Mortier, Isolation - Polystyrène expansé, Bloc ELITHERM, Isolation - Polystyrène extrudé, Finition int - Plaque de plâtre | 0.036 | 1450 | 25 | 86.6 (MJ/kg) | 3.29 (kgCO₂/kg) | Isolation - Polystyrène expansé | no | 2.69376 | 0.992913 | 7.34464 | 7.34464 | 2.50217 | 2.50217
Mue bloc ALKERN isolé | R+1 | Finition int - Plaque de plâtre, Isolation - Polystyrène extrudé, Bloc ELITHERM, Isolation - Polystyrène expansé, Mortier, Béton cellulaire, Finition ext - Crépis | 0.036 | 1450 | 25 | 86.6 (MJ/kg) | 3.29 (kgCO₂/kg) | Isolation - Polystyrène expansé | no | 3.64695 | 1.35807 | 10.0604 | 10.0604 | 3.42221 | 3.42221
Mue bloc ALKERN isolé | R+2 | Finition ext - Crépis, Béton cellulaire, Mortier, Bloc ELITHERM, Isolation - Polystyrène extrudé, Finition int - Plaque de plâtre |  |  |  |  |  |  |  | 2.69376 | 0.992913 | 7.06407 | 7.06407 | 2.49077 | 2.49077

# IfcWall: Mur ALKERN + planelle 23 345 x 2740 (6)
Type - ElementType: SOLIDWALL; PredefinedType: USERDEFINED
Description: Murs de façade bloc ALKERN; Classification: Mur porteur (Classification ARCHICAD)
Pset_WallCommon - AcousticRating: Non défini; ThermalTransmittance: 0; LoadBearing: yes; IsExternal: yes
PSET_Murs_ARCHI - Emplacement: Superstructure; Type: Mur en bloc ELITHERM; Destination: Façade; Matériaux: Maçonnerie Bloc ALKERN Elitherm
Propriétés DCE - Numéro de LOT: LOT 04; LOT 09; LOT 16; Numéro article: L04.2.12.1.1; L09.2.1.1.1; L16.2.1
AC_Pset_RenovationAndPhasing - Renovation Status: Existing
Material Properties - Component 4, Finition int - Plaque de plâtre, ThermalConductivity: 0.8; Component 4, Finition int - Plaque de plâtre, SpecificHeatCapacity: 1000 J/kg/K; Component 4, Finition int - Plaque de plâtre, MassDensity: 1600 kg/m3; Component 4, Finition int - Plaque de plâtre, Embodied Energy: 1.45 (MJ/kg); Component 4, Finition int - Plaque de plâtre, Embodied Carbon: 0.22 (kgCO₂/kg); Component 4, Finition int - Plaque de plâtre, Name: Finition int - Plaque de plâtre; Component 4, Finition int - Plaque de plâtre, Participates in Collision Detection: no; Component 2, Isolation - Polystyrène extrudé, ThermalConductivity: 0.036; Component 2, Isolation - Polystyrène extrudé, SpecificHeatCapacity: 1400 J/kg/K; Component 2, Isolation - Polystyrène extrudé, MassDensity: 25 kg/m3; Component 2, Isolation - Polystyrène extrudé, Embodied Energy: 86.4 (MJ/kg); Component 2, Isolation - Polystyrène extrudé, Embodied Carbon: 3.43 (kgCO₂/kg); Component 2, Isolation - Polystyrène extrudé, Name: Isolation - Polystyrène extrudé; Component 2, Isolation - Polystyrène extrudé, Participates in Collision Detection: no; Component 1, Bloc ELITHERM, ThermalConductivity: 1.35; Component 1, Bloc ELITHERM, SpecificHeatCapacity: 1000 J/kg/K; Component 1, Bloc ELITHERM, MassDensity: 2000 kg/m3; Component 1, Bloc ELITHERM, Embodied Energy: 0.78 (MJ/kg); Component 1, Bloc ELITHERM, Embodied Carbon: 0.113 (kgCO₂/kg); Component 1, Bloc ELITHERM, Name: Bloc ELITHERM; Component 1, Bloc ELITHERM, Participates in Collision Detection: yes; Component 7, Mortier, ThermalConductivity: 1.15; Component 7, Mortier, SpecificHeatCapacity: 1000 J/kg/K; Component 7, Mortier, MassDensity: 1800 kg/m3; Component 7, Mortier, Embodied Energy: 0.74 (MJ/kg); Component 7, Mortier, Embodied Carbon: 0.107 (kgCO₂/kg); Component 7, Mortier, Name: Mortier; Component 7, Mortier, Participates in Collision Detection: yes; Component 6, Béton cellulaire, ThermalConductivity: 0.12; Component 6, Béton cellulaire, SpecificHeatCapacity: 1050 J/kg/K; Component 6, Béton cellulaire, MassDensity: 450 kg/m3; Component 6, Béton cellulaire, Embodied Energy: 0.57 (MJ/kg); Component 6, Béton cellulaire, Embodied Carbon: 0.061 (kgCO₂/kg); Component 6, Béton cellulaire, Name: Béton cellulaire; Component 6, Béton cellulaire, Participates in Collision Detection: yes; Component 3, Finition ext - Crépis, ThermalConductivity: 0.8; Component 3, Finition ext - Crépis, SpecificHeatCapacity: 1000 J/kg/K; Component 3, Finition ext - Crépis, MassDensity: 1600 kg/m3; Component 3, Finition ext - Crépis, Embodied Energy: 1.4 (MJ/kg); Component 3, Finition ext - Crépis, Embodied Carbon: 0.09 (kgCO₂/kg); Component 3, Finition ext - Crépis, Name: Finition ext - Crépis; Component 3, Finition ext - Crépis, Participates in Collision Detection: no
BaseQuantities - Height: 2.74 m; Width: 0.345 m
Name | In | Material | Length (m) | GrossFootprintArea (m2) = NetFootprintArea (m2) | GrossSideArea (m2) | NetSideArea (m2) | GrossVolume (m3) | NetVolume (m3)
Mue bloc ALKERN isolé | R+2 | Finition int - Plaque de plâtre, Isolation - Polystyrène extrudé, Bloc ELITHERM, Mortier, Béton cellulaire, Finition ext - Crépis | 6.2994 | 2.20078 | 15.6178 | 15.6178 | 5.57903 | 5.57903
Mue bloc ALKERN isolé | R+3 | Finition ext - Crépis, Béton cellulaire, Mortier, Bloc ELITHERM, Isolation - Polystyrène extrudé, Finition int - Plaque de plâtre | 3.76439 | 1.33234 | 9.5763 | 7.6863 | 3.38878 | 2.73673
Mue bloc ALKERN isolé | R+3 | Finition int - Plaque de plâtre, Isolation - Polystyrène extrudé, Bloc ELITHERM, Mortier, Béton cellulaire, Finition ext - Crépis | 0.367087 | 0.105234 | 0.78196 | 0.78196 | 0.234199 | 0.234199
Mue bloc ALKERN isolé | R+3 | Finition ext - Crépis, Béton cellulaire, Mortier, Bloc ELITHERM, Isolation - Polystyrène extrudé, Finition int - Plaque de plâtre | 4.83467 | 1.67091 | 12.7012 | 10.8112 | 4.20897 | 3.55692
Mue bloc ALKERN isolé | R+3 | Finition ext - Crépis, Béton cellulaire, Mortier, Bloc ELITHERM, Isolation - Polystyrène extrudé, Finition int - Plaque de plâtre | 0.955 | 0.33735 | 2.5089 | 2.5089 | 0.860972 | 0.860972
Mue bloc ALKERN isolé | R+3 | Finition ext - Crépis, Béton cellulaire, Mortier, Bloc ELITHERM, Isolation - Polystyrène extrudé, Finition int - Plaque de plâtre | 0.322582 | 0.111291 | 0.84839 | 0.84839 | 0.284078 | 0.284078

# IfcWall: Mur ALKERN + planelle 23 BARDAGE courant 395 x 2740 (4)
In: R+3
Type - ElementType: SOLIDWALL; PredefinedType: USERDEFINED
Description: Murs de façade bloc ALKERN; Classification: Mur porteur (Classification ARCHICAD)
Pset_WallCommon - AcousticRating: Non défini; ThermalTransmittance: 0; LoadBearing: yes; IsExternal: yes
PSET_Murs_ARCHI - Emplacement: Superstructure; Type: Mur en bloc ELITHERM; Destination: Façade; Matériaux: Maçonnerie Bloc ALKERN Elitherm
Propriétés DCE - Numéro de LOT: LOT 04; LOT 05; LOT 09; Numéro article: L04.2.12.1.1; L05.2.3.2; L09.2.1.1.1
AC_Pset_RenovationAndPhasing - Renovation Status: Existing
Material Properties - Component 8, Finition ext - Bardage bois, ThermalConductivity: 0.14; Component 8, Finition ext - Bardage bois, SpecificHeatCapacity: 2300 J/kg/K; Component 8, Finition ext - Bardage bois, MassDensity: 500 kg/m3; Component 8, Finition ext - Bardage bois, Embodied Energy: 10 (MJ/kg); Component 8, Finition ext - Bardage bois, Embodied Carbon: 0.36 (kgCO₂/kg); Component 8, Finition ext - Bardage bois, Name: Finition ext - Bardage bois; Component 8, Finition ext - Bardage bois, Participates in Collision Detection: no; Component 3, Bois - Lattage, ThermalConductivity: 0.13; Component 3, Bois - Lattage, SpecificHeatCapacity: 1600 J/kg/K; Component 3, Bois - Lattage, MassDensity: 500 kg/m3; Component 3, Bois - Lattage, Embodied Energy: 6.95 (MJ/kg); Component 3, Bois - Lattage, Embodied Carbon: 0.29 (kgCO₂/kg); Component 3, Bois - Lattage, Name: Bois - Lattage; Component 3, Bois - Lattage, Participates in Collision Detection: yes; Component 6, Béton cellulaire, ThermalConductivity: 0.12; Component 6, Béton cellulaire, SpecificHeatCapacity: 1050 J/kg/K; Component 6, Béton cellulaire, MassDensity: 450 kg/m3; Component 6, Béton cellulaire, Embodied Energy: 0.57 (MJ/kg); Component 6, Béton cellulaire, Embodied Carbon: 0.061 (kgCO₂/kg); Component 6, Béton cellulaire, Name: Béton cellulaire; Component 6, Béton cellulaire, Participates in Collision Detection: yes; Component 7, Mortier, ThermalConductivity: 1.15; Component 7, Mortier, SpecificHeatCapacity: 1000 J/kg/K; Component 7, Mortier, MassDensity: 1800 kg/m3; Component 7, Mortier, Embodied Energy: 0.74 (MJ/kg); Component 7, Mortier, Embodied Carbon: 0.107 (kgCO₂/kg); Component 7, Mortier, Name: Mortier; Component 7, Mortier, Participates in Collision Detection: yes; Component 1, Bloc ELITHERM, ThermalConductivity: 1.35; Component 1, Bloc ELITHERM, SpecificHeatCapacity: 1000 J/kg/K; Component 1, Bloc ELITHERM, MassDensity: 2000 kg/m3; Component 1, Bloc ELITHERM, Embodied Energy: 0.78 (MJ/kg); Component 1, Bloc ELITHERM, Embodied Carbon: 0.113 (kgCO₂/kg); Component 1, Bloc ELITHERM, Name: Bloc ELITHERM; Component 1, Bloc ELITHERM, Participates in Collision Detection: yes; Component 2, Isolation - Polystyrène extrudé, ThermalConductivity: 0.036; Component 2, Isolation - Polystyrène extrudé, SpecificHeatCapacity: 1400 J/kg/K; Component 2, Isolation - Polystyrène extrudé, MassDensity: 25 kg/m3; Component 2, Isolation - Polystyrène extrudé, Embodied Energy: 86.4 (MJ/kg); Component 2, Isolation - Polystyrène extrudé, Embodied Carbon: 3.43 (kgCO₂/kg); Component 2, Isolation - Polystyrène extrudé, Name: Isolation - Polystyrène extrudé; Component 2, Isolation - Polystyrène extrudé, Participates in Collision Detection: no; Component 4, Finition int - Plaque de plâtre, ThermalConductivity: 0.8; Component 4, Finition int - Plaque de plâtre, SpecificHeatCapacity: 1000 J/kg/K; Component 4, Finition int - Plaque de plâtre, MassDensity: 1600 kg/m3; Component 4, Finition int - Plaque de plâtre, Embodied Energy: 1.45 (MJ/kg); Component 4, Finition int - Plaque de plâtre, Embodied Carbon: 0.22 (kgCO₂/kg); Component 4, Finition int - Plaque de plâtre, Name: Finition int - Plaque de plâtre; Component 4, Finition int - Plaque de plâtre, Participates in Collision Detection: no
BaseQuantities - Height: 2.74 m; Width: 0.395 m
Name | Material | Length (m) | GrossFootprintArea (m2) = NetFootprintArea (m2) | GrossSideArea (m2) | NetSideArea (m2) | GrossVolume (m3) | NetVolume (m3)
Mue bloc ALKERN isolé | Finition ext - Bardage bois, Bois - Lattage, Béton cellulaire, Mortier, Bloc ELITHERM, Isolation - Polystyrène extrudé, Finition int - Plaque de plâtre | 8.17161 | 3.21355 | 21.4674 | 14.2974 | 8.17966 | 5.34751
Mue bloc ALKERN isolé | Finition int - Plaque de plâtre, Isolation - Polystyrène extrudé, Bloc ELITHERM, Mortier, Béton cellulaire, Bois - Lattage, Finition ext - Bardage bois | 6.20571 | 2.44477 | 16.3165 | 11.0365 | 6.29948 | 4.21388
Mue bloc ALKERN isolé | Finition int - Plaque de plâtre, Isolation - Polystyrène extrudé, Bloc ELITHERM, Mortier, Béton cellulaire, Bois - Lattage, Finition ext - Bardage bois | 3.61924 | 1.48394 | 9.5491 | 9.5491 | 3.81466 | 3.81466
Mue bloc ALKERN isolé | Finition int - Plaque de plâtre, Isolation - Polystyrène extrudé, Bloc ELITHERM, Mortier, Béton cellulaire, Bois - Lattage, Finition ext - Bardage bois | 5.10924 | 1.99972 | 13.4261 | 13.4261 | 5.13132 | 5.13132

# IfcWall: Mur ALKERN + planelle 23 TERRASSE 356 x 2740 (2)
In: R+3
Type - ElementType: SOLIDWALL; PredefinedType: USERDEFINED
Description: Murs de façade bloc ALKERN; Classification: Mur porteur (Classification ARCHICAD); Material: Finition int - Plaque de plâtre, Isolation - Polystyrène extrudé, Bloc ELITHERM, Mortier, Béton cellulaire, Etanchéité - Bitume, Finition ext - Crépis, Métal - Aluminium
Pset_WallCommon - AcousticRating: Non défini; ThermalTransmittance: 0; LoadBearing: yes; IsExternal: yes
PSET_Murs_ARCHI - Emplacement: Superstructure; Type: Mur en bloc ELITHERM; Destination: Façade; Matériaux: Maçonnerie Bloc ALKERN Elitherm
Propriétés DCE - Numéro de LOT: LOT 04; LOT 09; LOT 16; Numéro article: L04.2.12.1.1; L09.2.1.1.1; L16.2.1
AC_Pset_RenovationAndPhasing - Renovation Status: Existing
Material Properties - Component 4, Finition int - Plaque de plâtre, ThermalConductivity: 0.8; Component 4, Finition int - Plaque de plâtre, SpecificHeatCapacity: 1000 J/kg/K; Component 4, Finition int - Plaque de plâtre, MassDensity: 1600 kg/m3; Component 4, Finition int - Plaque de plâtre, Embodied Energy: 1.45 (MJ/kg); Component 4, Finition int - Plaque de plâtre, Embodied Carbon: 0.22 (kgCO₂/kg); Component 4, Finition int - Plaque de plâtre, Name: Finition int - Plaque de plâtre; Component 4, Finition int - Plaque de plâtre, Participates in Collision Detection: no; Component 2, Isolation - Polystyrène extrudé, ThermalConductivity: 0.036; Component 2, Isolation - Polystyrène extrudé, SpecificHeatCapacity: 1400 J/kg/K; Component 2, Isolation - Polystyrène extrudé, MassDensity: 25 kg/m3; Component 2, Isolation - Polystyrène extrudé, Embodied Energy: 86.4 (MJ/kg); Component 2, Isolation - Polystyrène extrudé, Embodied Carbon: 3.43 (kgCO₂/kg); Component 2, Isolation - Polystyrène extrudé, Name: Isolation - Polystyrène extrudé; Component 2, Isolation - Polystyrène extrudé, Participates in Collision Detection: no; Component 1, Bloc ELITHERM, ThermalConductivity: 1.35; Component 1, Bloc ELITHERM, SpecificHeatCapacity: 1000 J/kg/K; Component 1, Bloc ELITHERM, MassDensity: 2000 kg/m3; Component 1, Bloc ELITHERM, Embodied Energy: 0.78 (MJ/kg); Component 1, Bloc ELITHERM, Embodied Carbon: 0.113 (kgCO₂/kg); Component 1, Bloc ELITHERM, Name: Bloc ELITHERM; Component 1, Bloc ELITHERM, Participates in Collision Detection: yes; Component 7, Mortier, ThermalConductivity: 1.15; Component 7, Mortier, SpecificHeatCapacity: 1000 J/kg/K; Component 7, Mortier, MassDensity: 1800 kg/m3; Component 7, Mortier, Embodied Energy: 0.74 (MJ/kg); Component 7, Mortier, Embodied Carbon: 0.107 (kgCO₂/kg); Component 7, Mortier, Name: Mortier; Component 7, Mortier, Participates in Collision Detection: yes; Component 6, Béton cellulaire, ThermalConductivity: 0.12; Component 6, Béton cellulaire, SpecificHeatCapacity: 1050 J/kg/K; Component 6, Béton cellulaire, MassDensity: 450 kg/m3; Component 6, Béton cellulaire, Embodied Energy: 0.57 (MJ/kg); Component 6, Béton cellulaire, Embodied Carbon: 0.061 (kgCO₂/kg); Component 6, Béton cellulaire, Name: Béton cellulaire; Component 6, Béton cellulaire, Participates in Collision Detection: yes; Component 8, Etanchéité - Bitume, ThermalConductivity: 0.23; Component 8, Etanchéité - Bitume, SpecificHeatCapacity: 1000 J/kg/K; Component 8, Etanchéité - Bitume, MassDensity: 1100 kg/m3; Component 8, Etanchéité - Bitume, Embodied Energy: 2.86 (MJ/kg); Component 8, Etanchéité - Bitume, Embodied Carbon: 0.066 (kgCO₂/kg); Component 8, Etanchéité - Bitume, Name: Etanchéité - Bitume; Component 8, Etanchéité - Bitume, Participates in Collision Detection: no; Component 3, Finition ext - Crépis, ThermalConductivity: 0.8; Component 3, Finition ext - Crépis, SpecificHeatCapacity: 1000 J/kg/K; Component 3, Finition ext - Crépis, MassDensity: 1600 kg/m3; Component 3, Finition ext - Crépis, Embodied Energy: 1.4 (MJ/kg); Component 3, Finition ext - Crépis, Embodied Carbon: 0.09 (kgCO₂/kg); Component 3, Finition ext - Crépis, Name: Finition ext - Crépis; Component 3, Finition ext - Crépis, Participates in Collision Detection: no; Component 9, Métal - Aluminium, ThermalConductivity: 160; Component 9, Métal - Aluminium, SpecificHeatCapacity: 880 J/kg/K; Component 9, Métal - Aluminium, MassDensity: 2800 kg/m3; Component 9, Métal - Aluminium, Embodied Energy: 155 (MJ/kg); Component 9, Métal - Aluminium, Embodied Carbon: 9.16 (kgCO₂/kg); Component 9, Métal - Aluminium, Name: Métal - Aluminium; Component 9, Métal - Aluminium, Participates in Collision Detection: yes
BaseQuantities - Height: 2.74 m; Width: 0.356439 m
Name | Length (m) | GrossFootprintArea (m2) = NetFootprintArea (m2) | GrossSideArea (m2) | NetSideArea (m2) | GrossVolume (m3) | NetVolume (m3)
Mue bloc ALKERN isolé | 6.28283 | 2.22406 | 16.8159 | 11.9471 | 5.63725 | 3.98175
Mue bloc ALKERN isolé | 5.98449 | 2.12076 | 16.0774 | 11.2086 | 5.37685 | 3.72135

# IfcWall: Mur ALKERN + planelle 25 345 x 2720 (2)
Type - ElementType: SOLIDWALL; PredefinedType: USERDEFINED
Description: Murs de façade bloc ALKERN; Classification: Mur porteur (Classification ARCHICAD); Material: Finition int - Plaque de plâtre, Isolation - Polystyrène extrudé, Bloc ELITHERM, Isolation - Polystyrène expansé, Mortier, Béton cellulaire, Finition ext - Crépis
Pset_WallCommon - AcousticRating: Non défini; ThermalTransmittance: 0; LoadBearing: yes; IsExternal: yes
PSET_Murs_ARCHI - Emplacement: Superstructure; Type: Mur en bloc ELITHERM; Destination: Façade; Matériaux: Maçonnerie Bloc ALKERN Elitherm
Propriétés DCE - Numéro de LOT: LOT 04; LOT 09; LOT 16; Numéro article: L04.2.12.1.1; L09.2.1.1.1; L16.2.1
AC_Pset_RenovationAndPhasing - Renovation Status: Existing
Material Properties - Component 4, Finition int - Plaque de plâtre, ThermalConductivity: 0.8; Component 4, Finition int - Plaque de plâtre, SpecificHeatCapacity: 1000 J/kg/K; Component 4, Finition int - Plaque de plâtre, MassDensity: 1600 kg/m3; Component 4, Finition int - Plaque de plâtre, Embodied Energy: 1.45 (MJ/kg); Component 4, Finition int - Plaque de plâtre, Embodied Carbon: 0.22 (kgCO₂/kg); Component 4, Finition int - Plaque de plâtre, Name: Finition int - Plaque de plâtre; Component 4, Finition int - Plaque de plâtre, Participates in Collision Detection: no; Component 2, Isolation - Polystyrène extrudé, ThermalConductivity: 0.036; Component 2, Isolation - Polystyrène extrudé, SpecificHeatCapacity: 1400 J/kg/K; Component 2, Isolation - Polystyrène extrudé, MassDensity: 25 kg/m3; Component 2, Isolation - Polystyrène extrudé, Embodied Energy: 86.4 (MJ/kg); Component 2, Isolation - Polystyrène extrudé, Embodied Carbon: 3.43 (kgCO₂/kg); Component 2, Isolation - Polystyrène extrudé, Name: Isolation - Polystyrène extrudé; Component 2, Isolation - Polystyrène extrudé, Participates in Collision Detection: no; Component 1, Bloc ELITHERM, ThermalConductivity: 1.35; Component 1, Bloc ELITHERM, SpecificHeatCapacity: 1000 J/kg/K; Component 1, Bloc ELITHERM, MassDensity: 2000 kg/m3; Component 1, Bloc ELITHERM, Embodied Energy: 0.78 (MJ/kg); Component 1, Bloc ELITHERM, Embodied Carbon: 0.113 (kgCO₂/kg); Component 1, Bloc ELITHERM, Name: Bloc ELITHERM; Component 1, Bloc ELITHERM, Participates in Collision Detection: yes; Component 5, Isolation - Polystyrène expansé, ThermalConductivity: 0.036; Component 5, Isolation - Polystyrène expansé, SpecificHeatCapacity: 1450 J/kg/K; Component 5, Isolation - Polystyrène expansé, MassDensity: 25 kg/m3; Component 5, Isolation - Polystyrène expansé, Embodied Energy: 86.6 (MJ/kg); Component 5, Isolation - Polystyrène expansé, Embodied Carbon: 3.29 (kgCO₂/kg); Component 5, Isolation - Polystyrène expansé, Name: Isolation - Polystyrène expansé; Component 5, Isolation - Polystyrène expansé, Participates in Collision Detection: no; Component 7, Mortier, ThermalConductivity: 1.15; Component 7, Mortier, SpecificHeatCapacity: 1000 J/kg/K; Component 7, Mortier, MassDensity: 1800 kg/m3; Component 7, Mortier, Embodied Energy: 0.74 (MJ/kg); Component 7, Mortier, Embodied Carbon: 0.107 (kgCO₂/kg); Component 7, Mortier, Name: Mortier; Component 7, Mortier, Participates in Collision Detection: yes; Component 6, Béton cellulaire, ThermalConductivity: 0.12; Component 6, Béton cellulaire, SpecificHeatCapacity: 1050 J/kg/K; Component 6, Béton cellulaire, MassDensity: 450 kg/m3; Component 6, Béton cellulaire, Embodied Energy: 0.57 (MJ/kg); Component 6, Béton cellulaire, Embodied Carbon: 0.061 (kgCO₂/kg); Component 6, Béton cellulaire, Name: Béton cellulaire; Component 6, Béton cellulaire, Participates in Collision Detection: yes; Component 3, Finition ext - Crépis, ThermalConductivity: 0.8; Component 3, Finition ext - Crépis, SpecificHeatCapacity: 1000 J/kg/K; Component 3, Finition ext - Crépis, MassDensity: 1600 kg/m3; Component 3, Finition ext - Crépis, Embodied Energy: 1.4 (MJ/kg); Component 3, Finition ext - Crépis, Embodied Carbon: 0.09 (kgCO₂/kg); Component 3, Finition ext - Crépis, Name: Finition ext - Crépis; Component 3, Finition ext - Crépis, Participates in Collision Detection: no
BaseQuantities - Height: 2.72 m; Width: 0.345 m
Name | In | Length (m) | GrossFootprintArea (m2) = NetFootprintArea (m2) | GrossSideArea (m2) | NetSideArea (m2) | GrossVolume (m3) | NetVolume (m3)
Mue bloc ALKERN isolé | R+1 | 6.10109 | 2.11425 | 16.6275 | 9.36746 | 5.35062 | 2.84592
Mue bloc ALKERN isolé | R+3 | 2.38134 | 0.830937 | 6.22766 | 4.33766 | 2.09237 | 1.44032

# IfcWall: Mur ALKERN + planelle 25 345 x 2760, Mue bloc ALKERN isolé
In: R+3
Type - ElementType: SOLIDWALL; PredefinedType: USERDEFINED
Description: Murs de façade bloc ALKERN; Classification: Mur porteur (Classification ARCHICAD); Material: Finition int - Plaque de plâtre, Isolation - Polystyrène extrudé, Bloc ELITHERM, Isolation - Polystyrène expansé, Mortier, Béton cellulaire, Finition ext - Crépis
Pset_WallCommon - AcousticRating: Non défini; ThermalTransmittance: 0; LoadBearing: yes; IsExternal: yes
PSET_Murs_ARCHI - Emplacement: Superstructure; Type: Mur en bloc ELITHERM; Destination: Façade; Matériaux: Maçonnerie Bloc ALKERN Elitherm
Propriétés DCE - Numéro de LOT: LOT 04; LOT 09; LOT 16; Numéro article: L04.2.12.1.1; L09.2.1.1.1; L16.2.1
AC_Pset_RenovationAndPhasing - Renovation Status: Existing
Material Properties - Component 4, Finition int - Plaque de plâtre, ThermalConductivity: 0.8; Component 4, Finition int - Plaque de plâtre, SpecificHeatCapacity: 1000 J/kg/K; Component 4, Finition int - Plaque de plâtre, MassDensity: 1600 kg/m3; Component 4, Finition int - Plaque de plâtre, Embodied Energy: 1.45 (MJ/kg); Component 4, Finition int - Plaque de plâtre, Embodied Carbon: 0.22 (kgCO₂/kg); Component 4, Finition int - Plaque de plâtre, Name: Finition int - Plaque de plâtre; Component 4, Finition int - Plaque de plâtre, Participates in Collision Detection: no; Component 2, Isolation - Polystyrène extrudé, ThermalConductivity: 0.036; Component 2, Isolation - Polystyrène extrudé, SpecificHeatCapacity: 1400 J/kg/K; Component 2, Isolation - Polystyrène extrudé, MassDensity: 25 kg/m3; Component 2, Isolation - Polystyrène extrudé, Embodied Energy: 86.4 (MJ/kg); Component 2, Isolation - Polystyrène extrudé, Embodied Carbon: 3.43 (kgCO₂/kg); Component 2, Isolation - Polystyrène extrudé, Name: Isolation - Polystyrène extrudé; Component 2, Isolation - Polystyrène extrudé, Participates in Collision Detection: no; Component 1, Bloc ELITHERM, ThermalConductivity: 1.35; Component 1, Bloc ELITHERM, SpecificHeatCapacity: 1000 J/kg/K; Component 1, Bloc ELITHERM, MassDensity: 2000 kg/m3; Component 1, Bloc ELITHERM, Embodied Energy: 0.78 (MJ/kg); Component 1, Bloc ELITHERM, Embodied Carbon: 0.113 (kgCO₂/kg); Component 1, Bloc ELITHERM, Name: Bloc ELITHERM; Component 1, Bloc ELITHERM, Participates in Collision Detection: yes; Component 5, Isolation - Polystyrène expansé, ThermalConductivity: 0.036; Component 5, Isolation - Polystyrène expansé, SpecificHeatCapacity: 1450 J/kg/K; Component 5, Isolation - Polystyrène expansé, MassDensity: 25 kg/m3; Component 5, Isolation - Polystyrène expansé, Embodied Energy: 86.6 (MJ/kg); Component 5, Isolation - Polystyrène expansé, Embodied Carbon: 3.29 (kgCO₂/kg); Component 5, Isolation - Polystyrène expansé, Name: Isolation - Polystyrène expansé; Component 5, Isolation - Polystyrène expansé, Participates in Collision Detection: no; Component 7, Mortier, ThermalConductivity: 1.15; Component 7, Mortier, SpecificHeatCapacity: 1000 J/kg/K; Component 7, Mortier, MassDensity: 1800 kg/m3; Component 7, Mortier, Embodied Energy: 0.74 (MJ/kg); Component 7, Mortier, Embodied Carbon: 0.107 (kgCO₂/kg); Component 7, Mortier, Name: Mortier; Component 7, Mortier, Participates in Collision Detection: yes; Component 6, Béton cellulaire, ThermalConductivity: 0.12; Component 6, Béton cellulaire, SpecificHeatCapacity: 1050 J/kg/K; Component 6, Béton cellulaire, MassDensity: 450 kg/m3; Component 6, Béton cellulaire, Embodied Energy: 0.57 (MJ/kg); Component 6, Béton cellulaire, Embodied Carbon: 0.061 (kgCO₂/kg); Component 6, Béton cellulaire, Name: Béton cellulaire; Component 6, Béton cellulaire, Participates in Collision Detection: yes; Component 3, Finition ext - Crépis, ThermalConductivity: 0.8; Component 3, Finition ext - Crépis, SpecificHeatCapacity: 1000 J/kg/K; Component 3, Finition ext - Crépis, MassDensity: 1600 kg/m3; Component 3, Finition ext - Crépis, Embodied Energy: 1.4 (MJ/kg); Component 3, Finition ext - Crépis, Embodied Carbon: 0.09 (kgCO₂/kg); Component 3, Finition ext - Crépis, Name: Finition ext - Crépis; Component 3, Finition ext - Crépis, Participates in Collision Detection: no
BaseQuantities - Length: 10.9428 m; Height: 2.76 m; Width: 0.345 m; GrossFootprintArea: 3.74006 m2; NetFootprintArea: 3.74006 m2; GrossSideArea: 28.6948 m2; NetSideArea: 19.6348 m2; GrossVolume: 9.5096 m3; NetVolume: 6.3839 m3

# IfcWall: Mur BETON + planelle 21 contre terre 1M (1) 396 x 2720, M_Ext-007
In: Rez-de-chaussée
Type - ElementType: SOLIDWALL; PredefinedType: USERDEFINED
Classification: Mur porteur (Classification ARCHICAD); Material: Finition int - Plaque de plâtre, Isolation - Polystyrène extrudé, Etanchéité résine, Béton, Isolation - Polystyrène expansé, Mortier (2), Béton cellulaire, Finition ext - Crépis, Etanchéité - Bitume, Couche - Drainage, Métal - Aluminium
Pset_WallCommon - AcousticRating: Non défini; ThermalTransmittance: 0; LoadBearing: yes; IsExternal: yes
PSET_Murs_ARCHI - Emplacement: Superstructure; Type: Mur en bloc ELITHERM; Destination: Façade; Matériaux: Maçonnerie Bloc ALKERN Elitherm
Propriétés DCE - Numéro de LOT: LOT 04; LOT 05; LOT 09; Numéro article: L09.2.1.1.1; L16.2.1
AC_Pset_RenovationAndPhasing - Renovation Status: Existing
Material Properties - Component 4, Finition int - Plaque de plâtre, ThermalConductivity: 0.8; Component 4, Finition int - Plaque de plâtre, SpecificHeatCapacity: 1000 J/kg/K; Component 4, Finition int - Plaque de plâtre, MassDensity: 1600 kg/m3; Component 4, Finition int - Plaque de plâtre, Embodied Energy: 1.45 (MJ/kg); Component 4, Finition int - Plaque de plâtre, Embodied Carbon: 0.22 (kgCO₂/kg); Component 4, Finition int - Plaque de plâtre, Name: Finition int - Plaque de plâtre; Component 4, Finition int - Plaque de plâtre, Participates in Collision Detection: no; Component 2, Isolation - Polystyrène extrudé, ThermalConductivity: 0.036; Component 2, Isolation - Polystyrène extrudé, SpecificHeatCapacity: 1400 J/kg/K; Component 2, Isolation - Polystyrène extrudé, MassDensity: 25 kg/m3; Component 2, Isolation - Polystyrène extrudé, Embodied Energy: 86.4 (MJ/kg); Component 2, Isolation - Polystyrène extrudé, Embodied Carbon: 3.43 (kgCO₂/kg); Component 2, Isolation - Polystyrène extrudé, Name: Isolation - Polystyrène extrudé; Component 2, Isolation - Polystyrène extrudé, Participates in Collision Detection: no; Component 12, Etanchéité résine, ThermalConductivity: 0.17; Component 12, Etanchéité résine, SpecificHeatCapacity: 900 J/kg/K; Component 12, Etanchéité résine, MassDensity: 1390 kg/m3; Component 12, Etanchéité résine, Embodied Energy: 77.2 (MJ/kg); Component 12, Etanchéité résine, Embodied Carbon: 3.1 (kgCO₂/kg); Component 12, Etanchéité résine, Name: Etanchéité résine; Component 12, Etanchéité résine, Participates in Collision Detection: no; Component 1, Béton, ThermalConductivity: 2.3; Component 1, Béton, SpecificHeatCapacity: 1000 J/kg/K; Component 1, Béton, MassDensity: 2300 kg/m3; Component 1, Béton, Embodied Energy: 1.92 (MJ/kg); Component 1, Béton, Embodied Carbon: 0.198 (kgCO₂/kg); Component 1, Béton, Name: Béton; Component 1, Béton, Participates in Collision Detection: yes; Component 5, Isolation - Polystyrène expansé, ThermalConductivity: 0.036; Component 5, Isolation - Polystyrène expansé, SpecificHeatCapacity: 1450 J/kg/K; Component 5, Isolation - Polystyrène expansé, MassDensity: 25 kg/m3; Component 5, Isolation - Polystyrène expansé, Embodied Energy: 86.6 (MJ/kg); Component 5, Isolation - Polystyrène expansé, Embodied Carbon: 3.29 (kgCO₂/kg); Component 5, Isolation - Polystyrène expansé, Name: Isolation - Polystyrène expansé; Component 5, Isolation - Polystyrène expansé, Participates in Collision Detection: no; Component 7, Mortier, ThermalConductivity: 1.15; Component 7, Mortier, SpecificHeatCapacity: 1000 J/kg/K; Component 7, Mortier, MassDensity: 1800 kg/m3; Component 7, Mortier, Embodied Energy: 0.74 (MJ/kg); Component 7, Mortier, Embodied Carbon: 0.107 (kgCO₂/kg); Component 7, Mortier, Name: Mortier; Component 7, Mortier, Participates in Collision Detection: yes; Component 6, Béton cellulaire, ThermalConductivity: 0.12; Component 6, Béton cellulaire, SpecificHeatCapacity: 1050 J/kg/K; Component 6, Béton cellulaire, MassDensity: 450 kg/m3; Component 6, Béton cellulaire, Embodied Energy: 0.57 (MJ/kg); Component 6, Béton cellulaire, Embodied Carbon: 0.061 (kgCO₂/kg); Component 6, Béton cellulaire, Name: Béton cellulaire; Component 6, Béton cellulaire, Participates in Collision Detection: yes; Component 3, Finition ext - Crépis, ThermalConductivity: 0.8; Component 3, Finition ext - Crépis, SpecificHeatCapacity: 1000 J/kg/K; Component 3, Finition ext - Crépis, MassDensity: 1600 kg/m3; Component 3, Finition ext - Crépis, Embodied Energy: 1.4 (MJ/kg); Component 3, Finition ext - Crépis, Embodied Carbon: 0.09 (kgCO₂/kg); Component 3, Finition ext - Crépis, Name: Finition ext - Crépis; Component 3, Finition ext - Crépis, Participates in Collision Detection: no; Component 8, Etanchéité - Bitume, ThermalConductivity: 0.23; Component 8, Etanchéité - Bitume, SpecificHeatCapacity: 1000 J/kg/K; Component 8, Etanchéité - Bitume, MassDensity: 1100 kg/m3; Component 8, Etanchéité - Bitume, Embodied Energy: 2.86 (MJ/kg); Component 8, Etanchéité - Bitume, Embodied Carbon: 0.066 (kgCO₂/kg); Component 8, Etanchéité - Bitume, Name: Etanchéité - Bitume; Component 8, Etanchéité - Bitume, Participates in Collision Detection: no; Component 11, Couche - Drainage, ThermalConductivity: 0.17; Component 11, Couche - Drainage, SpecificHeatCapacity: 900 J/kg/K; Component 11, Couche - Drainage, MassDensity: 1390 kg/m3; Component 11, Couche - Drainage, Embodied Energy: 77.2 (MJ/kg); Component 11, Couche - Drainage, Embodied Carbon: 3.1 (kgCO₂/kg); Component 11, Couche - Drainage, Name: Couche - Drainage; Component 11, Couche - Drainage, Participates in Collision Detection: no; Component 9, Métal - Aluminium, ThermalConductivity: 160; Component 9, Métal - Aluminium, SpecificHeatCapacity: 880 J/kg/K; Component 9, Métal - Aluminium, MassDensity: 2800 kg/m3; Component 9, Métal - Aluminium, Embodied Energy: 155 (MJ/kg); Component 9, Métal - Aluminium, Embodied Carbon: 9.16 (kgCO₂/kg); Component 9, Métal - Aluminium, Name: Métal - Aluminium; Component 9, Métal - Aluminium, Participates in Collision Detection: yes; Component 7: 2 with these values
BaseQuantities - Length: 0.600368 m; Height: 2.72 m; Width: 0.396439 m; GrossFootprintArea: 0.331747 m2; NetFootprintArea: 0.331747 m2; GrossSideArea: 2.27571 m2; NetSideArea: 2.27571 m2; GrossVolume: 0.823242 m3; NetVolume: 0.823242 m3

# IfcWall: Mur ossature Bois avec talon béton 358 x 2500 (10)
In: R+4
Type - PredefinedType: ELEMENTEDWALL
Classification: Mur composite (Classification ARCHICAD)
Pset_WallCommon - AcousticRating: Non défini; ThermalTransmittance: 0; LoadBearing: yes; IsExternal: yes
PSET_Murs_ARCHI - Emplacement: Superstructure; Type: Murs Ossature Bois; Destination: Façade; Matériaux: Ossature Bois
Propriétés DCE - Numéro de LOT: LOT 04; LOT 05; LOT 09
AC_Pset_RenovationAndPhasing - Renovation Status: Existing
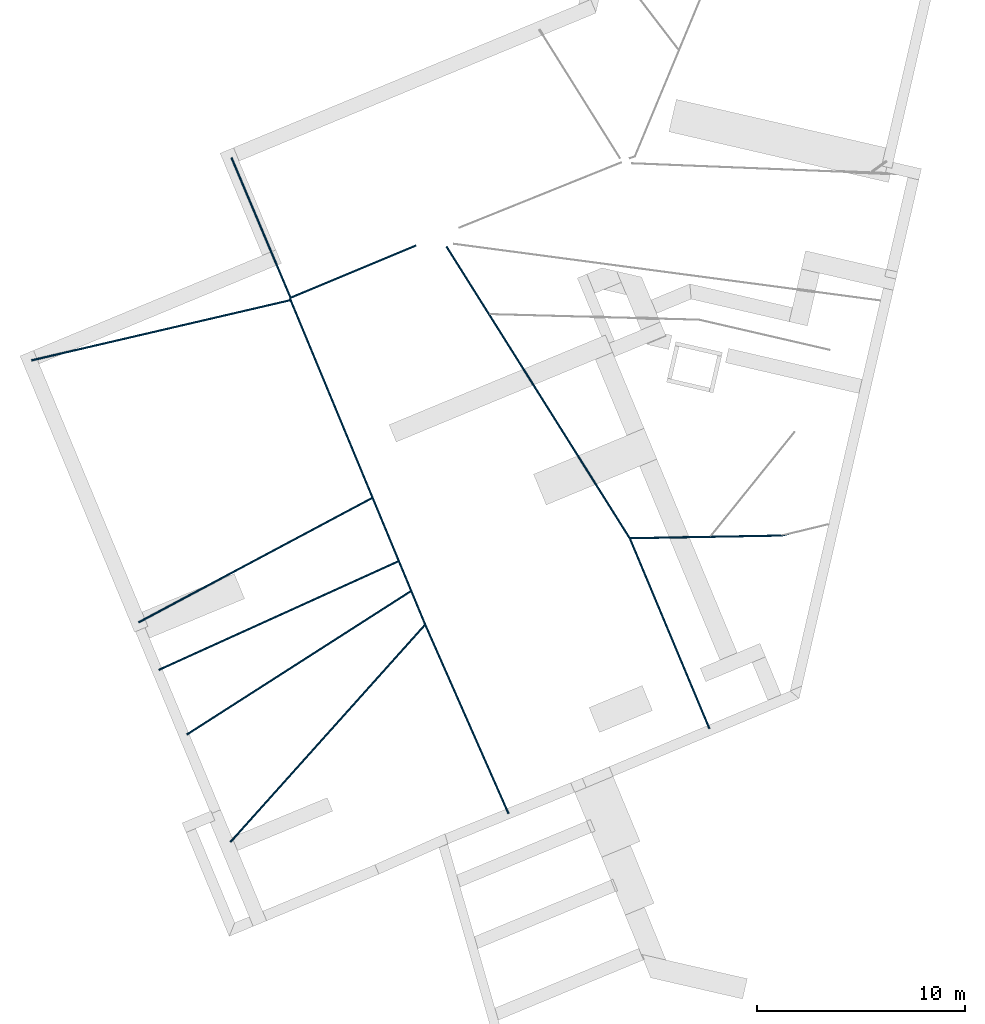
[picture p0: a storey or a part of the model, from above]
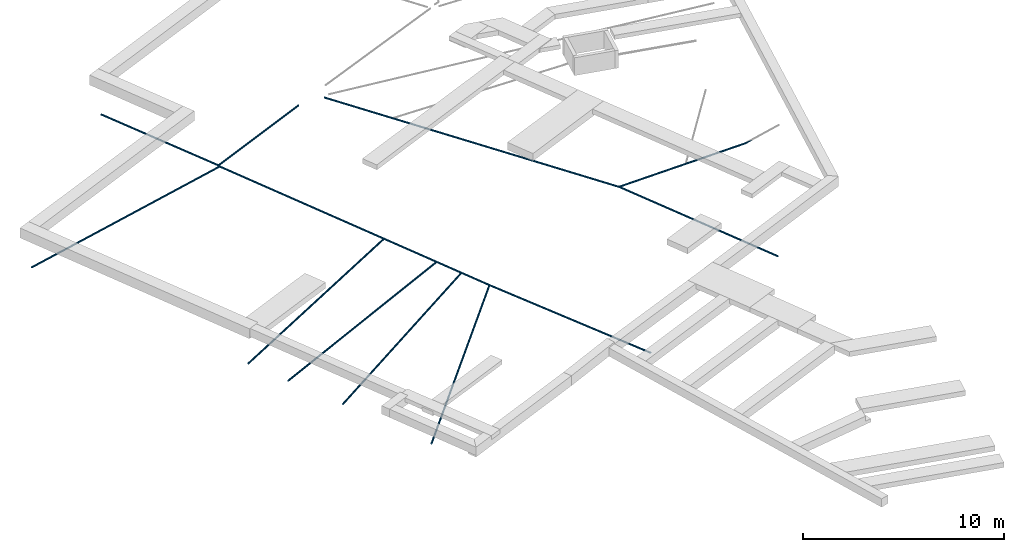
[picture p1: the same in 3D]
Properties of the parts of a building model (IFC2X3), part 21 of 22

# IfcWall: Mur ossature Bois avec talon béton 358 x 2500 (10)
Material Properties - Component 8, Métal - Aluminium, ThermalConductivity: 160; Component 8, Métal - Aluminium, SpecificHeatCapacity: 880 J/kg/K; Component 8, Métal - Aluminium, MassDensity: 2800 kg/m3; Component 8, Métal - Aluminium, Embodied Energy: 155 (MJ/kg); Component 8, Métal - Aluminium, Embodied Carbon: 9.16 (kgCO₂/kg); Component 8, Métal - Aluminium, Name: Métal - Aluminium; Component 8, Métal - Aluminium, Participates in Collision Detection: yes; Component 12, Etanchéité - Bitume, ThermalConductivity: 0.23; Component 12, Etanchéité - Bitume, SpecificHeatCapacity: 1000 J/kg/K; Component 12, Etanchéité - Bitume, MassDensity: 1100 kg/m3; Component 12, Etanchéité - Bitume, Embodied Energy: 2.86 (MJ/kg); Component 12, Etanchéité - Bitume, Embodied Carbon: 0.066 (kgCO₂/kg); Component 12, Etanchéité - Bitume, Name: Etanchéité - Bitume; Component 12, Etanchéité - Bitume, Participates in Collision Detection: no; Component 11, Isolation - Polyuréthane (extérieur), ThermalConductivity: 0.036; Component 11, Isolation - Polyuréthane (extérieur), SpecificHeatCapacity: 1450 J/kg/K; Component 11, Isolation - Polyuréthane (extérieur), MassDensity: 25 kg/m3; Component 11, Isolation - Polyuréthane (extérieur), Embodied Energy: 86.6 (MJ/kg); Component 11, Isolation - Polyuréthane (extérieur), Embodied Carbon: 3.29 (kgCO₂/kg); Component 11, Isolation - Polyuréthane (extérieur), Name: Isolation - Polyuréthane (extérieur); Component 11, Isolation - Polyuréthane (extérieur), Participates in Collision Detection: no; Component 7, Finition ext - Bardage bois, ThermalConductivity: 0.14; Component 7, Finition ext - Bardage bois, SpecificHeatCapacity: 2300 J/kg/K; Component 7, Finition ext - Bardage bois, MassDensity: 500 kg/m3; Component 7, Finition ext - Bardage bois, Embodied Energy: 10 (MJ/kg); Component 7, Finition ext - Bardage bois, Embodied Carbon: 0.36 (kgCO₂/kg); Component 7, Finition ext - Bardage bois, Name: Finition ext - Bardage bois; Component 7, Finition ext - Bardage bois, Participates in Collision Detection: no; Component 6, Bois - Lattage, ThermalConductivity: 0.13; Component 6, Bois - Lattage, SpecificHeatCapacity: 1600 J/kg/K; Component 6, Bois - Lattage, MassDensity: 500 kg/m3; Component 6, Bois - Lattage, Embodied Energy: 6.95 (MJ/kg); Component 6, Bois - Lattage, Embodied Carbon: 0.29 (kgCO₂/kg); Component 6, Bois - Lattage, Name: Bois - Lattage; Component 6, Bois - Lattage, Participates in Collision Detection: yes; Component 5, Bois - OSB 02, ThermalConductivity: 0.13; Component 5, Bois - OSB 02, SpecificHeatCapacity: 1350 J/kg/K; Component 5, Bois - OSB 02, MassDensity: 1000 kg/m3; Component 5, Bois - OSB 02, Embodied Energy: 11.98 (MJ/kg); Component 5, Bois - OSB 02, Embodied Carbon: 0.51 (kgCO₂/kg); Component 5, Bois - OSB 02, Name: Bois - OSB 02; Component 5, Bois - OSB 02, Participates in Collision Detection: yes; Component 1, Béton, ThermalConductivity: 2.3; Component 1, Béton, SpecificHeatCapacity: 1000 J/kg/K; Component 1, Béton, MassDensity: 2300 kg/m3; Component 1, Béton, Embodied Energy: 1.92 (MJ/kg); Component 1, Béton, Embodied Carbon: 0.198 (kgCO₂/kg); Component 1, Béton, Name: Béton; Component 1, Béton, Participates in Collision Detection: yes; Component 9, Bois - Massif 01, ThermalConductivity: 0.14; Component 9, Bois - Massif 01, SpecificHeatCapacity: 2300 J/kg/K; Component 9, Bois - Massif 01, MassDensity: 500 kg/m3; Component 9, Bois - Massif 01, Embodied Energy: 10 (MJ/kg); Component 9, Bois - Massif 01, Embodied Carbon: 0.36 (kgCO₂/kg); Component 9, Bois - Massif 01, Name: Bois - Massif 01; Component 9, Bois - Massif 01, Participates in Collision Detection: yes; Component 13, Etanchéité - Pare-vapeur, ThermalConductivity: 0.5; Component 13, Etanchéité - Pare-vapeur, SpecificHeatCapacity: 1800 J/kg/K; Component 13, Etanchéité - Pare-vapeur, MassDensity: 980 kg/m3; Component 13, Etanchéité - Pare-vapeur, Embodied Energy: 76.7 (MJ/kg); Component 13, Etanchéité - Pare-vapeur, Embodied Carbon: 1.93 (kgCO₂/kg); Component 13, Etanchéité - Pare-vapeur, Name: Etanchéité - Pare-vapeur; Component 13, Etanchéité - Pare-vapeur, Participates in Collision Detection: no; Component 4, Finition int - Plaque de plâtre, ThermalConductivity: 0.8; Component 4, Finition int - Plaque de plâtre, SpecificHeatCapacity: 1000 J/kg/K; Component 4, Finition int - Plaque de plâtre, MassDensity: 1600 kg/m3; Component 4, Finition int - Plaque de plâtre, Embodied Energy: 1.45 (MJ/kg); Component 4, Finition int - Plaque de plâtre, Embodied Carbon: 0.22 (kgCO₂/kg); Component 4, Finition int - Plaque de plâtre, Name: Finition int - Plaque de plâtre; Component 4, Finition int - Plaque de plâtre, Participates in Collision Detection: no; Component 9: 2 with these values
BaseQuantities - Height: 2.5 m; Width: 0.358 m
Name | Material | Numéro article | Component 2, Isolation - Laine de verre, ThermalConductivity | Component 2, Isolation - Laine de verre, SpecificHeatCapacity (J/kg/K) | Component 2, Isolation - Laine de verre, MassDensity (kg/m3) | Component 2, Isolation - Laine de verre, Embodied Energy | Component 2, Isolation - Laine de verre, Embodied Carbon | Component 2, Isolation - Laine de verre, Name | Component 2, Isolation - Laine de verre, Participates in Collision Detection | Component 2 | Length (m) | GrossFootprintArea (m2) = NetFootprintArea (m2) | GrossSideArea (m2) | NetSideArea (m2) | GrossVolume (m3) | NetVolume (m3)
M_Ext-009 | Métal - Aluminium, Etanchéité - Bitume, Isolation - Polyuréthane (extérieur), Finition ext - Bardage bois, Bois - Lattage, Bois - OSB 02, Béton, Isolation - Laine de verre (2), Bois - Massif 01 (2), Etanchéité - Pare-vapeur, Finition int - Plaque de plâtre | L04.2.12.8.3; L05.2.1.2; L05.2.3.1; L09.2.1.2.1 | 0.038 | 1030 | 14.5 | 26.5 (MJ/kg) | 1.32 (kgCO₂/kg) | Isolation - Laine de verre | no | 2 with these values | 4.76064 | 1.68987 | 11.6765 | 10.3015 | 3.58909 | 3.16284
M_Ext-009 | Finition int - Plaque de plâtre, Isolation - Laine de verre (2), Etanchéité - Pare-vapeur, Bois - Massif 01 (2), Béton, Bois - OSB 02, Bois - Lattage, Isolation - Polyuréthane (extérieur), Finition ext - Bardage bois, Etanchéité - Bitume, Métal - Aluminium | L04.2.12.8.3; L05.2.1.2; L05.2.3.1; L09.2.1.2.1 |  |  |  |  |  |  |  |  | 4.00055 | 1.44179 | 9.76417 | 6.88417 | 3.01986 | 2.12706 | Material Properties - Component 3, Isolation - Laine de verre, ThermalConductivity: 0.038; Component 3, Isolation - Laine de verre, SpecificHeatCapacity: 1030 J/kg/K; Component 3, Isolation - Laine de verre, MassDensity: 14.5 kg/m3; Component 3, Isolation - Laine de verre, Embodied Energy: 26.5 (MJ/kg); Component 3, Isolation - Laine de verre, Embodied Carbon: 1.32 (kgCO₂/kg); Component 3, Isolation - Laine de verre, Name: Isolation - Laine de verre; Component 3, Isolation - Laine de verre, Participates in Collision Detection: no; Component 3: 2 with these values
M_Ext-009 | Métal - Aluminium, Etanchéité - Bitume, Isolation - Polyuréthane (extérieur), Finition ext - Bardage bois, Bois - Lattage, Bois - OSB 02, Béton, Isolation - Laine de verre (2), Bois - Massif 01 (2), Etanchéité - Pare-vapeur, Finition int - Plaque de plâtre | L04.2.12.8.3; L05.2.1.2; L05.2.3.1; L09.2.1.2.1 | 0.038 | 1030 | 14.5 | 26.5 (MJ/kg) | 1.32 (kgCO₂/kg) | Isolation - Laine de verre | no | 2 with these values | 0.675465 | 0.263009 | 1.6231 | 1.6231 | 0.528561 | 0.528561
M_Ext-009 | Finition int - Plaque de plâtre, Isolation - Laine de verre (2), Etanchéité - Pare-vapeur, Bois - Massif 01 (2), Béton, Bois - OSB 02, Bois - Lattage, Isolation - Polyuréthane (extérieur), Finition ext - Bardage bois, Etanchéité - Bitume, Métal - Aluminium | L04.2.12.8.3; L05.2.1.2; L05.2.3.1; L09.2.1.2.1 |  |  |  |  |  |  |  |  | 5.84203 | 2.09145 | 14.4006 | 11.5206 | 4.4421 | 3.5493 | Material Properties - Component 3, Isolation - Laine de verre, ThermalConductivity: 0.038; Component 3, Isolation - Laine de verre, SpecificHeatCapacity: 1030 J/kg/K; Component 3, Isolation - Laine de verre, MassDensity: 14.5 kg/m3; Component 3, Isolation - Laine de verre, Embodied Energy: 26.5 (MJ/kg); Component 3, Isolation - Laine de verre, Embodied Carbon: 1.32 (kgCO₂/kg); Component 3, Isolation - Laine de verre, Name: Isolation - Laine de verre; Component 3, Isolation - Laine de verre, Participates in Collision Detection: no; Component 3: 2 with these values
M_Ext-009 | Finition int - Plaque de plâtre, Isolation - Laine de verre (2), Etanchéité - Pare-vapeur, Bois - Massif 01 (2), Béton, Bois - OSB 02, Bois - Lattage, Isolation - Polyuréthane (extérieur), Finition ext - Bardage bois, Etanchéité - Bitume, Métal - Aluminium | L04.2.12.8.3; L05.2.1.2; L05.2.3.1; L09.2.1.2.1 |  |  |  |  |  |  |  |  | 0.479464 | 0.143343 | 1.11434 | 1.11434 | 0.298418 | 0.298418 | Material Properties - Component 3, Isolation - Laine de verre, ThermalConductivity: 0.038; Component 3, Isolation - Laine de verre, SpecificHeatCapacity: 1030 J/kg/K; Component 3, Isolation - Laine de verre, MassDensity: 14.5 kg/m3; Component 3, Isolation - Laine de verre, Embodied Energy: 26.5 (MJ/kg); Component 3, Isolation - Laine de verre, Embodied Carbon: 1.32 (kgCO₂/kg); Component 3, Isolation - Laine de verre, Name: Isolation - Laine de verre; Component 3, Isolation - Laine de verre, Participates in Collision Detection: no; Component 3: 2 with these values
M_Ext-009 | Finition int - Plaque de plâtre, Isolation - Laine de verre (2), Etanchéité - Pare-vapeur, Bois - Massif 01 (2), Béton, Bois - OSB 02, Bois - Lattage, Isolation - Polyuréthane (extérieur), Finition ext - Bardage bois, Etanchéité - Bitume, Métal - Aluminium | L04.2.12.8.3; L05.2.1.2; L05.2.3.1; L09.2.1.2.1 |  |  |  |  |  |  |  |  | 0.961092 | 0.360338 | 2.32042 | 2.32042 | 0.731368 | 0.731368 | Material Properties - Component 3, Isolation - Laine de verre, ThermalConductivity: 0.038; Component 3, Isolation - Laine de verre, SpecificHeatCapacity: 1030 J/kg/K; Component 3, Isolation - Laine de verre, MassDensity: 14.5 kg/m3; Component 3, Isolation - Laine de verre, Embodied Energy: 26.5 (MJ/kg); Component 3, Isolation - Laine de verre, Embodied Carbon: 1.32 (kgCO₂/kg); Component 3, Isolation - Laine de verre, Name: Isolation - Laine de verre; Component 3, Isolation - Laine de verre, Participates in Collision Detection: no; Component 3: 2 with these values
M_Ext-009 | Métal - Aluminium, Etanchéité - Bitume, Isolation - Polyuréthane (extérieur), Finition ext - Bardage bois, Bois - Lattage, Bois - OSB 02, Béton, Isolation - Laine de verre (2), Bois - Massif 01 (2), Etanchéité - Pare-vapeur, Finition int - Plaque de plâtre | L04.2.12.1.1; L09.2.1.1.1; L16.2.1 | 0.038 | 1030 | 14.5 | 26.5 (MJ/kg) | 1.32 (kgCO₂/kg) | Isolation - Laine de verre | no | 2 with these values | 0.161724 | 0.0573941 | 0.298196 | 0.298196 | 0.107164 | 0.107164
M_Ext-009 | Métal - Aluminium, Etanchéité - Bitume, Isolation - Polyuréthane (extérieur), Finition ext - Bardage bois, Bois - Lattage, Bois - OSB 02, Béton, Isolation - Laine de verre (2), Bois - Massif 01 (2), Etanchéité - Pare-vapeur, Finition int - Plaque de plâtre | L04.2.12.8.3; L05.2.1.2; L05.2.3.1; L09.2.1.2.1 | 0.038 | 1030 | 14.5 | 26.5 (MJ/kg) | 1.32 (kgCO₂/kg) | Isolation - Laine de verre | no | 2 with these values | 4.97631 | 1.76507 | 12.175 | 12.175 | 3.72929 | 3.72929
M_Ext-009 | Métal - Aluminium, Etanchéité - Bitume, Isolation - Polyuréthane (extérieur), Finition ext - Bardage bois, Bois - Lattage, Bois - OSB 02, Béton, Isolation - Laine de verre (2), Bois - Massif 01 (2), Etanchéité - Pare-vapeur, Finition int - Plaque de plâtre | L04.2.12.8.3; L05.2.1.2; L05.2.3.1; L09.2.1.2.1 | 0.038 | 1030 | 14.5 | 26.5 (MJ/kg) | 1.32 (kgCO₂/kg) | Isolation - Laine de verre | no | 2 with these values | 1.78775 | 0.661205 | 4.36487 | 4.36487 | 1.37431 | 1.37431
M_Ext-009 | Métal - Aluminium, Etanchéité - Bitume, Isolation - Polyuréthane (extérieur), Finition ext - Bardage bois, Bois - Lattage, Bois - OSB 02, Béton, Isolation - Laine de verre (2), Bois - Massif 01 (2), Etanchéité - Pare-vapeur, Finition int - Plaque de plâtre | L04.2.12.8.3; L05.2.1.2; L05.2.3.1; L09.2.1.2.1 | 0.038 | 1030 | 14.5 | 26.5 (MJ/kg) | 1.32 (kgCO₂/kg) | Isolation - Laine de verre | no | 2 with these values | 0.43166 | 0.175726 | 1.15563 | 1.15563 | 0.382768 | 0.382768

# IfcWall: Mur ossature Bois avec talon béton 358 x 2510 (2)
In: R+4
Type - PredefinedType: ELEMENTEDWALL
Classification: Mur composite (Classification ARCHICAD); Material: Finition int - Plaque de plâtre, Isolation - Laine de verre (2), Etanchéité - Pare-vapeur, Bois - Massif 01 (2), Béton, Bois - OSB 02, Bois - Lattage, Isolation - Polyuréthane (extérieur), Finition ext - Bardage bois, Etanchéité - Bitume, Métal - Aluminium
Pset_WallCommon - AcousticRating: Non défini; ThermalTransmittance: 0; LoadBearing: yes; IsExternal: yes
PSET_Murs_ARCHI - Emplacement: Superstructure; Type: Murs Ossature Bois; Destination: Façade; Matériaux: Ossature Bois
Propriétés DCE - Numéro de LOT: LOT 04; LOT 05; LOT 09; Numéro article: L04.2.12.8.3; L05.2.1.2; L05.2.3.1; L09.2.1.2.1
AC_Pset_RenovationAndPhasing - Renovation Status: Existing
Material Properties - Component 4, Finition int - Plaque de plâtre, ThermalConductivity: 0.8; Component 4, Finition int - Plaque de plâtre, SpecificHeatCapacity: 1000 J/kg/K; Component 4, Finition int - Plaque de plâtre, MassDensity: 1600 kg/m3; Component 4, Finition int - Plaque de plâtre, Embodied Energy: 1.45 (MJ/kg); Component 4, Finition int - Plaque de plâtre, Embodied Carbon: 0.22 (kgCO₂/kg); Component 4, Finition int - Plaque de plâtre, Name: Finition int - Plaque de plâtre; Component 4, Finition int - Plaque de plâtre, Participates in Collision Detection: no; Component 3, Isolation - Laine de verre, ThermalConductivity: 0.038; Component 3, Isolation - Laine de verre, SpecificHeatCapacity: 1030 J/kg/K; Component 3, Isolation - Laine de verre, MassDensity: 14.5 kg/m3; Component 3, Isolation - Laine de verre, Embodied Energy: 26.5 (MJ/kg); Component 3, Isolation - Laine de verre, Embodied Carbon: 1.32 (kgCO₂/kg); Component 3, Isolation - Laine de verre, Name: Isolation - Laine de verre; Component 3, Isolation - Laine de verre, Participates in Collision Detection: no; Component 13, Etanchéité - Pare-vapeur, ThermalConductivity: 0.5; Component 13, Etanchéité - Pare-vapeur, SpecificHeatCapacity: 1800 J/kg/K; Component 13, Etanchéité - Pare-vapeur, MassDensity: 980 kg/m3; Component 13, Etanchéité - Pare-vapeur, Embodied Energy: 76.7 (MJ/kg); Component 13, Etanchéité - Pare-vapeur, Embodied Carbon: 1.93 (kgCO₂/kg); Component 13, Etanchéité - Pare-vapeur, Name: Etanchéité - Pare-vapeur; Component 13, Etanchéité - Pare-vapeur, Participates in Collision Detection: no; Component 9, Bois - Massif 01, ThermalConductivity: 0.14; Component 9, Bois - Massif 01, SpecificHeatCapacity: 2300 J/kg/K; Component 9, Bois - Massif 01, MassDensity: 500 kg/m3; Component 9, Bois - Massif 01, Embodied Energy: 10 (MJ/kg); Component 9, Bois - Massif 01, Embodied Carbon: 0.36 (kgCO₂/kg); Component 9, Bois - Massif 01, Name: Bois - Massif 01; Component 9, Bois - Massif 01, Participates in Collision Detection: yes; Component 1, Béton, ThermalConductivity: 2.3; Component 1, Béton, SpecificHeatCapacity: 1000 J/kg/K; Component 1, Béton, MassDensity: 2300 kg/m3; Component 1, Béton, Embodied Energy: 1.92 (MJ/kg); Component 1, Béton, Embodied Carbon: 0.198 (kgCO₂/kg); Component 1, Béton, Name: Béton; Component 1, Béton, Participates in Collision Detection: yes; Component 5, Bois - OSB 02, ThermalConductivity: 0.13; Component 5, Bois - OSB 02, SpecificHeatCapacity: 1350 J/kg/K; Component 5, Bois - OSB 02, MassDensity: 1000 kg/m3; Component 5, Bois - OSB 02, Embodied Energy: 11.98 (MJ/kg); Component 5, Bois - OSB 02, Embodied Carbon: 0.51 (kgCO₂/kg); Component 5, Bois - OSB 02, Name: Bois - OSB 02; Component 5, Bois - OSB 02, Participates in Collision Detection: yes; Component 6, Bois - Lattage, ThermalConductivity: 0.13; Component 6, Bois - Lattage, SpecificHeatCapacity: 1600 J/kg/K; Component 6, Bois - Lattage, MassDensity: 500 kg/m3; Component 6, Bois - Lattage, Embodied Energy: 6.95 (MJ/kg); Component 6, Bois - Lattage, Embodied Carbon: 0.29 (kgCO₂/kg); Component 6, Bois - Lattage, Name: Bois - Lattage; Component 6, Bois - Lattage, Participates in Collision Detection: yes; Component 11, Isolation - Polyuréthane (extérieur), ThermalConductivity: 0.036; Component 11, Isolation - Polyuréthane (extérieur), SpecificHeatCapacity: 1450 J/kg/K; Component 11, Isolation - Polyuréthane (extérieur), MassDensity: 25 kg/m3; Component 11, Isolation - Polyuréthane (extérieur), Embodied Energy: 86.6 (MJ/kg); Component 11, Isolation - Polyuréthane (extérieur), Embodied Carbon: 3.29 (kgCO₂/kg); Component 11, Isolation - Polyuréthane (extérieur), Name: Isolation - Polyuréthane (extérieur); Component 11, Isolation - Polyuréthane (extérieur), Participates in Collision Detection: no; Component 7, Finition ext - Bardage bois, ThermalConductivity: 0.14; Component 7, Finition ext - Bardage bois, SpecificHeatCapacity: 2300 J/kg/K; Component 7, Finition ext - Bardage bois, MassDensity: 500 kg/m3; Component 7, Finition ext - Bardage bois, Embodied Energy: 10 (MJ/kg); Component 7, Finition ext - Bardage bois, Embodied Carbon: 0.36 (kgCO₂/kg); Component 7, Finition ext - Bardage bois, Name: Finition ext - Bardage bois; Component 7, Finition ext - Bardage bois, Participates in Collision Detection: no; Component 12, Etanchéité - Bitume, ThermalConductivity: 0.23; Component 12, Etanchéité - Bitume, SpecificHeatCapacity: 1000 J/kg/K; Component 12, Etanchéité - Bitume, MassDensity: 1100 kg/m3; Component 12, Etanchéité - Bitume, Embodied Energy: 2.86 (MJ/kg); Component 12, Etanchéité - Bitume, Embodied Carbon: 0.066 (kgCO₂/kg); Component 12, Etanchéité - Bitume, Name: Etanchéité - Bitume; Component 12, Etanchéité - Bitume, Participates in Collision Detection: no; Component 8, Métal - Aluminium, ThermalConductivity: 160; Component 8, Métal - Aluminium, SpecificHeatCapacity: 880 J/kg/K; Component 8, Métal - Aluminium, MassDensity: 2800 kg/m3; Component 8, Métal - Aluminium, Embodied Energy: 155 (MJ/kg); Component 8, Métal - Aluminium, Embodied Carbon: 9.16 (kgCO₂/kg); Component 8, Métal - Aluminium, Name: Métal - Aluminium; Component 8, Métal - Aluminium, Participates in Collision Detection: yes; Component 3: 2 with these values; Component 9: 2 with these values
BaseQuantities - Height: 2.51 m; Width: 0.358 m
Name | Length (m) | GrossFootprintArea (m2) = NetFootprintArea (m2) | GrossSideArea (m2) = NetSideArea (m2) | GrossVolume (m3) = NetVolume (m3)
M_Ext-007 | 7.96358 | 2.87215 | 19.7118 | 6.07302
M_Ext-007 | 3.16743 | 1.11749 | 7.76237 | 2.36402

# IfcWall: Mur ossature Bois avec talon béton sans bardage 275 x 2500, M_Ext-009
In: R+4
Type - PredefinedType: ELEMENTEDWALL
Classification: Mur composite (Classification ARCHICAD); Material: Finition int - Plaque type PROMAT 5cm, Bois - OSB 02, Béton, Isolation - Laine de verre (2), Bois - Massif 01 (2), Etanchéité - Pare-vapeur, Finition int - Plaque de plâtre
Pset_WallCommon - AcousticRating: Non défini; ThermalTransmittance: 0; LoadBearing: yes; IsExternal: yes
PSET_Murs_ARCHI - Emplacement: Superstructure; Type: Murs Ossature Bois; Destination: Façade; Matériaux: Ossature Bois
Propriétés DCE - Numéro de LOT: LOT 04; LOT 05; LOT 09; Numéro article: L04.2.12.8.3; L05.2.1.2; L05.2.3.1; L09.2.1.2.1
AC_Pset_RenovationAndPhasing - Renovation Status: Existing
Material Properties - Component 9, Finition int - Plaque type PROMAT 5cm, ThermalConductivity: 0.18; Component 9, Finition int - Plaque type PROMAT 5cm, SpecificHeatCapacity: 1000 J/kg/K; Component 9, Finition int - Plaque type PROMAT 5cm, MassDensity: 600 kg/m3; Component 9, Finition int - Plaque type PROMAT 5cm, Embodied Energy: 8 (MJ/kg); Component 9, Finition int - Plaque type PROMAT 5cm, Embodied Carbon: 1.2 (kgCO₂/kg); Component 9, Finition int - Plaque type PROMAT 5cm, Name: Finition int - Plaque type PROMAT 5cm; Component 9, Finition int - Plaque type PROMAT 5cm, Participates in Collision Detection: no; Component 5, Bois - OSB 02, ThermalConductivity: 0.13; Component 5, Bois - OSB 02, SpecificHeatCapacity: 1350 J/kg/K; Component 5, Bois - OSB 02, MassDensity: 1000 kg/m3; Component 5, Bois - OSB 02, Embodied Energy: 11.98 (MJ/kg); Component 5, Bois - OSB 02, Embodied Carbon: 0.51 (kgCO₂/kg); Component 5, Bois - OSB 02, Name: Bois - OSB 02; Component 5, Bois - OSB 02, Participates in Collision Detection: yes; Component 1, Béton, ThermalConductivity: 2.3; Component 1, Béton, SpecificHeatCapacity: 1000 J/kg/K; Component 1, Béton, MassDensity: 2300 kg/m3; Component 1, Béton, Embodied Energy: 1.92 (MJ/kg); Component 1, Béton, Embodied Carbon: 0.198 (kgCO₂/kg); Component 1, Béton, Name: Béton; Component 1, Béton, Participates in Collision Detection: yes; Component 2, Isolation - Laine de verre, ThermalConductivity: 0.038; Component 2, Isolation - Laine de verre, SpecificHeatCapacity: 1030 J/kg/K; Component 2, Isolation - Laine de verre, MassDensity: 14.5 kg/m3; Component 2, Isolation - Laine de verre, Embodied Energy: 26.5 (MJ/kg); Component 2, Isolation - Laine de verre, Embodied Carbon: 1.32 (kgCO₂/kg); Component 2, Isolation - Laine de verre, Name: Isolation - Laine de verre; Component 2, Isolation - Laine de verre, Participates in Collision Detection: no; Component 6, Bois - Massif 01, ThermalConductivity: 0.14; Component 6, Bois - Massif 01, SpecificHeatCapacity: 2300 J/kg/K; Component 6, Bois - Massif 01, MassDensity: 500 kg/m3; Component 6, Bois - Massif 01, Embodied Energy: 10 (MJ/kg); Component 6, Bois - Massif 01, Embodied Carbon: 0.36 (kgCO₂/kg); Component 6, Bois - Massif 01, Name: Bois - Massif 01; Component 6, Bois - Massif 01, Participates in Collision Detection: yes; Component 8, Etanchéité - Pare-vapeur, ThermalConductivity: 0.5; Component 8, Etanchéité - Pare-vapeur, SpecificHeatCapacity: 1800 J/kg/K; Component 8, Etanchéité - Pare-vapeur, MassDensity: 980 kg/m3; Component 8, Etanchéité - Pare-vapeur, Embodied Energy: 76.7 (MJ/kg); Component 8, Etanchéité - Pare-vapeur, Embodied Carbon: 1.93 (kgCO₂/kg); Component 8, Etanchéité - Pare-vapeur, Name: Etanchéité - Pare-vapeur; Component 8, Etanchéité - Pare-vapeur, Participates in Collision Detection: no; Component 4, Finition int - Plaque de plâtre, ThermalConductivity: 0.8; Component 4, Finition int - Plaque de plâtre, SpecificHeatCapacity: 1000 J/kg/K; Component 4, Finition int - Plaque de plâtre, MassDensity: 1600 kg/m3; Component 4, Finition int - Plaque de plâtre, Embodied Energy: 1.45 (MJ/kg); Component 4, Finition int - Plaque de plâtre, Embodied Carbon: 0.22 (kgCO₂/kg); Component 4, Finition int - Plaque de plâtre, Name: Finition int - Plaque de plâtre; Component 4, Finition int - Plaque de plâtre, Participates in Collision Detection: no; Component 2: 2 with these values; Component 6: 2 with these values
BaseQuantities - Length: 0.6 m; Height: 2.5 m; Width: 0.275 m; GrossFootprintArea: 0.165 m2; NetFootprintArea: 0.165 m2; GrossSideArea: 1.494 m2; NetSideArea: 1.494 m2; GrossVolume: 0.408558 m3; NetVolume: 0.408558 m3

# IfcWall: Mur ossature Bois non isolé avec talon béton 275 x 3020 (3)
In: R+4
Type - ElementType: SOLIDWALL; PredefinedType: USERDEFINED
Classification: Mur porteur (Classification ARCHICAD); Mur (Classification ARCHICAD); Material: Métal - Aluminium, Etanchéité - Bitume, Isolation - Polyuréthane (extérieur), Finition ext - Bardage bois, Bois - Lattage, Bois - OSB 02, Bois - Massif 01 (2), Béton, Finition int - Plaque type PROMAT 5cm
Pset_WallCommon - AcousticRating: Non défini; ThermalTransmittance: 0; LoadBearing: yes; IsExternal: yes
PSET_Murs_ARCHI - Emplacement: Superstructure; Type: Murs Ossature Bois; Destination: Mur intérieur; Matériaux: BETON
Propriétés DCE - Numéro de LOT: LOT 04; LOT 05; Numéro article: L05.2.1.2; L05.2.3.1; L09.2.1.2.1
AC_Pset_RenovationAndPhasing - Renovation Status: Existing
Material Properties - Component 6, Métal - Aluminium, ThermalConductivity: 160; Component 6, Métal - Aluminium, SpecificHeatCapacity: 880 J/kg/K; Component 6, Métal - Aluminium, MassDensity: 2800 kg/m3; Component 6, Métal - Aluminium, Embodied Energy: 155 (MJ/kg); Component 6, Métal - Aluminium, Embodied Carbon: 9.16 (kgCO₂/kg); Component 6, Métal - Aluminium, Name: Métal - Aluminium; Component 6, Métal - Aluminium, Participates in Collision Detection: yes; Component 10, Etanchéité - Bitume, ThermalConductivity: 0.23; Component 10, Etanchéité - Bitume, SpecificHeatCapacity: 1000 J/kg/K; Component 10, Etanchéité - Bitume, MassDensity: 1100 kg/m3; Component 10, Etanchéité - Bitume, Embodied Energy: 2.86 (MJ/kg); Component 10, Etanchéité - Bitume, Embodied Carbon: 0.066 (kgCO₂/kg); Component 10, Etanchéité - Bitume, Name: Etanchéité - Bitume; Component 10, Etanchéité - Bitume, Participates in Collision Detection: no; Component 9, Isolation - Polyuréthane (extérieur), ThermalConductivity: 0.036; Component 9, Isolation - Polyuréthane (extérieur), SpecificHeatCapacity: 1450 J/kg/K; Component 9, Isolation - Polyuréthane (extérieur), MassDensity: 25 kg/m3; Component 9, Isolation - Polyuréthane (extérieur), Embodied Energy: 86.6 (MJ/kg); Component 9, Isolation - Polyuréthane (extérieur), Embodied Carbon: 3.29 (kgCO₂/kg); Component 9, Isolation - Polyuréthane (extérieur), Name: Isolation - Polyuréthane (extérieur); Component 9, Isolation - Polyuréthane (extérieur), Participates in Collision Detection: no; Component 5, Finition ext - Bardage bois, ThermalConductivity: 0.14; Component 5, Finition ext - Bardage bois, SpecificHeatCapacity: 2300 J/kg/K; Component 5, Finition ext - Bardage bois, MassDensity: 500 kg/m3; Component 5, Finition ext - Bardage bois, Embodied Energy: 10 (MJ/kg); Component 5, Finition ext - Bardage bois, Embodied Carbon: 0.36 (kgCO₂/kg); Component 5, Finition ext - Bardage bois, Name: Finition ext - Bardage bois; Component 5, Finition ext - Bardage bois, Participates in Collision Detection: no; Component 4, Bois - Lattage, ThermalConductivity: 0.13; Component 4, Bois - Lattage, SpecificHeatCapacity: 1600 J/kg/K; Component 4, Bois - Lattage, MassDensity: 500 kg/m3; Component 4, Bois - Lattage, Embodied Energy: 6.95 (MJ/kg); Component 4, Bois - Lattage, Embodied Carbon: 0.29 (kgCO₂/kg); Component 4, Bois - Lattage, Name: Bois - Lattage; Component 4, Bois - Lattage, Participates in Collision Detection: yes; Component 3, Bois - OSB 02, ThermalConductivity: 0.13; Component 3, Bois - OSB 02, SpecificHeatCapacity: 1350 J/kg/K; Component 3, Bois - OSB 02, MassDensity: 1000 kg/m3; Component 3, Bois - OSB 02, Embodied Energy: 11.98 (MJ/kg); Component 3, Bois - OSB 02, Embodied Carbon: 0.51 (kgCO₂/kg); Component 3, Bois - OSB 02, Name: Bois - OSB 02; Component 3, Bois - OSB 02, Participates in Collision Detection: yes; Component 7, Bois - Massif 01, ThermalConductivity: 0.14; Component 7, Bois - Massif 01, SpecificHeatCapacity: 2300 J/kg/K; Component 7, Bois - Massif 01, MassDensity: 500 kg/m3; Component 7, Bois - Massif 01, Embodied Energy: 10 (MJ/kg); Component 7, Bois - Massif 01, Embodied Carbon: 0.36 (kgCO₂/kg); Component 7, Bois - Massif 01, Name: Bois - Massif 01; Component 7, Bois - Massif 01, Participates in Collision Detection: yes; Component 1, Béton, ThermalConductivity: 2.3; Component 1, Béton, SpecificHeatCapacity: 1000 J/kg/K; Component 1, Béton, MassDensity: 2300 kg/m3; Component 1, Béton, Embodied Energy: 1.92 (MJ/kg); Component 1, Béton, Embodied Carbon: 0.198 (kgCO₂/kg); Component 1, Béton, Name: Béton; Component 1, Béton, Participates in Collision Detection: yes; Component 2, Finition int - Plaque type PROMAT 5cm, ThermalConductivity: 0.18; Component 2, Finition int - Plaque type PROMAT 5cm, SpecificHeatCapacity: 1000 J/kg/K; Component 2, Finition int - Plaque type PROMAT 5cm, MassDensity: 600 kg/m3; Component 2, Finition int - Plaque type PROMAT 5cm, Embodied Energy: 8 (MJ/kg); Component 2, Finition int - Plaque type PROMAT 5cm, Embodied Carbon: 1.2 (kgCO₂/kg); Component 2, Finition int - Plaque type PROMAT 5cm, Name: Finition int - Plaque type PROMAT 5cm; Component 2, Finition int - Plaque type PROMAT 5cm, Participates in Collision Detection: no; Component 7: 2 with these values
BaseQuantities - Width: 0.275 m
Name | Length (m) | Height (m) | GrossFootprintArea (m2) = NetFootprintArea (m2) | GrossSideArea (m2) = NetSideArea (m2) | GrossVolume (m3) = NetVolume (m3)
M_Ext-009 | 0.575972 | 3.02 | 0.167901 | 1.62417 | 0.375336
M_Ext-009 | 0.575 | 3.014 | 0.165996 | 1.5899 | 0.350579
M_Ext-009 | 0.575972 | 3.02 | 0.198665 | 1.71812 | 0.430969

# IfcWall: Mur ossature pour PF 358 x 2500 (4)
Type - PredefinedType: ELEMENTEDWALL
Classification: Mur composite (Classification ARCHICAD)
Pset_WallCommon - AcousticRating: Non défini; ThermalTransmittance: 0; LoadBearing: yes; IsExternal: yes
PSET_Murs_ARCHI - Emplacement: Superstructure; Type: Murs Ossature Bois; Destination: Façade
Propriétés DCE - Numéro de LOT: LOT 04; LOT 05; LOT 09; Numéro article: L04.2.12.8.3; L05.2.1.2; L05.2.3.1; L09.2.1.2.1
AC_Pset_RenovationAndPhasing - Renovation Status: Existing
Material Properties - Component 4, Finition int - Plaque de plâtre, ThermalConductivity: 0.8; Component 4, Finition int - Plaque de plâtre, SpecificHeatCapacity: 1000 J/kg/K; Component 4, Finition int - Plaque de plâtre, MassDensity: 1600 kg/m3; Component 4, Finition int - Plaque de plâtre, Embodied Energy: 1.45 (MJ/kg); Component 4, Finition int - Plaque de plâtre, Embodied Carbon: 0.22 (kgCO₂/kg); Component 4, Finition int - Plaque de plâtre, Name: Finition int - Plaque de plâtre; Component 4, Finition int - Plaque de plâtre, Participates in Collision Detection: no; Component 11, Etanchéité - Pare-vapeur, ThermalConductivity: 0.5; Component 11, Etanchéité - Pare-vapeur, SpecificHeatCapacity: 1800 J/kg/K; Component 11, Etanchéité - Pare-vapeur, MassDensity: 980 kg/m3; Component 11, Etanchéité - Pare-vapeur, Embodied Energy: 76.7 (MJ/kg); Component 11, Etanchéité - Pare-vapeur, Embodied Carbon: 1.93 (kgCO₂/kg); Component 11, Etanchéité - Pare-vapeur, Name: Etanchéité - Pare-vapeur; Component 11, Etanchéité - Pare-vapeur, Participates in Collision Detection: no; Component 9, Bois - Massif 01, ThermalConductivity: 0.14; Component 9, Bois - Massif 01, SpecificHeatCapacity: 2300 J/kg/K; Component 9, Bois - Massif 01, MassDensity: 500 kg/m3; Component 9, Bois - Massif 01, Embodied Energy: 10 (MJ/kg); Component 9, Bois - Massif 01, Embodied Carbon: 0.36 (kgCO₂/kg); Component 9, Bois - Massif 01, Name: Bois - Massif 01; Component 9, Bois - Massif 01, Participates in Collision Detection: yes; Component 1, Béton, ThermalConductivity: 2.3; Component 1, Béton, SpecificHeatCapacity: 1000 J/kg/K; Component 1, Béton, MassDensity: 2300 kg/m3; Component 1, Béton, Embodied Energy: 1.92 (MJ/kg); Component 1, Béton, Embodied Carbon: 0.198 (kgCO₂/kg); Component 1, Béton, Name: Béton; Component 1, Béton, Participates in Collision Detection: yes; Component 5, Bois - OSB 02, ThermalConductivity: 0.13; Component 5, Bois - OSB 02, SpecificHeatCapacity: 1350 J/kg/K; Component 5, Bois - OSB 02, MassDensity: 1000 kg/m3; Component 5, Bois - OSB 02, Embodied Energy: 11.98 (MJ/kg); Component 5, Bois - OSB 02, Embodied Carbon: 0.51 (kgCO₂/kg); Component 5, Bois - OSB 02, Name: Bois - OSB 02; Component 5, Bois - OSB 02, Participates in Collision Detection: yes; Component 6, Bois - Lattage, ThermalConductivity: 0.13; Component 6, Bois - Lattage, SpecificHeatCapacity: 1600 J/kg/K; Component 6, Bois - Lattage, MassDensity: 500 kg/m3; Component 6, Bois - Lattage, Embodied Energy: 6.95 (MJ/kg); Component 6, Bois - Lattage, Embodied Carbon: 0.29 (kgCO₂/kg); Component 6, Bois - Lattage, Name: Bois - Lattage; Component 6, Bois - Lattage, Participates in Collision Detection: yes; Component 7, Finition ext - Bardage bois, ThermalConductivity: 0.14; Component 7, Finition ext - Bardage bois, SpecificHeatCapacity: 2300 J/kg/K; Component 7, Finition ext - Bardage bois, MassDensity: 500 kg/m3; Component 7, Finition ext - Bardage bois, Embodied Energy: 10 (MJ/kg); Component 7, Finition ext - Bardage bois, Embodied Carbon: 0.36 (kgCO₂/kg); Component 7, Finition ext - Bardage bois, Name: Finition ext - Bardage bois; Component 7, Finition ext - Bardage bois, Participates in Collision Detection: no; Component 8, Métal - Aluminium, ThermalConductivity: 160; Component 8, Métal - Aluminium, SpecificHeatCapacity: 880 J/kg/K; Component 8, Métal - Aluminium, MassDensity: 2800 kg/m3; Component 8, Métal - Aluminium, Embodied Energy: 155 (MJ/kg); Component 8, Métal - Aluminium, Embodied Carbon: 9.16 (kgCO₂/kg); Component 8, Métal - Aluminium, Name: Métal - Aluminium; Component 8, Métal - Aluminium, Participates in Collision Detection: yes
BaseQuantities - Height: 2.5 m; Width: 0.358 m
Name | In | Material | Matériaux | Length (m) | GrossFootprintArea (m2) = NetFootprintArea (m2) | GrossSideArea (m2) | NetSideArea (m2) | GrossVolume (m3) | NetVolume (m3)
M_Ext-009 | R+3 | Finition int - Plaque de plâtre, Isolation - Laine de verre (2), Etanchéité - Pare-vapeur, Bois - Massif 01, Béton, Bois - OSB 02, Etanchéité - Bitume (2), Bois - Lattage, Finition ext - Bardage bois, Métal - Aluminium | BETON | 4.908 | 1.73911 | 11.9782 | 6.4942 | 3.51305 | 1.80672 | Material Properties - Component 3, Isolation - Laine de verre, ThermalConductivity: 0.038; Component 3, Isolation - Laine de verre, SpecificHeatCapacity: 1030 J/kg/K; Component 3, Isolation - Laine de verre, MassDensity: 14.5 kg/m3; Component 3, Isolation - Laine de verre, Embodied Energy: 26.5 (MJ/kg); Component 3, Isolation - Laine de verre, Embodied Carbon: 1.32 (kgCO₂/kg); Component 3, Isolation - Laine de verre, Name: Isolation - Laine de verre; Component 3, Isolation - Laine de verre, Participates in Collision Detection: no; Component 12, Etanchéité - Bitume, ThermalConductivity: 0.23; Component 12, Etanchéité - Bitume, SpecificHeatCapacity: 1000 J/kg/K; Component 12, Etanchéité - Bitume, MassDensity: 1100 kg/m3; Component 12, Etanchéité - Bitume, Embodied Energy: 2.86 (MJ/kg); Component 12, Etanchéité - Bitume, Embodied Carbon: 0.066 (kgCO₂/kg); Component 12, Etanchéité - Bitume, Name: Etanchéité - Bitume; Component 12, Etanchéité - Bitume, Participates in Collision Detection: no; Component 3: 2 with these values; Component 12: 2 with these values
M_Ext-009 | R+3 | Finition int - Plaque de plâtre, Isolation - Laine de verre (2), Etanchéité - Pare-vapeur, Bois - Massif 01, Béton, Bois - OSB 02, Etanchéité - Bitume (2), Bois - Lattage, Finition ext - Bardage bois, Métal - Aluminium | BETON | 3.90392 | 1.18162 | 9.33322 | 2.72333 | 2.8001 | 0.83702 | Material Properties - Component 3, Isolation - Laine de verre, ThermalConductivity: 0.038; Component 3, Isolation - Laine de verre, SpecificHeatCapacity: 1030 J/kg/K; Component 3, Isolation - Laine de verre, MassDensity: 14.5 kg/m3; Component 3, Isolation - Laine de verre, Embodied Energy: 26.5 (MJ/kg); Component 3, Isolation - Laine de verre, Embodied Carbon: 1.32 (kgCO₂/kg); Component 3, Isolation - Laine de verre, Name: Isolation - Laine de verre; Component 3, Isolation - Laine de verre, Participates in Collision Detection: no; Component 12, Etanchéité - Bitume, ThermalConductivity: 0.23; Component 12, Etanchéité - Bitume, SpecificHeatCapacity: 1000 J/kg/K; Component 12, Etanchéité - Bitume, MassDensity: 1100 kg/m3; Component 12, Etanchéité - Bitume, Embodied Energy: 2.86 (MJ/kg); Component 12, Etanchéité - Bitume, Embodied Carbon: 0.066 (kgCO₂/kg); Component 12, Etanchéité - Bitume, Name: Etanchéité - Bitume; Component 12, Etanchéité - Bitume, Participates in Collision Detection: no; Component 3: 2 with these values; Component 12: 2 with these values
M_Ext-009 | R+3 | Métal - Aluminium, Finition ext - Bardage bois, Bois - Lattage, Etanchéité - Bitume (2), Bois - OSB 02, Bois - Massif 01, Isolation - Laine de verre (2), Béton, Etanchéité - Pare-vapeur, Finition int - Plaque de plâtre | BETON | 3.90392 | 1.18162 | 9.33322 | 2.72733 | 2.8001 | 0.838259 | Material Properties - Component 10, Etanchéité - Bitume, ThermalConductivity: 0.23; Component 10, Etanchéité - Bitume, SpecificHeatCapacity: 1000 J/kg/K; Component 10, Etanchéité - Bitume, MassDensity: 1100 kg/m3; Component 10, Etanchéité - Bitume, Embodied Energy: 2.86 (MJ/kg); Component 10, Etanchéité - Bitume, Embodied Carbon: 0.066 (kgCO₂/kg); Component 10, Etanchéité - Bitume, Name: Etanchéité - Bitume; Component 10, Etanchéité - Bitume, Participates in Collision Detection: no; Component 2, Isolation - Laine de verre, ThermalConductivity: 0.038; Component 2, Isolation - Laine de verre, SpecificHeatCapacity: 1030 J/kg/K; Component 2, Isolation - Laine de verre, MassDensity: 14.5 kg/m3; Component 2, Isolation - Laine de verre, Embodied Energy: 26.5 (MJ/kg); Component 2, Isolation - Laine de verre, Embodied Carbon: 1.32 (kgCO₂/kg); Component 2, Isolation - Laine de verre, Name: Isolation - Laine de verre; Component 2, Isolation - Laine de verre, Participates in Collision Detection: no; Component 10: 2 with these values; Component 2: 2 with these values
M_Ext-009 | R+4 | Métal - Aluminium, Finition ext - Bardage bois, Bois - Lattage, Etanchéité - Bitume (2), Bois - OSB 02, Bois - Massif 01, Isolation - Laine de verre (2), Béton, Etanchéité - Pare-vapeur, Finition int - Plaque de plâtre | Ossature Bois | 2.43 | 0.62994 | 6.10372 | 1.11935 | 1.81738 | 0.365253 | Material Properties - Component 10, Etanchéité - Bitume, ThermalConductivity: 0.23; Component 10, Etanchéité - Bitume, SpecificHeatCapacity: 1000 J/kg/K; Component 10, Etanchéité - Bitume, MassDensity: 1100 kg/m3; Component 10, Etanchéité - Bitume, Embodied Energy: 2.86 (MJ/kg); Component 10, Etanchéité - Bitume, Embodied Carbon: 0.066 (kgCO₂/kg); Component 10, Etanchéité - Bitume, Name: Etanchéité - Bitume; Component 10, Etanchéité - Bitume, Participates in Collision Detection: no; Component 2, Isolation - Laine de verre, ThermalConductivity: 0.038; Component 2, Isolation - Laine de verre, SpecificHeatCapacity: 1030 J/kg/K; Component 2, Isolation - Laine de verre, MassDensity: 14.5 kg/m3; Component 2, Isolation - Laine de verre, Embodied Energy: 26.5 (MJ/kg); Component 2, Isolation - Laine de verre, Embodied Carbon: 1.32 (kgCO₂/kg); Component 2, Isolation - Laine de verre, Name: Isolation - Laine de verre; Component 2, Isolation - Laine de verre, Participates in Collision Detection: no; Component 10: 2 with these values; Component 2: 2 with these values

# IfcWall: Parpaing 10cm 100 (27)
Type - ElementType: PARTITIONING; PredefinedType: USERDEFINED
Description: Parpaing de 10cm; Classification: Cloison (Classification ARCHICAD); Material: Parpaing 10cm
Pset_WallCommon - AcousticRating: Non défini; ThermalTransmittance: 0
PSET_Murs_ARCHI - Emplacement: Infrastructure; Type: Mur en bloc de maçonnerie parpaing 10cm; Matériaux: Maçonnerie Parpaing 10 cm
Propriétés DCE - Numéro de LOT: LOT 04
AC_Pset_RenovationAndPhasing - Renovation Status: Existing
Material Properties - Parpaing 10cm, ThermalConductivity: 0.6; Parpaing 10cm, SpecificHeatCapacity: 880 J/kg/K; Parpaing 10cm, MassDensity: 1400 kg/m3; Parpaing 10cm, Embodied Energy: 0.72 (MJ/kg); Parpaing 10cm, Embodied Carbon: 0.088 (kgCO₂/kg); Parpaing 10cm, Name: Parpaing 10cm; Parpaing 10cm, Participates in Collision Detection: yes
BaseQuantities - Width: 0.1 m
Name | In | LoadBearing = IsExternal | Destination | Numéro article | Length (m) | Height (m) | GrossFootprintArea (m2) = NetFootprintArea (m2) | GrossSideArea (m2) | NetSideArea (m2) | GrossVolume (m3) | NetVolume (m3)
Parpaing 10x50x20 | Sous-sol | no | Cloison | L04.2.9.5.1; L04.2.9.5.2 | 12.3 | 2.67 | 0.415339 | 27.5753 | 13.2859 | 2.75753 | 1.32859
Parpaing 10x50x20 | Sous-sol | no | Cloison | L04.2.9.5.1; L04.2.9.5.2 | 4.76 | 2.37 | 0.19 | 11.0442 | 5.2896 | 1.10442 | 0.52896
Parpaing 10x50x20 | Sous-sol | no | Cloison | L04.2.9.5.1; L04.2.9.5.2 | 2.9427 | 2.37 | 0.11027 | 6.97419 | 3.13779 | 0.697419 | 0.313779
Parpaing 10x50x20 | Sous-sol | yes | Cloison | L04.2.9.5.1 | 1.35 | 2.67 | 0.028 | 3.204 | 1.2858 | 0.3204 | 0.12858
Parpaing 10x50x20 | Sous-sol | no | Cloison | L04.2.9.5.1; L04.2.9.5.2 | 1.36 | 2.37 | 0.039 | 3.1047 | 1.1865 | 0.31047 | 0.11865
Parpaing 10x50x20 | Sous-sol | no | Cloison | L04.2.9.5.1 | 4.2592 | 2.67 | 0.43092 | 10.8976 | 10.8976 | 1.08976 | 1.08976
5 x Parpaing 10x50x20 | Sous-sol | no | Cloison | L04.2.9.5.1 | 2 | 2.37 | 0.2 | 4.74 | 4.74 | 0.474 | 0.474
Parpaing 10x50x20 | Sous-sol | no | Cloison | L04.2.9.5.1 | 1.63697 | 2.37 | 0.163697 | 3.87961 | 3.87961 | 0.387961 | 0.387961
Parpaing 10x50x20 | Sous-sol | no | Cloison | L04.2.9.5.1 | 0.131957 | 2.67 | 0.019339 | 0.516352 | 0.516352 | 0.0516352 | 0.0516352
Parpaing 10x50x20 | Sous-sol | no | Cloison | L04.2.9.5.1; L04.2.9.5.2 | 1.8473 | 2.37 | 0.0927304 | 4.37811 | 2.45991 | 0.437811 | 0.245991
Parpaing 10x50x20 | Sous-sol | no | Cloison | L04.2.9.5.1 | 0.399428 | 2.37 | 0.0449428 | 1.06514 | 1.06514 | 0.106514 | 0.106514
Parpaing 10x50x20 | Sous-sol | no | Cloison | L04.2.9.5.1 | 0.974855 | 2.67 | 0.101342 | 2.46884 | 2.46884 | 0.246884 | 0.246884
Parpaing 10x50x20 | Sous-sol | no | Cloison | L04.2.9.5.1 | 1.7473 | 2.37 | 0.17473 | 4.14111 | 4.14111 | 0.414111 | 0.414111
Parpaing 10x50x20 | Sous-sol | no | Cloison | L04.2.9.5.1; L04.2.9.5.2 | 3.15557 | 2.37 | 0.223557 | 7.42971 | 5.51151 | 0.742971 | 0.551151
Parpaing 10x50x20 | Sous-sol | no | Cloison | L04.2.9.5.1 | 2.35046 | 2.37 | 0.235046 | 5.57058 | 5.57058 | 0.557058 | 0.557058
Parpaing 10x50x20 | Sous-sol | yes | Cloison | L04.2.9.5.1 | 2 | 2.67 | 0.2 | 5.34 | 5.34 | 0.534 | 0.534
Parpaing 10x50x20 | Sous-sol | no | Cloison | L04.2.9.5.1 | 3.61197 | 2.37 | 0.361197 | 8.56036 | 8.56036 | 0.856036 | 0.856036
Parpaing 10x50x20 | Sous-sol | no | Cloison | L04.2.9.5.1 | 2 | 2.37 | 0.114494 | 2.71351 | 2.71351 | 0.271351 | 0.271351
Parpaing 10x50x20 | Sous-sol | no | Cloison | L04.2.9.5.1 | 1.10904 | 2.37 | 0.110904 | 2.62844 | 2.62844 | 0.262844 | 0.262844
Parpaing 10x50x20 | Rez-de-chaussée | no | Mur intérieur | L04.2.9.5.1 | 0.371364 | 2.35 | 0.0421364 | 0.927052 | 0.927052 | 0.0927052 | 0.0927052
Parpaing 10x50x20 | Rez-de-chaussée | no | Mur intérieur | L04.2.9.5.1 | 0.449428 | 2.2 | 0.0449428 | 0.988741 | 0.988741 | 0.0988741 | 0.0988741
Parpaing 10x50x20 | Sous-sol | no | Cloison | L04.2.9.5.1 | 0.411364 | 2.37 | 0.0361364 | 0.856434 | 0.856434 | 0.0856434 | 0.0856434
Parpaing 10x50x20 | Rez-de-chaussée | no | Mur intérieur | L04.2.9.5.1 | 0.371023 | 2.35 | 0.0321023 | 0.706263 | 0.706263 | 0.0706263 | 0.0706263

# IfcWall: Parpaing 20cm 200 (10)
Type - PredefinedType: STANDARD
Classification: Mur standard (Classification ARCHICAD); Material: Parpaing 20cm
Pset_WallCommon - AcousticRating: Non défini; ThermalTransmittance: 0; IsExternal: no
PSET_Murs_ARCHI - Emplacement: Infrastructure; Destination: Mur intérieur
Propriétés DCE - Numéro de LOT: LOT 04
AC_Pset_RenovationAndPhasing - Renovation Status: Existing
Material Properties - Parpaing 20cm, ThermalConductivity: 0.6; Parpaing 20cm, SpecificHeatCapacity: 880 J/kg/K; Parpaing 20cm, MassDensity: 1400 kg/m3; Parpaing 20cm, Embodied Energy: 0.72 (MJ/kg); Parpaing 20cm, Embodied Carbon: 0.088 (kgCO₂/kg); Parpaing 20cm, Name: Parpaing 20cm; Parpaing 20cm, Participates in Collision Detection: yes
BaseQuantities - Width: 0.2 m
Name | In | LoadBearing | Type | Matériaux | Length (m) | Height (m) | GrossFootprintArea (m2) = NetFootprintArea (m2) | GrossSideArea (m2) = NetSideArea (m2) | GrossVolume (m3) = NetVolume (m3)
M_Ext-011 | Sous-sol | no | Mur en bloc de maçonnerie parpaing 20cm | Maçonnerie Parpaing 20cm | 1.03379 | 2.37 | 0.206758 | 2.45008 | 0.490016
M_Ext-012 | Sous-sol | no | Mur en bloc de maçonnerie parpaing 20cm | Maçonnerie Parpaing 20cm | 0.4 | 2.37 | 0.06 | 0.711 | 0.1422
M_Ext-011 | Sous-sol | no | Mur en bloc de maçonnerie parpaing 20cm | Maçonnerie Parpaing 20cm | 0.4 | 2.37 | 0.1 | 1.185 | 0.237
M_Ext-007 | Sous-sol | yes | Mur béton banché 20cm | BETON | 1.51898 | 2.37 | 0.303795 | 3.59997 | 0.719995
M_Ext-011 | Rez-de-chaussée | no | Mur en bloc de maçonnerie parpaing 20cm | Maçonnerie Parpaing 20cm | 0.5 | 0.66 | 0.06 | 0.186 | 0.0372
M_Ext-007 | Sous-sol | yes | Mur béton banché 20cm | BETON | 1.31498 | 2.9 | 0.302996 | 3.91365 | 0.78273
M_Ext-012 | Rez-de-chaussée | no | Mur en bloc de maçonnerie parpaing 20cm | Maçonnerie Parpaing 20cm | 0.885 | 0.67 | 0.197 | 0.612138 | 0.122428
M_Ext-012 | Rez-de-chaussée | no | Mur en bloc de maçonnerie parpaing 20cm | Maçonnerie Parpaing 20cm | 0.885 | 0.67 | 0.197 | 0.612072 | 0.122414
M_Ext-007 | Rez-de-chaussée | yes | Mur béton banché 20cm | BETON | 1.3 | 3.22 | 0.257 | 4.13765 | 0.82753
M_Ext-009 | Sous-sol | no | Mur en bloc de maçonnerie parpaing 20cm | Maçonnerie Parpaing 20cm | 1.51898 | 2.67 | 0.303795 | 4.05567 | 0.811134

# IfcWall: Tuyau PVC 100 100 x 100 (29)
In: -2. Etage
Type - PredefinedType: ELEMENTEDWALL
Classification: Mur composite (Classification ARCHICAD); Material: Plastique - PVC
Pset_WallCommon - AcousticRating: Non défini; ThermalTransmittance: 0; LoadBearing: yes; IsExternal: yes
PSET_Murs_ARCHI - Emplacement: Infrastructure; Type: Mur béton banché 20cm; Destination: Façade; Matériaux: BETON
Propriétés DCE - Numéro de LOT: LOT 04
AC_Pset_RenovationAndPhasing - Renovation Status: Existing
Material Properties - Plastique - PVC, ThermalConductivity: 0.17; Plastique - PVC, SpecificHeatCapacity: 900 J/kg/K; Plastique - PVC, MassDensity: 1390 kg/m3; Plastique - PVC, Embodied Energy: 77.2 (MJ/kg); Plastique - PVC, Embodied Carbon: 3.1 (kgCO₂/kg); Plastique - PVC, Name: Plastique - PVC; Plastique - PVC, Participates in Collision Detection: no
BaseQuantities - Height: 0.1 m; Width: 0.1 m; GrossSideArea: 0 m2; NetSideArea: 0 m2
Name | Numéro article | Length (m) | GrossFootprintArea (m2) = NetFootprintArea (m2) | GrossVolume (m3) = NetVolume (m3)
M_Ext-026 | L04.2.7.4.1 | 16.9744 | 1.69077 | 0.128597
M_Ext-015 | L04.2.7.4.1 | 15.5672 | 1.55885 | 0.119
M_Ext-034 | L04.2.7.4.1 | 7.28014 | 0.748261 | 0.0568457
M_Ext-029 | L04.2.7.4.1 | 14.0242 | 1.39965 | 0.106981
M_Ext-030 | L04.2.7.4.1 | 9.86515 | 1.00941 | 0.0772489
M_Ext-038 | L04.2.7.4.1 | 10.0338 | 0.993808 | 0.0752571
M_Ext-011 | L04.2.7.4.1 | 8.11656 | 0.811656 | 0.0621215
M_Ext-012 | L09.2.1.1.1; L16.2.1 | 2.36264 | 0.239612 | 0.0181659
M_Ext-014 | L04.2.7.4.1 | 0.618317 | 0.0706519 | 0.00529803
M_Ext-016 | L04.2.7.4.1 | 0.299681 | 0.0266969 | 0.00187409
M_Ext-017 | L04.2.7.4.1 | 9.88476 | 0.991064 | 0.0757189
M_Ext-023 | L04.2.7.4.1 | 6.53442 | 0.658441 | 0.0503329
M_Ext-024 | L04.2.7.4.1 | 7.30678 | 0.728178 | 0.055603
M_Ext-025 | L04.2.7.4.1 | 12.729 | 1.27543 | 0.0974861
M_Ext-028 | L04.2.7.4.1 | 12.6119 | 1.26369 | 0.0965892
M_Ext-031 | L04.2.7.4.1 | 12.7481 | 1.27735 | 0.0976324
M_Ext-032 | L04.2.7.4.1 | 9.9167 | 0.997051 | 0.0762442
M_Ext-033 | L04.2.7.4.1 | 16.5457 | 1.65457 | 0.126636
M_Ext-035 | L04.2.7.4.1 | 6.43568 | 0.646823 | 0.0493373
M_Ext-036 | L04.2.7.4.1 | 2.34174 | 0.222705 | 0.0164519
M_Ext-037 | L04.2.7.4.1 | 6.4746 | 0.672607 | 0.0511671
M_Ext-013 | L04.2.7.4.1 | 2.47487 | 0.247487 | 0.0189418
M_Ext-018 | L04.2.7.4.1 | 6.18705 | 0.618705 | 0.0473536
M_Ext-019 | L04.2.7.4.1 | 7.32872 | 0.732872 | 0.0560916
M_Ext-020 | L04.2.7.4.1 | 13.5307 | 1.35307 | 0.10356
M_Ext-021 | L04.2.12.1.1; L09.2.1.1.1; L16.2.1 | 0.88562 | 0.088562 | 0.00677824
M_Ext-022 | L04.2.7.4.1 | 8.45785 | 0.845785 | 0.0647336
M_Ext-027 | L04.2.7.4.1 | 12.6831 | 1.26831 | 0.0970723
M_Ext-039 | L04.2.7.4.1 | 20.7015 | 2.07014 | 0.158442

# IfcWindow: Baie générique 2017 v2 (135)
Type - ParameterTakesPrecedence: no; Sizeable: no
Classification: Fenêtre (Classification ARCHICAD)
AC_Pset_RenovationAndPhasing - Renovation Status: Existing
Name | In | Description | OverallHeight (m) = Height (m) | OverallWidth (m) = Width (m) | Repaire Inventaire | Repaire architecte | Numéro de LOT | Numéro article | GrossArea (m2) = Area (m2) | Perimeter (m) | Volume (m3) = NetVolume (m3) | Depth (m)
MEN 30 | Rez-de-chaussée | type M11 ALU 2V 240x205 | 2.05 | 2.4 | M11 | MEN 30 | LOT 04 | L04.2.13.3.2 | 5.01396 | 8.9 | 0.0981165 | 0.356439
MEN 27 | Rez-de-chaussée | type M11 ALU 2V 240x205 | 2.05 | 2.4 | M11 | MEN 27 | LOT 04 | L04.2.13.3.2 | 5.01396 | 8.9 | 0.0981165 | 0.356439
MEN 28 | Rez-de-chaussée | type PVC 1V 100x205 | 2.05 | 1 | M09 | MEN 28 | LOT 04 | L04.2.13.3.2 | 2.05 | 6.1 | 0.058261 | 0.356439
MEN 03 | Rez-de-chaussée | type M11 ALU 2V 240x205 | 2.05 | 2.4 | M11 | MEN 03 | LOT 04 | L04.2.13.3.2 | 4.92 | 8.9 | 0.0981165 | 0.356439
MEN 15 | Rez-de-chaussée | type M12 ALU 2V 240x205 | 2.05 | 2.4 | M12 | MEN 15 | LOT 04 | L04.2.13.3.2 | 4.92 | 8.9 | 0.0981165 | 0.356439
MEN 16 | Rez-de-chaussée | type M10 PVC 2V 140x205 | 2.05 | 1.4 | M10 | MEN 16 | LOT 04 | L04.2.13.3.2 | 2.87 | 6.9 | 0.0809674 | 0.356439
MEN 14 | Rez-de-chaussée | type M10 PVC 2V 140x205 | 2.05 | 1.4 | M10 | MEN 14 | LOT 04 | L04.2.13.3.2 | 2.87 | 6.9 | 0.0809674 | 0.356439
MEN 13 | Rez-de-chaussée | type M10 PVC 2V 140x205 | 2.05 | 1.4 | M10 | MEN 13 | LOT 04 | L04.2.13.3.2 | 2.87 | 6.9 | 0.0809674 | 0.356439
MEN 31 | Rez-de-chaussée | type PVC 1V 100x205 | 2.05 | 1 | M09 | MEN 31 | LOT 04 | L04.2.13.3.2 | 2.08915 | 6.1 | 0.058261 | 0.356439
MEN 19 | Rez-de-chaussée | type M10 PVC 2V 140x205 | 2.05 | 1.4 | M10 | MEN 19 | LOT 04 | L04.2.13.3.2 | 2.87 | 6.9 | 0.0809674 | 0.356439
MEN 18 | Rez-de-chaussée | type M12 ALU 2V 240x205 | 2.05 | 2.4 | M12 | MEN 18 | LOT 04 | L04.2.13.3.2 | 4.92 | 8.9 | 0.0981165 | 0.356439
MEN 17 | Rez-de-chaussée | type M12 ALU 2V 240x205 | 2.05 | 2.4 | M12 | MEN 17 | LOT 04 | L04.2.13.3.2 | 4.92 | 8.9 | 0.0981165 | 0.356439
MEN 12 | Rez-de-chaussée | type M12 ALU 2V 240x205 | 2.05 | 2.4 | M12 | MEN 12 | LOT 04 | L04.2.13.3.2 | 4.92 | 8.9 | 0.0981165 | 0.356439
MEN 11 | Rez-de-chaussée | type M10 PVC 2V 140x205 | 2.05 | 1.4 | M10 | MEN 11 | LOT 04 | L04.2.13.3.2 | 2.87 | 6.9 | 0.0809674 | 0.356439
MEN 10 | Rez-de-chaussée | type M24 PVC 1V 100x205 | 2.05 | 1 | M24 | MEN 10 | LOT 04 | L04.2.13.3.2 | 2.05 | 6.1 | 0.058261 | 0.356439
MEN 07 | Rez-de-chaussée | type PVC 1V 100x205 | 2.05 | 1 | M09 | MEN 07 | LOT 04 | L04.2.13.3.2 | 2.05 | 6.1 | 0.058261 | 0.356439
MEN 08 | Rez-de-chaussée | type PVC 1V 100x205 | 2.05 | 1 | M09 | MEN 08 | LOT 04 | L04.2.13.3.2 | 2.05 | 6.1 | 0.058261 | 0.356439
MEN 06 | Rez-de-chaussée | type M11 ALU 2V 240x205 | 2.05 | 2.4 | M11 | MEN 06 | LOT 04 | L04.2.13.3.2 | 4.92 | 8.9 | 0.0981165 | 0.356439
MEN 05 | Rez-de-chaussée | type PVC 1V 100x205 | 2.05 | 1 | M09 | MEN 05 | LOT 04 | L04.2.13.3.2 | 2.05 | 6.1 | 0.058261 | 0.356439
MEN 04 | Rez-de-chaussée | type PVC 1V 100x205 | 2.05 | 1 | M09 | MEN 04 | LOT 04 | L04.2.13.3.2 | 2.05 | 6.1 | 0.058261 | 0.356439
MEN 25 | Rez-de-chaussée | type M06 PVC 1V 90x210 | 2.1 | 0.9 | M06 | MEN 25 | LOT 04 | L04.2.13.3.1 | 1.89 | 6 | 0.065058 | 0.345
MEN 26 | Rez-de-chaussée | type M06 PVC 1V 90x210 | 2.1 | 0.9 | M06 | MEN 26 | LOT 04 | L04.2.13.3.1 | 1.89 | 6 | 0.065058 | 0.345
MEN 01 | Rez-de-chaussée | type M11 ALU 2V 240x205 | 2.05 | 2.4 | M11 | MEN 01 | LOT 04 | L04.2.13.3.2 | 4.92 | 8.9 | 0.0981165 | 0.356439
MEN 02 | Rez-de-chaussée | type PVC 1V 100x205 | 2.05 | 1 | M09 | MEN 02 | LOT 04 | L04.2.13.3.2 | 2.05 | 6.1 | 0.058261 | 0.356439
MEN 29 | Rez-de-chaussée | type M14 PVC 1V 90x120 | 1.2 | 0.9 | M14 | MEN 29 | LOT 04 | L04.2.13.3.1 | 1.08 | 4.2 | 0.0391674 | 0.356439
MEN 23 | Rez-de-chaussée | type M31 ALU 2V 240x205 | 2.05 | 2.4 | M31 | MEN 23 | LOT 04 | L04.2.13.3.2 | 4.92 | 8.9 | 0.0981165 | 0.345
MEN 22 | Rez-de-chaussée | type M01 PVC 1V 100x205 | 2.05 | 1 | M01 | MEN 22 | LOT 04 | L04.2.13.3.2 | 2.05 | 6.1 | 0.058261 | 0.345
MEN 24 | Rez-de-chaussée | type M26 PVC 1V 90x120 | 1.2 | 0.9 | M26 | MEN 24 | LOT 04 | L04.2.13.3.1 | 1.08 | 4.2 | 0.0391674 | 0.345
MEN 21 | Rez-de-chaussée | type M10 PVC 2V 140x205 | 2.05 | 1.4 | M10 | MEN 21 | LOT 04 | L04.2.13.3.2 | 2.87 | 6.9 | 0.0809674 | 0.356439
MEN 20 | Rez-de-chaussée | type M12 ALU 2V 240x205 | 2.05 | 2.4 | M12 | MEN 20 | LOT 04 | L04.2.13.3.2 | 4.92 | 8.9 | 0.0981165 | 0.356439
MEN 09 | Rez-de-chaussée | type M24 PVC 1V 100x205 | 2.05 | 1 | M24 | MEN 09 | LOT 04 | L04.2.13.3.2 | 2.05 | 6.1 | 0.058261 | 0.356439
MEN 42 | R+1 | type M17 ALU 1V 80x120 | 1.2 | 0.8 | M17 | MEN 42 | LOT 04 | L04.2.13.3.1 | 0.96 | 4 | 0.034786 | 0.345
MEN 50 | R+1 | type M07 ALU 2V 240x220 | 2.2 | 2.4 | M07 | MEN 50 | LOT 04 | L04.2.13.3.2 | 5.28 | 9.2 | 0.103149 | 0.345
MEN 51 | R+1 |  | 2.2 | 0.9 | M04 | MEN 51 | LOT 04 | L04.2.13.3.2 | 1.98 | 6.2 | 0.0625664 | 0.345
MEN 47 | R+1 | type M07 ALU 2V 240x220 | 2.2 | 2.4 | M07 | MEN 47 | LOT 04 | L04.2.13.3.2 | 5.28 | 9.2 | 0.103149 | 0.345
MEN 46 | R+1 | type M03 1V sur allège vitrée 90x210 | 2.1 | 0.9 | M03 | MEN 46 | LOT 04 | L04.2.13.3.1 | 1.89 | 6 | 0.0693171 | 0.345
MEN 48 | R+1 | type M03 1V sur allège vitrée 90x210 | 2.1 | 0.9 | M03 | MEN 48 | LOT 04 | L04.2.13.3.1 | 1.89 | 6 | 0.0693171 | 0.345
MEN 45 | R+1 | type M03 1V sur allège vitrée 90x210 | 2.1 | 0.9 | M03 | MEN 45 | LOT 04 | L04.2.13.3.1 | 1.89 | 6 | 0.0693171 | 0.345
MEN 43 | R+1 | type M03 1V sur allège vitrée 90x210 | 2.1 | 0.9 | M03 | MEN 43 | LOT 04 | L04.2.13.3.1 | 1.89 | 6 | 0.0693171 | 0.345
MEN 44 | R+1 | type M07 ALU 2V 240x220 | 2.2 | 2.4 | M07 | MEN 44 | LOT 04 | L04.2.13.3.2 | 5.28 | 9.2 | 0.103149 | 0.345
MEN 53 | R+1 | type M03 1V sur allège vitrée 90x210 | 2.1 | 0.9 | M03 | MEN 53 | LOT 04 | L04.2.13.3.1 | 1.89 | 6 | 0.0693171 | 0.345
MEN 52 | R+1 | type M07 ALU 2V 240x220 | 2.2 | 2.4 | M07 | MEN 52 | LOT 04 | L04.2.13.3.2 | 5.28 | 9.2 | 0.103149 | 0.345
MEN 41 | R+1 | type M03 1V sur allège vitrée 90x210 | 2.1 | 0.9 | M03 | MEN 41 | LOT 04 | L04.2.13.3.1 | 1.89 | 6 | 0.0693171 | 0.345
MEN 38 | R+1 | type M08 ALU 2V 240x220 | 2.2 | 2.4 | M08 | MEN 38 | LOT 04 | L04.2.13.3.2 | 5.28 | 9.2 | 0.103149 | 0.345
MEN 36 | R+1 | type M02 PVC 1V sur allège vitrée 90x210 | 2.1 | 0.9 | M02 | MEN 36 | LOT 04 | L04.2.13.3.1 | 1.89 | 6 | 0.0693171 | 0.345
MEN 37 | R+1 | type M02 PVC 1V sur allège vitrée 90x210 | 2.1 | 0.9 | M02 | MEN 37 | LOT 04 | L04.2.13.3.1 | 1.89 | 6 | 0.0693171 | 0.345
MEN 35 | R+1 | type M08 ALU 2V 240x220 | 2.2 | 2.4 | M08 | MEN 35 | LOT 04 | L04.2.13.3.2 | 5.28 | 9.2 | 0.103149 | 0.345
MEN 49 | R+1 | type M07 ALU 2V 240x220 | 2.2 | 2.4 | M07 | MEN 49 | LOT 04 | L04.2.13.3.2 | 5.28 | 9.2 | 0.103149 | 0.345
MEN 39 | R+1 | type M02 PVC 1V sur allège vitrée 90x210 | 2.1 | 0.9 | M02 | MEN 39 | LOT 04 | L04.2.13.3.1 | 1.89 | 6 | 0.0693171 | 0.345
MEN 63 | R+1 | type M02 PVC 1V sur allège vitrée 90x210 | 2.1 | 0.9 | M02 | MEN 63 | LOT 04 | L04.2.13.3.1 | 1.89 | 6 | 0.065058 | 0.345
MEN 62 | R+1 | type M08 ALU 2V 240x220 | 2.2 | 2.4 | M08 | MEN 62 | LOT 04 | L04.2.13.3.2 | 5.28 | 9.2 | 0.103149 | 0.345
MEN 57 | R+1 | type M06 PVC 1V 90x210 | 2.1 | 0.9 | M06 | MEN 57 | LOT 04 | L04.2.13.3.1 | 1.89 | 6 | 0.065058 | 0.345
MEN 58 | R+1 | type M06 PVC 1V 90x210 | 2.1 | 0.9 | M06 | MEN 58 | LOT 04 | L04.2.13.3.1 | 1.89 | 6 | 0.065058 | 0.345
MEN 54 | R+1 | type M02 PVC 1V sur allège vitrée 90x210 | 2.1 | 0.9 | M02 | MEN 54 | LOT 04 | L04.2.13.3.1 | 1.89 | 6 | 0.0693171 | 0.345
MEN 40 | R+1 | type M34 PVC 2V 120x120 | 1.2 | 1.2 | M34 | MEN 40 | LOT 04 | L04.2.13.3.1 | 1.44 | 4.8 | 0.0526044 | 0.345
MEN 32 | R+1 | type M02 PVC 1V sur allège vitrée 90x210 | 2.1 | 0.9 | M02 | MEN 32 | LOT 04 | L04.2.13.3.1 | 1.89 | 6 | 0.065058 | 0.345
MEN 55 | R+1 | type M30 ALU 2V 240x220 | 2.2 | 2.4 | M30 | MEN 55 | LOT 04 | L04.2.13.3.2 | 5.28 | 9.2 | 0.103149 | 0.345
MEN 56 | R+1 | type M04 PVC 1V 90x220 | 2.2 | 0.9 | M04 | MEN 56 | LOT 04 | L04.2.13.3.2 | 1.98 | 6.2 | 0.0625664 | 0.345
MEN 59 | R+1 | type M08 ALU 2V 240x220 | 2.2 | 2.4 | M08 | MEN 59 | LOT 04 | L04.2.13.3.2 | 5.28 | 9.2 | 0.103149 | 0.345
MEN 60 | R+1 | type M23 PVC 1V 100x220 | 2.2 | 1 | M23 | MEN 60 | LOT 04 | L04.2.13.3.2 | 2.2 | 6.4 | 0.061666 | 0.345
MEN 61 | R+1 | type M14 PVC 1V 90x120 | 1.2 | 0.9 | M14 | MEN 61 | LOT 04 | L04.2.13.3.1 | 1.08 | 4.2 | 0.036876 | 0.345
MEN 33 | R+1 | type M02 PVC 1V sur allège vitrée 90x210 | 2.1 | 0.9 | M02 | MEN 33 | LOT 04 | L04.2.13.3.1 | 1.89 | 6 | 0.065058 | 0.345
MEN 34 | R+1 | type M08 ALU 2V 240x220 | 2.2 | 2.4 | M08 | MEN 34 | LOT 04 | L04.2.13.3.2 | 5.28 | 9.2 | 0.103149 | 0.345
MEN 92 | R+2 | type M08 ALU 2V 240x220 | 2.2 | 2.4 | M08 | MEN 92 | LOT 04 | L04.2.13.3.2 | 5.28 | 9.2 | 0.103149 | 0.345
MEN 93 | R+2 | type M23 PVC 1V 100x220 | 2.2 | 1 | M23 | MEN 93 | LOT 04 | L04.2.13.3.2 | 2.2 | 6.4 | 0.061666 | 0.345
MEN 94 | R+2 | type M14 PVC 1V 90x120 | 1.2 | 0.9 | M14 | MEN 94 | LOT 04 | L04.2.13.3.1 | 1.08 | 4.2 | 0.036876 | 0.345
MEN 65 | R+2 | type M02 PVC 1V sur allège vitrée 90x210 | 2.1 | 0.9 | M02 | MEN 65 | LOT 04 | L04.2.13.3.1 | 1.89 | 6 | 0.065058 | 0.345
MEN 66 | R+2 | type M08 ALU 2V 240x220 | 2.2 | 2.4 | M08 | MEN 66 | LOT 04 | L04.2.13.3.2 | 5.28 | 9.2 | 0.103149 | 0.345
MEN 67 | R+2 | type M02 PVC 1V sur allège vitrée 90x210 | 2.1 | 0.9 | M02 | MEN 67 | LOT 04 | L04.2.13.3.1 | 1.89 | 6 | 0.065058 | 0.345
MEN 64 | R+2 | type M02 PVC 1V sur allège vitrée 90x210 | 2.1 | 0.9 | M02 | MEN 64 | LOT 04 | L04.2.13.3.1 | 1.89 | 6 | 0.065058 | 0.345
MEN 68 | R+2 | type M02 PVC 1V sur allège vitrée 90x210 | 2.1 | 0.9 | M02 | MEN 68 | LOT 04 | L04.2.13.3.1 | 1.89 | 6 | 0.065058 | 0.395
MEN 69 | R+2 | type M02 PVC 1V sur allège vitrée 90x210 | 2.1 | 0.9 | M02 | MEN 69 | LOT 04 | L04.2.13.3.1 | 1.89 | 6 | 0.065058 | 0.395
MEN 70 | R+2 | type M02 PVC 1V sur allège vitrée 90x210 | 2.1 | 0.9 | M02 | MEN 70 | LOT 04 | L04.2.13.3.1 | 1.89 | 6 | 0.065058 | 0.395
MEN 95 | R+2 | type M08 ALU 2V 240x220 | 2.2 | 2.4 | M08 | MEN 95 | LOT 04 | L04.2.13.3.2 | 5.28 | 9.2 | 0.103149 | 0.345
MEN 72 | R+2 | type M13 ALU 2V 240X200 | 2 | 2.4 | M13 | MEN 72 | LOT 04 | L04.2.13.3.3 | 4.824 | 8.8 | 0.096439 | 0.402689
MEN 85 | R+2 | type M03 1V sur allège vitrée 90x210 | 2.1 | 0.9 | M03 | MEN 85 | LOT 04 | L04.2.13.3.1 | 1.89 | 6 | 0.065058 | 0.345
MEN 84 | R+2 | type M03 1V sur allège vitrée 90x210 | 2.1 | 0.9 | M03 | MEN 84 | LOT 04 | L04.2.13.3.1 | 1.89 | 6 | 0.065058 | 0.345
MEN 83 | R+2 | type M03 1V sur allège vitrée 90x210 | 2.1 | 0.9 | M03 | MEN 83 | LOT 04 | L04.2.13.3.1 | 1.89 | 6 | 0.065058 | 0.345
MEN 71 | R+2 | type M13 ALU 2V 240X200 | 2 | 2.4 | M13 | MEN 71 | LOT 04 | L04.2.13.3.3 | 4.824 | 8.8 | 0.096439 | 0.402689
MEN 88 | R+2 | type M13 ALU 2V 240X200 | 2 | 2.4 | M13 | MEN 88 | LOT 04 | L04.2.13.3.3 | 4.824 | 8.8 | 0.0985035 | 0.402689
MEN 89 | R+2 | type M27 PVC 1V 90x120 | 1.2 | 0.9 | M27 | MEN 89 | LOT 04 | L04.2.13.3.1 | 1.08 | 4.2 | 0.0391674 | 0.402689
MEN 78 | R+2 | type M07 ALU 2V 240x220 | 2.2 | 2.4 | M07 | MEN 78 | LOT 04 | L04.2.13.3.2 | 5.28 | 9.2 | 0.103149 | 0.345
MEN 77 | R+2 | type M03 1V sur allège vitrée 90x210 | 2.1 | 0.9 | M03 | MEN 77 | LOT 04 | L04.2.13.3.1 | 1.89 | 6 | 0.065058 | 0.345
MEN 79 | R+2 | type M03 1V sur allège vitrée 90x210 | 2.1 | 0.9 | M03 | MEN 79 | LOT 04 | L04.2.13.3.1 | 1.89 | 6 | 0.065058 | 0.345
MEN 76 | R+2 | type M03 1V sur allège vitrée 90x210 | 2.1 | 0.9 | M03 | MEN 76 | LOT 04 | L04.2.13.3.1 | 1.89 | 6 | 0.065058 | 0.345
MEN 86 | R+2 | type M02 PVC 1V sur allège vitrée 90x210 | 2.1 | 0.9 | M02 | MEN 86 | LOT 04 | L04.2.13.3.1 | 1.89 | 6 | 0.065058 | 0.345
MEN 87 | R+2 | type M15 PVC 1V 90x200 | 2 | 0.9 | M15 | MEN 87 | LOT 04 | L04.2.13.3.3 | 1.8 | 5.8 | 0.054636 | 0.345
MEN 96 | R+2 | type M02 PVC 1V sur allège vitrée 90x210 | 2.1 | 0.9 | M02 | MEN 96 | LOT 04 | L04.2.13.3.1 | 1.89 | 6 | 0.065058 | 0.345
MEN 74 | R+2 | type M03 1V sur allège vitrée 90x210 | 2.1 | 0.9 | M03 | MEN 74 | LOT 04 | L04.2.13.3.1 | 1.89 | 6 | 0.065058 | 0.345
MEN 75 | R+2 | type M07 ALU 2V 240x220 | 2.2 | 2.4 | M07 | MEN 75 | LOT 04 | L04.2.13.3.2 | 5.28 | 9.2 | 0.103149 | 0.345
MEN 81 | R+2 | type M07 ALU 2V 240x220 | 2.2 | 2.4 | M07 | MEN 81 | LOT 04 | L04.2.13.3.2 | 5.28 | 9.2 | 0.103149 | 0.345
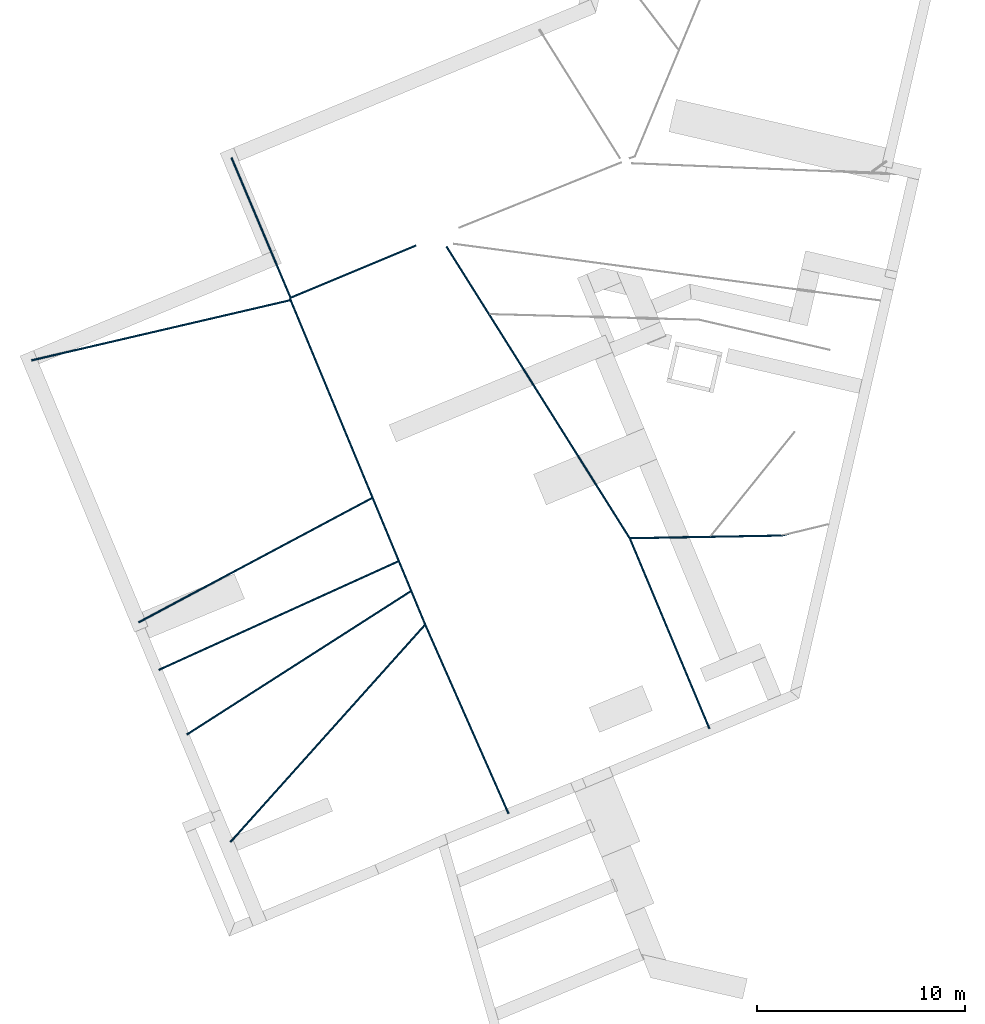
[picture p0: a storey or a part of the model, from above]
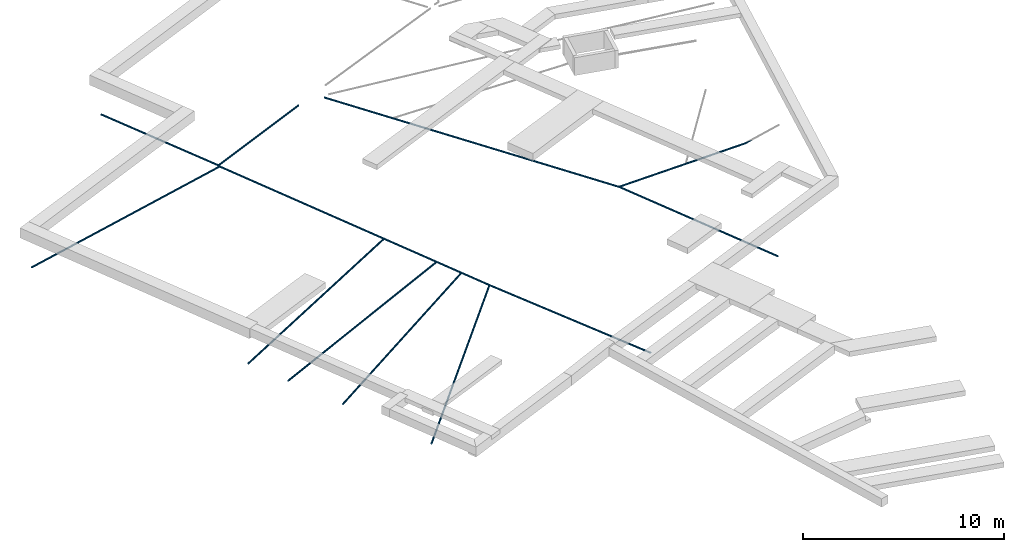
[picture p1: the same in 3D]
Properties of the parts of a building model (IFC2X3), part 22 of 22

# IfcWindow: Baie générique 2017 v2 (135)
Name | In | Description | OverallHeight (m) = Height (m) | OverallWidth (m) = Width (m) | Repaire Inventaire | Repaire architecte | Numéro de LOT | Numéro article | GrossArea (m2) = Area (m2) | Perimeter (m) | Volume (m3) = NetVolume (m3) | Depth (m)
MEN 82 | R+2 | typre M05 PVC 1V 90x220 | 2.2 | 0.9 | M05 | MEN 82 | LOT 04 | L04.2.13.3.2 | 1.98 | 6.2 | 0.059076 | 0.345
MEN 80 | R+2 | type M07 ALU 2V 240x220 | 2.2 | 2.4 | M07 | MEN 80 | LOT 04 | L04.2.13.3.2 | 5.28 | 9.2 | 0.103149 | 0.345
MEN 73 | R+2 | type M17 ALU 1V 80x120 | 1.2 | 0.8 | M17 | MEN 73 | LOT 04 | L04.2.13.3.1 | 0.96 | 4 | 0.034786 | 0.345
MEN 90 | R+2 | type M06 PVC 1V 90x210 | 2.1 | 0.9 | M06 | MEN 90 | LOT 04 | L04.2.13.3.1 | 1.89 | 6 | 0.065058 | 0.345
MEN 91 | R+2 | type M06 PVC 1V 90x210 | 2.1 | 0.9 | M06 | MEN 91 | LOT 04 | L04.2.13.3.1 | 1.89 | 6 | 0.065058 | 0.345
MEN 105 | R+3 | type M17 ALU 1V 80x120 | 1.2 | 0.8 | M17 | MEN 105 | LOT 04 | L04.2.13.3.1 | 0.96 | 4 | 0.034786 | 0.395
MEN 106 | R+3 | type M03 1V sur allège vitrée 90x210 | 2.1 | 0.9 | M03 | MEN 106 | LOT 04 | L04.2.13.3.1 | 1.89 | 6 | 0.065058 | 0.345
MEN 107 | R+3 | type M07 ALU 2V 240x220 | 2.2 | 2.4 | M07 | MEN 107 | LOT 04 | L04.2.13.3.2 | 5.28 | 9.2 | 0.103149 | 0.345
MEN 122 | R+3 | type M02 PVC 1V sur allège vitrée 90x210 | 2.1 | 0.9 | M02 | MEN 122 | LOT 04 | L04.2.13.3.1 | 1.89 | 6 | 0.065058 | 0.345
MEN 102 | R+3 | type M02 PVC 1V sur allège vitrée 90x210 | 2.1 | 0.9 | M02 | MEN 102 | LOT 04 | L04.2.13.3.1 | 1.89 | 6 | 0.065058 | 0.395
MEN 101 | R+3 | type M19a/b ALU | 2.1 | 0.7 | M19a | MEN 101 | LOT 04 | L04.2.13.3.1 | 1.47 | 5.6 | 0.057568 | 0.395
MEN 100 | R+3 | type M02 PVC 1V sur allège vitrée 90x210 | 2.1 | 0.9 | M02 | MEN 100 | LOT 04 | L04.2.13.3.1 | 1.89 | 6 | 0.065058 | 0.395
MEN 103 | R+3 | type M13 ALU 2V 240X200 | 2 | 2.4 | M13 | MEN 103 | LOT 04 | L04.2.13.3.3 | 4.824 | 8.8 | 0.096439 | 0.402689
MEN 112 | R+3 | type M08 ALU 2V 240x220 | 2.2 | 2.4 | M08 | MEN 112 | LOT 04 | L04.2.13.3.2 | 5.28 | 9.2 | 0.103149 | 0.395
MEN 113 | R+3 | type M13 ALU 2V 240X200 | 2 | 2.4 | M13 | MEN 113 | LOT 04 | L04.2.13.3.3 | 4.86996 | 8.8 | 0.0985035 | 0.356439
MEN 97 | R+3 | type M02 PVC 1V sur allège vitrée 90x210 | 2.1 | 0.9 | M02 | MEN 97 | LOT 04 | L04.2.13.3.1 | 1.89 | 6 | 0.065058 | 0.345
MEN 108 | R+3 | type M03 1V sur allège vitrée 90x210 | 2.1 | 0.9 | M03 | MEN 108 | LOT 04 | L04.2.13.3.1 | 1.89 | 6 | 0.065058 | 0.345
MEN 121 | R+3 | type M13 ALU 2V 240X200 | 2 | 2.4 | M13 | MEN 121 | LOT 04 | L04.2.13.3.3 | 4.86996 | 8.8 | 0.096439 | 0.356439
MEN 110 | R+3 | type M07 ALU 2V 240x220 | 2.2 | 2.4 | M07 | MEN 110 | LOT 04 | L04.2.13.3.2 | 5.28 | 9.2 | 0.103149 | 0.345
MEN 109 | R+3 | type M03 1V sur allège vitrée 90x210 | 2.1 | 0.9 | M03 | MEN 109 | LOT 04 | L04.2.13.3.1 | 1.89 | 6 | 0.065058 | 0.345
MEN 111 | R+3 | type M03 1V sur allège vitrée 90x210 | 2.1 | 0.9 | M03 | MEN 111 | LOT 04 | L04.2.13.3.1 | 1.89 | 6 | 0.065058 | 0.345
MEN 98 | R+3 | type M02 PVC 1V sur allège vitrée 90x210 | 2.1 | 0.9 | M02 | MEN 98 | LOT 04 | L04.2.13.3.1 | 1.89 | 6 | 0.065058 | 0.395
MEN 99 | R+3 | type M08 ALU 2V 240x220 | 2.2 | 2.4 | M08 | MEN 99 | LOT 04 | L04.2.13.3.2 | 5.28 | 9.2 | 0.103149 | 0.395
MEN 104 | R+3 | type M15 PVC 1V 90x200 | 2 | 0.9 | M15 | MEN 104 | LOT 04 | L04.2.13.3.3 | 1.809 | 5.8 | 0.054636 | 0.402689
MEN 120 | R+3 | type M21 ALU 3V 280x200 | 2 | 2.8 | M21 | MEN 120 | LOT 04 | L04.2.13.3.3 | 5.84418 | 9.6 | 0.10112 | 0.358
MEN 114 | R+3 | type M21 ALU 3V 280x200 | 2 | 2.8 | M21 | MEN 114 | LOT 04 | L04.2.13.3.3 | 5.84418 | 9.6 | 0.10112 | 0.358
MEN 126 | R+4 | type M03 1V sur allège vitrée 90x210 | 2.1 | 0.9 | M03 | MEN 126 | LOT 04 | L04.2.13.3.1 | 1.89 | 6 | 0.0490215 | 0.31
MEN 125 | R+4 | type M03 1V sur allège vitrée 90x210 | 2.1 | 0.9 | M03 | MEN 125 | LOT 04 | L04.2.13.3.1 | 1.89 | 6 | 0.0490215 | 0.31
MEN 127 | R+4 | type M18 PVC 1V 80x120 | 1.2 | 0.8 | M18 | MEN 127 | LOT 04 | L04.2.13.3.1 | 0.96 | 4 | 0.0258142 | 0.31
MEN 124 | R+4 | type M02 PVC 1V sur allège vitrée 90x210 | 2.1 | 0.9 | M02 | MEN 124 | LOT 04 | L04.2.13.3.1 | 1.89 | 6 | 0.0490215 | 0.31
MEN 128 | R+4 | type M03 1V sur allège vitrée 90x210 | 2.1 | 0.9 | M03 | MEN 128 | LOT 04 | L04.2.13.3.1 | 1.89 | 6 | 0.07275 | 0.31
MEN 130 | R+4 | type M25 PVC 1V 90x200 | 2 | 0.9 | M25 | MEN 130 | LOT 04 | L04.2.13.3.3 | 1.8 | 5.8 | 0.060996 | 0.31
MEN 132 | R+4 | type M33 ALU 2V 180x200 | 2 | 1.8 | M33 | MEN 132 | LOT 04 | L04.2.13.3.3 | 3.6 | 7.6 | 0.090379 | 0.31
MEN 116 | R+3 | type M16a/b ALU | 1.2 | 0.9 | M16b | MEN 116 |  |  | 1.08 | 4.2 | 0.036876 | 0.358
MEN 118 | R+3 | type M16a/b ALU | 1.2 | 0.9 | M16b | MEN 118 |  |  | 1.08 | 4.2 | 0.036876 | 0.358
MEN 117 | R+3 | type M16a/b ALU | 1.2 | 2.8 | M16a | MEN 117 |  |  | 3.36 | 8 | 0.07296 | 0.358
MEN 119 | R+3 | type M20 ALU 1V 70x120 | 1.23 | 0.7 | M20 | MEN 119 |  |  | 0.861 | 3.86 | 0.033332 | 0.358
MEN 115 | R+3 | type M20 ALU 1V 70x120 | 1.23 | 0.7 | M20 | MEN 115 |  |  | 0.861 | 3.86 | 0.033332 | 0.358
MEN 123 | R+4 | type M19a/b ALU | 2.1 | 0.7 | M19b | MEN 123 |  |  | 1.47 | 5.6 | 0.0428719 | 0.31
MEN 133 | R+4 | type M29 PVC 1V 45x110 | 1.1 | 0.45 | M29 | MEN 133 |  |  | 0.495 | 3.1 | 0.028776 | 0.358
MEN 134 | R+4 | type M28 PVC 1V 80x110 | 1.1 | 0.8 | M28 | MEN 134 |  |  | 0.88 | 3.8 | 0.036616 | 0.358
MEN 129 | R+4 | type M22 ALU 2V 240x120 | 1.2 | 2.4 | M22 | MEN 129 |  |  | 2.88 | 7.2 | 0.071998 | 0.358
MEN 131 | R+4 | type M22 ALU 2V 240x120 | 1.2 | 2.4 | M22 | MEN 131 |  |  | 2.88 | 7.2 | 0.071998 | 0.358
MEN 135 | R+4 | type M32 ALU 2V 240x200 | 2 | 2.4 | M32 | MEN 135 |  |  | 5.09466 | 8.8 | 0.100758 | 0.358
